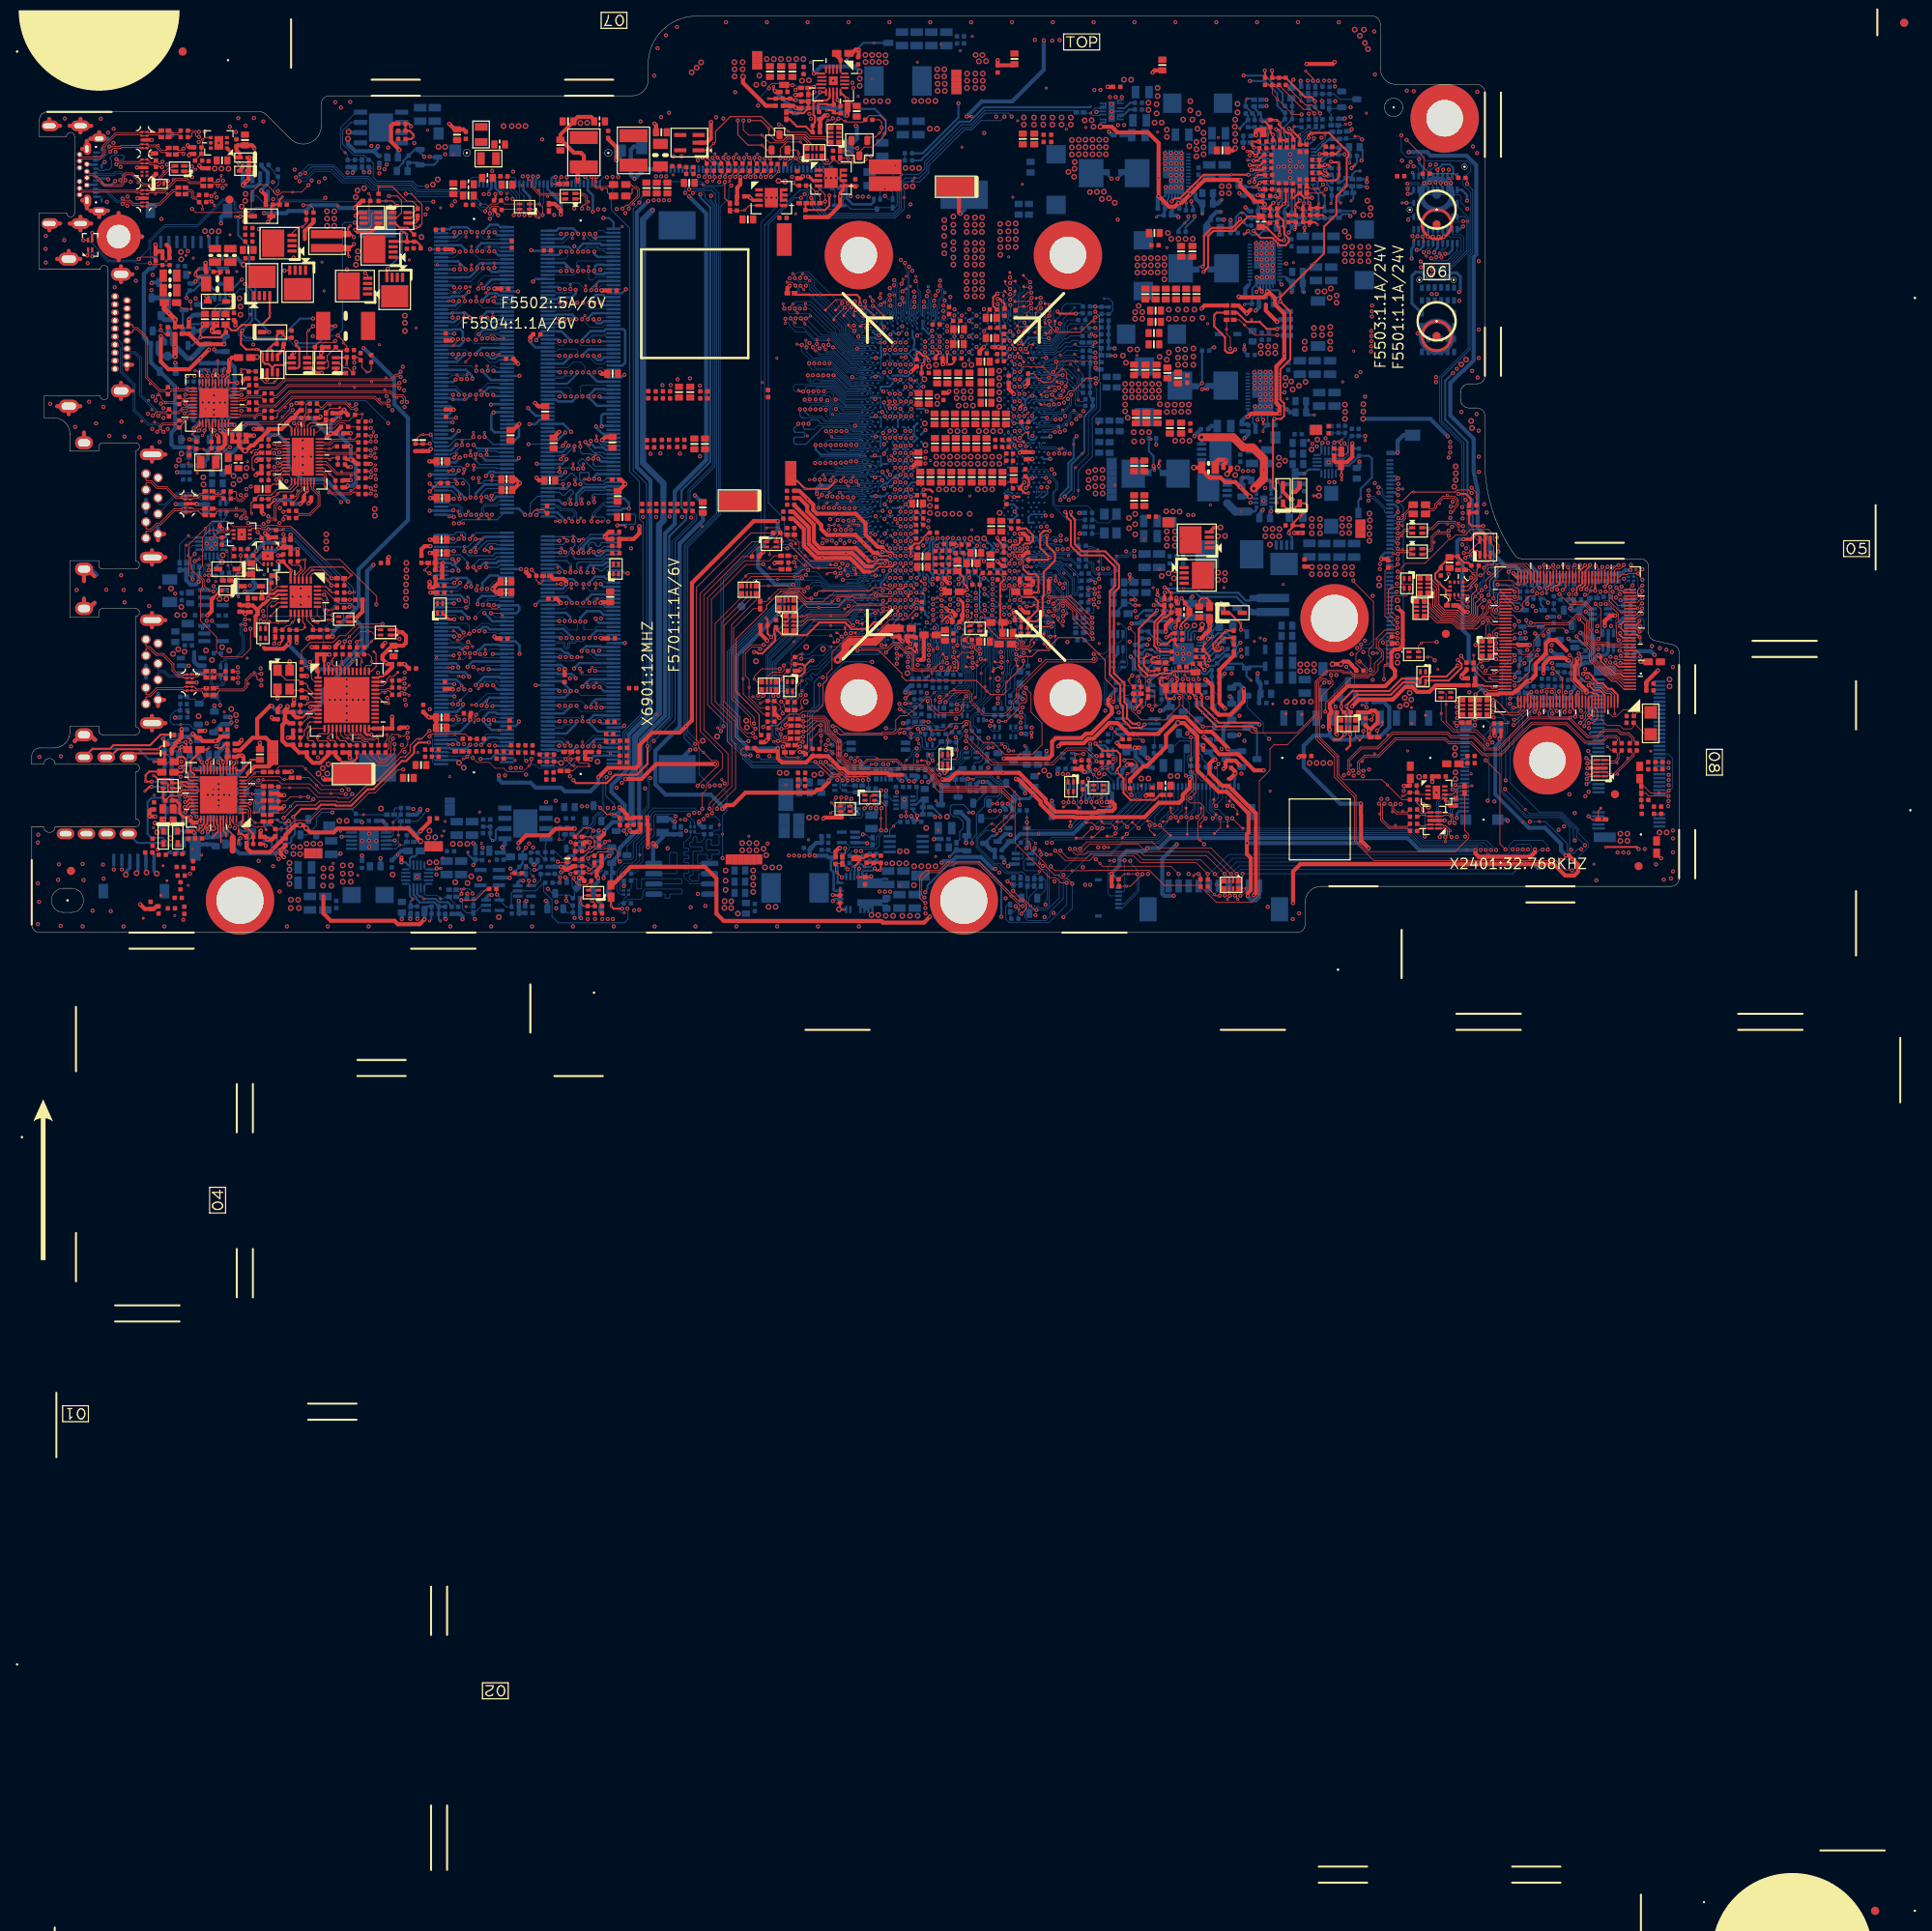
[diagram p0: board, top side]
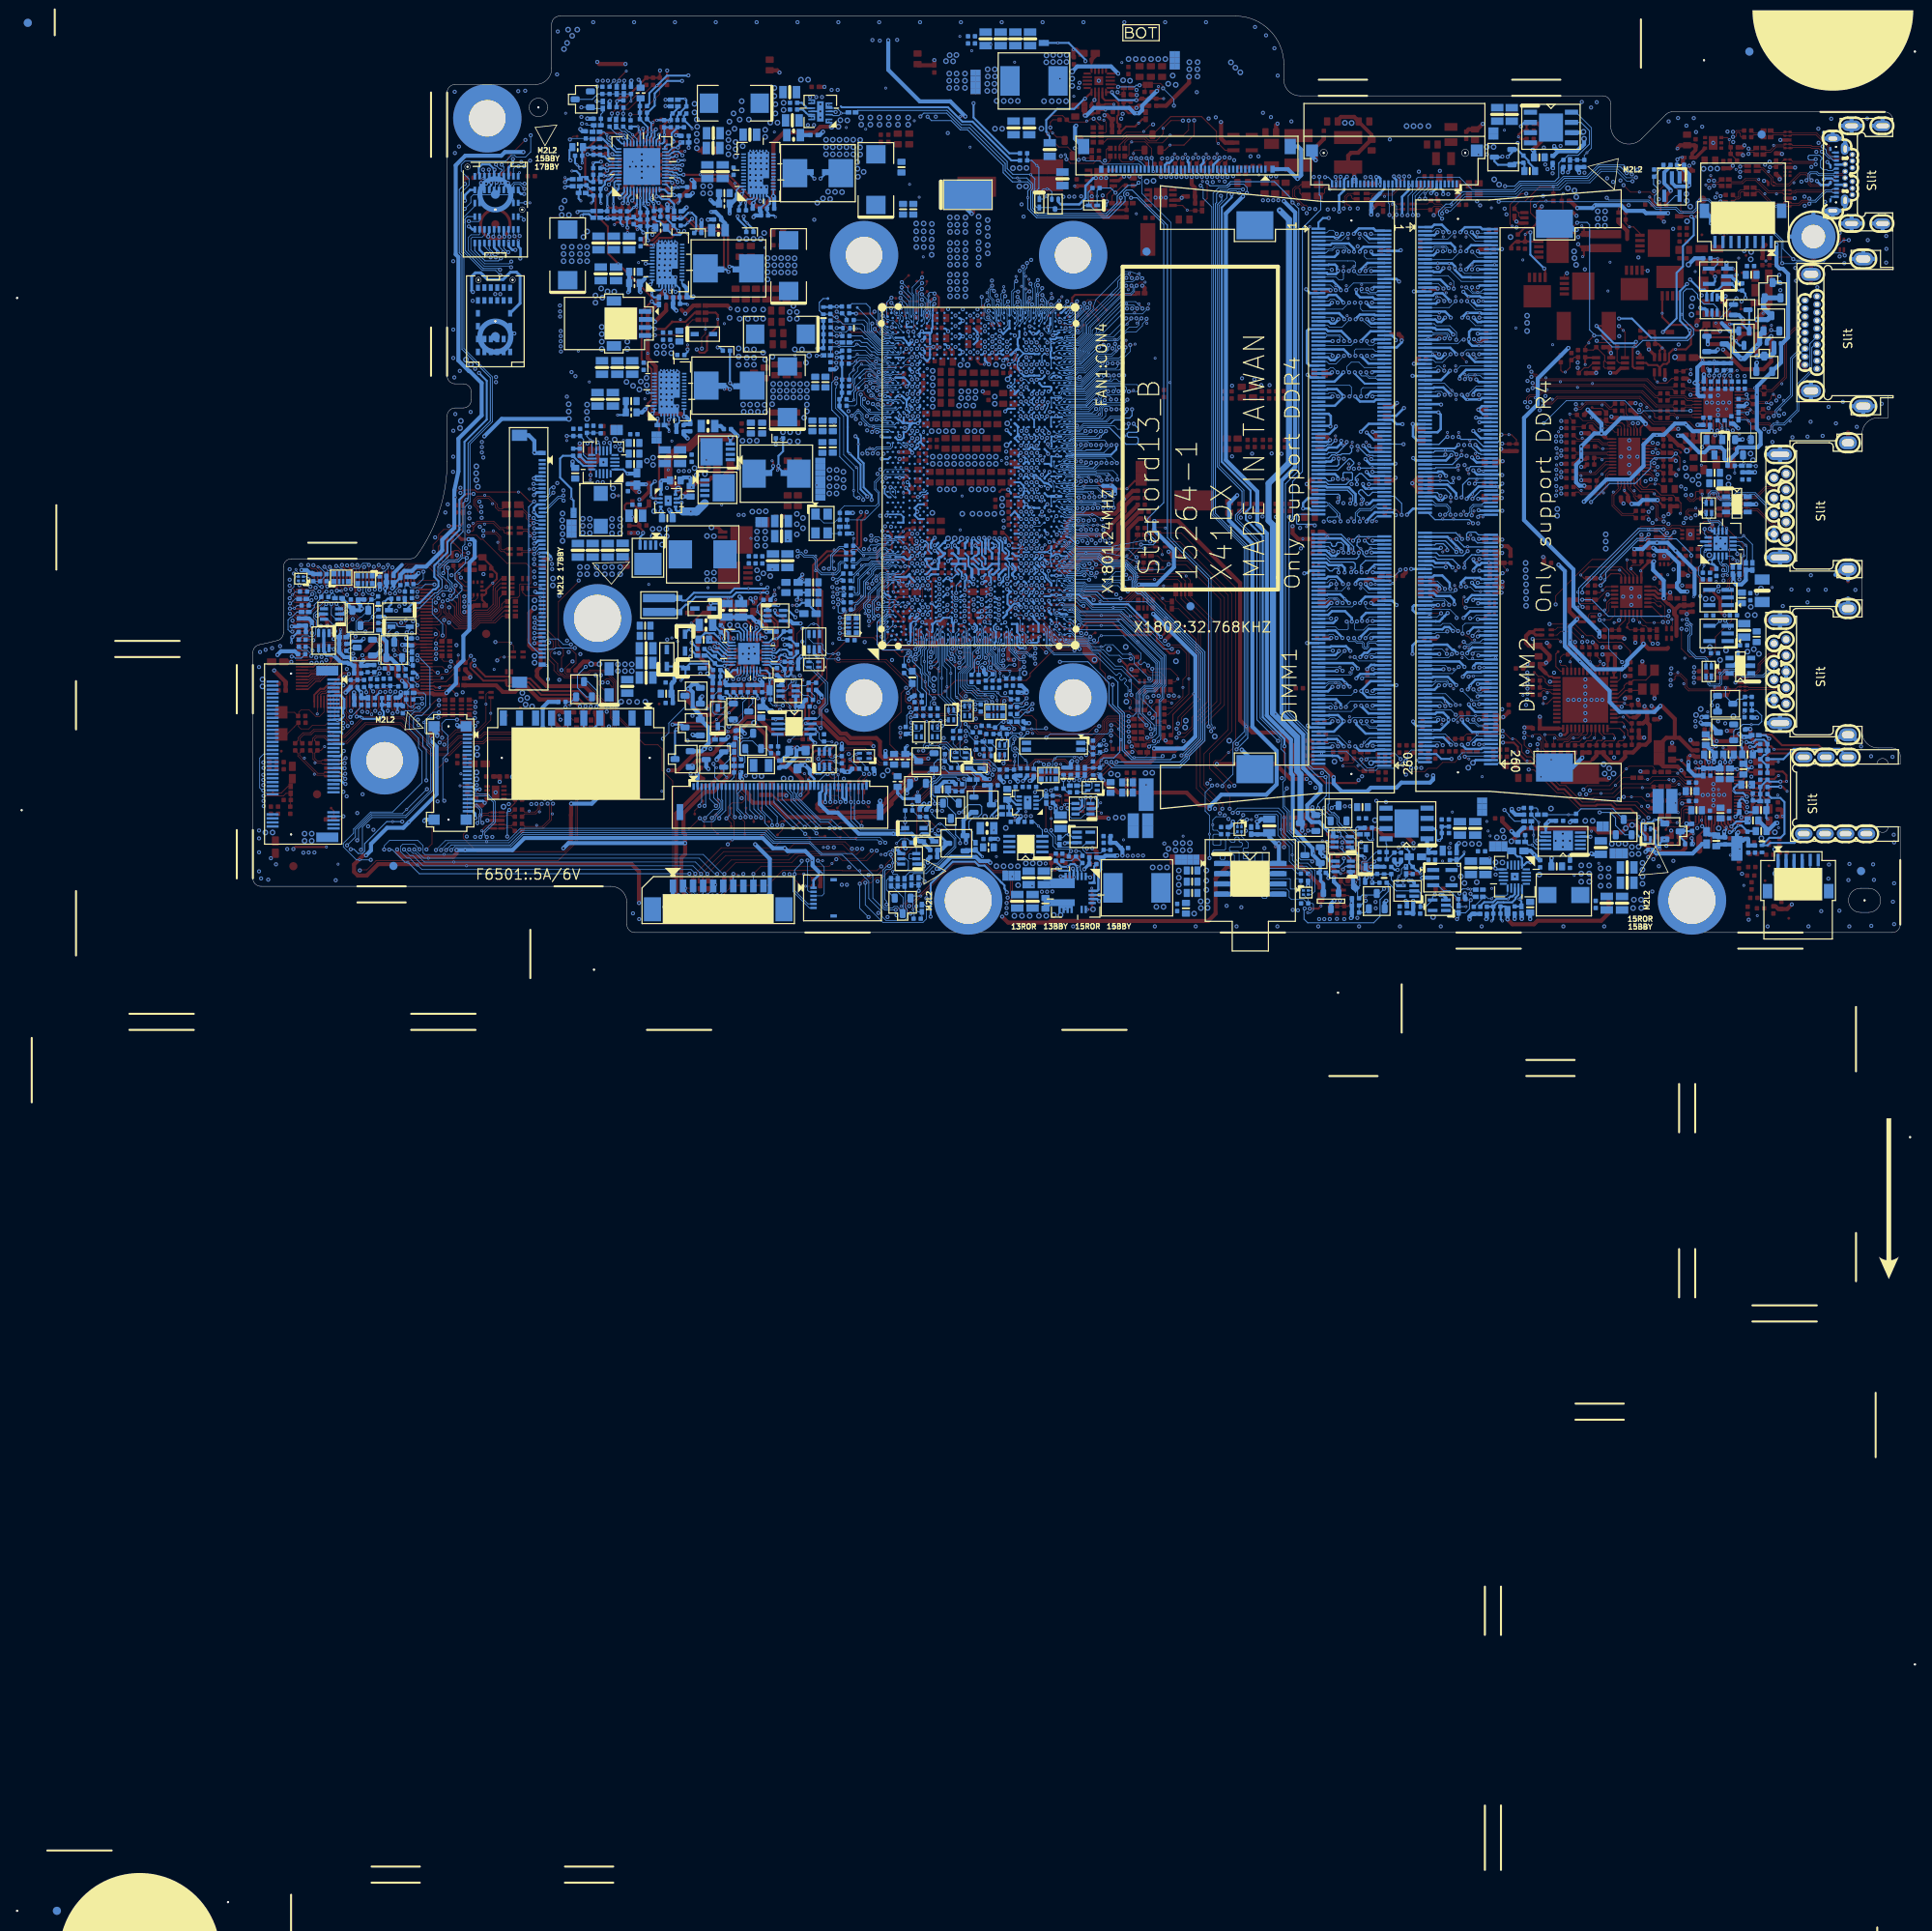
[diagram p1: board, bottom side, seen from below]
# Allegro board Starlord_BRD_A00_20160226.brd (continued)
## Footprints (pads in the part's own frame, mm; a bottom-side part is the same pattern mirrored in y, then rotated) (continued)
QFN22G4-G2PH42
  rect 0.305x0.914 smd: 1(1.25,2.051) 2(0.75,2.051) 3(0.25,2.051) 4(-0.25,2.051) 5(-0.75,2.051) 6(-1.25,2.051) 16(0.75,-2.051) 17(1.25,-2.051)
  custom 0.326x0.326 smd: 7(-2.051,1.25)
  rect 0.025x0.025 smd: 8(-2.051,0.75) 9(-2.051,0.25) 10(-2.051,-0.75) 13(-0.75,-2.051) 14(-0.25,-2.051) 15(0.25,-2.051)
  custom 0.232x0.232 smd: 11(-2.051,-1.25)
  custom 0.229x0.229 smd: 12(-1.25,-2.051)
  rect 0.914x0.305 smd: 18(2.051,-1.25) 19(2.051,-0.75) 20(2.051,-0.25) 21(2.051,0.25) 22(2.051,1.25)
QFN24-G2D8-UH24
  rect 0.305x0.889 smd: 1(1.25,2.045) 2(0.751,2.045) 3(0.25,2.045) 4(-0.25,2.045) 5(-0.751,2.045) 6(-1.25,2.045) 13(-1.25,-2.045) 14(-0.751,-2.045) 15(-0.25,-2.045) 16(0.25,-2.045) 17(0.751,-2.045) 18(1.25,-2.045)
  rect 0.889x0.305 smd: 7(-2.045,1.25) 8(-2.045,0.751) 9(-2.045,0.25) 10(-2.045,-0.25) 11(-2.045,-0.751) 12(-2.045,-1.25) 19(2.045,-1.25) 20(2.045,-0.751) 21(2.045,-0.25) 22(2.045,0.25) 23(2.045,0.751) 24(2.045,1.25)
  rect 2.794x2.794 smd: 25(0,0)
QFN32J4-G2D7H42
  custom 0.051x0.051 smd: 1(1.4,2.076) 8(-1.4,2.076) 9(-2.076,1.4) 16(-2.076,-1.4) 17(-1.4,-2.076) 24(1.4,-2.076) 25(2.076,-1.4) 32(2.076,1.4)
  rect 0.203x0.94 smd: 2(1,2.038) 3(0.6,2.038) 4(0.2,2.038) 5(-0.2,2.038) 6(-0.6,2.038) 7(-1,2.038) 18(-1,-2.038) 19(-0.6,-2.038) 20(-0.2,-2.038) 21(0.2,-2.038) 22(0.6,-2.038) 23(1,-2.038)
  rect 0.94x0.203 smd: 10(-2.038,1) 11(-2.038,0.6) 12(-2.038,0.2) 13(-2.038,-0.2) 14(-2.038,-0.6) 15(-2.038,-1) 26(2.038,-1) 27(2.038,-0.6) 28(2.038,-0.2) 29(2.038,0.2) 30(2.038,0.6) 31(2.038,1)
  rect 2.692x2.692 smd: 33(0,0)
QFN36J4060-G2554H48
  rect 0.203x0.559 smd: 1(1,2.873) 2(0.6,2.873) 3(0.2,2.873) 4(-0.2,2.873) 5(-0.6,2.873) 6(-1,2.873)
  rect 0.61x0.203 smd: 7(-1.848,2.2) 8(-1.848,1.8) 9(-1.848,1.4) 10(-1.848,1) 25(1.848,-2.2) 26(1.848,-1.8) 27(1.848,-1.4) 28(1.848,-1) 29(1.848,-0.6) 30(1.848,-0.2) 31(1.848,0.2) 32(1.848,0.6) 33(1.848,1) 34(1.848,1.4) 35(1.848,1.8) 36(1.848,2.2)
  rect 0.559x0.203 smd: 11(-1.848,0.6) 12(-1.848,0.2) 13(-1.848,-0.2) 14(-1.848,-0.6) 15(-1.848,-1) 16(-1.848,-1.4) 17(-1.848,-1.8) 18(-1.848,-2.2)
  rect 0.025x0.025 smd: 19(-1,-2.848) 20(-0.6,-2.848) 21(-0.2,-2.848) 22(0.2,-2.848) 23(0.6,-2.848) 24(1,-2.848)
  custom 0.665x0.665 smd: 37(0,0)
QFN40J5-G3D65H32
  rect 0.203x0.94 smd: 1(1.8,2.538) 10(-1.8,2.538) 21(-1.8,-2.538) 30(1.8,-2.538)
  rect 0.203x0.965 smd: 2(1.4,2.526) 3(1,2.526) 4(0.6,2.526) 5(0.2,2.526) 6(-0.2,2.526) 7(-0.6,2.526) 8(-1,2.526) 9(-1.4,2.526) 22(-1.4,-2.526) 23(-1,-2.526) 24(-0.6,-2.526) 25(-0.2,-2.526) 26(0.2,-2.526) 27(0.6,-2.526) 28(1,-2.526) 29(1.4,-2.526)
  rect 0.94x0.203 smd: 11(-2.538,1.8) 20(-2.538,-1.8) 31(2.538,-1.8) 40(2.538,1.8)
  rect 0.965x0.203 smd: 12(-2.526,1.4) 13(-2.526,1) 14(-2.526,0.6) 15(-2.526,0.2) 16(-2.526,-0.2) 17(-2.526,-0.6) 18(-2.526,-1) 19(-2.526,-1.4) 32(2.526,-1.4) 33(2.526,-1) 34(2.526,-0.6) 35(2.526,-0.2) 36(2.526,0.2) 37(2.526,0.6) 38(2.526,1) 39(2.526,1.4)
  rect 3.658x3.658 smd: 41(0,0)
QFN40J4060-G275475H32
  rect 0.203x0.914 smd: 1(1.4,3.051) 2(1,3.051) 3(0.6,3.051) 4(0.2,3.051) 5(-0.2,3.051) 6(-0.6,3.051) 7(-1,3.051) 8(-1.4,3.051) 21(-1.4,-3.051) 22(-1,-3.051) 23(-0.6,-3.051) 24(-0.2,-3.051) 25(0.2,-3.051) 26(0.6,-3.051) 27(1,-3.051) 28(1.4,-3.051)
  rect 0.914x0.203 smd: 9(-2.051,2.2) 10(-2.051,1.8) 11(-2.051,1.4) 12(-2.051,1) 13(-2.051,0.6) 14(-2.051,0.2) 15(-2.051,-0.2) 16(-2.051,-0.6) 17(-2.051,-1) 18(-2.051,-1.4) 19(-2.051,-1.8) 20(-2.051,-2.2) 29(2.051,-2.2) 30(2.051,-1.8) 31(2.051,-1.4) 32(2.051,-1) 33(2.051,-0.6) 34(2.051,-0.2) 35(2.051,0.2) 36(2.051,0.6) 37(2.051,1) 38(2.051,1.4) 39(2.051,1.8) 40(2.051,2.2)
  rect 2.743x4.75 smd: 41(0,0)
QFN48G7-G5D7H26
  rect 0.305x0.914 smd: 1(2.75,3.551) 12(-2.75,3.551) 25(-2.75,-3.551) 36(2.75,-3.551)
  rect 0.305x0.94 smd: 2(2.25,3.538) 3(1.75,3.538) 4(1.25,3.538) 5(0.75,3.538) 6(0.25,3.538) 7(-0.25,3.538) 8(-0.75,3.538) 9(-1.25,3.538) 10(-1.75,3.538) 11(-2.25,3.538) 26(-2.25,-3.538) 27(-1.75,-3.538) 28(-1.25,-3.538) 29(-0.75,-3.538) 30(-0.25,-3.538) 31(0.25,-3.538) 32(0.75,-3.538) 33(1.25,-3.538) 34(1.75,-3.538) 35(2.25,-3.538)
  rect 0.914x0.305 smd: 13(-3.551,2.75) 24(-3.551,-2.75) 37(3.551,-2.75) 48(3.551,2.75)
  rect 0.94x0.305 smd: 14(-3.538,2.25) 15(-3.538,1.75) 16(-3.538,1.25) 17(-3.538,0.75) 18(-3.538,0.25) 19(-3.538,-0.25) 20(-3.538,-0.75) 21(-3.538,-1.25) 22(-3.538,-1.75) 23(-3.538,-2.25) 38(3.538,-2.25) 39(3.538,-1.75) 40(3.538,-1.25) 41(3.538,-0.75) 42(3.538,-0.25) 43(3.538,0.25) 44(3.538,0.75) 45(3.538,1.25) 46(3.538,1.75) 47(3.538,2.25)
  rect 5.69x5.69 smd: 49(0,0)
QFN48J6-G465H40
  rect 0.203x0.965 smd: 1(2.2,3.025) 2(1.8,3.025) 3(1.4,3.025) 4(1,3.025) 5(0.6,3.025) 6(0.2,3.025) 7(-0.2,3.025) 8(-0.6,3.025) 9(-1,3.025) 10(-1.4,3.025) 11(-1.8,3.025) 12(-2.2,3.025) 25(-2.2,-3.025) 26(-1.8,-3.025) 27(-1.4,-3.025) 28(-1,-3.025) 29(-0.6,-3.025) 30(-0.2,-3.025) 31(0.2,-3.025) 32(0.6,-3.025) 33(1,-3.025) 34(1.4,-3.025) 35(1.8,-3.025) 36(2.2,-3.025)
  rect 0.965x0.203 smd: 13(-3.025,2.2) 14(-3.025,1.8) 15(-3.025,1.4) 16(-3.025,1) 17(-3.025,0.6) 18(-3.025,0.2) 19(-3.025,-0.2) 20(-3.025,-0.6) 21(-3.025,-1) 22(-3.025,-1.4) 23(-3.025,-1.8) 24(-3.025,-2.2) 37(3.025,-2.2) 38(3.025,-1.8) 39(3.025,-1.4) 40(3.025,-1) 41(3.025,-0.6) 42(3.025,-0.2) 43(3.025,0.2) 44(3.025,0.6) 45(3.025,1) 46(3.025,1.4) 47(3.025,1.8) 48(3.025,2.2)
  rect 4.648x4.648 smd: 49(0,0)
R402H14
  custom 0.14x0.14 smd: 1(0,0.445) 2(0,-0.445)
R402H15
  custom 0.14x0.14 smd: 1(0,0.445) 2(0,-0.445)
R402H16
  custom 0.14x0.14 smd: 1(0,0.445) 2(0,-0.445)
R603H22
  custom 0.197x0.197 smd: 1(0,0.66) 2(0,-0.66)
R805H24
  rect 1.549x0.94 smd: 1(0,0.838) 2(0,-0.838)
R1206H26
  rect 1.854x1.27 smd: 1(0,1.397) 2(0,-1.397)
R1206H28
  rect 1.854x1.27 smd: 1(0,1.397) 2(0,-1.397)
R2512H28
  rect 3.505x1.778 smd: 1(0,2.794) 2(0,-2.794)
R3720H40
  rect 4.013x1.041 smd: 1(0,0.867) 2(0,-0.867)
SC70-2D2-312H44
  custom 0.152x0.152 smd: 1(-0.65,-0.902) 2(0.65,-0.902) 3(0,0.902)
SC70-5H44
  rect 0.406x1.219 smd: 1(0.65,0.826) 2(0,0.826) 3(-0.65,0.826) 4(-0.65,-0.826) 5(0.65,-0.826)
SKT-HDMI23-188137-2
  oval 0.787x0.94 hole 0.533: 1(-4.5,5.75) 2(-4,7.25) 3(-3.5,5.75) 4(-3,7.25) 5(-2.5,5.75) 6(-2,7.25) 7(-1.5,5.75) 8(-1,7.25) 9(-0.5,5.75) 10(0,7.25) 11(0.5,5.75) 12(1,7.25) 13(1.5,5.75) 14(2,7.25) 15(2.5,5.75) 16(3,7.25) 17(3.5,5.75) 18(4,7.25) 19(4.5,5.75)
  oval 1.626x2.515 hole 0.914x1.803: 20(-7.25,6.5) 21(7.25,6.5) 22(-9.15,0) 23(9.15,0)
SKT-USB13-160162-2
  round 1.168 hole 0.813: 1(3.5,9.2) 2(1,9.2) 3(-1,9.2) 4(-3.5,9.2) 5(-4,7.7) 6(-2,7.7) 7(0,7.7) 8(2,7.7) 9(4,7.7)
  oval 1.422x2.997 hole 0.711x2.286: 10(6.4,8.45) 11(-6.4,8.45)
  oval 1.626x2.235 hole 0.914x1.524: 12(7.85,0) 13(-7.85,0)
SKT-USB36-124103-1
  round 0.254 hole 0.762 unplated: (-3.45,5.8) (3.45,5.8)
  oval 1.321x2.134 hole 0.61x1.6: 13(-6.075,0) 22(6.075,0)
  oval 1.321x2.311 hole 0.61x1.6: 14(-6.075,3.865) 21(6.075,3.865)
  oval 1.041x1.829 hole 0.508x1.118: 15(-4.475,6.2) 20(4.475,6.2)
  custom 0.076x0.076 smd: 16(-3.2,6.49) 19(3.2,6.49) A1(-2.75,5.74) A12(2.75,5.74)
  rect 0.508x0.305 smd: 17(-1,6.49) 18(1,6.49)
  rect 0.305x0.61 smd: A2(-2.25,5.74) A3(-1.75,5.74) A4(-1.25,5.74) A5(-0.75,5.74) A6(-0.25,5.74) A7(0.25,5.74) A8(0.75,5.74) A9(1.25,5.74) A10(1.75,5.74) A11(2.25,5.74)
  oval 1.549x0.94 hole 0.914x0.406: B1(3.2,4.665) B12(-3.2,4.665)
  oval 0.66x0.711 hole 0.406: B2(2.5,3.765) B3(1.7,3.765) B4(1.3,4.665) B5(0.85,3.765) B6(0.4,4.665) B7(-0.4,4.665) B8(-0.85,3.765) B9(-1.3,4.665) B10(-1.7,3.765) B11(-2.5,3.765)
SLP2510P8-1H22
  rect 0.305x0.762 smd: 1(-1,-0.5) 5(1,-0.5) 6(1,0.5) 10(-1,0.5)
  rect 0.203x0.762 smd: 2(-0.5,-0.5) 4(0.5,-0.5) 7(0.5,0.5) 9(-0.5,0.5)
  rect 0.406x0.762 smd: 3(0,-0.5) 8(0,0.5)
SMD49-3215-0713H36
  rect 1.549x1.549 smd: 1(0,1.371) 2(0,-1.371)
SMD49-6914-0403H56
  rect 1.168x0.559 smd: 1(-3.38,-0.427) 2(3.38,-0.427) 3(3.38,0.427) 4(-3.38,0.427)
SMD-ARES4-2H18-U
  rect 0.305x0.406 smd: 1(-0.25,-0.305) 2(0.25,-0.305) 3(0.25,0.305) 4(-0.25,0.305)
SMD-ARES4H18
  rect 0.356x0.66 smd: 1(-0.325,-0.599) 2(0.325,-0.599) 3(0.325,0.599) 4(-0.325,0.599)
SMD-ARES4H20
  rect 0.356x0.66 smd: 1(-0.325,-0.599) 2(0.325,-0.599) 3(0.325,0.599) 4(-0.325,0.599)
SOD123FLAKH40
  rect 1.143x1.651 smd: A(0,1.622) K(0,-1.622)
SOD323-2513AKH36
  rect 0.559x1.168 smd: A(0,1.05) K(0,-1.05)
SOD323AKH38
  rect 0.559x1.016 smd: A(0,1.143) K(0,-1.143)
SOD323AKH44
  rect 0.559x1.016 smd: A(0,1.143) K(0,-1.143)
SOD882-10D6-1H20
  custom 0.114x0.114 smd: 1(0,0.445) 2(0,-0.445)
SOD923-10D6AKH16
  rect 0.457x0.762 smd: A(0,0.527) K(0,-0.527)
SOD-523-2H26
  rect 0.559x1.016 smd: 1(0,0.762) 2(0,-0.762)
SOD-523-4H28
  rect 0.559x0.864 smd: 1(0,0.778) 2(0,-0.778)
SOIC8-1H86
  rect 0.635x1.651 smd: 1(-1.905,-3.493) 2(-0.635,-3.493) 3(0.635,-3.493) 4(1.905,-3.493) 5(1.905,3.493) 6(0.635,3.493) 7(-0.635,3.493) 8(-1.905,3.493)
SOIC8-G3530H63
  rect 0.635x1.651 smd: 1(-1.905,-2.555) 2(-0.635,-2.555) 3(0.635,-2.555) 4(1.905,-2.555) 5(1.905,2.555) 6(0.635,2.555) 7(-0.635,2.555) 8(-1.905,2.555)
  rect 3.505x2.997 smd: 9(0,0)
SOT23-2D4-312H44
  custom 0.191x0.191 smd: 1(-0.984,-0.953) 2(0.984,-0.953) 3(0,0.953)
SOT23-2D4-312H48
  custom 0.191x0.191 smd: 1(-0.984,-0.953) 2(0.984,-0.953) 3(0,0.953)
SOT23-2D4-312H60
  custom 0.191x0.191 smd: 1(-0.984,-0.953) 2(0.984,-0.953) 3(0,0.953)
SOT23CBE2D4H44
  custom 0.191x0.191 smd: B(-0.984,-0.953) C(0,0.953) E(0.984,-0.953)
SOT23CBE2D6H46
  custom 0.165x0.165 smd: B(-0.95,-1.092) C(0,1.092) E(0.95,-1.092)
SOT23CBE2D6H62
  custom 0.165x0.165 smd: B(-0.95,-1.092) C(0,1.092) E(0.95,-1.092)
SOT23DGS2D4H44
  custom 0.191x0.191 smd: D(0,0.953) G(-0.984,-0.953) S(0.984,-0.953)
SOT23DGS2D4H48
  custom 0.191x0.191 smd: D(0,0.953) G(-0.984,-0.953) S(0.984,-0.953)
SOT23DGS2D8H56
  custom 0.254x0.254 smd: D(0,1.118) G(-1.016,-1.118) S(1.016,-1.118)
SOT323CBE2D2H40
  custom 0.152x0.152 smd: B(-0.65,-0.902) C(0,0.902) E(0.65,-0.902)
SOT723DGS1D2H22
  custom 0.146x0.146 smd: D(0,0.61)
  custom 0.121x0.121 smd: G(-0.4,-0.61) S(0.4,-0.61)
SOT883-1D0-321H20
  rect 0.203x0.305 smd: 1(0.203,-0.35) 2(-0.203,-0.35)
  rect 0.559x0.305 smd: 3(0,0.35)
SOT-6H58
  rect 0.584x1.016 smd: 1(-0.953,-1.346) 2(0,-1.346) 3(0.953,-1.346) 4(0.953,1.346) 5(0,1.346) 6(-0.953,1.346)
SOT-23-5H51
  rect 0.508x1.524 smd: 1(-0.95,-1.143) 2(0,-1.143) 3(0.95,-1.143) 4(0.95,1.143) 5(-0.95,1.143)
SOT-23-5H52
  rect 0.508x1.524 smd: 1(-0.95,-1.143) 2(0,-1.143) 3(0.95,-1.143) 4(0.95,1.143) 5(-0.95,1.143)
SOT-23-5H56
  rect 0.508x1.524 smd: 1(-0.95,-1.143) 2(0,-1.143) 3(0.95,-1.143) 4(0.95,1.143) 5(-0.95,1.143)
SOT-23-9H44
  custom 0.178x0.178 smd: 1(-0.95,-0.999) 2(0.95,-0.999) 3(0,0.999)
SOT-23-10H44
  rect 0.762x1.143 smd: 1(-0.984,-0.953) 2(0.984,-0.953) 3(0,0.953)
SOT-363H44
  rect 0.406x1.016 smd: 1(-0.65,-0.94) 2(0,-0.94) 3(0.65,-0.94) 4(0.65,0.94) 5(0,0.94) 6(-0.65,0.94)
SPR5128H111
  rect 4.801x2.489 smd: 1(-1.397,0)
SPR6238H60
  rect 5.893x3.505 smd: 1(-1.702,0)
STF217R115H101
  round 5.512 hole 2.921: 1(0,0)
STFSR158R113H62
  round 0.254 hole 2.87 unplated: (0,0)
  custom 1.003x1.003 smd: 1(0,-1.822)
TPAD14-OP
  round 0.356 smd: 1(0,0)
TQFP128J16H48
  rect 0.203x1.524 smd: 1(6.2,7.746) 2(5.8,7.746) 3(5.4,7.746) 4(5,7.746) 5(4.6,7.746) 6(4.2,7.746) 7(3.8,7.746) 8(3.4,7.746) 9(3,7.746) 10(2.6,7.746) 11(2.2,7.746) 12(1.8,7.746) 13(1.4,7.746) 14(1,7.746) 15(0.6,7.746) 16(0.2,7.746) 17(-0.2,7.746) 18(-0.6,7.746) 19(-1,7.746) 20(-1.4,7.746) 21(-1.8,7.746) 22(-2.2,7.746) 23(-2.6,7.746) 24(-3,7.746) 25(-3.4,7.746) 26(-3.8,7.746) 27(-4.2,7.746) 28(-4.6,7.746) 29(-5,7.746) 30(-5.4,7.746) 31(-5.8,7.746) 32(-6.2,7.746) 65(-6.2,-7.746) 66(-5.8,-7.746) 67(-5.4,-7.746) 68(-5,-7.746) 69(-4.6,-7.746) 70(-4.2,-7.746) 71(-3.8,-7.746) 72(-3.4,-7.746) 73(-3,-7.746) 74(-2.6,-7.746) 75(-2.2,-7.746) 76(-1.8,-7.746) 77(-1.4,-7.746) 78(-1,-7.746) 79(-0.6,-7.746) 80(-0.2,-7.746) 81(0.2,-7.746) 82(0.6,-7.746) 83(1,-7.746) 84(1.4,-7.746) 85(1.8,-7.746) 86(2.2,-7.746) 87(2.6,-7.746) 88(3,-7.746) 89(3.4,-7.746) 90(3.8,-7.746) 91(4.2,-7.746) 92(4.6,-7.746) 93(5,-7.746) 94(5.4,-7.746) 95(5.8,-7.746) 96(6.2,-7.746)
  rect 1.524x0.203 smd: 33(-7.746,6.2) 34(-7.746,5.8) 35(-7.746,5.4) 36(-7.746,5) 37(-7.746,4.6) 38(-7.746,4.2) 39(-7.746,3.8) 40(-7.746,3.4) 41(-7.746,3) 42(-7.746,2.6) 43(-7.746,2.2) 44(-7.746,1.8) 45(-7.746,1.4) 46(-7.746,1) 47(-7.746,0.6) 48(-7.746,0.2) 49(-7.746,-0.2) 50(-7.746,-0.6) 51(-7.746,-1) 52(-7.746,-1.4) 53(-7.746,-1.8) 54(-7.746,-2.2) 55(-7.746,-2.6) 56(-7.746,-3) 57(-7.746,-3.4) 58(-7.746,-3.8) 59(-7.746,-4.2) 60(-7.746,-4.6) 61(-7.746,-5) 62(-7.746,-5.4) 63(-7.746,-5.8) 64(-7.746,-6.2) 97(7.746,-6.2) 98(7.746,-5.8) 99(7.746,-5.4) 100(7.746,-5) 101(7.746,-4.6) 102(7.746,-4.2) 103(7.746,-3.8) 104(7.746,-3.4) 105(7.746,-3) 106(7.746,-2.6) 107(7.746,-2.2) 108(7.746,-1.8) 109(7.746,-1.4) 110(7.746,-1) 111(7.746,-0.6) 112(7.746,-0.2) 113(7.746,0.2) 114(7.746,0.6) 115(7.746,1) 116(7.746,1.4) 117(7.746,1.8) 118(7.746,2.2) 119(7.746,2.6) 120(7.746,3) 121(7.746,3.4) 122(7.746,3.8) 123(7.746,4.2) 124(7.746,4.6) 125(7.746,5) 126(7.746,5.4) 127(7.746,5.8) 128(7.746,6.2)
unnamed
  round 0.254 hole 2.184 unplated: (0,0)
XBGCB5008
  round 0.254 hole 2.718 unplated: (0,0)
  round 0.254 hole 0.711 unplated: (5.143,-2.145) (5.143,2.105)
  rect 0.813x0.508 smd: A1(-3.805,2.165) A2(-3.805,1.365) A3(-3.805,0.565) A4(-3.805,-0.235) A5(-3.805,-1.035) A6(-3.805,-1.835) B1(-2.205,2.165) B2(-2.205,1.365) B3(-2.205,0.565) B4(-2.205,-0.235) B5(-2.205,-1.035) B6(-2.205,-1.835) C1(2.595,2.165) C2(2.595,1.365) C3(2.595,0.565) C4(2.595,-0.235) C5(2.595,-1.035) C6(2.595,-1.835) D2(4.195,1.365) D3(4.195,0.565) D4(4.195,-0.235) D5(4.195,-1.035) P1(-0.605,2.165) P2(0.995,2.165) P3(-0.605,-1.835) P4(0.995,-1.835)
  rect 0.762x0.508 smd: D1(4.169,2.165) D6(4.169,-1.835)
  custom 1.124x1.124 smd: N1(-1.905,0)
XBGCB5009
  round 0.254 hole 0.711 unplated: (-5.325,-3.465) (0,3.34)
  round 0.254 hole 2.718 unplated: (0,0)
  rect 0.813x0.356 smd: A1(-4.15,2.845) A2(-4.15,2.245) A3(-4.15,1.645) A4(-4.15,1.045) A5(-4.15,0.445) A6(-4.15,-0.155) A7(-4.15,-0.755) A8(-4.15,-1.355) A9(-4.15,-1.955) A10(-4.15,-2.555) B1(-2.45,2.845) B2(-2.45,2.245) B3(-2.45,1.645) B4(-2.45,1.045) B5(-2.45,0.445) B6(-2.45,-0.155) B7(-2.45,-0.755) B8(-2.45,-1.355) B9(-2.45,-1.955) B10(-2.45,-2.555) C2(-0.82,2.245) C9(-0.82,-1.955) C10(-0.82,-2.555) D1(0.87,2.845) D2(0.87,2.245) D9(0.87,-1.955) D10(0.87,-2.555) E1(2.45,2.845) E2(2.45,2.245) E3(2.45,1.645) E4(2.45,1.045) E5(2.45,0.445) E6(2.45,-0.155) E7(2.45,-0.755) E8(2.45,-1.355) E9(2.45,-1.955) E10(2.45,-2.555) F1(4.15,2.845) F2(4.15,2.245) F3(4.15,1.645) F4(4.15,1.045) F5(4.15,0.445) F6(4.15,-0.155) F7(4.15,-0.755) F8(4.15,-1.355) F9(4.15,-1.955) F10(4.15,-2.555)
  rect 0.762x0.356 smd: C1(-0.846,2.845)
  custom 1.124x1.124 smd: N1(-1.905,0)

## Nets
1.8V_RUN_FB: PC5405.2 PR5403.2 PR5404.1 PU5401.2
3V5V_CT1: C4001.1 U4001.12
3V5V_CT2: C4002.1 U4001.10
3V5V_S0_ON: R4010.2 U4001.3 U4001.5
3V_5V_EN: C4009.1 D4001.1 PR4515.1 PR4516.1 R4006.1 R4009.1
3V_5V_POK: C1710.1 EC1705.1 PG4529.1 PG4531.1 PR5210.1 PR5406.1 R1718.2 R1728.2 R4033.1
3V_5V_POK#: Q1701.5 Q1701.6 R1726.1
3V_5V_POK_C: Q1701.2 R1727.2 R1728.1 R1729.1
5V_AUX_S5: PG4528.2 PR4510.2
5V_HDD: C6010.1 R6003.1 R6006.2 U6002.7 U6002.8
5V_HDD_SIP: C6002.1 C6004.1 HDD1.8 HDD1.9 HDD1.10 HDD1.11 R6003.2
5V_HDMI_R_S5: F5701.1 R5715.2 R5716.2
5V_HDMI_S5: C5713.1 F5701.2 HDMI1.18
5V_S0: C4005.1 C6009.1 D5701.3 EC8916.1 EC8917.1 F5501.1 F6501.1 GPU2.P4 R2612.1 R2702.1 R2703.2 R2704.1 R5507.1 R5716.1 R6006.1 R6501.1 R6510.1 U4001.13 U4001.14 U6002.1 U6002.2 U6002.4
5V_S5: C3402.1 C3502.1 C3503.1 C3713.1 C3714.1 C4031.1 C4032.1 EC8914.1 EC8915.1 IOBD1.28 IOBD1.29 IOBD1.30 IOBD1.31 IOBD1.32 PC4707.1 PC4807.1 PC4846.1 PC5001.1 PC5202.1 PC5401.1 PC5410.1 PG4507.2 PG4508.2 PG4509.2 PG4510.2 PG4511.2 PG4512.2 PG4513.2 PG4514.2 PR4303.1 PR4642.1 PR4657.1 PR4702.2 PR4803.2 PR4806.2 PR5118.2 PU4701.7 PU4701.36 PU4801.3 PU4801.7 PU4801.36 PU4802.3 PU4802.7 PU4802.36 PU5001.4 PU5201.21 PU5401.6 PU5403.6 Q6401.E Q6402.E Q6505.E R2725.1 R3402.1 R3405.1 R3406.1 R3721.2 R3722.1 R3723.1 R5715.1 U3401.1 U3501.5 U3502.5 U3703.2 U3704.2 U4001.1 U4001.2 U4001.4 U4002.3 U4004.3 U4006.4
5V_STB: HDA27.47 R2725.2
+3V_1D8V_AVDD: C2715.1 HDA27.16 R2705.2 R2710.2 R2713.2
+3V_AVDD: C2716.1 C2717.1 C2719.1 HDA27.4 HDA27.12 R2722.1 R2728.2 R2731.2
+3VLP: KBC24.120 R2454.1 R2463.2
+5V_AVDD: C2710.1 C2711.1 HDA27.40 R2703.1
+5V_KB_BL: AFTP6529.1 C6501.1 F6501.2 KBBD1.30 R6501.2
+5V_PVDD: C2706.1 C2707.1 C2708.1 C2709.1 HDA27.41 HDA27.46 R2702.2 R2704.2
+V1.00A_SIP: C1112.1 C2101.1 C2104.1 C2116.1 C2121.1 CPU1.A10 CPU1.A14 CPU1.AB17 CPU1.AB19 CPU1.AB20 CPU1.AK20 CPU1.K17 CPU1.L1 CPU1.L21 CPU1.P18 CPU1.T1 CPU1.Y18 R1102.2 R1803.2 R2108.1 R2109.1 R2110.1 R2111.1
+V1.00U_CPU: C4012.1 R4036.1 R4038.1 U4006.7 U4006.8
+V1.8A: C2714.1 C2722.1 C4023.1 C4029.1 PG5405.2 PG5406.2 PG5407.2 Q2702.S Q4009.S R1104.2 R2726.1 R4046.1
+V1.8A_SIP: C1122.1 C2108.1 CPU1.AA1 CPU1.AF16 R1104.1
+V1.8S_EDRAM: C4028.1 CPU1.H63 Q4009.D R702.1 R704.1
+V3.3A_SIP: C1113.1 C1123.1 C2105.1 C2106.1 C2107.1 C2109.1 C2110.1 C2111.1 CPU1.AD15 CPU1.AG15 CPU1.AJ16 CPU1.AJ21 CPU1.AK15 CPU1.AK17 CPU1.T16 CPU1.V19 CPU1.Y15 CPU1.Y16 R1103.2 R1701.1 R1731.1 R2101.1
+VCCAMPHYPLL_1P0: C2113.1 CPU1.K15 CPU1.L15 R2107.2
+VCCAPLL_1P0: C2114.1 CPU1.V15 R2108.2
+VCCCLK2: C2115.1 CPU1.K19 R2109.2
+VCCCLK4: C2119.1 CPU1.N20 R2110.2
+VCCCLK5: C2122.1 CPU1.L19 R2111.2
+VCCCOREG0: CPU1.K32 TP701.1
+VCCCOREG1: CPU1.AK32 TP707.1
+VCCDSW_1P0: C2103.1 CPU1.AL1
+VCCFUSEPRG: CPU1.G20 R703.1
+VCCGT: C1102.1 C1103.1 C1104.1 C1105.1 C1106.1 C1107.1 CPU1.A48 CPU1.A53 CPU1.A58 CPU1.A62 CPU1.A66 CPU1.AA63 CPU1.AA64 CPU1.AA66 CPU1.AA67 CPU1.AA69 CPU1.AA70 CPU1.AA71 CPU1.AC64 CPU1.AC65 CPU1.AC66 CPU1.AC67 CPU1.AC68 CPU1.AC69 CPU1.AC70 CPU1.AC71 CPU1.AK42 CPU1.AK43 CPU1.AK45 CPU1.AK46 CPU1.AK48 CPU1.AK50 CPU1.AK52 CPU1.AK53 CPU1.AK55 CPU1.AK56 CPU1.AK58 CPU1.AK60 CPU1.AK70 CPU1.AL43 CPU1.AL46 CPU1.AL50 CPU1.AL53 CPU1.AL56 CPU1.AL60 CPU1.AM48 CPU1.AM50 CPU1.AM52 CPU1.AM53 CPU1.AM56 CPU1.AM58 CPU1.AU58 CPU1.AU63 CPU1.BB57 CPU1.BB66 CPU1.J43 CPU1.J45 CPU1.J46 CPU1.J48 CPU1.J50 CPU1.J52 CPU1.J53 CPU1.J55 CPU1.J56 CPU1.J58 CPU1.J60 CPU1.K48 CPU1.K50 CPU1.K52 CPU1.K53 CPU1.K55 CPU1.K56 CPU1.K58 CPU1.K60 CPU1.L62 CPU1.L63 CPU1.L64 CPU1.L65 CPU1.L66 CPU1.L67 CPU1.L68 CPU1.L69 CPU1.L70 CPU1.L71 CPU1.M62 CPU1.N63 CPU1.N64 CPU1.N66 CPU1.N67 CPU1.N69 CPU1.N70 CPU1.N71 CPU1.R63 CPU1.R64 CPU1.R65 CPU1.R66 CPU1.R67 CPU1.R68 CPU1.R69 CPU1.R70 CPU1.R71 CPU1.T62 CPU1.U65 CPU1.U68 CPU1.U71 CPU1.W63 CPU1.W64 CPU1.W65 CPU1.W66 CPU1.W67 CPU1.W68 CPU1.W69 CPU1.W70 CPU1.W71 CPU1.Y62 EC1005.1 EC1006.1 PC1001.1 PC1037.1 PC1038.1 PC1039.1 PC1040.1 PC1041.1 PC1042.1 PC1043.1 PC1044.1 PC1045.1 PC1046.1 PC1047.1 PC1048.1 PC1049.1 PC1050.1 PC1051.1 PC1052.1 PC1053.1 PC1054.1 PC1055.1 PC1056.1 PC1057.1 PC1058.1 PC1059.1 PC1060.1 PC1061.1 PC1062.1 PC1063.1 PC1064.1 PC1065.1 PC1066.1 PC1067.1 PC1068.1 PC1069.1 PC1070.1 PG4809.2 PG4816.2 PL4801.2 PL4802.2 PT4801.1 PT4802.1 PT4803.1 R721.1
+VCCIO: C1108.1 C1109.1 C1110.1 C1111.1 CPU1.AK28 CPU1.AK30 CPU1.AL30 CPU1.AL42 CPU1.AM28 CPU1.AM30 CPU1.AM42 PC1102.1 PC1103.1 PC1104.1 R801.1 R4045.2
+VCCIO_SIP: C4007.1 R4042.1 R4045.1 U4002.6 U4002.7 U4002.8
+VCCMPHYGTAON_1P0_LS_SIP: C1114.1 C1115.1 C1116.1 C1117.1 C1118.1 C1119.1 C1120.1 C1121.1 C1704.1 CPU1.AF20 CPU1.AF21 CPU1.N15 CPU1.N16 CPU1.N17 CPU1.N18 CPU1.P15 CPU1.P16 CPU1.T19 CPU1.T20 R1724.2 R1735.2 R2107.1
+VCCPAZIO: CPU1.AJ19 R2101.2 R2102.2
+VCCPDSW_3P3: CPU1.AD17 CPU1.AD18 CPU1.AJ17 R1707.1 R1711.2
+VCCPRIM_CORE: C2102.1 C2120.1 CPU1.AF18 CPU1.AF19 CPU1.V20 CPU1.V21 EC2101.1 PC1105.1 PC1106.1 R1101.2
+VCCPRTC_3P3: C2117.1 C2118.1 CPU1.AK19 CPU1.BB14 R2106.2
+VCCSA: CPU1.AK23 CPU1.AK25 CPU1.G23 CPU1.G25 CPU1.G27 CPU1.G28 CPU1.J22 CPU1.J23 CPU1.J27 CPU1.K23 CPU1.K25 CPU1.K27 CPU1.K28 CPU1.K30 EC1001.1 EC1007.1 PC1071.1 PC1072.1 PC1073.1 PC1074.1 PC1075.1 PC1076.1 PC1077.1 PC1078.1 PG5025.1 PG5026.1 PG5027.1 PG5028.1 PG5029.1 PG5030.1 PG5031.1 R735.1
+VCCSFR: C720.1 C721.1 CPU1.K20 CPU1.K21 R4038.2
+VCCST_CPU: C716.1 CPU1.A18 PC4610.1 PR4621.1 PR4622.1 PR4623.1 PR4624.1 R419.1 R603.2 R723.1 R726.1 R727.1 R4036.2
+VCCSTG: C717.1 C4008.1 CPU1.A22 PR4669.1 R401.1 R408.2 R409.2 R416.2 R417.2 R421.2 R422.2 R423.2 R703.2 R1722.1 R4042.2
+VDDQ_CPU_CLK: C715.1 CPU1.AM40 R705.2
AV1_TP: CPU1.AV1 TP2307.1
AV71_TP: CPU1.AV71 TP2304.1
DVSS: HDA27.7 R2732.1
GND: AFTP2604.1 AFTP4306.1 AFTP4307.1 AFTP4308.1 BATT1.8 BATT1.9 BATT1.10 C701.2 C702.2 C703.2 C704.2 C715.2 C716.2 C717.2 C718.2 C719.2 C720.2 C721.2 C1101.2 C1102.2 C1103.2 C1104.2 C1105.2 C1106.2 C1107.2 C1108.2 C1109.2 C1110.2 C1111.2 C1112.2 C1113.2 C1114.2 C1115.2 C1116.2 C1117.2 C1118.2 C1119.2 C1120.2 C1121.2 C1122.2 C1123.2 C1124.2 C1125.2 C1126.2 C1127.2 C1202.2 C1203.2 C1204.2 C1205.2 C1206.2 C1207.2 C1208.2 C1209.2 C1210.2 C1211.2 C1212.2 C1213.2 C1214.2 C1215.2 C1216.2 C1217.2 C1218.2 C1219.2 C1220.2 C1221.2 C1223.2 C1224.2 C1225.2 C1226.2 C1227.2 C1228.2 C1229.2 C1230.2 C1231.2 C1232.2 C1301.2 C1303.2 C1304.2 C1305.2 C1306.2 C1307.2 C1308.2 C1309.2 C1310.2 C1311.2 C1312.2 C1313.2 C1314.2 C1315.2 C1316.2 C1317.2 C1318.2 C1319.2 C1320.2 C1321.2 C1322.2 C1324.2 C1325.2 C1326.2 C1327.2 C1328.2 C1329.2 C1330.2 C1331.2 C1701.2 C1702.2 C1703.2 C1704.2 C1710.2 C1711.2 C1801.1 C1802.1 C1803.1 C1804.1 C1805.2 C1806.2 C2101.2 C2102.2 C2103.2 C2104.2 C2105.2 C2106.2 C2107.2 C2108.2 C2109.2 C2110.2 C2111.2 C2112.2 C2113.2 C2114.2 C2115.2 C2116.2 C2117.2 C2118.2 C2119.2 C2120.2 C2121.2 C2122.2 C2402.2 C2403.2 C2405.2 C2406.2 C2409.2 C2410.2 C2411.2 C2412.2 C2413.2 C2414.2 C2416.2 C2418.2 C2420.2 C2421.2 C2423.2 C2424.1 C2425.1 C2426.2 C2428.2 C2429.2 C2501.2 C2502.2 C2503.2 C2601.2 C2602.2 C2603.2 C2604.2 C2605.2 C2608.2 C2609.2 C2610.2 C2701.2 C2706.2 C2707.2 C2708.2 C2709.2 C2716.2 C2717.2 C2718.2 C2719.2 C2721.2 C2722.2 C2723.1 C2724.2 C3401.2 C3402.2 C3403.2 C3404.2 C3405.2 C3502.2 C3503.2 C3507.2 C3508.2 C3512.2 C3513.2 C3514.2 C3701.2 C3702.2 C3703.2 C3704.2 C3705.1 C3706.2 C3707.2 C3708.2 C3709.2 C3710.2 C3711.2 C3712.2 C3713.2 C3714.2 C3815.2 C3816.2 C3817.2 C3818.2 C3819.2 C3820.2 C3821.2 C4001.2 C4002.2 C4004.2 C4005.2 C4006.2 C4007.2 C4008.2 C4009.2 C4010.2 C4011.2 C4012.2 C4013.2 C4014.2 C4015.2 C4017.2 C4028.2 C4029.2 C4031.2 C4032.2 C4033.2 C4034.2 C4101.2 C4102.2 C5502.2 C5503.2 C5505.2 C5507.2 C5508.1 C5512.2 C5513.2 C5514.2 C5515.2 C5516.2 C5517.2 C5518.2 C5534.2 C5542.1 C5701.1 C5702.1 C5703.1 C5704.1 C5705.1 C5706.1 C5713.2 C5716.1 C6002.2 C6004.2 C6007.2 C6008.2 C6009.2 C6010.2 C6304.2 C6305.2 C6306.2 C6307.2 C6308.2 C6501.2 C6503.2 C6504.2 C6901.2 C6902.2 C6903.2 C6904.2 C6905.2 C6906.2 C6907.2 C6908.2 C6909.2 C7001.2 C7002.2 C7003.2 C7004.2 CPU1.AA2 CPU1.AA4 CPU1.AA65 CPU1.AA68 CPU1.AB8 CPU1.AB15 CPU1.AB16 CPU1.AB18 CPU1.AB21 CPU1.AD8 CPU1.AD13 CPU1.AD16 CPU1.AD19 CPU1.AD20 CPU1.AD21 CPU1.AD62 CPU1.AE64 CPU1.AE65 CPU1.AE66 CPU1.AE67 CPU1.AE68 CPU1.AE69 CPU1.AF1 CPU1.AF2 CPU1.AF4 CPU1.AF10 CPU1.AF15 CPU1.AF17 CPU1.AF63 CPU1.AG16 CPU1.AG17 CPU1.AG18 CPU1.AG19 CPU1.AG20 CPU1.AG21 CPU1.AG71 CPU1.AH6 CPU1.AH13 CPU1.AH63 CPU1.AH64 CPU1.AH67 CPU1.AJ4 CPU1.AJ15 CPU1.AJ18 CPU1.AJ20 CPU1.AK8 CPU1.AK11 CPU1.AK16 CPU1.AK18 CPU1.AK21 CPU1.AK22 CPU1.AK27 CPU1.AK63 CPU1.AK68 CPU1.AK69 CPU1.AL2 CPU1.AL4 CPU1.AL28 CPU1.AL32 CPU1.AL35 CPU1.AL38 CPU1.AL45 CPU1.AL48 CPU1.AL52 CPU1.AL55 CPU1.AL58 CPU1.AL64 CPU1.AL65 CPU1.AL66 CPU1.AM8 CPU1.AM13 CPU1.AM21 CPU1.AM25 CPU1.AM27 CPU1.AM43 CPU1.AM45 CPU1.AM46 CPU1.AM55 CPU1.AM60 CPU1.AM61 CPU1.AM68 CPU1.AM71 CPU1.AN20 CPU1.AN23 CPU1.AN28 CPU1.AN30 CPU1.AN32 CPU1.AN33 CPU1.AN35 CPU1.AN37 CPU1.AN38 CPU1.AN40 CPU1.AN42 CPU1.AN58 CPU1.AN63 CPU1.AP10 CPU1.AP18 CPU1.AP20 CPU1.AP23 CPU1.AP28 CPU1.AP32 CPU1.AP35 CPU1.AP38 CPU1.AP42 CPU1.AP58 CPU1.AP63 CPU1.AP68 CPU1.AP70 CPU1.AR5 CPU1.AR8 CPU1.AR11 CPU1.AR15 CPU1.AR16 CPU1.AR20 CPU1.AR23 CPU1.AR28 CPU1.AR35 CPU1.AR42 CPU1.AR43 CPU1.AR45 CPU1.AR46 CPU1.AR48 CPU1.AR50 CPU1.AR52 CPU1.AR53 CPU1.AR55 CPU1.AR58 CPU1.AR63 CPU1.AT2 CPU1.AT4 CPU1.AT20 CPU1.AT23 CPU1.AT28 CPU1.AT35 CPU1.AT42 CPU1.AT56 CPU1.AT58 CPU1.AT63 CPU1.AT68 CPU1.AT71 CPU1.AU10 CPU1.AU15 CPU1.AU20 CPU1.AU32 CPU1.AU38 CPU1.AV68 CPU1.AV69 CPU1.AV70 CPU1.AW6 CPU1.AW8 CPU1.AW10 CPU1.AW12 CPU1.AW14 CPU1.AW16 CPU1.AW18 CPU1.AW21 CPU1.AW23 CPU1.AW26 CPU1.AW28 CPU1.AW30 CPU1.AW32 CPU1.AW34 CPU1.AW36 CPU1.AW38 CPU1.AW41 CPU1.AW43 CPU1.AW45 CPU1.AW47 CPU1.AW49 CPU1.AW51 CPU1.AW53 CPU1.AW55 CPU1.AW57 CPU1.AW60 CPU1.AW62 CPU1.AW64 CPU1.AW66 CPU1.AY66 CPU1.B10 CPU1.B14 CPU1.B18 CPU1.B22 CPU1.B30 CPU1.B34 CPU1.B39 CPU1.B44 CPU1.B48 CPU1.B53 CPU1.B58 CPU1.B62 CPU1.B66 CPU1.BA6 CPU1.BA10 CPU1.BA14 CPU1.BA18 CPU1.BA23 CPU1.BA28 CPU1.BA32 CPU1.BA36 CPU1.BA41 CPU1.BA45 CPU1.BA49 CPU1.BA53 CPU1.BA57 CPU1.BA62 CPU1.BA66 CPU1.BB6 CPU1.BB18 CPU1.BB26 CPU1.BB30 CPU1.BB34 CPU1.BB38 CPU1.BB43 CPU1.BB55 CPU1.BB60 CPU1.BB64 CPU1.C5 CPU1.C25 CPU1.D6 CPU1.D10 CPU1.D11 CPU1.D14 CPU1.D18 CPU1.D22 CPU1.D25 CPU1.D26 CPU1.D30 CPU1.D34 CPU1.D39 CPU1.D44 CPU1.D45 CPU1.D47 CPU1.D48 CPU1.D53 CPU1.D58 CPU1.D62 CPU1.D66 CPU1.D69 CPU1.E6 CPU1.E11 CPU1.E15 CPU1.E18 CPU1.E21 CPU1.E46 CPU1.E50 CPU1.E53 CPU1.E56 CPU1.E65 CPU1.F1 CPU1.F2 CPU1.F4 CPU1.F8 CPU1.F13 CPU1.F22 CPU1.F23 CPU1.F27 CPU1.F28 CPU1.F32 CPU1.F33 CPU1.F35 CPU1.F37 CPU1.F38 CPU1.F40 CPU1.F42 CPU1.F68 CPU1.G5 CPU1.G6 CPU1.G10 CPU1.G22 CPU1.G43 CPU1.G45 CPU1.G48 CPU1.G52 CPU1.G55 CPU1.G58 CPU1.G60 CPU1.G63 CPU1.G66 CPU1.H15 CPU1.H18 CPU1.H71 CPU1.J8 CPU1.J11 CPU1.J13 CPU1.J25 CPU1.J28 CPU1.J32 CPU1.J35 CPU1.J38 CPU1.J42 CPU1.K16 CPU1.K18 CPU1.K22 CPU1.K61 CPU1.K63 CPU1.K64 CPU1.K65 CPU1.K66 CPU1.K67 CPU1.K68 CPU1.K70 CPU1.K71 CPU1.L2 CPU1.L4 CPU1.L8 CPU1.L11 CPU1.L16 CPU1.L17 CPU1.L18 CPU1.L20 CPU1.N6 CPU1.N10 CPU1.N13 CPU1.N19 CPU1.N21 CPU1.N65 CPU1.N68 CPU1.P17 CPU1.P19 CPU1.P20 CPU1.P21 CPU1.R6 CPU1.R13 CPU1.T2 CPU1.T4 CPU1.T15 CPU1.T17 CPU1.T18 CPU1.T21 CPU1.U10 CPU1.U63 CPU1.U64 CPU1.U66 CPU1.U67 CPU1.U69 CPU1.U70 CPU1.V16 CPU1.V17 CPU1.V18 CPU1.W6 CPU1.W9 CPU1.W13 CPU1.Y17 CPU1.Y19 CPU1.Y20 CPU1.Y21 D502.1 D2601.A D4304.1 D4305.1 D4306.1 DB1.8 DB1.10 DB1.11 DB1.12 DB3.4 DB3.7 DB3.8 DCIN1.9 DCIN1.10 DM1.1 DM1.2 DM1.5 DM1.6 DM1.9 DM1.10 DM1.14 DM1.15 DM1.18 DM1.19 DM1.22 DM1.23 DM1.26 DM1.27 DM1.30 DM1.31 DM1.35 DM1.36 DM1.39 DM1.40 DM1.43 DM1.44 DM1.47 DM1.48 DM1.51 DM1.52 DM1.56 DM1.57 DM1.60 DM1.61 DM1.64 DM1.65 DM1.68 DM1.69 DM1.72 DM1.73 DM1.77 DM1.78 DM1.81 DM1.82 DM1.85 DM1.86 DM1.89 DM1.90 DM1.93 DM1.94 DM1.98 DM1.99 DM1.102 DM1.103 DM1.106 DM1.107 DM1.167 DM1.168 DM1.171 DM1.172 DM1.175 DM1.176 DM1.180 DM1.181 DM1.184 DM1.185 DM1.188 DM1.189 DM1.192 DM1.193 DM1.196 DM1.197 DM1.201 DM1.202 DM1.205 DM1.206 DM1.209 DM1.210 DM1.213 DM1.214 DM1.217 DM1.218 DM1.222 DM1.223 DM1.226 DM1.227 DM1.230 DM1.231 DM1.234 DM1.235 DM1.238 DM1.239 DM1.243 DM1.244 DM1.247 DM1.248 DM1.251 DM1.252 DM1.261 DM1.262 DM2.1 DM2.2 DM2.5 DM2.6 DM2.9 DM2.10 DM2.14 DM2.15 DM2.18 DM2.19 DM2.22 DM2.23 DM2.26 DM2.27 DM2.30 DM2.31 DM2.35 DM2.36 DM2.39 DM2.40 DM2.43 DM2.44 DM2.47 DM2.48 DM2.51 DM2.52 DM2.56 DM2.57 DM2.60 DM2.61 DM2.64 DM2.65 DM2.68 DM2.69 DM2.72 DM2.73 DM2.77 DM2.78 DM2.81 DM2.82 DM2.85 DM2.86 DM2.89 DM2.90 DM2.93 DM2.94 DM2.98 DM2.99 DM2.102 DM2.103 DM2.106 DM2.107 DM2.167 DM2.168 DM2.171 DM2.172 DM2.175 DM2.176 DM2.180 DM2.181 DM2.184 DM2.185 DM2.188 DM2.189 DM2.192 DM2.193 DM2.196 DM2.197 DM2.201 DM2.202 DM2.205 DM2.206 DM2.209 DM2.210 DM2.213 DM2.214 DM2.217 DM2.218 DM2.222 DM2.223 DM2.226 DM2.227 DM2.230 DM2.231 DM2.234 DM2.235 DM2.238 DM2.239 DM2.243 DM2.244 DM2.247 DM2.248 DM2.251 DM2.252 DM2.261 DM2.262 EC401.2 EC1001.2 EC1002.2 EC1003.2 EC1004.2 EC1005.2 EC1006.2 EC1007.2 EC1102.2 EC1103.2 EC1202.2 EC1302.2 EC1303.2 EC1701.2 EC1702.2 EC1703.2 EC1704.2 EC1705.2 EC1706.2 EC1707.2 EC1708.2 EC1709.2 EC1710.2 EC1711.2 EC1712.2 EC1713.2 EC1801.2 EC1802.2 EC1803.1 EC1806.2 EC1807.2 EC1808.2 EC1901.1 EC1902.2 EC2002.2 EC2101.2 EC2501.2 EC2502.2 EC2503.2 EC2701.2 EC2703.2 EC2704.2 EC2705.2 EC2706.2 EC2707.2 EC2708.2 EC2709.2 EC2901.2 EC2902.2 EC2903.2 EC2904.2 EC2909.2 EC2910.2 EC2911.2 EC2912.2 EC4001.2 EC4306.1 EC4307.2 EC4308.2 EC4309.2 EC4310.2 EC4425.2 EC4534.2 EC5501.2 EC5502.2 EC5503.2 EC5504.2 EC5505.2 EC6401.2 EC6402.2 EC6501.2 EC6502.2 EC6503.2 EC6504.2 EC6601.2 EC6602.2 EC6603.2 EC8901.2 EC8902.2 EC8903.2 EC8904.2 EC8905.2 EC8906.2 EC8907.2 EC8908.2 EC8909.2 EC8910.2 EC8911.2 EC8912.2 EC8913.2 EC8914.2 EC8915.2 EC8916.2 EC8917.2 EC8918.2 EC8919.2 EC8920.2 EC8921.2 EC8922.2 EC8923.2 EC8924.2 EC8925.2 EC8926.2 EC8927.2 EC8928.2 EC8929.2 EC8933.2 EC8934.2 EC8935.2 EC8936.2 EC8937.2 EC8938.2 ED1217.2 ED1302.2 ED2901.2 ED2902.2 ED2903.2 ED2904.2 ED2905.2 ED2906.2 ED3801.3 ED6301.3 ED6301.8 ED6401.2 ED6402.2 EL4303.2 EL4304.2 EU3601.3 EU3602.2 EU3603.3 EU3604.2 EU3801.3 EU3802.3 EU3803.3 EU3804.3 FAN1.2 FAN1.5 FAN1.6 G1801.1 GMR1.2 GPU1.A3 GPU1.A6 GPU1.A9 GPU1.B1 GPU1.B4 GPU1.B7 GPU1.B10 GPU1.E1 GPU1.E4 GPU1.E7 GPU1.E10 GPU1.F3 GPU1.F6 GPU1.F9 GPU2.C1 GPU2.C2 GPU2.C3 GPU2.C4 GPU2.C5 GPU2.C6 GPU2.D1 GPU2.D2 GPU2.D3 GPU2.D4 GPU2.D5 GPU2.D6 H2.1 H3.1 H4.1 H5.1 H6.1 H7.1 H8.1 H9.1 H10.1 HDA27.49 HDD1.3 HDD1.4 HDD1.5 HDD1.6 HDD1.14 HDD1.17 HDD1.20 HDD1.21 HDD1.22 HDD1.23 HDD1.24 HDMI1.2 HDMI1.5 HDMI1.8 HDMI1.11 HDMI1.17 HDMI1.20 HDMI1.21 HDMI1.22 HDMI1.23 HS1.1 IOBD1.5 IOBD1.6 IOBD1.9 IOBD1.12 IOBD1.15 IOBD1.18 IOBD1.21 IOBD1.24 IOBD1.50 IOBD1.51 IOBD1.52 IOBD1.53 IOBD1.54 KBBD1.1 KBBD1.35 KBBD1.38 KBBD1.39 KBBD1.45 KBBD1.46 KBC24.17 KBC24.51 KBC24.64 KBC24.84 KBC24.100 KBC24.124 LCD1.11 LCD1.14 LCD1.17 LCD1.20 LCD1.23 LCD1.26 LCD1.33 LCD1.34 LCD1.35 LCD1.36 LCD1.37 LCD1.38 LCD1.39 LCD1.40 LCD1.41 LCD1.42 LCD1.43 LCD1.44 PC1001.2 PC1002.2 PC1003.2 PC1004.2 PC1005.2 PC1006.2 PC1007.2 PC1008.2 PC1009.2 PC1010.2 PC1011.2 PC1012.2 PC1013.2 PC1014.2 PC1015.2 PC1016.2 PC1017.2 PC1018.2 PC1019.2 PC1020.2 PC1021.2 PC1022.2 PC1023.2 PC1024.2 PC1025.2 PC1026.2 PC1027.2 PC1028.2 PC1029.2 PC1030.2 PC1031.2 PC1032.2 PC1034.2 PC1036.2 PC1037.2 PC1038.2 PC1039.2 PC1040.2 PC1041.2 PC1042.2 PC1043.2 PC1044.2 PC1045.2 PC1046.2 PC1047.2 PC1048.2 PC1049.2 PC1050.2 PC1051.2 PC1052.2 PC1053.2 PC1054.2 PC1055.2 PC1056.2 PC1057.2 PC1058.2 PC1059.2 PC1060.2 PC1061.2 PC1062.2 PC1063.2 PC1064.2 PC1065.2 PC1066.2 PC1067.2 PC1068.2 PC1069.2 PC1070.2 PC1071.2 PC1072.2 PC1073.2 PC1074.2 PC1075.2 PC1076.2 PC1077.2 PC1078.2 PC1101.2 PC1102.2 PC1103.2 PC1104.2 PC1105.2 PC1106.2 PC1107.2 PC1108.2 PC1109.2 PC1110.2 PC1111.2 PC1112.2 PC1113.2 PC1114.2 PC1115.2 PC4302.2 PC4303.2 PC4304.2 PC4305.2 PC4306.2 PC4307.2 PC4311.2 PC4403.2 PC4404.2 PC4405.2 PC4406.2 PC4407.2 PC4408.2 PC4409.2 PC4410.2 PC4411.2 PC4412.2 PC4413.2 PC4415.2 PC4416.2 PC4417.2 PC4418.2 PC4419.2 PC4421.2 PC4422.2 PC4423.2 PC4424.2 PC4427.2 PC4428.2 PC4430.2 PC4431.2 PC4432.2 PC4433.2 PC4435.2 PC4501.2 PC4502.2 PC4503.2 PC4504.2 PC4505.2 PC4507.2 PC4508.2 PC4509.2 PC4510.2 PC4511.2 PC4512.2 PC4513.2 PC4514.2 PC4515.2 PC4516.2 PC4517.2 PC4518.2 PC4519.2 PC4520.2 PC4522.2 PC4523.2 PC4524.2 PC4525.2 PC4527.2 PC4528.2 PC4529.2 PC4530.2 PC4531.2 PC4532.2 PC4610.2 PC4701.2 PC4702.2 PC4703.2 PC4704.2 PC4705.2 PC4707.2 PC4708.2 PC4709.2 PC4710.2 PC4802.2 PC4803.2 PC4804.2 PC4805.2 PC4806.2 PC4807.2 PC4808.2 PC4810.2 PC4811.2 PC4812.2 PC4814.2 PC4820.2 PC4827.2 PC4828.2 PC4829.2 PC4830.2 PC4846.2 PC4847.2 PC5001.2 PC5002.2 PC5027.2 PC5029.2 PC5031.2 PC5101.2 PC5102.2 PC5103.2 PC5104.2 PC5105.2 PC5106.2 PC5107.2 PC5108.2 PC5110.2 PC5111.2 PC5113.2 PC5114.2 PC5115.2 PC5116.2 PC5118.2 PC5119.2 PC5120.2 PC5138.2 PC5201.2 PC5202.2 PC5203.2 PC5205.2 PC5206.2 PC5208.2 PC5209.2 PC5210.2 PC5211.2 PC5213.2 PC5214.2 PC5215.2 PC5216.2 PC5401.2 PC5402.2 PC5403.2 PC5404.2 PC5406.2 PC5407.2 PC5408.2 PC5409.2 PC5410.2 PC5412.2 PC5413.2 PC5414.2 PC5427.2 PD4301.A PD4302.1 PD4303.3 PD4304.A PG4601.2 PQ4302.E PQ4304.E PQ4306.1 PQ4306.4 PQ4307.1 PQ4307.4 PQ4308.1 PQ4308.4 PQ4309.1 PQ4309.4 PQ4310.1 PQ4310.4 PQ4311.1 PQ4311.4 PQ4405.1 PQ4405.4 PQ4415.1 PQ4415.4 PR4302.2 PR4308.2 PR4313.2 PR4315.1 PR4316.2 PR4323.2 PR4324.2 PR4328.1 PR4329.2 PR4332.2 PR4401.2 PR4409.2 PR4413.1 PR4423.2 PR4424.2 PR4430.2 PR4433.2 PR4436.2 PR4437.2 PR4442.2 PR4443.1 PR4449.2 PR4451.2 PR4508.2 PR4512.2 PR4513.2 PR4514.2 PR4530.2 PR4551.2 PR4652.2 PR4653.1 PR4656.1 PR4661.2 PR5104.2 PR5106.1 PR5203.2 PR5204.2 PR5401.2 PR5404.2 PR5409.2 PR5420.2 PT4701.2 PT4801.2 PT4802.2 PT4803.2 PT4805.2 PT4806.2 PU4401.33 PU4405.1 PU4405.2 PU4405.3 PU4501.7 PU4501.8 PU4501.18 PU4501.21 PU4502.7 PU4502.8 PU4502.18 PU4502.21 PU4701.3 PU4701.5 PU4701.19 PU4701.20 PU4701.21 PU4701.22 PU4701.23 PU4701.24 PU4701.31 PU4701.37 PU4801.5 PU4801.19 PU4801.20 PU4801.21 PU4801.22 PU4801.23 PU4801.24 PU4801.31 PU4801.37 PU4802.5 PU4802.19 PU4802.20 PU4802.21 PU4802.22 PU4802.23 PU4802.24 PU4802.31 PU4802.37 PU5001.6 PU5001.9 PU5003.1 PU5003.2 PU5003.3 PU5101.7 PU5101.8 PU5101.18 PU5101.21 PU5102.4 PU5102.8 PU5102.11 PU5201.4 PU5201.12 PU5201.13 PU5201.14 PU5201.15 PU5201.19 PU5401.1 PU5402.2 PU5403.1 Q1701.1 Q1701.4 Q1702.1 Q1702.4 Q1802.S Q2408.S Q2505.S Q2701.S Q4008.S Q5704.S Q6501.S Q6503.S Q7001.1 Q7001.4 R402.2 R406.2 R407.2 R412.2 R413.2 R414.2 R415.2 R501.2 R502.2 R503.2 R601.2 R602.2 R604.2 R605.2 R720.2 R722.2 R725.2 R731.2 R734.2 R803.1 R1205.2 R1209.2 R1210.2 R1212.2 R1216.2 R1303.2 R1307.2 R1309.2 R1311.2 R1501.2 R1502.2 R1603.2 R1714.2 R1715.2 R1717.2 R1719.2 R1816.2 R1823.2 R1825.2 R1901.2 R2008.2 R2009.2 R2019.2 R2030.2 R2417.2 R2436.2 R2445.1 R2448.2 R2449.1 R2454.2 R2504.2 R2510.2 R2611.2 R2706.2 R2717.2 R2732.2 R3403.1 R3404.1 R3501.2 R3704.1 R3716.2 R3802.1 R3803.2 R3815.1 R3817.1 R3819.1 R3821.1 R3823.1 R3830.2 R3831.2 R4006.2 R4301.1 R4303.2 R5412.1 R5414.1 R5416.1 R5418.1 R5501.2 R5710.2 R6304.2 R6305.2 R6508.2 R6509.2 R6907.2 R6908.1 R6910.1 R6912.1 R6914.1 R6916.1 R6918.1 R7007.1 RN1201.2(A) RN1301.2(A) RN1602.3(B) RN1602.4(B) RN1703.1(A) RN1703.2(A) RN2009.1(A) RN2009.2(A) RN5502.1(A) RN5502.2(A) RN5502.3(A) RN5502.4(A) SKT251.4 SPI25.4 SPK1.6 SPK1.7 SPK1.8 SPR1.1 SPR2.1 SPR3.1 SPR4.1 SSD1.1 SSD1.3 SSD1.9 SSD1.15 SSD1.21 SSD1.27 SSD1.33 SSD1.39 SSD1.45 SSD1.51 SSD1.57 SSD1.71 SSD1.73 SSD1.75 SSD1.76 SSD1.77 TC3501.2 TCBD1.13 TCBD1.16 TCBD1.20 TCBD1.21 TCBD1.29 TCBD1.33 TCBD1.34 THM261.5 TP6901.1 U1701.3 U1703.3 U3401.14 U3401.17 U3501.2 U3502.2 U3701.25 U3702.3 U3702.7 U3703.1 U3703.7 U3704.1 U3704.7 U3801.41 U4001.11 U4001.15 U4002.5 U4004.5 U4005.3 U4006.5 U4006.9 U4101.1 U4301.3 U4302.3 U5501.2 U5701.8 U5701.15 U5701.35 U5701.41 U6001.3 U6001.8 U6002.5 U6002.9 U6901.8 U6901.23 U6901.35 U6901.47 U6901.49 U7001.5 U7001.6 U7001.7 U7001.8 USB1.13 USB1.14 USB1.15 USB1.16 USB1.17 USB1.18 USB1.19 USB1.20 USB1.21 USB1.22 USB1.A1 USB1.A12 USB1.B1 USB1.B12 USB2.4 USB2.7 USB2.10 USB2.11 USB2.12 USB2.13 USB3.4 USB3.7 USB3.10 USB3.11 USB3.12 USB3.13 X6901.2 X6901.4
V0.85A_VID0: CPU1.AN11 TP2101.1
V0.85A_VID1: CPU1.AN13 TP2102.1
VBUS_PRODECT: PQ4309.2 PQ4311.2 PR4334.1 U4301.1
VBUS_PRODECT#: PQ4311.5 PQ4311.6 PR4337.1
VCC3PD: D3701.K D3702.K PR4334.2 PR4337.2 R3701.1 R3702.1 U4301.2
VCC_CORE: C1101.1 C1124.1 C1125.1 C1126.1 C1127.1 CPU1.A30 CPU1.A34 CPU1.A39 CPU1.A44 CPU1.AK33 CPU1.AK35 CPU1.AK37 CPU1.AK38 CPU1.AK40 CPU1.AL33 CPU1.AL37 CPU1.AL40 CPU1.AM32 CPU1.AM33 CPU1.AM35 CPU1.AM37 CPU1.AM38 CPU1.G30 CPU1.G32 CPU1.G33 CPU1.G35 CPU1.G37 CPU1.G38 CPU1.G40 CPU1.G42 CPU1.J30 CPU1.J33 CPU1.J37 CPU1.J40 CPU1.K33 CPU1.K35 CPU1.K37 CPU1.K38 CPU1.K40 CPU1.K42 CPU1.K43 EC1002.1 EC1003.1 EC1004.1 PC1002.1 PC1003.1 PC1004.1 PC1005.1 PC1006.1 PC1007.1 PC1008.1 PC1009.1 PC1010.1 PC1011.1 PC1012.1 PC1013.1 PC1014.1 PC1015.1 PC1016.1 PC1017.1 PC1018.1 PC1019.1 PC1020.1 PC1021.1 PC1022.1 PC1023.1 PC1024.1 PC1025.1 PC1026.1 PC1027.1 PC1028.1 PC1029.1 PC1030.1 PC1031.1 PC1032.1 PC1034.1 PC1036.1 PG4708.2 PL4701.2 PT4701.1 R719.1
VCC_EDRAM_FUSEPRG: CPU1.G61 R702.2 R704.2
VCC_SENSE: CPU1.E32 PR4648.1 R719.2
VCCGT_SENSE: CPU1.J70 PR4617.1 R721.2
VCCPD_VBUS: C3707.1 C3821.1 PC4310.2 PR4319.1 PR4331.1 PR4336.2 PR4338.1 PU4303.1 PU4303.2 PU4303.3 PU4305.5 PU4305.6 PU4305.7 PU4305.8 R3703.1 R3715.1 U3702.6 USB1.A4 USB1.A9 USB1.B4 USB1.B9
VCCRTCEXT: C2112.1 CPU1.BB10
VCCSA_SENSE: CPU1.H20 PR4607.1 R735.2
VCCSENSE_EDRAM_VR: CPU1.AC63 R724.2
VCCSENSE_EOPIO_VR: CPU1.AL63 R729.2
VCCSTG_EN_R: C4033.1 R4017.2 U4002.4
VCCSTU_EN: EC4001.1 R4023.2 R4024.1 R4026.2 U4005.4
VCCSTU_EN_R: C4034.1 R4024.2 U4006.3
VDD: PC4428.1 PR4412.1 PR4422.1 PR4471.1 PU4401.19
VDDD: C3701.1 C3702.1 C3703.1 R3701.2 R3708.1 R3717.1 RN1814.1(A) RN1814.2(A) RN1815.1(A) RN1815.2(A) U3701.6 U3701.9
VDDIO: R3702.2 R3713.1 R3714.1 U3701.8
VSS_AY71: CPU1.AY71 R602.1
VSS_SENSE: CPU1.E33 PR4645.1 R720.1
VSSGT_SENSE: CPU1.J69 PR4618.1 R722.1
VSSSA_SENSE: CPU1.H21 PR4604.1 R734.1
VSSSENSE_EDRAM_VR: CPU1.AE63 R725.1
VSSSENSE_EOPIO_VR: CPU1.AJ62 R731.1
0D6V_PWR: PC5114.1 PG5120.1 PG5121.1 PU5102.3 PU5102.5
0D6V_S0: C1223.1 C1224.1 C1225.1 C1226.1 C1227.1 C1230.1 C1324.1 C1325.1 C1326.1 C1327.1 DM1.258 DM2.258 PG5120.2 PG5121.2
1D0V_PWR: PC5201.1 PC5203.1 PC5205.1 PC5206.1 PC5208.1 PG5201.1 PG5204.1 PG5206.1 PG5207.1 PG5208.1 PG5209.1 PG5211.1 PG5213.1 PG5215.1 PG5216.1 PG5223.2 PL5201.2
1D0V_S5: C4006.1 C4013.1 C4015.1 EC1710.1 PG5201.2 PG5204.2 PG5206.2 PG5207.2 PG5208.2 PG5209.2 PG5211.2 PG5213.2 PG5215.2 PG5216.2 Q4001.G R1101.1 R1102.1 R1724.1 R1735.1 R2402.1 U4002.1 U4002.2 U4002.9 U4004.1 U4004.2 U4004.9 U4006.1 U4006.2
1D0V_S5_PWRGD: PR5209.1 R4029.1
1D2V_PWR: PC5101.1 PC5102.1 PC5103.1 PC5104.1 PC5105.1 PC5115.1 PC5118.1 PG5102.1 PG5106.1 PG5109.1 PG5111.1 PG5112.1 PG5113.1 PG5114.1 PL5101.2 PU5102.1 PU5102.2
1D2V_S3: C718.1 C719.1 C1202.1 C1203.1 C1204.1 C1205.1 C1206.1 C1208.1 C1209.1 C1210.1 C1214.1 C1215.1 C1216.1 C1217.1 C1218.1 C1219.1 C1220.1 C1221.1 C1303.1 C1304.1 C1305.1 C1306.1 C1307.1 C1308.1 C1309.1 C1310.1 C1315.1 C1316.1 C1317.1 C1318.1 C1319.1 C1320.1 C1321.1 C1322.1 CPU1.AL23 CPU1.AU23 CPU1.AU28 CPU1.AU35 CPU1.AU42 CPU1.BB23 CPU1.BB32 CPU1.BB41 CPU1.BB47 CPU1.BB51 DM1.12 DM1.33 DM1.54 DM1.75 DM1.96 DM1.111 DM1.112 DM1.117 DM1.118 DM1.123 DM1.124 DM1.129 DM1.130 DM1.135 DM1.136 DM1.141 DM1.142 DM1.147 DM1.148 DM1.153 DM1.154 DM1.159 DM1.160 DM1.163 DM1.178 DM1.199 DM1.220 DM1.241 DM2.12 DM2.33 DM2.54 DM2.75 DM2.96 DM2.111 DM2.112 DM2.117 DM2.118 DM2.123 DM2.124 DM2.129 DM2.130 DM2.135 DM2.136 DM2.141 DM2.142 DM2.147 DM2.148 DM2.153 DM2.154 DM2.159 DM2.160 DM2.163 DM2.178 DM2.199 DM2.220 DM2.241 EC1102.1 EC1103.1 EC1202.1 EC1303.1 EC8918.1 EC8919.1 EC8920.1 EC8921.1 EC8922.1 EC8923.1 EC8924.1 EC8925.1 EC8933.1 EC8934.1 EC8935.1 EC8936.1 EC8937.1 EC8938.1 PC1101.1 PC1107.1 PC1108.1 PC1109.1 PC1110.1 PC1111.1 PC1112.1 PC1113.1 PC1114.1 PC1115.1 PG5102.2 PG5106.2 PG5109.2 PG5111.2 PG5112.2 PG5114.2 Q501.G R505.1 R705.1 R1215.1 R1312.1 RN1201.1(A) RN1301.1(A)
1D2V_VTT_PWRGD: PR5107.1 R4011.1
1D5V_PWR: PC5409.1 PG5404.1 PU5402.5
1D5V_S0: PG5404.2 R2102.1 R2705.1 R5701.1
1D5V_VDD: C5702.2 C5704.2 C5705.2 C5706.2 C5716.2 R5701.2 U5701.12 U5701.19 U5701.20 U5701.31 U5701.40
1D8S_EN#: Q4008.D R4043.1 R4046.2
1D8S_EN_R#: C4023.2 Q4009.G R4043.2
1D8V_EN#: Q2701.D R2726.2 R2727.1
1D8V_EN_R#: C2714.2 Q2702.G R2727.2
1D8V_PWR: PC5402.1 PC5404.1 PC5405.1 PG5405.1 PG5406.1 PG5407.1 PR5403.1 PU5401.3 PU5401.4
1D8V_S0: C2721.1 Q2702.D R2713.1 R2724.1
1D8V_S5_PWROK: PR5408.1 R4030.1
2D5V_S3: C1207.1 C1211.1 C1212.1 C1213.1 C1231.1 C1232.1 C1311.1 C1312.1 C1313.1 C1314.1 C1330.1 C1331.1 DM1.257 DM1.259 DM2.257 DM2.259 PG5408.2 PG5409.2
3D3V_AUX_KBC_33: C2423.1 KBC24.54 R2462.1
3D3V_AUX_S5: D2501.1 GPU1.F1 PG4532.2 PR4503.1 PR4505.1 R1726.2 R1727.1 R1737.1 R2463.1
3D3V_CAMERA_S0: C5503.1 EC5502.1 F5502.2 R5513.2 TCBD1.6
3D3V_GSEN2: C7003.1 C7004.1 R7004.2 R7005.1 R7006.2 U7001.9 U7001.10
3D3V_MCU: C6901.1 C6903.1 C6904.1 C6905.1 C6906.1 C6907.1 R6901.2 R6902.2 R6909.2 R6911.2 R6913.2 R6915.2 R6917.2 R6919.2 RN6901.1(A) RN6901.2(A) TP6902.1 U6901.1 U6901.9 U6901.24 U6901.36 U6901.48
3D3V_MUX: C3815.1 C3816.1 C3817.1 C3818.1 C3819.1 R3801.1 R3810.2 R3811.2 R3812.2 R3813.2 R3814.2 R3816.1 R3818.1 R3820.1 R3822.1 R3824.1 R3847.2 R3848.2 R3849.1 R3850.1 U3801.6 U3801.20 U3801.28
3D3V_S0: C1228.1 C1328.1 C1329.1 C2601.1 C2602.1 C4004.1 C5502.1 C5701.2 C5703.2 DB1.1 DM1.255 DM2.255 EC8909.1 EC8910.1 EC8911.1 F5502.1 F5504.1 GPU2.P1 GPU2.P2 GPU2.P3 IOBD1.36 IOBD1.37 IOBD1.38 IOBD1.39 PR4614.1 PR5102.2 Q1801.2 Q1801.5 Q2414.G Q2601.2 Q2601.5 R405.1 R506.1 R802.2 R1204.2 R1208.2 R1211.2 R1216.1 R1302.2 R1306.2 R1310.2 R1503.1 R1606.1 R1607.1 R1608.1 R1818.2 R1820.1 R1821.1 R2005.1 R2006.1 R2010.1 R2029.1 R2042.1 R2043.1 R2044.1 R2045.1 R2046.1 R2047.1 R2048.1 R2049.1 R2429.2 R2430.2 R2489.2 R2603.1 R2604.1 R2609.1 R2710.1 R2731.1 R3847.1 R3848.1 R4005.1 R4027.1 R5411.1 R5413.1 R5415.1 R5417.1 R5419.1 R5420.1 R5513.1 R5516.1 R6120.1 R6302.1 R6307.1 R6502.1 R6901.1 R7004.1 R7018.1 RN801.1(A) RN801.2(A) RN803.1(A) RN803.2(A) RN1810.1(A) RN1810.2(A) RN1812.1(A) RN1812.2(A) RN1812.3(A) RN1813.1(A) RN1813.2(A) RN1813.3(A) RN2007.3(B) RN2007.4(B) RN2008.3(B) RN2008.4(B) RN2602.1(A) RN2602.2(A) THM261.1 U4001.8 U4001.9 U5501.4 U5501.5 U5701.11 U5701.37
3D3V_S5: C1702.1 C1703.1 C2416.1 C2421.1 C4014.1 C4102.1 C6502.1 C7002.1 D3701.A EC1302.1 EC1713.1 EC8912.1 GMR1.3 PC5403.1 PC5408.1 PC5414.1 PD4302.2 PG4519.2 PG4520.2 PG4521.2 PG4522.2 PG4523.2 PG4524.2 PR4304.1 PR4335.1 PR4450.2 PR5208.1 PR5402.1 PR5410.1 PU5401.5 PU5401.9 PU5402.1 PU5403.5 PU5403.9 Q2416.2 Q2416.5 Q6502.S R1711.1 R2434.1 R2442.1 R2446.1 R2607.1 R3849.2 R3850.2 R4026.1 R4028.1 R4031.1 R4101.1 R5721.1 R7001.2 R7011.2 RN1704.1(A) RN1704.2(A) RN1704.3(A) RN1704.4(A) RN2405.5(B) RN2405.6(B) RN2405.7(B) RN2405.8(B) RN2407.1(A) RN2407.2(A) U1701.5 U1703.5 U4001.6 U4001.7 U4005.5 U4101.2 U4101.3 U4302.2
3D3V_S5_KBC: C2410.1 C2411.1 C2412.1 C2413.1 C2414.1 C2420.1 C2422.1 C2429.1 D4304.2 D4305.2 D4306.2 DB3.1 KBC24.5 KBC24.19 KBC24.22 KBC24.43 KBC24.65 KBC24.82 KBC24.103 KBC24.115 PR4438.1 PR4439.1 PR4445.1 Q2415.G Q2605.2 Q2605.5 R2414.2 R2415.2 R2424.2 R2443.1 R2446.2 R2450.2 R2462.2 R2473.2 R2480.2 R2495.2 R2608.1 R3707.1 R4032.1 RN2402.1(A) RN2402.2(A) RN2403.1(A) RN2403.2(A) RN2403.3(A) RN2403.4(A) RN2404.1(A) RN2404.2(A) RN2404.3(A) RN2404.4(A) RN2409.1(A) RN2409.2(A) RN2409.3(A) RN2409.4(A) RN2410.1(A) RN2410.2(A) RN2410.3(A) RN2410.4(A) RN2411.1(A) RN2411.2(A) RN2411.3(A) RN2411.4(A) RN2412.1(A) RN2412.2(A) RN2412.3(A) RN2412.4(A) RN2603.1(A) RN2603.2(A) RN2604.1(A) RN2604.2(A)
3D3V_S5_PCH: C4101.1 Q2604.2 Q2604.5 R404.1 R1103.1 R1814.1 R1822.1 R1824.1 R1836.1 R1837.1 R2007.1 R2039.1 R2040.1 R2041.1 R2501.2 R2515.1 R4101.2 R4103.2 RN1601.1(A) RN1601.2(A) RN1601.3(A) RN1601.4(A) RN1802.1(A) RN1802.2(A) RN1807.1(A) RN1807.2(A) RN1807.3(A) RN1807.4(A) RN1811.1(A) RN1811.2(A)
3D3V_SEN_S0: C5515.1 EC5505.1 F5504.2 R5516.2 TCBD1.5
3D3V_SPIVCC1: C2501.1 C2502.1 R2515.2 SKT251.8 SPI25.8
3D3V_SSD: AFTP6304.1 C6304.1 C6305.1 C6306.1 C6307.1 C6308.1 R6302.2 R6303.1 R6307.2 SSD1.2 SSD1.4 SSD1.12 SSD1.14 SSD1.16 SSD1.18 SSD1.70 SSD1.72 SSD1.74
81208_AGND: PC4604.1 PC4609.2 PC4613.2 PC4615.1 PC4619.2 PC4626.2 PC4628.2 PC4629.2 PC4630.2 PC4631.2 PC4632.2 PC4633.2 PG4601.1 PR4602.1 PR4611.2 PR4613.1 PR4615.2 PR4628.2 PR4632.1 PR4635.2 PR4636.2 PR4658.1 PR4659.2 PR4660.1 PR4663.1 PR4664.2 PR4672.1 PU4601.49
+DC_IN: EC8913.1 EL4301.2 EL4302.2 PC4301.1 PC4302.1 PD4301.K PQ4305.2 PR4307.1 PR4312.1 PR4314.1 PU4301.1 PU4301.2 PU4301.3
+DC_IN_C: AFTP4303.1 AFTP4305.1 DCIN1.6 DCIN1.7 DCIN1.8 EC4301.1 EC4302.1 EL4301.1 EL4302.1
+RTC_VCC: D2501.2 IOBD1.34 Q2505.G R2504.1
+SDC_IN: PG4402.1 PR4318.1 PR4320.1 PR4402.1 PU4302.1 PU4302.2 PU4302.3 PU4304.1 PU4304.2 PU4304.3
+SDC_IN_SW: PR4318.2 PR4333.2 PU4302.4
+SDC_IN_SW_R1: PQ4310.3 PR4333.1
+V_EDRAM_VR: C701.1 C702.1 CPU1.AB62 CPU1.P62 CPU1.V62 R724.1 R4021.2
+V_EOPIO_VR: C703.1 C704.1 CPU1.AE62 CPU1.AG62 R729.1 R4022.1
+V_VREF_PATH1: C1222.2 R1209.1
+V_VREF_PATH2: C1323.2 R1309.1
A5_TP: CPU1.A5 TP2309.1
A67_TP: CPU1.A67 TP2311.1
A70_TP: CPU1.A70 TP2310.1
AC_DIS: PQ4304.B PQ4306.5 R4302.1 R4303.1
AC_IN#_G: PR4312.2 PR4313.1 U4302.5
AC_PRESENT: CPU1.AY15 D1701.A EC1707.1 Q1702.3 RN1704.8(B)
ACLIM: PR4421.2 PR4424.1 PU4401.16
ACOK#: PQ4415.2 PQ4415.3 PR4471.2
ACOK_IN: KBC24.128 PG4408.2 PQ4415.5
ACOK_IN_M: D1701.K PD4305.K PD4306.K PQ4415.6
AD+: PC4303.1 PC4304.1 PC4305.1 PC4306.1 PD4402.A PD4406.A PD4411.A PR4311.1 PR4316.1 PR4431.1 PU4301.5 PU4301.6 PU4301.7 PU4301.8 PU4302.5 PU4302.6 PU4302.7 PU4302.8
AD_IA: PC4423.1 PG4401.2 R2421.1
AD_OFF_L: PQ4304.C PQ4305.1
AD_OFF_R: PC4301.2 PQ4305.3 PR4307.2 PR4308.1 PU4301.4
ALERT#: R2603.2 THM261.6
ALL_SYS_PWRGD: D4002.1 EC1709.1 KBC24.48 R1716.1 R1733.2 R4002.1 R4005.2 R4011.2 R4044.1 U1701.2 U1703.4
ALL_SYS_PWRGD_R: D4003.K R4018.2 R4019.1 R4044.2
ALWON: KBC24.121 R4009.2
AMBER_LED_BAT: EC6401.1 Q6402.C R6401.2
AUD_AGND: C2702.1 C2704.1 C2705.1 C2710.2 C2711.2 C2712.1 C2713.2 C2715.2 C2902.2 EC2703.1 EC2704.1 EC2705.1 EC2706.1 EC2707.1 EC2905.2 EC2906.2 EC2907.2 EC2908.2 EC8901.1 EC8902.1 EC8903.1 EC8904.1 HDA27.18 HDA27.37 HPMIC1.MS R2706.1 R2711.1 R2905.2 R2919.2 R2920.2
AUD_HP1_JACK_L: HDA27.26 R2907.2
AUD_HP1_JACK_L1: EC2907.1 R2907.1 R2908.1 R2912.2 R2919.1 R2922.2
AUD_HP1_JACK_R: HDA27.25 R2909.2
AUD_HP1_JACK_R1: EC2908.1 R2909.1 R2910.1 R2913.2 R2920.1 R2921.2
AUD_PC_BEEP: HDA27.32 R2723.2
AUD_PC_BEEP_C: C2720.1 D2701.3 R2717.1
AUD_PC_BEEP_R: C2720.2 R2723.1
AUD_PORTA_L_R_B: ED2902.1 HPMIC1.1 R2908.2
AUD_PORTA_R_R_B: ED2905.1 HPMIC1.2 R2910.2
AUD_SENSE: C2902.1 R2709.2 R2923.2
AUD_SENSE_A: HDA27.1 R2709.1 R2722.2
AUD_SPK_L+: EC2904.1 EL2902.2 HDA27.42
AUD_SPK_L+_C: AFTP2902.1 EC2911.1 EL2902.1 SPK1.1
AUD_SPK_L-: EC2903.1 EL2901.2 HDA27.43
AUD_SPK_L-_C: AFTP2901.1 EC2909.1 EL2901.1 SPK1.2
AUD_SPK_R+: EC2901.1 EL2904.2 HDA27.45
AUD_SPK_R+_C: AFTP2904.1 EC2910.1 EL2904.1 SPK1.4
AUD_SPK_R-: EC2902.1 EL2903.2 HDA27.44
AUD_SPK_R-_C: AFTP2903.1 EC2912.1 EL2903.1 SPK1.3
AUD_VREF: C2705.2 HDA27.38
AUX_EN_WOWL: CPU1.BB17 TP1710.1
B71_TP: CPU1.B71 TP2312.1
BA1_TP: CPU1.BA1 TP2305.1
BA2_TP: CPU1.BA2 TP2306.1
BA71_TP: CPU1.BA71 TP2303.1
BAT1_LED#: KBC24.1 Q2416.1 RN2405.1(A)
BAT2_LED#: KBC24.106 Q2416.4 RN2405.2(A)
BAT_AMBER: ED6401.1 KBBD1.33 R6401.1
BAT_WHITE: ED6402.1 KBBD1.34 R6402.1
BATT_WHITE_LED#: Q2416.6 R6404.1
BATT_WHITE_LED_R#: Q6105.D Q6401.B R6404.2
BB67_TP: CPU1.BB67 TP2302.1
BB70_TP: CPU1.BB70 TP2301.1
BEEP: KBC24.45 RN2701.1(A)
BKLGT_PWM: KBC24.44 Q6501.G R6509.1
BKLT_CTRL: D5502.3 R5502.1 RN5501.5(B) RN5502.5(B)
BLON_OUT_C: LCD1.31 RN5501.2(A) RN5502.6(B)
BLUETOOTH_EN: CPU1.AB2 IOBD1.47 R2042.2
BOARD_ID: C2408.2 KBC24.111 R2443.2 R2444.1 R2494.2
BOARD_ID1: CPU1.AC1 R2009.1 R2010.2
BOARD_ID2: CPU1.AB3 R2005.2 R2008.1
BOOST_MON: PC4424.1 PG4414.2 R2423.1
BT+: AFTP4312.1 AFTP4313.1 AFTP4314.1 BATT1.1 BATT1.2 BATT1.3 EC4307.1 EC4308.1 PC4415.1 PC4416.1 PC4417.1 PC4418.1 PC4419.1 PC4433.1 PC4435.1 PD4304.K PD4401.A PG4413.1 PR4403.2 PR4415.2
C1_TP: CPU1.C1 TP2308.1
CAP_LED: AFTP6538.1 KBBD1.2 R6513.2
CAP_LED#: KBC24.93 Q2414.S R2489.1
CAP_LED#_R: Q2414.D R6512.1
CAP_LED_Q: Q6505.C R6513.1
CAP_LED_R#: Q6505.B R6512.2
CBN: C2703.2 HDA27.23
CBP: C2703.1 HDA27.22
CCG2_I2C_SCL: Q2605.6 RN1815.4(B) U3701.20
CCG2_I2C_SDA: Q2605.3 RN1815.3(B) U3701.19
CFG: R5420.2 U5701.23
CFG0: CPU1.E68 TP618.1
CFG1: CPU1.B67 TP619.1
CFG2: CPU1.D65 TP620.1
CFG3: CPU1.D67 R604.1 TP621.1
CFG4: CPU1.E70 R605.1 TP622.1
CFG5: CPU1.C68 TP623.1
CFG6: CPU1.D68 TP624.1
CFG7: CPU1.C67 TP625.1
CFG8: CPU1.F71 TP626.1
CFG9: CPU1.G69 TP627.1
CFG10: CPU1.F70 TP628.1
CFG11: CPU1.G68 TP629.1
CFG12: CPU1.H70 TP630.1
CFG13: CPU1.G71 TP631.1
CFG14: CPU1.H69 TP632.1
CFG15: CPU1.G70 TP633.1
CFG16: CPU1.E63 TP634.1
CFG17: CPU1.F63 TP635.1
CFG18: CPU1.E66 TP636.1
CFG19: CPU1.F66 TP637.1
CFG_RCOMP: CPU1.E60 R601.1
CHARGER_SRC: PC4405.1 PC4406.1 PC4407.1 PC4408.1 PC4409.1 PC4410.1 PC4411.1 PG4404.1 PG4405.1 PG4406.1 PG4407.1 PU4404.5 PU4404.6 PU4404.7 PU4404.8
CHG_AMBER_LED#: Q2416.3 R6403.1
CHG_AMBER_LED_R#: Q6402.B R6403.2
CLK_PCI_LPC: DB1.9 EC1802.1 R1804.2
CLK_PCI_LPC_MEC: EC1801.1 KBC24.57 R1805.2
CLK_PCIE_VGA: CPU1.C42 GPU1.B8
CLK_PCIE_VGA#: CPU1.D42 GPU1.B9
CLK_TP_SIO: EC6501.1 KBC24.78 RN6501.4(B) RN6502.2(A)
CLKREQ_PCIE#1: CPU1.AT7 IOBD1.44 RN1813.7(B)
CLKREQ_PCIE#2: CPU1.AT8 RN1813.6(B)
CLKREQ_PCIE#3: CPU1.AT10 RN1812.8(B)
CLKREQ_PCIE#4: CPU1.AU8 RN1812.6(B)
CLKREQ_PCIE#5: CPU1.AU7 RN1813.8(B)
CLKREQ_PEG#0: CPU1.AR10 GPU1.A2 RN1812.7(B)
CLKRUN#: KBC24.63 R1819.2 R2510.1
CLKRUN#_R: CPU1.AW11 R1818.1 R1819.1
CMP_VIN0: KBC24.20 R2470.2
CMP_VIN0_R: C2612.1 C2613.1 R2470.1 R2494.1 R2608.2 R2609.2 R2610.1
CMP_VOUT0: KBC24.85 R2602.2 R2607.2 R2615.2
CMP_VOUT1: KBC24.83 Q2408.G R2417.1 R2418.1
CODEC_BITCLK_R: HDA27.8 R2720.2
CODEC_SDOUT_R: HDA27.11 R2719.2
COMBO-GPI: HDA27.2 TP2702.1
CPU_A16_TP: CPU1.BB9 TP1902.1
CPU_D1_TP: CPU1.M2 TP1801.1
CPU_D4_TP: CPU1.V1 TP1804.1
CPU_D5_TP: CPU1.V2 TP1805.1
CPU_D6_TP: CPU1.M1 TP1806.1
CPU_DP1_CTRL_CLK: CPU1.L13 RN801.3(B) U5701.38
CPU_DP1_CTRL_DATA: CPU1.L12 RN801.4(B) U5701.39
CPU_DP1_HPD: CPU1.L9 U5701.3
CPU_DP2_CTRL_CLK: CPU1.N7 RN803.4(B)
CPU_DP2_CTRL_DATA: CPU1.N8 RN803.3(B)
CPU_DP2_HPD: CPU1.L7 R803.2 R804.1
CPU_DP_HPD_MUX: R3706.2 U3701.23
CPU_DP_HPD_R: R804.2 R3706.1 R3717.2 R3846.2
CPU_POPIRCOMP: CPU1.AT16 R412.1
CPU_RXN_C_DGPU_TXN0: CPU1.H13 GPU1.E3
CPU_RXN_C_DGPU_TXN1: CPU1.G11 GPU1.E6
CPU_RXN_C_DGPU_TXN2: CPU1.H16 GPU1.F5
CPU_RXN_C_DGPU_TXN3: CPU1.G15 GPU1.F8
CPU_RXP_C_DGPU_TXP0: CPU1.G13 GPU1.E2
CPU_RXP_C_DGPU_TXP1: CPU1.F11 GPU1.E5
CPU_RXP_C_DGPU_TXP2: CPU1.G16 GPU1.F4
CPU_RXP_C_DGPU_TXP3: CPU1.F15 GPU1.F7
CPVDD: C2701.1 C2724.1 HDA27.21 R2724.2
CPVEE: C2704.2 HDA27.24
CSI2_COMP: CPU1.E13 R1501.1
CTL1: R3401.2 U3401.6
CTL2: R3406.2 U3401.7
CTL3: R3402.2 U3401.8
DAT_TP_SIO: EC6502.1 KBC24.79 RN6501.3(B) RN6502.1(A)
DBC_EN_R: LCD1.32 R5503.1
DBC_PANEL_EN: CPU1.AM5 R2043.2 R5503.2
DC_IN_OK: PD4305.A PQ4306.2 PQ4308.2 PQ4310.5 PR4311.2 PR4315.2 PR4335.2 R2475.1 U4302.1
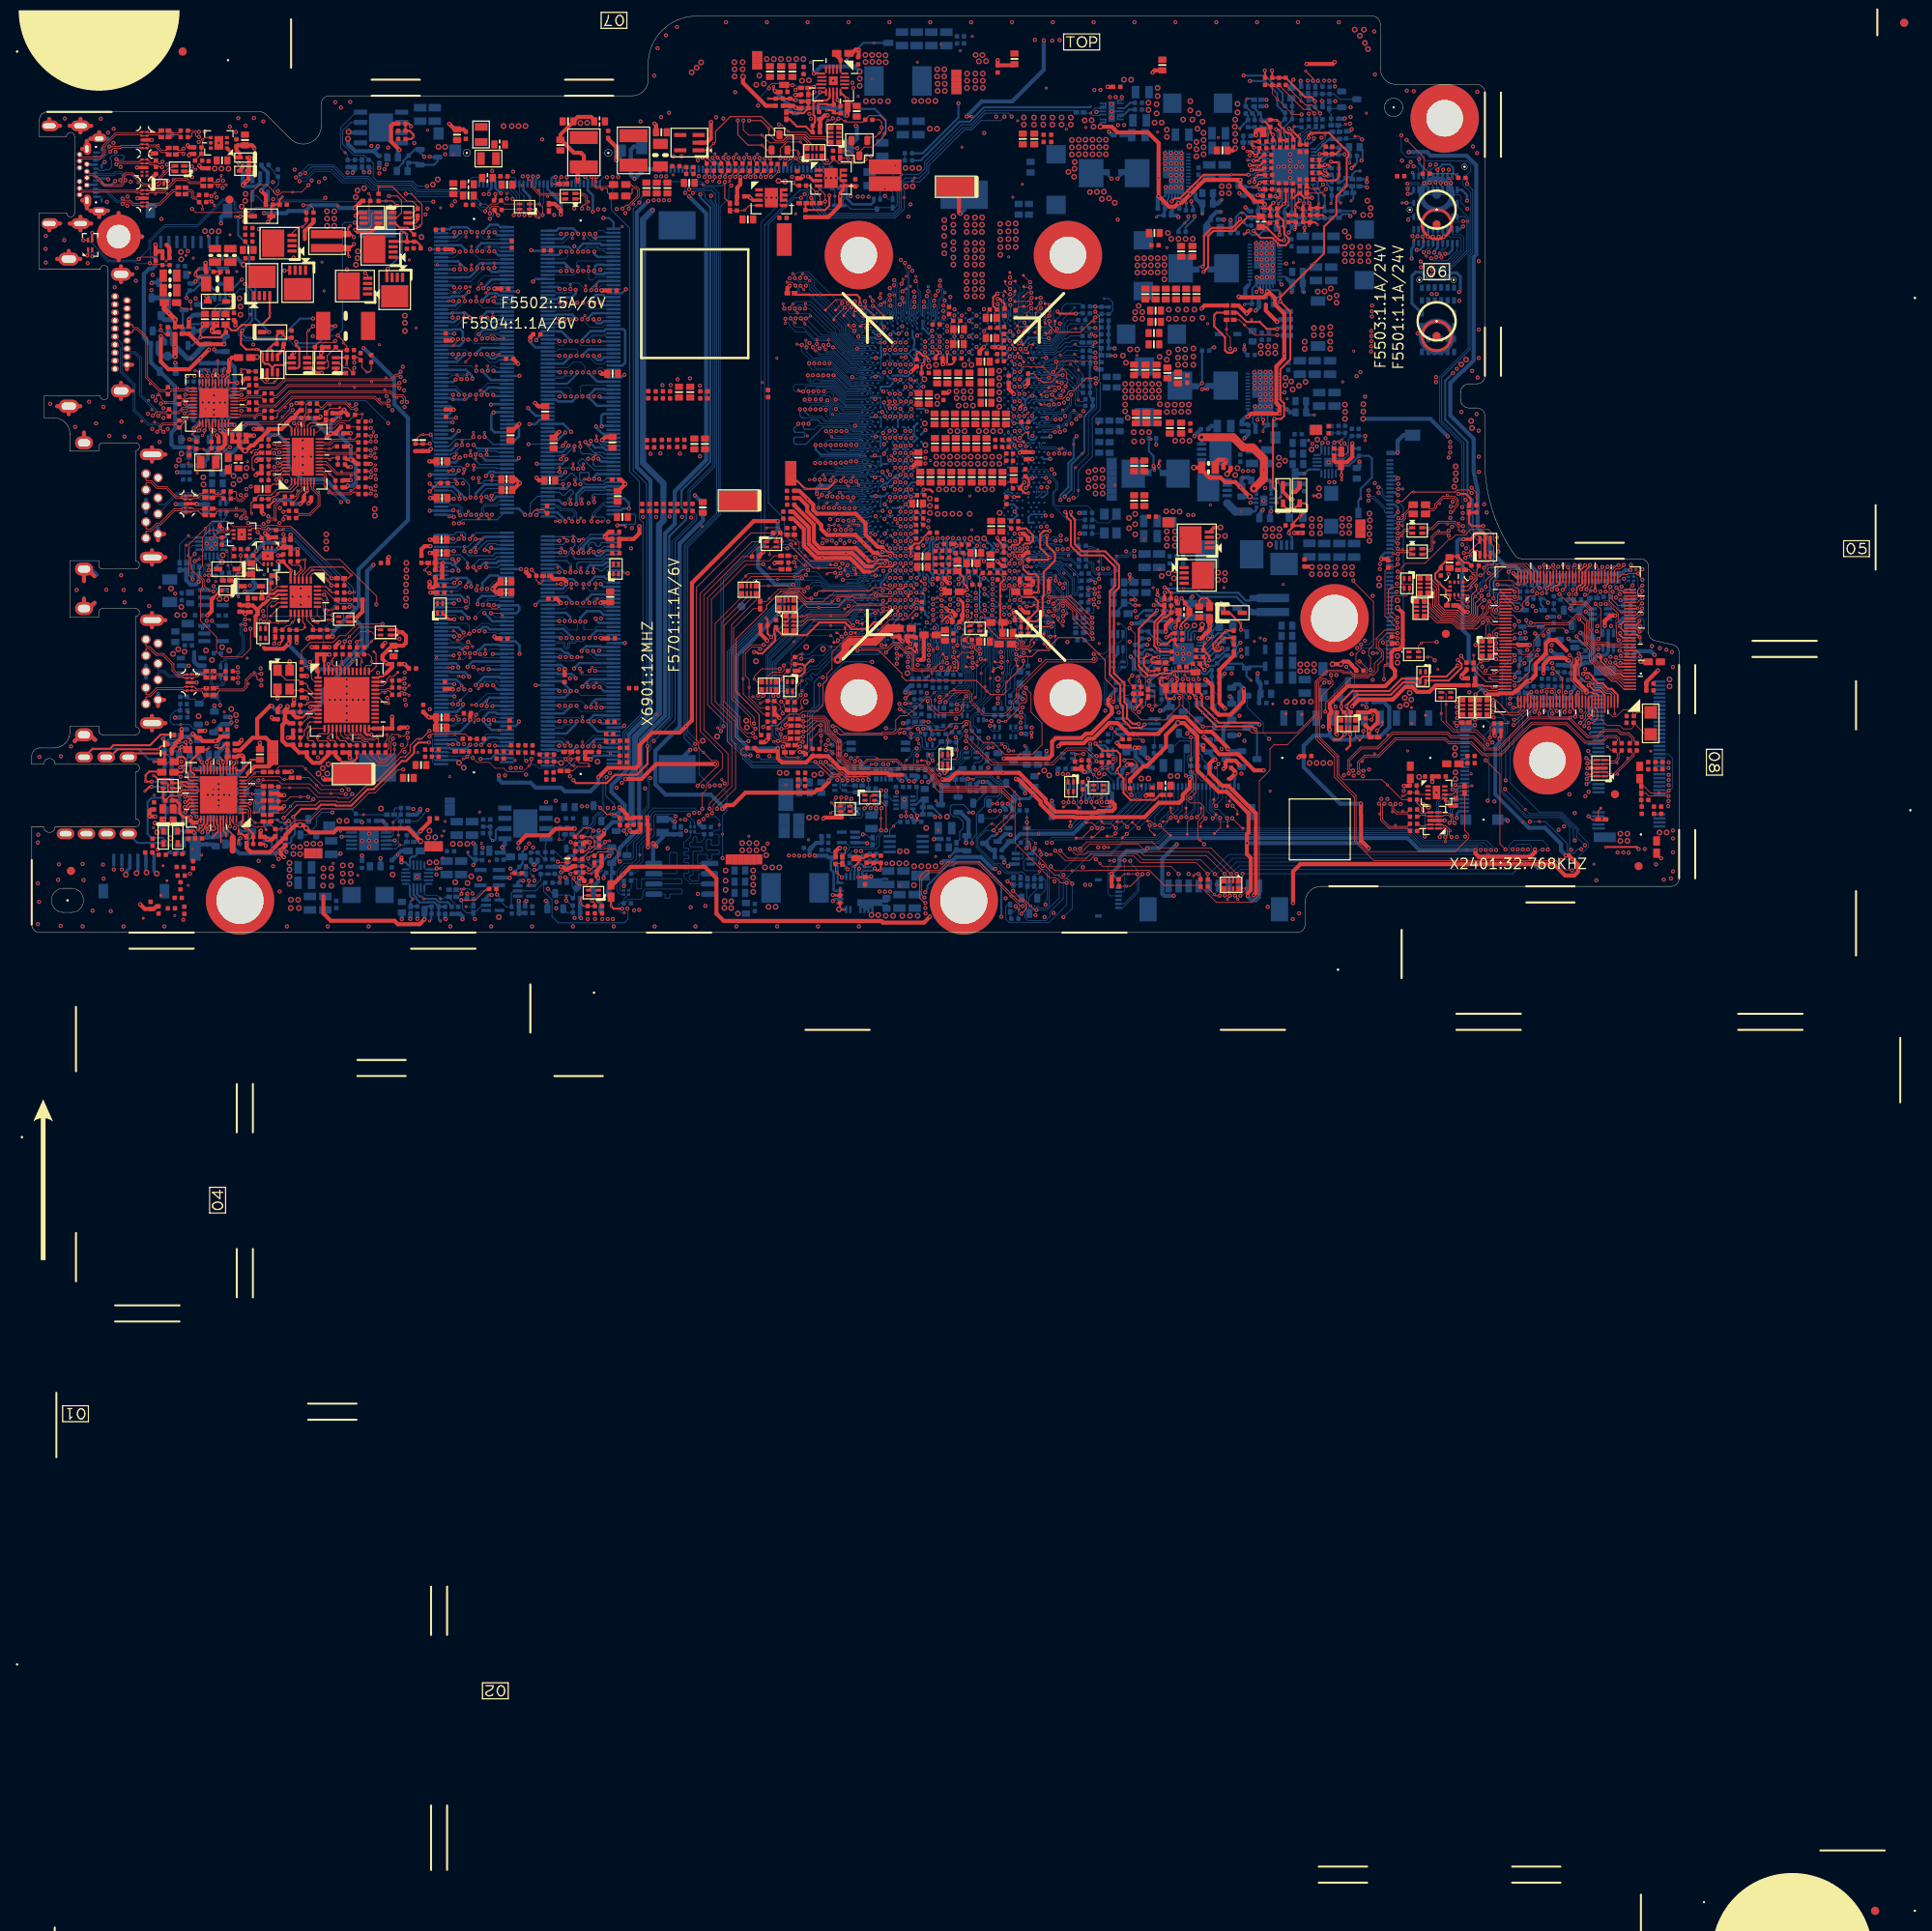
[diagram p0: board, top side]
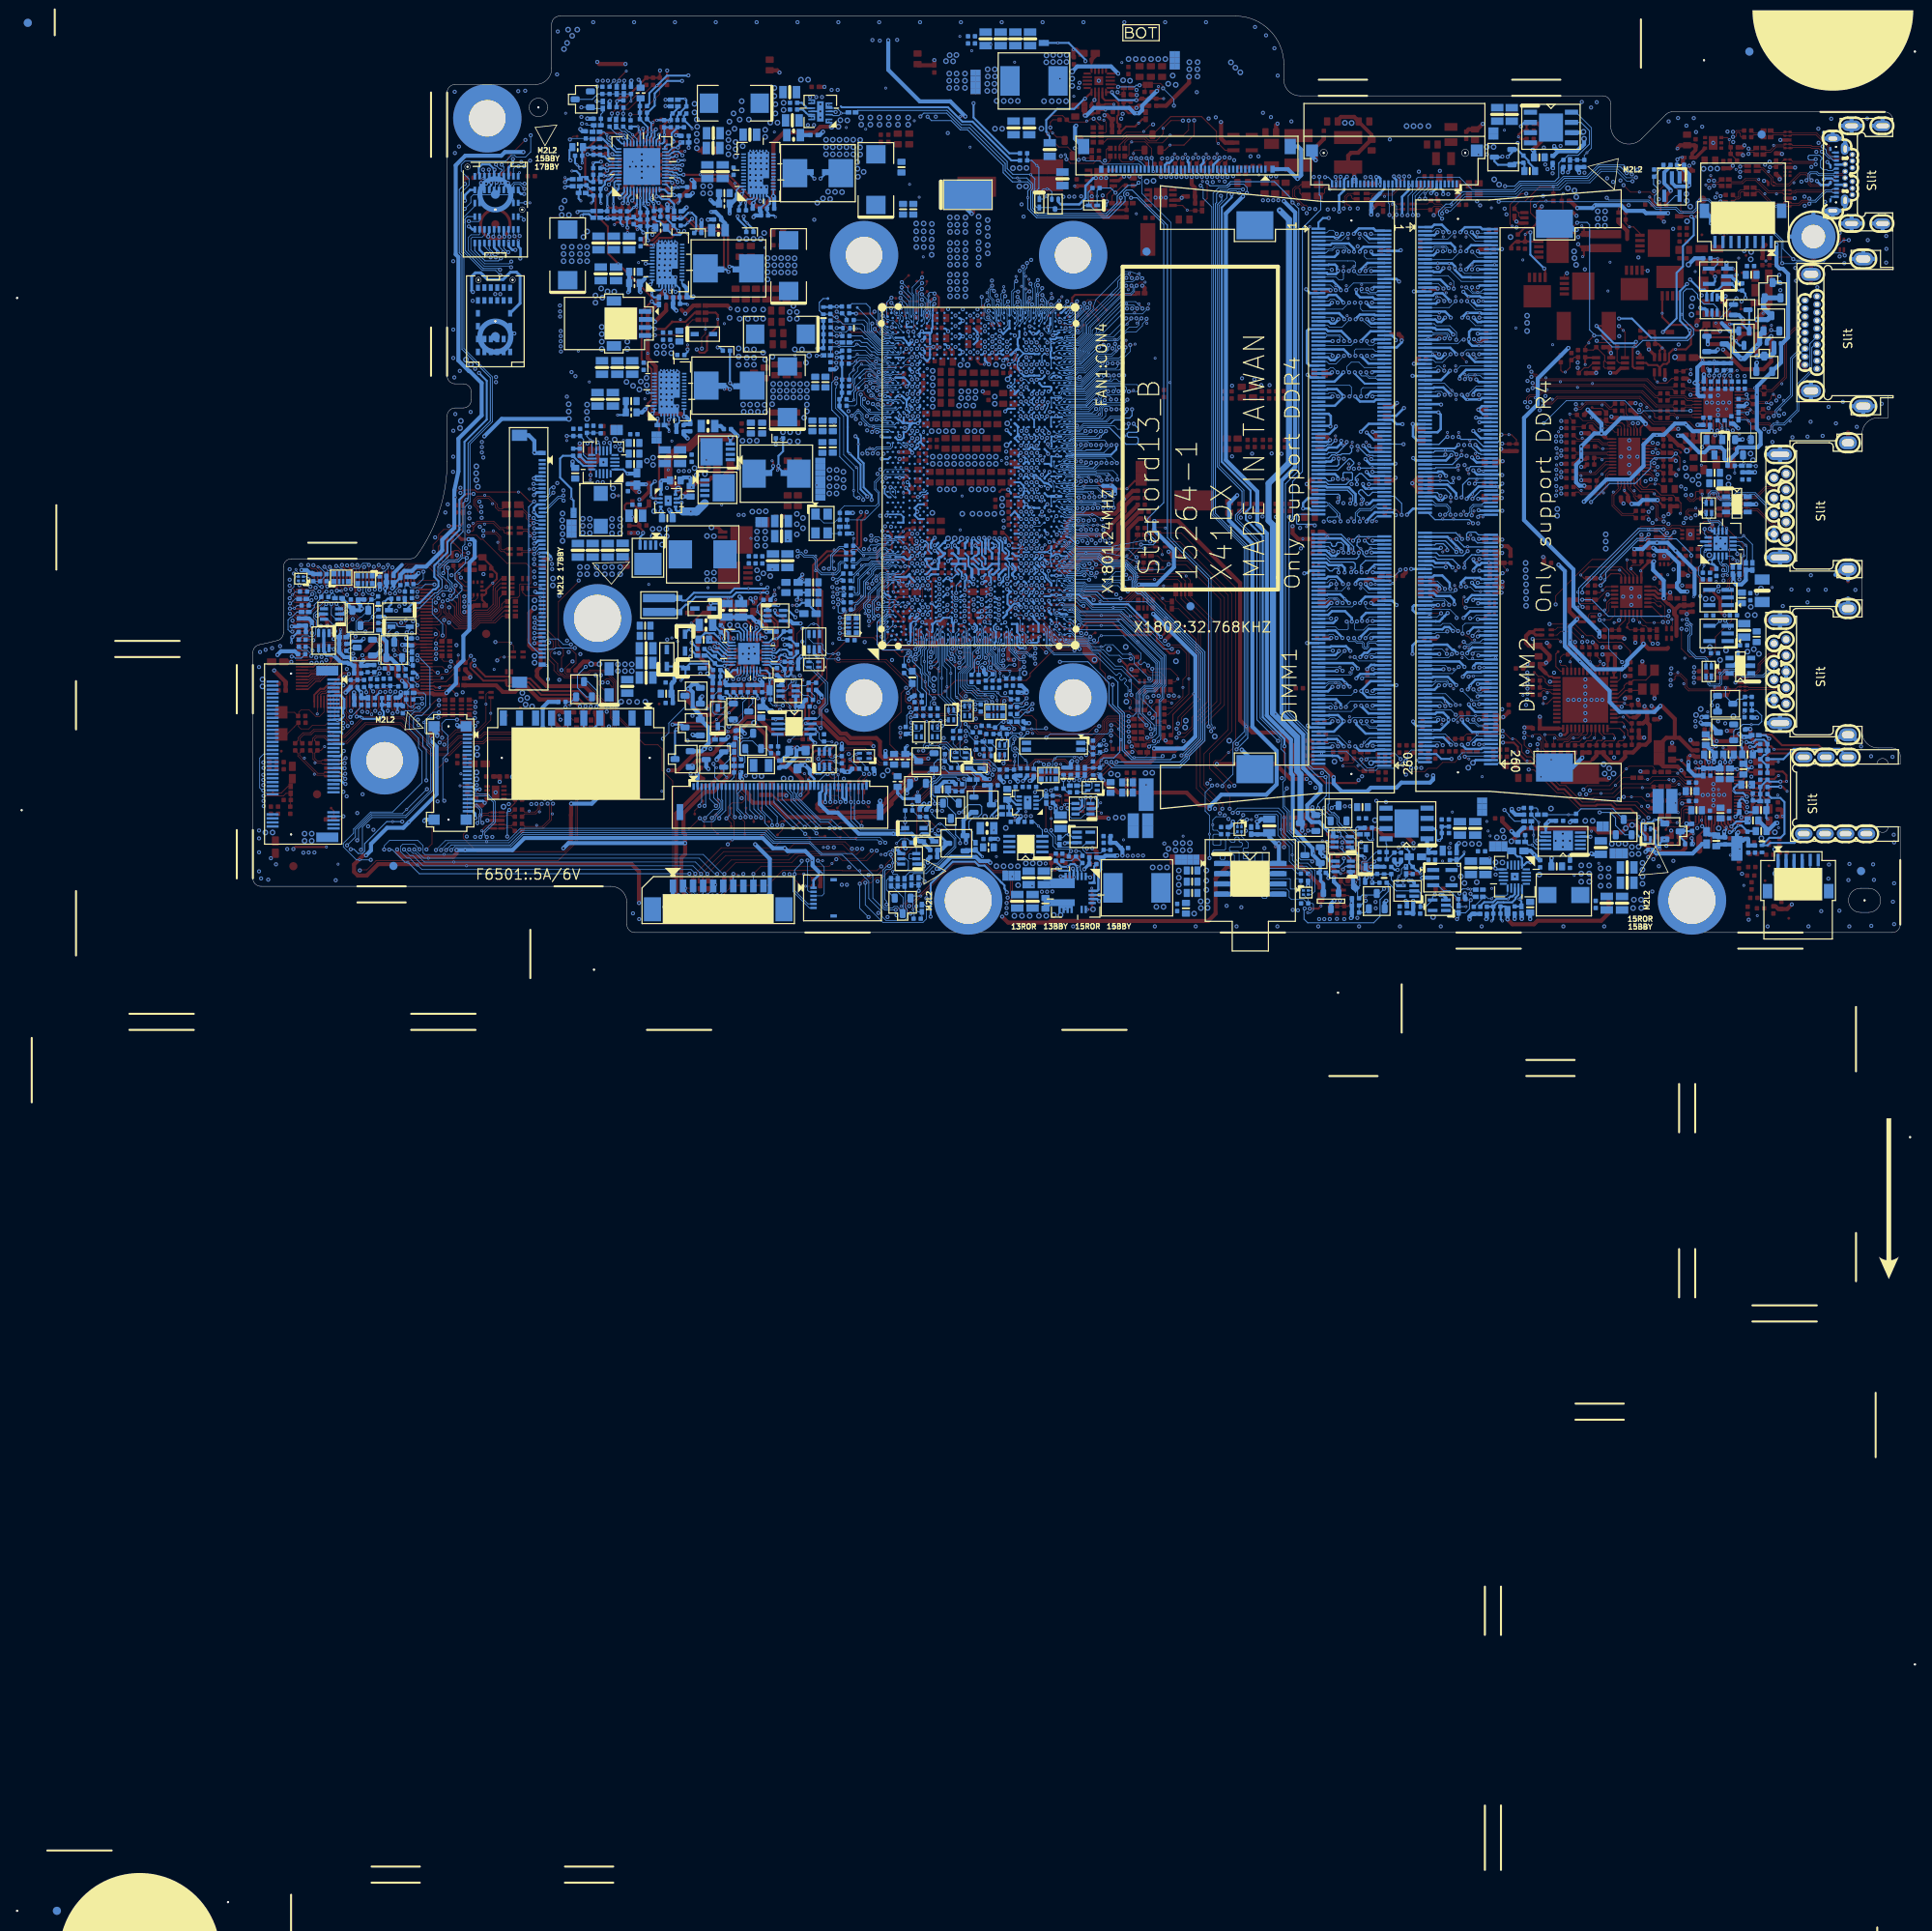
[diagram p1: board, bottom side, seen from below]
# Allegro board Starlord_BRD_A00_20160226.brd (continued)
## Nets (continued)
DCBATOUT: EC4425.1 EC4534.1 EC8905.1 EC8906.1 EC8907.1 EC8908.1 EC8926.1 EC8927.1 EC8928.1 EC8929.1 F5503.2 GPU2.A1 GPU2.A2 GPU2.A3 GPU2.A4 GPU2.A5 GPU2.A6 GPU2.B1 GPU2.B2 GPU2.B3 GPU2.B4 GPU2.B5 GPU2.B6 PC4434.1 PC4701.1 PC4702.1 PC4703.1 PC4704.1 PC4705.1 PC4710.1 PC4802.1 PC4803.1 PC4804.1 PC4805.1 PC4806.1 PC4811.1 PC4812.1 PC4820.1 PC4827.1 PC4828.1 PC4829.1 PC4830.1 PG4403.1 PG4404.2 PG4405.2 PG4406.2 PG4407.2 PG4501.1 PG4502.1 PG4503.1 PG4504.1 PG4505.1 PG4506.1 PG4515.1 PG4516.1 PG4517.1 PG4518.1 PG5023.2 PG5024.2 PG5101.1 PG5103.1 PG5104.1 PG5107.1 PG5108.1 PG5110.1 PG5210.1 PG5212.1 PG5214.1 PR4402.2 PR4410.2 PR4458.1 PR4509.1 PR4511.1 PR4601.1 PT4805.1 PT4806.1 PU4403.1 PU4403.2 PU4403.3 PU4701.25 PU4701.26 PU4701.27 PU4701.28 PU4701.29 PU4701.30 PU4801.25 PU4801.26 PU4801.27 PU4801.28 PU4801.29 PU4801.30 PU4802.25 PU4802.26 PU4802.27 PU4802.28 PU4802.29 PU4802.30 R5514.2 R5520.2
DCBATOUT_+VCCSA: PC5002.1 PC5027.1 PC5029.1 PG5023.1 PG5024.1 PU5002.5 PU5002.6 PU5002.7 PU5002.8
DCBATOUT_CAMERA: C5534.1 C5542.2 R5520.1 TCBD1.1 TCBD1.2
DCBATOUT_LCD: C5512.1 C5513.1 C5514.1 C5518.1 F5503.1 LCD1.1 LCD1.2 LCD1.3 LCD1.4 R5514.1
DCIN_EN: R5419.2 U5701.13
DDC_CLK_HDMI: HDMI1.15 R5707.2 U5701.32
DDC_CLK_PH1: D5701.2 R5707.1
DDC_DATA_HDMI: HDMI1.16 R5706.2 U5701.33
DDC_DATA_PH2: D5701.1 R5706.1
DDCBUF: R5417.2 R5418.2 U5701.14
DDR4_DRAMRST#: DM1.108 DM2.108 ED1217.1 ED1302.1 R504.2
DDR_VREF_S3: PC5116.1 PU5102.6
DGPU_HOLD_RST#: CPU1.P3 EC2002.1 GPU1.D10 RN2009.4(B)
DGPU_PWR_EN: CPU1.U1 GPU1.C10 RN2009.3(B)
DGPU_PWROK: GPU1.D9 R2471.1
DGPU_PWROK_KBC: KBC24.24 R2471.2
DGPU_RXN_C_CPU_TXN0: C1606.1 GPU1.A5
DGPU_RXN_C_CPU_TXN1: C1608.1 GPU1.A8
DGPU_RXN_C_CPU_TXN2: C1610.1 GPU1.B3
DGPU_RXN_C_CPU_TXN3: C1612.1 GPU1.B6
DGPU_RXP_C_CPU_TXP0: C1605.1 GPU1.A4
DGPU_RXP_C_CPU_TXP1: C1607.1 GPU1.A7
DGPU_RXP_C_CPU_TXP2: C1609.1 GPU1.B2
DGPU_RXP_C_CPU_TXP3: C1611.1 GPU1.B5
DMIC_CLK: C2723.2 EC5504.1 R2716.1 RN5503.4(B)
DMIC_CLK_C: RN5503.1(A) TCBD1.17
DMIC_CLK_R: HDA27.6 R2716.2
DMIC_DATA: EC5503.1 R2714.1 RN5503.3(B)
DMIC_DATA_C: RN5503.2(A) TCBD1.18
DMIC_DATA_R: EC2701.1 HDA27.5 R2714.2
DPB_AUXN: C3802.1 CPU1.E48
DPB_AUXN_C: C3802.2 R3801.2 U3801.25
DPB_AUXP: C3801.1 CPU1.F48
DPB_AUXP_C: C3801.2 R3802.2 U3801.24
DS3_PWRCTL: R4102.2 U4101.4
E71_TP: CPU1.E71 TP2313.1
EAPD#: HDA27.3 R2708.2
EC_AGND: C2407.1 C2408.1 C2422.2 C2427.2 C2435.2 C2441.2 KBC24.112 R2441.2 R2444.2 R2445.2
EC_MUTE#: KBC24.119 R2708.1 R2728.1
EC_SPI_CLK: KBC24.32 RN2406.4(B)
EC_SPI_MISO: KBC24.29 RN2406.3(B)
EC_SPI_MOSI: KBC24.28 R2405.2
EC_VTT: C2406.1 KBC24.95 R2402.2
EC_WAKE#: KBC24.35 R1732.1
ECVBAT: C2428.1 KBC24.122 R2451.2 R2472.1 R2496.2
EDP_AUX: C5510.1 LCD1.12
EDP_AUX#: C5511.1 LCD1.13
EDP_AUX_DN: C5511.2 CPU1.E45
EDP_AUX_DP: C5510.2 CPU1.F45
EDP_COMP: CPU1.E52 R801.2
EDP_DISP_UTIL: CPU1.B52 TP801.1
EDP_HPD: CPU1.L10 R5506.2 RN5502.7(B)
EDP_HPD_CONN: LCD1.27 R5506.1
EDP_TX0: C5509.1 LCD1.25
EDP_TX0#: C5506.1 LCD1.24
EDP_TX0_DN: C5506.2 CPU1.C47
EDP_TX0_DP: C5509.2 CPU1.C46
EDP_TX1: C5504.1 LCD1.22
EDP_TX1#: C5501.1 LCD1.21
EDP_TX1_DN: C5501.2 CPU1.D46
EDP_TX1_DP: C5504.2 CPU1.C45
EDP_TX2: C5519.1 LCD1.19
EDP_TX2#: C5533.1 LCD1.18
EDP_TX2_DN: C5533.2 CPU1.A45
EDP_TX2_DP: C5519.2 CPU1.B45
EDP_TX3: C5531.1 LCD1.16
EDP_TX3#: C5532.1 LCD1.15
EDP_TX3_DN: C5532.2 CPU1.A47
EDP_TX3_DP: C5531.2 CPU1.B47
EDP_VDD_EN: CPU1.U13 D5501.1
EDRAM_OPIO_RCOMP: CPU1.H66 R414.1
EMMC_RCOMP: CPU1.AT1 R1502.1
EN_EDRAM_VR: D4003.A D4004.A Q4001.D R4019.2 R4027.2 R4028.2 U4004.4
EOPIO_RCOMP: CPU1.H65 R415.1
EQ: R5411.2 R5412.2 U5701.17
EXT_PWR_GATE#: CPU1.AM10 R1731.2
FALL_INT2: Q7001.2 Q7001.3 R7018.2
FAN1_PWM: KBC24.47 R2614.1
FAN1_TACH: D2403.A KBC24.40 R2430.1
FAN_PWM1_C: AFTP2602.1 FAN1.4 R2614.2
FAN_TACH1: D2403.K R2613.1
FAN_TACH1_C: AFTP2601.1 FAN1.3 R2613.2
FAN_VCC_1: AFTP2603.1 C2603.1 C2604.1 C2605.1 D2601.K FAN1.1 R2612.2
FFS_INT2: CPU1.AC2 D7001.3 R2044.2 R7008.2
FFS_INT2_Q: Q7001.6 R6001.1
FFS_INT2_Q_R: HDD1.1 R6001.2
GC6_FB_EN: GPU1.C1 R2004.1
GC6_FB_EN_MCP: CPU1.AP7 R2004.2
GPD2/LAN_WAKE#: CPU1.AM15 R1707.2 R1732.2
GPD11/LANPHYPC: CPU1.AW17 RN1704.5(B)
GPP_B2/VRALERT#: CPU1.AM11 TP1708.1
GPP_B4/CPU_GP3: CPU1.AY5 TP404.1
GPP_B18/GSPI0_MOSI: CPU1.AR7 R2007.2 R2019.1
GPP_B22: CPU1.AN5 TP2018.1
GPP_B23/SML1ALERT#: CPU1.AM7 R1837.2
GPP_C2/SMBALERT#: CPU1.R10 R1836.2
GPP_C5/SML0ALERT#: CPU1.W1 R1822.2 R1823.1
GPP_E0/SATAXPCIE0/SATAGP0: CPU1.H2 TP1602.1
GPP_E1/SATAXPCIE1/SATAGP1: CPU1.H3 TP1603.1
GPP_E2/SATAXPCIE2/SATAGP2: CPU1.G4 TP1604.1
GPP_E3/CPU_GP0: CPU1.A6 TP403.1
GPU_EVENT#: GPU1.F10 R2003.1
GPU_EVENT_MCP#: CPU1.AN8 R2003.2
GSEN2_INT1: R7009.2 R7012.2 U7001.12
GSEN2_INT1_C: R2025.2 R6925.2 R7009.1
GSEN2_INT1_C_HUB: R6925.1 U6901.17
GSEN2_INT1_ISH: CPU1.BA7 R2025.1
GSEN2_INT2: R7010.2 R7013.2 U7001.11
GSEN2_INT2_C: R2026.2 R6926.2 R7010.1
GSEN2_INT2_C_HUB: R6926.1 U6901.38
GSEN2_INT2_ISH: CPU1.AY7 R2026.1
GSEN_INT1: R2023.2 R6921.2 TCBD1.9
GSEN_INT1_HUB: R6921.1 U6901.18
GSEN_INT1_ISH: CPU1.BA8 R2023.1
GSEN_INT2: R2024.2 R6922.2 TCBD1.10
GSEN_INT2_HUB: R6922.1 U6901.19
GSEN_INT2_ISH: CPU1.BB7 R2024.1
GSENSOR_CS: R7006.1 U7001.2
GSENSOR_SDO: R7005.2 R7007.2 U7001.3
GYRO_DRDY: R2028.2 R6924.2 TCBD1.12
GYRO_DRDY_HUB: R6924.1 U6901.39
GYRO_DRDY_ISH: CPU1.AP13 R2028.1
GYRO_INT: R7002.2 R7003.2 TCBD1.11
GYRO_INT_C: R2027.2 R6923.2 R7003.1
GYRO_INT_C_HUB: R6923.1 U6901.20
GYRO_INT_ISH: CPU1.AW7 R2027.1
GYRO_INT_P11: D7001.1 R7002.1
H_CATERR#: CPU1.D63 TP401.1
H_CPU_SVIDALRT#: CPU1.B63 R728.2
H_CPU_SVIDCLK: CPU1.A63 R732.1
H_CPU_SVIDDAT: CPU1.D64 R709.1 R726.2
H_CPUPWRGD: CPU1.A68 EC1701.1 R1714.1 TP1705.1
H_PECI: CPU1.A54 R2437.2
H_PROCHOT#: C2403.1 PG4419.2 PR4445.2 PR4455.2 PR4624.2 PR4668.2 PR4669.2 Q2408.D R401.2 R403.1 R2418.2
H_PROCHOT#_R: CPU1.C65 R403.2
H_VCCST_PWRGD: C1711.1 CPU1.B65 EC1708.1 R1716.2 R1719.1 R1722.2 U1701.4
HDA_BITCLK: CPU1.AY22 RN1902.3(B)
HDA_CODEC_BITCLK: EC1901.2 EC2709.1 R2720.1 RN1902.2(A)
HDA_CODEC_SDIN0: HDA27.10 R2718.2
HDA_CODEC_SDOUT: EC2708.1 R2719.1 RN1902.1(A)
HDA_CODEC_SYNC: HDA27.9 R1908.1
HDA_RST#: CPU1.AW22 EC1902.1 R1911.2
HDA_RST#_R: R1911.1 TP1903.1
HDA_SDIN0: CPU1.BA21 R2718.1
HDA_SDOUT: CPU1.BB22 R1909.2 RN1902.4(B)
HDA_SPKR_R: D2701.2 RN2701.3(B)
HDA_SYNC: CPU1.BA22 R1908.2
HDD_CT: C6007.1 U6002.6
HDD_DEVSLP: CPU1.J1 R6002.1
HDD_DEVSLP_R: HDD1.13 R6002.2
HDD_EN: C6008.1 R6005.2 R6007.2 U6002.3
HDD_EN_PCH: CPU1.J4 R6007.1
HDD_FALL_INT: CPU1.M3 R7012.1
HDMI_CLK: C5709.1 CPU1.G56
HDMI_CLK#: C5714.1 CPU1.F56
HDMI_CLK#_R: C5714.2 U5701.10
HDMI_CLK#_R_C: HDMI1.12 R5705.1 U5701.21
HDMI_CLK_R: C5709.2 U5701.9
HDMI_CLK_R_C: HDMI1.10 R5705.2 U5701.22
HDMI_DATA0: C5711.1 CPU1.G53
HDMI_DATA0#: C5708.1 CPU1.F53
HDMI_DATA0#_R: C5708.2 U5701.1
HDMI_DATA0#_R_C: HDMI1.9 R5703.2 U5701.30
HDMI_DATA0_R: C5711.2 U5701.2
HDMI_DATA0_R_C: HDMI1.7 R5703.1 U5701.29
HDMI_DATA1: C5712.1 CPU1.F58
HDMI_DATA1#: C5715.1 CPU1.E58
HDMI_DATA1#_R: C5715.2 U5701.4
HDMI_DATA1#_R_C: HDMI1.6 R5704.2 U5701.27
HDMI_DATA1_R: C5712.2 U5701.5
HDMI_DATA1_R_C: HDMI1.4 R5704.1 U5701.26
HDMI_DATA2: C5707.1 CPU1.F55
HDMI_DATA2#: C5710.1 CPU1.E55
HDMI_DATA2#_R: C5710.2 U5701.6
HDMI_DATA2#_R_C: HDMI1.3 R5702.2 U5701.25
HDMI_DATA2_R: C5707.2 U5701.7
HDMI_DATA2_R_C: HDMI1.1 R5702.1 U5701.24
HDMI_EC_DET#: R2407.1 R5723.1
HDMI_EC_DET#_C: Q5704.D R5721.2 R5723.2
HOST_DEBUG_TX: DB3.5 KBC24.81 R2480.1
HPD_HDMI_CON: HDMI1.19 R5722.2 U5701.28
HPD_HDMI_CON_C: Q5704.G R5722.1
HUB_PA1: R6918.2 R6919.1 U6901.11
HUB_PA2: R6916.2 R6917.1 U6901.12
HUB_PA3: R6914.2 R6915.1 U6901.13
HUB_PA4: R6912.2 R6913.1 U6901.14
HUB_PA5: R6910.2 R6911.1 U6901.15
HUB_PA6: R6908.2 R6909.1 U6901.16
HW_ACAVIN_NB#: KBC24.21 R2474.2 R2475.2
I2C0_SCL: CPU1.N3 R2020.1 RN2007.1(A)
I2C0_SCL_R: AFTP6534.1 KBBD1.37 Q6504.6 R6505.2 RN6503.3(B)
I2C0_SCL_TCH_PAD: CPU1.U6 EC6503.1 Q6504.1 R6505.1
I2C0_SDA: CPU1.M4 R2021.1 RN2007.2(A)
I2C0_SDA_R: AFTP6535.1 KBBD1.36 Q6504.3 R6506.2 RN6503.4(B)
I2C0_SDA_TCH_PAD: CPU1.U7 EC6504.1 Q6504.4 R6506.1
I2C1_SCL: CPU1.N2 RN2008.2(A)
I2C1_SDA: CPU1.N1 RN2008.1(A)
I2C_CLK_PD: R3845.2 RN1814.4(B) U3701.10
I2C_DATA_PD: R3844.2 RN1814.3(B) U3701.13
I_ADP: C2435.1 KBC24.110 R2421.2
I_BATT: C2441.1 KBC24.114 R2407.2 R2423.2
I_SYS: C2427.1 KBC24.113 R2403.2 R2422.2 R2497.2
IC_DELAY: PC4307.1 U4302.4
ICSP_CLOCK: DB3.2 KBC24.101
ICSP_CLR: DB3.6 KBC24.87 R2414.1
ICSP_DATA: DB3.3 KBC24.102
ILIM_HI: R3404.2 U3401.16
ILIM_LO: R3403.2 U3401.15
ILIM_SEL: R3405.2 U3401.4
INT2_SELECT: D7001.2 Q7001.5 R7008.1 R7013.1
INT#_TYPEC: KBC24.30 R3705.2
INT#_TYPEC_R: R3705.1 R3707.2 U3701.14
INT_TP#: AFTP6536.1 D401.K KBBD1.40 KBC24.33 R410.1 R6511.2
IR_CAMERA_DET#: CPU1.W4 R2046.2 R5540.2
IR_CAMERA_DET#_R: R5540.1 TCBD1.22
ISET: R5413.2 R5414.2 U5701.34
ISH_KB_DISABLE: CPU1.AY8 R2022.1
ITP_PMODE: CPU1.E8 TP638.1
JACK_PLUG: ED2903.1 HPMIC1.5 R2923.1
JACK_PLUG_DET: ED2904.1 HPMIC1.6 R2905.1
JGND: AFTP4301.1 AFTP4302.1 DCIN1.1 DCIN1.2 DCIN1.3 EC4301.2 EC4302.2 EL4303.1 EL4304.1
KB_BL_CTRL#: AFTP6530.1 KBBD1.31 Q6501.D
KB_CLOSE#_2: C7001.1 GMR1.1 Q2415.S R7001.1
KB_CLOSE#_2_R: KBC24.126 Q2415.D R2496.1
KB_DET#: CPU1.AD4 KBBD1.28 R2045.2
KB_DISABLE: R2022.2 R2403.1 R6920.1
KB_DISABLE_HUB: R6920.2 U6901.2
KB_LED_BL_DET_R: CPU1.W8 R6507.1 R6508.1
KB_LED_DET_C: C6504.1 KBBD1.32 R6507.2
KBC_BEEP_R: D2701.1 RN2701.4(B)
KBC_PWRBTN#: EC6601.1 IOBD1.45 R2432.1
KSI0: AFTP6512.1 KBBD1.20 KBC24.98 RN2403.8(B)
KSI1: AFTP6501.1 KBBD1.22 KBC24.99 RN2403.7(B)
KSI2: AFTP6508.1 KBBD1.24 KBC24.6 RN2403.6(B)
KSI3: AFTP6509.1 KBBD1.21 KBC24.7 RN2403.5(B)
KSI4: AFTP6505.1 KBBD1.25 KBC24.104 RN2404.8(B)
KSI5: AFTP6506.1 KBBD1.23 KBC24.105 RN2404.7(B)
KSI6: AFTP6503.1 KBBD1.26 KBC24.107 RN2404.6(B)
KSI7: AFTP6502.1 KBBD1.27 KBC24.108 RN2404.5(B)
KSO0: AFTP6507.1 KBBD1.11 KBC24.2 RN2412.8(B)
KSO1: AFTP6511.1 KBBD1.13 KBC24.14 RN2412.7(B)
KSO2: AFTP6513.1 KBBD1.12 KBC24.15 RN2412.6(B)
KSO3: AFTP6518.1 KBBD1.14 KBC24.16 RN2412.5(B)
KSO4: AFTP6514.1 KBBD1.18 KBC24.37 RN2409.8(B)
KSO5: AFTP6510.1 KBBD1.19 KBC24.38 RN2409.7(B)
KSO6: AFTP6517.1 KBBD1.16 KBC24.39 RN2409.6(B)
KSO7: AFTP6515.1 KBBD1.17 KBC24.50 RN2409.5(B)
KSO8: AFTP6516.1 KBBD1.15 KBC24.46 RN2410.8(B)
KSO9: AFTP6504.1 KBBD1.5 KBC24.68 R2449.2 R2450.1
KSO10: AFTP6523.1 KBBD1.3 KBC24.72 RN2410.7(B)
KSO11: AFTP6522.1 KBBD1.4 KBC24.74 RN2410.6(B)
KSO12: AFTP6519.1 KBBD1.10 KBC24.75 RN2410.5(B)
KSO13: AFTP6520.1 KBBD1.7 KBC24.76 RN2411.8(B)
KSO14: AFTP6521.1 KBBD1.6 KBC24.77 RN2411.7(B)
KSO15: AFTP6524.1 KBBD1.8 KBC24.86 RN2411.6(B)
KSO16: AFTP6539.1 KBBD1.9 KBC24.92 RN2411.5(B)
L_BKLT_CTRL: CPU1.R11 D5502.1 R5502.2
L_BKLT_EN: CPU1.R12 R2435.2
L_BKLT_EN_EC: KBC24.34 R2435.1 R2436.1
LCD_BRIGHTNESS: EC5501.1 LCD1.30 RN5501.4(A)
LCD_TST: D5502.2 R2419.2 RN5501.8(B)
LCD_TST_C: LCD1.29 RN5501.1(A)
LCD_TST_EN: D5501.2 KBC24.26 R2419.1
LCDVDD: C5505.1 C5507.1 C5508.2 LCD1.6 LCD1.7 LCD1.8 LCD1.9 U5501.3
LDO1_CAP: C2702.2 HDA27.39 R2711.2
LDO2_CAP: C2712.2 HDA27.17
LDO3_CAP: C2718.1 HDA27.13
LID_CL_SIO#: D2402.K GMR1.4 KBC24.41 R7011.1 RN2405.3(A)
LINE1-L_C: C2907.2 R2922.1
LINE1-L_R: C2908.2 R2921.1
LINE1_L: C2907.1 HDA27.34
LINE1_R: C2908.1 HDA27.33
LINE1_VREFO_L: HDA27.14 R2912.1
LINE1_VREFO_R: HDA27.15 R2913.1
LPC_FRAME#_DEBUG: DB1.6 R6801.2
LPC_LAD0: KBC24.59 RN1806.8(B) RN6801.1(A)
LPC_LAD0_C: DB1.2 RN6801.8(B)
LPC_LAD0_R: CPU1.AY13 RN1806.1(A)
LPC_LAD1: KBC24.60 RN1806.7(B) RN6801.2(A)
LPC_LAD1_C: DB1.3 RN6801.7(B)
LPC_LAD1_R: CPU1.BA13 RN1806.2(A)
LPC_LAD2: KBC24.61 RN1806.6(B) RN6801.3(A)
LPC_LAD2_C: DB1.4 RN6801.6(B)
LPC_LAD2_R: CPU1.BB13 RN1806.3(A)
LPC_LAD3: KBC24.62 RN1806.5(B) RN6801.4(A)
LPC_LAD3_C: DB1.5 RN6801.5(B)
LPC_LAD3_R: CPU1.AY12 RN1806.4(A)
LPC_LFRAME#: KBC24.58 R1801.1 R6801.1
LPC_LFRAME#_R: CPU1.BA12 R1801.2
LPSS_UART2_RXD: CPU1.AD1 R2048.2
LPSS_UART2_TXD: CPU1.AD2 R2049.2
LVDS_VDD_EN_R: D5501.3 RN5502.8(B) U5501.1
M_A_A0: CPU1.AY50 DM1.144
M_A_A1: CPU1.BB50 DM1.133
M_A_A2: CPU1.AY51 DM1.132
M_A_A3: CPU1.BA50 DM1.131
M_A_A4: CPU1.BB52 DM1.128
M_A_A5: CPU1.BA51 DM1.126
M_A_A6: CPU1.BA52 DM1.127
M_A_A7: CPU1.AW52 DM1.122
M_A_A8: CPU1.AY52 DM1.125
M_A_A9: CPU1.BB54 DM1.121
M_A_A10: CPU1.AT50 DM1.146
M_A_A11: CPU1.BA54 DM1.120
M_A_A12: CPU1.AW54 DM1.119
M_A_A13: CPU1.AU46 DM1.158
M_A_A14: CPU1.AT46 DM1.151
M_A_A15: CPU1.AU48 DM1.156
M_A_A16: CPU1.AU50 DM1.152
M_A_ACT_N: CPU1.BA55 DM1.114
M_A_ALERT_N: CPU1.AW50 DM1.116
M_A_BA0: CPU1.AU52 DM1.150
M_A_BA1: CPU1.AT48 DM1.145
M_A_BG0: CPU1.AY55 DM1.115
M_A_BG1: CPU1.AY54 DM1.113
M_A_CKE0: CPU1.BA56 DM1.109
M_A_CKE1: CPU1.BB56 DM1.110
M_A_CLK0: CPU1.AT53 DM1.137
M_A_CLK1: CPU1.AT55 DM1.138
M_A_CLK#0: CPU1.AU53 DM1.139
M_A_CLK#1: CPU1.AU55 DM1.140
M_A_CS#0: CPU1.AU45 DM1.149
M_A_CS#1: CPU1.AU43 DM1.157
M_A_DIMA_ODT0: CPU1.AT45 DM1.155
M_A_DIMA_ODT1: CPU1.AT43 DM1.161
M_A_DQ0: CPU1.AL71 DM1.8
M_A_DQ1: CPU1.AL68 DM1.7
M_A_DQ2: CPU1.AN68 DM1.20
M_A_DQ3: CPU1.AN69 DM1.21
M_A_DQ4: CPU1.AL70 DM1.4
M_A_DQ5: CPU1.AL69 DM1.3
M_A_DQ6: CPU1.AN70 DM1.16
M_A_DQ7: CPU1.AN71 DM1.17
M_A_DQ8: CPU1.AR70 DM1.28
M_A_DQ9: CPU1.AR68 DM1.29
M_A_DQ10: CPU1.AU71 DM1.41
M_A_DQ11: CPU1.AU68 DM1.42
M_A_DQ12: CPU1.AR71 DM1.24
M_A_DQ13: CPU1.AR69 DM1.25
M_A_DQ14: CPU1.AU70 DM1.38
M_A_DQ15: CPU1.AU69 DM1.37
M_A_DQ16: CPU1.BB65 DM1.50
M_A_DQ17: CPU1.AW65 DM1.49
M_A_DQ18: CPU1.AW63 DM1.62
M_A_DQ19: CPU1.AY63 DM1.63
M_A_DQ20: CPU1.BA65 DM1.46
M_A_DQ21: CPU1.AY65 DM1.45
M_A_DQ22: CPU1.BA63 DM1.58
M_A_DQ23: CPU1.BB63 DM1.59
M_A_DQ24: CPU1.BA61 DM1.70
M_A_DQ25: CPU1.AW61 DM1.71
M_A_DQ26: CPU1.BB59 DM1.83
M_A_DQ27: CPU1.AW59 DM1.84
M_A_DQ28: CPU1.BB61 DM1.66
M_A_DQ29: CPU1.AY61 DM1.67
M_A_DQ30: CPU1.BA59 DM1.79
M_A_DQ31: CPU1.AY59 DM1.80
M_A_DQ32: CPU1.AY39 DM1.174
M_A_DQ33: CPU1.AW39 DM1.173
M_A_DQ34: CPU1.AY37 DM1.187
M_A_DQ35: CPU1.AW37 DM1.186
M_A_DQ36: CPU1.BB39 DM1.170
M_A_DQ37: CPU1.BA39 DM1.169
M_A_DQ38: CPU1.BA37 DM1.183
M_A_DQ39: CPU1.BB37 DM1.182
M_A_DQ40: CPU1.AY35 DM1.195
M_A_DQ41: CPU1.AW35 DM1.194
M_A_DQ42: CPU1.AY33 DM1.207
M_A_DQ43: CPU1.AW33 DM1.208
M_A_DQ44: CPU1.BB35 DM1.191
M_A_DQ45: CPU1.BA35 DM1.190
M_A_DQ46: CPU1.BA33 DM1.203
M_A_DQ47: CPU1.BB33 DM1.204
M_A_DQ48: CPU1.AY31 DM1.216
M_A_DQ49: CPU1.AW31 DM1.215
M_A_DQ50: CPU1.AY29 DM1.228
M_A_DQ51: CPU1.AW29 DM1.229
M_A_DQ52: CPU1.BB31 DM1.211
M_A_DQ53: CPU1.BA31 DM1.212
M_A_DQ54: CPU1.BA29 DM1.224
M_A_DQ55: CPU1.BB29 DM1.225
M_A_DQ56: CPU1.AY27 DM1.237
M_A_DQ57: CPU1.AW27 DM1.236
M_A_DQ58: CPU1.AY25 DM1.249
M_A_DQ59: CPU1.AW25 DM1.250
M_A_DQ60: CPU1.BB27 DM1.232
M_A_DQ61: CPU1.BA27 DM1.233
M_A_DQ62: CPU1.BA25 DM1.245
M_A_DQ63: CPU1.BB25 DM1.246
M_A_DQS_DN0: CPU1.AM70 DM1.11
M_A_DQS_DN1: CPU1.AT69 DM1.32
M_A_DQS_DN2: CPU1.BA64 DM1.53
M_A_DQS_DN3: CPU1.AY60 DM1.74
M_A_DQS_DN4: CPU1.BA38 DM1.177
M_A_DQS_DN5: CPU1.AY34 DM1.198
M_A_DQS_DN6: CPU1.BA30 DM1.219
M_A_DQS_DN7: CPU1.AY26 DM1.240
M_A_DQS_DP0: CPU1.AM69 DM1.13
M_A_DQS_DP1: CPU1.AT70 DM1.34
M_A_DQS_DP2: CPU1.AY64 DM1.55
M_A_DQS_DP3: CPU1.BA60 DM1.76
M_A_DQS_DP4: CPU1.AY38 DM1.179
M_A_DQS_DP5: CPU1.BA34 DM1.200
M_A_DQS_DP6: CPU1.AY30 DM1.221
M_A_DQS_DP7: CPU1.BA26 DM1.242
M_A_PARITY: CPU1.AT52 DM1.143
M_B_A0: CPU1.BA46 DM2.144
M_B_A1: CPU1.AY46 DM2.133
M_B_A2: CPU1.AY47 DM2.132
M_B_A3: CPU1.BB46 DM2.131
M_B_A4: CPU1.BA47 DM2.128
M_B_A5: CPU1.AY48 DM2.126
M_B_A6: CPU1.BA48 DM2.127
M_B_A7: CPU1.AP48 DM2.122
M_B_A8: CPU1.BB48 DM2.125
M_B_A9: CPU1.AP50 DM2.121
M_B_A10: CPU1.AW46 DM2.146
M_B_A11: CPU1.AN48 DM2.120
M_B_A12: CPU1.AN50 DM2.119
M_B_A13: CPU1.BA43 DM2.158
M_B_A14: CPU1.AY44 DM2.151
M_B_A15: CPU1.AY43 DM2.156
M_B_A16: CPU1.AW44 DM2.152
M_B_ACT_N: CPU1.AN53 DM2.114
M_B_ALERT_N: CPU1.AN43 DM2.116
M_B_BA0: CPU1.BB44 DM2.150
M_B_BA1: CPU1.BA44 DM2.145
M_B_BG0: CPU1.AP52 DM2.115
M_B_BG1: CPU1.AN52 DM2.113
M_B_CKE0: CPU1.AN56 DM2.109
M_B_CKE1: CPU1.AP55 DM2.110
M_B_CLK0: CPU1.AP45 DM2.137
M_B_CLK1: CPU1.AP46 DM2.138
M_B_CLK#0: CPU1.AN45 DM2.139
M_B_CLK#1: CPU1.AN46 DM2.140
M_B_CS#0: CPU1.BB42 DM2.149
M_B_CS#1: CPU1.AY42 DM2.157
M_B_DIMB_ODT0: CPU1.BA42 DM2.155
M_B_DIMB_ODT1: CPU1.AW42 DM2.161
M_B_DQ0: CPU1.AF65 DM2.28
M_B_DQ1: CPU1.AF64 DM2.29
M_B_DQ2: CPU1.AK65 DM2.41
M_B_DQ3: CPU1.AK64 DM2.42
M_B_DQ4: CPU1.AF66 DM2.24
M_B_DQ5: CPU1.AF67 DM2.25
M_B_DQ6: CPU1.AK67 DM2.38
M_B_DQ7: CPU1.AK66 DM2.37
M_B_DQ8: CPU1.AF70 DM2.8
M_B_DQ9: CPU1.AF68 DM2.7
M_B_DQ10: CPU1.AH71 DM2.20
M_B_DQ11: CPU1.AH68 DM2.21
M_B_DQ12: CPU1.AF71 DM2.4
M_B_DQ13: CPU1.AF69 DM2.3
M_B_DQ14: CPU1.AH70 DM2.16
M_B_DQ15: CPU1.AH69 DM2.17
M_B_DQ16: CPU1.AT66 DM2.50
M_B_DQ17: CPU1.AU66 DM2.49
M_B_DQ18: CPU1.AP65 DM2.62
M_B_DQ19: CPU1.AN65 DM2.63
M_B_DQ20: CPU1.AN66 DM2.46
M_B_DQ21: CPU1.AP66 DM2.45
M_B_DQ22: CPU1.AT65 DM2.58
M_B_DQ23: CPU1.AU65 DM2.59
M_B_DQ24: CPU1.AT61 DM2.70
M_B_DQ25: CPU1.AU61 DM2.71
M_B_DQ26: CPU1.AP60 DM2.83
M_B_DQ27: CPU1.AN60 DM2.84
M_B_DQ28: CPU1.AN61 DM2.66
M_B_DQ29: CPU1.AP61 DM2.67
M_B_DQ30: CPU1.AT60 DM2.79
M_B_DQ31: CPU1.AU60 DM2.80
M_B_DQ32: CPU1.AU40 DM2.174
M_B_DQ33: CPU1.AT40 DM2.173
M_B_DQ34: CPU1.AT37 DM2.187
M_B_DQ35: CPU1.AU37 DM2.186
M_B_DQ36: CPU1.AR40 DM2.170
M_B_DQ37: CPU1.AP40 DM2.169
M_B_DQ38: CPU1.AP37 DM2.183
M_B_DQ39: CPU1.AR37 DM2.182
M_B_DQ40: CPU1.AT33 DM2.195
M_B_DQ41: CPU1.AU33 DM2.194
M_B_DQ42: CPU1.AU30 DM2.207
M_B_DQ43: CPU1.AT30 DM2.208
M_B_DQ44: CPU1.AR33 DM2.191
M_B_DQ45: CPU1.AP33 DM2.190
M_B_DQ46: CPU1.AR30 DM2.203
M_B_DQ47: CPU1.AP30 DM2.204
M_B_DQ48: CPU1.AU27 DM2.216
M_B_DQ49: CPU1.AT27 DM2.215
M_B_DQ50: CPU1.AT25 DM2.228
M_B_DQ51: CPU1.AU25 DM2.229
M_B_DQ52: CPU1.AP27 DM2.211
M_B_DQ53: CPU1.AN27 DM2.212
M_B_DQ54: CPU1.AN25 DM2.224
M_B_DQ55: CPU1.AP25 DM2.225
M_B_DQ56: CPU1.AT22 DM2.237
M_B_DQ57: CPU1.AU22 DM2.236
M_B_DQ58: CPU1.AU21 DM2.249
M_B_DQ59: CPU1.AT21 DM2.250
M_B_DQ60: CPU1.AN22 DM2.232
M_B_DQ61: CPU1.AP22 DM2.233
M_B_DQ62: CPU1.AP21 DM2.245
M_B_DQ63: CPU1.AN21 DM2.246
M_B_DQS_DN0: CPU1.AH66 DM2.32
M_B_DQS_DN1: CPU1.AG69 DM2.11
M_B_DQS_DN2: CPU1.AR66 DM2.53
M_B_DQS_DN3: CPU1.AR61 DM2.74
M_B_DQS_DN4: CPU1.AT38 DM2.177
M_B_DQS_DN5: CPU1.AT32 DM2.198
M_B_DQS_DN6: CPU1.AR25 DM2.219
M_B_DQS_DN7: CPU1.AR22 DM2.240
M_B_DQS_DP0: CPU1.AH65 DM2.34
M_B_DQS_DP1: CPU1.AG70 DM2.13
M_B_DQS_DP2: CPU1.AR65 DM2.55
M_B_DQS_DP3: CPU1.AR60 DM2.76
M_B_DQS_DP4: CPU1.AR38 DM2.179
M_B_DQS_DP5: CPU1.AR32 DM2.200
M_B_DQS_DP6: CPU1.AR27 DM2.221
M_B_DQS_DP7: CPU1.AR21 DM2.242
M_B_PARITY: CPU1.AP43 DM2.143
M_VREF_CA_DIMMA: C1229.1 DM1.164 R1206.1 RN1201.3(B) RN1201.4(B)
M_VREF_CA_DIMMB: C1301.1 DM2.164 R1305.1 RN1301.3(B) RN1301.4(B)
MCU_BOOT0: R6907.1 U6901.44
MCU_OSCI: C6909.1 U6901.5 X6901.1
MCU_OSCO: C6908.1 U6901.6 X6901.3
MCU_RST#: C6902.1 R6902.1 U6901.7
ME_FWP_EC: KBC24.80 R1909.1
ME_SUS_PWR_ACK: RN1702.1(A) TP1712.1
ME_SUS_PWR_ACK_R: CPU1.AR13 R1708.1 R2039.2 RN1702.4(B)
MEM_SMBCLK: CPU1.R7 Q1801.3 RN1811.3(B)
MEM_SMBDATA: CPU1.R8 Q1801.6 RN1811.4(B)
MIC2_VREFO_L: HDA27.27 RN2901.2(A)
MIC2_VREFO_R: HDA27.28 RN2901.1(A)
MIC_CAP: C2713.1 HDA27.31
MIC_GND: R5501.1 TCBD1.19
MODEL_ID: C2407.2 KBC24.109 R2441.1 R2442.2
MSATA_DEVSLP: CPU1.J3 R6301.1 R6303.2 R6304.1
MSATA_DEVSLP_R: AFTP6301.1 R6301.2 SSD1.38
MSM#: CPU1.AP56 TP617.1
MUX_CDE: R3819.2 R3820.2 U3801.35
MUX_CEQ: R3817.2 R3818.2 U3801.38
MUX_CEXT: C3820.1 U3801.1
MUX_DPEQ: R3815.2 R3816.2 U3801.14
MUX_EN: R3810.1 R3842.1 U3801.29
MUX_EN_R: R3842.2 TP2901.1
MUX_HPD_PD: R3846.1 U3801.32
MUX_I2C_EN: R3811.1 U3801.17
MUX_REXT: R3803.1 U3801.2
MUX_SSDE: R3823.2 R3824.2 U3801.3
MUX_SSEQ: R3821.2 R3822.2 U3801.11
MUX_SW0_PD: R3814.1 R3845.1 U3801.21
MUX_SW1_PD: R3813.1 R3844.1 U3801.22
MUX_SW2_PD: R3812.1 R3843.1 U3801.23
MUX_SW2_PD_R: R3843.2 TP2902.1
MUX_TYPEC_RXN1: R3835.1 U3801.31
MUX_TYPEC_RXN2: R3837.1 U3801.39
MUX_TYPEC_RXP1: R3834.1 U3801.30
MUX_TYPEC_RXP2: R3836.1 U3801.40
MUX_TYPEC_TXN1: C3863.1 U3801.34
MUX_TYPEC_TXN1_C: C3863.2 R3833.1
MUX_TYPEC_TXN2: C3862.1 U3801.36
MUX_TYPEC_TXN2_C: C3862.2 R3839.1
MUX_TYPEC_TXP1: C3864.1 U3801.33
MUX_TYPEC_TXP1_C: C3864.2 R3832.1
MUX_TYPEC_TXP2: C3861.1 U3801.37
MUX_TYPEC_TXP2_C: C3861.2 R3838.1
NCT7718_DXN: C2606.2 C2607.2 Q2603.E THM261.3
NCT7718_DXP: C2606.1 C2607.1 Q2603.B Q2603.C THM261.2
OC_1: R3722.2 U3703.4
OC_2: R3723.2 U3704.4
OVER_CURRENT_P8#: GPU1.C2 R2474.1
P_SYS: PC4430.1 PG4415.2 PR4401.1 PR4671.1 R2422.1
PANEL_BKEN_EC: KBC24.117 RN5501.7(B)
PBAT_PRES1#: AFTP4309.1 BATT1.6 RN4302.8(B)
PBAT_PRES#: D4304.3 EC4306.2 KBC24.97 R2415.1 RN4302.1(A)
PBAT_SMBCLK1: AFTP4311.1 BATT1.4 RN4302.6(B)
PBAT_SMBDAT1: AFTP4310.1 BATT1.5 RN4302.7(B)
PCH_ALW_ON: KBC24.71 R2495.1 R4102.1
PCH_BATLOW#: CPU1.AU13 RN1704.6(B)
PCH_DPC_N0: C3813.1 CPU1.C50
PCH_DPC_N0_C: C3813.2 U3801.10
PCH_DPC_N1: C3807.1 CPU1.C52
PCH_DPC_N1_C: C3807.2 U3801.13
PCH_DPC_N2: C3808.1 CPU1.A50
PCH_DPC_N2_C: C3808.2 U3801.16
PCH_DPC_N3: C3810.1 CPU1.D51
PCH_DPC_N3_C: C3810.2 U3801.19
PCH_DPC_P0: C3812.1 CPU1.D50
PCH_DPC_P0_C: C3812.2 U3801.9
PCH_DPC_P1: C3814.1 CPU1.D52
PCH_DPC_P1_C: C3814.2 U3801.12
PCH_DPC_P2: C3809.1 CPU1.B50
PCH_DPC_P2_C: C3809.2 U3801.15
PCH_DPC_P3: C3811.1 CPU1.C51
PCH_DPC_P3_C: C3811.2 U3801.18
PCH_DPWROK: CPU1.BB20 EC1711.1 R1704.2 R1718.1 R2497.1
PCH_JTAG_TCK: CPU1.B56 R407.1
PCH_JTAG_TDI: CPU1.D59 R408.1
PCH_JTAG_TDO: CPU1.A56 R409.1
PCH_JTAG_TMS: CPU1.C59 R416.1
PCH_PLTRST#: CPU1.AN10 R1713.2
PCH_POPIRCOMP: CPU1.AU16 R413.1
PCH_RSMRST#: EC1712.1 KBC24.88 R1702.2
PCH_SMBCLK: DM1.253 DM2.253 Q1801.4 RN1810.3(B)
PCH_SMBDATA: DM1.254 DM2.254 Q1801.1 RN1810.4(B)
PCH_THERMTRIP#: CPU1.C63 EC401.1 R419.2
PCH_WAKE#: CPU1.BB15 RN1704.7(B)
PCI_CLK_LPC0: CPU1.AW9 R1804.1
PCI_CLK_LPC1: CPU1.AY9 R1805.1
PCIE_CLK_XDP_N: CPU1.F43 TP1802.1
PCIE_CLK_XDP_P: CPU1.E43 TP1803.1
PCIE_RCOMPN: CPU1.F5 R1604.1
PCIE_RCOMPP: CPU1.E5 R1604.2
PCIE_RX_CPU_N5: CPU1.F16 IOBD1.8
PCIE_RX_CPU_P5: CPU1.E16 IOBD1.7
PCIE_TX_CPU_N5: C1601.2 CPU1.C19
PCIE_TX_CPU_P5: C1602.2 CPU1.D19
PCIE_TX_WLAN_N5: C1601.1 IOBD1.10
PCIE_TX_WLAN_P5: C1602.1 IOBD1.11
PD4403_A: PD4404.A PQ4408.B
PD4403_K: PD4404.K PR4458.2
PD_CC1: R3709.1 R3718.2 U3701.2
PD_CC1_VCONN_CTRL: R3712.2 R3713.2 U3703.3
PD_CC1_VCONN_CTRL_R: R3712.1 U3701.24
PD_CC2: R3710.1 R3719.2 U3701.1
PD_CC2_VCONN_CTRL: R3711.2 R3714.2 U3704.3
PD_CC2_VCONN_CTRL_R: R3711.1 U3701.21
PD_RD1: R3718.1 R3719.1 U3701.3
PD_SWD_CLK: TP3702.1 U3701.12
PD_SWD_IO: TP3701.1 U3701.11
PD_VBUS_C_CTRL1: PQ4307.2 PR4323.1 U3701.18
PD_VBUS_C_CTRL1_A: PC4311.1 PQ4306.6 PQ4307.5 PQ4307.6 PQ4311.3 PR4319.2
PD_VBUS_DISCHG: PQ4310.2 PR4332.1 U3701.22
PD_VBUS_P_CTRL1: PR4310.1 U3701.15
PD_VBUS_P_CTRL1_R: PQ4309.5 PQ4309.6 PR4310.2 PR4324.1
PD_VBUS_R: C3705.2 R3703.2 R3704.2 U3701.17
PD_VCCD: C3704.1 U3701.7
PD_XRES: C3706.1 R3708.2 TP3703.1 U3701.16
PECI_EC: C2405.1 KBC24.94 R2437.1
PEG_CLK1_CPU: CPU1.A42 IOBD1.14
PEG_CLK1_CPU#: CPU1.B42 IOBD1.13
PEG_TX_CPU_N0: C1606.2 CPU1.B17
PEG_TX_CPU_N1: C1608.2 CPU1.D16
PEG_TX_CPU_N2: C1610.2 CPU1.D17
PEG_TX_CPU_N3: C1612.2 CPU1.B19
PEG_TX_CPU_P0: C1605.2 CPU1.A17
PEG_TX_CPU_P1: C1607.2 CPU1.C16
PEG_TX_CPU_P2: C1609.2 CPU1.C17
PEG_TX_CPU_P3: C1611.2 CPU1.A19
PG_1: PG4402.2 PR4444.2
PG_2: PG4403.2 PR4414.1
PIRQA#: CPU1.BB11 R1607.2
PLT_RST#: C1701.1 C2402.1 EC1703.1 EC6602.1 GPU1.D1 IOBD1.43 KBC24.56 R1713.1 R1715.1 R6802.1
PLT_RST#_DEBUG: DB1.7 R6802.2
PM_PCH_PWROK: CPU1.BA20 R1706.2 RN1703.3(B)
PM_RSMRST#: CPU1.AY17 Q1701.3 R1702.1 R1704.1 R1720.2 RN1703.4(B)
PM_RSMRST#_M: Q1702.5 Q1702.6 R1737.2
PM_RSMRST#_R: Q1702.2 R1720.1
PME#: CPU1.AU11 TP1707.1
POWER_SW_IN#: C2426.1 KBC24.127 R2432.2 R2451.1
PQ3802_1: PQ4302.B PR4302.1 PR4309.2
PQ3809_D: PQ4306.3 PR4314.2
PQ4405_2: PQ4405.2 PR4462.1 PR4463.1
PQ4405_3: PQ4405.3 PR4455.1
PQ4405_5: PC4438.1 PQ4405.5 PR4413.2
PQ4405_6: PC4438.2 PQ4405.6 PR4450.1
PQ4408_C: PQ4408.C PR4451.1 PR4462.2
PQ4408_E: PQ4408.E PR4431.2 PR4436.1
PR_2: PC4432.1 PR4416.2
PRE: R5415.2 R5416.2 U5701.16
PROC_SELECT#: CPU1.C64 R603.1
PS_ID: KBC24.36 PD4302.3 PR4304.2 PR4305.2
PS_ID_R: AFTP4304.1 DCIN1.4 PR4317.1
PS_ID_R1: PQ4301.S PR4305.1 PR4306.2
PS_ID_R2: PD4303.1 PD4303.2 PQ4301.D PR4306.1 PR4309.1 PR4317.2
PSID_DISABLE#_R_C: PQ4301.G PQ4302.C PR4303.2
PSYS: PR4615.1 PR4671.2 PU4601.46
PTP_DIS#: AFTP6537.1 KBBD1.41 KBC24.90
PURE_HW_SHUTDOWN#: C2610.1 D4001.3 Q2602.D R2615.1
PWR_0D6V_S3EN: PC5120.1 PR5125.2 PR5126.2 PU5102.7
PWR_0D6V_S5EN: PC5119.1 PR5114.2 PU5102.9
PWR_0D6V_VCNTL: PC5111.1 PR5118.1 PU5102.10
PWR_1D0V_BT: PC5204.1 PU5201.20
PWR_1D0V_EN: PC5215.1 PR5207.2 PR5210.2 PU5201.2
PWR_1D0V_FB: PC5212.2 PR5202.2 PR5204.1 PU5201.5
PWR_1D0V_FB_A: PC5212.1 PG5223.1 PR5202.1
PWR_1D0V_PFM: PR5203.1 PU5201.3
PWR_1D0V_PG: PR5208.2 PR5209.2 PU5201.1
PWR_1D0V_PH: PC5204.2 PL5201.1 PU5201.10 PU5201.11 PU5201.16 PU5201.17 PU5201.18
PWR_1D0V_SS: PC5213.1 PU5201.22
PWR_1D0V_TON: PR5201.2 PU5201.6
PWR_1D2V_BOOT: PR5101.1 PU5101.1
PWR_1D2V_BOOT_R: PC5117.1 PR5101.2
PWR_1D2V_BYP: PC5110.1 PR5102.1 PU5101.15
PWR_1D2V_EN: PC5138.1 PR5105.2 PU5101.11
PWR_1D2V_IMAX: PR5106.2 PU5101.13
PWR_1D2V_LDO_P5: PC5113.1 PU5101.16 PU5101.17
PWR_1D2V_PGOOD: PR5107.2 PU5101.9 PU5101.10
PWR_1D2V_PHASE: PC5117.2 PL5101.1 PU5101.6 PU5101.19 PU5101.20
PWR_1D2V_VFB: PC5112.2 PR5103.2 PR5104.1 PU5101.14
PWR_1D2V_VFB_R: PC5112.1 PG5113.2 PR5103.1
PWR_1D5V_EN: PC5407.1 PR5405.2 PU5402.3
PWR_1D8V_EN: PC5406.1 PR5401.1 PR5406.2 PR5407.2 PU5401.8
PWR_1D8V_POK: PR5402.2 PR5408.2 PU5401.7
PWR_2D5V: PC5411.1 PC5412.1 PC5413.1 PG5408.1 PG5409.1 PR5419.1 PU5403.3 PU5403.4
PWR_2D5V_EN: PC5427.1 PR5409.1 PR5417.2 PU5403.8
PWR_2D5V_FB: PC5411.2 PR5419.2 PR5420.1 PU5403.2
PWR_2D5V_PG: PR5105.1 PR5114.1 PR5410.2 PU5403.7
PWR_3D3V: PC4509.1 PC4510.1 PC4511.1 PC4512.1 PC4513.1 PC4525.1 PG4519.1 PG4520.1 PG4521.1 PG4522.1 PG4523.1 PG4524.1 PG4530.2 PL4501.2
PWR_3D3V_BOOT: PR4501.1 PU4501.1
PWR_3D3V_BOOT_A: PC4506.1 PR4501.2
PWR_3D3V_EN: PC4508.1 PR4508.1 PR4509.2 PU4501.11
PWR_3D3V_EN1: PC4532.1 PR4514.1 PR4516.2 PU4501.12
PWR_3D3V_FB: PC4533.1 PU4501.13
PWR_3D3V_FB2: PC4533.2 PR4506.2
PWR_3D3V_LDO: PC4507.1 PG4532.1 PU4501.16 PU4501.17
PWR_3D3V_PH: PC4506.2 PL4501.1 PU4501.6 PU4501.19 PU4501.20
PWR_3D3V_VOUT: PG4530.1 PR4506.1 PU4501.14
PWR_3V_PG: PG4531.2 PR4505.2 PU4501.9 PU4501.10
PWR_5V: PC4514.1 PC4515.1 PC4516.1 PC4517.1 PC4518.1 PC4527.1 PC4528.1 PC4529.1 PG4507.1 PG4508.1 PG4509.1 PG4510.1 PG4511.1 PG4512.1 PG4513.1 PG4514.1 PG4527.2 PL4502.1
PWR_5V_BOOT: PR4502.1 PU4502.1
PWR_5V_BOOT_A: PC4521.1 PR4502.2
PWR_5V_EN: PC4530.1 PR4511.2 PR4512.1 PU4502.11
PWR_5V_EN1: PC4531.1 PR4504.2 PR4513.1 PU4502.12
PWR_5V_EN1_R: PR4503.2 PR4504.1 PR4515.2 PR4530.1
PWR_5V_FB: PC4526.1 PR4551.1 PU4502.13
PWR_5V_FB_A: PC4526.2 PR4507.1
PWR_5V_LDO: PC4520.1 PG4528.1 PU4502.15
PWR_5V_PG: PG4529.2 PR4510.1 PU4502.9 PU4502.10
PWR_5V_PH: PC4521.2 PL4502.2 PU4502.6 PU4502.19 PU4502.20
PWR_5V_VCC: PC4524.1 PU4502.16 PU4502.17
PWR_5V_VOUT: PG4527.1 PR4507.2 PU4502.14
PWR_+VCCSA: PG5022.2 PG5025.2 PG5026.2 PG5027.2 PG5028.2 PG5029.2 PG5030.2 PG5031.2 PL5001.2
PWR_ASGATE: PC4436.2 PU4401.30
PWR_CHG_1: PD4401.K PD4402.K PD4405.K PR4407.2
PWR_CHG_ACDET: PC4413.1 PR4408.2 PR4409.1 PU4401.1
PWR_CHG_ACN: PC4402.2 PC4404.1 PR4414.2 PU4401.31
PWR_CHG_ACOK: PG4408.1 PR4422.2 PR4443.2 PR4463.2 PU4401.2
PWR_CHG_ACP: PC4402.1 PC4403.1 PR4444.1 PU4401.32
PWR_CHG_BATDRV: PC4437.2 PU4401.25
PWR_CHG_BATPRES#: PR4449.1 PU4401.13
PWR_CHG_BTST: PR4447.1 PU4401.24
PWR_CHG_BTST1: PC4414.1 PR4447.2
PWR_CHG_COMP: PC4427.1 PR4416.1 PU4401.10
PWR_CHG_FSET: PR4430.1 PU4401.12
PWR_CHG_HIDRV: PU4401.23 PU4404.4
PWR_CHG_IADP: PG4401.1 PU4401.6
PWR_CHG_IDCHG: PG4414.1 PU4401.7
PWR_CHG_ILIM: PR4420.2 PR4423.1 PU4401.11
PWR_CHG_LODRV: PU4401.21 PU4405.4
PWR_CHG_NTC: PR4437.1 PU4401.17
PWR_CHG_PHASE: PC4414.2 PL4401.1 PU4401.22 PU4404.1 PU4404.2 PU4404.3 PU4405.5 PU4405.6 PU4405.7 PU4405.8
PWR_CHG_PHASE_1: PG4412.1 PL4401.2 PR4415.1 PU4403.5 PU4403.6 PU4403.7 PU4403.8
PWR_CHG_PMON: PG4415.1 PU4401.8
PWR_CHG_PROCHOT#: PG4419.1 PU4401.5
PWR_CHG_PROG: PR4433.1 PU4401.9
PWR_CHG_REGN: PC4431.1 PR4412.2 PR4420.1 PR4421.1 PU4401.20
PWR_CHG_SCL: PG4410.2 PU4401.4
PWR_CHG_SDA: PG4409.2 PU4401.3
PWR_CHG_SRN: PC4420.2 PC4422.1 PR4448.1 PU4401.14
PWR_CHG_SRN_1: PG4413.2 PR4448.2
PWR_CHG_SRP: PC4420.1 PC4421.1 PR4411.2 PU4401.15
PWR_CHG_SRP_1: PG4412.2 PR4411.1
PWR_CHG_VCC: PC4412.1 PR4407.1 PU4401.18
PWR_CMSRC: PC4436.1 PR4410.1 PU4401.29
PWR_DCBATOUT_1D0V: PC5209.1 PC5210.1 PC5211.1 PC5214.1 PC5216.1 PG5210.2 PG5212.2 PG5214.2 PR5201.1 PU5201.7 PU5201.8 PU5201.9
PWR_DCBATOUT_1D2V: PC5106.1 PC5107.1 PC5108.1 PG5101.2 PG5103.2 PG5104.2 PG5107.2 PG5108.2 PG5110.2 PU5101.2 PU5101.3 PU5101.4 PU5101.5
PWR_DCBATOUT_3D3V: PC4501.1 PC4502.1 PC4503.1 PC4504.1 PG4515.2 PG4516.2 PG4517.2 PG4518.2 PU4501.2 PU4501.3 PU4501.4 PU4501.5
PWR_DCBATOUT_5V: PC4505.1 PC4519.1 PC4522.1 PC4523.1 PG4501.2 PG4502.2 PG4503.2 PG4504.2 PG4505.2 PG4506.2 PU4502.2 PU4502.3 PU4502.4 PU4502.5
PWR_OPCN: PC4426.2 PU4401.28
PWR_OPCP: PC4426.1 PU4401.27
PWR_VBAT: PC4437.1 PR4403.1 PU4401.26
PWR_VCCGT_BOOTA: PR4802.1 PU4801.35
PWR_VCCGT_BOOTA_RC: PC4809.1 PR4802.2
PWR_VCCGT_BOOTB: PR4805.1 PU4802.35
PWR_VCCGT_BOOTB_RC: PC4845.1 PR4805.2
PWR_VCCGT_COMP: PC4617.2 PC4618.2 PU4601.4
PWR_VCCGT_COMP_R: PC4618.1 PR4631.2
PWR_VCCGT_CSCOMP: PC4620.1 PC4621.1 PR4634.2 PR4639.2 PR4640.2 PU4601.6
PWR_VCCGT_CSNA: PG4809.1 PR4646.2
PWR_VCCGT_CSNB: PG4816.1 PR4643.2
PWR_VCCGT_CSP1: PC4624.2 PR4651.1 PU4601.10
PWR_VCCGT_CSP2: PC4622.2 PR4642.2 PR4654.1 PU4601.9
PWR_VCCGT_CSPA: PG4808.1 PR4637.1 PR4651.2
PWR_VCCGT_CSPB: PG4815.1 PR4641.1 PR4654.2
PWR_VCCGT_CSREF: PC4622.1 PC4624.1 PC4626.1 PR4643.1 PR4646.1 PU4601.8
PWR_VCCGT_CSSUM: PC4620.2 PC4621.2 PR4637.2 PR4638.2 PR4641.2 PU4601.7
PWR_VCCGT_DIFFOUT: PR4625.1 PR4626.1 PU4601.2
PWR_VCCGT_DISB#_A: PR4808.2 PU4801.2
PWR_VCCGT_DISB#_B: PR4809.2 PU4802.2
PWR_VCCGT_FB: PC4614.2 PC4617.1 PR4626.2 PR4631.1 PU4601.3
PWR_VCCGT_FB_R: PC4614.1 PR4625.2
PWR_VCCGT_GL1: PU4801.8 PU4801.9 PU4801.10 PU4801.11
PWR_VCCGT_GL2: PU4802.8 PU4802.9 PU4802.10 PU4802.11
PWR_VCCGT_ICCMAX: PR4672.2 PU4601.18
PWR_VCCGT_ILIM: PR4640.1 PU4601.5
PWR_VCCGT_ILIM_R: PR4634.1 PR4638.1 PR4639.1
PWR_VCCGT_IOUT: PC4615.2 PR4632.2 PU4601.1
PWR_VCCGT_NTC: PR4655.1 PR4656.2 PR4661.1
PWR_VCCGT_PHASEDA: PC4809.2 PU4801.32 PU4801.34
PWR_VCCGT_PHASEDB: PC4845.2 PU4802.32 PU4802.34
PWR_VCCGT_PWMA: PU4601.16 PU4801.4
PWR_VCCGT_PWMB: PU4601.17 PU4802.4
PWR_VCCGT_SNUB_1: PC4810.1 PR4804.2
PWR_VCCGT_SNUB_2: PC4814.1 PR4807.2
PWR_VCCGT_SWA: PG4808.2 PL4801.1 PR4804.1 PU4801.12 PU4801.13 PU4801.14 PU4801.15 PU4801.16 PU4801.17 PU4801.18
PWR_VCCGT_SWB: PG4815.2 PL4802.1 PR4807.1 PU4802.12 PU4802.13 PU4802.14 PU4802.15 PU4802.16 PU4802.17 PU4802.18
PWR_VCCGT_TSENSE: PC4630.1 PR4655.2 PU4601.11
PWR_VCCGT_VCCA: PC4808.1 PR4803.1 PU4801.6
PWR_VCCGT_VCCB: PC4847.1 PR4806.1 PU4802.6
PWR_VCCGT_VSN: PC4612.2 PR4619.1 PU4601.48
PWR_VCCGT_VSN_R: PC4611.2 PC4612.1 PR4618.2 PR4619.2
PWR_VCCGT_VSP: PC4611.1 PR4617.2 PU4601.47
PWR_VCCSA_BST: PR5013.1 PU5001.1
PWR_VCCSA_BST_RC: PC5008.1 PR5013.2
PWR_VCCSA_COMP: PC4602.2 PC4604.2 PU4601.43
PWR_VCCSA_COMP_R: PC4602.1 PR4602.2
PWR_VCCSA_CSN: PC4606.1 PC4607.1 PG5022.1 PR4606.2 PU4601.41
PWR_VCCSA_CSN_NTC: PR4606.1 PR4609.2
PWR_VCCSA_CSP: PG5021.1 PR4612.2
PWR_VCCSA_CSP1B: PC4606.2 PC4607.2 PR4609.1 PR4612.1 PU4601.40
PWR_VCCSA_DRVH: PU5001.8 PU5002.4
PWR_VCCSA_DRVL: PU5001.5 PU5003.4
PWR_VCCSA_ICCMAX: PR4660.2 PU4601.20
PWR_VCCSA_ILIM: PC4632.1 PR4611.1 PU4601.42
PWR_VCCSA_IOUT: PC4609.1 PR4613.2 PU4601.39
PWR_VCCSA_PWM: PU4601.36 PU5001.2
PWR_VCCSA_SNUB: PC5031.1 PR5014.2
PWR_VCCSA_SW: PC5008.2 PG5021.2 PL5001.1 PR5014.1 PU5001.7 PU5002.1 PU5002.2 PU5002.3 PU5003.5 PU5003.6 PU5003.7 PU5003.8
PWR_VCCSA_VSN: PC4603.2 PR4605.2 PU4601.44
PWR_VCCSA_VSN_R: PC4603.1 PC4605.2 PR4604.2 PR4605.1
PWR_VCCSA_VSP: PC4608.2 PR4608.2 PU4601.45
PWR_VCCSA_VSP_R: PC4605.1 PR4607.2 PR4608.1 PR4616.1
PWR_VCCSA_VSP_RC: PC4608.1 PR4616.2
PWR_VCORE_ADDR_BOOT: PR4663.2 PU4601.21
PWR_VCORE_ALERT#: PR4666.2 PU4601.33
PWR_VCORE_BOOT: PR4701.1 PU4701.35
PWR_VCORE_BOOT_RC: PC4706.1 PR4701.2
PWR_VCORE_COMP: PC4601.1 PC4619.1 PU4601.26
PWR_VCORE_COMP_R: PC4601.2 PR4636.1
PWR_VCORE_CSN: PC4616.2 PC4634.2 PG4708.1 PR4633.1 PU4601.28
PWR_VCORE_CSNNTC: PR4629.2 PR4633.2
PWR_VCORE_CSP: PG4707.1 PR4627.2
PWR_VCORE_CSP_1A: PC4616.1 PC4634.1 PR4627.1 PR4629.1 PU4601.29
PWR_VCORE_DISB#: PR4704.2 PU4701.2
PWR_VCORE_DRVON: PR4704.1 PR4808.1 PR4809.1 PU4601.35 PU5001.3
PWR_VCORE_EN: PR4630.1 PU4601.37
PWR_VCORE_GL: PU4701.8 PU4701.9 PU4701.10 PU4701.11
PWR_VCORE_ICCMAX: PR4658.2 PU4601.19
PWR_VCORE_ILIM: PC4633.1 PR4635.1 PU4601.27
PWR_VCORE_IOUT: PC4613.1 PR4628.1 PU4601.30
PWR_VCORE_NTC: PR4650.1 PR4652.1 PR4653.2
PWR_VCORE_PHASED: PC4706.2 PU4701.32 PU4701.34
PWR_VCORE_PWM: PU4601.22 PU4701.4
PWR_VCORE_ROSC_COREGT: PR4664.1 PU4601.14
PWR_VCORE_ROSC_SAUS: PR4659.1 PU4601.15
PWR_VCORE_SCLK: PR4665.2 PU4601.34
PWR_VCORE_SDIO: PR4667.2 PU4601.32
PWR_VCORE_SNUB: PC4709.1 PR4703.2
PWR_VCORE_SW: PG4707.2 PL4701.1 PR4703.1 PU4701.12 PU4701.13 PU4701.14 PU4701.15 PU4701.16 PU4701.17 PU4701.18
PWR_VCORE_TSENSE: PC4628.1 PR4650.2 PU4601.23
PWR_VCORE_VCC: PC4708.1 PR4702.1 PU4701.6
PWR_VCORE_VCC_R: PC4631.1 PR4657.2 PU4601.13
PWR_VCORE_VR_RDY: PR4670.1 PU4601.38
PWR_VCORE_VRHOT#: PR4668.1 PU4601.31
PWR_VCORE_VRMP: PC4629.1 PR4601.2 PU4601.12
PWR_VCORE_VSN: PC4623.2 PR4644.1 PU4601.25
PWR_VCORE_VSN_R: PC4623.1 PC4625.1 PR4644.2 PR4645.2
PWR_VCORE_VSP: PR4647.1 PR4649.1 PU4601.24
PWR_VCORE_VSP_R: PC4625.2 PC4627.2 PR4647.2 PR4648.2
PWR_VCORE_VSP_RC: PC4627.1 PR4649.2
Q6204_G: Q6504.2 Q6504.5 R6510.2
Q6205_Q: Q6503.D R6503.2
Q6502_D: Q6502.D R6514.1
RESET_OUT#: EC1704.1 KBC24.73 Q2602.G R1706.1
REXT: R5710.1 U5701.18
RING2: EC2905.1 HDA27.29 R2906.2 RN2901.3(B)
RING2_R: ED2901.1 HPMIC1.4 R2906.1
RSMRST_PWRGD#: D4002.3 R4029.2 R4030.2 R4031.2 R4032.2 R4033.2
RSVD_F65: CPU1.F65 TP612.1
RSVD_G65: CPU1.G65 TP613.1
RSVD_TP_AK12: CPU1.AK12 TP606.1
RSVD_TP_AK13: CPU1.AK13 TP605.1
RSVD_TP_AW70: CPU1.AW70 TP615.1
RSVD_TP_AW71: CPU1.AW71 TP614.1
RSVD_TP_BA68: CPU1.BA68 TP602.1
RSVD_TP_BA70: CPU1.BA70 TP601.1
RSVD_TP_BB68: CPU1.BB68 TP603.1
RSVD_TP_BB69: CPU1.BB69 TP604.1
RTC_AUX_S5: C2503.1 D2501.3 R1730.1 R2106.1 R2472.2 RN1801.1(A) RN1801.2(A)
RTC_DET#: CPU1.P1 Q2505.D R2040.2
RTC_RST#: C1806.1 CPU1.AM16 EC1807.1 G1801.2 Q1802.D RN1801.3(B)
RTC_X1: C1804.2 CPU1.AM18 R1815.1 X1802.1
RTC_X2: C1803.2 CPU1.AM20 R1815.2 X1802.4
RTCRST_ON: EC1808.1 KBC24.31 Q1802.G R1816.1
SA0_CHA_DIM0: DM1.256 R1204.1 R1205.1
SA0_CHB_DIM0: DM2.256 R1302.1 R1303.1
SA1_CHA_DIM0: DM1.260 R1208.1 R1210.1
SA1_CHB_DIM0: DM2.260 R1306.1 R1307.1
SA2_CHA_DIM0: DM1.166 R1211.1 R1212.1
SA2_CHB_DIM0: DM2.166 R1310.1 R1311.1
SATA_ACT#: CPU1.H1 Q6105.S R1606.2
SATA_LED#: KBC24.69 Q6105.G R4302.2 R6120.2
SATA_RX_CPU_N0: C6006.1 CPU1.F20
SATA_RX_CPU_N1: C6309.2 CPU1.G21
SATA_RX_CPU_N1_C: C6309.1 ED6301.4 ED6301.7 SSD1.43
SATA_RX_CPU_P0: C6005.1 CPU1.E20
SATA_RX_CPU_P1: C6301.2 CPU1.F21
SATA_RX_CPU_P1_C: C6301.1 ED6301.5 ED6301.6 SSD1.41
SATA_RXN0_R: C6006.2 HDD1.18 U6001.4 U6001.7
SATA_RXP0_R: C6005.2 HDD1.19 U6001.5 U6001.6
SATA_TX_CPU_N0: C6003.1 CPU1.B21
SATA_TX_CPU_N1: C6303.2 CPU1.D21
SATA_TX_CPU_N1_C: C6303.1 ED6301.2 ED6301.9 SSD1.47
SATA_TX_CPU_P0: C6001.1 CPU1.A21
SATA_TX_CPU_P1: C6302.2 CPU1.C21
SATA_TX_CPU_P1_C: C6302.1 ED6301.1 ED6301.10 SSD1.49
SATA_TXN0_R: C6003.2 HDD1.16 U6001.2 U6001.9
SATA_TXP0_R: C6001.2 HDD1.15 U6001.1 U6001.10
SD_RCOMP: CPU1.AB7 R1901.1
SENSOR_I2C_SCL: R2020.2 R6928.2 RN6901.4(B) RN7001.2(A) TCBD1.8
SENSOR_I2C_SCL_2G: RN7001.3(B) U7001.1
SENSOR_I2C_SCL_HUB: R6928.1 U6901.42
SENSOR_I2C_SDA: R2021.2 R6929.2 RN6901.3(B) RN7001.1(A) TCBD1.7
SENSOR_I2C_SDA_2G: RN7001.4(B) U7001.4
SENSOR_I2C_SDA_HUB: R6929.1 U6901.43
SERIRQ: CPU1.AY11 KBC24.55 R1821.2
SIO_EXT_SCI#: CPU1.J2 KBC24.66 R1608.2
SIO_EXT_SMI#: CPU1.L6 KBC24.10 R802.1
SIO_EXT_WAKE#: CPU1.AD3 KBC24.116 R2041.2
SIO_PWRBTN#: CPU1.BA15 KBC24.52
SIO_RCIN#: CPU1.AW13 KBC24.53 R1820.2
SIO_SLP_A#: CPU1.AN16 TP1706.1
SIO_SLP_S0#: CPU1.AT11 KBC24.42 R6005.1
SIO_SLP_S3#: CPU1.AP15 KBC24.70 PR5126.1 PR5405.1 Q2701.G Q4008.G R1733.1 R4010.1 R4017.1 R4018.1 U1703.2
SIO_SLP_S4#: CPU1.BA16 KBC24.67 PR5417.1 R4023.1 U4005.2
SIO_SLP_S5#: CPU1.AY16 TP1703.1
SIO_SLP_SUS#: CPU1.AN15 PR5207.1 PR5407.1 R1729.2
SKTOCC#: CPU1.A65 TP402.1
SLEEVE: EC2906.1 HDA27.30 R2911.2 RN2901.4(B)
SLEEVE_R: ED2906.1 HPMIC1.3 R2911.1
SLP_LAN#: CPU1.AW15 TP1704.1
SM_DRAMRST#: CPU1.AT13 D502.2 R504.1 R505.2
SM_INTRUDER#: CPU1.AP16 R1730.2
SM_PGCNTL: CPU1.AW67 Q501.S
SM_PGCNTL_R: PR5125.1 Q501.D R506.2
SM_RCOMP_0: CPU1.AR18 R501.1
SM_RCOMP_1: CPU1.AT18 R502.1
SM_RCOMP_2: CPU1.AU18 R503.1
SMBCLK1: D4306.3 EC4309.1 KBC24.9 PG4410.1 PR4439.2 RN2402.3(B) RN4302.3(A)
SMBCLK2: KBC24.12 Q2604.3 R2459.1 RN2603.4(B)
SMBCLK3: KBC24.91 Q2605.1 RN2604.4(B)
SMBDA1: D4305.3 EC4310.1 KBC24.8 PG4409.1 PR4438.2 RN2402.4(B) RN4302.2(A)
SMBDA2: KBC24.11 Q2604.6 R2447.1 RN2603.3(B)
SMBDA3: KBC24.89 Q2605.4 RN2604.3(B)
SML0_SMBCLK: CPU1.R9 RN1807.5(B)
SML0_SMBDATA: CPU1.W2 RN1807.6(B)
SML1_SMBCLK: CPU1.W3 GPU1.E8 Q2601.3 Q2604.4 R2459.2 RN1807.7(B)
SML1_SMBDATA: CPU1.V3 GPU1.E9 Q2601.6 Q2604.1 R2447.2 RN1807.8(B)
SPI_CLK_CPU: CPU1.AV2 RN1803.8(B)
SPI_CLK_ROM: RN1803.1(A) RN2406.1(A) RN2502.4(B)
SPI_CLK_ROM_R: EC2503.1 RN2502.1(A) SKT251.6 SPI25.6
SPI_CS_CPU_N0: CPU1.AU3 R1812.2
SPI_CS_ROM_N0: KBC24.27 R1812.1 R2501.1 SKT251.1 SPI25.1
SPI_HOLD_CPU: CPU1.AU4 R1811.2
SPI_HOLD_ROM: R1811.1 R2503.2 RN1802.4(B)
SPI_HOLD_ROM_R: R2503.1 SKT251.7 SPI25.7
SPI_SI_CPU: CPU1.AV3 R1824.2 R1825.1 RN1803.6(B)
SPI_SI_ROM: R2405.1 RN1803.3(A) RN2502.3(B)
SPI_SI_ROM_R: EC2501.1 RN2502.2(A) SKT251.5 SPI25.5
SPI_SO_CPU: CPU1.AW3 RN1803.7(B)
SPI_SO_ROM: RN1803.2(A) RN2406.2(A) RN2503.2(A)
SPI_SO_ROM_R: EC2502.1 RN2503.3(B) SKT251.2 SPI25.2
SPI_WP_CPU: CPU1.AW2 RN1803.5(B)
SPI_WP_ROM: RN1802.3(B) RN1803.4(A) RN2503.1(A)
SPI_WP_ROM_R: RN2503.4(B) SKT251.3 SPI25.3
SPK_DET#: CPU1.AB1 R2047.2 SPK1.5
SPKR: CPU1.AW5 R2006.2 RN2701.2(A)
SRTC_RST#: C1805.1 CPU1.AN18 EC1806.1 RN1801.4(B)
SSD_PEDET: AFTP6303.1 R6305.1 SSD1.69
SUS_STAT#/LPCPD#: CPU1.BA11 R1814.2
SUSACK#: RN1702.2(A) TP1711.1
SUSACK#_R: CPU1.AP11 R1708.2 RN1702.3(B)
SUSCLK: R1813.2 TP1807.1
SUSCLK_R: CPU1.BA17 EC1803.2 R1813.1
SWCLK: TP6904.1 U6901.37
SWDIO: TP6903.1 U6901.34
SYS_PRES1#: AFTP4315.1 BATT1.7 R4301.2
SYS_PWROK: CPU1.B6 EC1702.1 KBC24.96 R1717.1
T_CRIT#: R2601.1 R2604.2 THM261.4
THERM_SYS_SHDN#: Q2602.S R2601.2 R2602.1
THM_SML1_CLK: C2608.1 Q2601.4 RN2602.4(B) THM261.8
THM_SML1_DATA: C2609.1 Q2601.1 RN2602.3(B) THM261.7
TOUCH_PANEL_INTR#: CPU1.A7 D2402.A R2429.1 TCBD1.32
TOUCHPAD_INTR#: CPU1.BA5 D401.A R404.2 R405.2 R410.2
TP1_AY4: CPU1.AY4 TP610.1
TP2_BB3: CPU1.BB3 TP611.1
TP4_BB5: CPU1.BB5 TP609.1
TP5_AU5: CPU1.AU5 TP607.1
TP6_AT5: CPU1.AT5 TP608.1
TP_EN#: KBC24.49 R6504.1 RN2405.4(A)
TP_ON#_GATE: C6502.2 Q6502.G Q6503.G R6504.2
TP_VDD: AFTP6531.1 C6503.1 KBBD1.44 R6502.2 R6503.1 R6511.1 R6514.2 RN6501.1(A) RN6501.2(A) RN6503.1(A) RN6503.2(A)
TPAN_VDD: C5516.1 C5517.1 F5501.2 R5507.2 TCBD1.26 TCBD1.27
TPCLK_C: AFTP6532.1 KBBD1.43 RN6502.3(B)
TPDATA_C: AFTP6533.1 KBBD1.42 RN6502.4(B)
TPS70933_EN: C3708.1 R3715.2 R3716.1 U3702.4
TS#_DIMM0_1: DM1.134 R1215.2
TS#_DIMM1_1: DM2.134 R1312.2
TYPEC_5V: PQ4309.3 PR4339.2
TYPEC_5V_SW: PC4312.2 PR4330.2 PU4305.1 PU4305.2 PU4305.3 PU4306.1 PU4306.2 PU4306.3
TYPEC_5V_SW_R: PC4312.1 PR4330.1 PR4339.1 PU4305.4 PU4306.4
TYPEC_CON_RXN1: EU3801.5 EU3801.6 R3835.2 USB1.B10
TYPEC_CON_RXN2: EU3802.1 EU3802.9 R3837.2 USB1.A10
TYPEC_CON_RXP1: EU3801.4 EU3801.7 R3834.2 USB1.B11
TYPEC_CON_RXP2: EU3802.2 EU3802.8 R3836.2 USB1.A11
TYPEC_CON_TXN1: EU3801.2 EU3801.8 R3833.2 USB1.A3
TYPEC_CON_TXN2: EU3802.4 EU3802.7 R3839.2 USB1.B3
TYPEC_CON_TXP1: EU3801.1 EU3801.9 R3832.2 USB1.A2
TYPEC_CON_TXP2: EU3802.5 EU3802.6 R3838.2 USB1.B2
U3703_OUT: D3704.A U3703.5 U3703.6
U3704_OUT: D3703.A U3704.5 U3704.6
U4006_CT: C4017.1 U4006.6
U4101_OUT: R4103.1 U4101.6 U4101.7 U4101.8
U4301_IN: PR4329.1 PR4331.2 U4301.5
UART0_CTS#: CPU1.U4 TP2014.1
UART0_RTS#: CPU1.U3 TP2013.1
UART0_TXD: CPU1.U2 TP2012.1
UART1_CTS#: CPU1.AB4 TP2017.1
UART1_RTS#: CPU1.AC3 TP2016.1
USB2_ID: CPU1.AG3 RN1602.1(A)
USB2_VBUSSENSE: CPU1.AG4 RN1602.2(A)
USB20_DN0_C: EU3602.1 TR3602.2 USB2.2
USB20_DN1_C: EU3604.1 TR3603.2 USB3.2
USB20_DP0_C: EU3602.6 TR3602.3 USB2.3
USB20_DP1_C: EU3604.6 TR3603.3 USB3.3
USB30_RX_CPU_N1: CPU1.H8 R3609.1
USB30_RX_CPU_N2: CPU1.J6 R3612.1
USB30_RX_CPU_N4: C3806.1 CPU1.E10
USB30_RX_CPU_N4_C: C3806.2 U3801.4
USB30_RX_CPU_P1: CPU1.G8 R3610.1
USB30_RX_CPU_P2: CPU1.H6 R3613.1
USB30_RX_CPU_P4: C3805.1 CPU1.F10
USB30_RX_CPU_P4_C: C3805.2 U3801.5
USB30_RXDN1_C: EU3601.1 EU3601.9 R3609.2 USB2.5
USB30_RXDN2_C: EU3603.1 EU3603.9 R3612.2 USB3.5
USB30_RXDP1_C: EU3601.2 EU3601.8 R3610.2 USB2.6
USB30_RXDP2_C: EU3603.2 EU3603.8 R3613.2 USB3.6
USB30_TX_CPU_N1: C3601.1 CPU1.C13
USB30_TX_CPU_N2: C3603.1 CPU1.B13
USB30_TX_CPU_N4: C3804.1 CPU1.C15
USB30_TX_CPU_N4_C: C3804.2 U3801.7
USB30_TX_CPU_P1: C3602.1 CPU1.D13
USB30_TX_CPU_P2: C3604.1 CPU1.A13
USB30_TX_CPU_P4: C3803.1 CPU1.D15
USB30_TX_CPU_P4_C: C3803.2 U3801.8
USB30_TXDN1_C: EU3601.4 EU3601.7 R3605.2 USB2.8
USB30_TXDN1_R: C3601.2 R3605.1
USB30_TXDN2_C: EU3603.4 EU3603.7 R3611.2 USB3.8
USB30_TXDN2_R: C3603.2 R3611.1
USB30_TXDP1_C: EU3601.5 EU3601.6 R3606.2 USB2.9
USB30_TXDP1_R: C3602.2 R3606.1
USB30_TXDP2_C: EU3603.5 EU3603.6 R3614.2 USB3.9
USB30_TXDP2_R: C3604.2 R3614.1
USB30_VCCA: C3401.1 C3403.1 C3404.1 C3405.1 EU3602.5 U3401.12 USB2.1
USB30_VCCB: C3507.1 C3508.1 C3512.1 C3513.1 C3514.1 EU3604.5 PU4306.5 PU4306.6 PU4306.7 PU4306.8 R3501.1 TC3501.1 U3501.1 U3502.1 USB3.1
USB_8+: R6904.1 R6906.2 U6901.33
USB_8-: R6905.2 U6901.32
USB_ADT: PD4405.A PD4407.A PD4409.A PR4327.2 PU4303.5 PU4303.6 PU4303.7 PU4303.8 PU4304.5 PU4304.6 PU4304.7 PU4304.8
USB_ADT_D: PD4406.K PD4407.K PR4408.1
USB_ADT_D1: PC4434.2 PD4409.K PD4411.K PR4442.1 PU4403.4
USB_ADT_R1: PD4306.A PQ4308.5 PQ4308.6 PR4327.1 PR4328.2
USB_ADT_SW: PR4320.2 PR4321.1 PU4304.4
USB_ADT_SW_R: PQ4308.3 PR4321.2
USB_CAMERA_N: TCBD1.15 TR5501.3
USB_CAMERA_P: TCBD1.14 TR5501.2
USB_CHG_EN: KBC24.23 U3401.5
USB_CPU_PN0: CPU1.AB9 U3401.2
USB_CPU_PN1: CPU1.AD6 TR3603.1
USB_CPU_PN2: CPU1.AH3 TR6601.2
USB_CPU_PN2_C: IOBD1.19 TR6601.1
USB_CPU_PN3: CPU1.AD9 TR3805.1
USB_CPU_PN4: CPU1.AJ1 TR5501.4
USB_CPU_PN5: CPU1.AF6 R6605.2
USB_CPU_PN5_C: IOBD1.16 R6605.1
USB_CPU_PN6: CPU1.AH1 R5510.2
USB_CPU_PN7: CPU1.AF8 TR6602.2
USB_CPU_PN7_C: IOBD1.22 TR6602.1
USB_CPU_PN8: CPU1.AG1 R6905.1
USB_CPU_PP0: CPU1.AB10 U3401.3
USB_CPU_PP1: CPU1.AD7 TR3603.4
USB_CPU_PP2: CPU1.AJ3 TR6601.3
USB_CPU_PP2_C: IOBD1.20 TR6601.4
USB_CPU_PP3: CPU1.AD10 TR3805.2
USB_CPU_PP4: CPU1.AJ2 TR5501.1
USB_CPU_PP5: CPU1.AF7 R6606.2
USB_CPU_PP5_C: IOBD1.17 R6606.1
USB_CPU_PP6: CPU1.AH2 R5511.2
USB_CPU_PP7: CPU1.AF9 TR6602.3
USB_CPU_PP7_C: IOBD1.23 TR6602.4
USB_CPU_PP8: CPU1.AG2 R6906.1
USB_EN#: IOBD1.49 KBC24.13 R2434.2 U3501.4 U3502.4
USB_OC0#: CPU1.A9 RN1601.6(B) U3401.13 U3501.3 U3502.3
USB_OC1#: CPU1.C9 IOBD1.48 RN1601.5(B)
USB_OC2#: CPU1.D9 RN1601.8(B)
USB_OC3#: CPU1.B9 RN1601.7(B)
USB_PN0_R: TR3602.1 U3401.11
USB_PN6_TPNL: R5510.1 TCBD1.31
USB_PP0_R: TR3602.4 U3401.10
USB_PP6_TPNL: R5511.1 TCBD1.30
USB_TYPEC_DIS: PQ4310.6 PR4338.2
USB_TYPEC_R: PC4310.1 PR4322.1 PR4336.1 PU4303.4
USB_TYPEC_SW: PQ4307.3 PR4322.2
USB_UART_SEL_D9: CPU1.P2 TP2006.1
USBC1_CC1_CONN: C3711.1 D3704.K ED3801.2 R3709.2 R3720.2 USB1.A5
USBC1_CC2_CONN: C3712.1 D3703.K ED3801.1 R3710.2 USB1.B5
USBC_CON_PN3: EU3804.1 TR3805.4 USB1.A7 USB1.B7
USBC_CON_PP3: EU3804.2 TR3805.3 USB1.A6 USB1.B6
USBC_DPAUX1: EU3803.1 EU3803.9 R3830.1 U3801.27 USB1.A8
USBC_DPAUX2: EU3803.2 EU3803.8 R3831.1 U3801.26 USB1.B8
USBCHARGER_CB0: KBC24.118 R2473.1 R3401.1
USBCOMP: CPU1.AB6 R1603.1
USBDISABLE: R6904.2 U6901.31
V_EDRAM_EOPIO_R: C4010.1 C4011.1 R4021.1 R4022.2 U4004.6 U4004.7 U4004.8
V_SM_VREF_CNTA: C1222.1 CPU1.AY67 R1206.2
V_SM_VREF_CNTB: C1323.1 CPU1.BA67 R1305.2
VCONN1: R3720.1 U3701.5
VCONN2: R3721.1 U3701.4
VCREF0: C2409.1 KBC24.25 R2424.1 R2448.1
VD_IN1_C: C2612.2 C2613.2 R2610.2 R2611.1
VOL_DOWN#: IOBD1.42 KBC24.4 RN2407.3(B)
VOL_UP#: IOBD1.41 KBC24.3 RN2407.4(B)
VR_CAP: C2418.1 KBC24.18
VR_EN: PR4630.2 R4002.2
VR_RDY: AFTP4601.1 PR4614.2 PR4670.2
VR_SVID_ALERT#: PR4622.2 PR4666.1 R727.2 R728.1
VR_SVID_CLK: PR4621.2 PR4665.1 R723.2 R732.2
VR_SVID_DATA: PR4623.2 PR4667.1 R709.2
VRAM_ID1: CPU1.AP8 R2029.2 R2030.1
VREG3PD: C3709.1 C3710.1 D3702.A U3702.1
WHITE_LED_BAT: EC6402.1 Q6401.C R6402.2
WIFI_RF_EN: CPU1.B7 EC6603.1 IOBD1.46 R1503.2
XCLK_BIASREF: CPU1.E42 R1803.1
XDP_BPM0: CPU1.C55 TP405.1
XDP_BPM1: CPU1.D55 TP406.1
XDP_BPM2: CPU1.B54 TP407.1
XDP_BPM3: CPU1.C56 TP408.1
XDP_DBRESET#: CPU1.B5 EC1706.1 R1701.2 TP1709.1
XDP_PRDY#: CPU1.D56 TP1605.1
XDP_PREQ#: CPU1.D61 TP1606.1
XDP_TCK_JTAGX: CPU1.A59 R417.1
XDP_TCLK: CPU1.B61 R406.1
XDP_TDI: CPU1.D60 R422.1
XDP_TDO_CPU: CPU1.A61 R423.1
XDP_TMS: CPU1.C60 R421.1
XDP_TRST#: CPU1.B59 CPU1.C61 R402.1
XTAL1: C2425.2 KBC24.123 X2401.1
XTAL2: C2424.2 KBC24.125 X2401.2
XTAL24_IN: C1801.2 CPU1.E37 R1802.1 X1801.1
XTAL24_OUT: CPU1.E35 R1802.2 R1810.1
XTAL24_OUT_R: C1802.2 R1810.2 X1801.3
ZVM#: CPU1.AR56 D4004.K Q4001.S

Pads without a net: CPU1 A3 A4 A11 A15 A23 A25 A26 A27 A29 A31 A33 A36 A38 A40 A52 A69 AB11 AB12 AB13 AD11 AD12 AF11 AF12 AF13 AH7 AH8 AH9 AH10 AH11 AH12 AK6 AK7 AK9 AK10 AK62 AL25 AL27 AL61 AM1 AM2 AM3 AM4 AM22 AM23 AN1 AN2 AN3 AN7 AN55 AP1 AP2 AP3 AP4 AP5 AP53 AT15 AU1 AU2 AU56 AW1 AW20 AW48 AW56 AW68 AW69 AY1 AY2 AY3 AY20 AY21 AY56 AY68 B2 B3 B11 B15 B23 B25 B26 B27 B29 B31 B33 B36 B38 B40 B69 B70 BA3 BA4 BA9 BB2 BB4 C2 C4 C7 C8 C11 C12 C20 C23 C24 C27 C28 C29 C31 C32 C33 C36 C37 C38 C40 C41 C54 C70 C71 D1 D3 D4 D5 D7 D8 D12 D20 D23 D24 D27 D28 D29 D31 D32 D33 D36 D37 D38 D40 D41 D54 D71 E1 E2 E3 E22 E23 E25 E27 E28 E30 E38 E40 E61 F6 F18 F25 F30 F46 F50 F52 F60 F61 G1 G2 G3 G18 G46 G50 H5 H10 H11 J5 J10 J68 J71 K45 K46 N9 N11 N12 P4 U8 U9 U11 U12 W7 W10 W11 W12; D4001 2; D4002 2; DCIN1 5; DM1 87 88 91 92 95 97 100 101 104 105 162 165; DM2 87 88 91 92 95 97 100 101 104 105 162 165; EU3602 3 4; EU3604 3 4; EU3803 4 5 6 7; GPU1 A1 A10 C9 D2 F2 N1; GPU2 N1; HDA27 19 20 35 36 48; HDD1 2 7 12; HDMI1 13 14; HS2 1; HS3 1; IOBD1 1 2 3 4 25 26 27 33 35 40; KBBD1 29; LCD1 5 10 28; PU4501 15; PU4701 1 33; PU4801 1 33; PU4802 1 33; PU5101 12; PU5402 4; RN1812 4 5; RN1813 4 5; RN4302 4 5; RN5501 3 6; SSD1 5 6 7 8 10 11 13 17 19 20 22 23 24 25 26 28 29 30 31 32 34 35 36 37 40 42 44 46 48 50 52 53 54 55 56 58 67 68; TCBD1 3 4 23 24 25 28; U1701 1; U1703 1; U3401 9; U3702 2 5; U4005 1; U4101 5; U4301 4; U5701 36; U6901 3 4 10 21 22 25 26 27 28 29 30 40 41 45 46; X1801 2 4; X1802 2 3

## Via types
v1: diameter 0.356, hole 0.178, TOP to BOTTOM, 1223 vias
v2: diameter 0.508, hole 0.254, TOP to BOTTOM, 3583 vias
v3: diameter 0.711, hole 0.406, TOP to BOTTOM, 782 vias

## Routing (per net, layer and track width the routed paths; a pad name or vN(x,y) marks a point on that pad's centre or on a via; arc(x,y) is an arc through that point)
1.8V_RUN_FB: length 5.5
  BOTTOM w0.254: PU5401.2 57.94,12.92 57.71,12.69 57.71,11.6 57.55,11.45 v1(57.3,11.45) 57,11.75 57,12.35 PR5404.1 57.02,12.37 PC5405.2 PR5403.2
3V5V_CT1: length 2.1
  BOTTOM w0.203: U4001.12 135.84,101.67 136.04,101.87
  BOTTOM w0.254: 136.04,101.87 136.47,102.3 C4001.1
3V5V_CT2: length 2.1
  BOTTOM w0.203: 136.13,102.7 135.91,102.47 U4001.10
  BOTTOM w0.254: C4002.1 136.57,103.14 136.13,102.7
3V5V_S0_ON: length 4.5
  BOTTOM w0.127: v1(131.7,101.85) 131.99,101.55 132.69,101.55 132.81,101.67 U4001.3 ; v1(131.7,101.85) 130.9,101.85 R4010.2 ; v1(131.7,101.85) 131.7,101.95 132.22,102.47 U4001.5
3V_5V_EN: length 119.5
  TOP w0.127: v1(117.09,19.02) 116.99,19.12 v2(116.42,19.12) ; v2(97.33,104.46) 97.33,104.44 97.06,104.17 PR4515.1 96.56,104.19 PR4516.1
  L3 w0.127: v2(101.85,91.51) 102.57,90.79 104.5,90.79 111.92,83.38 111.92,79.16 111.38,78.61 111.38,76.95 109.7,75.28 109.7,70.83 109.96,70.57 109.96,64.82 109.83,64.69 109.83,51.43 111.31,49.95 118.17,49.95 118.92,49.2 118.92,48.04 117.52,46.65 117.52,43.78 116.76,43.02 116.14,43.02 115.9,42.78 115.9,42.44 115.91,42.43 115.91,35.95 115.21,35.25 114.29,35.25 112.72,33.69 112.72,32.27 115.47,29.53 115.47,23.14 115.73,22.88 115.73,22.08 116.42,21.39 v2(116.42,19.12)
  L4 w0.127: v2(101.85,91.51) 101.85,93.26 104.9,96.31 104.9,100.25 102.54,102.61 99.01,102.61 97.33,104.28 v2(97.33,104.46)
  BOTTOM w0.127: D4001.1 117.26,16.08 118.41,17.24 118.41,17.8 117.83,17.8 117.59,17.56 R4006.1 R4009.1 116.19,18.03 116.19,18.89 v2(116.42,19.12)
3V_5V_POK: length 318.7
  TOP w0.102: v2(91.67,104.94) 91.67,105.22 92,105.55 93.09,105.55 PG4529.1 ; PG4531.1 163.42,59.45 163.65,59.68 163.65,60.39 v2(163.24,60.8) ; v2(65.4,8.81) 65.49,8.72 EC1705.1 66.91,8.72 67.35,9.15 C1710.1 R1728.2 69.33,10.02 69.65,10.02 70,10.38 71.25,10.38 71.32,10.46 72.44,10.46 72.9,10 v1(72.9,9.85) 72.9,9.06 v2(73.12,8.83) ; v2(105.61,17.67) 105.54,17.59 105.54,16.37 106.25,15.66 v2(106.25,12.69)
  L3 w0.102: v2(159.94,105.88) 157.44,108.39 135.44,108.39 133.5,106.44 122.3,106.44 116.81,100.96 115.04,100.96 114.28,101.72 108.2,101.72 107.74,102.18 102.08,102.18 102.07,102.17 99.06,102.17 97.89,103.34 95.71,103.34 95.4,103.04 94.63,103.04 92.63,105.05 91.77,105.05 v2(91.67,104.94) ; v2(103.12,10.13) 103.12,10.17 101.9,11.4 94.74,11.4 94.22,11.92 87.11,11.92 79.49,4.3 72.22,4.3 71.05,3.13 65.92,3.13 v2(65.25,3.8) ; v2(82.22,91.94) 82.22,92.83 81.28,93.77 81.28,94.4 81.94,95.06 81.94,97.02 84.61,99.69 84.92,99.69 85.57,100.34 85.57,101.44 86.05,101.92 88.24,101.92 89.1,102.79 v2(90.32,102.79)
  L4 w0.102: v2(65.4,8.81) 65.25,8.65 65.25,6.67 66.22,5.71 66.22,5.01 65.54,4.34 65.54,4.09 v2(65.25,3.8)
  L6 w0.102: v2(159.94,105.88) 160.4,106.34 162.25,106.34 162.63,105.95 162.63,105.22 165.38,102.48 165.38,100.89 169.29,96.98 169.29,77.94 167.21,75.86 165.63,75.86 165.2,75.43 165.2,75.39 165.19,75.38 165.19,71.17 166.79,69.57 166.79,62.06 166.01,61.28 163.73,61.28 v2(163.24,60.8)
  BOTTOM w0.102: v2(106.25,12.69) 106.2,12.69 105.38,11.88 105.38,10.79 104.95,10.35 103.35,10.35 v2(103.12,10.13) 103.39,9.86 PR5210.1 ; v2(159.94,105.88) 160.5,105.33 R4033.1 ; v2(90.32,102.79) 90.32,103.6 v2(91.67,104.94) ; v2(73.12,8.83) 73.33,9.03 74.53,9.03 74.8,9.31 74.8,11.14 76.22,12.56 76.22,14.98 76.78,15.54 76.78,18.69 76.48,18.99 76.48,22.29 77.01,22.83 77.01,23.36 76.93,23.44 76.93,24 77.19,24.25 79.6,26.66 79.6,48.56 82.43,51.39 82.43,51.8 81.62,52.61 81.62,54.98 84.67,58.04 84.67,90.39 83.74,91.31 83.74,91.76 83.31,92.19 82.57,92.19 82.32,91.94 v2(82.22,91.94) ; v2(105.61,17.67) 105.38,17.9 R1718.2 ; PR5406.1 65.1,9.11 v2(65.4,8.81)
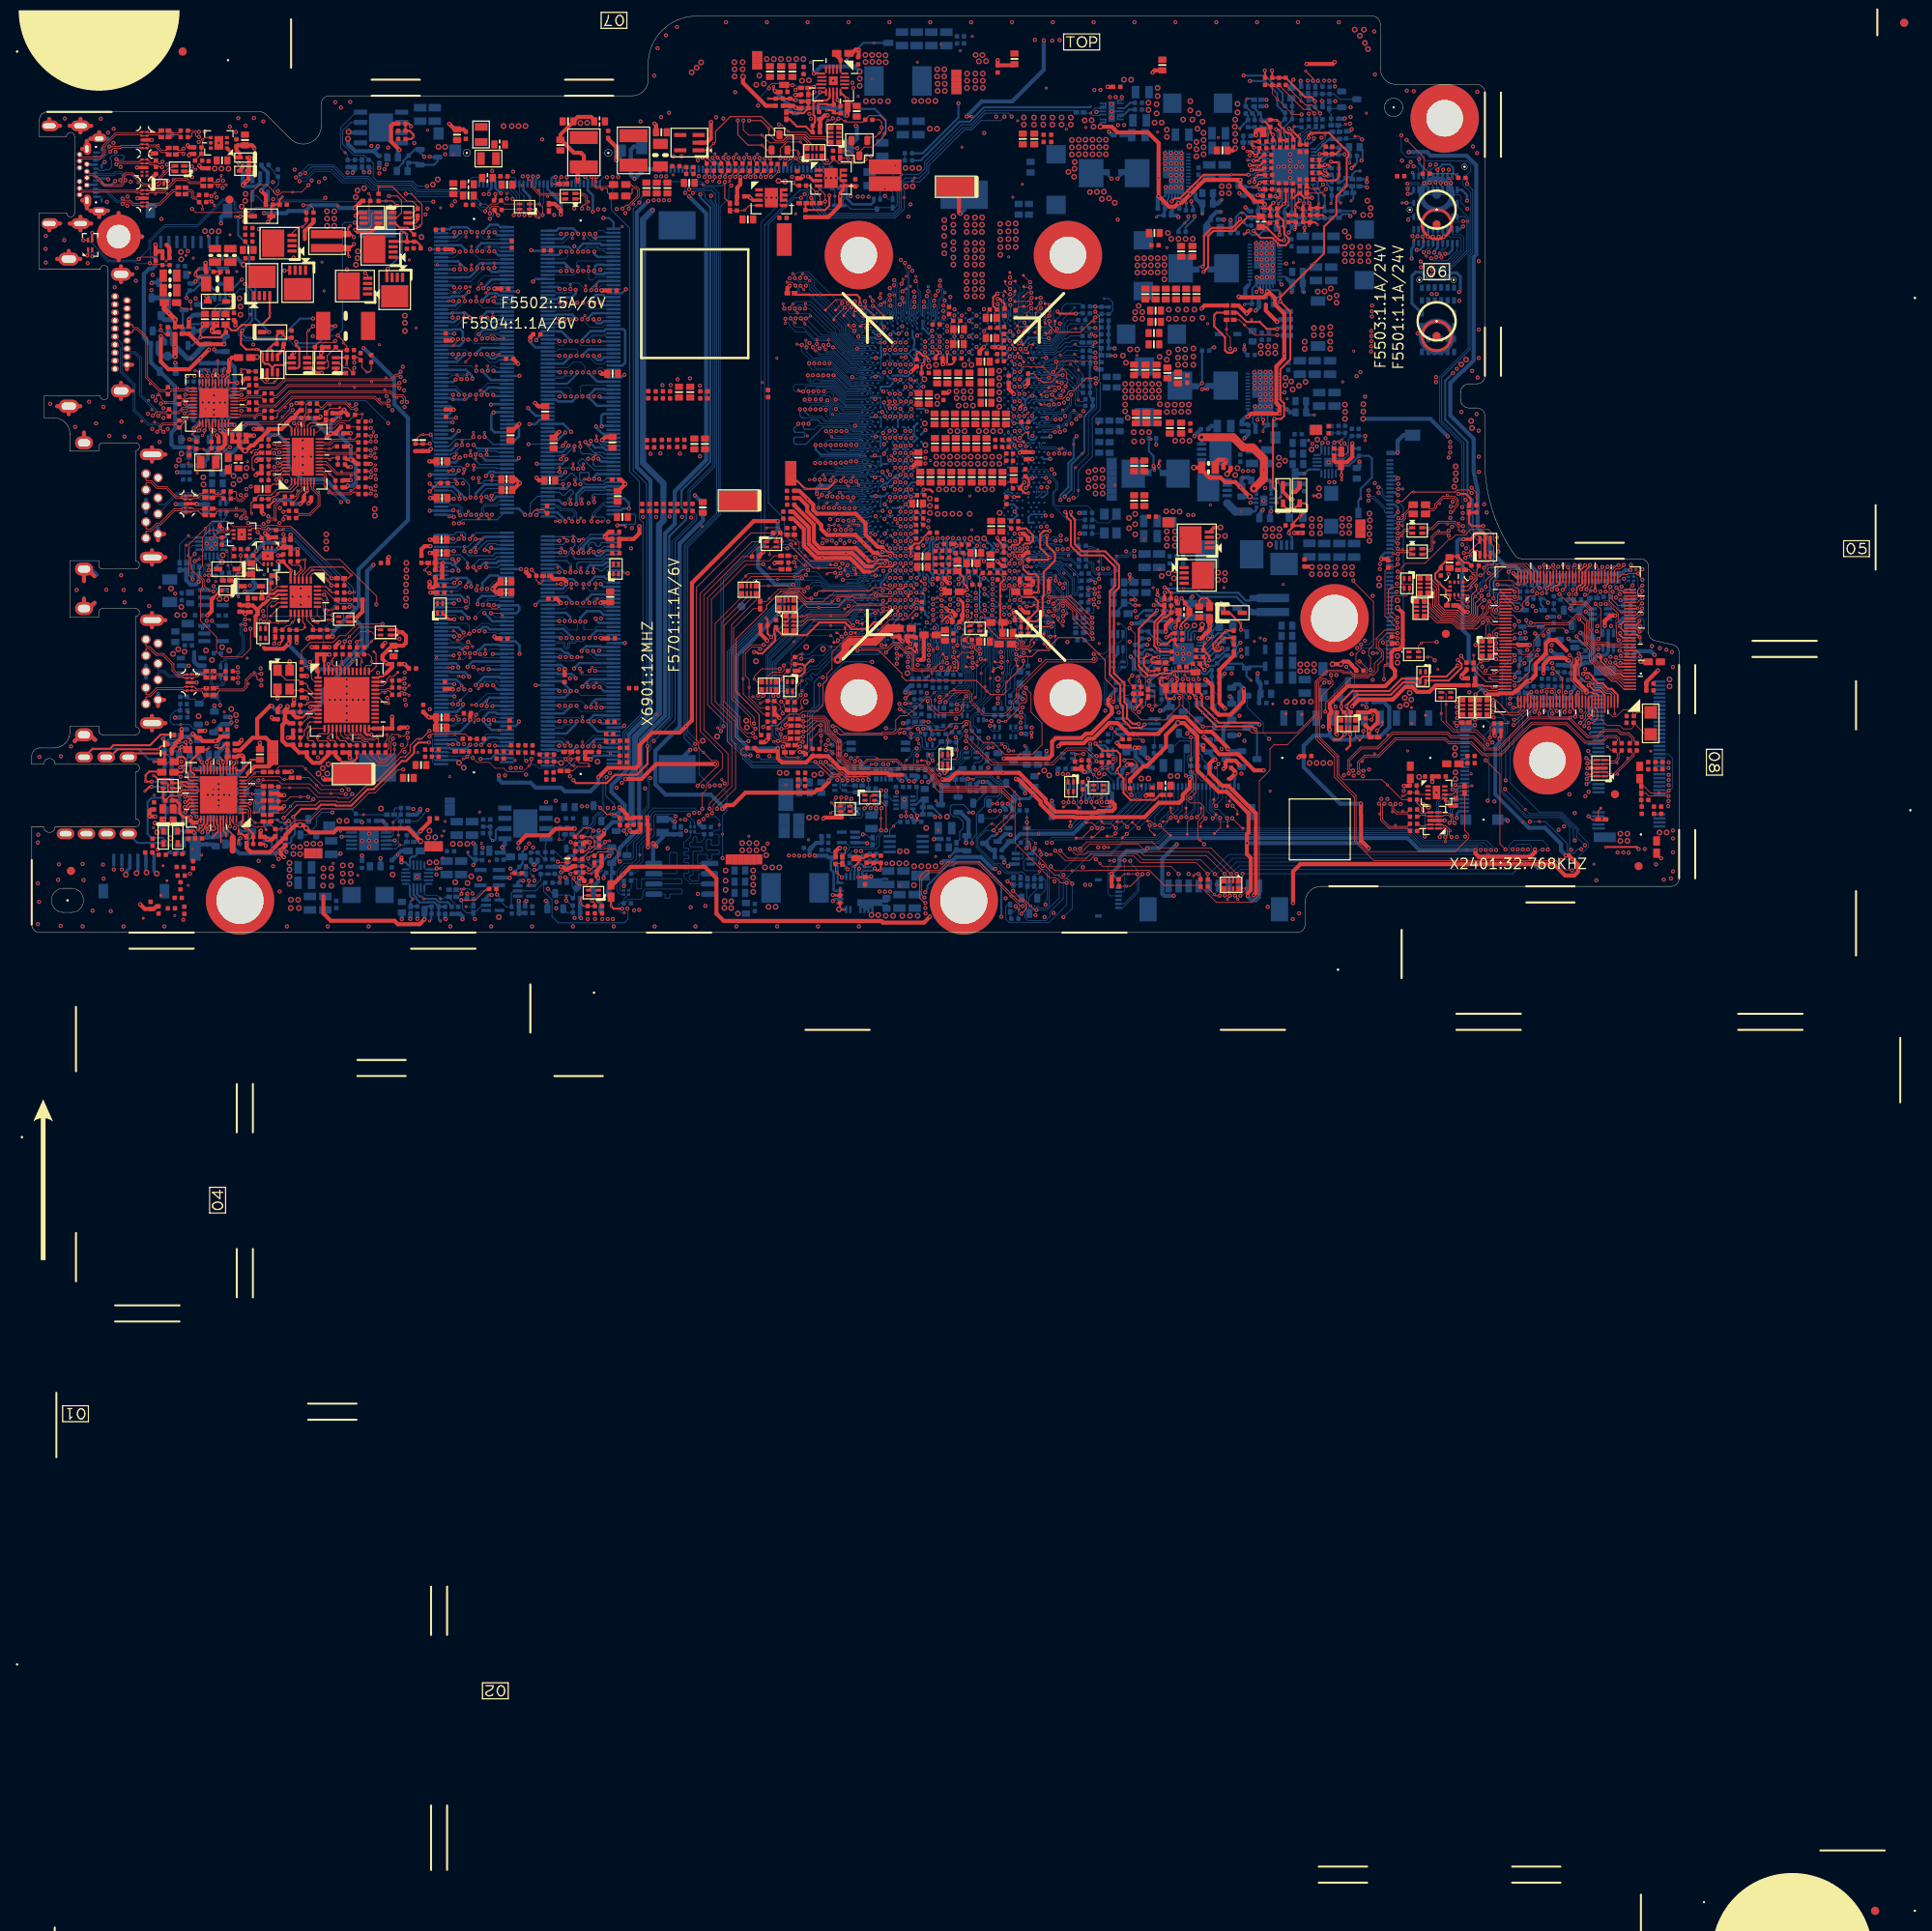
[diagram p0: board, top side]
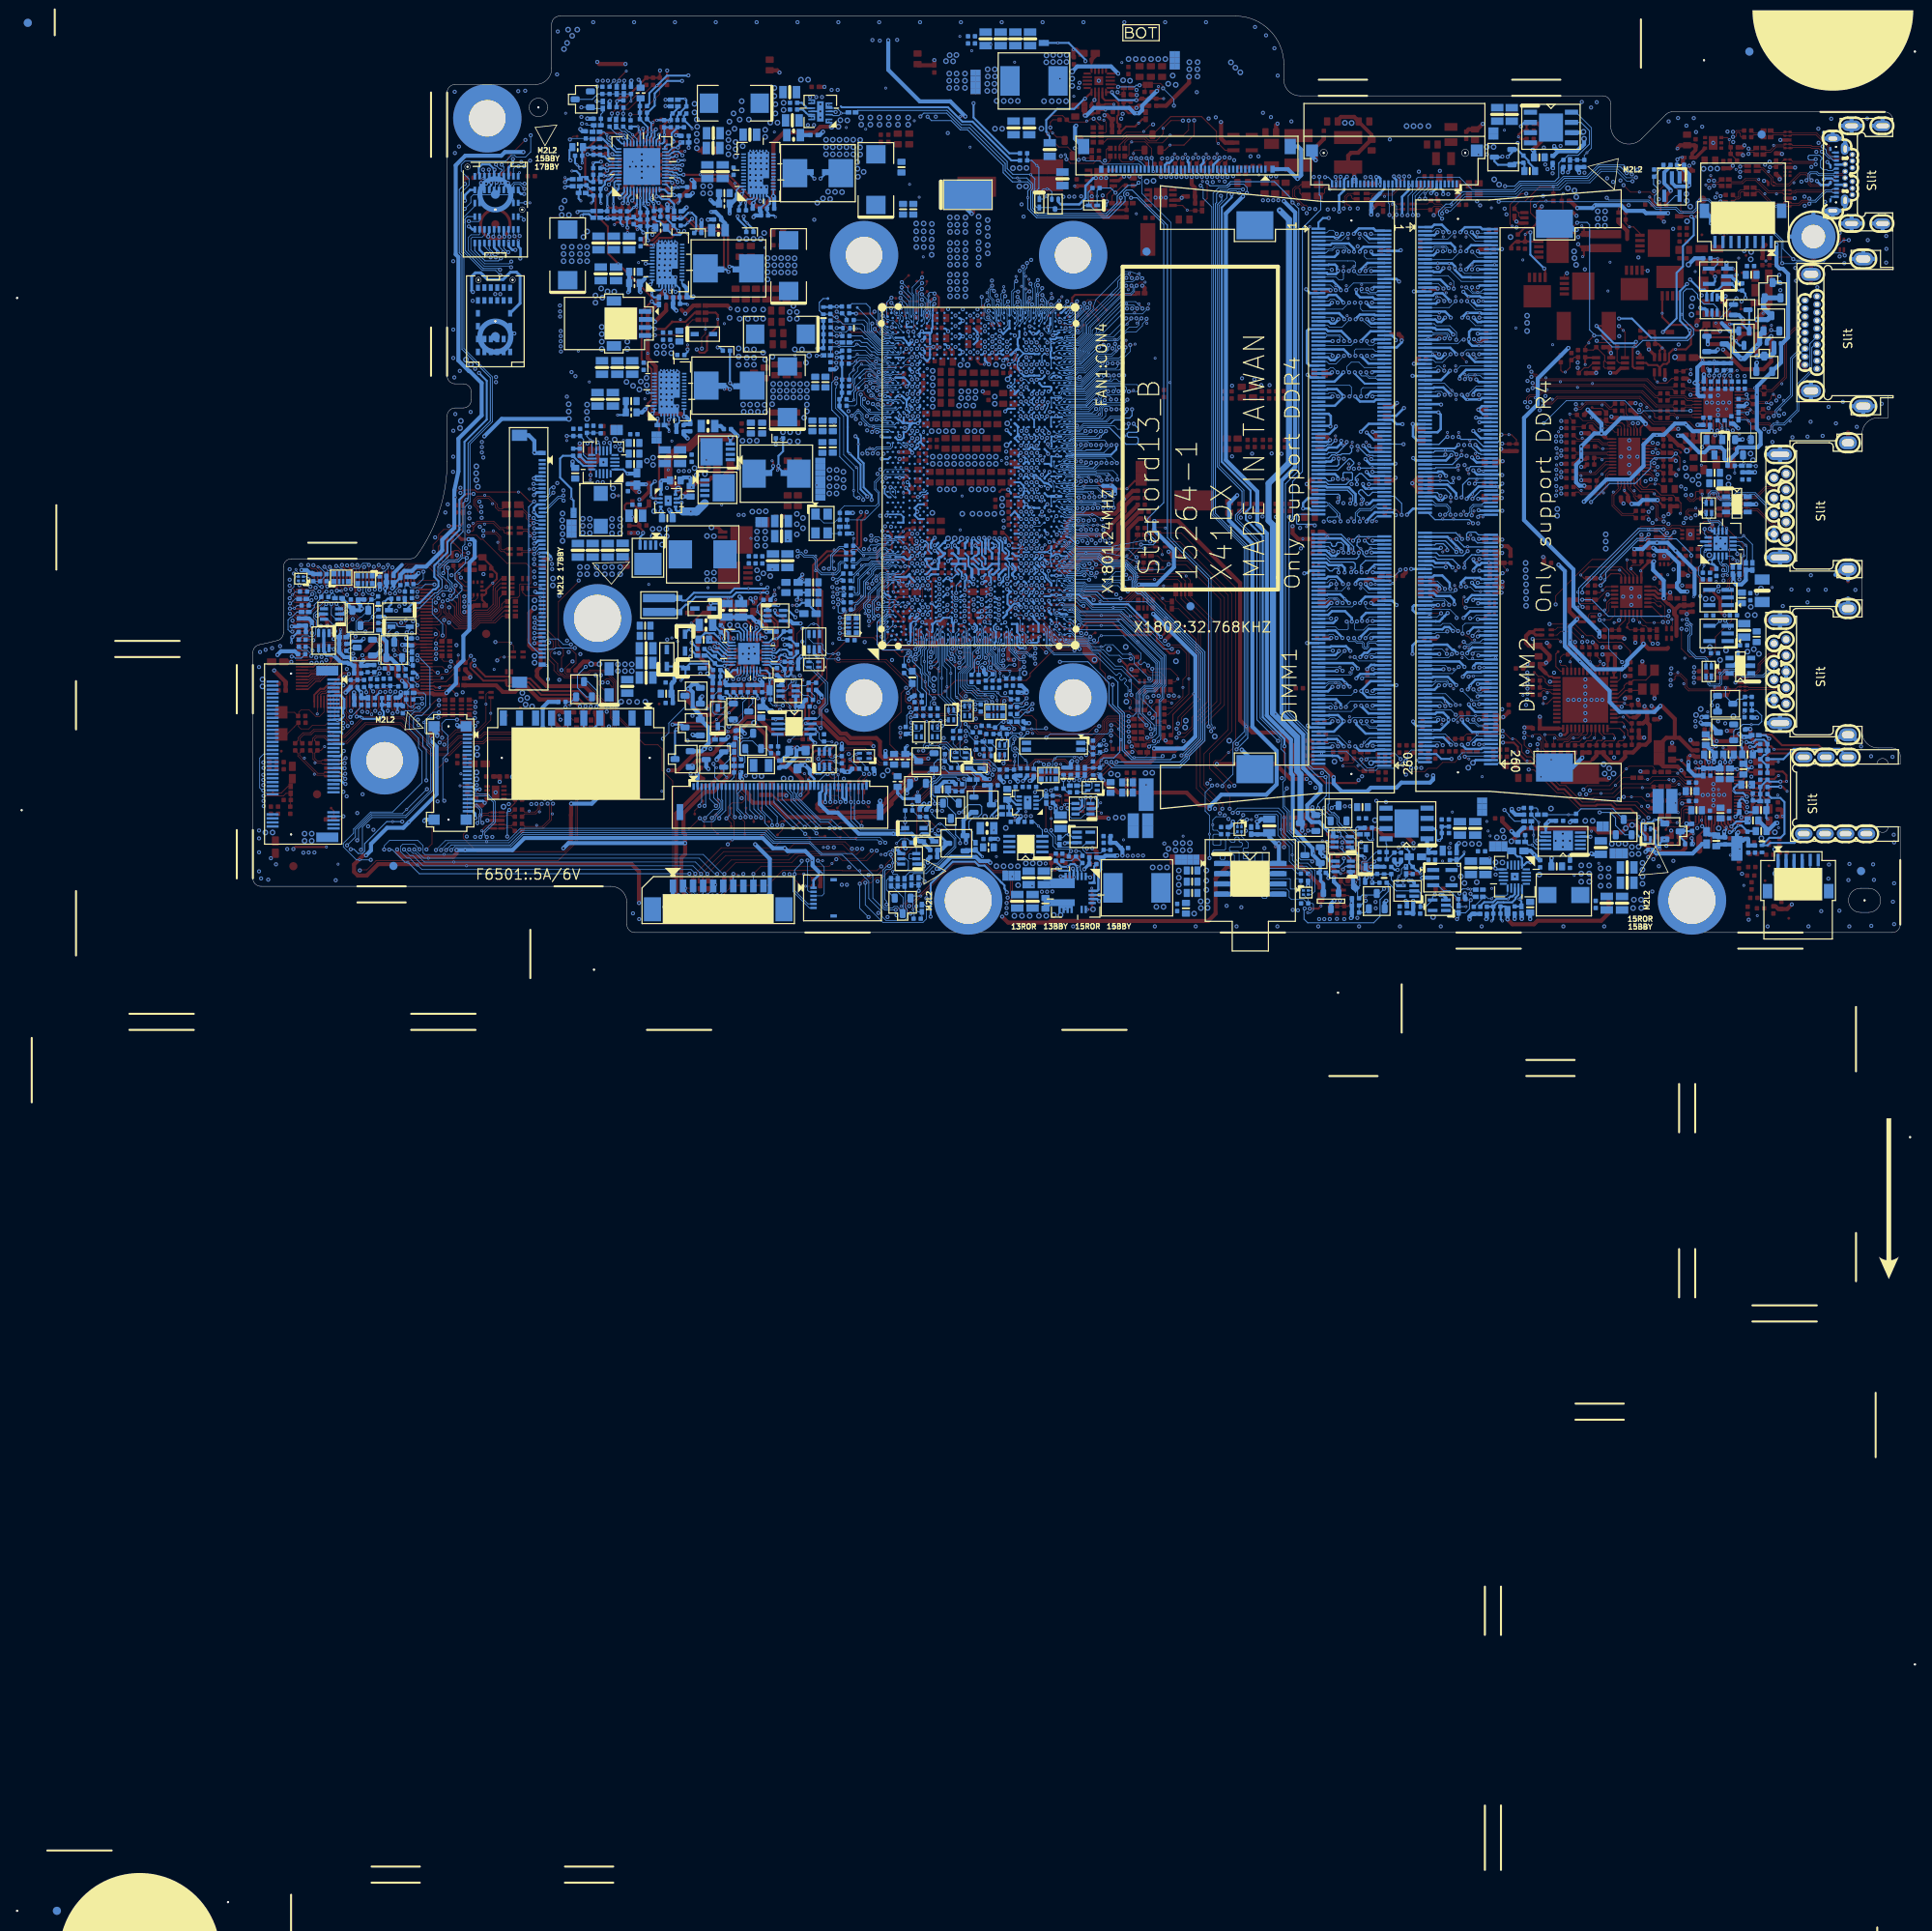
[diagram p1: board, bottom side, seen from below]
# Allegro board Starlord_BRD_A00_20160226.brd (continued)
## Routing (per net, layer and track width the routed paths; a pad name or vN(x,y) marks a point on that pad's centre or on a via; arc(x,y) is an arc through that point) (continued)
3V_5V_POK#: length 6.5
  TOP w0.127: v1(71.65,10.1) 71.58,10.02 70.46,10.02 69.98,9.54 R1726.1 69.52,9.54 v2(69.19,9.21)
  BOTTOM w0.127: v2(69.19,9.21) 69.19,8.73 69.7,8.22 Q1701.5 70.79,8.22 70.92,8.09 70.92,7.7 70.79,7.57 Q1701.6
3V_5V_POK_C: length 5.5
  TOP w0.127: R1727.2 69.96,8.26 69.57,7.87 69.31,7.87 v2(69.29,7.84) 69.26,7.87 69.26,7.97 68.96,8.27 68.46,8.27 R1728.1 68.39,8.2 68.39,7.64 R1729.1 69.02,7.46 69.15,7.33 v1(69.59,7.33)
  BOTTOM w0.127: v2(69.29,7.84) 69.26,7.87 69.26,7.97 69.01,8.22 Q1701.2
5V_AUX_S5: length 13.2
  TOP w0.254: v2(92.43,104.61) 92.25,104.79 v1(92.25,105.17)
  TOP w0.508: PG4528.2 101.45,101.64 v2(101.37,101.57) ; PR4510.2 92.56,104.49 92.43,104.61 v2(92.43,104.61)
  BOTTOM w0.508: v2(92.43,104.61) 94.28,102.76 94.28,102.23 94.66,101.85 95.22,101.85 95.88,102.51 100.25,102.51 101.19,101.57 v2(101.37,101.57)
5V_HDD:
  vias: v1(171.09,22.57)
5V_HDD_SIP:
  vias: v1(178.99,19.73) v3(177.04,19.9) v3(177.04,19.07)
5V_HDMI_R_S5:
  vias: v1(26.85,58.54)
5V_HDMI_S5:
  vias: v1(19.45,58.31) v3(18.31,58.72) v3(18.62,59.53)
5V_S0: length 76.3
  TOP w0.508: v2(145.46,77.56) 145.85,77.94 R2612.1
  L3 w0.508: v2(28.19,18.91) 29.41,17.7 29.41,14.09 31.55,11.95 31.55,10.15 v2(31.67,10.02)
  L6 w0.508: v2(145.46,77.56) 150.06,77.56 151.2,78.71 151.2,86.17 149.55,87.82 142.34,87.82 140.77,89.4 140.77,91.81 139.98,92.6 139.98,98.85 138.48,100.35 135.86,100.35 v2(135.84,100.37)
  BOTTOM w0.356: v2(177.49,79.62) 177.65,79.77 177.65,81.55 177.19,82.01 176.53,82.01 176.34,81.82 176.27,81.77 176.15,81.66 176.11,81.59 175.69,81.17 173.73,81.17 172.82,82.08 172.06,82.08 171.63,81.65 171.63,78.21 GPU2.P4
  BOTTOM w0.508: v2(31.67,10.02) 31.39,10.3 v1(31.09,10.3) 30.81,10.3 30.33,9.82 25.83,9.82 24.65,11 R2703.2
  vias: v1(24.74,58.11) v1(28.75,19.02) v2(25.45,25.62) v2(25.47,26.28) v2(135.08,100.37) v2(173.02,15.97) v3(25.4,27.04) v3(26.59,56.73) v3(26.72,57.75) v3(42.64,52.65) v3(42.67,51.81) v3(49.88,92.98) v3(50.49,93.62) v3(68.22,100.63) v3(69.06,100.65) v3(135.81,106.01) v3(136.7,106.01) v3(141.6,19.45) v3(142.47,19.45) v3(165.78,110.58) v3(166.17,109.82) v3(172.52,19.35) v3(173.68,15.64)
5V_S5: length 304.2
  TOP w0.406: U4004.3 97.17,93.47 96.67,93.97 v2(96.52,93.97) ; U4002.3 89.66,91.03 v2(89.36,91.33)
  TOP w0.508: v2(89.36,91.33) 89.18,91.51 C4032.1 ; v2(147.17,21.48) 146.96,21.48 146.45,20.97 146.45,19.8 148.03,18.23 148.79,18.23 152.22,14.8 152.22,4.92 v2(151.94,4.64) ; v3(48.36,11.35) 46.79,12.92 38.02,12.92 37.54,12.44 34.64,12.44 34.14,12.95 v3(34.14,12.97) 33.75,13.35 v3(33.35,13.35) 32.76,13.35 31.55,12.13 EC8914.1 31.32,11.71 29.61,10 27.23,10 26.72,10.51 R2725.1 ; v2(150.09,79.06) 150.19,78.96 153.19,78.96 153.62,79.38 v2(153.62,79.7) 153.74,79.7 154.61,78.83 154.61,78.07 155.75,76.93 v1(155.75,72) 155.75,71.37 154.76,70.37 154.76,65.83 155.17,65.42 v2(155.17,64.51) 151.63,64.51 v2(151.24,64.12) ; v2(153.34,90.52) 152.98,90.87 152.2,90.87 150.29,92.78 v2(150.29,93.56) 145.85,93.56 v2(144.07,91.79) 142.97,90.69 v2(142.59,90.69) 142.14,90.24 141.43,90.24 v2(140.13,91.53) v1(140.13,93.82) 140.13,98.14 138.81,99.46 135,99.46 134.29,100.17 v3(132.89,100.17) ; R3721.2 v2(33.07,47.67) ; v2(16.05,74.13) 16.05,70.96 16.99,70.02 19.58,70.02 v1(20.97,71.41) v2(22.02,72.46)
  L3 w0.508: v2(84,93.36) 83.92,93.29 82.79,93.29 82.32,93.76 82.32,94.29 82.69,94.66 87.98,94.66 88.05,94.59 94.8,94.59 95.25,94.14 95.25,93.73 95.62,93.36 96.15,93.36 96.52,93.73 v2(96.52,93.97)
  L4 w0.508: v2(84,93.36) 84.07,93.29 84.57,93.29 86.53,91.33 v2(89.36,91.33) ; v2(96.52,93.97) 97.64,93.97 98.7,92.9 98.98,92.9 99.82,92.07 99.82,91.2 100.38,90.64 104.31,90.64 104.82,91.16 104.82,93.32 106.73,95.23 106.73,96.87 108,98.14 111.94,98.14 116.3,102.51 v3(116.3,104.99) ; v2(154.12,52.39) 154.12,60.27 151.24,63.15 v2(151.24,64.12)
  L6 w0.508: 119.84,9.16 120.72,10.05 122.32,10.05 124.08,11.8 127.11,11.8 127.69,11.22 133.61,11.22 134.63,10.2 136.2,10.2 137.23,9.17 137.23,8.53 136.85,8.14 136.85,6.99 137.23,6.62 150.05,6.62 151.94,4.72 v2(151.94,4.64) ; v2(153.62,79.7) 154.57,79.7 v2(155.42,80.55) 155.12,80.86 155.12,85.82 153.72,87.21 153.72,90.14 v2(153.34,90.52)
  BOTTOM w0.203: PU4801.3 153.54,79.78 v2(153.62,79.7) ; PU4701.36 154.93,64.74 v2(155.17,64.51) ; PU4801.36 155.19,80.79 v2(155.42,80.55) ; v2(144.07,91.79) 143.83,92.02 PU4802.36 ; v2(132.38,102) 132.46,102.07 U4001.4 ; v2(151.24,64.12) PU4701.7 ; PU4801.7 151.49,80.67 151.26,80.43 ; v2(142.59,90.69) 142.59,90.82 142.18,91.23 PU4802.3 ; PU4802.7 140.14,91.54 v2(140.13,91.53)
  BOTTOM w0.305: C3402.1 22.86,45.41 23.21,45.76 23.37,45.76 v3(23.67,46.07) 23.1,46.64 U3401.1 ; 153.47,78.96 153.47,79.16 153.62,79.32 v2(153.62,79.7) ; PU5201.21 99.88,5.17 99.72,5.33 99.72,7.48 99.39,7.81 99.39,8.86 99.87,9.34 ; v2(154.12,52.39) PU5001.4
  BOTTOM w0.508: Q6505.E 147.17,21.59 v2(147.17,21.48) ; v2(142.59,90.69) 142.69,90.6 PC4846.1 ; v2(33.07,47.67) 32.03,47.67 31.24,48.45 v2(30.25,48.45) 28.93,48.45 v2(27.94,47.46) 27.4,46.93 27.4,46.91 25.58,45.08 25.58,42.05 ; 42.54,97.12 43.03,97.6 v2(43.03,97.76) ; 42.54,97.12 43.11,96.55 PC5410.1 ; 42.54,97.12 40.23,97.12 39.62,97.72 39.58,97.72 39.32,97.98 v3(39.32,98.67) ; Q6401.E 115.51,14.93 116.5,13.95 116.5,12.26 Q6402.E 116.18,11.94 v2(116.18,11.14) ; 116.25,104.94 v3(116.3,104.99) ; v2(119.81,7.92) 119.5,7.92 118.03,9.39 114.94,9.39 114.43,8.88 113.36,8.88 v2(113.16,8.68) ; PC5202.1 99.06,9.34 98.86,9.54 97.64,9.54 97.61,9.57 v2(97.36,9.57) ; R3405.1 20.75,44.48 v2(20.75,43.6) 20.42,43.27 19.73,43.27 19.2,43.81 R3406.1 R3402.1 ; v2(153.34,90.52) 153.29,90.47 PR4642.1 ; v2(150.09,79.06) 150.19,78.96 PR4803.2 150.9,80.08 151.26,80.43 ; v2(16.05,74.13) 16.6,73.59 PR4303.1 ; PR4702.2 151.15,63.2 PC4707.1 150.47,63.59 150.99,64.12 v2(151.24,64.12) ; PU5403.6 39.5,99.43 v3(39.39,99.53) ; PR4657.1 149.97,93.24 v2(150.29,93.56) ; v2(154.12,52.39) 153.97,52.24 PC5001.1 ; v2(140.13,91.53) 140.02,91.43 PR4806.2
  vias: v1(75.61,9.64) v1(126.16,104.97) v1(131.06,100.07) v2(24.86,41.83) v2(91.51,11.07) v2(107.59,17.44) v3(23.34,41.47) v3(23.75,46.91) v3(23.67,35.48) v3(24.2,41.47) v3(24.56,35.07) v3(25.09,56.76) v3(25.83,56.25) v3(26.11,90.24) v3(26.54,90.95) v3(26.59,91.81) v3(55.68,6.7) v3(65.33,13.96) v3(82.07,106.93) v3(82.68,107.51) v3(83.23,108.17) v3(116.3,106.77) v3(116.3,105.88) v3(117.35,106.77) v3(117.35,105.88) v3(117.35,104.99) v3(118.26,106.77) v3(118.26,105.88) v3(118.26,104.99) v3(130.94,100.96) v3(131.8,100.98) v3(132.03,100.17) v3(164.51,112.23) v3(165.15,111.47) v3(165.66,112.23) v3(167.54,44.01) v3(167.56,43.15)
5V_STB: length 3.4
  TOP w0.102: 25.73,12.77 25.73,13.09 25.65,13.17 25.65,13.22 25.45,13.43 25.22,13.43 25.04,13.61 HDA27.47
  TOP w0.254: 25.73,12.77 v1(25.73,12.26) 26.16,12.26 26.5,11.92 R2725.2
+3V_1D8V_AVDD: length 7.2
  TOP w0.203: 24.31,21.17 24.31,21 24.24,20.93 HDA27.16
  TOP w0.254: 24.31,21.17 24.31,21.8 R2713.2 R2710.2 R2705.2 24.08,23.46 23.52,22.9 v1(23.44,22.9) 23.19,22.9 v2(22.93,23.16)
  BOTTOM w0.254: v2(22.93,23.16) 23.06,23.16 23.37,23.46 23.37,23.82 C2715.1
+3V_AVDD: length 12.6
  TOP w0.203: v2(27.13,16.05) 27.06,16.11 HDA27.4 ; HDA27.12 26.63,19.31 26.85,19.52 26.85,19.78
  TOP w0.508: 26.85,19.78 v2(27.23,20.16) 27.71,20.64 29.46,20.64 29.97,21.15 R2731.2 ; R2728.2 29.88,11.57 v1(29.34,11.57) 29.01,11.9 R2722.1 28.43,12.6 v2(28.5,12.67)
  L6 w0.508: v2(28.5,12.67) 28.5,14.68 v2(27.13,16.05)
+3VLP: length 23.4
  TOP w0.102: KBC24.120 194.01,27.83 194.26,27.58 194.26,26.89 193.93,26.56 193.47,26.56 193.17,26.25 193.17,25.77 v2(193.06,25.67) ; v2(181.32,24.22) 181.35,24.25 181.35,25.51 R2454.1 R2463.2 183.5,25.99 v1(183.61,26.1)
  L6 w0.102: v2(181.32,24.22) 181.32,24.87 183.44,26.99 184.5,26.99 185.98,28.46 189.63,28.46 190.17,27.93 190.17,26.97 190.45,26.69 191.06,26.69 192.23,25.52 192.91,25.52 v2(193.06,25.67)
+5V_AVDD: length 5.7
  TOP w0.203: v2(21.89,12.54) 21.89,13.1 22.24,13.44 HDA27.40
  BOTTOM w0.254: v2(21.89,12.54) 21.64,12.79 v1(21.64,13.07)
  BOTTOM w0.508: v2(21.89,12.54) 21.89,11.97 C2710.1 22.67,11.84 C2711.1 23.01,12.18 23.73,12.18 R2703.1
+5V_KB_BL: length 1
  BOTTOM w0.305: KBBD1.30 135.55,18.75 135.81,19.02
  vias: v3(137.97,19.14) v3(138.86,19.14)
+5V_PVDD: length 2
  TOP w0.203: HDA27.41 22.64,13.02 v3(22.58,12.96) ; v2(24.64,13.2) 24.64,13.2 HDA27.46
  vias: v1(24.71,13.96) v2(25.25,12.98)
+V1.00A_SIP: length 29.6
  TOP w0.406: v2(120.06,46.17) 120.66,45.57 C2101.1
  TOP w0.508: v2(126.69,43.98) 126.48,43.77 v2(126.48,42.36) ; v2(115,48.1) 114.8,48.3 C2121.1 ; v2(113.08,42.7) 113.51,42.7 R2108.1 ; v2(124.43,58.87) 124.39,58.83 R1803.2
  L4 w0.508: v2(137.21,39.97) 132.54,39.97 132.52,40 130.86,40 129.28,41.57 127.54,41.57 126.79,42.32 126.53,42.32 v2(126.48,42.36)
  BOTTOM w0.127: v2(120.52,34.87) 120.47,34.92 120.47,36.01 120.41,36.06 CPU1.L1 ; CPU1.A14 125.6,44.19 126.49,44.19 v2(126.69,43.98) ; v2(117.85,35.27) 117.78,35.34 117.78,36.6 CPU1.T1
  BOTTOM w0.152: CPU1.AK20 109.59,47.77 109.33,48.04 v2(109.33,48.66)
  BOTTOM w0.254: CPU1.K17 120.41,45.82 v2(120.06,46.17) ; v2(118.39,46.17) 118.08,46.47 CPU1.P18 ; CPU1.A10 125.84,41.97 126.09,41.97 v2(126.48,42.36) ; CPU1.AB17 115.26,46.47 CPU1.Y18 115.08,46.84 114.89,46.84 CPU1.AB19
  BOTTOM w0.305: v2(115,48.1) 115,48.1 115,48.08 114.7,47.77 CPU1.AB20 CPU1.AB19 ; CPU1.L21 119.94,48.12 v2(120.06,48.12)
  vias: v1(139.44,42.87)
+V1.00U_CPU: length 6
  TOP w0.254: v1(110.11,13.96) v2(110.11,14.52)
  BOTTOM w0.254: U4006.8 109.61,15.12 110.11,14.62 v2(110.11,14.52) 110.63,14.52 R4038.1 R4036.1 110.81,15.96 111.05,16.2 C4012.1 110.59,16.53 109.96,15.9 U4006.7
+V1.8A: length 50.2
  TOP w0.508: R1104.2 110.92,36.81 v1(110.92,34) 110.82,33.9 v2(110.21,33.9) ; v2(73.1,15.56) 74.03,14.63 R4046.1 74.79,14.22 C4023.1 74.86,14.29 C4029.1
  L6 w0.508: v2(110.21,33.9) 109.95,33.9 109.56,33.51 109.56,32.92 110.01,32.48 110.01,31.3 109.17,30.47 108.37,30.47 107.21,29.31 107.21,27.63 104.98,25.39 100.78,25.39 99.84,26.34 99.79,26.34 99.71,26.41 97.86,26.41 97.08,25.63 97.08,23.12 95.77,21.81 95.12,21.81 94.74,22.19 92.38,22.19 91.92,22.65 86.49,22.65 85.96,23.17 83.83,23.17 82.75,22.09 80.82,22.09 79.96,21.23
  BOTTOM w0.508: v2(73.1,15.56) 73.1,15.08 72.68,14.66 Q4009.S
  vias: v1(23.95,27.42) v1(51.41,13.81) v3(20.75,26.89) v3(24.81,27.78) v3(43.43,15.41)
+V1.8A_SIP: length 3.2
  BOTTOM w0.178: CPU1.AA1 115.11,36.72 115.11,35.73 v2(115.09,35.7)
  BOTTOM w0.254: v2(113.21,43.32) 113.08,43.45 113.08,44.14 113.31,44.37 113.31,44.8 CPU1.AF16
  vias: v1(114.6,35.4)
+V1.8S_EDRAM: length 147
  TOP w0.508: C4028.1 75.68,12.58 v1(75.59,12.49) 74.55,12.49 v2(74.37,12.67)
  L6 w0.508: v2(77.16,89.78) 79.03,87.91 87.41,87.91 89.08,89.58 98.93,89.58 99.85,90.49 106.58,90.49 107.29,89.78 111.45,89.78 112.95,91.28 117.73,91.28 119.45,89.55 119.45,83.35 120.95,81.86 120.95,73.22 v2(121.61,72.56)
  BOTTOM w0.305: v2(121.61,72.56) 121.3,72.25 CPU1.H63
  BOTTOM w0.508: Q4009.D 74.57,13.61 74.37,13.4 v2(74.37,12.67)
  BOTTOM w0.762: Q4009.D 74.59,19.69 75,20.11 75,24.29 78,27.29 78,50.66 78.55,51.21 78.55,55.83 76.01,58.37 76.01,88.62 v2(77.16,89.78)
+V3.3A_SIP: length 94.6
  TOP w0.508: v2(70.46,19.3) 71.63,20.46 75.16,20.46 75.59,20.9 75.59,23.31 77.14,24.86 80.57,24.86 v1(81.32,25.61) 82.09,26.38 82.09,43.45 89.79,51.15 v2(92.76,51.15)
  L4 w0.508: v2(54.89,11.12) 54.89,11.75 54.99,11.85 54.99,14.93 55.04,14.98 55.04,15.21 58.09,18.25 v2(58.09,19.52)
  BOTTOM w0.254: CPU1.Y16 115.87,45.59 115.87,46.7 CPU1.V19 ; v2(116.58,44.11) 116.7,44.23 116.7,44.75 116.75,44.79 CPU1.T16
  BOTTOM w0.279: CPU1.AK15 110.42,44.63 110.04,45.01 110.04,45.34 110.42,45.72 CPU1.AK17
  BOTTOM w0.305: CPU1.AD15 113.77,44.49 v2(114.16,44.11) ; v2(112.02,43.95) 112.09,44.02 CPU1.AG15 112.03,44.52 111.38,45.17 CPU1.AJ16 ; CPU1.AK15 110.42,44.43 v2(110.06,44.07) ; CPU1.AJ21 111.26,48.84 v2(111.35,48.94)
  BOTTOM w0.406: v2(115.24,43.95) 115.45,44.16 CPU1.Y15 CPU1.Y16
  BOTTOM w0.508: v2(94.69,43.25) 92.48,43.25 90.32,45.41 90.32,47.57 90.72,47.97 90.73,47.97 92.76,50 v2(92.76,51.15) ; v2(70.46,19.3) 70.46,18.53 69.47,17.54 66.29,17.54 65.83,18.01 62.65,18.01 62.03,18.63 58.47,18.63 58.09,19.02 v2(58.09,19.52) ; v2(54.89,11.12) 55.17,10.84 R2101.1
+VCCAMPHYPLL_1P0: length 8.7
  TOP w0.254: v2(120.93,44.06) 120.93,43.86 120.42,43.35 v1(120.42,40.99) 120.42,38.97 R2107.2 120.7,38.46 C2113.1
  BOTTOM w0.254: v2(120.93,44.06) 120.9,44.09 120.9,44.1 120.48,44.52 CPU1.K15 CPU1.L15
+VCCAPLL_1P0: length 5.9
  TOP w0.254: R2108.2 116.05,42.36 v2(116.3,42.61) 116.3,42.97 115.87,43.4 v1(115.87,43.6) 115.87,44.16 C2114.1
  BOTTOM w0.254: CPU1.V15 116.11,44.35 116.11,43.9 116.3,43.7 v2(116.3,42.61)
+VCCCLK2: length 25.2
  TOP w0.254: v2(137.21,41.34) v1(136.65,41.34)
  L6 w0.203: v2(121.63,48.65) 122.1,49.11 122.65,49.11
  L6 w0.254: v2(137.21,41.34) 137.34,41.47 137.34,42.35 135.41,44.28 135.41,44.94 133.94,46.4 130.78,46.4 130.15,47.03 128.85,47.03 128.8,47.08 127.05,47.08 126.67,47.46 125.53,47.46 123.9,49.09 122.68,49.09 122.65,49.11
  BOTTOM w0.203: v2(121.63,48.65) 121.21,48.65 120.88,48.32 120.88,47.52 CPU1.K19
  BOTTOM w0.254: C2115.1 R2109.2 137.06,42.26 137.06,41.49 v2(137.21,41.34)
+VCCCLK4: length 26.7
  TOP w0.254: v2(136.52,44.49) v1(136.52,43.91)
  L6 w0.254: v2(136.52,44.49) 136.52,44.9 134.18,47.24 131.6,47.24 128.95,49.88 127.81,49.88 126.67,48.73 126.08,48.73 124.31,50.51 120.29,50.51 119.05,49.27 119.05,48.78 118.38,48.12 v2(118.38,48.08)
  BOTTOM w0.254: v2(118.38,48.08) 118.69,47.77 CPU1.N20 ; C2119.1 R2110.2 137.06,43.53 137.06,43.88 136.52,44.42 v2(136.52,44.49)
+VCCCLK5: length 29.4
  TOP w0.254: v2(137.21,40.68) v1(137.77,40.68)
  L6 w0.254: v2(137.21,40.68) 137.27,40.68 137.72,41.13 137.72,42.5 135.79,44.43 135.79,45.09 134.1,46.78 131.14,46.78 129.68,48.24 125.64,48.24 123.84,50.04 122.02,50.04 120.95,48.97 120.95,47.85 120.57,47.46 v2(120.06,47.46)
  BOTTOM w0.254: v2(120.06,47.46) 119.98,47.46 CPU1.L19 ; R2111.2 134.81,39.81 135.84,40.83 C2122.1 136.57,40.99 136.88,40.68 v2(137.21,40.68)
+VCCCOREG0: length 2
  TOP w0.254: v2(122.15,54.15) 122.17,54.17 TP701.1
  BOTTOM w0.127: CPU1.K32 121.11,54.45 121.56,54.45 121.82,54.19 122.1,54.19 v2(122.15,54.15)
+VCCCOREG1: length 1.8
  TOP w0.254: TP707.1 111.73,55.06 v2(110.92,55.06)
  BOTTOM w0.254: CPU1.AK32 110.59,54.68 110.92,55.01 v2(110.92,55.06)
+VCCDSW_1P0: length 4.5
  TOP w0.254: C2103.1 110.11,34.92 v1(110.06,34.87) 109.83,34.87 109.35,35.35 108.89,35.35 v2(108.86,35.38)
  BOTTOM w0.254: CPU1.AL1 109.82,36.71 109.82,35.67 109.5,35.35 108.89,35.35 v2(108.86,35.38)
+VCCFUSEPRG: length 8.4
  TOP w0.152: 123.3,45.31 123.3,46.09 123.02,46.37 122.68,46.37 v2(122.22,46.83)
  TOP w0.254: 123.3,45.31 123.3,45.17 123.92,44.54 124.84,44.54 125.18,44.2 v1(125.18,42.3) 125.13,42.26 123.99,42.26 R703.1
  BOTTOM w0.254: CPU1.G20 121.92,47.29 122.22,46.98 v2(122.22,46.83)
+VCCGT: length 12.3
  BOTTOM w0.114: CPU1.BB57 103.45,68.95 103.45,68.95 103.36,68.95 102.13,68.95 v2(102.03,69.05)
  BOTTOM w0.127: v2(126.49,68.98) 126.49,68.98 CPU1.A58 ; v2(102.79,74.1) 102.96,73.93 CPU1.BB66
  BOTTOM w0.152: CPU1.AU63 106.45,71.97 106.73,71.7 v2(106.73,70.67)
  BOTTOM w0.178: v2(126.46,73.88) 126.44,73.85 125.67,73.85 CPU1.A66
  BOTTOM w0.203: v2(110.94,77.79) 110.77,77.62 CPU1.AK70 ; CPU1.A53 125.75,66.67 v2(126.21,66.67)
  BOTTOM w0.254: CPU1.AK45 110.59,61.92 v2(111.12,62.45) ; CPU1.A62 126.12,71.46 v2(126.13,71.44) ; CPU1.AK43 111,60.6 v3(111.12,60.6) ; CPU1.AK58 110.62,69.23 111,68.85 v3(111,68.77) ; CPU1.AU58 106.4,69.15 106.75,68.8 107.21,68.8 107.29,68.72 v2(107.39,68.72) ; v2(126.24,63.98) 126.23,63.98 126.15,64.06 125.63,64.06 CPU1.A48
  vias: v1(115.67,97.63) v1(121.99,91.41) v1(123.19,93.01) v2(113.36,77.94) v2(114.75,77.47) v2(114.74,76.7) v2(114.73,72.13) v2(115.64,72.15) v2(115.65,76.7) v2(115.65,74.09) v2(116.58,77.47) v2(117.48,76.7) v2(117.48,75.4) v2(117.48,74.09) v2(117.48,72.79) v2(118.41,77.49) v3(111.05,63.29) v3(113.48,88.56) v3(113.49,87.6) v3(113.46,86.58) v3(113.47,85.44) v3(113.47,84.42) v3(114.6,88.99) v3(114.6,87.98) v3(114.6,87.09) v3(114.6,85.82) v3(114.6,84.93) v3(114.6,83.91) v3(114.6,83.02) v3(115.26,65.5) v3(116.24,88.89) v3(116.23,85.72) v3(116.24,84.83) v3(116.23,81.78) v3(116.24,80.89) v3(116.15,65.52) v3(116.25,87.98) v3(116.25,87.09) v3(116.25,83.91) v3(116.25,83.02) v3(116.25,79.98) v3(116.25,79.09) v3(117.04,65.5) v3(117.3,88.89) v3(117.27,87.98) v3(117.27,87.09) v3(117.28,85.72) v3(117.3,84.83) v3(117.27,83.91) v3(117.27,83.02) v3(117.28,81.78) v3(117.3,80.89) v3(117.27,79.98) v3(117.27,79.09) v3(118.19,88.89) v3(118.16,87.98) v3(118.16,87.09) v3(118.17,85.72) v3(118.19,84.83) v3(118.16,83.91) v3(118.16,83.02) v3(118.17,81.78) v3(118.19,80.89) v3(118.16,79.98) v3(118.16,79.09) v3(120.32,69.82) v3(120.32,68.93) v3(120.32,68.04) v3(120.32,67.15) v3(120.32,66.26) v3(120.32,65.37) v3(128.9,94.56) v3(129.34,98.52) v3(129.34,97.6) v3(129.34,96.71) v3(129.61,93.95) v3(129.69,95.77) v3(129.67,94.94) v3(130.2,98.54) v3(130.2,97.63) v3(130.2,96.74) v3(131.04,98.54) v3(131.04,97.63) v3(131.04,96.74) v3(131.6,92.04) v3(131.9,98.54) v3(131.9,97.63) v3(131.9,96.74) v3(132.46,92.07) v3(132.74,98.54) v3(132.74,97.63) v3(132.74,96.74) v3(133.07,91.18) v3(133.32,92.09) v3(133.58,98.54) v3(133.58,97.63) v3(133.58,96.74) v3(133.96,91.25) v3(134.67,90.72) v3(136.57,72.48) v3(137.21,77.13) v3(137.21,76.29) v3(137.49,83.81) v3(137.49,82.92) v3(137.49,82.03) v3(137.46,72.48) v3(137.64,77.89) v3(138.1,77.13) v3(138.1,76.29) v3(138.33,83.84) v3(138.33,82.95) v3(138.33,82.06) v3(139.16,83.84) v3(139.16,82.95) v3(139.16,82.06) v3(140,83.84) v3(140,82.95) v3(140,82.06) v3(140.84,83.84) v3(140.84,82.97) v3(140.84,82.08) v3(140.84,81.2)
+VCCIO: length 1.6
  TOP w0.127: 106.48,65.57 106.5,65.6 107.59,65.6 107.62,65.57 ; 107.16,60.09 107.57,60.09
  vias: v1(92.66,71.39) v2(111.17,59.78) v3(111.68,53.94) v3(111.68,53.05) v3(111.68,52.16) v3(112.6,66.62) v3(112.6,65.73)
+VCCIO_SIP:
  vias: v1(94.99,89.35)
+VCCMPHYGTAON_1P0_LS_SIP: length 2.3
  BOTTOM w0.254: v2(112.52,48.07) 112.87,48.42 112.93,48.42 CPU1.AF21
  BOTTOM w0.305: v2(112.52,48.07) 112.82,47.77 CPU1.AF20 ; v2(117.57,48.1) 117.23,47.77 CPU1.T20 CPU1.T19
  vias: v1(94.79,36.14) v2(119.47,43.98) v3(88.85,26.33) v3(88.92,25.49) v3(90.07,33.72) v3(96.32,35.5) v3(96.67,14.29) v3(97.56,14.29)
+VCCPAZIO: length 82.1
  L4 w0.254: v2(58.85,19.52) 58.85,18.08 55.5,14.72 55.5,8.98 v2(54.91,8.4)
  L6 w0.254: 109.75,44.59 110.54,45.38 110.54,47.13 111.99,48.58 v2(111.99,49.01) ; 106.2,43.58 105.87,43.58 102.03,39.74 100.63,39.74 97,36.11 94.56,36.11 90.73,32.27 86.54,32.27 78.59,24.32 76.91,24.32 73.84,21.25 72.03,21.25 70.76,19.98 69.92,19.98 68.37,18.43 67.03,18.43 65.5,19.96 65.33,19.96 65.15,20.13 61.24,20.13 61.06,19.96 59.28,19.96 v2(58.85,19.52)
  BOTTOM w0.254: R2101.2 54.93,9.05 54.23,9.74 v1(54.23,10) ; R2101.2 55.95,9.05 R2102.2 ; R2101.2 55.17,8.7 54.91,8.45 v2(54.91,8.4) ; v2(111.99,49.01) 111.99,48.86 111.63,48.51 111.63,47.5 CPU1.AJ19
+VCCPDSW_3P3: length 82.6
  L4 w0.254: v2(61.47,19.63) 61.29,19.45 61.29,10.81 61.44,10.66 v2(61.44,10.56) ; v2(114.55,49.04) 114.5,48.99 114.5,47.74 111.05,44.29 v2(111.05,44)
  L6 w0.254: 106.27,41.93 105.71,41.93 103.02,39.23 101.01,39.23 96.32,34.54 94.03,34.54 91.39,31.89 86.71,31.89 78.33,23.51 77.8,23.51 76.6,22.32 75.46,22.32 74.01,20.87 72.23,20.87 70.97,19.61 70.97,19.08 69.93,18.05 66.85,18.05 65.33,19.57 61.52,19.57 v2(61.47,19.63) ; v2(111.05,44) 111.01,44 110.56,43.55 110.56,42.97 110.34,42.74
  BOTTOM w0.203: v2(111.05,44) 110.86,44.19 110.86,45.35 111.26,45.74 CPU1.AJ17
  BOTTOM w0.229: v2(114.55,49.04) 114.55,48.89 114.2,48.53 114.2,46.9 CPU1.AD18
  BOTTOM w0.254: CPU1.AD17 CPU1.AD18 ; v1(59.66,7.32) 60.02,7.69 60.17,7.69 60.63,8.14 R1707.1 60.63,8.2 61.05,8.61 R1711.2 61.05,10.06 61.44,10.46 v2(61.44,10.56)
+VCCPRIM_CORE: length 4.2
  BOTTOM w0.254: v2(113.28,49.04) 113.38,48.94 113.38,47.67 112.93,47.22 CPU1.AF19
  BOTTOM w0.305: CPU1.V20 CPU1.V21 116.21,48.42 116,48.63 v2(116,49.01) ; CPU1.AF18 CPU1.AF19
  vias: v1(93.78,18.36) v3(93.01,19.85) v3(93.85,19.83) v3(96.24,28.69) v3(98.4,35.25)
+VCCPRTC_3P3: length 97.4
  TOP w0.203: C2118.1 111.48,49.7 110.87,49.09 110.87,48.89 110.78,48.8
  TOP w0.254: v2(109.33,46.83) 109.31,46.85 C2117.1 109.31,47.88 109.78,48.35 110.34,48.35 110.78,48.8 ; v2(73.43,2.96) 72.36,2.96 v1(72.03,3.29) R2106.2
  L3 w0.229: 106.86,48.23 106.88,48.2 108.91,48.2 109.33,47.79 v2(109.33,46.83)
  L3 w0.254: v2(73.38,18.61) 73.4,18.58 74.14,18.58 74.48,18.93 76.44,18.93 76.68,18.69 77.14,18.69 78.18,19.73 81.2,19.73 81.88,20.4 86.98,20.4 87.96,19.42 91.39,19.42 91.59,19.22 94.7,19.22 97.19,21.71 97.84,21.71 98.19,22.06 98.19,23.83 99.08,24.72 99.08,28.24 97.43,29.89 97.43,31.49 98.24,32.3 100.02,32.3 101.46,33.75 102.32,33.75 103.38,34.8 103.38,42.51 v2(101.47,44.42) 101.5,44.44 102.44,44.44 104.08,46.09 104.08,46.97 105,47.9 106.2,47.9 106.53,48.23 106.86,48.23
  L4 w0.254: v2(73.43,2.96) 73.43,4.86 74.14,5.57 74.14,10.41 73.12,11.42 73.12,12.89 75.13,14.9 75.13,18.64 74.17,19.6 73.6,19.6 73.3,19.3 73.3,18.69 v2(73.38,18.61)
  BOTTOM w0.127: CPU1.BB14 103.6,44.37 102.84,44.37 102.84,44.36 101.88,44.36 101.82,44.42 v2(101.47,44.42)
  BOTTOM w0.254: v2(109.33,46.83) 109.35,46.8 110.03,46.8 110.35,47.12 CPU1.AK19
+VCCSA:
  vias: v1(134.75,55.62) v2(111.5,51.2) v2(111.48,50.36) v2(125.5,50.44) v2(126.23,50.49) v2(126.85,51.81) v3(112.65,52.04) v3(113.54,52.04) v3(114.48,52.05) v3(115.37,52.05) v3(116.64,52.05) v3(120.36,52.16) v3(131.42,57.27) v3(131.42,56.25) v3(131.39,55.31) v3(132.26,57.5) v3(132.26,56.48) v3(132.26,55.46) v3(132.28,54.58) v3(133.15,57.5) v3(133.15,56.48) v3(133.15,55.46) v3(133.17,54.58)
+VCCSFR: length 55.1
  TOP w0.254: C721.1 C720.1 120.86,48.04 120.06,48.84 v2(120.06,49.06) ; v2(124.33,24.83) v1(124.33,24.25)
  L4 w0.254: v2(120.06,49.06) 120.53,48.59 120.53,44.35 120.45,44.26 120.45,42.98 120.83,42.59 124.07,42.59 124.97,41.7 124.97,38.32 124.1,37.46 124.1,32.76 124.99,31.87 124.99,26.85 124.13,25.98 124.13,25.98 123.75,25.59 123.75,25.09 124,24.83 v2(124.33,24.83)
  L6 w0.254: v2(124.33,24.83) 124.28,24.78 124.28,24.68 123.19,23.59 120.62,23.59 120.22,23.18 120.22,22.39 120.11,22.29 120.11,18.94 116.84,15.66 116.41,15.66 115.09,14.34 115.09,13.89 114.6,13.4 112.85,13.4 112.34,13.91 v2(112.34,14.37)
  BOTTOM w0.254: R4038.2 112.09,14.7 112.34,14.44 v2(112.34,14.37) ; CPU1.K20 120.55,47.84 120.55,48.35 CPU1.K21 120.48,48.65 v2(120.06,49.06)
+VCCST_CPU: length 183.5
  TOP w0.254: v2(154.23,107.15) 154.25,107.13 PR4624.1 PR4622.1 PR4621.1 158.33,103.85 159.13,103.85 159.56,103.42 v2(159.56,103.34) ; C716.1 126.31,46.33 v2(126.58,46.61) 126.58,46.64 125.4,47.82 125.4,49.47 125.86,49.93 v2(126.57,49.93)
  L4 w0.254: v2(124.36,25.47) 125.37,26.48 125.37,32.05 124.53,32.88 124.53,37.23 125.35,38.04 125.35,44.64 126.58,45.88 v2(126.58,46.61) ; v2(134.67,72.61) 134.03,72.61 133.85,72.43 133.85,70.88 134.8,69.94 136.04,69.94 139.72,73.63 151.1,73.63 151.97,72.76 151.97,71.82 152.37,71.42 156.72,71.42 157.22,71.92 163.22,71.92 166.07,74.78 v2(166.57,74.78)
  L6 w0.254: v2(154.23,107.15) 157.1,107.15 157.17,107.08 159.1,107.08 159.31,107.28 162.66,107.28 163.6,106.34 163.6,105.59 166.32,102.87 166.32,101.28 170.07,97.53 171.43,97.53 172.01,96.95 172.01,95.78 172.34,95.45 172.34,95.03 172.01,94.71 171.25,94.71 170.23,93.69 170.23,86 172.11,84.12 172.11,84 172.11,83.13 171.65,82.67 171.65,78.31 168.12,74.78 v2(166.57,74.78) ; v2(134.67,72.61) 134.03,71.97 134.03,65.07 130.66,61.69 v2(129.92,61.69) ; v2(112.98,14.37) 112.98,14.14 113.33,13.78 114.4,13.78 114.65,14.04 114.65,14.47 116.28,16.09 116.71,16.09 119.73,19.12 119.73,22.47 119.84,22.57 119.84,23.36 120.65,24.17 123.21,24.17 123.59,24.55 123.59,24.87 124.2,25.47 v2(124.36,25.47) ; v2(127.91,53.79) 127.44,53.32 127.44,50.75 126.62,49.93 v2(126.57,49.93)
  BOTTOM w0.152: v2(126.58,46.61) 126.51,46.68 CPU1.A18
  BOTTOM w0.254: PC4610.1 159.62,103.28 v2(159.56,103.34) 159.47,103.43 PR4623.1 ; v2(127.91,53.79) 127.91,54.35 128.9,55.34 128.9,58.34 129.56,59 v1(129.56,60.7) 129.56,61.33 v2(129.92,61.69) ; v2(112.98,14.37) 112.98,14.6 111.99,15.59 R4036.2 ; R603.2 133.89,76.04 R419.1 R727.1 R723.1 133.89,72.66 R726.1 134.64,72.64 v2(134.67,72.61)
+VCCSTG: length 319.2
  TOP w0.114: R703.2 122.43,42.36 123.09,41.7 123.44,41.7
  TOP w0.254: v2(67.36,18.94) 67.36,18.89 67.67,18.58 71.5,18.58 72.52,19.6 75.21,19.6 76.58,20.97 v2(76.58,23.16) ; v2(153.34,107.15) 153.36,107.13 PR4669.1 ; v2(127.56,77.18) 127.81,76.93 v2(129.84,76.93) ; v2(126.24,49.32) 126.24,48.15 127.23,47.16 127.23,46.21 125.83,44.81 125.83,41.8 125.7,41.67 125.7,39.41 124.97,38.68 124.14,38.68 C717.1 125.09,40.11 125.09,41.19 124.59,41.7 123.44,41.7 ; v2(99.18,91.62) 99.18,90.34 98.66,89.82 C4008.1 96.21,90.56 R4042.2
  L3 w0.254: v2(127.56,77.18) 127.56,76.39 126.71,75.54 125.99,75.54 124.69,76.85 124.4,76.85 122.99,78.27 122.99,84.09 123.24,84.34 123.24,88.49 120.65,91.08 107.95,91.08 106.75,92.28 99.84,92.28 v2(99.18,91.62) 98.99,91.81 98.5,91.81 97.61,92.7 88.47,92.7 88.09,92.32 86.51,92.32 86.13,92.7 84.07,92.7 v2(83.13,91.76)
  L4 w0.254: v2(129.84,76.93) 131.2,75.58 131.2,72.44 132.17,71.47 v2(132.26,71.47) 132.66,71.47 134.57,69.56 136.37,69.56 140.05,73.24 150.93,73.24 151.59,72.58 151.59,71.98 151.59,71.66 152.21,71.04 156.87,71.04 157.38,71.54 163.42,71.54 166.02,74.14 v2(166.57,74.14) ; v2(67.36,18.94) 67.31,18.94 66.75,18.38 64.74,18.38 64.46,18.1 64.46,16.01 64.17,15.71 64.04,15.71 63.1,14.78 63.1,8.35 62.54,7.79 v2(62.51,7.79)
  L6 w0.254: v2(128.45,54.19) 128.45,53.38 127.94,52.87 127.94,50.54 126.72,49.32 v2(126.24,49.32) ; v2(166.57,74.14) 168.03,74.14 174.83,80.94 175.39,80.94 177.24,82.8 177.24,93.77 176.88,94.12 176.2,94.12 176.17,94.1 174.51,94.1 173.02,95.59 173.02,96.49 171.61,97.91 170.23,97.91 166.7,101.44 166.7,102.71 166.7,103.03 163.98,105.75 163.98,106.5 162.82,107.66 159.05,107.66 158.85,107.46 157.45,107.46 157.25,107.66 153.97,107.66 153.47,107.15 v2(153.34,107.15)
  BOTTOM w0.254: v2(76.58,23.16) 76.58,24.07 77.06,24.55 79.27,26.76 79.27,49.24 81.38,51.35 81.38,52.27 80.8,52.85 80.8,54.95 84.36,58.52 84.36,90.15 83.13,91.38 v2(83.13,91.76) ; CPU1.A22 125.75,49.32 v2(126.24,49.32) ; v2(129.84,76.93) 129.89,76.98 R401.1 ; v2(132.26,71.47) 132.21,71.52 R423.2 131.63,71.47 R421.2 131.63,70.31 131.58,70.26 R416.2 131.61,68.7 R417.2 R408.2 131.61,66.59 R409.2 R422.2 131.91,65.19 130.89,64.17 130.89,62.86 130.9,62.85 130.9,62.78 130.89,62.79 130.89,59.79 v1(130.63,59.53) 129.28,58.18 129.28,55.08 128.45,54.25 v2(128.45,54.19) ; R1722.1 63.23,8.16 62.86,7.79 v2(62.51,7.79)
+VDDQ_CPU_CLK: length 17.4
  TOP w0.254: v2(109.36,59.63) 110.21,59.63 C715.1 ; R705.2 95.2,56.13 v1(96.16,55.16) 99.03,55.16 99.97,56.1 v2(99.97,56.15)
  L4 w0.152: 108.96,60.04 108.94,60.06 107.29,60.06
  L4 w0.254: 106.53,59.2 106.42,59.2 104.39,57.17 100.98,57.17 100.14,56.32 100.14,56.32 v2(99.97,56.15)
  BOTTOM w0.254: CPU1.AM40 109.65,59.34 v2(109.36,59.63)
AV1_TP: length 1.3
  TOP w0.102: TP2307.1 105.69,35.7 v2(105.66,35.73)
  BOTTOM w0.102: v2(105.66,35.73) 105.77,35.84 CPU1.AV1
AV71_TP: length 3.3
  TOP w0.102: v2(104.6,77.87) 104.7,77.87 104.81,77.77 104.82,77.77 TP2304.1
  BOTTOM w0.102: CPU1.AV71 105.7,77.07 104.97,77.79 104.79,77.79 104.7,77.87 v2(104.6,77.87)
DVSS: length 2.6
  TOP w0.102: R2732.1 28.76,17.21 v1(27.44,17.21) 27.34,17.31 HDA27.7
GND: length 1777.8
  TOP w0.203: U5701.8 v2(26.08,66.84) ; U5701.15 22.85,66.97 v2(22.66,66.77) ; v2(197.5,37.23) 197.5,36.98 197.84,36.64 198.75,36.64 KBC24.17 ; KBC24.64 184.81,44.19 184.53,44.19 184.25,44.47 v2(184.25,44.67) ; U5701.35 22.45,62.7 v2(22.76,62.4) ; KBC24.84 182.35,35.04 v2(182.09,35.3) ; 195.61,27.38 KBC24.124 195.61,29.5 194.96,30.14 194.22,30.14 193.64,30.73 v2(193.6,30.73) ; v2(186.46,29.89) 186.33,29.89 186.01,29.56 KBC24.100 ; KBC24.51 190.01,43.39 189.76,43.15 189.51,43.15 189.05,42.69 v2(189.05,42.61)
  TOP w0.254: v2(58.01,89.17) 57.54,89.64 EC5504.2 ; v1(195.71,10.63) 199.57,10.63 v2(199.82,10.38) ; v2(57.66,91.79) 57.66,91.19 EC5503.2
  TOP w0.305: RN1602.3 113.26,20.08 v2(113.51,19.83) 113.64,19.83 113.91,20.1 RN1602.4 ; PR4451.2 137.93,28.5 137.26,27.83 v2(137.18,27.83) ; U6901.47 36.92,33.33 v2(36.88,33.37) ; RN1301.2 51.89,38.93 52.54,38.93 v2(52.54,38.93) ; EU3804.3 16.43,93.25 16.61,93.44 v2(16.95,93.44) ; U6901.8 34.76,28.17 v2(34.64,28.06) ; U6901.23 41.41,24.87 41.7,24.58 v2(42.25,24.58) ; v2(20.5,31.08) EU3603.3 ; v2(176.02,16.12) 175.78,16.36 U6002.5 ; 22.59,41.63 23.47,42.51 ED3801.3 ; U6901.35 43.55,31.17 v2(43.56,31.18)
  TOP w0.356: v2(181.94,24.45) 181.91,24.45 181.84,24.53 R2454.2 ; v2(175.69,13.94) U6001.3 U6001.8
  TOP w0.381: v2(115.23,41.4) 115.39,41.4 115.8,40.99 115.8,39.54 R1901.2 ; R3815.1 39.25,57.88 v2(39.67,57.88)
  TOP w0.406: v2(31.27,72.48) 30.57,71.79 PQ4308.4 ; EU3801.3 v2(13.13,91.28) ; PQ4307.4 35.94,72.02 v2(35.96,72.04) ; v2(44.58,90.26) 44.85,89.98 PQ4309.1 ; v2(193.44,20.41) 193.47,20.44 ED6301.8 ED6301.3 ; v2(32.64,72.1) 32.63,72.1 32.36,71.83 PQ4310.4 ; v2(100.53,91.51) 100.53,91.94 100.93,92.33 U4004.5 102.33,92.82 C4011.2 ; v2(40.23,87.34) 40.54,87.04 42.16,87.04 43.1,87.98 PQ4311.1 ; PQ4311.4 40.65,89.49 v2(40.26,89.09) ; PQ4308.1 v2(29.27,68.75) ; PQ4309.4 47.44,88.19 47.64,88.38 v2(47.72,88.38) 47.98,88.64 PR4324.2 ; PQ4310.1 34.76,70.16 35.34,69.57 v2(36.07,69.57) ; v2(20.55,53.26) 20.5,53.31 EU3601.3 ; EU3803.3 v2(13.08,95.09) ; v2(162.28,24.6) 162.17,24.72 162.17,26.88 162.29,27 EC4309.2 ; EU3802.3 v2(14.91,98.52) ; C3713.2 26.69,44.58 26.48,44.37 v2(26.39,44.37) ; PQ4307.1 v2(37.82,69.57)
  TOP w0.432: v2(30.63,46.88) 31.15,46.88 C3703.2
  TOP w0.457: C3819.2 32.93,65.82 v2(32.92,65.8)
  TOP w0.508: v2(34.31,36.54) 34.34,36.54 34.53,36.73 C3705.1 R3704.1 ; C3816.2 28.54,62.6 v2(27.61,62.6) ; C6902.2 32.61,28.4 v2(32.61,28.95) ; HDMI1.20 12.54,67.33 ; HDMI1.20 11.1,68.32 ; HDMI1.20 11.1,66.34 ; 12.5,70.58 HDMI1.2 11.85,70.01 ; EC2708.2 32.23,19.96 v2(32.31,20.03) ; C1210.2 70.84,69.46 v2(70.67,69.63) ; v2(19.56,76.24) 19.56,75.99 19.53,75.96 PR4302.2 ; C3706.2 v2(32.94,36.03) ; USB2.12 6.5,62.17 ; C1214.2 70.89,79.8 v2(70.84,79.85) ; 3.52,88.13 USB1.13 2.19,87.3 ; C1203.2 64.9,61.54 v2(65.59,62.23) ; v2(156.97,49.67) 157.48,49.67 157.49,49.69 PR4442.2 ; PC4531.2 PR4513.2 98.04,100.33 98.04,100.98 PR4551.2 98.14,101.11 98.63,101.59 v2(98.96,101.59) ; 6.27,91.01 USB1.B12 6.85,90.02 ; v2(57.52,36.8) 57.78,36.54 C1318.2 ; PD4301.A 21.89,78.93 v2(21.72,79.11) ; v2(52.46,64.99) 52.46,65 C1315.2 ; C6008.2 171.28,18.23 v2(170.64,18.23) ; v2(57.52,80.05) 57.54,80.03 C1321.2 ; PC1115.2 v2(49.5,48.84) ; v2(31.34,9.37) 30.96,9.75 30.96,10.24 EC8914.2 ; 22.59,41.63 22.38,41.42 22.38,39.97 v2(21.84,39.44) ; v2(141.02,37.41) 141.02,38.19 141.65,38.83 PC4428.2 ; EC1807.2 68.69,6.46 68.4,6.75 68.12,6.75 v2(68.04,6.82) ; v2(109.33,57.8) 109.45,57.8 110.01,58.36 C715.2 ; EC5505.2 53.68,99.84 C5515.2 52.6,99.84 v2(51.92,100.52) ; R3821.1 38.7,56.23 v2(39.67,56.23) ; v2(14.7,96.79) 14.91,96.79 14.97,96.85 R3830.2 ; v3(161.75,33.37) v3(162.79,33.37) 163.09,33.67 163.73,33.67 164.16,33.24 164.16,33.19 164.7,32.64 EC6603.2 ; v2(152.24,99.1) 152.2,99.15 152.2,99.53 152.45,99.79 PG4601.2 ; v2(19.56,96.64) 19.71,96.79 R3716.2 ; v2(122.13,66.94) 121.49,67.58 R601.2 ; v2(88.11,93.92) 88.11,92.98 87.72,92.59 C4032.2 87.68,91.47 C4033.2 ; EC1712.2 68.77,11.22 v2(69.39,11.22) ; v2(45.72,97.3) 45.71,97.3 44.68,98.33 44.68,100.22 45.01,100.55 PR5420.2 ; v2(113.33,70.63) 113.27,70.69 R725.2 ; PR4323.2 37.85,69.54 v2(37.82,69.57) ; C3702.2 26.25,39.88 v2(26.54,39.59) 26.8,39.84 C3701.2 ; C1209.2 70.84,41.06 v2(70.74,40.96) ; C1218.2 66.27,32.71 v2(66.3,32.74) ; v2(65.81,8.17) 65.86,8.12 66.09,8.12 66.38,7.83 EC1705.2 66.81,8.04 67.07,8.04 67.28,8.26 C1710.2 ; C1306.2 59.84,55.01 v2(60.68,55.85) 60.17,56.35 C1307.2 ; v2(36.19,19.22) 36.4,19.02 38.66,19.02 39.35,19.71 SPR3.1 ; R3802.1 35.76,63.97 v2(35.91,64.13) ; C3818.2 34.75,53.66 v2(34.42,53.33) ; v3(148.64,56.99) 148.64,57.05 149.08,57.5 PC5031.2 ; USB3.11 16.63,26.03 ; USB3.11 14.95,26.92 ; USB3.11 14.95,25.14 ; v2(90.98,47.34) 90.46,46.82 EC1901.1 ; C1304.2 57.71,42.31 v2(57.3,42.71) 58.24,43.65 C1305.2 ; ED2903.2 17.41,22.83 17.82,23.23 ED2904.2 18.63,24.25 ED2905.2 18.63,25.28 v2(18.64,25.29) ; TP6901.1 43.61,35.68 v2(43.94,36.01) ; 7.3,89.73 USB1.15 ; USB1.15 8.39,88.95 ; USB1.15 9.48,89.73 ; USB1.21 7.39,100.28 ; USB1.21 6.06,101.12 ; USB1.21 4.72,100.28 ; USB1.21 6.06,99.45 ; C6906.2 v2(37.03,35.46) ; R6910.1 R6908.1 v2(39.55,21.73) ; PC4431.2 142.34,41.1 v2(142.34,41.6) ; C6909.2 34.21,31.91 v2(34.24,31.88) ; EC1902.2 92.45,45.99 v2(92.38,45.91) ; C1205.2 72.97,54.9 v2(73.81,55.74) 73.24,56.31 C1219.2 ; C1215.2 62.36,74.36 62,74.01 v2(62,73.6) ; v2(52.36,73.72) 52.23,73.59 C1319.2 ; v2(28.83,52.01) 28.6,52.24 R3823.1 R3803.2 ; C2416.2 C2421.2 200.77,31.14 v2(202.21,32.58) ; v2(39.67,62.07) 38.77,62.07 C3817.2 ; v2(35.96,72.04) 36.1,72.18 PR4332.2 PC4311.2 ; 16.74,85.49 17.11,85.12 C7002.2 17.11,83.89 C7001.2 ; EC8910.2 46.89,32.83 v2(46.35,33.37) C6904.2 ; C1316.2 52.3,30.28 v2(52.36,30.22) ; v2(167.8,46.43) 168.5,46.43 EC6602.2 ; R1901.2 115.71,39.45 115.71,38.93 R1603.2 ; v2(65.81,40.96) 65.28,41.49 C1217.2 ; v2(100.53,91.51) 100.53,90.42 99.05,88.93 C4008.2 ; v3(149.66,97.5) 149.38,97.22 EC8929.2 ; R3819.1 28.07,58.79 v2(27.91,58.64) ; EC1801.2 EC1802.2 92.54,27.11 v2(92.96,26.69) ; 10.8,83.58 HS1.1 ; HS1.1 10.8,89.44 ; HS1.1 13.73,86.51 ; C1206.2 71.29,61.59 v2(70.92,61.21) ; v2(94.26,80.41) 93.97,80.12 R602.2 ; C6907.2 v2(34.82,35.46) ; v2(30.58,44.01) 30.21,44.38 C3704.2 ; C1202.2 62.99,65.42 v2(62.59,65.83) ; v2(23.01,61.81) 23.23,61.6 R5414.1 ; v2(70.76,36.62) 70.81,36.57 C1220.2 ; v2(130.94,19.96) 130.54,20.35 C6504.2 130.3,20.35 R6508.2 ; USB3.10 14.95,39.72 ; USB3.10 16.63,38.83 ; USB3.10 14.95,37.94 ; C4015.2 95.64,93.76 v2(95.88,94) ; v2(114.17,43.44) 113.96,43.44 113.54,43.86 C2107.2 ; v2(134.95,23.56) 135.37,23.14 C2609.2 C2608.2 ; 7.3,98.68 USB1.20 8.39,99.47 ; HDMI1.23 6.04,83.73 ; HDMI1.23 4.6,84.72 ; HDMI1.23 3.16,83.73 ; R4301.1 166.27,24.52 166.27,25.04 v2(166.29,25.06) ; v2(31.85,24.22) R6916.1 R6918.1 ; PC4302.2 22.83,75.43 22.4,75 v2(22.4,74.77) 22.55,74.62 PR4308.2 ; v2(38.25,36.08) 37.77,35.6 R6907.2 ; v2(76.63,10.61) 76.63,13.39 C4028.2 C4029.2 ; EC8907.2 49.5,14.18 49.5,13.81 48.33,12.64 v2(48.33,12.59) ; EC8908.2 157.71,21.94 v2(157.53,21.76) ; v2(52.54,84.69) 52.31,84.93 C1322.2 ; PR4315.1 29.11,90.5 29.11,91.63 v2(28.55,92.19) ; v2(44.4,46.68) 44.31,46.59 EC8911.2 ; USB1.14 6.06,88.97 ; USB1.14 4.72,88.13 ; USB1.14 7.39,88.13 ; USB1.14 6.06,87.3 ; PR4328.1 31.27,73.07 v2(31.27,72.48) ; HDMI1.21 11.1,82.82 ; HDMI1.21 12.54,81.83 ; HDMI1.21 11.1,80.84 ; R1825.2 95.4,32.53 v2(95.6,32.73) ; 5.33,23.79 6.12,24.58 USB3.13 7.21,24.58 7.85,23.94 ; EC8913.2 25.32,75.95 v2(25.32,75.48) ; SPR1.1 115.3,89.51 v2(115.47,89.35) ; v2(20.83,95.32) 21.14,95 C3821.2 ; EC2910.2 15.5,3.26 15.17,2.93 EC2912.2 14.06,2.93 v2(13.49,3.5) ; v2(62.76,56.53) 63.09,56.2 C1204.2 ; v2(174.17,18.74) 174.15,18.75 C6009.2 C6010.2 ; C717.2 123.48,39.81 v2(122.86,40.43) ; v2(118.4,72.8) 117.87,72.27 C1104.2 ; PR4313.2 21.61,82.22 v2(21.61,83.25) ; v2(66.47,43.32) 66.47,43.6 66.11,43.96 64.83,43.96 R1212.2 ; v2(77.44,100.55) 77.62,100.37 C5502.2 ; 6.85,98.4 USB1.B1 6.27,97.41 ; v2(84.48,100.75) 84.45,100.73 84.45,98.7 83.95,98.19 U5501.2 ; 6.5,43.68 USB2.13 6.91,45.18 7.8,44.29 ; v2(60.63,63.21) 59.89,62.48 C1303.2 ; C1317.2 54.52,27.17 v2(54.52,26.46) ; R1309.2 50.2,45.1 R1311.2 50.2,47.1 C1308.2 v2(49.5,47.18) ; X6901.4 v2(32.07,33.7) ; R3831.2 14.98,93.83 v2(14.98,93.64) ; v2(166.29,25.06) 166.29,25.3 EC4306.1 ; v2(166.29,25.06) 167.36,26.13 167.36,27.22 167,27.57 166.54,27.57 166.34,27.37 EC4310.2 ; EC6601.2 169.2,35.96 v2(169.85,35.96) ; AFTP2604.1 153.47,77.31 v2(154.86,75.91) ; v2(49.63,60.11) 49.36,59.85 ED1217.2 ED1302.2 ; PR4512.2 PC4530.2 94.71,102.77 v2(94.98,102.51) 95.15,102.51 95.17,102.48 PR4530.2 ; v2(122.87,46.83) 123.29,46.83 123.68,47.22 C716.2 ; EC8928.2 139.65,107.18 v2(139.37,106.9) ; R407.2 123.9,68.24 v2(123.54,67.88) ; 3.52,100.28 USB1.22 2.19,101.12 ; C6007.2 176.36,15.78 v2(176.02,16.12) ; C2103.2 109.79,36.8 R1502.2 108.77,36.54 108.88,36.43 108.88,36.26 v2(109.26,35.88) ; C6903.2 30.07,26.51 v2(29.84,26.74) ; v2(49.45,58.59) 49.48,58.56 C1310.2 ; C2718.2 v2(28.37,23.58) ; EC8927.2 122.06,107.8 EC8915.2 v2(120.11,108.45) ; USB2.11 14.95,47.52 ; USB2.11 16.63,46.63 ; USB2.11 14.95,45.74 ; v2(122.87,49.57) 123.39,49.57 123.89,49.08 R734.2 ; X6901.2 v2(30.56,29.11) ; EC8916.2 v2(133.78,105.12) ; R731.2 110,70.36 v2(109.33,69.69) ; EC2701.2 30.62,15.51 C2723.1 31.13,15.45 v2(31.39,15.71) ; 15.7,48.77 USB2.4 16.46,49.53 ; v2(72.69,96) 72.69,96.36 72.77,96.44 72.77,97.55 71.68,98.64 EC8917.2 ; C3711.2 v2(32.18,49.45) ; R1501.2 122.87,43.18 v2(122.87,43.17) ; 16.46,28.93 USB3.4 15.7,28.17 ; C6905.2 30.59,27.82 v2(30.94,28.16) ; v2(34.24,29.1) 34.12,29.21 C6908.2 ; HDMI1.22 6.04,65.43 ; HDMI1.22 3.16,65.43 ; HDMI1.22 4.6,64.44 ; C1301.2 v2(49.58,42.26) ; v2(91.44,36.26) 91.44,36.31 90.61,37.14 C2112.2 ; EC8904.2 v2(21.56,25.07) ; EC4425.2 159.12,45.5 v3(159.18,45.43) ; v2(138.53,17.01) 138.64,17.12 C6501.2 ; v2(46.73,25.49) 45.83,25.49 C6901.2 ; USB2.10 14.95,60.32 ; USB2.10 16.63,59.43 ; USB2.10 14.95,58.54 ; C1329.2 50.29,25.47 R1216.2 49.43,26.74 v2(49.38,26.79) 49.31,26.79 EC8909.2 ; C2405.2 178.42,32.59 177.82,32 v2(177.82,31.74) 177.98,31.59 C2406.2 ; 7.8,40.99 7.09,40.28 USB3.12 6.5,41.47 ; v2(31.39,17.06) 30.85,17.06 EC2709.2 30.62,17.29 R2732.2 ; C1309.2 v2(49.55,54.02) ; v2(19.38,97.86) 19.63,97.6 C3708.2 ; v2(60.48,70.69) 59.88,71.3 C1320.2 ; C3815.2 v2(42.16,58.26)
  L3 w0.508: HDMI1.5 10.99,72.08 ; 6.5,43.83 USB2.13 6.96,45.18 7.72,44.42 ; USB1.14 7.39,88.13 ; USB1.14 4.72,88.13 ; USB1.14 6.06,87.3 ; USB1.14 6.06,88.97 ; 3.52,88.13 USB1.13 2.19,87.3 ; 7.3,89.73 USB1.15 ; USB1.15 8.39,88.95 ; USB1.15 9.48,89.73 ; 3.16,65.43 HDMI1.22 ; HDMI1.22 6.04,65.43 ; HDMI1.22 4.6,64.44 ; 14.95,37.94 USB3.10 14.95,39.72 ; USB2.4 16.46,49.53 ; USB2.4 15.7,50.29 ; USB2.4 15.7,48.77 ; 15.7,28.17 USB3.4 ; USB3.4 16.46,28.93 ; USB3.4 15.7,29.69 ; USB3.11 14.95,26.92 ; USB3.11 16.63,26.03 ; USB3.11 14.95,25.14 ; HDMI1.21 12.54,81.83 ; HDMI1.21 11.1,80.84 ; HDMI1.21 11.1,82.82 ; HDMI1.2 12.5,70.58 ; HDMI1.2 11.85,70.01 ; HDMI1.2 11.2,70.58 ; HS1.1 10.8,88.35 ; HS1.1 12.64,86.51 ; HS1.1 10.8,84.67 ; HS1.1 8.96,86.51 ; USB1.21 6.06,101.12 ; USB1.21 4.72,100.28 ; USB1.21 7.39,100.28 ; USB1.21 6.06,99.45 ; 14.95,47.52 USB2.11 14.95,45.74 ; 3.52,100.28 USB1.22 2.19,101.12 ; 7.82,23.97 7.21,24.58 USB3.13 6.17,24.58 5.33,23.74 ; HDMI1.11 10.96,75.08 ; 6.85,98.4 USB1.B1 6.27,97.41 ; USB2.10 14.95,60.32 ; USB2.10 14.95,58.54 ; USB2.10 16.63,59.43 ; 7.3,98.68 USB1.20 8.39,99.47 ; USB3.7 14.96,32.43 ; USB3.7 14.2,31.67 ; USB3.7 14.2,33.19 ; 7.85,41.06 7.06,40.28 USB3.12 6.5,41.62 ; USB2.7 14.96,53.03 ; USB2.7 14.2,52.27 ; USB2.7 14.2,53.79 ; HDMI1.23 6.04,83.73 ; HDMI1.23 3.16,83.73 ; HDMI1.23 4.6,84.72 ; 6.85,90.02 USB1.B12 6.27,91.01 ; 12.5,73.58 HDMI1.8 11.2,73.58 ; 6.5,62.07 USB2.12 6.91,60.88 7.69,61.66 ; HDMI1.20 11.1,68.32 ; HDMI1.20 12.54,67.33 ; HDMI1.20 11.1,66.34
  L4 w0.127: v2(109.33,40.43) 109.32,40.43 108.86,40.89 108.48,40.89 108.03,41.34 v2(108.01,41.34)
  L4 w0.508: 15.7,48.77 USB2.4 ; USB2.4 15.7,50.29 ; USB2.4 16.46,49.53 ; HDMI1.23 6.04,83.73 ; HDMI1.23 3.16,83.73 ; HDMI1.23 4.6,84.72 ; 6.5,62.32 USB2.12 7.04,60.88 7.77,61.61 ; USB1.21 7.39,100.28 ; USB1.21 6.06,99.45 ; USB1.21 6.06,101.12 ; USB1.21 4.72,100.28 ; USB2.7 14.96,53.03 ; USB2.7 14.2,52.27 ; USB2.7 14.2,53.79 ; 5.31,23.77 6.12,24.58 USB3.13 7.19,24.58 7.85,23.92 ; v2(108.03,42.26) 108.03,42.25 108.03,41.35 v2(108.01,41.34) ; 14.95,60.32 USB2.10 14.95,58.54 ; 4.6,64.44 HDMI1.22 ; HDMI1.22 6.04,65.43 ; HDMI1.22 3.16,65.43 ; USB3.11 14.95,26.92 ; USB3.11 16.63,26.03 ; USB3.11 14.95,25.14 ; 11.1,66.34 HDMI1.20 ; HDMI1.20 12.54,67.33 ; HDMI1.20 11.1,68.32 ; 8.39,88.95 USB1.15 7.3,89.73 ; 6.06,87.3 USB1.14 ; USB1.14 7.39,88.13 ; USB1.14 4.72,88.13 ; USB1.14 6.06,88.97 ; USB3.7 14.2,33.19 ; USB3.7 14.2,31.67 ; USB3.7 14.96,32.43 ; USB2.11 14.95,47.52 ; USB2.11 16.63,46.63 ; USB2.11 14.95,45.74 ; 2.19,101.12 USB1.22 3.52,100.28 ; 7.69,44.39 6.91,45.18 USB2.13 6.5,43.93 ; USB3.10 14.95,39.72 ; USB3.10 16.63,38.83 ; USB3.10 14.95,37.94 ; HDMI1.21 12.54,81.83 ; HDMI1.21 11.1,82.82 ; HDMI1.21 11.1,80.84 ; 15.7,28.17 USB3.4 ; USB3.4 15.7,29.69 ; USB3.4 16.46,28.93 ; 6.85,90.02 USB1.B12 6.27,91.01 ; 6.5,41.6 USB3.12 6.89,40.28 7.64,41.04 ; 12.5,73.58 HDMI1.8 11.2,73.58 ; 11.2,70.58 HDMI1.2 ; HDMI1.2 11.85,70.01 ; HDMI1.2 12.5,70.58 ; 7.3,98.68 USB1.20 8.39,99.47 ; 3.52,88.13 USB1.13 2.19,87.3 ; 6.27,97.41 USB1.B1 6.85,98.4 ; HDMI1.5 11.02,72.08
  L6 w0.127: v2(109.33,40.43) 108.9,40.86 108.51,40.86 108.03,41.34 v2(108.01,41.34)
  L6 w0.508: USB2.11 14.95,47.52 ; USB2.11 14.95,45.74 ; USB2.11 16.63,46.63 ; USB1.21 7.39,100.28 ; USB1.21 6.06,101.12 ; USB1.21 6.06,99.45 ; USB1.21 4.72,100.28 ; 3.52,88.13 USB1.13 2.19,87.3 ; USB1.14 7.39,88.13 ; USB1.14 6.06,88.97 ; USB1.14 4.72,88.13 ; USB1.14 6.06,87.3 ; 6.85,98.4 USB1.B1 6.27,97.41 ; USB3.4 16.46,28.93 ; USB3.4 15.7,28.17 ; USB3.4 15.7,29.69 ; 14.2,31.67 USB3.7 ; USB3.7 14.2,33.19 ; USB3.7 14.96,32.43 ; 6.5,43.86 USB2.13 7.13,45.18 7.9,44.42 ; 4.6,64.44 HDMI1.22 ; HDMI1.22 6.04,65.43 ; HDMI1.22 3.16,65.43 ; 6.5,41.65 USB3.12 7.19,40.28 7.9,40.99 ; 6.27,91.01 USB1.B12 6.85,90.02 ; 5.31,23.74 6.15,24.58 USB3.13 7.29,24.58 7.97,23.89 ; HDMI1.23 6.04,83.73 ; HDMI1.23 3.16,83.73 ; HDMI1.23 4.6,84.72 ; 14.2,52.27 USB2.7 ; USB2.7 14.96,53.03 ; USB2.7 14.2,53.79 ; HS1.1 12.64,86.51 ; HS1.1 10.8,84.67 ; HS1.1 8.96,86.51 ; HS1.1 10.8,88.35 ; HDMI1.20 12.54,67.33 ; HDMI1.20 11.1,66.34 ; HDMI1.20 11.1,68.32 ; 14.95,39.72 USB3.10 14.95,37.94 ; USB2.4 16.46,49.53 ; USB2.4 15.7,50.29 ; USB2.4 15.7,48.77 ; HDMI1.21 11.1,82.82 ; HDMI1.21 11.1,80.84 ; HDMI1.21 12.54,81.83 ; 3.52,100.28 USB1.22 2.19,101.12 ; 14.95,58.54 USB2.10 ; USB2.10 14.95,60.32 ; USB2.10 16.63,59.43 ; USB3.11 16.63,26.03 ; USB3.11 14.95,26.92 ; USB3.11 14.95,25.14 ; 8.39,88.95 USB1.15 ; USB1.15 9.48,89.73 ; USB1.15 7.3,89.73 ; 8.39,99.47 USB1.20 7.3,98.68
  BOTTOM w0.089: v2(171.68,86.58) 171.85,86.76 GPU1.E1 ; 99.13,55.54 101.65,55.54 101.66,55.53 101.77,55.53 101.88,55.41 102.76,55.41 102.87,55.53 CPU1.BB34
  BOTTOM w0.102: CPU1.P20 CPU1.P21 ; v2(125.55,55.34) 125.6,55.29 125.6,54.63 125.09,54.11 CPU1.B30
  BOTTOM w0.114: v2(125.55,55.34) 125.35,55.34 124.94,54.93 124.94,54.5
  BOTTOM w0.127: v2(102.2,51.21) 102.29,51.3 102.35,51.36 102.98,51.36 103.18,51.57 103.95,51.57 104.1,51.72 CPU1.BA28 ; v2(107.95,78.08) 108.08,77.96 108.08,76.16 CPU1.AP70 ; CPU1.BB55 103.59,67.63 102.74,67.63 102.67,67.56 101.57,67.56 99.85,69.27 v2(99.7,69.27) ; CPU1.AW51 CPU1.AW53 ; v2(112.27,77.93) 112.21,77.88 112.21,77.67 112.1,77.46 CPU1.AG71 ; CPU1.AT71 107.09,77.5 106.85,77.74 106.85,77.87 v2(106.79,77.93) ; CPU1.AW32 105.59,54.19 105.59,53.43 105.56,53.4 CPU1.AW30 ; v2(109.77,79.02) 109.77,79.02 109.35,78.59 109.35,77.62 109.38,77.58 109.38,77.55 109.45,77.49 CPU1.AM71 ; CPU1.BB64 102.67,72.6 v2(102.64,72.57) ; CPU1.BB26 102.93,50.54 102.44,50.05 101.87,50.05 v2(101.87,50.06) ; CPU1.AW60 105.59,70.18 105.59,71.4 CPU1.AW62 ; v2(99.64,72.74) 99.82,72.74 101.9,70.65 102.72,70.65 103.07,70.3 103.56,70.3 CPU1.BB60 ; CPU1.BB38 102.99,57.88 102.86,57.75 100.35,57.75 99.97,58.13 v2(99.97,58.36) ; CPU1.BB30 102.56,52.9 102.41,52.75 v2(102.33,52.75) ; v2(102.53,60.61) 102.56,60.61 102.68,60.48 CPU1.BB43
  BOTTOM w0.152: CPU1.AW16 105.56,45.94 105.67,46.05 105.67,46.69 CPU1.AW18 ; CPU1.AL55 110.13,67.4 110.59,67.86 ; CPU1.AK16 110.42,45.29 110.79,45.66 110.79,46.01 CPU1.AJ18 ; CPU1.AP42 108.49,60.09 108.5,60.08 108.85,60.08 108.85,60.09 CPU1.AN42 ; 110.59,67.86 110.13,68.32 CPU1.AL58 ; 110.59,67.86 v2(110.87,67.86) ; CPU1.AR42 107.58,60.09 107.57,60.08 107.22,60.08 107.21,60.09 CPU1.AT42 ; CPU1.AR20 CPU1.AT20
  BOTTOM w0.178: 118.39,44.06 117.85,44.06 117.39,44.52 CPU1.T15 ; CPU1.AM61 109.78,70.93 109.78,70.27 CPU1.AM60 ; CPU1.AW64 105.62,72.76 105.62,73.72 105.65,73.75 ; CPU1.H71 121.7,78.01 v2(121.69,78.02) ; CPU1.AP20 CPU1.AN20
  BOTTOM w0.203: v2(108.08,66.02) 108.08,65.95 CPU1.AR52 ; CPU1.AN63 109.65,71.32 CPU1.AM61 ; CPU1.AN63 CPU1.AP63 ; CPU1.AN63 109.5,72.47 CPU1.AL64 ; CPU1.AT20 CPU1.AU20 ; v2(104.94,64.22) 105.09,64.07 CPU1.AW49 105.6,64.03 105.6,62.91 CPU1.AW47 ; v2(156.01,83.15) 155.97,83.12 PU4801.31 ; CPU1.AR11 107.7,42.58 v2(108.03,42.26) 108.35,41.93 CPU1.AP10 ; v2(152.42,63.74) 152.48,63.8 PU4701.5 ; CPU1.L8 120.4,40.88 CPU1.J8 ; PU4701.31 155.7,67.08 v2(155.78,67.15) ; v2(104.86,56.58) 104.98,56.7 CPU1.AW36 ; v2(126.08,51.84) 125.94,51.98 124.77,51.98 124.76,51.97 124.26,51.97 CPU1.D26 ; CPU1.AM45 109.75,62.01 109.75,62.73 CPU1.AM46 ; v2(152.3,79.65) 152.74,80.08 PU4801.5 ; v2(120.11,78.15) 120.29,77.97 120.29,77.32 120.29,77.32 120.29,76.75 CPU1.K71 CPU1.K70 ; CPU1.AW18 105.34,46.8 105.13,47.01 105.08,47.01 105.04,47.04 104.58,47.04 104.34,46.8 CPU1.BA18 CPU1.BB18 ; v2(104.87,66.31) 105.03,66.47 CPU1.AW53 ; CPU1.AW43 105.51,60.43 105.51,60.82 105.59,60.9 105.59,61.21 105.56,61.23 CPU1.AW45 104.97,61.66 v2(104.96,61.66) ; CPU1.AR45 107.7,61.91 107.44,61.65 107.44,61.59 v2(107.36,61.51) 107.44,61.43 107.44,61.26 107.69,61 CPU1.AR43 ; PC4846.2 141.24,90.55 141.24,91.12 141.38,91.26 PU4802.5 ; CPU1.G45 121.77,61.79 121.77,61.12 CPU1.G43 ; PU4701.3 153.28,65.25 ; CPU1.AJ15 111.26,44.46 111.53,44.19 111.53,43.68 CPU1.AH13 ; CPU1.AF2 112.74,37.65 112.74,38.07 CPU1.AF4 ; CPU1.AR50 107.73,64.66 108.07,64.32 v2(108.07,64.19) 108.07,64.08 107.74,63.74 CPU1.AR48 CPU1.AR46 ; CPU1.D45 123.64,62.22 123.29,62.57 123.29,62.73 CPU1.E46 ; CPU1.G5 122.02,39.06 122.39,38.69 122.72,38.69 CPU1.F4 ; 105.58,58 105.58,59.16 CPU1.AW41 104.97,59.18 v2(104.84,59.3) ; v2(104.96,71.43) CPU1.AW62 ; 153.28,65.29 v2(153.39,65.4) ; U4001.11 v2(134.29,102.07) ; CPU1.T17 117.52,45.43 117.52,45.01 117.12,44.62 CPU1.T15
  BOTTOM w0.229: USB1.A12 8.42,96.96 ; CPU1.AL2 109.81,37.29 109.47,36.95 109.47,36.14 109.26,35.92 v2(109.26,35.88) ; CPU1.AD16 114.19,45.59 114.19,46.06 CPU1.AB18 ; USB1.A1 8.61,91.46 ; CPU1.AJ20 110.84,47.36 110.84,46.91 111.26,46.49 CPU1.AJ18
  BOTTOM w0.254: GPU1.A9 176.65,94.35 176.76,94.45 176.76,95.06 176.35,95.47 175.41,95.47 174.8,94.86 v2(174.8,94.83) ; CPU1.AR35 107.7,56.56 108.02,56.88 ; v2(118.4,72.8) 118.72,73.12 CPU1.N65 ; v2(108.74,55.06) 109,55.33 CPU1.AN33 109.46,55.97 CPU1.AL35 ; v2(108.74,55.06) 109,54.79 CPU1.AN32 109,54.52 v2(109.33,54.19) 109.38,54.14 CPU1.AL32 ; v2(108.74,55.06) 108.35,54.68 CPU1.AP32 ; CPU1.AN35 109,56.56 v2(108.68,56.89) 108.68,56.75 CPU1.AP35 ; v2(104.84,59.3) 104.72,59.18 CPU1.BA41 ; CPU1.AT56 107.05,68.25 106.66,67.86 105.68,67.86 CPU1.AW55 105.56,67.46 105.74,67.28 105.87,67.28 105.89,67.25 v2(105.91,67.25) ; CPU1.AT2 CPU1.AT4 107.16,38.42 107.7,38.96 CPU1.AR5 ; v2(108.68,53.23) 109,52.9 CPU1.AN28 ; v2(108.68,53.23) 109,53.55 CPU1.AN30 ; v2(108.68,53.23) 108.35,52.9 CPU1.AP28 108.29,52.83 107.76,52.83 CPU1.AR28 CPU1.AT28 ; EC401.2 131.53,75.18 132.23,75.18 v2(132.26,75.15) ; v2(104.96,61.66) 104.96,61.66 CPU1.BA45 ; DM1.78 66.59,68.23 67.82,69.46 v2(67.82,69.63) ; CPU1.B18 CPU1.D18 123.62,46.37 CPU1.E18 ; CPU1.AP63 108.33,71.95 107.73,71.95 CPU1.AR63 107.63,71.9 107.13,71.9 CPU1.AT63 ; CPU1.D47 124.06,63.35 124.46,63.74 124.61,63.74 124.9,64.02 CPU1.B48 ; CPU1.D47 123.92,63.39 CPU1.D48 ; CPU1.D47 123.5,63.35 123.46,63.31 122.18,63.31 v2(122.15,63.29) ; CPU1.AP42 108.35,60.13 108.03,60.45 ; R406.2 131.81,72.1 v2(132.26,72.1) ; CPU1.AA68 114.74,74.62 v2(114.74,74.1) 114.74,73.57 CPU1.AA65 ; CPU1.BA62 v2(104.96,71.43) ; v2(119.46,40.74) 119.56,40.74 119.88,40.43 CPU1.L8 ; CPU1.U10 116.69,41.9 116.41,41.9 v2(116.38,41.93) ; CPU1.T2 CPU1.T4 ; CPU1.T4 117.76,38.44 v2(117.45,38.75) ; CPU1.T4 117.93,38.52 CPU1.R6 CPU1.N6 119.41,38.71 119.9,38.71 120.27,38.35 CPU1.L4 120.34,38.28 120.34,37.44 CPU1.L2 ; USB1.18 8.68,95.39 v2(9.07,95.77) ; CPU1.BA49 104.77,64.07 104.88,64.18 104.9,64.18 v2(104.94,64.22) ; v2(104.87,66.31) 104.71,66.47 CPU1.BA53 ; v2(118.41,44.06) 118.62,44.06 CPU1.N13 ; v2(118.41,44.06) 118.03,43.68 CPU1.R13 ; v2(118.41,44.06) 118.39,44.06 ; v2(108.08,66.02) 108.08,66.12 CPU1.AR53 ; CPU1.K70 120.34,75.16 CPU1.K68 120.45,74.65 CPU1.K67 CPU1.K66 CPU1.K65 ; CPU1.B53 124.72,66.72 v2(124.4,66.72) 124.14,66.72 CPU1.D53 123.56,66.14 v2(123.56,65.12) 123.56,65.04 123.19,64.67 CPU1.E50 ; v2(70.59,73.52) 70.63,73.48 DM1.57 ; v2(112,72.13) 111.83,72.31 111.7,72.31 CPU1.AH64 ; v2(112,72.13) 111.69,71.82 CPU1.AH63 ; v2(112,72.13) 112.31,71.82 CPU1.AF63 ; v2(104.86,56.58) 104.72,56.58 104.6,56.7 CPU1.BA36 ; CPU1.AW64 105.56,72.31 105.66,72.21 105.66,71.52 CPU1.AW62 ; v2(104.87,39.73) 104.81,39.73 104.8,39.72 104.52,39.72 CPU1.BA6 104.24,39.54 104.19,39.59 103.76,39.59 103.7,39.54 CPU1.BB6 ; CPU1.L20 119.64,47.79 119.38,48.05 119.38,48.05 119,48.42 CPU1.N21 ; CPU1.AG17 CPU1.AF17 ; CPU1.AG17 CPU1.AG18 CPU1.AG19 112.09,47.23 112.04,47.29 112.04,47.69 112.09,47.75 CPU1.AG20 112.03,47.84 112.03,48.36 CPU1.AG21 112.09,48.44 v2(112.65,48.99) ; CPU1.AG17 CPU1.AG16 ; CPU1.T17 CPU1.T18 ; CPU1.AK69 CPU1.AK68 110.89,75.07 CPU1.AH67 111.55,74.42 v2(111.95,74.82) ; CPU1.AT58 CPU1.AR58 CPU1.AP58 108.43,69.15 108.92,69.15 CPU1.AN58 109.33,69.56 v2(109.33,69.69) 109.65,70.01 CPU1.AM60 ; CPU1.AD16 CPU1.AB16 ; CPU1.AB16 CPU1.AB15 ; CPU1.AB16 115.26,45.82 CPU1.Y17 ; CPU1.AR15 107.38,44.87 v2(107.38,45) ; GPU1.E7 175.45,86.97 175.59,86.83 v2(175.59,86.5) ; 108.02,56.88 107.5,56.88 CPU1.AT35 107,56.43 106.46,55.88 106.25,55.88 106.18,55.81 106,55.81 105.94,55.76 105.89,55.76 CPU1.AW34 ; 108.02,56.88 v2(108.03,56.89) ; CPU1.U66 116.7,74.1 v2(116.57,74.1) 116.75,74.28 116.76,74.28 116.91,74.42 CPU1.U67 ; CPU1.AR55 107.98,67.13 v2(107.98,66.94) ; CPU1.B44 124.94,61.55 124.94,61.51 124.66,61.24 124.27,61.24 124.26,61.25 124.22,61.25 CPU1.D44 123.92,62.18 CPU1.D45 ; 108.03,60.45 v2(108.03,60.52) ; 108.03,60.45 107.7,60.12 CPU1.AR42 ; CPU1.AW32 106.03,54.23 CPU1.AU32 ; CPU1.BA66 CPU1.AY66 105.09,73.75 105.65,73.75 CPU1.AW66 ; CPU1.AV70 CPU1.AV69 105.7,75.55 v2(105.97,75.28) 105.89,75.2 CPU1.AV68 ; LCD1.11 83.95,94.41 83.74,94.2 83.74,94 v2(83.67,93.92) ; CPU1.AB21 114.65,48.42 115.21,48.99 v2(115.26,48.99) ; v2(122.2,60.55) 122.2,60.73 121.92,61 CPU1.G43 121.88,61 CPU1.J42 ; CPU1.G60 122.22,69.82 v2(122.22,69.69) 121.89,69.36 CPU1.G58 ; CPU1.Y21 115.45,48.32 115.47,48.3 115.47,47.91 115.45,47.88 CPU1.Y20 CPU1.Y19 ; R604.2 v2(132.26,77.82) 132.29,77.78 R1714.2 133.07,77.75 EC1701.2 ; CPU1.U69 116.9,75.72 116.76,75.87 116.75,75.87 v2(116.57,76.05) 116.75,76.23 116.76,76.23 116.91,76.37 CPU1.U70 ; CPU1.D26 123.96,51.59 CPU1.D25 CPU1.C25 ; DM1.213 70.11,32.48 v2(70.06,32.53) ; v2(113.14,40.64) 113.35,40.43 CPU1.AD8 ; CPU1.G63 121.61,71.68 v2(121.61,71.62) 121.61,71.6 121.07,71.06 CPU1.K61 120.93,71.09 120.92,71.15 120.65,71.41 CPU1.K63 CPU1.K64 ; CPU1.W13 115.72,43.68 115.35,43.31 v2(115.25,43.31) ; CPU1.H18 121.24,46.25 121.03,46.04 121.03,45.81 120.48,45.26 CPU1.K16 121.11,44.54 CPU1.H15 ; CPU1.AU38 105.84,58.26 CPU1.AW38 ; v2(110.06,43.27) 109.99,43.27 109.65,43.61 CPU1.AM13 ; CPU1.AW14 v2(104.93,44.38) CPU1.BA14 ; CPU1.B34 124.5,56.59 v2(124.43,56.52) 124.36,56.59 CPU1.D34 ; CPU1.AL4 CPU1.AJ4 ; CPU1.AK11 111.01,41.96 111.01,40.84 CPU1.AK8 110.59,40.48 110.18,40.88 CPU1.AM8 ; GPU1.B7 175.45,92.66 175.21,92.9 v2(175.21,93.21) ; CPU1.AK18 CPU1.AJ18 ; v2(118.48,42.06) 118.5,42.04 118.68,42.04 CPU1.N10 ; v2(105.79,47.31) 105.66,47.44 105.66,47.59 105.56,47.69 CPU1.AW21 ; v2(105.79,47.31) 105.82,47.29 CPU1.AU20 ; v2(105.79,47.31) 105.56,47.08 CPU1.AW18 ; v2(112.06,41.47) 112.35,41.47 CPU1.AF10 ; CPU1.AU10 105.72,41.8 CPU1.AW10 v2(104.93,41.96) CPU1.BA10 ; CPU1.D58 123.85,68.98 CPU1.E56 123.19,68.21 123.51,67.89 123.53,67.89 123.54,67.88 v2(123.54,67.88) ; CPU1.AK27 110.13,52.31 CPU1.AL28 109.67,51.86 CPU1.AM27 ; CPU1.F68 CPU1.D69 123.57,75.71 v2(123.44,75.84) ; CPU1.AW8 105.87,41.03 v2(105.87,41.24) ; CPU1.U63 116.89,71.82 v2(116.57,72.15) 116.89,72.47 CPU1.U64 ; v2(112.62,35.35) 112.62,35.42 112.6,35.45 112.6,36.03 112.46,36.17 CPU1.AF1 CPU1.AF2 ; CPU1.AM45 110.11,61.46 CPU1.AL45 109.67,61 CPU1.AM43 ; CPU1.AW57 105.56,68.95 105.31,69.21 105.02,69.21 v2(104.92,69.1) 104.89,69.08 104.47,69.08 CPU1.BA57 ; CPU1.AP68 107.96,74.44 v2(107.8,74.44) ; CPU1.F2 CPU1.F1 123.07,36.26 123.29,36.04 v2(123.29,36.03) ; CPU1.AN37 109.33,57.67 v2(109.33,57.8) CPU1.AL38 ; CPU1.J25 122.08,51.4 CPU1.F27 122.54,51.97 122.28,52.23 122.28,52.25 v2(122.22,52.32) 122.22,52.41 122.54,52.73 CPU1.F28 122.08,53.23 CPU1.J28 ; v2(106.73,45) 106.72,45 106.72,44.86 CPU1.AU15 106.25,44.39 106.25,44.09 105.56,43.4 CPU1.AW12 ; DM1.5 70.43,86.48 70.29,86.35 69.87,86.35 69.58,86.64 69.58,86.65 v2(69.37,86.86) ; v2(173.12,93.18) 173.66,92.65 173.66,92.31 GPU1.B4 ; CPU1.B66 CPU1.D66 123.92,73.83 123.54,73.45 123.54,73.33 CPU1.E65 ; v2(65.61,38.73) 65.6,38.73 DM1.188 ; v2(108.68,58.72) 108.35,58.39 CPU1.AP38 ; v2(118.4,74.75) 118.72,75.07 CPU1.N68 ; v2(111.3,64.79) 110.97,65.12 CPU1.AL52 ; CPU1.AM68 109.54,73.98 CPU1.AL66 CPU1.AL65 109.74,73.11 109.74,73 109.68,72.94 109.68,72.55 109.74,72.49 109.74,72.49 CPU1.AL64 ; v2(71.07,88.82) 71.79,88.82 72.35,88.26 DM1.1 ; CPU1.B14 CPU1.D14 ; CPU1.B62 124.58,71.46 v2(124.41,71.29) 124.24,71.46 CPU1.D62
  BOTTOM w0.279: CPU1.AA2 115.1,37.38 115.09,37.38 114.81,37.66 114.81,38.06 115.09,38.35 CPU1.AA4
  BOTTOM w0.305: CPU1.AH6 111.53,39.15 111.09,39.59 111.09,39.93 CPU1.AK8 ; DM1.217 69.4,31.48 68.47,30.56 v2(68.46,30.56) ; v2(53.96,41.19) 53.79,41.37 53.79,41.42 53.27,41.94 50.9,41.94 DM2.176 ; v2(114.17,43.44) 114.1,43.44 113.86,43.68 CPU1.AD13 ; v2(54.52,26.46) 54.37,26.31 54.37,26.07 53.24,24.94 DM2.244 ; DM2.103 57.54,62.19 57.15,62.58 57.15,64.38 v2(57.43,64.66) 57.45,64.69 DM2.93 ; DM2.35 58.1,79.19 57.82,79.46 56.91,79.46 56.17,78.72 56.17,78.67 v2(56,78.5) ; v3(117.57,48.99) 117.57,48.8 117.96,48.42 CPU1.P21 ; v2(57.29,28.14) 57.34,28.19 DM2.231 ; GPU1.B1 171.85,92.14 171.52,91.81 v2(171.12,91.81) ; v2(52.54,36.8) 52.53,36.81 52.4,36.81 52.28,36.94 50.9,36.94 DM2.196 ; DM2.222 52.15,30.44 v2(52.36,30.22) ; IOBD1.18 169.83,50.21 v2(169.87,50.26) ; DM2.82 52.72,67.44 53.1,67.06 v2(53.1,66.84) ; DM1.81 72.35,67.49 71.29,67.49 71.22,67.55 70.07,67.55 69.37,66.86 69.37,66.81 v2(69.19,66.64) 69.37,66.46 69.37,66.42 70.3,65.48 DM1.89 ; DM1.196 65.53,36.73 65.65,36.61 65.78,36.61 v2(65.79,36.6) ; DM2.192 50.9,37.94 53.06,37.94 v2(53.72,37.28) ; DM2.60 53.23,72.94 53.64,73.35 v2(53.64,73.75) 53.64,73.86 53.61,73.9 53.61,74.68 53.31,74.97 52.32,74.97 52.27,74.92 50.91,74.92 DM2.52 ; v2(57.42,69.83) 57.57,69.69 DM2.73 ; v2(65.71,34.24) 65.71,34.23 DM1.206 ; DM2.61 55.95,72.69 55.39,72.12 55.39,72.07 v2(55.21,71.89) ; v2(66.53,86.86) 66.53,86.76 66,86.24 64.15,86.24 DM1.6 ; v2(113.92,49.06) 113.77,48.92 CPU1.AD21 CPU1.AD20 CPU1.AD19 ; DM1.15 70.34,83.98 69.95,84.38 v2(69.95,84.65) ; v2(53.15,78.5) 52.97,78.32 52.97,78.27 52.64,77.94 DM2.40 ; v2(52.39,26.46) 52.36,26.44 DM2.238 ; v2(53.05,23.42) 53.05,23.6 52.67,23.97 52.09,23.97 52.06,23.94 DM2.248 ; v2(122.87,46.83) 123.19,46.51 CPU1.E18 ; HDD1.14 177.52,18.08 177.24,17.8 v2(176.66,17.8) ; v2(57.33,34.61) 57.35,34.61 57.38,34.64 59.05,34.64 DM2.205 ; DM2.214 52.08,32.44 52.14,32.37 53.86,32.37 54.22,32.02 54.22,31.97 v2(54.39,31.8) ; v2(52.5,40.92) 52.48,40.94 50.9,40.94 DM2.180 ; DM1.44 65.32,76.73 65.4,76.81 67.2,76.81 67.54,76.47 67.54,76.42 v2(67.72,76.24) ; CPU1.G66 121.95,74.45 v2(121.66,74.75) 121.45,74.54 120.75,74.54 CPU1.K67 ; v2(86.64,96.31) 86.64,95.7 86.95,95.39 LCD1.17 ; v2(67.08,62.25) 66.09,63.23 DM1.98 ; TCBD1.13 61.15,92.26 61.95,91.46 v2(61.95,89.17) ; DM2.167 58.16,44.19 57.96,44.38 56.96,44.38 56.03,43.46 56.03,42.79 v2(55.95,42.71) ; v2(65.66,80.03) 65.45,80.23 DM1.30 ; v2(67.21,82.23) 67.04,82.41 67.04,82.45 66.25,83.24 64.15,83.24 DM1.18 ; DM1.106 65.43,61.23 v2(66.35,62.15) ; v2(67.21,36.6) 67.04,36.78 67.04,36.83 66.13,37.73 DM1.192 ; v2(65.69,69.63) 65.59,69.73 DM1.72 ; v2(65.64,26.26) 65.61,26.23 DM1.238 ; v2(108.03,39.51) 107.87,39.36 107.87,39.31 107.7,39.14 CPU1.AR5 ; TCBD1.16 62.65,93.56 62.96,93.87 v2(62.96,94) ; CPU1.H18 121.14,46.47 CPU1.K18 ; v2(54.7,87.06) 54.52,87.23 54.52,87.28 54.13,87.67 52.21,87.67 51.97,87.44 DM2.2 ; DM1.184 64.15,39.73 66.44,39.73 66.98,39.19 66.98,38.78 v2(66.93,38.73) ; SSD1.9 193.91,29.44 193.5,29.02 193.5,27.88 193.65,27.73 ; USB1.17 8.68,93.19 8.94,92.93 9.88,92.93 v2(10.36,93.41) ; DM2.5 57.92,86.69 v2(57.54,87.06) ; v2(54.19,33.01) 54.19,33.06 54.82,33.69 DM2.209 ; v2(70.84,79.85) 70.86,79.85 71,79.98 DM1.31 ; DM2.89 57.16,65.69 v2(57.1,65.62) ; R2436.2 184.69,32.31 184.4,32.02 184.4,31.74 v2(184.4,31.74) ; DM2.218 52.82,31.44 53.61,30.64 53.61,30.4 v2(53.79,30.22) ; CPU1.AD62 113.82,71.12 v2(113.33,70.63) ; v2(57.52,84.69) 58.03,84.18 DM2.15 ; DM1.86 65.21,66.23 65.44,66.01 67.19,66.01 67.77,66.59 v2(67.77,66.64) ; v2(67.44,32.81) 67.44,32.86 68.07,33.49 72.35,33.49 DM1.209 ; CPU1.AF15 112.74,44.52 CPU1.AG16 ; v2(57.45,26.43) 57.45,26.38 57.64,26.19 DM2.239 ; DM2.69 60.48,70.69 v2(60.48,70.69) ; v2(55.6,74.34) 55.68,74.41 55.68,74.46 56.16,74.95 57.69,74.95 57.89,75.15 58.09,75.15 58.13,75.19 DM2.51 ; v2(57.52,80.05) 57.54,80.05 57.68,80.19 DM2.31 ; DM2.18 53,83.44 53.79,82.65 53.79,82.61 v2(53.96,82.43) ; v2(122.16,65.1) 121.89,65.37 CPU1.G52 ; v2(65.79,82.23) 65.79,82.24 64.15,82.24 DM1.22 ; CPU1.AM45 109.65,61.74 v2(109.37,61.46) ; v2(55.93,28.24) 55.93,28.24 56.87,29.19 DM2.227 ; DM2.48 52.07,75.94 52.12,75.89 52.55,75.89 52.88,76.22 52.88,76.27 v2(53.05,76.44) ; v2(54.3,39.11) 53.48,39.94 50.9,39.94 DM2.184 ; DM1.185 71.13,39.48 70.67,39.95 69.04,39.95 68.2,39.11 v2(68.2,38.65) ; v2(65.61,71.69) 65.57,71.73 DM1.64 ; LCD1.14 85.45,95.36 85.39,95.42 85.39,95.44 84.66,96.18 v2(84.66,96.31) ; v2(54.63,43.02) 54.63,43.5 54.05,44.09 52.28,44.09 52.13,43.94 50.9,43.94 DM2.168 ; KBBD1.35 133.05,16.23 v2(133.04,16.22) ; CPU1.AK63 110.54,71.82 109.89,72.47 CPU1.AL64 ; DM1.107 71.4,60.98 71.39,61 71.12,61 v2(70.92,61.21) ; v2(53.28,87.06) 53.28,87 52.71,86.44 DM2.6 ; DM1.69 73.46,70.48 73.79,70.81 73.79,74.79 73.59,74.98 DM1.51 71.38,74.98 71.16,74.76 69.5,74.76 68.48,73.75 68.48,73.55 v2(68.46,73.52) ; DM1.205 70.25,34.48 69.8,34.94 v2(69.8,35) ; DM1.251 70.77,22.98 v2(70.62,23.14) ; v2(70.84,27.96) 70.87,27.98 DM1.231 ; 123.56,66.14 123.22,66.49 CPU1.E53 ; 60.59,63.18 60.59,61.7 60.08,61.19 DM2.107 ; 60.59,63.18 60.03,63.18 60.02,63.19 DM2.99 ; 60.59,63.18 v2(60.63,63.21) ; DM1.168 65.38,43.73 65.58,43.93 67.31,43.93 67.74,43.51 v2(67.74,43.32) ; v2(65.78,84.65) 65.78,84.49 65.53,84.24 64.15,84.24 DM1.14 ; DM1.181 71.34,40.48 70.89,40.94 70.76,40.94 v2(70.74,40.96) ; DM1.93 71.09,64.48 70.82,64.22 70.82,63.03 70.86,62.99 v2(70.86,62.91) 70.94,62.98 DM1.99 ; DM1.73 72.35,69.49 70.82,69.49 v2(70.67,69.63) ; v2(178,87.77) 177.94,87.77 177.57,87.4 177.26,87.4 GPU1.E10 ; v2(67.04,28.19) 66.86,28.01 66.86,27.97 66.12,27.23 DM1.234 ; v2(70.18,62.91) 70.18,62.79 70.99,61.98 DM1.103 ; DM1.90 63.18,65.23 v2(62.59,65.83) ; v2(173.58,86.5) 173.65,86.58 GPU1.E4 ; v2(62.33,80.92) 62.36,80.95 62.37,80.95 62.65,81.23 DM1.26 ; v2(69.57,28.01) 69.57,28.41 70.14,28.98 DM1.227 ; DM1.65 72.35,71.48 71.15,71.48 70.82,71.16 70.36,71.16 70.06,71.46 70.06,71.51 v2(69.88,71.69) ; v2(52.46,34.44) 50.98,34.44 50.97,34.44 DM2.206 ; DM2.30 52.3,80.44 v2(52.54,80.2) ; CPU1.AM55 110.11,66.95 CPU1.AL55 ; CPU1.D22 CPU1.B22 ; v2(57.3,73.83) 57.38,73.83 57.52,73.69 DM2.57 ; v2(52.34,62.44) DM2.102 ; v2(52.54,38.93) 52.54,38.94 50.9,38.94 DM2.188 ; DM1.210 65.33,33.23 65.37,33.27 65.81,33.27 66.3,32.78 v2(66.3,32.74) ; CPU1.AM46 110.11,63.29 CPU1.AL48 ; DM1.202 65.8,35.23 66.26,34.77 66.65,34.77 66.96,34.46 66.96,34.41 v2(67.14,34.24) ; DM2.78 52.41,68.44 v2(52.73,68.75) ; DM2.172 50.9,42.94 52.76,42.94 53.25,43.43 v2(53.25,43.48) ; DM2.247 58.04,24.19 57.97,24.25 56.82,24.25 56.12,23.56 56.1,23.56 v2(55.88,23.33) ; DM1.61 72.35,72.48 69.2,72.48 68.64,71.92 68.64,71.87 v2(68.46,71.69) ; DM2.56 52.15,73.94 v2(52.36,73.72) ; v2(70.62,66.64) 70.77,66.49 72.35,66.49 DM1.85 ; v2(55.45,40.81) 55.47,40.83 55.47,41.28 55.51,41.32 55.51,41.36 55.97,41.83 57.67,41.83 58.03,42.19 DM2.175 ; DM1.39 70.98,77.98 v2(70.67,78.3) ; v2(52.34,63.44) DM2.98 ; v2(122.2,60.55) 122.2,60.39 122.5,60.09 CPU1.F42 ; v2(55.39,84.69) 55.39,85.17 55.9,85.69 DM2.9 ; v2(178.48,90.97) 178.48,91.66 177.83,92.31 GPU1.B10 ; v2(172.21,84.85) 172.59,84.85 173.05,85.32 GPU1.F3 ; DM1.167 71.41,43.98 71.16,44.24 70.05,44.24 69.37,43.55 69.37,43.4 v2(69.29,43.32) ; PU5102.8 45.08,11.42 45.1,11.44 v2(45.15,11.44) ; v2(68.55,40.96) 68.56,40.96 69.63,42.03 71.23,42.03 71.28,41.98 DM1.175 ; DM2.235 57.82,27.19 57.65,27.36 56.83,27.36 56.18,26.71 v2(56.18,26.43) 56.18,26.17 57.17,25.19 DM2.243 ; v2(88.59,96.28) 88.59,95.8 88.45,95.66 LCD1.20 ; CPU1.F13 123.19,44.28 CPU1.E15 123.53,44.2 CPU1.D14 ; v2(105.84,40.22) 105.84,39.84 105.58,39.58 CPU1.AW6 ; DM2.43 56.59,77.19 55.89,76.49 v2(55.89,76.44) ; DM1.35 71.35,78.98 71.07,79.26 70.16,79.26 69.42,78.52 69.42,78.47 v2(69.24,78.3) ; DM1.248 65.05,23.73 65.07,23.75 65.81,23.75 66.3,23.26 v2(66.3,23.22) ; IOBD1.6 168.9,56.23 169.59,56.23 169.82,56.46 v2(169.9,56.46) 169.64,56.71 IOBD1.5 ; CPU1.V18 CPU1.T18 117.77,47.12 CPU1.P19 ; DM1.222 64.15,30.24 65.4,30.24 v2(65.61,30.02) ; v2(70.76,43.32) 70.76,43.29 71.06,42.98 DM1.171 ; DM1.68 66.13,70.73 66.86,71.46 66.86,71.51 v2(67.04,71.69) ; CPU1.AN38 108.68,58.58 v2(108.68,58.72) 108.68,58.85 CPU1.AN40 ; v2(67.92,84.62) 67.92,85.01 68.56,85.65 70.68,85.65 70.84,85.48 DM1.9 ; v2(57.42,78.5) 57.73,78.19 DM2.39 ; v2(55.12,34.71) 55.12,34.74 55.52,35.14 55.7,35.14 56.34,35.78 58.07,35.78 58.17,35.69 DM2.201 ; DM1.23 71.33,81.98 71.3,81.96 71.3,81.96 71.19,81.86 70.18,81.86 69.92,82.11 69.92,82.24 v2(69.9,82.26) 70.06,82.42 70.06,82.8 70.28,83.02 71.07,83.02 71.11,82.98 DM1.19 ; SSD1.33 193.57,23.44 ; CPU1.T21 116.74,48.81 v3(116.74,48.96) ; v2(53.79,71.89) 53.61,71.71 53.61,71.66 52.88,70.94 DM2.68 ; DM1.27 70.55,80.98 69.62,80.05 69.62,79.9 v2(69.57,79.85) ; v2(115.26,48.99) 115.45,48.8 CPU1.Y21 ; CPU1.AT68 107.09,74.74 107.39,74.44 v2(107.8,74.44) ; v2(53.05,32.94) 53.05,33.15 52.73,33.47 52.11,33.47 52.07,33.44 DM2.210 ; v2(53.85,34.71) 53.85,34.81 53.23,35.44 DM2.202 ; DM2.252 52,22.94 52.12,22.82 54,22.82 v2(54.52,23.34) ; DM2.86 52.03,66.44 52.2,66.26 54,66.26 54.34,66.61 54.34,66.66 v2(54.52,66.84) ; DM2.85 57.52,66.69 v2(57.37,66.84) ; 193.77,22.17 194,21.94 SSD1.39 ; v2(56.12,87.06) 56.3,87.23 56.3,87.28 57.01,87.98 57.95,87.98 58.25,87.69 DM2.1 ; v2(55.62,37.48) 56.11,37.96 56.66,37.96 56.94,37.68 DM2.193 ; v2(67.95,86.86) 67.77,87.03 67.77,87.08 67.33,87.52 65.51,87.52 65.22,87.23 DM1.2 ; 193.65,27.73 193.86,27.94 SSD1.15 ; 193.65,27.73 v2(193.65,26.99) 193.65,26.79 194,26.44 SSD1.21 ; CPU1.AK11 110.74,42.38 v2(111.06,42.69) ; DM2.230 52.32,28.44 v2(52.36,28.39) ; CPU1.G55 121.89,67.18 v2(122.13,66.94) ; PU5201.19 99.88,4.17 v2(99.62,3.9) ; SSD1.3 193.81,30.94 v2(193.6,30.73) ; v2(56.16,80.1) 56.26,80.2 56.26,80.25 57.19,81.19 DM2.27 ; DM1.48 65.33,75.73 65.36,75.7 65.81,75.7 66.12,76.02 66.12,76.06 v2(66.3,76.24) ; IOBD1.24 168.27,47.21 167.8,46.74 v2(167.8,46.43) ; v2(67.77,23.14) 67.26,22.62 65.37,22.62 65.25,22.73 DM1.252 ; v2(69.85,76.24) 70.03,76.06 70.03,76.01 70.34,75.7 70.79,75.7 71.07,75.98 DM1.47 ; v2(174.39,84.52) 174.39,84.7 174.85,85.16 GPU1.F6 ; IOBD1.9 169.57,54.71 169.9,54.38 v2(169.9,54.37) ; KBBD1.39 131.05,16.31 v2(131.14,16.22) 131.24,16.32 131.24,16.44 131.55,16.75 KBBD1.38 ; DM1.180 64.15,40.73 65.53,40.73 65.76,40.96 v2(65.81,40.96) ; DM2.47 57.82,76.19 57.82,76.19 57.54,75.91 57.09,75.91 56.78,76.21 56.78,76.26 v2(56.6,76.44) ; 193.75,24.76 193.93,24.94 SSD1.27 ; DM1.10 64.15,85.24 66.75,85.24 67.21,84.78 v2(67.21,84.62) ; v2(53.96,84.69) 53.96,84.84 53.37,85.44 DM2.10 ; CPU1.L20 118.99,47.12 CPU1.N19 119.24,46.69 119.42,46.69 CPU1.L18 119.53,46.37 119.53,45.93 CPU1.L17 CPU1.L16 CPU1.K16 ; v2(66.4,78.3) 66.22,78.12 66.22,78.07 65.89,77.73 DM1.40 ; v2(193.44,20.41) 193.47,20.44 SSD1.45 ; DM1.218 65.87,31.23 66.86,30.25 66.86,30.2 v2(67.04,30.02) 66.86,29.84 66.86,29.8 66.29,29.23 DM1.226 ; DM2.189 57.77,38.69 57.76,38.68 57.3,38.68 56.97,39.01 56.97,39.05 56.68,39.34 56.67,39.34 v2(56.28,39.72) ; DM1.235 71.06,26.98 71.02,27.02 69.91,27.02 69.37,26.48 69.37,26.44 v2(69.19,26.26) 69.37,26.08 69.37,26.03 70.42,24.98 72.35,24.98 DM1.243 ; IOBD1.12 169.49,53.21 169.9,52.81 v2(169.9,52.26) 169.9,52.23 169.38,51.71 IOBD1.15 ; DM2.251 57.65,23.19 v2(57.61,23.23) ; v2(52.54,84.69) 52.28,84.44 DM2.14 ; DM2.36 52.12,78.94 52.27,79.09 53.77,79.09 v2(54.33,79.65) ; v2(52.36,71.89) 52.32,71.94 DM2.64 ; v2(69.24,69.63) 69.42,69.46 69.42,69.41 70.34,68.49 72.35,68.49 DM1.77 ; DM2.217 58.18,31.69 58.09,31.77 56.23,31.77 55.22,30.76 v2(55.21,30.76) ; v2(69.19,23.14) 69.37,23.31 69.37,23.36 70.07,24.05 71.22,24.05 71.29,23.98 DM1.247 ; v2(62,73.6) 62,73.35 62.61,72.73 DM1.60 ; TCBD1.20 64.65,93.73 64.84,93.92 v2(65.15,93.92) TCBD1.21 ; PU5201.4 102.79,7.84 v2(102.89,7.94) ; v2(53.1,62.35) 52.18,61.44 DM2.106 ; DM1.82 65.79,67.23 66.17,66.86 66.17,66.81 v2(66.35,66.64) ; v2(172.52,96.16) 172.52,95.62 173.06,95.08 173.06,94.02 GPU1.A3 ; v2(176.02,16.12) 176.25,16.35 177.19,16.35 177.42,16.58 HDD1.17 ; CPU1.V16 CPU1.V17 CPU1.T17 CPU1.P17 ; v2(70.13,39.03) 70.13,38.86 70.5,38.48 DM1.189 ; v2(67.04,73.52) 66.86,73.7 66.86,73.75 65.87,74.73 DM1.52 ; v2(109.33,50.49) 109.33,50.34 ; v2(70.62,26.26) 70.89,25.98 DM1.239 ; DM2.223 57.91,30.19 v2(57.37,30.73) ; DM2.44 52.07,76.94 52.17,77.03 53.93,77.03 54.29,76.67 54.29,76.62 v2(54.47,76.44) ; IOBD1.21 169.4,48.71 169.65,48.45 169.77,48.45 v2(169.87,48.35) ; DM1.193 71.25,37.48 71.2,37.53 70.24,37.53 69.37,36.66 v2(69.37,36.62) ; DM1.102 v2(65.59,62.23) ; DM1.197 70.9,36.48 v2(70.76,36.62) ; v2(65.61,73.52) 65.4,73.73 DM1.56 ; DM2.94 50.9,64.43 51.91,64.43 v2(52.46,64.99) 52.02,65.44 DM2.90 ; v2(68.38,35) 68.56,35.18 68.56,35.22 68.91,35.58 68.92,35.58 70.78,35.58 70.87,35.48 DM1.201 ; CPU1.AR8 107.7,40.97 107.87,41.13 107.87,41.19 108.01,41.33 v2(108.01,41.34) ; v2(54.79,68.85) 54.79,69.16 54.01,69.94 DM2.72 ; CPU1.N21 118.8,48.6 v3(118.41,48.99) ; v2(56.63,71.89) 56.81,71.71 56.81,71.66 57.11,71.36 57.57,71.36 57.9,71.69 DM2.65 ; v2(69.14,76.24) 69.14,76.34 69.79,76.98 DM1.43 ; v2(67.64,31.6) 67.47,31.77 67.47,31.82 67.14,32.15 65.43,32.15 65.34,32.23 DM1.214 ; v2(122.15,63.29) 121.89,63.55 CPU1.G48 ; CPU1.AD16 113.58,45.17 CPU1.AF17 ; PU5001.6 v2(151.54,53.44) ; DM2.22 52.54,82.44 v2(52.54,82.43) ; LCD1.26 91.45,95.41 91.18,95.67 90.88,95.67 90.5,96.05 v2(90.5,96.28) ; v2(53.64,28.36) 53.64,28.25 53.61,28.21 53.61,28.16 52.88,27.44 DM2.234 ; DM2.171 57.52,43.19 57.3,42.97 v2(57.3,42.71) ; v2(55.94,66.84) 56.12,67.02 56.12,67.06 56.82,67.75 57.97,67.75 58.04,67.69 DM2.81 ; v2(61.71,65.2) 62.67,64.23 DM1.94 ; DM1.172 64.15,42.73 66.01,42.73 66.47,43.2 v2(66.47,43.32) ; DM2.23 58.08,82.19 58.08,82.19 58.01,82.11 57.23,82.11 56.81,82.53 v2(56.81,82.59) ; v2(69.77,89.6) 69.77,91.64 69.15,92.26 TCBD1.29 69.15,93.6 v2(68.81,93.95) ; DM2.77 57.09,68.69 56.17,69.61 56.17,69.66 v2(56,69.83) ; CPU1.B58 CPU1.D58 ; v2(107.38,45) 107.53,45.15 107.53,45.2 107.7,45.37 CPU1.AR16 ; DM2.213 58.19,32.69 58.18,32.7 56.85,32.7 v2(56.81,32.74) ; GPU1.A6 174.85,94.78 v2(174.8,94.83) ; v2(70.62,30.53) 71.16,29.98 DM1.223 ; DM1.230 65.57,28.23 v2(65.61,28.19) ; GPU1.F9 176.66,85.7 176.66,84.86 176.17,84.37 v2(175.77,84.37) ; v2(90.02,93.92) 89.95,93.99 LCD1.23 ; DM2.226 52.47,29.44 v2(52.56,29.34) ; v2(177.19,14.24) 177.19,14.77 177.49,15.08 HDD1.20 ; DM2.19 55.75,83.19 55.39,82.82 v2(55.39,82.59) 55.39,82.38 54.46,81.45 53.4,81.45 53.39,81.44 DM2.26 ; v2(57.52,36.8) 57.63,36.69 DM2.197 ; DM1.36 65.37,78.73 65.59,78.96 67.16,78.96 67.64,79.44 v2(67.64,79.9) ; v2(193.34,18.47) 193.66,18.65 193.96,18.94 SSD1.51 ; v2(67.77,26.26) 67.62,26.11 67.62,25.87 66.49,24.73 DM1.244 ; DM2.185 60.24,39.69 60.63,40.07 60.63,40.5 60.45,40.68 59.1,40.68 DM2.181 58.18,40.69 58.16,40.71 v2(57.48,40.71) ; v2(67.18,40.96) 67.18,41.02 67.04,41.17 67.04,41.22 66.52,41.73 64.15,41.73 DM1.176 ; CPU1.AH13 111.58,43.68 111.94,43.32 111.99,43.32 v2(112.01,43.3) ; CPU1.AL2 CPU1.AL4 ; U3401.14 24.78,48.6 ; v2(38.53,11.9) 38.55,11.92 PU5102.4
  BOTTOM w0.356: CPU1.AM27 109.65,51.72 v2(109.33,51.4) ; CPU1.BA32 104.9,54.23 v2(104.93,54.26) ; Q1701.4 70.96,8.87 71.58,9.49 v2(71.8,9.49) ; THM261.5 135.51,24.12 v2(134.95,23.56) ; CPU1.F4 CPU1.F2 ; 122.1,40.2 121.89,39.99 CPU1.G6 ; R2504.2 71.12,7.12 v2(71.12,6.77) ; 122.86,63.31 123.19,62.98 CPU1.E46 ; U4005.3 102.38,11.17 103.88,11.17 v2(103.88,11.09)
  BOTTOM w0.381: Q1702.1 68.39,10.62 67.31,9.54 66.88,9.54 v2(66.62,9.29) ; CPU1.AW32 104.97,54.23 v2(104.93,54.26)
  BOTTOM w0.406: v2(110.84,25.34) 111.52,25.34 R1823.2 ; v2(122.93,73.58) 122.93,73.45 123.22,73.16 123.25,73.16 CPU1.E65 ; v2(191.08,36.52) 191.39,36.21 192.51,36.21 192.84,35.88 C2428.2 ; v2(113.51,19.83) 113.59,19.83 114.17,20.41 ED6402.2 ; v2(109.33,40.43) 109.65,40.75 CPU1.AM8 ; v2(137.18,27.83) 137.36,28.01 PQ4405.4 ; v2(138.92,31.27) 138.92,31.15 139.24,30.83 PQ4405.1 ; PQ4306.4 24.07,77.3 24.31,77.54 24.74,77.54 v2(24.86,77.66) ; v2(191.39,29.86) 191.84,30.32 C2426.2 ; v2(21.72,79.11) 21.88,78.95 PQ4306.1 ; C2502.2 79.96,13.15 79.96,13.78 v2(79.98,13.81) ; PC5202.2 PC5213.2 101.47,7.88 v2(101.47,7.87) ; C4034.2 105,15.75 v2(105,15.45) ; v2(124.71,10.51) 124.71,10.28 124.24,9.81 Q7001.4 ; v2(139.52,40.71) 140.56,40.71 140.84,40.43 PQ4415.1 ; v2(138.73,35.77) 138.2,35.77 PR4449.2 ; Q7001.1 121.67,8.51 v2(121.41,8.25) ; v2(57.2,4.66) 56.84,4.66 56.5,4.32 U1703.3 ; v2(61.11,6.44) 60.69,6.44 60.44,6.19 U1701.3 ; PQ4415.4 138.02,38.74
  BOTTOM w0.432: C2429.2 199.25,38.04 v2(200.03,38.04)
  BOTTOM w0.457: v2(28.55,92.19) 28.55,92.32 29.35,93.12 U4301.3 29.35,94.49 28.56,95.28 PR4329.2 ; 186.31,45.71 187.36,44.66 C2423.2 ; v2(136.65,34.31) 136.65,34.31 137.04,33.91 137.04,33.65 ; C2418.2 198.26,38.14 C2410.2
  BOTTOM w0.508: v2(26.59,13.55) 26.53,13.49 25.91,13.49 R2717.2 ; v2(109.37,14.47) 109.37,14.34 109.71,14 C4102.2 ; C1702.2 61.35,3.79 v2(61.49,3.93) ; 3.16,65.43 HDMI1.22 ; HDMI1.22 4.6,64.44 ; HDMI1.22 6.04,65.43 ; HDD1.23 183.39,14.03 v2(183.54,13.89) ; v2(148.99,29.35) 149.21,29.14 D4304.1 ; v2(149.07,88.56) 149.07,88.05 149.08,88.04 PR4656.1 ; v2(73.63,5.78) 73.63,6.37 73.65,6.38 EC2503.2 ; v2(146.15,29.18) 146.67,29.18 PR4436.2 ; LCD1.43 74.88,97.71 74.5,97.32 74.5,94.15 v2(74.95,93.69) 76.15,94.89 LCD1.41 ; PQ4304.E 20.07,76.76 v2(19.56,76.24) ; 15.7,28.17 USB3.4 ; USB3.4 15.7,29.69 ; USB3.4 16.46,28.93 ; v2(179.45,25.8) 179.28,25.63 HDD1.22 ; R803.1 123.61,24.73 v2(123.01,24.73) ; v2(18.64,25.29) 19.24,25.29 EC8902.2 ; v2(185.98,40.86) 185.96,40.87 C2411.2 ; v2(71.8,9.49) 71.8,9.57 72.12,9.88 Q2505.S ; 6.06,99.45 USB1.21 ; USB1.21 4.72,100.28 ; USB1.21 7.39,100.28 ; USB1.21 6.06,101.12 ; PC4423.2 PC4424.2 PR4401.2 141.48,30.81 141.48,31.08 v2(141.83,31.44) ; 14.2,52.27 USB2.7 14.2,53.79 ; PC5118.2 v2(41.07,9.57) ; PD4303.3 14.97,80.8 v2(14.91,80.74) ; 14.2,33.19 USB3.7 14.2,31.67 ; R2445.1 190.54,29.15 C2413.2 191.39,29.19 v2(191.39,29.86) ; EC6502.2 130.34,20.32 130.71,19.96 v2(130.94,19.96) 131.29,19.96 131.48,20.15 EC6503.2 ; v2(105,15.45) 105,14.88 104.72,14.6 C4013.2 ; EC1708.2 64.21,8.18 C1711.2 65.06,8.17 v2(65.81,8.17) ; 7.95,23.94 7.31,24.58 USB3.13 6.2,24.58 5.43,23.82 ; v2(184.25,44.67) 184.72,44.2 R2510.2 R2449.1 ; PC5409.2 PC5408.2 58.67,10.41 v2(58.49,10.58) 58.83,10.92 PU5401.1 ; PC5410.2 43.23,95.06 v2(43.18,95.01) ; C2420.2 186.73,29.19 186.46,29.46 v2(186.46,29.89) ; PC4307.2 25.55,83.81 v3(26.34,83.02) ; 2.19,87.3 USB1.13 3.52,88.13 ; v2(103,21.3) 103.15,21.15 EC1704.2 EC1711.2 ; PC4810.2 148.23,88.64 v2(148.26,88.61) ; C1806.2 EC1808.2 R1816.2 68.18,1.91 v2(68.3,1.79) ; v2(59.43,6.8) 59.41,6.82 PU5402.2 ; v2(81.89,22.72) 80.25,21.09 DM1.262 ; EC4307.2 152.64,29.52 EC4308.2 152.8,30.92 PC4419.2 152.42,31.3 152.42,32.2 v2(152.45,32.22) ; v2(114.15,32.94) 113.94,32.73 113.94,32.34 R2009.2 ; R1719.2 66.53,6.66 v2(66.34,6.85) ; v2(141.02,37.41) 139.76,37.41 PR4424.2 ; EC1707.2 107.75,19.19 108.08,18.86 v2(108.23,18.86) ; EC6401.2 120.93,9.07 v2(120.93,8.7) ; v2(153.08,52.54) 152.93,52.39 152.93,52.27 152.65,51.99 PC5001.2 ; v2(123.52,17.31) 123.52,17.7 123.13,18.08 Q6503.S ; v2(126.85,16.37) 126.85,16.35 126.85,16.34 KBBD1.46 ; TCBD1.34 73.15,96.46 v2(72.69,96) ; v2(140.29,27.56) 140.31,27.56 140.35,27.6 140.69,27.6 141.12,28.03 C2601.2 141.41,28.25 141.41,28.95 PC4430.2 ; D4305.1 150.07,24.51 v2(150.16,24.6) ; R2417.2 C2412.2 191.78,41 191.49,40.71 191.49,40.45 v2(191.31,40.28) 191.31,40.25 191.5,40.06 Q2408.S 192.53,40.12 192.53,40.2 193.76,41.43 R2611.2 ; v2(181.94,24.45) 181.94,24.68 182.32,25.06 HDD1.21 ; v2(47.95,1.69) PC5110.2 ; v2(112.19,11.6) 112.24,11.65 113.09,11.65 C4101.2 ; PC5406.2 62.91,8.81 62.53,8.42 v2(62.46,8.42) 62.08,8.81 PR5401.2 ; USB2.4 15.7,50.29 ; USB2.4 15.7,48.77 ; USB2.4 16.46,49.53 ; 2.19,101.12 USB1.22 3.52,100.28 ; v2(150.93,90.14) 151.41,89.65 PR4661.2 ; USB1.20 9.48,98.68 ; USB1.20 7.3,98.68 ; USB1.20 8.39,99.47 ; R4006.2 117.76,18.73 v2(118.26,18.73) 118.9,18.73 119.73,17.9 C4009.2 ; 137.04,33.65 PC4432.2 PC4427.2 ; EC2502.2 83.56,13.06 83.42,13.06 82.98,13.5 v2(82.98,13.78) ; v2(46.02,1.67) PC5113.2 ; v2(133.96,99.53) 134.36,99.13 PC4814.2 ; v2(150.8,61.43) 151.29,61.93 PC4708.2 151.23,62.31 PC4707.2 ; PC5407.2 54.15,4.25 v2(54.15,4.84) ; 3.16,83.73 HDMI1.23 ; HDMI1.23 4.6,84.72 ; HDMI1.23 6.04,83.73 ; 14.95,58.54 USB2.10 ; USB2.10 14.95,60.32 ; USB2.10 16.63,59.43 ; 4.72,88.13 USB1.14 ; USB1.14 7.39,88.13 ; USB1.14 6.06,87.3 ; USB1.14 6.06,88.97 ; v2(18.06,57.22) 18.07,57.2 C3401.2 C3403.2 ; ED6401.2 121.03,12.23 121.61,12.23 v2(121.72,12.13) ; R2030.2 109.26,30.69 108.63,30.06 v2(108.63,29.84) 109.71,29.84 R2008.2 ; PR5409.2 PC5427.2 40.18,94.86 39.93,94.61 v2(39.93,94.45) ; 6.5,41.55 USB3.12 7.19,40.28 7.87,40.96 ; C1802.1 v2(130.3,49.6) ; v2(160.45,103.34) 160.51,103.28 PC4610.2 ; PR4652.2 151.76,99.03 151.84,99.1 v2(152.24,99.1) ; PC5119.2 46.85,12.95 46.98,12.95 47.53,12.39 PC5111.2 47.85,12.11 v2(48.33,12.59) ; v2(102.49,100.3) 102.61,100.17 102.61,98.67 101.67,97.73 101.57,97.73 LCD1.44 ; v2(144.32,41.75) 144.12,41.55 144.12,40.91 PC4412.2 ; v2(185.8,36.59) 185.76,36.55 C2414.2 ; v2(70.51,12.69) 70.51,12.1 Q1702.4 ; v2(79.98,13.81) 79.78,13.81 79.5,14.09 C2501.2 ; 8.39,88.95 USB1.15 ; USB1.15 7.3,89.73 ; USB1.15 9.48,89.73 ; EC6504.2 v2(131.62,23.46) ; PR4413.1 136.51,28.52 C2602.2 136.93,28.08 v2(137.18,27.83) ; v2(39.55,21.73) 40.77,20.51 DM2.262 ; PC4807.2 152.58,78.2 PC4808.2 152.63,77.74 v2(152.2,77.31) ; C2403.2 188.53,39.25 v2(188.44,39.16) ; PR5106.1 PC5138.2 53.25,2.32 53.57,2 v2(53.57,1.64) ; PR4409.2 147.66,31.77 PC4413.2 147.95,31.82 v2(148.33,32.2) ; USB3.11 14.95,26.92 ; USB3.11 16.63,26.03 ; USB3.11 14.95,25.14 ; C2721.2 24.65,26.8 v2(24.71,26.74) ; R6509.2 139.13,21.37 138.81,21.68 138.78,21.68 v2(138.76,21.71) 138.71,21.71 138.15,22.27 Q6501.S ; PR4433.2 139.63,31.98 v2(138.92,31.27) ; DM2.261 41.27,88.11 40.5,87.34 v2(40.23,87.34) ; v2(19.61,61.31) 19.65,61.27 Q5704.S ; PD4302.1 17.9,70.76 v2(17.83,70.83) ; 11.1,66.34 HDMI1.20 11.1,68.32 ; SPR4.1 116,89.88 v2(115.47,89.35) ; v2(142.59,88.94) 142.39,89.15 PC4847.2 141.68,89.57 141.8,89.7 PC4846.2 ; v2(127.56,19.7) 127.56,19.87 127.57,19.88 127.57,20.26 EC6501.2 ; 6.27,97.41 USB1.B1 6.85,98.4 ; v2(144.59,61.71) 144.59,61.76 PC4709.2 ; v2(38.4,9.82) 38.38,9.82 38.28,9.72 PC5114.2 ; PC4507.2 164.87,57.75 165.1,57.98 v2(165.1,58.54) ; v2(63.93,3.95) 63.93,3.91 64.11,3.73 Q1802.S ; EU3602.2 20.57,53.23 v2(20.55,53.26) ; v2(96.72,9.57) 96.72,10.32 EC1710.2 97.56,11.15 EC4001.2 98.25,11.18 98.25,11.92 C4014.2 ; G1801.1 68.04,5.58 v2(68.04,6.82) 68.32,7.1 Q1701.1 ; PC5414.2 45.54,97.12 v2(45.72,97.3) ; C1703.2 60.67,2.43 EC8912.2 60.56,2.38 EC1709.2 v2(60.56,3.94) ; v2(132.28,70.2) 132.47,70.01 R402.2 ; v2(21.61,83.25) 21.61,82.63 U4302.3 ; C2722.2 18.43,26.71 v2(17.8,26.71) ; 14.95,39.72 USB3.10 14.95,37.94 ; C2410.2 C2429.2 ; EU3604.2 v2(19.53,33.16) ; 10.8,89.44 HS1.1 13.73,86.51 ; C1801.1 v2(130.25,52.16) ; PR5104.2 51.41,1.74 v2(51.48,1.67) ; v2(23.54,88.15) 23.54,88.91 DCIN1.10 ; USB2.11 14.95,47.52 ; USB2.11 16.63,46.63 ; USB2.11 14.95,45.74 ; v2(189.05,42.61) 189.05,43.21 189.08,43.23 C2402.2 ; v2(97.64,54.55) 97.64,55.16 97.99,55.52 99.11,55.52 99.13,55.54 ; C2610.2 144.75,25.15 144.11,25.15 v2(143.69,24.73) ; 8.08,44.47 7.36,45.18 USB2.13 6.5,43.88 ; v2(198.8,45.05) 198.17,45.05 197.81,44.7 197.47,44.7 C2409.2 R2448.2 ; 6.27,91.01 USB1.B12 6.85,90.02 ; v2(154.86,75.91) 155.16,76.21 FAN1.2 ; IOBD1.53 169.8,59.61 v2(169.85,59.66) 169.85,61.12 170.54,61.81 IOBD1.51 ; PC5120.2 47.83,14.65 48.31,15.13 v2(48.31,15.36) ; 138.02,38.74 137.71,38.42 v2(136.75,38.42) ; v2(22.68,72.48) 22.94,72.22 PQ4302.E ; Q2701.S v2(22.72,28.22) ; PC5115.2 43.38,9.21 v2(43.36,9.24) ; C6503.2 v2(126.19,22.57)
  vias: v1(15.92,42.89) v1(18.9,61.31) v1(19.45,27.35) v1(21.61,65.09) v1(22.6,17.77) v1(26.8,34.1) v1(48,22.37) v1(58.14,25.14) v1(60.98,92.88) v1(61.49,8.27) v1(73.43,87.75) v1(77.67,27.14) v1(83.34,50.49) v1(90.83,68.37) v1(116.66,54.27) v1(116.94,111.4) v1(116.89,50.05) v1(118.11,39.21) v1(121.49,83.99) v1(121.46,62.15) v1(122.6,100.91) v1(128.65,99.86) v1(137.44,71.75) v1(138.35,48.81) v1(139.19,61.33) v1(140.26,45.18) v1(141.17,85.13) v1(144.12,36.39) v1(146.23,75.68) v1(171.7,94.45) v1(194.26,8.5) v2(0.81,12.16) v2(0.76,11.2) v2(0.76,6.12) v2(0.76,1.04) v2(0.91,3.83) v2(0.96,21.84) v2(1.73,84.98) v2(1.75,86.58) v2(1.75,83.28) v2(2.3,65.72) v2(3.27,6.54) v2(3.38,8.47) v2(3.63,21.91) v2(3.61,0.83) v2(4.04,86.07) v2(4.11,101.18) v2(4.88,23.13) v2(5.41,62.86) v2(5.59,42.59) v2(6.32,8.53) v2(6.33,0.76) v2(6.45,6.52) v2(6.96,83.2) v2(7.13,65.97) v2(7.54,84.04) v2(7.57,2.71) v2(8,63.29) v2(8.58,101.16) v2(8.91,65.35) v2(8.86,8.45) v2(8.94,6.7) v2(9.35,90.82) v2(9.27,42.61) v2(9.65,61.74) v2(9.83,2.66) v2(10.16,98.16) v2(10.21,7.84) v2(10.31,80.2) v2(10.44,97.04) v2(11.05,95.16) v2(11.15,63.49) v2(11.11,44.42) v2(11.43,42.59) v2(11.41,0.76) v2(11.54,61.64) v2(11.54,41.04) v2(11.91,91.48) v2(11.89,90.34) v2(12.29,93.34) v2(12.95,81.02) v2(13.05,82.62) v2(13.41,61.56) v2(13.54,42.64) v2(14.45,64.48) v2(14.6,40.58) v2(14.91,79.85) v2(15.04,81.75) v2(15.04,66.64) v2(14.98,62.6) v2(15.64,10.33) v2(15.9,60.98) v2(16.13,88.71) v2(16.38,65.19) v2(16.38,63.97) v2(16.49,0.76) v2(16.81,95.44) v2(16.91,62.6) v2(17.83,42.13) v2(18.85,1.59) v2(19.68,7.31) v2(19.94,93.92) v2(20.78,98.26) v2(21.26,65.88) v2(21.49,99.56) v2(21.77,48.33) v2(21.77,26) v2(21.89,17.11) v2(22.02,65.88) v2(21.97,43.76) v2(22.35,48.99) v2(22.35,47.72) v2(22.53,17.11) v2(22.65,65.84) v2(22.66,64.99) v2(22.66,64.35) v2(22.66,26.25) v2(22.88,48.33) v2(22.99,91.38) v2(23.24,18.46) v2(23.24,17.8) v2(23.24,17.11) v2(23.24,16.45) v2(23.24,15.79) v2(23.26,98.16) v2(23.42,65.88) v2(23.74,92.57) v2(23.8,93.46) v2(23.93,17.11) v2(24.05,65.88) v2(24.64,100.17) v2(24.56,17.09) v2(24.69,79.21) v2(25.4,99.51) v2(25.45,51.86) v2(25.63,32.99) v2(25.68,101.24) v2(25.7,95.67) v2(25.65,31.06) v2(26.11,49.5) v2(26.59,100.3) v2(26.57,37.63) v2(26.69,55.13) v2(26.92,50.92) v2(27.25,55.44) v2(27.63,101.25) v2(27.56,73.09) v2(28.47,32.83) v2(28.55,30.73) v2(28.8,100.83) v2(28.83,50.79) v2(28.75,39.97) v2(29.36,46.8) v2(30.2,56.94) v2(30.81,50.92) v2(30.86,52.77) v2(31.67,56.1) v2(31.73,0.76) v2(32.43,41.75) v2(32.69,59.15) v2(33.45,42.76) v2(33.45,41.75) v2(33.45,40.73) v2(33.7,61.18) v2(33.7,60.16) v2(33.7,59.15) v2(33.7,58.13) v2(33.7,57.12) v2(34.47,41.75) v2(34.72,59.15) v2(35.58,21.76) v2(36.81,0.76) v2(37.06,28.92) v2(37.74,103.22) v2(37.72,28.92) v2(38.4,28.92) v2(39.17,31.46) v2(39.17,30.57) v2(39.17,29.68) v2(39.17,28.92) v2(39.17,28.16) v2(39.17,27.27) v2(39.17,26.38) v2(39.6,103.25) v2(39.93,28.92) v2(40.61,28.92) v2(41.07,11.4) v2(41.3,28.92) v2(41.93,11.42) v2(41.89,0.76) v2(41.96,12.28) v2(41.96,10.63) v2(42.75,60.19) v2(42.75,59) v2(42.8,61.69) v2(42.8,61.05) v2(42.77,57.52) v2(42.8,56.35) v2(42.77,55.49) v2(42.8,54.32) v2(42.85,11.4) v2(44.12,66.69) v2(44.83,64.94) v2(46.15,70.32) v2(46.3,67.4) v2(46.35,68.57) v2(46.35,65.32) v2(46.35,30.95) v2(46.4,28.95) v2(47.93,6.95) v2(50.32,7.2) v2(52.05,0.76) v2(52.25,90.39) v2(52.63,90.9) v2(54.57,78.5) v2(57.13,0.76) v2(59.87,94.58) v2(61.06,94) v2(62.21,0.76) v2(63.47,98.59) v2(64.97,89.2) v2(66.93,19.42) v2(67.29,0.76) v2(67.46,90.01) v2(67.47,85.3) v2(67.82,78.3) v2(68.43,15.69) v2(69.06,15.69) v2(69.14,1.67) v2(70.05,1.69) v2(70.43,89.91) v2(70.94,1.67) v2(71.19,89.88) v2(71.63,1.67) v2(72.26,1.67) v2(72.37,0.76) v2(72.74,89.93) v2(73.81,89.42) v2(74.53,47.75) v2(74.63,50.29) v2(74.9,2.76) v2(76.01,51.66) v2(76.94,59.51) v2(77.34,91.02) v2(77.41,106.52) v2(77.45,0.76) v2(77.65,51.66) v2(77.82,109.92) v2(77.98,91.02) v2(78.17,59.56) v2(78.43,68.05) v2(78.61,91.02) v2(78.87,111.52) v2(79.25,91.02) v2(79.31,51.71) v2(79.45,68.05) v2(80.24,112.56) v2(80.32,68.77) v2(80.6,59.53) v2(80.87,51.66) v2(81.85,68.9) v2(82,51.58) v2(82.53,0.76) v2(82.83,96) v2(82.83,4.79) v2(83.09,67.97) v2(83.09,59.19) v2(83.77,3.32) v2(85.48,93.29) v2(86.33,113.16) v2(87.61,0.76) v2(91.41,113.16) v2(92.69,0.76) v2(94.99,76.34) v2(95.53,77.56) v2(96.26,80.41) v2(96.49,113.16) v2(96.72,73.27) v2(97.79,69.26) v2(97.77,0.76) v2(97.94,70.76) v2(97.96,72.61) v2(98.04,58.36) v2(98.32,48.38) v2(99.03,23.89) v2(99.57,54.19) v2(99.67,105.88) v2(99.92,50.05) v2(100.05,48.38) v2(100.18,18.97) v2(100.4,52.75) v2(100.91,51.2) v2(101.24,22.06) v2(101.57,113.16) v2(101.87,58.57) v2(102.06,105.63) v2(102.16,104.99) v2(102.85,0.76) v2(104.37,96.51) v2(106.27,8.58) v2(106.65,113.16) v2(107.56,33.42) v2(108.03,46.83) v2(108.08,83.61) v2(108.51,16.53) v2(109.02,88.99) v2(109.5,82.26) v2(110.69,18.74) v2(110.84,48.12) v2(111.56,34.48) v2(111.73,113.16) v2(112.39,79.19) v2(112.95,81.04) v2(113.82,75.4) v2(113.82,74.75) v2(113.82,73.45) v2(113.82,72.8) v2(114.48,22.14) v2(115.21,40.76) v2(115.21,40.08) v2(116.81,113.16) v2(120.92,43.17) v2(121.89,113.16) v2(122.22,49.57) v2(126.42,59.51) v2(126.97,113.16) v2(127.13,59.53) v2(127.96,49.34) v2(128.23,40.61) v2(128.24,38.7) v2(128.27,42.84) v2(128.29,16.2) v2(128.37,65.88) v2(128.5,64.2) v2(128.47,62.42) v2(128.67,48.85) v2(128.86,47.68) v2(129.06,59.53) v2(129.31,63.26) v2(130.78,64.81) v2(130.99,5.93) v2(131.62,5.93) v2(132.05,113.16) v2(132.72,41.74) v2(132.69,41.06) v2(132.79,42.94) v2(133.86,45.25) v2(134.29,102.96) v2(134.29,101.31) v2(136.09,47.36) v2(137.13,113.16) v2(138.81,7.28) v2(140.92,96.89) v2(140.94,96.26) v2(140.94,95.6) v2(140.97,94.91) v2(140.99,92.65) v2(141.35,7.28) v2(141.65,96.92) v2(141.68,96.28) v2(141.68,95.62) v2(141.65,94.89) v2(141.65,94.15) v2(141.68,93.46) v2(141.65,92.63) v2(142.21,113.16) v2(142.31,96.92) v2(142.34,96.28) v2(142.34,95.62) v2(142.34,94.89) v2(142.31,94.15) v2(142.34,93.46) v2(142.29,92.65) v2(142.44,34.66) v2(142.95,96.92) v2(142.92,92.65) v2(142.97,96.28) v2(142.97,95.62) v2(143.03,94.91) v2(143,94.17) v2(143.03,93.49) v2(143.15,35.35) v2(143.18,34.66) v2(143.2,34) v2(143.91,34.64) v2(143.86,7.28) v2(147.29,113.16) v2(150.19,26.94) v2(150.42,19.75) v2(150.59,57.37) v2(150.8,23.84) v2(151.26,57.37) v2(151.89,57.37) v2(152.02,69.64) v2(152.04,69) v2(152.04,68.34) v2(152.07,67.66) v2(152.09,65.4) v2(152.25,85.69) v2(152.27,85.06) v2(152.27,84.4) v2(152.3,83.71) v2(152.32,81.45) v2(152.37,113.16) v2(152.75,69.66) v2(152.78,69.03) v2(152.78,68.37) v2(152.75,67.63) v2(152.75,66.89) v2(152.78,66.21) v2(152.75,65.37) v2(152.91,85.72) v2(152.93,85.08) v2(152.93,84.42) v2(152.93,83.68) v2(152.98,82.95) v2(153.01,82.26) v2(152.98,81.42) v2(153.21,53.69) v2(153.41,69.66) v2(153.44,69.03) v2(153.44,68.37) v2(153.44,67.63) v2(153.41,66.89) v2(153.44,66.21) v2(153.36,55.26) v2(153.57,85.72) v2(153.59,85.08) v2(153.59,84.42) v2(153.59,83.68) v2(153.64,82.95) v2(153.62,81.45) v2(153.67,82.26) v2(154.05,69.66) v2(154.02,65.4) v2(154.07,69.03) v2(154.07,68.37) v2(154.13,67.66) v2(154.1,66.92) v2(154.13,66.23) v2(154.2,85.72) v2(154.23,85.08) v2(154.23,84.42) v2(154.28,83.71) v2(154.33,82.97) v2(154.25,81.45) v2(154.35,82.29) v2(156.82,1.67) v2(157.45,113.16) v2(157.59,2.38) v2(160.39,98.8) v2(160.88,61.43) v2(161.19,60.88) v2(161.26,58.46) v2(161.34,55.97) v2(161.97,55.97) v2(162.53,113.16) v2(163.17,19.55) v2(164.39,19.5) v2(165.54,19.44) v2(166.24,54.96) v2(166.29,20.26) v2(166.94,112.01) v2(167.03,106.67) v2(167,55.87) v2(167.82,16.6) v2(168.58,16.6) v2(169.87,46.42) v2(170.23,15.97) v2(170.99,104.64) v2(171.85,104.59) v2(174.09,79.37) v2(174.72,79.37) v2(174.67,17.42) v2(175.08,11.88) v2(176.2,59.05) v2(176.18,44.56) v2(176.38,60.98) v2(176.4,51.55) v2(176.63,50.44) v2(176.68,53.56) v2(177.21,11.88) v2(177.77,64.71) v2(178.26,11.93) v2(179.22,97.71) v2(179.73,96.89) v2(179.68,64.45) v2(179.75,104.51) v2(179.8,69) v2(179.94,83.45) v2(179.93,74.95) v2(179.93,71.42) v2(179.93,62.37) v2(179.94,59.15) v2(179.96,57.27) v2(180.62,53.23) v2(180.92,52.21) v2(182.19,49.11) v2(193.17,32.76) v2(193.55,22.57) v2(193.65,25.42) v2(193.6,17.49) v2(194.55,6.5) v2(197.2,9.95) v2(197.92,9.95) v2(198.58,9.92) v2(198.85,45.69) v2(200.28,45.15) v2(200.28,43.86) v2(200.58,10.38) v2(201.47,35.6) v2(201.98,8.47) v2(202.46,35.35) v2(202.94,6.57) v2(203.27,35.14) v2(203.53,20.46) v2(203.53,16.35) v2(203.5,15.71) v2(203.55,21.15) v2(203.83,6.72) v2(203.96,34.87) v2(204.09,33) v2(204.09,12.68) v2(204.09,11.7) v2(204.09,9.97) v2(204.09,7.6) v3(17.32,42.76) v3(17.58,34.64) v3(18.21,35.22) v3(19,34.92) v3(22.4,33.87) v3(25.07,55.74) v3(26.52,88.41) v3(32.05,8.65) v3(32.05,7.81) v3(32.05,6.95) v3(32.05,6.06) v3(32.23,4.08) v3(32.21,3.04) v3(33.12,4.08) v3(33.22,3.04) v3(52.37,11.01) v3(52.67,6.25) v3(53.26,11.01) v3(54.15,11.01) v3(54.19,6.15) v3(54.65,6.98) v3(86.13,3.06) v3(86.16,3.9) v3(86.28,7.71) v3(86.28,6.44) v3(86.28,5.3) v3(86.99,3.88) v3(86.97,3.04) v3(87.81,2.35) v3(90.09,105.38) v3(90.47,106.52) v3(91.03,105.5) v3(95.78,105.88) v3(96.64,105.94) v3(97.31,19.6) v3(98.14,19.75) v3(104.42,2.18) v3(105.26,2.18) v3(106.2,2.07) v3(106.81,99.94) v3(107.01,8.6) v3(107.11,2.07) v3(107.87,8.6) v3(108.25,2.07) v3(108.74,8.6) v3(109.22,2.07) v3(110.16,2.07) v3(111.68,99.91) v3(112.57,99.91) v3(112.83,55.08) v3(113.71,55.08) v3(114.22,62.32) v3(114.6,55.08) v3(114.98,67.28) v3(115.01,66.44) v3(115.11,62.32) v3(115.49,55.08) v3(115.87,67.28) v3(115.9,66.44) v3(116,62.32) v3(116.76,67.28) v3(116.79,66.44) v3(117.37,109.08) v3(117.65,55.08) v3(117.78,108.3) v3(117.78,62.32) v3(118.21,109.06) v3(118.54,55.08) v3(118.67,108.32) v3(118.67,62.32) v3(119.43,55.08) v3(119.56,62.32) v3(120.42,88.08) v3(120.42,87.12) v3(120.45,86.15) v3(120.44,85.19) v3(120.45,84.25) v3(120.45,62.32) v3(121.44,88.13) v3(121.44,87.17) v3(121.44,86.2) v3(121.42,85.21) v3(122.35,85.21) v3(122.37,88.13) v3(122.37,87.17) v3(122.37,86.2) v3(123.37,101.31) v3(123.37,100.42) v3(124.64,101.31) v3(124.64,100.42) v3(125.78,101.31) v3(125.78,100.42) v3(126.92,101.31) v3(126.92,100.42) v3(128.07,101.31) v3(128.07,100.42) v3(129.21,101.31) v3(129.21,100.42) v3(135.69,71.72) v3(136.07,70.83) v3(136.45,51.53) v3(136.45,50.26) v3(137.03,62.2) v3(137.08,61.05) v3(137.21,52.04) v3(137.21,50.77) v3(137.21,49.5) v3(138.05,62.2) v3(138.1,61.05) v3(138.86,103.14) v3(138.86,102.25) v3(138.94,62.2) v3(139.62,100.68) v3(139.88,102.96) v3(139.88,101.82) v3(140,104.99) v3(140,103.98) v3(140.24,71.57) v3(140.51,100.68) v3(140.51,44.31) v3(141.15,99.79) v3(141.15,98.9) v3(141.15,71.21) v3(141.27,86.96) v3(141.4,77.44) v3(141.4,76.29) v3(141.4,72.1) v3(141.37,44.64) v3(141.7,86.22) v3(142.19,61.13) v3(142.16,45.03) v3(142.29,76.29) v3(142.54,77.44) v3(142.54,72.48) v3(142.54,71.47) v3(142.54,70.58) v3(142.59,86.22) v3(143.08,61.13) v3(143.31,76.29) v3(143.43,72.48) v3(143.43,71.47) v3(143.43,70.58) v3(143.48,86.22) v3(143.56,77.44) v3(143.97,61.13) v3(144.32,76.29) v3(144.37,86.22) v3(144.45,72.61) v3(144.45,71.59) v3(144.45,70.58) v3(144.58,77.44) v3(145.57,76.42) v3(147.98,92.78) v3(147.98,91.89) v3(148.87,92.78) v3(148.87,91.89) v3(149.6,100.17) v3(149.66,101.06) v3(149.66,99.28) v3(149.66,98.39) v3(149.66,56.86) v3(149.93,103.01) v3(149.93,101.95) v3(149.93,57.73) v3(152.83,72.91) v3(152.83,72.03) v3(153.74,72.86) v3(153.74,72.03) v3(154.63,72.89) v3(154.63,72.03) v3(154.96,52.37) v3(157.74,33.34) v3(157.74,32.5) v3(158.29,73.45) v3(158.29,72.56) v3(158.58,33.34) v3(158.58,32.5) v3(159.18,44.54) v3(159.43,75.15) v3(159.43,74.26) v3(159.46,33.34) v3(159.46,32.5) v3(159.92,79.67) v3(160.2,45.43) v3(160.2,44.54) v3(160.45,75.15) v3(160.45,74.26) v3(160.75,79.7) v3(161.09,45.43) v3(161.09,44.54) v3(161.39,78.91) v3(161.54,80.05) v3(161.47,75.28) v3(161.47,74.39) v3(161.47,73.45) v3(161.47,72.56) v3(162.1,45.43) v3(162.1,44.54) v3(162.25,79.19) v3(162.25,78.3) v3(163.29,87.15) v3(163.29,65.63) v3(163.32,64.74) v3(163.29,63.85) v3(163.75,86.45) v3(165.56,89.2) v3(166.09,90.97) v3(166.44,89.2) v3(166.5,90.06) v3(169.82,34.38) v3(169.82,33.54) v3(170.13,28.11) v3(170.74,29.18) v3(170.94,28.34) v3(171.35,29.79) v3(171.55,28.95) v3(176.99,22.93) v3(176.96,22.09) v3(197.53,12.28) v3(197.53,11.4) v3(198.42,12.28) v3(198.42,11.4)
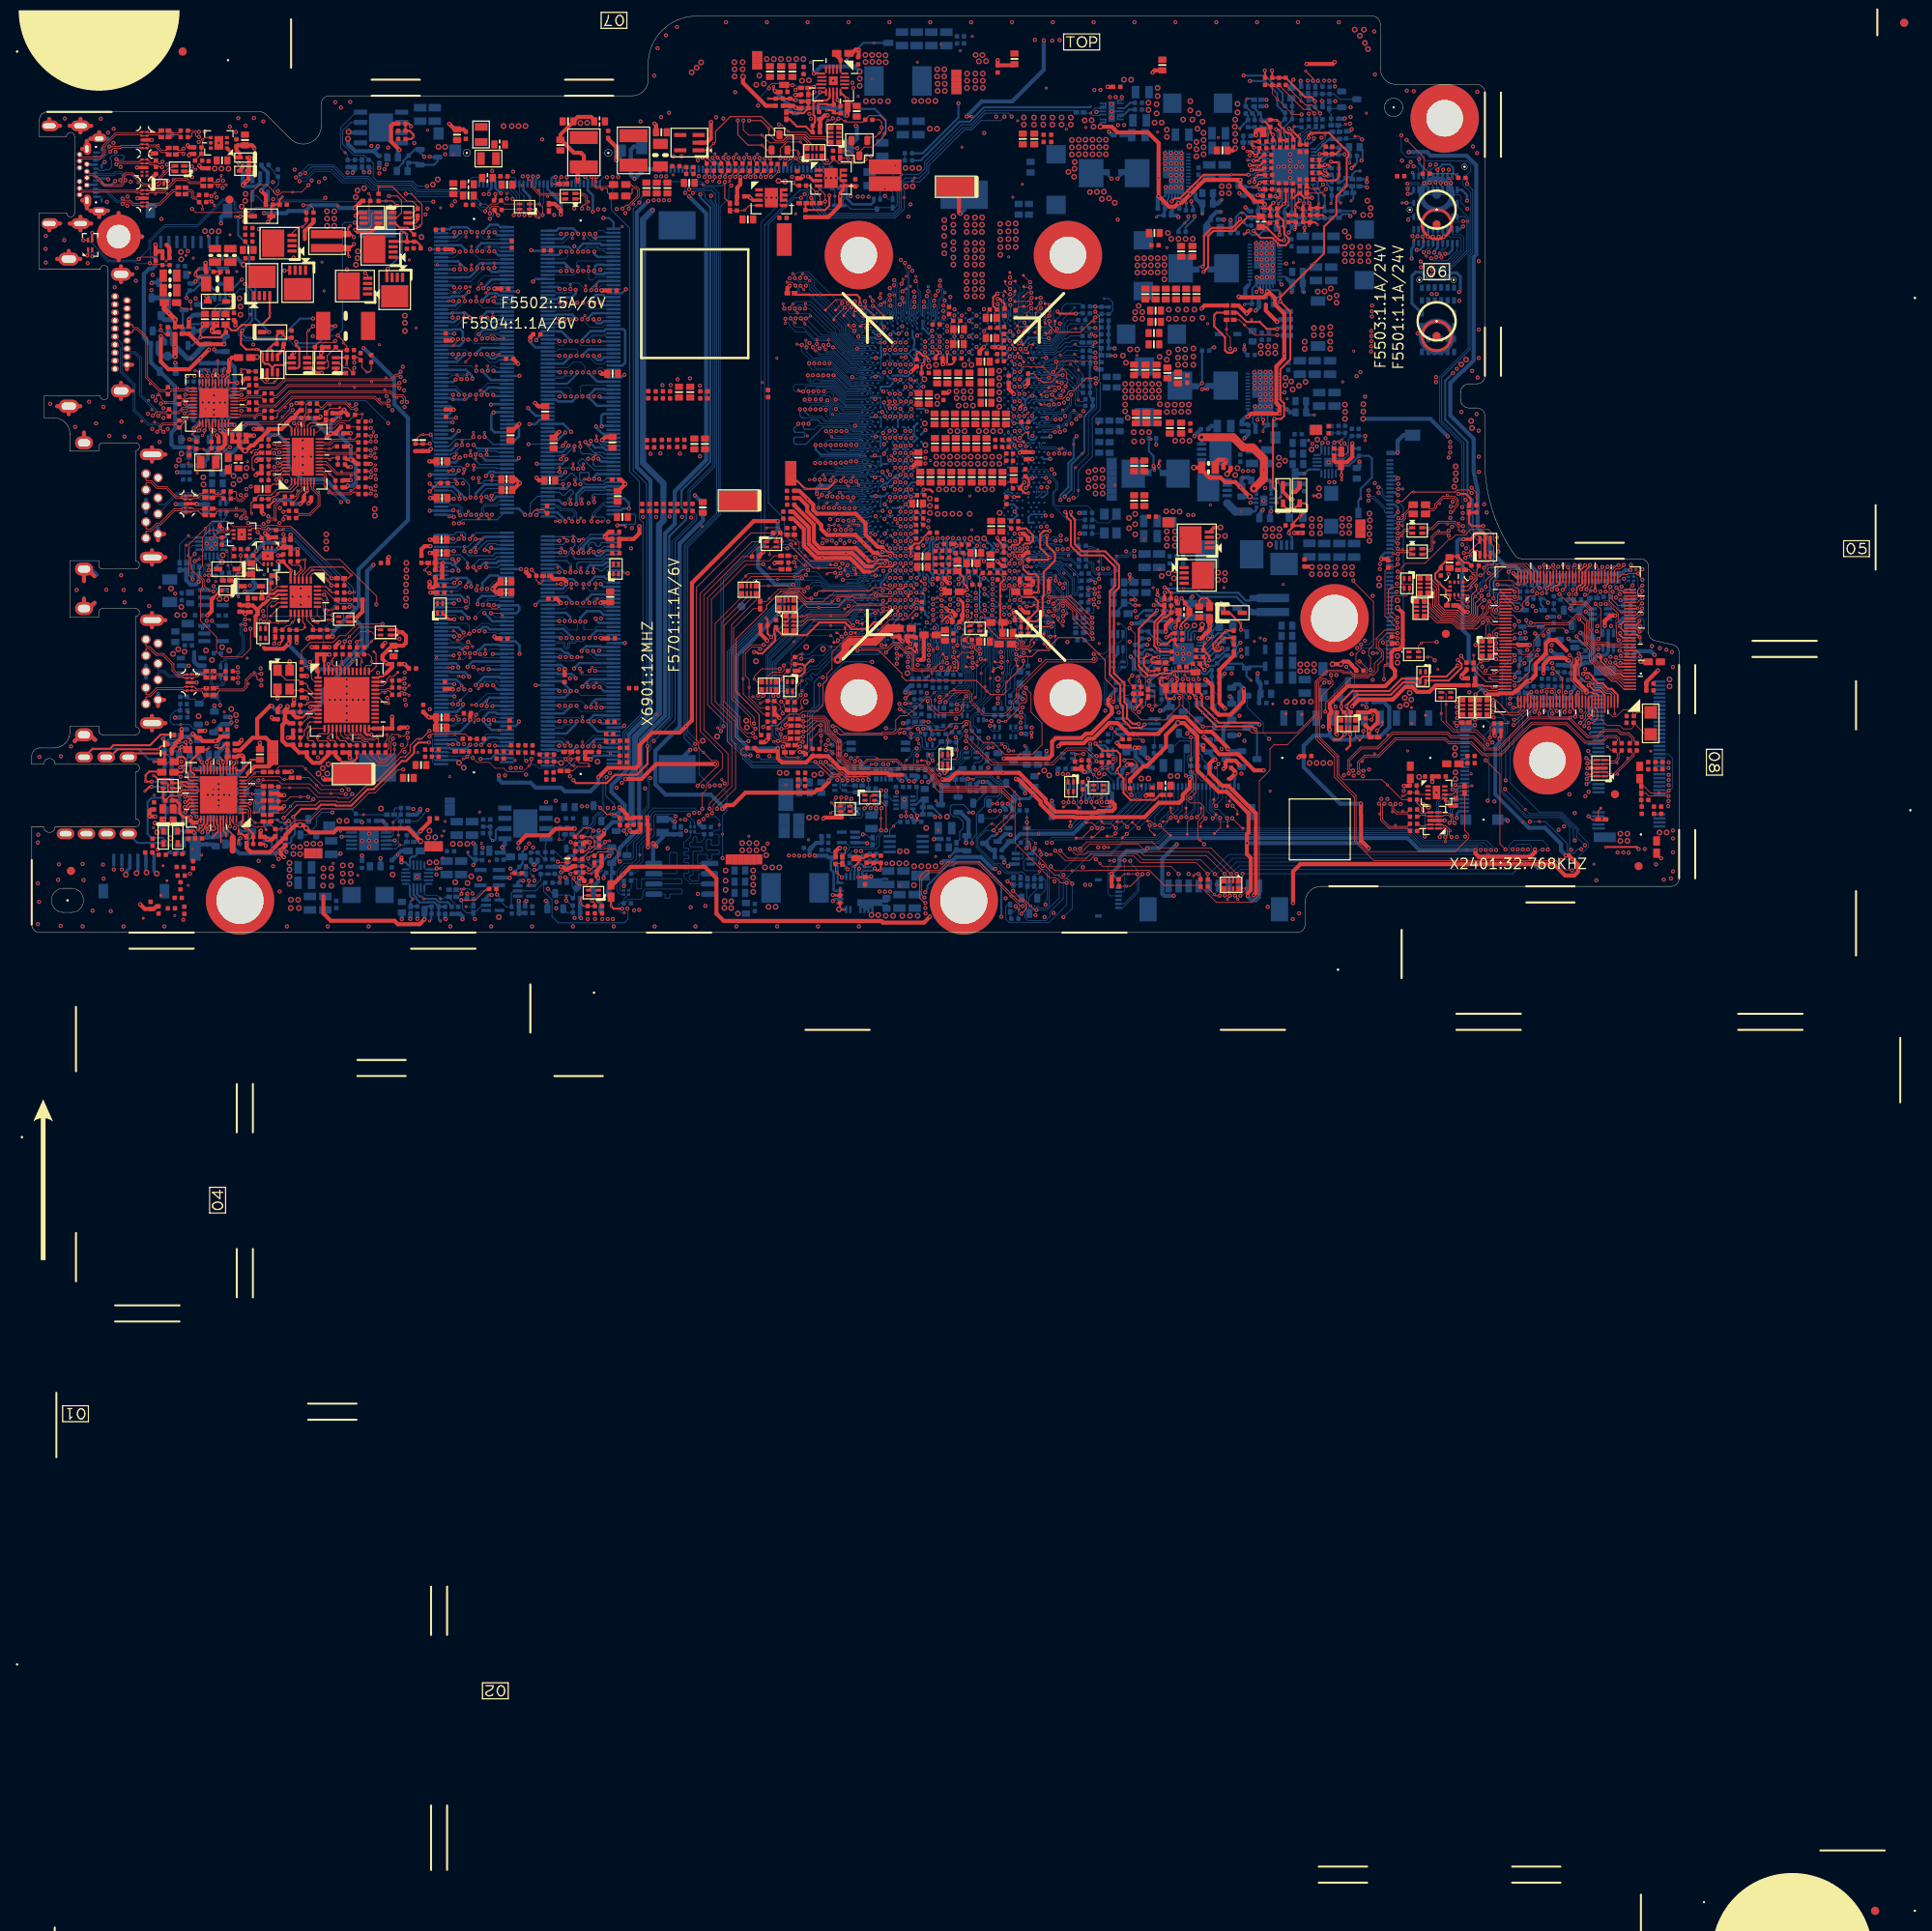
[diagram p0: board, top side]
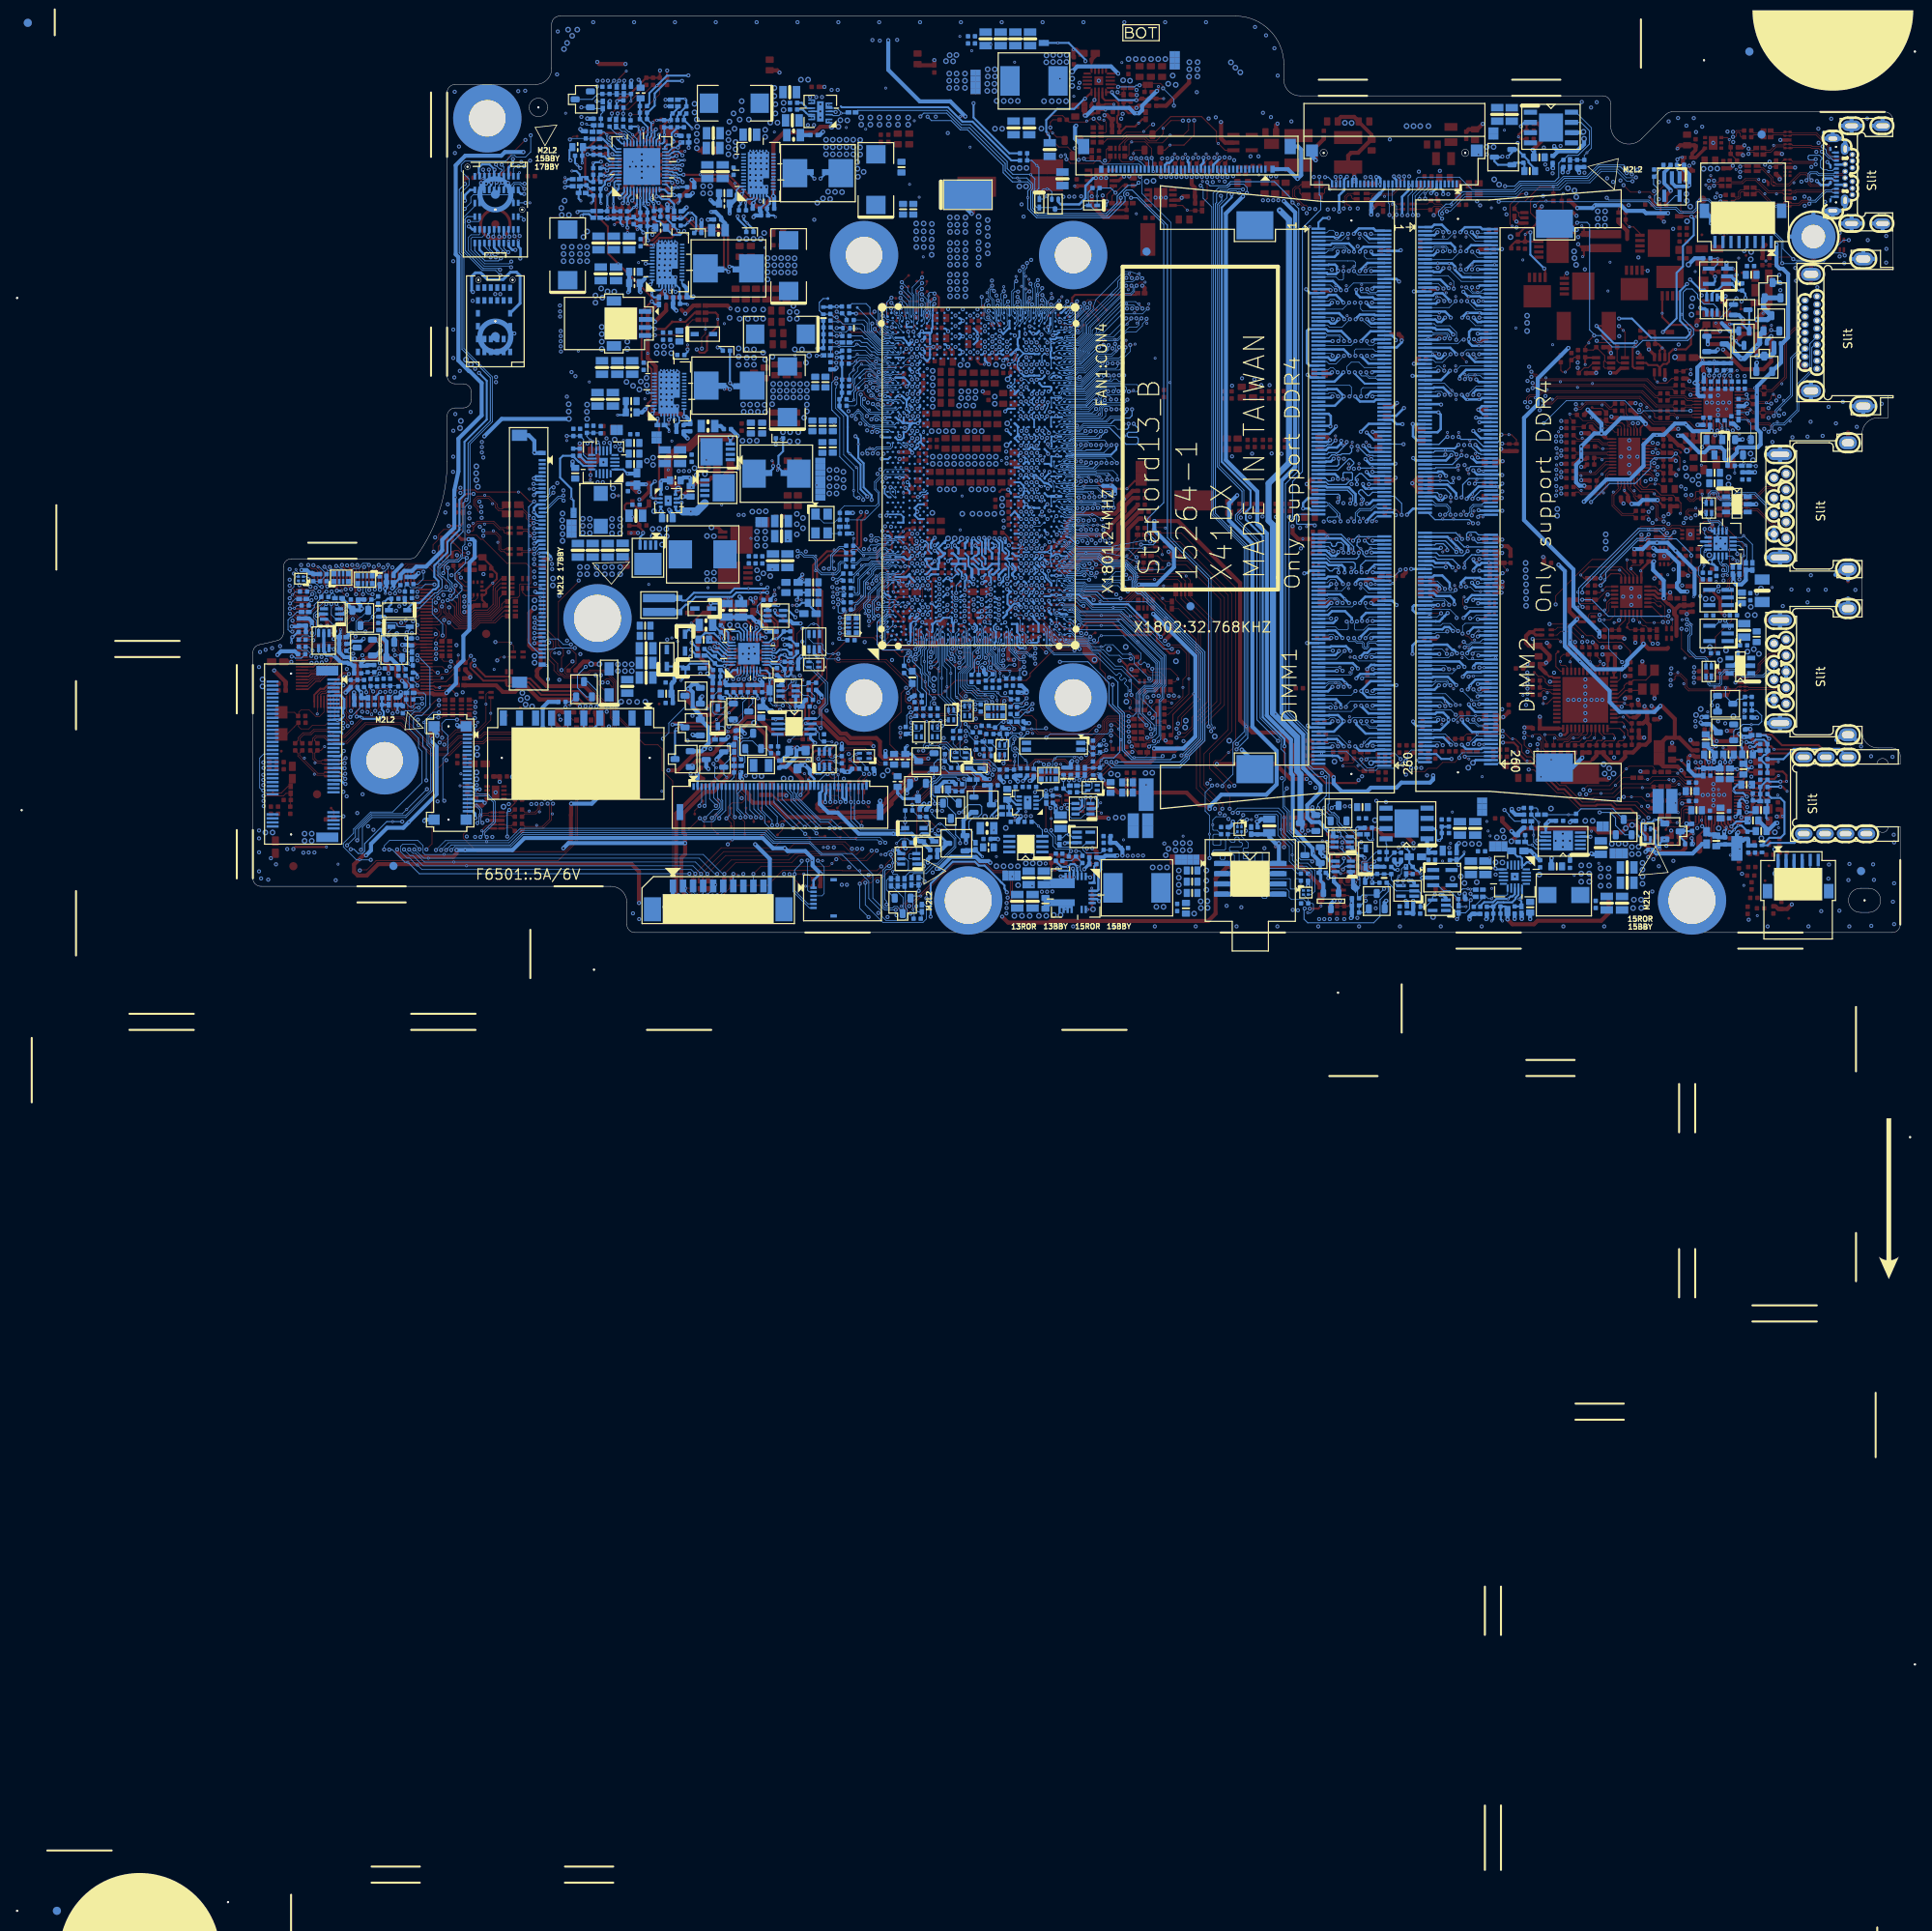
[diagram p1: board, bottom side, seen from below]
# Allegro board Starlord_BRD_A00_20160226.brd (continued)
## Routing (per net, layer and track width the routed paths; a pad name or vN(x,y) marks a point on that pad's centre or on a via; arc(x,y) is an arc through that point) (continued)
V0.85A_VID0: length 1.2
  TOP w0.254: v2(109.33,42.26) 108.98,41.91 TP2101.1
  BOTTOM w0.254: CPU1.AN11 109,42.68 109.33,42.35 v2(109.33,42.26)
V0.85A_VID1: length 1.8
  TOP w0.203: TP2102.1 108.25,42.71 v2(108.68,43.15)
  BOTTOM w0.254: CPU1.AN13 108.89,43.63 108.68,43.43 v2(108.68,43.15)
VBUS_PRODECT: length 33.1
  TOP w0.127: v2(44.42,91.56) 45.44,91.56 45.97,91.02 45.97,89.45 45.36,88.84 PQ4309.2 PQ4311.2
  L4 w0.127: v2(44.42,91.56) 43.25,91.56 42.31,90.62 36.75,90.62 35.74,89.6 30.71,89.6 29.44,90.87 29.44,91.48 30.16,92.21 30.16,92.59 30.5,92.93 30.5,93.56 29.31,94.76 28.7,94.76 27.71,95.75 v2(27.71,96.1)
  BOTTOM w0.127: U4301.1 27.45,94.44 27.77,94.77 PR4334.1 27.77,96.04 v2(27.71,96.1) 27.46,96.36 v1(27.1,96.36)
VBUS_PRODECT#: length 5.2
  TOP w0.102: 41.96,88.84 PQ4311.5 ; 41.96,88.84 41.96,90.81 PR4337.1 42.1,91.67 v1(41.91,91.86) ; 41.96,88.84 41.96,88.36 41.79,88.19 PQ4311.6
VCC3PD: length 88.2
  TOP w0.508: v2(40.16,90.06) 41.04,90.95 PR4337.2 ; D3702.K 27.02,96.25 27.02,94.77 D3701.K 26.94,93.61 v1(26.74,93.41) v2(26.24,92.9)
  L4 w0.508: v2(28.88,89.42) 28.9,89.45 28.9,91.63 29.18,91.91 29.18,92.98 28.9,93.26 26.59,93.26 v2(26.24,92.9) 26.03,92.7 26.03,92.7 25.83,92.5 25.83,91.56 25.82,91.55 25.82,91.34 22.4,87.93 21.83,87.93 20.8,87.93 20.2,87.33 20.2,86.47 20.88,85.79 20.88,83.1 21.08,82.9 21.08,78.32 20.29,77.54 20.29,75.45 18.72,73.88 18.72,68.9 20.12,67.5 20.12,65.98 22.12,63.97 22.12,58.64 23.16,57.6 23.16,52.24 25.35,50.05 25.35,44.24 26.44,43.15 v2(27.13,43.15)
  BOTTOM w0.457: v2(26.24,92.9) 26.39,92.75 27.96,92.75 28.4,93.18 U4301.2
  BOTTOM w0.508: v2(28.88,89.42) 31.62,89.42 31.9,89.7 34.03,89.7 34.75,90.42 37.92,90.42 38.28,90.06 v2(40.16,90.06) ; v2(26.24,92.9) 26.24,94.23 26.88,94.87 PR4334.2
VCC_CORE: length 5.5
  BOTTOM w0.152: CPU1.G32 121.75,54.74 121.27,54.74 121.05,54.96
  BOTTOM w0.203: v2(126.13,56.51) 126.05,56.59 CPU1.A34 ; v2(126.29,55.37) 126.29,54.58 125.82,54.11 CPU1.A30
  BOTTOM w0.254: CPU1.A39 125.63,59.07 125.86,58.84 126.52,58.84 126.57,58.89 v2(126.64,58.89) ; v2(126.67,61.69) 126.53,61.55 CPU1.A44
  vias: v1(111.76,58.67) v1(132.59,63.26) v2(109.39,58.7) v2(109.39,56.87) v2(109.4,55.06) v2(111.12,59) v2(111.12,58.31) v3(112.47,59.15) v3(112.47,58.26) v3(113.31,59.15) v3(113.31,58.26) v3(114.2,59.15) v3(114.2,58.26) v3(115.09,59.15) v3(115.09,58.26) v3(115.92,59.15) v3(115.92,58.26) v3(116.76,59.15) v3(116.76,58.26) v3(117.65,59.15) v3(117.65,58.26) v3(118.54,59.15) v3(118.54,58.26) v3(119.43,59.15) v3(119.43,58.26) v3(120.32,59.15) v3(120.32,58.26) v3(135.96,68.19) v3(135.96,67.35) v3(135.96,66.51) v3(135.96,65.62) v3(135.96,64.79) v3(136.29,64) v3(136.8,68.19) v3(136.8,67.35) v3(136.8,66.51) v3(137.64,68.19) v3(137.64,67.35) v3(137.64,66.51) v3(138.48,68.19) v3(138.48,67.35) v3(138.48,66.51) v3(139.32,68.19) v3(139.32,67.35) v3(139.32,66.51) v3(140.16,68.19) v3(140.16,67.35) v3(140.16,66.51) v3(140.28,65.68) v3(141.15,64.71) v3(141.22,65.6) v3(142.14,65.62) v3(142.06,64.74) v3(142.95,64.74) v3(143.03,65.62) v3(143.81,64.74) v3(143.89,65.62)
VCC_EDRAM_FUSEPRG: length 0.6
  BOTTOM w0.305: CPU1.G61 121.89,70.88 122.15,70.62 122.2,70.62 v2(122.22,70.6)
  vias: v1(121.84,71.06)
VCC_SENSE: length 102.5
  TOP w0.254: v2(123.64,55.27) 124,55.63 v1(124,55.85) 124,56.25 123.56,56.7 R719.2
  L3 w0.254: v2(165.23,69.66) 165.05,69.66 163.85,70.86 163.85,79.7 159.48,84.07 159.48,89.65 160.4,90.56 160.4,91.79 159.59,92.61 159.59,96.16 157.83,97.91 157.83,99.88 157.83,100.2 154.74,103.29 153.77,103.29 v2(153.54,103.52)
  L6 w0.254: v2(123.64,55.27) 123.89,55.27 124.99,54.17 126.8,54.17 127.74,55.11 129.58,55.11 131.31,53.38 137.33,53.38 139.85,50.87 142.8,50.87 143.38,50.28 144.94,50.28 146.28,51.63 151.28,51.63 152.53,52.87 152.53,53.94 152.91,54.32 155.16,54.32 158.16,57.33 158.16,61 159.43,62.27 163.91,62.27 164.56,62.93 164.56,66.41 165.61,67.45 165.61,69.03 165.23,69.41 v2(165.23,69.66)
  BOTTOM w0.254: PR4648.1 v2(153.54,103.52) ; v2(123.64,55.27) 123.19,54.82 CPU1.E32
VCCGT_SENSE: length 67.2
  TOP w0.254: v2(120.09,79.43) 120,79.34 119.94,79.34 119.56,78.96 119.56,77.88 R721.2
  L4 w0.254: v2(164.49,89.55) 164.49,88.74 164.21,88.46 161.54,88.46 160.27,87.19 160.27,81.65 157.83,79.21 154.86,79.21 154.4,78.76 153.21,78.76 152.58,78.12 140.54,78.12 139.8,78.86 127.46,78.86 123.87,82.44 120.34,82.44 119.3,81.4 119.3,79.45 119.49,79.26 119.93,79.26 v2(120.09,79.43)
  BOTTOM w0.089: v2(120.09,79.43) 120.25,79.59 120.67,79.59 120.82,79.44 v1(120.82,79.16) 120.82,77.29 120.81,77.25 120.76,77.11 120.76,77.11 120.76,76.92 120.82,76.79 120.82,76.58 CPU1.J70
  BOTTOM w0.254: v2(164.49,89.55) 164.36,89.68 PR4617.1
VCCPD_VBUS: length 44.9
  TOP w0.508: v2(37.41,36.8) 36.82,36.8 R3703.1
  BOTTOM w0.305: USB1.B4 6.9,95.46 USB1.A9 ; USB1.B9 6.9,92.96 USB1.A4
  BOTTOM w0.508: v2(41.27,72.66) 45.08,68.85 45.08,65.68 46.79,63.97 46.79,51.27 40.64,45.13 40.64,40.58 37.41,37.35 v2(37.41,36.8)
  vias: v1(27.76,97.43) v1(43.23,73.07) v3(22.76,94.96) v3(23.59,94.96) v3(24.46,94.94) v3(40.28,91.43) v3(40.31,83) v3(40.51,92.24) v3(40.51,83.84) v3(40.56,84.67) v3(41.32,92.52)
VCCRTCEXT: length 16.5
  TOP w0.254: v1(91.29,39.11) 91.5,38.89 C2112.1 91.5,37.16 91.92,36.75 v2(91.95,36.75)
  BOTTOM w0.254: v2(91.95,36.75) 96.01,40.81 100.46,40.81 101.19,41.55 101.67,41.55 102.13,42 103.57,42 CPU1.BB10
VCCSA_SENSE: length 93.9
  TOP w0.152: 123.49,48.35 123.34,48.2 123.34,47.54 123.11,47.31 121.99,47.31 v2(121.56,46.88)
  TOP w0.254: 123.49,48.35 124.13,48.35 124.51,48.73 124.51,49.37 v1(124.01,49.87) 123.65,50.23 122.69,50.23 R735.2
  L4 w0.203: 123.49,46.37 121.84,46.37 121.56,46.65 v2(121.56,46.88)
  L4 w0.254: v2(144.45,51.91) 144.45,51.44 143.82,50.82 140.31,50.82 139.27,49.78 139.27,46.52 138.12,45.38 135.74,45.38 135.02,46.09 127.84,46.09 126.77,47.16 125.53,47.16 125.25,46.88 124,46.88 123.49,46.37
  L6 w0.254: v2(166.04,92.62) 166.04,92.61 162.08,88.64 162.08,82.12 163.96,80.24 163.96,72.36 162.79,71.19 162.79,67.03 159.81,64.05 158.7,64.05 155.19,60.54 154.18,60.54 153.57,59.94 153.57,56.75 152.89,56.07 151.53,56.07 150.42,54.96 150.42,53.31 150.01,52.9 144.93,52.9 144.45,52.42 v2(144.45,51.91)
  BOTTOM w0.254: v2(121.56,46.88) 121.51,46.88 121.24,47.15 CPU1.H20 ; PR4607.1 165.89,92.77 v2(166.04,92.62)
VCCSENSE_EDRAM_VR: length 3.5
  TOP w0.254: R724.2 114.72,70.95 114.4,70.63 v1(113.9,70.63) 113.82,70.71 v2(113.82,72.15)
  BOTTOM w0.254: CPU1.AC63 114.15,71.82 v2(113.82,72.15)
VCCSENSE_EOPIO_VR: length 3.5
  TOP w0.254: R729.2 110.65,70.44 v2(110.84,70.63) 110.97,70.76 v1(110.97,71.21)
  BOTTOM w0.127: CPU1.AL63 110.11,71.09 110.34,70.86 110.74,70.73 v2(110.84,70.63)
VCCSTG_EN_R: length 3.9
  TOP w0.127: U4002.4 89.24,90.38 v1(88.67,89.81) 88.61,89.74 C4033.1 R4017.2
VCCSTU_EN: length 14.4
  TOP w0.102: v2(105.66,15.46) 105.59,15.38 v1(105.59,14.16) v2(105.59,12.72)
  BOTTOM w0.102: EC4001.1 R4026.2 99.43,9.9 101.25,9.9 101.62,10.27 101.62,10.46 101.78,10.61 ; R4024.1 106.2,15.99 v2(105.66,15.46) ; v2(105.59,12.72) 105.59,12.46 105.05,11.93 105.05,11.12 104.84,10.9 R4023.2 104.25,10.61 101.78,10.61 ; U4005.4 101.21,11.18 101.78,10.61
VCCSTU_EN_R: length 3.2
  BOTTOM w0.127: v1(104.46,16.97) 104.52,17.02 C4034.1 106.17,17.02 R4024.2 106.42,17 107.03,16.4 U4006.3
VDD: length 17.8
  TOP w0.254: PR4412.1 142.62,38.87 PC4428.1 142.39,38.64 142.39,38.09 v2(142.21,37.91) ; v1(139.98,42.59) v2(139.98,41.98) ; v2(145.84,32.64) 145.8,32.68 145.77,32.68 145.27,33.18 PR4422.1
  L3 w0.254: v2(139.98,41.98) 140,41.98 140.74,41.24 140.74,39.39 v2(142.21,37.91) 142.21,37.66 145.46,34.41 145.46,33.02 v2(145.84,32.64)
  BOTTOM w0.203: PU4401.19 142.58,37.35 142.21,37.71 v2(142.21,37.91)
  BOTTOM w0.254: PR4471.1 140.47,41.48 v2(139.98,41.98)
VDDD: length 43.5
  TOP w0.305: U3701.6 32.2,44.86 v1(32.29,44.94) 32.29,45.02 31.29,46.02 C3703.1 ; U3701.9 30.63,42 30.19,41.56 v2(29.41,41.56)
  TOP w0.356: RN1815.2 39.91,39.28 40.18,39.01 v2(40.18,38.95) 40.18,38.9 39.91,38.63 RN1815.1
  TOP w0.406: v2(29.41,41.56) 29.41,41.37 28.9,40.86 28.78,40.86 28.17,40.25 28.17,39.91 C3701.1
  TOP w0.508: C3702.1 25.93,40.67 R3701.2 27.47,40.67 28.1,40.03 C3701.1 28.1,39.58 27.84,39.31 27.84,36.87 ; 28.88,35.4 29.01,35.27 31.3,35.27 31.8,35.77 31.8,35.78 v2(31.93,35.91) 32.05,36.03 R3708.1 ; C3703.1 v2(30.63,46.13) ; v2(40.18,38.95) 41.13,39.91 R3717.1
  BOTTOM w0.508: v2(30.63,46.13) 30.73,46.03 30.73,45.08 29.41,43.76 v2(29.41,41.56) ; v2(31.93,35.91) 31.93,35.78 33.96,33.75 33.96,33.36 34.33,32.99 34.37,32.99 34.62,32.73 37.95,32.73 41.07,35.85 41.07,38.07 v2(40.18,38.95)
VDDIO: length 14.3
  TOP w0.305: U3701.8 30.49,42.5 30.1,42.1 28.8,42.1 v2(28.62,42.28)
  TOP w0.508: v2(28.62,42.28) 28.61,42.27 R3702.2 ; R3714.1 29.59,49.13 R3713.1 29.47,49.18 v2(29.01,49.65)
  L3 w0.508: v2(29.01,49.65) 29.01,49.34 28.52,48.86 28.42,48.86 27.18,47.62 27.18,44.62 28.62,43.17 v2(28.62,42.28)
VSS_AY71: length 11
  TOP w0.254: R602.1 95.06,79.27 v1(98.04,79.27) 102.61,79.27 102.97,78.91 102.97,78.14 v2(103.03,78.08)
  BOTTOM w0.254: v2(103.03,78.08) 103.03,78.06 103.25,77.83 103.5,77.83 104.31,77.02 CPU1.AY71
VSS_SENSE: length 101.8
  TOP w0.254: v1(123.95,54.63) 123.48,54.63 R720.1 122.9,55.43 v2(123.44,55.97)
  L3 w0.254: v2(164.74,69.16) 164.74,69.43 163.47,70.7 163.47,79.54 159.1,83.91 159.1,89.81 160.02,90.72 160.02,91.63 159.2,92.45 159.2,96 157.45,97.76 157.45,100.04 154.58,102.91 153.72,102.91 v2(153.54,102.73)
  L6 w0.254: v2(123.44,55.97) 123.44,55.97 123.72,55.97 125.14,54.55 126.64,54.55 127.58,55.49 129.74,55.49 131.47,53.76 137.49,53.76 140,51.25 142.96,51.25 143.54,50.66 144.78,50.66 146.12,52.01 151.12,52.01 152.14,53.03 152.14,54.09 152.75,54.7 155,54.7 157.78,57.48 157.78,61.16 159.28,62.65 163.75,62.65 164.18,63.08 164.18,66.57 165.23,67.61 165.23,68.87 164.94,69.16 v2(164.74,69.16)
  BOTTOM w0.254: PR4645.1 153.52,102.71 v2(153.54,102.73) ; CPU1.E33 123.19,55.75 123.42,55.97 v2(123.44,55.97)
VSSGT_SENSE: length 65.6
  TOP w0.254: v2(120.09,78.79) 120.37,78.79 v1(120.71,78.45) 120.98,78.19 R722.1
  L4 w0.254: v2(120.09,78.79) 120,78.88 119.33,78.88 118.92,79.29 118.92,81.56 120.19,82.82 124.03,82.82 127.61,79.24 139.96,79.24 140.69,78.5 152.42,78.5 153.05,79.14 154.25,79.14 154.7,79.59 157.68,79.59 159.89,81.81 159.89,87.03 159.89,87.03 159.89,87.35 161.38,88.84 163.75,88.84 v2(163.98,89.07)
  BOTTOM w0.089: v2(120.09,78.79) 120.63,78.25 120.63,77.28 120.57,77.15 120.57,76.9 120.63,76.78 120.63,76.32 120.81,76.14 120.81,75.95 CPU1.J69
  BOTTOM w0.254: PR4618.1 162.6,88.85 163.05,89.3 163.75,89.3 v2(163.98,89.07)
VSSSA_SENSE: length 89.5
  TOP w0.203: v2(121.64,47.74) 121.64,47.82 122.02,48.2 122.6,48.2
  TOP w0.254: R734.1 122.87,48.78 122.87,48.47 122.6,48.2 ; v1(166.04,93.84) v2(166.04,93.29)
  L4 w0.203: v2(121.64,47.74) 121.64,47.49 121.84,47.29 123.29,47.29
  L4 w0.254: v2(143.81,51.91) 143.81,51.53 143.61,51.32 140.08,51.32 138.76,50 138.76,49.57 138.76,49.56 138.76,46.75 137.89,45.89 135.96,45.89 135.25,46.6 127.84,46.6 126.82,47.62 125.42,47.62 125.09,47.29 123.29,47.29
  L6 w0.254: v2(143.81,51.91) 143.81,52.5 144.72,53.41 149.63,53.41 149.91,53.69 149.91,55.17 151.32,56.58 152.68,56.58 153.06,56.96 153.06,60.16 153.95,61.05 154.98,61.05 158.49,64.56 159.6,64.56 162.28,67.24 162.28,71.4 163.45,72.57 163.45,80.03 161.57,81.91 161.57,88.92 165.94,93.29 v2(166.04,93.29)
  BOTTOM w0.254: PR4604.1 165.68,93.64 v2(166.04,93.29) ; v2(121.64,47.74) 121.64,47.75 121.56,47.75 121.24,48.07 CPU1.H21
VSSSENSE_EDRAM_VR: length 2.1
  TOP w0.254: v1(112.45,72.46) 112.81,72.1 v2(112.93,72.1) 112.38,71.56 R725.1
  BOTTOM w0.254: CPU1.AE63 113.21,71.82 v2(112.93,72.1)
VSSSENSE_EOPIO_VR: length 3.5
  TOP w0.254: v2(111.53,71.11) 111.53,71.34 111.2,71.67 110.87,71.67 110.39,72.15 v1(110.08,72.15) 110.06,72.13 R731.1
  BOTTOM w0.254: CPU1.AJ62 111.29,71.35 v2(111.53,71.11)
0D6V_PWR:
  vias: v1(38.4,12.59)
0D6V_S0: length 4.1
  BOTTOM w0.305: v3(65.81,21.07) 65.65,21.23 DM1.258 ; v3(53.14,21.1) 52.8,21.44 DM2.258
  vias: v1(51.99,19.37) v3(38.25,13.89) v3(39.17,13.89) v3(53.72,20.49)
1D0V_PWR:
  vias: v1(96.59,11.52) v3(89.71,7.71) v3(89.71,6.82) v3(89.71,5.93) v3(89.71,5.05) v3(91.18,8.09) v3(91.62,3.19) v3(92.07,8.09) v3(92.51,3.19) v3(92.96,8.09)
1D0V_S5: length 72.1
  TOP w0.508: v2(164.18,28.11) 165.05,28.97 169.21,28.97 169.24,29 169.26,29 170.79,30.52 171.65,30.52 172.26,29.91 173.79,29.91 174.6,30.73 178.55,30.73 R2402.1
  L4 w0.508: v2(134.95,28.03) 134.05,28.03 128.21,33.87 v2(125.37,33.87)
  L6 w0.508: v2(164.18,28.11) 164.18,27.4 163.27,26.48 160.35,26.48 158.7,24.83 153.24,24.83 153.03,24.63 151.58,24.63 149.53,26.68 149.53,27.86 147.52,29.86 141.9,29.86 141.02,28.98 141.02,27.39 140.39,26.76 137.35,26.76 136.08,28.03 v2(134.95,28.03)
  BOTTOM w0.305: v2(100.02,93.79) 100.33,93.79 101.32,92.8 101.32,91.29 102.09,90.52 104.4,90.52 104.7,90.82 Q4001.G
  vias: v1(89.18,11.98) v1(111.5,31.87) v2(91.34,91.36) v2(91.97,91.36) v2(92.61,91.36) v2(94.16,9.57) v2(94.79,9.57) v2(95.43,9.54) v2(96.09,9.54) v2(98.75,93.79) v2(99.39,93.79) v3(83.44,23.84) v3(85.24,24.38) v3(88.34,11.12) v3(88.34,10.23) v3(89.23,11.12) v3(89.23,10.23) v3(90.12,11.12) v3(90.12,10.23) v3(91.01,10.41) v3(91.34,9.62) v3(92.86,93.44) v3(93.7,93.36) v3(108.89,32.25) v3(120.14,31.54)
1D0V_S5_PWRGD: length 183.9
  TOP w0.127: v2(101.14,10.46) 101.14,9.78 PR5209.1
  L3 w0.127: v2(158.67,105.88) 158.67,105.98 156.76,107.89 135.71,107.89 133.75,105.93 123.87,105.93 120.95,103.02 v2(120.95,101.41)
  L4 w0.127: v2(101.14,10.46) 100.66,10.94 99.9,10.94 99.19,11.65 94.46,11.65 92.78,13.33 90.85,13.33 87.18,17 86.4,17 86.12,16.72 82.27,16.72 81.34,17.65 81.34,19.77 84.4,22.83 84.4,24.88 85.15,25.62 v2(86,25.62)
  BOTTOM w0.127: v2(158.67,105.88) 158.72,105.83 R4029.1 ; v2(86,25.62) 86,43.96 91.13,49.09 91.13,87.93 95.5,92.29 96.24,92.29 96.57,91.96 96.57,91.61 96.39,91.43 96.39,90.9 98.42,88.87 107.41,88.87 108.49,89.95 v1(108.49,91.36) 108.49,92.19 108.13,92.56 108.13,92.94 108.5,93.31 110.41,93.31 111.56,94.45 111.56,95.36 115.98,99.79 116.89,99.79 118.03,100.93 120.47,100.93 v2(120.95,101.41)
1D2V_PWR: length 16.3
  TOP w0.508: v2(48.84,1.64) 48.23,1.03 45.54,1.03 45.11,1.46 37.18,1.46 36.27,2.38 36.27,4.54
  BOTTOM w0.508: PG5113.1 v2(48.84,1.64)
  vias: v1(37.49,8.6) v1(40.54,7.1) v3(36.22,5.83) v3(36.27,7.97) v3(36.27,6.95) v3(37.26,7.97) v3(37.26,6.95) v3(37.26,5.81) v3(38.68,8.35) v3(38.68,7.33) v3(38.68,6.32) v3(39.67,8.35) v3(39.67,7.33) v3(39.67,6.32)
1D2V_S3: length 234.9
  TOP w0.508: v2(85.88,15.36) 85.93,15.36 86.41,15.84 87.2,15.84 88.75,17.39 97.28,17.39 97.66,17.77 98.14,17.77 99.11,18.74 v2(99.11,18.91)
  BOTTOM w0.089: v2(102.16,54.09) 102.63,54.19 CPU1.BB32
  BOTTOM w0.127: CPU1.BB47 103.59,62.85 102.59,62.85 102.44,63.01 v2(102.37,63.01) ; CPU1.BB51 103.44,65.47 101.19,65.47 101.18,65.48 101.15,65.48 100.37,66.26 v2(99.97,66.26)
  BOTTOM w0.203: CPU1.BB23 103.59,49.14 103.3,49.14 102.75,48.59 102.73,48.59 102.69,48.56 102.34,48.56 v2(102.3,48.52)
  BOTTOM w0.254: v2(52.75,64) 52.7,63.95 52.12,63.95 52.11,63.94 DM2.96 ; DM1.112 66,59.73 66.56,60.3 66.56,60.31 v2(66.77,60.51) ; v2(97.45,60.6) 97.48,60.57 97.48,60.04 98.13,59.39 102.86,59.39 102.98,59.27 103.6,59.27 CPU1.BB41 ; v2(105.79,57.26) 105.79,57.14 106.4,56.53 CPU1.AU35 ; 57.55,57.19 57.55,57.19 DM2.123 ; CPU1.AU42 106.4,60.08 105.99,59.67 105.99,59.53 v2(105.97,59.5) ; CPU1.AU28 106.4,52.9 v2(106.07,53.24) ; 60.26,52.69 DM2.141 ; v2(106.08,49.57) 106.08,49.62 106.4,49.95 CPU1.AU23 ; v2(109.33,49.57) CPU1.AL23 ; DM2.111 55.37,60.19 v2(54.94,60.62) ; DM1.142 63.09,52.23 v2(62.74,51.88) ; DM1.160 65.37,45.73 v2(66.32,44.78)
  BOTTOM w0.305: v2(52.55,74.44) 52.55,74.44 DM2.54 ; 60.26,52.69 60.59,52.69 v2(61.34,51.93) ; v2(52.54,30.88) 52.48,30.93 DM2.220 ; v2(66.5,58.85) 66.32,58.67 66.32,58.63 65.93,58.23 DM1.118 62.84,58.23 v2(62.79,58.28) ; DM1.123 70.28,56.98 69.92,56.63 v2(69.92,56.38) ; v2(74.12,44.64) 74.06,44.7 73.71,44.7 73.42,44.98 DM1.163 ; DM2.148 50.9,48.94 52.38,48.94 v2(52.39,48.94) ; v2(62.63,40.71) 63.16,41.23 DM1.178 ; v2(56.48,56.76) 56.48,56.78 56.99,57.3 57.44,57.3 57.55,57.19 ; v2(57.12,47.83) 57.26,47.69 DM2.153 ; v2(62.66,30.74) 62.67,30.73 DM1.220 ; DM2.160 50.9,45.94 52.07,45.94 52.31,45.69 52.54,45.69 ; v2(69.52,61.13) 69.52,60.82 70.05,60.29 71.09,60.29 71.4,59.99 72.35,59.99 DM1.111 ; v2(53.25,59.05) 53.07,58.87 53.07,58.83 52.68,58.44 DM2.118 ; v2(67.74,53.24) 67.74,54.5 68.5,55.27 68.52,55.27 68.59,55.34 71.28,55.34 71.43,55.48 DM1.129 ; v2(53.91,53.92) 53.73,54.1 53.73,54.14 52.44,55.44 DM2.130 49.86,55.43 v2(49.49,55.8) ; v2(49.49,56.87) 49.56,56.94 DM2.124 52.63,56.94 53.1,57.41 v2(53.1,57.45) ; DM1.130 65.68,55.23 65.74,55.18 66.48,55.18 66.81,55.5 v2(66.81,55.74) ; DM2.154 52.48,47.44 v2(52.5,47.41) ; v2(60.82,45.19) DM2.163 ; v2(65.61,48.71) 65.58,48.73 DM1.148 ; v2(73.7,69.32) 73.64,69.32 73.3,68.98 DM1.75 ; DM2.136 52.47,53.94 v2(52.49,53.92) ; v2(60.65,69.21) 60.63,69.19 DM2.75 ; DM2.199 60.15,36.19 60.65,35.68 v2(60.65,34.64) ; DM1.54 63.23,74.23 62.74,73.74 v2(62.74,73.63) ; v2(68.6,47.21) 68.6,48.08 69.51,48.98 DM1.147 ; v2(60.57,58.98) 60.27,58.69 DM2.117 56.48,58.69 v2(55.82,59.35) ; v2(65.73,47.24) 65.73,47.23 DM1.154 ; v2(70.46,58.89) 70.81,58.54 71.38,58.54 71.44,58.48 DM1.117 ; DM2.135 57.82,54.19 57.4,53.76 56.95,53.76 56.64,54.07 56.64,54.09 v2(56.54,54.19) ; DM1.141 73.27,52.48 73.49,52.71 v2(74.26,52.71) 74.26,53.38 73.66,53.98 DM1.135 ; DM1.142 65.32,52.23 66.22,51.34 66.22,51.25 v2(66.37,51.1) ; v2(61.9,63.19) 62.63,63.19 63.18,63.73 DM1.96 ; v2(49.53,84.95) 49.55,84.94 DM2.12 ; DM1.136 65.56,53.73 65.99,53.31 v2(66.31,53.31) ; v2(73.88,79.96) 73.4,79.48 DM1.33 ; v2(52.83,60.62) 52.14,59.94 DM2.112 ; DM2.147 56.31,49.19 54.56,47.43 v2(54.56,47.36) ; v2(69.87,47.31) 69.87,47.18 70.23,46.83 70.71,46.83 71.37,47.48 DM1.153 ; v2(62.11,84.82) 62.2,84.82 62.29,84.73 DM1.12 ; DM1.159 71.39,45.98 71.07,45.67 69.43,45.67 69.09,45.33 v2(69.09,44.76) ; DM2.129 56.3,55.69 55.22,54.6 v2(55.22,54.04) ; DM2.241 60.19,25.68 60.58,26.07 v2(60.58,26.23) ; v2(53.07,44.98) 53.07,45.16 52.54,45.69 ; DM1.124 65.86,56.73 66.17,57.05 66.17,57.07 v2(66.35,57.25) ; v2(53.07,46.4) 53.07,46.17 52.59,45.69 52.54,45.69 ; v2(55.68,45.38) 56.23,45.94 57.78,45.94 58.03,46.19 DM2.159 ; v2(73.77,35.98) DM1.199 ; v2(49.49,52.42) 49.51,52.44 DM2.142 52.37,52.43 v2(52.44,52.5) ; DM2.178 52.25,41.44 52.28,41.46 52.99,41.46 v2(53.11,41.33) ; DM2.33 60.48,79.69 v2(60.48,79.69) ; DM1.241 73.4,25.48 73.63,25.72 v2(73.68,25.72)
  BOTTOM w0.508: R505.1 99.52,19.32 v2(99.11,18.91) ; v2(85.88,15.36) 85.88,15.69 84.43,17.14 78.83,17.14 77.54,18.43 77.54,22.57 80.57,25.59 80.57,48.33 83.46,51.22 83.46,53.34 v2(82.45,54.35)
  vias: v1(50.34,34.18) v1(50.44,83.02) v1(96.44,61.74) v1(104.27,57.95) v2(52.5,50.87) v2(53.61,55.82) v2(53.92,59.25) v2(54.23,60.6) v2(54.18,58.11) v2(54.63,51.93) v2(54.88,56.48) v2(55.29,51.93) v2(55.65,61.59) v2(57.22,51.93) v2(67.64,44.8) v2(67.94,57.65) v2(68.22,55.74) v2(68.67,51.11) v2(69.19,58.89) v2(69.25,53.37) v2(71.69,51.09) v2(97.2,67.28) v2(97.48,66.26) v2(97.46,65.04) v2(100.04,62.33) v2(99.99,60.6) v3(32.54,10.66) v3(32.54,9.77) v3(33.37,10.63) v3(33.37,9.74) v3(34.19,11.04) v3(35.02,11.04) v3(35.66,19.75) v3(35.86,11.01) v3(36.19,20.41) v3(36.75,19.75) v3(36.88,20.92) v3(46.53,43.27) v3(46.53,42.38) v3(46.53,41.49) v3(46.53,40.61) v3(46.58,45.94) v3(46.58,45.05) v3(46.58,44.16)
1D2V_VTT_PWRGD: length 228.1
  L3 w0.127: v2(49.2,89.98) 49.68,89.5 49.68,89.02 49.02,88.36 49.02,64.3 47.8,63.08 47.8,35.45 45.9,33.54 45.9,28.82 46.43,28.29 v2(46.53,28.29) ; v2(51.41,96.74) 51.43,96.74 52.68,97.98 55.45,97.98 57.16,96.27 65.53,96.27 67,97.74 77.68,97.74 78.78,98.84 79.33,98.84 86.79,106.3 86.79,108.45 87.97,109.63 120.05,109.63 121.12,108.56 133.84,108.56 134.81,109.53 158.72,109.53 161.49,106.76 162.44,106.76 162.76,106.44 162.76,104 v2(162.1,103.34)
  L4 w0.127: v2(49.2,89.98) 49.2,90.75 51.05,92.6 51.05,96.38 v2(51.41,96.74) ; v2(46.53,28.29) 46.29,28.05 46.29,23.68 46.89,23.08 46.89,18.2 51.81,13.28 51.81,10.8 54.98,7.64 55.51,7.64 56.22,6.92 56.22,6.25 v2(54.81,4.84)
  BOTTOM w0.127: v2(162.1,103.34) 162.06,103.31 R4011.1 ; v2(54.81,4.84) 54.81,5.05 54.43,5.43 v1(53.74,5.43) 52.89,5.43 PR5107.1
1D5V_PWR:
  vias: v1(56.92,8.88)
1D5V_S0: length 99
  TOP w0.508: v2(26.08,23.93) 26.08,23.87 25.68,23.46 R2705.1
  L3 w0.508: v3(28.02,71.53) 27.96,71.53 27.9,71.47 27.22,71.47 25.4,69.65 25.4,69.08 24.86,68.55 24.86,66.34 24.94,66.26 24.94,64.53 24.18,63.77 24.18,61.84 23.21,60.88 22.3,60.88 19.05,57.62 19.05,56.79 18.54,56.28 18.54,52.11 17.85,51.43 17.85,43.4 20.06,41.19 20.06,38.57 20.37,38.27 20.37,34.13 20.74,33.76 22.02,32.48 22.02,30.83 24.15,28.69 25.16,28.69 26.16,27.69 26.16,24.01 v2(26.08,23.93) 26.08,23.11 30.15,19.04 30.15,14.54 32.86,11.83 36.7,11.83 37.41,11.12 39.17,11.12 40.97,12.92 42.34,12.92 45.79,9.47 55.01,9.47 v2(56.08,10.53)
  vias: v1(55.93,11.09)
1D5V_VDD: length 8.9
  TOP w0.178: U5701.12 24.05,68.85 24.41,69.21 v2(24.41,69.36)
  TOP w0.203: U5701.40 25.01,63.3 v2(25.21,63.1) ; U5701.31 20.85,63.14 20.39,62.68 v2(20.14,62.68)
  TOP w0.508: R5701.2 24.89,71.47 v1(24.6,71.18) 24.54,71.11 24.54,69.87 24.41,69.74 v2(24.41,69.36)
  BOTTOM w0.508: v2(20.14,62.68) 20.74,63.28 C5716.2 ; C5704.2 v2(25.21,63.1) ; v2(24.41,69.36) 24.43,69.33 C5702.2
  vias: v2(19.35,69.18) v2(20.24,69.18)
1D8S_EN#: length 4.8
  TOP w0.127: R4043.1 R4046.2 72.65,14.7 v1(72.08,14.7) 71.5,14.7 v2(70.7,15.5)
  BOTTOM w0.127: Q4008.D 70.37,15.78 70.65,15.5 v2(70.7,15.5)
1D8S_EN_R#: length 3.3
  TOP w0.127: C4023.2 74.09,13.39 R4043.2 74.03,13.06 v2(73.63,12.67) 73.63,12.56 v1(73.99,12.21)
  BOTTOM w0.127: v2(73.63,12.67) 73.59,12.62 Q4009.G
1D8V_EN#: length 5.1
  BOTTOM w0.127: v1(21.72,30.47) 21.72,29.34 Q2701.D 20.24,29.01 19.58,29.01 R2726.2 R2727.1
1D8V_EN_R#: length 8.2
  BOTTOM w0.127: Q2702.G 20.71,25.05 20.47,25.29 20.17,25.29 19.58,25.87 18.54,25.87 v1(18.51,25.85) 17.6,25.85 17.23,26.22 17.23,26.95 17.85,27.58 18.43,27.58 C2714.2 18.46,27.61 R2727.2
1D8V_PWR:
  vias: v1(55.7,14.98)
1D8V_S0: length 13.2
  TOP w0.508: R2713.1 25.53,21.84 25.69,22 v1(26.14,22) 26.16,21.98 26.16,21.96 26.34,21.78 v2(26.34,21.17)
  L6 w0.508: v2(24.81,26.1) 24.81,25.19 25.45,24.55 25.45,22.98 26.34,22.09 v2(26.34,21.17)
  BOTTOM w0.508: v2(24.81,26.1) 24.62,25.91 C2721.1 23.65,25.91 Q2702.D ; v2(26.34,21.17) 26.34,20.29 25.56,19.51 R2724.1
1D8V_S5_PWROK: length 191.8
  TOP w0.127: v1(158.42,107.08) 159.31,106.19 v2(159.31,105.88)
  L3 w0.127: v2(159.31,105.88) 157.05,108.14 135.58,108.14 133.63,106.19 123.76,106.19 119.94,102.36 v2(119.94,101.41) ; v2(72.24,93.95) 72.79,93.39 73.73,93.39 74.5,94.15 76.43,94.15 79.46,97.18 80.01,97.18 85.37,102.54 87.93,102.54 88.9,103.52 90.61,103.52 91.63,102.5 91.63,102.32 92.15,101.79 92.56,101.79 93.67,100.68 97.59,100.68 98.83,99.43 102.84,99.43 103.94,100.52 107.03,100.52 107.49,100.07 109.32,100.07 111.12,98.26 117.32,98.26 v2(118.44,99.38)
  L4 w0.127: v2(118.44,99.38) 119.94,100.88 v2(119.94,101.41)
  BOTTOM w0.127: R4030.1 159.61,105.58 v2(159.31,105.88) ; v2(72.24,93.95) 72.24,91.69 72.06,91.51 72.06,89.86 74.34,87.57 74.34,57.28 75.56,56.07 75.56,51.45 76,51.01 76,27.41 73.53,24.93 73.53,20.86 73.01,20.34 71.78,20.34 71.03,19.58 71.03,16.01 71.15,15.89 71.15,15.31 70.72,14.89 70.38,14.89 69.8,14.3 69.8,13.7 69.19,13.1 68.53,13.1 67.64,12.21 PR5408.1
2D5V_S3:
  vias: v1(60.12,21.4) v1(71.96,22.24) v2(59.56,20.46) v2(60.2,20.46) v2(60.83,20.46) v3(50.57,97.65) v3(51.41,97.65) v3(70.36,21.25)
3D3V_AUX_KBC_33: length 3.9
  TOP w0.203: KBC24.54 188.81,43.26 188.42,42.87 v2(188.42,42.76)
  BOTTOM w0.305: v1(188.37,42.16) 188.37,42.72 v2(188.42,42.76)
  BOTTOM w0.508: C2423.1 R2462.1 188.25,42.93 v2(188.42,42.76)
3D3V_AUX_S5: length 436.4
  TOP w0.406: v2(182.52,24.07) 182.52,24.17 182.7,24.35 R2463.1
  TOP w0.508: v2(156.84,3.67) 156.84,7.59 157.76,8.5 189.28,8.5 190.69,7.09 191.82,7.09 192.28,7.55 192.28,8.45 191.13,9.59 v2(190.78,9.59) ; v2(94.94,104.11) 95.62,104.11 PR4503.1 ; v2(158.52,107.97) 161.77,107.97 v2(162.02,108.22) ; v2(164.21,60.8) 164.21,59.12 163.55,58.46 PG4532.2 162.15,58.46 161.95,58.67 PR4505.1 ; v2(71.17,12.67) 71.17,12.26 70.62,11.71 R1737.1 ; v2(70.43,6.8) 70.25,6.98 70.25,7.66 70.85,8.26 R1727.1 R1726.2
  L3 w0.508: v2(170.38,95.95) 169.75,95.95 165.66,100.04 165.66,103.35 164.26,104.75 164.26,107.13 163.17,108.22 v2(162.02,108.22) ; v2(94.94,104.11) 95.88,104.11 96.16,103.83 98.04,103.83 99.26,102.61 99.81,102.61 99.81,102.61 101.9,102.61 101.9,102.61 107.92,102.61 108.38,102.15 117.35,102.15 122.13,106.94 133.26,106.94 135.15,108.83 157.66,108.83 v2(158.52,107.97)
  L4 w0.508: v2(136.52,36.16) 136.8,36.16 139.83,39.18 154.4,39.18 158.01,42.79 158.01,53.1 158.34,53.43 158.34,61.51 159.41,62.58 162.43,62.58 v2(164.21,60.8) ; v2(94.94,104.11) 94.71,104.11 94.59,103.98 89.38,103.98 88.26,105.1 87.21,105.1 86.84,104.72 86.84,99.81 84.71,97.68 83.49,97.68 78.54,92.73 78.14,92.73 76.66,91.24 v2(76.66,90.92) ; v2(71.17,12.67) 71.17,12.41 70.66,11.9 69.09,11.9 68.4,11.22 68.4,10.66 69.14,9.92 69.67,9.92 70.43,9.16 v2(70.43,6.8)
  L6 w0.508: v2(142.01,4.56) 142.9,4.56 144.93,2.53 155.7,2.53 v2(156.84,3.67) ; v2(136.52,36.16) 132.59,32.22 132.59,25.04 133.78,23.84 133.78,20.19 134.29,19.69 134.29,17.49 138.35,13.43 138.35,13.11 140.5,10.96 v2(142.39,10.96) ; v2(164.21,60.8) 166.42,60.8 167.56,61.94 167.56,69.43 165.63,71.37 165.63,74.73 166.31,75.41 167.7,75.41 171.12,78.83 171.12,83.3 v2(171.6,83.79) 169.72,85.67 169.72,95.29 v2(170.38,95.95)
  BOTTOM w0.305: GPU1.F1 171.85,85.28 171.58,85.01 171.58,83.81 v2(171.6,83.79)
  BOTTOM w0.457: v1(185.45,13.71) 181.99,17.18 181.99,23.12 182.52,23.65 v2(182.52,24.07)
  BOTTOM w0.508: v2(142.39,10.96) 140.58,9.15 140.58,4.83 140.84,4.56 v2(142.01,4.56) ; v2(70.43,6.8) 70.43,6.32 69.84,5.72 D2501.1 ; v2(190.78,9.59) 190.17,10.2 190.17,11.01 188.16,13.02 186.15,13.02 v1(185.45,13.71) ; v2(71.17,12.67) 72.24,13.73 73.2,13.73 73.73,14.27 73.73,15.84 72.08,17.49 72.08,18.29 74.24,20.44 74.24,24.61 76.93,27.3 76.93,56.18 75.25,57.87 75.25,89.51 v2(76.66,90.92)
3D3V_CAMERA_S0: length 1.5
  BOTTOM w0.305: v2(58.34,91.91) 58.29,91.91 57.65,92.56 TCBD1.6
  vias: v1(59.08,91.86)
3D3V_GSEN2: length 11.7
  TOP w0.254: 175.84,42.63 v1(175.03,43.45) 174.52,43.95 174.52,44.6 175.19,45.27 C7003.1 175.21,45.56 C7004.1 176.41,46.77 R7005.1 178.14,45.97 178.67,45.97 R7006.2 ; 175.84,42.63 175.96,42.52 U7001.9 ; 175.84,42.63 175.84,42.18 176.07,41.96 U7001.10 176.35,41.35 175.98,40.97 R7004.2
3D3V_MCU: length 75.6
  TOP w0.254: U6901.9 34.98,27.67 34.73,27.42 34.36,27.42 33.68,26.74 33.22,26.74 ; 42.49,25.37 U6901.24 ; U6901.36 43.12,31.67 43.27,31.82 43.66,31.82 44.08,32.24 ; 38.25,21.53 38.56,21.23 39.98,21.23 40.44,21.68 R6909.2 ; U6901.48 36.41,33.07 36.37,33.11 36.37,33.8 ; 35.61,32.37 U6901.1
  TOP w0.356: RN6901.2 45.39,37.63 45.69,37.33 45.34,36.98 RN6901.1
  TOP w0.508: C6905.1 31.48,27.63 31.8,27.94 v2(31.8,28.13) ; C6905.1 R6902.2 32.5,27.12 32.88,26.74 33.22,26.74 ; C6905.1 C6903.1 ; C6906.1 C6907.1 35.48,32.5 35.61,32.37 ; C6906.1 36.37,33.8 ; C6906.1 37.02,34.57 v2(37.03,34.56) ; v2(44.82,26.83) C6901.1 42.5,25.37 42.49,25.37 ; 38.25,21.53 37.77,22.01 R6911.2 R6913.2 36.88,22.11 35.86,21.1 34.95,21.1 34.21,21.84 R6915.2 33.23,22.38 32.5,23.12 R6917.2 31.67,23.33 31.16,23.84 31.16,25.8 31.48,26.12 C6903.1 ; C6903.1 31.99,26 R6919.2 ; 45.69,37.33 46.07,37.33 46.53,36.87 46.53,36.01 46.18,35.65 R6901.2 44.83,35.65 43.61,34.43 TP6902.1 43.61,33.98 v2(44.04,33.54) 44.22,33.37 C6904.1 44.82,32.97 44.08,32.24
  L4 w0.508: 42.54,33.54 41.53,34.56 v2(37.03,34.56) 36.45,34.56 35.84,33.95 35.84,27.73 35,26.89 33.04,26.89 v2(31.8,28.13) ; 42.54,33.54 42.37,33.37 42.37,29.28 v2(44.82,26.83) ; 42.54,33.54 v2(44.04,33.54)
3D3V_MUX: length 60.8
  TOP w0.203: U3801.20 36.41,61.35 36.65,61.59 ; U3801.28 32.3,62.73 31.82,63.21 v2(31.67,63.21) ; U3801.6 34.3,55.34
  TOP w0.254: v2(30.17,53.76) 30.17,53.73 R3824.1
  TOP w0.305: 34.3,55.34 v1(34.3,54.96) 34.3,54.85 33.86,54.4 C3818.1
  TOP w0.406: v2(39.67,58.77) 39.62,58.82 39.13,58.82 R3816.1
  TOP w0.508: v2(39.67,60.42) R3811.2 ; R3812.2 37.42,64.56 38.43,64.56 v2(38.86,64.99) 38.86,64.84 39.3,64.39 R3813.2 ; v2(39.29,55.54) 39.09,55.34 R3822.1 ; C3818.1 33.86,53.74 v2(33.4,53.28) ; R3850.1 25.77,60.48 26.36,59.88 v3(26.54,59.88) 26.62,59.88 27.28,60.54 27.55,60.54 28.31,61.31 R3810.2 28.56,61.5 29.45,62.39 C3816.1 31.04,62.58 v2(31.67,63.21) 31.67,63.34 32.28,63.95 32.57,63.95 R3801.1 32.82,64.19 32.82,64.38 33.36,64.93 C3819.1 ; R3850.1 R3847.2 R3848.2 ; R3850.1 R3849.1 ; R3820.1 R3818.1 28.09,57.09 v2(27.86,56.86) ; v2(39.67,58.77) 39.93,58.77 40.44,58.26 C3815.1 ; R3814.2 38.47,62.82 37.86,62.21 C3817.1 v2(37.16,62.04) 37.16,62.02 36.73,61.59 36.65,61.59
  L4 w0.508: v3(26.54,59.88) 26.54,59.05 27.86,57.73 v2(27.86,56.86) 27.86,56.63 30.17,54.32 v2(30.17,53.76)
  BOTTOM w0.508: v2(39.29,55.54) 39.89,55.54 40.31,55.96 40.31,58.14 39.68,58.77 v2(39.67,58.77) v2(39.67,60.42) 38.05,62.04 v2(37.16,62.04) ; v2(31.67,63.21) 31.67,63.27 32.35,63.95 34.75,63.95 36.65,62.04 v2(37.16,62.04) ; v2(33.4,53.28) 32.54,53.28 32.05,53.76 v2(30.17,53.76) ; v2(37.16,62.04) 37.16,63.29 v2(38.86,64.99)
3D3V_S0: length 508.6
  TOP w0.203: v2(25.55,68.32) 25.5,68.32 25.44,68.38 U5701.11 ; U5701.37 23.25,62.59 v2(23.47,62.37)
  TOP w0.406: v2(23.47,62.37) 23.98,61.87 R3848.1
  TOP w0.508: v2(49.58,48.02) 48.84,48.02 48.46,47.64 R1310.2 ; v2(161.4,25.22) 161.31,25.32 161.31,27.01 161.45,27.15 161.45,27.17 161.57,27.29 161.57,27.72 161.42,27.87 161.42,28.44 163.6,30.62 168.31,30.62 169.52,31.83 169.52,31.96 169.52,31.96 169.52,32.49 169.52,32.49 169.52,32.6 169.06,33.06 169.06,34.81 169.44,35.2 170,35.2 170.48,35.68 170.48,36.4 170.48,39.72 v3(169.85,40.35) ; 28.04,24.21 27.47,24.21 25.91,22.65 R2710.1 ; 28.04,24.21 29.09,24.21 R2731.1 ; 28.04,24.21 28.04,26.56 29.64,28.16 v2(29.84,28.16) ; R5413.1 23.53,60.16 24.04,60.67 R3847.1 R3848.1 ; v2(61.49,45.15) 61.49,44.75 61.86,44.38 R1211.2 ; v2(165.28,16.02) 165.28,14.63 165.3,14.61 165.3,11.42 v2(166.24,10.48) ; v2(92.78,22.88) 92.78,22.87 ; 92.78,22.87 92.48,22.57 90.23,22.57 R1607.1 ; 92.78,22.87 92.78,21.66 93.29,21.15 96.3,21.15 R1821.1 97.13,21.92 R1820.1 98.99,21.92 100.53,20.39 100.99,20.39 101.55,19.83 106.37,19.83 106.6,19.6 108.23,19.6 ; C1228.1 R1204.2 R1208.2 68.82,21.56 69.44,21.56 v2(69.49,21.51) ; v2(151.2,4.56) 151.2,4.89 151.59,5.27 151.59,9.26 151.1,9.74 v2(151.1,11.12) 151.1,12.21 151.31,12.41 151.31,14.82 148.63,17.49 147.6,17.49 144.93,20.16 144.93,24.4 143.28,26.05 v3(142.54,26.05) 141.04,24.55 141.04,23.1 138.62,20.67 138.23,20.67 136.57,19.02 R2045.1 ; R7004.1 177.37,40.66 177.51,40.52 177.51,40.52 178.19,39.84 v2(178.56,39.84)
  L3 w0.508: v2(61.49,45.15) 61.49,46.02 58.98,48.53 55.95,48.53 55.52,48.1 49.66,48.1 v2(49.58,48.02) ; v2(28.22,8.91) 30.83,6.29 v2(30.83,5.1) 30.83,2.38 31.72,1.49 44.93,1.49 45.74,2.3 46.45,2.3 v2(47.06,1.69) ; v2(85.11,101.34) 85.11,100.49 84.74,100.12 84.43,100.12 v2(80.8,96.49)
  L4 w0.508: 163.24,101.21 v2(163.27,101.18) ; 163.24,101.21 163.24,103.12 162.17,104.19 160.51,104.19 159.57,105.12 150.77,105.12 150.09,105.81 137.67,105.81 135.71,103.85 v2(135.56,103.85) ; 163.24,101.21 163.24,100.14 163.6,99.79 164.06,99.79 v2(164.13,99.86) ; v2(28.22,8.91) 28.62,8.91 30.02,10.3 30.02,22.31 29.08,23.25 29.08,27.4 v2(29.84,28.16) ; v2(188.59,37.41) 188.59,37.76 187.81,38.55 187.81,40.3 187.48,40.63 186.71,40.63 v2(186.64,40.56) ; v2(135.18,27.35) 133.73,27.35 v2(133.5,27.58) ; v2(30.83,5.1) 32.18,5.1 35.89,8.81 37.18,8.81 37.69,9.31 37.69,12.16 38.38,12.84 40.21,12.84 v2(41.07,13.71) ; v2(92.89,39.62) 89.18,35.91 89.18,34.59 79.07,24.48 76.93,24.48 74.78,22.32 69.06,22.32
  L6 w0.508: v2(23.47,62.37) 23.65,62.2 25.48,62.2 25.96,62.67 25.96,63.85 25.2,64.61 25.2,67.99 25.5,68.29 25.5,68.32 v2(25.55,68.32) 25.55,68.75 25.2,69.1 25.2,69.51 24.64,70.07 19.07,70.07 18.46,69.47 18.46,66.39 19.07,65.78 v2(19.07,65.73) ; v2(49.58,48.02) 44.8,48.02 v2(42.49,45.71) ; v2(202.61,9.24) 202.61,11.19 201.67,12.13 201.67,16.66 203.34,18.33 v2(203.55,18.33) ; v2(203.55,19.6) 203.49,19.6 202.89,20.2 202.89,32.35 202.84,32.4 202.84,32.84 202.47,33.21 202.03,33.21 199.31,35.94 199.31,37.87 197.16,40.02 195.65,40.02 193.95,38.32 190.85,38.32 189.94,37.41 v2(188.59,37.41) ; v2(108.33,26.03) 108.86,26.03 110.41,27.58 110.41,28.87 v2(111.3,29.76)
  BOTTOM w0.254: DM2.255 57.68,22.19 57.08,21.58 v2(55.8,21.58) ; R4027.1 110.79,96.87 115.24,101.31 v2(115.24,103.09)
  BOTTOM w0.305: v2(172.34,74.46) 172.46,74.46 172.87,74.86 GPU2.P3 ; Q1801.2 100.13,15.38 99.85,15.66 99.85,16.5 100.02,16.68 v2(100.02,16.78) ; Q1801.5 102.06,15.38 101.75,15.69 101.75,16.45 v2(101.93,16.63) ; v2(69.49,21.51) 69.95,21.96 70.61,21.96 70.63,21.98 DM1.255
  BOTTOM w0.356: R2043.1 108.76,19.31 108.76,19.17 v2(109.09,18.84)
  BOTTOM w0.406: Q2601.2 135.05,34.66 134.72,34.33
  BOTTOM w0.508: R506.1 40.9,13.87 v2(41.07,13.71) ; v2(19.07,65.73) 19.12,65.73 19.42,65.43 R5420.1 ; v2(42.49,45.71) 41.71,44.92 41.71,35.58 36.14,30.02 36.14,28.66 34.91,27.42 30.58,27.42 v2(29.84,28.16) ; PR4614.1 163.87,99.6 v2(164.13,99.86) ; R1818.2 108.82,26.03 v2(108.33,26.03) ; v2(166.24,10.48) 165.61,11.12 v2(151.1,11.12) ; C5701.2 24.97,66.67 25.2,66.89 25.2,68.11 25.4,68.32 v2(25.55,68.32) 25.24,68.63 25.24,70.23 24.7,70.77 R5419.1 R5417.1 R5415.1 R5411.1 ; v2(151.2,4.56) 151.2,4.48 151.68,4 152.2,4 152.63,4.43 152.63,5.79 DB1.1 ; 161.4,24.49 159.44,24.49 158.16,23.21 158.16,20.56 162.71,16.02 v2(165.28,16.02) ; 161.4,24.49 v2(161.4,25.22) ; 161.4,24.49 161.92,23.97 164.41,23.97 164.79,24.35 167.66,24.35 168.81,25.49 168.81,27.98 168.12,28.67 R6120.1 ; v2(123.7,10.48) 123.85,10.63 123.85,10.99 123.86,11 R7018.1 ; v2(92.89,39.62) 87.65,34.38 87.65,24.37 89.14,22.88 v2(92.78,22.88) ; v2(163.27,101.18) 163.24,101.16 R4005.1 ; R405.1 121.92,15.49 121.41,15.99 v2(121.38,15.99) ; v2(39.34,53.56) 39.3,53.56 36.55,56.32 33.61,56.32 31.93,58 31.93,60.64 30.7,61.87 29.41,61.87 28.01,63.26 26.74,63.26 25.8,62.32 23.52,62.32 v2(23.47,62.37) 23.67,62.58 C5703.2 ; R2042.1 111.99,19.17 111.5,18.69 v2(111.48,18.71) ; R2429.2 188.78,37.6 v2(188.59,37.41) 188.59,37.24 188.64,37.19 188.64,36.57 188.23,36.15 188.23,34.19 Q2414.G 188.14,34.05 187.65,34.05 186.75,33.15 R2489.2 ; PR5102.2 47.06,2.32 47.06,1.8 47.06,1.79 v2(47.06,1.69)
  vias: v1(132.74,35.93) v2(49.5,27.75) v2(57.25,94.68) v2(79.81,96.49) v2(86,101.18) v2(96.7,101.77) v2(96.87,101.16) v2(114.93,26.59) v2(118.95,24.17) v2(123.21,27.98) v2(134.08,103.85) v2(134.8,103.85) v2(174.62,69.05) v2(174.62,68.42) v2(177.52,78.53) v2(203.55,18.97) v3(169.82,41.29) v3(177.75,70.63) v3(178.36,71.21)
3D3V_S5: length 329.1
  TOP w0.305: GMR1.3 7.51,86.93 v2(7.54,86.96)
  TOP w0.406: Q2416.2 Q2416.5 180.72,49.45 180.49,49.67 179.7,49.67 178.92,48.89 v2(178.03,48.89)
  TOP w0.457: v2(26.24,95.32) 26.24,95.14 25.89,94.79 D3701.A
  TOP w0.508: R7001.2 16.25,84.64 C7002.1 15.67,84.67 R7011.2 15.42,85.37 15.39,85.4 v2(15.39,85.51) ; R3850.2 R3849.2 26.76,61.76 v2(27.63,61.76) ; v2(122.37,19.1) 122.43,19.04 122.69,19.04 125.45,16.28 125.45,15.98 127.06,14.37 129.64,14.37 129.72,14.29 132.74,14.29 132.79,14.34 138.38,14.34 140.16,16.13 142.69,16.13 143.13,16.57 143.13,17.11 144.02,18 v2(144.02,19.07) ; v2(100.48,10.48) 100.35,10.48 99.95,10.08 PR5208.1 ; v2(60.53,11.12) 61.49,12.08 64.31,12.08 65.12,12.89 v2(67.51,12.89) ; v2(180.77,29.79) 180.95,29.61 182.38,29.61 182.51,29.73 184.17,29.73 184.5,30.06 184.71,30.06 185.93,31.28 v2(186.31,31.28) 187.02,32 187.02,33.42 188.29,34.69 188.29,35.92 188.74,36.36 189.53,36.36 190.85,35.04 ; v2(120.88,21.63) 126.44,21.63 126.87,22.06 126.87,23.71 127.33,24.17 130.54,24.17 131.09,24.73 131.76,24.73 134.31,27.29 134.31,27.95 133.86,28.4 133.86,28.95 v2(134.14,29.23)
  L3 w0.508: v2(20.37,80.94) 19.96,80.94 v2(15.39,85.51)
  L4 w0.508: 179.68,51.81 179.68,55.72 178.87,56.53 178.87,59.39 176.56,61.69 v2(176.07,61.69) ; v2(186.31,31.28) 185.55,30.52 185.55,28.87 186.23,28.19 186.23,26.97 186.74,26.46 187.79,26.46 191.49,22.76 191.49,20.08 188.31,16.9 186.78,16.9 186.1,16.21 181.98,16.21 v2(181.89,16.3) ; v2(26.24,95.32) 26.24,95.14 24.42,93.32 24.42,91.92 21.83,89.32 19.36,89.32 15.75,85.71 15.75,85.7 15.56,85.51 v2(15.39,85.51) 15.39,85.35 15.05,85.01 13.03,85.01 12.18,84.16 9.84,84.16 8.3,85.69 8.3,86.2 v2(7.54,86.96)
  L6 w0.508: v2(144.02,19.07) 144.45,18.63 147.5,18.63 148.56,17.57 151.31,17.57 152.52,16.35 158.04,16.35 159.05,15.33 170.53,15.33 172.54,17.34 173.81,17.34 175.66,15.49 181.07,15.49 v2(181.89,16.3) ; 41.22,95.7 39.38,95.7 35.39,91.71 33.64,91.71 28.76,86.83 27.76,86.83 27.43,87.16 27.43,94.25 26.36,95.32 v2(26.24,95.32)
  BOTTOM w0.254: R4028.1 110.54,95.98 115.37,100.8 116.64,100.8 118.41,102.58 131.62,102.58 131.75,102.71
  BOTTOM w0.406: R2442.1 185.87,30.85 v2(186.31,31.28) ; v2(20.37,80.94) 20.42,80.99 20.42,81.02 20.62,81.22 20.7,81.22 21.05,81.58 U4302.2
  BOTTOM w0.508: v3(165.56,63.85) 173.91,63.85 v2(176.07,61.69) ; v2(27.63,61.76) 27.07,61.76 24.99,59.68 24.33,59.68 23.7,60.32 22.3,60.32 21.87,59.88 21.87,58.89 21.47,58.5 ; PR5402.1 66.61,13 67.41,13 v2(67.51,12.89) ; PR5410.1 41.98,95.05 v2(41.98,94.5) ; v2(15.39,85.51) 15.39,82.92 14.98,82.52 14.6,82.52 13.94,81.86 13.94,73.96 14.65,73.24 PR4304.1 14.82,70.86 PD4302.2 17.83,67.85 v1(17.83,66.87) 17.83,62.6 17.37,62.14 17.37,60.68 17.73,60.32 20.12,60.32 20.32,60.11 20.32,59.66 21.47,58.5 ; v2(20.37,80.94) 20.1,80.67 19.68,80.67 PR4335.1 ; R2607.1 144.22,19.82 144.22,19.27 v2(144.02,19.07) ; v2(134.14,29.23) 134.14,29.47 PR4450.2 ; v2(180.77,29.79) 179.6,30.95 179.6,32.94 178.67,33.86 178.67,36.89 177.93,37.64 177.93,45.97 177.26,46.63 177.26,48.63 177.52,48.89 v2(178.03,48.89) ; R2434.1 199.29,34.61 199.64,34.97 201.34,34.97 v2(201.8,34.51) ; 21.47,58.5 R5721.1
  vias: v1(50.85,90.09) v2(43.86,94.89) v2(44.14,95.47) v2(59.54,7.94) v2(60.53,10.48) v2(106.25,17.64) v2(132.13,104.74) v2(132.89,104.74) v2(160.7,105.88) v2(161.34,105.88) v2(162,105.88) v3(48.46,86.45) v3(58.09,1.92) v3(107.95,10.1) v3(108.79,10.1) v3(111.22,13) v3(165.58,65.68) v3(165.58,64.76) v3(166.34,52.09) v3(166.34,50.38) v3(166.34,49.52) v3(166.34,48.68) v3(166.39,51.25)
3D3V_S5_KBC: length 444.6
  TOP w0.178: KBC24.19 197.98,37.44 197.51,37.91 v2(197.51,38.09)
  TOP w0.203: v2(197.51,38.09) 197.51,38.19 197.96,38.64 KBC24.22 ; KBC24.65 184.12,42.64 v2(184.4,42.36) ; KBC24.5 197.89,31.84 197.59,32.15 196.88,32.15 196.17,32.86 195.99,32.86 195.12,33.73 195.12,34.18 ; v2(192.28,29.84) 192.01,29.57 KBC24.115 ; KBC24.103 187.21,27.76 v2(186.87,27.42) ; 184.77,35.84 184.77,35.84 KBC24.82 ; v2(193.77,45.69) 193.72,45.64 193.72,45.51 193.21,44.99 KBC24.43 193.21,43.24 v2(192.66,42.69)
  TOP w0.254: v2(30.78,35.91) 31.16,36.29 R3707.1
  TOP w0.508: v2(127.68,23.16) 128.07,23.54 130.8,23.54 131.36,24.1 132.02,24.1 133.97,26.05 134.5,26.05 135,26.05 136.37,24.68 137.01,24.68 137.01,24.68 140,24.68 142.11,26.79 143.48,26.79 145.31,24.96 146.72,24.96 148.72,22.96 v2(148.72,22.8) ; v2(179.53,10.25) 179.53,9.82 179.93,9.41 186.36,9.41 186.92,9.97 v2(186.92,10.33) ; 184.77,35.84 184.86,35.75 v2(186.28,35.75) ; 195.12,34.18 v2(194.82,34.48) ; v2(145.92,31.46) 146,31.46 146.81,30.65 146.81,27.86 147.6,27.07 149.02,27.07 150.72,28.77 v2(150.72,30.29) ; R2414.2 134.28,5.78 R2480.2 134.28,7.27 v2(134.24,7.31) ; v2(200.07,33.65) R2446.2
  L3 w0.254: v2(30.02,8.25) 31.42,6.85 31.42,2.53 31.95,2 44.65,2 45.46,2.81 58.06,2.81 58.62,2.25 67.22,2.25 67.3,2.33 71.45,2.33 72.62,3.5 81.58,3.5 v2(81.94,3.14)
  L3 w0.406: 123.7,25.75 123.7,27.64 123.8,27.74 123.8,28.22 123.7,28.33 123.7,28.34 123.52,28.52 123.52,28.74 v2(123.24,29.02)
  L3 w0.508: v2(138.71,10.48) 137.01,12.18 137.01,13.25 135.94,14.32 135.94,17.16 134.62,18.48 132.92,18.48 131.6,19.8 131.6,20.29 129.21,22.67 128.17,22.67 v2(127.68,23.16) 127.4,23.44 124.83,23.44 123.7,24.57 123.7,25.75 ; v2(186.87,27.42) 186.84,27.4 186.84,26.66 187.4,26.1 188.92,26.1 192.19,22.84 192.19,19.51 187.53,14.85 187.53,11.78 186.92,11.17 v2(186.92,10.33)
  L4 w0.254: v2(30.78,35.91) 30.78,35.65 29.11,33.98 29.11,29.62 30.35,28.37 30.35,27.96 30.53,27.78 30.53,9.65 30.02,9.14 v2(30.02,8.25)
  L6 w0.254: v2(111.1,5) 111.1,6.39 109.98,7.51 106.22,7.51 105.26,8.47 99.79,8.47 98.19,10.08 92.78,10.08 91.59,8.88 88.39,8.88 87.7,8.2 87.7,7.64 87.15,7.08 85.88,7.08 v2(81.94,3.14) ; v2(134.24,7.31) 128.86,7.31 128.5,7.66 127.89,7.66 127.18,6.95 125.32,6.95 120.57,2.21 v2(120.57,1.97)
  L6 w0.508: v2(171.22,97.02) 170.28,97.02 169.86,97.02 165.81,101.07 165.81,102.66 163.09,105.38 163.09,106.13 162.45,106.77 159.56,106.77 159.31,106.52 158.41,106.52 157.78,105.89 v2(157.78,105.88)
  BOTTOM w0.254: v2(186.87,27.42) 186.87,28.1 C2420.1 ; v2(120.57,1.97) 120.57,6.06 117.83,8.81 115.07,8.81 114.59,8.32 113.86,8.32 111.91,6.38 111.91,6.34 111.76,6.19 111.72,6.19 111.39,5.86 111.39,5.48 v2(111.1,5)
  BOTTOM w0.305: DB3.1 135.14,6.48 134.31,7.31 v2(134.24,7.31) ; R2495.2 186.57,44.07 187.12,43.53 R2462.2
  BOTTOM w0.406: v2(194.82,34.48) 195.71,34.48 195.93,34.71 195.93,34.87 196.04,34.97 Q2605.5 Q2605.2
  BOTTOM w0.508: C2420.1 186.36,28.3 R2415.2 ; R2495.2 186.51,44.46 186.01,44.96 185.05,44.96 184.53,45.48 183.32,45.48 181.3,47.5 181.3,48.81 179.8,50.31 179.8,54.96 179.79,54.97 179.3,57.32 179.3,61.38 176.4,64.28 176.4,68.3 177.89,69.79 177.98,69.79 179.3,71.11 179.3,83.96 179.63,84.29 179.63,95.37 178.43,96.56 173.96,96.56 173.51,97.02 v2(171.22,97.02) ; v2(187.53,42.79) 187.36,42.96 R2462.2 ; R2443.1 C2422.1 192.45,33.16 192.68,33.39 192.94,33.39 193.09,33.54 193.88,33.54 v2(194.82,34.48) ; C2429.1 C2410.1 197.88,39.04 197.51,38.68 v2(197.51,38.09) ; v2(134.24,7.31) 135.25,8.32 135.25,9.22 136.16,10.13 138.35,10.13 v2(138.71,10.48) 140.18,10.48 141.45,11.75 171.07,11.75 172.57,10.25 v1(178.46,10.25) v2(179.53,10.25) ; v2(188.92,35.07) 189.55,34.44 Q2415.G ; R2608.1 122.72,29.3 122.93,29.3 123.21,29.02 v2(123.24,29.02) ; R4032.1 157.83,105.83 v2(157.78,105.88) ; D4304.2 149.65,30.85 150.16,30.85 v2(150.72,30.29) 150.57,30.29 150.16,29.89 150.16,27.98 149.21,27.03 D4305.2 148.18,25.45 148.18,23.51 148.59,23.11 148.59,22.93 v2(148.72,22.8) 148.79,22.8 149.05,22.54 D4306.2 ; v2(145.92,31.46) 146.1,31.28 146.1,30.92 PR4438.1 PR4439.1 PR4445.1 ; v2(192.28,29.84) 192.28,29.19 C2413.1 R2473.2 ; C2414.1 185.43,35.67 185.52,35.75 v2(186.28,35.75)
  vias: v1(174.85,32.71) v2(178.76,29.86) v2(179.54,35.73) v2(189.81,45.46)
3D3V_S5_PCH: length 208.2
  TOP w0.254: 96.11,33.09 96.11,32.35 95.65,31.89 94.87,31.89 ; 96.11,33.09 96.82,33.8 v2(97.08,33.8) ; 96.11,33.09 95.85,33.35 R1824.1
  TOP w0.508: 100.76,14.29 98.58,14.29 v2(98.45,14.16) ; v2(195.6,38.12) 195.6,38.73 196.26,39.39 v2(196.9,39.39) ; R1837.1 91.62,24.12 v2(91.36,23.87) 91.15,23.65 R1814.1
  TOP w1.016: v3(100.2,33.9) 101.2,34.9 101.2,35.6 101.77,36.16 104.87,36.16 106.53,37.81 R1103.1
  L3 w0.508: v2(190.52,13.2) 195.3,13.2 199.26,17.16 199.26,30.29 198.02,31.54 198.02,32.96 198.22,33.16 198.22,35.15 197.67,35.7 197.05,35.7 195.6,37.15 v2(195.6,38.12) 195.6,38.19 194.92,38.88 194.33,38.88 193.32,39.89 v2(193.24,39.89) ; v2(79.07,10.48) 83.01,10.48 86.31,13.78 88.31,13.78 88.8,14.27 94.79,14.27 95.73,13.33 97.79,13.33 98.45,13.99 v2(98.45,14.16) 101.19,14.16 ; v2(97.08,33.8) 96.65,33.37 95.34,33.37 94.87,32.89 94.87,32.14 93.12,30.4 92.29,30.4 91.59,29.69 91.59,24.1 v2(91.36,23.87)
  L4 w0.508: v2(81.38,12.64) 79.22,10.48 v2(79.07,10.48)
  L6 w0.508: v2(109.73,18.79) 110.59,19.65 111.21,19.65 112.06,20.51 112.06,20.52 112.28,20.74 112.3,20.74 112.67,21.12 112.67,21.58 114.22,23.13 114.22,27.12 114.83,27.73 v2(115.01,27.73) ; v2(190.52,13.2) 190.52,11.7 189.99,11.17 179.51,11.17 177.43,9.08 144.86,9.08 144.78,9.16 140.97,9.16 138.53,11.6 134.13,11.6 133.87,11.85 128.88,11.85 127.51,13.22 127.51,16.72 129.97,19.19 129.97,20.75 129.56,21.16 129.56,23.33 131.95,25.72 131.95,32.94 v2(128.78,36.11)
  BOTTOM w0.406: Q2604.5 196.57,39.59 196.77,39.39 v2(196.9,39.39) ; v2(193.24,39.89) 193.27,39.89 193.27,39.92 193.6,39.59 Q2604.2
  BOTTOM w0.508: v2(109.73,18.79) 109.73,18.81 110.21,19.3 R2007.1 110.06,19.51 R2041.1 ; v2(120.7,16.04) 120.72,16.02 120.72,15.74 121.05,15.41 121.05,15.32 R404.1
  vias: v1(112.22,29.81) v1(112.44,16.35) v2(83.54,14.11) v3(113.82,14.39)
3D3V_SEN_S0: length 1.4
  BOTTOM w0.305: v2(56.84,91.79) 56.84,92.19 57.15,92.5 TCBD1.5
  vias: v1(52.45,96.71)
3D3V_SPIVCC1: length 7.5
  TOP w0.508: v1(77.67,10.68) v2(77.27,11.09)
  BOTTOM w0.508: SPI25.8 77.27,8.71 v2(77.27,11.09) 77.7,11.09 78.46,11.85 C2501.1 78.66,12.21 C2502.1 79.92,12.22 R2515.2
3D3V_SSD:
  vias: v3(202.41,12.44) v3(203.3,12.44) v3(203.66,31.46) v3(203.66,30.6)
81208_AGND:
  vias: v1(157.63,95.83) v2(155.01,95.19) v2(155.73,95.22) v2(156.49,96.74) v2(156.49,95.98) v2(156.49,95.22) v2(156.49,94.58) v2(156.49,93.82) v2(157.22,95.22) v2(157.96,95.19)
+DC_IN: length 2.5
  BOTTOM w0.508: PQ4305.2 21.19,74.78 21.82,75.4 21.84,75.4 22.2,75.76
  vias: v1(22.93,75.76) v1(25.5,82.16) v1(27.18,76.85) v3(25.83,78.83) v3(25.96,77.82) v3(25.96,76.8)
+DC_IN_C:
  vias: v1(20.09,83.84) v3(21.54,87.19) v3(22.38,87.16) v3(23.24,87.16)
+RTC_VCC: length 276.5
  TOP w0.254: v1(116.89,101.44) v2(116.25,101.44)
  L4 w0.508: v2(81.74,91.51) 82.3,90.94 83.23,90.94 83.84,91.56 83.84,91.94 84.12,92.22 84.74,92.22 86.37,90.59 89.79,90.59 90.24,91.05 90.24,91.53 91.16,92.45 95.17,92.45 95.43,92.7 97.84,92.7 98.35,92.19 98.35,91.76 97.77,91.18 97.77,90.46 98.22,90.01 104.57,90.01 104.94,90.38 105.46,90.9 105.46,93.06 107.49,95.09 107.49,96.61 108.38,97.5 112.32,97.5 v2(116.25,101.44) ; v2(169.75,42.36) 170.42,43.03 170.42,43.08 171.96,44.62 171.96,53 172.97,54.02 172.97,69.38 178.41,74.82 178.41,76.14 179.09,76.83 179.09,82.59 178.87,82.82 178.87,88.94 179.2,89.27 179.2,93.49 178.74,93.95 178.05,93.95 174.7,97.3 174.19,97.3 170.92,100.56 168.83,100.56 167.44,101.96 167.44,104 165.78,105.65 165.78,108.23 162.04,111.98 126.92,111.98 v2(125.84,110.9)
  BOTTOM w0.305: v2(169.75,42.36) 169.6,42.21 IOBD1.34
  BOTTOM w0.406: 71.74,6.06 72.07,6.39 72.07,7.18 R2504.1 72.12,7.64 Q2505.G
  BOTTOM w0.508: v2(81.74,91.51) 83.86,89.39 83.86,58.73 79.96,54.83 79.96,50.79 78.76,49.6 78.76,26.97 76.85,25.06 76.85,25.06 75.77,23.98 75.77,19.78 75.54,19.55 75.54,12.92 73.07,10.46 73.07,9.69 72.12,8.74 Q2505.G ; v2(125.84,110.9) 125.84,107.24 121.92,103.32 118.13,103.32 v2(116.25,101.44) ; 71.74,6.06 D2501.2
+SDC_IN: length 21.9
  TOP w0.508: v2(26.21,68.55) 26.53,68.86 PR4320.1 ; PR4318.1 35.04,88.29 33.96,87.21 33.96,86.2
  L3 w0.508: v2(26.21,68.55) 26.52,68.55 29.34,71.37 29.34,73.45 30.64,74.75 30.64,80.26 32.56,82.19 v2(32.56,83.91)
  vias: v1(36.09,83.33)
+SDC_IN_SW: length 3.9
  TOP w0.127: PR4333.2 PR4318.2 34.15,88.19 33.67,87.72 v1(33.67,87.72) 33.16,87.72 32.37,86.92 PU4302.4
+SDC_IN_SW_R1: length 22.7
  TOP w0.127: PR4333.1 35.04,90.02 34.62,90.44 33.79,90.44 v2(33.77,90.42) ; PQ4310.3 34.24,74.64 v1(34.44,74.85) v2(34.97,75.38)
  L3 w0.127: v2(34.97,75.38) 34.49,75.86 34.49,79.16 35.51,80.18 35.51,85.31 33.68,87.14 33.68,90.33 v2(33.77,90.42)
+V_EDRAM_VR:
  vias: v1(116.51,71.11) v3(108.66,95.04) v3(109.5,95.04) v3(110.34,95.01) v3(115.97,70.55) v3(116.86,70.55)
+V_EOPIO_VR:
  vias: v1(109.52,93.44) v3(108.71,92.75) v3(109.55,92.75) v3(111.56,70.37) v3(112.44,70.58)
+V_VREF_PATH1: length 2.2
  TOP w0.508: R1209.1 71.78,49.81 71.27,49.31 v1(71.27,49.18) 71.53,48.92 C1222.2
+V_VREF_PATH2: length 1.9
  TOP w0.508: C1323.2 R1309.1 51.04,45.85 v1(51.15,45.97)
A5_TP: length 2.8
  TOP w0.102: v2(126.67,36.77) 126.74,36.85 TP2309.1
  BOTTOM w0.102: CPU1.A5 125.91,38.46 126.24,38.14 126.24,37.91 126.49,37.66 126.49,36.95 v2(126.67,36.77)
A67_TP: length 4.8
  TOP w0.102: v2(126.59,77.99) 126.41,78.17 TP2311.1
  BOTTOM w0.102: CPU1.A67 126,74.61 127.09,75.7 127.09,77.5 v2(126.59,77.99)
A70_TP: length 3.2
  TOP w0.102: v2(125.45,78.91) 124.97,78.91 TP2310.1
  BOTTOM w0.102: CPU1.A70 126.03,76.68 126.03,78.32 v2(125.45,78.91)
AC_DIS: length 200.1
  TOP w0.102: v2(34.42,92.9) 33.55,92.04 v1(32.43,92.04) 31.11,92.04 30.81,91.74 30.35,91.74 30.05,92.04 30.05,92.17 29.26,92.96 28.29,92.96 27.3,91.96 27.3,89.83 26.97,89.5 20.39,89.5 v2(19.94,89.96) ; v2(170.97,98.52) 173.12,96.37 173.12,95.06 R4303.1 176.9,94.33 R4302.1
  L3 w0.102: v2(34.42,92.9) 34.36,92.96 34.36,93.67 35.15,94.45 36.6,94.45 41.67,99.52 47.92,99.52 48.49,100.09 57.05,100.09 57.99,99.15 62.28,99.15 62.95,99.83 75.71,99.83 75.8,99.91 75.82,99.91 77.09,101.18 77.75,101.18 78,100.93 78.43,100.93 78.69,101.18 78.69,101.56 78.62,101.62 78.61,101.63 78.61,102.16 78.98,102.53 79.52,102.53 83.39,106.39 84.47,107.47 84.47,109.47 86.82,111.83 86.88,111.83 87.01,111.95 161.65,111.95 165.81,107.8 165.81,105.78 165.83,105.75 165.83,105.75 167.54,104.05 167.54,101.64 169.64,99.53 170.48,99.53 170.97,99.05 v2(170.97,98.52)
  L6 w0.102: v2(19.94,89.96) 19.94,79.26 v2(20.37,78.83)
  BOTTOM w0.102: PQ4306.5 23.42,76.52 23.21,76.32 22.48,76.32 PQ4304.B 20.74,78.46 v2(20.37,78.83)
AC_IN#_G: length 3.2
  TOP w0.254: v2(23.04,81.53) 23.48,81.97 PR4312.2 PR4313.1
  BOTTOM w0.254: v2(23.04,81.53) 23.04,80.92 23.33,80.63 U4302.5
AC_PRESENT: length 91.7
  L3 w0.102: v2(106.5,20.9) 106.02,20.41 101.01,20.41 99.74,19.14 99.74,18.65 98.38,17.29 89.81,17.29 89.61,17.49 86.94,17.49 86.85,17.58 79.36,17.58 76.68,14.9 72.22,14.9 v2(71.63,15.5)
  L4 w0.102: v2(100.86,43.86) 100.86,43.81 100.73,43.68 100.73,42.92 99.01,41.19 99.01,39.31 94.77,35.07 94.77,26.38 94.87,26.28 94.87,23.79 94.54,23.46 94.54,22 95.05,21.48 96.25,21.48 97.19,20.54 98.52,20.54 99.41,19.65 103.83,19.65 104.37,20.18 105.79,20.18 v2(106.5,20.9)
  BOTTOM w0.089: 103.4,44.16 103.52,44.12 103.69,44.12 103.79,44.14 103.96,44.32 103.96,44.41 104.55,45 CPU1.AY15
  BOTTOM w0.102: v2(71.63,15.5) 71.63,15.26 71.02,14.65 70.48,14.65 70.05,14.22 70.05,13.5 68.47,11.92 Q1702.3 68.44,11.9 68.1,11.9 67.55,11.36 67.55,10.88 67.13,10.46 D1701.A ; RN1704.8 107.46,20.06 EC1707.1 107.75,20.97 107.49,21.23 v1(107.14,21.23) 106.83,21.23 v2(106.5,20.9) ; v2(100.86,43.86) 100.92,43.91 102.68,43.91 102.93,44.16 103.4,44.16
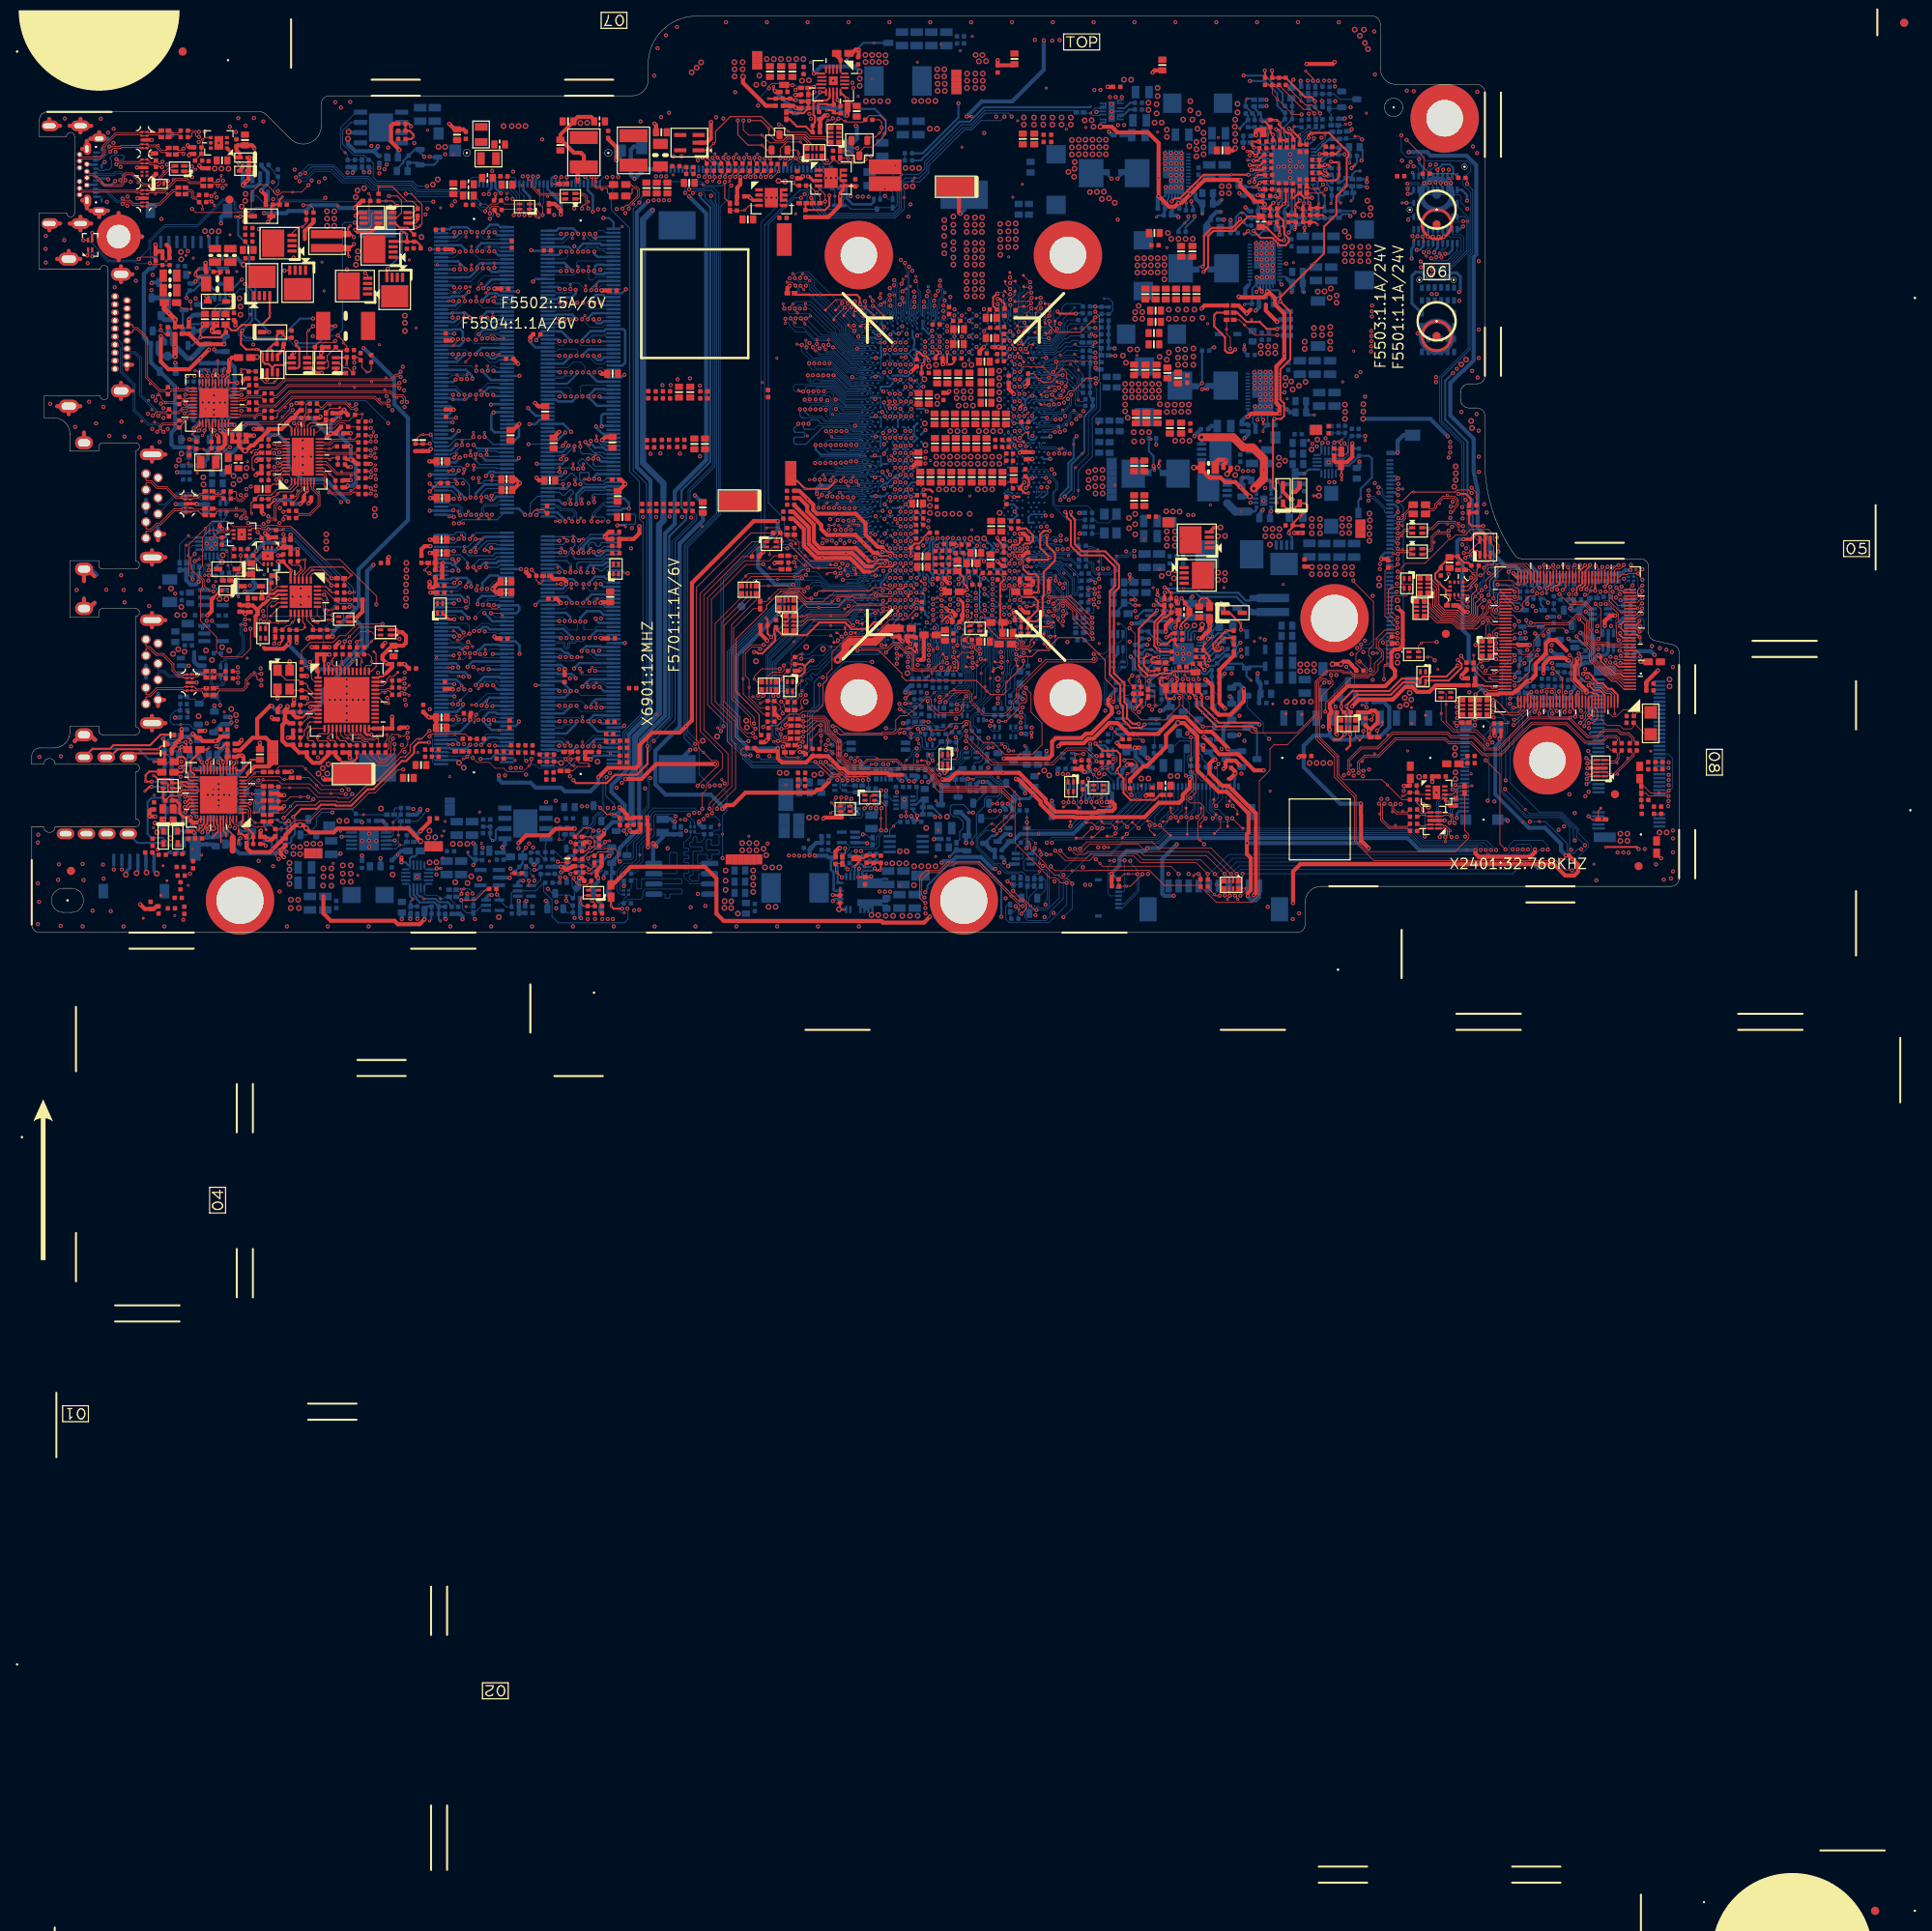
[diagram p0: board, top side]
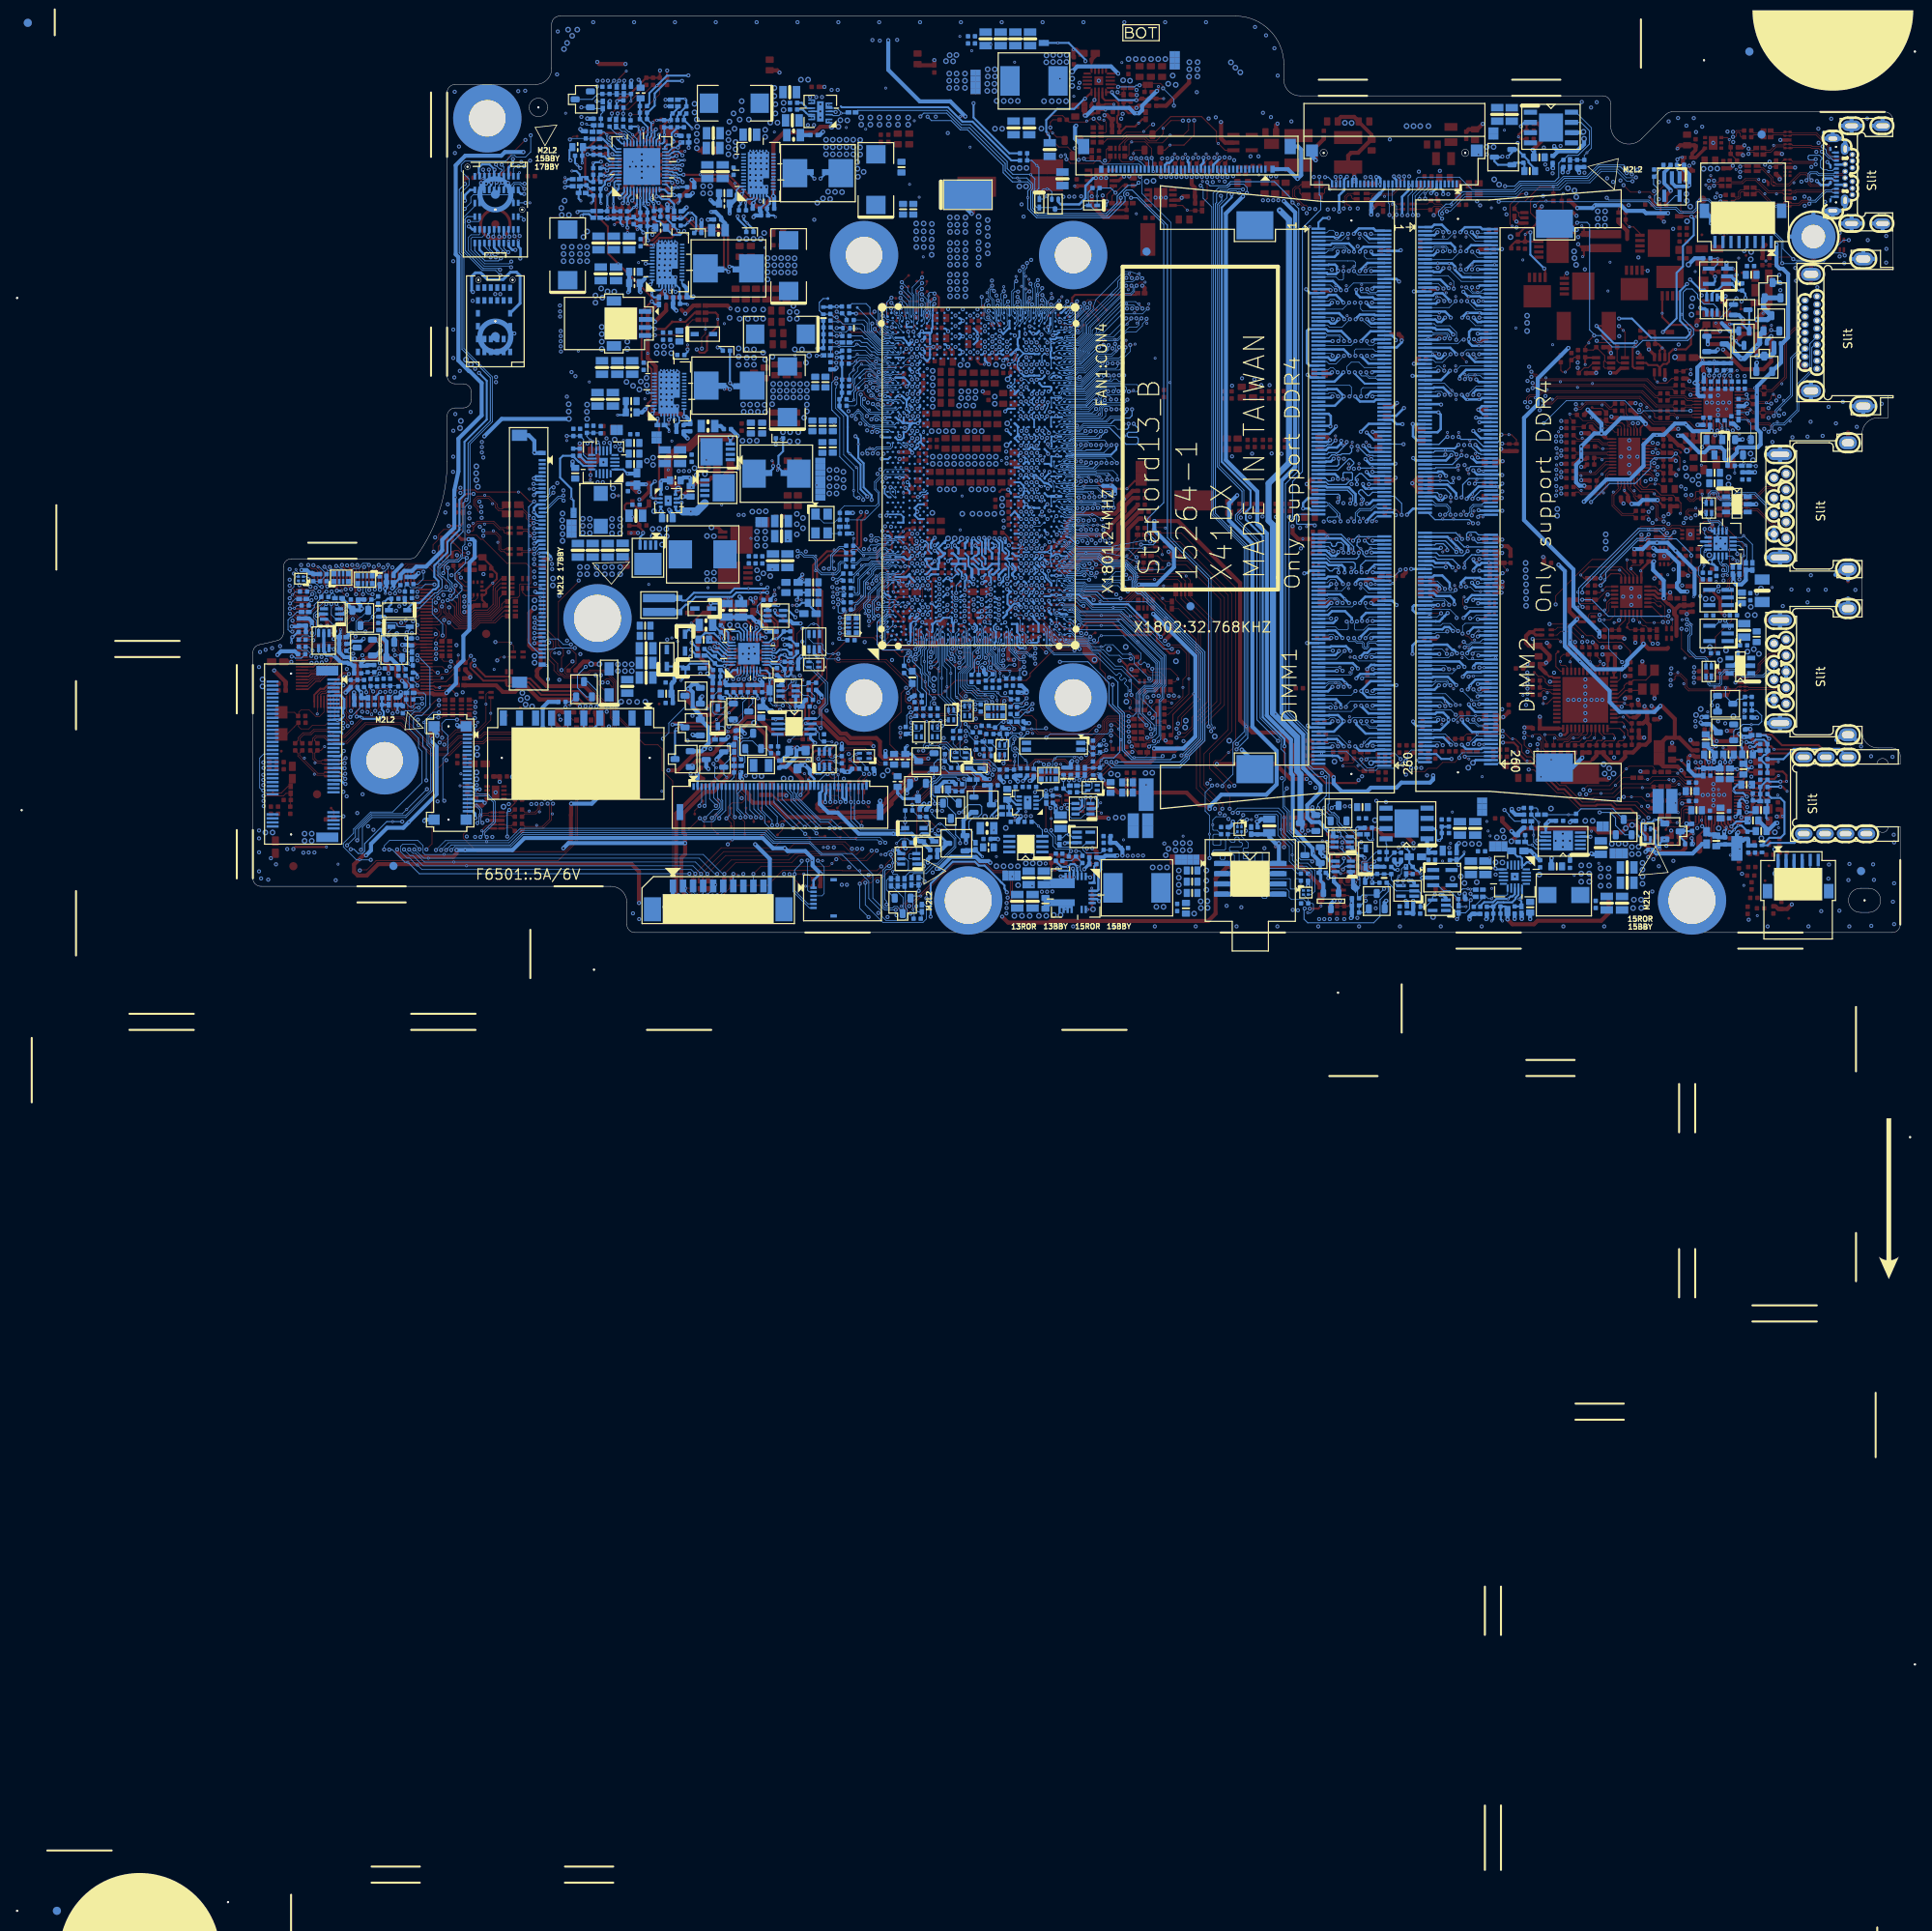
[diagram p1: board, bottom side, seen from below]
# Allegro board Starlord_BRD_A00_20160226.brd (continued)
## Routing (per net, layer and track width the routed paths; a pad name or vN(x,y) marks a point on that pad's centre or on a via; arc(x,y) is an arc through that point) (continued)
ACLIM: length 3.7
  BOTTOM w0.203: PU4401.16 140.66,36.06 140.41,36.31
  BOTTOM w0.254: PR4421.2 138.83,37.44 PR4424.1 138.85,37.32 139.65,36.52 v1(139.75,36.52) 140.21,36.52 140.41,36.31
ACOK#: length 4.4
  BOTTOM w0.127: 141.58,39.29 141.58,39.11 141.21,38.74 PQ4415.3 ; 141.58,39.29 142.11,39.82 v1(142.11,39.89) 142.11,40.59 PR4471.2 ; 141.58,39.29 141.48,39.39 PQ4415.2
ACOK_IN: length 85.4
  TOP w0.203: 196.95,29.81 197.21,29.55 KBC24.128
  TOP w0.254: v2(192.91,32.15) 192.96,32.15 193.06,32.25 193.65,32.25 194.18,31.72 194.18,31.56 194.75,30.99 195.31,30.99 196.01,30.29 196.47,30.29 196.95,29.81 ; v2(139.93,40.05) 137.67,37.79 v1(137.67,33.44) 137.67,33.08 138.77,31.97 139.95,31.97 140.17,32.2 141.68,32.2 141.96,32.48 144.27,32.48 PG4408.2
  L6 w0.254: v2(139.93,40.05) 140.08,39.89 140.08,36.77 140.71,36.14 140.71,35.67 144.25,32.13 146.05,32.13 146.78,32.86 155.57,32.86 156.74,34.03 163.22,34.03 164.72,32.52 165.5,32.52 166.11,33.14 167.99,33.14 169.16,31.97 176.64,31.97 177.7,30.9 178.81,30.9 179.19,30.52 183.41,30.52 184.1,31.21 185.6,31.21 186.1,30.7 191.46,30.7 v2(192.91,32.15)
  BOTTOM w0.254: v2(139.93,40.05) 139.93,39.67 139.65,39.39 PQ4415.5
ACOK_IN_M: length 404.4
  TOP w0.254: PD4305.K 26.01,89.04 v2(25.96,88.99) v1(25.35,88.99) ; PD4306.K v2(29.51,74.64)
  L3 w0.254: v2(65.81,7.48) 65.05,7.48 63.32,9.21 61.08,9.21 59.99,10.3 59.99,11.22 59.23,11.98 59.23,12.01 58.6,12.64 58.56,12.64 58.43,12.77 51.98,12.77 51.38,13.36 51.38,13.38 51.18,13.58 51.17,13.58 50.73,14.01 45.72,14.01 43.71,16.02 38.77,16.02 37.82,16.97 37.82,18.18 38.72,19.08 38.72,24.21 35.42,27.51 35.42,34.08 33.81,35.7 33.81,36.44 33.04,37.2 29.2,37.2 27.94,38.46 27.94,40.86 29.28,42.21 29.28,43.3 27.68,44.9 27.68,45.91 29.54,47.77 29.54,48.91 30,49.37 30,50 30.25,50.25 30.25,52.9 31.11,53.76 31.11,54.75 32.18,55.82 32.18,56.33 31.29,57.22 31.29,61.1 30.05,62.35 30.05,65.25 34.64,69.85 34.64,73.83 v2(34.95,74.13) ; v2(39.27,94.45) 39.27,94.82 41.59,97.15 43.13,97.15 44.94,98.95 48.11,98.95 48.73,99.57 56.6,99.57 57.68,98.49 62.36,98.49 63.18,99.32 77.05,99.32 78.15,100.42 78.71,100.42 85.23,106.94 85.23,109.1 87.32,111.19 120.88,111.19 121.77,110.3 133.07,110.3 133.86,111.09 161.36,111.09 161.49,110.96 161.49,110.96 165.02,107.43 165.02,105.45 166.62,103.85 166.62,100.83 171.47,95.98 v2(171.47,95.77)
  L4 w0.254: v2(137.39,39.18) 136.75,39.18 135.18,37.61 135.18,35.04 137.16,33.06 144.56,33.06 145.83,34.33 147.86,34.33 148.61,33.58 148.64,33.58 148.66,33.56 151.62,33.56 151.94,33.87 153.08,33.87 154.61,35.4 157.62,35.4 158.63,36.41 158.63,40.45 160.61,42.43 164.61,42.43 165.07,42.89 165.07,56.53 166.6,58.06 166.6,58.31 166.6,58.31 166.6,60.06 168.06,61.52 168.06,70.82 169.25,72.01 169.25,79.53 169.9,80.18 169.9,94.65 170.61,95.36 170.61,95.45 170.93,95.77 v2(171.47,95.77)
  L6 w0.254: v2(39.27,94.45) 39.27,93.21 38.78,92.73 38.78,87.47 35.86,84.55 35.86,75.05 v2(34.95,74.13) 33.68,72.86 32.64,72.86 30.86,74.64 v2(29.51,74.64)
  BOTTOM w0.254: PQ4415.6 138.24,40.04 v2(137.39,39.18) ; v2(25.96,88.99) 25.68,88.71 25.68,86.68 27.02,85.34 27.02,82.8 27.81,82.01 27.81,76.34 v2(29.51,74.64) ; v2(65.81,7.48) 66.06,7.48 66.47,7.89 D1701.K
AD+: length 251.1
  TOP w0.457: v2(156.79,53.84) 156.54,53.84 155.6,54.78 PD4411.A
  L3 w0.508: v2(149.2,32.2) 149.2,35.84 150.26,36.9 151.56,36.9 157.61,42.94 157.61,53.03 v2(156.79,53.84)
  L4 w0.508: v2(163.93,100.55) 164.51,100.55 165.4,101.44 165.4,103.16 163.63,104.94 163.63,107.52 161.33,109.82 128.7,109.82 128.48,109.61 124.66,109.61 121.78,112.48 82.57,112.48 81.93,112.48 78.05,108.6 78.05,104.61 76,102.56 v2(38.45,102.56) ; v2(166.67,77.94) 166.75,78.02 167.61,78.02 168.48,77.16 168.48,72.15 167.31,70.98 167.31,69.73 163.99,66.41 161.34,66.41 157.58,62.65 157.58,54.37 157.05,53.84 v2(156.79,53.84)
  L6 w0.508: v2(38.45,102.56) 38.45,101.13 37.51,100.19 37.51,98.8 35.33,96.61 30.99,96.61 29.06,94.68 29.06,92.96 29.36,92.65 29.36,91.18 28.24,90.06 v2(28.24,87.47) ; v2(163.93,100.55) 163.8,100.55 163.35,100.09 163.35,99.66 164.74,98.26 164.74,98.21 165.36,97.59 166.36,97.59 167.69,96.26 167.69,78.99 166.67,77.97 v2(166.67,77.94)
  vias: v1(152.04,36.19)
AD_IA: length 70
  TOP w0.102: v2(165.1,33.7) 165.19,33.7 166.04,32.85 166.04,32.26 165.86,32.08 164.34,32.08 164.02,32.4 163.19,32.4 162.96,32.63 161.04,32.63 159.61,31.2 159.61,27.11 157.34,24.83 151.71,24.83 151.33,25.21 147.17,25.21 146.78,25.59 v2(145.64,25.59) 145.62,25.59 v1(144.93,26.28) 143.15,28.06 143.15,29.4 142.95,29.61 142.57,29.61 PG4401.2
  L6 w0.102: v2(189.1,32.2) 189.03,32.2 188.26,32.96 185.14,32.96 185.01,33.09 184.14,33.09 183.83,33.09 182.56,31.82 180.11,31.82 178.23,33.7 178.23,34.58 177.95,34.87 176.96,34.87 175.11,33.01 169.59,33.01 168.3,34.31 168.3,34.31 167.9,34.31 167.9,34.31 165.71,34.31 v2(165.1,33.7)
  BOTTOM w0.102: v2(189.1,32.2) 189.38,31.92 189.83,31.92 R2421.1 ; v2(145.64,25.59) 145.54,25.59 145.21,25.92 144.58,25.92 143.94,26.56 143.94,28.59 143.31,29.23 PC4423.1
AD_OFF_L: length 5.5
  BOTTOM w0.254: PQ4304.C 18.78,77.26 PQ4305.1 18.81,74.78 19.66,75.63 v1(21.23,75.63)
AD_OFF_R: length 17.3
  TOP w0.254: PU4301.4 v1(29.6,76.98) 29.6,76.51 28.62,75.53 26.11,75.53 25.42,74.85 24.84,74.85 PR4307.2 24.1,74.65 PR4308.1 23.51,73.98 v2(20.98,73.98) 20.98,75.02 PC4301.2
  BOTTOM w0.254: v2(20.98,73.98) 19.98,72.98 PQ4305.3
ALERT#: length 3.8
  BOTTOM w0.102: v1(132.84,23.69) 132.9,23.75 R2603.2 134.12,23.75 134.43,24.06 134.43,24.79 134.93,25.29 THM261.6
ALL_SYS_PWRGD: length 312.9
  TOP w0.127: KBC24.48 191.21,45.23 v2(191.01,45.43) ; R4044.1 97.13,91.13 v2(96.92,91.33) ; R1733.2 57.77,4.8 v2(57.86,4.72)
  L3 w0.127: v2(179.12,69.82) 178.72,69.42 178.48,69.42 178.26,69.37 177.53,69.37 176.78,68.62 176.78,64.18 179.47,61.48 179.47,57.09 180.16,54.91 180.16,52.16 181.25,51.07 181.61,50.03 181.61,49.06 183.23,47.44 183.23,46.55 183.84,45.94 184.83,45.94 185.84,44.94 190.51,44.94 v2(191.01,45.43) ; v2(121.84,101.44) 121.84,103.04 124.46,105.66 133.93,105.66 135.91,107.64 156.66,107.64 158.23,106.07 158.23,105.39 158.7,104.92 159.76,104.92 162.1,102.58 v2(164.01,102.58)
  L4 w0.127: v2(96.92,91.33) 96.57,91.69 96.57,91.96 96.28,92.26 95.61,92.26 95.36,92 91.35,92 90.7,91.36 90.7,90.77 90.07,90.14 85.93,90.14 v2(84.48,91.58) ; v2(77.37,23.82) 77.37,20.9 75.46,18.99 75.46,14.77 74.83,14.14 74.83,5.71 73.99,4.87 73.99,3.06 v2(74.06,2.99) ; v2(166.65,76.57) 167.08,76.14 167.08,73.83 166.76,73.51 v2(166.57,73.51)
  L6 w0.127: v2(166.57,73.51) 166.08,73.01 166.08,71.73 170.97,66.84 175.11,66.84 177.72,69.46 178.76,69.46 v2(179.12,69.82) ; v2(166.65,76.57) 166.27,76.57 165.86,76.98 165.86,77.96 167.12,79.22 167.12,95.64 165.91,96.84 165.9,96.84 165.82,96.93 165.1,96.93 164.24,97.79 164.12,97.79 162.02,99.89 162.02,101.34 163.27,102.58 v2(164.01,102.58)
  BOTTOM w0.127: v2(96.92,91.33) 96.92,90.83 98.63,89.12 107.3,89.12 108.13,89.95 108.13,92.2 107.87,92.46 107.87,93.05 108.62,93.79 v1(109.78,93.79) 110.39,93.79 111.3,94.71 111.3,95.6 115.75,100.04 116.76,100.04 118.58,101.86 121.42,101.86 v2(121.84,101.44) ; v2(74.06,2.99) 74.14,2.91 74.14,1.67 73.68,1.21 65.48,1.21 64.69,2 64.69,4.08 63.68,5.1 63.68,6 R1716.1 63.68,6.19 62.66,5.17 U1701.2 59.92,5.17 59.64,4.89 59.64,3.26 EC1709.1 59.64,3.18 59.02,3.18 U1703.4 58.15,4.42 v2(57.86,4.72) ; v2(164.01,102.58) 164,102.59 D4002.1 162.7,102.42 R4011.2 161.34,101.95 161.58,101.71 R4005.2 R4002.1 ; v2(77.37,23.82) 80,26.45 80,48.59 82.67,51.27 82.67,51.9 81.86,52.71 81.86,54.86 84.91,57.91 84.91,90.49 84.38,91.02 84.38,91.48 v2(84.48,91.58)
ALL_SYS_PWRGD_R: length 7.6
  TOP w0.127: R4044.2 98.02,91.53 v2(97.59,91.96) 96.7,92.85 R4018.2
  BOTTOM w0.127: v2(97.59,91.96) 98.17,92.55 R4019.1 99.87,92.23 v1(99.87,91.53) 99.87,90.41 D4003.K
ALWON: length 110.8
  TOP w0.127: KBC24.121 194.41,27.91 194.69,27.63 194.69,26.69 v1(194.34,26.34) 194.05,26.05 v2(193.62,26.05)
  L4 w0.127: v2(116.91,11.12) 117.12,10.91 118.84,10.91 119.48,10.28 122.48,10.28 123.52,9.24 128.95,9.24 130.52,7.67 132.78,7.67 132.87,7.76 137.52,7.76 137.53,7.78 137.9,7.78 137.91,7.76 140.08,7.76 140.51,8.2 152.35,8.2 156.67,12.51 164.21,12.51 165.02,13.33 173.91,13.33 175.16,14.57 176.78,14.57 177.24,15.03 179.04,15.03 179.53,15.51 186.41,15.51 187.09,16.2 188.6,16.2 192.19,19.79 192.19,23.22 191.5,23.91 191.5,27.06 192.43,27.99 193,27.99 193.19,27.8 193.19,26.48 v2(193.62,26.05)
  BOTTOM w0.127: R4009.2 116.66,18.56 117.42,19.32 119.15,19.32 119.89,18.58 120.11,18.58 120.34,18.36 120.34,17.13 120.11,16.91 118.76,16.91 118.46,16.61 118.46,15.69 117.47,14.7 117.47,12.16 116.91,11.6 v2(116.91,11.12)
AMBER_LED_BAT: length 4.6
  BOTTOM w0.305: Q6402.C 119.4,12.03 119.76,12.03 v1(120.04,12.31)
  BOTTOM w0.508: Q6402.C 119.08,10.48 119.12,10.48 119.34,10.25 R6401.2 EC6401.1
AUD_AGND: length 29.6
  TOP w0.203: 20.5,13.68 20.9,14.09 HDA27.37 ; HDA27.18 23.44,20.82 23.16,21.1 v2(23.16,21.17)
  TOP w0.381: v2(19.76,14.32) 19.71,14.37 18.87,14.37 18.4,14.84 18.4,15.96 17.93,16.43 EC2906.2
  TOP w0.508: v2(20.17,12.44) 20.03,12.58 EC2704.1 ; EC2905.2 14.84,15.29 14.65,15.1 v1(14.65,14.47) 14.7,14.42 v2(15.35,14.42) ; v2(19.76,14.32) 19.76,13.89 19.96,13.68 20.5,13.68 ; v2(20.01,24.71) 20.53,24.18 EC8904.1 21.27,23.79 v2(22.83,23.79) 23.01,23.79 23.49,24.27 EC8901.1 EC8903.1
  BOTTOM w0.508: C2705.1 16.64,12.92 C2702.1 16.51,12.62 15.52,13.61 v2(15.29,13.61) ; v2(20.01,24.71) 20.01,24.68 19.67,24.34 EC8902.1 18.67,24.34 R2905.2 ; R2706.1 19.58,11.42 19.37,11.64 R2711.1 18.9,11.54 EC2707.1 EC2706.1 ; R2706.1 20.32,12.28 v2(20.17,12.44) ; R2706.1 20.79,10.95 C2710.2 22.67,10.95 C2711.2 ; C2715.2 23.06,22.19 C2712.1 23.16,22.01 v2(23.16,21.17)
  vias: v2(18.51,19.37) v2(18.62,21.25)
AUD_HP1_JACK_L: length 3.5
  TOP w0.203: 19.43,19.14 19.66,18.91 HDA27.26
  TOP w0.254: R2907.2 18.7,19.93 18.97,20.21 v1(18.98,20.21) 18.98,20.16 19.43,19.71 19.43,19.14
AUD_HP1_JACK_L1: length 9.5
  TOP w0.254: v1(14.14,18.8) 14.16,18.8 ; 14.16,18.8 14.16,19.56 14.6,20.01 16.09,20.01 R2907.1 ; 14.16,18.8 14.24,18.8 14.27,18.76 v2(14.91,18.76)
  BOTTOM w0.254: v2(14.91,18.76) 16.29,18.76 R2919.1 R2912.2 R2908.1 R2922.2 17.44,16.35 18.27,16.35 EC2907.1
AUD_HP1_JACK_R: length 5.3
  TOP w0.203: HDA27.25 20.21,19.65
  TOP w0.254: 20.21,19.65 20.06,19.8 20.06,19.8 19.76,20.1 19.76,21.33 20.9,22.47 20.9,22.75 R2909.2 21.82,22.75 v1(22.02,22.95)
AUD_HP1_JACK_R1: length 8.5
  TOP w0.254: v2(19.12,23.66) 19.23,23.56 19.23,22.91 R2909.1
  BOTTOM w0.254: R2920.1 EC2908.1 R2910.1 17.41,21.59 16.91,22.09 16.76,22.09 16.52,22.33 R2921.2 R2913.2 16.52,23.52 16.97,23.97 17.98,23.97 v1(18.34,23.61) 19.07,23.61 v2(19.12,23.66)
AUD_PC_BEEP: length 3.1
  TOP w0.203: HDA27.32 19.56,16.51 19.3,16.25 19.1,16.25 19.08,16.23 v2(19.07,16.23)
  BOTTOM w0.254: v2(19.07,16.23) 19.08,16.23 19.1,16.25 19.2,16.25 19.66,16.7 v1(19.66,16.76) 20.01,16.4 R2723.2
AUD_PC_BEEP_C: length 3.3
  BOTTOM w0.254: R2717.1 25.91,12.6 27.33,12.6 D2701.3 27.37,11.88 26.76,11.27 C2720.1
AUD_PC_BEEP_R: length 10.5
  TOP w0.254: v1(25.68,11.04) 25.68,11.46 v2(25.94,11.73)
  L6 w0.254: v2(25.94,11.73) 25.71,11.73 24.97,12.46 23.26,12.46 22.66,11.85 21.1,11.85 20.7,12.25 20.7,12.76 20.5,12.96 v2(20.5,14.39)
  BOTTOM w0.254: R2723.1 20.24,14.74 20.24,14.65 v2(20.5,14.39) ; v2(25.94,11.73) 25.87,11.66 C2720.2
AUD_PORTA_L_R_B: length 15.7
  BOTTOM w0.254: R2908.2 16.04,16.73 14.91,16.73 14.4,16.22 14.4,12.26 14.88,11.78 16.28,11.78 17.19,10.86 ED2902.1 16.47,10.85 16.18,11.14 13.15,11.14 HPMIC1.1
AUD_PORTA_R_R_B: length 23.4
  TOP w0.254: ED2905.1 17.69,24.6 16.03,24.6 14.7,23.28 10.16,23.28 9.7,22.83 7.54,22.83 6.51,21.79 HPMIC1.2
  BOTTOM w0.254: HPMIC1.2 7.54,22.83 13.26,22.83 14.53,21.56 R2910.2
AUD_SENSE: length 30
  TOP w0.254: v2(18.46,20.54) 18.64,20.71 18.89,20.71 19.17,21 v1(19.17,21.5) 18.83,21.84 18.31,21.84 18.31,21.82 R2923.2 ; v2(29.08,10.79) 29.08,10.81 28.88,11.01 R2709.2
  L6 w0.254: v2(18.46,20.54) 18.34,20.41 15.33,20.41 14.4,19.48 14.4,17.15 20.26,11.29 22.81,11.29 23.48,11.95 24.76,11.95 25.93,10.79 v2(29.08,10.79)
  BOTTOM w0.254: v2(18.46,20.54) 18.59,20.41 18.95,20.41 C2902.1
AUD_SENSE_A: length 4.8
  TOP w0.203: 26.26,14.39 HDA27.1
  TOP w0.254: 26.26,14.39 26.26,13.96 26.08,13.78 26.08,13.34 26.52,12.9 v1(26.76,12.9) 26.89,12.9 27.54,12.25 R2722.2 R2709.1
AUD_SPK_L+: length 2.6
  TOP w0.203: 22.43,11.8 23.16,12.54 23.16,13.33 23.04,13.45 HDA27.42
  vias: v1(19.96,10.38)
AUD_SPK_L+_C: length 1.8
  BOTTOM w0.406: v3(15.54,7.33) 15.2,7.67 SPK1.1
AUD_SPK_L-: length 2.9
  TOP w0.203: HDA27.43 23.44,13.53 23.49,13.48 23.49,11.97 23.52,11.94 23.52,11.22
  vias: v1(21.13,9.62)
AUD_SPK_L-_C: length 1.6
  BOTTOM w0.406: v3(14.27,7.46) 14.2,7.53 SPK1.2
AUD_SPK_R+: length 4.3
  TOP w0.203: 24.99,11.8 24.99,12.13 24.15,12.97 24.15,13.49 24.24,13.58 HDA27.45
  TOP w0.762: 24.99,10.17 24.99,11.8
  vias: v1(17.78,2.1)
AUD_SPK_R+_C: length 2
  BOTTOM w0.406: SPK1.4 12.2,8.03 11.71,7.54 v3(11.71,7.18)
AUD_SPK_R-: length 2.3
  TOP w0.203: HDA27.44 23.82,14.07 23.82,12.64 24.15,12.31 24.15,11.9
  vias: v1(19.45,5.86)
AUD_SPK_R-_C: length 1.7
  BOTTOM w0.406: SPK1.3 13.2,7.55 v3(13.03,7.38)
AUD_VREF: length 4
  TOP w0.203: HDA27.38 21.44,13.58 21.24,13.37 21.2,13.37 v2(21,13.17)
  TOP w0.254: v1(20.65,12.74) 21,13.1 v2(21,13.17)
  BOTTOM w0.254: C2705.2 19.1,13.81 20.37,13.81 v2(21,13.17)
AUX_EN_WOWL: length 4.3
  TOP w0.102: TP1710.1 99.97,45.71 v2(100,45.74)
  BOTTOM w0.102: CPU1.BB17 102.77,46.14 102.64,46.27 100.46,46.27 100,45.81 v2(100,45.74)
B71_TP: length 2.5
  TOP w0.102: v2(125.5,77.61) 124.81,76.93 TP2312.1
  BOTTOM w0.102: CPU1.B71 125.45,77.51 125.5,77.56 v2(125.5,77.61)
BA1_TP: length 4.1
  TOP w0.102: v2(100.25,36.31) 100,36.06 TP2305.1
  BOTTOM w0.102: v2(100.25,36.31) 100.3,36.36 100.86,36.36 100.89,36.39 103.33,36.39 103.33,36.4 CPU1.BA1
BA2_TP: length 4.4
  TOP w0.102: TP2306.1 100.23,37.25 v2(100.71,36.77)
  BOTTOM w0.102: v2(100.71,36.77) 100.86,36.62 102.54,36.62 103.1,37.18 103.58,37.18 103.73,37.03 CPU1.BA2
BA71_TP: length 5.6
  TOP w0.102: v2(102.37,78.46) 102.37,78.01 102.79,77.59 103.22,77.59 103.32,77.49 103.96,77.49 TP2303.1
  BOTTOM w0.102: CPU1.BA71 103.49,77.28 103.49,77.32 103.26,77.55 102.83,77.55 102.57,77.81 102.57,78.24 102.37,78.44 v2(102.37,78.46)
BAT1_LED#: length 49.7
  TOP w0.127: v2(178.26,46.57) 178.53,46.85 v1(178.92,46.85) 178.92,47.08 179.32,47.49 179.75,47.49 180.07,47.17 Q2416.1 ; v2(180.63,41.31) 179.78,40.46 179.78,39.39 179.21,38.82 178.98,38.59 177.72,38.59 176.97,39.34 175.38,39.34 174.22,40.5 174.22,41.61 RN2405.1 ; v2(192.1,36.8) 192.1,36.75 193.71,35.13 193.71,33.83 195.61,31.93 195.78,31.93 196.49,31.22 197.01,31.22 197.99,30.24 KBC24.1
  L3 w0.127: v2(181.18,44.67) 181.53,44.67 183.13,43.07 184.83,43.07 188.3,39.6 188.62,39.6 188.89,39.34 188.89,39.17 189.74,38.32 190.98,38.32 191.44,37.86 191.44,37.46 v2(192.1,36.8)
  BOTTOM w0.127: v2(180.63,41.31) 180.06,41.31 178.87,42.51 178.87,43.07 179.7,43.91 179.7,44.62 178.41,45.91 178.41,46.4 178.26,46.55 v2(178.26,46.57) 178.8,46.57 179.3,46.08 180.48,46.08 180.74,45.83 180.75,45.83 181.06,45.51 181.06,45.5 181.07,45.49 181.07,44.77 v2(181.18,44.67)
BAT2_LED#: length 38.6
  TOP w0.127: v2(180.59,45.33) 181.01,45.74 v1(181.64,45.74) 181.79,45.89 181.79,48 181.37,48.41 Q2416.4 ; KBC24.106 188.41,29.9 v2(188.39,29.91) ; RN2405.2 174.06,42.87 174.5,42.43 174.5,40.58 175.48,39.59 177.08,39.59 177.83,38.84 178.87,38.84 179.53,39.5 179.53,40.94 180.26,41.68 180.26,41.81 180.3,41.85 v2(180.3,41.85)
  L4 w0.127: v2(188.39,29.91) 188.39,30.17 187.02,31.54 187.02,33.7 186.73,33.99 186.73,36.76 186.5,36.99 186.5,37.16 185.39,38.26 185.39,38.85 184.96,39.28 184.91,39.28 181.65,42.54 181,42.54 180.54,42.08 180.31,41.85 v2(180.3,41.85)
  BOTTOM w0.127: v2(180.59,45.33) 180.59,43.96 180.07,43.44 180.07,42.96 179.78,42.67 179.78,42.27 180.1,41.94 180.17,41.94 180.26,41.85 v2(180.3,41.85)
BAT_AMBER: length 18.4
  BOTTOM w0.305: 134.34,17.31 134.05,17.6 KBBD1.33
  BOTTOM w0.508: R6401.1 120.64,10.32 ED6401.1 121.69,11.37 122.03,11.37 122.92,12.26 v1(125.19,12.26) 125.22,12.28 129.51,12.28 132.13,14.9 133.28,14.9 134.34,15.96 134.34,17.31
BAT_WHITE: length 31
  TOP w0.508: v2(133.68,16.2) 133.7,16.22 134.34,16.22 134.67,15.89 134.67,15.43 134.34,15.1 132.64,15.1 132.46,14.93 130,14.93 129.92,15 127.32,15 126.08,16.24 126.08,16.55 122.77,19.85 v1(120.8,19.85) 114.98,19.85 114.1,18.97 113.33,18.97 v2(113.23,19.07)
  BOTTOM w0.305: KBBD1.34 133.55,17.34 133.68,17.21 v2(133.68,16.2)
  BOTTOM w0.406: R6402.1 113.92,19.23 114.44,19.75 114.86,19.75 115.52,20.41 ED6402.1
  BOTTOM w0.457: R6402.1 113.8,19.07 v2(113.23,19.07)
BATT_WHITE_LED#: length 90.9
  TOP w0.127: Q2416.6 180.07,48.62 178.64,47.18 v2(178.08,47.18) ; v1(119.51,16.02) v2(120.06,16.02)
  L4 w0.127: v2(120.06,16.02) 120.06,15.99 120.47,15.59 120.6,15.59 120.85,15.33 121.99,15.33 122.43,14.9 125.27,14.9 125.66,14.51 134.81,14.51 135.08,14.77 139.5,14.77 141.63,16.91 143.64,16.91 143.89,17.16 144.73,17.16 146.43,18.86 148.84,18.86 149.27,19.3 150.59,19.3 150.87,19.58 150.87,20.47 154.56,24.16 164.3,24.16 164.72,24.58 166.44,24.58 166.86,25 166.86,25.3 169.09,27.52 169.09,28.7 172.74,32.35 172.74,36.57 175.99,39.82 175.99,43.45 176.01,43.47 176.01,43.5 176.99,44.48 176.99,46.09 v2(178.08,47.18)
  BOTTOM w0.127: R6404.1 115.73,19.32 115.99,19.57 119.26,19.57 119.99,18.84 120.22,18.84 120.59,18.46 120.59,16.88 120.09,16.37 120.09,16.04 v2(120.06,16.02)
BATT_WHITE_LED_R#: length 60
  L4 w0.127: v2(162.13,28.06) 162,28.06 161.91,28.15 160.51,28.15 159.94,27.58 152.2,27.58 150.47,25.85 149.73,25.85 148.79,24.91 146.12,24.91 146,24.78 145.57,24.78 145.18,24.39 145.18,24 143.98,22.8 141.68,22.8 139.42,20.54 137.56,20.54 136.65,19.63 135.53,19.63 134.91,19 132.45,19 131.89,19.56 131.18,19.56 131.13,19.51 130.21,19.51 129.04,20.68 124.99,20.68 124.57,20.26 121.95,20.26 121.69,20.26 121.16,19.73 119.71,19.73 v2(118.95,20.49)
  BOTTOM w0.127: Q6401.B v1(115.19,18.1) 114.84,18.44 R6404.2 114.84,19.18 115.49,19.83 118.29,19.83 v2(118.95,20.49) ; Q6105.D 163.21,31.2 161.96,29.95 161.96,28.23 v2(162.13,28.06)
BB67_TP: length 2.1
  TOP w0.102: v2(102.31,74.79) 102.26,74.79 TP2302.1
  BOTTOM w0.102: v2(102.31,74.79) 102.33,74.79 102.36,74.82 103.03,74.82 103.24,74.61 CPU1.BB67
BB70_TP: length 2
  TOP w0.102: v2(102.46,77.36) 102.23,77.13 TP2301.1
  BOTTOM w0.102: CPU1.BB70 103.13,76.56 102.51,77.18 102.51,77.31 v2(102.46,77.36)
BEEP: length 343.5
  TOP w0.203: KBC24.45 192.41,44.99 192.62,45.2 192.76,45.2 193.14,45.58 v2(193.14,45.64)
  TOP w0.254: v2(31.95,13.89) 31.85,13.89 v1(31.49,13.53)
  L3 w0.254: v2(31.95,13.89) 31.95,14.35 30.78,15.52 30.78,19.45 26.8,23.44 26.8,27.96 25.27,29.48 24.41,29.48 22.66,31.23 22.66,32.74 21,34.39 21,38.53 20.7,38.84 20.7,41.45 18.49,43.66 18.49,51.15 19.18,51.83 19.18,56 19.68,56.51 19.68,57.2 22.72,60.24 23.48,60.24 25.72,62.48 25.72,63.81 25.58,63.95 25.58,67.05 26.19,67.66 26.52,67.66 29.97,71.1 29.97,73.17 31.29,74.49 31.29,80 33.2,81.91 33.2,84.33 31.28,86.25 31.28,90.76 30.1,91.94 30.1,92.49 32.44,94.83 v2(32.69,94.83)
  L4 w0.254: v2(169.87,44.87) 169.87,44.9 170.51,45.53 170.51,53.81 171.52,54.83 171.52,69.92 176.83,75.22 176.83,77.08 176.68,77.23 176.68,79.54 177.67,80.53 177.67,81.83 177.21,82.29 177.21,85.61 175.82,87.01 172.95,87.01 172.57,87.39 172.57,90.52 171.73,91.36 171.73,93.97 172.41,94.66 172.41,95.52 172.01,95.93 172.01,96.97 171.4,97.58 169.84,97.58 166.04,101.38 166.04,103.42 164.32,105.14 164.32,107.72 161.46,110.58 128.44,110.58 128.1,110.24 127.52,110.24 v2(126.9,110.86)
  L6 w0.254: v2(32.69,94.83) 32.92,95.06 35.99,95.06 38.4,97.48 40.07,97.48 41.93,99.33 44.32,99.33 47.18,102.19 76.28,102.19 76.6,102.51 76.6,102.51 79.04,104.94 79.04,106.7 83.93,111.59 126.17,111.59 v2(126.9,110.86) ; v2(193.14,45.64) 193.14,45.6 191.6,44.06 183.71,44.06 183.13,44.64 183.13,44.66 181.14,46.65 179.94,46.65 179.13,45.84 172.11,45.84 171.14,44.87 v2(169.87,44.87)
  BOTTOM w0.254: v2(31.95,13.89) 32.23,13.61 32.23,12.51 31.72,12 RN2701.1
BKLGT_PWM: length 113.7
  TOP w0.203: v2(192.02,42.05) 192.02,42.08 192.12,42.18 192.12,42.84 192.46,43.17 192.61,43.17 192.81,43.37 KBC24.44
  TOP w0.508: v1(137.72,22.98) v2(137.16,22.98)
  L3 w0.508: v2(192.02,42.05) 192.02,41.69 193.03,40.68 193.62,40.68 194.18,40.12 197.06,40.12 198.58,38.61 198.58,36.26 198.98,35.86 198.98,32.73 198.78,32.53 198.78,31.85 200.02,30.61 200.02,16.83 195.5,12.31 190.32,12.31 v2(189.86,12.77)
  L6 w0.508: v2(137.16,22.98) 137.21,22.93 137.21,18.86 138.33,17.75 138.69,17.75 139.16,17.27 139.16,15.86 145.18,9.85 177.11,9.85 179.32,12.06 189.15,12.06 v2(189.86,12.77)
  BOTTOM w0.508: R6509.1 139.28,20.59 138.56,20.59 137.26,21.89 137.26,22.88 v2(137.16,22.98) 136.98,22.8 136.29,22.8 Q6501.G
BKLT_CTRL: length 22.2
  TOP w0.114: v2(98.91,95.95) 98.73,96.13 98.73,97.32 98.57,97.48 RN5501.5 ; RN5502.5 99.38,100.24 v2(100.3,101.16) 100.68,101.16 100.96,100.88 v1(101.17,100.88) 101.29,100.75 103.36,100.75 R5502.1 104.15,101.54 105.51,101.54 106.2,100.85 106.2,99.23 104.61,97.64 103.53,97.64 102.92,97.03 D5502.3
  L4 w0.114: v2(98.91,95.95) 100.3,97.35 v2(100.3,101.16)
BLON_OUT_C: length 15.7
  TOP w0.102: v2(95.02,96.26) 95.02,96.18 95.43,95.77 96.75,95.77 97.08,96.11 RN5501.2 ; v2(99.62,101.21) 99.4,100.99 v1(99.03,100.99) 98.73,100.69 98.73,99.53 98.86,99.4 RN5502.6
  L4 w0.102: v2(95.02,96.26) 95.22,96.05 95.22,96.03 95.45,95.8 95.83,95.8 99.62,99.58 v2(99.62,101.21)
  BOTTOM w0.102: LCD1.31 93.95,95.29 94.49,95.83 94.59,95.83 v2(95.02,96.26)
BLUETOOTH_EN: length 82.8
  L4 w0.102: v2(114.74,34.84) 114.77,34.81 114.78,34.81 115.39,34.21 115.39,29.02 115.75,28.67 115.75,25.5 115.54,25.29 115.54,23.53 116.14,22.93 v2(116.2,22.93) 118.1,22.93 118.73,22.29 119.45,22.29 120.55,21.2 121.06,21.2 121.31,21.45 124.15,21.45 124.51,21.81 130.5,21.81 130.55,21.76 130.96,21.76 131.77,22.57 132.79,22.57 133.32,22.04 137.84,22.04 138.23,22.42 139.08,22.42 140.89,24.22 142.21,24.22 143.99,26 144.52,26 145.01,26.48 148.78,26.48 150.71,28.41 151.69,28.41 152.02,28.74 154.94,28.74 155.62,29.43 159.41,29.43 159.56,29.28 161.57,29.28 162.83,29.28 165.75,32.2 166.65,32.2 166.9,32.45 166.9,32.99 167.94,34.03 167.94,35.98 v2(168.02,36.06)
  BOTTOM w0.089: CPU1.AB2 114.66,36.83 114.66,36.67 114.71,36.48 114.71,36.31 114.67,36.18 114.5,36.01 114.5,35.3 114.6,35.2
  BOTTOM w0.102: IOBD1.47 168.27,35.71 168.04,35.93 168.04,36.01 168.02,36.03 v2(168.02,36.06) ; v2(114.74,34.84) 114.74,35.05 114.6,35.2 ; R2042.2 112.08,20.25 112.27,20.44 112.27,20.44 112.52,20.69 112.52,20.69 v1(112.72,20.9) 113.28,21.45 115.19,21.45 115.46,21.73 115.46,22.44 115.95,22.93 v2(116.2,22.93)
BOARD_ID: length 9.6
  TOP w0.102: v2(189.13,32.86) 190.32,31.67 190.32,29.68 190.41,29.6 KBC24.111 190.41,27.89 190.41,27.89 190.17,27.65 190.17,27.27 v1(190.07,27.17)
  BOTTOM w0.102: R2494.2 188.53,32.76 189.03,32.76 v2(189.13,32.86) 189.15,32.86 189.25,32.76 189.28,32.76 189.67,32.36 C2408.2 R2444.1 190.71,32.22 R2443.2
BOARD_ID1: length 6.5
  BOTTOM w0.102: CPU1.AC1 113.76,36.7 113.76,35.89 113.77,35.88 113.77,34.74 113.31,34.28 v1(113.31,33.75) 113.31,33.32 113.54,33.09 113.54,32.68 113.33,32.48 113.19,32.48 R2009.1 112.91,32.12 R2010.2
BOARD_ID2: length 14.7
  BOTTOM w0.089: CPU1.AB3 114.45,37.52 114.84,37.13 114.84,36.69 114.89,36.5 114.89,36.11 114.68,35.9 114.68,35.48 114.74,35.41
  BOTTOM w0.102: R2008.1 R2005.2 110.59,29 110.92,29.33 111.78,29.33 112.44,29.99 114.45,29.99 114.6,30.14 114.6,30.14 v1(114.68,30.22) 115.11,30.65 115.82,30.65 116.05,30.88 116.05,32.22 115.31,32.96 115.31,34.84 114.74,35.41
BOOST_MON: length 72.1
  TOP w0.254: PG4414.2 141.04,29.18 v1(141.17,29.05) 141.98,29.05 v2(142.06,29.13)
  L6 w0.254: v2(142.06,29.13) 142.06,29.12 144.08,27.1 144.08,25.09 145.11,24.06 145.4,23.77 146.68,23.77 147.27,24.35 149.22,24.35 150.24,23.33 176.53,23.33 176.73,23.54 177.98,23.54 179.5,22.01 182.93,22.01 187.55,26.64 189.56,26.64 189.81,26.38 190.93,26.38 192.45,24.86 193.9,24.86 194.16,25.11 194.16,27.53 192.51,29.18 189.76,29.18 v2(189.03,29.91)
  BOTTOM w0.254: R2423.1 189.67,29.26 v2(189.03,29.91) ; PC4424.1 142.42,29.84 142.11,29.53 142.11,29.23 142.06,29.18 v2(142.06,29.13)
BT+:
  vias: v3(156.06,28.69) v3(157.07,28.67) v3(158.06,28.69) v3(159.05,28.69)
C1_TP: length 2.4
  TOP w0.102: TP2308.1 126.21,35.53 v2(126.36,35.53)
  BOTTOM w0.102: v2(126.36,35.53) 125.49,36.4 CPU1.C1
CAP_LED: length 3.7
  TOP w0.508: AFTP6538.1 149.02,19.12 v2(149.66,19.75) 149.66,19.97 R6513.2
  BOTTOM w0.305: 149.55,19.12 KBBD1.2
  BOTTOM w0.508: 149.55,19.12 149.55,19.65 v2(149.66,19.75)
CAP_LED#: length 10.8
  TOP w0.127: v2(187.17,34.48) 186.23,33.54 186.23,32.43 184.96,31.16 184.3,31.16 184.02,31.44 KBC24.93 181.53,31.44 v1(181.33,31.64)
  BOTTOM w0.127: R2489.1 185.86,32.9 186.36,33.39 186.36,34.1 Q2414.S 186.61,34.48 v2(187.17,34.48)
CAP_LED#_R: length 81.2
  TOP w0.508: v2(145.69,23.26) 145.67,23.23 v1(145.67,22.7)
  L3 w0.508: 194.36,30.62 194.77,30.62 196.77,28.62 196.77,18.23 195.04,16.5 193.62,16.5 v2(193.19,16.93) ; v2(186.94,37.18) 186.94,36.9 187.76,36.08 187.76,35.83 188.29,35.3 188.29,34.71 188.77,34.23 189.76,34.23 192.11,31.88
  L6 w0.508: v2(145.69,23.26) 145.72,23.26 145.97,23 146.86,23 147.57,23.71 148.79,23.71 149.96,22.55 151.79,22.55 154.15,20.18 156.87,20.18 158.62,21.94 163.24,21.94 164.23,20.95 172.24,20.95 172.95,20.24 175.06,20.24 175.46,20.64 182.85,20.64 184.35,19.14 184.38,19.14 185.7,17.82 192.3,17.82 v2(193.19,16.93)
  BOTTOM w0.508: v2(145.69,23.26) 145.63,23.32 145.03,23.32 R6512.1 ; v2(186.94,37.18) 187.27,36.85 Q2414.D
CAP_LED_Q: length 4.3
  TOP w0.508: v2(148.21,20.34) 148.44,20.57 148.44,21.17 148.63,21.37 R6513.1 149.67,21.37 v1(150.24,20.79)
  BOTTOM w0.508: v2(148.21,20.34) 148.49,20.62 Q6505.C
CAP_LED_R#: length 3.9
  BOTTOM w0.127: v1(145.92,19.3) 146.3,19.68 Q6505.B 146.3,20.82 145.57,21.56 145.57,21.9 R6512.2
CBN: length 2.9
  TOP w0.203: HDA27.23 21.44,20.74 21.13,21.05 v2(21.13,21.17)
  TOP w0.254: v2(21.13,21.17) 20.78,21.53 v1(20.7,21.53)
  BOTTOM w0.254: C2703.2 21.13,21.68 v2(21.13,21.17)
CBP: length 2.8
  TOP w0.203: HDA27.22 21.84,21.1 v2(21.77,21.17)
  TOP w0.254: v2(21.77,21.17) 21.77,21.33 v1(22.15,21.71)
  BOTTOM w0.254: C2703.1 21.77,21.87 v2(21.77,21.17)
CCG2_I2C_SCL: length 361.1
  TOP w0.089: RN1815.4 38.51,38.63 38.78,38.9 38.78,39.46 38.53,39.72 37.62,39.72 v2(37.39,39.49) 36.73,39.49 36.22,40 36.22,40.87 36.09,41 U3701.20 ; v2(85.7,25.04) v1(85.29,25.44)
  L3 w0.127: v2(120.32,7.46) 120.93,6.85 121.54,6.85 124.6,3.79 125.07,3.79 125.25,3.61 125.25,3.61 125.87,2.99 128.75,2.99 129,2.73 153.26,2.73 153.69,3.17 v2(153.69,3.19) ; v2(37.39,39.49) 35.86,41.01 35.86,42.26 36.12,42.51 37.26,42.51 38.78,44.03 38.78,51.37 37.49,52.67 37.49,53.71 38.02,54.25 38.02,68.88 38.43,69.28 38.43,72.03 37.26,73.19 37.26,74.11 39.67,76.52 39.67,79.44 43.86,83.63 43.86,92.63 43.23,93.26 v2(43.23,94.38)
  L4 w0.127: v2(43.23,94.38) 43.27,94.34 44.76,94.34 49.6,99.18 54.28,99.18 55.34,98.11 55.34,94.71 56.7,93.35 70.55,93.35 70.84,93.64 70.84,94.12 71.14,94.43 72.41,94.43 v2(72.92,93.92) ; v2(85.7,25.04) 85.82,24.91 85.82,23.69 81.72,19.59 81.72,17.81 82.43,17.1 85.96,17.1 86.24,17.38 87.34,17.38 91.01,13.71 92.96,13.71 94.64,12.03 99.36,12.03 100.07,11.32 102.81,11.32 103.48,10.65 105.9,10.65 106.31,11.05 109.21,11.05 109.97,10.29 113.93,10.29 114.83,9.39 118.21,9.39 119.18,8.42 119.93,8.42 120.32,8.04 v2(120.32,7.46) ; v2(194.79,35.22) 194.79,35.14 195.27,34.66 195.27,34.31 195.22,34.26 195.22,33.32 199.01,29.53 199.01,17.92 193.58,12.5 192.26,12.5 190.8,11.04 190.8,10.28 188.71,8.18 158.54,8.18 158.33,7.97 158.29,7.97 153.69,3.37 v2(153.69,3.19)
  L6 w0.102: v2(94.54,93.95) 94.53,93.95 93.67,93.95 93.61,94.01 92.62,94.01 92.1,93.49 87.02,93.49 86.82,93.29 86.79,93.29 86.56,93.06 86.56,93.03 86.28,92.75 83.89,92.75 83.06,93.59 82.75,93.59 82.35,94 79.53,94 79.09,94.43 74.88,94.43 74.37,93.92 v2(72.92,93.92)
  BOTTOM w0.089: Q2605.6 194.92,35.35 v2(194.79,35.22) ; v2(94.54,93.95) 94.54,93.9 94.28,93.64 94.28,91.86 90.68,88.26 90.68,49.06 85.7,44.09 85.7,25.92 85.58,25.8 85.58,25.44 85.7,25.32 v2(85.7,25.04)
CCG2_I2C_SDA: length 236.5
  TOP w0.089: RN1815.3 37.81,39.28 v2(37.39,38.85) 37.36,38.88 v1(36.83,38.88) 36.07,38.88 35.49,39.45 U3701.19
  L3 w0.127: v2(34.59,33.62) 34.69,33.52 34.69,28.85 34.16,28.31 34.16,27.75 38.02,23.89 38.02,19.4 37.11,18.48 37.11,16.69 38.49,15.31 41.78,15.31 44.42,12.67 45.69,12.67 47.57,10.79 50.77,10.79 51.89,11.9 51.97,11.9 51.99,11.93 58.29,11.93 58.52,11.7 58.52,11.69 59.29,10.91 59.29,10.01 61.97,7.33 64.01,7.33 66,5.34 79.04,5.34 86.64,12.93 94.7,12.93 95.13,12.5 100.39,12.5 101.12,13.24 109.8,13.24 110.64,12.4 111.54,12.4 111.75,12.6 113.22,12.6 116.72,9.11 117.25,9.11 120.9,5.45 120.9,4.46 v2(121.11,4.26)
  L4 w0.127: v2(196.39,38.11) 196.39,37.44 194.99,36.03 194.97,36.03 194.35,35.41 194.35,33.96 194.84,33.47 194.84,33.16 198.61,29.39 198.61,18.25 193.51,13.15 192.35,13.15 190.42,11.22 190.42,10.44 188.55,8.56 158.39,8.56 158.17,8.35 158.13,8.35 152.56,2.77 133.46,2.77 133.02,3.22 132.1,3.22 132.1,3.22 130.18,3.22 130.17,3.22 127.74,3.22 126.63,4.32 121.17,4.32 v2(121.11,4.26)
  BOTTOM w0.089: Q2605.3 196.69,37.8 196.39,38.09 v2(196.39,38.11) ; v2(37.39,38.85) 36.24,37.71 36.24,35.27 v2(34.59,33.62)
CFG: length 2.8
  TOP w0.102: U5701.23 19.16,66.84 19.12,66.87 v2(19.1,66.87)
  BOTTOM w0.102: v2(19.1,66.87) 18.95,66.72 v1(18.95,66.31) 20.1,66.31 R5420.2
CFG0: length 4.7
  TOP w0.089: v2(126.52,76.67) 126.03,76.19 TP618.1
  BOTTOM w0.089: v2(126.52,76.67) 126.36,76.52 126.31,76.52 126.01,76.22 125.78,76.22 125.63,76.06 125.2,76.06 124.56,75.42 124.56,75.19 123.97,74.61 CPU1.E68
CFG1: length 4.5
  TOP w0.089: v2(126.54,77.31) 126.31,77.31 TP619.1
  BOTTOM w0.089: v2(126.54,77.31) 126.54,77.28 126.9,76.92 126.9,75.85 125.95,74.9 125.7,74.9 125.42,74.61 CPU1.B67
CFG2: length 5.5
  TOP w0.089: v2(127.53,75.02) 127.25,75.3 TP620.1
  BOTTOM w0.089: v2(127.53,75.02) 127.15,74.64 127.15,74.63 126.8,74.28 126.27,74.28 126.16,74.17 125.78,74.17 125.72,74.2 125.46,74.2 125.42,74.18 125.25,74 125.25,73.84 124.98,73.58 124.28,73.58 CPU1.D65
CFG3: length 9.5
  TOP w0.114: TP621.1 126.44,74.46 v2(126.67,74.69)
  BOTTOM w0.089: v2(126.67,74.69) 126.57,74.6 126.31,74.6 126.07,74.35 125.81,74.35 125.72,74.39 125.45,74.39 125.36,74.35 125.16,74.35 125.03,74.4 124.82,74.4 CPU1.D67
  BOTTOM w0.114: R604.1 130.36,78.17 128.6,78.17 128.12,77.69 128.12,76.9 127.3,76.09 127.3,75.61 126.67,74.97 v2(126.67,74.69)
CFG4: length 4.5
  TOP w0.089: v2(124.28,78.25) 123.85,77.82 TP622.1 122.79,77.82 R605.1
  BOTTOM w0.089: v2(124.28,78.25) 123.77,77.74 123.77,76.85 123.61,76.69 CPU1.E70
CFG5: length 4.9
  TOP w0.089: v2(125.45,78.27) 125.42,78.25 125.42,78.15 125.02,77.74 125.02,77.72 TP623.1
  BOTTOM w0.089: v2(125.45,78.27) 125.42,78.27 125.02,77.87 125.02,77.26 125.12,77.16 125.12,76.9 124.94,76.72 124.53,76.72 124.33,76.52 124.33,76.27 124.5,76.1 124.5,75.75 124.22,75.47 CPU1.C68
CFG6: length 3.2
  TOP w0.089: TP624.1 123.77,77.03 124.31,77.56 v2(124.31,77.61)
  BOTTOM w0.089: v2(124.31,77.61) 124.46,77.46 124.46,76.9 124.28,76.72 124.2,76.72 123.98,76.5 123.98,76.14 CPU1.D68
CFG7: length 1.5
  TOP w0.089: TP625.1 124.76,74.61 v2(125.41,75.25)
  BOTTOM w0.089: v2(125.41,75.25) 124.96,75.25 CPU1.C67
CFG8: length 5
  TOP w0.089: TP626.1 123.44,80.2 v2(124.18,80.2)
  BOTTOM w0.089: CPU1.F71 122.98,76.65 123.06,76.73 123.06,78.88 124.18,80 v2(124.18,80.2)
CFG9: length 5.7
  TOP w0.089: v2(121.66,80) 121.05,80.61 TP627.1
  BOTTOM w0.089: CPU1.G69 122.26,75.88 122.1,76.04 122.1,79.54 121.66,79.98 v2(121.66,80)
CFG10: length 5.4
  TOP w0.089: TP628.1 123.8,79.54 v2(124.31,79.54)
  BOTTOM w0.089: v2(124.31,79.54) 123.24,78.48 123.24,76.85 123.29,76.8 123.29,76.37 122.92,76 CPU1.F70
CFG11: length 7.7
  TOP w0.089: v2(124.15,80.84) TP629.1
  BOTTOM w0.089: CPU1.G68 122.26,75.11 122.65,75.51 122.65,76.66 122.81,76.81 122.81,79.16 123.42,79.77 123.42,80.1 v2(124.15,80.84)
CFG12: length 4.3
  TOP w0.089: v2(121.66,78.68) 122.25,79.26 TP630.1
  BOTTOM w0.089: CPU1.H70 121.49,76.25 121.49,76.43 121.44,76.61 121.44,76.79 121.47,76.9 121.47,77.17 121.44,77.24 121.44,77.31 121.26,77.49 121.26,78.25 121.66,78.66 v2(121.66,78.68)
CFG13: length 4.8
  TOP w0.089: TP631.1 121.87,80.97 v2(121.64,80.74)
  BOTTOM w0.089: CPU1.G71 122.36,79.48 122.39,79.51 122.39,79.94 121.64,80.69 v2(121.64,80.74)
CFG14: length 5.3
  TOP w0.089: TP632.1 121.36,79.34 v2(121.66,79.34)
  BOTTOM w0.089: CPU1.H69 121.31,75.78 121.31,76.4 121.26,76.59 121.26,76.82 121.29,76.93 121.29,77.13 121.26,77.2 121.26,77.24 121.03,77.46 121.03,78.71 v2(121.66,79.34)
CFG15: length 6.4
  TOP w0.089: TP633.1 121.64,82.03 v2(121.64,81.42)
  BOTTOM w0.089: CPU1.G70 122.36,76.61 122.63,76.88 122.63,79.26 122.86,79.49 122.86,80.2 v2(121.64,81.42)
CFG16: length 1.8
  TOP w0.089: v2(122.95,72.56) 123.49,72.03 TP634.1
  BOTTOM w0.089: v2(122.95,72.56) 122.95,72.29 123.21,72.03 CPU1.E63
CFG17: length 1.3
  TOP w0.089: v2(122.25,71.54) 122.63,71.92 TP635.1
  BOTTOM w0.089: v2(122.25,71.54) 122.6,71.9 CPU1.F63
CFG18: length 1.5
  TOP w0.089: v2(123.37,74.69) 123.37,74.92 TP636.1
  BOTTOM w0.089: v2(123.37,74.69) 123.25,74.58 CPU1.E66
CFG19: length 1.5
  TOP w0.089: v2(122.71,74.69) 122.71,75.28 TP637.1
  BOTTOM w0.089: CPU1.F66 122.6,74.59 v2(122.71,74.69)
CFG_RCOMP: length 0.6
  BOTTOM w0.356: v2(122.87,69.69) 123.19,70.01 CPU1.E60
  vias: v1(121.03,70.07)
CHARGER_SRC:
  vias: v1(142.92,48.99) v3(141.15,49.85) v3(141.15,48.96) v3(141.15,48.07) v3(142.16,49.85) v3(142.16,48.96) v3(142.16,48.07)
CHG_AMBER_LED#: length 96.2
  TOP w0.127: v1(116.48,14.9) v2(117.04,14.9) ; v2(179.47,46.91) 179.47,46.5 179.88,46.09 181.18,46.09 181.37,46.29 Q2416.3
  L4 w0.127: v2(117.04,14.9) 117.27,14.67 121.74,14.67 122.25,14.16 123.92,14.16 124.31,13.78 135,13.78 135.33,14.11 139.75,14.11 141.88,16.25 144.3,16.25 146.66,18.61 148.97,18.61 149.2,18.84 150.49,18.84 151.13,19.48 151.13,20.37 154.66,23.91 164.43,23.91 164.84,24.32 167.15,24.32 169.34,26.52 169.34,28.59 173,32.25 173,36.44 176.25,39.69 176.25,43.35 176.26,43.36 176.26,43.4 177.24,44.38 177.24,44.8 179.35,46.91 v2(179.47,46.91)
  BOTTOM w0.127: v2(117.04,14.9) 116.86,14.9 115.87,15.89 114.45,15.89 114.22,15.66 114.22,14.77 114.6,14.39 115.2,14.39 115.81,13.79 115.81,12.93 115.39,12.51 115.39,11.56 R6403.1
CHG_AMBER_LED_R#: length 2.5
  BOTTOM w0.305: v1(114.12,9.44) 114.16,9.44 R6403.2
  BOTTOM w0.508: Q6402.B 116.19,10.23 115.02,10.23 R6403.2
CLK_PCI_LPC: length 63.8
  TOP w0.089: v2(142.62,7.28) 141.66,8.24 133.18,8.24 v1(132.84,8.58) v2(132.31,9.11) ; EC1802.1 R1804.2 91.51,26.1 v2(90.96,25.54)
  L4 w0.127: v2(132.31,9.11) 131.37,10.05 131.37,10.11 129.34,12.13 128.93,12.13 127.8,13.26 123.38,13.26 122.99,13.66 122.02,13.66 121.56,14.11 121.54,14.11 121.49,14.16 116.14,14.16 114.46,15.85 108.19,15.85 107.63,16.41 102.35,16.41 102.12,16.18 101.74,16.18 101.62,16.3 99.85,16.3 98.43,17.72 97.31,17.72 95.7,19.33 95.7,19.46 94.88,20.27 94.55,20.27 92.68,22.14 92.68,22.33 92.33,22.68 92.33,24.25 91.03,25.54 v2(90.96,25.54)
  BOTTOM w0.089: v2(142.62,7.28) 142.61,7.28 142.61,5.79 DB1.9
CLK_PCI_LPC_MEC: length 137.8
  TOP w0.089: KBC24.57 187.61,45.28 v2(187.5,45.38) ; v1(90.6,28.52) 90.73,28.52 90.99,28.78 R1805.2 EC1801.1 92.44,28.78 93.09,28.13 93.09,27.78 93.37,27.5 v2(93.37,27.22)
  L4 w0.127: v2(177.88,52.88) 178.53,52.22 178.53,49.65 178.28,49.39 177.83,49.39 177.34,48.91 177.34,47.59 176.43,46.68 176.43,45.74 175.49,44.8 175.49,40.05 172.24,36.8 172.24,32.57 168.58,28.91 168.58,27.75 166.34,25.52 165.17,25.52 165,25.34 162.23,25.34 161.58,24.69 153.82,24.69 153.27,24.15 153.27,23.79 150.28,20.79 150.04,20.79 148.64,19.4 146.23,19.4 144.5,17.67 143.66,17.67 143.43,17.44 141.43,17.44 139.27,15.28 134.85,15.28 134.58,15.02 125.89,15.02 125.5,15.41 122.69,15.41 121.59,16.5 115.78,16.5 115.03,17.25 109.71,17.25 109.09,17.87 108.53,17.87 107.78,18.62 105.09,18.62 104.46,17.99 99.4,17.99 98.45,18.94 96.93,18.94 95.09,20.78 94.76,20.78 93.84,21.71 93.84,23.78 94.17,24.12 94.17,25.96 94.03,26.1 94.03,26.56 v2(93.37,27.22)
  L6 w0.102: v2(177.88,52.88) 177.99,52.88 179.86,51.02 179.86,50.54 182.93,47.46 182.93,46.85 183.64,46.14 184.22,46.14 184.35,46.02 184.67,46.02 184.78,45.98 185.37,45.38 v2(187.5,45.38)
CLK_PCIE_VGA: length 155.3
  L3 w0.14: v2(123.65,60.44) 123.39,60.19 123.39,59.55 123.52,59.43 123.87,59.43 124,59.55 124,59.86 124.13,59.99 124.38,59.99 126.17,58.2 127.73,58.2 128.26,57.67 128.26,56.73 125.32,53.8 125.32,51.55 125.78,51.1 126.46,51.1 126.9,50.66 129.96,50.66 131.05,49.57 131.05,48.17 131.88,47.34 134.82,47.34 137.26,44.9 137.26,43.98 136.37,43.1 136.37,39.61 135.66,38.9 135.66,34.26 137.69,32.23 137.69,32.05 138.17,31.58 138.17,30.4 138.9,29.66 139.34,29.66 140.13,28.87 140.74,28.87 141.44,28.17 146.12,28.17 147.36,26.94 149.22,26.94 149.82,27.54 153.02,27.54 154.38,26.18 164.31,26.18 165.53,27.4 165.53,29.48 166.25,30.21 166.25,31.58 166.58,31.91 166.78,31.91 167.51,32.63 167.51,36.75 168.48,37.72 168.48,43.84 168.6,43.96 168.6,55.57 167.73,56.44 167.73,92.97 169.26,94.5 174.09,94.5 174.88,93.72 175.57,93.72 175.84,93.44 v2(175.84,93.11)
  BOTTOM w0.102: GPU1.B8 176.05,92.9 v2(175.84,93.11) ; v2(123.65,60.44) 123.95,60.44 124.38,60.87 CPU1.C42
CLK_PCIE_VGA#: length 156
  TOP w0.102: v2(176.48,93.18) 176.48,93.49 v1(176.22,93.74)
  L3 w0.14: v2(122.91,60.54) 123.24,60.88 123.87,60.88 126.28,58.46 127.84,58.46 128.52,57.78 128.52,56.62 125.59,53.69 125.59,51.66 125.89,51.36 126.58,51.36 127.01,50.92 130.07,50.92 131.32,49.68 131.32,48.28 131.99,47.6 134.93,47.6 137.53,45.01 137.53,43.87 136.64,42.98 136.64,39.5 135.93,38.79 135.93,34.37 137.96,32.34 137.96,32.16 138.43,31.69 138.43,30.51 139.01,29.93 139.45,29.93 140.24,29.14 140.85,29.14 141.55,28.44 146.23,28.44 147.47,27.21 149.11,27.21 149.71,27.8 153.13,27.8 154.49,26.45 164.2,26.45 165.26,27.51 165.26,29.6 165.99,30.32 165.99,31.69 166.47,32.17 166.67,32.17 167.24,32.74 167.24,36.86 168.22,37.83 168.22,43.95 168.34,44.07 168.34,55.46 167.46,56.33 167.46,93.08 169.15,94.77 174.2,94.77 174.99,93.98 175.68,93.98 v2(176.48,93.18)
  BOTTOM w0.102: GPU1.B9 176.65,93.01 v2(176.48,93.18) ; v2(122.91,60.54) 123.19,60.54 123.51,60.87 CPU1.D42
CLK_TP_SIO: length 94.5
  TOP w0.089: KBC24.78 184.01,37.44 184.4,37.84 184.4,38.22 v2(184.4,38.22) ; v2(133.35,10.58) v1(133.91,10.58) ; RN6502.2 128.88,19.04 v2(128.22,19.7)
  L3 w0.127: v2(133.35,10.58) 133.27,10.58 132.83,10.14 131.61,10.14 127.46,14.3 127.46,18.94 v2(128.22,19.7)
  L4 w0.127: v2(184.4,38.22) 184.4,38.22 184.1,37.91 184.1,37.46 183.58,36.93 183.58,29.49 183.37,29.28 183.37,28.65 183.35,28.62 183.35,28.26 183.74,27.86 183.74,27.33 183.42,27.01 183.42,25.45 184.01,24.87 184.01,22.57 181.58,20.15 177.58,20.15 177.26,20.46 176.68,20.46 176.48,20.26 176.48,18.59 174.86,16.97 174.48,16.97 173.68,17.77 172.41,17.77 171.42,16.78 170.18,16.78 169.66,17.3 167.88,17.3 166.14,15.56 158.7,15.56 157.88,14.75 155.65,14.75 151.33,10.43 139.44,10.43 139.05,10.04 138.52,10.04 138.06,10.49 133.44,10.49 v2(133.35,10.58)
  BOTTOM w0.089: v2(128.22,19.7) 128.22,20.02 EC6501.1 128.56,20.55 129.43,21.42 RN6501.4
CLKREQ_PCIE#1: length 110.6
  TOP w0.102: v2(169.85,37.23) 168.55,37.23 167.51,36.19 167.51,35.48 168.07,34.92 168.07,33.95 167.41,33.29 167.41,32.58 166.8,31.97 166.43,31.97 166.13,31.67 164.04,31.67 160.86,28.49 v2(160.86,27.45) ; RN1813.7 95.93,38.67 96.51,39.25 101.23,39.25 102.11,40.12 v1(103.07,40.12) 105.21,40.12 105.5,39.83 106.01,39.83 106.2,40.02 106.97,40.02 v2(107.38,40.43)
  L4 w0.102: v2(107.38,40.43) 106.99,40.82 106.57,40.82 106.25,40.5 106.25,39.87 106.15,39.77 106.15,39.26 106.87,38.54 106.87,33.26 106.91,33.22 106.91,28.34 106.86,28.29 106.86,24.24 109.51,21.58 110.29,21.58 111.1,22.39 112.46,22.39 113.2,21.65 113.33,21.65 113.8,21.65 115.28,20.17 118.27,20.17 119.21,19.23 121.42,19.23 121.94,19.75 121.96,19.75 122.13,19.75 124.59,19.75 125.63,18.71 127.79,18.71 128.07,18.43 135.08,18.43 135.71,19.07 136.83,19.07 137.77,20.01 139.62,20.01 141.83,22.22 144.24,22.22 144.58,22.55 145.62,22.55 146.38,23.31 146.4,23.31 147.5,24.4 149.02,24.4 149.88,25.26 150.62,25.26 152.4,27.04 160.15,27.04 160.55,27.45 v2(160.86,27.45)
  BOTTOM w0.102: CPU1.AT7 107.05,40.11 v2(107.38,40.43) ; v2(169.85,37.23) 169.83,37.21 IOBD1.44
CLKREQ_PCIE#2: length 15.4
  TOP w0.102: RN1813.6 95.79,38.17 96.51,38.89 v1(97.25,38.89) 101.43,38.89 v2(102.13,38.19)
  L6 w0.102: v2(107.38,41.34) 107.31,41.34 106.81,40.83 105.13,40.83 104.16,39.87 104.16,39.36 103.05,38.24 102.18,38.24 v2(102.13,38.19)
  BOTTOM w0.102: v2(107.38,41.34) 107.05,41.02 CPU1.AT8
CLKREQ_PCIE#3: length 16.1
  TOP w0.102: RN1812.8 92.95,41.65 93.51,42.21 95.27,42.21 96.35,41.13 98.4,41.13 99.2,41.93 v1(103.17,41.93) 104.32,41.93 104.74,42.35 105.11,42.35 105.37,42.09 106.56,42.09 v2(106.73,42.26)
  BOTTOM w0.102: v2(106.73,42.26) 107.05,41.93 CPU1.AT10
CLKREQ_PCIE#4: length 15.1
  TOP w0.102: RN1812.6 94.1,41.75 94.19,41.83 95.08,41.83 96.5,40.4 v1(97.86,40.4) 100.23,40.4 101.15,41.33 102.12,41.33 102.6,40.85 106.24,40.85 v2(106.73,41.34)
  BOTTOM w0.102: CPU1.AU8 106.4,41.01 v2(106.73,41.34)
CLKREQ_PCIE#5: length 13.2
  TOP w0.102: v2(106.73,40.43) 106.2,40.43 106.01,40.62 102.25,40.62 101.14,39.51 96.29,39.51 96.1,39.32 v1(95.76,39.32) RN1813.8
  BOTTOM w0.102: CPU1.AU7 106.4,40.1 v2(106.73,40.43)
CLKREQ_PEG#0: length 183.4
  TOP w0.102: v2(107.38,42.26) 106.89,41.77 105.33,41.77 105.12,41.56 102.32,41.56 102.14,41.74 100.14,41.74 v1(99.53,41.13) 99.34,40.94 96.26,40.94 95.18,42.02 93.82,42.02 93.6,41.8 RN1812.7
  L4 w0.102: v2(107.38,42.26) 106.87,41.75 106.58,41.75 106.26,41.43 106.26,41.08 105.81,40.63 105.69,40.63 105.45,40.39 105.45,40.03 105.48,40 105.48,39.64 106.65,38.47 106.65,24.16 109.43,21.38 110.37,21.38 111.18,22.19 112.37,22.19 113.12,21.45 113.41,21.45 113.71,21.45 115.19,19.97 118.18,19.97 119.12,19.03 121.52,19.03 122.05,19.55 124.48,19.55 125.53,18.51 127.68,18.51 127.96,18.23 135.18,18.23 135.81,18.86 136.93,18.86 137.87,19.8 139.72,19.8 141.93,22.01 144.35,22.01 144.68,22.34 145.72,22.34 146.48,23.11 146.53,23.11 147.62,24.2 149.12,24.2 149.99,25.06 150.73,25.06 152.51,26.84 160.91,26.84 161.39,27.32 164.37,27.32 165.11,28.07 165.11,29.19 166.31,30.38 167.05,30.38 167.69,31.02 167.69,31.91 167.84,32.06 167.84,32.56 168.88,33.61 168.88,35.25 169.19,35.55 169.19,37.24 168.87,37.56 168.87,43.06 169.24,43.43 169.24,56.94 170.89,58.59 170.89,70.18 171.7,70.99 171.7,77.11 173.47,78.88 174.85,78.88 175.67,79.7 175.67,81.7 176.45,82.48 176.45,84.65 175.34,85.77 171.59,85.77 170.74,86.62 170.74,88.79 171.07,89.12 171.63,89.12 172.07,89.57 172.07,90.25 170.64,91.68 170.64,93.97 171.83,95.17 v2(171.83,95.24)
  BOTTOM w0.102: CPU1.AR10 107.7,41.93 v2(107.38,42.26) ; v2(171.83,95.24) 172.17,95.24 172.46,94.95 172.46,94.02 GPU1.A2
CLKRUN#: length 104.5
  TOP w0.102: v2(183.64,44.85) 183.92,45.13 185.07,45.13 185.21,44.99 KBC24.63 ; v1(110.51,24.83) 110.51,24.98 v2(110.18,25.32)
  L4 w0.102: v2(183.64,44.85) 183.33,44.85 180.41,47.77 v2(178.36,47.77) ; v2(110.18,25.32) 110.59,24.91 110.59,23.96 111.2,23.35 114.61,23.35 115.66,22.29 118.16,22.29 118.57,21.89 119.23,21.89 120.32,20.79 120.44,20.79 121.22,20.79 121.48,21.05 124.36,21.05 124.71,21.4 130.3,21.4 130.35,21.35 131.14,21.35 131.62,20.87 135.51,20.87 135.99,20.39 136.37,20.39 137.64,21.66 137.75,21.66 138.31,22.22 139.17,22.22 140.86,23.91 142.2,23.91 144.09,25.8 144.63,25.8 145.11,26.28 148.86,26.28 150.79,28.21 151.79,28.21 151.86,28.29 154.79,28.29 155.73,29.23 159.31,29.23 159.46,29.07 161.48,29.07 161.49,29.07 162.78,29.07 162.91,29.07 165.84,32 166.73,32 167.1,32.37 167.1,32.88 168.15,33.93 168.15,35.55 168.45,35.86 168.45,36.62 168.07,37 168.07,42.82 168.1,42.84 168.1,45.38 v2(167.66,45.81)
  L6 w0.102: v2(178.36,47.77) 174.55,47.77 173.28,46.5 171.75,46.5 170.58,45.33 168.15,45.33 v2(167.66,45.81)
  BOTTOM w0.102: R2510.1 184.31,43.31 183.67,43.96 183.67,44.82 v2(183.64,44.85) ; v2(110.18,25.32) 110.18,25.42 110.73,25.96 R1819.2
CLKRUN#_R: length 23.1
  L4 w0.127: v2(105.81,42.49) 105.81,41.93 105.21,41.32 105.21,39.97 105.28,39.89 105.28,39.56 104.47,38.75 104.47,34.94 106.22,33.19 v2(106.22,25.4)
  BOTTOM w0.089: v2(106.22,25.4) 106.32,25.3 v1(108.02,25.3) 108.99,25.3 R1818.1 109.84,26.15 R1819.1 ; CPU1.AW11 105.73,42.57 v2(105.81,42.49)
CMP_VIN0: length 5.3
  TOP w0.114: v2(199.95,37.41) 199.91,37.41 199.48,37.84 KBC24.20
  BOTTOM w0.114: v2(199.95,37.41) 200.23,37.41 200.48,37.66 200.48,38.85 200.12,39.21 200,39.21 199.37,39.84 R2470.2
CMP_VIN0_R: length 158.9
  L3 w0.102: v2(189.08,33.49) 189.46,33.49 192.81,30.14 192.81,29.35 193.05,29.11 194.83,29.11 196.04,27.91 196.04,18.99 194.97,17.92 192.85,17.92 190.09,15.16 190.09,14.88 188.48,13.27 188.48,11.38 187.89,10.8 v2(187.89,10.3) ; v2(123.37,34.76) 123.37,34.46 122.82,33.91 122.82,33.79 122.45,33.42 122.15,33.42 120.67,31.94 120.67,29.96 120.27,29.56 119.96,29.56 118.51,28.11 118.51,25.54 119.25,24.81 119.38,24.68 119.38,21.03 120.9,19.51 120.9,19.09 123.75,16.25 123.75,14.65 124.28,14.11 124.28,10.2 125.25,9.24 126.64,9.24 126.69,9.19 127.1,9.19 127.71,8.58 127.71,7.13 128.11,6.72 131.65,6.72 132.66,7.74 150.14,7.74 v2(150.57,7.31)
  L4 w0.114: v2(187.04,40) 187.04,38.27 187.45,37.86 187.45,36.57 187.83,36.19 187.83,34.74 v2(189.08,33.49)
  L6 w0.102: v2(195.71,42.38) 194.71,41.39 194.13,41.39 193.6,40.86 191.06,40.86 190.76,40.57 187.62,40.57 v2(187.04,40)
  BOTTOM w0.114: v2(123.37,34.76) 123.87,34.26 C2612.1 123.2,32.48 R2610.1 122.22,31.84 122.22,30.17 121.82,29.76 121.82,29.6 R2608.2 R2609.2 ; R2494.1 187.56,32.92 187.96,33.32 188.44,33.32 188.53,33.41 188.71,33.41 188.8,33.49 v2(189.08,33.49) ; v2(150.57,7.31) 184.15,7.31 v1(185.59,8.74) 185.95,8.74 187.51,10.3 v2(187.89,10.3) ; v2(195.71,42.38) 195.88,42.38 196.35,41.91 C2613.1 196.35,41.59 197.21,40.73 197.21,40.42 197.79,39.84 R2470.1
CMP_VOUT0: length 65.5
  TOP w0.114: v2(147.57,20.97) 147.57,20.87 v1(147.19,20.49) ; v2(184.4,34.46) 184.22,34.64 KBC24.85
  L6 w0.102: v2(147.57,20.97) 149.05,20.97 149.26,20.77 150.78,20.77 153.35,18.2 169.24,18.2 170.41,17.03 171.04,17.03 172.16,18.15 175.66,18.15 176.45,17.36 181.74,17.36 v2(183.28,18.91)
  BOTTOM w0.114: v2(147.57,20.97) 147.57,20.77 147.42,20.62 147.42,19.32 146.94,18.84 145.49,18.84 145.02,19.31 R2607.2 R2602.2 R2615.2 ; v2(183.28,18.91) 183.28,22.73 183.72,23.17 183.72,24.37 184.89,25.53 184.89,26.59 184.51,26.97 183.85,26.97 182.83,27.99 182.83,28.43 182.83,32.89 v2(184.4,34.46)
CMP_VOUT1: length 17.1
  TOP w0.089: KBC24.83 184.49,35.44 185.37,34.56 186.18,34.56 186.76,35.14 186.76,36.28 188.32,37.83 190.43,37.83 v2(190.85,37.41)
  BOTTOM w0.089: v2(190.85,37.41) 190.9,37.35 191.76,37.35 192.04,37.63 192.04,38.68 191.51,39.21 191.36,39.21 Q2408.G 190.5,40.99 R2417.1 189.67,41.39 R2418.1
CODEC_BITCLK_R: length 3
  TOP w0.089: HDA27.8 26.73,17.71 27.45,18.43 v1(27.54,18.43) 27.72,18.43 27.96,18.18 R2720.2
CODEC_SDOUT_R: length 3
  TOP w0.089: HDA27.11 26.79,18.91 v1(27.68,19.8) 27.84,19.96 R2719.2
COMBO-GPI: length 4.9
  TOP w0.102: TP2702.1 29.13,12.92 28.88,13.17 28.19,13.17 28.12,13.1 27.66,13.1 26.95,13.81 26.95,15.18 26.82,15.31 HDA27.2
CPU_A16_TP: length 2.7
  TOP w0.102: TP1902.1 101.22,40.25 v2(101.57,40.61)
  BOTTOM w0.102: v2(101.57,40.61) 101.93,40.61 102.61,41.29 103.13,41.29 103.13,41.29 CPU1.BB9
CPU_D1_TP: length 4.8
  TOP w0.102: v2(120.6,33.6) 119.84,33.6 TP1801.1
  BOTTOM w0.089: CPU1.M2 119.75,36.99 119.98,36.71 119.98,36.61 120.01,36.48 120.01,35.75
  BOTTOM w0.102: 120.01,35.75 119.89,35.63 119.89,34.15 120.45,33.6 v2(120.6,33.6)
CPU_D4_TP: length 5.1
  TOP w0.102: TP1804.1 116.89,33.04 v2(117.02,32.91)
  BOTTOM w0.102: v2(117.02,32.91) 116.27,33.65 116.27,35.78 116.41,35.91 116.41,36.69 CPU1.V1
CPU_D5_TP: length 4.9
  TOP w0.102: TP1805.1 117.19,33.54 v2(117.02,33.54)
  BOTTOM w0.102: v2(117.02,33.54) 116.47,34.09 116.47,35.67 116.7,35.9 116.7,37.06 116.44,37.32 CPU1.V2
CPU_D6_TP: length 5.2
  TOP w0.102: v2(120.55,32.96) 120.01,32.96 TP1806.1
  BOTTOM w0.102: v2(120.55,32.96) 120.34,33.16 120.14,33.16 119.66,33.65 119.66,36.3 CPU1.M1
CPU_DP1_CTRL_CLK: length 232.5
  TOP w0.089: v2(32.46,64.96) 32.46,64.91 30.73,63.19 26.72,63.19 v1(26.64,63.11) 26.26,63.11 25.54,62.39 24.14,62.39 23.65,62.87 U5701.38
  L3 w0.127: v2(127.18,57.01) 126.06,57.01 124.81,55.77 124.81,51.84 123.43,50.46 122.26,50.46 121.03,49.23 121.03,47.55 120.26,46.78 119.83,46.78 119.07,46.02 119.07,43.79 119.48,43.38 v2(119.48,43.34)
  L4 w0.127: v2(122.99,25.42) 122.99,25.47 124.53,27.02 124.53,31.16 121.97,33.72 121.97,36.34 124.51,38.88 124.51,41.49 123.69,42.31 120.5,42.31 v2(119.48,43.34)
  L6 w0.102: v2(32.46,64.96) 32.31,64.96 31.7,65.57 31.7,66.95 33.04,68.29 33.04,70.7 37.01,74.67 37.01,84.45 39.22,86.66 39.22,92.16 40.47,93.41 41.5,93.41 42.42,94.33 42.42,95.29 42.87,95.75 43.1,95.75 46.05,98.69 46.05,98.77 47.01,99.74 47.34,99.74 47.72,100.12 47.72,100.78 48.25,101.3 74.59,101.3 75.49,100.4 76.17,100.4 78.54,102.76 87.11,102.76 88.07,103.72 92.12,103.72 95.12,100.73 101.7,100.73 102.03,101.06 103.58,101.06 103.83,100.8 121.19,100.8 130.27,91.73 130.69,91.3 131.71,91.3 136,87.01 136,74.99 133.93,72.92 133.93,72.74 133.42,72.23 133.42,65.45 130.4,62.42 129.61,62.42 129.18,61.99 129.18,60.47 129.79,59.86 129.79,59.22 127.58,57.01 v2(127.18,57.01)
  BOTTOM w0.089: RN801.3 121.72,25.28 121.99,25.01 122.6,25.01 122.93,25.34 122.93,25.37 v2(122.99,25.42) ; CPU1.L13 119.81,43.68 v2(119.48,43.34)
CPU_DP1_CTRL_DATA: length 230.1
  TOP w0.089: U5701.39 24.05,62.88 24.28,62.66 25.4,62.66 26.21,63.47 30.58,63.47 31.16,64.04 v1(31.16,64.11) 31.17,64.11 32.03,64.96 32.03,65.22 32.28,65.47 v2(32.28,65.6)
  L3 w0.127: v2(119.47,42.69) 119.04,43.12 119.04,43.49 118.85,43.67 118.85,46.11 119.75,47.01 120.18,47.01 120.8,47.63 120.8,49.31 122.17,50.68 123.34,50.68 124.59,51.92 124.59,55.85 125.97,57.23 126.48,57.23 v2(126.82,57.57)
  L4 w0.127: v2(119.47,42.69) 120.11,42.04 123.56,42.04 124.29,41.3 124.29,39.04 121.74,36.49 121.74,33.39 124.15,30.98 124.15,27.23 123.03,26.1 v2(122.98,26.1)
  L6 w0.102: v2(126.82,57.57) 127.71,57.57 129.49,59.35 129.49,59.71 128.88,60.32 128.88,62.12 129.49,62.73 130.27,62.73 133.02,65.47 133.02,72.25 133.6,72.84 133.6,73.04 135.7,75.14 135.7,86.89 131.58,91 130.57,91 129.06,92.5 121.07,100.5 103.71,100.5 103.45,100.75 102.16,100.75 101.83,100.42 94.87,100.42 91.9,103.39 88.17,103.39 87.15,102.37 78.62,102.37 76.35,100.09 75.36,100.09 74.57,100.88 70.08,100.88 69.29,100.09 67.66,100.09 66.76,100.99 48.4,100.99 48.08,100.68 48.08,100.04 47.47,99.43 47.16,99.43 46.35,98.63 46.35,98.57 43.23,95.44 43,95.44 42.72,95.17 42.72,94.2 41.63,93.11 40.6,93.11 39.55,92.06 39.55,86.56 37.31,84.32 37.31,74.54 33.35,70.58 33.35,68.16 33.13,67.95 33.13,67.81 33.43,67.51 33.43,67.33 33.25,67.15 33.07,67.15 32.77,67.45 32.63,67.45 32,66.82 32,65.88 v2(32.28,65.6)
  BOTTOM w0.089: v2(119.47,42.69) 119.8,43.03 CPU1.L12 ; RN801.4 122.37,25.64 122.71,25.98 122.85,25.98 v2(122.98,26.1)
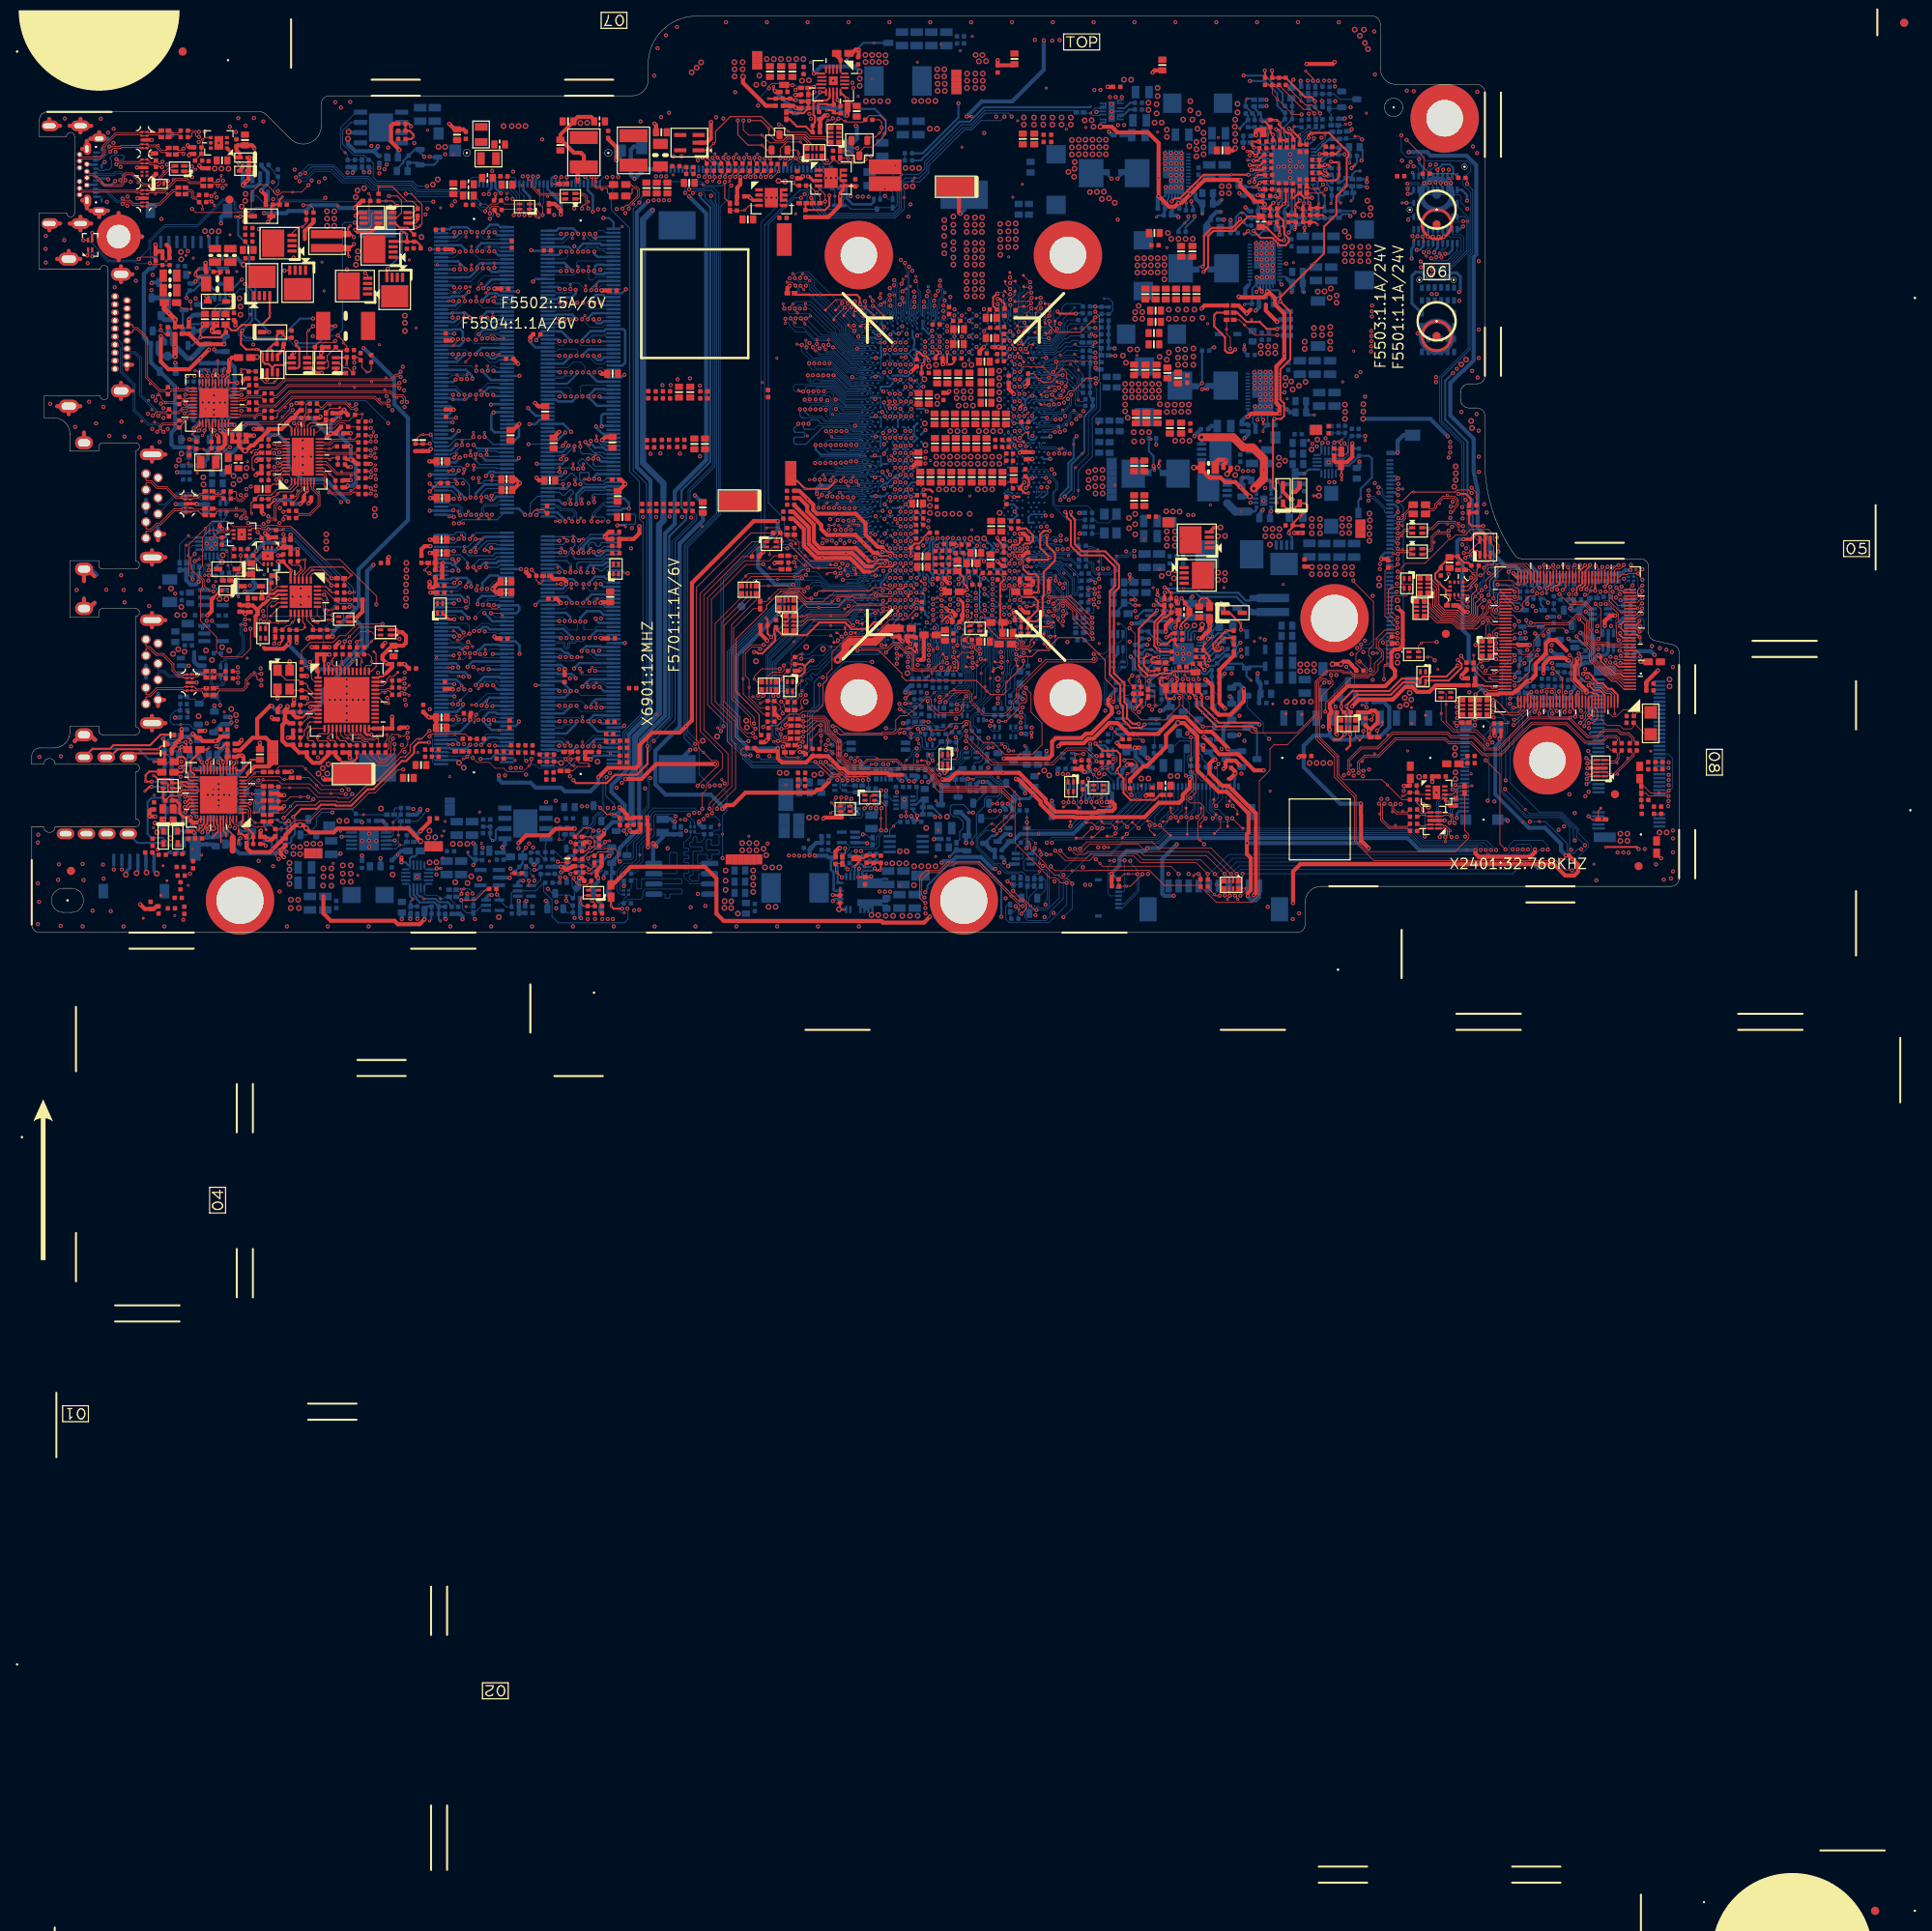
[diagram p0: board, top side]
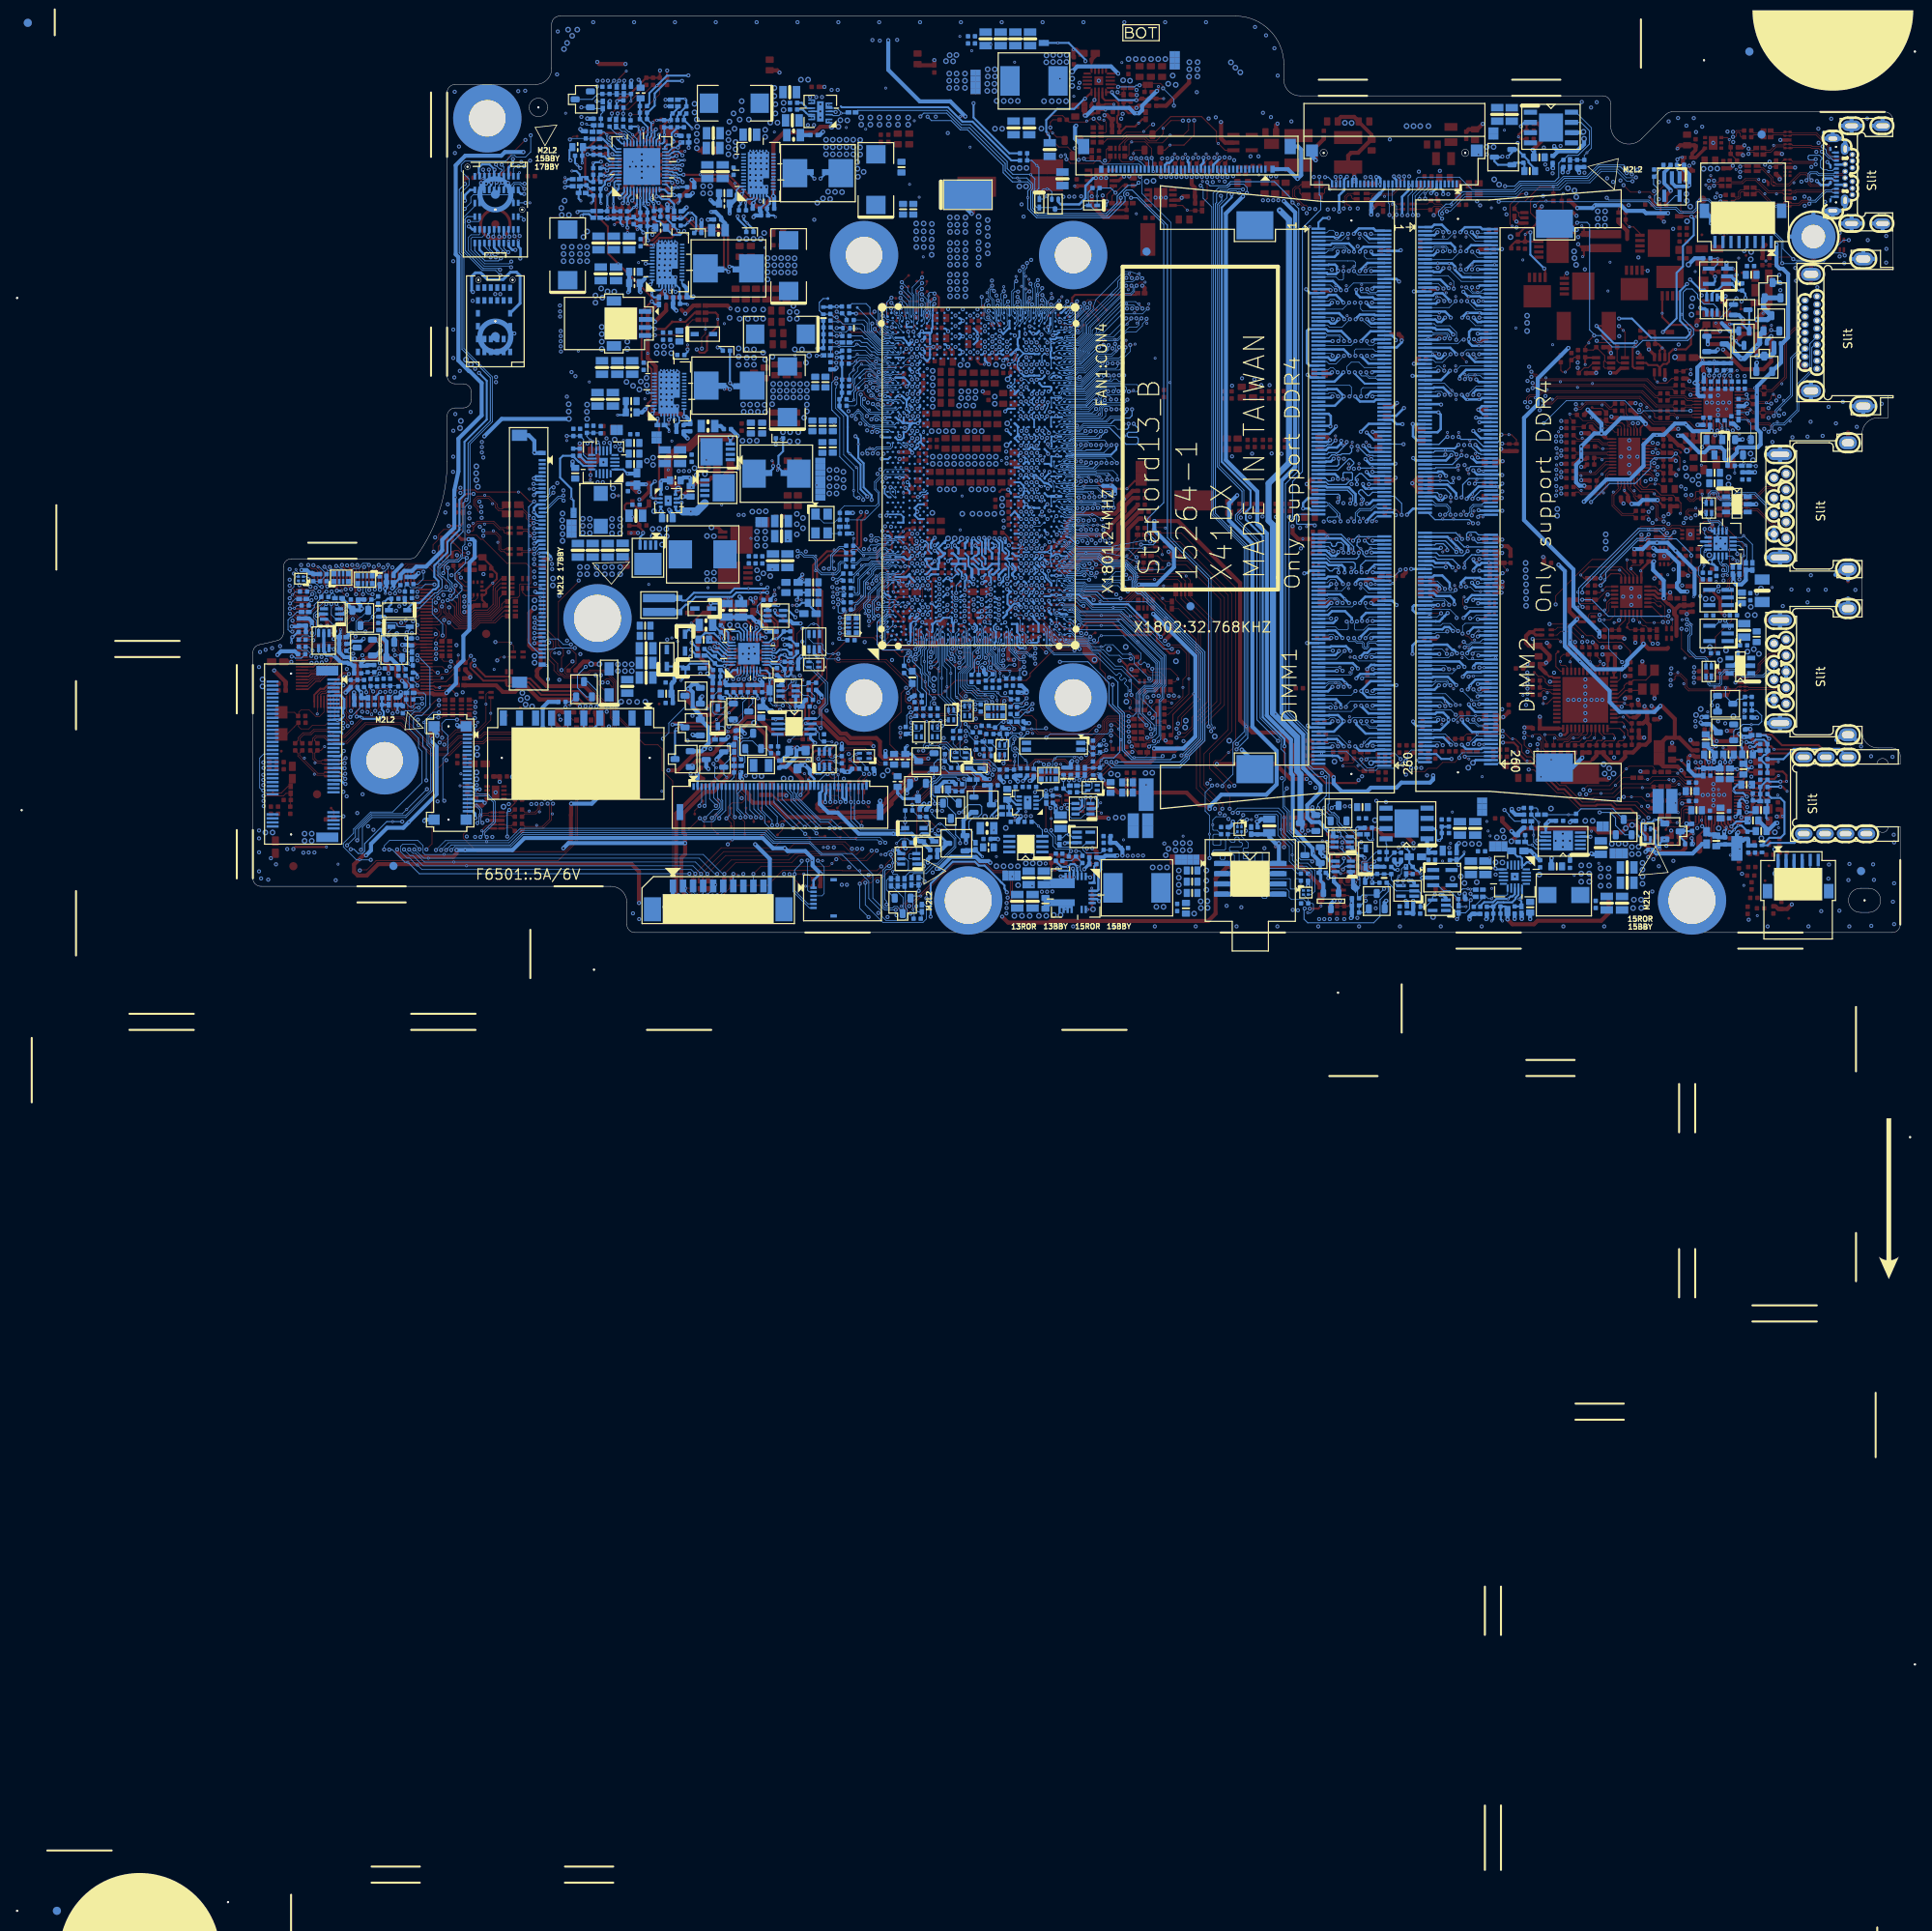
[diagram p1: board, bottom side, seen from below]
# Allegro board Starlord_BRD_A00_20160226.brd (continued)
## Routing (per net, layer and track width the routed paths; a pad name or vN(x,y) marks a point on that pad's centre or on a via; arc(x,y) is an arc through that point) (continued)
CPU_DP1_HPD: length 184.2
  TOP w0.102: v2(123.62,30.42) 123.62,30.37 124.26,29.73 124.26,27.4 125.63,26.03 125.63,23.36 124.4,22.14 120.98,22.14 119.56,23.56 118.36,23.56 116.69,25.24 116.69,26.13 116.46,26.36 116.03,26.36 115.7,26.03 115.69,26.03 115.64,25.98 114.32,25.98 113.52,25.18 v1(111.82,25.18) 111.22,25.77 109.83,25.77 109.42,25.37 108,25.37 107.29,24.65 105.84,24.65 105.74,24.55 100.51,24.55 v2(99.95,25.11) ; U5701.3 26.06,64.84 v2(26.08,64.86)
  L3 w0.102: v2(44.32,63.31) 45.46,62.17 45.46,40.94 43.1,38.57 43.1,33.49 44.25,32.35 44.25,30.14 43.56,29.46 43.56,23.44 46.01,20.99 47.53,20.99 48.61,19.9 51.59,19.9 53.95,17.54 62.61,17.54 62.79,17.36 77.14,17.36 78.71,18.94 81.53,18.94 82.22,19.63 86.59,19.63 87.6,18.61 90.78,18.61 90.97,18.42 95.08,18.42 97.15,20.49 99.25,20.49 99.67,20.91 99.67,24.83 v2(99.95,25.11)
  L4 w0.102: v2(123.62,30.42) 121.46,32.58 121.46,36.5 123.59,38.63 123.59,40.1 123.33,40.37 123.33,41.5 122.99,41.84 121.42,41.84 120.97,41.38 v2(119.47,41.38)
  BOTTOM w0.102: v2(44.32,63.31) 41.53,66.11 34.24,66.11 32.66,64.53 32.26,64.53 31.93,64.86 v2(26.08,64.86) ; CPU1.L9 119.63,41.38 v2(119.47,41.38)
CPU_DP2_CTRL_CLK: length 17.9
  TOP w0.089: v1(119.73,25.68) 119.72,25.7 v2(119.15,25.7)
  L4 w0.127: v2(118.51,40.07) 118.51,38.32 118.69,38.14 118.69,26.15 v2(119.15,25.7)
  BOTTOM w0.089: RN803.4 120.36,25.18 120.21,25.03 119.46,25.03 119.15,25.35 v2(119.15,25.7) ; CPU1.N7 118.81,39.77 v2(118.51,40.07)
CPU_DP2_CTRL_DATA: length 17
  TOP w0.089: v2(119.33,26.31) 118.79,26.31 v1(118.73,26.37)
  L4 w0.127: v2(118.47,40.73) 118.47,40.7 119.05,40.12 119.05,39.66 119,39.61 119,38.42 119.07,38.35 119.07,26.56 v2(119.33,26.31)
  BOTTOM w0.089: CPU1.N8 118.78,40.43 v2(118.47,40.73) ; RN803.3 119.71,25.82 119.33,26.2 v2(119.33,26.31)
CPU_DP2_HPD: length 23.1
  TOP w0.102: v1(122.5,26.89) 122.55,26.89 v2(123.04,27.37)
  L4 w0.127: v2(123.04,27.37) 122.99,27.37 122.76,27.6 122.76,28.7 121.21,30.25 121.21,36.85 123.34,38.98 123.34,39.82 123.16,40 122.72,40 121.83,40.89 120.24,40.89 v2(119.46,40.1)
  BOTTOM w0.127: v2(119.46,40.1) 119.78,39.77 CPU1.L7 ; R804.1 122.41,27.82 122.86,27.37 v2(123.04,27.37) 123.16,27.37 123.54,26.99 123.54,25.68 R803.2
CPU_DP_HPD_MUX: length 5.6
  TOP w0.102: U3701.23 36.51,42.5 37.64,41.37 R3706.2 37.96,41.16 38.21,40.91 39.67,40.91 40.05,40.53 v1(40.05,40.45)
CPU_DP_HPD_R: length 174.8
  TOP w0.127: R3706.1 v2(39.55,41.37) R3717.2 ; R3846.2 28.01,59.63 v2(27.91,59.53) 27.89,59.53 27.4,59.05 27.4,57.7 v1(27.56,57.55)
  L3 w0.127: v2(108.1,14.47) 107.97,14.47 107.12,13.62 100.97,13.62 100.23,12.88 95.31,12.88 94.37,13.82 88.99,13.82 88.49,13.33 86.49,13.33 80.55,7.4 67.65,7.4 65.45,9.59 61.78,9.59 60.98,10.39 60.98,11.29 59.15,13.12 52.09,13.12 50.87,14.34 50.85,14.34 50.56,14.63 46.58,14.63 46.56,14.66 45.73,15.49 44.78,15.49 43.91,16.35 38.89,16.35 38.15,17.09 38.15,18.05 39.04,18.94 39.04,24.35 35.74,27.65 35.74,36.16 34.9,37 34.46,37 33.93,37.53 29.32,37.53 28.43,38.42 28.43,38.94 v2(28.83,39.34) ; v2(39.55,41.37) 38.81,42.1 38.81,42.54 39.8,43.53 39.8,51.55 38.45,52.9 v2(38.45,53.51)
  L6 w0.127: v2(108.1,14.47) 108.63,13.94 110.59,13.94 111.71,15.05 114.48,15.05 115.85,16.43 116.59,16.43 119.42,19.25 119.42,22.6 119.52,22.7 119.52,23.5 122.76,26.74 v2(123.04,26.74)
  BOTTOM w0.127: v2(123.04,26.74) 122.57,26.74 R804.2 ; v2(39.55,41.37) 38.35,41.37 36.29,39.31 28.9,39.31 28.87,39.34 v2(28.83,39.34) ; v2(38.45,53.51) 36.14,55.82 32.97,55.82 31.05,57.74 31.05,58.54 30.6,59 28.45,59 v2(27.91,59.53)
CPU_POPIRCOMP: length 18
  TOP w0.203: 104.21,44.85 104.7,44.85 105.31,45.46 106.92,45.46 v2(107.38,45.92)
  TOP w0.508: R412.1 94.69,51.45 96.01,50.13 96.01,48.07 97.53,46.55 v1(98.3,46.55) 101.78,46.55 103.48,44.85 104.21,44.85
  BOTTOM w0.305: v2(107.38,45.92) 107.38,45.78 CPU1.AT16
CPU_RXN_C_DGPU_TXN0: length 161.1
  TOP w0.102: v1(173.07,85.92) 173.07,86.38 v2(172.95,86.5)
  L3 w0.14: v2(121.56,44.03) 121.61,44.03 122.03,43.62 123.65,43.62 124.89,42.38 124.89,37.53 125.36,37.06 125.36,35.29 125.88,34.77 125.88,33.54 124.1,31.77 124.1,28.77 124.38,28.49 124.38,26.46 126.69,24.15 129.59,24.15 131.29,22.44 132.56,22.44 132.86,22.15 132.86,20.93 133.86,19.93 133.86,19.77 134.52,19.1 135.44,19.1 137.49,17.06 137.49,13.79 139.32,11.95 164.74,11.95 165.25,12.46 170.36,12.46 172.4,14.51 172.4,18.62 171.59,19.43 171.59,25.53 174.05,28 174.05,31.24 173.7,31.6 173.7,33.73 174.23,34.26 174.23,62.13 173.39,62.97 173.39,71.25 176.97,74.83 176.97,76.96 175.45,78.49 175.45,80.27 175.7,80.52 175.7,81.7 176.97,82.96 176.97,84.33 176.01,85.29 173.45,85.29 172.99,85.76 172.95,85.8 v2(172.95,86.5)
  BOTTOM w0.102: GPU1.E3 173.05,86.61 v2(172.95,86.5) ; CPU1.H13 121.24,43.76 121.52,44.03 v2(121.56,44.03)
CPU_RXN_C_DGPU_TXN1: length 166.1
  TOP w0.102: v2(121.57,43.17) 121.01,42.61 v1(120.85,42.61)
  L3 w0.14: v2(174.95,86.5) 174.95,86.48 175.41,86.02 176.66,86.02 177.84,84.84 177.84,80.62 176.66,79.44 176.66,78.42 177.71,77.37 177.71,74.4 174.12,70.81 174.12,63.36 174.94,62.54 174.94,36.91 175.42,36.42 175.42,35.31 175.26,35.14 175.26,33.32 174.84,32.9 174.84,27.49 172.35,25 172.35,20.85 173.49,19.71 173.49,17.02 174.56,15.95 174.56,15.32 173.9,14.66 173.67,14.66 170.76,11.75 165.56,11.75 164.96,11.15 154.39,11.15 153,9.76 137.65,9.76 135.27,12.15 135.27,13.6 134.96,13.9 134.96,16.74 134.12,17.58 131.89,17.58 130.19,19.28 130.19,20.29 128.91,21.57 125.06,21.57 122.26,24.36 122.26,28.88 122.52,29.14 122.52,31.2 124.57,33.25 124.57,36.63 124.13,37.07 124.13,40.8 122.9,42.04 121.91,42.04 121.54,42.41 121.54,43.14 v2(121.57,43.17)
  BOTTOM w0.102: v2(174.95,86.5) 174.86,86.6 174.86,87.4 GPU1.E6 ; CPU1.G11 121.89,42.85 v2(121.57,43.17)
CPU_RXN_C_DGPU_TXN2: length 151.6
  TOP w0.102: v2(121.56,45.86) 121.56,46.09 v1(121.84,46.37)
  L3 w0.14: v2(173.73,84.55) 173.56,84.38 173.56,80.57 171.82,78.82 171.82,62.31 172.27,61.85 172.43,61.7 172.43,58.21 172.62,58.01 172.81,57.83 172.81,34.85 172.08,34.13 172.08,30.98 172.48,30.58 172.48,28.68 170.17,26.37 170.17,18.89 169.89,18.61 169.89,17.5 170.95,16.44 170.95,15.67 169.21,13.94 151.31,13.94 150.26,14.99 143.85,14.99 139.06,19.78 138.2,19.78 136.04,21.94 135.56,21.94 134.28,23.21 134.28,23.24 131.83,25.7 127.27,25.7 125.8,27.16 125.8,29.09 125.6,29.29 125.6,31.24 127.94,33.58 127.94,33.6 128.01,33.67 128.01,37.79 128.69,38.46 128.69,43.23 127.07,44.85 122.96,44.85 122.38,45.43 122.05,45.43 121.61,45.86 v2(121.56,45.86)
  BOTTOM w0.102: v2(173.73,84.55) 173.73,84.76 174.25,85.28 GPU1.F5 ; v2(121.56,45.86) 121.24,45.54 CPU1.H16
CPU_RXN_C_DGPU_TXN3: length 154.7
  TOP w0.102: v2(175.28,83.94) 175.28,84.19 v1(175.03,84.45)
  L3 w0.14: v2(121.59,44.97) 122.1,44.47 122.35,44.47 122.46,44.35 124.56,44.35 125.63,43.29 125.63,37.84 126.24,37.23 126.92,37.23 127.23,36.92 127.23,33.87 124.89,31.54 124.89,29 125.09,28.79 125.09,26.86 127.02,24.93 131.58,24.93 133.6,22.92 133.6,21.19 134.38,20.41 135.2,20.41 137.74,17.87 138.53,17.87 139.47,16.93 139.47,14.88 141.54,12.81 164.58,12.81 164.95,13.17 170.05,13.17 171.66,14.79 171.66,18.29 170.88,19.08 170.88,25.94 173.26,28.33 173.26,30.81 172.96,31.12 172.96,34 173.52,34.56 173.52,58.13 173.21,58.43 173.21,62.03 172.6,62.64 172.6,71.54 173.1,72.04 173.1,74.74 172.6,75.24 172.6,78.53 174.87,80.8 174.87,81.89 175.28,82.3 v2(175.28,83.94)
  BOTTOM w0.102: v2(175.28,83.94) 175.29,83.95 175.29,84.54 176.05,85.3 GPU1.F8 ; CPU1.G15 121.59,44.85 v2(121.59,44.97)
CPU_RXP_C_DGPU_TXP0: length 161.2
  TOP w0.102: v1(171.85,86.05) 171.85,86.1 v2(172.31,86.55)
  L3 w0.14: v2(172.31,86.55) 172.41,86.45 172.41,86.26 172.29,86.13 172.03,86.13 171.91,86 171.91,85.7 172.03,85.57 172.8,85.57 173.34,85.02 173.57,85.02 175.9,85.02 176.71,84.22 176.71,83.07 175.44,81.81 175.44,80.63 175.18,80.38 175.18,78.38 176.71,76.85 176.71,74.94 173.12,71.36 173.12,62.86 173.96,62.02 173.96,34.37 173.43,33.84 173.43,31.49 173.79,31.13 173.79,28.11 171.32,25.65 171.32,19.32 172.13,18.51 172.13,14.62 170.25,12.73 165.14,12.73 164.63,12.22 139.43,12.22 137.76,13.9 137.76,17.17 137.41,17.51 135.55,19.37 134.63,19.37 134.12,19.88 134.12,20.04 133.13,21.04 133.13,22.26 132.67,22.71 131.4,22.71 129.7,24.41 126.8,24.41 124.65,26.57 124.65,28.6 124.37,28.88 124.37,31.66 126.15,33.43 126.15,34.88 125.63,35.4 125.63,37.17 125.16,37.64 125.16,42.49 123.76,43.89 122.34,43.89 v2(122.2,44.03)
  BOTTOM w0.102: CPU1.G13 121.89,43.78 122.15,44.03 v2(122.2,44.03) ; v2(172.31,86.55) 172.45,86.7 GPU1.E2
CPU_RXP_C_DGPU_TXP1: length 167.4
  TOP w0.102: v1(121.61,41.27) 121.61,42.66 122.12,43.17 v2(122.22,43.17)
  L3 w0.14: v2(122.22,43.17) 121.8,42.76 121.8,42.52 122.02,42.31 123.01,42.31 124.4,40.91 124.4,37.18 124.84,36.74 124.84,33.14 122.78,31.08 122.78,29.03 122.53,28.77 122.53,24.47 125.17,21.84 129.02,21.84 130.45,20.41 130.45,19.39 132,17.85 134.23,17.85 135.23,16.85 135.23,14.01 135.53,13.71 135.53,12.26 137.76,10.03 152.89,10.03 154.28,11.42 164.85,11.42 165.44,12.02 170.65,12.02 173.56,14.93 173.79,14.93 174.29,15.43 174.29,15.84 173.23,16.91 173.23,19.6 172.08,20.74 172.08,25.11 174.57,27.6 174.57,33.01 174.99,33.43 174.99,35.25 175.16,35.42 175.16,36.31 174.67,36.8 174.67,62.43 173.85,63.25 173.85,70.92 177.44,74.51 177.44,77.26 176.39,78.31 176.39,79.55 177.57,80.73 177.57,84.73 176.54,85.75 174.69,85.75 174.22,86.22 v2(174.22,86.5)
  BOTTOM w0.102: GPU1.E5 174.26,87.4 174.26,86.55 v2(174.22,86.5) ; v2(122.22,43.17) 122.17,43.13 122.17,42.85 122.35,42.66 122.49,42.66 CPU1.F11
CPU_RXP_C_DGPU_TXP2: length 151.6
  TOP w0.102: v1(173.43,84.07) 173.1,84.4 v2(173.1,84.57)
  L3 w0.14: v2(122.22,45.86) 122.32,45.86 123.07,45.12 127.18,45.12 128.95,43.35 128.95,38.35 128.28,37.68 128.28,33.55 125.87,31.13 125.87,29.4 126.07,29.2 126.07,27.27 127.38,25.96 131.94,25.96 134.55,23.35 134.55,23.32 135.67,22.2 136.15,22.2 138.31,20.04 139.17,20.04 143.96,15.26 150.37,15.26 151.42,14.2 169.1,14.2 170.68,15.78 170.68,16.33 169.62,17.39 169.62,18.72 169.9,19 169.9,26.48 172.21,28.79 172.21,30.47 171.97,30.71 171.82,30.86 171.82,34.24 172.54,34.96 172.54,57.72 172.36,57.9 172.16,58.1 172.16,61.59 171.55,62.2 171.55,78.93 173.3,80.68 173.3,83.81 173.17,83.94 172.59,83.94 172.46,84.07 172.46,84.45 172.59,84.57 v2(173.1,84.57)
  BOTTOM w0.102: GPU1.F4 173.65,85.08 173.15,84.57 v2(173.1,84.57) ; CPU1.G16 121.89,45.51 122.22,45.84 v2(122.22,45.86)
CPU_RXP_C_DGPU_TXP3: length 154.6
  TOP w0.102: v1(122.78,44.92) 122.25,44.92 v2(122.22,44.95)
  L3 w0.14: v2(174.65,83.94) 174.67,83.94 174.8,83.81 174.8,83.49 174.67,83.36 174.37,83.36 174.24,83.23 174.24,82.97 174.37,82.85 174.89,82.85 175.02,82.72 175.02,82.41 174.61,82 174.61,80.91 172.34,78.64 172.34,75.13 172.83,74.63 172.83,72.15 172.34,71.65 172.34,62.53 172.95,61.92 172.95,58.32 173.25,58.02 173.25,34.67 172.69,34.11 172.69,31 173,30.7 173,28.44 170.61,26.05 170.61,18.97 171.4,18.18 171.4,14.9 169.94,13.44 164.84,13.44 164.47,13.07 141.65,13.07 139.74,14.99 139.74,17.04 138.64,18.14 137.85,18.14 135.31,20.68 134.49,20.68 133.87,21.3 133.87,23.03 131.69,25.2 127.13,25.2 125.36,26.98 125.36,28.91 125.16,29.11 125.16,31.43 127.49,33.76 127.49,37.03 127.03,37.49 126.35,37.49 125.89,37.95 125.89,43.4 124.67,44.62 122.6,44.62 122.27,44.95 v2(122.22,44.95)
  BOTTOM w0.102: v2(122.22,44.95) 122.28,44.95 122.54,44.69 CPU1.F15 ; v2(174.65,83.94) 174.72,83.94 174.85,84.07 174.85,84.12 175.06,84.33 175.06,84.63 175.45,85.02 GPU1.F7
CPVDD: length 4.9
  TOP w0.203: HDA27.21 22.24,21.01 v2(22.4,21.17)
  BOTTOM w0.254: R2724.2 v1(25.4,20.4)
  BOTTOM w0.508: v2(22.4,21.17) 22.4,20.44 C2724.1 22.46,20.4 C2701.1 R2724.2
CPVEE: length 1.8
  TOP w0.203: v2(20.27,20.31) 20.44,20.14 HDA27.24
  BOTTOM w0.305: v2(20.27,20.31) 20.34,20.39 C2704.2
CSI2_COMP: length 2.9
  TOP w0.508: R1501.1 124.18,43.98 124.51,43.65 v1(124.51,43.32) 124.35,43.16 v2(123.52,43.16)
  BOTTOM w0.254: CPU1.E13 123.19,43.52 123.52,43.19 v2(123.52,43.16)
CTL1: length 3.9
  BOTTOM w0.102: U3401.6 19.99,48.1 19.45,47.57 v1(19.45,46.85) 19.68,46.63 19.68,45.77 R3401.2
CTL2: length 4.1
  BOTTOM w0.102: U3401.7 19.68,48.6 v1(19.23,48.15) 19.07,48 19.07,46.47 19.2,46.35 R3406.2
CTL3: length 5.3
  BOTTOM w0.102: R3402.2 18.39,48.25 v1(19.48,49.34) 19.72,49.1 U3401.8
DAT_TP_SIO: length 93.4
  TOP w0.089: v2(185.09,37.2) 184.33,37.2 184.16,37.04 184.16,37.04 KBC24.79 ; v2(128.85,19.7) 128.93,19.7 129.53,19.1 RN6502.1
  L3 w0.127: v2(128.85,19.7) 127.85,18.7 127.85,15.35 v2(132.61,10.58)
  L4 w0.127: v2(185.09,37.2) 184.38,37.2 183.96,36.78 183.96,29.6 184.28,29.28 184.28,28.53 184.67,28.14 184.67,27.72 183.81,26.85 183.81,25.61 184.39,25.02 184.39,22.42 180.35,18.38 178.76,18.38 177.7,17.31 175.77,17.31 175.04,16.59 174.31,16.59 173.59,17.3 172.5,17.3 170.38,15.18 158.88,15.18 158.06,14.37 155.83,14.37 151.51,10.05 139.67,10.05 139.28,9.66 138.34,9.66 137.88,10.11 133.08,10.11 v2(132.61,10.58)
  BOTTOM w0.089: v2(128.85,19.7) 128.85,19.77 EC6502.1 130.63,21.54 v1(130.63,21.56) 129.9,22.29 RN6501.3
DBC_EN_R: length 8.9
  TOP w0.102: R5503.1 101.41,96.3 v2(101.52,96.18)
  BOTTOM w0.102: LCD1.32 94.45,95.33 94.64,95.52 99.08,95.52 99.47,95.91 101.25,95.91 v2(101.52,96.18)
DBC_PANEL_EN: length 157.4
  TOP w0.102: v2(102.16,96.05) 102.16,96.66 101.64,97.18 R5503.2
  L3 w0.102: v2(84.3,18.2) 84.68,17.82 86.97,17.82 87.09,17.7 89.94,17.7 90.1,17.53 98.34,17.53 99.54,18.74 99.54,19.23 100.56,20.24 100.56,24.13 102.2,25.77 104.1,25.77 106.45,28.13 106.45,31.51 108.01,33.07 108.01,34.85 v2(107.54,35.32)
  L4 w0.102: v2(86.99,92.85) 87.63,93.49 92.1,93.49 93.19,94.58 96.44,94.58 96.82,94.96 101.06,94.96 v2(102.16,96.05) ; v2(107.54,35.32) 108.01,34.85 108.01,33.31 107.31,32.61 107.31,28.17 107.26,28.12 107.26,24.43 108.71,22.98 109.95,22.98 v2(110.06,22.88)
  BOTTOM w0.102: v2(86.99,92.85) 86.69,92.55 86.69,91.28 85.61,90.2 85.61,51.93 81.58,47.91 81.58,24.96 82.68,23.87 82.98,23.56 82.98,19.68 84.3,18.36 v2(84.3,18.2) ; v2(107.54,35.32) 107.94,35.72 108.37,35.72 108.76,36.11 108.76,37.08 109.06,37.38 109.25,37.38 109.44,37.57 109.44,38.84 CPU1.AM5 ; v2(110.06,22.88) 109.8,22.88 109.47,22.55 109.47,22.11 v1(108.78,21.42) 108.56,21.2 R2043.2
DC_IN_OK: length 290.6
  TOP w0.254: PQ4308.2 29.92,70.22 ; 29.92,70.22 29.46,70.68 29.03,70.68 28.75,70.96 28.75,71.97 28.24,72.48 v1(27.94,72.48) 26.66,72.48 26.02,73.12 26.02,74.68 v2(26.19,74.85) ; 29.92,70.22 30.24,70.54 31.33,70.54 31.6,70.81 PQ4310.5 ; R2475.1 178.92,53.29 178.92,53.92 178.31,54.53 v2(177.42,54.53) ; v2(29.39,88.36) 29.79,88.76 PD4305.A 29.79,90.3 PR4315.2 PR4311.2 30.82,91.09 v1(31.16,91.43)
  L3 w0.254: v2(26.52,80.61) 26.39,80.48 20.85,80.48 v2(19.25,78.88) ; v2(34.8,93.49) 34.92,93.36 34.92,92.69 34.29,92.06 34.29,86.99 35.84,85.44 35.84,77.18 v2(34.97,76.32)
  L4 w0.254: v2(124.74,110.96) 126.26,112.49 162.25,112.49 166.29,108.44 166.29,105.91 167.97,104.23 170.23,104.23 171.07,103.39 171.07,101.21 174.47,97.81 174.49,97.81 174.91,97.81 174.91,97.81 175.11,97.81 176.63,96.28 178.76,96.28 179.17,95.88 179.17,94.4 179.7,93.87 179.7,88.92 179.37,88.59 179.37,83.03 179.6,82.8 179.6,76.62 179.37,76.39 179.37,71.16 175.56,67.35 175.56,55.31 176.35,54.53 v2(177.42,54.53) ; v2(26.19,74.85) 27.05,75.71 27.05,84.62 28.98,86.55 28.98,87.95 v2(29.39,88.36)
  L6 w0.254: v2(124.74,110.96) 124.62,111.08 84.14,111.08 79.58,106.52 79.58,104.74 76.78,101.95 76.76,101.95 76.5,101.68 47.43,101.68 44.52,98.77 42.09,98.77 40.28,96.97 38.61,96.97 36.2,94.56 35.05,94.56 34.8,94.3 v2(34.8,93.49)
  BOTTOM w0.254: v2(34.97,76.32) 33.36,76.32 30.97,73.93 26.62,73.93 26.19,74.36 v2(26.19,74.85) 27.38,76.04 27.38,79.75 v2(26.52,80.61) ; v2(19.25,78.88) 19.25,79.4 PR4335.2 20.15,79.81 20.97,80.63 U4302.1 21.93,80.63 22.66,79.9 22.93,79.9 23.42,79.42 PQ4306.2
DCBATOUT: length 43.4
  TOP w0.508: v2(153.19,20.16) 152.02,20.16 150.01,22.17 147.68,22.17 147.16,22.69 147.16,22.91 v2(145.74,24.32) ; PR4410.2 149.48,34.43 147.7,32.66 147.7,28.52 v2(148.39,27.83) ; v3(88.44,106.39) 88.44,105.63 91.3,102.77 PR4511.1
  L6 w0.508: v3(158.9,21.07) 157.25,19.42 153.84,19.42 153.19,20.07 v2(153.19,20.16) ; v2(145.74,24.32) 145.74,24.45 148.39,27.09 v2(148.39,27.83) ; v3(145.72,96.74) 146.99,95.47 147.37,95.47 150.16,92.68 v2(150.16,91.91)
  BOTTOM w0.508: PR4458.1 146.07,23.99 v2(145.74,24.32) ; PR4601.1 150.47,91.61 v2(150.16,91.91)
  vias: v1(38.07,90.34) v1(51,12.01) v1(51.26,12.62) v1(112.72,12.72) v1(113.08,110.38) v1(146.56,53.15) v1(147.55,98.82) v1(154,17.57) v1(163.02,68.44) v1(164.39,72.28) v1(165.96,101.85) v3(36.7,89.65) v3(36.73,88.74) v3(36.73,87.85) v3(37.62,89.65) v3(37.62,88.74) v3(37.62,87.85) v3(49.3,11.83) v3(49.45,12.67) v3(50.16,11.83) v3(58.67,100.25) v3(59.69,100.25) v3(60.53,100.25) v3(61.39,100.25) v3(87.37,108.2) v3(87.4,107.31) v3(87.4,106.42) v3(88.4,108.2) v3(88.4,107.31) v3(109.73,8.25) v3(110.62,8.25) v3(111.5,8.25) v3(112.39,8.25) v3(141.07,52.37) v3(141.91,52.34) v3(142.75,52.31) v3(143.18,101.06) v3(143.94,97.76) v3(144.07,103.34) v3(144.07,102.2) v3(144.32,101.06) v3(144.83,98.26) v3(144.83,97.37) v3(144.83,96.49) v3(144.96,99.91) v3(145.08,101.82) v3(145.59,100.8) v3(145.72,99.41) v3(145.72,98.52) v3(145.72,97.63) v3(153.44,50.16) v3(153.39,49.27) v3(153.97,48.23) v3(154.3,50.18) v3(154.28,49.27) v3(155.09,59.02) v3(155.09,58.13) v3(155.14,50.16) v3(155.12,49.27) v3(155.9,68.95) v3(155.88,68.04) v3(155.85,58.64) v3(156.61,68.5) v3(156.79,67.5) v3(157.58,67.96) v3(158.39,68.44) v3(159.76,21.07) v3(160.6,21.07) v3(161.44,21.07) v3(163.29,85.23) v3(163.29,84.34) v3(163.29,83.46) v3(163.29,45.43) v3(163.29,44.54) v3(164.18,85.23) v3(164.18,84.34) v3(164.18,83.46) v3(164.18,45.43) v3(164.18,44.54) v3(165.2,85.23) v3(165.2,84.34) v3(165.2,83.46) v3(166.22,85.23) v3(166.22,84.34) v3(166.22,83.46) v3(176.88,55.41) v3(177.06,57.95) v3(177.09,57.09) v3(177.06,56.25) v3(178.99,63.59) v3(179.09,62.7)
DCBATOUT_+VCCSA:
  vias: v1(152.75,61.1)
DCBATOUT_CAMERA:
  vias: v1(55.8,90.52) v2(56.21,91.79)
DCBATOUT_LCD:
  vias: v1(79.75,94.17) v2(77.62,94) v2(78.26,94) v2(78.89,94)
DCIN_EN: length 2.6
  TOP w0.102: v1(23.98,70.13) 23.77,69.91 v2(23.77,69.23) 23.65,69.12 U5701.13
  BOTTOM w0.102: v2(23.77,69.23) 23.77,69.83 R5419.2
DDC_CLK_HDMI: length 29.1
  TOP w0.089: R5707.2 20.47,61.43 19.99,61.92 v1(19.99,61.97) 20.24,62.22 20.63,62.22 v2(20.83,62.41) 20.86,62.45 20.86,62.49 21.25,62.88 U5701.32
  L6 w0.102: v2(20.83,62.41) 20.83,62.38 20.65,62.2 19.35,62.2 17.79,63.76 17.79,64.7 17.4,65.09 17.4,68.62 13.59,72.43 13.59,78.2 12.27,79.52 11.43,79.52 11.02,79.11 11.02,77.23 10.87,77.08 HDMI1.15
DDC_CLK_PH1: length 5.8
  TOP w0.089: v2(24.66,60.32) 24.43,60.32 23.8,59.68 21.79,59.68 v1(21.41,60.06) 21.32,60.15 R5707.1
  BOTTOM w0.089: v2(24.66,60.32) 24.66,60.47 24.1,61.03 D5701.2
DDC_DATA_HDMI: length 24.4
  TOP w0.089: U5701.33 21.65,62.57 v2(21.46,62.37) 21.46,62.02 v1(21.23,61.79)
  L6 w0.102: HDMI1.16 13.06,76.37 13.06,72.5 17.09,68.47 17.09,63.95 19.18,61.87 20.95,61.87 v2(21.46,62.37)
  BOTTOM w0.089: v2(21.46,62.37) 21.64,62.55 21.64,63.48 R5706.2
DDC_DATA_PH2: length 2.6
  BOTTOM w0.089: R5706.1 22.15,63.1 v1(22.15,62.73) 22.15,61.29 D5701.1
DDCBUF: length 4.5
  TOP w0.102: U5701.14 23.25,69.06 23.13,69.18 v2(23.13,69.23) v1(23.13,71.09)
  BOTTOM w0.102: R5418.2 23.13,68.89 v2(23.13,69.23) 23.13,69.58 R5417.2
DDR4_DRAMRST#: length 130.2
  TOP w0.127: v2(49.6,61.89) v1(48.66,61.89) 48.36,61.89 47.72,61.26 ED1302.1 ED1217.1 49.31,60.74 49.35,60.77 v2(49.5,60.77)
  L3 w0.127: v2(102.09,18.94) 102.08,18.93 102.08,18.91 101.63,18.46 100.02,18.46 98.61,17.05 89.44,17.05 89.25,17.24 86.84,17.24 86.74,17.34 79.47,17.34 76.8,14.66 71.38,14.66 70.99,15.05 66.01,15.05 65.94,15.13 63.4,15.13 61.85,16.68 53.54,16.68 51.26,18.97 46.48,18.97 42.89,22.56 42.89,32.14 v2(43.05,32.3) ; v2(49.6,61.89) 50.62,61.89 51.45,61.07 61.4,61.07 v2(61.77,60.7) ; v2(46.38,32.33) 48.06,34 48.06,59.83 48.99,60.77 v2(49.5,60.77)
  L4 w0.127: v2(46.38,32.33) 46.35,32.3 v2(43.05,32.3)
  BOTTOM w0.127: DM1.108 62.74,60.73 62.71,60.7 v2(61.77,60.7) ; v2(102.09,18.94) 102.07,18.94 101.42,19.59 R504.2 ; DM2.108 50.05,60.94 49.81,61.18 49.81,61.69 v2(49.6,61.89)
DDR_VREF_S3: length 2.5
  BOTTOM w0.305: PU5102.6 44.08,13.12
  BOTTOM w0.508: PC5116.1 43.64,13.89 v1(43.74,13.78) 44.08,13.44 44.08,13.12
DGPU_HOLD_RST#: length 136.7
  TOP w0.127: v2(117.96,34.64) 117.89,34.64 117.27,35.26 117.27,35.67 116.98,35.96 116.44,35.96 EC2002.1 116.01,36.43 116.7,37.11 RN2009.4
  L4 w0.127: v2(117.96,34.64) 117.96,34.54 117.6,34.18 117.6,33.82 118.06,33.37 118.06,25.84 119.19,24.71 120.39,24.71 122.24,22.86 125.06,22.86 126.36,24.16 132.66,24.16 133.7,23.12 135.86,23.12 136.17,23.42 137.46,23.42 137.74,23.14 138.78,23.14 142.4,26.76 144.22,26.76 144.7,27.25 148.46,27.25 150.39,29.18 151.38,29.18 151.71,29.51 154.4,29.51 155.05,30.15 160.07,30.15 160.22,30 161.87,30 162.4,30 162.66,30.27 162.67,30.27 163.3,30.9 163.3,30.9 163.31,30.91 163.31,31.34 164.99,33.02 165.4,33.02 166.07,33.7 166.36,33.7 167.21,34.55 167.21,35.09 167.08,35.22 167.08,36.49 167.21,36.62 167.21,42.03 166.51,42.73 166.51,46.69 168.24,48.42 168.24,59.52 169.49,60.77 169.49,70.17 170.69,71.37 170.69,78.1 173.45,80.86 173.45,81.73 v2(174.12,82.39)
  BOTTOM w0.089: CPU1.P3 118.43,37.62 118.02,37.22 118.02,36.62 117.99,36.53 117.99,35.84 118.26,35.56 118.26,34.94 118.2,34.88
  BOTTOM w0.127: GPU1.D10 178.18,88.99 178.46,88.71 178.46,84.78 176.22,82.54 174.27,82.54 v2(174.12,82.39) ; 118.2,34.88 v2(117.96,34.64) 117.57,34.25 v1(117.57,33.65)
DGPU_PWR_EN: length 136.5
  TOP w0.102: RN2009.3 116.3,38.14 116.08,37.91 116.08,37.2 115.59,36.72 115.59,35.83 v1(115.95,35.48) 116.84,35.48 v2(116.86,35.5)
  L4 w0.102: v2(174.09,81.73) 174.09,81.14 170.94,77.99 170.94,71.27 169.75,70.08 169.75,60.67 168.48,59.4 168.48,48.3 166.75,46.57 166.75,42.84 167.45,42.14 167.45,36.5 167.32,36.38 167.32,35.32 167.45,35.19 167.45,34.45 166.42,33.42 166.29,33.42 162.63,29.76 162.5,29.76 159.97,29.76 159.82,29.91 155.22,29.91 154.56,29.25 151.81,29.25 151.48,28.92 150.49,28.92 148.61,27.04 148.6,27.04 148.55,26.99 144.8,26.99 144.32,26.51 143.79,26.51 142.16,24.88 140.86,24.88 138.88,22.9 138,22.9 137.64,22.55 133.93,22.55 132.56,23.92 126.49,23.92 125.19,22.62 122.14,22.62 121.09,23.66 118.72,23.66 117.8,24.58 117.8,33.32 117.4,33.72 117.4,34.97 v2(116.86,35.5)
  BOTTOM w0.102: GPU1.C10 177.25,90.3 178.71,88.84 178.71,84.7 176.32,82.3 174.66,82.3 v2(174.09,81.73) ; v2(116.86,35.5) 117.09,35.73 117.09,36.39 CPU1.U1
DGPU_PWROK: length 69.3
  TOP w0.102: v2(178,88.41) v1(178.56,88.41)
  L3 w0.102: v2(178,88.41) 177.57,87.98 177.57,86.58 178.8,85.34 178.8,73.59 175.54,70.32 175.54,63.64 178.31,60.88 178.31,54.78 179.18,53.9 179.18,51.17 179.8,50.54 179.8,49.88 180.21,49.47 180.21,48.23 180.57,47.87 180.57,46.4 183.41,43.55 184.98,43.55 185.11,43.43 191.75,43.43 191.88,43.3 193.67,43.3 193.77,43.2 193.77,41.98 194.26,41.49 196.14,41.49 196.49,41.14 197.39,41.14 v2(197.56,41.31)
  BOTTOM w0.102: R2471.1 197.9,40.97 v2(197.56,41.31) ; GPU1.D9 176.65,88.52 176.79,88.38 177.98,88.38 v2(178,88.41)
DGPU_PWROK_KBC: length 3.5
  TOP w0.102: v2(200.25,40.28) 199.72,39.74 199.72,39.67 199.49,39.44 KBC24.24
  BOTTOM w0.102: R2471.2 199.34,40.66 v1(199.69,40.3) 199.7,40.31 200.22,40.31 v2(200.25,40.28)
DGPU_RXN_C_CPU_TXN0: length 149.9
  TOP w0.102: v1(132.71,42.31) 132.41,42.31 v2(132.18,42.08)
  L3 w0.14: v2(132.18,42.08) 132.18,42.1 132.05,42.23 131.81,42.23 131.68,42.1 131.68,41.72 131.55,41.6 131.34,41.6 131.21,41.72 131.21,42.32 131.09,42.45 130.81,42.45 130.62,42.26 130.62,33.23 132.68,31.17 132.68,27.74 133.97,26.45 134.22,26.45 136.97,23.7 137.46,23.7 138.67,22.48 139.21,22.48 140.6,21.09 144.15,21.09 146.97,18.27 150.81,18.27 152.29,16.79 166.68,16.79 169.19,19.3 169.19,28.97 171.09,30.88 171.09,34.52 171.83,35.26 171.83,57.43 171.65,57.61 171.37,57.88 171.37,61.26 170.84,61.79 170.84,86.78 171.41,87.35 175.14,87.35 176.62,88.83 176.62,91.49 177.72,92.6 177.72,94.15 176.22,95.65 174.81,95.65 v2(174.62,95.47)
  BOTTOM w0.102: v2(132.18,42.08) 132.18,42.1 131.92,42.36 131.29,42.36 131.14,42.21 131.14,42.06 131.27,41.93 C1606.1 ; v2(174.62,95.47) 174.62,95.38 174.16,94.91 173.99,94.91 173.89,94.81 173.89,94.69 174.25,94.32 GPU1.A5
DGPU_RXN_C_CPU_TXN1: length 140
  TOP w0.102: v2(132.08,41.42) 131.57,41.42 v1(131.52,41.37)
  L3 w0.14: v2(132.08,41.42) 131.81,41.15 131.54,41.15 131.16,40.77 131.16,33.32 133.12,31.35 133.12,28.59 133.95,27.76 133.95,27.56 137.22,24.29 138.58,24.29 141.34,21.53 144.35,21.53 147.09,18.79 151.05,18.79 152.61,17.23 166.45,17.23 168.74,19.53 168.74,27.18 168.49,27.43 168.49,29.09 170.65,31.25 170.65,34.7 171.38,35.44 171.38,57.24 170.85,57.78 170.85,61.04 170.32,61.57 170.32,86.89 171.33,87.9 172.08,87.9 172.45,88.27 172.45,90.21 174.57,92.32 176.73,92.32 177.27,92.86 177.27,93.51 176.22,94.55 v2(176.22,94.83)
  BOTTOM w0.102: v2(176.22,94.83) 176.22,94.66 176.05,94.49 GPU1.A8 ; v2(132.08,41.42) 131.7,41.04 C1608.1
DGPU_RXN_C_CPU_TXN2: length 137.8
  TOP w0.102: v2(132.71,43.97) v1(132.71,44.57)
  L3 w0.14: v2(132.71,43.97) 132.78,43.97 133.56,43.18 133.56,40.77 132.85,40.06 132.85,33 134.1,31.76 134.1,30.28 135.97,28.41 135.97,26.93 137.62,25.27 139.43,25.27 142.2,22.51 144.76,22.51 147.43,19.84 148.54,19.84 149.38,20.68 150.78,20.68 153.25,18.21 166.04,18.21 167.77,19.93 167.77,26.66 167.36,27.06 167.36,29.56 169.43,31.63 169.43,32.52 168.96,32.99 168.96,34.92 169.34,35.3 169.85,35.3 170.41,35.86 170.41,56.84 169.12,58.12 169.12,92.15 170.06,93.08 v2(171.07,93.08)
  BOTTOM w0.102: C1610.1 131.49,44.62 132.13,43.98 132.7,43.98 v2(132.71,43.97) ; v2(171.07,93.08) 171.4,93.08 171.56,93.23 172.39,93.23 173.05,92.57 GPU1.B3
DGPU_RXN_C_CPU_TXN3: length 142.4
  L3 w0.14: v2(133.22,45.2) 133.04,45.03 133.04,44.74 134.28,43.51 134.28,40.48 133.56,39.77 133.56,33.3 134.81,32.05 134.81,30.57 135.96,29.42 136.3,29.08 136.68,28.71 136.68,27.22 137.23,26.67 138.55,26.67 139.13,26.09 140.14,26.09 142.72,23.51 144.8,23.51 146.02,22.29 147.67,22.29 148.5,21.47 151.11,21.47 153.63,18.95 165.78,18.95 166.84,20.01 166.84,21.62 164.81,23.64 164.81,25.83 166.44,27.46 166.44,29.65 167.33,30.54 167.33,31.69 168.1,32.45 168.1,35.5 168.47,35.87 168.47,36.74 169,37.28 169,43.62 169.12,43.74 169.12,56.42 168.32,57.22 168.32,92.8 169.51,93.98 173.87,93.98 174.55,93.31 v2(174.55,93.23)
  BOTTOM w0.102: GPU1.B6 174.85,92.57 174.72,92.7 174.72,93.06 v2(174.55,93.23) ; 132.46,47.47 133.02,46.91 133.02,45.42 133.22,45.21 v2(133.22,45.2) ; 132.46,47.47 v1(132.56,47.57) ; 132.46,47.47 131.94,47.99 131.17,47.99 C1612.1
DGPU_RXP_C_CPU_TXP0: length 150.1
  TOP w0.102: v1(131.37,42.59) 131.49,42.71 v2(132.18,42.71)
  L3 w0.14: v2(132.18,42.71) 130.7,42.71 130.35,42.37 130.35,33.12 132.41,31.06 132.41,27.63 133.86,26.18 134.11,26.18 136.86,23.43 137.35,23.43 138.56,22.21 139.09,22.21 140.49,20.82 144.04,20.82 146.86,18 150.7,18 152.18,16.52 166.79,16.52 169.45,19.18 169.45,28.86 171.36,30.77 171.36,34.41 172.1,35.15 172.1,57.54 171.91,57.72 171.91,57.72 171.64,57.99 171.64,61.37 171.11,61.9 171.11,86.67 171.52,87.09 175.25,87.09 176.88,88.72 176.88,91.38 177.99,92.49 177.99,94.26 176.33,95.92 174.44,95.92 173.96,95.44 v2(173.91,95.44)
  BOTTOM w0.102: C1605.1 132.08,42.82 v2(132.18,42.71) ; GPU1.A4 173.66,94.02 173.66,95.19 v2(173.91,95.44)
DGPU_RXP_C_CPU_TXP1: length 140.1
  TOP w0.102: v2(132.08,40.78) 132.21,40.78 v1(132.61,40.38)
  L3 w0.14: v2(175.51,94.83) 175.56,94.83 177,93.4 177,92.97 176.62,92.59 174.45,92.59 172.18,90.32 172.18,88.38 171.97,88.16 171.22,88.16 170.05,87 170.05,61.46 170.58,60.93 170.58,57.66 171.12,57.13 171.12,35.55 170.38,34.81 170.38,31.36 168.22,29.2 168.22,27.32 168.48,27.07 168.48,19.64 166.34,17.5 152.72,17.5 151.16,19.05 147.2,19.05 144.46,21.8 141.45,21.8 138.69,24.56 137.33,24.56 134.22,27.67 134.22,27.87 133.39,28.71 133.39,31.46 131.42,33.43 131.42,40.66 131.65,40.88 131.98,40.88 v2(132.08,40.78)
  BOTTOM w0.102: C1607.1 131.38,39.84 131.51,39.72 131.95,39.72 132.08,39.84 v2(132.08,40.78) ; GPU1.A7 175.45,94.75 175.46,94.76 175.46,94.78 v2(175.51,94.83)
DGPU_RXP_C_CPU_TXP2: length 137.8
  TOP w0.102: v1(131.75,43.78) 131.98,43.78 v2(132.26,43.5)
  L3 w0.14: v2(132.26,43.5) 132.33,43.58 132.47,43.58 132.53,43.52 132.85,43.52 133.3,43.07 133.3,40.88 132.59,40.17 132.59,32.89 133.83,31.65 133.83,30.17 135.7,28.3 135.7,26.82 137.51,25 139.32,25 142.08,22.24 144.65,22.24 147.32,19.57 148.65,19.57 149.49,20.41 150.67,20.41 153.14,17.94 166.15,17.94 168.03,19.82 168.03,26.77 167.63,27.17 167.63,29.45 169.7,31.52 169.7,32.63 169.23,33.1 169.23,34.81 169.45,35.03 169.96,35.03 170.67,35.75 170.67,56.95 169.39,58.23 169.39,92.04 170.17,92.82 170.7,92.82 170.88,92.63 170.91,92.63 170.95,92.59 v2(171.09,92.45)
  BOTTOM w0.102: v2(132.26,43.5) 132.26,43.63 132.13,43.76 132.04,43.76 131.78,44.01 131.56,44.01 131.43,43.88 C1609.1 ; v2(171.09,92.45) 171.65,93.01 172.3,93.01 172.45,92.85 GPU1.B2
DGPU_RXP_C_CPU_TXP3: length 142.3
  L3 w0.14: v2(132.56,45.2) 132.78,44.99 132.78,44.63 134.01,43.4 134.01,40.59 133.3,39.88 133.3,33.19 134.54,31.94 134.54,30.46 135.44,29.57 136.11,28.9 136.41,28.6 136.41,27.11 137.12,26.4 138.44,26.4 139.02,25.82 140.03,25.82 142.61,23.24 144.69,23.24 145.91,22.03 147.56,22.03 148.39,21.2 151,21.2 153.52,18.68 165.89,18.68 167.1,19.9 167.1,21.73 165.08,23.75 165.08,25.72 166.71,27.35 166.71,29.54 167.6,30.43 167.6,31.58 168.36,32.34 168.36,35.39 168.74,35.76 168.74,36.63 169.27,37.17 169.27,43.51 169.39,43.63 169.39,56.53 168.59,57.33 168.59,92.69 169.6,93.7 169.61,93.7 169.62,93.72 173.76,93.72 173.93,93.55 173.93,93.3 v2(173.84,93.21)
  BOTTOM w0.102: C1611.1 131.08,47.31 131.52,47.76 131.85,47.76 132.79,46.81 132.79,46.12 ; v1(132.66,46.12) 132.79,46.12 ; 132.79,46.12 132.79,45.43 v2(132.56,45.2) ; GPU1.B5 174.25,92.87 173.91,93.21 v2(173.84,93.21)
DMIC_CLK: length 123.4
  TOP w0.089: R2716.1 29.79,16.34 C2723.2 31.61,16.34 32.13,16.86 v1(33.42,16.86) v2(34.39,16.86) ; v2(56.97,89.37) 56.97,90.04 57.21,90.28 57.98,90.28 EC5504.1 58.51,89.91 RN5503.4
  L3 w0.127: v2(34.39,16.86) 34.39,17.03 34.31,17.11 34.31,22.9 30,27.22 29.53,27.22 29.01,27.75 29.01,33.85 25.63,37.23 25.63,42.85 24.78,43.7 24.78,45.43 24.98,45.63 24.98,47.74 26.55,49.31 26.55,49.92 27.38,50.74 27.38,52.68 28.65,53.95 28.65,65.9 33.09,70.35 33.09,72.57 32.42,73.24 32.42,73.61 33.15,74.33 33.15,79.63 33.42,79.91 33.42,79.93 34.24,80.74 34.24,81.47 34.25,81.49 34.25,84.77 32.33,86.69 32.33,93.34 v2(32.87,93.87)
  BOTTOM w0.089: v2(56.97,89.37) 56.97,89.67 56.5,90.14 55.89,90.14 54.25,91.79 47.8,91.79 47.01,92.57 42.52,92.57 41.62,93.47 38.7,93.47 37.28,94.89 35.13,94.89 34.06,93.82 32.92,93.82 v2(32.87,93.87)
DMIC_CLK_C: length 6.8
  TOP w0.089: v2(62.63,89.22) 62.63,88.97 62.74,88.87 v1(63.07,88.87) 63.09,88.89 63.09,89.53 62.71,89.91 RN5503.1
  BOTTOM w0.089: v2(62.63,89.22) 62.63,90.29 63.15,90.8 TCBD1.17
DMIC_CLK_R: length 3.1
  TOP w0.089: HDA27.6 27.2,16.91 27.94,16.17 v1(27.94,16.1) 27.94,16.09 28.34,16.09 28.65,16.4 R2716.2
DMIC_DATA: length 123.1
  TOP w0.089: v2(35.02,16.58) 34.72,16.27 32.71,16.27 32.15,15.71 v1(32.15,15.69) 32.15,15.66 31.37,14.88 29.98,14.88 R2714.1 ; v2(56.39,89.65) 56.39,89.83 57.1,90.55 57.9,90.55 EC5503.1 58.79,90.56 RN5503.3
  L3 w0.127: v2(35.02,16.58) 35.02,16.96 34.69,17.29 34.69,23.06 30.15,27.6 29.69,27.6 29.39,27.91 29.39,34.01 26.01,37.39 26.01,41.74 26.01,43.01 25.16,43.86 25.16,45.27 25.36,45.47 25.36,47.58 26.94,49.15 26.94,49.47 26.93,49.47 26.93,49.76 27.76,50.58 27.76,52.52 29.03,53.79 29.03,65.57 33.53,70.07 33.53,79.47 34.62,80.56 34.62,81.31 34.63,81.33 34.63,84.93 32.71,86.85 32.71,92.8 v2(33.3,93.39)
  BOTTOM w0.089: v2(33.3,93.39) 34.01,93.39 35.24,94.62 37.17,94.62 38.59,93.2 41.43,93.2 42.34,92.29 46.91,92.29 47.72,91.48 54.13,91.48 55.95,89.65 v2(56.39,89.65)
DMIC_DATA_C: length 6.7
  TOP w0.089: v2(63.52,89.2) 63.52,90.16 v1(63.14,90.54) 63.12,90.56 RN5503.2
  BOTTOM w0.089: v2(63.52,89.2) 63.52,90.54 63.65,90.67 TCBD1.18
DMIC_DATA_R: length 5.3
  TOP w0.089: R2714.2 EC2701.1 28.45,15.51 28.29,15.36 28.29,15.05 28.16,14.91 v1(27.63,14.91) 27.58,14.97 27.58,16.23 27.29,16.51 HDA27.5
DPB_AUXN: length 174.2
  TOP w0.102: v2(40.33,65.68) 40.33,65.65 39.95,65.27 39.79,65.27 39.45,65.61 ; 39.45,65.61 39.13,65.93 36.73,65.93 36.09,65.29 35.93,65.29 C3802.1 ; 39.45,65.61 v1(39.55,65.7)
  L6 w0.127: v2(40.33,65.68) 39.97,65.31 39.55,65.31 39.43,65.43 39.43,69.04 38.38,70.1 38.38,71.06 39.05,71.73 39.05,80.5 41.39,82.84 41.39,91.09 42.2,91.91 42.2,92.21 45.02,95.03 45.02,95.56 47.12,97.66 47.12,98.31 47.39,98.59 47.72,98.59 48.89,99.76 52.24,99.76 52.59,100.11 56.17,100.11 56.36,99.92 56.36,99.91 57.27,99.01 61.73,99.01 62.58,99.86 66.72,99.86 67.26,99.33 69.61,99.33 70.39,100.12 74.26,100.12 75.04,99.33 78.12,99.33 78.39,99.6 94.6,99.6 94.63,99.57 103.44,99.57 103.66,99.36 105.61,99.36 105.99,98.98 107.5,98.98 108.26,99.74 110.49,99.74 111.25,98.98 112.09,98.98 112.62,98.44 122.05,98.44 130.25,90.24 131.27,90.24 134.93,86.58 134.93,84.99 134.94,84.98 134.94,77.11 132.78,74.96 132.78,73.23 132.37,72.83 131.76,72.83 131.15,72.21 131.15,70.01 131.56,69.6 131.56,66.68 128,63.12 125.61,63.12 125.14,63.59 122.83,63.59 122.62,63.81 122.62,64.04 v2(122.78,64.2)
  BOTTOM w0.102: CPU1.E48 122.95,63.74 122.78,63.92 v2(122.78,64.2)
DPB_AUXN_C: length 4.5
  TOP w0.102: U3801.25 33.5,62.72 33.68,62.9 33.68,63.13 33.68,63.13 33.68,63.78 R3801.2 33.81,63.97 33.93,64.1 33.93,64.33 34.11,64.5 34.11,65.62 34.24,65.75 C3802.2
DPB_AUXP: length 175.9
  TOP w0.102: v1(37.08,65.57) 37.08,65.7 ; 37.08,65.7 39.04,65.7 39.7,65.04 v2(40.33,65.04) ; 37.08,65.7 36.83,65.7 36.19,65.06 35.67,65.06 C3801.1
  L6 w0.127: v2(122.13,64.2) 122.35,63.97 122.35,63.69 122.72,63.33 125.03,63.33 125.5,62.86 128.11,62.86 131.82,66.57 131.82,69.71 131.42,70.12 131.42,72.1 131.88,72.56 132.48,72.56 133.04,73.12 133.04,74.85 135.2,77 135.2,85.09 135.2,85.1 135.2,86.69 131.38,90.5 130.36,90.5 122.16,98.71 112.73,98.71 112.2,99.24 111.36,99.24 110.6,100 108.15,100 107.39,99.24 106.1,99.24 105.72,99.62 103.77,99.62 103.55,99.84 94.74,99.84 94.71,99.86 78.28,99.86 78.01,99.6 75.16,99.6 74.37,100.38 70.28,100.38 69.49,99.6 67.37,99.6 66.83,100.13 62.47,100.13 61.62,99.28 57.38,99.28 56.63,100.03 56.28,100.37 52.47,100.37 52.13,100.03 48.78,100.03 47.61,98.86 47.28,98.86 46.85,98.43 46.85,97.77 44.75,95.67 44.75,95.14 41.93,92.32 41.93,92.02 41.12,91.2 41.12,82.95 38.78,80.61 38.78,71.84 38.11,71.17 38.11,69.98 39.17,68.93 39.17,65.32 39.44,65.04 v2(40.33,65.04)
  BOTTOM w0.102: CPU1.F48 122.54,63.78 v2(122.13,64.2)
DPB_AUXP_C: length 2.9
  TOP w0.102: C3801.2 34.38,64.66 R3802.2 33.91,63.5 33.91,63.04 33.9,63.04 U3801.24
DS3_PWRCTL: length 2.5
  BOTTOM w0.127: U4101.4 106.68,12.5 106.69,12.51 106.69,12.75 v1(107.16,13.22) 107.7,13.76 R4102.2
E71_TP: length 4.5
  TOP w0.102: TP2313.1 123.9,78.45 v2(124.33,78.88)
  BOTTOM w0.102: CPU1.E71 123.5,78.05 v2(124.33,78.88)
EAPD#: length 4.1
  TOP w0.102: R2708.2 28.55,13.81 28.4,13.66 v1(27.76,13.66) 27.25,14.16 27.25,15.31 26.85,15.71 HDA27.3
EC_AGND: length 8.5
  TOP w0.152: KBC24.112 190.81,27.75 190.6,27.54 v2(190.6,27.4)
  TOP w0.508: v2(191.11,33.82) 190.97,33.82 190.67,34.13 188.81,34.13 187.98,33.3 v2(187.98,32.22)
  BOTTOM w0.508: v2(191.11,33.82) 191.11,33.8 191.37,33.53 C2422.2 190.66,33.16 R2444.2 C2408.1
  vias: v1(190.09,27.07)
EC_MUTE#: length 191
  TOP w0.102: R2708.1 29.7,13.43 R2728.1 30.34,12.92 31.67,12.92 32.69,13.94 34.64,13.94 36.09,15.38 37.61,15.38 37.65,15.34 39.91,15.34 41.95,17.38 42.71,17.38 v1(44.68,19.35) 45.54,20.21 46.15,20.21 v2(46.2,20.26) ; v2(192.56,26.08) 192.66,26.08 193.22,26.64 193.22,27.17 193.61,27.56 KBC24.119
  L3 w0.102: v2(84.94,18.3) 84.53,18.71 82.62,18.71 81.94,18.03 79.12,18.03 77.54,16.45 66.27,16.45 65.4,15.59 63.63,15.59 62.08,17.14 53.74,17.14 51.38,19.5 48.28,19.5 47.52,20.26 v2(46.2,20.26)
  L4 w0.102: v2(192.56,26.08) 192.45,25.98 192.45,23.87 192.63,23.69 192.63,19.6 188.08,15.05 179.7,15.05 179.23,14.58 178.99,14.58 177.27,12.87 165.23,12.87 164.41,12.06 156.87,12.06 152.55,7.74 140.71,7.74 139.6,6.62 133.06,6.62 132.48,7.2 130.33,7.2 128.75,8.78 122.93,8.78 121.89,9.82 119.31,9.82 118.66,10.47 115.85,10.47 114.74,11.59 113.85,11.59 113.21,12.23 111.93,12.23 111.65,11.95 109.95,11.95 109.78,12.13 105.56,12.13 104.86,12.83 102.64,12.83 102.35,12.54 100.48,12.54 99.9,13.12 95.12,13.12 93.39,14.85 91.42,14.85 87.3,18.97 85.6,18.97 v2(84.94,18.3)
EC_SPI_CLK: length 1.3
  TOP w0.089: v2(199.06,43.17) 198.75,42.87 KBC24.32
  BOTTOM w0.089: v2(199.06,43.17) 199.13,43.25 199.13,43.68 RN2406.4
EC_SPI_MISO: length 5.5
  TOP w0.089: v2(200.28,42.46) 200.28,42.25 199.47,41.44 KBC24.29
  BOTTOM w0.089: v2(200.28,42.46) 199.74,42.99 199.74,43.96 199.47,44.23 RN2406.3 199.19,44.7 199.49,45 v1(199.49,45.13)
EC_SPI_MOSI: length 3.4
  TOP w0.089: v2(200.28,41.55) 200.18,41.55 199.67,41.04 KBC24.28
  BOTTOM w0.089: v2(200.28,41.55) 200.28,41.65 v1(199.92,42) 199.54,42.38 R2405.2
EC_VTT: length 4.8
  TOP w0.203: R2402.2 180.42,30.75 180.55,30.62 181.46,30.62 v1(181.63,30.45) 182.14,30.45 182.34,30.64 KBC24.95
  TOP w0.508: C2406.1 R2402.2
EC_WAKE#: length 188.7
  TOP w0.102: KBC24.35 196.41,44.96 197.1,45.66 v2(197.33,45.66)
  L3 w0.102: v2(62.51,6.44) 64.18,4.77 79.3,4.77 86.89,12.36 94.44,12.36 94.87,11.93 100.62,11.93 101.36,12.67 104.44,12.67 105.08,12.03 110.2,12.03 110.46,11.78 111.73,11.78 111.98,12.03 112.99,12.03 116.57,8.45 117.1,8.45 120.27,5.28 120.27,4.2 121.68,2.79 123.29,2.79 123.93,2.15 v2(124.81,2.15)
  L4 w0.102: v2(197.33,45.66) 197.33,45.07 198.01,44.39 198.17,44.39 198.55,44.01 198.55,43.04 198.8,42.79 198.8,39.59 198.58,39.36 198.58,31.41 200.02,29.96 200.02,17.49 193.88,11.35 193,11.35 192.1,10.45 192.1,10.01 189.49,7.41 158.9,7.41 154.94,3.45 154.94,3.16 153.78,2 133.09,2 132.66,2.43 127.84,2.43 127.35,1.95 126.9,1.95 126.19,2.66 125.68,2.66 125.17,2.15 v2(124.81,2.15)
  BOTTOM w0.102: v2(62.51,6.44) 62.51,6.85 v1(62.36,7) 62.03,7.33 62.03,7.89 61.76,8.16 R1732.1
ECVBAT: length 13.4
  TOP w0.203: v2(193.32,29.84) 193.32,29.84 194.02,29.84 194.17,29.7 194.6,29.7 194.81,29.49 KBC24.122
  TOP w0.508: v2(193.32,29.84) 193.32,30.09 191.87,31.54 191.87,33.11 192.12,33.37 192.12,33.98 v2(192.17,34.03)
  BOTTOM w0.254: v1(193.95,37.63) 193.95,37.18 194.12,37.01 R2472.1
  BOTTOM w0.508: v2(193.32,29.84) 192.68,30.47 R2451.2 ; R2472.1 C2428.1 R2496.2 194.12,34.86 193.49,34.23 192.86,34.23 192.66,34.03 v2(192.17,34.03)
EDP_AUX: length 2
  TOP w0.102: v2(84.3,93.92) 83.95,94.28 C5510.1
  BOTTOM w0.102: v2(84.3,93.92) 84.45,94.07 LCD1.12
EDP_AUX#: length 2.6
  TOP w0.102: v1(84.68,93.41) 84.94,93.67 v2(84.94,93.92) 84.83,94.02 C5511.1
  BOTTOM w0.102: LCD1.13 84.95,94.54 84.73,94.32 84.73,94.1 84.91,93.92 v2(84.94,93.92)
EDP_AUX_DN: length 98.1
  TOP w0.102: C5511.2 84.72,95.58 84.02,96.28 v2(84.02,96.36)
  L3 w0.14: v2(122.86,62.38) 122.63,62.62 122.63,62.86 122.76,62.98 123.2,62.98 123.33,62.86 123.33,62.21 124.04,61.5 124.23,61.31 124.73,61.31 125.79,60.25 130.37,60.25 133.61,63.5 133.61,69.98 132.81,70.79 132.81,86.31 130.93,88.19 127.93,88.19 127.25,88.87 127.25,91.99 122.13,97.11 103.82,97.11 103.4,96.69 101.27,96.69 100.41,97.55 98.55,97.55 96.94,99.17 86.59,99.17 85.24,97.82 84.19,97.82 83.65,97.29 83.65,97.11 83.79,96.97 83.89,96.97 84.02,96.84 v2(84.02,96.36)
  BOTTOM w0.102: CPU1.E45 122.99,61.92 122.86,62.04 v2(122.86,62.38)
EDP_AUX_DP: length 98.1
  TOP w0.102: v2(83.39,96.31) 83.95,95.75 C5510.2
  L3 w0.14: v2(83.39,96.31) 83.39,97.4 84.08,98.09 85.13,98.09 86.48,99.43 97.05,99.43 98.66,97.82 100.52,97.82 101.38,96.96 103.29,96.96 103.71,97.37 122.24,97.37 127.52,92.1 127.52,88.98 128.04,88.46 131.04,88.46 133.08,86.42 133.08,70.9 133.88,70.1 133.88,63.39 130.48,59.99 125.68,59.99 124.62,61.04 124.12,61.04 123.85,61.31 123.22,61.94 122.62,61.94 v2(122.23,62.34)
  BOTTOM w0.102: v2(122.23,62.34) 122.54,62.03 CPU1.F45
EDP_COMP: length 2
  TOP w0.305: v2(122.89,65.1) 122.89,65.3 v1(123.19,65.6)
  TOP w0.508: v2(114.1,67.28) 113.89,67.07 113.4,67.07 R801.2
  BOTTOM w0.305: v2(122.89,65.1) 122.89,65.27 CPU1.E52
EDP_DISP_UTIL: length 2.5
  TOP w0.102: v2(126.49,65.6) 125.53,65.6 TP801.1
  BOTTOM w0.102: CPU1.B52 125.26,65.78 125.58,65.47 126.36,65.47 v2(126.49,65.6)
EDP_HPD: length 119.6
  TOP w0.102: RN5502.7 96.84,98.9 96.26,99.48 94.18,99.48 94.09,99.57 v1(94.07,99.57) 94.07,99.59 93.32,100.35 93.01,100.35 v2(92.91,100.45) ; R5506.2 93.65,95.52 v2(94.38,96.26)
  L3 w0.102: v2(126.54,56.02) 125.68,56.02 125.02,55.36 125.02,51.15 124.13,50.26 122.34,50.26 121.23,49.15 121.23,47.46 120.34,46.57 119.91,46.57 119.67,46.33 119.67,46 119.87,45.8 119.87,42.45 v2(119.47,42.05) ; v2(135.05,88.61) 134.97,88.54 131.67,88.54 131.24,88.97 128.6,88.97 128.04,89.53 128.04,92.32 122.48,97.88 104.56,97.88 103.47,98.98 98.63,98.98 97.38,100.22 93.14,100.22 v2(92.91,100.45)
  L4 w0.102: v2(94.38,96.26) 94.38,98.92 92.91,100.4 v2(92.91,100.45)
  L6 w0.102: v2(135.05,88.61) 136.32,87.33 136.32,74.87 134.24,72.79 134.24,72.61 133.73,72.1 133.73,65.29 130.55,62.12 129.74,62.12 129.49,61.87 129.49,60.6 130.1,59.99 130.1,59.1 127.02,56.02 v2(126.54,56.02)
  BOTTOM w0.102: CPU1.L10 119.62,42.05 v2(119.47,42.05)
EDP_HPD_CONN: length 3.2
  TOP w0.102: v2(91.92,93.92) 92.17,93.92 v1(92.86,94.61) 92.86,95.41 R5506.1
  BOTTOM w0.102: LCD1.27 91.95,93.95 v2(91.92,93.92)
EDP_TX0: length 2.2
  TOP w0.102: v2(91.29,93.92) 91.95,94.58 C5509.1
  BOTTOM w0.102: v2(91.29,93.92) 90.95,94.26 LCD1.25
EDP_TX0#: length 2
  TOP w0.102: v2(90.65,93.92) 90.65,94.38 90.97,94.7 C5506.1
  BOTTOM w0.102: v2(90.65,93.92) 90.65,94.33 90.45,94.53 LCD1.24
EDP_TX0_DN: length 78.1
  TOP w0.102: v2(91.13,96.23) 91.24,96.13 91.24,95.76 C5506.2
  L3 w0.14: v2(91.13,96.23) 91.34,96.44 91.34,96.77 91.59,97.02 95.98,97.02 96.45,96.55 97.11,95.89 98.39,94.61 100.23,94.61 100.88,93.96 107.5,93.96 107.69,93.76 107.8,93.65 111.83,93.65 112.78,94.61 117.77,94.61 118.07,94.31 118.07,92.85 118.21,92.71 118.58,92.71 118.72,92.85 118.72,94.31 119.01,94.61 120.95,94.61 125.13,90.43 125.13,82.22 129.35,78 129.35,76.52 129.73,76.14 129.73,69.4 130.85,68.28 130.85,65.97 130.33,65.46 130.33,64.27 v2(130.38,64.23)
  BOTTOM w0.102: 129.59,64.76 129.84,64.76 v2(130.38,64.23) ; 129.59,64.76 129.31,64.76 128.98,64.43 128.98,63.92 128.13,63.07 125.1,63.07 124.82,63.35 CPU1.C47 ; 129.59,64.76 v1(129.59,64.91)
EDP_TX0_DP: length 78.1
  TOP w0.102: C5509.2 91.95,96.08 v2(91.79,96.23)
  L3 w0.14: v2(91.79,96.23) 91.6,96.42 91.6,96.65 91.7,96.75 95.87,96.75 96.92,95.7 98.28,94.34 100.12,94.34 100.77,93.69 107.39,93.69 107.69,93.39 111.94,93.39 112.09,93.54 112.89,94.34 117.66,94.34 117.8,94.2 117.8,92.74 118.1,92.44 118.69,92.44 118.98,92.74 118.98,94.2 119.12,94.34 120.84,94.34 124.86,90.32 124.86,82.11 129.08,77.89 129.08,76.41 129.46,76.03 129.46,69.29 130.58,68.17 130.58,66.08 130.07,65.57 130.07,64.75 129.84,64.52 129.6,64.52 129.34,64.26 129.34,63.92 129.44,63.82 v2(129.87,63.82)
  BOTTOM w0.102: v2(129.87,63.82) 129.94,63.9 129.94,64.34 129.75,64.53 129.4,64.53 129.21,64.34 129.21,63.83 128.57,63.19 ; v1(128.67,63.08) 128.57,63.19 ; 128.57,63.19 128.22,62.84 125,62.84 CPU1.C46
EDP_TX1: length 2.1
  TOP w0.102: C5504.1 90.16,94.7 v2(89.38,93.92)
  BOTTOM w0.102: v2(89.38,93.92) 89.38,94.31 89.45,94.38 LCD1.22
EDP_TX1#: length 2.1
  TOP w0.102: v2(88.75,93.92) 88.77,93.92 88.95,94.1 88.95,94.1 89.28,94.43 C5501.1
  BOTTOM w0.102: v2(88.75,93.92) 88.95,94.12 LCD1.21
EDP_TX1_DN: length 79.4
  TOP w0.102: C5501.2 89.51,95.81 89.51,96 v2(89.23,96.28) 88.9,96.61 v1(88.9,96.77)
  L3 w0.14: v2(123.78,62.75) 124.1,62.43 124.3,62.43 124.69,62.83 125.32,63.45 125.32,64.1 126.24,65.02 128.37,65.02 129.72,66.36 129.72,67.76 128.62,68.85 128.62,75.75 128.29,76.08 128.29,77.51 124.05,81.75 124.05,89.93 122.33,91.65 116.57,91.65 116.25,91.96 116.25,93.41 116.13,93.54 115.39,93.54 115.26,93.41 115.26,91.95 114.96,91.65 114.37,91.65 114.08,91.95 114.08,93.41 113.94,93.55 113.45,93.55 111.61,91.71 108.18,91.71 107.03,92.85 98.65,92.85 96.2,95.3 89.7,95.3 89.42,95.59 89.42,96.09 v2(89.23,96.28)
  BOTTOM w0.102: v2(123.78,62.75) 123.82,62.78 CPU1.D46
EDP_TX1_DP: length 79.5
  TOP w0.102: v1(90.26,96.79) 89.86,96.39 v2(89.86,96.28) 89.86,95.89 C5504.2
  L3 w0.14: v2(124.45,61.73) 124.45,62.2 124.88,62.64 125.11,62.87 125.59,63.34 125.59,63.99 126.35,64.75 128.48,64.75 129.98,66.25 129.98,67.87 128.89,68.97 128.89,75.86 128.56,76.19 128.56,77.62 124.32,81.86 124.32,90.04 122.44,91.92 116.68,91.92 116.52,92.08 116.52,93.52 116.24,93.81 115.28,93.81 114.99,93.52 114.99,92.06 114.85,91.92 114.48,91.92 114.35,92.06 114.35,93.52 114.05,93.82 113.34,93.82 111.5,91.98 108.29,91.98 107.14,93.12 98.76,93.12 96.31,95.57 89.81,95.57 89.69,95.7 89.69,96.1 v2(89.86,96.28)
  BOTTOM w0.102: CPU1.C45 124.61,61.9 v2(124.45,61.73)
EDP_TX2: length 2.4
  TOP w0.102: v2(87.48,93.92) 88.25,94.7 C5519.1
  BOTTOM w0.102: v2(87.48,93.92) 87.95,94.39 LCD1.19
EDP_TX2#: length 2.9
  TOP w0.102: v1(86.76,93.36) 86.84,93.44 v2(86.84,93.92) 87.5,94.58 C5533.1
  BOTTOM w0.102: LCD1.18 87.45,94.53 v2(86.84,93.92)
EDP_TX2_DN: length 81.3
  TOP w0.102: C5533.2 87.27,95.81 v2(87.27,96.31) 87.27,96.44 v1(87.63,96.79)
  L3 w0.14: v2(127.23,62.22) 127.89,61.56 128.78,61.56 129.56,62.35 129.81,62.35 131.63,64.17 131.63,68.81 130.76,69.69 130.76,77.74 125.92,82.58 125.92,91.44 121.94,95.42 112.42,95.42 111.44,94.44 108.41,94.44 108.11,94.75 101.21,94.75 100.56,95.39 98.8,95.39 96.38,97.82 88.02,97.82 87.48,97.27 87.48,96.51 v2(87.27,96.31)
  BOTTOM w0.102: CPU1.A45 v2(127.23,62.22)
EDP_TX2_DP: length 81.3
  TOP w0.102: v1(127.68,62.88) 127.86,62.7 v2(127.86,62.22) ; C5519.2 88.39,95.7 87.93,96.16 v2(87.93,96.28)
  L3 w0.14: v2(87.93,96.28) 87.74,96.47 87.74,97.16 88.13,97.55 96.27,97.55 98.69,95.13 100.45,95.13 101.1,94.48 108,94.48 108.3,94.17 111.56,94.17 112.53,95.15 121.83,95.15 125.65,91.33 125.65,82.47 130.49,77.63 130.49,69.58 131.37,68.7 131.37,64.28 129.7,62.62 129.45,62.62 128.67,61.83 128,61.83 127.86,61.96 v2(127.86,62.22)
  BOTTOM w0.102: CPU1.B45 125.49,62.22 125.76,62.49 126.86,62.49 127.02,62.65 127.43,62.65 v2(127.86,62.22)
EDP_TX3: length 2
  TOP w0.102: C5531.1 86.21,94.29 v2(86.21,93.92)
  BOTTOM w0.102: v2(86.21,93.92) 86.33,94.05 86.33,94.12 86.45,94.24 LCD1.16
EDP_TX3#: length 2
  TOP w0.102: C5532.1 85.72,94.07 v2(85.57,93.92)
  BOTTOM w0.102: LCD1.15 85.95,94.3 v2(85.57,93.92)
EDP_TX3_DN: length 95.2
  TOP w0.102: v1(84.96,96.82) 84.96,96.64 v2(85.29,96.31) 85.72,95.88 C5532.2
  L3 w0.14: v2(85.29,96.31) 85.55,96.56 85.55,97.35 86.8,98.61 96.7,98.61 98.36,96.96 100.11,96.96 101.53,95.53 104.56,95.53 105.36,96.33 122.15,96.33 126.72,91.76 126.72,88.53 127.58,87.67 130.58,87.67 132.22,86.03 132.22,81.28 131.62,80.69 131.62,70.17 132.05,69.74 132.58,69.74 133.07,69.25 133.07,63.75 130.09,60.77 126.52,60.77 125.69,61.6 125.69,62.46 126.33,63.1 127.33,63.1 127.53,63.3 127.53,63.54 v2(127.3,63.77)
  BOTTOM w0.102: v2(127.3,63.77) 126.92,63.77 126.49,63.35 CPU1.A47
EDP_TX3_DP: length 95.1
  TOP w0.102: C5531.2 86.61,95.6 86,96.21 v2(86,96.31) 86,96.49 v1(86.31,96.79)
  L3 w0.14: v2(86,96.31) 85.81,96.5 85.81,97.24 86.91,98.34 96.59,98.34 98.25,96.69 100,96.69 101.42,95.27 104.67,95.27 105.47,96.07 122.04,96.07 126.45,91.65 126.45,88.42 127.47,87.41 130.47,87.41 131.95,85.92 131.95,81.39 131.35,80.8 131.35,70.06 131.94,69.47 132.47,69.47 132.8,69.14 132.8,63.86 129.98,61.04 126.63,61.04 125.96,61.71 125.96,62.35 126.44,62.83 127.44,62.83 127.6,62.99 127.8,63.19 127.8,63.66 v2(127.94,63.8)
  BOTTOM w0.102: CPU1.B47 125.53,63.62 126.07,63.62 126.1,63.59 126.41,63.59 127.06,64.24 127.5,64.24 v2(127.94,63.8)
EDP_VDD_EN: length 108.7
  TOP w0.127: D5501.1 91.43,97.26 v1(90.8,97.88) 89.08,97.88 87.81,99.15 v2(87.81,100.96)
  L3 w0.127: v2(117.4,42.21) 117.98,42.79 117.98,46.47 119.35,47.84 119.35,49.38 118.08,50.64 112.98,50.64 111.99,51.63 111.5,51.63 110.51,52.61 110.51,66.31 111.5,67.3 111.5,69.21 110.44,70.27 110.44,73.4 111.53,74.49 111.53,76.04 112.95,77.46 112.95,78.68 113.82,79.55 113.82,82.79 109.9,86.71 109.9,87.09 105.03,91.96 100.15,91.96 99.35,91.15 99.02,91.15 98.85,91.33 97.59,91.33 96.53,92.38 88.61,92.38 88.23,92 85.76,92 85.74,92.03 84.03,92.03 83.32,91.32 82.95,91.32 82.68,91.59 82.68,92.75 81.88,93.55 81.88,94.62 82.19,94.94 82.19,96.93 84.71,99.45 85.02,99.45 85.87,100.3 87.15,100.3 v2(87.81,100.96)
  BOTTOM w0.127: v2(117.4,42.21) 117.4,43.15 CPU1.U13
EDRAM_OPIO_RCOMP: length 0.6
  BOTTOM w0.381: v2(121.62,73.56) 121.3,73.88 CPU1.H66
  vias: v1(122.12,74.29)
EMMC_RCOMP: length 3.5
  TOP w0.508: v2(108.28,36.19) 107.88,36.58 R1502.1 v1(106.98,36.8)
  BOTTOM w0.254: v2(108.28,36.19) 108.1,36.01 107.34,36.01 107.16,36.19 CPU1.AT1
EN_EDRAM_VR: length 22.6
  TOP w0.127: U4004.4 97.85,92.54 98.66,91.72 v2(98.66,90.88)
  BOTTOM w0.127: D4003.A 100.91,91.04 100.98,91.11 100.98,92.02 R4019.2 ; D4003.A 101.4,90.39 101.86,89.93 105.1,89.93 Q4001.D 105.29,90.12 D4004.A 107.34,90.12 107.62,90.39 107.62,91.99 107.11,92.5 107.11,95.09 107.36,95.34 ; D4003.A 100.76,90.39 100.25,89.88 99.11,89.88 98.66,90.33 v2(98.66,90.88) ; 107.36,95.34 108,95.98 R4028.2 R4027.2 ; 107.36,95.34 v1(107.36,95.35)
EOPIO_RCOMP: length 2.7
  TOP w0.508: v1(119.4,72.76) 120.19,72.76 v2(120.24,72.81) 120.36,72.7 R415.1
  BOTTOM w0.152: v2(120.24,72.81) 121.08,72.81 CPU1.H65
EQ: length 3.7
  TOP w0.102: v1(21.5,70) 21.86,69.65 v2(21.86,69.23) 22.05,69.04 U5701.17
  BOTTOM w0.102: R5411.2 21.12,69.88 21.77,69.23 v2(21.86,69.23) 21.86,68.58 R5412.2
EXT_PWR_GATE#: length 2
  TOP w0.127: R1731.2 110.32,41.1 v2(110.05,41.37) 109.75,41.08 v1(109.75,40.83)
  BOTTOM w0.127: v2(110.05,41.37) 109.65,41.77 CPU1.AM10
FALL_INT2: length 6.3
  BOTTOM w0.102: Q7001.2 123.19,9.16 123.26,9.24 123.26,9.69 123.16,9.8 122.37,9.8 Q7001.3 122.35,10.55 R7018.2 123.45,11.65 124.26,11.65 v1(124.81,11.09)
FAN1_PWM: length 76.3
  TOP w0.102: R2614.1 v1(148.58,75) 148.58,74.43 149.04,73.96 149.04,72.61 v2(149.02,72.58) ; KBC24.47 191.61,45.4 191.87,45.66 v2(191.87,45.69)
  L3 w0.102: v2(177.21,70.07) 177.21,69.42 176.83,69.03 176.81,69.03 176.53,68.75 176.53,64.08 179.23,61.37 179.23,57.05 179.52,56.13 179.52,56.13 179.91,54.91 179.91,52.06 181.05,50.92 181.37,49.99 181.37,48.95 182.98,47.34 182.98,46.46 183.74,45.7 184.72,45.7 185.72,44.7 190.88,44.7 191.87,45.68 v2(191.87,45.69)
  L4 w0.102: v2(166.55,72.23) 165.44,72.23 163.81,70.6 157.77,70.6 157.26,70.1 151.83,70.1 150.71,71.21 150.19,71.21 149.02,72.38 v2(149.02,72.58)
  L6 w0.102: v2(177.21,70.07) 177.37,69.92 177.37,69.49 174.97,67.09 171.07,67.09 166.55,71.61 v2(166.55,72.23)
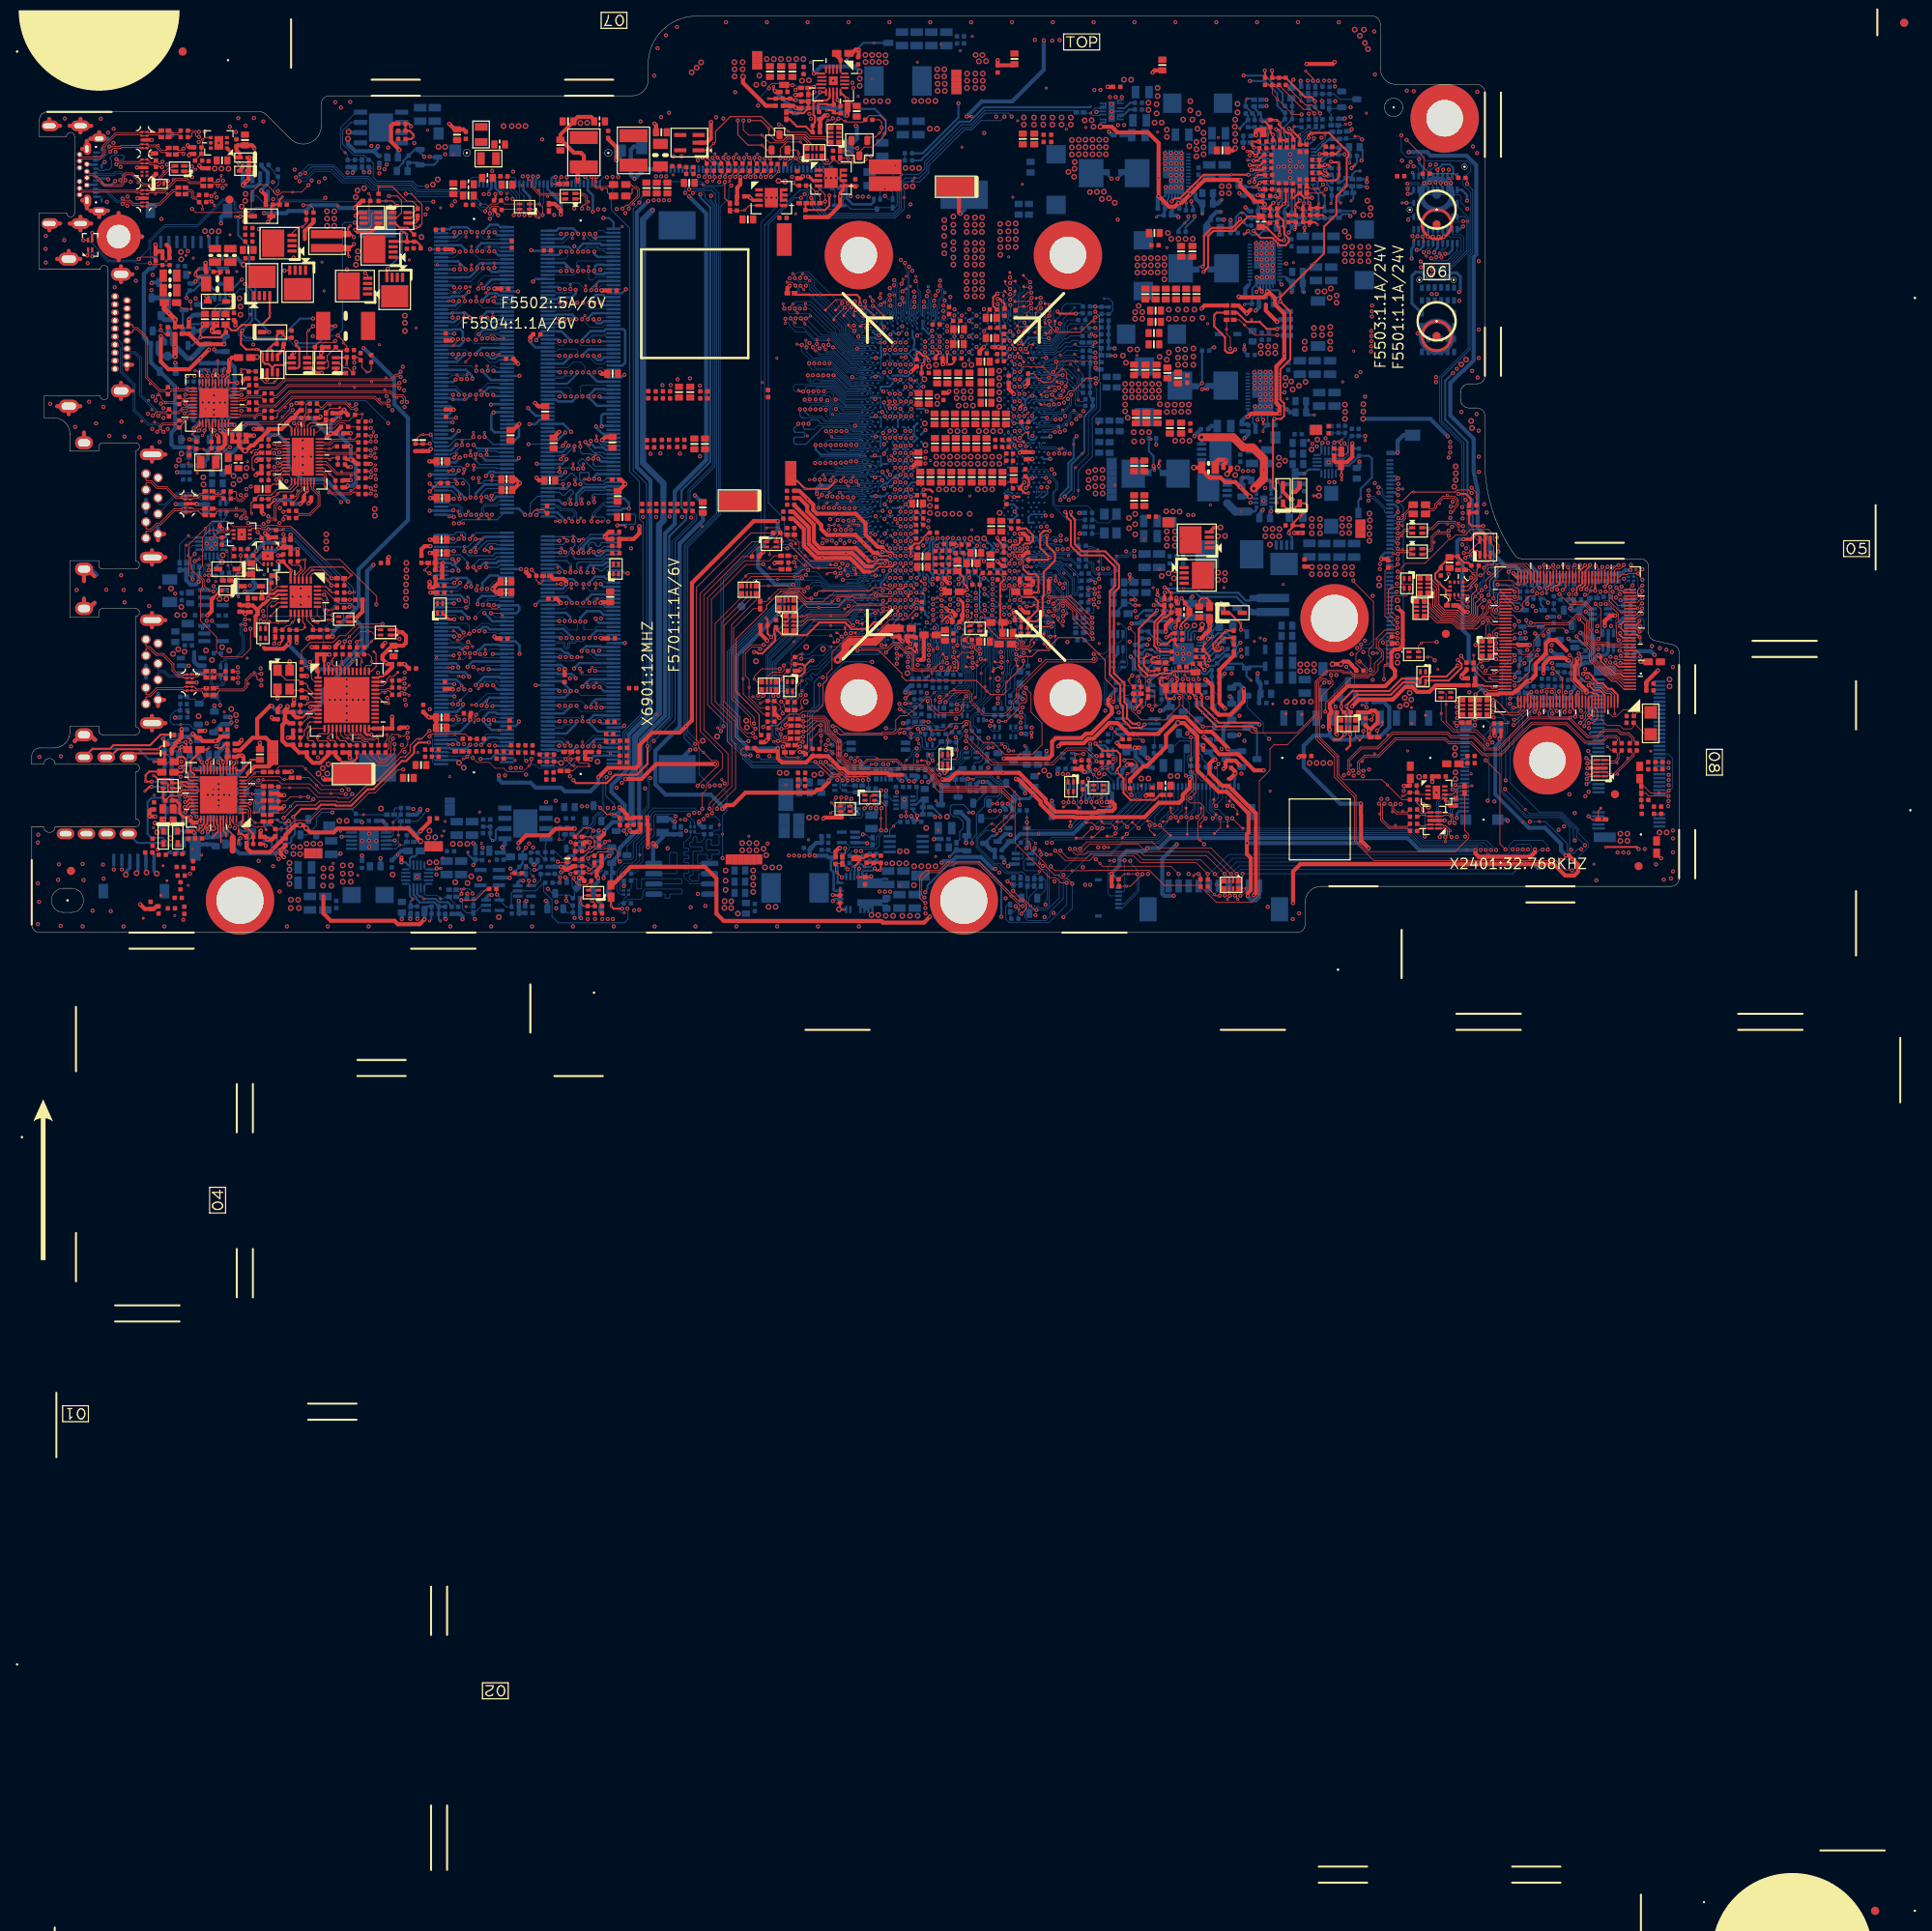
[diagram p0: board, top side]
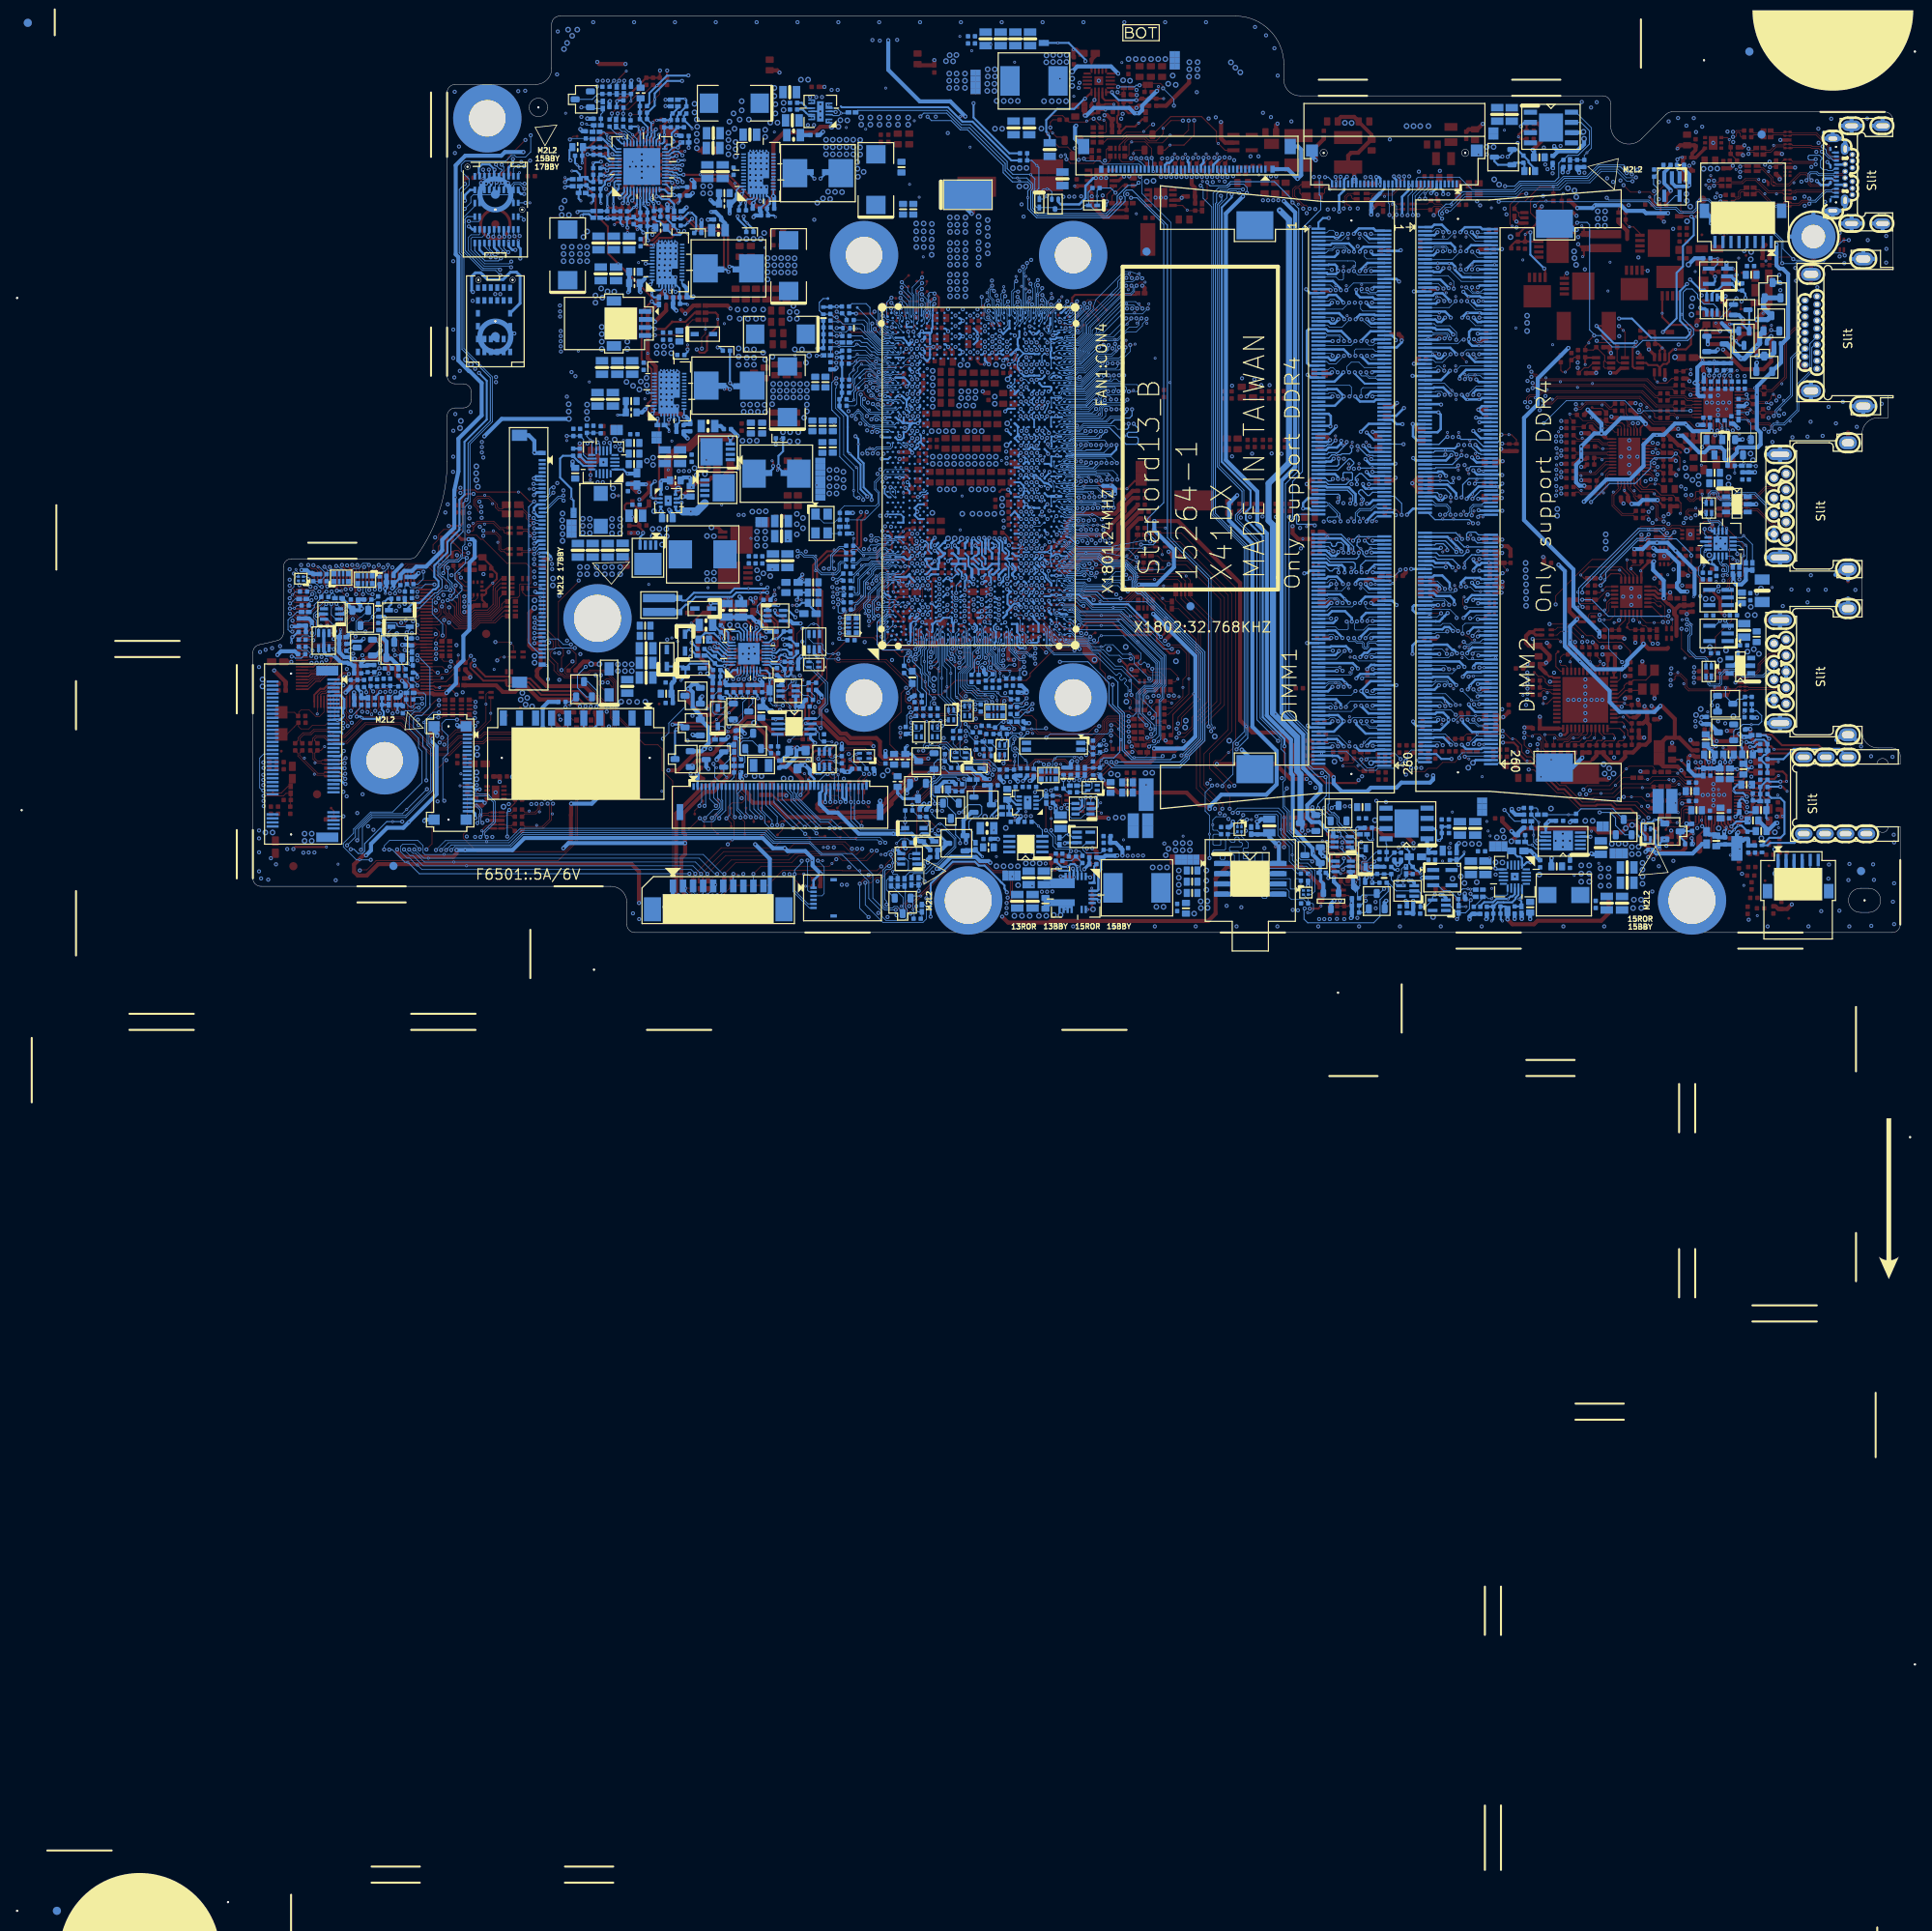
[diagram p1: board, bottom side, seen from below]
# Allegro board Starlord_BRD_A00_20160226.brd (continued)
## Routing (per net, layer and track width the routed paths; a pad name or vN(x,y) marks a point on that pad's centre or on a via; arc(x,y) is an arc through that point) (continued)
FAN1_TACH: length 11.4
  TOP w0.203: KBC24.40 194.41,42.97 194.41,42.97
  TOP w0.254: v2(194.41,42.49) 194.41,42.97
  L6 w0.254: v2(194.41,42.49) 194.37,42.49 193.35,41.47 190.8,41.47 190.52,41.19 190.36,41.19 190.33,41.16 188.72,41.16 v2(188.57,41.01)
  BOTTOM w0.254: v2(188.57,41.01) 188.09,41.49 R2430.1 187.64,40.8 187.93,40.5 D2403.A ; v1(193.85,42.49) v2(194.41,42.49)
FAN_PWM1_C: length 7.4
  TOP w0.102: R2614.2 150.16,76.17 AFTP2602.1 152.07,74.26 v2(154.86,74.26)
  BOTTOM w0.102: v2(154.86,74.26) 154.91,74.21 FAN1.4
FAN_TACH1: length 75.7
  TOP w0.254: v2(149.66,72.48) 149.25,72.08 148.69,72.08 148.39,72.38 148.39,74.01 147.04,75.35 v1(147.04,76.24) 147.04,76.78 147.32,77.05 R2613.1
  L4 w0.254: v2(149.66,72.48) 150.44,71.7 150.84,71.7 152,70.53 157.08,70.53 157.59,71.04 163.63,71.04 165.47,72.87 v2(166.57,72.87)
  L6 w0.254: v2(166.57,72.87) 166.58,72.86 166.98,72.86 167.33,72.51 167.33,71.58 171.4,67.52 174.79,67.52 176.73,69.46 v2(176.73,69.56)
  BOTTOM w0.254: D2403.K 185.65,40.25 184.91,40.99 184.08,40.99 182.4,42.67 182.16,42.67 181.77,43.05 181.77,43.69 182.29,44.21 182.29,45.62 180.67,47.24 180.67,48.55 179.17,50.05 179.17,53.81 178.53,54.44 178.53,61 175.77,63.77 175.77,68.58 176.73,69.55 v2(176.73,69.56)
FAN_TACH1_C: length 7.5
  TOP w0.254: R2613.2 149.91,77.05 151.05,75.91 AFTP2601.1 153.59,75.02 v2(154.86,75.02)
  BOTTOM w0.254: FAN1.3 155.05,75.21 v2(154.86,75.02)
FAN_VCC_1: length 2.7
  TOP w0.508: 151.08,76.95 AFTP2603.1 ; 151.08,76.95 150.09,77.94 R2612.2 ; 151.08,76.95 v2(151.08,76.93)
  vias: v1(151.69,76.19)
FFS_INT2: length 52
  TOP w0.102: v2(125.73,8.27) 125.68,8.27 v1(125.3,8.65)
  L3 w0.102: v2(125.73,8.27) 124.84,8.27 122.5,10.61 122.5,10.63 122.43,10.71 122.43,12.77 121.74,13.45 121.74,13.71 120.75,14.7 118.95,14.7 118.48,15.16 118.48,17.16 118.48,17.16 118.48,17.33 117.05,18.76 117.05,19.38 116.86,19.57 116.86,25.01 116.38,25.49 116.05,25.49 115.72,25.82 115.72,30.34 v2(113.13,32.94)
  BOTTOM w0.089: 113.56,35.83 113.56,36.53 113.51,36.67 113.51,37.1 CPU1.AC2
  BOTTOM w0.102: R2044.2 112.43,31.77 112.43,32.4 112.68,32.65 112.84,32.65 v2(113.13,32.94) 112.95,33.11 112.95,34.23 113.56,34.84 113.56,35.83 113.56,35.83 ; v2(125.73,8.27) 126.01,8.27 126.49,7.79 126.49,3.29 126.24,3.04 125.32,3.04 125.12,3.24 124.74,3.24 124.41,2.91 124.41,2.72 D7001.3 124,2.42 124,4.38 125.41,5.8 R7008.2
FFS_INT2_Q: length 75.9
  TOP w0.102: v2(179.47,26.46) 179.06,26.46 R6001.1 ; v1(126.74,9.69) v2(126.19,9.69)
  L4 w0.102: v2(126.19,9.69) 126.34,9.54 130.15,9.54 131.37,8.32 139.9,8.32 140.28,8.7 152.12,8.7 156.44,13.02 163.98,13.02 164.79,13.83 173.68,13.83 174.93,15.08 176.55,15.08 177.04,15.56 178.79,15.56 179.6,16.37 v2(181.05,16.37)
  BOTTOM w0.102: v2(179.47,26.46) 179.5,26.46 179.51,26.47 180.87,26.47 181.36,25.98 181.36,25.24 180.62,24.5 180.62,22.24 181.23,21.63 181.23,16.55 v2(181.05,16.37) ; Q7001.6 124.54,8.51 124.92,8.88 124.92,9.74 125.32,10.15 125.73,10.15 v2(126.19,9.69)
FFS_INT2_Q_R: length 3.5
  TOP w0.102: R6001.2 177.71,26.2 176.94,26.2 v1(176.88,26.14) 176.88,26.03 v2(177.21,25.7)
  BOTTOM w0.102: HDD1.1 177.57,24.58 177.21,24.93 v2(177.21,25.7)
GC6_FB_EN: length 145.1
  TOP w0.127: v2(170.97,90.7) v1(170.41,90.7)
  L4 w0.127: v2(170.97,90.7) 170.5,90.24 170.5,86.52 171.5,85.51 175.25,85.51 176.21,84.55 176.21,82.58 174.83,81.2 174.83,81.14 171.45,77.77 171.45,71.08 170.56,70.19 170.56,58.61 168.98,57.04 168.98,43.78 168.59,43.39 168.59,42.64 168.57,42.61 168.57,37.52 168.95,37.14 168.95,35.65 168.64,35.35 168.64,33.71 167.6,32.66 167.6,32.16 167.45,32.01 167.45,31.12 166.95,30.62 166.21,30.62 164.87,29.29 164.87,28.17 164.32,27.61 161.33,27.61 161.05,27.89 160.64,27.89 160.07,27.32 152.34,27.32 150.56,25.54 149.81,25.54 148.92,24.65 147.39,24.65 146.44,23.7 145.38,23.7 144.13,22.46 141.72,22.46 139.51,20.25 137.65,20.25 136.75,19.35 135.63,19.35 134.96,18.67 128.18,18.67 127.89,18.97 125.73,18.97 124.69,20.01 121.84,20.01 121.31,19.47 119.31,19.47 118.37,20.41 115.38,20.41 113.9,21.89 113.3,21.89 112.56,22.64 110.93,22.64 110.24,23.32 108.73,23.32 107.5,24.55 107.5,28.02 v2(107.9,28.41)
  BOTTOM w0.127: v2(170.97,90.7) 171.85,90.7 GPU1.C1 ; R2004.1 109.83,27.17 109.29,27.7 108.66,27.7 107.95,28.41 v2(107.9,28.41)
GC6_FB_EN_MCP: length 15
  TOP w0.127: v2(108.63,28.46) v1(109.32,28.46)
  L4 w0.127: v2(108.63,28.46) 107.94,29.16 107.94,32.94 108.21,33.22 108.21,35.22 107.36,36.08 107.36,38.2 v2(108.68,39.51)
  BOTTOM w0.127: CPU1.AP7 108.35,39.92 108.68,39.6 v2(108.68,39.51) ; v2(108.63,28.46) 109.05,28.05 R2004.2
GPD2/LAN_WAKE#: length 87.7
  TOP w0.102: v2(61.82,6.44) v1(61.82,5.88)
  L3 w0.102: v2(109.33,44.08) 109.33,44.35 109.72,44.74 109.72,46.08 109.49,46.31 105.91,46.31 103.93,44.33 103.93,34.43 102.56,33.06 101.78,33.06 99.72,31 99.72,26.97 100.42,26.27 100.42,24.96 99.87,24.41 99.87,20.83 99.33,20.29 97.24,20.29 95.17,18.22 90.82,18.22 90.63,18.41 87.48,18.41 86.46,19.42 82.32,19.42 81.63,18.74 78.81,18.74 77.24,17.16 64.74,17.16 63.96,16.37 v2(63.96,16.22)
  L4 w0.102: v2(63.96,16.22) 63.93,16.22 63.85,16.15 63.73,16.15 62.8,15.22 62.8,9.76 61.82,8.78 v2(61.82,6.44)
  BOTTOM w0.102: v2(61.82,6.44) 61.62,6.65 61.62,6.65 61.44,6.83 R1732.2 R1707.2 ; v2(109.33,44.08) 109.65,44.41 CPU1.AM15
GPD11/LANPHYPC: length 42
  TOP w0.102: v1(104.39,20.92) v2(104.98,20.92)
  L4 w0.102: v2(104.98,20.92) 104.9,20.84 104.42,20.84 103.63,20.06 100.76,20.06 98.93,21.89 95.22,21.89 94.94,22.17 94.94,23.26 95.27,23.59 95.27,26.48 95.17,26.59 95.17,32.91 95.81,33.54 95.9,33.54 102.72,40.36 102.72,42.87 103.6,43.76 103.6,45.05 104.87,46.32 v2(104.87,46.6)
  BOTTOM w0.102: CPU1.AW17 105.24,46.24 v2(104.87,46.6) ; v2(104.98,20.92) 104.98,20.1 RN1704.5
GPP_B2/VRALERT#: length 1.2
  TOP w0.102: TP1708.1 109.72,42.78 v2(109.33,43.17)
  BOTTOM w0.102: v2(109.33,43.17) 109.65,42.85 CPU1.AM11
GPP_B4/CPU_GP3: length 1.6
  TOP w0.102: v2(104.95,38.11) 104.57,37.73 TP404.1
  BOTTOM w0.102: CPU1.AY5 104.91,38.15 v2(104.95,38.11)
GPP_B18/GSPI0_MOSI: length 25
  L4 w0.102: v2(108.03,40.43) 107.95,40.43 107.54,40.02 106.68,40.02 106.34,39.68 106.34,39.35 107.08,38.6 107.08,33.31 107.11,33.29 107.11,28.26 107.06,28.2 107.06,24.32 108.71,22.67 109.45,22.67 v2(110.11,22.01)
  BOTTOM w0.102: v2(110.11,22.01) 110.11,21.28 v1(110.13,21.25) 110.13,20.84 110.21,20.77 R2007.2 R2019.1 ; v2(108.03,40.43) 107.7,40.11 CPU1.AR7
GPP_B22: length 2
  TOP w0.102: v2(110.03,39.49) 109.9,39.49 TP2018.1
  BOTTOM w0.102: v2(110.03,39.49) 109.24,39.49 109,39.25 CPU1.AN5
GPP_B23/SML1ALERT#: length 28.3
  TOP w0.102: R1837.2 91.91,25.72 92.77,25.72 94.19,27.14 95.53,27.14 95.88,27.5 97.66,27.5 98.37,28.21 98.37,30.83 98.88,31.33 98.88,32.17 99.52,32.81 99.52,34.83 101.51,36.82 104.6,36.82 106.68,38.91 v1(108.29,38.91) 108.63,38.91 109.42,39.7 109.42,39.72 v2(110.03,40.33)
  BOTTOM w0.102: CPU1.AM7 109.67,39.97 v2(110.03,40.33)
GPP_C2/SMBALERT#: length 20.1
  TOP w0.102: v1(115.8,25.57) 116.15,25.92 v2(116.23,25.92)
  L4 w0.102: v2(116.23,25.92) 116,26.15 116,28.79 115.64,29.15 115.64,32.48 115.71,32.54 115.71,38 115.54,38.17 115.54,39.85 115.72,40.02 115.72,40.68 116.3,41.27 v2(116.38,41.27)
  BOTTOM w0.102: v2(116.23,25.92) 116,25.7 116,25.59 115.33,24.92 R1836.2 ; CPU1.R10 117.93,41.53 117.56,41.15 117.23,41.15 117.02,41.37 116.74,41.37 116.64,41.27 v2(116.38,41.27)
GPP_C5/SML0ALERT#: length 16.9
  TOP w0.102: v2(111.5,26.18) 111.4,26.28 v1(110.92,26.28)
  L4 w0.102: v2(112.9,29.28) 111.5,27.88 v2(111.5,26.18)
  BOTTOM w0.102: v2(112.9,29.28) 113.05,29.43 114.77,29.43 115.43,30.09 116.03,30.09 116.6,30.65 116.6,32.24 115.73,33.11 115.73,36.35 CPU1.W1 ; v2(111.5,26.18) 111.81,26.18 112.49,25.49 R1823.1 113.14,25.49 R1822.2
GPP_E0/SATAXPCIE0/SATAGP0: length 4.8
  TOP w0.102: v2(122.43,33.95) 122.43,33.29 TP1602.1
  BOTTOM w0.089: 121.54,35.55 121.54,36.46 121.48,36.63 121.48,36.86 121.48,36.87 121.49,37 CPU1.H2
  BOTTOM w0.102: v2(122.43,33.95) 122.43,34.03 121.82,34.64 121.82,35.27 121.54,35.55
GPP_E1/SATAXPCIE1/SATAGP1: length 4.9
  TOP w0.102: TP1603.1 123.85,35.22 v2(122.48,35.22)
  BOTTOM w0.102: v2(122.48,35.22) 122.08,35.61 122.08,37.68 CPU1.H3
GPP_E2/SATAXPCIE2/SATAGP2: length 5.4
  TOP w0.102: TP1604.1 124.64,35.78 124.28,35.42 122.91,35.42 v2(122.48,35.86)
  BOTTOM w0.102: v2(122.48,35.86) 122.67,36.05 122.67,37.92 122.4,38.19 CPU1.G4
GPP_E3/CPU_GP0: length 1.8
  TOP w0.102: v2(126.41,38.52) 126.44,38.55 TP403.1
  BOTTOM w0.102: v2(126.41,38.52) 126.22,38.71 126.22,38.82 125.8,39.24 CPU1.A6
GPU_EVENT#: length 136.1
  TOP w0.127: v1(108.53,27.4) 108.18,27.75 v2(107.95,27.75)
  L4 w0.127: v2(107.95,27.75) 107.83,27.64 107.83,24.58 108.84,23.58 110.35,23.58 111.02,22.9 114.43,22.9 115.49,21.84 117.99,21.84 118.38,21.44 119.04,21.44 120.13,20.35 120.62,20.35 121.41,20.35 121.66,20.6 124.56,20.6 124.9,20.95 130.1,20.95 130.15,20.9 130.94,20.9 132.57,19.26 133.67,19.26 134.8,20.39 135.15,20.39 135.61,19.93 136.54,19.93 137.48,20.87 139.22,20.87 141.4,23.05 143.88,23.05 144.89,24.07 144.89,24.68 145.36,25.15 145.83,25.15 146.09,25.42 148.69,25.42 149.53,26.25 150.51,26.25 152.09,27.83 159.66,27.83 160.41,28.58 163.8,28.58 166.1,30.88 166.84,30.88 167.19,31.23 167.19,32.11 167.35,32.27 167.35,32.77 168.39,33.81 168.39,35.45 168.69,35.76 168.69,36.72 168.31,37.1 168.31,42.72 168.34,42.74 168.34,43.51 168.72,43.9 168.72,57.15 170.31,58.74 170.31,70.3 171.19,71.18 171.19,77.89 174.56,81.26 174.56,83.27 v2(174.01,83.81)
  BOTTOM w0.127: v2(174.01,83.81) 174.33,83.49 175.98,83.49 177.26,84.77 177.26,85.7 GPU1.F10 ; R2003.1 110.17,26.69 109.52,26.69 108.81,27.4 108.3,27.4 v2(107.95,27.75)
GPU_EVENT_MCP#: length 16.6
  TOP w0.127: v1(109.27,29.71) 108.68,29.13 v2(108.63,29.13)
  L4 w0.127: v2(108.68,40.43) 108.68,40.38 109.14,39.92 109.14,36.92 109.76,36.31 109.76,35.54 109.16,34.94 109.08,34.94 108.48,34.35 108.48,33.14 108.19,32.85 108.19,29.57 v2(108.63,29.13)
  BOTTOM w0.127: CPU1.AN8 109,40.75 v2(108.68,40.43) ; R2003.2 110.17,28.52 109.24,28.52 v2(108.63,29.13)
GSEN2_INT1: length 105.2
  TOP w0.102: v2(122.05,5.17) 123.02,4.2 123.31,4.2 v1(124.24,3.27) 124.69,2.81 v2(124.92,2.81) ; U7001.12 177.41,41.73 177.6,41.55 178.15,41.55 v2(178.56,41.14)
  L3 w0.102: v2(180.82,10.25) 181.94,11.37 181.94,14.63 182.6,15.29 182.6,16.52 180.97,18.14 180.97,19.79 183.03,21.85 183.03,22.75 183.64,23.36 183.64,24.43 182.42,25.65 182.42,29.61 181.43,30.6 181.43,32.94 180.85,33.52 180.85,35.44 179.28,37.01 179.28,38.02 179.2,38.1 179.2,40.5 v2(178.56,41.14)
  BOTTOM w0.102: v2(124.92,2.81) 126.3,2.81 127.76,4.27 127.76,7.23 130.35,9.82 134.1,9.82 135.58,11.29 140.05,11.29 141.17,12.41 171.35,12.41 172.87,10.89 180.19,10.89 v2(180.82,10.25) ; R7009.2 R7012.2 122.07,5.91 122.05,5.88 v2(122.05,5.17)
GSEN2_INT1_C: length 113.9
  TOP w0.102: v2(120.45,12.69) 120.45,12.92 122.02,14.49 122.02,16.3 120.6,17.72 113.34,17.72 112.39,18.67 112.39,18.71 112.04,19.07 112.04,19.53 111.38,20.18 111.1,20.18 110.82,20.46 101.85,20.46 101.29,21.02 101.1,21.02 100.3,21.82 100.3,23.55 98.77,25.07 98.77,26.11 98.48,26.41 97.25,26.41 96.47,25.62 v2(95.93,25.62) 95.83,25.72 R2025.2 ; v2(46.76,24.22) 46.76,23.31 46.35,22.9 46.17,22.9 45.92,22.65 45.92,22.47 44.25,20.79 42.72,20.79 41.32,22.19 R6925.2
  L3 w0.102: v2(46.76,24.22) 47.83,23.16 47.83,22.6 49.38,21.05 52.09,21.05 54.43,18.71 65.53,18.71 66.67,19.85 67.03,19.85 67.8,20.62 68.8,20.62 69.35,20.07 70.9,20.07 72.36,21.53 80.57,21.53 81.13,22.09 83.5,22.09 84.14,22.72 88.52,22.72 88.8,22.44 93.34,22.44 94.31,23.41 94.31,23.99 v2(95.93,25.62)
  BOTTOM w0.102: R7009.1 122.96,7.08 122.71,7.33 121.11,7.33 120.04,8.4 119.63,8.4 117.45,10.58 117.45,11.76 119.19,13.5 v1(119.4,13.5) 119.63,13.5 v2(120.45,12.69)
GSEN2_INT1_C_HUB: length 4.3
  TOP w0.102: U6901.17 38.41,24.59 38.83,24.17 v1(39.29,24.17) 39.47,24.17 39.93,23.71 40.94,23.71 41.32,23.33 R6925.1
GSEN2_INT1_ISH: length 26.8
  TOP w0.102: R2025.1 94.02,25.34 93.24,25.34 v2(93.22,25.32) v1(92.66,25.32)
  BOTTOM w0.102: v2(93.22,25.32) 93.22,25.9 94.54,27.22 94.54,29.56 93.78,30.32 92.86,30.32 92.15,31.03 92.15,33.61 97.19,38.65 101.75,38.65 102.92,39.82 103.43,39.82 103.71,40.1 CPU1.BA7
GSEN2_INT2: length 106
  TOP w0.102: v2(178.56,40.5) 178.36,40.5 v1(178,40.86) 177.6,41.27 177.21,41.27 176.91,41.57 U7001.11
  L3 w0.102: v2(180.19,10.25) 181.74,11.8 181.74,14.72 182.4,15.38 182.4,16.43 180.77,18.06 180.77,19.87 182.83,21.93 182.83,22.85 183.34,23.36 183.34,24.43 182.22,25.54 182.22,29.51 181.23,30.5 181.23,32.83 180.64,33.42 180.64,35.35 179.07,36.92 179.07,37.94 178.99,38.02 178.99,40.07 v2(178.56,40.5)
  BOTTOM w0.102: R7013.2 R7010.2 123.72,5.69 123.72,3.13 123.49,2.91 123.49,1.84 123.84,1.49 126.11,1.49 126.64,2.02 126.64,2.61 128.27,4.23 128.27,6.37 131.52,9.62 134.19,9.62 135.66,11.09 140.16,11.09 141.25,12.18 171.27,12.18 172.77,10.68 179.75,10.68 v2(180.19,10.25)
GSEN2_INT2_C: length 122.7
  TOP w0.102: R6926.2 41.53,35.46 v1(42.23,36.16) 42.22,36.16 42.55,36.49 v2(45.72,36.49) ; R2026.2 95.31,24.98 v2(95.96,24.98) 96.32,24.98 97.53,26.2 98.4,26.2 98.57,26.03 98.57,24.99 100.1,23.46 100.1,21.66 100.94,20.82 101.19,20.82 101.75,20.26 110.72,20.26 111,19.98 111.3,19.98 111.83,19.45 111.83,18.97 112.19,18.61 112.19,18.12 112.82,17.49 120.54,17.49 121.82,16.22 121.82,15 119.61,12.79 v2(119.61,12.69)
  L3 w0.102: v2(45.72,36.49) 45.64,36.41 45.64,27.65 46.3,26.99 46.3,24.06 46.85,23.51 46.85,23.5 47.62,22.72 47.62,22.5 49.35,20.77 51.99,20.77 54.25,18.51 71.58,18.51 73.71,20.64 80.77,20.64 81.46,21.33 83.82,21.33 84.48,21.99 87.86,21.99 88.77,21.07 91.54,21.07 92.23,21.76 92.95,21.76 94.51,23.32 94.51,23.91 95.59,24.98 v2(95.96,24.98)
  BOTTOM w0.102: v2(119.61,12.69) 118.67,12.69 117.65,11.68 117.65,10.68 119.73,8.6 120.34,8.6 121.41,7.54 123.19,7.54 123.82,6.9 R7010.1
GSEN2_INT2_C_HUB: length 3.5
  TOP w0.102: R6926.1 41.9,34.57 42.26,34.21 v1(42.26,33.7) 42.26,33.29 42.16,33.19 41.63,33.19 41.41,32.98 U6901.38
GSEN2_INT2_ISH: length 29.3
  TOP w0.102: v2(93.65,24.22) 94.33,24.91 R2026.1
  BOTTOM w0.102: CPU1.AY7 104.3,40.16 104.09,40.37 102.91,40.37 101.95,39.41 v1(99.36,39.41) 97.03,39.41 91.74,34.13 91.74,30.86 92.69,29.91 93.55,29.91 94.03,29.43 94.03,28.77 92.53,27.27 92.53,24.65 92.96,24.22 v2(93.65,24.22)
GSEN_INT1: length 150.9
  TOP w0.102: v2(45.11,23.41) v1(45.11,22.78) 45.11,22.32 43.91,21.12 43.13,21.12 42.21,22.04 R6921.2 ; v2(95.88,23.71) 95.81,23.64 95.29,23.64 R2023.2
  L3 w0.102: v2(59.94,89.17) 59.1,89.17 57.94,90.34 52.83,90.34 52.45,89.96 52.04,89.96 51.59,90.42 49.73,90.42 49.5,90.64 48.82,90.64 46.84,88.66 46.84,85.61 47.85,84.59 47.85,73.55 45.01,70.7 45.01,65.41 45.74,64.68 45.74,38.52 44.4,37.18 44.4,35.2 44.65,34.94 44.65,27.6 44.17,27.12 44.17,24.22 44.98,23.41 v2(45.11,23.41) 45.11,22.57 46.17,21.51 47.65,21.51 48.84,20.31 51.87,20.31 54.23,17.95 71.6,17.95 73.89,20.24 80.97,20.24 81.66,20.92 84.02,20.92 84.68,21.58 87.58,21.58 88.49,20.67 91.74,20.67 92.4,21.33 93.16,21.33 95.55,23.71 v2(95.88,23.71)
  BOTTOM w0.102: TCBD1.9 59.15,92.71 60.32,91.53 60.32,89.55 v2(59.94,89.17)
GSEN_INT1_HUB: length 4.6
  TOP w0.102: R6921.1 41.77,23.71 41.32,23.71 40.87,24.17 v1(40.64,24.17) 40.05,24.17 39.7,24.53 39.11,24.53 38.92,24.73 U6901.18
GSEN_INT1_ISH: length 28.5
  TOP w0.102: R2023.1 93.74,23.59 93.34,23.59 93.14,23.79 v2(92.81,23.79) 92.29,23.79 v1(92.24,23.74)
  BOTTOM w0.102: v2(92.81,23.79) 92.17,24.43 92.17,28.85 91.79,29.23 91.79,30.5 91.54,30.75 91.54,34.37 96.93,39.77 102.03,39.77 102.87,40.61 104.14,40.61 104.26,40.72 CPU1.BA8
GSEN_INT2: length 150.3
  TOP w0.102: R2024.2 95.49,24.35 v2(95.91,24.35) ; v2(44.91,24.1) 44.91,23.94 44.68,23.71 44.68,22.22 43.94,21.48 43.41,21.48 v1(43.41,21.48) 43.38,21.48 43.1,21.76 R6922.2
  L3 w0.102: v2(95.91,24.35) 95.88,24.35 93.06,21.53 92.3,21.53 91.64,20.87 88.67,20.87 87.76,21.78 84.58,21.78 83.92,21.12 81.56,21.12 80.87,20.44 73.79,20.44 71.51,18.15 54.32,18.15 51.96,20.51 48.94,20.51 47.67,21.78 46.2,21.78 45.54,22.44 45.54,23.77 45.21,24.1 v2(44.91,24.1) 44.37,24.63 44.37,27.02 44.85,27.5 44.85,35.03 44.6,35.28 44.6,37.08 46,38.47 46,64.71 45.21,65.5 45.21,70.6 48.06,73.45 48.06,84.67 47.04,85.69 47.04,88.56 48.92,90.44 49.4,90.44 49.63,90.21 51.48,90.21 51.94,89.75 52.55,89.75 52.93,90.14 57.83,90.14 59.23,88.74 60.15,88.74 v2(60.6,89.2)
  BOTTOM w0.102: TCBD1.10 59.65,92.69 60.65,91.69 60.65,89.24 v2(60.6,89.2)
GSEN_INT2_HUB: length 5.5
  TOP w0.102: U6901.19 39.41,24.91 39.59,24.74 39.79,24.74 40,24.53 40.82,24.53 41.43,23.92 42.59,23.92 42.85,24.17 v1(43,24.17) 43.1,24.07 R6922.1
GSEN_INT2_ISH: length 27.4
  TOP w0.102: v2(93.14,24.65) 93.14,24.1 93.44,23.79 94.04,23.79 R2024.1
  BOTTOM w0.102: CPU1.BB7 102.92,40.1 101.8,38.98 96.9,38.98 91.95,34.03 91.95,30.95 92.78,30.12 93.63,30.12 94.23,29.52 94.23,27.25 92.78,25.8 92.78,25.01 v2(93.14,24.65)
GSENSOR_CS: length 4.3
  TOP w0.127: U7001.2 178.59,42.52 v1(178.99,42.92) 178.99,43.14 179.7,43.85 179.7,45.15 179.92,45.37 R7006.1
GSENSOR_SDO: length 5.2
  TOP w0.127: U7001.3 178.51,43.01 179.45,43.96 179.45,44.39 v1(179.21,44.63) 178.77,45.08 R7007.2 178.24,45.32 177.68,45.88 R7005.2
GYRO_DRDY: length 160.3
  TOP w0.102: v1(41.02,36.36) 40.69,36.36 v2(40.44,36.11) R6924.2
  L3 w0.102: v2(102.73,18.94) 101.99,18.2 100.13,18.2 98.73,16.81 88.49,16.81 88.31,16.98 86.64,16.98 86.52,17.1 79.59,17.1 76.91,14.42 71.22,14.42 70.84,14.8 65.91,14.8 65.82,14.89 63.21,14.89 61.67,16.43 53.44,16.43 51.15,18.71 46.38,18.71 41.82,23.27 41.82,25.35 42.44,25.98 42.44,33.57 40.44,35.58 v2(40.44,36.11) 40.69,36.11 42.39,37.81 42.39,42.42 42.53,42.56 42.53,44.09 43.61,45.17 43.61,53.41 43.99,53.79 43.99,62.22 43.39,62.82 43.39,70.08 47.34,74.03 47.34,84.46 46.43,85.38 46.43,88.89 48.87,91.33 54.53,91.33 55.29,90.57 58.19,90.57 59.05,89.7 60.73,89.7 v2(61.26,89.17)
  BOTTOM w0.102: TCBD1.12 60.65,92.11 61.2,91.56 61.2,89.23 v2(61.26,89.17) ; R2028.2 102.73,19.14 v2(102.73,18.94)
GYRO_DRDY_HUB: length 2.4
  TOP w0.102: R6924.1 41.05,33.96 v1(41.05,33.64) 40.92,33.51 U6901.39
GYRO_DRDY_ISH: length 33.9
  TOP w0.102: v2(102.36,21.3) 102.36,21.45 v1(102.69,21.78)
  L3 w0.102: v2(102.36,21.3) 102.23,21.17 101.09,21.17 100.76,21.51 100.76,24.05 102.28,25.57 104.57,25.57 106.88,27.88 106.88,31.66 107.71,32.48 107.71,32.49 108.23,33.01 108.23,35.2 105.9,37.52 105.9,38.61 105.42,39.09 105.42,42.8 106.3,43.68 107.54,43.68 107.95,44.08 v2(108.03,44.08)
  BOTTOM w0.102: CPU1.AP13 108.35,43.76 v2(108.03,44.08) ; v2(102.36,21.3) 102.28,21.23 R2028.1
GYRO_INT: length 223.1
  TOP w0.102: v1(122.76,2.86) v2(122.35,3.27)
  L3 w0.102: v2(122.35,3.27) 121.49,3.27 120.47,4.28 120.47,5.37 117.18,8.65 116.65,8.65 113.07,12.23 111.9,12.23 111.69,12.03 110.49,12.03 110.29,12.23 105.25,12.23 104.61,12.87 101.28,12.87 100.54,12.13 94.97,12.13 94.54,12.56 86.79,12.56 79.2,4.97 65.76,4.97 63.78,6.95 61.83,6.95 58.93,9.85 58.93,10.76 58.14,11.55 52.14,11.55 52.12,11.52 52.04,11.52 50.93,10.41 47.34,10.41 45.46,12.28 44.27,12.28 41.63,14.93 38.35,14.93 36.73,16.55 36.73,18.63 37.65,19.56 37.65,23.73 33.76,27.62 33.76,34.61 32.51,35.85 32.51,36.21 32.09,36.63 28.98,36.63 27.38,38.23 27.38,38.43 27.38,42.16 25.53,44.01 25.53,45.11 26.41,46 26.41,48.05 27.3,48.94 27.3,49 27.3,49.6 28.13,50.43 28.13,52.35 29.4,53.62 29.4,65.41 33.89,69.9 33.89,79.3 35,80.41 35,85.08 33.08,87 33.08,90.75 33.08,90.95 33.73,91.59 33.73,93.67 33.37,94.02 33.37,94.25 v2(33.38,94.25)
  BOTTOM w0.102: v2(33.38,94.25) 33.37,94.25 33.37,94.4 34.39,95.41 37.57,95.41 38.99,94 41.88,94 42.75,93.13 47.24,93.13 48.03,92.35 53.26,92.35 54.81,93.9 59.95,93.9 60.15,93.7 TCBD1.11 ; R7002.2 121.66,1.86 R7003.2 122.13,2.57 122.35,2.79 v2(122.35,3.27)
GYRO_INT_C: length 122.7
  TOP w0.102: v2(128.7,6.19) 127.96,6.19 127.33,6.82 126.57,6.82 122.27,11.12 122.27,16.47 120.79,17.95 113.4,17.95 112.6,18.75 112.6,18.81 112.24,19.17 112.24,19.63 111.49,20.39 111.18,20.39 110.9,20.67 108.18,20.67 107.49,21.35 103.94,21.35 103.26,20.67 101.95,20.67 101.39,21.23 101.18,21.23 100.51,21.9 100.51,23.63 98.98,25.16 98.98,26.2 98.54,26.64 96.84,26.64 96.45,26.25 v2(95.96,26.25) 95.68,26.53 R2027.2 ; R6923.2 43.99,22.44 44.45,22.9 44.45,24.27 44.8,24.63 45.52,24.63 v1(45.74,24.4) 46.28,24.4 v2(46.73,24.86)
  L3 w0.102: v2(95.96,26.25) 95.48,26.25 94.08,24.86 94.08,24.04 93.83,23.79 93.47,23.79 93.22,23.54 93.21,23.54 92.99,23.31 92.61,23.31 92,22.7 88.87,22.7 88.64,22.93 84.05,22.93 83.42,22.29 81.02,22.29 80.47,21.73 72.26,21.73 70.8,20.27 69.45,20.27 68.78,20.95 67.82,20.95 67.03,20.16 66.5,20.16 65.25,18.91 54.53,18.91 52.2,21.25 49.48,21.25 48.03,22.7 48.03,23.56 47.19,24.4 47.19,24.4 46.94,24.65 v2(46.73,24.86)
  BOTTOM w0.102: R7003.1 121.35,3.46 121.11,3.22 121.11,1.68 121.52,1.26 126.52,1.26 128.7,3.44 v2(128.7,6.19)
GYRO_INT_C_HUB: length 6.7
  TOP w0.102: U6901.20 39.92,24.92 40.1,24.73 40.9,24.73 41.51,24.12 42.44,24.12 42.92,24.6 v1(44.19,24.6) 44.19,23.94 43.99,23.74 R6923.1
GYRO_INT_ISH: length 26.9
  TOP w0.102: v2(93.72,25.77) 93.72,26 94.26,26.53 R2027.1
  BOTTOM w0.089: CPU1.AW7 105.24,39.94 105.26,39.92 105.26,39.57 105.02,39.34 104.57,39.34 104.44,39.21 104.29,39.21
  BOTTOM w0.102: 104.29,39.21 104.19,39.21 104.11,39.29 103.83,39.29 103.81,39.26 102.64,39.26 101.55,38.17 v1(99.36,38.17) 96.99,38.17 92.35,33.53 92.35,31.13 92.96,30.52 93.88,30.52 94.74,29.66 94.74,26.79 v2(93.72,25.77)
GYRO_INT_P11: length 4.1
  BOTTOM w0.102: R7002.1 122.63,1.78 122.63,2.53 122.78,2.69 122.78,3.99 D7001.1 122.8,4.54 v1(121.79,4.54)
H_CATERR#: length 1.7
  TOP w0.102: v2(123.59,72.56) 124.12,73.09 TP401.1
  BOTTOM w0.102: v2(123.59,72.56) 123.96,72.19 CPU1.D63
H_CPU_SVIDALRT#: length 6.2
  BOTTOM w0.114: R728.2 129.11,74.16 128.77,73.82 128.45,73.82 127.04,72.41 125.73,72.41 125.45,72.13 CPU1.B63
H_CPU_SVIDCLK: length 5.5
  BOTTOM w0.114: R732.1 130.25,73.35 130,73.6 129.38,73.6 129.13,73.35 128.5,73.35 127.86,72.71 127.71,72.71 127.13,72.13 CPU1.A63
H_CPU_SVIDDAT: length 11.1
  BOTTOM w0.114: R709.1 133.01,72.61 R726.2 132.85,72.81 131.86,72.81 131.81,72.87 131.36,72.87 131.35,72.86 130.08,72.86 129.8,73.13 v1(129.76,73.13) 129.58,73.13 129.31,72.86 128.6,72.86 127.91,72.18 127.53,72.18 127.2,71.85 125.96,71.85 125.94,71.83 124.49,71.83 124.29,72.04 CPU1.D64
H_CPUPWRGD: length 13.3
  TOP w0.127: v2(132.26,76.47) 130.4,74.62 127.36,74.62 126.52,75.46 v2(126.52,76.01)
  BOTTOM w0.127: CPU1.A68 126.02,75.26 126.52,75.76 v2(126.52,76.01) ; v2(132.26,76.47) 132.56,76.47 132.98,76.89 R1714.1 133.07,76.86 EC1701.1 133.97,76.86 134.42,77.31 134.42,78.32 133.93,78.81 TP1705.1
H_PECI: length 88.4
  TOP w0.114: v2(132.31,68.9) 131.14,68.9 129.59,67.35 129.06,67.35 128.82,67.12 128.82,66.94 128.22,66.34 127.43,66.34 126.92,66.84 v2(126.87,66.84) ; v2(177.75,34.38) 177.99,34.14 177.99,34.01 178.36,33.63 178.36,33.63 178.42,33.57 R2437.2
  L6 w0.102: v2(177.75,34.38) 177.16,34.38 175.31,32.53 169.39,32.53 168.1,33.82 165.99,33.82 165.38,33.21 165.3,33.21 164.84,33.21 163.4,34.66 156.56,34.66 155.8,33.9 152.45,33.9 152.37,33.82 148.08,33.82 147.09,34.81 144.7,34.81 140.64,38.88 140.64,41.9 140.46,42.08 140.46,42.18 134.49,48.15 132.41,48.15 131.67,48.89 131.67,51.73 129.54,53.86 v2(129.54,54.04)
  BOTTOM w0.114: v2(126.87,66.84) 126.62,66.84 126.34,67.12 125.97,67.12 CPU1.A54 ; v2(132.31,68.9) 132.87,68.34 132.87,64.97 132.79,64.89 132.79,64.89 131.88,63.97 131.88,59.15 130.15,57.42 v1(130.15,54.96) 130.15,54.3 129.89,54.04 v2(129.54,54.04)
H_PROCHOT#: length 208.5
  TOP w0.089: v2(132.26,77.18) 132.26,77.11 132.74,76.62 132.74,68.67 132.33,68.27 v2(132.31,68.27) ; v2(136.51,37.82) 137.18,37.15 137.18,32.94 138.49,31.63 138.49,30.59 138.81,30.27 PR4455.2 139.18,30.2 139.65,29.73 139.65,28.04 v2(139.3,27.69) ; PG4419.2 143.08,30.09 v2(143.97,29.2) ; PR4669.2 PR4624.2 154.25,104.23 156.79,101.69 v2(157.91,101.69)
  L4 w0.127: v2(143.97,29.2) 143.94,29.2 143.42,28.68 140.28,28.68 139.3,27.7 v2(139.3,27.69) ; v2(132.26,77.18) 133.7,75.73 151.38,75.73 153.51,77.86 158.75,77.86 159.03,77.59 162.43,77.59 167.68,82.83 167.68,95.48 166.04,97.12 164.82,97.12 164.46,97.48 162.34,97.48 158.12,101.69 v2(157.91,101.69) ; v2(136.51,37.82) 135.74,37.05 135.74,35.48 136.16,35.05 138.82,35.05 139.13,34.74 141.65,34.74 142.84,33.56 144.41,33.56 145.64,34.79 148.03,34.79 148.79,34.03 150.16,34.03 v2(150.44,34.31)
  L6 w0.102: v2(128.95,53.79) 128.95,53.43 129.82,52.57 129.82,51.98 131.09,50.71 131.09,48.73 132.21,47.62 134.34,47.62 138.35,43.61 138.35,39.41 136.77,37.82 v2(136.51,37.82) ; v2(150.44,34.31) 152.17,34.31 152.25,34.38 155.6,34.38 156.36,35.14 163.42,35.14 167.87,39.59 170,39.59 170.25,39.34 170.25,39.16 173.73,35.68 174.9,35.68 176.14,36.92 177.42,36.92 179.78,39.29 181.24,39.29 181.34,39.18 183.31,39.18 183.74,39.62 185.62,39.62 185.98,39.26 187.93,39.26 188.26,39.59 188.64,39.59 189,39.23 v2(189.94,39.23)
  BOTTOM w0.089: Q2408.D 191.49,38.17 190.96,38.7 190.47,38.7 v2(189.94,39.23) 189.94,39.45 C2403.1 189.25,40.87 R2418.2 ; R403.1 131.02,76.42 R401.2 132.05,76.98 v2(132.26,77.18) ; v2(132.31,68.27) 132.31,67.71 132.38,67.63 132.38,65.17 131.39,64.18 131.39,59.4 v1(129.79,57.8) 129.64,57.65 129.64,54.78 128.95,54.09 v2(128.95,53.79) ; PR4668.2 157.91,100.99 v2(157.91,101.69) ; v2(143.97,29.2) 143.97,29.63 144.19,29.86 PR4445.2
H_PROCHOT#_R: length 7.5
  BOTTOM w0.089: R403.2 128.85,76.14 128.47,75.76 128.47,74.76 126.69,72.98 125.12,72.98 124.85,73.26 CPU1.C65
H_VCCST_PWRGD: length 250.4
  TOP w0.127: v2(65.71,6.85) v1(65.71,6.29)
  L3 w0.127: v2(109.27,90.52) 120.76,90.52 122.92,88.36 122.92,84.68 122.67,84.44 122.67,77.41 125.24,74.85 125.6,74.85 126.01,75.25 127.13,75.25 127.58,75.71 v2(127.84,75.71) ; v2(65.71,6.85) 65.12,6.85 63.09,8.88 60.96,8.88 59.68,10.16 59.68,11.07 59.56,11.19 59.56,11.19 58.9,11.85 58.9,11.88 58.47,12.31 51.99,12.31 51.86,12.44 51.84,12.44 51.05,13.22 51.05,13.24 51.05,13.25 44.4,13.25 41.96,15.69 38.65,15.69 37.49,16.85 37.49,18.3 38.4,19.22 38.4,24.07 35.1,27.37 35.1,33.74 33.45,35.39 33.45,36.29 32.87,36.87 29.08,36.87 27.62,38.33 27.62,43.29 27.25,43.65 26.34,43.65 25.93,44.06 25.93,45 26.66,45.72 26.66,47.76 28.21,49.31 28.33,49.31 28.55,49.52 28.55,50.44 28.38,50.61 28.38,52.25 29.28,53.15 29.28,53.17 29.64,53.52 29.64,65.29 34.22,69.88 34.22,79.28 35.25,80.31 35.25,85.18 33.32,87.11 33.32,90.85 33.97,91.49 33.97,94.37 v2(34.01,94.4)
  L6 w0.127: v2(56.97,88.74) 57.15,88.74 57.35,88.54 64.64,88.54 65.84,87.34 68.13,87.34 68.13,87.34 68.37,87.34 68.37,87.34 70.99,87.34 71.7,88.05 74.47,88.05 76.86,90.44 77.77,90.44 79.42,88.79 87.65,88.79 88.92,90.06 98.78,90.06 99.67,90.95 106.85,90.95 107.28,90.52 v2(109.27,90.52)
  BOTTOM w0.127: v2(56.97,88.74) 57.41,89.18 57.41,89.63 56.5,90.55 55.97,90.55 54.43,92.09 47.93,92.09 47.14,92.88 42.64,92.88 41.77,93.76 38.89,93.76 37.47,95.17 34.78,95.17 v2(34.01,94.4) ; R1716.2 R1719.1 65.64,6.71 65.66,6.72 65.66,6.8 v2(65.71,6.85) 65.26,7.29 C1711.1 65.02,7.27 EC1708.1 R1722.2 63.3,6.57 62.55,5.82 U1701.4 ; v2(127.84,75.71) 127.94,75.61 127.94,74.81 127.92,74.79 127.92,74.77 127.36,74.21 127.36,74.2 126.63,73.47 126.16,73.47 126.09,73.54 125.74,73.54 125.46,73.26 CPU1.B65
HDA_BITCLK: length 14.2
  TOP w0.089: v1(91.77,46.98) 91.77,47.51 92.18,47.93 RN1902.3 93.06,47.93 v2(93.95,47.74)
  BOTTOM w0.089: v2(93.95,47.74) 93.98,47.77 102.35,47.77 102.36,47.77 102.53,47.77 102.91,48.16 103.3,48.16 103.61,48.47 103.61,48.65 103.79,48.82 103.96,48.83 104.25,48.77 CPU1.AY22
HDA_CODEC_BITCLK: length 99.3
  TOP w0.089: v2(84.3,15.38) 84.26,15.43 84.26,16.03 86.58,18.35 86.58,22.22 83.58,25.22 83.58,41.92 88.38,46.73 EC1901.2 89.57,47.17 90.33,47.93 RN1902.2 ; v2(39.85,17.21) 39.34,16.7 38.22,16.7 38.11,16.82 35.57,16.82 34.39,18 v1(32.08,18) 30.8,18 EC2709.1 30.62,18.18 R2720.1
  L3 w0.127: v2(84.3,15.38) 84.02,15.1 83.87,15.1 83.18,14.42 82.27,14.42 80.52,12.67 78.46,12.67 77.93,12.13 76.78,12.13 75.47,10.82 71.11,10.82 70.25,11.69 63.02,11.69 62.75,11.95 62.74,11.95 60.55,14.14 52.49,14.14 50.19,16.44 45.25,16.44 44.38,17.31 43.83,17.31 40.05,17.31 40,17.26 39.9,17.26 v2(39.85,17.21)
HDA_CODEC_SDIN0: length 6.7
  TOP w0.089: R2718.2 32.03,19.24 31.82,19.04 v1(31.42,19.04) 31.19,19.04 30.83,19.4 27.61,19.4 26.72,18.51 HDA27.10
HDA_CODEC_SDOUT: length 99.5
  TOP w0.089: v2(83.39,15.38) 83.39,17.26 83.87,17.75 83.87,18.37 85.89,20.4 85.89,22.24 83.11,25.03 83.11,42.12 89.57,48.58 RN1902.1 ; R2719.1 EC2708.1 30.57,20.45 30.78,20.67 33.73,20.67 v1(34.06,20.34) 36.14,18.25 38.91,18.25 v2(39.39,17.77)
  L3 w0.127: v2(39.39,17.77) 39.77,17.77 39.83,17.82 43.62,17.82 44.17,17.82 44.59,17.82 45.47,16.95 50.4,16.95 52.7,14.65 60.78,14.65 63.23,12.2 76.01,12.2 76.45,12.64 77.7,12.64 78.23,13.17 80.08,13.17 80.53,13.62 80.53,14.48 81.39,15.33 83.34,15.33 v2(83.39,15.38)
HDA_CODEC_SYNC: length 105.1
  TOP w0.089: HDA27.9 26.73,18.11 27.48,18.86 27.64,18.86 28.02,18.49 28.4,18.49 28.84,18.93 30.62,18.93 31.06,18.48 34.57,18.48 35.77,17.29 v1(37.21,17.29) 38.3,17.29 38.4,17.19 v2(39.06,17.19) ; v2(84.61,14.82) 84.61,15 84.73,15.12 84.73,15.83 87.05,18.15 87.05,23.2 86.49,23.77 86.49,25.85 84.05,28.29 84.05,41.62 88.64,46.22 91.74,46.22 92.35,46.83 R1908.1
  L3 w0.127: v2(39.06,17.19) 39.5,16.76 44.09,16.76 44.92,15.93 49.98,15.93 52.28,13.63 60.32,13.63 62.81,11.14 66.04,11.14 66.47,10.71 67.41,10.71 67.98,10.14 75.53,10.14 77.01,11.62 78.15,11.62 78.69,12.16 82.21,12.16 84.61,14.55 v2(84.61,14.82)
HDA_RST#: length 13.3
  TOP w0.089: R1911.2 94.12,45.97 EC1902.1 94.74,45.99 v2(94.79,46.04) 95.02,45.81 v1(95.02,45.45)
  BOTTOM w0.089: v2(94.79,46.04) 96.44,46.7 99.52,47.38 102.64,47.38 103.06,47.8 103.49,47.8 103.86,48.17 104.11,48.28 104.57,48.3 104.74,48.3 CPU1.AW22
HDA_RST#_R: length 1.6
  TOP w0.089: R1911.1 91.97,45.15 TP1903.1
HDA_SDIN0: length 108.1
  TOP w0.089: v2(90.96,45.79) 90.9,45.74 88.85,45.74 84.52,41.41 84.52,28.5 86.97,26.05 86.97,23.96 87.52,23.41 87.52,17.92 85.22,15.61 v2(85.22,15.38) ; v2(38.61,17.67) 38.5,17.77 35.95,17.77 v1(35.42,18.29) 34.78,18.94 34.77,18.94 34.47,19.24 R2718.1
  L3 w0.127: v2(38.61,17.67) 39.32,18.38 44.88,18.38 45.81,17.45 50.63,17.45 52.93,15.16 61.01,15.16 63.27,12.89 66.77,12.89 67.24,13.36 70.45,13.36 70.66,13.15 77.47,13.15 80.16,15.84 84.76,15.84 v2(85.22,15.38)
  BOTTOM w0.089: CPU1.BA21 103.93,47.99 103.57,47.62 103.13,47.62 102.69,47.18 99.58,47.18 98.7,46.3 96.24,46.3 95.07,45.13 91.57,45.13 91.13,45.56 91.13,45.61 v2(90.96,45.79)
HDA_SDOUT: length 15
  TOP w0.089: R1909.2 93.27,49.48 v2(93.27,48.61) ; R1909.2 92.57,49.17 RN1902.4 ; R1909.2 93.08,50.17 92.91,50.33 91.43,50.33 v1(91.38,50.28)
  BOTTOM w0.089: CPU1.BB22 102.83,48.31 102.77,48.28 102.18,47.99 98.02,47.99 94.51,48.66 93.32,48.66 v2(93.27,48.61)
HDA_SPKR_R: length 4.7
  BOTTOM w0.254: D2701.2 29.41,11.58 29.87,11.12 v1(29.87,10.38) 30.49,11 30.49,12.65 30.72,12.88 RN2701.3
HDA_SYNC: length 12.4
  TOP w0.089: R1908.2 94.79,46.83 v2(94.97,46.65) 95.99,45.63 v1(96.23,45.63)
  BOTTOM w0.089: v2(94.97,46.65) 95.02,46.65 95.93,47.57 102.57,47.57 102.99,47.98 103.42,47.98 103.94,48.49 CPU1.BA22
HDD_CT: length 2.6
  TOP w0.102: U6002.6 176.66,17.17 177.06,17.57 v1(177.21,17.57) 177.21,16.79 C6007.1
HDD_DEVSLP: length 98.9
  TOP w0.102: R6002.1 178.18,12.72 178.69,12.21 178.69,11.75 176.99,10.05 166.06,10.05 164.68,11.43 164.68,17.02 162.3,19.4 162.3,21.84 159.89,24.25 159.89,26.46 160.22,26.79 160.22,30.57 v2(160.73,31.08)
  L4 w0.102: v2(160.73,31.08) 160.63,31.18 154.56,31.18 154.13,30.75 151.74,30.75 151.71,30.78 150.52,30.78 149.66,29.91 148.69,29.91 147.09,28.31 144.3,28.31 143.81,27.83 142.04,27.83 142.01,27.8 141.99,27.8 138.86,24.68 137.66,24.68 137.56,24.78 133.5,24.78 133.09,25.19 125.93,25.19 124.64,23.89 122.66,23.89 121.87,24.69 121.87,28.31 v2(120.14,30.04)
  BOTTOM w0.102: v2(120.14,30.04) 120.22,30.04 120.88,30.7 120.88,31.87 121.31,32.3 121.31,33.65 v1(121.36,33.7) 121.36,35.1 121.13,35.33 121.13,36.34 CPU1.J1
HDD_DEVSLP_R: length 3.4
  TOP w0.102: v2(177.01,18.33) 177.04,18.33 177.13,18.24 R6002.2 v1(179.09,18.24)
  BOTTOM w0.102: v2(177.01,18.33) 177.11,18.33 177.34,18.56 177.68,18.56 177.7,18.58 HDD1.13
HDD_EN: length 4.3
  TOP w0.102: R6005.2 172.26,18.24 C6008.1 ; R6005.2 172.5,17.17 U6002.3 ; R6005.2 R6007.2 171.16,17.4 170.74,16.98 v1(170.47,16.98)
HDD_EN_PCH: length 83
  TOP w0.102: v2(161.57,32) 161.57,31.49 161.8,31.26 161.8,30.8 160.42,29.43 160.42,26.7 160.15,26.42 160.15,24.3 162.51,21.94 162.51,19.6 163.12,18.99 167.92,18.99 v1(168.55,18.35) 170.39,16.51 R6007.1
  L4 w0.102: v2(121.61,38.57) 121.59,38.57 120.13,37.11 120.13,32.52 120.95,31.69 120.95,29.89 122.27,28.57 122.27,24.86 122.83,24.3 124.47,24.3 125.76,25.59 133.4,25.59 133.85,26.05 136.22,26.05 136.83,26.66 138.89,26.66 139.86,27.64 139.86,27.74 140.36,28.24 143.61,28.24 144.09,28.72 146.89,28.72 148.49,30.32 149.45,30.32 150.32,31.18 151.92,31.18 151.94,31.16 153.92,31.16 154.43,31.67 160.14,31.67 160.47,32 v2(161.57,32)
  BOTTOM w0.102: v2(121.61,38.57) 121.59,38.57 121.36,38.35 CPU1.J4
HDD_FALL_INT: length 45.7
  TOP w0.102: v1(121.8,6) 121.44,6.37 v2(121.33,6.37)
  L3 w0.102: v2(120.6,34.23) 117.98,31.61 117.98,20.17 119.61,18.55 119.61,18.24 119.61,18.24 119.61,15.87 119.88,15.59 120.57,15.59 120.9,15.26 120.9,15.1 121.96,14.05 121.96,13.54 122.64,12.85 122.64,10.8 124.74,8.7 126.41,8.7 126.46,8.65 126.9,8.65 127.18,8.37 v2(127.18,6.37)
  L4 w0.102: v2(121.33,6.37) 121.41,6.44 127.1,6.44 v2(127.18,6.37)
  BOTTOM w0.089: CPU1.M3 120.13,37.01 120.15,36.8 120.15,36.63 120.19,36.5 120.19,36.01 120.24,35.95 120.24,35.68
  BOTTOM w0.102: R7012.1 121.7,6.81 121.33,6.44 v2(121.33,6.37) ; v2(120.6,34.23) 120.13,34.7 120.13,35.56 120.24,35.68
HDMI_CLK: length 148.3
  TOP w0.102: C5709.1 28.36,67.58 30.5,67.58 31.52,68.6 42.26,68.6 ; 42.26,68.6 44.75,68.6 45.33,69.18 45.77,69.18 v2(45.87,69.08) ; 42.26,68.6 v1(42.26,68.47)
  L6 w0.127: v2(45.87,69.08) 46.15,69.36 47.85,69.36 48.42,69.93 48.42,74.7 47.55,75.58 47.55,75.58 47.52,75.61 47.52,86.3 48.66,87.44 48.66,87.95 50.67,89.96 50.67,91.38 51.82,92.54 55.1,92.54 55.7,93.13 59.18,93.13 59.63,92.69 60.24,92.69 60.57,92.36 64.62,92.36 65.09,92.83 69.3,92.83 70.02,92.1 75.62,92.1 75.89,92.37 79.68,92.37 81.3,90.75 82.09,90.75 82.76,90.09 87.09,90.09 88.82,91.81 92.92,91.81 93.16,91.57 95.26,91.57 96.1,92.41 98.18,92.41 98.7,92.93 106.81,92.93 107.8,91.94 111.1,91.94 112.06,92.9 119.68,92.9 123.96,88.62 123.96,82.48 123.38,81.89 123.38,77.55 124.64,76.29 124.64,74.74 124.83,74.55 124.83,70.16 123.04,68.37 122.72,68.37 v2(122.21,67.85)
  BOTTOM w0.102: v2(122.21,67.85) 121.89,68.17 CPU1.G56
HDMI_CLK#: length 148.4
  TOP w0.102: 44.07,68.83 31.42,68.83 30.41,67.81 28.15,67.81 C5714.1 ; 44.07,68.83 44.65,68.83 45.24,69.41 45.57,69.41 v2(45.87,69.71) ; 44.07,68.83 v1(44.07,68.95)
  L6 w0.127: v2(122.86,67.85) 122.9,67.85 125.09,70.05 125.09,74.66 124.9,74.85 124.9,76.4 123.65,77.66 123.65,81.78 124.23,82.37 124.23,88.74 119.79,93.17 111.95,93.17 110.99,92.21 107.91,92.21 106.92,93.2 98.59,93.2 98.07,92.68 95.98,92.68 95.15,91.84 93.27,91.84 93.03,92.08 88.71,92.08 86.98,90.35 82.87,90.35 82.21,91.01 81.41,91.01 79.79,92.64 75.78,92.64 75.51,92.37 70.13,92.37 69.41,93.1 64.98,93.1 64.51,92.63 60.68,92.63 60.35,92.96 59.74,92.96 59.29,93.4 55.59,93.4 54.99,92.8 51.71,92.8 50.4,91.49 50.4,90.07 48.4,88.06 48.4,87.55 47.25,86.41 47.25,75.5 47.28,75.47 47.28,75.47 48.16,74.59 48.16,70.04 47.74,69.63 45.96,69.63 v2(45.87,69.71)
  BOTTOM w0.102: CPU1.F56 122.54,68.17 v2(122.86,67.85)
HDMI_CLK#_R: length 2.1
  TOP w0.102: U5701.10 25.83,67.64 25.91,67.55 26.08,67.55 26.24,67.71 26.71,67.71 C5714.2
HDMI_CLK#_R_C: length 15
  TOP w0.102: 18.11,67.55 17.19,67.55 R5705.1 16.61,67.48 15.98,67.48 14.4,69.05 14.4,73.95 13.15,75.19 12.67,75.19 12.57,75.3 12.57,75.48 12.47,75.58 HDMI1.12 ; 18.11,67.55 v1(18.11,67.68) ; 18.11,67.55 19.4,67.55 19.48,67.64 U5701.21
HDMI_CLK_R: length 2.1
  TOP w0.102: U5701.9 25.83,67.24 25.91,67.32 26.17,67.32 26.33,67.48 26.71,67.48 C5709.2
HDMI_CLK_R_C: length 15.1
  TOP w0.102: 14.82,68.31 14.17,68.96 14.17,73.85 13.06,74.97 12.67,74.97 12.57,74.86 12.57,74.68 12.47,74.58 HDMI1.10 ; 14.82,68.31 15.88,67.25 16.61,67.25 R5705.2 17.35,67.32 19.4,67.32 19.48,67.24 U5701.22 ; 14.82,68.31 v1(14.73,68.22)
HDMI_DATA0: length 156.7
  TOP w0.102: C5711.1 30.57,64.86 32.35,66.64 42.69,66.64 43.15,66.18 ; v2(44.4,66.11) 44.22,65.93 43.4,65.93 43.15,66.18 ; 43.15,66.18 v1(43.25,66.29)
  L6 w0.127: v2(122.2,66.03) 122.57,65.66 124.3,65.66 125.13,66.49 125.13,68.3 126.43,69.6 126.43,70.57 126.93,71.08 126.93,73.29 128.22,74.57 128.22,75.13 128.51,75.42 128.51,76 128.23,76.28 128.23,78.26 125.82,80.67 125.82,89.41 120.48,94.75 110.96,94.75 110.59,94.38 108,94.38 107.61,94.77 101.2,94.77 100.53,95.44 96.95,95.44 96.28,94.77 79.84,94.77 79.41,95.2 74.51,95.2 74.08,94.77 71.51,94.77 70.8,95.48 63.65,95.48 63.56,95.39 56.21,95.39 55.77,94.95 54.94,94.95 54.42,94.43 49.66,94.43 47.88,92.65 47.88,91.2 46.91,90.24 46.91,89.88 45.26,88.23 45.26,83.3 45.52,83.05 45.52,78.88 44.14,77.51 44.14,67.38 44.66,66.86 44.66,66.37 v2(44.4,66.11)
  BOTTOM w0.102: v2(122.2,66.03) 121.89,66.34 CPU1.G53
HDMI_DATA0#: length 155.9
  TOP w0.102: 31.42,65.39 30.55,64.52 30.55,64.11 30.42,63.97 C5708.1 ; 31.42,65.39 32.44,66.41 42.59,66.41 43.31,65.7 44.17,65.7 v2(44.4,65.47) ; 31.42,65.39 v1(31.52,65.29)
  L6 w0.127: v2(122.84,66.07) 122.98,65.93 124.19,65.93 124.86,66.6 124.86,68.42 126.16,69.71 126.16,70.68 126.67,71.19 126.67,73.4 127.95,74.68 127.95,75.24 128.24,75.53 128.24,75.89 127.96,76.17 127.96,78.15 125.55,80.56 125.55,89.3 120.37,94.48 111.07,94.48 110.7,94.11 107.89,94.11 107.49,94.5 101.09,94.5 100.42,95.18 97.06,95.18 96.39,94.5 79.73,94.5 79.3,94.94 74.62,94.94 74.19,94.5 71.4,94.5 70.69,95.22 63.76,95.22 63.67,95.13 56.32,95.13 55.88,94.68 55.05,94.68 54.53,94.16 49.77,94.16 48.14,92.54 48.14,91.09 47.18,90.13 47.18,89.77 45.53,88.12 45.53,83.41 45.78,83.16 45.78,78.77 44.41,77.4 44.41,67.49 44.93,66.97 44.93,66.01 v2(44.4,65.47)
  BOTTOM w0.102: CPU1.F53 122.54,66.37 v2(122.84,66.07)
HDMI_DATA0#_R: length 4.1
  TOP w0.102: 27.74,64.12 28.01,64.12 28.19,64.3 28.61,64.3 C5708.2 ; 27.74,64.12 v1(27.74,63.97) ; 27.74,64.12 25.91,64.12 25.83,64.04 U5701.1
HDMI_DATA0#_R_C: length 20.8
  TOP w0.102: U5701.30 19.49,64.04 18.88,63.43 18.88,63.31 R5703.2 18.01,63.1 16.34,63.1 16.1,62.86 16.1,62.53 v2(16.38,62.25)
  BOTTOM w0.102: 15.29,63.31 15.77,63.31 16.1,62.98 16.1,62.53 v2(16.38,62.25) ; 15.29,63.31 14.49,63.31 12.85,64.96 12.85,68.13 11.23,69.76 11.23,73.2 HDMI1.9 ; 15.29,63.31 v1(15.29,63.47)
HDMI_DATA0_R: length 4
  TOP w0.102: C5711.2 28.61,64.53 28.1,64.53 27.92,64.35 25.91,64.35 25.83,64.44 U5701.2
HDMI_DATA0_R_C: length 20
  TOP w0.102: U5701.29 19.56,64.44 18.78,63.66 R5703.1 18.01,63.33 16.24,63.33 15.87,62.96 15.87,62.53 v2(15.59,62.25)
  BOTTOM w0.102: 13.8,63.68 14.4,63.08 15.68,63.08 15.87,62.89 15.87,62.53 v2(15.59,62.25) ; 13.8,63.68 v1(13.69,63.57) ; 13.8,63.68 12.62,64.86 12.62,68.04 11,69.66 11,72.71 10.63,73.08 HDMI1.7
HDMI_DATA1: length 148.6
  TOP w0.102: v2(46.66,65.93) 46.45,66.13 46.45,66.49 46.12,66.82 45.13,66.82 44.59,67.35 43.91,67.35 ; 43.91,67.35 v1(43.91,67.48) ; 43.91,67.35 32.05,67.35 30.28,65.57 28.23,65.57 C5712.1
  L6 w0.127: v2(122.22,68.77) 122.68,69.24 122.99,69.24 123.49,69.74 123.49,71.85 124.03,72.38 124.03,73.22 123.92,73.32 123.92,74.82 123.65,75.1 123.09,75.1 122.32,75.86 122.32,83.46 123.19,84.32 123.19,88.28 119.35,92.12 112.42,92.12 111.4,91.1 107.41,91.1 106.36,92.16 99.05,92.16 97.47,90.58 88.71,90.58 87.43,89.3 81.63,89.3 79.36,91.57 76.38,91.57 76.12,91.3 69.73,91.3 68.98,92.05 65.41,92.05 64.93,91.57 60.24,91.57 60.06,91.75 59.17,91.75 58.56,92.36 56.02,92.36 55.33,91.67 52.23,91.67 51.51,90.95 51.51,89.65 49.45,87.6 49.45,86.28 48.31,85.14 48.31,75.91 49.2,75.02 49.2,75.02 49.21,75.01 49.21,69.12 46.56,66.47 46.56,66.03 v2(46.66,65.93)
  BOTTOM w0.102: v2(122.22,68.77) 122.54,69.1 CPU1.F58
HDMI_DATA1#: length 149
  TOP w0.102: v1(45.39,66.46) 45.39,66.59 ; 45.39,66.59 45.03,66.59 44.5,67.12 32.15,67.12 30.37,65.35 28.28,65.35 C5715.1 ; 45.39,66.59 46.03,66.59 46.23,66.39 46.23,66.13 v2(46.02,65.93)
  L6 w0.127: v2(46.02,65.93) 46.29,66.2 46.29,66.58 48.92,69.21 48.92,69.23 48.94,69.26 48.94,74.9 48.93,74.91 48.93,74.91 48.04,75.8 48.04,85.25 49.19,86.39 49.19,87.71 51.24,89.76 51.24,91.06 52.12,91.94 55.22,91.94 55.91,92.63 58.67,92.63 59.28,92.02 60.17,92.02 60.35,91.84 64.82,91.84 65.3,92.32 69.09,92.32 69.84,91.57 76.01,91.57 76.27,91.84 79.47,91.84 81.74,89.56 87.31,89.56 88.6,90.85 97.36,90.85 98.94,92.42 106.47,92.42 107.53,91.37 111.29,91.37 112.31,92.38 119.46,92.38 123.45,88.39 123.45,84.21 122.59,83.35 122.59,75.97 123.2,75.37 123.76,75.37 124.19,74.93 124.19,73.43 124.29,73.33 124.29,72.27 123.76,71.74 123.76,69.63 122.91,68.77 v2(122.87,68.77)
  BOTTOM w0.102: v2(122.87,68.77) 122.87,69.14 122.96,69.23 CPU1.E58
HDMI_DATA1#_R: length 2
  TOP w0.102: U5701.4 25.83,65.24 25.91,65.32 26.7,65.32 C5715.2
HDMI_DATA1#_R_C: length 15.6
  TOP w0.102: v2(15.72,64.21) 16.01,64.51 16.72,64.51 R5704.2 17.41,64.51 18.3,64.51 18.86,65.07 19.37,65.07 19.54,65.24 U5701.27
  BOTTOM w0.102: v2(15.72,64.21) 15.55,64.39 15.55,64.93 14.42,66.05 ; 14.42,66.05 13.64,66.84 13.64,71.42 12.87,72.19 12.24,72.19 HDMI1.6 ; 14.42,66.05 v1(14.53,66.16)
HDMI_DATA1_R: length 2
  TOP w0.102: C5712.2 26.71,65.55 25.91,65.55 25.83,65.64 U5701.5
HDMI_DATA1_R_C: length 16
  TOP w0.102: v2(15.06,64.25) 15.54,64.74 16.75,64.74 R5704.1 17.38,64.74 18.21,64.74 18.77,65.29 19.28,65.29 19.62,65.64 U5701.26
  BOTTOM w0.102: HDMI1.4 12.24,71.97 12.77,71.97 13.41,71.33 13.41,66.74 15.05,65.1 ; 15.05,65.1 15.32,64.83 15.32,64.51 v2(15.06,64.25) ; 15.05,65.1 v1(14.93,64.99)
HDMI_DATA2: length 150.3
  TOP w0.102: v2(45.72,68.32) 45.52,68.11 38.28,68.11 ; v1(38.28,68.24) 38.28,68.11 ; 38.28,68.11 31.8,68.11 30.38,66.69 30.16,66.69 C5707.1
  L6 w0.127: v2(122.81,66.95) 123.34,67.48 123.72,67.48 123.95,67.71 123.95,68.22 125.44,69.7 125.44,71.78 125.73,72.08 125.73,74.3 125.92,74.49 125.92,75.52 125.4,76.04 125.4,76.69 124.76,77.33 124.76,88.97 120.04,93.69 111.53,93.69 111.17,93.34 107.57,93.34 107.19,93.72 100.78,93.72 100.1,94.4 98.32,94.4 97.16,93.25 95.79,93.25 94.95,92.41 93.43,92.41 93.24,92.6 88.34,92.6 88.29,92.56 88.29,92.55 88.22,92.48 86.61,90.87 84.17,90.87 83.64,91.41 83.64,91.89 82.99,92.54 82.26,92.54 81.85,92.94 80.31,92.94 80.11,93.15 75.55,93.15 75.29,92.89 71.08,92.89 70.72,93.25 70.72,94.09 70.37,94.44 65.03,94.44 63.74,93.15 60.89,93.15 60.51,93.53 59.91,93.53 59.57,93.87 59.54,93.87 59.51,93.91 55.38,93.91 54.78,93.31 51.48,93.31 47.97,89.8 47.97,89.42 46.71,88.16 46.71,78.25 45.27,76.82 45.27,68.5 45.46,68.32 v2(45.72,68.32)
  BOTTOM w0.102: CPU1.F55 122.54,67.22 v2(122.81,66.95)
HDMI_DATA2#: length 151.5
  TOP w0.102: v1(40.13,67.76) 40.13,67.89 ; 40.13,67.89 45.52,67.89 v2(45.72,67.68) ; 40.13,67.89 31.89,67.89 30.47,66.46 30.16,66.46 C5710.1
  L6 w0.127: v2(45.72,67.68) 45.01,68.39 45.01,76.93 46.44,78.36 46.44,88.27 47.7,89.53 47.7,89.91 51.37,93.58 54.67,93.58 55.27,94.17 59.62,94.17 59.65,94.14 59.68,94.14 60.02,93.79 60.62,93.79 61.01,93.41 63.63,93.41 64.92,94.71 70.48,94.71 70.99,94.2 70.99,93.36 71.19,93.16 75.18,93.16 75.44,93.41 80.22,93.41 80.42,93.21 81.96,93.21 82.37,92.8 83.1,92.8 83.91,92 83.91,91.52 84.28,91.14 86.5,91.14 88.03,92.66 88.03,92.67 88.23,92.87 93.35,92.87 93.54,92.68 94.84,92.68 95.68,93.51 97.05,93.51 98.21,94.67 100.21,94.67 100.89,93.98 107.3,93.98 107.68,93.6 111.06,93.6 111.42,93.96 120.15,93.96 125.03,89.08 125.03,77.44 125.66,76.8 125.66,76.15 126.19,75.63 126.19,74.38 125.99,74.19 125.99,71.97 125.7,71.67 125.7,69.59 124.22,68.11 124.22,67.6 123.79,67.17 123.7,67.17 v2(123.47,66.94)
  BOTTOM w0.102: CPU1.E55 123.19,67.22 v2(123.47,66.94)
HDMI_DATA2#_R: length 4.1
  TOP w0.102: C5710.2 28.61,66.46 26.84,66.46 26.5,66.12 25.91,66.12 25.83,66.04 U5701.6
HDMI_DATA2#_R_C: length 13.8
  TOP w0.102: U5701.25 19.48,66.04 19.36,66.16 18.81,66.16 R5702.2 18.27,65.75 v2(16.05,65.75)
  L6 w0.127: HDMI1.3 11.17,70.26 11.17,70.25 13.63,67.8 15.28,67.8 16.18,66.89 16.18,65.88 v2(16.05,65.75)
  BOTTOM w0.102: v1(16.66,65.85) 16.56,65.75 v2(16.05,65.75)
HDMI_DATA2_R: length 4.1
  TOP w0.102: U5701.7 25.83,66.44 25.91,66.35 26.4,66.35 26.74,66.69 28.61,66.69 C5707.2
HDMI_DATA2_R_C: length 14.5
  TOP w0.102: v1(15.77,66.89) 15.77,66.76 ; 15.77,66.76 15.93,66.76 16.05,66.64 16.05,66.37 16.44,65.98 17.68,65.98 17.8,66.11 17.8,66.45 17.93,66.58 R5702.1 18.53,66.39 19.43,66.39 19.48,66.44 U5701.24 ; 15.77,66.76 15.59,66.76 15.47,66.64 15.47,66.18 v2(15.42,66.13)
  L6 w0.127: v2(15.42,66.13) 15.67,66.13 15.91,66.37 15.91,66.78 15.17,67.53 13.51,67.53 10.8,70.25 10.52,70.25 HDMI1.1
HDMI_EC_DET#: length 260.9
  TOP w0.102: v2(30.71,9.11) 30.35,9.47 v1(30.35,9.92)
  L3 w0.102: v2(187.12,29.94) 187.12,29.56 188.59,28.08 188.59,27.04 188.85,26.79 188.85,26.79 192.62,23.02 192.62,19.23 189.51,16.12 189.51,15.51 187.96,13.96 187.96,11.6 187.37,11.01 187.37,10.09 187.37,10.08 187.37,9.74 185.67,8.04 174.47,8.04 173.84,7.41 157.23,7.41 155.17,5.35 155.17,3.17 154.38,2.38 153.43,2.38 153.41,2.37 128.85,2.37 128.6,2.62 127.26,2.62 v2(127.07,2.43) ; v2(30.71,9.11) 30.71,11.09 28.75,13.05 28.75,17.54 27.66,18.63 27.66,20.56 25.65,22.57 25.65,24.73 24.86,25.52 22.63,25.52 22.61,25.54 22.61,25.57 23.16,26.13 23.16,26.38 22.2,27.35 22.2,29.28 21.13,30.34 21.13,32.35 19.61,33.87 19.61,35.91 16.91,38.6 16.91,39.92 16.13,40.71 16.13,44.87 17.16,45.9 17.16,57.18 v2(17.96,57.98)
  L4 w0.102: v2(127.07,2.43) 126.49,3.01 125.4,3.01 125.17,3.24 124.53,3.24 124.13,2.84 121.72,2.84 117.27,7.28 114.54,7.28 112.39,5.14 112.39,1.71 111.88,1.2 111.11,1.2 110.93,1.02 103.74,1.02 103.55,1.21 31.65,1.21 30.4,2.46 30.4,7.08 30.71,7.38 v2(30.71,9.11)
  BOTTOM w0.102: v2(187.12,29.94) 187.87,29.19 R2407.1 ; v2(17.96,57.98) 18.01,58.03 R5723.1
HDMI_EC_DET#_C: length 3.2
  BOTTOM w0.102: v1(20.58,57.12) R5721.2 R5723.2 19.56,58.17 Q5704.D
HOST_DEBUG_TX: length 83.2
  TOP w0.102: v2(137.49,7.26) 137.46,7.28 v1(136.35,7.28) 135.82,7.28 R2480.1 ; KBC24.81 184.05,36.24 184.4,36.59 v2(184.4,36.59)
  L4 w0.102: v2(184.4,36.59) 184.4,36.59 184.4,35.53 186.18,33.75 186.18,32.35 185.11,31.28 185.11,28.54 185.72,27.93 185.72,21.83 184.14,20.24 184.14,18.14 183.24,17.24 179.27,17.24 178.1,16.07 177.24,16.07 176.45,15.28 174.83,15.28 173.58,14.04 164.69,14.04 163.88,13.22 156.34,13.22 152.02,8.91 140.18,8.91 139.8,8.53 137.06,8.53 136.68,8.91 v2(136.6,8.91)
  BOTTOM w0.102: DB3.5 135.82,3.56 137.49,5.22 v2(137.49,7.26) 137.49,7.76 136.57,8.68 136.57,8.88 v2(136.6,8.91)
HPD_HDMI_CON: length 23.8
  TOP w0.102: U5701.28 19.33,64.84 v2(19.02,64.53)
  L6 w0.102: v2(19.02,64.53) 18.95,64.61 18.31,64.61 17.7,65.22 17.7,68.75 13.89,72.56 13.89,78.32 12.37,79.85 11.12,79.85 HDMI1.19
  BOTTOM w0.102: v1(18.64,64.99) 18.64,64.91 v2(19.02,64.53) 19.12,64.63 20.1,64.63 R5722.2
HPD_HDMI_CON_C: length 3.8
  BOTTOM w0.102: Q5704.G 18.57,63.32 v1(18.87,63.62) 19.01,63.76 R5722.1
HUB_PA1: length 3.5
  TOP w0.127: R6918.2 R6919.1 33.65,26 v1(34.44,26.79) 34.97,26.79 35.09,26.67 U6901.11
HUB_PA2: length 4.5
  TOP w0.127: U6901.12 34.56,26.17 34.33,25.94 v1(34.33,25.57) 33.88,25.13 33.88,24.53 33.58,24.22 R6916.2 R6917.1
HUB_PA3: length 5.4
  TOP w0.127: R6915.1 R6914.2 35.1,23.69 34.95,23.84 34.49,23.84 34.31,24.02 v1(34.31,24.27) 34.31,24.81 34.88,25.37 U6901.13
HUB_PA4: length 5.4
  TOP w0.127: R6912.2 R6913.1 36.92,23.31 36.92,23.6 36.7,23.82 35.63,23.82 35.53,23.92 v1(35.53,24.14) 35.53,24.5 35.74,24.71 36.8,24.71 36.92,24.82 U6901.14
HUB_PA5: length 3.9
  TOP w0.127: R6910.2 R6911.1 37.77,23.74 37.64,23.87 37.13,23.87 v1(36.83,24.17) 36.83,24.3 37.41,24.89 U6901.15
HUB_PA6: length 4
  TOP w0.127: R6909.1 R6908.2 38.97,23.84 38.38,23.84 v1(38.05,24.17) 37.92,24.3 U6901.16
HW_ACAVIN_NB#: length 34.5
  TOP w0.203: KBC24.21 199.54,38.24 199.92,38.62 v2(199.92,38.78)
  TOP w0.254: v2(180.49,50.54) v1(179.09,50.54) 178.74,50.89 R2475.2 R2474.2
  L3 w0.254: v2(199.92,38.78) 199.92,39.06 199.49,39.49 199.49,41.57 199.16,41.9 199.09,41.9 198.53,42.46 198.53,44.14 198.2,44.47 197.78,44.47 197.7,44.39 191.65,44.39 191.24,43.98 185.34,43.98 185.19,44.14 183.62,44.14 181.13,46.63 181.13,48.25 180.85,48.53 180.85,49.48 v2(180.49,50.54)
I2C0_SCL: length 14.3
  BOTTOM w0.089: CPU1.N3 119.13,37.97 119.3,37.74 119.3,37.57 119.35,37.47 119.35,37.27 119.31,37.19 119.31,36.9 119.35,36.82 119.35,36.62 119.27,36.45 119.27,35.91 119.2,35.84 v1(119.2,31.61) 119.2,29.48 117.71,27.98 RN2007.1 117.71,27.5 117.55,27.35 117.35,27.35 116.81,26.81 116.81,25.67 116.91,25.57 R2020.1
I2C0_SCL_R: length 11.4
  TOP w0.089: AFTP6534.1 131.77,15.89 v2(131.77,16.22) 131.77,16.63 132.18,17.03 132.97,17.03 133.24,17.3 RN6503.3 ; v2(134.54,21.58) 134.11,21.15 R6505.2 133.41,20.62 132.89,20.62 132.51,20.24 v2(132.28,20.24)
  BOTTOM w0.089: v2(132.28,20.24) 132.28,19.88 132.05,19.65 KBBD1.37 132.05,16.5 v2(131.77,16.22) ; Q6504.6 134.43,21.87 134.54,21.76 v2(134.54,21.58)
I2C0_SCL_TCH_PAD: length 40.5
  TOP w0.089: R6505.1 132.56,21.15 v2(132.41,21.3) 131.04,22.67 128.82,22.67 126.99,20.84 119.31,20.84 117.74,22.41 v1(117.59,22.41) 116.2,23.79 v2(116.17,23.79)
  L4 w0.127: v2(116.17,23.79) 116.23,23.79 117.42,24.98 117.42,31.09 116.46,32.05 116.46,38.17 116.79,38.5 116.79,38.91 v2(116.34,39.35)
  BOTTOM w0.089: EC6503.1 132.14,21.04 v2(132.41,21.3) 132.66,21.3 132.76,21.4 133.07,21.4 133.12,21.45 133.98,21.45 134.43,21.01 Q6504.1 ; CPU1.U6 116.57,39.12 v2(116.34,39.35)
I2C0_SDA: length 15.3
  BOTTOM w0.089: CPU1.M4 119.49,38.09 119.49,37.6 119.53,37.51 119.53,37.23 119.49,37.15 119.49,36.95 119.53,36.86 119.53,36.58 119.45,36.41 119.45,35.93 119.47,35.91 119.47,33.12 119.61,32.99 v1(119.61,32.81) 119.61,29.51 118.36,28.26 RN2007.2 118.36,27.24 118.18,27.07 117.45,27.07 117.09,26.71 117.09,25.77 117.78,25.09 R2021.1
I2C0_SDA_R: length 14.4
  TOP w0.089: R6506.2 134.71,22.01 134.97,21.76 134.97,21.41 133.91,20.35 133.01,20.35 132.74,20.08 v2(132.74,19.78) ; AFTP6535.1 132.97,15.66 v2(132.41,16.22) 132.41,16.25 132.92,16.76 133.07,16.76 133.81,17.49 133.81,18.15 133.63,18.33 RN6503.4
  BOTTOM w0.089: v2(132.41,16.22) 132.55,16.36 KBBD1.36 132.55,19.59 v2(132.74,19.78) 132.74,19.78 133.13,20.17 Q6504.3
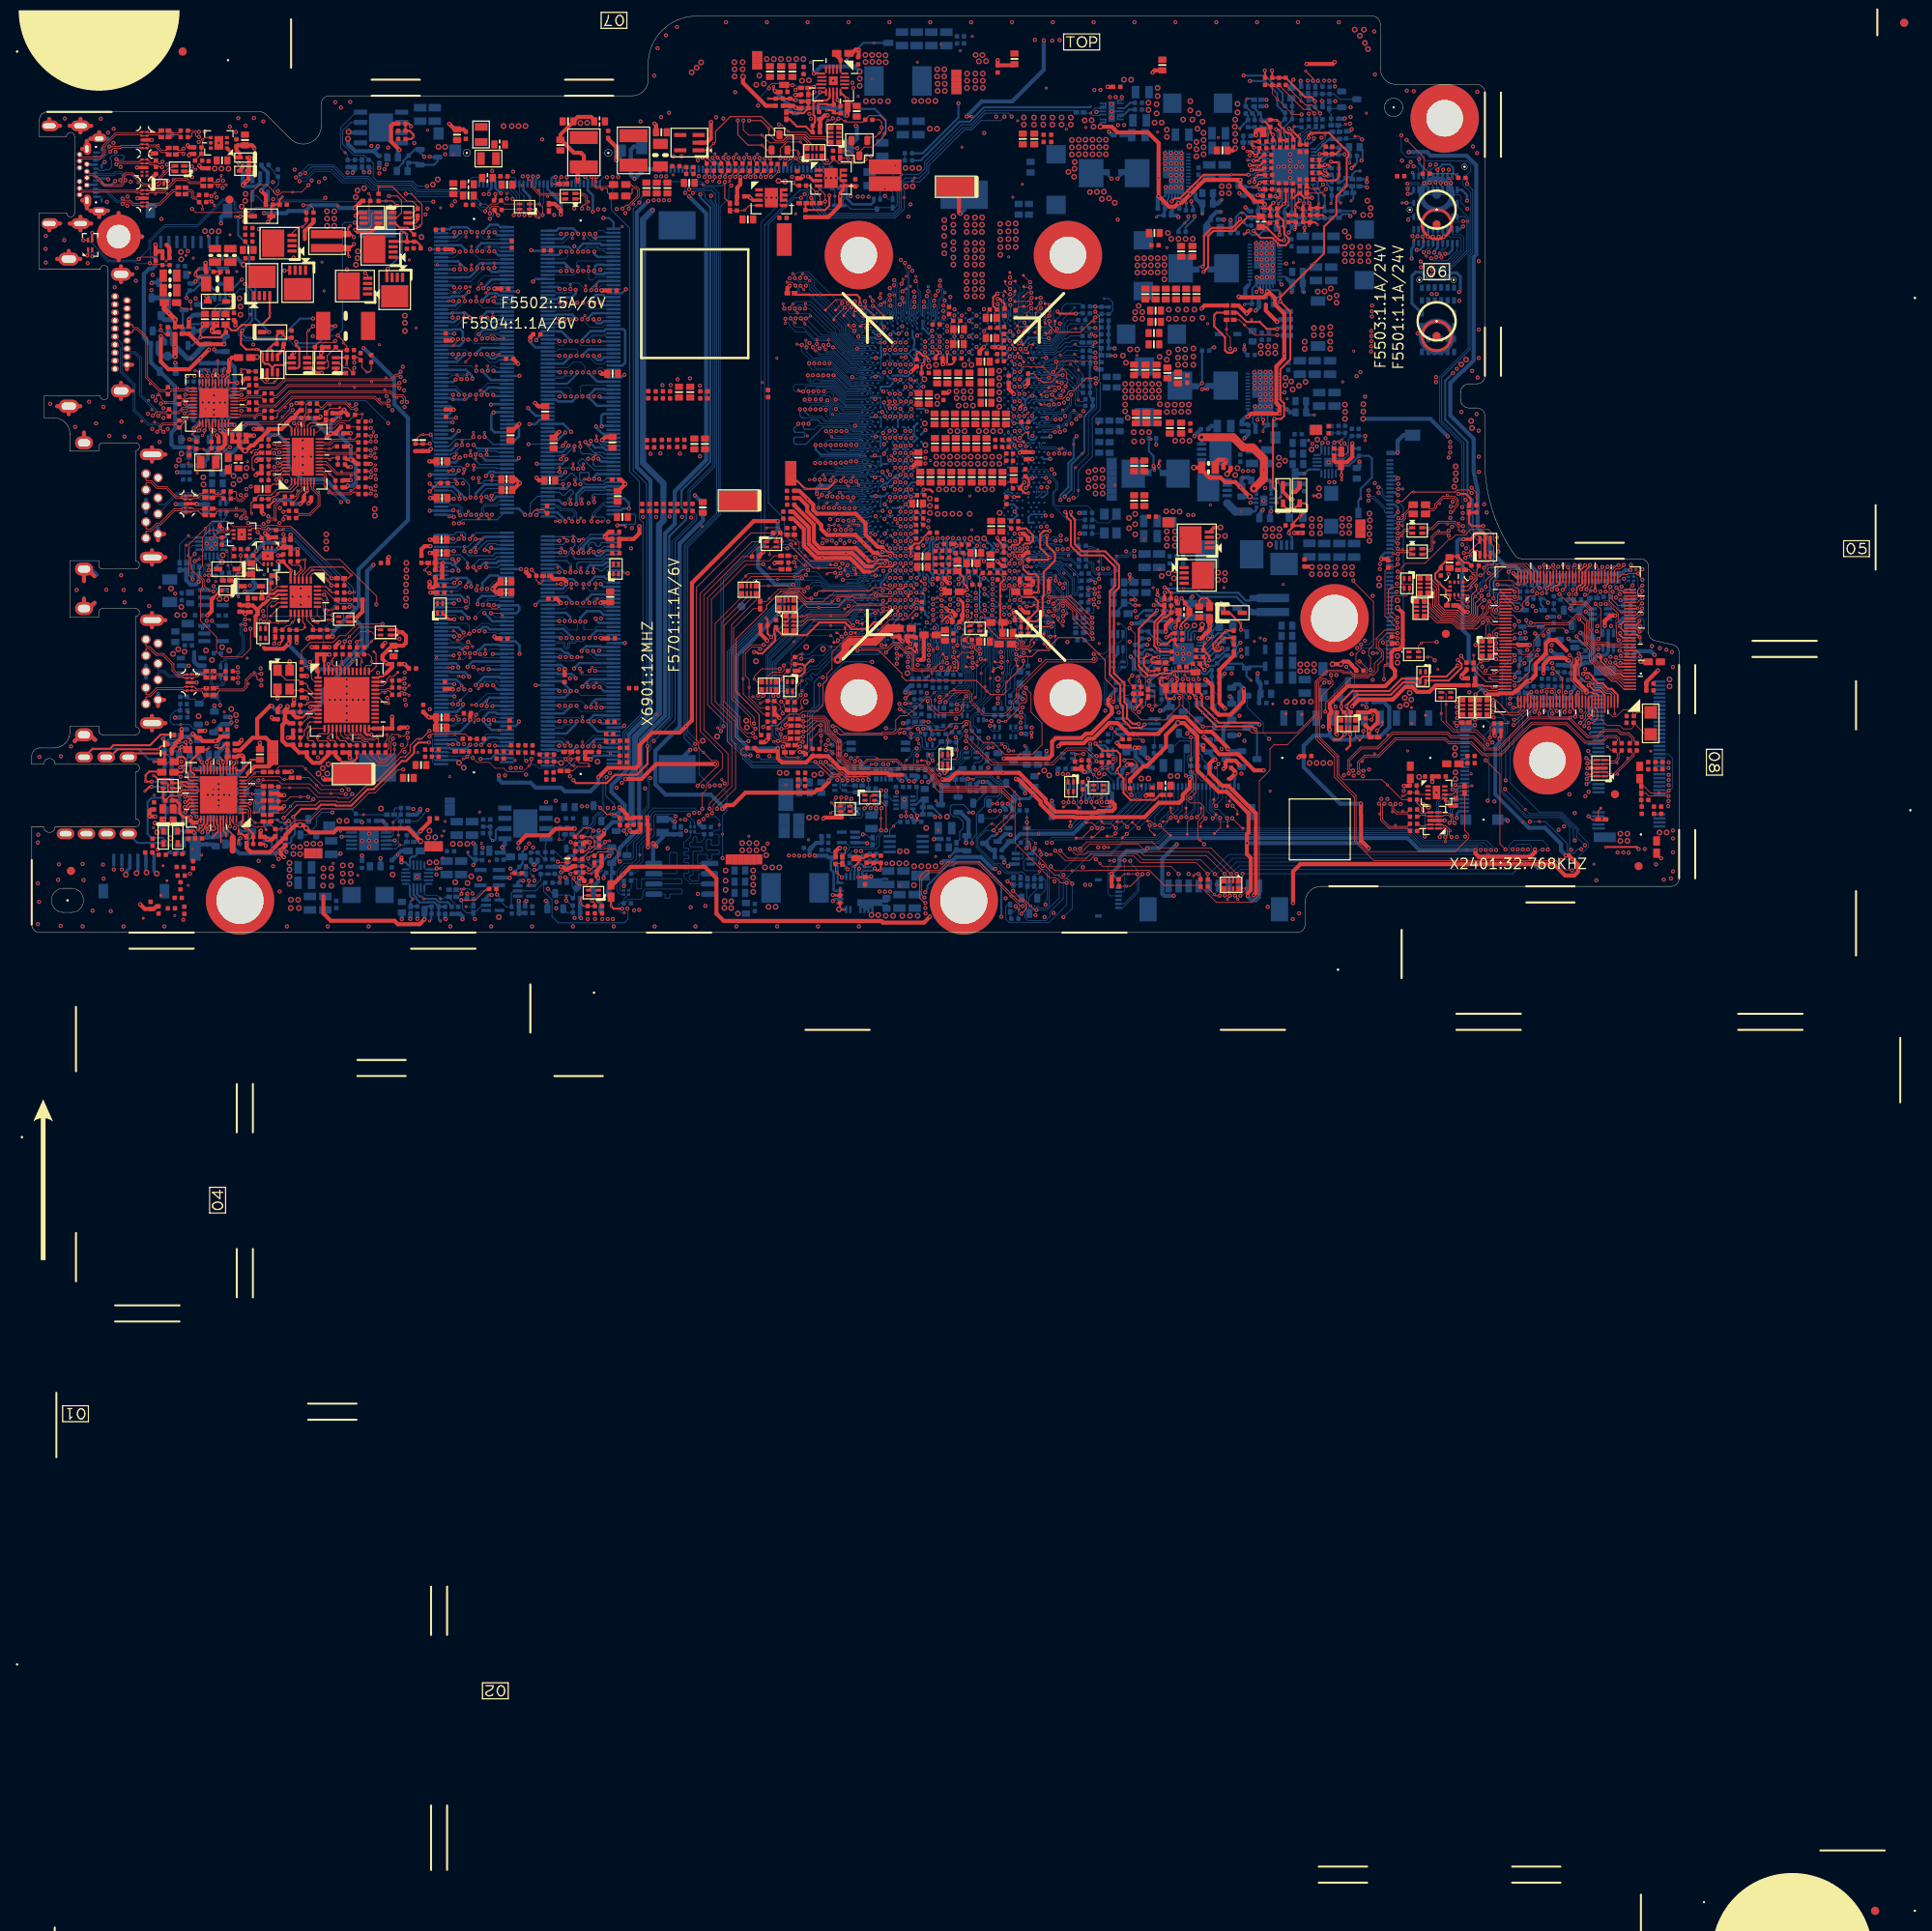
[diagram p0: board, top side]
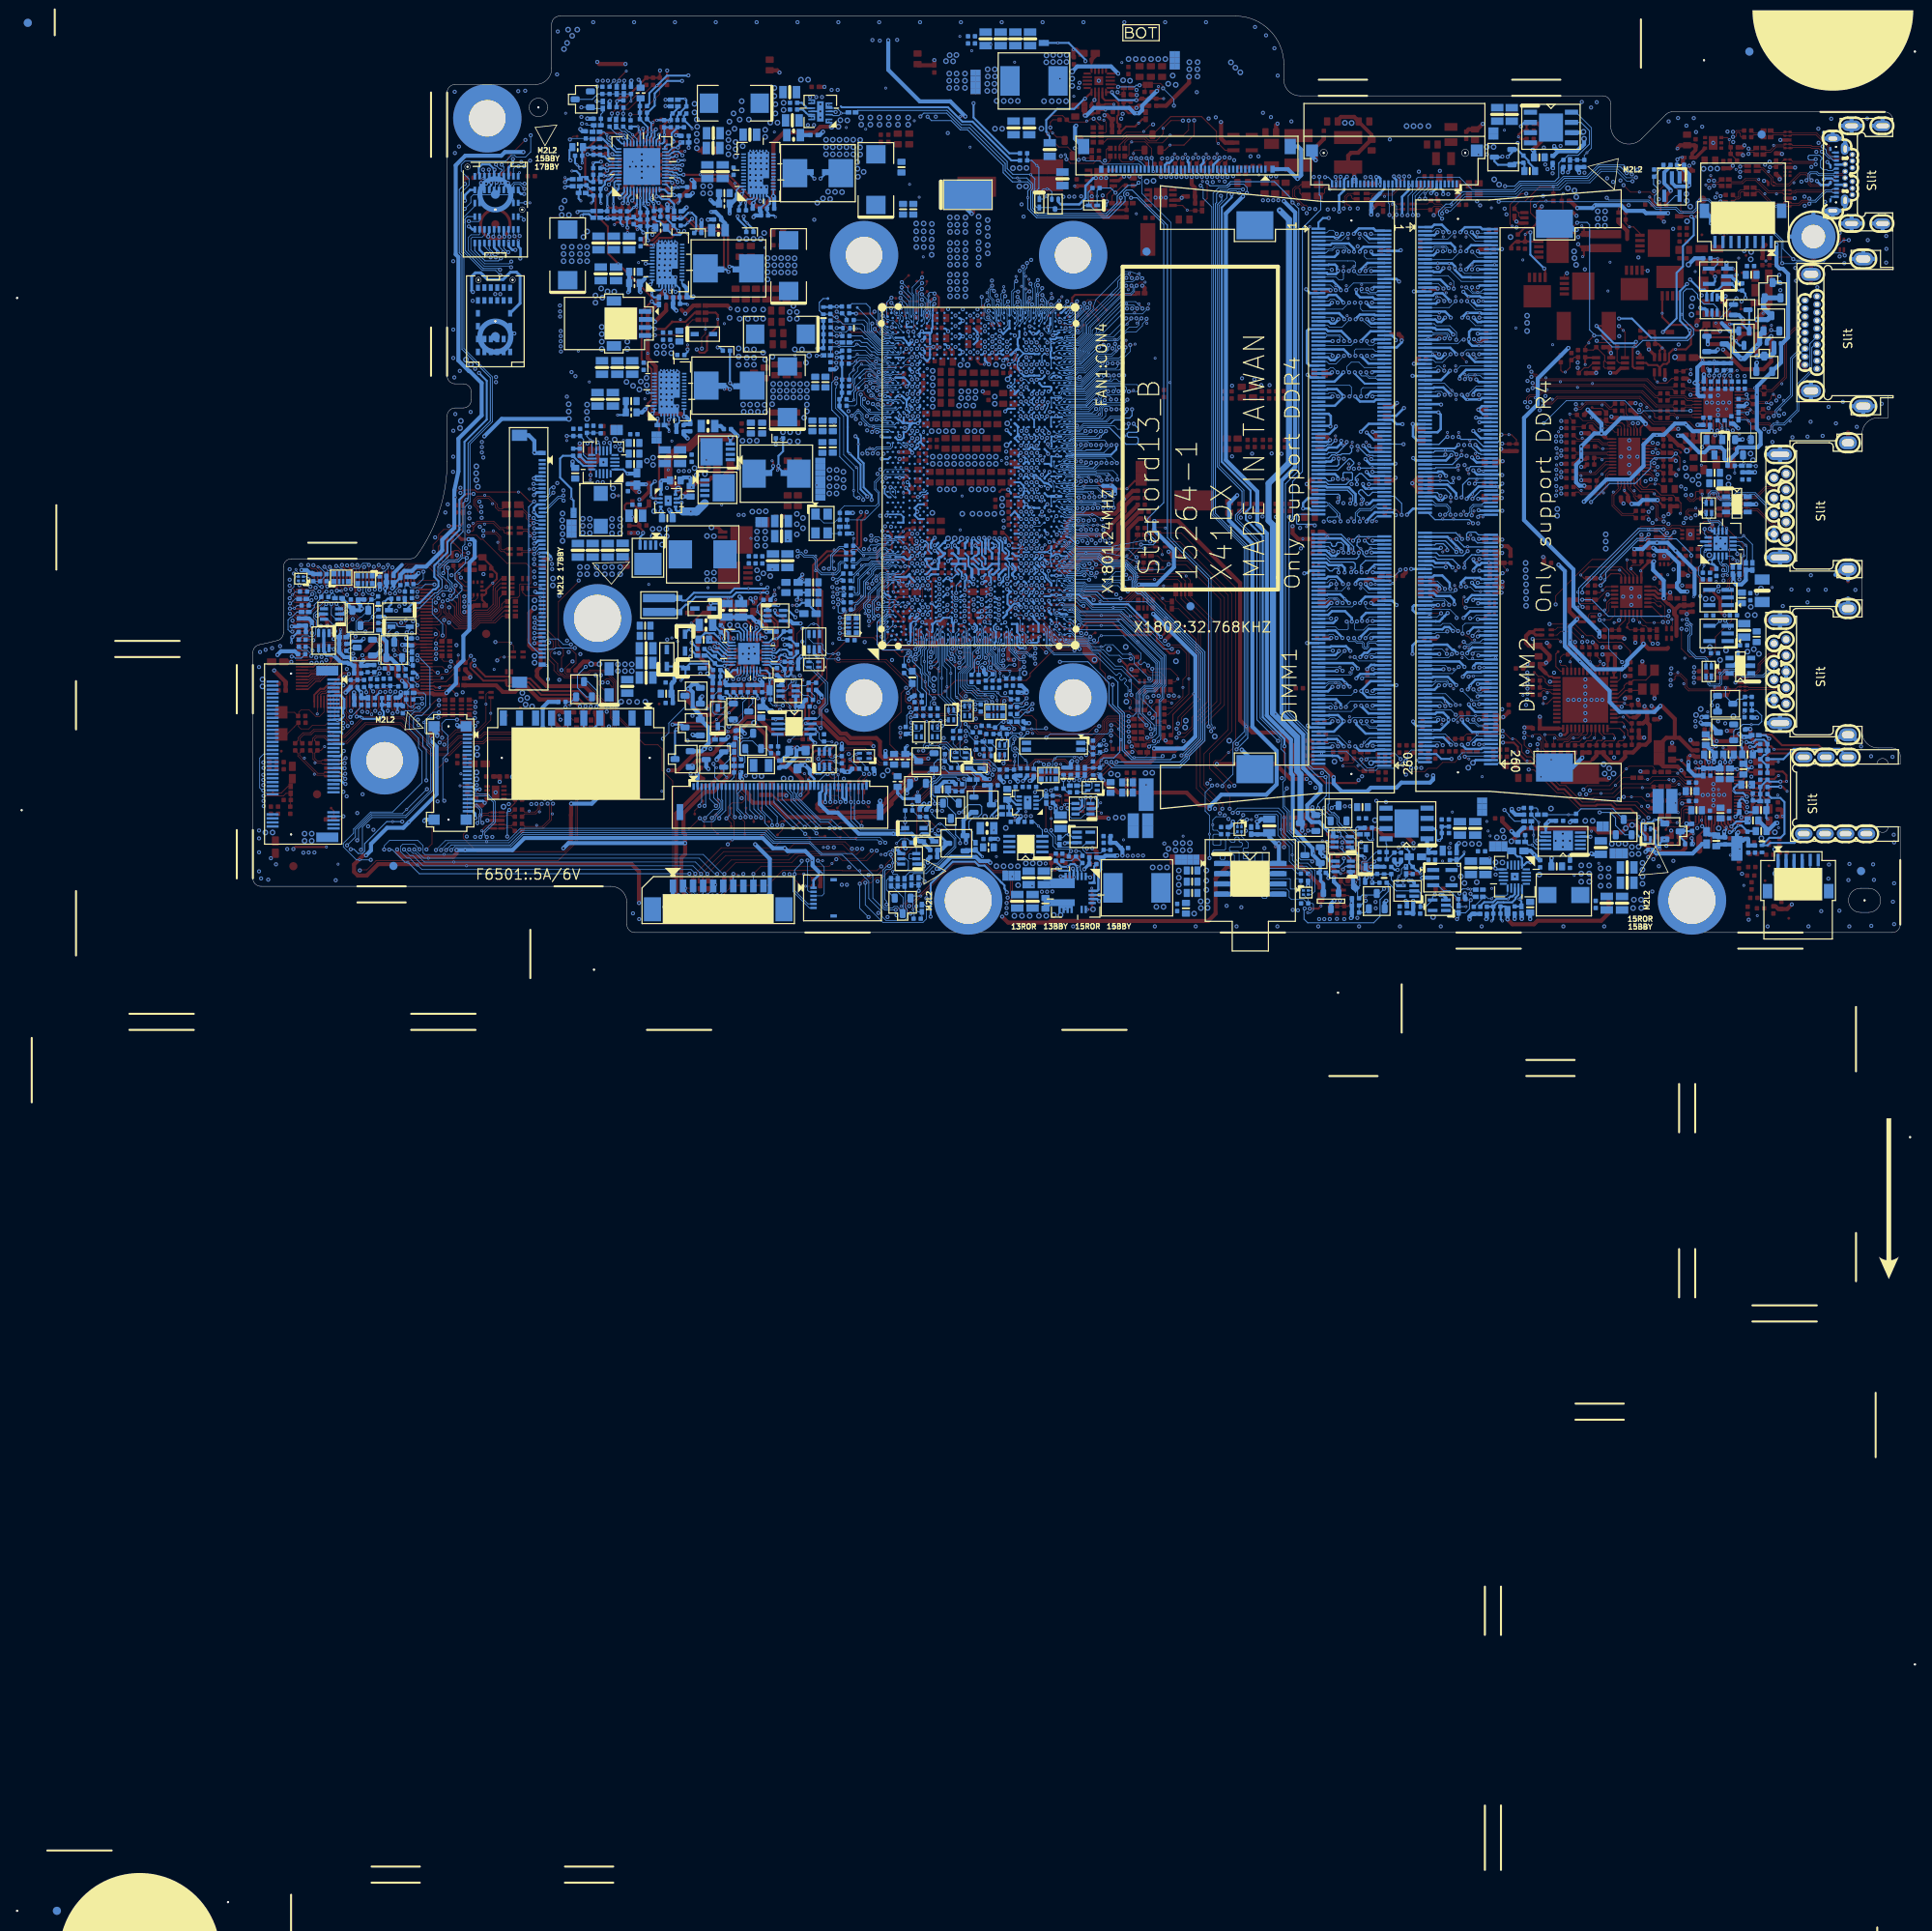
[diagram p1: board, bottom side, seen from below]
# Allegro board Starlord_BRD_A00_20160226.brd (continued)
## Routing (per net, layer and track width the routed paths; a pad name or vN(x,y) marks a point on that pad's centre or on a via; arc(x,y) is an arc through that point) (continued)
I2C0_SDA_TCH_PAD: length 38.9
  TOP w0.089: v2(116.23,24.43) v1(118.85,21.81) 119.55,21.11 126.88,21.11 128.71,22.93 131.23,22.93 132.23,21.94 v2(132.41,21.94) 132.98,21.94 R6506.1
  L4 w0.127: v2(116.23,24.43) 117.03,25.23 117.03,30.94 116.18,31.79 116.18,38.12 115.94,38.36 115.94,39.59 v2(116.33,39.99)
  BOTTOM w0.089: v2(116.33,39.99) 116.54,39.77 CPU1.U7 ; EC6504.1 132.4,21.92 v2(132.41,21.94) 132.66,21.68 132.97,21.68 133.13,21.85 Q6504.4
I2C1_SCL: length 10.8
  BOTTOM w0.089: CPU1.N2 119.04,37.37 118.83,37.16 118.83,33.68 118.06,32.91 v1(118.06,32.22) 118.06,29.17 117.04,28.15 RN2008.2
I2C1_SDA: length 11.8
  BOTTOM w0.089: CPU1.N1 119,36.64 119,33.17 118.54,32.71 v1(118.54,30.55) 118.54,29.28 116.79,27.52 115.85,27.52 115.7,27.67 RN2008.1
I2C_CLK_PD: length 45.1
  TOP w0.089: R3845.2 v2(42.16,62.7) ; U3701.10 30.66,41.5 30.33,41.16 29.87,41.16 29.26,40.56 29.26,38.98 v2(28.88,38.6) 28.55,38.93 v1(28.4,38.93) 28.32,38.85 28.32,38.24 28.43,38.14 RN1814.4
  L3 w0.127: v2(42.16,62.7) 41.2,61.74 41.2,38.39 40.39,37.58 38.99,37.58 38.78,37.38 34.62,37.38 34.09,37.91 29.56,37.91 v2(28.88,38.6)
I2C_DATA_PD: length 42.8
  TOP w0.089: RN1814.3 29.08,38.16 v2(29.51,38.6) 29.59,38.52 v1(30.61,38.52) 31.62,38.52 32.2,39.1 U3701.13 ; v2(42.16,63.59) 42.09,63.52 R3844.2
  L3 w0.127: v2(42.16,63.59) 40.82,62.25 40.82,38.55 40.23,37.96 38.81,37.96 38.61,37.76 34.8,37.76 34.26,38.29 29.82,38.29 v2(29.51,38.6)
I_ADP: length 3
  TOP w0.102: KBC24.110 190.01,29.85 v2(189.89,29.96)
  BOTTOM w0.102: v2(189.89,29.96) 190.22,30.29 R2421.2 189.46,30.64 C2435.1
I_BATT: length 8.8
  TOP w0.203: 191.95,27.52 191.61,27.87 KBC24.114
  TOP w0.254: 191.95,27.52 191.95,27.51 191.97,27.48 191.97,27.06 191.95,27.03 v2(191.95,26.84)
  BOTTOM w0.254: v2(191.95,26.84) 191.44,26.84 v1(191.31,26.71) 191.16,26.56 189.02,26.56 188.57,27.01 188.57,27.38 188.59,27.4 188.59,27.5 188.81,27.72 C2441.1 ; C2441.1 188.81,29.13 R2423.2 ; C2441.1 187.97,28.31 R2407.2
I_SYS: length 16.1
  TOP w0.102: KBC24.113 191.21,27.5 v2(191.26,27.45)
  L6 w0.102: v2(183.79,28.44) 184.02,28.67 190.63,28.67 191.26,28.03 v2(191.26,27.45)
  BOTTOM w0.102: C2427.1 185.57,31.62 185.57,31.14 R2422.2 185.76,29.94 R2403.2 185.79,29.76 R2497.2 185.79,28.5 185.34,28.06 v1(185.01,28.06) 184.63,28.44 v2(183.79,28.44)
IC_DELAY: length 2.9
  BOTTOM w0.127: PC4307.1 v1(22.71,83.81) 22.71,83.1 23.28,82.53 U4302.4
ICSP_CLOCK: length 68.4
  TOP w0.089: KBC24.101 186.41,27.98 186.18,27.75 185.96,27.75 184.66,26.46 v2(184.33,26.46) ; v1(135.33,8.96) v2(135.89,8.96)
  L4 w0.127: v2(135.89,8.96) 136.28,9.35 136.79,9.35 137.25,8.89 139.63,8.89 140.03,9.29 151.86,9.29 156.18,13.61 163.73,13.61 164.54,14.42 173.43,14.42 174.67,15.66 176.3,15.66 177.09,16.45 177.95,16.45 179.12,17.62 180.69,17.62 185.15,22.08 185.15,25.71 184.4,26.46 v2(184.33,26.46)
  BOTTOM w0.089: v2(135.89,8.96) 135.89,5.26 135.69,5.06 DB3.2
ICSP_CLR: length 82.9
  TOP w0.102: v2(182.09,34) 182.25,33.84 KBC24.87 ; v2(138.12,7.26) 136.62,5.76 v1(136.12,5.76) R2414.1 ; v2(180.8,21.43) 182.57,19.65 182.57,11.02 v2(183.27,10.33)
  L4 w0.102: v2(180.8,21.43) 180.62,21.61 180.62,24.54 182.29,26.22 182.29,29.06 182.32,29.09 182.32,29.72 182.52,29.92 182.52,33.57 v2(182.09,34)
  L6 w0.102: v2(183.27,10.33) 183.27,10.03 183.06,9.82 182.45,9.82 181.28,8.65 139.52,8.65 v2(138.12,7.26)
  BOTTOM w0.102: v2(138.12,7.26) 137.69,6.82 137.69,5.1 135.65,3.06 DB3.6
ICSP_DATA: length 71
  TOP w0.089: v2(184.25,25.8) 184.45,25.8 185.93,27.27 186.1,27.27 186.81,27.97 KBC24.102 ; v1(134.01,8.93) v2(134.59,8.93)
  L4 w0.127: v2(184.25,25.8) 184.77,25.28 184.77,22.26 180.51,18 178.94,18 177.77,16.83 175.84,16.83 175.22,16.21 174.46,16.21 174.13,16.21 173.42,16.92 172.68,16.92 170.56,14.8 164.36,14.8 163.55,13.99 156.01,13.99 151.69,9.67 139.85,9.67 139.46,9.28 137.42,9.28 136.97,9.73 135.39,9.73 v2(134.59,8.93)
  BOTTOM w0.089: v2(134.59,8.93) 133.81,8.15 133.81,4.84 134.09,4.56 DB3.3
ILIM_HI: length 3.3
  BOTTOM w0.102: U3401.16 24.17,47.6 24.41,47.36 v1(24.41,45.64) 24.41,45.48 24.55,45.34 R3404.2
ILIM_LO: length 5.2
  BOTTOM w0.102: U3401.15 24.45,48.1 24.81,47.74 24.81,45.69 25.09,45.41 25.09,44.48 R3403.2
ILIM_SEL: length 3.2
  TOP w0.102: v1(20.83,46.41) 20.79,46.41 20.55,46.17 v2(20.27,46.17)
  BOTTOM w0.102: R3405.2 20.27,46 v2(20.27,46.17) 20.9,46.8 U3401.4
INT2_SELECT: length 9.6
  BOTTOM w0.102: Q7001.5 123.62,9.16 123.34,8.88 123.34,7.92 123.57,7.69 125.19,7.69 v1(125.3,7.59) 125.3,7.31 125.22,7.23 124.74,7.23 124.66,7.15 R7013.1 R7008.1 125.87,6.68 126.06,6.49 126.06,5.3 125.04,4.28 D7001.2
INT#_TYPEC: length 248.6
  TOP w0.127: R3705.2 30.28,36.03 v2(30.15,35.91) ; KBC24.30 199.49,41.84 199.71,42.06 199.71,42.57 200.25,43.12 v2(200.28,43.12) ; v2(123.06,2.35) 123.68,2.98 123.68,3.48 123.21,3.95 122.64,3.95 117.82,8.77 113.89,8.77 112.81,7.69 111.16,7.69 v1(110.42,6.95) 110.42,4.28 111.03,3.67 v2(111.12,3.67)
  L3 w0.127: v2(30.15,35.91) 31.04,35.02 32.56,35.02 33.25,34.33 33.25,26.81 35.08,24.98 35.08,19.27 36.27,18.08 36.27,15.1 36.9,14.47 41.43,14.47 45.97,9.92 54.67,9.92 55.74,10.99 56.61,10.99 56.92,10.68 56.92,8.68 59.92,5.68 60.48,5.68 63.59,2.57 67.09,2.57 67.17,2.65 71.28,2.65 72.45,3.81 81.9,3.81 84.19,1.53 111.87,1.53 112.13,1.79 112.13,3.31 111.73,3.7 111.15,3.7 v2(111.12,3.67)
  L4 w0.127: v2(123.06,2.35) 123.72,1.69 125.07,1.69 125.78,2.4 126.08,2.4 127.02,1.46 128.47,1.46 128.55,1.54 153.98,1.54 155.47,3.03 155.47,3.32 159.1,6.95 189.81,6.95 192.44,9.58 193.04,9.58 200.68,17.22 200.68,30.45 201.06,30.83 201.06,34.61 199.25,36.43 199.25,39.07 199.79,39.62 199.79,41.22 199.82,41.24 199.82,42.64 200.02,42.84 200.02,42.87 v2(200.28,43.12)
INT#_TYPEC_R: length 3.8
  TOP w0.102: U3701.14 32.7,38.84 v1(32.41,38.55) 31.98,38.12 31.66,38.12 R3707.2 R3705.1
INT_TP#: length 140.4
  TOP w0.102: v2(130.48,16.22) 130.48,16.83 130.68,17.03 R6511.2 ; KBC24.33 197.21,44.19 197.46,44.19 197.76,44.49 198.37,44.49 198.5,44.62 v2(199.74,44.62) ; v2(123.75,13.71) 123.8,13.66 AFTP6536.1 123.8,11.45 124.2,11.04 124.2,10.4 125.7,8.91 125.7,8.91 126.16,8.45 126.16,8.17 127.2,7.13 127.71,7.13 128.11,6.72 128.78,6.72 129.39,6.11 v2(129.39,6.06)
  L4 w0.102: v2(128.29,1.92) 128.42,1.79 153.9,1.79 155.14,3.04 155.14,3.34 159,7.2 189.71,7.2 192.33,9.82 192.94,9.82 200.43,17.31 200.43,30.13 199.01,31.55 199.01,39.18 199.24,39.41 199.24,41 199.57,41.33 199.57,42.74 199.77,42.94 199.77,43.7 199.74,43.73 v2(199.74,44.62)
  BOTTOM w0.102: R410.1 123.75,15.17 v1(123.75,14.27) v2(123.75,13.71) D401.K 123.98,12.74 129.29,12.74 130.48,13.93 v2(130.48,16.22) 130.55,16.29 KBBD1.40 ; v2(128.29,1.92) 129.39,3.01 v2(129.39,6.06)
IR_CAMERA_DET#: length 142.4
  TOP w0.102: v2(113.82,33.49) 112.93,33.49 v1(112.34,32.91) 112.22,32.78 109.85,32.78 109.7,32.94 109.7,34.54 109.32,34.92 108.77,34.92 108.3,35.38 108.3,35.48 107.77,36.01 107.06,36.01 106.37,35.32 103.2,35.32 103.02,35.5 102.31,35.5 v2(102.06,35.25) ; v2(66.52,93.9) 66.51,93.88 R5540.2
  L3 w0.102: v2(66.52,93.9) 66.52,93.69 67.92,92.29 80.9,92.29 v2(81.25,91.94) ; v2(82.5,23.44) 82.86,23.08 83.52,23.08 83.85,23.41 88.87,23.41 89.1,23.18 91.29,23.18 92.02,23.92 92.02,26.92 94.38,29.28 94.38,30.18 99.2,35 101.81,35 v2(102.06,35.25)
  L4 w0.102: v2(113.82,33.49) 114.15,33.82 114.15,35.53 115.29,36.67 v2(115.29,37.86)
  BOTTOM w0.102: CPU1.W4 115.77,38.35 v2(115.29,37.86) ; v2(82.5,23.44) 81.38,24.55 81.38,47.99 85.41,52.02 85.41,90.5 85.44,90.54 85.44,91.92 84.77,92.59 83.68,92.59 83.23,93.03 81.63,93.03 81.23,92.63 81.23,91.96 v2(81.25,91.94) ; R2046.2 114.6,33.06 114.2,33.47 113.89,33.47 113.87,33.49 v2(113.82,33.49)
IR_CAMERA_DET#_R: length 2.8
  TOP w0.102: v2(65.86,93.92) 65.62,93.68 R5540.1 65.59,93.03 v1(64.72,93.03)
  BOTTOM w0.102: v2(65.86,93.92) 65.65,93.71 TCBD1.22
ISET: length 3.4
  TOP w0.102: R5413.2 R5414.2 22.45,61.12 v1(22.45,61.92) 22.45,62.09 22.05,62.49 U5701.34
ISH_KB_DISABLE: length 31.8
  TOP w0.102: v2(93.39,23.11) 93.64,22.86 R2022.1 93.64,22.05 93.93,21.76 v1(95.27,21.76)
  BOTTOM w0.102: CPU1.AY8 104.75,40.72 104.45,41.02 104.12,41.02 103.91,40.81 102.79,40.81 101.95,39.97 96.85,39.97 91.34,34.46 91.34,30.67 91.59,30.41 91.59,29.13 91.97,28.74 91.97,24.02 92.68,23.31 93.19,23.31 v2(93.39,23.11)
ITP_PMODE: length 1.7
  TOP w0.102: v2(123.72,40.53) 124.43,40.53 TP638.1
  BOTTOM w0.102: CPU1.E8 123.21,40.88 123.57,40.53 v2(123.72,40.53)
JACK_PLUG: length 7
  TOP w0.254: HPMIC1.5 12.48,22.27 16.5,22.27 ED2903.1 16.52,21.56 R2923.1 v1(15.16,21.23)
JACK_PLUG_DET: length 10.7
  TOP w0.254: v2(16.31,24.1) 16.93,23.47 ED2904.1 16.65,23.16 16.08,23.16 v1(15.7,22.78) 10.67,22.78 9.68,21.79 HPMIC1.6
  BOTTOM w0.254: v2(16.31,24.1) 16.74,24.53 R2905.1
JGND:
  vias: v1(16.71,83.48) v3(18.54,84.6) v3(18.59,83.68)
KB_BL_CTRL#: length 4.9
  TOP w0.508: v2(136.19,20.82) 136.29,20.92 AFTP6530.1
  BOTTOM w0.305: KBBD1.31 135.05,19.11 135.61,19.67 135.61,19.8
  BOTTOM w0.508: Q6501.D 136.7,20.82 v2(136.19,20.82) 135.61,20.24 135.61,19.8
KB_CLOSE#_2: length 313.8
  TOP w0.102: GMR1.1 7.01,84.27 v2(6.91,84.17) ; C7001.1 R7001.1 16.13,83.09 14.79,83.09 v2(14.68,83.2) ; v1(85.8,19.02) 85.8,18.89 v2(86.16,18.53)
  L3 w0.102: v2(86.16,18.53) 85.77,18.91 82.52,18.91 81.84,18.23 79.02,18.23 77.44,16.65 66.17,16.65 65.3,15.79 63.73,15.79 62.18,17.34 53.85,17.34 51.48,19.7 48.51,19.7 47.46,20.76 45.96,20.76 43.36,23.36 43.36,29.56 43.99,30.19 43.99,32.3 42.9,33.39 42.9,38.68 45.11,40.89 45.11,61.43 43.6,62.95 43.6,70 47.55,73.94 47.55,84.55 46.63,85.46 46.63,88.79 48.69,90.85 v2(49.93,90.85)
  L4 w0.102: v2(189,35.73) 188.97,35.73 188.49,35.25 188.49,34.84 189.61,33.72 189.61,32.28 191.84,30.04 191.84,29.66 192.78,28.72 192.86,28.72 194.08,27.5 194.08,25.02 192.86,23.8 192.86,19.54 186.41,13.1 177.79,13.1 177.36,12.67 165.33,12.67 164.51,11.85 156.97,11.85 151.97,6.85 140.13,6.85 139.7,6.42 132.98,6.42 132.39,7 129.91,7 128.82,8.09 127.77,8.09 127.46,7.79 123.62,7.79 121.79,9.62 119.22,9.62 118.57,10.27 115.77,10.27 114.65,11.38 113.77,11.38 113.12,12.03 112.01,12.03 111.73,11.75 109.85,11.75 109.68,11.93 105.48,11.93 104.78,12.63 102.73,12.63 102.44,12.34 100.38,12.34 99.79,12.92 95.02,12.92 93.29,14.65 91.33,14.65 87.45,18.53 v2(86.16,18.53)
  BOTTOM w0.102: v2(49.93,90.85) 31.34,90.85 30.41,89.92 27.98,89.92 27.48,89.42 25.7,89.42 25.17,89.96 25.17,90.72 24.92,90.97 23.86,90.97 20.61,87.72 16.58,87.72 14.78,85.92 14.78,83.3 v2(14.68,83.2) 14.63,83.15 13.1,83.15 12.88,83.37 9.5,83.37 8.4,84.47 7.21,84.47 v2(6.91,84.17) ; Q2415.S 189.68,36.41 v2(189,35.73)
KB_CLOSE#_2_R: length 11.4
  TOP w0.127: v2(192.38,34.66) 192.66,34.38 192.66,33.21 192.35,32.91 192.35,31.97 193.14,31.18 193.77,31.18 194.4,30.56 194.41,30.56 194.52,30.45 195.07,30.45 195.78,29.73 196.24,29.73 196.41,29.57 KBC24.126
  BOTTOM w0.127: Q2415.D 191.96,35.35 192.9,35.35 R2496.1 192.95,34.74 192.45,34.74 v2(192.38,34.66)
KB_DET#: length 49.1
  TOP w0.102: v2(135.86,21.4) 136.02,21.56 136.98,21.56 137.39,21.15 137.39,20.64 136.5,19.75 v1(136.27,19.75) 136.07,19.55 136.07,17.64 136.5,17.21 136.6,17.21 136.73,17.09 v2(136.75,17.09) 136.78,17.11 136.78,17.73 R2045.2
  L4 w0.102: v2(113.87,38.62) 113.87,35.14 113.35,34.62 113.35,33.28 113.54,33.09 113.54,31.97 115.19,30.32 115.19,28.94 115.54,28.58 115.54,25.59 115.33,25.38 115.33,23.14 115.97,22.5 118.24,22.5 118.65,22.09 119.37,22.09 120.46,21 121.14,21 121.39,21.25 124.26,21.25 124.61,21.61 130.4,21.61 130.45,21.56 131.37,21.56 132.18,22.37 132.64,22.37 133.86,21.15 135.58,21.15 135.84,21.4 v2(135.86,21.4)
  BOTTOM w0.102: v2(113.87,38.62) 113.59,38.35 CPU1.AD4 ; v2(136.75,17.09) 136.75,17.24 136.55,17.44 KBBD1.28
KB_DISABLE: length 266.4
  TOP w0.102: v2(95.58,23.13) 95.32,22.88 94.84,22.39 R2022.2 ; v2(111,4.33) 110.67,4.66 110.67,6.54 111.57,7.45 112.91,7.45 113.47,8 113.99,8.52 117.72,8.52 122.95,3.29 v2(123.24,3.29) ; R6920.1 33.55,34.99 34.54,35.98 34.57,35.98 34.67,36.08 37.46,36.08 38.27,36.9 39.01,36.9 40.46,38.35 v2(43.61,38.35)
  L3 w0.102: v2(111,4.33) 111.45,4.33 112.44,3.34 112.44,1.69 111.96,1.21 83.01,1.21 81.41,2.81 v2(75.54,2.81) ; v2(95.58,23.13) 95.26,23.13 93.25,21.12 92.56,21.12 91.9,20.46 88.36,20.46 87.45,21.38 84.78,21.38 84.12,20.72 81.76,20.72 81.08,20.03 77.75,20.03 v2(76.91,19.19) 76.48,19.63 73.56,19.63 71.69,17.75 54.07,17.75 51.71,20.11 48.74,20.11 47.55,21.3 45.99,21.3 43.76,23.53 43.76,29.35 44.45,30.04 44.45,32.45 43.51,33.39 43.51,38.24 v2(43.61,38.35)
  L4 w0.102: v2(75.54,2.81) 75.54,14.29 76.99,15.74 76.99,19.12 v2(76.91,19.19) ; v2(123.24,3.29) 123.26,3.29 123.92,3.95 126.39,3.95 127.28,3.06 127.34,3.06 127.57,2.84 132.87,2.84 133.3,2.4 153.54,2.4 154.48,3.34 154.48,3.6 158.7,7.81 188.97,7.81 v2(190.19,9.03)
  BOTTOM w0.102: R2403.1 183.61,29.79 183.36,29.53 183.36,28.21 184.07,27.5 184.73,27.5 185.42,26.81 185.42,25.32 184.25,24.15 184.25,22.95 183.82,22.52 183.82,18.63 187.47,14.98 190.22,14.98 192.33,12.87 192.33,12.36 193.6,11.09 193.6,10.66 191.97,9.03 v1(191.57,9.03) v2(190.19,9.03)
KB_DISABLE_HUB: length 3.7
  TOP w0.102: U6901.2 35.18,31.17 34.8,31.55 34.8,32.74 v1(34.46,33.08) 33.91,33.08 R6920.2
KB_LED_BL_DET_R: length 37.6
  TOP w0.102: R6507.1 129.88,21.4 R6508.1 129.72,22.09 v1(129.79,22.17) 129.82,22.19 v2(130.76,22.19)
  L4 w0.102: v2(130.76,22.19) 130.58,22.01 122.08,22.01 121.7,21.93 121.31,21.93 121.11,22.01 121.08,22.03 120.61,22.5 118.82,22.5 117.95,23.36 115.99,23.36 115.74,23.61 115.74,25.21 116.02,25.49 116.41,25.49 116.66,25.75 116.66,30.09 115.89,30.87 115.89,31.87 115.9,31.88 115.9,38.09 115.73,38.25 115.73,39.76 115.92,39.95 115.92,40.17 v2(116.38,40.63)
  BOTTOM w0.102: CPU1.W8 116.14,40.43 116.34,40.63 v2(116.38,40.63)
KB_LED_DET_C: length 5.9
  TOP w0.102: v2(133.37,19.7) 132.84,19.17 132.51,19.17 v1(132.08,19.6) 131.43,20.25 C6504.1 R6507.2
  BOTTOM w0.102: KBBD1.32 134.55,18.75 133.7,19.6 133.48,19.6 v2(133.37,19.7)
KBC_BEEP_R: length 3.4
  BOTTOM w0.254: RN2701.4 31.72,13.38 31.39,13.71 30.86,13.71 v1(30.55,14.01) 29.74,14.01 D2701.1
KBC_PWRBTN#: length 32.6
  TOP w0.102: v2(169.85,36.59) 169.66,36.78 EC6601.1 168.5,36.15 168.5,33.42 v1(168.3,33.21) 168.15,33.07 v2(168.15,31.48)
  L6 w0.102: v2(168.15,31.48) 169,30.64 175.34,30.64 176.09,29.89 177.65,29.89 178.42,29.13 180.87,29.13 181.48,29.73 185.6,29.73 186.26,30.4 190.22,30.4 v2(190.75,29.86)
  BOTTOM w0.102: v2(190.75,29.86) 190.75,30.23 R2432.1 ; v2(169.85,36.59) 169.73,36.71 IOBD1.45
KSI0: length 66.4
  TOP w0.102: KBC24.98 185.21,27.77 184.78,27.35 183.61,27.35 182.07,28.9 v2(181.71,28.9) 181.7,28.91 RN2403.8 ; AFTP6512.1 136.93,13.68 v2(137.64,12.97)
  L4 w0.102: v2(137.64,12.97) 138.35,12.97 138.68,12.64 140.87,12.64 141.25,13.02 149.53,13.02 150.24,13.73 151.36,13.73 154.58,16.96 156.82,16.96 157.76,17.9 162.38,17.9 162.97,18.48 165.95,18.48 167.02,19.55 168.79,19.55 175.97,26.73 175.97,28.97 176.73,29.73 178.09,29.73 178.92,28.9 v2(181.71,28.9)
  BOTTOM w0.102: v2(137.64,12.97) 140.55,15.88 KBBD1.20
KSI1: length 69
  TOP w0.102: AFTP6501.1 135.56,13.78 v2(136.22,13.12) ; RN2403.7 181.71,28.26 v2(181.71,28.26) 182.93,27.04 184.86,27.04 185.61,27.79 KBC24.99
  L4 w0.102: v2(181.71,28.26) 179.27,28.26 178,29.53 176.82,29.53 176.17,28.89 176.17,26.64 168.88,19.35 167.1,19.35 166.04,18.28 163.05,18.28 162.39,17.62 157.78,17.62 156.92,16.76 154.68,16.76 151.46,13.53 150.34,13.53 149.63,12.82 141.35,12.82 140.97,12.44 137.54,12.44 136.85,13.12 v2(136.22,13.12)
  BOTTOM w0.102: v2(136.22,13.12) 139.55,16.45 KBBD1.22
KSI2: length 121.6
  TOP w0.102: v2(134.8,12.97) 134.24,13.53 133.3,13.53 AFTP6508.1 ; RN2403.6 181.55,27.76 181.73,27.58 v2(181.73,27.37) ; v2(195.73,33.87) 195.73,33.52 196.11,33.14 196.37,33.14 197.08,32.43 197.71,32.43 197.9,32.24 KBC24.6
  L4 w0.102: v2(195.73,33.87) 195.73,33.77 195.71,33.75 195.71,33.37 199.41,29.66 199.41,17.8 193.57,11.95 192.38,11.95 191.88,11.46 v2(191.88,11.46) ; v2(134.8,12.97) 135.08,12.69 136.98,12.69 137.44,12.23 141.07,12.23 141.45,12.62 149.73,12.62 150.44,13.33 151.56,13.33 154.79,16.55 157.02,16.55 157.88,17.42 162.48,17.42 163.14,18.08 166.12,18.08 167.19,19.14 168.96,19.14 176.38,26.56 176.38,28.8 176.9,29.33 177.9,29.33 179.17,28.06 181.02,28.06 181.68,27.4 181.7,27.4 v2(181.73,27.37)
  BOTTOM w0.102: KBBD1.24 138.55,17.72 137.94,17.1 137.94,16.35 134.8,13.21 v2(134.8,12.97) ; v2(191.88,11.46) 191.72,11.62 191.72,12.9 190.08,14.55 185.87,14.55 182.76,17.66 182.76,22.88 183.18,23.31 183.18,24.57 183.46,24.85 183.46,26.37 182.46,27.37 v2(181.73,27.37)
KSI3: length 119.9
  TOP w0.102: RN2403.5 180.98,27.09 181.33,26.74 v2(181.79,26.74) ; v2(196.29,33.57) 196.29,33.54 197.19,32.64 KBC24.7 ; AFTP6509.1 136.09,12.26 v2(136.17,12.26)
  L4 w0.102: v2(136.17,12.26) 136.4,12.03 141.17,12.03 141.55,12.41 149.83,12.41 150.54,13.12 151.66,13.12 154.89,16.35 157.12,16.35 157.99,17.21 162.56,17.21 163.22,17.87 166.2,17.87 167.27,18.94 169.04,18.94 176.58,26.47 176.58,28.72 176.98,29.13 177.8,29.13 180.19,26.74 v2(181.79,26.74) ; v2(191.41,10.28) 191.41,10.38 191.9,10.86 192.78,11.75 193.67,11.75 199.62,17.7 199.62,29.76 197.71,31.67 197.71,32.02 196.29,33.44 v2(196.29,33.57)
  BOTTOM w0.102: v2(181.79,26.74) 182.81,26.74 183.2,26.35 183.2,24.91 182.95,24.67 182.95,23.51 182.5,23.05 182.5,17.63 185.84,14.29 190.04,14.29 191.23,13.1 191.23,10.46 v2(191.41,10.28) ; v2(136.17,12.26) 140.05,16.14 KBBD1.21
KSI4: length 79.9
  TOP w0.102: KBC24.104 187.61,27.81 187.48,27.68 v2(187.48,27.22) ; v2(177.25,26.66) 177.44,26.66 177.89,27.11 RN2404.8 ; v2(133.15,12.97) 132.03,11.85 AFTP6505.1
  L4 w0.102: v2(133.15,12.97) 134.49,11.62 141.37,11.62 141.76,12.01 150.04,12.01 150.75,12.72 151.86,12.72 155.09,15.94 157.33,15.94 158.19,16.81 162.73,16.81 163.39,17.47 166.37,17.47 167.44,18.53 169.21,18.53 171.07,20.39 174.48,20.39 175.77,21.67 175.77,23.32 177.67,25.22 177.67,26.24 v2(177.25,26.66)
  L6 w0.102: v2(187.48,27.22) 182.57,22.32 180.62,22.32 178.2,24.73 178.2,25.7 v2(177.25,26.66)
  BOTTOM w0.102: KBBD1.25 138.05,17.65 137.69,17.29 137.69,16.58 134.11,13 133.17,13 v2(133.15,12.97)
KSI5: length 76.8
  TOP w0.102: AFTP6506.1 134.42,11.98 v2(134.77,12.34) ; v2(188.09,27.55) 188.01,27.63 KBC24.105 ; RN2404.7 177.55,27.76 177.24,27.45 177.24,27.33 v2(177.24,27.32)
  L4 w0.102: v2(177.24,27.32) 176.81,26.9 176.81,26.42 169.13,18.74 167.36,18.74 166.29,17.67 163.3,17.67 162.64,17.01 158.09,17.01 157.22,16.15 154.99,16.15 151.76,12.92 150.65,12.92 149.93,12.21 141.65,12.21 141.27,11.83 135.28,11.83 v2(134.77,12.34)
  L6 w0.102: v2(188.09,27.55) 188.06,27.58 188.06,27.6 187.81,27.86 186.69,27.86 185.67,26.84 185.67,26.03 182.16,22.52 180.7,22.52 178.56,24.66 178.56,26 v2(177.24,27.32)
  BOTTOM w0.102: KBBD1.23 139.05,16.61 134.85,12.41 134.85,12.41 v2(134.77,12.34)
KSI6: length 86.3
  TOP w0.102: AFTP6503.1 131.82,13.66 v2(132.51,12.97) ; KBC24.107 188.81,27.92 189.08,27.64 v2(189.08,27.22) ; RN2404.6 177.41,28.26 v2(177.19,28.03)
  L4 w0.102: v2(132.51,12.97) 134.06,11.42 141.48,11.42 141.86,11.8 150.14,11.8 150.85,12.51 151.97,12.51 155.19,15.74 157.43,15.74 158.29,16.6 162.81,16.6 163.47,17.26 166.46,17.26 167.52,18.33 169.31,18.33 171.17,20.18 174.56,20.18 175.97,21.59 175.97,23.23 177.87,25.14 177.87,27.45 177.29,28.03 v2(177.19,28.03)
  L6 w0.102: v2(177.19,28.03) 177.29,28.03 178.76,26.56 178.76,24.75 180.79,22.72 182.07,22.72 185.34,25.99 185.34,26.8 186.6,28.06 188.69,28.06 189.08,27.68 189.08,27.23 v2(189.08,27.22)
  BOTTOM w0.102: KBBD1.26 137.55,17.45 137.39,17.29 137.39,16.82 134.3,13.73 133.27,13.73 v2(132.51,12.97)
KSI7: length 90.4
  TOP w0.102: AFTP6502.1 130.61,11.75 v2(131.82,12.97) ; KBC24.108 189.21,27.9 189.56,27.55 v2(189.63,27.55) ; RN2404.5 177.4,28.91 v2(177.16,28.67)
  L4 w0.102: v2(177.16,28.67) 177.32,28.67 178.08,27.91 178.08,22.45 177.18,21.56 176.22,21.56 174.62,19.96 171.25,19.96 169.42,18.13 167.61,18.13 166.54,17.06 163.56,17.06 162.87,16.37 158.37,16.37 157.53,15.54 155.29,15.54 152.07,12.31 150.95,12.31 150.24,11.6 141.96,11.6 141.58,11.22 133.58,11.22 v2(131.82,12.97)
  L6 w0.102: v2(177.16,28.67) 177.32,28.67 178.97,27.02 178.97,24.83 180.87,22.93 181.99,22.93 185.14,26.08 185.14,26.88 186.52,28.26 188.85,28.26 189.56,27.55 v2(189.63,27.55)
  BOTTOM w0.102: v2(131.82,12.97) 132.89,14.04 134.31,14.04 137.18,16.91 137.18,17.26 137.05,17.4 KBBD1.27
KSO0: length 86.9
  TOP w0.102: KBC24.2 198.03,30.64 197.2,31.46 196.59,31.46 195.88,32.17 195.71,32.17 193.95,33.93 193.95,35.25 193.44,35.75 193.44,35.77 193.11,36.1 193.11,38.27 v2(192.43,38.95) ; AFTP6507.1 145.41,14.85 v2(144.91,14.34)
  L3 w0.102: v2(192.43,38.95) 192.43,39.77 190.58,41.62 189.79,41.62 189.53,41.87 189.53,42.26 189.69,42.41 v2(189.69,42.64)
  L4 w0.102: v2(189.69,42.64) 189.1,43.22 187.27,43.22 187.04,42.99 183.16,42.99 182.29,43.86 179.44,43.86 177.85,42.27 177.85,39.06 175.72,36.92 175.72,32.36 173.38,30.02 173.38,27.69 168.54,22.85 165.56,22.85 165.12,22.42 158.88,22.42 157.38,20.93 157.07,20.93 155.67,19.52 153.36,19.52 151.2,17.36 150.01,17.36 149.68,17.03 147.6,17.03 v2(144.91,14.34)
  BOTTOM w0.102: RN2412.8 189.69,43.05 v2(189.69,42.64) ; v2(144.91,14.34) 145.05,14.49 KBBD1.11
KSO1: length 86.8
  TOP w0.102: AFTP6511.1 143.53,14.39 v2(143.58,14.34) ; KBC24.14 197.74,35.44 197.68,35.5 195.96,35.5 195.81,35.65 194.47,35.65 193.72,36.4 193.72,40.02 192.99,40.76 191.26,40.76 v2(189.96,42.05)
  L4 w0.102: v2(143.58,14.34) 143.58,14.32 144.04,13.86 145.03,13.86 145.34,14.16 145.34,14.45 146.19,15.31 147.45,15.31 147.7,15.56 147.7,15.67 148.61,16.58 148.87,16.58 148.92,16.63 149.88,16.63 150.21,16.96 151.43,16.96 153.03,18.56 153.03,18.58 153.57,19.12 155.84,19.12 157.18,20.46 157.24,20.52 157.55,20.52 159.04,22.01 165.33,22.01 165.76,22.44 168.7,22.44 173.79,27.53 173.79,29.85 176.12,32.19 176.12,36.69 179.28,39.86 179.28,42.17 180.52,43.4 181.13,43.4 181.99,42.54 182.7,42.54 182.95,42.79 185.47,42.79 186.66,41.6 189.51,41.6 v2(189.96,42.05)
  BOTTOM w0.102: RN2412.7 190.65,42.96 190.83,42.79 190.83,42.38 190.5,42.05 v2(189.96,42.05) ; v2(143.58,14.34) 143.58,14.47 144.5,15.38 144.5,17.36 144.05,17.81 KBBD1.13
KSO2: length 88.7
  TOP w0.102: KBC24.15 197.75,35.84 197.61,35.7 196.06,35.7 195.91,35.86 194.55,35.86 193.93,36.48 193.93,40.11 193.07,40.96 191.84,40.96 191.16,41.65 v2(191.16,42.05) ; v2(144.22,14.29) 143.69,13.76 AFTP6513.1
  L4 w0.102: v2(144.22,14.29) 144.7,14.77 144.83,14.77 147.29,17.24 149.58,17.24 149.91,17.57 151.1,17.57 153.26,19.73 155.58,19.73 157.1,21.24 157.1,21.94 157.12,21.96 157.12,22.01 157.73,22.62 165.02,22.62 165.45,23.05 168.45,23.05 173.18,27.78 173.18,30.11 175.51,32.44 175.51,37.02 177.57,39.08 177.57,42.87 178.5,43.79 178.5,44.28 179.07,44.85 180.74,44.85 181,45.1 181.36,45.1 182.19,44.26 182.19,44.25 183.24,43.2 186.94,43.2 187.17,43.43 190.14,43.43 190.8,42.77 190.8,42.41 v2(191.16,42.05)
  BOTTOM w0.102: KBBD1.12 144.55,17.82 144.7,17.67 144.7,15.23 144.22,14.75 v2(144.22,14.29) ; v2(191.16,42.05) 191.15,42.06 RN2412.6
KSO3: length 89.7
  TOP w0.102: KBC24.16 197.84,36.24 197.84,36.24 197.51,35.91 196.16,35.91 196.01,36.06 194.64,36.06 194.13,36.57 194.13,40.19 193.16,41.16 192.02,41.16 191.59,41.6 191.59,42.59 v2(191.64,42.64) ; v2(142.95,14.34) 142.57,13.96 AFTP6518.1
  L4 w0.102: v2(191.64,42.64) 190.65,43.63 187.07,43.63 186.84,43.4 183.33,43.4 182.4,44.33 182.4,44.35 180.93,45.81 180.39,45.81 180.19,45.61 179.54,45.61 178.29,44.36 178.29,43.88 177.37,42.95 177.37,39.23 175.31,37.18 175.31,32.53 172.97,30.19 172.97,27.86 168.37,23.26 165.35,23.26 164.95,22.85 157.5,22.85 156.76,22.11 156.76,21.19 155.83,20.26 154.23,20.26 153.69,20.79 153.04,20.79 152.22,19.97 152.22,19.03 150.96,17.77 149.81,17.77 149.58,17.54 147.27,17.54 144.7,14.98 143.58,14.98 v2(142.95,14.34)
  BOTTOM w0.102: v2(191.64,42.64) 191.64,42.66 191.81,42.83 RN2412.5 ; v2(142.95,14.34) 143.55,14.94 KBBD1.14
KSO4: length 88.3
  TOP w0.102: v2(195.96,45.46) 195.61,45.1 KBC24.37 ; AFTP6514.1 141.5,12.11 v2(140.28,13.33)
  L4 w0.102: v2(195.96,45.46) 194.84,44.34 187.01,44.34 186.48,43.81 183.5,43.81 182.8,44.5 182.8,44.52 181.1,46.22 180.19,46.22 179.98,46.02 179.37,46.02 177.89,44.53 177.89,44.05 176.96,43.12 176.96,39.44 173.68,36.16 173.68,31.48 172.57,30.36 172.57,28.03 168.2,23.66 165.15,23.66 164.74,23.26 154.94,23.26 153.51,21.83 153.5,21.83 151.79,20.11 151.79,19.18 150.79,18.18 149.5,18.18 149.27,17.95 146.96,17.95 144.6,15.59 142.36,15.59 140.28,13.51 v2(140.28,13.33)
  BOTTOM w0.102: v2(140.28,13.33) 140.28,13.94 141.55,15.2 KBBD1.18 ; v2(195.96,45.46) 195.5,45 195.18,45 RN2409.8
KSO5: length 87.6
  TOP w0.102: v2(195.29,45.44) 195.21,45.36 KBC24.38 ; v2(139.65,13.35) 139.14,13.86 AFTP6510.1
  L4 w0.102: v2(139.65,13.35) 142.09,15.79 144.5,15.79 146.86,18.15 149.17,18.15 149.4,18.38 150.7,18.38 151.59,19.26 151.59,20.2 154.85,23.46 164.64,23.46 165.05,23.87 168.11,23.87 172.36,28.12 172.36,30.44 173.45,31.54 173.45,36.24 176.76,39.54 176.76,43.2 177.68,44.13 177.68,44.61 179.29,46.22 179.88,46.22 180.16,46.5 181.11,46.5 183.01,44.6 183.01,44.58 183.58,44.01 186.39,44.01 186.93,44.54 194.39,44.54 v2(195.29,45.44)
  BOTTOM w0.102: RN2409.7 194.13,45 194.26,45.13 194.97,45.13 v2(195.29,45.44) ; KBBD1.19 141.05,15.82 139.65,14.42 v2(139.65,13.35)
KSO6: length 88.4
  TOP w0.102: KBC24.39 194.81,45.24 v2(194.49,45.56) ; AFTP6517.1 141.17,13.78 v2(141.65,14.27)
  L4 w0.102: v2(194.49,45.56) 194.82,45.89 196.49,45.89 196.75,45.64 196.75,45.28 195.6,44.14 187.09,44.14 186.56,43.6 183.41,43.6 182.6,44.42 182.6,44.43 181.02,46.02 180.29,46.02 180.08,45.81 179.46,45.81 178.09,44.44 178.09,43.96 177.16,43.04 177.16,39.34 173.94,36.11 173.94,31.44 172.77,30.27 172.77,27.95 168.28,23.46 165.25,23.46 164.84,23.05 155.03,23.05 153.6,21.62 153.59,21.62 151.99,20.03 151.99,19.09 150.87,17.97 149.6,17.97 149.38,17.75 147.06,17.75 144.68,15.36 142.72,15.36 141.65,14.29 v2(141.65,14.27)
  BOTTOM w0.102: RN2409.6 193.63,45.08 193.8,45.25 193.98,45.25 194.28,45.56 v2(194.49,45.56) ; v2(141.65,14.27) 141.65,14.47 142.55,15.37 KBBD1.16
KSO7: length 87.9
  TOP w0.102: KBC24.50 190.41,45.67 v2(190.42,45.69) ; v2(139.01,13.35) 139.01,12.74 AFTP6515.1
  L4 w0.102: v2(190.42,45.69) 190.24,45.51 190.24,45.28 189.71,44.75 186.84,44.75 186.33,44.24 183.64,44.24 183.21,44.67 183.21,44.69 181.19,46.7 180.06,46.7 179.78,46.42 179.21,46.42 177.48,44.7 177.48,44.28 176.5,43.3 176.5,39.59 173.25,36.34 173.25,31.62 172.16,30.53 172.16,28.2 168.04,24.08 164.96,24.08 164.54,23.66 154.76,23.66 151.38,20.28 151.38,19.39 150.58,18.58 149.3,18.58 149.08,18.37 146.77,18.37 144.4,15.99 141.98,15.99 139.85,13.86 139.52,13.86 v2(139.01,13.35)
  BOTTOM w0.102: RN2409.5 192.98,44.66 192.38,45.25 191.67,45.25 191.44,45.48 191.44,45.64 191.18,45.89 190.63,45.89 v2(190.42,45.69) ; KBBD1.17 142.05,15.35 141.2,14.49 141.2,13.63 140.46,12.89 139.47,12.89 v2(139.01,13.35)
KSO8: length 105.7
  TOP w0.102: v2(142.29,14.32) 141.63,14.98 AFTP6516.1 ; KBC24.46 192,44.19 192,45.16 192.5,45.66 v2(192.5,45.69) ; v2(180.45,40.42) 180.45,39.72 179.94,39.21 179.45,38.72 179.08,38.35 177.62,38.35 176.87,39.09 175.28,39.09 173.91,40.46 173.91,40.81 173.57,41.15 RN2410.8 172.68,41.65 171.9,41.65 171.68,41.87 171.68,43.25 171.6,43.32 170.43,43.32 170.31,43.45 170.31,45.33 170.86,45.89 173.25,45.89 176.25,48.89 176.53,48.89 177.04,49.39 178.23,49.39 178.94,50.11 181.13,50.11 181.76,49.47 181.76,48.89 182.45,48.2 182.45,47.41 v2(182.37,47.34)
  L3 w0.102: v2(192.5,45.69) 192.07,45.25 191.79,45.25 191.03,44.49 185.64,44.49 184.64,45.49 183.65,45.49 182.45,46.7 182.45,47.26 v2(182.37,47.34)
  L4 w0.102: v2(180.45,40.42) 180.25,40.42 178.79,38.96 178.79,38.68 176.35,36.24 176.35,32.13 173.99,29.77 173.99,27.44 168.79,22.24 165.86,22.24 165.43,21.81 163.02,21.81 161.14,19.93 156.97,19.93 155.93,18.89 153.66,18.89 150.94,16.17 148.51,16.17 147.9,15.56 147.9,15.48 147.53,15.1 146.28,15.1 145.54,14.37 145.54,14.08 145.12,13.66 142.95,13.66 v2(142.29,14.32)
  BOTTOM w0.102: v2(142.29,14.32) 142.29,14.47 143.05,15.23 KBBD1.15
KSO9: length 67
  TOP w0.102: AFTP6504.1 146.99,16.02 v2(147.27,15.74) ; v2(182.28,43.26) 182.36,43.26 182.47,43.15 184.22,43.15 184.58,42.79 184.76,42.79 184.88,42.66 184.88,41.52 184.63,41.27 184.22,41.27 184.05,41.44 KBC24.68
  L4 w0.102: v2(147.27,15.74) 148.36,16.83 149.78,16.83 150.11,17.16 151.31,17.16 153.47,19.32 155.75,19.32 157.16,20.72 157.16,20.73 157.47,20.73 158.96,22.22 165.23,22.22 165.66,22.65 168.62,22.65 173.58,27.61 173.58,29.94 175.92,32.27 175.92,36.82 178.05,38.95 178.05,42.18 179.52,43.65 181.3,43.65 181.66,43.3 182.24,43.3 v2(182.28,43.26)
  BOTTOM w0.102: KBBD1.5 148.05,16.61 147.27,15.83 v2(147.27,15.74) ; R2450.1 185.95,43.05 185.7,43.3 R2449.2 185.25,42.87 183.84,42.87 183.39,43.32 182.38,43.32 182.32,43.26 v2(182.28,43.26)
KSO10: length 64.7
  TOP w0.102: RN2410.7 173.59,40.5 175.19,38.89 176.79,38.89 177.54,38.14 179.16,38.14 179.65,38.63 179.65,38.63 180.02,39.01 180.9,39.88 180.9,40.8 v2(181.25,41.16) 181.34,41.16 181.79,40.71 181.79,40.33 181.68,40.23 181.68,39.87 181.94,39.62 182.32,39.62 182.54,39.84 KBC24.72 ; v2(149.32,15.74) 149.91,15.16 AFTP6523.1
  L4 w0.102: v2(181.25,41.16) 180.92,40.83 180.92,40.22 180.64,39.95 180.06,39.95 178.99,38.88 178.99,38.45 176.55,36.01 176.55,32.05 174.19,29.68 174.19,27.36 168.87,22.04 165.96,22.04 165.53,21.61 163.15,21.61 161.25,19.7 157.03,19.7 156.02,18.69 153.74,18.69 150.8,15.74 v2(149.32,15.74)
  BOTTOM w0.102: KBBD1.3 149.05,16.22 149.32,15.94 v2(149.32,15.74)
KSO11: length 64
  TOP w0.102: v2(148.69,15.74) 148.92,15.97 AFTP6522.1 ; RN2410.6 173.6,40 174.92,38.69 176.69,38.69 177.44,37.94 179.25,37.94 179.86,38.55 179.86,38.55 180.11,38.8 180.11,38.8 180.42,39.12 181.15,39.84 181.15,40.33 v2(181.35,40.53) 181.48,40.4 181.48,39.56 182.01,39.04 KBC24.74
  L4 w0.102: v2(181.35,40.53) 181.35,40.2 180.88,39.73 180.15,39.73 179.2,38.78 179.2,37.58 178.38,36.77 178.38,33.47 177.6,32.68 177.49,32.68 174.39,29.58 174.39,27.27 168.96,21.84 166.06,21.84 165.63,21.4 163.24,21.4 161.33,19.5 157.12,19.5 156.11,18.48 153.87,18.48 150.7,15.31 149.12,15.31 v2(148.69,15.74)
  BOTTOM w0.102: KBBD1.4 148.55,15.88 v2(148.69,15.74)
KSO12: length 65.1
  TOP w0.102: KBC24.75 181.9,38.64 181.25,39.29 180.88,39.29 180.63,39.03 180.63,38.68 v2(180.47,38.52) 179.68,37.74 177.34,37.74 176.59,38.49 174.74,38.49 173.87,39.35 RN2410.5 ; v2(145.97,14.19) 145.36,13.58 AFTP6519.1
  L4 w0.102: v2(145.97,14.19) 146.68,14.9 147.62,14.9 147.83,15.1 150.8,15.1 153.97,18.28 156.21,18.28 157.2,19.27 161.39,19.27 163.32,21.2 165.73,21.2 166.17,21.63 169.04,21.63 174.62,27.21 174.62,29.51 177.6,32.48 177.75,32.48 178.59,33.32 178.59,36.54 180.47,38.42 v2(180.47,38.52)
  BOTTOM w0.102: KBBD1.10 145.55,14.61 v2(145.97,14.19)
KSO13: length 59
  TOP w0.102: RN2411.8 180.82,36.72 180.82,38.12 181.06,38.35 v2(181.06,38.85) 181.67,38.24 KBC24.76 ; AFTP6520.1 147.83,13.05 147.83,14.19 v2(147.78,14.24)
  L4 w0.102: v2(181.06,38.85) 181.06,38.07 180.29,37.3 180.29,35.58 178.79,34.08 178.79,33.23 177.83,32.27 177.73,32.27 174.83,29.38 174.83,27.13 169.13,21.43 166.25,21.43 165.82,21 163.4,21 161.47,19.07 157.3,19.07 156.31,18.08 154.07,18.08 150.9,14.9 148.44,14.9 v2(147.78,14.24)
  BOTTOM w0.102: v2(147.78,14.24) 146.63,15.38 146.63,16.3 147.05,16.72 KBBD1.7
KSO14: length 55.2
  TOP w0.102: AFTP6521.1 148.72,14.14 v2(148.64,14.22) ; RN2411.7 181.72,35.55 181.89,35.71 181.89,35.73 v2(182.09,35.93) 182.09,36.47 181.68,36.87 181.68,37.38 182.14,37.84 KBC24.77
  L4 w0.102: v2(182.09,35.93) 181.18,35.93 179.2,33.95 179.2,32.47 177.66,30.93 176.67,30.93 175.03,29.29 175.03,27.05 169.21,21.23 166.33,21.23 165.9,20.79 163.49,20.79 161.56,18.86 157.4,18.86 156.41,17.87 154.18,17.87 151,14.7 149.12,14.7 v2(148.64,14.22)
  BOTTOM w0.102: KBBD1.6 147.55,16.76 146.84,16.04 146.84,15.56 147.09,15.31 147.55,15.31 v2(148.64,14.22)
KSO15: length 54.3
  TOP w0.102: v2(149.27,14.22) 150.54,12.95 AFTP6524.1 ; RN2411.6 181.72,35.05 182.07,34.7 v2(182.07,34.64) 182.14,34.64 182.54,34.24 KBC24.86
  L4 w0.102: v2(182.07,34.64) 180.17,34.64 179.45,33.92 179.45,32.44 177.69,30.67 176.7,30.67 175.26,29.23 175.26,26.99 169.29,21.02 166.42,21.02 165.99,20.59 163.57,20.59 161.64,18.66 157.5,18.66 156.51,17.67 154.28,17.67 151.08,14.47 149.53,14.47 v2(149.27,14.22)
  BOTTOM w0.102: v2(149.27,14.22) 148.84,13.78 147.62,13.78 147.34,14.06 147.34,14.37 146.43,15.28 146.43,16.4 146.55,16.52 KBBD1.8
KSO16: length 55.1
  TOP w0.102: RN2411.5 181.35,33.94 181.13,33.72 180.24,33.72 v2(180.21,33.7) 179.8,33.28 179.8,32.91 180.61,32.1 181.41,32.1 181.66,31.84 KBC24.92 ; AFTP6539.1 147.27,14.6 v2(146.86,14.19)
  L4 w0.102: v2(180.21,33.7) 179.7,33.19 179.7,32.27 177.9,30.47 176.79,30.47 175.46,29.15 175.46,26.9 168.62,20.06 166.84,20.06 165.75,18.97 162.77,18.97 162.21,18.41 157.55,18.41 156.61,17.47 154.38,17.47 151.15,14.24 149.93,14.24 149.48,13.78 147.6,13.78 147.19,14.19 v2(146.86,14.19)
  BOTTOM w0.102: v2(146.86,14.19) 146.86,14.37 146.05,15.18 KBBD1.9
L_BKLT_CTRL: length 79.7
  TOP w0.114: D5502.1 104.33,98.88 104.91,98.88 v1(105.41,99.38) 105.69,99.66 v2(105.69,100.07) 105.69,100.73 105.38,101.03 R5502.2
  L3 w0.114: v2(117.4,41.55) 117.14,41.55 116.86,41.83 116.86,42.64 117.12,42.89 117.32,42.89 117.77,43.34 117.77,46.59 119.14,47.95 119.14,49.29 118.01,50.41 112.67,50.41 112.29,50.79 111.33,50.79 110.05,52.07 110.05,64.58 110.18,64.7 110.18,70.69 109.95,70.91 109.95,73.21 111.3,74.57 111.3,76.39 112.7,77.79 112.7,78.81 113.4,79.51 113.4,82.61 109.48,86.53 109.48,86.91 106.64,89.75 106.14,89.75 104.68,91.22 104.3,91.22 v2(104.06,91.45)
  L4 w0.114: v2(105.69,100.07) 105.69,95.05 104.57,93.94 104.06,93.43 v2(104.06,91.45)
  BOTTOM w0.114: v2(117.4,41.55) 117.63,41.77 117.63,41.85 117.93,42.16 117.93,42.36 117.93,42.36 CPU1.R11
L_BKLT_EN: length 96.2
  TOP w0.102: v1(167.33,34.74) v2(166.77,34.74)
  L4 w0.102: v2(118.48,42.72) 118.48,42.63 118.08,42.23 118.08,38.07 118.4,37.75 118.4,33.84 118.32,33.76 118.32,25.91 119.29,24.95 120.49,24.95 122.34,23.11 124.96,23.11 126.26,24.4 132.76,24.4 133.17,23.99 137.23,23.99 137.84,23.38 138.68,23.38 142.31,27.02 144.12,27.02 144.6,27.5 147.39,27.5 148.33,28.44 149.3,28.44 150.29,29.43 151.28,29.43 151.61,29.76 154.3,29.76 154.94,30.4 160.17,30.4 160.32,30.24 162.3,30.24 163.07,31.01 163.07,31.44 164.89,33.27 165.3,33.27 v2(166.77,34.74)
  L6 w0.102: v2(185.98,35.12) 184.94,36.16 182.93,36.16 182.55,36.54 182.42,36.67 181.76,36.67 181.63,36.54 181.38,36.29 179.25,36.29 178.46,35.5 176.73,35.5 175.49,34.26 170.7,34.26 170.04,34.92 169.6,34.92 169.42,34.74 v2(166.77,34.74)
  BOTTOM w0.102: R2435.2 185.74,34.88 v2(185.98,35.12) ; v2(118.48,42.72) 118.24,42.72 CPU1.R12
L_BKLT_EN_EC: length 74.5
  TOP w0.102: v2(197.97,45.69) 197.97,45.64 197.53,45.2 197.03,45.2 196.81,44.98 KBC24.34
  L4 w0.102: v2(185.62,33.47) 185.62,32.15 184.86,31.39 184.86,28.49 185.52,27.83 185.52,21.91 183.93,20.32 183.93,18.55 v2(183.21,17.82) ; v2(193.14,10.84) 193.44,11.14 193.98,11.14 200.23,17.39 200.23,30.05 198.78,31.5 198.78,39.26 199.03,39.51 199.03,41.16 199.36,41.49 199.36,42.84 199.57,43.04 199.57,43.4 198.78,44.19 198.7,44.19 198.3,44.59 198.09,44.59 197.79,44.9 197.79,45.3 197.97,45.48 v2(197.97,45.69)
  BOTTOM w0.102: v2(193.14,10.84) 192.1,11.88 192.1,12.81 190.13,14.77 186.26,14.77 v1(185.73,15.3) v2(183.21,17.82) ; v2(185.62,33.47) 185.62,33.44 185.38,33.2 R2436.1 185.08,33.32 R2435.1
LCD_BRIGHTNESS: length 20.3
  TOP w0.114: RN5501.4 98.23,95.97 98.7,95.5 99.19,95.5 99.62,95.93 99.62,96.27 EC5501.1 100.32,95.62 103.17,95.62 v2(103.68,96.13)
  L4 w0.114: v2(103.68,96.13) 103.19,96.62 100.84,96.62 99.61,95.39 94.59,95.39 v2(93.72,96.26)
  BOTTOM w0.114: v2(103.68,96.13) 103.68,96.54 v1(103.83,96.69) ; LCD1.30 93.45,95.98 v2(93.72,96.26)
LCD_TST: length 232.3
  TOP w0.102: D5502.2 101.93,97.72 102.16,97.5 v2(102.64,97.5) ; v2(88.49,100.93) 88.49,99.76 89.14,99.12 v1(90.79,99.12) 91.75,98.16 93.5,98.16 93.97,98.63 95.99,98.63 96.43,98.19 RN5501.8
  L3 w0.102: v2(197.46,42.08) 197.99,41.55 197.99,41.47 198,41.46 198,41.1 197.99,41.1 197.99,41.04 197.74,40.78 196.47,40.78 195.96,41.29 193.21,41.29 192.71,41.8 192.71,42.03 192.07,42.66 192.07,42.82 191.67,43.22 185.02,43.22 184.93,43.31 183.27,43.31 181.05,45.53 181.05,45.56 180.8,45.81 180.77,45.81 180.36,46.22 180.36,47.42 179.96,47.83 179.96,49.39 179.6,49.75 179.6,50.46 178.98,51.08 178.98,53.82 178.1,54.69 178.1,60.65 175.33,63.42 175.33,70.53 178.52,73.71 178.52,85.34 177.37,86.49 177.37,88.21 177.57,88.41 177.57,91.06 179.25,92.74 179.25,95.75 178.75,96.24 176.97,96.24 175.23,97.98 172.32,97.98 170.57,99.74 169.92,99.74 167.77,101.9 167.77,104.11 166.04,105.83 166.04,105.84 166.01,105.86 166.01,107.88 161.74,112.16 86.92,112.16 86.8,112.03 86.74,112.03 84.26,109.56 84.26,107.57 79.42,102.73 78.9,102.73 78.26,102.09 v2(78.26,101.36) ; v2(88.49,100.93) 88.49,101.21 88.7,101.41 89.63,101.41 91.11,99.94 97.25,99.94 98.86,98.34 100.71,98.34 101.57,97.48 102.61,97.48 v2(102.64,97.5)
  L6 w0.102: v2(78.26,101.36) 78.28,101.36 78.38,101.46 81.28,101.46 81.58,101.77 87.65,101.77 v2(88.49,100.93)
  BOTTOM w0.102: v2(197.46,42.08) 198.07,41.47 R2419.2
LCD_TST_C: length 7.8
  TOP w0.102: v2(93.09,96.28) 93.09,97.46 93.64,98.01 93.64,98.02 93.9,98.28 v1(95.58,98.28) 95.91,97.95 95.91,96.69 96.09,96.51 RN5501.1
  BOTTOM w0.102: v2(93.09,96.28) 93.09,96.26 92.95,96.12 LCD1.29
LCD_TST_EN: length 227.9
  TOP w0.102: D5501.2 95.18,97.26 95.35,97.1 v1(95.35,96.84) 95.35,96.54 v2(95.65,96.23) ; v2(200.24,40.91) 200.18,40.91 199.51,40.24 199.5,40.24 KBC24.26
  L3 w0.102: v2(200.24,40.91) 199.85,41.3 199.85,43.55 199.41,43.98 199.16,43.98 198.35,44.8 191.62,44.8 191.12,44.29 185.55,44.29 184.55,45.29 183.53,45.29 181.43,47.39 181.43,48.51 181.15,48.78 181.15,49.99 180.87,50.81 180.58,51.1 179.7,51.98 179.7,54.88 179.32,56.1 179.03,57.02 179.03,61.27 176.3,64 176.3,69.97 179.5,73.17 179.5,91.79 179.78,92.07 179.78,96 179.02,96.76 177.13,96.76 175.4,98.49 172.5,98.49 171.17,99.82 171.17,103.45 170.2,104.41 168.15,104.41 166.5,106.06 166.5,108.08 161.94,112.64 86.72,112.64 86.62,112.54 86.56,112.54 83.78,109.76 83.78,107.8 79.19,103.22 78.7,103.22 77.24,101.76 76.96,101.76 76.03,100.83 v2(75.72,100.83)
  L4 w0.102: v2(95.65,96.23) 95.65,98.72 93.32,101.06 89.99,101.06 87.48,103.57 v2(87.48,104.46)
  L6 w0.102: v2(75.72,100.83) 76.15,100.83 78.71,103.39 86.41,103.39 v2(87.48,104.46)
  BOTTOM w0.102: R2419.1 199.59,41.47 200.15,40.91 v2(200.24,40.91)
LCDVDD:
  vias: v1(83.46,92.93) v2(82.95,94.02)
LDO1_CAP: length 5.9
  TOP w0.203: HDA27.39 21.84,13.51 21.51,13.18 21.51,13 21.21,12.69 v2(21.21,12.46)
  BOTTOM w0.254: C2702.2 18.91,12.62 R2711.2 19,12.56 19.73,13.3 v1(20.16,13.3) 21,12.46 v2(21.21,12.46)
LDO2_CAP: length 2.9
  TOP w0.203: HDA27.17 23.84,21.13 v2(23.8,21.17)
  TOP w0.254: v1(23.44,21.68) 23.8,21.33 v2(23.8,21.17)
  BOTTOM w0.254: C2712.2 24.38,21.75 v2(23.8,21.17)
LDO3_CAP: length 3.6
  TOP w0.254: C2718.1 27.28,21.48 v1(27.2,21.4) 27.2,21.28 26.06,20.14 HDA27.13
LID_CL_SIO#: length 305.5
  TOP w0.102: RN2405.3 174.12,43.37 174.71,42.78 174.71,42.56 174.74,42.53 174.74,40.68 175.58,39.83 177.18,39.83 177.93,39.08 178.77,39.08 179.28,39.6 179.28,41.54 v1(179.49,41.74) v2(180.31,42.56) ; R7011.1 15.42,83.58 15.04,83.96 13.56,83.96 v2(13.31,83.71) ; v2(6.4,86.07) 6.41,86.08 GMR1.4 ; v2(193.14,41.98) 193.42,41.98 193.75,42.31 193.75,42.76 194.01,43.02 KBC24.41
  L3 w0.102: v2(36.5,91.33) 37.67,92.5 37.67,94.91 42.02,99.27 47.99,99.27 48.6,99.88 56.93,99.88 57.94,98.87 62.3,98.87 63.05,99.62 75.9,99.62 77.26,100.98 77.62,100.98 77.88,100.73 78.52,100.73 78.89,101.1 78.89,101.64 78.81,101.72 78.81,102.08 79.07,102.33 79.61,102.33 83.47,106.19 84.67,107.39 84.67,109.39 86.91,111.62 86.96,111.62 87.09,111.75 161.57,111.75 165.61,107.71 165.61,105.69 167.31,103.99 167.31,101.46 169.67,99.1 v2(170.31,99.1)
  L4 w0.102: v2(188.01,36.92) 188.72,36.92 189.23,37.43 189.23,39.67 191.01,41.44 192.61,41.44 v2(193.14,41.98)
  L6 w0.102: v2(181.25,36.92) 181.33,36.92 181.68,37.28 181.68,37.28 181.94,37.53 183.21,37.53 183.72,37.02 184.61,37.02 185.52,36.11 186,36.11 186.46,36.57 187.65,36.57 v2(188.01,36.92)
  BOTTOM w0.102: D2402.K 187.63,37.74 188.01,37.35 v2(188.01,36.92) ; v2(170.31,99.1) 170.31,97.04 170.96,96.38 172.08,96.38 172.29,96.59 172.72,96.59 173.4,95.9 178.48,95.9 178.94,95.44 178.94,94.66 177.98,93.69 177.98,92.93 178.94,91.96 178.94,84.58 178.61,84.25 178.61,72.61 175.08,69.08 175.08,63.49 177.85,60.72 177.85,53.52 178.48,52.89 178.48,48.25 178.79,47.95 178.79,46.93 179.4,46.32 180.58,46.32 180.84,46.07 180.85,46.07 181.3,45.61 181.3,45.6 181.61,45.3 181.61,44.49 181.33,44.21 181.19,44.21 180.31,43.34 180.31,42.61 180.31,42.61 v2(180.31,42.56) 180.31,42.56 180.39,42.49 181.37,42.49 181.87,41.98 181.95,41.98 182.55,41.38 182.55,39.64 181.25,38.35 v2(181.25,36.92) ; v2(6.4,86.07) 7.09,86.07 9.58,83.58 13.17,83.58 v2(13.31,83.71) 14.58,84.98 14.58,86.02 16.53,87.98 20.57,87.98 23.77,91.18 25,91.18 25.37,90.8 25.37,90.06 25.8,89.63 27.33,89.63 27.84,90.14 30.34,90.14 31.26,91.05 36.22,91.05 v2(36.5,91.33)
LINE1-L_C: length 2.4
  BOTTOM w0.254: R2922.1 16.52,15.35 C2907.2 16.66,14.24 v1(16.48,14.06)
LINE1-L_R: length 1.1
  BOTTOM w0.254: C2908.2 17.9,22.57 R2921.1
LINE1_L: length 2.7
  TOP w0.203: HDA27.34 19.71,15.71 19.64,15.64 19.64,15.64 19.5,15.51 19.5,15.36 v2(19.1,14.95)
  BOTTOM w0.254: C2907.1 18.24,14.95 v2(19.1,14.95)
LINE1_R: length 12.6
  TOP w0.203: HDA27.33 19.64,16.11 19.12,15.59 v2(19.02,15.59)
  TOP w0.254: v1(19.43,24.25) 19.76,23.92 v2(19.76,23.66)
  L3 w0.254: v2(19.76,23.66) 19.76,23.05 19.48,22.78 19.48,20.46 19.3,20.29 19.3,18.91 18.46,18.08 18.46,16.09 18.85,15.71 18.9,15.71 v2(19.02,15.59)
  BOTTOM w0.254: v2(19.76,23.66) 19.76,23.05 19.66,22.95 19.66,22.15 C2908.1
LINE1_VREFO_L: length 15.8
  TOP w0.203: v2(25.45,21.17) 25.45,21.13 25.04,20.72 HDA27.14
  TOP w0.254: v2(14.91,18.13) 14.64,18.13 v1(14.07,17.56)
  L6 w0.254: v2(14.91,18.13) 19.48,18.13 21.94,20.59 24.95,20.59 25.32,20.96 25.32,21.05 v2(25.45,21.17)
  BOTTOM w0.254: v2(14.91,18.13) 16.5,18.13 R2912.1
LINE1_VREFO_R: length 10.1
  TOP w0.203: HDA27.15 24.64,21 v2(24.81,21.17)
  TOP w0.254: v1(18.34,22.57) 18.34,22.75 v2(18.67,23.08)
  L6 w0.254: v2(24.81,21.17) 23.93,22.06 23.16,22.06 22.15,23.08 v2(18.67,23.08)
  BOTTOM w0.254: v2(18.67,23.08) 18.13,23.08 17.8,23.41 R2913.1
LPC_FRAME#_DEBUG: length 4.3
  TOP w0.089: R6801.2 146.25,5.55 v1(147.09,4.72) 147.24,4.56 147.67,4.56 v2(147.7,4.59)
  BOTTOM w0.089: v2(147.7,4.59) 147.67,4.56 146.84,4.56 146.36,5.04 146.36,5.66 146.36,5.66 DB1.6
LPC_LAD0: length 177
  TOP w0.089: RN6801.1 150.05,7.12 149.86,7.31 v2(149.83,7.31) 146.61,10.53 140.05,10.53 139.3,11.28 131.22,11.28 v2(130.35,10.41) ; KBC24.59 186.81,44.93 185.88,45.86 182.27,45.86 181.79,45.38 181.28,45.38 180.31,44.42 v2(180.15,44.42) ; v2(89.99,25.34) 89.85,25.34 89.38,25.81 89.38,26.71 87.02,29.07 87.02,38.27 90.08,41.33 RN1806.8
  L3 w0.127: v2(180.15,44.42) 180.15,43.03 179.86,42.74 179.86,42.04 179.85,42.04 179.85,41.67 179.86,41.67 179.86,41.46 180.45,40.87 180.76,40.87 180.9,40.73 180.9,39.86 182.8,37.96 182.8,33.15 183.37,32.58 183.37,30.53 183.85,30.05 183.85,30.05 184.43,29.47 184.43,28.77 184.8,28.4 184.8,22.88 184.43,22.51 184.43,11.62 184.13,11.33 v2(184.13,10.35)
  L4 w0.127: v2(130.35,10.41) 129.16,11.6 128.73,11.6 127.57,12.75 123.16,12.75 122.77,13.15 121.79,13.15 121.28,13.66 115.93,13.66 114.24,15.35 107.57,15.35 107.01,15.9 102.58,15.9 102.35,15.68 101.51,15.68 101.4,15.79 99.64,15.79 98.22,17.21 96.92,17.21 95.48,18.66 93.43,18.66 92.17,19.92 92.17,22.11 91.82,22.47 91.82,24.04 90.52,25.34 v2(89.99,25.34)
  BOTTOM w0.089: v2(149.83,7.31) 150.35,7.83 183.82,7.83 v1(184.39,8.4) 184.5,8.4 185.37,9.26 185.69,9.26 186.49,10.06 186.49,10.71 186.23,10.96 184.74,10.96 v2(184.13,10.35)
LPC_LAD0_C: length 4
  TOP w0.089: v2(150.29,4.59) 150.29,4.66 151,5.38 v1(151,5.5) 150.1,5.5 RN6801.8
  BOTTOM w0.089: DB1.2 151.36,5.79 151.36,5.4 150.56,4.59 v2(150.29,4.59)
LPC_LAD0_R: length 15.6
  TOP w0.089: RN1806.1 v1(91.62,43.1) 93.95,43.1 94.2,42.85 96.45,42.85 v2(96.49,42.89)
  BOTTOM w0.089: CPU1.AY13 104.3,43.43 104.07,43.43 103.83,43.2 102.97,43.2 102.82,43.04 101.67,43.04 101.34,42.71 98.8,42.71 98.02,43.5 97.08,43.5 96.49,42.92 v2(96.49,42.89)
LPC_LAD1: length 173.6
  TOP w0.089: v2(180.8,42.97) 180.8,43.7 181.34,44.24 181.35,44.24 181.6,44.49 181.6,44.51 182.74,45.65 185.66,45.65 186.41,44.9 KBC24.60 ; v2(89.69,24.78) 88.89,24.78 88.09,25.59 88.09,26.74 86.09,28.73 86.09,38.15 89.43,41.49 RN1806.7 ; RN6801.2 149.4,6.95 149.12,7.23 v2(149.12,7.28) 149.07,7.28 146.3,10.06 138.52,10.06 137.57,11.01 131.56,11.01 130.53,9.98 130.14,9.98 v2(129.72,10.41)
  L3 w0.127: v2(180.8,42.97) 181.15,42.97 181.75,42.37 182.12,42.37 182.12,42.37 182.88,42.37 183.95,41.3 183.95,40.99 183.95,40.99 183.95,33.62 185.61,31.96 185.61,29.35 186,28.96 186,22.47 185.57,22.04 185.57,11.93 186.06,11.44 v2(186.06,10.33)
  L4 w0.127: v2(129.72,10.41) 128.9,11.22 128.55,11.22 127.39,12.37 123,12.37 122.61,12.77 121.61,12.77 121.23,13.15 115.9,13.15 114.09,14.96 101.66,14.96 101.22,15.41 99.48,15.41 98.06,16.83 96.75,16.83 95.3,18.28 93.13,18.28 91.26,20.15 91.26,23.33 90.9,23.69 90.9,23.94 90.06,24.78 v2(89.69,24.78)
  BOTTOM w0.089: v2(186.06,10.33) 185.3,9.57 184.96,9.57 183.69,8.3 v1(178.28,8.3) 150.14,8.3 v2(149.12,7.28)
LPC_LAD1_C: length 3
  TOP w0.089: RN6801.7 149.4,4.8 149.6,4.59 v2(149.63,4.59) 149.63,4.56 149.96,4.23 v1(149.96,4.13)
  BOTTOM w0.089: DB1.3 150.11,5.71 150.11,5.71 150.11,5.05 149.66,4.59 v2(149.63,4.59)
LPC_LAD1_R: length 15.9
  TOP w0.089: RN1806.2 89.43,43.47 89.84,43.88 v1(92.73,43.88) 95.63,43.88 v2(95.78,44.03)
  BOTTOM w0.089: v2(95.78,44.03) 96.01,43.81 97.97,43.81 98.37,43.4 98.47,43.4 98.98,42.89 101.27,42.89 101.6,43.22 102.74,43.22 102.89,43.37 103.36,43.37 103.69,43.71 103.69,43.71 103.69,43.71 CPU1.BA13
LPC_LAD2: length 172
  TOP w0.089: KBC24.61 186.01,44.89 185.49,45.41 182.98,45.41 181.27,43.7 181.27,42.07 v2(181.15,41.95) ; v2(129.08,10.41) 129.77,9.71 130.95,9.71 131.31,10.07 137.82,10.07 138.33,9.57 146.05,9.57 v2(148.33,7.28) 148.4,7.28 148.9,6.79 RN6801.3 ; RN1806.6 88.93,41.68 85.82,38.57 85.82,28.34 87.76,26.41 87.76,25.54 89.02,24.27 89.94,24.27 v2(89.99,24.22)
  L3 w0.127: v2(185.42,10.33) 185.42,11.54 185.19,11.77 185.19,22.2 185.62,22.63 185.62,28.8 185.23,29.19 185.23,29.75 185.23,31.8 183.56,33.46 183.56,41.14 182.72,41.99 181.96,41.99 181.96,41.99 181.59,41.99 181.59,41.99 181.19,41.99 v2(181.15,41.95)
  L4 w0.127: v2(129.08,10.41) 128.65,10.84 128.37,10.84 127.21,11.99 122.52,11.99 122.21,11.69 120.01,11.69 119.41,12.28 118.14,12.28 117.71,12.72 115.78,12.72 115.37,13.12 114.55,13.12 113.9,13.77 112.31,13.77 111.71,14.37 111.4,14.37 110.7,14.37 110.35,14.02 107.86,14.02 107.3,14.58 101.48,14.58 101.04,15.03 99.32,15.03 97.9,16.45 96.57,16.45 95.12,17.9 92.98,17.9 90.75,20.12 90.75,23.11 90.4,23.46 90.4,23.82 v2(89.99,24.22)
  BOTTOM w0.089: v2(148.33,7.28) 149.82,8.77 v1(179.86,8.77) 183.53,8.77 184.61,9.85 184.94,9.85 v2(185.42,10.33)
LPC_LAD2_C: length 2.8
  TOP w0.089: v1(148.69,4.11) 148.69,4.26 148.99,4.56 v2(148.99,4.59) 148.9,4.69 RN6801.6
  BOTTOM w0.089: v2(148.99,4.59) 148.86,4.72 148.86,5.79 DB1.4
LPC_LAD2_R: length 16.1
  TOP w0.089: RN1806.3 88.93,43.73 89.43,44.24 v1(94.84,44.24) 95.44,44.24 95.62,44.42 96.22,44.42 v2(96.26,44.47)
  BOTTOM w0.089: CPU1.BB13 103.12,43.55 102.82,43.55 102.67,43.4 101.52,43.4 101.19,43.07 99.06,43.07 97.84,44.29 96.44,44.29 v2(96.26,44.47)
LPC_LAD3: length 170.6
  TOP w0.089: RN1806.5 88.28,41.71 84.99,38.42 84.99,28.72 87.45,26.25 87.45,24.32 88.03,23.74 89.08,23.74 v2(89.13,23.79) ; RN6801.4 147.97,6.42 v2(147.12,7.28) 145.38,9.02 138.19,9.02 137.41,9.8 131.72,9.8 131.14,9.22 128.87,9.22 v2(127.91,10.18) ; KBC24.62 185.61,43.33 185.52,43.25 184.64,43.25 184.63,43.25 184.13,43.76 182.01,43.76 181.79,43.53 181.79,41.56 v2(181.77,41.55)
  L3 w0.127: v2(181.77,41.55) 182.62,41.55 183.18,40.99 183.18,33.3 183.75,32.74 183.75,30.68 184.81,29.63 184.81,29.07 185.24,28.64 185.24,22.79 184.81,22.35 184.81,10.35 v2(184.78,10.33)
  L4 w0.127: v2(89.13,23.79) 89.84,23.08 89.84,20.46 92.78,17.52 94.94,17.52 96.39,16.07 97.74,16.07 99.17,14.65 100.07,14.65 100.52,14.2 107.14,14.2 107.7,13.64 110.51,13.64 110.85,13.99 111.56,13.99 112.15,13.39 113.75,13.39 114.39,12.74 115.22,12.74 115.62,12.34 117.55,12.34 117.98,11.9 119.25,11.9 119.85,11.31 122.59,11.31 122.9,11.61 127.03,11.61 127.91,10.73 v2(127.91,10.18)
  BOTTOM w0.089: v2(147.12,7.28) 147.39,7.28 149.35,9.24 v1(183.03,9.24) 183.62,9.24 184.71,10.33 v2(184.78,10.33)
LPC_LAD3_C: length 3.5
  TOP w0.089: v1(147.32,5.93) 147.76,5.93 RN6801.5 148.25,4.73 v2(148.36,4.61)
  BOTTOM w0.089: v2(148.36,4.61) 148.36,4.66 147.61,5.41 147.61,5.79 DB1.5
LPC_LAD3_R: length 19.7
  TOP w0.089: v2(96.52,45.08) 95.76,45.08 95.27,44.59 89.08,44.59 v1(88.8,44.32) 88.28,43.79 RN1806.4
  BOTTOM w0.089: CPU1.AY12 104.91,43.8 104.68,44.03 104.27,44.03 104.21,43.98 103.86,43.98 103.72,43.94 103.48,43.94 103.47,43.95 103.39,43.98 103.05,43.98 102.8,43.73 102.74,43.73 102.59,43.58 101.45,43.58 101.12,43.25 99.19,43.25 97.56,44.87 96.72,44.87 v2(96.52,45.08)
LPC_LFRAME#: length 179.6
  TOP w0.089: R1801.1 89.74,40.26 87.29,37.81 87.29,29.29 89.81,26.76 v2(89.81,25.98) ; KBC24.58 187.21,43.26 186.6,42.65 v2(186.6,42.45) ; R6801.1 146.25,7.26 v2(146.23,7.28) 144.8,8.71 137.83,8.71 137.01,9.54 132.12,9.54 131.54,8.96 128.5,8.96 v2(127.28,10.18)
  L3 w0.127: v2(186.6,42.45) 186.6,41.84 188.27,40.17 189.9,40.17 192.06,38.02 192.64,38.02 194.33,36.33 194.33,33.72 198.3,29.76 198.3,17.75 195.6,15.05 193.06,15.05 192.21,14.2 190.47,14.2 190.17,14.2 189.01,13.05 189.01,10.81 v2(188.53,10.32)
  L4 w0.127: v2(89.81,25.98) 89.53,25.7 89.53,25.26 89.23,24.96 89.23,24.63 88.68,24.08 88.68,23.27 88.92,23.03 88.92,20.83 92.62,17.14 94.77,17.14 96.21,15.69 97.59,15.69 99.01,14.27 99.9,14.27 100.34,13.82 106.98,13.82 107.54,13.26 110.67,13.26 110.99,13.58 111.42,13.58 111.99,13.01 113.59,13.01 114.23,12.36 115.06,12.36 115.48,11.94 117.27,11.94 117.49,11.73 117.69,11.52 119.09,11.52 119.69,10.93 124.5,10.93 124.52,10.95 125.23,10.95 125.55,10.63 126.82,10.63 v2(127.28,10.18)
  BOTTOM w0.089: v2(188.53,10.32) 188.53,10.78 187.86,11.45 184.33,11.45 183.69,10.8 183.69,9.92 183.46,9.69 181.1,9.69 v1(181.07,9.72) 181.06,9.71 148.85,9.71 146.43,7.28 v2(146.23,7.28)
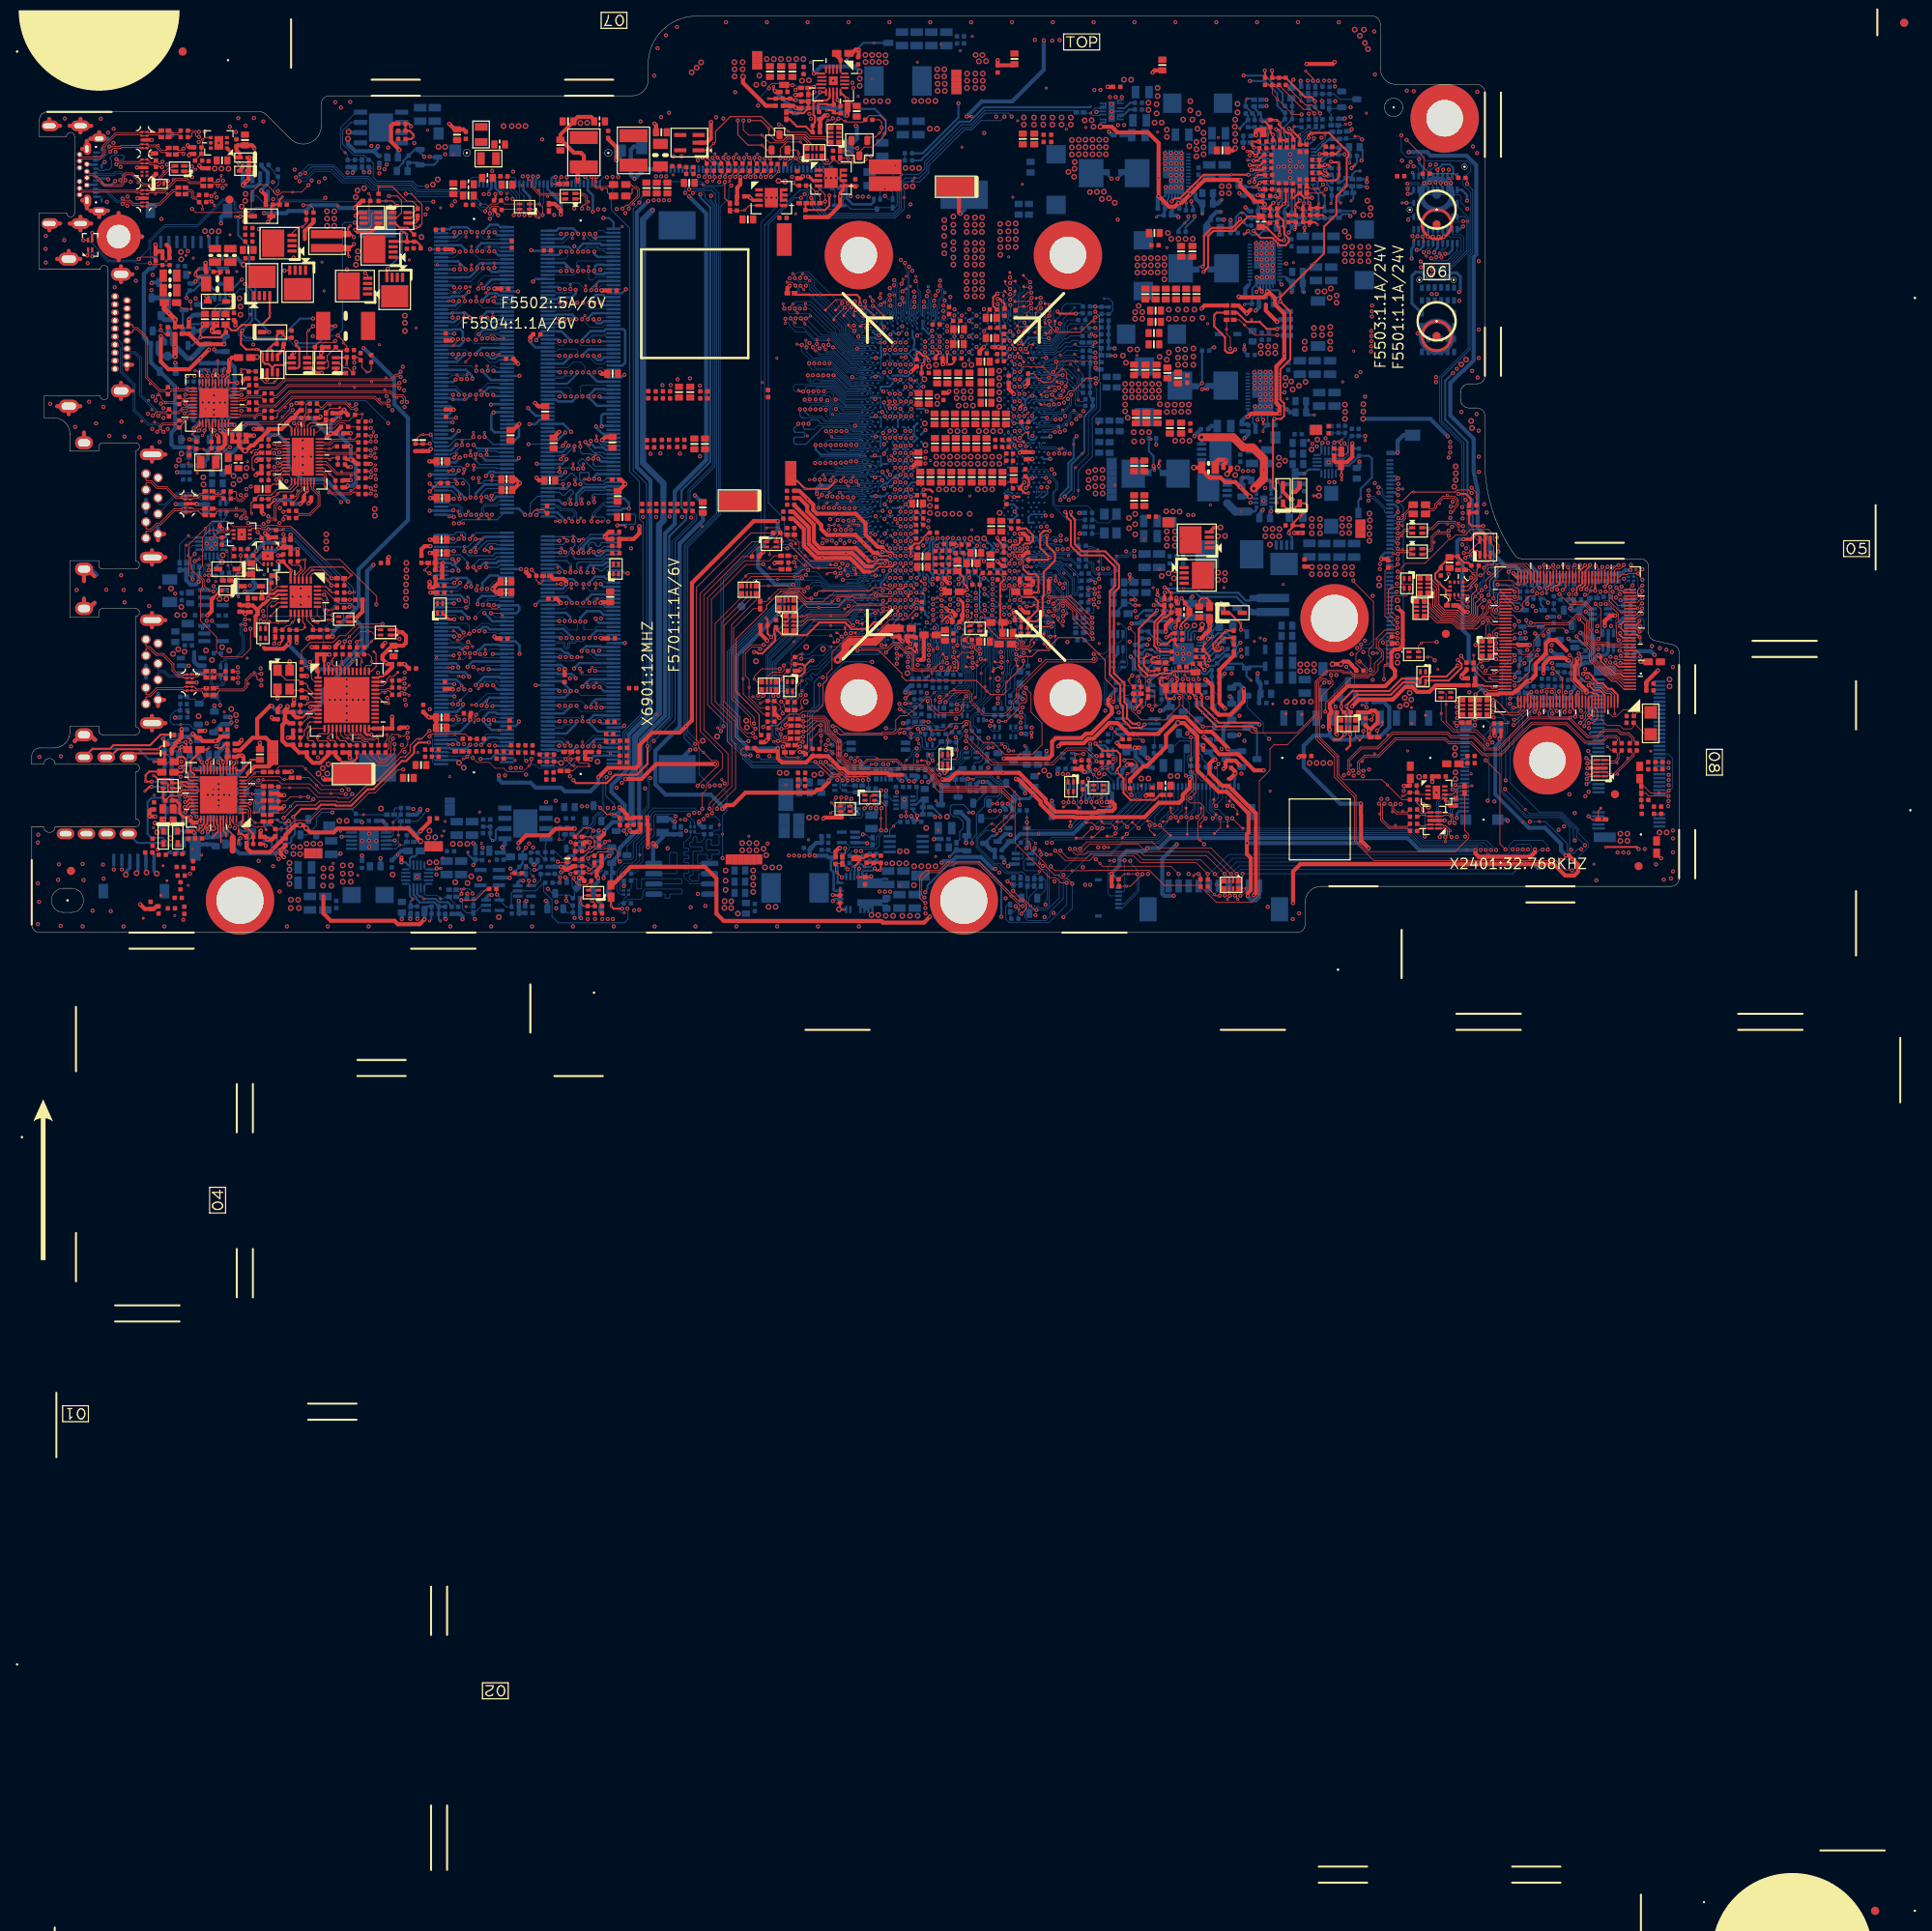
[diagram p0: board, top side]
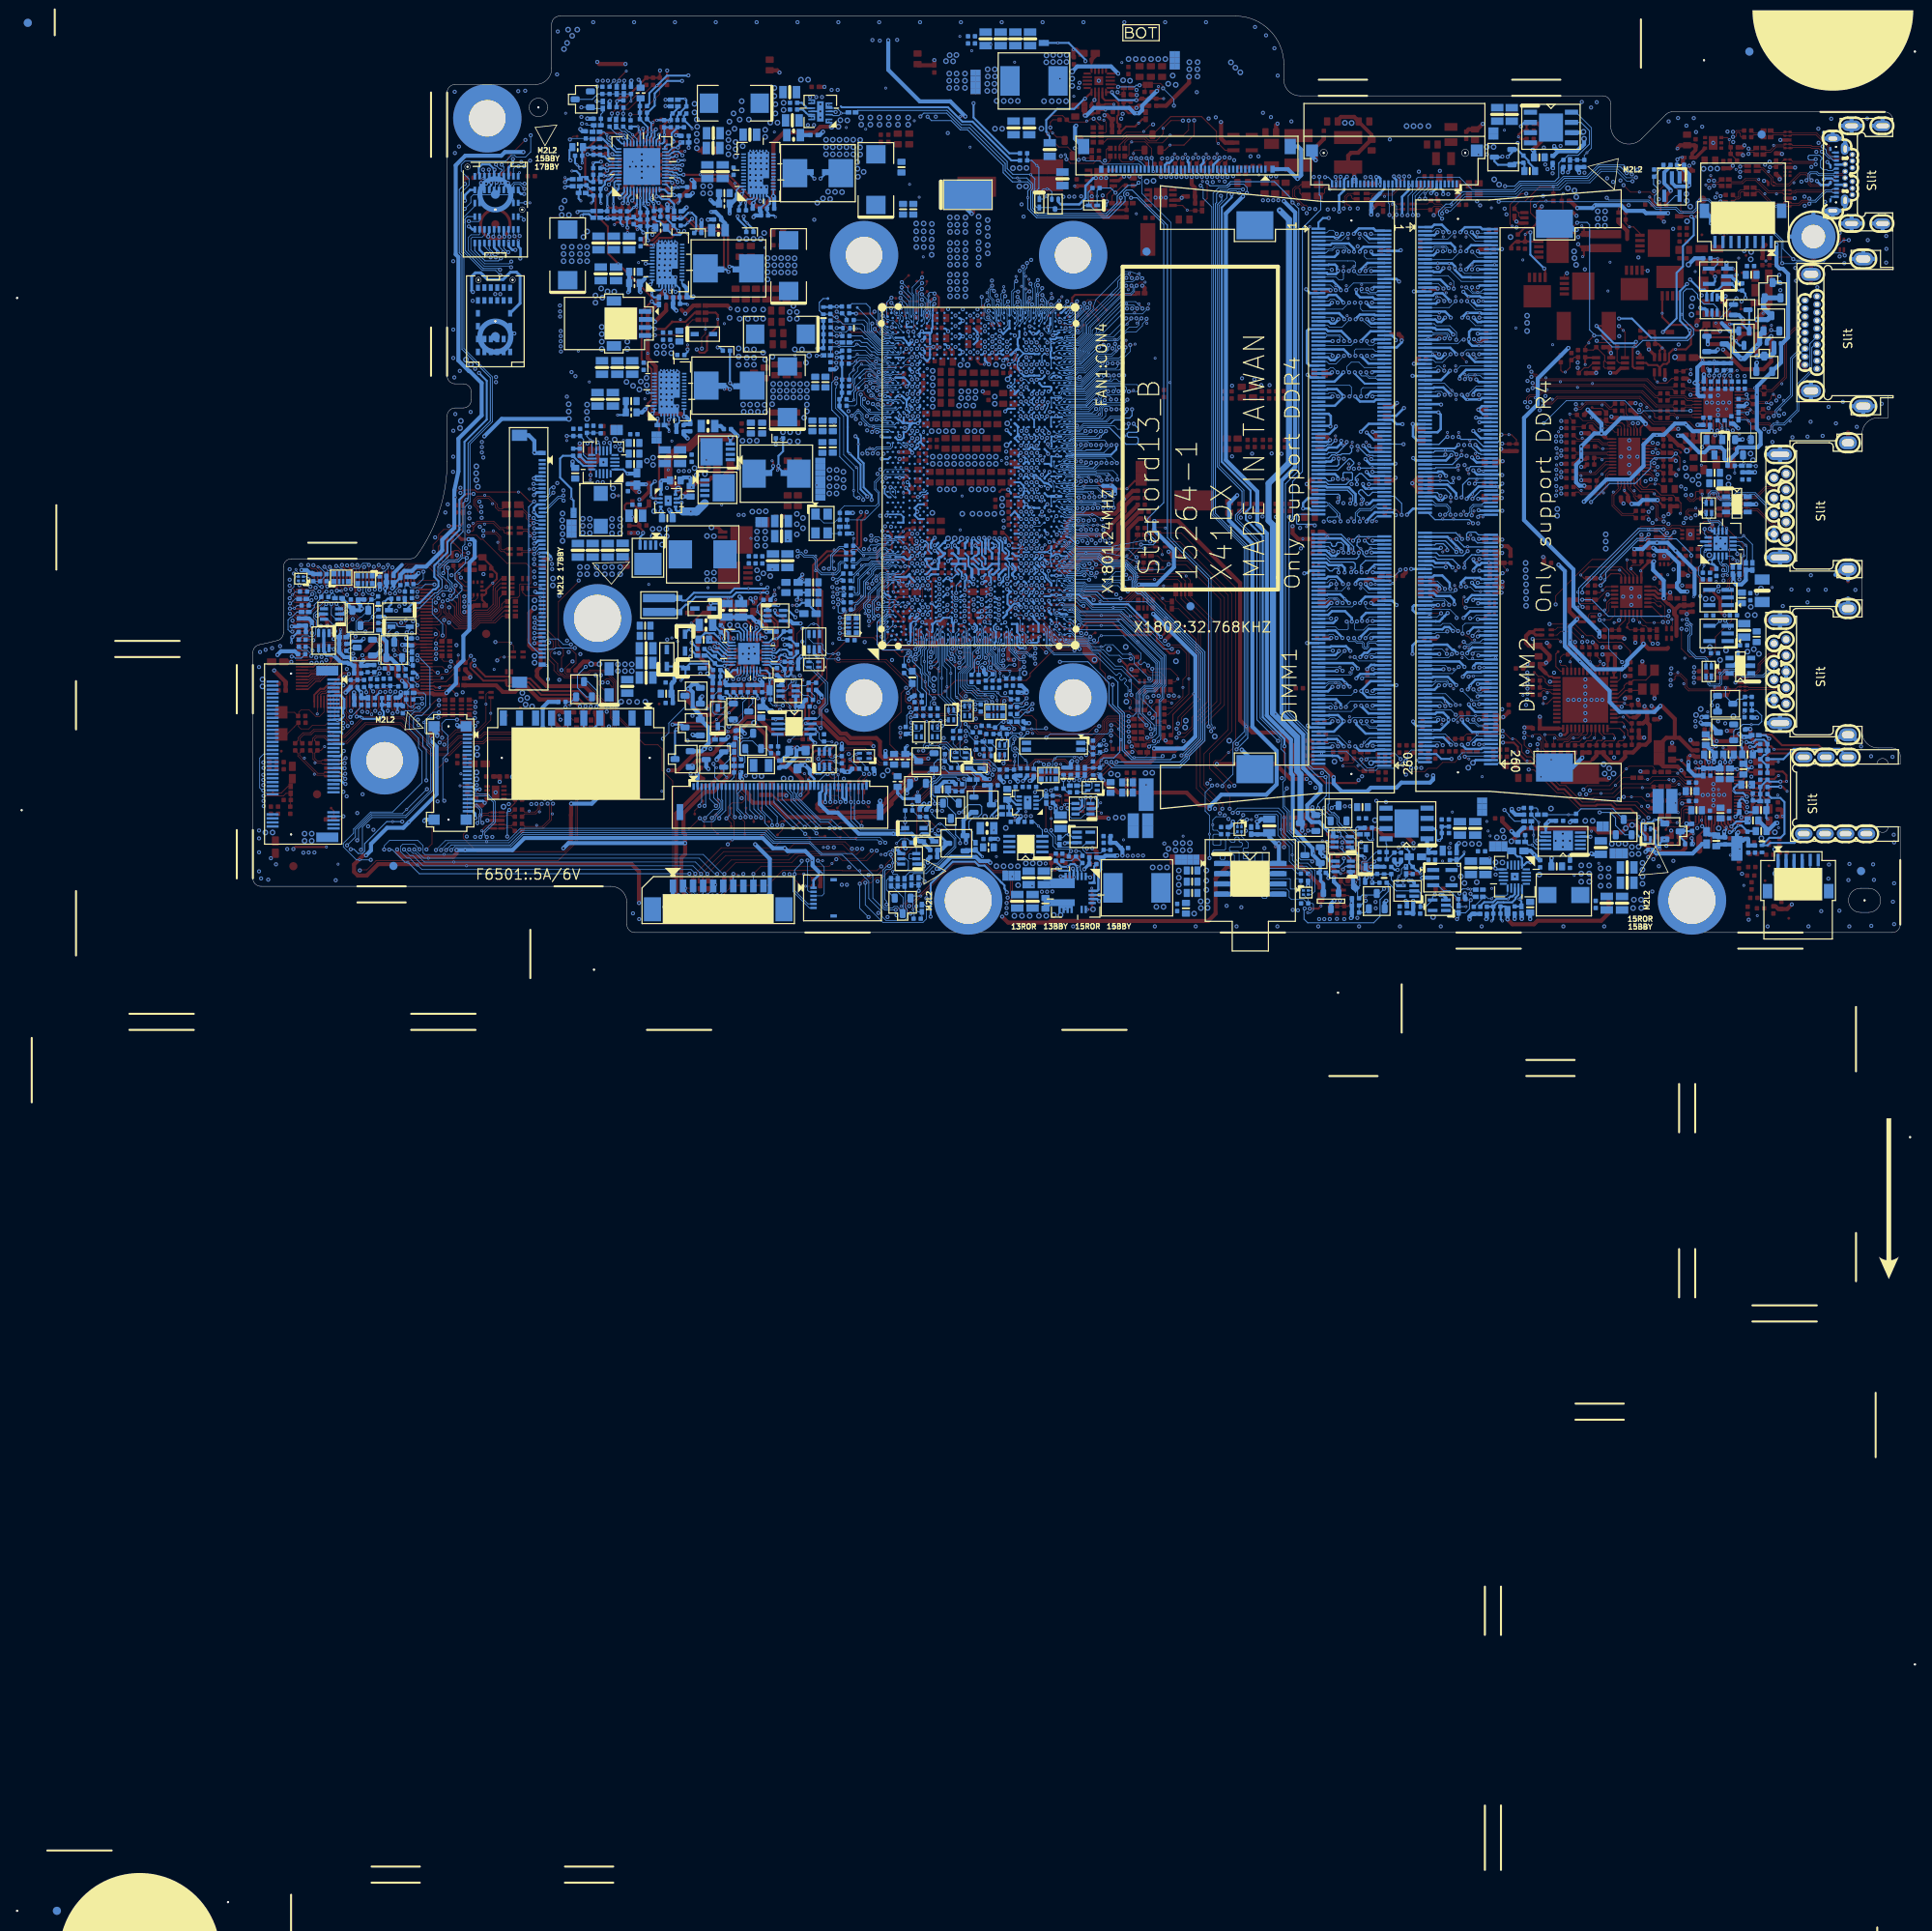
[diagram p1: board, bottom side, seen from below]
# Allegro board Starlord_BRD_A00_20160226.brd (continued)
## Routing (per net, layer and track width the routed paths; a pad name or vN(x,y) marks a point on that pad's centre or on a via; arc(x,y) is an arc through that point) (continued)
LPC_LFRAME#_R: length 15.3
  TOP w0.089: v2(96.06,42.41) 95.81,42.66 92.86,42.66 v1(91.73,41.53) 91.35,41.15 R1801.2
  BOTTOM w0.089: CPU1.BA12 104.01,42.89 103.66,42.89 103.53,43.02 103.05,43.02 102.89,42.87 101.75,42.87 101.42,42.54 98.7,42.54 98.12,43.12 97.28,43.12 96.62,42.46 96.11,42.46 v2(96.06,42.41)
LPSS_UART2_RXD: length 6.7
  BOTTOM w0.089: R2048.2 110.72,32.03 v1(110.72,32.5) 110.82,32.6 111.81,32.6 111.82,32.61 111.85,32.61 112.59,33.35 112.59,34.45 113.2,35.06 113.2,35.68 113.16,35.72 113.16,35.72 113.12,35.76 CPU1.AD1
LPSS_UART2_TXD: length 6.5
  BOTTOM w0.089: R2049.2 111.94,31.42 v1(111.94,32.25) 111.94,32.45 112.77,33.28 112.77,34.33 113.38,34.94 113.38,35.75 113.38,35.75 113.38,36.28 113.38,36.3 113.38,36.5 113.33,36.63 113.33,36.84 CPU1.AD2
LVDS_VDD_EN_R: length 20.3
  TOP w0.127: RN5502.8 98.99,98.25 98.6,98.64 96.7,98.64 96.18,99.17 D5501.3 90.73,101.43 86.87,101.43 85.02,99.58 85.02,98.3 v1(84.81,98.09) 83.96,97.24 U5501.1
M_A_A0: length 50.3
  TOP w0.152: v1(65.12,51.12) v2(65.68,51.12)
  L3 w0.089: v2(96.11,66.23) 95.91,66.03 93.31,66.03
  L3 w0.203: 93.31,66.03 93.28,66.06 86.47,66.06 83.13,62.72 82.35,62.72 80.66,61.03 79.98,61.03 78.65,59.7 78.65,59.36 76.2,56.9 75.12,56.9 74.53,56.31 73.64,56.31 72.16,54.83 68.73,54.83 68.65,54.75 67.08,54.75 65.68,53.36 v2(65.68,51.12)
  BOTTOM w0.089: v2(96.11,66.23) 96.11,66.16 96.42,65.85 98.68,65.85 98.78,65.75 99.1,65.75 99.59,65.26 99.59,64.93 100.11,64.41 102.82,64.41 103.04,64.19 103.94,64.19 104.25,64.5 104.46,64.5 CPU1.AY50
  BOTTOM w0.152: DM1.144 65.07,51.73 v2(65.68,51.12)
M_A_A1: length 49.4
  TOP w0.152: v1(69.94,54.07) v2(69.94,53.51)
  L3 w0.089: v2(98.93,66.16) 98.93,66.98 99.6,67.65 100.32,67.65 100.42,67.55 100.42,66.81 100.32,66.71 99.69,66.71 99.59,66.6 99.59,65.85 99.36,65.62 94.75,65.62 94.17,65.05 93.01,65.05
  L3 w0.203: 93.01,65.05 86.89,65.05 82.81,60.96 82.36,60.96 81.31,59.92 80.89,59.92 80.8,60.01 80.4,60.01 80.12,59.73 80.12,59.25 76.76,55.89 75.54,55.89 74.19,54.54 73.31,54.54 72.58,53.81 70.31,53.81 70,53.51 v2(69.94,53.51)
  BOTTOM w0.089: CPU1.BB50 103.28,64.63 103.15,64.77 100.89,64.77 100.16,65.5 99.62,65.5 99.19,65.93 99.16,65.93 v2(98.93,66.16)
  BOTTOM w0.152: v2(69.94,53.51) 69.68,53.77 69.68,54.3 69.86,54.48 DM1.133
M_A_A2: length 51.9
  TOP w0.152: v1(67.01,53.86) v2(67.01,53.28)
  L3 w0.089: 93,65.56 93.28,65.56 93.39,65.44 94.16,65.44 94.53,65.8 97.97,65.8 98.14,65.97 v2(98.14,66.26)
  L3 w0.203: v2(67.01,53.28) 67.01,53.97 67.29,54.25 68.88,54.25 68.96,54.32 72.37,54.32 73.09,55.05 73.98,55.05 75.33,56.4 76.41,56.4 79.16,59.15 79.16,59.49 80.19,60.52 81.05,60.52 82.2,61.67 82.79,61.67 86.68,65.56 93,65.56
  BOTTOM w0.089: v2(98.14,66.26) 98.14,66.5 98.34,66.69 99.14,66.69 99.34,66.5 99.34,66.03 99.7,65.68 100.28,65.68 100.89,65.07 101.85,65.07 101.87,65.08 103.08,65.08 103.27,64.9 103.36,64.9 103.51,64.85 103.71,64.85 103.91,64.91 104.54,64.91 104.69,65.03 CPU1.AY51
  BOTTOM w0.152: v2(67.01,53.28) 67.01,53.34 66.66,53.69 66.66,53.9 67.36,54.6 67.36,54.82 67.14,55.03 66.93,55.03 66.23,54.34 66.02,54.34 65.62,54.73 DM1.132
M_A_A3: length 51
  TOP w0.152: v1(68.4,53.92) v2(68.4,53.34)
  L3 w0.089: 92.75,64.54 93.99,64.54 94.88,65.43 99.5,65.43 99.79,65.72 99.98,65.72 100.8,66.54 100.95,66.54 101.13,66.36 101.13,66.22 v2(100,65.09)
  L3 w0.203: 92.75,64.54 87.11,64.54 83.02,60.46 82.57,60.46 80.65,58.54 80.12,58.54 76.97,55.38 75.75,55.38 74.4,54.03 73.52,54.03 72.79,53.31 70.53,53.31 70.12,52.89 68.85,52.89 v2(68.4,53.34)
  BOTTOM w0.089: v2(100,65.09) 100.5,64.59 102.89,64.59 103.11,64.37 103.68,64.37 CPU1.BA50
  BOTTOM w0.152: DM1.131 68.74,54.98 68.09,54.34 68.09,53.65 v2(68.4,53.34)
M_A_A4: length 51.1
  TOP w0.152: v1(66.07,55.17) v2(66.07,55.73)
  L3 w0.102: v2(97.84,67.28) 97.84,67.06 97.59,66.81 95.21,66.81
  L3 w0.203: 95.21,66.81 94.94,67.08 86.05,67.08 82.74,63.77 81.91,63.77 81.2,63.07 79.92,63.07 79.52,62.67 79.52,62.09 77.98,60.55 77.66,60.55 77.53,60.42 77.51,60.42 77.09,59.99 76.74,59.99 76.46,59.71 76.46,59.01 75.39,57.94 74.71,57.94 74.1,57.33 73.22,57.33 71.74,55.85 69.09,55.85 68.29,56.64 64.87,56.64 64.67,56.44 64.67,55.88 64.87,55.68 66.02,55.68 v2(66.07,55.73)
  BOTTOM w0.089: CPU1.BB52 101.2,65.96 99.4,67.76 97.66,67.76 97.53,67.63 97.53,67.5 97.76,67.28 v2(97.84,67.28)
  BOTTOM w0.152: v2(66.07,55.73) 66.01,55.73 66.01,55.73 DM1.128
M_A_A5: length 51.1
  TOP w0.152: v1(67.49,56.28) 67.57,56.2 v2(67.57,55.72)
  L3 w0.089: 94.5,66.52 95.84,66.52 95.94,66.62 96.58,66.62 96.75,66.45 v2(96.75,66.26)
  L3 w0.203: v2(67.57,55.72) 67.57,55.45 67.76,55.26 68.43,55.26 68.5,55.34 71.95,55.34 73.43,56.82 74.32,56.82 74.91,57.41 75.99,57.41 76.36,57.78 76.36,58.07 76.94,58.65 77.22,58.65 77.69,59.11 77.69,59.76 77.97,60.04 78.19,60.04 80.03,61.88 80.03,62.28 80.31,62.56 81.47,62.56 82.14,63.23 82.92,63.23 86.26,66.57 94.45,66.57 94.5,66.52
  BOTTOM w0.089: v2(96.75,66.26) 96.54,66.46 96.54,66.77 96.64,66.86 96.73,66.86 96.74,66.87 98.63,66.87 98.64,66.89 98.66,66.89 98.97,67.2 99.37,67.2 99.73,66.84 99.73,66.61 99.52,66.4 99.52,66.4 99.52,66.11 99.77,65.85 100.35,65.85 100.95,65.26 103.21,65.26 103.39,65.08 103.54,65.03 103.68,65.03 103.88,65.09 103.97,65.09 CPU1.BA51
  BOTTOM w0.152: v2(67.57,55.72) 67.57,56.05 67.76,56.25 67.76,56.54 67.26,57.04 66.97,57.04 66.17,56.23 DM1.126
M_A_A6: length 50.6
  TOP w0.152: v1(68.73,56.35) v2(69.29,56.35)
  L3 w0.203: v2(69.29,56.35) 69.31,56.38 69.31,56.45 69.72,56.86 71.26,56.86 75.92,61.52 76.99,61.52 77.27,61.8 77.27,61.92 79.46,64.11 80.77,64.11 82.12,65.46 82.12,66.23 83.99,68.1 96.34,68.1 96.57,67.87 v2(96.57,67.25)
  BOTTOM w0.089: v2(96.57,67.25) 96.48,67.25 96.24,67.5 96.24,67.73 96.44,67.94 99.53,67.94 101.23,66.23 103.66,66.23 CPU1.BA52
  BOTTOM w0.152: v2(69.29,56.35) 69.29,57.08 69.19,57.18 68.22,57.18 68.12,57.08 68.12,56.3 68.22,56.2 68.41,56.2 68.92,55.7 71.13,55.7 71.42,55.98 DM1.127
M_A_A7: length 52.7
  TOP w0.152: v1(65.64,57.83) v2(65.64,57.27)
  L3 w0.203: v2(98.5,67.28) 97.95,67.82 97.09,67.82 96.45,68.46 95.3,68.46 95.22,68.53 95.15,68.6 83.04,68.6 82.61,68.17 82.61,67.43 81.62,66.44 81.62,65.67 80.56,64.62 79.19,64.62 77.2,62.63 76.31,62.63 71.05,57.37 69.51,57.37 69.29,57.15 67.11,57.15 66.83,57.43 66.83,57.45 66.55,57.73 66.53,57.73 65.93,58.33 64.63,58.33 64.43,58.14 64.43,57.46 64.64,57.26 65.63,57.26 v2(65.64,57.27)
  BOTTOM w0.089: v2(98.5,67.28) 98.5,67.3 98.78,67.58 99.33,67.58 99.71,67.2 101.24,65.68 104.16,65.68 104.48,65.57 104.95,65.57 CPU1.AW52
  BOTTOM w0.152: DM1.122 65.6,57.23 v2(65.64,57.27)
M_A_A8: length 51.4
  TOP w0.152: v1(95.35,67.4) 95.5,67.25 v2(95.93,67.25)
  L3 w0.203: v2(70.56,56.38) 70.58,56.35 71.53,56.35 73.4,58.22 73.68,58.22 73.84,58.06 74.12,58.06 74.41,58.36 74.41,58.64 74.26,58.8 74.26,59.08 74.65,59.48 74.94,59.48 75.39,59.02 75.68,59.02 75.95,59.3 75.95,59.61 75.51,60.05 75.51,60.34 76.1,60.93 77.32,60.93 77.78,61.39 77.78,61.71 79.67,63.6 80.98,63.6 82.25,64.87 83.13,64.87 83.47,65.22 83.47,65.5 83.09,65.88 83.09,65.89 82.94,66.04 82.94,66.32 83.22,66.61 83.51,66.61 84.05,66.08 84.33,66.08 84.62,66.37 84.62,66.65 84.26,67.01 84.26,67.3 84.55,67.59 84.83,67.59 85.19,67.23 85.48,67.23 85.84,67.59 95.78,67.59 95.93,67.43 v2(95.93,67.25)
  BOTTOM w0.089: v2(95.93,67.25) 94.93,67.25 94.72,67.45 94.72,67.91 94.93,68.11 99.6,68.11 101.3,66.41 104,66.41 104.22,66.19 104.23,66.19 104.55,65.86 CPU1.AY52
  BOTTOM w0.152: v2(70.56,56.38) 70.8,56.13 71.14,56.13 71.49,56.48 DM1.125
M_A_A9: length 50.2
  TOP w0.152: v1(68.58,58.26) v2(68.58,57.7)
  L3 w0.203: v2(68.58,57.7) 68.65,57.7 68.86,57.9 70.87,57.9 76.1,63.14 76.99,63.14 78.98,65.12 80.35,65.12 80.88,65.65 80.88,66.71 80.77,66.81 80.77,67.1 81.06,67.39 81.35,67.39 81.45,67.28 81.74,67.28 82.1,67.64 82.1,68.41 82.8,69.11 95.06,69.11 95.34,68.83 96.7,68.83 v2(97.15,69.27)
  BOTTOM w0.089: v2(97.15,69.27) 97.06,69.27 96.78,69 96.78,68.62 96.91,68.5 97.15,68.5 97.46,68.81 97.78,68.81 98.09,68.5 99.73,68.5 101.24,66.99 CPU1.BB54
  BOTTOM w0.152: v2(68.58,57.7) 68.53,57.7 68.4,57.83 68.4,57.84 67.96,58.28 67.96,58.46 68.38,58.88 68.55,58.88 69.95,57.48 DM1.121
M_A_A10: length 50.7
  TOP w0.152: v2(68.04,48.71) 68.25,48.91 v1(68.58,48.91)
  L3 w0.089: 95.5,61.43 95.64,61.57 102.82,61.57 104.69,63.44 106.03,63.44 v2(106.74,64.15)
  L3 w0.203: 95.5,61.43 94.25,60.18 88.97,60.18 82.65,53.87 82.16,53.87 81.22,52.93 80.74,52.93 79.88,52.07 79.88,51.6 78.38,50.1 77.35,50.1 75.99,48.74 68.08,48.74 68.05,48.7 v2(68.04,48.71)
  BOTTOM w0.152: DM1.146 64.18,49.21 67.55,49.21 v2(68.04,48.71) ; v2(106.74,64.15) 107.05,64.46 CPU1.AT50
M_A_A11: length 50.9
  TOP w0.152: v1(67.31,58.28) v2(67.31,57.7)
  L3 w0.203: v2(96.51,69.27) 95.4,69.27 95.06,69.62 81.89,69.62 81.31,69.04 81.31,68.36 80.3,67.35 80.26,67.31 80.26,66.7 79.74,66.17 79.15,66.17 79.14,66.18 79.13,66.18 76.6,63.65 75.89,63.65 70.66,58.41 68.07,58.41 67.94,58.54 67.94,59.55 67.81,59.68 67.22,59.68 67.01,59.47 67.01,58 v2(67.31,57.7)
  BOTTOM w0.089: CPU1.BA54 103.68,66.73 101.25,66.73 99.66,68.32 96.8,68.32 96.51,68.61 v2(96.51,69.27)
  BOTTOM w0.152: DM1.120 67.22,57.73 67.26,57.7 v2(67.31,57.7)
M_A_A12: length 50.9
  TOP w0.152: v2(69.82,58.89) 69.82,59.07 v1(70.13,59.38)
  L3 w0.089: v2(98.43,69.26) 98.43,69.5 98.24,69.69 95.59,69.69
  L3 w0.203: v2(69.82,58.89) 69.82,59.17 69.62,59.38 68.72,59.38 68.51,59.58 68.51,59.94 68.72,60.14 71.67,60.14 75.68,64.16 76.39,64.16 77.25,65.02 77.25,65.89 77.6,66.24 78.47,66.24 78.97,66.73 79.47,66.73 79.76,67.02 79.76,67.52 80.8,68.57 80.8,69.36 81.57,70.13 95,70.13 95.44,69.69 95.59,69.69
  BOTTOM w0.089: CPU1.AW54 105.24,66.87 105.1,66.73 104.49,66.73 104.27,66.95 104.27,67.12 104.19,67.2 104.02,67.25 103.84,67.25 103.72,67.21 103.47,67.21 103.39,67.25 102.98,67.25 102.91,67.17 101.32,67.17 99.82,68.67 98.29,68.67 98.19,68.77 98.19,69.16 98.29,69.26 v2(98.43,69.26)
  BOTTOM w0.152: DM1.119 70.02,57.98 69.82,58.18 v2(69.82,58.89)
M_A_A13: length 53.1
  TOP w0.152: v1(66.98,45.36) v2(66.98,44.77)
  L3 w0.089: 95.92,59.59 96.32,59.99 103.84,59.99 105.87,62.01 v2(105.87,62.09)
  L3 w0.203: v2(66.98,44.77) 66.98,45.33 67.41,45.76 73.71,45.76 73.73,45.74 74.85,45.74 75.27,45.32 79.05,45.32 82.55,48.83 82.55,49.97 90.03,57.45 93.78,57.45 95.92,59.59
  BOTTOM w0.152: DM1.158 66.5,46.23 67.11,45.63 67.11,44.95 66.98,44.82 v2(66.98,44.77) ; CPU1.AU46 105.87,62.29 v2(105.87,62.09)
M_A_A14: length 51.6
  TOP w0.152: v2(70.51,47.39) v1(71.07,47.39)
  L3 w0.089: 96.62,60.95 96.85,60.95 97.11,61.21 103.11,61.21 104.92,63.03 106.55,63.03 106.7,63.18 107.41,63.18 107.6,62.98 107.6,62.64 v2(107.34,62.37)
  L3 w0.203: 96.62,60.95 96,60.95 94.18,59.12 89.35,59.12 83.07,52.85 82.58,52.85 81.43,51.7 81.43,51.54 80.47,50.58 80.47,50.29 80.96,49.81 80.96,49.52 80.67,49.23 80.38,49.23 79.9,49.72 79.61,49.72 79.32,49.43 79.32,49.14 79.84,48.63 79.84,48.37 79.52,48.05 79.27,48.05 78.75,48.57 77.33,48.57 76.49,47.72 75.99,47.72 75.41,47.72 74.96,47.27 74.37,47.27 74.35,47.29 72.93,47.29 72.49,47.72 70.85,47.72 v2(70.51,47.39)
  BOTTOM w0.152: v2(107.34,62.37) 107.05,62.66 CPU1.AT46 ; v2(70.51,47.39) 71.11,47.98 DM1.151
M_A_A15: length 51.9
  TOP w0.152: v1(67.33,49.27) v2(67.33,48.71)
  L3 w0.089: 96.7,61.84 96.78,61.76 102.7,61.76 104.71,63.76 105.12,63.76 105.65,64.3 105.97,64.3 v2(106.09,64.18)
  L3 w0.203: v2(67.33,48.71) 67.87,49.25 68.04,49.25 68.28,49.49 72.11,49.49 72.31,49.29 75.82,49.29 77.16,50.62 78.01,50.62 78.83,51.44 78.83,52.03 80.24,53.44 80.99,53.44 81.97,54.42 81.97,54.58 82.22,54.83 82.9,54.83 88.79,60.72 94.24,60.72 95.35,61.84 96.7,61.84
  BOTTOM w0.152: v2(106.09,64.18) 106.09,64.02 106.37,63.74 CPU1.AU48 ; v2(67.33,48.71) 67.55,48.49 67.55,48.11 66.83,47.38 66.83,47.07 66.49,46.73 DM1.156
M_A_A16: length 52.4
  TOP w0.152: v2(66.37,47.26) 65.86,47.77 v1(65.86,47.79)
  L3 w0.089: 97.74,62.98 99.68,62.98 101.9,63.27 102.29,63.39 102.5,63.39 102.89,63.56 104.75,65.09 105.37,65.53 105.45,65.62 105.53,65.66 105.58,65.68 v2(105.99,65.9)
  L3 w0.203: v2(66.37,47.26) 66.11,48.45 66.11,48.94 67.44,50.27 68.09,50.51 71.41,50.51 71.92,50.65 72.28,50.83 72.59,51.15 73.68,51.15 73.95,51.41 74.84,51.41 75.45,52.03 77.06,52.65 77.29,52.65 81.02,56.38 82.1,56.38 88.03,62.31 93.72,62.31 94.43,62.56 94.63,62.76 97.51,62.76 97.74,62.98
  BOTTOM w0.152: v2(66.37,47.26) 65.89,47.73 DM1.152 ; v2(105.99,65.9) 105.99,65.45 106.15,65.12 CPU1.AU50
M_A_ACT_N: length 49.6
  TOP w0.152: v2(67.49,60.47) 67.46,60.44 v1(67.46,59.91)
  L3 w0.203: v2(96.66,70.77) 96.4,70.77 95.01,72.16 80.29,72.16 72.08,63.95 68.66,63.95 67.56,62.85 67.56,60.54 v2(67.49,60.47)
  BOTTOM w0.089: v2(96.66,70.77) 96.66,70.38 97.12,69.92 99.59,69.92 101.76,67.76 102.54,67.76 102.65,67.87 103.39,67.87 103.52,67.91 103.69,67.91 103.88,67.86 103.98,67.86 CPU1.BA55
  BOTTOM w0.152: v2(67.49,60.47) 66.32,59.31 65.6,59.31 65.53,59.23 DM1.114
M_A_ALERT_N: length 66.2
  TOP w0.152: v2(65.79,58.85) 65.79,58.95 v1(66.14,59.3)
  L3 w0.089: 107.41,67.96 108.02,67.35 109.5,67.35 109.76,67.09 109.76,64.93 109.54,64.7 106.59,64.7 106.54,64.76 105.79,64.76 v2(105.74,64.71)
  L3 w0.203: 107.41,67.96 106.78,67.96 102.62,72.13 95.98,72.13 94.94,73.18 79.85,73.18 71.64,64.96 65.73,64.96 64.55,63.79 64.55,60.09 v2(65.79,58.85)
  BOTTOM w0.152: v2(105.74,64.71) 105.73,64.69 CPU1.AW50 ; v2(65.79,58.85) 65.68,58.73 DM1.116
M_A_BA0: length 51.6
  TOP w0.152: v1(66.11,49.09) 66.22,49.09 v2(66.6,48.71)
  L3 w0.089: 97.21,62.16 97.44,61.94 102.36,61.94 104.44,64.02 104.44,64.27 104.8,64.63 105.05,64.63 105.57,65.15 106.69,65.15 v2(106.71,65.17)
  L3 w0.203: 97.21,62.16 95.21,62.16 94.32,61.27 92.16,61.27 92.16,61.26 88.42,61.26 82.5,55.35 81.43,55.35 78.32,52.24 78.32,51.65 77.8,51.13 76.94,51.13 76.42,50.6 76.42,50.6 75.61,49.8 74.41,49.8 74.08,50.12 71.92,50.12 71.48,50 68.18,50 68,49.94 67.82,49.76 67.66,49.76 67.5,49.59 67.48,49.59 v2(66.6,48.71)
  BOTTOM w0.152: v2(66.6,48.71) 66.57,48.68 66.5,48.68 66.05,48.23 DM1.150 ; v2(106.71,65.17) 106.4,65.48 CPU1.AU52
M_A_BA1: length 53.6
  TOP w0.152: v1(68.3,47.69) 67.97,47.36 v2(67.97,47.21)
  L3 w0.089: v2(107.38,64.14) 106.47,63.23 104.88,63.23 103.04,61.39 96.83,61.39 96.7,61.26
  L3 w0.203: v2(67.97,47.21) 67.97,47.26 68.94,48.23 76.2,48.23 77.56,49.59 78.59,49.59 80.39,51.39 80.39,51.86 80.95,52.42 81.43,52.42 82.37,53.36 82.86,53.36 89.17,59.66 94.21,59.66 95.81,61.26 96.7,61.26
  BOTTOM w0.152: DM1.145 69.5,49.48 67.97,47.95 v2(67.97,47.21) ; v2(107.38,64.14) 107.05,63.81 CPU1.AT48
M_A_BG0: length 50.4
  TOP w0.152: v1(68.15,60.95) 68.22,60.88 v2(68.22,60.39)
  L3 w0.203: v2(68.22,60.39) 68.22,62.02 69.64,63.44 72.29,63.44 80.5,71.65 95.04,71.65 96.36,70.33 97.04,70.33 97.3,70.58 v2(97.3,70.77)
  BOTTOM w0.089: CPU1.AY55 104.62,68.04 103.91,68.04 103.71,68.09 103.5,68.09 103.37,68.05 102.55,68.05 102.44,67.94 101.83,67.94 99.64,70.13 97.54,70.13 97.3,70.36 v2(97.3,70.77)
  BOTTOM w0.152: DM1.115 71.08,58.98 70.69,59.38 69.57,59.38 69.44,59.5 68.48,59.5 68.22,59.76 v2(68.22,60.39)
M_A_BG1: length 51.2
  TOP w0.152: v2(68.83,60.98) 69.21,60.6 v1(69.31,60.6)
  L3 w0.089: 95.53,70.12 95.78,69.87 100.23,69.87 100.37,69.73 100.37,69.07 100.16,68.86 99.47,68.86 v2(99.06,69.26)
  L3 w0.203: v2(68.83,60.98) 68.88,60.98 69.21,60.65 71.41,60.65 75.43,64.66 76.18,64.66 76.4,64.89 76.4,65.41 76.29,65.52 76.29,65.93 77.12,66.76 78.28,66.76 78.97,67.46 78.97,68.25 81.36,70.64 95.01,70.64 95.53,70.12
  BOTTOM w0.089: v2(99.06,69.26) 99.06,69.03 99.25,68.85 99.97,68.85 101.47,67.35 102.76,67.35 102.83,67.42 103.43,67.42 103.51,67.39 103.69,67.39 103.82,67.42 104.04,67.42 104.18,67.39 104.29,67.39 104.59,67.09 CPU1.AY54
  BOTTOM w0.152: v2(68.83,60.98) 68.83,60.76 69.94,59.66 71.09,59.66 71.26,59.48 DM1.113
M_A_CKE0: length 50.8
  TOP w0.152: v1(70.23,61.74) v2(70.23,61.18)
  L3 w0.089: 95.85,70.3 96.06,70.09 100.78,70.09 101.04,70.35 101.04,70.57 100.86,70.75 99.23,70.75 v2(99.21,70.77)
  L3 w0.203: v2(70.23,61.18) 70.23,61.46 70.03,61.66 69.34,61.66 69.12,61.89 69.12,62.17 69.37,62.42 70.74,62.42 71.48,61.68 71.73,61.68 71.93,61.88 71.93,62.7 72.16,62.93 72.98,62.93 75.22,65.17 75.22,65.58 76.91,67.28 77.39,67.28 77.94,67.83 77.94,68.31 78.38,68.75 78.75,68.75 80.23,70.23 80.23,70.6 80.78,71.14 95.01,71.14 95.85,70.3
  BOTTOM w0.089: CPU1.BA56 103.41,68.57 103.13,68.57 103.12,68.56 103.09,68.56 103.02,68.48 102.72,68.47 102.46,68.47 102.36,68.37 101.9,68.37 101.7,68.58 99.5,70.77 v2(99.21,70.77)
  BOTTOM w0.152: DM1.109 71.4,60.48 71.24,60.65 70.76,60.65 v2(70.23,61.18)
M_A_CKE1: length 50.4
  TOP w0.152: v2(66.06,60.51) 66.06,60.61 v1(66.42,60.98)
  L3 w0.203: v2(98.58,70.77) 98.58,71.29 98.35,71.52 96.07,71.52 94.92,72.67 80.08,72.67 71.86,64.45 65.94,64.45 65.06,63.58 65.06,61.51 v2(66.06,60.51)
  BOTTOM w0.089: v2(98.58,70.77) 98.58,70.76 98.95,70.38 99.64,70.38 101.91,68.11 102.36,68.11 102.49,68.24 103.21,68.24 CPU1.BB56
  BOTTOM w0.152: v2(66.06,60.51) 65.78,60.23 DM1.110
M_A_CLK0: length 52
  TOP w0.102: v2(69.6,51.12) 69.6,51.48 v1(69.77,51.65)
  L3 w0.089: v2(107.34,66.01) 106.93,66.41 106.4,66.41 106.32,66.49 105.64,66.49 105.07,65.92 103.17,65.92 103.13,65.96
  L3 w0.14: 103.13,65.96 102.54,65.96 102.02,65.43 102.02,65.02 102.64,64.39 102.64,64.16 102.48,64 102.25,64 101.62,64.62 101.2,64.62 100.34,63.76 98.21,63.76 98.04,63.92 94.99,63.92 94.22,63.14 87.71,63.14 81.76,57.2 80.68,57.2 76.95,53.47 75.74,53.47 74.5,52.23 73.61,52.23 73.35,51.97 71.1,51.97 70.66,51.53 70.34,51.53 70.21,51.51 v2(69.6,51.12)
  BOTTOM w0.102: v2(69.6,51.12) 69.71,51.22 69.71,52.06 70.99,53.35 71.19,53.35 71.33,53.48 DM1.137 ; CPU1.AT53 v2(107.34,66.01)
M_A_CLK1: length 52.7
  TOP w0.102: v1(68.27,51.53) 68.27,51.45 v2(67.92,51.1)
  L3 w0.089: 103.68,66.51 103.72,66.56 104.11,66.56 104.26,66.72 105.33,66.72 105.37,66.67 106.47,66.67 106.54,66.6 106.86,66.6 106.89,66.62 v2(107.34,66.95)
  L3 w0.14: v2(67.92,51.1) 67.92,51.62 68.36,52.06 70.46,52.06 70.88,52.49 73.13,52.49 73.86,53.21 74.74,53.21 76.09,54.56 77.31,54.56 80.46,57.72 80.99,57.72 82.91,59.64 83.36,59.64 87.4,63.67 94.06,63.67 94.67,64.28 100.23,64.28 102.46,66.51 103.68,66.51
  BOTTOM w0.102: CPU1.AT55 v2(107.34,66.95) ; v2(67.92,51.1) 67.77,51.25 67.77,52.17 67.24,52.7 65.86,52.7 65.46,53.1 65.16,53.1 65.02,53.23 DM1.138
M_A_CLK#0: length 52
  TOP w0.102: v2(70.37,51.08) 70.93,51.08 v1(70.94,51.09)
  L3 w0.089: 103.13,65.69 103.17,65.73 105.15,65.73 105.72,66.3 106.23,66.3 106.35,66.18 106.5,66.18 v2(106.68,66.01)
  L3 w0.14: 103.13,65.69 102.65,65.69 102.28,65.32 102.28,65.13 102.91,64.5 102.91,64.05 102.59,63.73 102.13,63.73 101.51,64.35 101.31,64.35 100.45,63.49 98.1,63.49 97.93,63.66 95.1,63.66 94.33,62.88 87.82,62.88 81.87,56.93 80.79,56.93 77.06,53.2 75.85,53.2 74.61,51.97 73.72,51.97 73.46,51.7 71.21,51.7 70.59,51.08 v2(70.37,51.08)
  BOTTOM w0.102: v2(106.68,66.01) 106.5,66.01 106.4,66.1 CPU1.AU53 ; DM1.139 71.33,52.98 71.19,53.12 71.09,53.12 70.03,52.06 70.03,51.77 70.15,51.64 71.12,51.64 71.27,51.49 71.27,51.23 71.12,51.08 v2(70.37,51.08)
M_A_CLK#1: length 52.6
  TOP w0.102: v1(66.77,51.5) 66.8,51.5 v2(67.21,51.1)
  L3 w0.089: v2(106.7,66.99) 106.58,66.86 105.45,66.86 105.41,66.91 104.18,66.91 104.03,66.75 103.71,66.75 103.68,66.78
  L3 w0.14: 103.68,66.78 102.35,66.78 100.12,64.55 94.56,64.55 93.95,63.94 87.29,63.94 83.25,59.9 82.8,59.9 80.88,57.98 80.35,57.98 77.2,54.83 75.98,54.83 74.63,53.48 73.74,53.48 73.02,52.75 70.77,52.75 70.34,52.33 68.25,52.33 67.65,51.73 67.35,51.73 67.21,51.59 67.21,51.1 v2(67.21,51.1)
  BOTTOM w0.102: DM1.140 64.97,52.73 65.11,52.87 65.36,52.87 65.77,52.47 67.15,52.47 67.54,52.08 67.54,51.83 67.41,51.7 67.33,51.7 67.21,51.57 v2(67.21,51.1) ; v2(106.7,66.99) 106.53,66.99 106.4,67.12 CPU1.AU55
M_A_CS#0: length 55.9
  TOP w0.152: v1(69.52,47.74) 69.24,47.46 v2(69.24,47.24)
  L3 w0.089: 96.9,60.65 97.28,61.02 102.9,61.02 103,60.92 103,60.54 103.1,60.43 103.39,60.43 103.5,60.54 103.5,60.76 103.6,60.86 104.09,60.86 104.19,60.96 104.19,61.19 104.09,61.29 103.92,61.29 103.82,61.39 103.82,61.67 104.83,62.68 106.37,62.68 v2(106.68,62.37)
  L3 w0.203: v2(69.24,47.24) 69.24,46.98 69.44,46.78 70.72,46.78 71.16,47.22 72.25,47.22 72.69,46.78 74.14,46.78 74.15,46.76 75.96,46.76 76.29,46.43 76.99,46.43 77.19,46.63 77.19,47.24 77.39,47.45 77.8,47.45 78,47.24 78,46.63 78.21,46.43 78.71,46.43 81.53,49.25 81.53,49.82 81.53,50.92 81.71,51.1 82.2,51.1 82.48,51.38 82.48,52.03 82.79,52.34 83.29,52.34 89.5,58.56 94.04,58.56 96.02,60.54 96.13,60.54 96.24,60.65 96.9,60.65
  BOTTOM w0.152: DM1.149 70.88,48.48 70.73,48.33 70.73,48.16 70.57,48.01 70.27,48.01 70.12,48.16 70.12,48.33 69.97,48.48 69.51,48.48 69.24,48.22 v2(69.24,47.24) ; v2(106.68,62.37) 106.65,62.35 106.65,62.17 CPU1.AU45
M_A_CS#1: length 56.9
  TOP w0.152: v1(68.28,45.36) v2(68.28,44.78)
  L3 w0.089: 96.24,59.48 96.52,59.76 104.37,59.76 104.91,60.3 106.57,60.3 106.77,60.49 106.77,60.81 v2(106.09,61.48)
  L3 w0.203: 96.24,59.48 93.7,56.94 90.38,56.94 83.06,49.61 83.06,48.62 78.59,44.15 78.08,44.15 77.88,44.36 77.88,44.61 77.68,44.82 77.27,44.82 77.07,44.61 77.07,44.36 76.86,44.15 76.46,44.15 76.25,44.36 76.25,44.61 76.05,44.82 75.65,44.82 75.44,44.61 75.44,44.36 75.24,44.15 73.99,44.15 73.98,44.16 73.92,44.16 73.63,44.44 73.63,44.46 72.84,45.25 68.48,45.25 68.28,45.05 v2(68.28,44.78)
  BOTTOM w0.152: v2(68.28,44.78) 68.1,44.97 68.1,44.99 67.78,45.3 67.78,45.84 67.98,46.05 70.91,46.05 71.35,46.48 DM1.157 ; v2(106.09,61.48) 106.09,61.4 106.4,61.09 CPU1.AU43
M_A_DIMA_ODT0: length 56
  TOP w0.152: v2(67.33,47.21) 67.33,47.46 v1(67.08,47.72)
  L3 w0.089: v2(106.73,61.51) 106.73,61.76 106.28,62.21 106.28,62.23 106.03,62.48 105.21,62.48 104.6,61.87 104.6,61.84 104.58,61.82 104.58,60.98 103.81,60.21 96.95,60.21 96.92,60.24
  L3 w0.203: 96.92,60.24 96.14,60.24 93.85,57.95 89.82,57.95 82.04,50.18 82.04,49.04 78.85,45.85 75.73,45.85 75.33,46.25 73.94,46.25 73.93,46.27 67.56,46.27 67.33,46.49 v2(67.33,47.21)
  BOTTOM w0.102: v2(106.73,61.51) 106.73,61.59 107.05,61.91 CPU1.AT45
  BOTTOM w0.152: DM1.155 71.47,46.98 71.44,46.96 71.42,46.96 70.92,46.45 67.61,46.45 67.33,46.73 v2(67.33,47.21)
M_A_DIMA_ODT1: length 56.6
  TOP w0.152: v1(69.85,45.33) v2(69.85,44.77)
  L3 w0.089: 96.59,59.33 96.84,59.58 102.95,59.58 104.33,58.2 105.38,58.2 106.83,59.64 106.83,60.07 107.25,60.49 v2(107.39,60.49)
  L3 w0.203: 96.59,59.33 93.7,56.43 90.59,56.43 83.57,49.4 83.57,48.41 78.76,43.6 78.08,43.6 77.88,43.39 77.88,42.92 77.69,42.74 77.25,42.74 77.07,42.92 77.07,43.46 76.88,43.64 76.44,43.64 76.25,43.46 76.25,42.97 76.05,42.76 75.64,42.76 75.44,42.97 75.44,43.47 75.26,43.64 74.8,43.64 74.63,43.47 74.63,42.96 74.42,42.75 73.19,42.75 72.83,43.11 72.83,43.4 73.2,43.77 73.2,44.05 72.91,44.34 72.63,44.34 72.26,43.98 71.97,43.98 71.24,44.71 69.91,44.71 v2(69.85,44.77)
  BOTTOM w0.152: CPU1.AT43 107.05,60.71 107.27,60.49 v2(107.39,60.49) ; v2(69.85,44.77) 69.85,45.15 69.95,45.25 70.35,45.25 70.65,44.95 70.94,44.95 71.47,45.48 DM1.161
M_A_DQ0: length 59.5
  TOP w0.089: v1(67.24,86.29) v2(67.24,86.86)
  L3 w0.127: v2(67.24,86.86) 67.68,86.41 72.53,86.41 74.95,88.84 82.67,88.84 82.8,88.96 82.8,89.36 82.92,89.49 83.18,89.49 83.3,89.36 83.3,88.96 83.43,88.84 83.85,88.84 84.58,89.56 104.23,89.56 110.37,83.41 110.37,80.34 v2(109.7,79.67)
  BOTTOM w0.089: CPU1.AL71 110.32,77.23 110.32,79.48 110.13,79.67 v2(109.7,79.67) ; v2(67.24,86.86) 66.12,85.73 DM1.8
M_A_DQ1: length 60
  TOP w0.089: v1(68.66,86.28) v2(68.66,86.86)
  L3 w0.127: v2(109.75,77.75) 110.46,78.46 111.09,80.04 111.09,83.71 104.36,90.44 77.85,90.44 74.62,89.6 73.7,88.67 69.05,87.32 v2(68.66,86.86)
  BOTTOM w0.089: DM1.7 71.46,85.98 71.43,86.02 69.49,86.02 v2(68.66,86.86) ; v2(109.75,77.75) 109.75,77.33 109.67,77.25 109.67,76.88 109.71,76.81 109.71,76.6 109.67,76.49 109.67,76.26 109.73,76.07 109.73,75.73 110.11,75.22 CPU1.AL68
M_A_DQ2: length 60.4
  TOP w0.089: v1(66.5,82.8) v2(66.5,82.23)
  L3 w0.127: v2(66.5,82.23) 66.5,83.07 66.7,83.28 71.18,83.28 72.39,84.49 73.15,84.49 75.75,87.09 96.66,87.09 96.95,87.37 103.95,87.37 106.15,85.17 107.06,83.43 108.95,81.54 108.95,80.28 108.66,79.48 108.46,79.28 108.01,79.28 107.77,78.92 107.53,78.14 107.53,77.91 107.91,77.35 109.23,76.03 109.23,74.61 109.02,74.41 v2(108.78,74.41)
  BOTTOM w0.089: v2(66.5,82.23) 65.9,82.73 DM1.20 ; v2(108.78,74.41) 108.88,74.51 CPU1.AN68
M_A_DQ3: length 60.2
  TOP w0.089: v1(108.35,81.2) 108.35,80.84 v2(108.15,80.64)
  L3 w0.127: v2(108.15,80.64) 108.13,80.66 108.13,81.34 107.39,82.07 106.73,82.07 106.61,82.2 106.61,82.68 106.46,82.83 106.25,82.83 106.1,82.68 106.1,82.2 105.97,82.07 105.72,82.07 105.59,82.2 105.59,82.45 105.44,82.6 105.23,82.6 105.08,82.45 105.08,82.2 104.96,82.07 104.8,82.07 103.96,81.22 101.27,81.22 100.43,82.06 100.43,82.97 99.45,83.95 99.45,84.13 100.21,84.89 100.21,85.1 100.06,85.25 99.85,85.25 99.09,84.49 98.91,84.49 98.73,84.67 98.73,84.85 99.62,85.73 99.62,85.94 99.47,86.09 99.26,86.09 98.37,85.21 98.19,85.21 98.01,85.38 98.01,85.56 98.75,86.31 98.75,86.52 98.61,86.66 98.39,86.66 97.65,85.92 97.47,85.92 97.08,86.32 76.13,86.32 73.25,83.44 72.44,83.44 71.38,82.39 v2(70.69,82.39)
  BOTTOM w0.089: CPU1.AN69 108.6,76.12 108.38,76.42 108.31,76.49 108.31,77.29 108.35,77.33 108.35,78.24 107.87,78.72 107.87,79.58 107.88,79.59 107.88,80.04 107.99,80.15 107.99,80.47 v2(108.15,80.64) ; DM1.21 70.78,82.48 v2(70.69,82.39)
M_A_DQ4: length 59.9
  L3 w0.127: v2(109.93,80.97) 109.97,81 109.97,83.32 104.08,89.21 87.31,89.21 86.58,88.47 86.22,88.47 86.1,88.6 86.1,89 85.97,89.13 85.72,89.13 85.59,89 85.59,88.6 85.46,88.47 85.21,88.47 85.08,88.6 85.08,89 84.95,89.13 84.7,89.13 84.57,89 84.57,88.6 84.45,88.47 75.17,88.47 72.76,86.06 66.62,86.06 v2(65.82,86.86)
  BOTTOM w0.089: v1(109.95,81.55) 109.93,81.53 v2(109.93,80.97) 110.18,80.71 110.18,80 110.5,79.69 110.5,76.76 CPU1.AL70 ; DM1.4 65.7,86.73 v2(65.82,86.86)
M_A_DQ5: length 60.5
  TOP w0.089: v1(70.08,86.29) v2(70.08,86.86)
  L3 w0.127: v2(70.08,86.86) 72.47,86.86 74.8,89.19 77.68,89.19 77.81,89.32 77.81,89.75 77.96,89.9 78.17,89.9 78.32,89.75 78.32,89.32 78.45,89.19 78.7,89.19 78.83,89.32 78.83,89.77 78.95,89.89 79.21,89.89 79.33,89.77 79.33,89.32 79.46,89.19 79.72,89.19 79.84,89.32 79.84,89.73 79.99,89.88 80.2,89.88 80.35,89.73 80.35,89.32 80.48,89.19 80.73,89.19 80.86,89.32 80.86,89.63 81.01,89.78 81.22,89.78 81.37,89.63 81.37,89.32 81.49,89.19 81.87,89.19 82.7,90.01 104.28,90.01 110.73,83.56 110.73,80.19 110.23,79.7 110.23,78.85 v2(109.77,78.39)
  BOTTOM w0.089: v2(70.08,86.86) 70.52,87.29 71.01,87.29 71.32,86.98 DM1.3 ; CPU1.AL69 109.9,75.93 109.9,76.1 109.85,76.29 109.85,76.47 109.88,76.57 109.88,76.85 109.85,76.92 109.85,77.18 110.14,77.47 110.14,78.01 109.77,78.38 v2(109.77,78.39)
M_A_DQ6: length 58.9
  TOP w0.089: v2(108.25,78.88) 108.25,78.53 v1(108.46,78.32)
  L3 w0.127: v2(66.5,84.65) 66.5,83.87 66.73,83.63 71.03,83.63 72.24,84.85 73,84.85 75.6,87.44 96.3,87.44 96.61,87.75 104.07,87.75 107.41,84.41 107.41,83.64 109.31,81.75 109.31,79.85 109.29,79.84 109.29,79.05 109.14,78.9 108.27,78.9 v2(108.25,78.88)
  BOTTOM w0.089: v2(108.25,78.88) 108.25,78.84 108.54,78.55 108.54,77.26 108.48,77.21 108.48,76.67 CPU1.AN70 ; v2(66.5,84.65) 66.63,84.51 66.63,84.02 66.35,83.73 DM1.16
M_A_DQ7: length 58.5
  TOP w0.089: v1(108.76,80) 108.58,80 v2(108.28,79.7)
  L3 w0.127: v2(108.28,79.7) 108.28,80.13 108.6,80.45 108.6,81.37 105.77,84.19 105.77,85.05 103.8,87.02 101.42,87.02 101.29,86.89 101.29,86.52 101.14,86.38 100.93,86.38 100.78,86.52 100.78,86.89 100.65,87.02 100.4,87.02 100.27,86.89 100.27,86.63 100.12,86.48 99.91,86.48 99.76,86.63 99.76,86.89 99.64,87.02 97.09,87.02 96.81,86.73 75.9,86.73 73.3,84.13 72.56,84.13 71.33,82.9 68.78,82.9 68.58,82.7 v2(68.58,82.24)
  BOTTOM w0.089: v2(68.58,82.24) 68.16,82.66 67.93,82.66 67.73,82.86 67.73,83.28 67.93,83.48 68.7,83.48 68.7,83.48 DM1.17 ; v2(108.28,79.7) 108.48,79.7 108.74,79.44 108.74,77.23 108.78,77.19 CPU1.AN71
M_A_DQ8: length 55.6
  TOP w0.089: v1(68.88,80.41) v2(68.88,79.85)
  L3 w0.127: v2(107.24,80.46) 107.14,80.46 107.05,80.55 105.22,80.55 104.73,80.06 100.78,80.06 99.36,81.47 99.36,82.52 96.77,85.11 82.14,85.11 81.48,84.44 81.12,84.44 81,84.57 81,85.02 80.87,85.14 80.62,85.14 80.49,85.02 80.49,84.57 80.36,84.44 80.11,84.44 79.98,84.57 79.98,85.02 79.85,85.14 79.6,85.14 79.47,85.02 79.47,84.57 79.35,84.44 75.94,84.44 73.8,82.3 72.9,82.3 71.28,80.69 69.72,80.69 v2(68.88,79.85)
  BOTTOM w0.089: v2(68.88,79.85) 68,80.73 DM1.28 ; CPU1.AR70 107.55,76.58 107.55,76.75 107.49,76.94 107.49,77.12 107.53,77.22 107.53,77.5 107.47,77.62 107.46,77.64 107.38,77.78 107.38,79.45 107.24,79.59 v2(107.24,80.46)
M_A_DQ9: length 56.1
  TOP w0.089: v1(70.2,80.41) v2(70.2,79.85)
  L3 w0.127: v2(70.2,79.85) 70.21,79.85 70.65,80.29 71.42,80.29 73.07,81.95 73.95,81.95 76.09,84.09 81.63,84.09 82.25,84.71 96.66,84.71 99.01,82.36 99.01,80.83 100.14,79.7 104.87,79.7 104.97,79.79 106.39,79.79 106.52,79.66 106.85,79.66 107.21,79.3 107.21,77.41 105.26,75.46 105.26,75 105.59,74.67 106.54,74.67 107.12,75.25 107.12,76.08 107.24,76.21 108.13,76.21 108.25,76.08 v2(108.25,75.35)
  BOTTOM w0.089: v2(70.2,79.85) 70.84,80.48 DM1.29 ; v2(108.25,75.35) 107.93,75.35 CPU1.AR68
M_A_DQ10: length 53.8
  TOP w0.089: v1(105.56,79.44) 105.48,79.37 v2(105.48,78.88)
  L3 w0.127: v2(105.48,78.88) 105.18,78.58 105.18,77.44 105.43,77.2 105.43,76.83 104.89,76.29 104.33,76.29 104.13,76.09 100.14,76.09 97.15,79.08 97.15,81.59 95.8,82.95 86.61,82.95 85.91,82.25 76.83,82.25 72.06,77.49 68.72,77.49 68.53,77.67 v2(68.53,78.3)
  BOTTOM w0.089: DM1.41 69.34,77.48 v2(68.53,78.3) ; CPU1.AU71 106.43,77.21 106.04,77.6 106.04,78.38 105.61,78.81 105.56,78.81 v2(105.48,78.88)
M_A_DQ11: length 55.5
  TOP w0.089: v2(103.6,78.46) 103.68,78.39 v1(103.68,77.84)
  L3 w0.127: v2(103.6,78.46) 103.9,78.16 103.9,77.26 103.37,76.74 101.46,76.74 98.87,79.32 98.34,79.32 97.92,79.75 97.92,81.91 96.14,83.68 82.68,83.68 81.95,82.96 76.53,82.96 74.49,80.92 73.5,80.92 71.33,78.75 70.78,78.75 70.77,78.74 67.56,78.74 v2(67.11,78.3)
  BOTTOM w0.089: DM1.42 65.14,77.23 65.16,77.25 66.84,77.25 67.11,77.52 v2(67.11,78.3) ; CPU1.AU68 106.45,75.07 106.45,74.9 106.01,74.45 105.77,74.45 105.59,74.64 105.59,74.87 105.41,75.05 105.41,77.07 105.12,77.36 104.56,77.36 103.62,78.29 103.62,78.44 v2(103.6,78.46)
M_A_DQ12: length 54.2
  TOP w0.089: v1(67.92,82.8) v2(67.92,82.23)
  L3 w0.127: v2(67.92,82.23) 67.92,81.68 68.16,81.45 71.49,81.45 72.72,82.69 73.68,82.69 75.8,84.8 77.25,84.8 77.38,84.93 77.38,85.15 77.51,85.28 77.76,85.28 77.89,85.15 77.89,84.93 78.02,84.8 78.38,84.8 79.11,85.52 96.86,85.52 99.72,82.67 99.72,81.63 100.84,80.51 104.67,80.51 105.26,81.09 v2(107.24,81.09)
  BOTTOM w0.089: DM1.24 67.43,81.73 v2(67.92,82.23) ; v2(107.24,81.09) 107.66,80.67 107.66,80.27 107.56,80.17 107.56,77.92 107.75,77.73 CPU1.AR71
M_A_DQ13: length 55.3
  TOP w0.089: v1(69.24,82.8) v2(69.24,82.24)
  L3 w0.127: v2(106.7,80.1) 106.79,80.01 107.42,80.01 107.68,80.27 107.68,81.28 107.25,81.71 105.37,81.71 104.52,80.86 100.99,80.86 100.07,81.78 100.07,82.82 96.99,85.91 76.37,85.91 73.5,83.04 72.58,83.04 71.34,81.8 69.57,81.8 69.24,82.13 v2(69.24,82.24)
  BOTTOM w0.089: v2(106.7,80.1) 106.75,80.05 106.75,79.82 107.19,79.39 107.19,77.72 107.32,77.53 107.35,77.46 107.35,77.25 107.32,77.15 107.32,76.91 107.37,76.72 107.37,76.38 107.59,76.09 CPU1.AR69 ; DM1.25 70.16,81.48 69.79,81.12 69.37,81.12 69.24,81.25 69.24,81.74 69.24,81.74 v2(69.24,82.24)
M_A_DQ14: length 53.7
  TOP w0.089: v2(105.59,78.05) 105.87,78.32 v1(106.09,78.32)
  L3 w0.127: v2(65.69,78.3) 66.85,77.13 72.21,77.13 76.9,81.82 85.99,81.82 86.76,82.59 95.65,82.59 96.77,81.47 96.77,78.96 99.87,75.86 102.39,75.86 102.39,75.86 102.4,75.86 102.71,75.55 103.95,75.55 104.02,75.48 104.78,75.48 106.02,76.72 106.02,77.61 v2(105.59,78.05)
  BOTTOM w0.089: DM1.38 65.63,78.23 v2(65.69,78.3) ; CPU1.AU70 106.23,76.68 106.21,76.76 106.14,76.83 106.14,77.24 105.86,77.53 105.86,77.55 105.84,77.57 105.84,77.79 v2(105.59,78.05)
M_A_DQ15: length 54.8
  TOP w0.089: v1(104.24,79.04) 104.57,78.7 v2(104.57,78.52)
  L3 w0.127: v2(69.96,78.3) 70.4,77.85 71.93,77.85 73.4,79.33 73.4,80.23 73.64,80.47 74.54,80.47 76.68,82.6 76.97,82.6 76.97,82.6 82.61,82.6 82.74,82.73 82.74,83.01 82.87,83.14 83.12,83.14 83.25,83.01 83.25,82.73 83.37,82.6 83.63,82.6 83.76,82.73 83.76,83.01 83.88,83.14 84.14,83.14 84.26,83.01 84.26,82.73 84.39,82.6 84.64,82.6 84.77,82.73 84.77,83.01 84.9,83.14 85.15,83.14 85.28,83.01 85.28,82.73 85.41,82.6 85.76,82.6 86.46,83.3 95.94,83.3 97.53,81.71 97.53,79.35 98.13,78.75 98.31,78.75 98.51,78.95 98.69,78.95 98.87,78.77 98.87,78.59 98.67,78.39 98.67,78.21 98.85,78.03 99.03,78.03 99.23,78.23 99.41,78.23 99.59,78.05 99.59,77.87 99.39,77.67 99.39,77.49 99.57,77.31 99.75,77.31 99.95,77.52 100.13,77.52 100.31,77.34 100.31,77.16 100.11,76.95 100.11,76.77 100.36,76.52 103.46,76.52 104.16,77.22 104.16,78.1 v2(104.57,78.52)
  BOTTOM w0.089: DM1.37 71.08,78.48 70.84,78.72 70.38,78.72 v2(69.96,78.3) ; CPU1.AU69 106.15,76.08 106.12,76.15 106.09,76.26 106.09,76.42 106.07,76.45 106.07,76.47 106.07,76.47 106.07,76.55 106.01,76.61 105.99,76.67 105.97,76.7 105.97,77.17 105.5,77.64 105.44,77.64 105.2,77.89 105.2,78.06 104.73,78.52 v2(104.57,78.52)
M_A_DQ16: length 47.3
  TOP w0.089: v2(94.89,81.35) 94.89,81.65 v1(94.64,81.91)
  L3 w0.127: v2(67.01,76.24) 67.98,75.43 72.54,75.43 77.46,80.34 91.51,80.34 92.13,80.97 93.98,80.97 94.07,80.88 94.44,80.88 94.7,81.14 94.7,81.15 v2(94.89,81.35)
  BOTTOM w0.089: v2(67.01,76.24) 65.81,75.23 DM1.50 ; v2(94.89,81.35) 95.15,81.14 95.29,81.01 95.45,80.92 96.17,80.92 96.47,80.8 96.69,80.58 96.69,80 101.14,75.55 101.14,74.45 102.25,73.35 102.97,73.35 103.05,73.27 CPU1.BB65
M_A_DQ17: length 49.5
  TOP w0.089: v2(68.43,76.24) 68.43,76.33 v1(68.78,76.68)
  L3 w0.127: v2(68.43,76.24) 68.89,75.78 72.39,75.78 77.31,80.7 91.36,80.7 91.98,81.32 v2(94.26,81.32)
  BOTTOM w0.089: v2(68.43,76.24) 69.43,75.24 70.96,75.24 71.2,75.48 DM1.49 ; CPU1.AW65 104.51,73.62 104.34,73.62 104.2,73.66 104.08,73.7 103.97,73.81 103.94,73.91 103.94,73.98 103.85,74.15 103.69,74.19 103.27,74.19 102.98,74.48 102.56,74.48 102.48,74.41 102.15,74.41 101.83,74.73 101.83,76.01 100.35,77.49 100.35,77.81 100.1,78.45 100.02,78.68 96.55,82.15 95.72,82.15 94.66,81.79 v2(94.26,81.32)
M_A_DQ18: length 50.3
  TOP w0.089: v2(94.23,77.56) 94.23,77.72 v1(94.66,78.16)
  L3 w0.127: v2(67.75,71.69) 67.75,72.11 67.95,72.32 71.46,72.32 72.02,72.87 72.62,72.87 78.26,78.52 93.94,78.52 94.23,78.23 v2(94.23,77.56)
  BOTTOM w0.089: CPU1.AW63 104.98,72.23 104.72,72.38 104.45,72.38 104.41,72.34 103.53,72.34 103.39,72.38 103.05,72.38 102.85,72.19 102.48,72.19 102.25,72.41 102.25,72.57 100.48,74.34 100.48,74.85 96.9,78.43 95.1,78.43 v2(94.23,77.56) ; v2(67.75,71.69) 67.89,71.83 67.89,72.35 67.7,72.54 65.56,72.54 65.25,72.23 DM1.62
M_A_DQ19: length 48.6
  TOP w0.089: v2(93.57,77.56) 93.44,77.69 v1(93.44,78.15)
  L3 w0.127: v2(93.57,77.56) 93.57,77.61 93.02,78.16 83.31,78.16 83.18,78.04 83.18,77.5 83.05,77.37 82.8,77.37 82.67,77.5 82.67,78.04 82.54,78.16 82.29,78.16 82.16,78.04 82.16,77.5 82.04,77.37 81.78,77.37 81.65,77.5 81.65,78.04 81.53,78.16 81.27,78.16 81.15,78.04 81.15,77.5 81.02,77.37 80.77,77.37 80.64,77.5 80.64,78.04 80.51,78.16 80.26,78.16 80.13,78.04 80.13,77.5 80,77.37 79.75,77.37 79.62,77.5 79.62,78.04 79.5,78.16 78.98,78.16 78.72,77.91 78.54,77.91 78.47,77.98 78.29,77.98 78.11,77.8 78.11,77.62 78.18,77.55 78.18,77.37 78,77.19 77.82,77.19 77.75,77.26 77.57,77.26 77.39,77.08 77.39,76.91 77.46,76.83 77.46,76.65 77.28,76.47 77.1,76.47 77.03,76.55 76.85,76.55 76.67,76.37 76.67,76.19 76.75,76.11 76.75,75.93 73.26,72.44 72.61,72.44 71.85,71.69 v2(70.59,71.69)
  BOTTOM w0.089: v2(70.59,71.69) 70.59,71.88 70.69,71.98 DM1.63 ; CPU1.AY63 104.04,71.64 102.27,71.64 101.65,72.26 101.65,72.33 99.42,74.56 99.11,74.56 96.77,76.9 94.23,76.9 v2(93.57,77.56)
M_A_DQ20: length 47.8
  TOP w0.089: v2(96.24,81.37) 96.37,81.37 v1(96.72,81.02)
  L3 w0.127: v2(65.59,76.24) 65.59,76.51 65.81,76.72 72.31,76.72 77.05,81.46 86.34,81.46 86.98,82.11 93.91,82.11 93.95,82.15 95.46,82.15 v2(96.24,81.37)
  BOTTOM w0.089: v2(96.24,81.37) 96.39,81.37 97.01,80.76 97.01,80.13 101.32,75.82 101.32,74.53 102.32,73.52 103.16,73.52 103.17,73.53 103.37,73.53 103.63,73.46 CPU1.BA65 ; v2(65.59,76.24) 65.58,76.23 DM1.46
M_A_DQ21: length 48.4
  TOP w0.089: v1(95.86,81.91) 95.55,81.6 v2(95.55,81.35)
  L3 w0.127: v2(70.57,76.24) 70.57,76.24 72.34,76.24 76.7,80.6 76.7,80.6 77.16,81.06 86.88,81.06 87.01,81.18 87.01,81.62 87.13,81.75 87.39,81.75 87.51,81.62 87.51,81.18 87.64,81.06 87.89,81.06 88.02,81.18 88.02,81.62 88.15,81.75 88.4,81.75 88.53,81.62 88.53,81.18 88.66,81.06 88.91,81.06 89.04,81.18 89.04,81.62 89.16,81.75 89.42,81.75 89.55,81.62 89.55,81.18 89.67,81.06 89.93,81.06 90.05,81.18 90.05,81.62 90.18,81.75 90.43,81.75 90.56,81.62 90.56,81.18 90.69,81.06 91.21,81.06 91.83,81.68 93.98,81.68 94.1,81.79 95.08,81.79 95.52,81.35 v2(95.55,81.35)
  BOTTOM w0.089: v2(70.57,76.24) 70.81,76.48 DM1.45 ; CPU1.AY65 104.44,73.27 104.2,73.48 103.82,73.58 103.7,73.63 103.39,73.71 103,73.71 103,73.7 102.44,73.7 101.6,74.54 101.6,75.99 99.88,77.7 97.32,80.26 97.32,80.92 96.42,81.83 96.04,81.83 v2(95.55,81.35)
M_A_DQ22: length 48.2
  TOP w0.089: v1(95.22,77.03) 94.89,77.36 v2(94.89,77.56)
  L3 w0.127: v2(94.89,77.56) 94.89,78.51 94.5,78.9 78.13,78.9 72.48,73.25 71.81,73.25 71.28,72.72 66.82,72.72 66.32,73.21 v2(66.32,73.52)
  BOTTOM w0.089: CPU1.BA63 103.63,72.14 103.37,72.2 103.12,72.2 102.92,72.01 102.4,72.01 102.04,72.38 102.04,72.51 99.97,74.57 99.97,74.9 96.89,77.99 95.32,77.99 v2(94.89,77.56) ; DM1.58 65.3,73.23 65.53,73.01 66.09,73.01 66.32,73.24 v2(66.32,73.52)
M_A_DQ23: length 47.3
  TOP w0.089: v2(96.16,77.56) 96.16,78.15 v1(96.21,78.2)
  L3 w0.127: v2(67.75,73.52) 68.19,73.08 70.94,73.08 71.75,73.88 72.45,73.88 77.88,79.32 94.82,79.32 96.16,77.98 v2(96.16,77.56)
  BOTTOM w0.089: DM1.59 68.28,72.98 v2(67.75,73.52) ; v2(96.16,77.56) 96.72,77.56 100.07,74.22 100.07,74.16 101.86,72.37 101.86,72.3 102.34,71.82 103.16,71.82 CPU1.BB63
M_A_DQ24: length 48
  TOP w0.089: v2(95.63,76.34) 96.14,75.84 v1(96.14,75.63)
  L3 w0.127: v2(68.53,69.63) 68.98,69.19 71.36,69.19 73.2,71.02 73.93,71.02 78.76,75.85 93.14,75.85 93.14,75.85 95.43,75.85 95.63,76.05 v2(95.63,76.34)
  BOTTOM w0.089: v2(68.53,69.63) 68.82,69.92 68.82,70.35 68.27,70.9 67.32,70.9 66.66,70.23 DM1.70 ; CPU1.BA61 103.59,71.26 102.15,71.26 101.29,72.12 101.29,72.19 99.46,74.02 97.85,74.02 95.68,76.19 95.68,76.27 95.63,76.32 v2(95.63,76.34)
M_A_DQ25: length 49.3
  TOP w0.089: v1(93.7,75.73) 93.7,76.27 v2(93.72,76.29)
  L3 w0.127: v2(93.72,76.29) 92.4,76.29 92.28,76.42 92.28,76.89 92.13,77.04 91.92,77.04 91.77,76.89 91.77,76.42 91.64,76.29 91.39,76.29 91.26,76.42 91.26,76.87 91.13,77 90.88,77 90.75,76.87 90.75,76.42 90.63,76.29 90.37,76.29 90.25,76.42 90.25,76.87 90.12,77 89.86,77 89.74,76.87 89.74,76.42 89.61,76.29 89.36,76.29 89.23,76.42 89.23,76.87 89.1,77 88.85,77 88.72,76.87 88.72,76.42 88.59,76.29 78.68,76.29 73.76,71.38 73.05,71.38 72.08,70.41 69.92,70.41 69.72,70.2 69.72,69.84 69.92,69.63 v2(69.96,69.63)
  BOTTOM w0.089: CPU1.AW61 104.78,70.49 104.74,70.48 104.49,70.48 104.28,70.56 104.22,70.62 103.13,70.62 102.88,70.87 101.97,70.87 101.54,71.3 101.54,71.33 100.86,72 100.86,72.05 100.83,72.08 100.83,72.14 99.41,73.57 97.29,73.57 96.19,74.67 94.99,74.67 94.23,75.43 94.23,75.66 93.72,76.17 v2(93.72,76.29) ; v2(69.96,69.63) 70.54,70.22 70.87,70.22 71.1,69.98 DM1.71
M_A_DQ26: length 47.5
  TOP w0.089: v2(97.64,73.17) v1(97.64,73.73)
  L3 w0.127: v2(69.91,66.64) 69.22,67.32 68.04,67.32 67.93,67.42 67.93,68.04 68.04,68.14 71.89,68.14 73.61,69.87 74.23,69.87 79.19,74.82 92.71,74.82 92.72,74.82 96.76,74.82 97.64,73.94 v2(97.64,73.17)
  BOTTOM w0.089: v2(97.64,73.17) 97.56,73.09 97.56,72.42 98.11,71.87 99.69,71.87 101.54,70.02 102.39,70.02 102.74,69.66 103.02,69.66 103.1,69.59 CPU1.BB59 ; v2(69.91,66.64) 70.34,67.08 71.04,67.08 71.13,66.98 DM1.83
M_A_DQ27: length 50.2
  TOP w0.089: v2(95.76,73.04) 95.25,73.04 v1(95.15,73.14)
  L3 w0.127: v2(95.76,73.04) 95.15,73.65 79.66,73.65 71.44,65.43 66.84,65.43 v2(65.64,66.64)
  BOTTOM w0.089: v2(65.64,66.64) 65.54,66.73 DM1.84 ; v2(95.76,73.04) 95.76,72.22 96.79,71.18 99.32,71.18 99.34,71.16 99.39,71.16 99.62,70.93 99.62,70.91 101.88,68.65 102.21,68.65 102.3,68.74 102.55,68.74 103.41,68.76 103.66,68.67 103.94,68.67 104.06,68.61 105.06,68.61 105.1,68.65 105.38,68.65 105.41,68.61 105.7,68.61 105.9,68.81 105.9,69.09 105.47,69.52 105.31,69.52 CPU1.AW59
M_A_DQ28: length 47.6
  TOP w0.089: v1(94.92,75.76) 94.92,75.79 v2(94.36,76.34)
  L3 w0.127: v2(66.32,71.69) 66.32,71.09 66.52,70.89 72.06,70.89 72.9,71.73 73.62,71.73 78.53,76.65 86.86,76.65 86.99,76.78 86.99,77.07 87.11,77.2 87.37,77.2 87.49,77.07 87.49,76.78 87.62,76.65 88.16,76.65 88.37,76.85 88.37,77.2 88.57,77.41 92.59,77.41 93.25,76.75 93.95,76.75 v2(94.36,76.34)
  BOTTOM w0.089: CPU1.BB61 103.14,71.06 102.06,71.06 101.06,72.06 101.06,72.17 99.47,73.75 97.38,73.75 95.88,75.25 94.94,75.25 94.66,75.53 94.66,76.06 94.41,76.32 94.38,76.32 v2(94.36,76.34) ; v2(66.32,71.69) 65.87,71.23 DM1.66
M_A_DQ29: length 48.4
  TOP w0.089: v1(96.82,76.65) 96.52,76.34 v2(96.26,76.34)
  L3 w0.127: v2(96.26,76.34) 96.21,76.39 96.21,76.89 96,77.11 93.39,77.11 92.71,77.79 86.44,77.79 86.32,77.66 86.32,77.13 86.19,77 85.93,77 85.81,77.13 85.81,77.66 85.68,77.79 85.43,77.79 85.3,77.66 85.3,77.13 85.17,77 84.92,77 84.79,77.13 84.79,77.66 84.66,77.79 84.22,77.79 83.44,77 78.38,77 73.47,72.09 72.75,72.09 71.91,71.25 69.61,71.25 v2(69.17,71.69)
  BOTTOM w0.089: CPU1.AY61 103.92,71.3 103.79,71.44 102.22,71.44 101.47,72.19 101.47,72.26 99.47,74.26 98.32,74.26 96.62,75.96 96.62,75.99 v2(96.26,76.34) ; DM1.67 71.33,70.98 71.02,70.68 70.18,70.68 v2(69.17,71.69)
M_A_DQ30: length 48.2
  TOP w0.089: v1(97.48,72.31) 97.13,72.66 v2(97.13,72.76)
  L3 w0.127: v2(68.48,66.64) 68.48,66.38 68.67,66.19 71.2,66.19 79.47,74.47 92.57,74.47 92.57,74.46 95.78,74.46 95.78,74.47 96.44,74.47 97.13,73.78 v2(97.13,72.76)
  BOTTOM w0.089: DM1.79 71.44,67.98 71.41,68.02 68.46,68.02 68.25,67.81 68.25,66.87 v2(68.48,66.64) ; CPU1.BA59 103.83,69.48 103.61,69.48 103.51,69.38 103.38,69.33 103.07,69.33 102.93,69.47 102.6,69.47 102.28,69.79 101.44,69.79 99.59,71.64 98.02,71.64 97.18,72.48 97.18,72.71 v2(97.13,72.76)
M_A_DQ31: length 49.3
  TOP w0.089: v2(96.34,72.74) 96.27,72.81 v1(96.27,73.61)
  L3 w0.127: v2(67.06,66.64) 67.06,66.09 67.32,65.84 71.34,65.84 79.62,74.11 92.42,74.11 92.42,74.11 95.71,74.11 96.32,73.5 96.32,72.76 v2(96.34,72.74)
  BOTTOM w0.089: DM1.80 64.24,67.73 64.24,67.73 66.82,67.73 67.06,67.49 v2(67.06,66.64) ; v2(96.34,72.74) 96.37,72.71 96.37,72.18 97.13,71.41 99.5,71.41 101.35,69.56 102.25,69.56 102.51,69.3 102.92,69.15 103.41,69.15 103.69,69.24 104.09,69.24 104.18,69.28 CPU1.AY59
M_A_DQ32: length 52.7
  TOP w0.089: v2(67.11,43.32) v1(67.11,42.76)
  L3 w0.127: v2(67.11,43.32) 67.11,42.63 67.4,42.34 68.34,42.34 68.46,42.21 68.46,41.8 68.59,41.67 68.84,41.67 68.97,41.8 68.97,42.21 69.1,42.34 71.05,42.34 72.54,40.85 78.22,40.85 81.11,43.74 81.61,43.74 85.1,47.23 85.1,48.77 91.15,54.81 93.45,54.81 97,58.36 v2(97.41,58.36)
  BOTTOM w0.089: CPU1.AY39 104.36,58.54 104.05,58.86 103.69,58.86 103.38,59.01 102.88,59.01 102.76,59.13 98.12,59.13 97.43,58.44 97.43,58.39 v2(97.41,58.36) ; DM1.174 66.17,42.23 67.11,43.17 v2(67.11,43.32)
M_A_DQ33: length 51.3
  TOP w0.089: v2(68.6,43.32) v1(68.6,42.76)
  L3 w0.127: v2(68.6,43.32) 69.04,43.78 70.99,43.78 72.85,41.91 78.24,41.91 84.39,48.07 84.39,49.06 90.91,55.57 93.53,55.57 97.06,59.11 98.39,59.11 v2(99.34,58.41)
  BOTTOM w0.089: CPU1.AW39 105.24,58.06 105.18,57.84 105.05,57.72 104.67,57.62 104.18,57.62 104.04,57.66 103.79,57.66 103.71,57.62 103.51,57.62 103.43,57.66 103.04,57.66 102.93,57.55 100.17,57.55 100.02,57.7 v2(99.34,58.41) ; DM1.173 69.44,42.48 v2(68.6,43.32)
M_A_DQ34: length 52.7
  TOP w0.089: v1(96.7,56.28) 96.72,56.3 v2(97.36,56.3)
  L3 w0.127: v2(97.36,56.3) 96.88,56.3 93.77,53.19 92.11,53.19 86.84,47.92 86.84,45.51 84.04,42.71 83.18,42.71 82.92,42.46 82.92,42.28 83.18,42.02 83.18,41.84 83,41.67 82.82,41.67 82.57,41.92 82.39,41.92 82.21,41.74 82.21,41.56 82.46,41.31 82.46,41.13 82.28,40.95 82.1,40.95 81.85,41.2 81.67,41.2 81.49,41.02 81.49,40.84 81.74,40.59 81.74,40.41 81.56,40.23 81.38,40.23 81.13,40.48 80.95,40.48 80.77,40.3 80.77,40.12 81.02,39.87 81.02,39.69 80.84,39.51 80.66,39.51 80.41,39.76 80.23,39.76 79.5,39.03 79.14,39.03 79.02,38.9 79.02,38.57 78.89,38.45 78.64,38.45 78.51,38.57 78.51,38.9 78.38,39.03 78.13,39.03 78,38.9 78,38.57 77.87,38.45 77.62,38.45 77.49,38.57 77.49,38.9 77.37,39.03 77.11,39.03 76.98,38.9 76.98,38.57 76.86,38.45 76.6,38.45 76.48,38.57 76.48,38.9 76.35,39.03 76.1,39.03 75.97,38.9 75.97,38.57 75.84,38.45 75.59,38.45 75.46,38.57 75.46,38.9 75.33,39.03 v2(70.79,39.03)
  BOTTOM w0.089: v2(70.79,39.03) 72.3,39.03 DM1.187 ; v2(97.36,56.3) 97.36,56.89 97.89,57.42 99.99,57.42 100.04,57.37 103,57.37 103.11,57.48 103.39,57.48 103.47,57.44 103.75,57.44 103.84,57.48 104.01,57.48 104.11,57.45 104.12,57.45 104.26,57.38 CPU1.AY37
M_A_DQ35: length 53.2
  TOP w0.089: v1(99.67,56.66) 99.34,56.33 v2(99.34,56.18)
  L3 w0.127: v2(99.34,56.18) 99.03,55.87 96.82,55.87 93.84,52.89 92.32,52.89 87.2,47.77 87.2,45.36 80.96,39.12 80.2,39.12 79.17,38.09 75.39,38.09 74.99,38.49 70.05,38.49 69.67,38.86 69.67,38.94 69.16,39.45 66.27,39.45 66.11,39.3 66.11,38.88 v2(66.27,38.73)
  BOTTOM w0.089: CPU1.AW37 105.12,57.32 104.81,57 104.14,57 104.09,56.96 103.95,56.96 103.77,56.78 103.75,56.78 103.75,56.78 103.01,56.78 103,56.78 102.99,56.78 102.94,56.84 100.13,56.84 100.04,56.74 99.52,56.74 99.39,56.61 99.39,56.23 v2(99.34,56.18) ; v2(66.27,38.73) 66.27,38.97 66,39.23 DM1.186
M_A_DQ36: length 50.6
  TOP w0.089: v2(65.84,43.32) 65.81,43.3 v1(65.28,43.3)
  L3 w0.127: v2(65.84,43.32) 65.86,43.35 65.86,43.91 66.19,44.24 71.03,44.24 73,42.27 78.09,42.27 84.04,48.21 84.04,49.21 90.78,55.95 93.57,55.95 96.98,59.35 102.84,59.35 103.02,59.17 103.02,58.67 102.92,58.57 v2(102.51,58.57)
  BOTTOM w0.089: CPU1.BB39 102.53,58.54 v2(102.51,58.57) ; DM1.170 65.72,43.23 65.81,43.32 v2(65.84,43.32)
M_A_DQ37: length 51.5
  TOP w0.089: v2(70.13,43.32) v1(70.13,42.76)
  L3 w0.127: v2(70.13,43.32) 70.11,43.32 69.91,43.12 69.91,42.9 70.11,42.7 71.57,42.7 72.71,41.56 73.2,41.56 73.33,41.43 73.33,41.33 73.46,41.2 73.71,41.2 73.84,41.33 73.84,41.43 73.97,41.56 74.22,41.56 74.35,41.43 74.35,41.33 74.47,41.2 74.73,41.2 74.85,41.33 74.85,41.43 74.98,41.56 75.24,41.56 75.36,41.43 75.36,41.33 75.49,41.2 75.74,41.2 75.87,41.33 75.87,41.43 76,41.56 76.25,41.56 76.38,41.43 76.38,41.33 76.51,41.2 76.76,41.2 76.89,41.33 76.89,41.43 77.01,41.56 77.27,41.56 77.39,41.43 77.39,41.33 77.52,41.2 77.78,41.2 77.9,41.33 77.9,41.43 78.03,41.56 78.39,41.56 81.05,44.22 81.23,44.22 81.32,44.13 81.5,44.13 81.68,44.3 81.68,44.48 81.58,44.58 81.58,44.76 81.76,44.94 81.94,44.94 82.04,44.84 82.22,44.84 82.4,45.02 82.4,45.2 82.3,45.3 82.3,45.47 82.48,45.65 82.66,45.65 82.75,45.56 82.93,45.56 83.11,45.74 83.11,45.92 83.02,46.01 83.02,46.19 83.2,46.37 83.38,46.37 83.47,46.28 83.65,46.28 83.83,46.46 83.83,46.64 83.74,46.73 83.74,46.91 83.92,47.09 84.1,47.09 84.19,47 84.37,47 84.55,47.18 84.55,47.36 84.46,47.45 84.46,47.63 84.75,47.92 84.75,48.91 91.03,55.19 93.48,55.19 97.05,58.77 98.3,58.77 v2(98.7,58.36)
  BOTTOM w0.089: v2(98.7,58.36) 98.7,58.8 98.86,58.96 102.68,58.96 102.8,58.84 103.32,58.84 103.55,58.73 103.72,58.65 103.83,58.65 CPU1.BA39 ; v2(70.13,43.32) 70.13,43.73 70.31,43.91 70.82,43.91 71.25,43.48 DM1.169
M_A_DQ38: length 52.3
  TOP w0.089: v2(98.63,56.3) 98.63,56.68 v1(98.45,56.86)
  L3 w0.127: v2(67.82,40.96) 67.82,40.36 68.02,40.16 71.41,40.16 71.83,39.74 79.18,39.74 82.9,43.47 83.79,43.47 86.13,45.81 86.13,48.28 90.12,52.26 90.12,52.32 91.54,53.75 93.51,53.75 96.69,56.93 98.37,56.93 98.63,56.67 v2(98.63,56.3)
  BOTTOM w0.089: CPU1.BA37 103.67,56.95 103.08,56.95 103.02,57.01 100.03,57.01 99.95,56.94 98.91,56.94 98.65,56.68 98.65,56.33 v2(98.63,56.3) ; DM1.183 71.99,39.98 71.27,39.98 70.78,40.48 68.17,40.48 67.87,40.78 67.87,40.91 v2(67.82,40.96)
M_A_DQ39: length 51.3
  TOP w0.089: v2(97.99,56.3) 97.99,55.85 v1(98.22,55.62)
  L3 w0.127: v2(97.99,56.3) 97.59,56.71 96.86,56.71 93.56,53.41 92.01,53.41 92,53.39 91.81,53.39 86.49,48.07 86.49,45.66 83.89,43.06 83.03,43.06 79.35,39.39 71.06,39.39 70.64,39.81 66.56,39.81 66.23,40.13 66.23,40.7 v2(66.5,40.96)
  BOTTOM w0.089: v2(66.5,40.96) 66.5,40.47 66.26,40.23 DM1.182 ; CPU1.BB37 103.26,57.19 99.95,57.19 99.91,57.15 98.51,57.15 97.99,56.63 v2(97.99,56.3)
M_A_DQ40: length 56.7
  TOP w0.089: v1(102.84,55.62) 102.51,55.95 v2(102.51,56.07)
  L3 w0.127: v2(70.1,36.62) 70.1,36.67 70.49,37.06 71.39,37.06 72.39,36.07 73.06,36.07 73.58,35.54 73.95,35.54 74.48,36.07 79.91,36.07 88.76,44.91 88.76,47.2 92.26,50.7 92.97,50.7 97.22,54.96 103.46,54.96 104.26,55.76 104.26,57.92 104.13,58.05 102.19,58.05 101.86,57.71 101.86,57.17 102.51,56.51 v2(102.51,56.07)
  BOTTOM w0.089: CPU1.AY35 104.47,55.97 104.14,55.97 104.04,55.93 103.84,55.93 103.74,55.96 103.47,55.96 103.35,55.91 102.67,55.91 v2(102.51,56.07) ; DM1.195 71.07,36.98 70.98,37.08 70.53,37.08 70.1,36.64 v2(70.1,36.62)
M_A_DQ41: length 57.5
  TOP w0.089: v1(102.16,56.63) 101.88,56.35 v2(101.88,56.07)
  L3 w0.127: v2(101.88,56.07) 100.99,55.19 97.1,55.19 94.13,52.22 93.15,52.22 88.4,47.47 88.4,45.06 79.77,36.42 73.96,36.42 73.95,36.43 73.58,36.43 73.57,36.42 72.55,36.42 72.5,36.47 72.5,36.47 71.55,37.42 68.3,37.42 67.71,38.01 64.71,38.01 64.51,37.81 64.51,37.35 64.71,37.15 65.95,37.15 v2(66.5,36.6)
  BOTTOM w0.089: v2(66.5,36.6) 65.87,37.23 DM1.194 ; CPU1.AW35 104.94,55.79 104.17,55.79 104.07,55.75 103.8,55.75 103.71,55.79 103.51,55.79 103.42,55.75 103.42,55.75 103.38,55.73 102.81,55.73 102.81,55.72 102.68,55.59 102.29,55.59 101.88,56 v2(101.88,56.07)
M_A_DQ42: length 56.9
  TOP w0.089: v1(101.85,53.56) 101.85,53.74 v2(101.47,54.12)
  L3 w0.089: 97.35,53.29 97.5,53.43 101.1,53.43 101.47,53.8 v2(101.47,54.12)
  L3 w0.127: 97.35,53.29 92.84,48.78 92.84,47.36 91.43,45.94 91.43,45.01 90.54,44.12 90.54,43.42 87.43,40.31 87.26,40.31 87.03,40.54 86.85,40.54 86.67,40.36 86.67,40.18 86.9,39.95 86.9,39.77 86.72,39.59 86.54,39.59 86.31,39.82 86.13,39.82 85.95,39.64 85.95,39.46 86.18,39.23 86.18,39.05 86,38.87 85.82,38.87 85.59,39.1 85.41,39.1 85.23,38.92 85.23,38.74 85.46,38.52 85.46,38.34 85.28,38.16 85.1,38.16 84.87,38.38 84.69,38.38 84.51,38.2 84.51,38.02 84.74,37.8 84.74,37.62 84.56,37.44 84.38,37.44 84.27,37.54 84.06,37.54 83.92,37.39 83.92,37.18 84.02,37.08 84.02,36.9 83.84,36.72 83.66,36.72 83.55,36.83 83.37,36.83 83.19,36.65 83.19,36.47 83.3,36.36 83.3,36.18 83,35.88 82.21,35.88 81.61,35.28 81.61,35.1 81.83,34.89 81.83,34.71 81.65,34.53 81.47,34.53 81.26,34.74 81.08,34.74 79.54,33.21 71.52,33.21 70.68,34.05 70.05,34.05 v2(69.09,35)
  BOTTOM w0.089: DM1.207 70.11,33.98 v2(69.09,35) ; CPU1.AY33 104.36,54.71 104.16,54.57 103.92,54.57 103.57,54.49 103.51,54.45 103.39,54.42 102.59,54.42 102.51,54.5 101.73,54.5 101.47,54.24 v2(101.47,54.12)
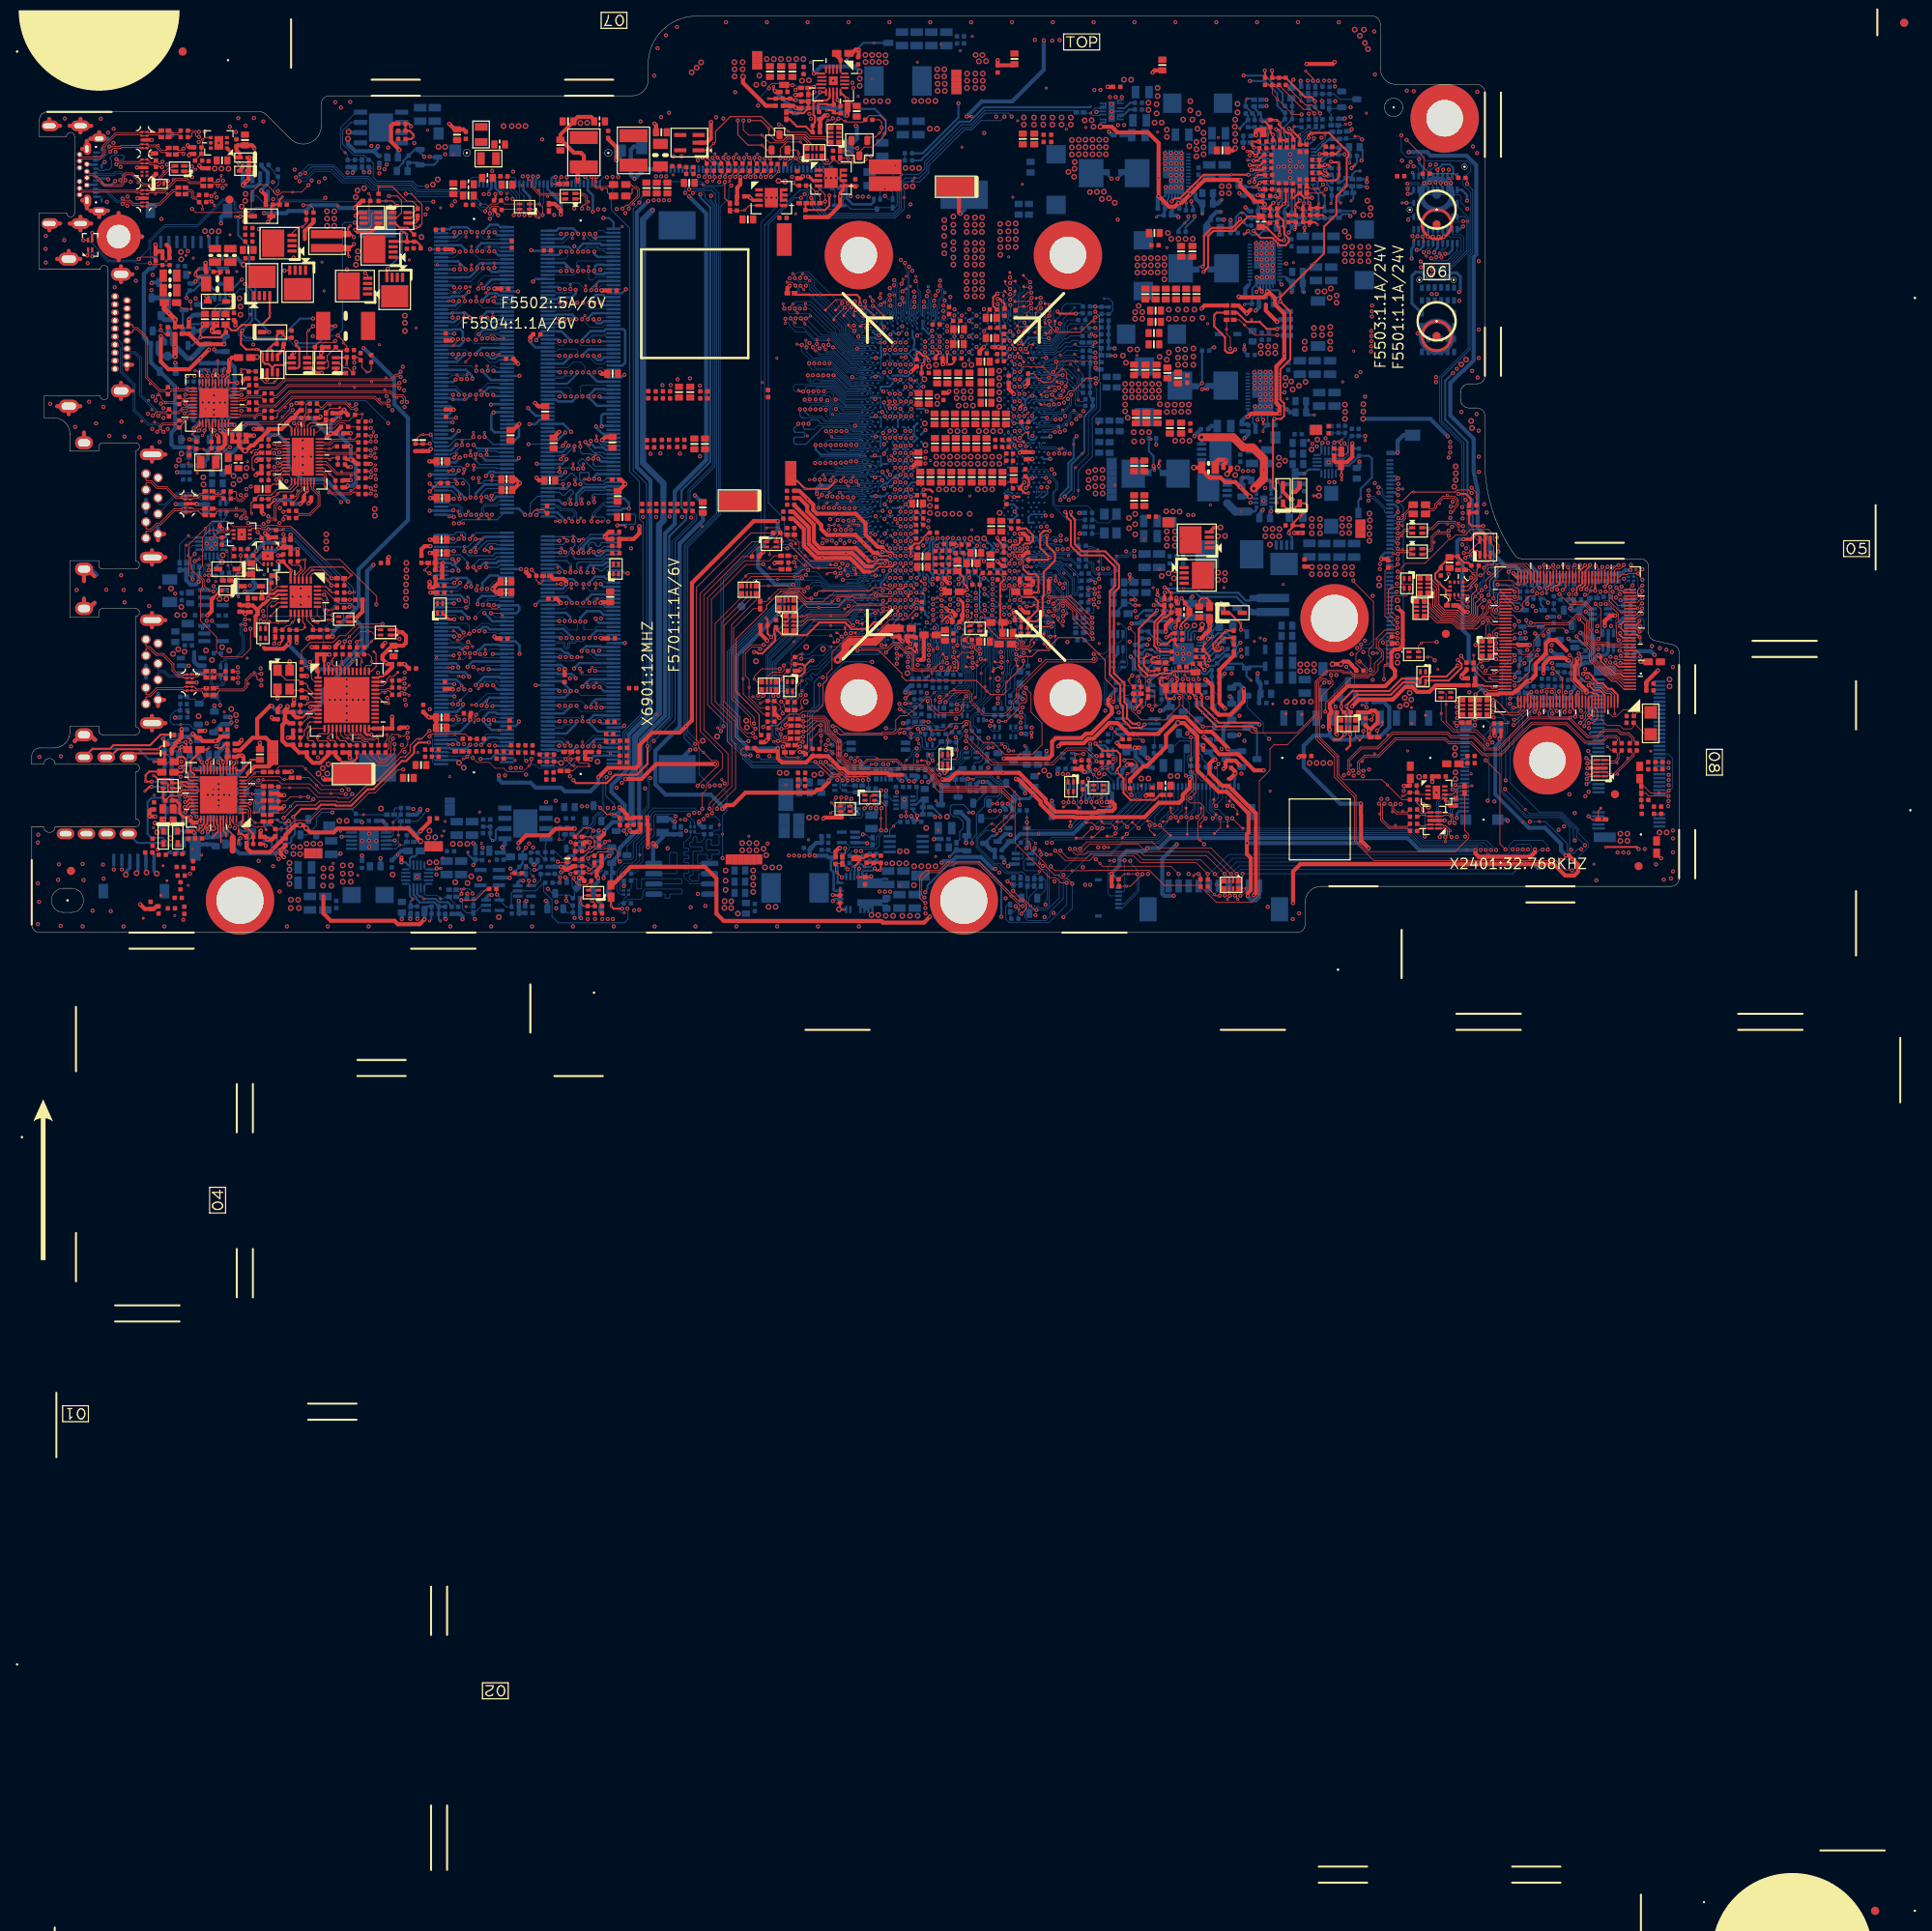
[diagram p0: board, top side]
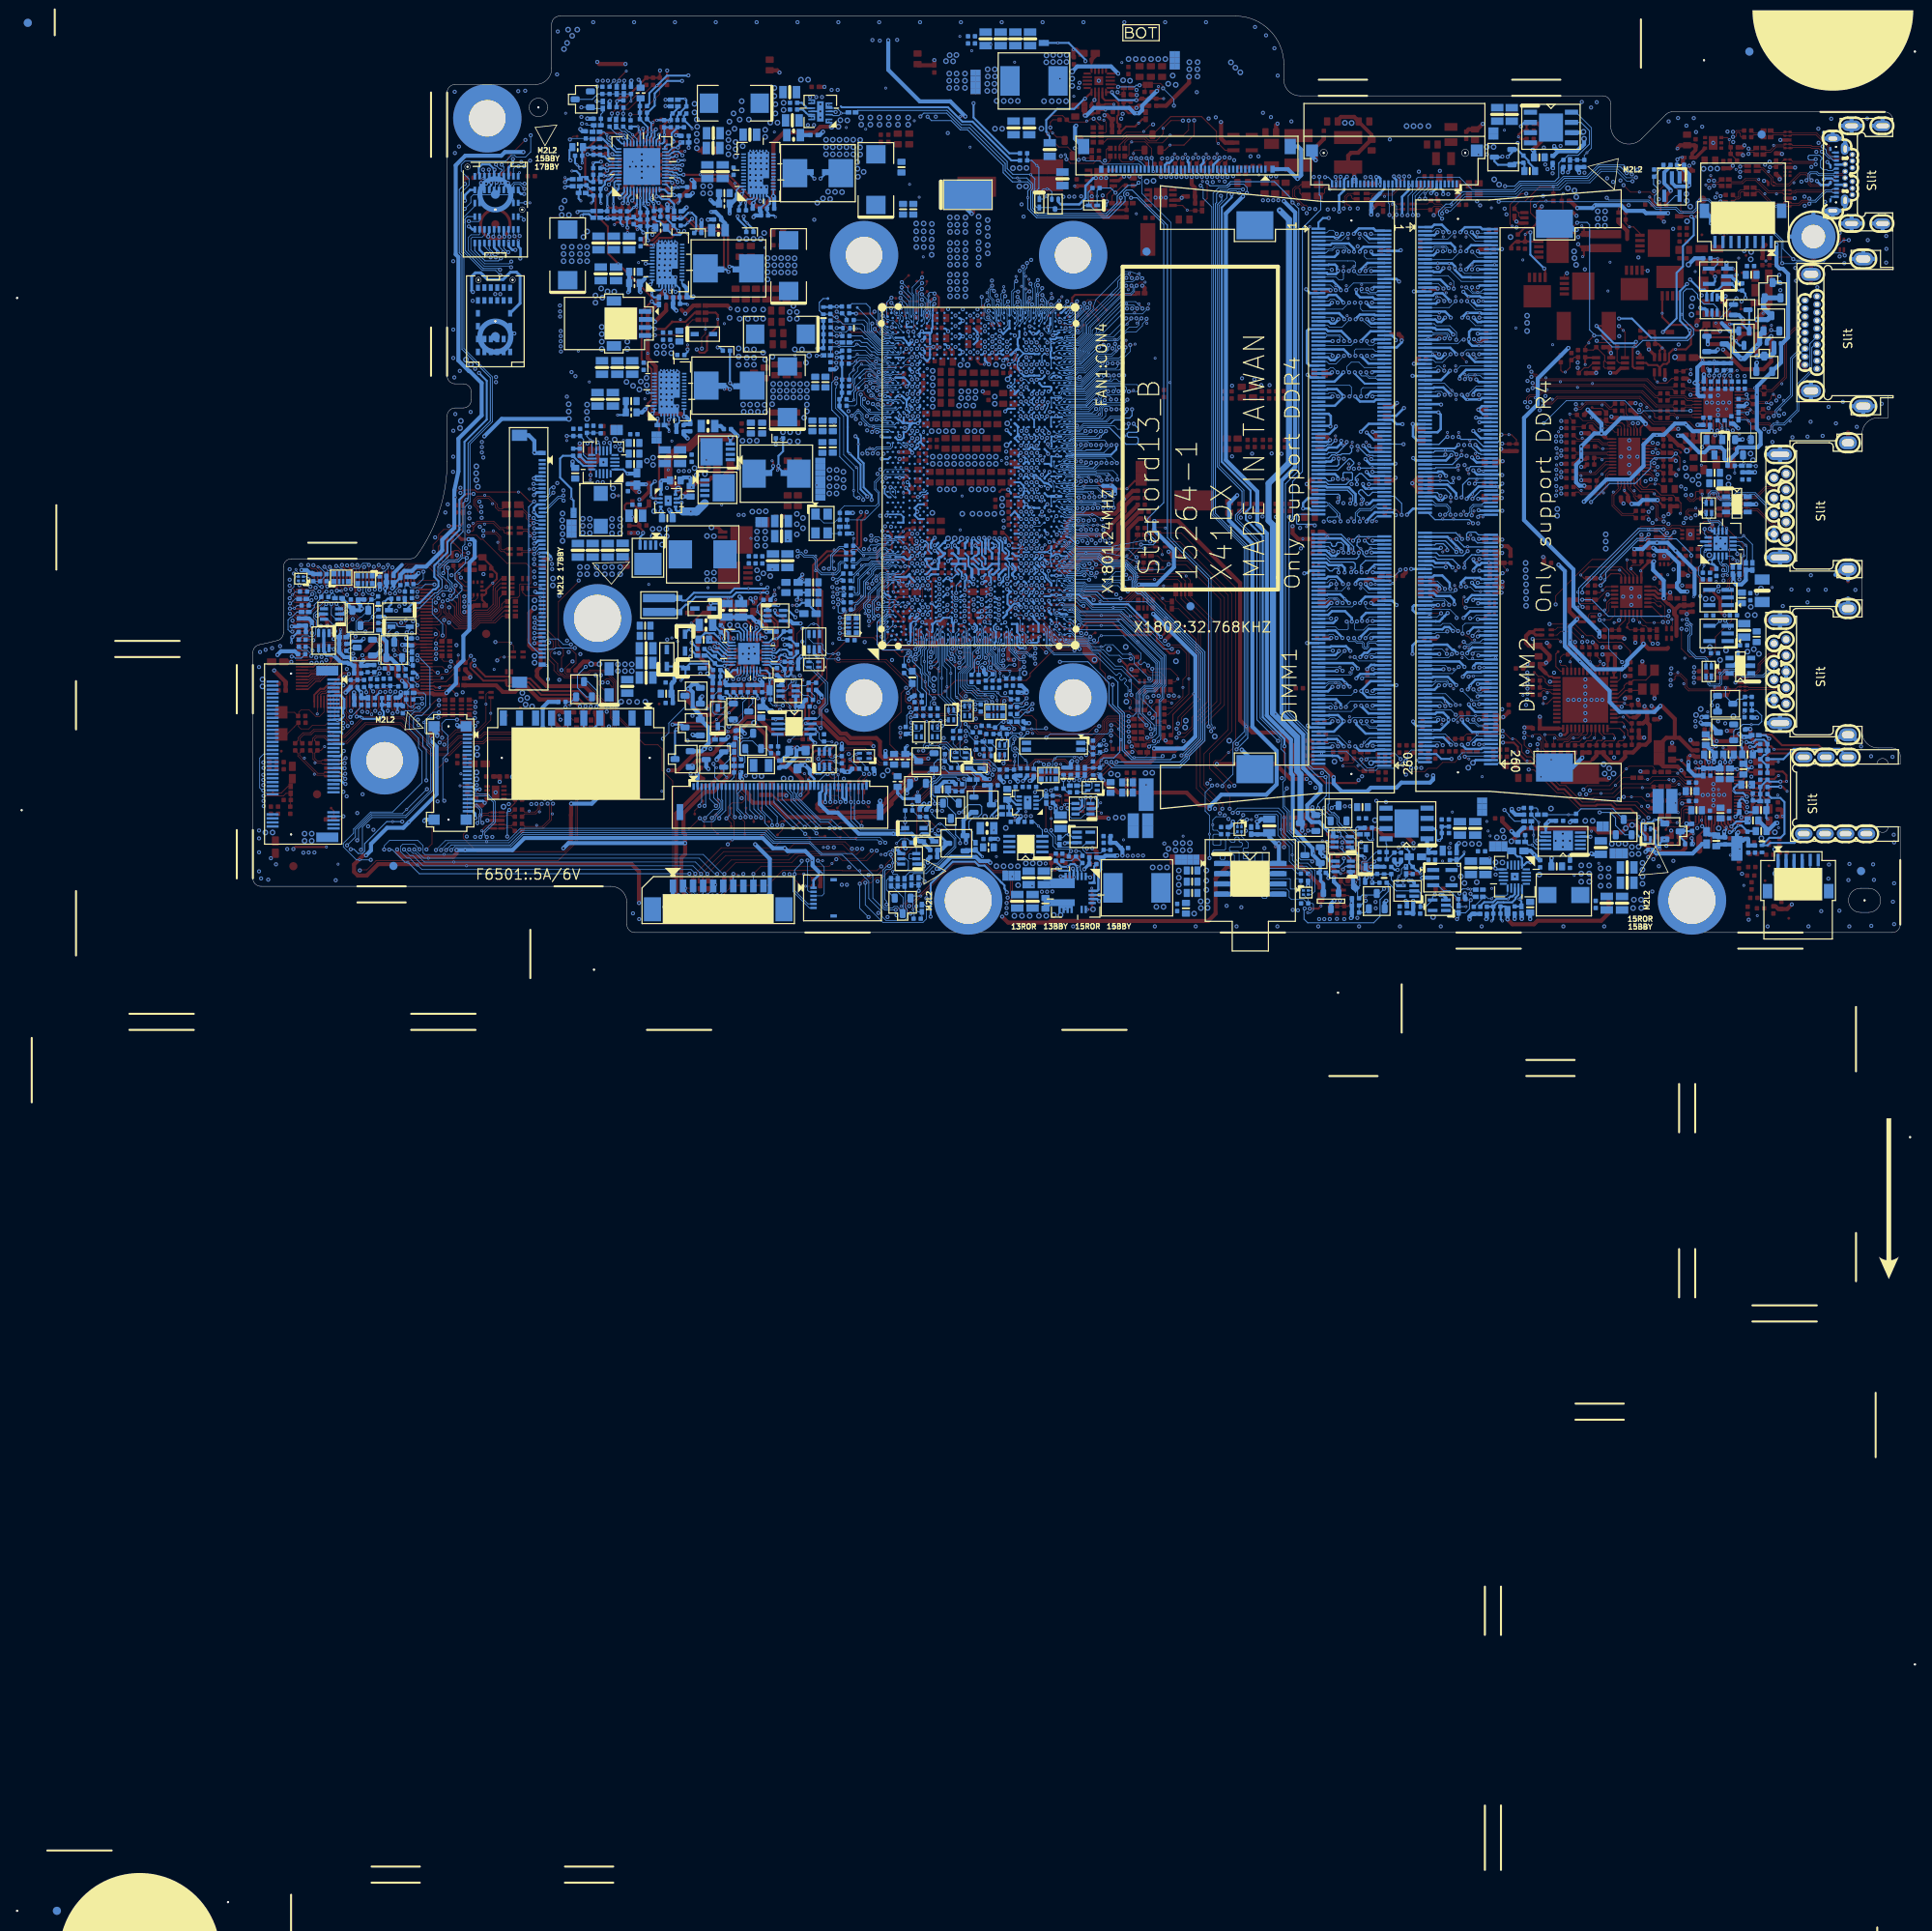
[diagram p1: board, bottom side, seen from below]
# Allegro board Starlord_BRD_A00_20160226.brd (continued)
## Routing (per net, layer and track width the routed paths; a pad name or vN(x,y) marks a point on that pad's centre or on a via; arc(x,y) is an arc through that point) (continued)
M_A_DQ43: length 55.2
  TOP w0.089: v2(67.85,34.24) v1(68.41,34.24)
  L3 w0.127: v2(105.75,56.23) 102.56,53.64 101.33,53.23 97.67,53.23 94.44,50 93.8,48.52 93.11,47.83 93.11,46.84 92.81,45.62 91.37,44.19 90.9,43.28 81.66,34.04 79.79,32.86 71.37,32.86 70.54,33.69 69.8,33.69 v2(67.85,34.24)
  BOTTOM w0.089: v2(67.85,34.24) 67.37,33.75 65.16,33.75 65.14,33.73 DM1.208 ; v2(105.75,56.23) 105.75,56.19 105.37,55.82 105.24,55.44 CPU1.AW33
M_A_DQ44: length 55.6
  TOP w0.089: v1(101.55,55.49) 101.24,55.8 v2(101.24,56.07)
  L3 w0.127: v2(101.24,56.07) 101.24,55.76 100.9,55.41 97.03,55.41 94.04,52.43 92.87,52.43 87.91,47.48 87.91,45.07 80.87,38.03 80.69,38.03 80.5,38.23 80.32,38.23 80.14,38.05 80.14,37.87 80.33,37.67 80.33,37.49 79.67,36.83 79.31,36.83 79.19,36.96 79.19,37.25 79.06,37.38 78.81,37.38 78.68,37.25 78.68,36.96 78.55,36.83 78.3,36.83 78.17,36.96 78.17,37.25 78.04,37.38 77.79,37.38 77.66,37.25 77.66,36.96 77.54,36.83 77.28,36.83 77.16,36.96 77.16,37.25 77.03,37.38 76.77,37.38 76.65,37.25 76.65,36.96 76.52,36.83 76.27,36.83 76.14,36.96 76.14,37.23 75.99,37.38 75.78,37.38 75.63,37.23 75.63,36.96 75.5,36.83 72.64,36.83 71.7,37.77 68.51,37.77 68.38,37.9 68.38,38.21 68.83,38.65 v2(68.83,38.65)
  BOTTOM w0.089: DM1.191 70.2,37.98 69.86,37.64 68.77,37.64 68.64,37.77 68.64,38.52 68.77,38.65 v2(68.83,38.65) ; CPU1.BB35 103.24,56.19 102.75,56.38 102.67,56.46 101.63,56.46 v2(101.24,56.07)
M_A_DQ45: length 56.1
  TOP w0.089: v2(100.61,56.13) 100.61,56.25 v1(100.94,56.58)
  L3 w0.127: v2(67.56,38.68) 67.56,38.97 67.69,39.09 69.02,39.09 69.29,38.82 69.29,38.27 69.43,38.13 72.59,38.13 72.72,38 72.72,37.34 72.86,37.2 73.08,37.2 73.22,37.34 73.22,38 73.35,38.13 73.61,38.13 73.73,38 73.73,37.31 73.86,37.19 74.11,37.19 74.24,37.31 74.24,38 74.37,38.13 74.85,38.13 75.24,37.73 79.32,37.73 80.35,38.77 81.1,38.77 87.55,45.22 87.55,47.62 92.58,52.65 93.93,52.65 96.92,55.64 100.36,55.64 100.61,55.89 v2(100.61,56.13)
  BOTTOM w0.089: v2(100.61,56.13) 101.13,56.65 102.88,56.65 102.95,56.58 103.74,56.58 103.94,56.38 CPU1.BA35 ; v2(67.56,38.68) 67.57,38.68 67.86,38.38 67.86,37.73 67.74,37.6 66.75,37.6 66.11,38.23 DM1.190
M_A_DQ46: length 56
  TOP w0.089: v1(100.43,54.73) 100.84,54.32 v2(100.84,54.12)
  L3 w0.089: v2(100.84,54.12) 100.84,53.76 100.69,53.61 97.35,53.61 97.18,53.45
  L3 w0.127: v2(70.56,35.04) 70.56,34.64 70.81,34.39 71.39,34.39 71.59,34.58 71.77,34.58 71.95,34.41 71.95,34.23 71.75,34.03 71.75,33.85 72.01,33.6 74.29,33.6 74.42,33.72 74.42,34.01 74.57,34.16 74.78,34.16 74.93,34.01 74.93,33.72 75.05,33.6 75.31,33.6 75.43,33.72 75.43,33.98 75.58,34.13 75.79,34.13 75.94,33.98 75.94,33.72 76.07,33.6 79.4,33.6 87.05,41.24 87.23,41.24 87.45,41.01 87.63,41.01 87.81,41.19 87.81,41.37 87.59,41.6 87.59,41.78 87.77,41.96 87.95,41.96 88.17,41.73 88.35,41.73 88.53,41.91 88.53,42.09 88.3,42.32 88.3,42.5 88.48,42.68 88.66,42.68 88.89,42.45 89.07,42.45 89.25,42.63 89.25,42.81 89.02,43.04 89.02,43.22 89.2,43.4 89.38,43.4 89.61,43.17 89.79,43.17 89.97,43.35 89.97,43.53 89.74,43.76 89.74,43.94 90.14,44.34 90.14,44.75 90.27,44.88 90.74,44.88 90.87,45 90.87,45.26 90.74,45.39 90.27,45.39 90.14,45.51 90.14,46.62 90.4,46.89 91.3,46.89 91.43,47.01 91.43,47.53 91.54,47.64 91.8,47.64 92.1,47.34 92.28,47.34 92.46,47.52 92.46,47.7 91.95,48.21 91.95,48.39 92.84,49.28 93.01,49.28 97.18,53.45
  BOTTOM w0.089: v2(100.84,54.12) 100.84,54.47 101.05,54.68 102.59,54.68 102.66,54.6 103.36,54.6 103.43,54.62 103.82,54.86 CPU1.BA33 ; v2(70.56,35.04) 72.29,35.04 DM1.203
M_A_DQ47: length 54.6
  L3 w0.089: 96.78,53.41 97.15,53.79 99.87,53.79 v2(100.2,54.12)
  L3 w0.127: v2(66.43,34.24) 65.67,35 65.38,35 65.25,35.12 65.25,35.84 65.38,35.96 67.91,35.96 68.38,35.49 71.37,35.49 72.87,33.99 73.86,33.99 74.81,34.95 75.51,34.95 76.47,33.99 79.29,33.99 89.79,44.49 89.79,46.77 92.65,49.64 93,49.64 96.78,53.41
  BOTTOM w0.089: v2(66.43,34.24) 66.32,34.24 65.89,34.66 65.3,34.66 65.23,34.73 DM1.204 ; CPU1.BB33 103.25,54.83 102.72,54.83 102.69,54.86 100.71,54.86 v1(100.52,54.66) 100.23,54.37 100.23,54.14 v2(100.2,54.12)
M_A_DQ48: length 55.7
  TOP w0.089: v1(100.15,53.28) 99.76,52.89 v2(99.76,52.78)
  L3 w0.127: v2(99.76,52.78) 99.35,52.37 98.98,52.37 98.51,51.89 97.92,51.89 95.44,49.41 95.44,47.7 94.24,46.51 94.24,45.05 92.79,43.6 92.79,42.78 81.16,31.15 74.93,31.15 74.21,30.43 71.41,30.43 70.69,31.15 68.03,31.15 67.43,30.54 66.48,30.54 66.28,30.75 66.28,31.27 66.61,31.6 v2(66.93,31.6)
  BOTTOM w0.089: CPU1.AY31 104.23,53.2 103.43,53.2 103.38,53.15 100.14,53.15 v2(99.76,52.78) ; DM1.216 66.79,31.73 v2(66.93,31.6)
M_A_DQ49: length 56.1
  TOP w0.089: v2(68.15,32.81) 68.15,32.6 v1(68.43,32.33)
  L3 w0.127: v2(97.81,52.8) 97.62,52.8 94.7,49.88 94.7,49.1 93.42,47.82 93.42,45.74 91.73,44.04 91.73,43.57 80.66,32.5 71.22,32.5 70.39,33.33 69.32,33.33 68.44,33.7 67.76,33.7 67.63,33.57 67.63,33.25 68.07,32.81 v2(68.15,32.81)
  BOTTOM w0.089: DM1.215 68.35,31.98 68.15,32.18 v2(68.15,32.81) ; v2(97.81,52.8) 97.81,53.56 97.94,53.69 102.72,53.69 103.05,54.02 103.42,54.02 103.57,53.95 103.64,53.88 104.74,53.88 105.05,53.56 CPU1.AW31
M_A_DQ50: length 55.4
  TOP w0.089: v2(101.57,51.23) 101.57,51.23 102.06,50.74 102.72,50.74 v1(102.81,50.64)
  L3 w0.127: v2(68.93,28.03) 68.93,28.45 69.17,28.69 81.16,28.69 94.03,41.55 94.03,43.24 96.63,45.83 96.63,48.82 98.5,50.69 101.03,50.69 v2(101.57,51.23)
  BOTTOM w0.089: CPU1.AY29 104.19,52.06 104.03,51.94 103.84,51.89 103.72,51.76 103.1,51.76 102.94,51.6 101.95,51.6 101.58,51.23 v2(101.57,51.23) ; DM1.228 67.2,28.73 67.24,28.77 68.38,28.77 68.93,28.21 v2(68.93,28.03)
M_A_DQ51: length 55
  TOP w0.089: v2(70.2,27.96) v1(70.2,28.52)
  L3 w0.127: v2(70.2,27.96) 70.66,27.5 70.73,27.5 70.74,27.49 71.6,27.49 72.23,28.12 72.63,28.12 72.76,27.99 72.76,27.62 72.89,27.49 73.14,27.49 73.27,27.62 73.27,27.99 73.39,28.12 73.65,28.12 73.78,27.99 73.78,27.62 73.9,27.49 74.16,27.49 74.28,27.62 74.28,27.99 74.41,28.12 81.21,28.12 92.26,39.17 93.07,39.17 93.43,39.53 93.43,40.45 94.28,41.3 94.28,41.78 96.92,44.43 96.92,48.81 98.59,50.47 102.83,50.47 104.77,52.42 v2(105.81,52.42)
  BOTTOM w0.089: CPU1.AW29 105.73,52.34 v2(105.81,52.42) ; v2(70.2,27.96) 70.73,28.48 DM1.229
M_A_DQ52: length 53.9
  TOP w0.089: v2(69.35,32.53) 69.69,32.87 v1(69.69,32.98)
  L3 w0.127: v2(99.13,52.79) 99.07,52.79 98.4,52.11 97.83,52.11 95.21,49.49 95.21,48.03 93.89,46.71 93.89,45.2 92.44,43.75 92.44,43.21 80.99,31.77 74.25,31.77 74.13,31.64 74.13,31 74,30.88 73.75,30.88 73.62,31 73.62,31.64 73.49,31.77 73.24,31.77 73.11,31.64 73.11,31 72.96,30.85 72.75,30.85 72.6,31 72.6,31.64 72.48,31.77 72.22,31.77 72.1,31.64 72.1,31 71.97,30.88 71.71,30.88 71.59,31 71.59,31.64 71.46,31.77 69.62,31.77 69.35,32.04 v2(69.35,32.53)
  BOTTOM w0.089: v2(69.35,32.53) 69.81,33 69.82,32.98 DM1.211 ; v2(99.13,52.79) 99.6,53.26 99.97,53.26 100.05,53.33 103.05,53.33 CPU1.BB31
M_A_DQ53: length 54.6
  TOP w0.089: v2(98.45,52.8) 98.45,52.92 v1(98.91,53.38)
  L3 w0.127: v2(98.45,52.8) 98.02,52.37 97.61,52.37 94.96,49.71 94.96,48.17 93.66,46.86 93.66,45.47 92.08,43.89 92.08,43.41 80.8,32.13 71.09,32.13 70.24,32.98 69.16,32.98 68.48,32.29 66.8,32.29 66.29,31.78 65.26,31.78 65.05,31.99 65.05,32.53 65.26,32.74 v2(65.59,32.74)
  BOTTOM w0.089: v2(65.59,32.74) 65.58,32.73 DM1.212 ; v2(98.45,52.8) 98.45,53.28 98.68,53.51 102.79,53.51 103.12,53.84 103.35,53.84 103.38,53.82 103.47,53.79 103.52,53.75 103.7,53.56 CPU1.BA31
M_A_DQ54: length 54.4
  TOP w0.089: v2(100.23,51.27) 99.59,50.64 v1(99.13,50.64)
  L3 w0.127: v2(100.23,51.27) 99.79,51.27 99.44,50.92 98.42,50.92 96.4,48.9 96.4,45.91 93.71,43.22 93.71,41.73 81.02,29.04 66.63,29.04 66.32,29.35 v2(66.32,30.02)
  BOTTOM w0.089: v2(100.23,51.27) 100.35,51.27 100.86,51.78 102.87,51.78 103.03,51.94 103.54,51.94 103.66,52.06 CPU1.BA29 ; DM1.224 65.21,29.73 65.37,29.58 65.89,29.58 v2(66.32,30.02)
M_A_DQ55: length 52.4
  L3 w0.127: v2(99.29,51.38) 99.06,51.15 98.34,51.15 96.14,48.95 96.14,45.96 93.49,43.31 93.49,42.02 80.87,29.4 68.84,29.4 v2(67.75,30.02)
  BOTTOM w0.089: CPU1.BB29 103.07,52.24 102.78,51.96 v1(100.48,51.96) 100.26,51.96 99.88,51.73 v2(99.29,51.38) ; v2(67.75,30.02) 68.28,29.48 DM1.225
M_A_DQ56: length 59.4
  TOP w0.089: v2(101.24,50.04) 101.24,50.2 v1(101.6,50.56)
  L3 w0.127: v2(69.91,26.26) 70.35,25.82 70.89,25.82 71.25,26.17 79.17,26.17 80.04,27.04 82.09,27.04 86.39,31.34 86.57,31.34 87.08,30.83 87.26,30.83 87.44,31.01 87.44,31.19 86.93,31.7 86.93,31.88 87.11,32.06 87.29,32.06 87.8,31.55 87.98,31.55 88.16,31.73 88.16,31.91 87.65,32.42 87.65,32.6 87.83,32.78 88.01,32.78 88.52,32.27 88.7,32.27 88.88,32.45 88.88,32.63 88.37,33.14 88.37,33.32 88.55,33.5 88.73,33.5 89.24,32.99 89.42,32.99 89.6,33.17 89.6,33.35 89.09,33.86 89.09,34.04 89.34,34.29 90.41,34.29 95.78,39.65 95.78,40.97 97.69,42.88 97.69,48.63 98.45,49.39 100.27,49.39 100.29,49.41 100.61,49.41 v2(101.24,50.04)
  BOTTOM w0.089: DM1.237 71.1,26.48 70.89,26.7 70.34,26.7 v2(69.91,26.26) ; CPU1.AY27 104.3,50.99 104.23,50.93 104.07,50.86 103.74,50.86 103.7,50.85 103.45,50.78 103.37,50.77 103.33,50.75 102.86,50.75 102.57,50.46 101.65,50.46 v2(101.24,50.04)
M_A_DQ57: length 59.6
  TOP w0.089: v2(68.48,26.26) v1(68.48,26.82)
  L3 w0.127: v2(68.48,26.26) 69.47,25.27 74.17,25.27 74.72,25.82 79.34,25.82 80.21,26.69 82.24,26.69 84.98,29.43 85.16,29.43 85.55,29.04 85.73,29.04 85.91,29.22 85.91,29.4 85.52,29.79 85.52,29.97 85.81,30.26 87.38,30.26 91.01,33.89 91.01,34.39 97.91,41.28 97.91,48.55 98.53,49.17 100.35,49.17 100.38,49.2 100.72,49.2 100.75,49.17 102.02,49.17 104.61,51.76 v2(104.93,51.76)
  BOTTOM w0.089: v2(104.93,51.76) 104.93,51.71 105.24,51.4 CPU1.AW27 ; v2(68.48,26.26) 68.01,26.73 DM1.236
M_A_DQ58: length 58.6
  TOP w0.089: v2(69.91,23.14) v1(69.91,23.7)
  L3 w0.127: v2(101.67,48.68) 101.67,48.43 101.24,48 100.94,48 99.27,46.33 99.27,40.13 93.17,34.03 93.17,33.57 88.03,28.44 87.65,28.44 84.07,24.86 81.2,24.86 80.27,23.93 80.27,23.11 80.14,22.98 79.89,22.98 79.76,23.11 79.76,23.93 79.63,24.06 79.38,24.06 79.25,23.93 79.25,22.91 79.12,22.79 78.87,22.79 78.74,22.91 78.74,23.93 78.62,24.06 78.26,24.06 76.9,22.69 74.86,22.69 74.74,22.82 74.74,23 74.61,23.13 74.36,23.13 74.23,23 74.23,22.82 74.1,22.69 73.85,22.69 73.72,22.82 73.72,23 73.59,23.13 73.34,23.13 73.21,23 73.21,22.82 73.09,22.69 70.35,22.69 v2(69.91,23.14)
  BOTTOM w0.089: DM1.249 71.13,23.48 71.04,23.58 70.34,23.58 v2(69.91,23.14) ; CPU1.AY25 104.23,49.61 104.15,49.57 104.15,49.57 103.81,49.57 103.2,49.38 102.73,48.91 102,48.91 101.78,48.68 v2(101.67,48.68)
M_A_DQ59: length 59.3
  TOP w0.089: v1(104.29,49.7) 104.54,49.45 v2(104.87,49.45)
  L3 w0.127: v2(65.59,23.21) 66.46,22.34 67.43,22.34 67.56,22.21 67.56,21.94 67.69,21.81 67.94,21.81 68.07,21.94 68.07,22.21 68.2,22.34 68.45,22.34 68.58,22.21 68.58,22.04 68.7,21.91 68.96,21.91 69.08,22.04 69.08,22.21 69.21,22.34 80.23,22.34 82.4,24.5 84.22,24.5 87.81,28.08 88.19,28.08 92.26,32.15 93.15,32.15 93.99,32.99 93.99,34.35 99.52,39.87 99.52,45.99 99.93,46.41 100.87,46.41 101.24,46.78 102.2,46.78 v2(104.87,49.45)
  BOTTOM w0.089: v2(65.59,23.21) 65.56,23.23 DM1.250 ; CPU1.AW25 105.24,49.82 v2(104.87,49.45)
M_A_DQ60: length 56.9
  L3 w0.127: v2(99.11,50.05) 98.47,50.05 97.15,48.74 97.15,44.34 94.76,41.95 94.76,40.24 92.09,37.56 91.15,37.56 81.35,27.76 77.09,27.76 76.96,27.64 76.96,27.01 76.83,26.88 76.58,26.88 76.45,27.01 76.45,27.64 76.33,27.76 76.07,27.76 75.94,27.64 75.94,27.01 75.82,26.88 75.56,26.88 75.44,27.01 75.44,27.64 75.31,27.76 74.95,27.76 74.33,27.14 69.2,27.14 68.35,27.99 68.35,28.2 67.92,28.64 66.77,28.64 v2(66.32,28.19)
  BOTTOM w0.089: v2(99.11,50.05) 99.11,50.28 99.49,50.66 v1(99.79,50.66) 100.94,50.66 101.09,50.82 102.41,50.82 102.72,51.12 102.72,51.12 102.73,51.13 103.2,51.13 CPU1.BB27 ; DM1.232 65.87,27.73 v2(66.32,28.19)
M_A_DQ61: length 58.3
  TOP w0.089: v1(100.35,50.61) 100.6,50.37 v2(100.6,50.07)
  L3 w0.127: v2(67.74,28.19) 67.74,27.06 68.07,26.73 75.16,26.73 75.36,26.53 77.4,26.53 77.52,26.65 77.52,27.17 77.65,27.3 77.9,27.3 78.03,27.17 78.03,26.65 78.16,26.53 78.82,26.53 79.71,27.41 81.5,27.41 81.55,27.41 91.34,37.21 92.23,37.21 95.36,40.34 95.36,40.86 97.47,42.96 97.47,48.75 98.35,49.62 100.16,49.62 v2(100.6,50.07)
  BOTTOM w0.089: CPU1.BA27 103.63,51.01 103.31,50.93 102.78,50.93 102.49,50.64 101.17,50.64 v2(100.6,50.07) ; DM1.233 68.26,27.48 67.74,28.01 v2(67.74,28.19)
M_A_DQ62: length 57.9
  TOP w0.089: v2(68.48,23.14) v1(68.48,23.7)
  L3 w0.127: v2(68.48,23.14) 68.93,23.58 71.15,23.58 71.32,23.41 71.32,23.21 71.47,23.05 72.41,23.05 72.62,23.26 72.62,23.46 72.74,23.58 74.7,23.58 74.86,23.42 75.09,23.42 75.3,23.63 75.3,24.29 75.42,24.41 75.78,24.41 75.91,24.28 75.91,23.79 76.03,23.66 76.29,23.66 76.41,23.79 76.41,24.28 76.54,24.41 80.03,24.41 80.84,25.21 83.9,25.21 87.49,28.8 87.88,28.8 92.8,33.73 92.8,34.17 99.05,40.42 99.05,46.42 101.04,48.4 v2(101.06,48.4)
  BOTTOM w0.089: DM1.245 69.83,24.48 v2(68.48,23.14) ; CPU1.BA25 103.58,49.69 103.13,49.55 103.11,49.54 102.66,49.09 101.27,49.09 101.06,48.88 101.06,48.41 v2(101.06,48.4)
M_A_DQ63: length 56.9
  TOP w0.089: v2(67.01,23.22) 66.66,23.56 v1(66.66,23.65)
  L3 w0.127: v2(100.55,48.79) 100.55,48.29 98.8,46.55 98.8,40.68 92.32,34.2 92.32,33.75 87.81,29.23 87.42,29.23 85.08,26.9 84.9,26.9 84.66,27.13 84.48,27.13 84.3,26.96 84.3,26.78 84.47,26.61 84.47,26.43 84.29,26.25 84.11,26.25 83.87,26.49 83.69,26.49 83.51,26.31 83.51,26.13 83.82,25.82 83.82,25.64 83.76,25.57 80.67,25.57 79.87,24.77 75.28,24.77 74.52,24.01 67.8,24.01 v2(67.01,23.22)
  BOTTOM w0.089: DM1.246 65.99,24.23 v2(67.01,23.22) ; v2(100.55,48.79) 101.03,49.27 102.54,49.27 103.15,49.88 CPU1.BB25
M_A_DQS_DN0: length 59.8
  L3 w0.14: v2(109.09,82.77) 109.09,83.64 103.96,88.77 95.64,88.77 95.35,88.49 95.35,88.22 95.21,88.08 94.93,88.08 94.79,88.22 94.79,88.49 94.51,88.77 94.02,88.77 93.73,88.49 93.73,88.22 93.59,88.08 93.31,88.08 93.17,88.22 93.17,88.49 92.88,88.77 92.39,88.77 92.1,88.49 92.1,88.22 91.96,88.08 91.68,88.08 91.54,88.22 91.54,88.49 91.25,88.77 89.87,88.77 89.34,88.25 88.91,88.25 88.38,88.77 87.72,88.77 87.03,88.08 75.34,88.08 72.74,85.49 69.16,85.49 68.55,84.88 v2(68.55,84.65)
  BOTTOM w0.089: v1(109.27,80.33) 109.11,80.33 ; 109.11,80.33 109.11,78.21 109.15,77.86 109.15,77.54 109.18,77.5 109.18,77.24 109.22,77.17 109.22,76.9 109.18,76.79 109.18,76.61 109.24,76.43 109.24,76.25 CPU1.AM70 ; 109.11,80.33 109.11,82 109.07,82.04 109.07,82.75 v2(109.09,82.77) ; v2(68.55,84.65) 68.55,84.82 68.78,85.05 68.78,85.07 69.02,85.31 69.18,85.31 70.34,85.31 70.46,85.2 70.46,85.2 70.67,84.98 DM1.11
M_A_DQS_DN1: length 54.9
  TOP w0.089: v1(107.29,79.24) v2(106.68,79.24)
  L3 w0.14: v2(66.29,79.98) 66.29,80.84 66.55,81.1 67.59,81.1 68.35,80.33 68.35,79.7 68.65,79.39 71.06,79.39 73.23,81.56 74.11,81.56 76.25,83.7 81.79,83.7 82.04,83.95 82.41,84.33 96.44,84.33 98.58,82.19 98.58,80.72 99.92,79.37 105.02,79.37 105.21,79.55 106.08,79.55 106.39,79.24 v2(106.68,79.24)
  BOTTOM w0.089: DM1.32 65,79.73 65.15,79.59 65.9,79.59 v2(66.29,79.98) ; CPU1.AT69 106.7,76.04 106.7,76.42 106.65,76.6 106.65,76.79 106.7,76.97 106.7,76.99 106.7,77.19 106.21,77.68 106.21,78.63 v2(106.68,79.24)
M_A_DQS_DN2: length 48.6
  TOP w0.089: v2(94.97,80.41) 94.54,80.84 v1(93.9,80.84)
  L3 w0.14: v2(69.17,73.52) 69.42,73.77 69.42,74.32 69.83,74.73 72.39,74.73 77.62,79.96 91.86,79.96 92,80.1 92,80.29 92.29,80.58 92.78,80.58 93.07,80.29 93.07,80.1 93.21,79.96 95.13,79.96 95.21,80.04 95.21,80.16 95.15,80.22 95.15,80.22 v2(94.97,80.41)
  BOTTOM w0.089: v2(94.97,80.41) 95.23,80.15 95.23,79.67 95.64,79.26 96.65,79.26 100.71,75.2 100.71,74.36 102.1,72.97 102.83,72.97 102.97,72.82 103.39,72.82 103.54,72.87 103.68,72.87 103.88,72.81 104.06,72.81 CPU1.BA64 ; DM1.53 71.45,74.48 71.28,74.32 69.72,74.32 69.17,73.77 v2(69.17,73.52)
M_A_DQS_DN3: length 48.6
  TOP w0.089: v1(98.73,72.48) 98.45,72.76 v2(98.45,73.01)
  L3 w0.14: v2(98.45,73.01) 98.63,73.19 98.63,73.75 97.17,75.21 92.88,75.21 92.88,75.21 79.03,75.21 74.07,70.25 73.45,70.25 71.75,68.55 67.16,68.55 66.6,69.11 66.6,69.43 v2(66.4,69.63)
  BOTTOM w0.089: DM1.74 65.04,69.23 65.2,69.07 66,69.07 66.4,69.48 v2(66.4,69.63) ; CPU1.AY60 104.54,69.87 103.91,69.87 103.71,69.81 103.51,69.81 103.36,69.85 102.81,69.85 102.46,70.21 101.66,70.21 99.78,72.09 98.76,72.09 98.45,72.41 v2(98.45,73.01)
M_A_DQS_DN4: length 52
  TOP w0.089: v2(69.34,40.96) 69.34,41.19 v1(69.06,41.47)
  L3 w0.14: v2(100.61,58.41) 100.78,58.24 100.78,57.21 100.45,56.88 99.45,56.88 98.79,57.55 96.6,57.55 93.44,54.39 91.59,54.39 91.59,54.39 91.27,54.39 89.48,52.59 85.49,48.6 85.49,46.97 84.94,46.42 84.94,46.01 85.08,45.86 85.08,45.66 84.88,45.47 84.69,45.47 84.5,45.66 84.11,45.66 83.74,45.29 83.74,44.9 83.93,44.71 83.93,44.51 83.73,44.32 83.54,44.32 83.39,44.46 82.98,44.46 81.62,43.1 81.22,43.1 78.58,40.46 72.28,40.46 70.79,41.95 70.06,41.95 69.34,41.23 v2(69.34,40.96)
  BOTTOM w0.089: CPU1.BA38 103.98,58.09 103.88,58.09 103.69,58.14 103.52,58.14 103.39,58.11 102.91,58.11 102.72,57.98 102.69,57.95 101.01,57.95 100.61,58.35 v2(100.61,58.41) ; v2(69.34,40.96) 70.01,41.63 71.08,41.63 71.22,41.48 DM1.177
M_A_DQS_DN5: length 56.8
  TOP w0.089: v2(98.91,54.19) 98.91,54.42 v1(99.19,54.7)
  L3 w0.089: 96.81,53.77 97,53.97 98.52,53.97 98.75,54.19 v2(98.91,54.19)
  L3 w0.14: 96.81,53.77 93.06,50.02 92.49,50.02 89.4,46.93 89.4,44.65 80.18,35.42 79.17,35.42 79.03,35.28 79.03,34.7 78.74,34.41 78.25,34.41 77.96,34.7 77.96,35.28 77.82,35.42 77.54,35.42 77.4,35.28 77.4,34.7 77.12,34.41 76.62,34.41 76.34,34.7 76.34,35.28 76.2,35.42 74.74,35.42 74.22,34.9 74.21,34.9 73.69,34.38 73.03,34.38 71.5,35.91 68.62,35.91 v2(67.92,36.6)
  BOTTOM w0.089: DM1.198 65.03,36.23 65.09,36.17 66.11,36.17 66.32,35.97 66.32,35.53 66.42,35.43 66.57,35.43 66.67,35.53 66.67,35.97 66.87,36.17 67.51,36.17 67.92,36.58 v2(67.92,36.6) ; v2(98.91,54.19) 99.87,55.16 101.49,55.16 101.62,55.03 102.93,55.03 103,55.1 103.11,55.1 103.13,55.12 103.3,55.12 103.3,55.13 103.36,55.13 103.51,55.08 103.71,55.08 103.91,55.14 104.29,55.14 CPU1.AY34
M_A_DQS_DN6: length 54.5
  TOP w0.089: v1(69,31.05) 69.19,30.86 v2(69.19,30.53)
  L3 w0.14: v2(101.67,52.75) 101.38,52.45 101.38,52.21 101.03,51.86 99.15,51.86 98.7,51.41 98.11,51.41 95.91,49.22 95.91,46.05 93.27,43.4 93.27,42.34 80.71,29.79 79.79,29.79 79.5,30.07 79.5,30.37 79.36,30.51 79.08,30.51 78.94,30.37 78.94,30.07 78.65,29.79 78.16,29.79 77.87,30.07 77.87,30.37 77.73,30.51 77.45,30.51 77.31,30.37 77.31,30.07 77.02,29.79 76.35,29.79 75.94,30.2 75.22,30.2 74.81,29.79 69.76,29.79 69.19,30.35 v2(69.19,30.53)
  BOTTOM w0.089: CPU1.BA30 104.06,52.7 103.88,52.7 103.68,52.63 103.54,52.63 103.39,52.68 102.99,52.68 102.77,52.46 102.64,52.34 101.84,52.34 101.67,52.5 v2(101.67,52.75) ; v2(69.19,30.53) 69.48,30.81 69.48,30.91 69.71,31.15 71.14,31.15 71.31,30.98 DM1.219
M_A_DQS_DN7: length 58.3
  L3 w0.14: v2(66.35,26.26) 66.35,25.28 67.23,24.4 74.36,24.4 75.14,25.18 79.72,25.18 80.52,25.98 82.43,25.98 84.23,27.77 85.37,27.77 87.22,29.62 87.65,29.62 91.93,33.91 91.93,34.36 98.5,40.93 98.5,47.04 99.51,48.05 v2(99.51,48.71)
  BOTTOM w0.089: CPU1.AY26 104.63,50.16 103.91,50.16 103.71,50.1 103.51,50.1 103.36,50.15 103.12,50.15 102.43,49.46 99.97,49.46 ; 99.97,49.46 99.63,49.46 99.37,49.19 99.37,48.85 v2(99.51,48.71) ; 99.97,49.46 v1(99.97,49.29) ; v2(66.35,26.26) 66.35,26 65.93,25.58 65.11,25.58 64.96,25.73 DM1.240
M_A_DQS_DP0: length 59.8
  L3 w0.14: v2(108.58,83.23) 108.68,83.23 108.84,83.38 108.84,83.54 103.86,88.52 95.75,88.52 95.61,88.38 95.61,88.12 95.32,87.83 94.83,87.83 94.54,88.12 94.54,88.38 94.4,88.52 94.12,88.52 93.98,88.38 93.98,88.12 93.69,87.83 93.2,87.83 92.91,88.12 92.91,88.38 92.77,88.52 92.49,88.52 92.36,88.38 92.36,88.12 92.07,87.83 91.58,87.83 91.29,88.12 91.29,88.38 91.15,88.52 89.98,88.52 89.45,87.99 88.81,87.99 88.28,88.52 87.82,88.52 87.13,87.83 75.44,87.83 72.84,85.23 69.27,85.23 69.06,85.02 69.06,84.8 v2(69.21,84.65)
  BOTTOM w0.089: v2(69.21,84.65) 69.1,84.65 68.97,84.78 68.97,84.99 69.1,85.12 70.26,85.12 70.38,85.01 70.38,85.01 70.59,84.79 71.1,84.79 71.41,84.48 DM1.13 ; 108.92,81.58 108.92,78.2 108.94,78.02 108.96,77.84 108.96,77.46 109.01,77.41 109.01,77.2 109.04,77.13 109.04,76.93 109.01,76.82 109.01,76.59 109.06,76.4 109.06,76.05 109.45,75.55 CPU1.AM69 ; 108.92,81.58 v1(108.74,81.58) ; 108.92,81.58 108.92,81.92 108.88,81.96 108.88,82.38 108.59,82.67 108.59,83.22 v2(108.58,83.23)
M_A_DQS_DP1: length 54.8
  TOP w0.089: v1(66.98,80.56) v2(66.98,80)
  L3 w0.14: v2(66.98,80) 66.91,80 66.74,80.16 66.55,80.36 66.55,80.74 66.65,80.84 67.48,80.84 68.1,80.23 68.1,79.59 68.55,79.14 71.17,79.14 73.34,81.31 74.22,81.31 76.36,83.45 81.89,83.45 82.29,83.84 82.29,83.85 82.52,84.07 96.33,84.07 98.32,82.08 98.32,80.61 99.82,79.11 105.13,79.11 105.31,79.3 105.97,79.3 106.29,78.99 106.35,78.99 106.35,78.98 v2(106.73,78.6)
  BOTTOM w0.089: CPU1.AT70 106.88,76.26 106.88,76.44 106.83,76.63 106.83,76.77 106.86,76.91 106.87,76.94 106.88,76.96 106.88,77.28 106.4,77.76 106.4,78.41 106.49,78.5 106.63,78.5 v2(106.73,78.6) ; v2(66.98,80) 67.01,80 67.14,79.87 67.14,79.66 67.01,79.53 66.27,79.53 66.14,79.4 65.23,79.4 65.07,79.23 DM1.34
M_A_DQS_DP2: length 47.9
  TOP w0.089: v2(95.6,80.41) 95.6,80.31 v1(96.01,79.9)
  L3 w0.14: v2(69.88,73.52) 69.67,73.73 69.67,74.21 69.94,74.48 72.49,74.48 77.72,79.7 91.97,79.7 92.26,79.99 92.26,80.19 92.4,80.33 92.67,80.33 92.81,80.19 92.81,79.99 93.1,79.7 95.23,79.7 95.46,79.94 95.46,80.26 95.48,80.28 95.48,80.28 v2(95.6,80.41)
  BOTTOM w0.089: v2(95.6,80.41) 95.42,80.22 95.42,79.75 95.72,79.45 96.73,79.45 100.9,75.28 100.9,74.44 102.18,73.16 102.9,73.16 103.06,73 103.36,73 103.51,73.05 103.71,73.05 103.91,72.99 104.54,72.99 CPU1.AY64 ; DM1.55 71.47,73.98 71.33,74.13 69.8,74.13 69.69,74.03 69.69,73.62 69.8,73.52 v2(69.88,73.52)
M_A_DQS_DP3: length 48.6
  TOP w0.089: v2(99.08,73.05) v1(99.08,73.7)
  L3 w0.14: v2(67.11,69.63) 66.99,69.51 66.99,69.08 67.27,68.8 71.64,68.8 73.35,70.51 73.97,70.51 78.92,75.46 92.98,75.46 92.98,75.46 97.28,75.46 98.88,73.86 98.88,73.25 v2(99.08,73.05)
  BOTTOM w0.089: v2(99.08,73.05) 98.66,72.63 98.66,72.46 98.84,72.28 99.86,72.28 101.74,70.4 102.54,70.4 102.91,70.03 103.39,70.03 103.54,69.98 103.68,69.98 103.88,70.05 104.06,70.05 CPU1.BA60 ; DM1.76 65.04,68.73 65.19,68.88 66.08,68.88 66.38,69.19 66.98,69.19 67.11,69.32 v2(67.11,69.63)
M_A_DQS_DP4: length 51.9
  TOP w0.089: v2(70.03,40.96) 70.03,41.14 v1(70.33,41.44)
  L3 w0.14: v2(101.24,58.44) 101.03,58.23 101.03,57.11 100.55,56.63 99.35,56.63 98.68,57.29 96.71,57.29 93.54,54.13 91.48,54.13 91.48,54.13 91.38,54.13 89.73,52.48 85.74,48.5 85.74,46.86 85.19,46.31 85.19,46.11 85.34,45.97 85.34,45.56 84.99,45.21 84.58,45.21 84.39,45.4 84.21,45.4 84,45.19 84,45.01 84.19,44.82 84.19,44.41 83.84,44.06 83.43,44.06 83.29,44.21 83.09,44.21 81.73,42.85 81.32,42.85 78.68,40.21 72.18,40.21 70.69,41.7 70.17,41.7 69.79,41.32 69.79,41.06 69.89,40.96 v2(70.03,40.96)
  BOTTOM w0.089: CPU1.AY38 104.31,58.27 103.91,58.27 103.71,58.32 103.5,58.32 103.37,58.28 102.81,58.28 102.64,58.17 102.61,58.14 101.43,58.14 101.24,58.33 v2(101.24,58.44) ; DM1.179 72.06,40.98 71.46,40.98 71,41.44 70.09,41.44 69.82,41.18 69.82,41.06 69.93,40.96 v2(70.03,40.96)
M_A_DQS_DP5: length 57
  TOP w0.089: v1(97.84,54.02) 97.92,54.02 v2(98.27,54.37)
  L3 w0.089: 96.63,53.95 96.71,54.03 96.8,54.03 96.92,54.16 98.19,54.16 98.27,54.24 v2(98.27,54.37)
  L3 w0.14: v2(68.64,36.6) 68.64,36.29 68.76,36.16 71.6,36.16 73.13,34.63 73.59,34.63 74.11,35.15 74.11,35.15 74.63,35.68 76.3,35.68 76.59,35.39 76.59,34.81 76.73,34.67 77.01,34.67 77.15,34.81 77.15,35.39 77.44,35.68 77.93,35.68 78.22,35.39 78.22,34.81 78.36,34.67 78.64,34.67 78.78,34.81 78.78,35.39 79.06,35.68 80.07,35.68 89.15,44.75 89.15,47.04 92.38,50.28 92.95,50.28 96.63,53.95
  BOTTOM w0.089: v2(68.64,36.6) 68.67,36.57 68.67,36.3 68.54,36.17 67.79,36.17 67.59,35.98 66.95,35.98 66.86,35.89 66.86,35.45 66.65,35.24 66.34,35.24 66.12,35.45 66.12,35.89 66.04,35.98 65.27,35.98 65.02,35.73 DM1.200 ; CPU1.BA34 104.06,55.32 103.88,55.32 103.68,55.26 103.54,55.26 103.39,55.31 103.02,55.31 103,55.29 102.92,55.29 102.85,55.22 101.69,55.22 101.57,55.35 99.79,55.35 99.25,54.8 98.26,54.8 98.13,54.68 98.13,54.5 98.26,54.37 v2(98.27,54.37)
M_A_DQS_DP6: length 54.6
  TOP w0.089: v1(70.22,31.06) 69.91,30.74 v2(69.91,30.53)
  L3 w0.14: v2(101.04,52.75) 101.13,52.66 101.13,52.32 100.92,52.11 99.04,52.11 98.6,51.67 98.59,51.67 98.59,51.67 98.01,51.67 95.66,49.32 95.66,46.15 93.01,43.51 93.01,42.45 80.6,30.04 79.89,30.04 79.75,30.18 79.75,30.47 79.46,30.76 78.97,30.76 78.68,30.47 78.68,30.18 78.54,30.04 78.27,30.04 78.13,30.18 78.13,30.47 77.84,30.76 77.35,30.76 77.06,30.47 77.06,30.18 76.92,30.04 76.46,30.04 76.05,30.45 75.11,30.45 74.7,30.04 70,30.04 69.83,30.21 69.83,30.46 v2(69.91,30.53)
  BOTTOM w0.089: v2(101.04,52.75) 101.04,52.72 101.07,52.69 101.07,52.69 101.61,52.15 102.72,52.15 102.9,52.33 103.08,52.5 103.36,52.5 103.51,52.46 103.71,52.46 103.91,52.52 104.29,52.52 104.45,52.67 CPU1.AY30 ; v2(69.91,30.53) 69.79,30.53 69.67,30.66 69.67,30.83 69.79,30.96 71.06,30.96 71.54,30.49 72.35,30.49 DM1.221
M_A_DQS_DP7: length 58.7
  TOP w0.089: v1(98.35,48.99) 98.57,48.99 v2(98.87,48.69)
  L3 w0.14: v2(98.87,48.69) 99.2,48.36 99.2,48.1 98.25,47.14 98.25,41.03 91.68,34.47 91.68,34.01 87.54,29.87 87.11,29.87 85.27,28.03 84.13,28.03 82.33,26.23 80.41,26.23 79.61,25.43 75.03,25.43 74.25,24.65 67.34,24.65 66.6,25.39 66.6,25.68 67.06,26.14 v2(67.06,26.26)
  BOTTOM w0.089: v2(67.06,26.26) 67.06,25.95 66.94,25.83 66.45,25.83 66.01,25.39 65.12,25.39 64.96,25.23 DM1.242 ; v2(98.87,48.69) 99.18,48.99 99.18,49.27 99.55,49.65 102.35,49.65 103.03,50.33 103.39,50.33 103.54,50.28 103.68,50.28 103.88,50.34 104.06,50.34 CPU1.BA26
M_A_PARITY: length 49.2
  TOP w0.152: v1(73.83,50.46) 73.69,50.61 v2(72.8,50.61)
  L3 w0.089: v2(107.36,65.17) 107.36,65.32 107.12,65.57 106.2,65.57 106.15,65.52 105.65,65.52 105.64,65.5 105.62,65.5 104.97,64.86 104.78,64.86 104.26,64.34 104.26,64.34 103.29,63.37 102.95,63.37 102.77,63.2 102.77,62.86 102.53,62.62 102.21,62.62 101.99,62.84 101.73,62.84 101.69,62.81 98.02,62.81 97.76,62.55
  L3 w0.203: v2(72.8,50.61) 72.84,50.64 73.9,50.64 74.16,50.91 75.05,50.91 75.26,51.11 76.21,51.11 77.23,52.14 77.44,52.14 77.44,52.14 77.5,52.14 81.22,55.86 82.29,55.86 88.21,61.77 94.16,61.77 94.85,62.45 97.67,62.45 97.76,62.55
  BOTTOM w0.152: v2(72.8,50.61) 72.8,50.62 72.93,50.75 74.96,50.75 75.07,50.86 75.07,51.86 74.95,51.98 DM1.143 ; CPU1.AT52 107.16,65.57 107.36,65.37 v2(107.36,65.17)
M_B_A0: length 67.1
  TOP w0.152: v1(51.9,51.66) v2(52.49,51.66)
  L6 w0.165: v2(52.49,51.66) 51.96,52.19 51.43,52.19 51.23,51.99 51.23,50.84 51.03,50.65 50.52,50.65 50.32,50.85 50.32,52.77 50.52,52.98 53.29,52.98 53.55,53.24 65.54,53.24 66.12,53.82 69.01,53.82 69.18,53.99 71.88,53.99 73.07,55.19 74.12,55.19 75.16,56.23 77.28,56.23 80.11,59.06 80.81,59.06 84.19,62.44 92.67,62.44 92.78,62.55 95.24,62.55 95.93,63.24 v2(95.96,63.24)
  BOTTOM w0.089: CPU1.BA46 103.7,62.35 103.7,62.35 103.37,62.43 102.15,62.43 101.56,63.02 97.74,63.02 97.29,62.56 96.85,62.56
  BOTTOM w0.152: DM2.144 52.32,51.94 52.49,51.76 v2(52.49,51.66) ; 96.85,62.56 96.16,62.56 95.96,62.76 v2(95.96,63.24)
M_B_A1: length 68.2
  TOP w0.152: v1(57.17,53.74) v2(57.17,54.3)
  L6 w0.165: v2(57.17,54.3) 57.29,54.18 59.26,54.18 59.46,54.37 59.46,55.12 59.96,55.62 60.25,55.62 60.86,55 62.4,55 62.56,54.84 62.56,54.39 62.73,54.22 63.06,54.22 63.22,54.39 63.22,54.84 63.39,55 63.72,55 63.88,54.84 63.88,54.39 64.05,54.22 64.38,54.22 64.54,54.39 64.54,54.84 64.71,55 64.9,55 65.14,54.76 65.74,54.76 65.74,54.76 68.62,54.76 68.81,54.95 71.51,54.95 73.9,57.35 74.79,57.35 74.99,57.54 75.22,57.54 75.54,57.23 75.77,57.23 76.01,57.46 76.01,57.69 75.69,58.01 75.69,58.24 76.03,58.58 76.29,58.58 76.46,58.41 76.46,58.07 76.65,57.88 76.93,57.88 77.12,58.07 77.12,58.41 77.28,58.58 78.29,58.58 78.89,59.18 78.89,59.8 80.2,61.11 80.2,61.41 80.4,61.61 80.7,61.61 81.02,61.93 81.02,62.19 82.22,63.38 82.61,63.38 82.92,63.69 83.27,63.69 83.58,63.38 86.63,63.38 86.79,63.55 86.79,63.94 86.96,64.1 87.29,64.1 87.45,63.94 87.45,63.55 87.62,63.38 87.95,63.38 88.11,63.55 88.11,63.94 88.28,64.1 88.61,64.1 88.77,63.94 88.77,63.55 88.94,63.38 89.27,63.38 89.43,63.55 89.43,63.94 89.6,64.1 89.93,64.1 90.09,63.94 90.09,63.55 90.26,63.38 90.59,63.38 90.75,63.55 90.75,63.94 90.92,64.1 91.25,64.1 91.41,63.94 91.41,63.55 91.58,63.38 91.91,63.38 92.07,63.55 92.07,63.94 92.24,64.1 92.57,64.1 92.73,63.94 92.73,63.55 92.9,63.38 93.23,63.38 93.39,63.55 93.39,63.94 93.56,64.1 93.89,64.1 94.06,63.94 94.06,63.55 94.22,63.38 94.45,63.38 95.07,64 95.83,64 v2(96.59,63.24)
  BOTTOM w0.089: 98.17,63.26 101.57,63.26 102.22,62.61 103.39,62.61 103.58,62.56 103.99,62.56 CPU1.AY46
  BOTTOM w0.152: 98.17,63.26 97.71,63.72 96.9,63.72 96.59,63.42 v2(96.59,63.24) ; DM2.133 57.56,54.69 v2(57.17,54.3)
M_B_A2: length 67.8
  TOP w0.152: v1(53.2,54.5) v2(53.2,53.92)
  L6 w0.165: v2(53.2,53.92) 52.74,53.46 51.64,53.46 51.51,53.59 51.51,54.25 51.9,54.64 53.92,54.64 54.64,55.35 58.36,55.35 59.79,56.78 61.08,56.78 61.92,55.94 64.02,55.94 64.28,56.2 65.01,56.2 65.01,56.21 68.6,56.21 68.91,55.89 71.12,55.89 73.51,58.29 74.4,58.29 76.77,60.65 77.01,60.65 77.35,60.31 77.59,60.31 77.82,60.54 77.82,60.78 77.47,61.12 77.47,61.36 77.7,61.58 78.99,61.58 79.26,61.86 79.26,62.5 80.07,63.31 80.82,63.31 82.26,64.76 82.99,64.76 83.28,65.05 94.51,65.05 94.94,64.62 95.74,64.62 v2(96.16,65.04)
  BOTTOM w0.089: CPU1.AY47 104.46,63.2 104.03,63.2 103.71,63.27 103.5,63.27 103.37,63.24 102.94,63.24 102.55,63.63 98.77,63.63 98.22,64.18 96.72,64.18 96.61,64.29
  BOTTOM w0.152: DM2.132 52.2,54.94 52.2,54.92 v2(53.2,53.92) ; 96.61,64.29 96.16,64.74 v2(96.16,65.04)
M_B_A3: length 67.6
  TOP w0.152: v1(55.9,53.56) v2(55.9,54.12)
  L6 w0.165: v2(55.9,54.12) 56.32,53.71 59.81,53.71 59.98,53.87 59.98,54.56 60.17,54.75 60.44,54.75 60.64,54.56 60.64,53.87 60.8,53.71 61.13,53.71 61.3,53.87 61.3,54.36 61.46,54.53 61.79,54.53 61.96,54.36 61.96,53.87 62.12,53.71 65.34,53.71 65.93,54.29 68.82,54.29 69,54.47 71.69,54.47 73.93,56.7 77.08,56.7 79.54,59.16 79.54,59.78 80.76,61.01 81,61.01 81.26,60.75 81.53,60.75 81.73,60.94 81.73,61.21 81.47,61.47 81.47,61.71 81.7,61.94 82.09,61.94 82.27,61.76 82.83,61.76 83.08,62.02 83.08,62.7 83.29,62.91 92.14,62.91 92.26,62.8 94.23,62.8 94.66,63.24 v2(95.32,63.24)
  BOTTOM w0.089: 101.08,62.78 101.55,62.78 102.07,62.26 103.2,62.26 CPU1.BB46
  BOTTOM w0.152: DM2.131 56.56,55.19 55.9,54.53 v2(55.9,54.12) ; 101.08,62.78 98.35,62.78 96.26,60.7 94.99,60.7 94.77,60.93 94.77,61.42 94.92,61.57 95.98,61.57 96.14,61.72 96.14,62.03 95.98,62.18 94.92,62.18 94.77,62.33 94.77,62.68 v2(95.32,63.24)
M_B_A4: length 67.4
  TOP w0.152: v1(52.65,56.3) 52.9,56.06 v2(52.9,55.79)
  L6 w0.165: v2(95.53,65.04) 94.75,65.82 94,65.82 93.71,65.52 93.34,65.52 93.05,65.82 92.68,65.82 92.39,65.52 92.02,65.52 91.73,65.82 91.36,65.82 91.07,65.52 90.7,65.52 90.41,65.82 90.04,65.82 89.75,65.52 89.38,65.52 89.09,65.82 88.72,65.82 88.43,65.52 88.06,65.52 87.77,65.82 87.4,65.82 87.11,65.52 86.74,65.52 86.45,65.82 86.08,65.82 85.79,65.52 85.42,65.52 85.13,65.82 84.76,65.82 84.47,65.52 84.1,65.52 83.81,65.82 83.39,65.82 82.8,65.23 81.98,65.23 80.54,63.78 79.88,63.78 78.19,62.09 77.55,62.09 74.21,58.76 73.32,58.76 71.43,56.86 69.14,56.86 68.95,56.68 64.82,56.68 64.81,56.67 63.39,56.67 62.93,57.13 62.55,57.13 62.12,56.7 61.83,56.7 60.95,57.57 59.92,57.57 58.17,55.82 54.44,55.82 53.73,55.11 51.46,55.11 51.26,55.31 51.26,55.95 51.46,56.15 52.18,56.15 52.53,55.79 v2(52.9,55.79)
  BOTTOM w0.089: CPU1.BA47 103.99,63.02 103.69,63.1 103.53,63.1 103.4,63.06 102.87,63.06 102.47,63.45 98.66,63.45 98.17,63.95 96.19,63.95
  BOTTOM w0.152: v2(52.9,55.79) 52.76,55.94 DM2.128 ; 96.19,63.95 95.83,63.95 95.53,64.25 v2(95.53,65.04)
M_B_A5: length 68.2
  L6 w0.165: v2(96.82,65.04) 97.38,64.48 97.38,64.08 97.18,63.87 96.59,63.87 96.11,64.36 94.53,64.36 94.31,64.58 86.14,64.58 85.97,64.41 85.97,64.04 85.81,63.87 85.48,63.87 85.31,64.04 85.31,64.41 85.15,64.58 84.82,64.58 84.65,64.41 84.65,64.04 84.49,63.87 84.16,63.87 83.99,64.04 83.99,64.41 83.83,64.58 83.48,64.58 83.19,64.29 82.46,64.29 81.01,62.84 80.3,62.84 79.73,62.27 79.73,61.31 79.51,61.09 78.9,61.09 78.64,60.82 78.64,60.21 78.44,60.02 77.98,60.02 77.7,59.75 77.7,59.28 77.47,59.05 75.83,59.05 74.6,57.82 73.71,57.82 71.31,55.42 68.62,55.42 68.43,55.23 65.94,55.23 65.94,55.23 65.33,55.23 65.09,55.47 61.43,55.47 61.16,55.75 61.16,56.04 60.88,56.31 59.99,56.31 58.5,54.83 54.79,54.83 54.56,54.6 v2(54.56,54.09)
  BOTTOM w0.089: v2(96.82,65.04) 96.82,65.4 97,65.57 99.03,65.57 99.41,65.19 99.41,64.58 v1(99.59,64.41) 99.77,64.23 102.74,64.23 103.02,63.95 103.46,63.95 104.31,63.74 CPU1.AY48
  BOTTOM w0.152: DM2.126 52.64,56.44 52.65,56.44 53.64,56.44 54.41,55.67 54.41,54.24 v2(54.56,54.09)
M_B_A6: length 66.4
  TOP w0.152: v1(55.59,55.92) v2(55.59,56.48)
  L6 w0.165: v2(55.59,56.48) 55.78,56.29 57.97,56.29 59.72,58.04 61.15,58.04 61.59,57.6 63.13,57.6 63.59,57.14 64.62,57.14 65.25,57.77 66.5,57.77 67.09,57.19 68.8,57.19 69.53,57.92 69.79,57.92 69.96,57.75 69.96,57.51 70.13,57.34 70.39,57.34 70.62,57.57 70.85,57.57 71.03,57.39 71.27,57.39 71.5,57.63 71.5,57.86 71.32,58.04 71.32,58.27 71.55,58.51 71.78,58.51 71.97,58.33 72.2,58.33 72.43,58.56 72.43,58.79 72.25,58.98 72.25,59.21 72.62,59.58 73.31,59.58 73.71,59.98 73.95,59.98 74.23,59.7 74.46,59.7 74.7,59.93 74.7,60.17 74.41,60.45 74.41,60.68 74.65,60.92 74.88,60.92 75.16,60.63 75.4,60.63 75.63,60.87 75.63,61.1 75.35,61.38 75.35,61.62 76.57,62.84 77.15,62.84 77.39,62.6 77.96,62.6 79.61,64.25 80.16,64.25 82.19,66.29 82.59,66.29 82.85,66.54 83.25,66.54 83.51,66.29 92.28,66.29 92.44,66.45 92.44,66.86 92.61,67.02 92.94,67.02 93.1,66.86 93.1,66.45 93.27,66.29 94.92,66.29 95.68,65.52 97.61,65.52 v2(98.09,65.04)
  BOTTOM w0.089: CPU1.BA48 103.58,63.73 103.39,63.77 102.94,63.77 102.7,64.02 99.47,64.02 99.24,64.25 99.24,65.12 98.96,65.4 98.35,65.4 98.12,65.17 98.12,65.07 v2(98.09,65.04)
  BOTTOM w0.152: DM2.127 56.3,56.19 55.94,55.83 55.72,55.83 55.59,55.96 v2(55.59,56.48)
M_B_A7: length 69.1
  TOP w0.152: v2(52.39,57.47) 51.96,57.47 v1(51.84,57.34)
  L6 w0.102: v2(108.73,64.19) 108.22,63.68 104.81,63.68 104.6,63.9
  L6 w0.165: v2(52.39,57.47) 52.39,56.61 52.61,56.38 52.84,56.38 53.22,56.76 54.3,56.76 54.53,56.99 56,56.99 56.28,57.27 57.49,57.27 59.99,59.77 60.43,59.77 60.98,59.22 65.36,59.22 65.4,59.26 65.41,59.26 65.55,59.41 70.74,59.41 71.85,60.52 72.92,60.52 73.09,60.68 73.09,60.92 72.69,61.32 72.69,61.55 72.92,61.79 73.15,61.79 73.55,61.39 73.79,61.39 76.19,63.78 77.81,63.78 79.22,65.19 79.77,65.19 80.4,65.83 80.4,66.06 80.4,66.2 80.68,66.48 81.05,66.48 81.34,66.76 81.34,67 81.34,67.13 81.7,67.49 83.26,67.49 83.74,67.97 93.76,67.97 94.47,67.26 94.59,67.26 94.59,67.26 95.16,67.26 95.65,66.77 100.13,66.77 102,64.89 103.6,64.89 104.6,63.9
  BOTTOM w0.152: v2(52.39,57.47) 52.35,57.44 DM2.122 ; CPU1.AP48 108.73,64.12 v2(108.73,64.19)
M_B_A8: length 64.7
  TOP w0.152: v1(57.21,56.18) v2(57.21,56.76)
  L6 w0.165: v2(57.21,56.76) 57.66,56.76 59.41,58.51 60.87,58.51 61.11,58.75 61.5,58.75 61.66,58.59 61.66,58.32 61.83,58.16 62.16,58.16 62.32,58.32 62.32,58.59 62.49,58.75 63.92,58.75 64.09,58.59 64.09,57.94 64.25,57.78 64.58,57.78 64.75,57.94 64.75,58.59 64.91,58.75 65.21,58.75 65.73,58.24 67.02,58.24 67.18,58.41 67.18,58.75 67.35,58.92 67.68,58.92 67.84,58.75 67.84,58.41 68.01,58.24 69.19,58.24 69.33,58.39 70.61,58.39 72.27,60.05 73.12,60.05 76.38,63.31 78.01,63.31 79.42,64.72 79.96,64.72 82.26,67.02 83.46,67.02 83.93,67.5 84.42,67.5 84.59,67.33 84.59,66.98 84.75,66.82 85.08,66.82 85.25,66.98 85.25,67.33 85.41,67.5 85.74,67.5 85.91,67.33 85.91,66.98 86.07,66.82 86.4,66.82 86.57,66.98 86.57,67.33 86.73,67.5 87.06,67.5 87.23,67.33 87.23,66.98 87.39,66.82 87.72,66.82 87.89,66.98 87.89,67.33 88.06,67.5 88.39,67.5 88.55,67.33 88.55,66.98 88.72,66.82 89.05,66.82 89.21,66.98 89.21,67.33 89.38,67.5 89.71,67.5 89.87,67.33 89.87,66.98 90.04,66.82 90.37,66.82 90.53,66.98 90.53,67.33 90.7,67.5 91.03,67.5 91.19,67.33 91.19,66.98 91.36,66.82 91.69,66.82 91.85,66.98 91.85,67.33 92.02,67.5 93.57,67.5 94.27,66.79 94.39,66.79 94.39,66.79 94.86,66.79 95.87,65.78 97.97,65.78 v2(98.75,64.99)
  BOTTOM w0.089: CPU1.BB48 102.93,63.5 102.62,63.81 99.2,63.81 98.8,64.2 98.8,64.94 v2(98.75,64.99)
  BOTTOM w0.152: DM2.125 57.29,56.69 v2(57.21,56.76)
M_B_A9: length 65.4
  TOP w0.152: v1(54.96,57.5) v2(54.96,58.06)
  L6 w0.102: v2(108.02,65.12) 107.68,64.77 106.51,64.77 105.98,65.31 102.59,65.31 101.84,66.06 101.8,66.06
  L6 w0.165: 101.8,66.06 99.74,68.11 99.65,68.2 94.86,68.2 94.15,68.91 82.52,68.91 82.04,68.43 81.3,68.43 79.58,66.7 79.27,66.7 78.24,65.67 78.24,65.54 77.42,64.72 75.78,64.72 73.79,62.73 72.02,62.73 71.14,61.85 68.29,61.85 67.66,61.22 66.74,61.22 64.25,61.22 63.81,60.77 62.61,60.77 62.07,60.24 61.29,60.24 60.76,60.77 59.67,60.77 57.13,58.24 55.14,58.24 v2(54.96,58.06)
  BOTTOM w0.152: CPU1.AP50 108.35,64.79 v2(108.02,65.12) ; DM2.121 57.84,57.69 57.75,57.78 55.24,57.78 v2(54.96,58.06)
M_B_A10: length 67.3
  TOP w0.152: v1(53.41,49.42) 53.77,49.06 v2(53.77,48.94)
  L6 w0.102: v2(101.31,62.35) 101.31,61.33 100.99,61 97.28,61 96.65,60.37 96.32,60.37 95.48,59.53 94.62,59.53
  L6 w0.165: 94.62,59.53 93.52,58.44 87.45,58.44 82.09,53.08 80.94,53.08 79.77,51.91 79.77,50.76 79.51,50.5 79.28,50.5 78.92,50.86 78.68,50.86 78.45,50.63 78.45,50.4 78.81,50.03 78.81,49.8 78.58,49.57 78.35,49.57 77.98,49.93 77.75,49.93 77.52,49.7 77.52,49.46 77.88,49.1 77.88,48.87 77.28,48.26 71.83,48.26 71.62,48.48 68.47,48.48 68.14,48.14 66.95,48.14 66.58,47.78 66.21,47.78 65.74,48.25 65.41,48.25 65.08,48.58 64.51,48.58 64.34,48.76 55.79,48.76 55.47,48.44 54.01,48.44 53.77,48.68 v2(53.77,48.94)
  BOTTOM w0.089: CPU1.AW46 104.94,62.07 104.6,61.96 104.18,61.96 104.09,61.91 103.13,61.91 102.98,62.06 102.96,62.07 101.59,62.07 v2(101.31,62.35)
  BOTTOM w0.152: v2(53.77,48.94) 53.92,49.09 53.92,49.55 53.69,49.78 52.8,49.78 52.46,49.44 DM2.146
M_B_A11: length 69.6
  TOP w0.152: v1(53.64,57.04) 53.8,57.19 v2(53.8,57.58)
  L6 w0.102: v2(109.39,64.2) 109,64.59 107.9,64.59 107.9,64.58 106.43,64.58 105.9,65.12 102.51,65.12 102.16,65.47 101.93,65.47
  L6 w0.165: v2(53.8,57.58) 55.93,57.58 56.12,57.77 57.33,57.77 59.8,60.24 60.62,60.24 61.1,59.77 62.92,59.77 63.34,60.19 63.69,60.19 64,59.88 64.35,59.88 64.51,60.04 64.51,60.56 64.68,60.72 65.01,60.72 65.17,60.56 65.17,60.04 65.34,59.88 69.03,59.88 69.19,60.04 69.19,60.46 69.36,60.62 69.69,60.62 69.85,60.46 69.85,60.04 70.02,59.88 70.3,59.88 71.69,61.27 71.69,61.68 71.95,61.94 72.36,61.94 72.68,62.26 73.98,62.26 75.97,64.25 77.62,64.25 78.71,65.35 78.71,65.48 79.47,66.23 79.77,66.23 81.5,67.96 82.24,67.96 82.71,68.44 93.96,68.44 94.66,67.73 95.14,67.73 95.27,67.86 99.54,67.86 101.93,65.47
  BOTTOM w0.152: CPU1.AN48 109.39,64.13 v2(109.39,64.2) ; DM2.120 52.19,57.94 52.19,57.94 53.4,57.94 53.76,57.58 v2(53.8,57.58)
M_B_A12: length 70.2
  TOP w0.152: v1(54.56,59.91) v2(54.56,59.33)
  L6 w0.102: v2(109.38,65.09) 109.74,65.45 109.74,66.3 109.47,66.56 109.18,66.56 108.19,67.56 106.98,67.56 106.7,67.83 105.64,67.83 104.98,67.17 104.93,67.17
  L6 w0.165: 104.93,67.17 102.94,67.17 100.06,70.05 95.42,70.05 94.68,70.79 79.18,70.79 73.11,64.71 64.21,64.71 62.16,62.65 58.89,62.65 56.86,60.62 55.68,60.62 55.21,60.16 54.76,60.16 54.56,59.95 v2(54.56,59.33)
  BOTTOM w0.152: v2(54.56,59.33) 55.7,58.19 DM2.119 ; CPU1.AN50 109.38,65.03 v2(109.38,65.09)
M_B_A13: length 64.6
  TOP w0.152: v1(52.65,45.97) 52.65,46.11 v2(52.34,46.43)
  L6 w0.102: v2(100.63,60.6) 100.61,60.6 100.07,60.06 99.11,60.06 98.6,59.55 96.75,59.55 93.74,56.54
  L6 w0.165: 93.74,56.54 88.29,56.54 77.44,45.69 73.84,45.69 73.51,45.36 64.91,45.36 64.72,45.18 64.72,44.91 64.56,44.75 64.23,44.75 64.06,44.91 64.06,45.55 63.9,45.71 63.57,45.71 63.4,45.55 63.4,44.91 63.24,44.75 62.91,44.75 62.74,44.91 62.74,45.55 62.58,45.71 57.73,45.71 57.1,46.35 54.28,46.35 53.57,45.64 52.55,45.64 52.34,45.85 v2(52.34,46.43)
  BOTTOM w0.089: v2(100.63,60.6) 101.05,61.02 102.65,61.02 102.67,60.99 102.69,60.99 102.83,60.85 102.88,60.78 103.01,60.71 103.4,60.71 103.53,60.74 103.69,60.74 103.99,60.67 CPU1.BA43
  BOTTOM w0.152: v2(52.34,46.43) 52.33,46.44 DM2.158
M_B_A14: length 68.2
  TOP w0.152: v2(56.34,47.54) 56.67,47.54 v1(56.89,47.31)
  L6 w0.102: v2(98.72,60.6) 98.08,59.96 96.55,59.96 95.16,58.57 94.97,58.57
  L6 w0.165: 94.97,58.57 93.89,57.48 87.9,57.48 82.46,52.05 81.81,52.05 81.53,51.78 81.53,51.12 77.05,46.63 74.33,46.63 73.63,47.32 71.1,47.32 70.55,46.77 68.82,46.77 68.35,46.3 65.35,46.3 64.8,46.85 64.8,47.33 64.58,47.55 64.1,47.55 63.83,47.82 63.1,47.82 62.94,47.65 62.94,46.89 62.77,46.73 62.44,46.73 62.28,46.89 62.28,47.65 62.11,47.82 61.78,47.82 61.61,47.65 61.61,46.89 61.45,46.73 61.12,46.73 60.95,46.89 60.95,47.65 60.79,47.82 60.46,47.82 60.29,47.65 60.29,46.89 60.13,46.73 59.8,46.73 59.63,46.89 59.63,47.65 59.47,47.82 59.14,47.82 58.97,47.65 58.97,46.89 58.81,46.73 58.48,46.73 58.31,46.89 58.31,47.65 58.15,47.82 57.81,47.82 57.28,47.29 56.59,47.29 v2(56.34,47.54)
  BOTTOM w0.089: CPU1.AY44 104.18,60.84 104.03,60.84 103.71,60.92 103.5,60.92 103.37,60.88 103.08,60.88 102.81,61.13 102.74,61.2 98.95,61.2 98.72,60.97 v2(98.72,60.6)
  BOTTOM w0.152: DM2.151 57.87,48.19 57.73,48.33 56.82,48.33 56.34,47.84 v2(56.34,47.54)
M_B_A15: length 68
  TOP w0.152: v1(54.2,45.91) v2(54.2,45.36)
  L6 w0.102: v2(105.99,60.7) 103.35,60.7 102.11,59.45 99.34,59.45 98.83,58.94 97.25,58.94 95.78,57.47
  L6 w0.165: v2(54.2,45.36) 53.72,44.87 53.72,44.39 53.97,44.14 58.11,44.14 59.39,42.86 76.6,42.86 88.84,55.1 93.41,55.1 95.78,57.47
  BOTTOM w0.089: v2(105.99,60.7) 105.99,60.39 105.69,60.09 105.37,60.09 105.36,60.1 105.19,60.1 CPU1.AY43
  BOTTOM w0.152: v2(54.2,45.36) 54.13,45.43 54.13,46.12 53.29,46.96 52.86,46.96 52.84,46.94 50.9,46.94 DM2.156
M_B_A16: length 67
  TOP w0.152: v1(55.98,48.91) v2(55.19,48.91)
  L6 w0.102: v2(100.68,62.33) 100.68,61.6 100.26,61.19 97.2,61.19 96.57,60.56 96.24,60.56 95.7,60.02 94.57,60.02
  L6 w0.165: v2(55.19,48.91) 55.51,49.23 64.51,49.23 64.57,49.18 66.18,49.18 66.19,49.18 66.2,49.17 71.59,49.17 72.03,48.73 74.18,48.73 74.35,48.9 74.35,49.18 74.51,49.34 74.85,49.34 75.01,49.18 75.01,48.9 75.18,48.73 76.05,48.73 76.22,48.91 76.22,49.17 75.72,49.67 75.72,49.91 75.95,50.14 76.19,50.14 76.61,49.72 76.84,49.72 77.07,49.96 77.07,50.19 76.86,50.4 76.86,50.67 77.06,50.86 77.33,50.86 77.54,50.66 77.77,50.66 78.12,51.01 78.12,51.95 78.52,52.35 79.54,52.35 80.75,53.55 81.57,53.55 81.74,53.72 81.74,54.8 82.01,55.07 83.42,55.07 87.26,58.91 93.46,58.91 94.57,60.02
  BOTTOM w0.089: v2(100.68,62.33) 101.12,61.88 102.91,61.88 103.06,61.73 103.78,61.73 104.17,61.34 104.72,61.34 105.01,61.05 CPU1.AW44
  BOTTOM w0.152: DM2.152 50.9,47.94 54.22,47.94 v2(55.19,48.91)
M_B_ACT_N: length 68.7
  TOP w0.152: v1(53.52,61.18) v2(53.52,60.62)
  L6 w0.102: 104.09,68.29 105.26,68.29 105.43,68.47 106.96,68.47 107.19,68.24 108.15,68.24 108.32,68.41 109.14,68.41 109.32,68.22 109.51,68.22 109.74,68 109.74,67.37 v2(109.33,66.97)
  L6 w0.165: v2(53.52,60.62) 53.52,61 54.74,62.22 55.83,62.22 58.34,64.73 62.2,64.73 63.63,66.16 72.56,66.16 78.6,72.2 94.8,72.2 95.23,71.77 99.6,71.77 101.5,69.86 102.52,69.86 104.09,68.29
  BOTTOM w0.152: CPU1.AN53 109,66.64 v2(109.33,66.97) ; v2(53.52,60.62) 52.42,59.53 52.25,59.53 52.14,59.43 50.91,59.43 DM2.114
M_B_ALERT_N: length 71.7
  TOP w0.152: v1(52.83,59.53) 52.83,59.34 v2(52.54,59.05)
  L6 w0.089: v2(109.33,60.54) 109.33,60.6 109.88,61.15 109.88,64.26 109.55,64.59 109.27,64.59 108.99,64.86 108.99,65.3 108.72,65.56 106.55,65.56 106.49,65.5 103.05,65.5 102.89,65.65
  L6 w0.165: 102.89,65.65 100.05,68.5 95.23,68.5 94.35,69.38 81.58,69.38 79.38,67.17 79.08,67.17 78.15,66.24 77.64,66.24 77.32,65.93 77.32,65.62 76.89,65.19 75.58,65.19 73.59,63.2 71.82,63.2 70.94,62.32 68.1,62.32 67.46,61.69 66.54,61.69 66.16,61.69 66.16,61.69 64.06,61.69 63.61,61.24 59.47,61.24 56.94,58.71 54.12,58.71 53.85,58.44 52.88,58.44 52.54,58.78 v2(52.54,59.05)
  BOTTOM w0.152: v2(52.54,59.05) 52.43,58.94 DM2.116 ; v2(109.33,60.54) 109,60.87 CPU1.AN43
M_B_BA0: length 66.1
  L6 w0.102: 95.38,60.85 95.78,60.85 95.91,60.98 96.45,60.98 97.05,61.57 98.02,61.57 v2(98.77,62.33)
  L6 w0.165: 95.38,60.85 94.03,60.85 93.03,59.85 86.87,59.85 83.2,56.18 80.85,56.18 77.64,52.96 75.89,52.96 74.94,52.02 74.94,51.42 73.19,49.67 72.42,49.67 71.97,50.12 64.95,50.12 64.9,50.18 50.52,50.18 50.32,49.97 50.32,48.68 50.52,48.48 52.64,48.48 v2(53.1,48.94)
  BOTTOM w0.152: CPU1.BB44 103.15,61.28 102.95,61.28 102.8,61.43 102.72,61.44 99.66,61.44 v1(99.48,61.62) v2(98.77,62.33) ; v2(53.1,48.94) 53.09,48.94 52.58,48.44 DM2.150
M_B_BA1: length 67.3
  TOP w0.152: v2(54.48,48.91) 54.48,49.01 v1(54.84,49.37)
  L6 w0.102: v2(99.41,62.33) 99.69,62.04 99.69,61.51 99.57,61.38 97.12,61.38 96.52,60.78 96.12,60.78 95.87,60.53 94.75,60.53
  L6 w0.165: 94.75,60.53 94.52,60.53 93.37,59.38 87.06,59.38 83.23,55.54 81.05,55.54 80.27,54.76 80.27,54.53 80.52,54.28 80.52,54.05 80.29,53.82 80.06,53.82 79.81,54.06 79.57,54.06 79.34,53.83 79.34,53.6 79.59,53.35 79.59,53.11 79.35,52.88 79.12,52.88 78.87,53.13 78.64,53.13 78,52.49 77.33,52.49 77.17,52.33 77.17,51.54 77,51.38 76.67,51.38 76.51,51.54 76.51,52.33 76.34,52.49 76.08,52.49 75.41,51.82 75.41,51.23 75.1,50.91 75.1,50.1 74.82,49.83 74.01,49.83 73.39,49.2 72.22,49.2 71.78,49.65 64.76,49.65 64.71,49.7 54.68,49.7 54.48,49.5 v2(54.48,48.91)
  BOTTOM w0.089: v2(99.41,62.33) 100.07,61.66 102.83,61.66 102.88,61.65 103.04,61.49 103.41,61.49 103.68,61.4 CPU1.BA44
  BOTTOM w0.152: v2(54.48,48.91) 55.25,49.69 DM2.145
M_B_BG0: length 69.4
  TOP w0.152: v1(56.56,59.96) v2(56.56,59.4)
  L6 w0.102: v2(108.71,66.03) 108.32,66.42 105.62,66.42 105.07,65.87 104.52,65.87
  L6 w0.165: v2(56.56,59.4) 56.84,59.67 57.23,59.67 59.28,61.71 63.4,61.71 65.36,63.67 65.73,63.67 65.9,63.51 65.9,62.79 66.06,62.63 66.39,62.63 66.56,62.79 66.56,63.51 66.72,63.67 67.44,63.67 67.61,63.51 67.61,63.12 67.77,62.96 68.1,62.96 68.27,63.12 68.27,63.51 68.43,63.67 73.4,63.67 76.06,66.34 76.3,66.34 76.42,66.21 76.66,66.21 76.89,66.45 76.89,66.68 76.76,66.81 76.76,67.04 77.05,67.32 77.28,67.32 77.79,66.82 78.02,66.82 78.26,67.05 78.26,67.28 77.75,67.79 77.75,68.02 78.56,68.84 78.79,68.84 79.1,68.53 79.33,68.53 79.56,68.76 79.56,69 79.26,69.3 79.26,69.54 79.57,69.85 80.05,69.85 80.22,69.68 80.22,69.4 80.38,69.23 80.71,69.23 80.88,69.4 80.88,69.68 81.04,69.85 94.54,69.85 95.25,69.14 95.85,69.14 96.19,68.8 100.35,68.8 102.89,66.26 104.13,66.26 104.52,65.87
  BOTTOM w0.152: v2(108.71,66.03) 108.69,66.01 108.69,65.91 CPU1.AP52 ; DM2.115 56.78,59.19 v2(56.56,59.4)
M_B_BG1: length 68.1
  TOP w0.152: v1(55.19,58.84) v2(55.19,59.43)
  L6 w0.102: 104.93,66.84 105.08,66.69 106.09,66.69 106.3,66.9 106.3,67.14 106.54,67.38 106.87,67.38 106.9,67.35 108.13,67.35 109.34,66.13 v2(109.34,65.99)
  L6 w0.165: 104.93,66.84 102.91,66.84 100.06,69.7 95.21,69.7 94.59,70.32 79.38,70.32 73.3,64.24 64.43,64.24 64.28,64.09 64.28,63.86 64.45,63.68 64.45,63.45 64.22,63.22 63.98,63.22 63.81,63.39 63.57,63.39 63.34,63.16 63.34,62.92 63.51,62.75 63.51,62.52 63.28,62.28 63.05,62.28 62.87,62.46 62.64,62.46 62.37,62.18 59.08,62.18 57.04,60.14 55.9,60.14 v2(55.19,59.43)
  BOTTOM w0.152: CPU1.AN52 109.34,65.91 v2(109.34,65.99) ; v2(55.19,59.43) 55.62,59.85 57.86,59.85 58.03,59.69 DM2.113
M_B_CKE0: length 63.6
  TOP w0.152: v1(56.31,62.17) v2(56.31,61.61)
  L6 w0.102: 105.08,67.92 105.16,67.92 105.51,68.27 106.86,68.27 107.08,68.04 108.23,68.04 108.41,68.22 108.94,68.22 v2(109.33,67.83)
  L6 w0.165: 105.08,67.92 104.01,67.92 102.38,69.54 101.46,69.54 99.79,71.21 95.3,71.21 94.79,71.73 78.79,71.73 72.75,65.69 63.82,65.69 62.4,64.26 58.96,64.26 v2(56.31,61.61)
  BOTTOM w0.127: v2(109.33,67.83) 109.33,67.99 CPU1.AN56
  BOTTOM w0.152: v2(56.31,61.61) 56.43,61.61 57.36,60.69 DM2.109
M_B_CKE1: length 65.6
  TOP w0.152: v1(54.91,62.17) v2(54.91,61.61)
  L6 w0.102: 104.77,67.5 105.02,67.5 105.55,68.03 106.82,68.03 107.03,67.81 v2(108.65,67.81)
  L6 w0.165: 104.77,67.5 102.98,67.5 100.17,70.31 95.62,70.31 94.67,71.26 78.99,71.26 72.92,65.19 64.03,65.19 62.63,63.79 59.36,63.79 56.69,61.12 55.4,61.12 v2(54.91,61.61)
  BOTTOM w0.152: CPU1.AP55 v2(108.65,67.81) ; DM2.110 51.86,60.43 52.73,61.31 54.61,61.31 v2(54.91,61.61)
M_B_CLK0: length 69.5
  TOP w0.102: v2(55.93,51.93) 55.93,51.81 v1(55.55,51.43)
  L6 w0.089: 105.31,62.7 105.31,62.71 105.36,62.77 107.51,62.77 108,62.28 108,61.54 v2(108.02,61.51)
  L6 w0.127: 105.31,62.7 104.89,62.28 103.88,62.28 102.64,63.52 98.68,63.52 97.22,62.06 96.45,62.06 95.94,61.55 93.66,61.55 92.99,60.88 86.46,60.88 86.2,60.61 85.8,60.61 85.54,60.88 85.32,60.88 85.16,60.71 85.16,60.54 85.44,60.25 85.44,59.85 85.1,59.52 84.7,59.52 84.29,59.93 84.11,59.93 83.93,59.75 83.93,59.57 84.34,59.16 84.34,58.76 82.88,57.29 80.56,57.29 77.91,54.65 76.09,54.65 75.05,53.62 73.84,53.62 73.24,53.02 73.24,52.84 73.82,52.27 73.82,51.87 73.48,51.53 73.08,51.53 72.51,52.11 72.33,52.11 71.83,51.6 65.18,51.6 64.75,51.17 56.5,51.17 56.14,51.53 56.14,51.71 55.93,51.92 v2(55.93,51.93)
  BOTTOM w0.102: v2(55.93,51.93) 55.93,52.8 56.36,53.23 57.71,53.23 58.16,53.69 DM2.137 ; CPU1.AP45 108.35,61.84 v2(108.02,61.51)
M_B_CLK1: length 68.5
  TOP w0.102: v1(54.28,52.37) 54.28,52.24 v2(53.95,51.91)
  L6 w0.127: v2(108.63,62.36) 108.88,62.6 108.88,62.97 108.66,63.19 104.28,63.19 103.21,64.25 98.58,64.25 96.89,62.56 96.2,62.56 95.68,62.04 92.98,62.04 92.59,61.65 84.72,61.65 82.4,59.33 82.4,59.15 82.74,58.82 82.74,58.42 82.4,58.09 82,58.09 81.67,58.42 81.49,58.42 81.14,58.07 80.24,58.07 77.61,55.44 75.78,55.44 74.73,54.39 73.47,54.39 71.52,52.44 53.92,52.44 53.72,52.24 53.72,52.12 53.93,51.91 v2(53.95,51.91)
  BOTTOM w0.102: CPU1.AP46 108.61,62.83 108.71,62.73 108.71,62.44 v2(108.63,62.36) ; v2(53.95,51.91) 53.87,51.91 53.52,52.26 53.52,52.82 53.13,53.2 52.02,53.2 51.79,53.43 DM2.138
M_B_CLK#0: length 69.5
  TOP w0.102: v1(56.89,51.43) 56.59,51.73 v2(56.59,51.93)
  L6 w0.089: 105.12,62.89 105.18,62.96 107.59,62.96 108.19,62.36 108.19,61.96 v2(108.7,61.45)
  L6 w0.127: 105.12,62.89 104.78,62.55 103.99,62.55 102.75,63.78 98.57,63.78 97.11,62.32 96.34,62.32 95.83,61.81 93.55,61.81 92.88,61.14 86.35,61.14 86.09,60.88 85.91,60.88 85.65,61.14 85.21,61.14 84.89,60.83 84.89,60.42 85.17,60.14 85.17,59.96 84.99,59.78 84.81,59.78 84.4,60.19 84,60.19 83.67,59.86 83.67,59.46 84.07,59.05 84.07,58.87 82.77,57.56 80.45,57.56 77.8,54.92 75.98,54.92 74.94,53.89 73.73,53.89 72.98,53.13 72.98,52.73 73.55,52.16 73.55,51.98 73.37,51.8 73.19,51.8 72.62,52.37 72.22,52.37 71.72,51.87 65.07,51.87 64.64,51.44 56.61,51.44 56.41,51.64 56.41,51.76 v2(56.59,51.93)
  BOTTOM w0.102: CPU1.AN45 108.75,61.92 108.65,61.81 108.65,61.5 v2(108.7,61.45) ; v2(56.59,51.93) 56.16,52.37 56.16,52.7 56.46,53 57.8,53 57.99,53.19 DM2.139
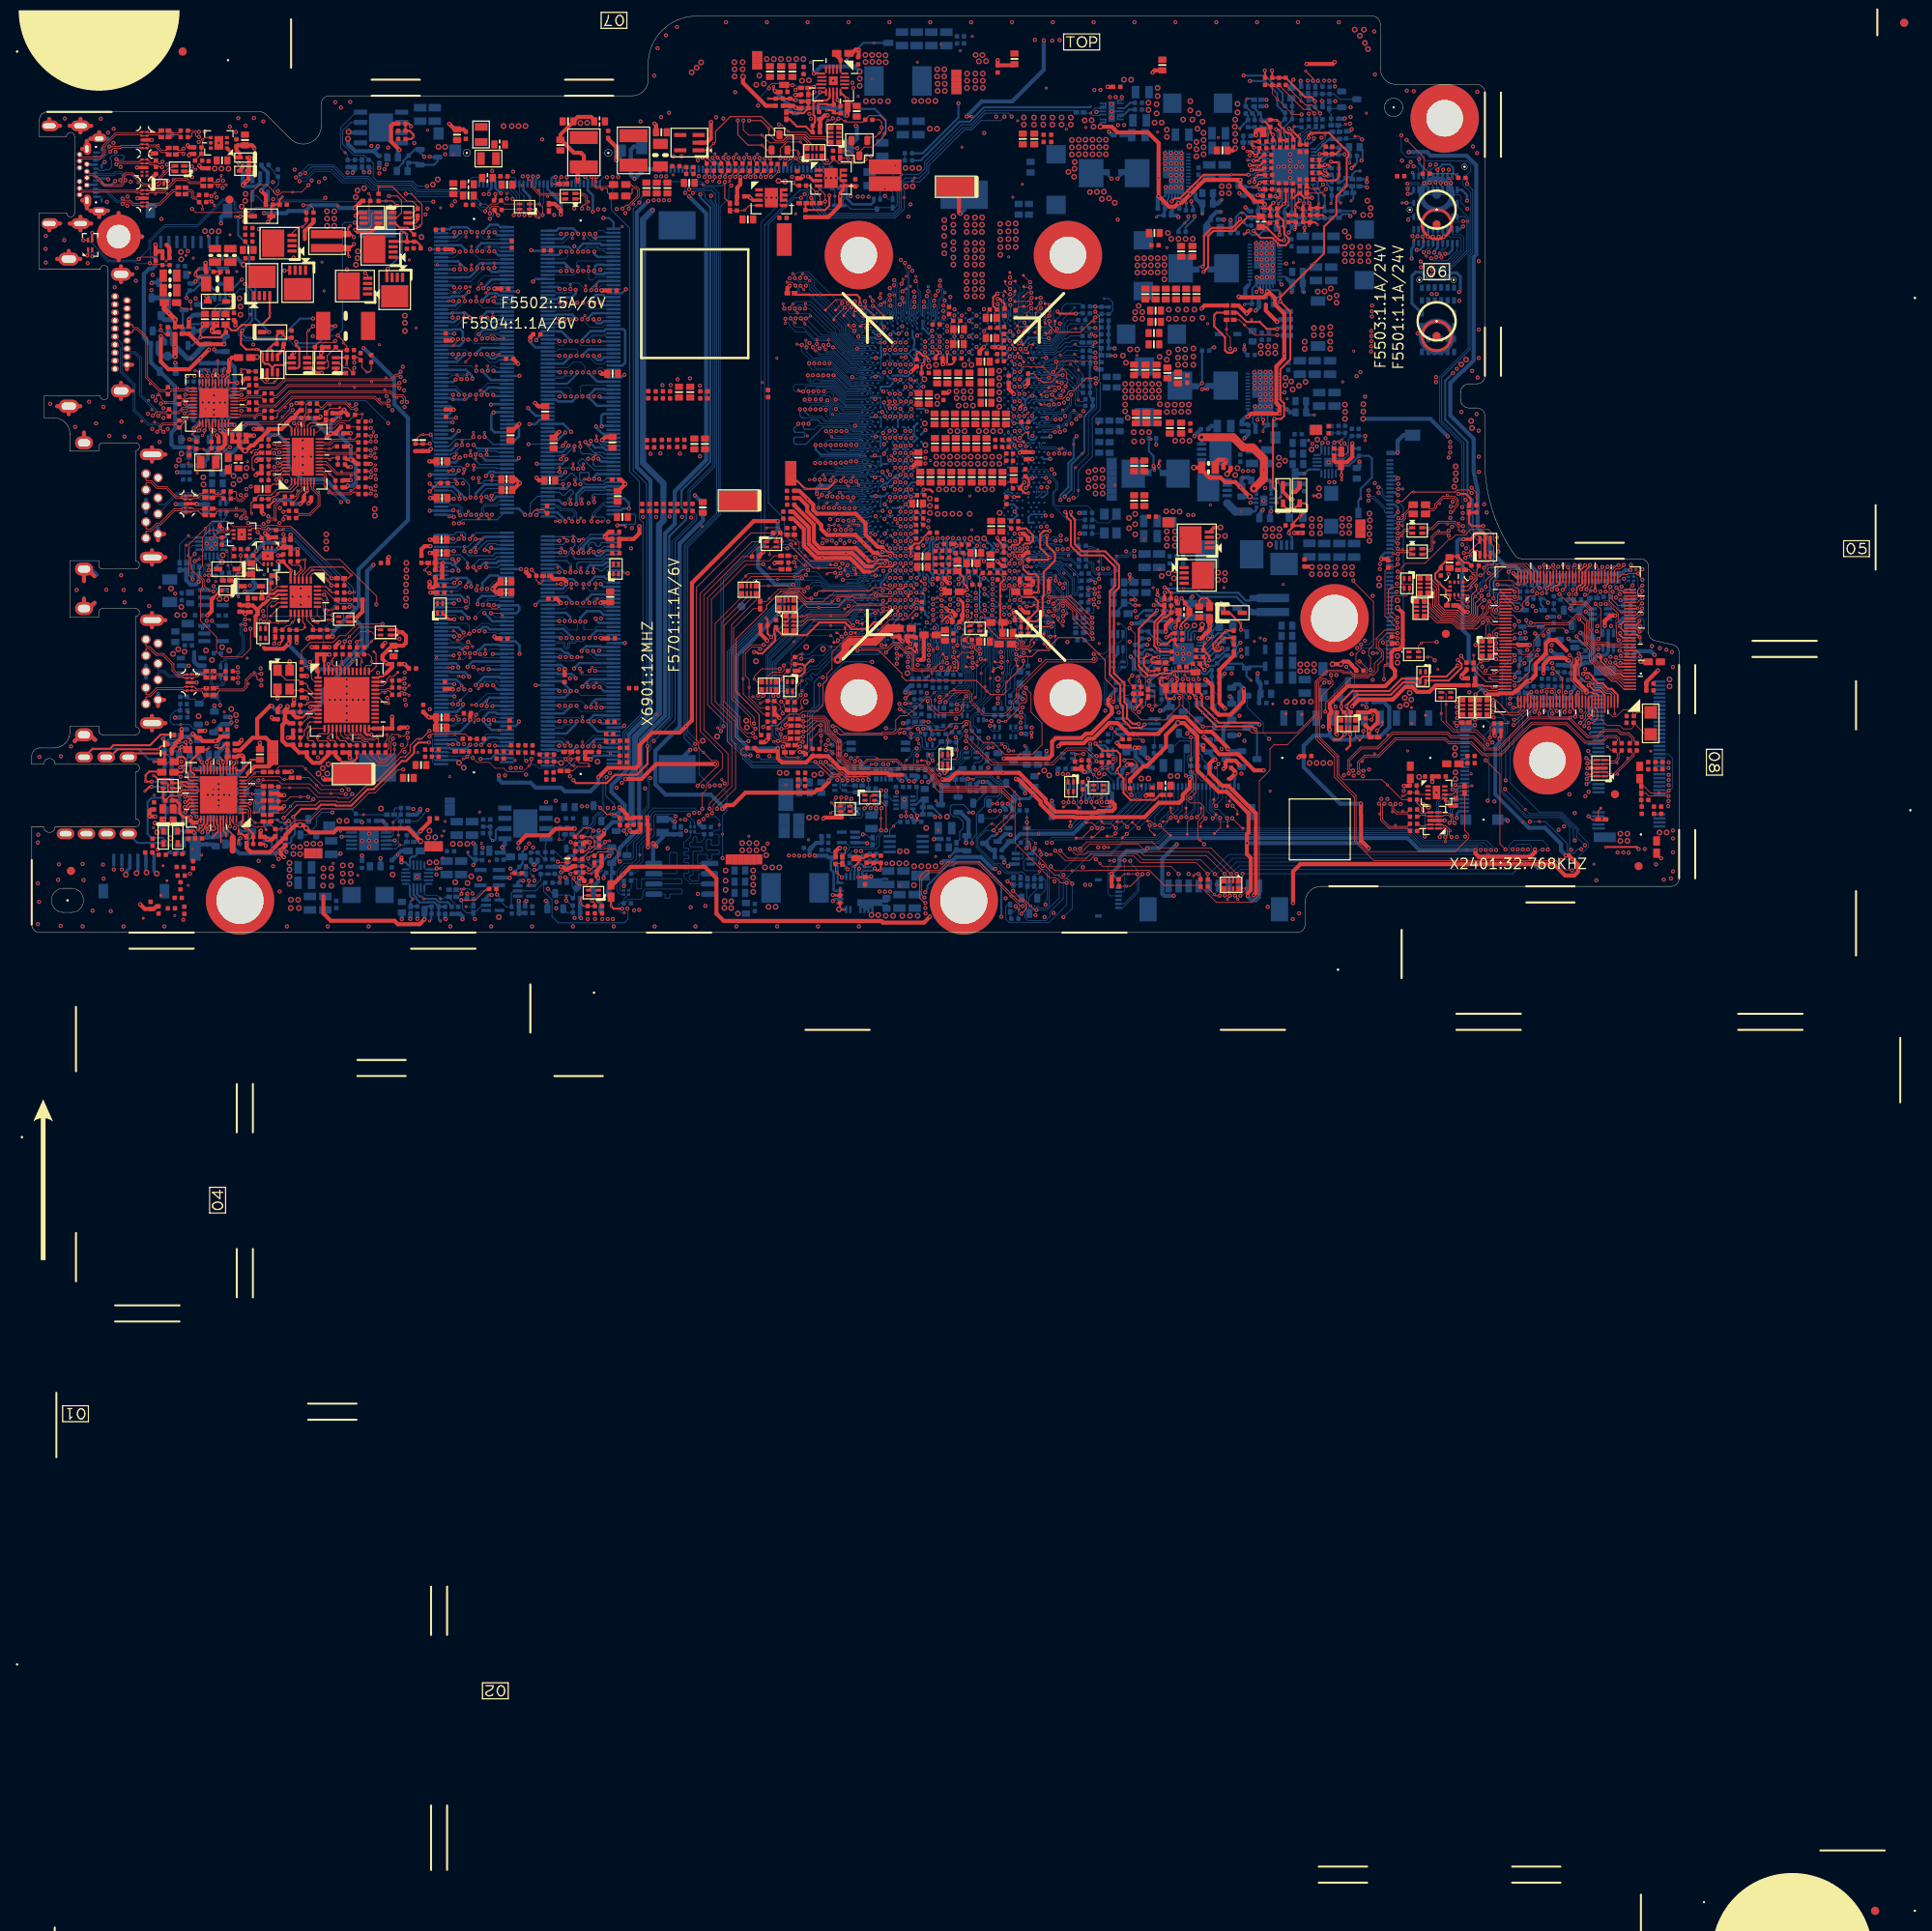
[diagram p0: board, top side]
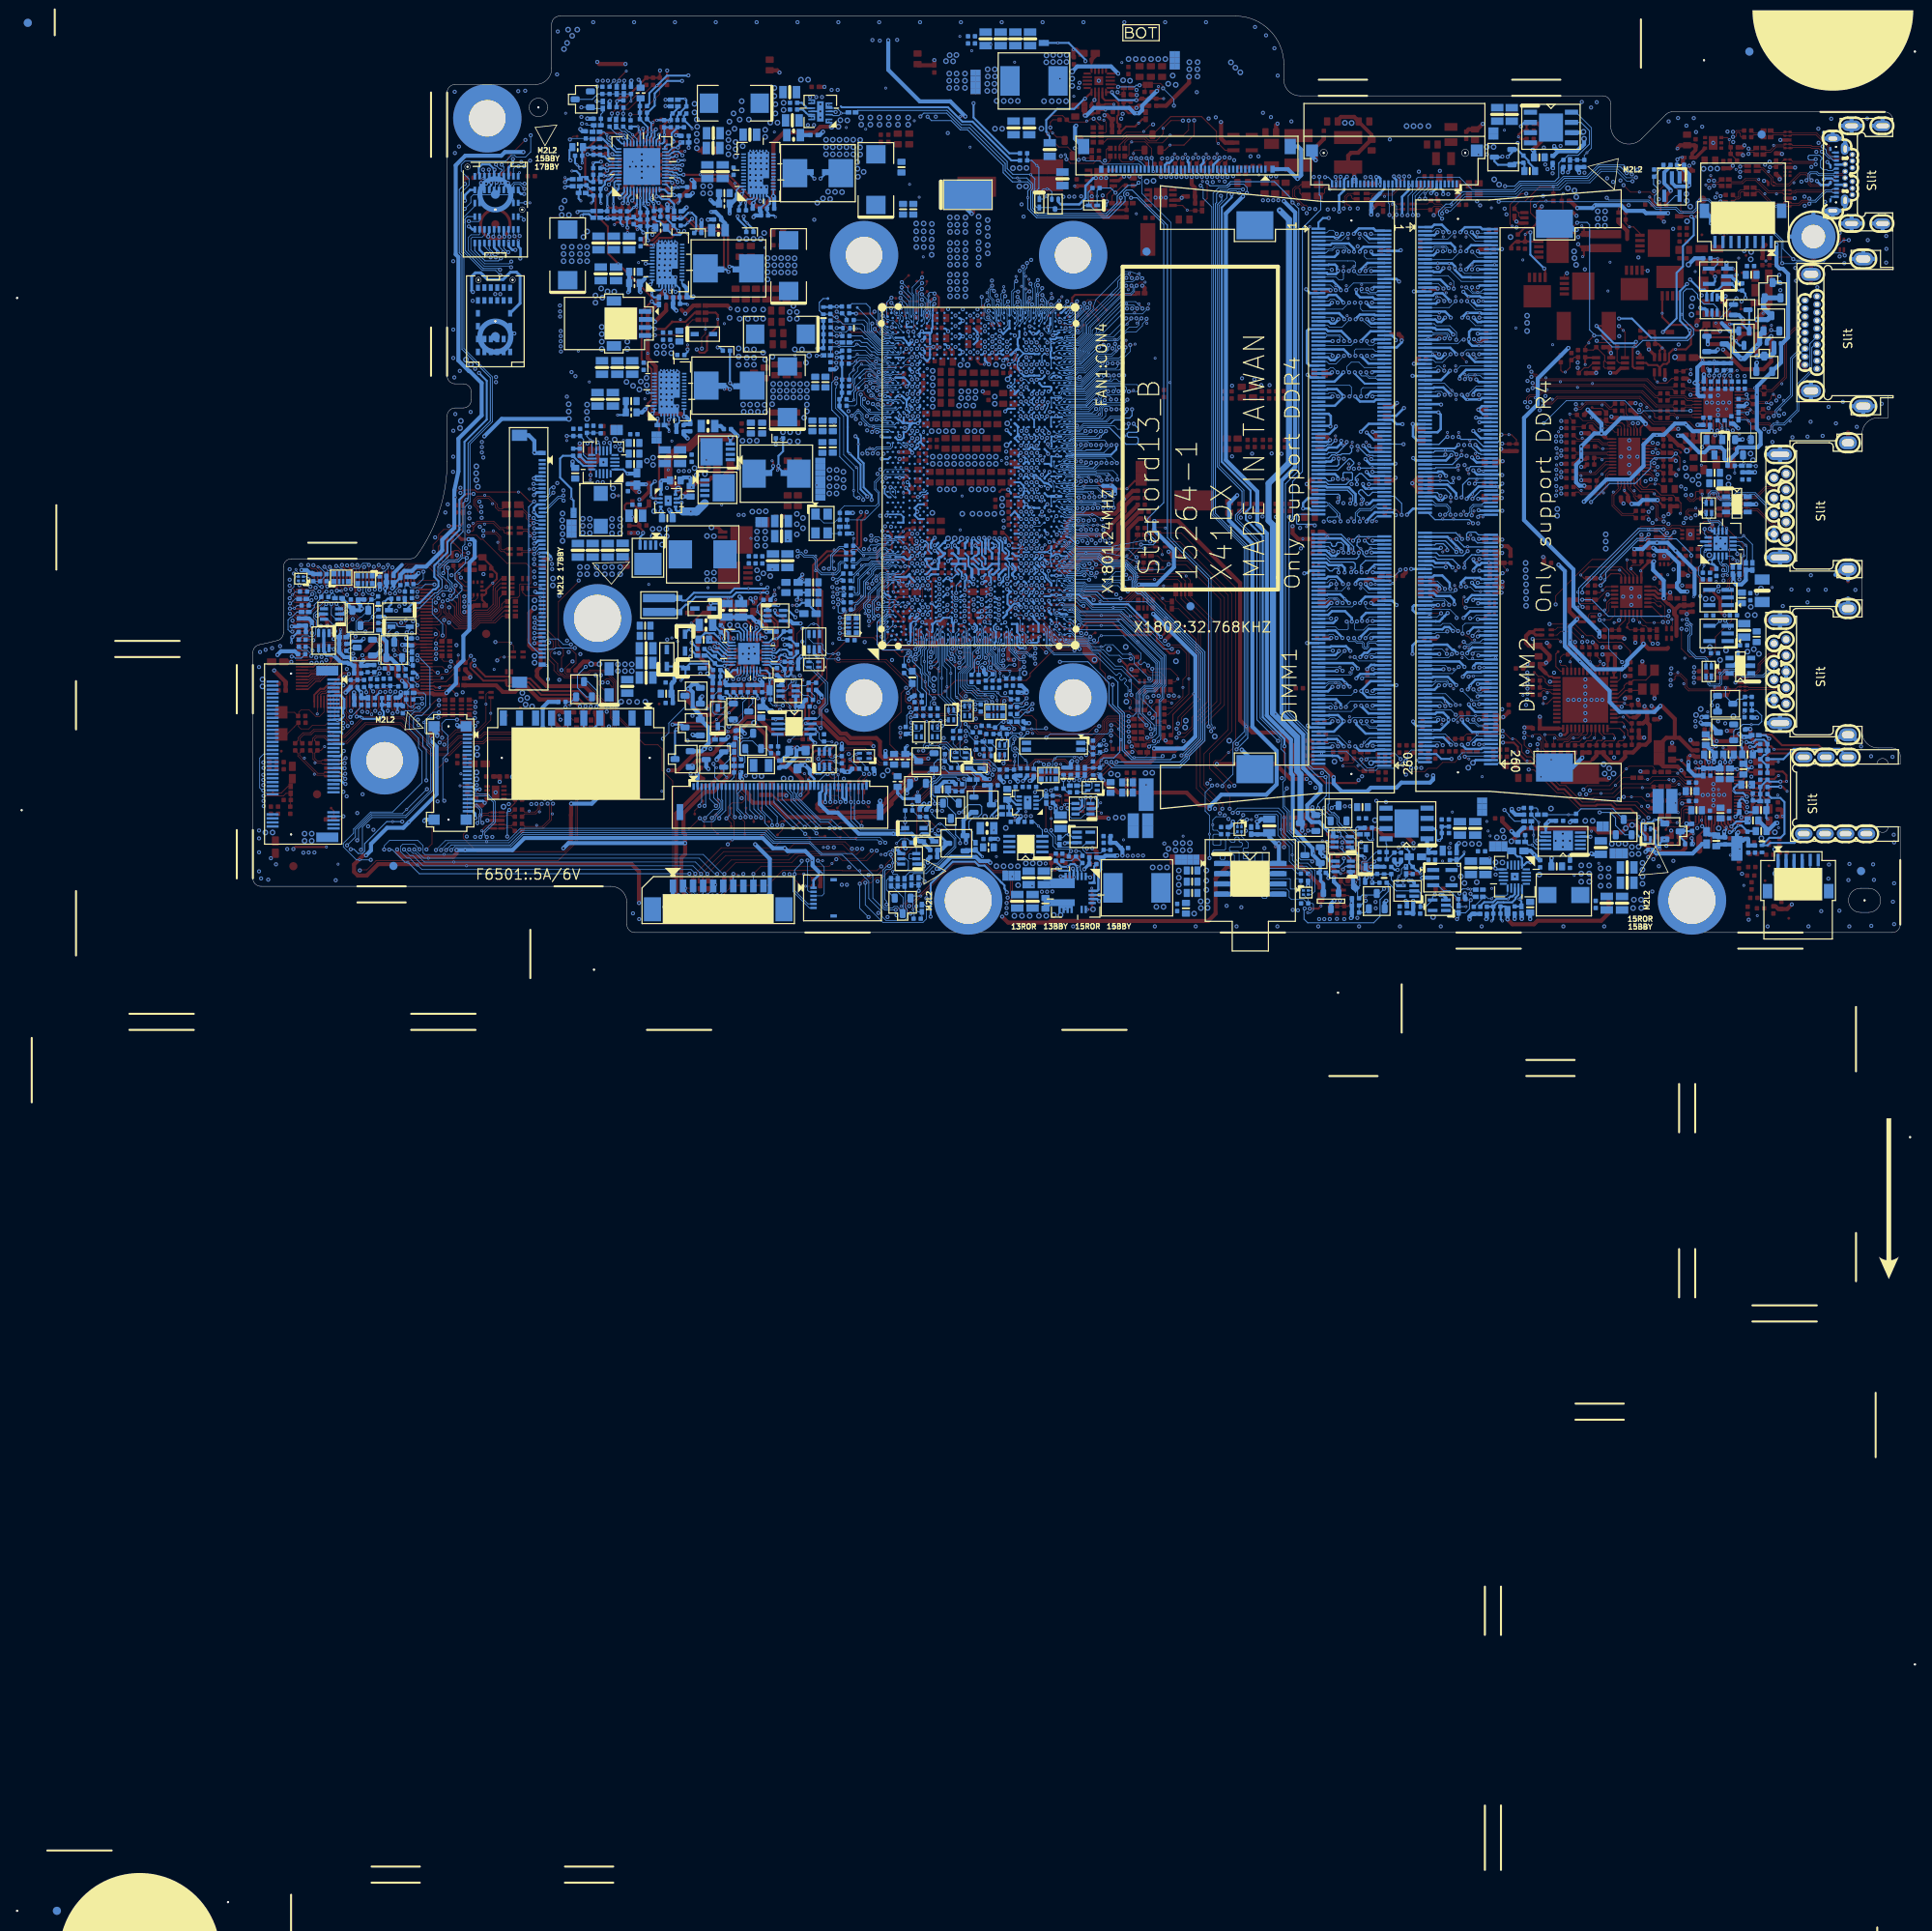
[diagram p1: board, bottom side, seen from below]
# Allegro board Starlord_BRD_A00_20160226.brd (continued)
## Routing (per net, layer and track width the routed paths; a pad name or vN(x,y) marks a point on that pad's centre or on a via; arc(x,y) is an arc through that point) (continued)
M_B_CLK#1: length 68.6
  TOP w0.102: v2(53.29,51.86) 53.01,52.14 v1(53.01,52.39)
  L6 w0.127: v2(109.28,62.35) 109.14,62.49 109.14,63.08 108.77,63.45 104.39,63.45 103.33,64.52 98.47,64.52 96.78,62.83 96.09,62.83 95.57,62.31 92.87,62.31 92.48,61.92 84.61,61.92 82.14,59.45 82.14,59.04 82.47,58.71 82.47,58.53 82.29,58.35 82.11,58.35 81.78,58.68 81.38,58.68 81.03,58.34 80.12,58.34 77.5,55.71 75.67,55.71 74.62,54.66 73.36,54.66 71.41,52.71 53.81,52.71 53.45,52.35 53.45,52.02 v2(53.29,51.86)
  BOTTOM w0.102: v2(109.28,62.35) 109,62.63 CPU1.AN46 ; v2(53.29,51.86) 53.29,52.72 53.03,52.98 50.94,52.98 DM2.140
M_B_CS#0: length 64.8
  TOP w0.152: v1(55.19,47.87) v2(55.19,47.31)
  L6 w0.102: v2(99.36,60.6) 98.52,59.76 96.63,59.76 93.89,57.01
  L6 w0.165: 93.89,57.01 88.1,57.01 77.24,46.16 73.64,46.16 73.48,46.33 73.48,46.69 73.31,46.85 72.98,46.85 72.82,46.69 72.82,45.97 72.69,45.84 72.28,45.84 72.15,45.97 72.15,46.69 71.99,46.85 71.66,46.85 71.49,46.69 71.49,46.33 71.33,46.16 70.43,46.16 70.1,45.84 69.76,45.84 69.44,46.16 68.91,46.16 68.58,45.83 65.15,45.83 64.74,46.24 64.35,46.24 64.18,46.41 64.18,46.89 63.99,47.08 63.72,47.08 63.52,46.89 63.52,46.41 63.36,46.24 58.04,46.24 57.47,46.82 55.36,46.82 55.19,46.98 v2(55.19,47.31)
  BOTTOM w0.089: 101.23,59.99 101.34,59.88 101.73,59.88 101.75,59.86 103.09,59.86 103.13,59.82 CPU1.BB42
  BOTTOM w0.152: v2(55.19,47.31) 56.57,48.69 DM2.149 ; v2(99.36,60.6) 99.36,60.17 99.54,59.99 101.23,59.99
M_B_CS#1: length 66
  TOP w0.152: v2(54.91,45.43) 54.91,45.33 v1(55.29,44.95)
  L6 w0.102: v2(101.26,60.6) 100.53,59.86 99.19,59.86 98.68,59.35 96.87,59.35 93.6,56.07
  L6 w0.165: 93.6,56.07 93.57,56.04 88.45,56.04 77.63,45.22 75.56,45.22 75.39,45.06 75.39,44.53 75.23,44.37 74.9,44.37 74.73,44.53 74.73,45.06 74.57,45.22 74.04,45.22 73.09,44.28 72.67,44.28 72.51,44.44 72.51,44.71 72.34,44.87 72.01,44.87 71.85,44.71 71.85,44.44 71.68,44.28 71.35,44.28 71.19,44.44 71.19,44.71 71.02,44.87 70.69,44.87 70.53,44.71 70.53,44.44 70.36,44.28 61.05,44.28 60.08,45.24 57.4,45.24 56.77,45.88 55.36,45.88 v2(54.91,45.43)
  BOTTOM w0.089: v2(101.26,60.6) 101.82,60.04 102.92,60.04 102.96,60.08 103.39,60.08 103.47,60.04 103.72,60.04 103.84,60.08 104.02,60.08 104.19,60.03 CPU1.AY42
  BOTTOM w0.152: v2(54.91,45.43) 54.91,45.64 55.68,46.4 57.53,46.4 57.82,46.69 DM2.157
M_B_DIMB_ODT0: length 65.7
  TOP w0.152: v1(53.8,47.97) v2(53.8,47.41)
  L6 w0.102: v2(98.09,60.6) 97.65,60.16 96.44,60.16 95.32,59.04 94.81,59.04
  L6 w0.165: 94.81,59.04 93.73,57.95 87.71,57.95 82.27,52.52 81.04,52.52 80.24,51.72 80.24,50.49 77.04,47.29 74.34,47.29 73.83,47.79 71.64,47.79 71.42,48.01 68.67,48.01 68.33,47.67 67.14,47.67 66.87,47.4 66.87,47.11 66.54,46.77 65.54,46.77 65.27,47.04 65.27,47.72 64.9,48.1 64.29,48.1 64.1,48.29 55.99,48.29 55.67,47.97 54,47.97 53.8,47.77 v2(53.8,47.41)
  BOTTOM w0.102: CPU1.BA42 103.67,59.55 103.13,59.55 103.12,59.56 103.08,59.56 102.98,59.66 99.02,59.66 v2(98.09,60.6)
  BOTTOM w0.152: DM2.155 57.72,47.19 57.69,47.16 57.63,47.16 57.33,46.85 54.35,46.85 v2(53.8,47.41)
M_B_DIMB_ODT1: length 66.3
  TOP w0.152: v1(56.51,45.97) v2(56.51,45.41)
  L6 w0.102: 93.07,55.59 93.44,55.59 97,59.15 98.75,59.15 99.26,59.66 101.62,59.66 101.9,59.93 v2(101.9,60.63)
  L6 w0.165: v2(56.51,45.41) 56.26,45.15 56.26,44.8 56.44,44.62 59.05,44.62 59.28,44.39 59.28,43.98 59.46,43.81 59.7,43.81 59.86,43.64 59.86,43.51 60.03,43.35 60.36,43.35 60.52,43.51 60.52,43.64 60.69,43.81 61.02,43.81 61.18,43.64 61.18,43.51 61.35,43.35 61.68,43.35 61.84,43.51 61.84,43.64 62.01,43.81 62.34,43.81 62.5,43.64 62.5,43.51 62.67,43.35 63,43.35 63.16,43.51 63.16,43.64 63.33,43.81 63.66,43.81 63.83,43.64 63.83,43.51 63.99,43.35 64.32,43.35 64.49,43.51 64.49,43.64 64.65,43.81 71.68,43.81 71.84,43.64 71.84,43.51 72.01,43.35 72.34,43.35 72.5,43.51 72.5,43.64 72.67,43.81 73,43.81 73.16,43.64 73.16,43.51 73.33,43.35 73.66,43.35 73.83,43.51 73.83,43.64 73.99,43.81 74.32,43.81 74.49,43.64 74.49,43.51 74.65,43.35 74.98,43.35 75.15,43.51 75.15,43.64 75.31,43.81 75.7,43.81 75.86,43.97 75.86,44.56 76.03,44.72 76.36,44.72 76.53,44.56 76.53,44.24 76.77,44 77.07,44 88.65,55.57 93.05,55.57 93.07,55.59
  BOTTOM w0.089: v2(101.9,60.63) 101.9,60.42 102.1,60.21 102.77,60.21 102.81,60.26 103.43,60.26 103.51,60.22 103.69,60.22 103.82,60.26 104.04,60.26 104.18,60.22 104.65,60.22 104.75,60.12 104.8,60.07 105.05,59.82 CPU1.AW42
  BOTTOM w0.152: DM2.161 58.23,45.69 57.95,45.41 v2(56.51,45.41)
M_B_DQ0: length 75
  TOP w0.089: v1(56.1,83.18) v2(56.1,82.59)
  L6 w0.102: v2(112.91,72.8) 113.31,73.2 113.31,73.55 113.51,73.75 113.51,74.41 113.31,74.62 113.31,74.87 110.78,77.4 110.55,77.63 110.55,77.63 110.18,77.99 110.18,79.19 110.11,79.26 110.11,79.93 107.83,82.21 105.71,82.21 104.87,81.37 101.67,81.37 98.02,85.03 90.26,85.03 88.42,83.19 81.16,83.19 80.21,82.24 73.25,82.24 72.13,81.12 63.62,81.12 63.05,81.68 63.03,81.68 63.02,81.7 56.98,81.7 v2(56.1,82.59)
  BOTTOM w0.089: DM2.28 54.59,80.94 56.1,82.44 v2(56.1,82.59) ; v2(112.91,72.8) 112.58,73.12 CPU1.AF65
M_B_DQ1: length 73.7
  TOP w0.089: v2(56.81,80.05) 56.81,79.86 v1(56.46,79.52)
  L6 w0.102: v2(112,72.8) 112.51,73.32 112.51,74.84 111.89,75.46 110.92,75.46 108.65,77.72 108.65,77.94 108.11,78.48 108.1,78.48 106.9,79.67 106.17,79.67 105.81,80.03 101.57,80.03 97.66,83.94 90.57,83.94 88.83,82.2 81.57,82.2 80.62,81.25 73.66,81.25 71.77,79.35 65.71,79.35 65.43,79.63 63.85,79.63 63.75,79.73 63.75,79.95 63.65,80.05 63.45,80.05 63.35,79.95 63.35,79.73 63.24,79.63 63.04,79.63 62.94,79.73 62.94,79.95 62.84,80.05 62.63,80.05 62.53,79.95 62.53,79.73 62.43,79.63 61.21,79.63 60.14,80.69 59.96,80.69 59.86,80.59 59.86,79.72 59.76,79.62 59.56,79.62 59.45,79.72 59.45,80.59 59.35,80.69 59.15,80.69 59.05,80.59 59.05,79.72 58.95,79.62 58.74,79.62 58.64,79.72 58.64,80.59 58.54,80.69 57,80.69 56.81,80.51 v2(56.81,80.05)
  BOTTOM w0.089: v2(112,72.8) 112.32,72.47 CPU1.AF64 ; DM2.29 57.45,80.69 v2(56.81,80.05)
M_B_DQ2: length 73.9
  TOP w0.089: v1(55.28,79.06) v2(55.28,78.5)
  L6 w0.102: v2(55.28,78.5) 55.36,78.42 55.36,77.72 55.47,77.62 60.73,77.62 61.35,77 73.03,77 75.65,79.62 87.74,79.62 87.84,79.72 87.84,80.44 87.96,80.56 88.13,80.56 88.25,80.44 88.25,79.72 88.35,79.62 88.57,79.62 91.11,82.16 91.32,82.16 91.42,82.06 91.42,81.64 91.54,81.53 91.71,81.53 91.83,81.64 91.83,82.06 91.93,82.16 92.14,82.16 92.24,82.06 92.24,81.62 92.36,81.5 92.52,81.5 92.64,81.62 92.64,82.06 92.75,82.16 92.95,82.16 93.05,82.06 93.05,81.68 93.15,81.58 93.35,81.58 93.46,81.68 93.46,82.06 93.56,82.16 97.08,82.16 100.38,78.86 103.76,78.86 103.99,78.63 103.99,77.65 104.46,77.18 105.54,77.18 106.12,76.6 108.28,76.6 110.59,74.28 110.59,73.29 v2(111.08,72.8)
  BOTTOM w0.089: v2(111.08,72.8) 110.95,72.8 CPU1.AK65 ; v2(55.28,78.5) 56.09,77.69 DM2.41
M_B_DQ3: length 74.9
  TOP w0.089: v1(53.64,79.04) 53.86,78.82 v2(53.86,78.5)
  L6 w0.102: v2(111.08,72.15) 111.47,72.54 111.47,73.63 111.07,74.03 111.07,74.34 108.41,77 106.27,77 105.64,77.64 105.44,77.64 105.19,77.88 105.19,78.62 105.09,78.72 105.09,78.75 104.57,79.26 101.04,79.26 100.73,79.57 100.63,79.57 97.33,82.87 90.89,82.87 89.24,81.22 87.79,81.22 87.29,81.22 87.19,81.12 87.19,80.89 87.06,80.76 86.9,80.76 86.78,80.88 86.78,81.12 86.68,81.22 85.9,81.22 84.96,80.28 75.37,80.28 74.17,79.08 74.03,79.08 73.54,79.56 73.4,79.56 73.26,79.42 73.26,79.28 73.74,78.79 73.74,78.65 73.6,78.5 73.45,78.5 72.97,78.99 72.83,78.99 72.68,78.85 72.68,78.7 73.17,78.22 73.17,78.07 72.96,77.86 71.77,77.86 71.59,78.05 71.36,78.05 71.18,77.86 65.15,77.86 64.41,78.6 57.94,78.6 57.61,78.93 54.29,78.93 v2(53.86,78.5)
  BOTTOM w0.089: v2(53.86,78.5) 52.82,77.45 51.91,77.45 51.89,77.44 DM2.42 ; v2(111.08,72.15) 110.95,72.15 CPU1.AK64
M_B_DQ4: length 74.3
  TOP w0.089: v1(54.67,83) v2(54.67,82.43)
  L6 w0.102: v2(112.91,73.45) 112.91,73.53 113.3,73.93 113.3,74.34 113.1,74.54 113.1,74.79 111.81,76.09 110.86,76.09 109.14,77.81 109.14,80.43 107.69,81.88 105.87,81.88 104.7,80.71 101.85,80.71 97.86,84.7 90.4,84.7 88.55,82.86 81.3,82.86 80.34,81.91 73.38,81.91 72.27,80.79 63.48,80.79 62.91,81.35 55.39,81.35 54.67,82.07 v2(54.67,82.43)
  BOTTOM w0.089: CPU1.AF66 112.58,73.77 v2(112.91,73.45) ; v2(54.67,82.43) 54.18,81.94 DM2.24
M_B_DQ5: length 74
  TOP w0.089: v2(55.52,80.03) 55.52,80.23 v1(55.93,80.64)
  L6 w0.102: v2(55.52,80.03) 55.52,80.66 55.89,81.02 60.59,81.02 60.69,80.92 60.69,80.76 60.79,80.66 61,80.66 61.1,80.76 61.1,80.92 61.2,81.02 61.61,81.02 62.18,80.46 72.4,80.46 73.52,81.58 80.48,81.58 81.43,82.53 88.69,82.53 90.52,84.36 97.72,84.36 101.73,80.36 105.21,80.36 106.4,81.55 107.41,81.55 107.67,81.3 107.67,80.51 107.97,80.2 108.58,80.2 108.81,79.98 108.81,79.59 108.91,79.48 108.91,77.77 110.81,75.87 111.76,75.87 112.91,74.71 v2(112.91,74.1)
  BOTTOM w0.089: DM2.25 58.1,81.69 58.06,81.65 56.23,81.65 55.52,80.94 v2(55.52,80.03) ; v2(112.91,74.1) 112.58,74.42 CPU1.AF67
M_B_DQ6: length 72.4
  TOP w0.089: v1(51.88,78.5) v2(52.44,78.5)
  L6 w0.102: v2(110.11,74.21) 110.11,74.32 108.04,76.39 106.04,76.39 105.48,76.95 104.09,76.95 103.45,77.59 102.79,77.59 102.63,77.75 102.5,77.75 101.6,78.66 100.1,78.66 96.92,81.83 94.08,81.83 93.42,81.17 90.59,81.17 88.71,79.29 75.79,79.29 73.17,76.67 72.57,76.67 72.47,76.57 72.47,76.29 72.35,76.17 72.18,76.17 72.07,76.29 72.07,76.57 71.96,76.67 71.76,76.67 71.66,76.57 71.66,76.23 71.56,76.14 71.35,76.14 71.25,76.23 71.25,76.57 71.15,76.67 61.21,76.67 60.6,77.29 55.13,77.29 55.03,77.39 55.03,77.92 54.93,78.02 54.73,78.02 54.62,77.92 54.62,77.39 54.52,77.29 54.32,77.29 54.22,77.39 54.22,77.92 54.12,78.02 53.91,78.02 53.81,77.92 53.81,77.39 53.71,77.29 53.51,77.29 53.41,77.39 53.41,77.92 53.3,78.02 53.1,78.02 53,77.92 53,77.39 52.9,77.29 52.65,77.29 52.44,77.5 v2(52.44,78.5)
  BOTTOM w0.089: v2(110.11,74.21) 110.32,74.42 CPU1.AK67 ; v2(52.44,78.5) 52.38,78.44 DM2.38
M_B_DQ7: length 73.7
  TOP w0.089: v1(57.63,79.04) 57.25,79.04 v2(56.71,78.5)
  L6 w0.102: v2(111.08,73.45) 110.82,73.71 110.82,74.32 108.34,76.8 106.2,76.8 105.61,77.39 104.53,77.39 104.18,77.73 104.18,78.77 103.89,79.06 100.96,79.06 100.68,79.34 100.38,79.34 97.23,82.49 90.98,82.49 89.38,80.89 87.65,80.89 86.71,79.95 86.51,79.95 86.41,80.05 86.41,80.75 86.29,80.86 86.12,80.86 86,80.75 86,80.05 85.9,79.95 75.51,79.95 72.9,77.33 64,77.33 63.9,77.44 63.9,78.17 63.8,78.27 63.6,78.27 63.49,78.17 63.49,77.44 63.39,77.33 63.19,77.33 63.09,77.44 63.09,78.17 62.99,78.27 62.78,78.27 62.68,78.17 62.68,77.44 62.58,77.33 62.38,77.33 62.27,77.44 62.27,78.17 62.17,78.27 61.97,78.27 61.87,78.17 61.87,77.44 61.77,77.33 61.49,77.33 61.36,77.46 61.36,77.82 61.24,77.95 60.09,77.95 59.99,78.05 59.99,78.17 59.89,78.27 59.69,78.27 59.59,78.17 59.59,78.05 59.48,77.95 59.28,77.95 59.18,78.05 59.18,78.17 59.08,78.27 58.87,78.27 58.77,78.17 58.77,78.05 58.67,77.95 57.25,77.95 v2(56.71,78.5)
  BOTTOM w0.089: DM2.37 57.91,78.69 57.62,78.98 57.19,78.98 v2(56.71,78.5) ; v2(111.08,73.45) 110.95,73.45 CPU1.AK66
M_B_DQ8: length 75.1
  TOP w0.089: v1(53.99,86.46) v2(53.99,87.06)
  L6 w0.102: v2(53.99,87.06) 54.43,86.61 63.68,86.61 64.55,85.74 72.36,85.74 72.47,85.86 73.48,85.86 73.65,86.02 73.89,86.02 74.06,85.86 79.02,85.86 79.7,86.54 87.96,86.54 89.2,87.79 98.85,87.79 100.35,89.29 105.79,89.29 113.71,81.36 113.71,79.65 113.51,79.44 v2(113.51,78.58)
  BOTTOM w0.089: DM2.8 52.87,85.94 v2(53.99,87.06) ; CPU1.AF70 113.26,76.88 113.5,76.88 113.74,77.12 113.74,77.66 113.9,77.82 113.9,78.14 113.51,78.53 v2(113.51,78.58)
M_B_DQ9: length 76.9
  TOP w0.089: v1(55.41,86.48) v2(55.41,87.06)
  L6 w0.102: v2(55.41,87.06) 56.17,87.82 63.41,87.82 64.83,86.4 72.08,86.4 72.89,87.2 87.68,87.2 88.93,88.45 98.58,88.45 100.08,89.95 106.06,89.95 114.37,81.63 114.37,79.16 v2(114.22,79.01)
  BOTTOM w0.089: v2(114.22,79.01) 114.22,77.84 113.94,77.56 113.94,76.34 113.68,76.08 113.22,76.08 113,75.85 113,75.58 113,75.58 112.96,75.55 112.96,75.53 CPU1.AF68 ; v2(55.41,87.06) 56.28,86.18 DM2.7
M_B_DQ10: length 74.4
  TOP w0.089: v1(53.25,83) v2(53.25,82.43)
  L6 w0.102: v2(111.3,79.11) 110.77,79.65 110.77,81.21 110.17,81.8 109.27,81.8 107.34,83.73 107.34,84.33 104.36,87.32 101.28,87.32 99.66,85.69 89.99,85.69 88.14,83.85 73.79,83.85 71.72,81.78 64.11,81.78 62.81,83.08 60.72,83.08 60.62,82.98 60.62,82.52 60.52,82.41 60.31,82.41 60.21,82.52 60.21,82.98 60.11,83.08 59.91,83.08 59.81,82.98 59.81,82.52 59.7,82.41 59.5,82.41 59.4,82.52 59.4,82.98 59.3,83.08 59.09,83.08 58.99,82.98 58.99,82.52 58.89,82.41 58.69,82.41 58.59,82.52 58.59,82.98 58.48,83.08 53.9,83.08 v2(53.25,82.43)
  BOTTOM w0.089: v2(53.25,82.43) 52.75,82.94 DM2.20 ; v2(111.3,79.11) 111.51,78.9 111.51,77.57 111.47,77.53 111.47,77.51 111.43,77.48 CPU1.AH71
M_B_DQ11: length 76.9
  TOP w0.089: v1(57.52,83.23) v2(57.52,82.65)
  L6 w0.102: v2(110.95,78.42) 110.95,78.87 110.44,79.39 110.44,81.07 110.06,81.45 109.16,81.45 107.01,83.6 107.01,84.2 104.22,86.99 101.42,86.99 99.79,85.36 90.12,85.36 88.28,83.52 81.02,83.52 80.07,82.57 79.69,82.57 79.58,82.67 79.58,83.38 79.48,83.48 79.28,83.48 79.18,83.38 79.18,82.67 79.08,82.57 78.87,82.57 78.77,82.67 78.77,83.38 78.67,83.48 78.47,83.48 78.37,83.38 78.37,82.67 78.26,82.57 78.06,82.57 77.96,82.67 77.96,83.38 77.86,83.48 77.65,83.48 77.55,83.38 77.55,82.67 77.45,82.57 77.25,82.57 77.15,82.67 77.15,83.38 77.04,83.48 76.84,83.48 76.74,83.38 76.74,82.67 76.64,82.57 76.43,82.57 76.33,82.67 76.33,83.38 76.23,83.48 76.03,83.48 75.93,83.38 75.93,82.67 75.83,82.57 75.62,82.57 75.52,82.67 75.52,83.38 75.42,83.48 75.22,83.48 75.11,83.38 75.11,82.67 75.01,82.57 73.11,82.57 71.99,81.45 63.93,81.45 63.32,82.06 58.11,82.06 v2(57.52,82.65)
  BOTTOM w0.089: v2(110.95,78.42) 110.95,78.42 111.33,78.04 111.33,77.64 111.29,77.6 111.29,77.59 111.08,77.37 111.08,76.9 111.06,76.88 111.06,75.93 111.03,75.91 111.03,75.48 CPU1.AH68 ; DM2.21 57.56,82.69 v2(57.52,82.65)
M_B_DQ12: length 74.3
  TOP w0.089: v1(52.57,86.49) v2(52.57,87.06)
  L6 w0.102: v2(52.57,87.06) 53.39,86.23 63.59,86.23 65.35,84.47 65.35,84.47 65.61,84.22 65.67,84.15 71.24,84.15 72.61,85.53 79.22,85.53 79.91,86.21 88.09,86.21 89.34,87.46 98.99,87.46 100.49,88.95 105.65,88.95 113.38,81.22 113.38,80.15 112.96,79.01 112.96,77.66 v2(113.35,77.28)
  BOTTOM w0.089: DM2.4 52.45,86.94 v2(52.57,87.06) ; CPU1.AF71 v2(113.35,77.28)
M_B_DQ13: length 76
  TOP w0.089: v1(56.83,86.48) v2(56.83,87.06)
  L6 w0.102: v2(113.43,76.46) 113.43,76.47 113.76,76.8 113.76,78.12 113.9,78.26 113.9,78.77 113.83,78.85 113.83,79.43 114.04,79.65 114.04,81.5 105.92,89.62 100.21,89.62 98.71,88.12 89.06,88.12 87.82,86.87 78.77,86.87 78.67,86.77 78.67,86.4 78.57,86.3 78.37,86.3 78.27,86.4 78.27,86.77 78.16,86.87 77.96,86.87 77.86,86.77 77.86,86.4 77.76,86.3 77.56,86.3 77.45,86.4 77.45,86.77 77.35,86.87 77.15,86.87 77.05,86.77 77.05,86.4 76.95,86.3 76.74,86.3 76.64,86.4 76.64,86.77 76.54,86.87 76.34,86.87 76.23,86.77 76.23,86.4 76.13,86.3 75.93,86.3 75.83,86.4 75.83,86.77 75.73,86.87 73.02,86.87 72.22,86.07 64.69,86.07 63.27,87.49 57.27,87.49 v2(56.83,87.06)
  BOTTOM w0.089: DM2.3 58.07,87.18 57.76,87.49 57.27,87.49 v2(56.83,87.06) ; CPU1.AF69 112.82,75.88 112.82,75.93 113.15,76.25 113.22,76.25 v2(113.43,76.46)
M_B_DQ14: length 75.1
  L6 w0.102: v2(111.48,79.72) 111.1,80.1 111.1,81.37 104.83,87.65 101.12,87.65 99.49,86.02 89.85,86.02 88.01,84.18 87.62,84.18 87.51,84.28 87.51,84.8 87.41,84.9 87.21,84.9 87.11,84.8 87.11,84.28 87.01,84.18 86.8,84.18 86.7,84.28 86.7,84.8 86.6,84.9 86.4,84.9 86.3,84.8 86.3,84.28 86.19,84.18 85.99,84.18 85.89,84.28 85.89,84.63 85.77,84.75 85.6,84.75 85.48,84.63 85.48,84.28 85.38,84.18 73.65,84.18 72.33,82.86 71.82,82.86 63.54,82.86 62.91,83.48 54.38,83.48 v2(53.24,84.62)
  BOTTOM w0.089: DM2.16 52.55,83.94 53.24,84.62 v2(53.24,84.62) ; CPU1.AH70 111.43,76.61 111.67,76.85 111.69,76.94 111.69,77.03 111.72,77.05 111.72,77.67 111.7,77.69 111.7,78.6 111.83,78.73 111.83,79.37 v2(111.48,79.72) 111.48,80.28 v1(111.48,80.28)
M_B_DQ15: length 76
  TOP w0.089: v1(54.67,85.28) v2(54.67,84.69)
  L6 w0.102: v2(112.21,78.56) 111.91,78.86 111.91,80.51 111.83,80.59 111.83,81.1 104.96,87.98 100.98,87.98 99.35,86.35 89.71,86.35 88.59,85.23 84.95,85.23 84.84,85.13 84.84,84.62 84.74,84.52 84.54,84.52 84.44,84.62 84.44,85.13 84.34,85.23 84.13,85.23 84.03,85.13 84.03,84.62 83.93,84.52 73.29,84.52 71.96,83.19 63.94,83.19 63.3,83.84 59.11,83.84 59.01,83.94 59.01,84.17 58.91,84.27 58.71,84.27 58.6,84.17 58.6,83.94 58.5,83.84 55.53,83.84 v2(54.67,84.69)
  BOTTOM w0.089: CPU1.AH69 111.83,76.12 111.83,76.76 111.9,77.02 111.9,77.75 111.88,77.77 111.88,78.23 v2(112.21,78.56) ; DM2.17 55.68,83.69 v2(54.67,84.69)
M_B_DQ16: length 62.9
  TOP w0.089: v1(53.76,77.02) v2(53.76,76.44)
  L6 w0.102: v2(106.78,74.34) 106.78,75.02 106.13,75.67 105.81,75.67 105.45,76.04 104.9,76.04 104.62,76.32 101.37,76.32 99.69,77.99 99.24,77.99 97.6,79.63 90.45,79.63 89.12,78.3 76.2,78.3 73.04,75.15 60.71,75.15 60.25,75.61 53.9,75.61 53.76,75.74 v2(53.76,76.44)
  BOTTOM w0.089: DM2.50 52.81,75.44 53.76,76.38 v2(53.76,76.44) ; v2(106.78,74.34) 106.78,74.31 106.81,74.29 106.81,74.13 107.05,73.89 CPU1.AT66
M_B_DQ17: length 62.2
  TOP w0.089: v1(105.51,73.35) v2(106.07,73.35)
  L6 w0.102: v2(55.22,73.68) 55.55,73.35 61.11,73.35 61.82,74.06 64.3,74.06 64.48,73.88 64.73,73.88 64.91,74.06 73.32,74.06 76.6,77.33 89.56,77.33 90.89,78.66 97.18,78.66 98.83,77 99.59,77 101.9,74.69 101.9,74.64 102.16,74.39 102.46,74.39 102.61,74.54 104.04,74.54 105.03,73.55 105.87,73.55 v2(106.07,73.35)
  BOTTOM w0.089: v2(55.22,73.68) 55.17,73.72 55.17,74.6 56,75.43 57.71,75.43 57.94,75.66 57.95,75.66 57.97,75.69 DM2.49 ; v2(106.07,73.35) 106.07,73.6 106.27,73.8 CPU1.AU66
M_B_DQ18: length 66.2
  TOP w0.089: v2(54.5,71.89) 54.5,71.48 v1(53.95,70.93)
  L6 w0.102: v2(54.5,71.89) 54.96,72.36 71.04,72.36 71.75,73.07 73.73,73.07 77.01,76.34 90.62,76.34 90.72,76.45 90.72,77.09 90.84,77.21 91.01,77.21 91.13,77.09 91.13,76.45 91.23,76.34 91.59,76.34 91.67,76.42 91.67,76.9 91.9,77.13 92.33,77.13 92.43,77.23 92.43,77.56 92.53,77.66 92.74,77.66 92.84,77.56 92.84,77.23 92.94,77.13 97.23,77.13 98.35,76.01 99.64,76.01 102.41,73.24 103.76,73.24 104.32,72.69 105.17,72.69 105.82,72.04 107.63,72.04 v2(108.03,72.43)
  BOTTOM w0.089: DM2.62 50.9,72.43 53.96,72.43 v2(54.5,71.89) ; CPU1.AP65 108.35,72.76 v2(108.03,72.43)
M_B_DQ19: length 66.4
  TOP w0.089: v1(58.14,71.89) v2(57.34,71.89)
  L6 w0.102: v2(108.68,72.43) 108.08,71.83 105.75,71.83 105.13,72.46 104.24,72.46 103.66,73.04 102.33,73.04 99.69,75.68 98.04,75.68 96.92,76.8 93.6,76.8 92.81,76.01 92.51,76.01 92.4,76.12 92.4,76.43 92.28,76.55 92.12,76.55 92,76.43 92,76.12 91.9,76.01 77.14,76.01 73.87,72.74 72.42,72.74 72.19,72.51 72.04,72.51 71.93,72.62 71.79,72.62 71.64,72.48 71.64,72.33 71.76,72.22 71.76,72.08 71.61,71.93 71.47,71.93 71.36,72.04 71.21,72.04 71.07,71.9 71.07,71.76 71.18,71.64 71.18,71.5 70.94,71.26 65.18,71.26 65.08,71.36 65.08,71.92 64.98,72.03 64.77,72.03 64.67,71.92 64.67,71.36 64.57,71.26 64.37,71.26 64.27,71.36 64.27,71.92 64.16,72.03 63.96,72.03 63.86,71.92 63.86,71.36 63.76,71.26 63.55,71.26 63.45,71.36 63.45,71.92 63.35,72.03 63.15,72.03 63.05,71.92 63.05,71.36 62.94,71.26 62.74,71.26 62.64,71.36 62.64,71.92 62.54,72.03 62.34,72.03 62.23,71.92 62.23,71.36 62.13,71.26 61.87,71.26 61.24,71.89 v2(57.34,71.89)
  BOTTOM w0.089: CPU1.AN65 109,72.76 v2(108.68,72.43) ; v2(57.34,71.89) 57.34,71.89 57.64,72.19 DM2.63
M_B_DQ20: length 65.4
  TOP w0.089: v1(52.34,77.02) v2(52.34,76.44)
  L6 w0.102: v2(52.34,76.44) 52.77,76.87 60.41,76.87 61.47,75.81 72.77,75.81 75.92,78.96 88.85,78.96 90.73,80.84 97.38,80.84 101.47,76.75 105.28,76.75 105.87,76.17 106.88,76.17 108.3,74.75 108.3,73.72 v2(108.68,73.35)
  BOTTOM w0.089: DM2.46 50.92,76.42 52.32,76.42 v2(52.34,76.44) ; v2(108.68,73.35) 109,73.67 CPU1.AN66
M_B_DQ21: length 64.7
  TOP w0.089: v1(57.32,77.03) v2(57.32,76.44)
  L6 w0.102: v2(57.32,76.44) 57.8,76.44 57.9,76.34 57.9,76.09 58,75.99 58.2,75.99 58.3,76.09 58.3,76.34 58.41,76.44 58.61,76.44 58.71,76.34 58.71,76.09 58.81,75.99 59.02,75.99 59.12,76.09 59.12,76.34 59.22,76.44 59.42,76.44 59.52,76.34 59.52,76.09 59.62,75.99 59.83,75.99 59.93,76.09 59.93,76.34 60.03,76.44 60.33,76.44 61.29,75.48 72.91,75.48 76.06,78.63 88.98,78.63 90.32,79.96 90.73,79.96 90.83,80.06 90.83,80.41 90.93,80.51 91.13,80.51 91.24,80.41 91.24,80.06 91.34,79.96 91.54,79.96 91.64,80.06 91.64,80.41 91.74,80.51 91.95,80.51 92.05,80.41 92.05,80.06 92.15,79.96 92.35,79.96 92.46,80.06 92.46,80.41 92.56,80.51 92.76,80.51 92.86,80.41 92.86,80.06 92.96,79.96 93.17,79.96 93.27,80.06 93.27,80.41 93.37,80.51 93.57,80.51 93.67,80.41 93.67,80.06 93.78,79.96 97.73,79.96 97.93,79.77 97.94,79.77 99.39,78.32 99.63,78.32 101.39,76.56 105.19,76.56 105.79,75.96 106.32,75.96 107.29,75 107.29,74.09 v2(108.03,73.35)
  BOTTOM w0.089: v2(108.03,73.35) 108.35,73.67 CPU1.AP66 ; DM2.45 57.56,76.69 v2(57.32,76.44)
M_B_DQ22: length 64.7
  TOP w0.089: v1(52.4,72.94) 53.01,73.55 v2(53.01,73.75)
  L6 w0.102: v2(106.73,72.43) 106.32,72.84 105.58,72.84 105.33,73.09 105.05,73.09 104.49,73.65 102.56,73.65 99.54,76.67 98.68,76.67 97.03,78.32 91.02,78.32 89.7,77 76.73,77 73.46,73.73 71.47,73.73 70.76,73.02 64.06,73.02 63.96,73.12 63.96,73.6 63.86,73.7 63.65,73.7 63.55,73.6 63.55,73.12 63.45,73.02 55.27,73.02 54.79,73.5 54.79,74.16 54.58,74.36 53.62,74.36 v2(53.01,73.75)
  BOTTOM w0.089: CPU1.AT65 107.05,72.76 v2(106.73,72.43) ; v2(53.01,73.75) 52.55,73.3 52.07,73.3 51.93,73.44 DM2.58
M_B_DQ23: length 63.5
  TOP w0.089: v1(106.07,71.87) 106.07,72.43 v2(106.07,72.44)
  L6 w0.102: v2(106.07,72.44) 105.71,72.44 105.26,72.89 104.47,72.89 103.91,73.45 102.49,73.45 99.59,76.34 98.49,76.34 96.83,77.99 92.05,77.99 91.95,77.89 91.95,77.73 91.83,77.61 91.66,77.61 91.54,77.73 91.54,77.89 91.44,77.99 91.16,77.99 89.84,76.67 76.87,76.67 73.59,73.4 71.61,73.4 70.9,72.69 55.13,72.69 54.28,73.54 v2(54.28,73.7)
  BOTTOM w0.089: v2(54.28,73.7) 54.52,73.7 55.03,73.19 DM2.59 ; v2(106.07,72.44) 106.4,72.77 CPU1.AU65
M_B_DQ24: length 63.6
  TOP w0.089: v1(55.28,70.43) v2(55.28,69.83)
  L6 w0.102: v2(107.38,70.6) 106.79,71.19 105.74,71.19 105.4,70.84 104.97,70.84 104.56,71.26 104.56,71.28 104.09,71.75 102.33,71.75 101.83,72.25 101.83,72.69 99.79,74.72 97.58,74.72 97.28,75.01 77.56,75.01 74.15,71.6 72.86,71.6 71.36,70.1 58.5,70.1 58.34,69.94 58.34,69.71 58.22,69.59 58.05,69.59 57.93,69.71 57.93,70.28 57.83,70.38 55.83,70.38 v2(55.28,69.83)
  BOTTOM w0.089: v2(107.38,70.6) 107.05,70.93 CPU1.AT61 ; DM2.70 50.91,70.43 54.69,70.43 v2(55.28,69.83)
M_B_DQ25: length 62.8
  TOP w0.089: v1(56.71,70.43) v2(56.71,69.83)
  L6 w0.102: v2(56.71,69.83) 56.71,69.32 56.92,69.1 59.62,69.1 60.23,69.71 60.84,69.71 61.46,69.09 61.74,69.09 61.84,69.19 61.84,69.64 61.94,69.74 62.15,69.74 62.25,69.64 62.25,69.19 62.35,69.09 62.55,69.09 62.65,69.19 62.65,69.64 62.76,69.74 62.96,69.74 63.06,69.64 63.06,69.19 63.16,69.09 63.36,69.09 63.47,69.19 63.47,69.64 63.57,69.74 63.77,69.74 63.87,69.64 63.87,69.19 63.97,69.09 64.18,69.09 64.28,69.19 64.28,69.64 64.38,69.74 64.58,69.74 64.69,69.64 64.69,69.19 64.79,69.09 70.82,69.09 73,71.27 74.29,71.27 77.69,74.68 97.15,74.68 97.31,74.51 99.72,74.51 101.62,72.61 101.62,72.18 102.26,71.54 103.83,71.54 104.72,70.65 106.01,70.65 v2(106.04,70.63)
  BOTTOM w0.089: CPU1.AU61 106.04,70.69 v2(106.04,70.63) ; DM2.71 59,70.19 57.82,70.19 57.59,70.42 57.29,70.42 56.71,69.83 v2(56.71,69.83)
M_B_DQ26: length 66.7
  TOP w0.089: v2(56.66,66.84) 56.12,67.38 v1(55.75,67.38)
  L6 w0.102: v2(108.68,69.69) 108.32,69.33 107.01,69.33 106.63,68.95 105.36,68.95 105.11,68.71 104.66,68.71 103.05,70.32 101.65,70.32 99.79,72.18 95.86,72.18 95.08,72.96 78.28,72.96 73.91,68.59 73.77,68.59 73.32,69.04 73.16,69.04 73.04,68.92 73.04,68.75 73.48,68.31 73.48,68.16 73.33,68.02 73.19,68.02 72.75,68.46 72.61,68.46 72.46,68.32 72.46,68.17 72.9,67.73 72.9,67.59 72.77,67.45 65.34,67.45 64.83,66.95 62.31,66.95 61.77,66.41 60.04,66.41 59.94,66.51 59.94,66.82 59.84,66.92 59.63,66.92 59.53,66.82 59.53,66.51 59.43,66.41 59.23,66.41 59.13,66.51 59.13,66.82 59.02,66.92 58.82,66.92 58.72,66.82 58.72,66.51 58.62,66.41 58.42,66.41 58.31,66.51 58.31,66.82 58.21,66.92 58.01,66.92 57.91,66.82 57.91,66.51 57.81,66.41 57.09,66.41 v2(56.66,66.84)
  BOTTOM w0.089: v2(108.68,69.69) 108.35,70.01 CPU1.AP60 ; v2(56.66,66.84) 57.08,67.26 57.72,67.26 57.8,67.19 DM2.83
M_B_DQ27: length 66.4
  TOP w0.089: v1(52.39,66.26) v2(52.39,66.84)
  L6 w0.102: v2(52.39,66.84) 53.15,66.08 61.91,66.08 62.45,66.62 64.97,66.62 65.48,67.12 72.47,67.12 72.9,67.12 78.42,72.63 95.04,72.63 95.69,71.99 99.71,71.99 101.57,70.12 102.92,70.12 104.52,68.52 105.2,68.52 105.36,68.67 106.62,68.67 107.06,69.12 108.65,69.12 108.76,69.23 109.43,69.23 109.72,69.53 109.72,70.21 v2(109.33,70.6)
  BOTTOM w0.089: v2(52.39,66.84) 52.29,66.94 DM2.84 ; CPU1.AN60 109,70.28 v2(109.33,70.6)
M_B_DQ28: length 65.7
  TOP w0.089: v1(52.78,71.39) 53.07,71.69 v2(53.07,71.89)
  L6 w0.102: v2(108.68,70.6) 107.89,71.39 105.61,71.39 105.05,71.95 102.41,71.95 102.03,72.33 102.03,72.79 99.79,75.02 97.74,75.02 97.41,75.35 77.42,75.35 74.01,71.95 72.64,71.95 71.13,70.43 61.61,70.43 60.92,71.13 60.3,71.13 59.88,70.71 54.22,70.71 54.12,70.81 54.12,71.09 54,71.21 53.83,71.21 53.71,71.09 53.71,70.81 53.61,70.71 53.31,70.71 53.07,70.94 v2(53.07,71.89)
  BOTTOM w0.089: v2(108.68,70.6) 109,70.93 CPU1.AN61 ; v2(53.07,71.89) 53.07,71.89 52.62,71.44 DM2.66
M_B_DQ29: length 65.1
  TOP w0.089: v1(108.1,71.52) v2(108.68,71.52)
  L6 w0.102: v2(55.92,71.89) 55.92,71.22 56.1,71.04 56.48,71.04 56.58,71.14 56.58,71.34 56.68,71.44 56.88,71.44 56.98,71.34 56.98,71.14 57.09,71.04 57.29,71.04 57.39,71.14 57.39,71.34 57.49,71.44 57.69,71.44 57.8,71.34 57.8,71.14 57.9,71.04 58.1,71.04 58.2,71.14 58.2,71.34 58.3,71.44 58.51,71.44 58.61,71.34 58.61,71.14 58.71,71.04 58.91,71.04 59.02,71.14 59.02,71.3 59.13,71.42 59.3,71.42 59.42,71.3 59.42,71.14 59.52,71.04 59.75,71.04 60.16,71.46 61.12,71.46 61.82,70.76 70.99,70.76 72.51,72.28 73.88,72.28 77.28,75.68 97.54,75.68 97.87,75.35 99.74,75.35 102.23,72.86 102.23,72.41 102.49,72.15 105.13,72.15 105.69,71.59 108.6,71.59 v2(108.68,71.52)
  BOTTOM w0.089: v2(55.92,71.89) 56.93,70.88 57.77,70.88 58.08,71.19 DM2.67 ; CPU1.AP61 108.35,71.19 v2(108.68,71.52)
M_B_DQ30: length 65.5
  TOP w0.089: v1(55.23,66.26) v2(55.23,66.84)
  L6 w0.102: v2(106.73,69.69) 106.26,69.22 105.42,69.22 105.03,69.61 104.39,69.61 103.48,70.53 101.96,70.53 100.51,71.98 100.51,72.43 99.26,73.68 95.51,73.68 95.12,73.3 78.14,73.3 74.82,69.98 73.53,69.98 71.36,67.8 71.32,67.8 71.31,67.78 63.99,67.78 63.89,67.68 63.89,67.38 63.78,67.28 63.58,67.28 63.48,67.38 63.48,67.68 63.38,67.78 63.17,67.78 63.07,67.68 63.07,67.38 62.97,67.28 62.77,67.28 62.67,67.38 62.67,67.68 62.57,67.78 62.42,67.78 61.9,67.27 61.63,67.27 61.53,67.17 61.53,66.84 61.43,66.74 61.22,66.74 61.12,66.84 61.12,67.17 61.02,67.27 60.82,67.27 60.71,67.17 60.71,66.84 60.61,66.74 60.41,66.74 60.31,66.84 60.31,67.17 60.21,67.27 55.66,67.27 v2(55.23,66.84)
  BOTTOM w0.089: v2(106.73,69.69) 107.05,70.01 CPU1.AT60 ; DM2.79 58.95,68.19 58.93,68.16 58.21,68.16 58.11,68.27 56.66,68.27 v2(55.23,66.84)
M_B_DQ31: length 64.7
  TOP w0.089: v1(53.81,66.26) v2(53.81,66.84)
  L6 w0.102: v2(53.81,66.84) 53.81,67.47 53.97,67.63 58.58,67.63 58.69,67.73 58.69,67.87 58.8,67.99 58.97,67.99 59.09,67.87 59.09,67.73 59.19,67.63 59.4,67.63 59.5,67.73 59.5,68.01 59.6,68.11 59.8,68.11 59.9,68.01 59.9,67.73 60.01,67.63 60.21,67.63 60.31,67.73 60.31,68.01 60.41,68.11 60.62,68.11 60.72,68.01 60.72,67.73 60.82,67.63 61.02,67.63 61.12,67.73 61.12,68.01 61.23,68.11 61.43,68.11 61.53,68.01 61.53,67.73 61.63,67.63 61.8,67.63 62.28,68.11 71.17,68.11 71.18,68.13 71.22,68.13 73.4,70.31 74.69,70.31 78,73.63 95.1,73.63 95.35,73.88 99.32,73.88 100.99,72.21 100.99,71.81 101.92,70.88 103.41,70.88 104.43,69.87 105.36,69.87 105.61,69.61 v2(105.99,69.61)
  BOTTOM w0.089: CPU1.AU60 106,69.74 106,69.67 105.99,69.66 v2(105.99,69.61) ; DM2.80 52.71,67.94 v2(53.81,66.84)
M_B_DQ32: length 65.4
  TOP w0.089: v1(54.23,43.5) 54,43.27 v2(54,42.97)
  L6 w0.102: v2(54,42.97) 55.01,41.95 58.14,41.95 58.14,41.95 58.18,41.95 58.7,41.43 71.23,41.43 71.65,41.01 76.77,41.01 89.35,53.59 93.37,53.59 96.92,57.14 102.92,57.14 104.44,58.67 106.66,58.67 v2(106.68,58.69)
  BOTTOM w0.089: v2(106.68,58.69) 106.4,58.96 CPU1.AU40 ; v2(54,42.97) 53.45,42.97 52.92,42.43 50.9,42.43 DM2.174
M_B_DQ33: length 65.9
  TOP w0.089: v1(55.42,43.15) 55.29,43.02 v2(55.29,42.59)
  L6 w0.102: v2(107.33,59.63) 106.65,59.63 106.13,59.11 105.62,59.11 105.04,59.7 104.68,59.7 102.53,57.55 96.67,57.55 93.46,54.34 89.16,54.34 76.92,42.09 58.98,42.09 57.92,43.15 55.62,43.15 55.29,42.82 v2(55.29,42.59)
  BOTTOM w0.089: v2(107.33,59.63) 107.05,59.36 CPU1.AT40 ; v2(55.29,42.59) 55.29,42.51 55.52,42.28 57.48,42.28 57.86,42.66 59.08,42.66 DM2.173
M_B_DQ34: length 67.8
  TOP w0.089: v1(58.55,39.36) 58.22,39.69 v2(57.1,39.69)
  L6 w0.102: v2(107.38,57.8) 107.33,57.85 106.35,57.85 106.16,58.04 104.91,58.04 103.53,56.66 103.53,56.52 102.66,55.64 98.8,55.64 98.65,55.8 96.59,55.8 93.43,52.63 92.25,52.63 92.1,52.48 89.65,52.48 89.38,52.2 89.38,52.06 89.73,51.71 89.73,51.57 89.58,51.42 89.44,51.42 89.09,51.77 88.95,51.77 88.8,51.63 88.8,51.49 89.15,51.14 89.15,50.99 89.01,50.85 88.86,50.85 88.52,51.2 88.37,51.2 88.23,51.05 88.23,50.91 88.58,50.56 88.58,50.42 88.43,50.27 88.29,50.27 87.94,50.62 87.8,50.62 87.65,50.48 87.65,50.34 88,49.99 88,49.84 87.86,49.7 87.71,49.7 87.37,50.05 87.22,50.05 87.08,49.9 87.08,49.76 87.2,49.64 87.2,49.47 87.08,49.35 86.91,49.35 86.79,49.47 86.65,49.47 76.99,39.82 65.14,39.82 64.91,39.59 57.2,39.59 v2(57.1,39.69)
  BOTTOM w0.089: v2(107.38,57.8) 107.38,57.67 CPU1.AT37 ; DM2.187 57.6,39.19 v2(57.1,39.69)
M_B_DQ35: length 66.4
  TOP w0.089: v1(106.42,57.42) 106.42,57.21 v2(106.74,56.89)
  L6 w0.102: v2(106.74,56.89) 105.97,57.66 105.1,57.66 104.24,56.81 104.24,56.69 102.81,55.26 98.63,55.26 98.52,55.36 97.13,55.36 94.01,52.25 92.65,52.25 92.22,51.82 91.95,51.82 90.93,51.82 87.69,48.58 86.69,48.58 77.27,39.16 71.68,39.16 71.12,38.6 69.49,38.6 68.94,39.16 65.43,39.16 65.2,38.93 55.97,38.93 55.36,39.54 53.97,39.54 v2(53.49,39.06)
  BOTTOM w0.089: v2(53.49,39.06) 53.13,39.06 52.75,39.44 DM2.186 ; CPU1.AU37 106.4,57.23 v2(106.74,56.89)
M_B_DQ36: length 66.6
  TOP w0.089: v2(52.54,43.48) 52.91,43.84 v1(52.91,43.93)
  L6 w0.102: v2(108.01,59.63) 107.61,60.03 104.74,60.03 102.47,57.75 96.57,57.75 93.48,54.67 89.03,54.67 76.78,42.42 59.11,42.42 58.06,43.48 54,43.48 53.56,43.91 52.97,43.91 v2(52.54,43.48)
  BOTTOM w0.089: CPU1.AR40 107.7,59.32 v2(108.01,59.63) ; v2(52.54,43.48) 52.49,43.43 50.91,43.43 DM2.170
M_B_DQ37: length 67.6
  TOP w0.089: v2(108.67,59.63) 109.04,59.26 v1(109.04,59.17)
  L6 w0.102: v2(56.61,42.71) 57.05,42.28 58.28,42.28 58.32,42.28 58.84,41.76 71.8,41.76 71.9,41.66 71.9,41.44 72,41.34 72.2,41.34 72.3,41.44 72.3,41.66 72.41,41.76 72.61,41.76 72.71,41.66 72.71,41.44 72.81,41.34 73.02,41.34 73.12,41.44 73.12,41.66 73.22,41.76 73.42,41.76 73.52,41.66 73.52,41.44 73.62,41.34 73.83,41.34 73.93,41.44 73.93,41.66 74.03,41.76 74.23,41.76 74.34,41.66 74.34,41.44 74.44,41.34 74.64,41.34 74.74,41.44 74.74,41.66 74.84,41.76 75.05,41.76 75.15,41.66 75.15,41.44 75.25,41.34 75.45,41.34 75.56,41.44 75.56,41.66 75.66,41.76 75.86,41.76 75.96,41.66 75.96,41.44 76.06,41.34 76.27,41.34 76.37,41.44 76.37,41.66 76.47,41.76 77.06,41.76 89.21,53.92 93.39,53.92 96.82,57.34 102.84,57.34 104.37,58.87 106.3,58.87 106.61,59.19 108.23,59.19 v2(108.67,59.63)
  BOTTOM w0.089: CPU1.AP40 108.35,59.31 v2(108.67,59.63) ; DM2.169 57.56,43.69 56.69,42.82 56.69,42.79 v2(56.61,42.71)
M_B_DQ38: length 68.4
  TOP w0.089: v1(108.35,57.34) 108.35,57.48 v2(108.68,57.8)
  L6 w0.102: v2(108.68,57.8) 108.17,57.29 107.75,57.29 107.64,57.18 106.94,56.48 106.55,56.48 106.18,56.85 105.62,56.85 105.48,56.99 104.69,56.99 104.44,56.74 104.44,56.62 102.89,55.07 98.54,55.07 98.47,55.13 97.39,55.13 93.67,51.41 93.15,51.41 92.95,51.61 92.47,51.61 92.36,51.49 91.81,51.49 91.06,51.49 87.83,48.25 86.83,48.25 77.4,38.83 71.81,38.83 71.2,38.22 65.17,38.22 64.79,38.6 55.68,38.6 v2(55.17,39.11)
  BOTTOM w0.089: v1(108.35,57.34) 108.35,57.48 v2(108.68,57.8) ; v2(55.17,39.11) 55.17,39.34 56.02,40.19 DM2.183
M_B_DQ39: length 68.9
  TOP w0.089: v1(54.23,41.7) 54.41,41.52 54.41,40.77 v2(54.03,40.4)
  L6 w0.102: v2(108.03,57.8) 107.95,57.8 107.56,57.41 107.21,57.41 106.96,57.66 106.27,57.66 106.08,57.85 104.99,57.85 103.73,56.6 103.73,56.45 102.73,55.45 98.72,55.45 98.56,55.6 96.78,55.6 93.62,52.44 92.37,52.44 92.08,52.15 90.79,52.15 87.55,48.91 86.55,48.91 77.13,39.49 65.28,39.49 65.05,39.26 56.11,39.26 55.68,39.69 55.68,40.25 55.55,40.38 55.24,40.38 55.12,40.25 55.12,40 54.99,39.87 54.57,39.87 v2(54.03,40.4)
  BOTTOM w0.089: CPU1.AR37 108.03,57.67 v2(108.03,57.8) ; v2(54.03,40.4) 54,40.44 DM2.182
M_B_DQ40: length 68.8
  TOP w0.089: v1(106.81,55.44) 106.84,55.44 v2(107.38,55.97)
  L6 w0.102: v2(56.34,37.43) 56.79,37.89 59.6,37.89 59.7,37.79 59.7,37.46 59.8,37.35 60,37.35 60.1,37.46 60.1,37.79 60.2,37.89 60.41,37.89 60.51,37.79 60.51,37.46 60.61,37.35 60.81,37.35 60.92,37.46 60.92,37.79 61.02,37.89 61.22,37.89 61.32,37.79 61.32,37.46 61.42,37.35 61.63,37.35 61.73,37.46 61.73,37.79 61.83,37.89 62.03,37.89 62.14,37.79 62.14,37.46 62.24,37.35 62.44,37.35 62.54,37.46 62.54,37.79 62.64,37.89 62.86,37.89 63.37,37.38 71.31,37.38 72.09,38.17 72.25,38.17 72.35,38.07 72.35,37.18 72.45,37.08 72.65,37.08 72.75,37.18 72.75,38.07 72.86,38.17 77.68,38.17 87.1,47.59 88.1,47.59 90.83,50.32 93.68,50.32 97.03,53.66 102.36,53.66 104.66,55.96 105.45,55.96 105.58,55.83 105.91,55.83 106.15,56.07 107.28,56.07 v2(107.38,55.97)
  BOTTOM w0.089: DM2.195 57.82,37.19 57.7,37.3 56.46,37.3 v2(56.34,37.43) ; v2(107.38,55.97) 107.05,55.65 CPU1.AT33
M_B_DQ41: length 68.6
  TOP w0.089: v1(52.42,37.48) 52.58,37.48 v2(53.19,36.87)
  L6 w0.102: v2(53.19,36.87) 53.2,36.87 53.45,36.62 54.43,36.62 54.68,36.37 62.76,36.37 63.07,36.37 63.07,36.37 63.63,36.37 63.9,36.1 64.71,36.1 64.81,36 64.81,35.72 64.93,35.6 65.1,35.6 65.22,35.72 65.22,36 65.32,36.1 65.53,36.1 65.63,36 65.63,35.4 65.73,35.3 65.93,35.3 66.03,35.4 66.03,36 66.13,36.1 66.34,36.1 66.44,36 66.44,35.4 66.54,35.3 66.74,35.3 66.85,35.4 66.85,36 66.95,36.1 70.89,36.1 71.21,36.41 72.96,36.41 74.05,37.51 77.95,37.51 87.37,46.93 88.37,46.93 91.1,49.66 94.12,49.66 97.65,53.19 97.67,53.19 97.69,53.2 102.51,53.2 104.49,55.18 v2(106.01,55.18)
  BOTTOM w0.089: v2(53.19,36.87) 52.62,37.44 DM2.194 ; CPU1.AU33 106.38,55.52 106.04,55.18 v2(106.01,55.18)
M_B_DQ42: length 67.1
  TOP w0.089: v2(106.73,54.14) 106.78,54.09 v1(106.78,53.59)
  L6 w0.102: v2(106.73,54.14) 105.69,54.14 105.13,53.59 104.84,53.59 102.94,51.68 100.08,51.68 99.74,51.35 99.74,51.28 99.4,50.93 97.73,50.93 94.06,47.26 93.27,47.26 93.17,47.36 93.17,47.77 93.07,47.87 92.86,47.87 92.76,47.77 92.76,47.36 92.66,47.26 92.46,47.26 92.36,47.36 92.36,47.77 92.25,47.87 92.05,47.87 91.95,47.77 91.95,47.36 91.85,47.26 91.59,47.26 91.21,46.88 90.16,46.88 88.91,45.64 87.91,45.64 78.49,36.21 76.04,36.21 73.99,34.16 68.95,34.16 68.26,33.47 63.77,33.47 62.18,35.07 56.21,35.07 55.8,34.66 55.8,34.66 v2(55.75,34.61)
  BOTTOM w0.089: v2(106.73,54.14) 106.4,53.82 CPU1.AU30 ; DM2.207 59.07,34.15 56.21,34.15 v2(55.75,34.61)
M_B_DQ43: length 68.1
  TOP w0.089: v1(54.48,34.15) v2(54.48,34.71)
  L6 w0.102: v2(54.48,34.71) 54.51,34.71 55.19,35.4 62.36,35.4 63.95,33.8 64.22,33.8 64.32,33.91 64.32,34.03 64.43,34.13 64.63,34.13 64.73,34.03 64.73,33.91 64.83,33.8 68.13,33.8 68.82,34.49 73.85,34.49 75.9,36.54 78.35,36.54 87.77,45.97 88.77,45.97 91.02,48.21 93.74,48.21 94.36,48.84 95.1,48.84 98.13,51.87 102.71,51.87 104.63,53.79 105.05,53.79 105.61,54.34 106.32,54.34 106.51,54.54 106.92,54.54 107.31,54.14 v2(107.38,54.14)
  BOTTOM w0.089: v2(107.38,54.14) 107.38,54.13 107.05,53.81 CPU1.AT30 ; v2(54.48,34.71) 53.69,33.93 50.91,33.93 DM2.208
M_B_DQ44: length 69.6
  TOP w0.089: v1(107.34,56.56) 107.43,56.56 v2(108.02,55.97)
  L6 w0.102: v2(54.99,37.48) 55.73,38.22 63.86,38.22 63.96,38.12 63.96,37.81 64.06,37.71 64.27,37.71 64.37,37.81 64.37,38.12 64.47,38.22 64.71,38.22 65.16,37.76 71.22,37.76 71.96,38.5 77.54,38.5 86.96,47.92 87.96,47.92 90.69,50.65 91.27,50.65 91.37,50.75 91.37,51.05 91.47,51.15 91.68,51.15 91.78,51.05 91.78,50.75 91.88,50.65 93.4,50.65 97.24,54.49 97.24,54.71 97.47,54.94 97.8,54.94 97.97,54.77 103.14,54.77 104.52,56.15 105.03,56.15 105.51,56.63 106.04,56.63 106.38,56.29 107.1,56.29 107.19,56.38 107.61,56.38 v2(108.02,55.97)
  BOTTOM w0.089: CPU1.AR33 107.7,55.65 v2(108.02,55.97) ; DM2.191 57.12,38.19 56.89,38.42 55.92,38.42 54.99,37.48 v2(54.99,37.48)
M_B_DQ45: length 71.5
  TOP w0.089: v1(52.93,36.36) 53.29,36.36 53.77,36.85 53.97,36.85 54.28,37.15 v2(54.43,37.15)
  L6 w0.102: v2(54.43,37.15) 54.86,36.72 56.67,36.72 57.2,37.25 58.85,37.25 59.08,37.02 59.89,37.02 59.99,36.92 59.99,36.82 60.09,36.72 60.3,36.72 60.4,36.82 60.4,36.92 60.5,37.02 60.7,37.02 60.81,36.92 60.81,36.82 60.91,36.72 61.11,36.72 61.21,36.82 61.21,36.92 61.31,37.02 61.52,37.02 61.62,36.92 61.62,36.82 61.72,36.72 61.92,36.72 62.03,36.82 62.03,36.92 62.13,37.02 62.33,37.02 62.43,36.92 62.43,36.82 62.53,36.72 62.74,36.72 62.84,36.82 62.84,36.92 62.94,37.02 65.61,37.02 65.63,37.05 71.09,37.05 71.39,36.75 72.82,36.75 73.91,37.84 77.81,37.84 87.24,47.26 88.24,47.26 90.96,49.99 93.94,49.99 97.36,53.41 102.41,53.41 104.38,55.37 105.65,55.37 105.91,55.64 105.99,55.64 106.12,55.64 106.36,55.88 106.91,55.88 107.21,55.58 107.23,55.58 107.25,55.56 108.29,55.56 v2(108.65,55.93)
  BOTTOM w0.089: v2(108.65,55.93) 108.35,55.63 CPU1.AP33 ; v2(54.43,37.15) 54.43,38.1 54.1,38.44 DM2.190
M_B_DQ46: length 68.4
  TOP w0.089: v1(56.39,35.2) v2(56.39,34.64)
  L6 w0.102: v2(108.03,54.14) 107.63,53.75 106.41,53.75 106.33,53.84 105.66,53.84 105.21,53.38 104.94,53.38 102.3,50.74 97.81,50.74 94,46.93 91.76,46.93 91.38,46.55 90.29,46.55 89.05,45.3 88.05,45.3 78.62,35.88 76.17,35.88 73.33,33.04 71.67,33.04 71.57,33.14 71.57,33.47 71.46,33.57 71.26,33.57 71.16,33.47 71.16,33.14 71.06,33.04 70.86,33.04 70.75,33.14 70.75,33.47 70.65,33.57 70.45,33.57 70.35,33.47 70.35,33.14 70.25,33.04 70.04,33.04 69.94,33.14 69.94,33.47 69.84,33.57 69.64,33.57 69.53,33.47 69.53,33.14 69.43,33.04 69.06,33.04 68.38,32.36 66.6,32.36 66.55,32.31 64.41,32.31 62.53,34.18 56.84,34.18 v2(56.39,34.64)
  BOTTOM w0.089: DM2.203 58.02,35.19 57.95,35.25 57,35.25 v2(56.39,34.64) ; CPU1.AR30 108.03,54.01 v2(108.03,54.14)
M_B_DQ47: length 69.4
  TOP w0.089: v1(53.18,34.08) v2(53.18,34.65)
  L6 w0.102: v2(53.18,34.65) 53.98,33.85 62.3,33.85 64.18,31.98 66.7,31.98 66.75,32.03 72.8,32.03 76.33,35.55 78.76,35.55 88.18,44.97 89.18,44.97 90.43,46.22 91.51,46.22 91.84,46.55 93.89,46.55 97.85,50.51 102.38,50.51 105,53.13 105.31,53.13 105.81,53.63 106.25,53.63 106.32,53.56 108.09,53.56 v2(108.68,54.14)
  BOTTOM w0.089: v2(53.18,34.65) 52.89,34.94 50.9,34.94 DM2.204 ; CPU1.AP30 108.35,53.82 v2(108.68,54.14)
M_B_DQ48: length 70.5
  TOP w0.089: v2(53.68,31.8) 53.16,31.8 v1(53.08,31.87)
  L6 w0.102: v2(106.04,51.4) 105.56,51.4 105.31,51.15 104.41,51.15 104.36,51.1 104.34,51.1 103.12,49.88 103.12,48.78 102.31,47.97 97.94,47.97 94.43,44.47 91.65,44.47 90.83,43.65 88.73,43.65 79.31,34.23 76.87,34.23 72.97,30.33 71.66,30.33 70.92,29.59 64.58,29.59 62.46,31.72 61.37,31.72 61.27,31.61 61.27,30.93 61.17,30.83 60.97,30.83 60.86,30.93 60.86,31.61 60.76,31.72 60.56,31.72 60.46,31.61 60.46,30.93 60.36,30.83 60.15,30.83 60.05,30.93 60.05,31.61 59.95,31.72 55.73,31.72 55.15,32.3 54.19,32.3 v2(53.68,31.8)
  BOTTOM w0.089: v2(53.68,31.8) 53.54,31.94 50.9,31.94 DM2.216 ; v2(106.04,51.4) 106.4,51.76 CPU1.AU27
M_B_DQ49: length 71
  TOP w0.089: v1(106.73,51.73) v2(106.73,52.31)
  L6 w0.102: v2(54.9,33.01) 55.87,32.05 59.43,32.05 59.53,32.15 59.53,32.73 59.63,32.83 59.83,32.83 59.94,32.73 59.94,32.15 60.04,32.05 60.24,32.05 60.34,32.15 60.34,32.73 60.44,32.83 60.65,32.83 60.75,32.73 60.75,32.15 60.85,32.05 62.59,32.05 64.19,30.45 67.93,30.45 68.28,30.1 70.87,30.1 71.44,30.66 72.84,30.66 76.74,34.56 79.17,34.56 88.59,43.98 90.7,43.98 91.51,44.8 94.43,44.8 95.76,46.12 95.76,46.83 98.13,49.2 102.14,49.2 104.29,51.35 105.18,51.35 105.64,51.81 106.22,51.81 v2(106.73,52.31)
  BOTTOM w0.089: v2(54.9,33.01) 55.73,32.19 DM2.215 ; CPU1.AT27 107.05,51.99 v2(106.73,52.31)
M_B_DQ50: length 69.5
  TOP w0.089: v1(107.62,50.87) 107.62,51.16 v2(107.38,51.4)
  L6 w0.102: v2(54.53,30.14) 55.29,29.38 63.02,29.38 63.78,28.62 64.6,28.62 64.7,28.52 64.7,28.31 64.8,28.21 65,28.21 65.11,28.31 65.11,28.52 65.21,28.62 71.33,28.62 72.05,29.34 73.4,29.34 77.32,33.27 79.71,33.27 89.13,42.69 91.23,42.69 91.92,43.37 94.26,43.37 96.44,45.56 97.64,45.56 99.05,46.97 102.21,46.97 103.81,48.57 103.81,49.5 104.87,50.57 106.35,50.57 107.18,51.4 v2(107.38,51.4)
  BOTTOM w0.089: CPU1.AT25 107.05,51.07 v2(107.38,51.4) ; v2(54.53,30.14) 53.21,28.82 52.48,28.82 52.37,28.93 DM2.228
M_B_DQ51: length 68.9
  TOP w0.089: v1(56.58,28.72) v2(56.58,28.14)
  L6 w0.102: v2(56.58,28.14) 57.11,28.67 58.26,28.67 58.36,28.57 58.36,28.34 58.46,28.24 58.66,28.24 58.76,28.34 58.76,28.57 58.87,28.67 59.07,28.67 59.17,28.57 59.17,28.34 59.27,28.24 59.47,28.24 59.58,28.34 59.58,28.57 59.68,28.67 62.75,28.67 64.22,27.19 72.19,27.19 77.6,32.6 79.98,32.6 89.41,42.03 91.51,42.03 91.74,42.26 95.02,42.26 96.06,43.3 96.59,43.3 99.7,46.4 102.18,46.4 104.27,48.49 104.27,49.42 105.03,50.19 106.88,50.19 107.17,50.47 107.71,50.49 v2(108.03,50.49)
  BOTTOM w0.089: v2(56.58,28.14) 57.13,28.68 DM2.229 ; v2(108.03,50.49) 106.96,50.49 106.5,50.94 CPU1.AU25
M_B_DQ52: length 71.4
  TOP w0.089: v1(55.52,32.74) v2(56.1,32.74)
  L6 w0.102: v2(56.1,32.74) 56.53,33.17 57.54,33.17 57.64,33.07 57.64,32.71 57.74,32.6 57.95,32.6 58.05,32.71 58.05,33.07 58.15,33.17 58.35,33.17 58.45,33.07 58.45,32.71 58.56,32.6 58.76,32.6 58.86,32.71 58.86,33.07 58.96,33.17 62.02,33.17 64.36,30.83 68.12,30.83 68.28,30.99 69.87,30.99 69.97,31.09 69.97,31.26 70.07,31.36 70.28,31.36 70.38,31.26 70.38,31.09 70.48,30.99 70.68,30.99 70.79,31.09 70.79,31.26 70.89,31.36 71.09,31.36 71.19,31.26 71.19,31.09 71.29,30.99 71.5,30.99 71.6,31.09 71.6,31.26 71.7,31.36 71.9,31.36 72.01,31.26 72.01,31.09 72.11,30.99 72.7,30.99 76.6,34.89 79.03,34.89 88.46,44.31 90.56,44.31 91.37,45.13 94.49,45.13 95.38,46.01 95.38,47.06 97.74,49.42 102.06,49.42 102.52,49.88 102.52,49.9 104.77,52.15 105.47,52.15 105.6,52.02 105.98,52.02 106.3,52.34 106.3,52.44 106.57,52.71 108.29,52.71 v2(108.68,52.31)
  BOTTOM w0.089: CPU1.AP27 108.35,51.99 v2(108.68,52.31) ; v2(56.1,32.74) 56.56,33.2 56.57,33.19 DM2.211
M_B_DQ53: length 71.9
  TOP w0.089: v1(51.76,32.94) v2(52.34,32.94)
  L6 w0.102: v2(52.34,32.94) 52.9,33.5 62.18,33.5 64.51,31.16 64.99,31.16 65.09,31.26 65.09,31.54 65.19,31.64 65.39,31.64 65.49,31.54 65.49,31.26 65.6,31.16 65.8,31.16 65.9,31.26 65.9,31.54 66,31.64 66.21,31.64 66.31,31.54 66.31,31.26 66.41,31.16 67.99,31.16 68.52,31.7 68.81,31.7 68.91,31.6 68.91,31.45 69.03,31.33 69.2,31.33 69.32,31.45 69.32,31.6 69.42,31.7 72.94,31.7 76.46,35.22 78.9,35.22 88.32,44.64 90.42,44.64 91.24,45.46 93.06,45.46 97.24,49.63 102,49.63 102.3,49.93 102.3,49.96 105.18,52.83 106.28,52.83 106.35,52.9 108.43,52.9 108.51,52.82 108.82,52.82 v2(109.33,52.31)
  BOTTOM w0.089: v2(109.33,52.31) 109,51.99 CPU1.AN27 ; DM2.212 50.9,32.94 52.33,32.94 v2(52.34,32.94)
M_B_DQ54: length 71.7
  TOP w0.089: v2(53.07,30.22) 53.07,30.31 v1(53.44,30.67)
  L6 w0.102: v2(53.07,30.22) 53.07,29.87 55.29,27.65 63.3,27.65 64.13,26.81 72.27,26.81 77.73,32.27 80.12,32.27 89.54,41.7 91.64,41.7 91.87,41.93 96.14,41.93 97.59,43.37 100.99,43.37 103.16,45.54 103.16,47.11 105.43,49.38 105.43,49.48 105.95,50 106.96,50 107.12,50.16 107.77,50.16 107.83,50.09 108.28,50.09 v2(108.68,50.49)
  BOTTOM w0.089: v2(53.07,30.22) 52.64,29.78 52.12,29.78 51.96,29.94 50.9,29.94 DM2.224 ; v2(108.68,50.49) 109,50.81 CPU1.AN25
M_B_DQ55: length 70.9
  TOP w0.089: v1(54.71,28.29) v2(55.27,28.29)
  L6 w0.102: v2(55.27,28.29) 56.03,29.05 62.84,29.05 63.73,28.16 63.88,28.16 63.99,28.27 64.13,28.27 64.27,28.12 64.27,27.98 64.16,27.87 64.16,27.72 64.36,27.52 72.05,27.52 77.46,32.94 79.85,32.94 89.27,42.36 91.37,42.36 91.6,42.59 94.97,42.59 95.88,43.5 96.19,43.5 99.39,46.71 102.21,46.71 104.06,48.56 104.06,49.49 104.95,50.38 106.52,50.38 107.11,50.97 108.25,50.97 v2(108.68,51.4)
  BOTTOM w0.089: v2(55.27,28.29) 55.27,28.41 56.54,29.69 56.88,29.69 DM2.225 ; CPU1.AP25 108.35,51.08 v2(108.68,51.4)
M_B_DQ56: length 73.8
  TOP w0.089: v2(56.82,26.43) 57,26.25 v1(57,25.9)
  L6 w0.102: v2(56.82,26.43) 56.82,26.05 57.07,25.8 59.44,25.8 59.54,25.9 59.54,26.86 59.64,26.97 59.85,26.97 59.95,26.86 59.95,25.9 60.05,25.8 61.16,25.8 61.27,25.9 61.27,26.89 61.37,26.99 61.57,26.99 61.67,26.89 61.67,25.9 61.77,25.8 61.98,25.8 62.08,25.9 62.08,26.89 62.18,26.99 62.38,26.99 62.49,26.89 62.49,25.9 62.59,25.8 62.83,25.8 62.93,25.9 62.93,26.61 63.03,26.71 63.24,26.71 63.34,26.61 63.34,25.9 63.44,25.8 64.17,25.8 64.47,25.5 71.62,25.5 71.62,25.5 71.89,25.5 78.01,31.61 80.39,31.61 89.51,40.73 95.6,40.73 97.76,42.89 101.06,42.89 103.62,45.45 103.62,47.04 105.52,48.94 106.31,48.94 106.92,49.55 107.35,49.55 v2(107.38,49.57)
  BOTTOM w0.089: DM2.237 57.8,26.68 57.63,26.86 57.24,26.86 v2(56.82,26.43) ; CPU1.AT22 107.05,49.25 v2(107.38,49.57)
M_B_DQ57: length 73.2
  TOP w0.089: v1(105.26,48.78) 105.51,48.53 v2(105.8,48.53)
  L6 w0.102: v2(105.8,48.53) 105.39,48.53 103.84,46.98 103.84,45.39 101.14,42.69 98.83,42.69 96.47,40.33 94.06,40.33 93.96,40.22 93.96,39.62 93.86,39.51 93.65,39.51 93.55,39.62 93.55,40.22 93.45,40.33 92.3,40.33 92.2,40.22 92.2,39.64 92.09,39.54 91.89,39.54 91.79,39.64 91.79,40.22 91.69,40.33 91.48,40.33 91.38,40.22 91.38,39.64 91.28,39.54 91.08,39.54 90.98,39.64 90.98,40.22 90.88,40.33 90.67,40.33 90.57,40.22 90.57,39.64 90.47,39.54 90.27,39.54 90.16,39.64 90.16,40.22 90.06,40.33 89.57,40.33 80.53,31.28 78.14,31.28 71.91,25.05 60.28,25.05 59.87,25.47 56.51,25.47 v2(55.55,26.43)
  BOTTOM w0.089: DM2.236 50.9,26.94 54.76,26.94 55.26,26.43 v2(55.55,26.43) ; v2(105.8,48.53) 105.81,48.53 106.4,49.11 CPU1.AU22
M_B_DQ58: length 72.2
  TOP w0.089: v1(106.35,48.18) 106.35,48.13 v2(106.73,47.74)
  L6 w0.102: v2(56.89,23.28) 57.45,23.84 58.96,23.84 59.16,23.65 73.34,23.65 76.67,26.97 76.81,26.97 77.32,26.46 77.47,26.46 77.61,26.6 77.61,26.75 77.1,27.26 77.1,27.4 77.24,27.55 77.39,27.55 77.9,27.03 78.04,27.03 78.19,27.18 78.19,27.32 77.67,27.83 77.67,27.98 77.82,28.12 77.96,28.12 78.47,27.61 78.62,27.61 78.76,27.75 78.76,27.9 78.25,28.41 78.25,28.55 78.39,28.7 78.54,28.7 79.05,28.18 79.19,28.18 79.34,28.33 79.34,28.47 78.82,28.98 78.82,29.13 78.97,29.27 79.11,29.27 79.62,28.76 79.77,28.76 79.91,28.9 79.91,29.05 79.4,29.56 79.4,29.7 79.68,29.99 81.07,29.99 89.27,38.19 96.26,38.19 99.81,41.74 101.43,41.74 104.87,45.18 104.87,45.84 106.73,47.69 v2(106.73,47.74)
  BOTTOM w0.089: v2(106.73,47.74) 106.73,47.74 106.4,48.07 CPU1.AU21 ; DM2.249 57.3,23.68 v2(56.89,23.28)
M_B_DQ59: length 73.2
  TOP w0.089: v1(51.79,23.38) v2(52.37,23.38)
  L6 w0.102: v2(107.38,47.74) 106.87,47.24 106.57,47.24 105.96,46.63 105.94,46.63 105.08,45.76 105.08,45.1 101.4,41.42 101.27,41.42 100.73,40.89 99.42,40.89 96.4,37.86 89.41,37.86 77.67,26.13 76.29,26.13 73.48,23.32 71.43,23.32 70.79,22.67 64.71,22.67 64.61,22.78 64.61,23.16 64.51,23.26 64.31,23.26 64.2,23.16 64.2,22.78 64.1,22.67 63.9,22.67 63.8,22.78 63.8,23.16 63.7,23.26 63.49,23.26 63.39,23.16 63.39,22.78 63.29,22.67 63.09,22.67 62.99,22.78 62.99,23.16 62.88,23.26 62.68,23.26 62.58,23.16 62.58,22.78 62.48,22.67 61.5,22.67 61.4,22.78 61.4,23.21 61.3,23.31 61.08,23.31 60.99,23.21 60.99,22.78 60.89,22.67 56.89,22.67 56.41,23.15 56.41,23.48 56.03,23.87 52.85,23.87 v2(52.37,23.38)
  BOTTOM w0.089: DM2.250 52.31,23.44 v2(52.37,23.38) ; CPU1.AT21 107.05,48.07 v2(107.38,47.74)
M_B_DQ60: length 75.5
  TOP w0.089: v1(53.34,28.9) 53.01,28.57 v2(53.01,28.36)
  L6 w0.102: v2(53.01,28.36) 53.01,27.58 53.34,27.25 54.35,27.25 55.12,26.48 55.12,25.54 55.52,25.14 59.66,25.14 60.15,24.65 71.98,24.65 72.43,25.1 72.57,25.1 72.88,24.78 73.03,24.78 73.17,24.93 73.17,25.07 72.86,25.39 72.86,25.53 78.28,30.95 80.67,30.95 88.9,39.18 94.35,39.18 94.45,39.29 94.45,39.87 94.55,39.97 94.75,39.97 94.85,39.87 94.85,39.29 94.96,39.18 95.71,39.18 99.02,42.5 101.25,42.5 104.04,45.28 104.04,46.91 105.25,48.12 105.95,48.12 106.88,49.06 108.17,49.06 v2(108.68,49.57)
  BOTTOM w0.089: DM2.232 50.9,27.94 52.62,27.94 53.01,28.33 v2(53.01,28.36) ; CPU1.AN22 109,49.25 v2(108.68,49.57)
M_B_DQ61: length 75.4
  TOP w0.089: v2(55.27,27.07) 55.09,26.89 55.09,26.2 v1(55.04,26.15)
  L6 w0.102: v2(108.03,49.57) 107.95,49.57 107.56,49.97 107.2,49.97 107.04,49.81 106.89,49.81 106.25,49.17 105.48,49.17 103.35,47.03 103.35,45.45 101.09,43.18 97.75,43.18 95.65,41.09 89.4,41.09 80.26,31.94 77.87,31.94 71.75,25.83 64.61,25.83 63.12,27.32 59.3,27.32 59.2,27.22 59.2,26.25 59.09,26.15 58.89,26.15 58.79,26.25 58.79,27.22 58.69,27.32 58.48,27.32 58.38,27.22 58.38,26.25 58.28,26.15 58.08,26.15 57.98,26.25 57.98,27.22 57.87,27.32 57.49,27.32 57.39,27.22 57.39,27.07 57.29,26.97 57.08,26.97 56.98,27.07 56.98,27.22 56.88,27.32 56.68,27.32 56.58,27.22 56.58,27.07 56.47,26.97 56.27,26.97 56.17,27.07 56.17,27.22 56.07,27.32 55.52,27.32 v2(55.27,27.07)
  BOTTOM w0.089: DM2.233 55.89,27.68 v2(55.27,27.07) ; v2(108.03,49.57) 108.35,49.25 CPU1.AP22
M_B_DQ62: length 73.9
  TOP w0.089: v2(108.03,47.74) 108.03,47.87 v1(107.7,48.2)
  L6 w0.102: v2(108.03,47.74) 108.54,47.24 109.48,47.24 109.72,46.99 109.72,46.66 109.48,46.42 106.02,46.42 105.29,45.68 105.29,44.72 105.36,44.64 105.36,44.24 102.32,41.2 101.34,41.2 100.67,40.53 99.54,40.53 96.54,37.53 89.56,37.53 77.82,25.8 76.45,25.8 73.64,22.99 71.59,22.99 70.94,22.34 56.23,22.34 v2(55.23,23.34)
  BOTTOM w0.089: DM2.245 56.58,24.68 v2(55.23,23.34) ; v2(108.03,47.74) 108.35,48.07 CPU1.AP21
M_B_DQ63: length 75.2
  TOP w0.089: v1(109,49.11) 108.68,48.79 v2(108.68,48.66)
  L6 w0.102: v2(53.76,23.42) 55.16,22.01 71.09,22.01 71.73,22.65 73.77,22.65 76.59,25.47 77.96,25.47 89.7,37.2 96.72,37.2 99.66,40.14 100.54,40.14 101.42,41.01 102.51,41.01 105.56,44.06 105.56,44.72 105.51,44.77 105.51,45.13 105.79,45.41 109.38,45.41 109.91,45.94 109.91,47.72 109.43,48.2 109.13,48.2 v2(108.68,48.66)
  BOTTOM w0.089: CPU1.AN21 109,48.33 v2(108.68,48.66) ; v2(53.76,23.42) 52.74,24.44 DM2.246
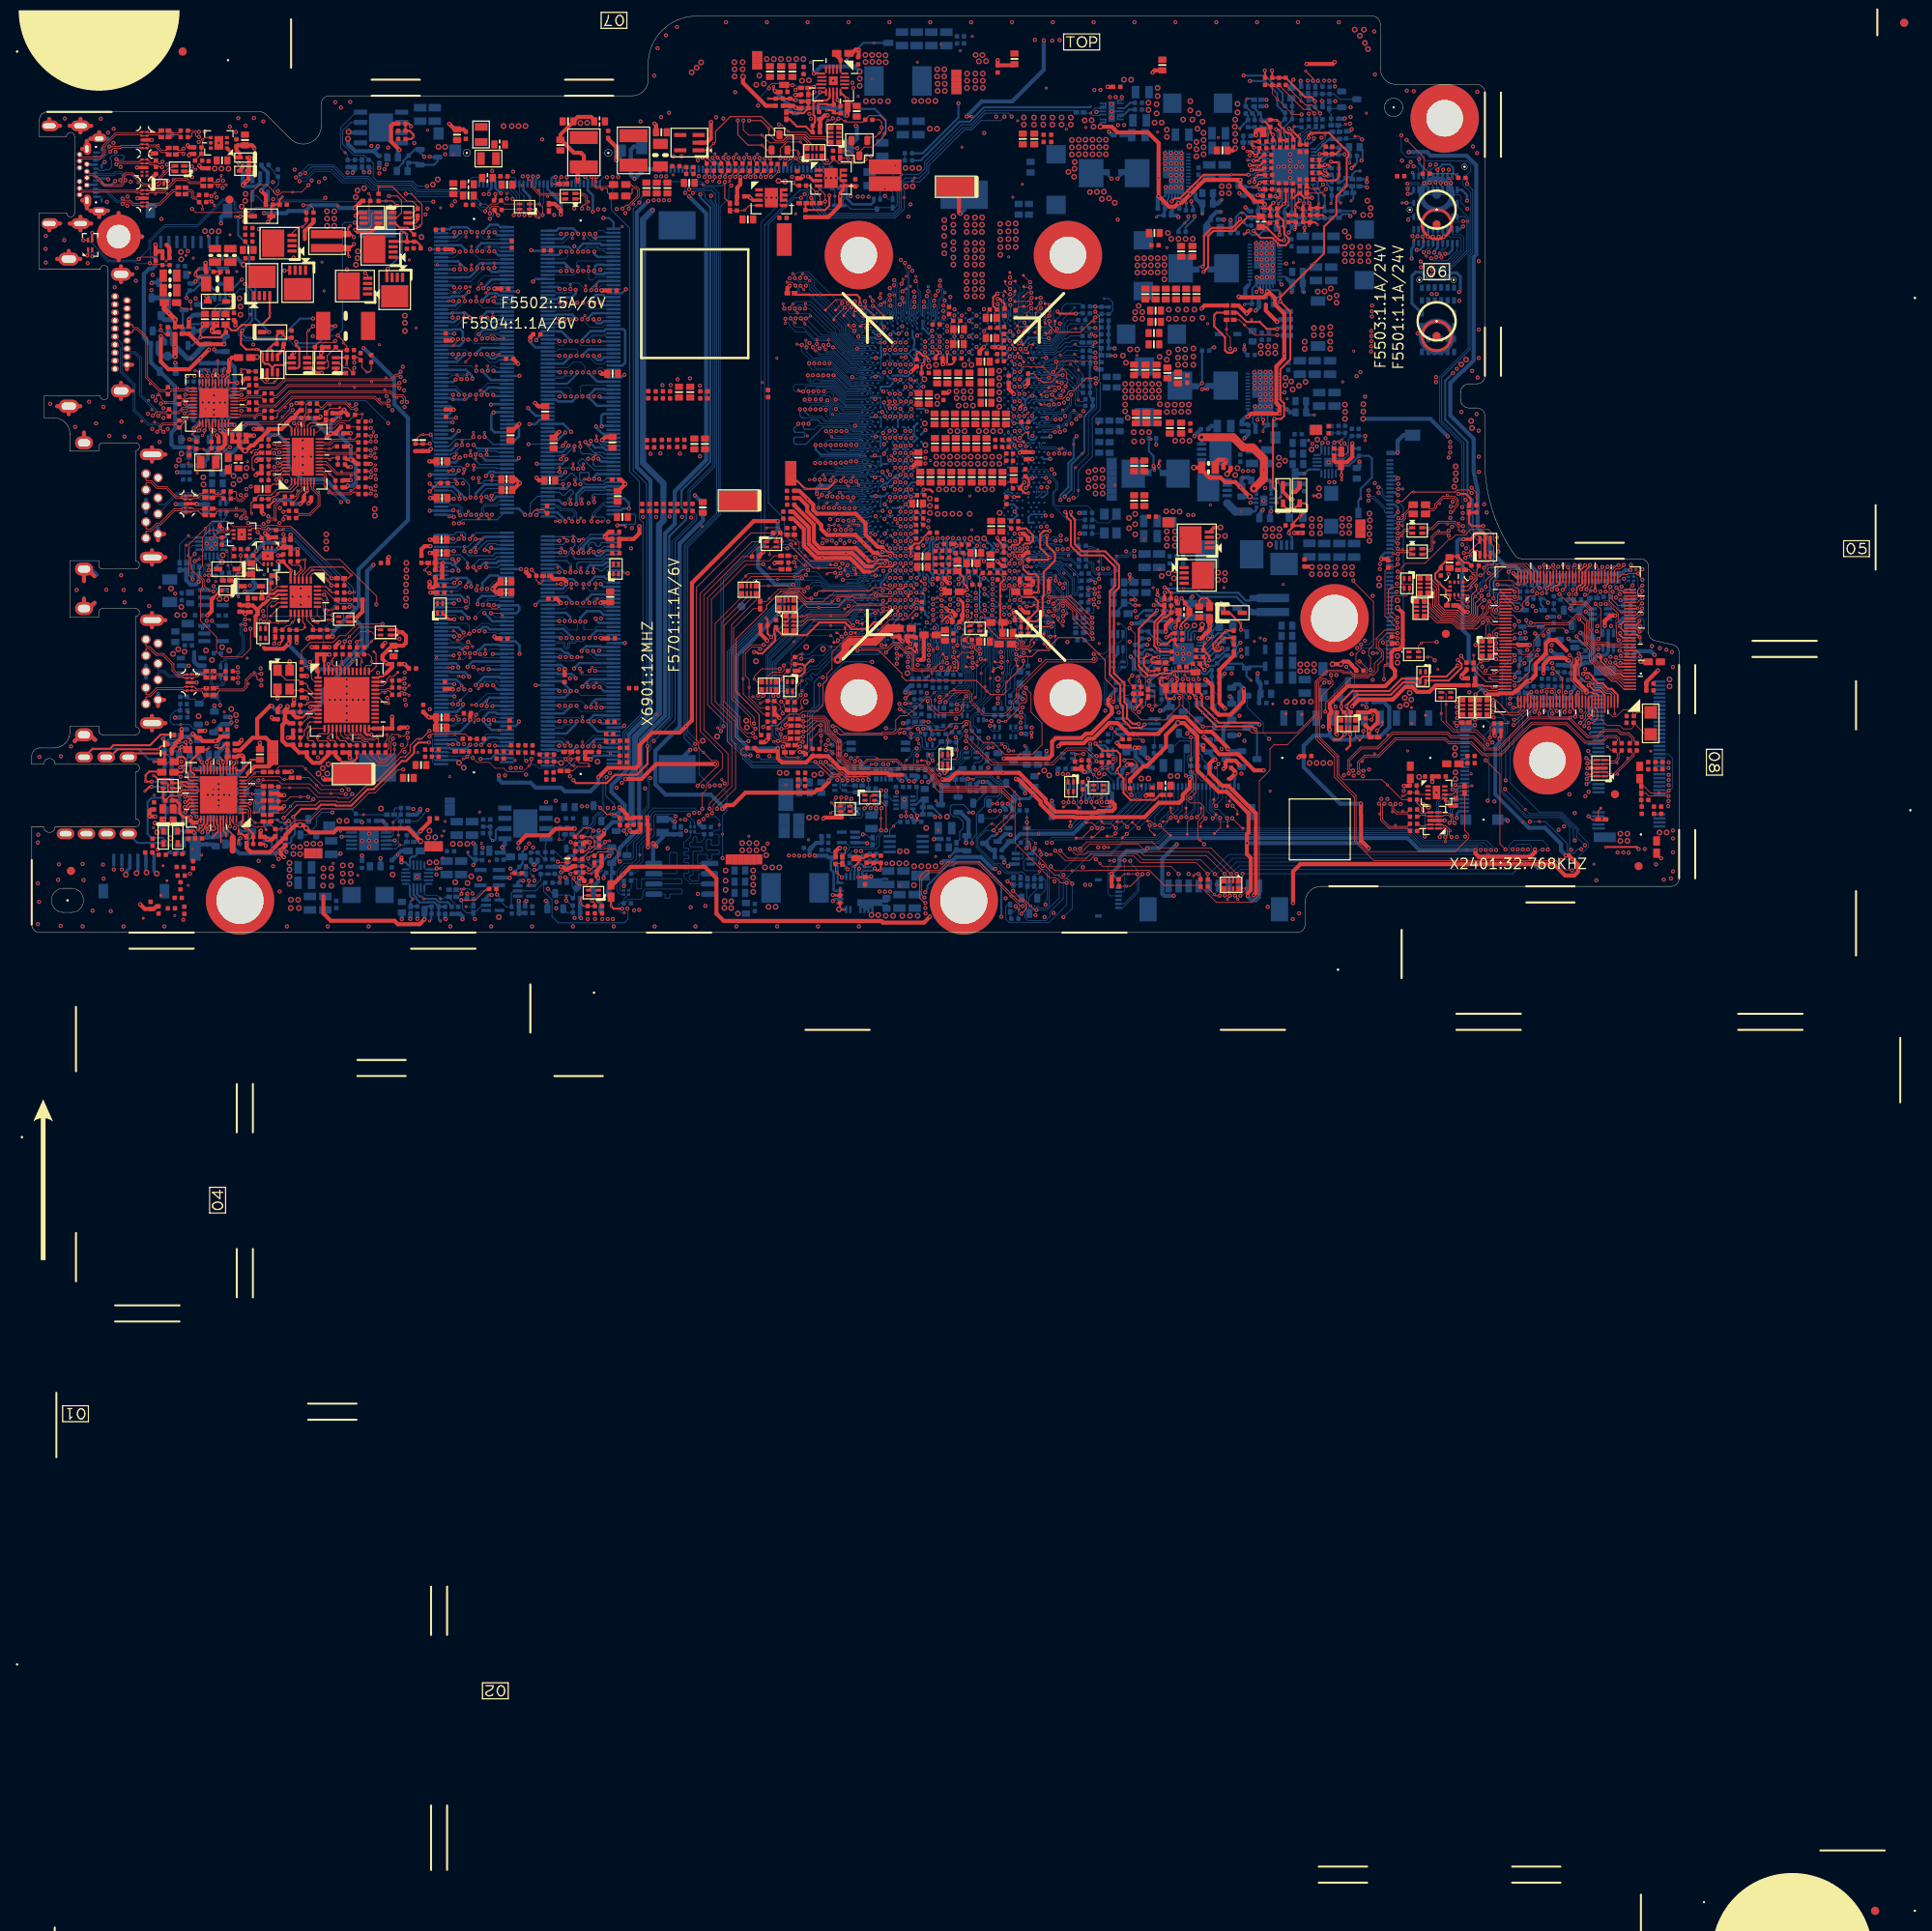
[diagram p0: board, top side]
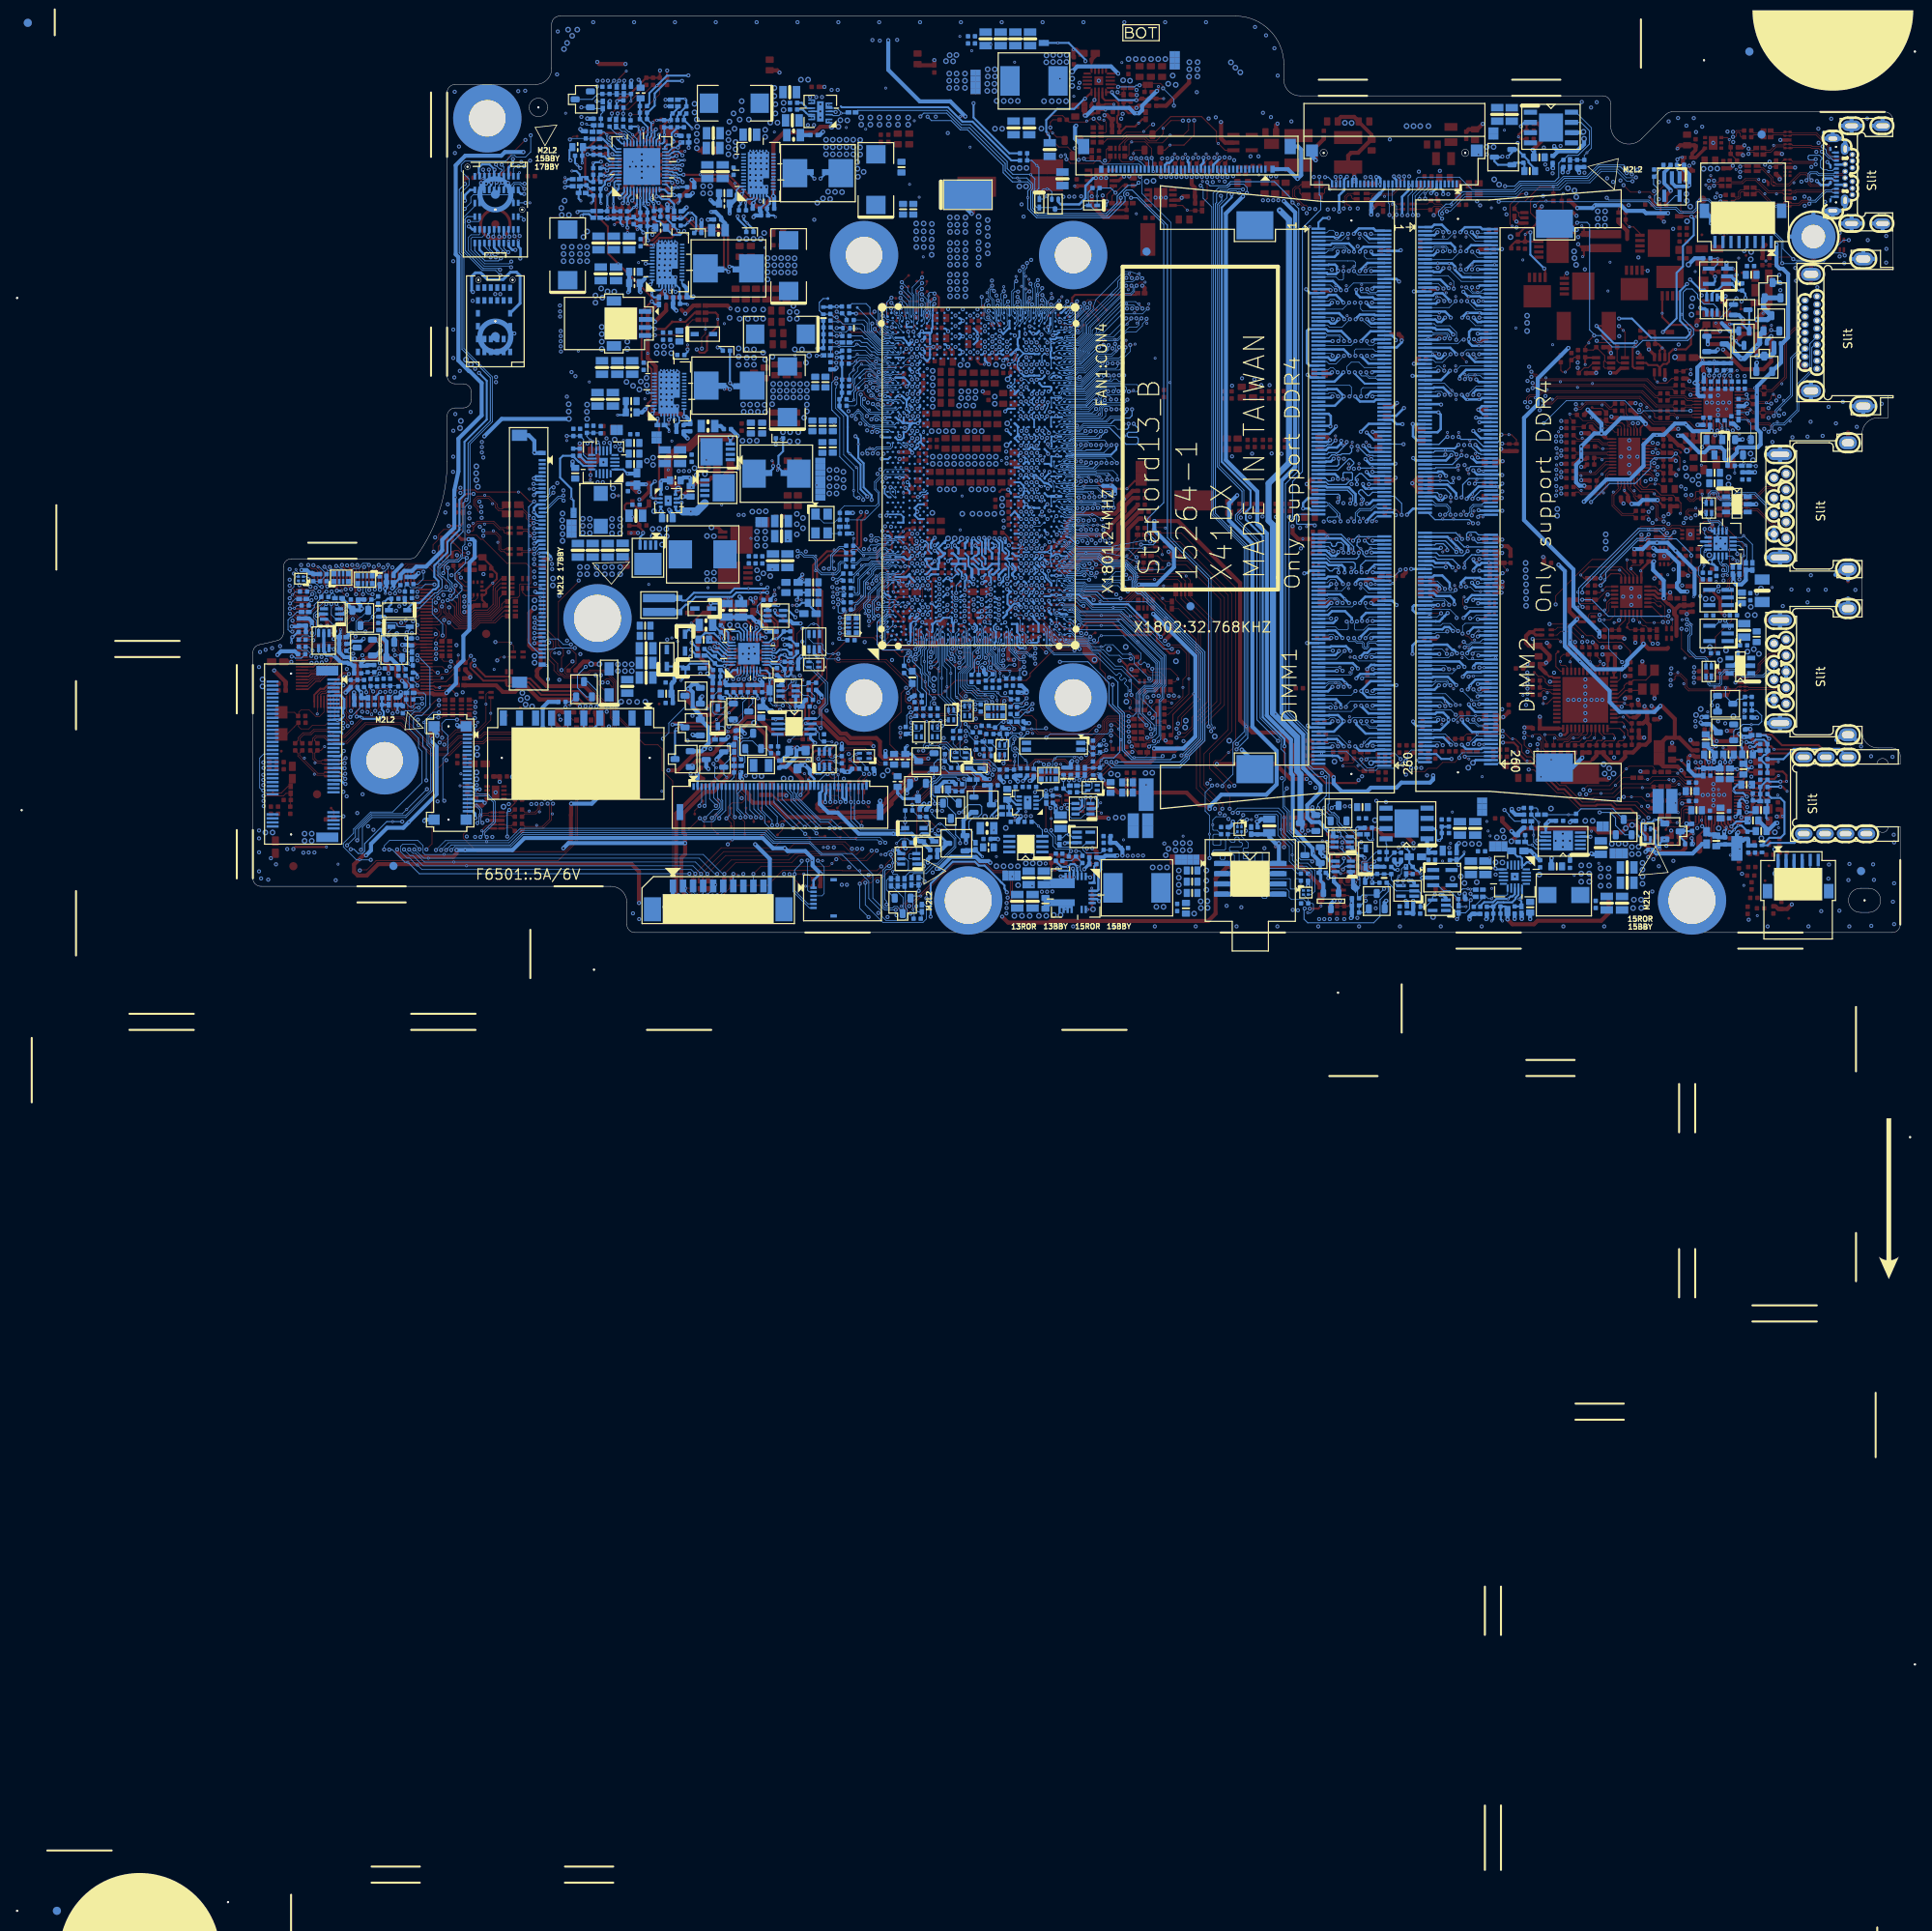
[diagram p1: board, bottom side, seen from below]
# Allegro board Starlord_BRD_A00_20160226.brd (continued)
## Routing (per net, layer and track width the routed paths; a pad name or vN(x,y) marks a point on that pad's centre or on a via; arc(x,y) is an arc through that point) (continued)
M_B_DQS_DN0: length 74
  TOP w0.089: v1(52.55,79.59) 53.15,80.2 v2(53.25,80.2)
  L6 w0.127: v2(112,74.1) 111.69,74.1 111.5,74.28 111.5,74.56 108.63,77.44 106.65,77.44 106.25,77.84 106.25,79.09 105.61,79.72 101.34,79.72 97.59,83.48 90.63,83.48 88.98,81.83 85.63,81.83 84.68,80.88 84.25,80.88 84.13,81 84.13,81.42 83.84,81.7 83.45,81.7 83.16,81.42 83.16,81 83.04,80.88 82.78,80.88 82.65,81 82.65,81.42 82.37,81.7 81.97,81.7 81.69,81.42 81.69,81 81.56,80.88 73.83,80.88 71.94,78.99 64.89,78.99 64.63,79.24 58.51,79.24 58.18,79.57 55.31,79.57 55.01,79.87 55.01,80.6 54.6,81.02 53.9,81.02 53.67,80.78 53.67,80.61 v2(53.25,80.2)
  BOTTOM w0.089: CPU1.AH66 111.67,73.77 v2(112,74.1) ; v2(53.25,80.2) 53.34,80.11 53.34,79.85 53.12,79.63 52.18,79.63 51.87,79.94 DM2.32
M_B_DQS_DN1: length 75
  L6 w0.127: v2(112.93,80.41) 112.47,80.86 112.47,81.55 105.43,88.59 100.64,88.59 99.14,87.09 89.49,87.09 88.24,85.84 83.08,85.84 82.82,85.58 82.82,85.28 82.69,85.16 82.44,85.16 82.31,85.28 82.31,85.58 82.05,85.84 81.61,85.84 81.34,85.58 81.34,85.28 81.22,85.16 72.76,85.16 71.39,83.79 65.14,83.79 63.1,85.82 56.39,85.82 56.02,85.45 v2(56.02,84.67)
  BOTTOM w0.089: v2(112.93,80.41) 113.38,79.95 113.38,79.54 ; v1(113.56,79.54) 113.38,79.54 ; 113.38,79.54 113.38,79.05 112.91,78.57 112.91,77.64 112.49,77.23 112.49,76.95 112.54,76.8 112.54,76.61 112.48,76.4 112.48,76.08 CPU1.AG69 ; DM2.11 58.09,85.18 57.94,85.34 56.47,85.34 56.26,85.12 56.26,84.91 v2(56.02,84.67)
M_B_DQS_DN2: length 64.2
  TOP w0.089: v1(107.01,72.91) 107.01,72.98 v2(107.38,73.35)
  L6 w0.089: 102.87,76.09 102.94,76.09 102.97,76.05 103.71,76.05 104.83,74.93 105.54,74.93 106.11,74.37 106.11,74.21 106.97,73.35 v2(107.38,73.35)
  L6 w0.127: v2(56.01,73.83) 56.18,74.01 56.18,74.36 56.51,74.69 57.96,74.69 58.22,74.43 58.22,74.08 58.35,73.96 58.6,73.96 58.73,74.08 58.73,74.91 58.99,75.18 59.43,75.18 59.69,74.91 59.69,74.08 59.82,73.96 60.08,73.96 60.2,74.08 60.2,74.43 60.46,74.69 73.11,74.69 76.35,77.93 89.27,77.93 90.61,79.26 97.43,79.26 99.08,77.61 99.69,77.61 101.22,76.09 102.87,76.09
  BOTTOM w0.089: DM2.53 58.24,74.69 58.09,74.53 56.62,74.53 56.29,74.53 56.09,74.33 56.09,73.92 v2(56.01,73.83) ; CPU1.AR66 107.7,73.67 v2(107.38,73.35)
M_B_DQS_DN3: length 64.6
  TOP w0.089: v1(54.13,69.36) v2(54.13,68.8)
  L6 w0.089: v2(108.02,70.58) 107.64,70.2 107.14,70.2 107.06,70.27 106.68,70.27 106.32,70.22 105.74,70.22 105.66,70.3 105.53,70.3 105.52,70.3 105.46,70.3 105.44,70.32 105.43,70.32
  L6 w0.127: v2(54.13,68.8) 53.92,68.6 53.92,68.39 54.09,68.23 55.11,68.23 55.61,68.72 56.34,68.72 56.83,68.23 58.13,68.23 58.63,68.72 70.97,68.72 73.15,70.9 74.44,70.9 77.85,74.31 99.61,74.31 101.42,72.5 101.42,71.99 102.07,71.34 103.7,71.34 104.72,70.32 105.43,70.32
  BOTTOM w0.089: CPU1.AR61 107.7,70.9 v2(108.02,70.58) ; DM2.74 53.69,69.44 53.87,69.26 53.87,68.98 54.05,68.8 v2(54.13,68.8)
M_B_DQS_DN4: length 66.8
  TOP w0.089: v1(106.88,59.27) 107.32,58.84 v2(107.32,58.74)
  L6 w0.102: v2(107.32,58.74) 107.32,58.67 106.91,58.26 106.5,58.26 106.32,58.44 104.6,58.44 103.1,56.94 102.77,56.94
  L6 w0.127: 102.77,56.94 97.01,56.94 93.15,53.08 89.41,53.08 76.74,40.42 64.89,40.42 64.66,40.19 62.2,40.19 62.07,40.31 62.07,40.62 61.81,40.89 61.37,40.89 61.11,40.62 61.11,40.31 60.98,40.19 60.73,40.19 60.6,40.31 60.6,40.62 60.34,40.89 59.9,40.89 59.63,40.62 59.63,40.31 59.51,40.19 59.24,40.19 57.84,41.58 56.68,41.58 56.36,41.26 56.36,41 v2(56.1,40.74)
  BOTTOM w0.089: CPU1.AT38 107.05,58.47 v2(107.32,58.74) ; DM2.177 58.26,41.69 58.02,41.44 56.67,41.44 56.1,40.87 v2(56.1,40.74)
M_B_DQS_DN5: length 68.7
  TOP w0.089: v2(54.28,36.14) 54.81,35.6 v1(54.81,35.53)
  L6 w0.089: v2(107.35,55.1) 107.17,54.91 106.33,54.91 106.2,54.78 105.84,54.78 105.73,54.89 105.57,54.89 104.72,54.89 104.72,54.89 104.54,54.89 104.54,54.89 104.51,54.89
  L6 w0.127: 104.51,54.89 103.78,54.15 103.78,53.56 103.51,53.3 103.32,53.11 103.32,53.1 102.53,52.31 97.63,52.31 94.61,49.29 91.25,49.29 88.53,46.56 87.53,46.56 78.1,37.14 75.65,37.14 73.61,35.09 71.57,35.09 70.93,35.73 68.05,35.73 67.24,34.92 64,34.92 62.92,36 54.94,36 54.65,35.71 54.52,35.71 54.28,35.95 v2(54.28,36.14)
  BOTTOM w0.089: v2(54.28,36.14) 54.24,36.14 53.9,35.81 53.63,35.81 53.32,36.12 52.24,36.12 51.92,36.44 DM2.198 ; CPU1.AT32 107.35,54.6 107.42,54.67 107.42,55.03 v2(107.35,55.1)
M_B_DQS_DN6: length 70.3
  TOP w0.089: v1(55.55,30.29) 55.94,30.69 v2(55.94,30.73)
  L6 w0.089: v2(108.03,51.4) 107.74,51.69 107.66,51.69 107.54,51.8 107.23,51.8 106.88,51.45 106.88,51.36 106.27,50.75 104.63,50.75 104.6,50.72
  L6 w0.127: v2(55.94,30.73) 56.07,30.6 56.07,30 56.29,29.79 58.3,29.79 58.56,30.05 58.56,30.93 58.69,31.06 58.94,31.06 59.07,30.93 59.07,30.05 59.33,29.79 63.32,29.79 64.11,28.99 71.18,28.99 71.9,29.71 73.24,29.71 77.17,33.63 79.56,33.63 88.98,43.06 91.08,43.06 91.88,43.86 94.44,43.86 96.51,45.93 97.31,45.93 98.8,47.41 102.36,47.41 103.55,48.6 103.55,49.68 104.07,50.2 104.59,50.72 104.6,50.72
  BOTTOM w0.089: CPU1.AR25 107.7,51.08 v2(108.03,51.4) ; v2(55.94,30.73) 56.18,30.96 56.18,31.18 56.35,31.35 57.75,31.35 57.78,31.35 57.94,31.19 DM2.219
M_B_DQS_DN7: length 73.5
  TOP w0.089: v2(53.1,26.46) 52.8,26.76 v1(52.8,26.94)
  L6 w0.089: 104.49,46.09 104.49,46.1 104.49,46.83 105.38,47.73 106.13,47.73 106.55,48.15 107.52,48.15 v2(108.03,48.66)
  L6 w0.127: v2(53.1,26.46) 53.1,25.2 53.77,24.52 58.8,24.52 59.31,24.02 73.19,24.02 75.09,25.92 75.09,26.29 74.89,26.5 74.89,26.68 75.07,26.86 75.25,26.86 75.45,26.65 75.82,26.65 76.14,26.96 76.14,27.33 75.93,27.54 75.93,27.72 76.11,27.9 76.29,27.9 76.5,27.69 76.87,27.69 79.53,30.36 80.91,30.36 89.13,38.57 96.08,38.57 99.53,42.03 101.42,42.03 104.49,45.1 104.49,46.09
  BOTTOM w0.089: v2(108.03,48.66) 107.7,48.98 CPU1.AR22 ; DM2.240 51.68,25.93 51.83,25.78 52.42,25.78 v2(53.1,26.46)
M_B_DQS_DP0: length 73.7
  TOP w0.089: v1(54.53,80.26) 54.02,80.26 v2(53.96,80.2)
  L6 w0.127: v2(112,73.45) 112,73.47 111.28,74.18 111.28,74.46 108.53,77.21 106.56,77.21 106.02,77.75 106.02,78.99 105.52,79.49 101.25,79.49 97.49,83.25 90.73,83.25 89.08,81.6 85.72,81.6 84.77,80.65 84.16,80.65 83.9,80.91 83.9,81.33 83.75,81.47 83.54,81.47 83.39,81.33 83.39,80.91 83.13,80.65 82.69,80.65 82.43,80.91 82.43,81.33 82.28,81.47 82.07,81.47 81.92,81.33 81.92,80.91 81.66,80.65 73.92,80.65 72.03,78.76 64.79,78.76 64.66,78.89 64.54,79.01 58.42,79.01 58.09,79.34 55.22,79.34 54.79,79.77 54.79,80.51 54.51,80.79 54,80.79 53.9,80.69 53.9,80.26 v2(53.96,80.2)
  BOTTOM w0.089: CPU1.AH65 111.67,73.12 v2(112,73.45) ; v2(53.96,80.2) 53.2,79.44 DM2.34
M_B_DQS_DP1: length 75.4
  TOP w0.089: v1(56.87,85.23) v2(56.87,84.67)
  L6 w0.127: v2(56.87,84.67) 56.65,84.67 56.25,85.07 56.25,85.36 56.48,85.59 63.01,85.59 65.05,83.56 71.49,83.56 72.86,84.93 81.31,84.93 81.57,85.19 81.57,85.49 81.7,85.61 81.95,85.61 82.08,85.49 82.08,85.19 82.34,84.93 82.79,84.93 83.05,85.19 83.05,85.49 83.17,85.61 88.34,85.61 89.58,86.86 99.24,86.86 100.73,88.36 105.34,88.36 112.24,81.46 112.24,80.77 112.42,80.59 112.42,79.85 112.52,79.75 v2(112.7,79.75)
  BOTTOM w0.089: v2(112.7,79.75) 112.7,79.88 112.8,79.98 113.08,79.98 113.19,79.87 113.19,79.13 112.72,78.65 112.72,77.74 112.32,77.34 112.32,76.92 112.36,76.77 112.36,76.63 112.3,76.43 112.3,76.15 112.2,76.05 CPU1.AG70 ; DM2.13 58.15,84.69 58.01,84.83 58.01,84.83 58.01,84.99 57.86,85.14 56.55,85.14 56.45,85.04 56.45,84.72 56.54,84.62 56.82,84.62 v2(56.87,84.67)
M_B_DQS_DP2: length 66
  TOP w0.089: v2(56.67,73.85) 57.07,74.26 57.48,74.26 57.88,73.85 v1(58.7,73.85)
  L6 w0.089: 102.87,75.86 103.63,75.86 104.75,74.74 105.46,74.74 105.92,74.29 105.92,74.13 106.91,73.14 106.92,73.14 107.38,72.68 v2(107.38,72.43)
  L6 w0.127: 102.87,75.86 101.12,75.86 99.6,77.39 98.99,77.39 97.34,79.04 90.7,79.04 89.37,77.7 76.44,77.7 73.2,74.46 60.56,74.46 60.43,74.34 60.43,73.99 60.17,73.73 59.73,73.73 59.47,73.99 59.47,74.82 59.34,74.95 59.09,74.95 58.96,74.82 58.96,73.99 58.7,73.73 58.25,73.73 57.99,73.99 57.99,74.34 57.87,74.46 56.61,74.46 56.41,74.27 56.41,74.11 v2(56.67,73.85)
  BOTTOM w0.089: DM2.55 58.25,74.19 58.1,74.33 57.96,74.33 57.96,74.34 56.37,74.34 56.28,74.25 56.28,74.15 56.37,74.07 56.58,73.85 v2(56.67,73.85) ; v2(107.38,72.43) 107.38,72.73 107.54,72.89 CPU1.AR65
M_B_DQS_DP3: length 64.8
  TOP w0.089: v2(53.44,68.77) 53.41,68.77 v1(52.88,69.31)
  L6 w0.089: v2(108.02,69.74) 107.76,70.01 107.06,70.01 106.98,70.08 106.69,70.08 106.34,70.03 105.66,70.03 105.63,70.06 105.61,70.06 105.59,70.08 105.57,70.08 105.56,70.1 105.43,70.1
  L6 w0.127: 105.43,70.1 104.62,70.1 103.6,71.11 101.98,71.11 101.19,71.9 101.19,72.41 99.52,74.08 77.94,74.08 74.53,70.67 73.24,70.67 71.07,68.49 58.72,68.49 58.23,68 56.74,68 56.24,68.5 55.7,68.5 55.21,68 53.99,68 53.69,68.3 53.69,68.52 v2(53.44,68.77)
  BOTTOM w0.089: DM2.76 51.94,68.94 52.25,69.24 53.61,69.24 53.68,69.18 53.68,69.01 v2(53.44,68.77) ; v2(108.02,69.74) 107.7,70.06 CPU1.AR60
M_B_DQS_DP4: length 67.7
  TOP w0.089: v2(56.81,40.74) 57.29,40.25 57.81,40.25 v1(58.09,40.53)
  L6 w0.102: 102.77,56.71 102.86,56.71 102.87,56.72 103.17,56.72 104.68,58.23 106.24,58.23 106.42,58.06 106.99,58.06 107.25,58.31 107.85,58.31 107.97,58.44 v2(107.97,58.72)
  L6 w0.127: v2(56.81,40.74) 56.59,40.95 56.59,41.16 56.78,41.35 57.75,41.35 58.23,40.87 59.14,39.96 59.6,39.96 59.86,40.22 59.86,40.53 59.99,40.66 60.24,40.66 60.37,40.53 60.37,40.22 60.63,39.96 61.08,39.96 61.34,40.22 61.34,40.53 61.46,40.66 61.72,40.66 61.84,40.53 61.84,40.22 62.11,39.96 64.76,39.96 64.99,40.19 76.84,40.19 89.5,52.85 93.24,52.85 97.1,56.71 102.77,56.71
  BOTTOM w0.089: DM2.179 58.16,41.19 58.1,41.25 56.75,41.25 56.65,41.15 56.65,40.89 v2(56.81,40.74) ; CPU1.AR38 107.7,58.46 v2(107.97,58.72)
M_B_DQS_DP5: length 68.5
  TOP w0.089: v2(54.15,35.45) 53.8,35.45 v1(53.62,35.27)
  L6 w0.089: 104.63,54.68 104.65,54.7 105.65,54.7 105.76,54.59 106.27,54.59 106.41,54.72 107.17,54.72 107.19,54.71 107.61,54.71 v2(107.99,55.08)
  L6 w0.127: v2(54.15,35.45) 54.19,35.48 54.74,35.48 55.03,35.77 62.82,35.77 63.9,34.69 67.33,34.69 68.15,35.5 70.84,35.5 71.47,34.87 73.7,34.87 75.75,36.91 78.2,36.91 87.62,46.33 88.62,46.33 91.35,49.06 94.7,49.06 97.73,52.08 102.62,52.08 103.55,53.01 103.55,53.01 103.61,53.07 103.61,53.07 104.01,53.47 104.01,54.06 104.63,54.68
  BOTTOM w0.089: CPU1.AR32 107.7,54.8 v2(107.99,55.08) ; v2(54.15,35.45) 53.99,35.61 53.55,35.61 53.24,35.93 51.78,35.93 51.77,35.93 DM2.200
M_B_DQS_DP6: length 70.3
  TOP w0.089: v2(108.03,52.31) 108.03,52.87 v1(108.02,52.87)
  L6 w0.089: 104.49,50.94 106.2,50.94 106.69,51.44 106.69,51.53 107.15,51.99 107.62,51.99 107.74,51.88 107.95,51.88 108.03,51.95 v2(108.03,52.31)
  L6 w0.127: v2(56.66,30.73) 56.3,30.38 56.3,30.1 56.38,30.02 58.2,30.02 58.33,30.14 58.33,31.02 58.59,31.28 59.04,31.28 59.3,31.02 59.3,30.14 59.42,30.02 63.41,30.02 64.21,29.22 71.09,29.22 71.8,29.94 73.15,29.94 77.07,33.86 79.46,33.86 88.88,43.29 90.99,43.29 91.79,44.09 94.34,44.09 96.41,46.16 97.22,46.16 98.7,47.64 102.27,47.64 103.33,48.7 103.33,49.78 104.49,50.94
  BOTTOM w0.089: CPU1.AR27 107.92,51.86 108.03,51.96 v2(108.03,52.31) ; DM2.221 58.17,30.69 57.7,31.16 57.19,31.16 57.19,31.16 56.43,31.16 56.37,31.1 56.37,30.84 56.48,30.73 v2(56.66,30.73)
M_B_DQS_DP7: length 73.8
  TOP w0.089: v1(106.81,49.34) 107.38,48.77 v2(107.38,48.66)
  L6 w0.089: 104.27,46.09 104.27,46.19 104.3,46.22 104.3,46.91 105.31,47.92 106.05,47.92 106.47,48.34 107.26,48.34 107.38,48.46 v2(107.38,48.66)
  L6 w0.127: v2(53.81,26.46) 53.81,26.44 53.33,25.96 53.33,25.29 53.86,24.75 58.9,24.75 59.4,24.25 73.1,24.25 74.87,26.01 74.87,26.19 74.66,26.4 74.66,26.77 74.97,27.09 75.34,27.09 75.55,26.88 75.73,26.88 75.91,27.06 75.91,27.24 75.7,27.45 75.7,27.81 76.01,28.13 76.38,28.13 76.59,27.92 76.77,27.92 79.44,30.59 80.82,30.59 89.04,38.8 95.98,38.8 99.44,42.26 101.33,42.26 104.27,45.2 104.27,46.09
  BOTTOM w0.089: v2(107.38,48.66) 107.7,48.33 CPU1.AR21 ; v2(53.81,26.46) 53.81,26.35 53.5,26.04 52.94,26.04 52.5,25.59 51.82,25.59 51.66,25.44 DM2.242
M_B_PARITY: length 71.4
  TOP w0.152: v1(53.69,50.87) v2(53.14,50.87)
  L6 w0.089: v2(108.67,60.5) 108.6,60.5 108.19,60.91 106.33,60.91 106.15,61.08 105.33,61.08
  L6 w0.165: v2(53.14,50.87) 53.36,50.65 53.73,50.65 53.9,50.81 53.9,51.19 54.06,51.35 54.39,51.35 54.56,51.19 54.56,50.81 54.72,50.65 65.09,50.65 65.15,50.59 72.17,50.59 72.61,50.14 73,50.14 74.47,51.62 74.47,52.21 75.69,53.43 77.44,53.43 80.74,56.73 83.09,56.73 86.67,60.32 93.14,60.32 94.08,61.25 96.24,61.25 96.8,61.82 97.64,61.82 98.96,63.14 101.47,63.14 103.52,61.08 105.33,61.08
  BOTTOM w0.152: v2(53.14,50.87) 53.59,51.32 57.86,51.32 58.72,52.19 DM2.143 ; v2(108.67,60.5) 108.35,60.82 CPU1.AP43
M_VREF_CA_DIMMA: length 1.5
  BOTTOM w0.305: v2(65.59,44.78) 65.54,44.73 DM1.164
  vias: v1(65.38,45.36)
M_VREF_CA_DIMMB: length 1.5
  BOTTOM w0.305: v2(52.34,44.98) 52.29,44.93 DM2.164
  vias: v1(52.2,42.38)
MCU_BOOT0: length 3.2
  TOP w0.127: U6901.44 38.41,33.01 38.29,33.14 37.57,33.14 37.32,33.38 37.32,33.55 37.32,33.55 v1(37.32,33.71) 37.32,33.94 37.77,34.38 R6907.1
MCU_OSCI: length 6.5
  TOP w0.127: X6901.1 30.56,32.45 31.63,31.37 33.2,31.37 C6909.1 33.58,30.99 34.02,30.99 34.34,30.67 34.34,30.42 35.09,29.67 U6901.5
MCU_OSCO: length 4
  TOP w0.127: U6901.6 35.08,29.17 34.15,30.1 C6908.1 32.23,30.1 X6901.3
MCU_RST#: length 3.3
  TOP w0.127: R6902.1 C6902.1 34.09,28.29 v1(34.29,28.49) 34.47,28.67 35.62,28.67 U6901.7
ME_FWP_EC: length 170
  TOP w0.102: v2(82.8,18.25) 85.06,20.51 85.17,20.51 85.42,20.77 85.42,21.13 85.17,21.38 84.53,21.38 v1(83.54,22.37) 82.93,22.98 82.93,23.61 82.63,23.91 82.63,42.87 89.43,49.67 R1909.1 ; v2(182.12,37.1) 182.14,37.08 182.14,36.9 182.4,36.64 KBC24.80
  L4 w0.102: v2(182.12,37.1) 182.73,36.49 182.73,29.84 182.52,29.64 182.52,29 182.5,28.98 182.5,27.9 182.57,27.83 182.57,25.65 182.5,25.57 182.5,25.17 183.16,24.51 183.16,22.93 181.23,21 177.98,21 177.62,21.35 176.33,21.35 174.69,19.71 174.09,19.71 173.15,18.77 170.5,18.77 169.64,17.92 167.69,17.92 166.63,16.86 163.64,16.86 162.96,16.17 158.47,16.17 157.63,15.33 155.4,15.33 152.17,12.11 151.05,12.11 150.34,11.4 142.06,11.4 141.68,11.01 132.43,11.01 132.18,10.76 132.18,10.18 132.74,9.62 132.74,8.93 132.49,8.68 131.82,8.68 130.76,9.74 126.87,9.74 126.49,10.13 125.32,10.13 125.25,10.05 123.37,10.05 122.88,10.53 119.56,10.53 118.94,11.15 117.54,11.15 117.12,11.57 115.32,11.57 114.91,11.99 114.08,11.99 113.43,12.64 111.76,12.64 111.48,12.36 110.41,12.36 109.95,12.82 107.47,12.82 106.83,13.45 102.56,13.45 102.06,12.95 100.68,12.95 100.1,13.53 95.38,13.53 93.65,15.26 91.58,15.26 87.47,19.37 83.92,19.37 v2(82.8,18.25)
ME_SUS_PWR_ACK: length 1.7
  TOP w0.127: TP1712.1 111.61,21.81 v2(112.04,21.38)
  BOTTOM w0.127: v2(112.04,21.38) 112.03,21.38 112.03,22.07 RN1702.1
ME_SUS_PWR_ACK_R: length 26.3
  TOP w0.127: v1(112.27,24.02) v2(111.71,24.02)
  L3 w0.127: v2(111.71,24.02) 111.45,24.27 111.45,25.59 109.47,27.58 109.47,30.19 108.28,31.39 108.28,32.76 108.43,32.91 108.43,35.3 106.32,37.41 106.32,42.43 106.56,42.66 107.47,42.66 107.97,43.17 v2(108.03,43.17)
  BOTTOM w0.127: v2(108.03,43.17) 107.7,43.5 CPU1.AR13 ; R2039.2 R1708.1 111.71,24.41 v2(111.71,24.02) 112.01,23.72 RN1702.4
MEM_SMBCLK: length 50.8
  TOP w0.089: v2(100.66,16.78) 100.57,16.69 RN1811.3 99.85,15.71 v1(99.44,16.12)
  L3 w0.127: v2(119.78,15.16) 119.76,15.16 119.24,15.68 119.24,18.39 117.61,20.02 117.61,31.77 118.63,32.78 118.63,38.21 v2(117.45,39.39)
  L4 w0.127: v2(119.78,15.16) 118.95,15.99 115.57,15.99 114.82,16.74 109.48,16.74 108.86,17.36 108.3,17.36 107.55,18.11 105.32,18.11 104.67,17.47 101.34,17.47 v2(100.66,16.78)
  BOTTOM w0.089: v2(100.66,16.78) 100.68,16.76 Q1801.3 ; v2(117.45,39.39) 117.84,39.77 CPU1.R7
MEM_SMBDATA: length 52.7
  TOP w0.089: v1(99.34,14.85) 99.55,15.06 RN1811.4 100.92,15.06 101.14,15.28 101.14,16.45 101.29,16.6 v2(101.29,16.78)
  L3 w0.127: v2(119.15,15.13) 118.86,15.42 118.86,17.48 117.42,18.91 117.42,19.55 117.23,19.74 117.23,31.93 118.41,33.11 118.41,36.95 117.04,38.32 117.04,39.62 v2(117.45,40.02)
  L4 w0.127: v2(119.15,15.13) 118.84,15.13 118.36,15.61 115.42,15.61 114.67,16.36 109.31,16.36 108.68,16.98 107.16,16.98 107.07,17.07 101.59,17.07 v2(101.29,16.78)
  BOTTOM w0.089: v2(117.45,40.02) 117.85,40.43 CPU1.R8 ; v2(101.29,16.78) 101.37,16.7 101.37,15.54 101.9,15 101.98,15 102.25,14.73 Q1801.6
MIC2_VREFO_L: length 5.6
  TOP w0.203: HDA27.27 19.43,18.51
  TOP w0.254: v1(15.14,19.5) 15.24,19.5 15.64,19.09 17.07,19.09 17.54,18.62 RN2901.2 18.41,18.58 18.55,18.71 19.23,18.71 19.43,18.51
MIC2_VREFO_R: length 2.9
  TOP w0.203: 19.23,18.11 HDA27.28
  TOP w0.254: 19.23,18.11 19.06,18.28 v1(18.74,18.28) 18.65,18.28 18.3,17.93 RN2901.1
MIC_CAP: length 4.5
  TOP w0.203: HDA27.31 19.1,16.91 v2(19.07,16.88)
  BOTTOM w0.254: C2713.1 20.24,18.38 20.7,17.92 v1(20.7,17.62) 20.7,17.57 20.48,17.35 19.54,17.35 v2(19.07,16.88)
MIC_GND: length 6.9
  TOP w0.508: R5501.1 65.03,90.58 v1(65.53,90.09) 65.78,89.83 v2(65.78,89.25)
  BOTTOM w0.305: 64.7,91.88 64.15,92.43 TCBD1.19
  BOTTOM w0.508: v2(65.78,89.25) 65.78,90.8 64.7,91.88
MODEL_ID: length 6
  TOP w0.102: v2(187.76,29.96) 188.14,30.34 189.23,30.34 189.46,30.12 189.46,29.71 189.61,29.56 KBC24.109
  BOTTOM w0.102: R2441.1 C2407.2 ; R2441.1 186.83,30.66 R2442.2 ; R2441.1 187.78,29.99 v2(187.76,29.96)
MSATA_DEVSLP: length 130.8
  TOP w0.102: R6303.2 200.2,16.41 R6304.1 200.14,17.29 R6301.1 200.73,17.3 201.05,16.98 v2(203.53,16.98) ; v2(191.55,7.72) 191.51,7.72 191.45,7.79 190.68,7.79 189.53,8.93 166.89,8.93 164.48,11.35 164.48,16.82 162,19.3 162,21.73 159.69,24.05 159.69,26.56 160.02,26.89 160.02,31.03 160.53,31.54 160.91,31.54 v2(161.36,31.08)
  L4 w0.102: v2(203.53,16.98) 201.08,16.98 193.1,9.01 192.56,9.01 191.55,8.01 v2(191.55,7.72) ; v2(120.22,30.67) 120.75,30.14 120.75,29.79 122.07,28.46 122.07,24.77 122.75,24.1 124.55,24.1 125.85,25.39 133.17,25.39 133.58,24.98 137.65,24.98 137.7,24.93 138.83,24.93 141.9,28.01 141.91,28.01 141.93,28.03 143.71,28.03 144.19,28.52 146.99,28.52 148.59,30.12 149.55,30.12 150.42,30.98 151.81,30.98 151.84,30.95 154.02,30.95 154.48,31.41 160.4,31.41 160.52,31.54 160.91,31.54 v2(161.36,31.08)
  BOTTOM w0.102: CPU1.J3 120.78,37.39 120.78,35.25 120.99,35.03 120.99,32.54 v1(120.72,32.27) 120.67,32.22 120.67,31.26 120.22,30.8 v2(120.22,30.67)
MSATA_DEVSLP_R: length 10
  TOP w0.102: v2(203.55,17.64) 203.25,17.34 AFTP6301.1 201.32,17.34 200.47,18.19 R6301.2
  BOTTOM w0.102: v2(203.55,17.64) 203.66,17.64 204.01,18 204.01,21.68 203.5,22.19 SSD1.38
MSM#: length 1.7
  TOP w0.102: TP617.1 109.47,68.6 v2(109.29,68.77)
  BOTTOM w0.102: CPU1.AP56 108.81,68.77 v2(109.29,68.77)
MUX_CDE: length 3.1
  TOP w0.127: U3801.35 30.88,58.95 30.81,58.87 v1(30.35,58.87) 29.53,58.87 R3819.2 R3820.2
MUX_CEQ: length 3.3
  TOP w0.127: U3801.38 31.21,57.75 30.88,57.42 v1(30.49,57.42) 29.77,57.42 R3818.2 R3817.2
MUX_CEXT: length 3.9
  TOP w0.127: U3801.1 32.3,55.69 31.95,55.34 31.55,55.34 31.13,55.75 v1(30.5,55.75) 30.5,55.74 29.97,55.74 C3820.1
MUX_DPEQ: length 3.3
  TOP w0.127: R3815.2 R3816.2 37.31,59 v1(37.08,58.77) 37.01,58.77 36.82,58.95 U3801.14
MUX_EN: length 3.4
  TOP w0.102: R3842.1 R3810.1 29.96,61.81 v1(30.28,61.81) 30.76,61.81 31.22,61.35 U3801.29
MUX_EN_R: length 1.6
  TOP w0.102: R3842.2 28.08,59.99 27.61,59.99 TP2901.1
MUX_HPD_PD: length 2.4
  TOP w0.102: U3801.32 30.61,60.15 30.56,60.09 v1(30.4,60.09) 29.91,60.09 R3846.1
MUX_I2C_EN: length 2.3
  TOP w0.102: U3801.17 v1(36.98,60.15) 37.29,60.15 37.56,60.42 R3811.1
MUX_REXT: length 8.1
  TOP w0.127: U3801.2 32.7,55.66 32.13,55.08 30.48,55.08 29.77,54.37 28.26,54.37 R3803.1 27.28,53.39 27.28,52.18 v1(27.35,52.1)
MUX_SSDE: length 5.7
  TOP w0.127: R3823.2 R3824.2 29.65,53.88 30,54.22 30.27,54.22 v1(30.58,54.53) 30.83,54.78 32.33,54.78 33.1,55.55 U3801.3
MUX_SSEQ: length 3.6
  TOP w0.127: U3801.11 36.3,57.75 v1(37.08,56.97) 37.76,56.29 R3821.2 R3822.2
MUX_SW0_PD: length 6.3
  TOP w0.089: U3801.21 35.48,62.2 35.99,62.7 v1(37.03,62.7) 37.54,62.7 38.2,63.36 38.85,63.36 R3814.1 40.47,62.86 R3845.1
MUX_SW1_PD: length 8.8
  TOP w0.089: R3844.1 41.1,63.99 v1(41.1,64.46) 40.3,64.46 R3813.1 39.47,63.63 38.09,63.63 37.62,63.16 36.65,63.16 36.46,62.97 34.86,62.97 34.7,62.81 U3801.22
MUX_SW2_PD: length 5.3
  TOP w0.127: U3801.23 34.3,63.05 34.59,63.34 36.16,63.34 R3843.1 R3812.1 37.65,63.68 37.96,63.99 38.4,63.99 v1(38.41,63.99)
MUX_SW2_PD_R: length 2.1
  TOP w0.127: R3843.2 37.07,65.14 38.2,65.14 TP2902.1
MUX_TYPEC_RXN1: length 52.8
  TOP w0.102: R3835.1 22.57,93.26 22.96,93.26 v2(23.16,93.46) 23.57,93.87 v1(23.57,94.1) ; U3801.31 31.1,60.55 31.01,60.46 30.48,60.46 v2(30.15,60.79)
  L6 w0.127: v2(30.15,60.79) 30.15,61.23 29.75,61.62 29.75,63.86 29.26,64.35 29.26,68 29.75,68.5 29.75,69.8 28.8,70.76 28.8,71.65 28.34,72.11 27.38,72.11 26.16,73.33 24.5,73.33 23.97,73.87 22.01,73.87 21.39,74.49 21.39,76.24 21.26,76.37 20.42,76.37 20.14,76.65 20.14,77.13 20.42,77.41 21.26,77.41 21.39,77.54 21.39,77.94 20.98,78.34 20.98,82.72 20.56,83.14 20.56,83.87 20.84,84.15 22.38,84.15 22.5,84.28 22.5,84.72 22.38,84.85 20.91,84.85 20.58,85.17 20.58,89.09 20.87,89.37 22.75,89.37 23.44,90.06 23.44,91.79 23.26,91.98 22.62,91.98 22.1,92.5 22.1,93.05 22.51,93.46 v2(23.16,93.46)
MUX_TYPEC_RXN2: length 57.6
  TOP w0.102: U3801.39 31.22,57.35 30.67,56.79 30.67,56.57 v2(30.4,56.3) ; v2(18.87,96.8) 18.67,96.99 18.2,96.99 R3837.1
  L6 w0.127: v2(30.4,56.3) 30.63,56.07 30.63,55.8 30.49,55.66 30.16,55.66 27.39,58.42 27.39,60.44 27.07,60.76 27.07,69.41 25.37,71.11 20.93,71.11 20.85,71.19 20.85,71.19 16.03,76.01 16.03,84.09 14.83,85.28 14.83,89.48 17.71,92.36 17.71,96.99 17.91,97.18 18.13,97.18 18.26,97.05 18.26,96.61 18.39,96.49 18.74,96.49 18.87,96.61 v2(18.87,96.8)
MUX_TYPEC_RXP1: length 53
  TOP w0.102: R3834.1 22.44,93.03 22.96,93.03 v2(23.16,92.83) 23.34,93.01 24.1,93.01 v1(24.18,92.93) ; v2(30.78,60.89) 30.84,60.95 U3801.30
  L6 w0.127: v2(30.78,60.89) 31.09,61.19 31.09,61.59 30.92,61.75 30.7,61.75 30.48,61.54 30.22,61.54 30.02,61.73 30.02,63.97 29.53,64.47 29.53,67.89 30.02,68.38 30.02,69.91 29.07,70.87 29.07,71.76 28.45,72.38 27.49,72.38 26.27,73.6 24.61,73.6 24.08,74.13 22.12,74.13 21.65,74.6 21.65,76.35 21.37,76.64 20.53,76.64 20.41,76.76 20.41,77.02 20.53,77.14 21.37,77.14 21.65,77.43 21.65,78.05 21.25,78.45 21.25,82.83 20.82,83.25 20.82,83.76 20.95,83.89 22.49,83.89 22.77,84.17 22.77,84.83 22.49,85.12 21.02,85.12 20.85,85.28 20.85,88.97 20.98,89.1 22.86,89.1 23.71,89.95 23.71,91.9 23.37,92.24 22.73,92.24 22.36,92.61 22.36,92.94 22.62,93.2 22.79,93.2 v2(23.16,92.83)
MUX_TYPEC_RXP2: length 57.6
  TOP w0.102: U3801.40 31.14,56.95 30.89,56.7 30.89,56.47 v2(31.04,56.33) ; R3836.1 18.22,97.22 18.64,97.22 v2(18.86,97.45)
  L6 w0.127: v2(18.86,97.45) 17.8,97.45 17.45,97.1 17.45,92.47 14.57,89.59 14.57,85.17 15.76,83.98 15.76,75.9 20.74,70.92 20.74,70.92 20.82,70.84 25.26,70.84 26.81,69.3 26.81,60.65 27.12,60.33 27.12,58.31 29.88,55.55 30.05,55.39 30.6,55.39 30.9,55.68 30.9,56.19 v2(31.04,56.33)
MUX_TYPEC_TXN1: length 55
  TOP w0.102: v1(22.81,91.91) 22.73,91.91 v2(22.35,91.53) 22.2,91.69 C3863.1 ; U3801.34 31.1,59.35 31.01,59.26 30.48,59.26 v2(30.15,59.59)
  L6 w0.127: v2(30.15,59.59) 28.98,60.75 28.98,63.42 28.37,64.03 28.37,70.03 25.99,72.41 23.6,72.41 22.95,73.05 20.82,73.05 18.79,75.08 18.79,76.25 17.62,77.42 17.62,80.09 17.91,80.37 18.59,80.37 18.72,80.5 18.72,80.75 18.59,80.88 17.91,80.88 17.62,81.16 17.62,81.64 17.91,81.92 18.59,81.92 18.72,82.05 18.72,82.3 18.59,82.43 17.91,82.43 17.62,82.71 17.62,86.75 17.91,87.03 18.9,87.03 19.02,87.16 19.02,87.41 18.9,87.54 17.91,87.54 17.62,87.82 17.62,88.3 17.91,88.58 18.95,88.58 19.07,88.71 19.07,88.96 18.95,89.09 17.91,89.09 17.62,89.37 17.62,90.43 18.73,91.53 v2(22.35,91.53)
MUX_TYPEC_TXN1_C: length 2.7
  TOP w0.102: C3863.2 20.53,91.41 20.18,91.41 20.11,91.48 20.11,92.08 19.88,92.31 19.4,92.31 R3833.1
MUX_TYPEC_TXN2: length 56
  TOP w0.102: v2(20.8,98.9) 20.52,98.9 20.39,99.03 20.39,99.33 20.27,99.46 20.01,99.46 19.89,99.33 19.89,99 19.76,98.87 C3862.1 ; v2(30.61,58.36) 30.68,58.28 30.94,58.28 31.21,58.55 U3801.36
  L6 w0.127: v2(30.61,58.36) 30.22,58.36 28.46,60.12 28.46,62.94 27.85,63.55 27.85,69.83 25.78,71.9 21.26,71.9 17.12,76.04 17.12,90.64 18.92,92.45 18.92,94.94 20.64,96.65 20.64,97.72 20.05,98.3 19.88,98.47 19.78,98.57 19.78,99.18 19.95,99.34 20.23,99.34 20.32,99.25 20.32,98.92 20.42,98.82 20.72,98.82 v2(20.8,98.9)
MUX_TYPEC_TXN2_C: length 1.8
  TOP w0.102: C3862.2 18.25,99.15 17.28,99.15 R3839.1
MUX_TYPEC_TXP1: length 55
  TOP w0.102: U3801.33 30.84,59.75 v2(30.78,59.69) ; C3864.1 21.93,91.02 22.2,91.02 v2(22.35,90.87) 22.71,90.52 v1(22.71,90.39)
  L6 w0.127: v2(22.35,90.87) 22.03,90.56 21.68,90.56 21.56,90.67 21.56,91.14 21.44,91.27 18.84,91.27 17.89,90.32 17.89,89.48 18.02,89.36 19.06,89.36 19.34,89.07 19.34,88.6 19.06,88.32 18.02,88.32 17.89,88.19 17.89,87.93 18.02,87.81 19.01,87.81 19.29,87.52 19.29,87.05 19.01,86.77 18.02,86.77 17.89,86.64 17.89,82.82 18.02,82.7 18.7,82.7 18.98,82.41 18.98,81.94 18.7,81.66 18.02,81.66 17.89,81.53 17.89,81.28 18.02,81.15 18.7,81.15 18.98,80.87 18.98,80.39 18.7,80.11 18.02,80.11 17.89,79.98 17.89,77.53 19.06,76.36 19.06,75.19 20.93,73.32 23.06,73.32 23.71,72.67 26.1,72.67 28.64,70.14 28.64,64.14 29.25,63.53 29.25,60.86 29.97,60.14 30.63,60.14 30.78,59.99 v2(30.78,59.69)
MUX_TYPEC_TXP1_C: length 3.8
  TOP w0.102: R3832.1 19.4,92.08 19.78,92.08 19.88,91.98 19.88,91.39 20.09,91.18 20.43,91.18 C3864.2 21.23,90.38 v1(21.23,89.91)
MUX_TYPEC_TXP2: length 55.9
  TOP w0.102: v2(30.17,57.88) 30.86,57.88 31.13,58.15 U3801.37 ; C3861.1 20.36,99.69 20.51,99.53 v2(20.8,99.53)
  L6 w0.127: v2(20.8,99.53) 20.72,99.61 19.84,99.61 19.52,99.29 19.52,98.46 19.86,98.11 20.37,97.61 20.37,96.77 18.65,95.05 18.65,92.56 16.85,90.75 16.85,75.93 21.15,71.63 25.67,71.63 27.58,69.72 27.58,63.44 28.19,62.83 28.19,60.01 30.17,58.03 v2(30.17,57.88)
MUX_TYPEC_TXP2_C: length 1.8
  TOP w0.102: R3838.1 17.31,99.38 18.22,99.38 C3861.2
NCT7718_DXN: length 182.5
  TOP w0.254: v2(129.23,52.26) 129.21,52.24 129.21,51.87 129.72,51.36 129.72,48.28 130.61,47.39 133.48,47.39 135.2,45.66 135.2,42.87 134.57,42.23 v1(134.57,34.33) 134.57,32.26 135.86,30.96 135.86,28.63 136.19,28.3 136.19,26.66 136.9,25.95 v2(137.67,25.95)
  L3 w0.254: v2(129.23,52.26) 129.54,52.57 129.86,52.57 130.61,53.32 130.61,58.35 135.02,62.77 135.02,70.51 134.16,71.37 134.16,84.67 136.17,86.67 136.17,88.92 135.46,89.63 132.19,89.63 131.76,90.06 129.62,90.06 129.13,90.55 129.13,92.94 121.67,100.4 114.76,100.4 113.99,101.16 107.95,101.16 107.49,101.62 102.16,101.62 101.12,100.58 99.25,100.58 98.45,101.38 98.45,101.45 97.12,102.79 96.14,102.79 95.32,101.97 93.91,101.97 91.24,104.64 88.5,104.64 87.48,103.62 84.92,103.62 79.57,98.26 79.01,98.26 76.04,95.29 67.49,95.29 67.09,95.7 50.96,95.7 49.69,96.97 49.22,96.97 48.82,96.56 v2(48.82,96.44)
  BOTTOM w0.254: v2(137.67,25.95) 137.67,25.52 137.89,25.29 THM261.3 ; v2(48.82,96.44) 48.28,96.97 Q2603.E 47.62,97.33 C2607.2 46.23,95.94 46.23,95.72 45.41,94.91 C2606.2
NCT7718_DXP: length 182.8
  TOP w0.254: v2(138.35,25.85) 138.35,25.8 138,25.44 137.67,25.44 136.69,25.44 v1(136.1,26.03) 136.1,26.04 135.81,26.32 135.69,26.45 135.69,28.09 135.35,28.42 135.35,30.75 134.06,32.05 134.06,42.44 134.69,43.08 134.69,45.45 133.26,46.88 130.39,46.88 129.21,48.07 129.21,51.15 128.7,51.65 128.7,52.09 v2(128.52,52.26)
  L3 w0.254: v2(49.48,96.46) 50.75,95.19 66.88,95.19 67.28,94.78 76.25,94.78 79.22,97.76 79.78,97.76 85.14,103.12 87.69,103.12 88.71,104.13 91.03,104.13 93.7,101.46 95.53,101.46 96.35,102.28 96.91,102.28 97.94,101.24 97.94,101.17 99.04,100.07 101.33,100.07 102.37,101.11 107.28,101.11 107.74,100.65 113.78,100.65 114.54,99.89 121.46,99.89 128.62,92.73 128.62,90.34 129.41,89.55 131.54,89.55 131.98,89.12 135.25,89.12 135.66,88.71 135.66,86.88 133.65,84.88 133.65,71.16 134.52,70.3 134.52,62.98 130.1,58.56 130.1,53.53 129.65,53.08 128.9,53.08 128.52,52.7 v2(128.52,52.26)
  BOTTOM w0.254: THM261.2 138.45,25.95 v2(138.35,25.85) ; C2606.1 46.73,95.56 C2607.1 48.03,95.69 Q2603.B 50.03,95.43 50.47,95.88 Q2603.C 49.55,96.38 v2(49.48,96.46)
OC_1: length 1.8
  TOP w0.102: R3722.2 28.64,45.73 U3703.4
OC_2: length 2.8
  TOP w0.102: U3704.4 24.83,50 23.94,49.1 R3723.2 23.64,49.1 23.02,49.1 22.73,49.38 v1(22.73,49.42)
OVER_CURRENT_P8#: length 47.9
  TOP w0.102: v2(179.04,55.29) 179.68,54.65 v1(179.68,54.09) 179.68,53.17 R2474.1
  L3 w0.102: v2(178.51,89.96) 179.3,89.17 179.3,73.35 176.03,70.08 176.03,63.86 178.83,61.06 178.83,56.99 179.04,56.3 v2(179.04,55.29)
  BOTTOM w0.102: GPU1.C2 172.45,91.17 173,91.71 177.44,91.71 177.75,91.41 177.75,90.72 v2(178.51,89.96)
P_SYS: length 122
  TOP w0.102: v2(164.34,43.76) 164.34,43.63 166.85,41.11 166.85,35.75 166.24,35.14 166.24,34.43 166.47,34.21 v2(166.47,32.63) ; PR4671.1 160.43,91.92 v2(160.93,92.42)
  L3 w0.102: v2(165.81,66.62) 165.83,66.64 165.83,69.1 165.91,69.18 165.91,70.13 164.67,71.37 164.67,80.05 160.32,84.4 160.32,89.32 161.62,90.62 161.62,92.17 161.36,92.42 v2(160.93,92.42)
  L4 w0.102: v2(165.81,66.62) 166.29,66.13 166.29,58.18 164.74,56.63 164.74,44.16 v2(164.34,43.76)
  L6 w0.102: v2(138.96,28.22) 138.96,28.26 141.22,30.52 149.88,30.52 150.75,31.39 159.87,31.39 160.93,32.45 162.76,32.45 163.02,32.2 166.04,32.2 v2(166.47,32.63) 168.07,32.63 169.03,31.67 175.72,31.67 176.79,30.6 178.69,30.6 179.07,30.22 183.92,30.22 184.4,30.7 v2(184.4,30.7)
  BOTTOM w0.102: v2(184.4,30.7) 184.4,30.85 185.07,31.52 R2422.1 ; PR4401.1 140.65,29.87 PG4415.2 140.5,29.72 PC4430.1 140.5,28.53 140.19,28.22 v1(139.83,28.22) v2(138.96,28.22)
PANEL_BKEN_EC: length 214.3
  TOP w0.127: v2(89.2,100.93) 90.7,100.93 v1(91.67,99.97) 91.67,99.26 92.53,98.4 93.38,98.4 93.85,98.87 96.09,98.87 97.08,97.88 RN5501.7 ; KBC24.117 192.81,29.97 191.41,31.36 191.41,33.32 191.67,33.57 191.67,34.1 191.31,34.46 v2(191.23,34.46)
  L3 w0.127: v2(191.23,34.46) 191.21,34.48 190.78,34.48 189.46,35.81 189.46,37.17 188.66,37.96 188.24,37.96 185.52,40.69 185.52,41.95 184.66,42.82 181.91,42.82 181.46,43.27 181.46,43.76 180.01,45.2 180.01,47.44 179.72,47.73 179.72,49.29 179.36,49.65 179.36,50.36 178.74,50.98 178.74,52.67 177.86,53.55 177.86,60.53 175.09,63.3 175.09,70.79 178.27,73.98 178.27,85.19 177.13,86.34 177.13,88.31 177.33,88.51 177.33,91.16 178.94,92.77 178.94,95.62 178.61,95.95 176.92,95.95 175.37,97.5 170.89,97.5 166.98,101.41 166.98,103.95 165.35,105.58 165.35,107.56 161.4,111.51 87.19,111.51 87.05,111.37 86.99,111.37 84.91,109.29 84.91,107.29 83.57,105.95 79.71,102.09 79.53,102.09 79.34,101.9 v2(79.25,101.9)
  L6 w0.127: v2(89.2,100.93) 89.2,101.24 88.83,101.6 88.49,101.6 88.04,102.05 81.5,102.05 81.3,101.85 79.3,101.85 v2(79.25,101.9)
PBAT_PRES1#: length 4.8
  TOP w0.102: RN4302.8 164.6,24.41 AFTP4309.1 165.58,24.35 v2(165.58,25.04)
  BOTTOM w0.102: v2(165.58,25.04) 165.7,25.15 BATT1.6
PBAT_PRES#: length 47.5
  TOP w0.102: RN4302.1 165.05,26.41 165.26,26.62 EC4306.2 166.03,26.46 v2(166.6,26.46) 166.77,26.63 166.77,27.01 v1(166.77,27.02) ; KBC24.97 184.81,28.08 184.68,27.96 v2(184.22,27.96)
  L6 w0.102: v2(153.86,24.09) 153.88,24.11 164.07,24.11 165.15,25.19 165.15,25.59 166.01,26.46 v2(166.6,26.46) 173.45,26.46 176.2,29.2 177.34,29.2 179.42,27.12 180.74,27.12 181.63,26.23 182.22,26.23 183.95,27.96 v2(184.22,27.96)
  BOTTOM w0.102: v2(184.22,27.96) 184.28,27.96 184.3,27.98 184.58,27.98 185.01,27.55 185.91,27.55 R2415.1 ; v2(153.86,24.09) 153.13,24.82 153.13,26.03 151.12,28.05 D4304.3
PBAT_SMBCLK1: length 5.2
  TOP w0.254: RN4302.6 163.45,24.81 v2(163.24,24.6) 162.63,23.99 AFTP4311.1
  BOTTOM w0.254: BATT1.4 161.69,26.65 161.69,26.15 v2(163.24,24.6)
PBAT_SMBDAT1: length 5
  TOP w0.254: RN4302.7 163.95,24.88 163.95,24.88 v2(163.95,24.6) 163.95,23.26 AFTP4310.1
  BOTTOM w0.254: BATT1.5 163.7,24.86 v2(163.95,24.6)
PCH_ALW_ON: length 143.7
  TOP w0.102: KBC24.71 184.08,40.24 184.43,39.89 185.01,39.89 185.42,40.3 185.42,41.01 186.23,41.82 186.83,41.82 v2(187.17,42.17) ; v2(108.74,14.47) v1(108.74,15.03)
  L3 w0.102: v2(108.74,14.47) 109.4,13.81 111.28,13.81 112.11,12.97 113.38,12.97 116.85,9.49 117.39,9.49 121.27,5.6 122.25,5.6 124.43,3.42 124.92,3.42 125.09,3.24 125.35,2.99 125.35,2.99 125.8,2.53 126.13,2.53 126.67,2 127.71,2 128.07,2.35 128.55,2.35 128.74,2.16 153.5,2.16 153.51,2.18 154.46,2.18 155.37,3.08 155.37,5.26 157.31,7.2 174.01,7.2 174.6,7.79 186.94,7.79 189.38,10.23 189.38,12.9 190.32,13.83 194.91,13.83 198.66,17.59 198.66,30.15 195.25,33.57 195.25,36.67 195,36.92 194.26,36.92 192.66,38.52 192.25,38.52 190.22,40.56 188.41,40.56 187.17,41.79 v2(187.17,42.17)
  BOTTOM w0.102: v2(108.74,14.47) 108.74,13.92 R4102.1 ; R2495.1 186.51,43.15 187.17,42.49 v2(187.17,42.17)
PCH_BATLOW#: length 34
  L4 w0.102: v2(101.85,21.68) 101.8,21.63 101.06,21.63 100.81,21.88 100.81,21.89 100.38,22.32 100.38,25.62 99.49,26.51 99.49,32.2 99.95,32.66 101.6,32.66 104.04,35.09 104.04,38.95 104.24,39.16 104.24,42.08 104.6,42.43 104.6,42.46 106.22,44.09 v2(106.73,44.09)
  BOTTOM w0.102: v2(101.85,21.68) 102.11,21.68 102.28,21.86 104.87,21.86 v1(105.13,21.6) 105.41,21.33 105.41,20.74 105.67,20.49 RN1704.6 ; v2(106.73,44.09) 106.4,43.76 CPU1.AU13
PCH_DPC_N0: length 162.1
  TOP w0.102: v1(42.75,54.91) 42.47,54.91 v2(42.16,55.21) 41.98,55.39 C3813.1
  L6 w0.127: v2(42.16,55.21) 42.34,55.03 43.05,55.03 44.79,56.77 44.79,63.92 43.37,65.34 43.37,74.27 43.2,74.44 43.2,77.79 44.73,79.32 44.73,82.72 44.47,82.97 44.47,88.59 46.12,90.24 46.12,90.69 47.09,91.66 47.09,93.01 49.3,95.22 52.14,95.22 52.65,95.72 55.35,95.72 55.81,96.18 63.02,96.18 63.26,96.42 70.97,96.42 71.84,95.56 73.75,95.56 74.64,96.45 78.37,96.45 78.77,96.04 79.69,96.04 80.18,95.55 95.78,95.55 96.9,96.66 100.4,96.66 101.52,95.55 105.69,95.55 106.22,96.08 110.51,96.08 111.06,95.53 120.81,95.53 126.6,89.74 126.6,88.72 128.05,87.28 130.16,87.28 131.99,85.45 131.99,81.72 129.06,78.78 129.06,74.37 128.23,73.54 128.23,70.7 127.7,70.16 127.7,69.22 125.8,67.33 125.8,66.21 124.4,64.81 v2(124.4,64.21)
  BOTTOM w0.102: v2(124.4,64.21) 124.4,64.49 CPU1.C50
PCH_DPC_N0_C: length 7.3
  TOP w0.102: C3813.2 40.31,55.39 39.77,54.86 ; v1(39.67,54.96) 39.77,54.86 ; 39.77,54.86 39.57,54.65 37.45,54.65 36.63,55.46 36.63,56.9 36.18,57.35 U3801.10
PCH_DPC_N1: length 164.7
  TOP w0.102: v1(42.75,58.13) 42.16,57.55 v2(42.16,57.24) 42.04,57.37 C3807.1
  L6 w0.127: v2(42.16,57.24) 42.34,57.07 43.66,57.07 44.02,57.42 44.02,57.82 43.89,57.95 43.5,57.95 43.22,58.23 43.22,58.7 43.5,58.99 43.89,58.99 44.02,59.11 44.02,62.45 43.38,63.09 43.38,64.18 42.59,64.96 42.59,73.73 42.29,74.03 42.29,78.3 43.51,79.52 43.51,90.21 44.38,91.08 45.34,91.08 45.62,91.36 45.62,92.65 48.97,96 51.43,96 53.48,98.05 55.15,98.05 56.25,96.96 62.63,96.96 62.87,97.2 70.39,97.2 71.25,98.06 72.95,98.06 73.79,97.22 79,97.22 79.26,97.49 100.87,97.49 101.45,96.91 103.52,96.91 103.85,97.24 104.66,97.24 105.04,96.85 110.85,96.85 111.39,96.32 121.14,96.32 127.39,90.07 127.39,89.33 128.66,88.07 130.49,88.07 132.78,85.78 132.78,81.39 130.85,79.46 130.85,76.84 129.84,75.84 129.84,74.03 128.95,73.14 128.95,69.2 129.45,68.71 129.45,67.8 128.4,66.74 v2(127.96,66.74)
  BOTTOM w0.089: CPU1.C52 124.82,66.03 125.03,66.03 125.16,66.09 125.36,66.09 125.45,66.05 125.72,66.05 125.81,66.09 126.71,66.09 126.79,66.16 127.29,66.16 127.88,66.74 v2(127.96,66.74)
PCH_DPC_N1_C: length 5.7
  TOP w0.102: 38.53,57.17 40.42,57.17 C3807.2 ; 38.53,57.17 37.98,57.17 36.6,58.55 U3801.13 ; 38.53,57.17 v1(38.53,57.29)
PCH_DPC_N2: length 164.6
  TOP w0.102: C3808.1 42.04,60.04 v2(42.16,59.91)
  L6 w0.127: v2(42.16,59.91) 42.33,59.74 42.96,59.74 43.24,60.02 43.24,62.11 42.61,62.75 42.61,63.83 41.72,64.72 41.72,72.85 41.32,73.24 41.32,78.71 42.72,80.1 42.72,90.57 43.69,91.53 43.69,91.84 46.84,94.99 46.84,95.52 49.8,98.48 52.77,98.48 53.12,98.82 55.5,98.82 56.59,97.73 62.3,97.73 62.61,98.04 70.13,98.04 70.93,98.84 73.73,98.84 74.53,98.04 78.69,98.04 78.92,98.26 102.89,98.26 103.13,98.02 104.99,98.02 105.37,97.64 111.18,97.64 111.72,97.11 121.47,97.11 128.18,90.4 128.18,89.66 128.99,88.85 130.82,88.85 133.56,86.11 133.56,81.06 132.83,80.33 132.83,80.15 133.52,79.46 133.52,79.06 133.18,78.72 132.78,78.72 132.09,79.41 131.92,79.41 131.63,79.13 131.63,76.51 130.64,75.52 130.64,73.72 129.75,72.83 129.75,69.52 130.24,69.04 130.24,67.47 129.72,66.95 129.72,66.69 129.36,66.34 v2(128.85,66.34)
  BOTTOM w0.102: CPU1.A50 125.95,64.66 128.07,64.66 128.28,64.87 ; v1(128.19,64.96) 128.28,64.87 ; 128.28,64.87 129.06,65.64 129.06,66.13 v2(128.85,66.34)
PCH_DPC_N2_C: length 5.2
  TOP w0.102: C3808.2 40.27,59.68 39.67,59.68 ; 39.67,59.68 36.44,59.68 36.37,59.75 U3801.16 ; 39.67,59.68 v1(39.67,59.81)
PCH_DPC_N3: length 166
  TOP w0.102: C3810.1 42.04,61.81 v2(42.16,61.69) 42.49,62.02 v1(42.49,62.25)
  L6 w0.127: v2(42.16,61.69) 42.16,61.87 42.04,61.99 41.71,61.99 41.58,61.87 41.58,61.45 41.45,61.32 41.22,61.32 41.06,61.48 41.06,71.96 40.45,72.57 40.45,79.26 42.2,81.01 42.2,90.79 43.04,91.63 43.04,91.93 45.81,94.7 45.81,95.21 49.59,98.99 52.56,98.99 52.91,99.33 55.71,99.33 56.8,98.24 62.07,98.24 62.91,99.08 66.16,99.08 66.68,98.56 69.93,98.56 70.71,99.34 73.94,99.34 74.72,98.56 75.37,98.56 78.47,98.56 78.63,98.71 78.71,98.8 103.1,98.8 103.35,98.54 105.21,98.54 105.59,98.16 111.4,98.16 111.94,97.63 121.69,97.63 128.7,90.62 128.7,90.03 129.36,89.37 131.04,89.37 134.08,86.33 134.08,77.59 132.37,75.87 131.97,75.87 131.28,75.19 131.28,73.59 130.33,72.64 130.33,69.69 130.76,69.26 130.76,67 129.78,66.02 129.78,66.02 129.08,65.32 127.89,65.32 127.76,65.45 v2(127.76,65.7)
  BOTTOM w0.102: CPU1.D51 124.52,65.26 124.81,64.97 127.03,64.97 v2(127.76,65.7)
PCH_DPC_N3_C: length 5.4
  TOP w0.102: U3801.19 36.3,60.95 36.37,60.88 37.01,60.88 37.47,61.33 39.55,61.33 ; C3810.2 40.14,61.33 39.55,61.33 ; v1(39.55,61.46) 39.55,61.33
PCH_DPC_P0: length 162.2
  TOP w0.102: v2(123.42,64.2) 123.52,64.2 v1(123.87,64.56) ; v2(42.16,54.58) 42.09,54.5 C3812.1
  L6 w0.127: v2(42.16,54.58) 42.35,54.77 43.16,54.77 45.06,56.66 45.06,64.03 43.64,65.45 43.64,74.38 43.47,74.55 43.47,77.68 44.99,79.21 44.99,82.83 44.74,83.08 44.74,88.48 46.39,90.13 46.39,90.58 47.36,91.55 47.36,92.9 49.41,94.95 52.25,94.95 52.76,95.46 55.46,95.46 55.92,95.91 63.13,95.91 63.25,96.04 63.37,96.16 70.86,96.16 71.73,95.29 73.86,95.29 74.75,96.18 78.26,96.18 78.66,95.77 79.58,95.77 80.07,95.28 95.89,95.28 97.01,96.4 100.29,96.4 101.41,95.28 105.8,95.28 106.33,95.81 110.4,95.81 110.95,95.27 120.7,95.27 126.34,89.63 126.34,88.61 127.94,87.01 130.05,87.01 131.72,85.34 131.72,81.83 128.79,78.89 128.79,74.48 127.96,73.65 127.96,70.81 127.43,70.27 127.43,69.33 125.54,67.44 125.54,66.32 124.13,64.92 124.13,64.59 123.75,64.2 v2(123.42,64.2)
  BOTTOM w0.102: CPU1.D50 123.47,64.2 v2(123.42,64.2)
PCH_DPC_P0_C: length 7.2
  TOP w0.102: 37.01,54.76 36.41,55.37 36.41,56.8 36.26,56.95 U3801.9 ; 37.01,54.76 37.35,54.42 39.67,54.42 40,54.75 40.37,54.75 C3812.2 ; 37.01,54.76 v1(36.9,54.65)
PCH_DPC_P1: length 164.2
  TOP w0.102: C3814.1 42.04,56.48 v2(42.16,56.61) 42.47,56.91 v1(42.75,56.91)
  L6 w0.127: v2(128.27,67.33) 128.29,67.3 128.58,67.3 129.18,67.91 129.18,68.6 128.69,69.09 128.69,73.25 129.58,74.14 129.58,75.95 130.58,76.95 130.58,79.57 132.51,81.5 132.51,85.67 130.38,87.8 128.55,87.8 127.13,89.22 127.13,89.96 121.03,96.05 111.28,96.05 110.74,96.59 104.93,96.59 104.54,96.97 103.96,96.97 103.63,96.64 101.34,96.64 100.76,97.22 79.37,97.22 79.11,96.96 73.67,96.96 72.84,97.79 71.36,97.79 70.5,96.93 62.98,96.93 62.74,96.69 56.14,96.69 55.04,97.78 53.59,97.78 51.54,95.74 49.08,95.74 45.88,92.54 45.88,91.24 45.45,90.81 44.49,90.81 43.78,90.1 43.78,79.41 42.56,78.19 42.56,74.14 42.86,73.84 42.86,65.08 43.65,64.29 43.65,63.2 44.28,62.56 44.28,59 44,58.72 43.61,58.72 43.48,58.59 43.48,58.34 43.61,58.21 44,58.21 44.28,57.93 44.28,57.31 43.77,56.8 42.35,56.8 v2(42.16,56.61)
  BOTTOM w0.089: 128,67.33 127.58,66.9 127.58,66.71 127.21,66.35 126.71,66.35 126.62,66.26 125.78,66.26 125.69,66.23 125.49,66.23 125.4,66.26 125.13,66.26 124.99,66.21 124.35,66.21 CPU1.D52
  BOTTOM w0.102: v2(128.27,67.33) 128,67.33
PCH_DPC_P1_C: length 5.7
  TOP w0.102: 39.7,56.94 37.88,56.94 36.67,58.15 U3801.12 ; 39.7,56.94 40.17,56.94 C3814.2 ; 39.7,56.94 v1(39.7,56.79)
PCH_DPC_P2: length 165.2
  TOP w0.102: v1(42.67,59.58) 42.37,59.27 v2(42.16,59.27) 42.04,59.15 C3809.1
  L6 w0.127: v2(42.16,59.27) 42.37,59.48 43.07,59.48 43.51,59.91 43.51,62.22 42.87,62.86 42.87,63.94 41.98,64.83 41.98,72.96 41.59,73.36 41.59,78.6 42.99,79.99 42.99,90.46 43.95,91.42 43.95,91.73 47.1,94.88 47.1,95.41 49.91,98.21 52.88,98.21 53.23,98.56 55.39,98.56 56.48,97.46 62.42,97.46 62.72,97.77 70.24,97.77 71.04,98.57 73.62,98.57 74.42,97.77 78.8,97.77 79.03,98 102.78,98 103.02,97.76 104.87,97.76 105.26,97.37 111.07,97.37 111.61,96.84 121.36,96.84 127.91,90.29 127.91,89.55 128.88,88.59 130.71,88.59 133.3,86 133.3,81.17 132.56,80.44 132.56,80.04 133.25,79.35 133.25,79.17 133.07,78.99 132.89,78.99 132.21,79.68 131.81,79.68 131.37,79.24 131.37,76.62 130.38,75.63 130.38,73.83 129.49,72.94 129.49,69.41 129.97,68.93 129.97,67.58 v2(129.26,66.87)
  BOTTOM w0.102: CPU1.B50 125.53,64.43 128.17,64.43 129.28,65.55 129.28,66.84 v2(129.26,66.87)
PCH_DPC_P2_C: length 5
  TOP w0.102: C3809.2 40.32,59.45 36.48,59.45 36.37,59.35 U3801.15
PCH_DPC_P3: length 166
  TOP w0.102: v2(127.13,65.65) 127.13,65.8 v1(126.77,66.16) ; C3811.1 42.04,60.93 v2(42.16,61.05)
  L6 w0.127: v2(42.16,61.05) 41.11,61.05 40.79,61.37 40.79,71.85 40.18,72.46 40.18,79.37 41.93,81.12 41.93,90.9 42.77,91.74 42.77,92.04 45.54,94.81 45.54,95.32 49.48,99.25 52.45,99.25 52.8,99.6 55.82,99.6 56.91,98.51 61.96,98.51 62.8,99.34 66.27,99.34 66.79,98.82 69.82,98.82 70.6,99.61 74.05,99.61 74.83,98.82 75.26,98.82 78.36,98.82 78.6,99.06 103.21,99.06 103.46,98.81 105.32,98.81 105.7,98.43 111.51,98.43 112.05,97.9 121.8,97.9 128.97,90.73 128.97,90.14 129.47,89.64 131.15,89.64 134.35,86.44 134.35,77.48 132.48,75.61 132.08,75.61 131.55,75.08 131.55,73.48 130.59,72.52 130.59,69.8 131.02,69.37 131.02,66.89 130.05,65.91 130.05,65.91 129.2,65.05 127.72,65.05 v2(127.13,65.65)
  BOTTOM w0.102: v2(127.13,65.65) 126.67,65.2 125,65.2 CPU1.C51
PCH_DPC_P3_C: length 5.2
  TOP w0.102: C3811.2 40.45,61.1 37.56,61.1 37.11,60.65 36.38,60.65 36.28,60.55 U3801.18
PCH_DPWROK: length 147.3
  TOP w0.127: v2(104.06,18.97) 104.06,19.14 103.82,19.38 101.36,19.38 100.81,19.93 100.35,19.93 99.48,20.81 v1(99.15,20.81) v2(98.73,21.23)
  L4 w0.127: v2(160.58,25.62) 160.48,25.52 153.6,25.52 152.54,24.45 152.54,24.37 150.66,22.5 149.66,22.5 148.03,20.87 148.03,20.79 147.45,20.21 145.97,20.21 144.19,18.43 143.36,18.43 143.13,18.2 141.12,18.2 138.96,16.04 134.54,16.04 134.25,15.75 126.27,15.75 125.4,16.63 122.51,16.63 121.9,17.24 116.09,17.24 115.34,17.99 110.81,17.99 110.18,18.62 110.18,18.96 109.61,19.54 104.63,19.54 v2(104.06,18.97)
  L6 w0.127: v2(183.82,29.1) 183.64,29.1 182.36,27.82 179.08,27.82 177.46,29.44 176.08,29.44 173.56,26.92 166.04,26.92 165,25.87 160.83,25.87 v2(160.58,25.62)
  BOTTOM w0.127: EC1711.1 104.06,19.59 v2(104.06,18.97) 104.05,18.95 R1718.1 103.59,17.44 R1704.2 ; R2497.1 184.83,28.97 184.58,29.23 183.95,29.23 v2(183.82,29.1) ; CPU1.BB20 103.27,47.36 102.88,46.97 99.65,46.97 98.73,46.04 96.3,46.04 94.94,44.69 94.94,43.63 95.1,43.48 95.1,43.08 94.71,42.69 94.29,42.69 86.47,34.87 86.47,23.86 88.43,21.91 88.43,21.62 89.54,20.5 98.02,20.5 98.73,21.21 v2(98.73,21.23)
PCH_JTAG_TCK: length 8.6
  TOP w0.114: R407.1 123.91,69.49 124.56,69.49 v1(125.29,68.76) 125.65,68.39 126.77,68.39 127.68,69.31 128.09,69.31 128.13,69.27 v2(128.19,69.27)
  BOTTOM w0.089: CPU1.B56 125.65,68.53 125.72,68.53 125.81,68.56 126.07,68.56 126.21,68.42 126.25,68.42 126.26,68.41 126.72,68.41 127.19,68.88 127.2,68.88 127.25,68.92 127.28,68.92 127.28,68.93 127.34,68.93 127.39,68.98 127.61,68.98 127.86,69.23 128.13,69.23 128.17,69.27 v2(128.19,69.27)
PCH_JTAG_TDI: length 9.2
  BOTTOM w0.089: v1(128.13,70.03) 128.08,70.03 128.04,69.99 128.01,69.99 127.91,69.89 127.8,69.89 127.19,69.28 127.14,69.28 127.13,69.28 126.8,69.28 126.71,69.37 126.32,69.37 126.23,69.27 126.13,69.24 126.09,69.22 125.74,69.22 125.68,69.24 125.44,69.24 125.32,69.36 124.26,69.36 CPU1.D59
  BOTTOM w0.114: v1(128.13,70.03) 128.82,70.03 130.03,68.82 130.03,68.25 130.15,68.13 130.15,67.5 130.55,67.1 R408.1
PCH_JTAG_TDO: length 7.5
  BOTTOM w0.089: CPU1.A56 126.05,68.3 126.12,68.23 126.8,68.23 127.26,68.7 127.68,68.7 127.84,68.86 128.92,68.86 129.79,67.99
  BOTTOM w0.114: R409.1 130.74,66.01 130.33,66.01 v1(130.12,66.21) 130.12,67.16 129.9,67.38 129.9,67.88 129.79,67.99
PCH_JTAG_TMS: length 8.3
  BOTTOM w0.089: CPU1.C59 124.83,69.66 125.09,69.92 126.46,69.92 126.8,70.25 127.43,70.25
  BOTTOM w0.114: R416.1 130.69,69.38 v1(130.15,69.92) 130.15,70.36 129.38,71.14 128.65,71.14 128.13,70.61 127.85,70.61 127.48,70.25 127.43,70.25
PCH_PLTRST#: length 27.6
  TOP w0.127: v1(107.9,24.76) 108,24.86 v2(108.51,24.86)
  L4 w0.127: v2(108.51,24.86) 108.51,24.93 109.6,26.03 109.6,30.29 111.16,31.86 111.16,32.64 110.88,32.92 110.88,35.22 110.74,35.36 110.74,37.1 110.54,37.3 110.54,38.83 110.74,39.03 110.74,41.25 110.22,41.78 109.77,41.78 v2(109.33,41.34)
  BOTTOM w0.127: v2(109.33,41.34) 109,41.67 CPU1.AN10 ; v2(108.51,24.86) 109.1,24.26 109.75,24.26 109.97,24.49 110.34,24.49 110.74,24.09 110.74,23.14 111.1,22.78 112.27,22.78 113.1,23.61 R1713.2
PCH_POPIRCOMP: length 17
  TOP w0.203: 104.11,46.16 105.07,46.16 105.27,46.36 106.28,46.36 v2(106.73,45.92)
  TOP w0.508: R413.1 94.83,53.12 97.25,50.69 97.25,48.56 98.04,47.77 102.5,47.77 v1(103.7,46.57) 104.11,46.16
  BOTTOM w0.305: CPU1.AU16 106.73,45.78 v2(106.73,45.92)
PCH_RSMRST#: length 186
  TOP w0.127: v2(67.03,11.24) 67.26,11.01 EC1712.1 67.55,10.89 R1702.2 ; v2(184.4,33.82) 184.4,33.82 184.02,33.44 KBC24.88
  L3 w0.127: v2(192.68,10.35) 191.97,10.35 191.6,10.72 191.22,10.72 187.96,7.46 174.62,7.46 174.12,6.95 157.4,6.95 155.62,5.18 155.62,2.98 154.57,1.92 129.23,1.92 128.79,1.48 122.18,1.48 119.75,3.91 119.75,5.17 117.37,7.55 112.66,7.55 110.3,5.18 110.3,3.23 v2(111.15,2.38) ; v2(186.28,13.78) 186.28,14.24 191.74,19.7 191.74,22.65 188.77,25.62 186.97,25.62 186.38,26.2 186.38,29.23 185.99,29.62 185.99,30.2 186.87,31.08 186.87,31.87 186.21,32.53 185.7,32.53 184.4,33.82 v2(184.4,33.82)
  L4 w0.127: v2(111.15,2.38) 111.15,2.29 110.38,1.53 104.15,1.53 103.94,1.74 75,1.74 74.27,2.48 70.54,2.48 68.88,4.14 68.88,7.26 68.58,7.56 68.58,8.93 66.9,10.61 66.9,11.12 v2(67.03,11.24)
  BOTTOM w0.127: v2(186.28,13.78) v1(187.48,13.78) 188.21,13.78 190.96,11.04 190.96,10.11 191.23,9.83 191.76,9.83 192.28,10.35 v2(192.68,10.35)
PCH_SMBCLK: length 76.3
  TOP w0.089: v2(104.32,15.46) 104.81,15.96 RN1810.3
  L3 w0.127: v2(61.85,11.07) 61.9,11.01 61.9,10.41 62.21,10.1 65.61,10.1 65.96,9.74 66.8,9.74 68.25,8.3 76.17,8.3 79.04,11.17 82.73,11.17 85.98,14.42 88.09,14.42 88.54,14.88 103.73,14.88 104.31,15.46 v2(104.32,15.46)
  L4 w0.127: v2(61.85,11.07) 61.95,11.17 61.95,20.13 61.49,20.59 v2(61.49,21.35)
  BOTTOM w0.089: DM1.253 68.82,22.48 66.5,20.16 65.2,20.16 64.95,20.41 63.04,20.41 62.6,20.86 62.22,20.86 61.72,21.35 v2(61.49,21.35) 61.24,21.61 61.24,22.27 60.82,22.68 DM2.253 ; v2(104.32,15.46) 104.32,15.47 v1(103.9,15.88) 103.75,16.03 Q1801.4
PCH_SMBDATA: length 78
  TOP w0.089: v2(103.55,15.45) 103.67,15.45 104.24,16.02 104.24,16.96 104.36,17.08 RN1810.4 ; v2(62.13,21.56) 62.13,21.02 v1(61.84,20.74) 61.11,20.01 59.13,20.01 58.72,20.41 57.63,20.41 56.89,21.15 55.4,21.15 v2(54.84,21.71)
  L3 w0.127: v2(103.55,15.45) 103.55,15.38 103.45,15.28 88.36,15.28 87.93,14.85 85.82,14.85 82.57,11.6 78.89,11.6 76.76,9.47 72.57,9.47 71.85,8.75 68.48,8.75 67.03,10.2 66.24,10.2 65.86,10.58 v2(62.36,10.58)
  L4 w0.127: v2(62.13,21.56) 62.13,20.77 62.36,20.54 v2(62.36,10.58)
  BOTTOM w0.089: v2(54.84,21.71) 54.84,21.96 54.46,22.34 51.92,22.34 51.82,22.44 DM2.254 ; DM1.254 62.81,22.23 v2(62.13,21.56) ; Q1801.1 101.36,14.73 101.88,14.22 103.05,14.22 103.35,14.52 103.35,15.13 103.55,15.33 v2(103.55,15.45)
PCH_THERMTRIP#: length 10.1
  BOTTOM w0.089: 128.06,73.77 126.9,72.61 125.32,72.61 124.85,72.13 CPU1.C63
  BOTTOM w0.102: R419.2 132.4,74.62 131.09,74.62 EC401.1 130.54,75.07 v1(129.79,75.07) 129.37,75.07 128.06,73.77
PCH_WAKE#: length 44.2
  TOP w0.102: v2(100.58,44.67) 100.54,44.67 v1(100.05,44.18)
  L4 w0.102: v2(105.87,20.92) 105.33,20.39 104.27,20.39 103.73,19.85 99.57,19.85 98.65,20.77 97.25,20.77 96.33,21.68 95.14,21.68 94.74,22.08 94.74,23.36 95.07,23.69 95.07,26.38 94.97,26.48 94.97,34.97 99.24,39.23 99.24,41.06 100.94,42.76 100.94,43.32 101.86,44.25 101.86,44.58 101.63,44.81 100.72,44.81 v2(100.58,44.67)
  BOTTOM w0.102: v2(105.87,20.92) 106.07,20.72 106.07,20.72 106.17,20.62 RN1704.7 ; v2(100.58,44.67) 100.91,45 101.79,45 101.98,44.81 103.15,44.81 CPU1.BB15
PCI_CLK_LPC0: length 29.1
  TOP w0.089: R1804.1 91.02,27.11 88.47,29.66 v1(88.47,31.54) 88.47,34.79 89.43,35.75 v2(91.01,35.75)
  BOTTOM w0.089: v2(91.01,35.75) 91.56,35.75 96.23,40.43 100.46,40.43 101.24,41.22 101.85,41.22 102.32,41.68 103.02,41.68 103.14,41.73 103.41,41.73 103.52,41.7 103.71,41.7 103.82,41.74 104.15,41.74 104.19,41.7 104.2,41.7 104.32,41.57 104.72,41.57 105,41.29 CPU1.AW9
PCI_CLK_LPC1: length 27.5
  TOP w0.089: v2(90.57,35.25) 90.33,35.49 89.54,35.49 88.73,34.68 88.73,31.92 89.21,31.44 89.21,30.47 v1(89.2,30.47) 89.2,29.3 90.61,27.89 R1805.1
  BOTTOM w0.089: CPU1.AY9 104.35,41.29 104.12,41.52 104.12,41.52 104.08,41.55 104.06,41.55 104.06,41.56 103.84,41.56 103.75,41.52 103.47,41.52 103.38,41.55 103.18,41.55 103.1,41.52 103.1,41.52 103.05,41.5 102.39,41.5 101.93,41.04 101.37,41.04 100.51,40.17 96.53,40.17 91.6,35.25 v2(90.57,35.25)
PCIE_CLK_XDP_N: length 1.8
  TOP w0.102: v2(122.23,61.43) 122.65,61 TP1802.1
  BOTTOM w0.102: v2(122.23,61.43) 122.54,61.11 CPU1.F43
PCIE_CLK_XDP_P: length 1.9
  TOP w0.102: v2(122.86,61.47) 123.52,62.12 TP1803.1
  BOTTOM w0.102: CPU1.E43 123.19,61.14 v2(122.86,61.47)
PCIE_RCOMPN: length 1.9
  TOP w0.305: v1(122.05,40.07) 122.05,39.68 v2(122.22,39.51) 122.22,38.83 R1604.1
  BOTTOM w0.305: v2(122.22,39.51) 122.22,39.38 CPU1.F5
PCIE_RCOMPP: length 1.4
  TOP w0.305: R1604.2 122.87,39.06 v2(122.87,39.51)
  BOTTOM w0.305: CPU1.E5 123.19,39.19 v2(122.87,39.51)
PCIE_RX_CPU_N5: length 153.7
  TOP w0.102: v1(170.48,55.13) v2(169.92,55.13)
  L3 w0.089: v2(122.88,45.91) 122.89,45.92 122.89,46.19 122.83,46.25 121.14,46.25 120.67,45.79
  L3 w0.14: 120.67,45.79 120.5,45.61 120.5,38.37 121.21,37.66 122.73,37.66 124.05,36.33 124.05,33.47 121.99,31.41 121.99,29.35 121.74,29.1 121.74,24.12 124.83,21.04 128.71,21.04 129.64,20.1 129.64,18.66 131.25,17.05 133.92,17.05 134.43,16.54 134.43,14.1 134.31,13.99 134.31,11.78 135.48,10.61 136.02,10.61 137.54,9.08 153.11,9.08 154.66,10.63 165.2,10.63 165.78,11.21 170.95,11.21 171.55,11.8 171.58,11.8 173.58,13.81 173.84,13.81 175.15,15.12 175.15,21.31 175.22,21.38 175.22,24.77 175.36,24.91 175.36,32.61 175.78,33.03 175.78,34.92 175.94,35.09 175.94,36.64 175.46,37.12 175.46,57.59 177.04,59.18 177.04,59.65 176.81,59.88 176.58,59.88 v2(176.38,59.68)
  L6 w0.127: v2(169.92,55.13) 170.34,54.72 170.34,53.79 170.47,53.66 170.79,53.66 170.91,53.79 170.91,55.25 175.69,60.02 176.03,60.02 v2(176.38,59.68)
  BOTTOM w0.102: v2(169.92,55.13) 169.85,55.21 IOBD1.8 ; CPU1.F16 122.55,45.46 122.86,45.76 122.86,45.89 v2(122.88,45.91)
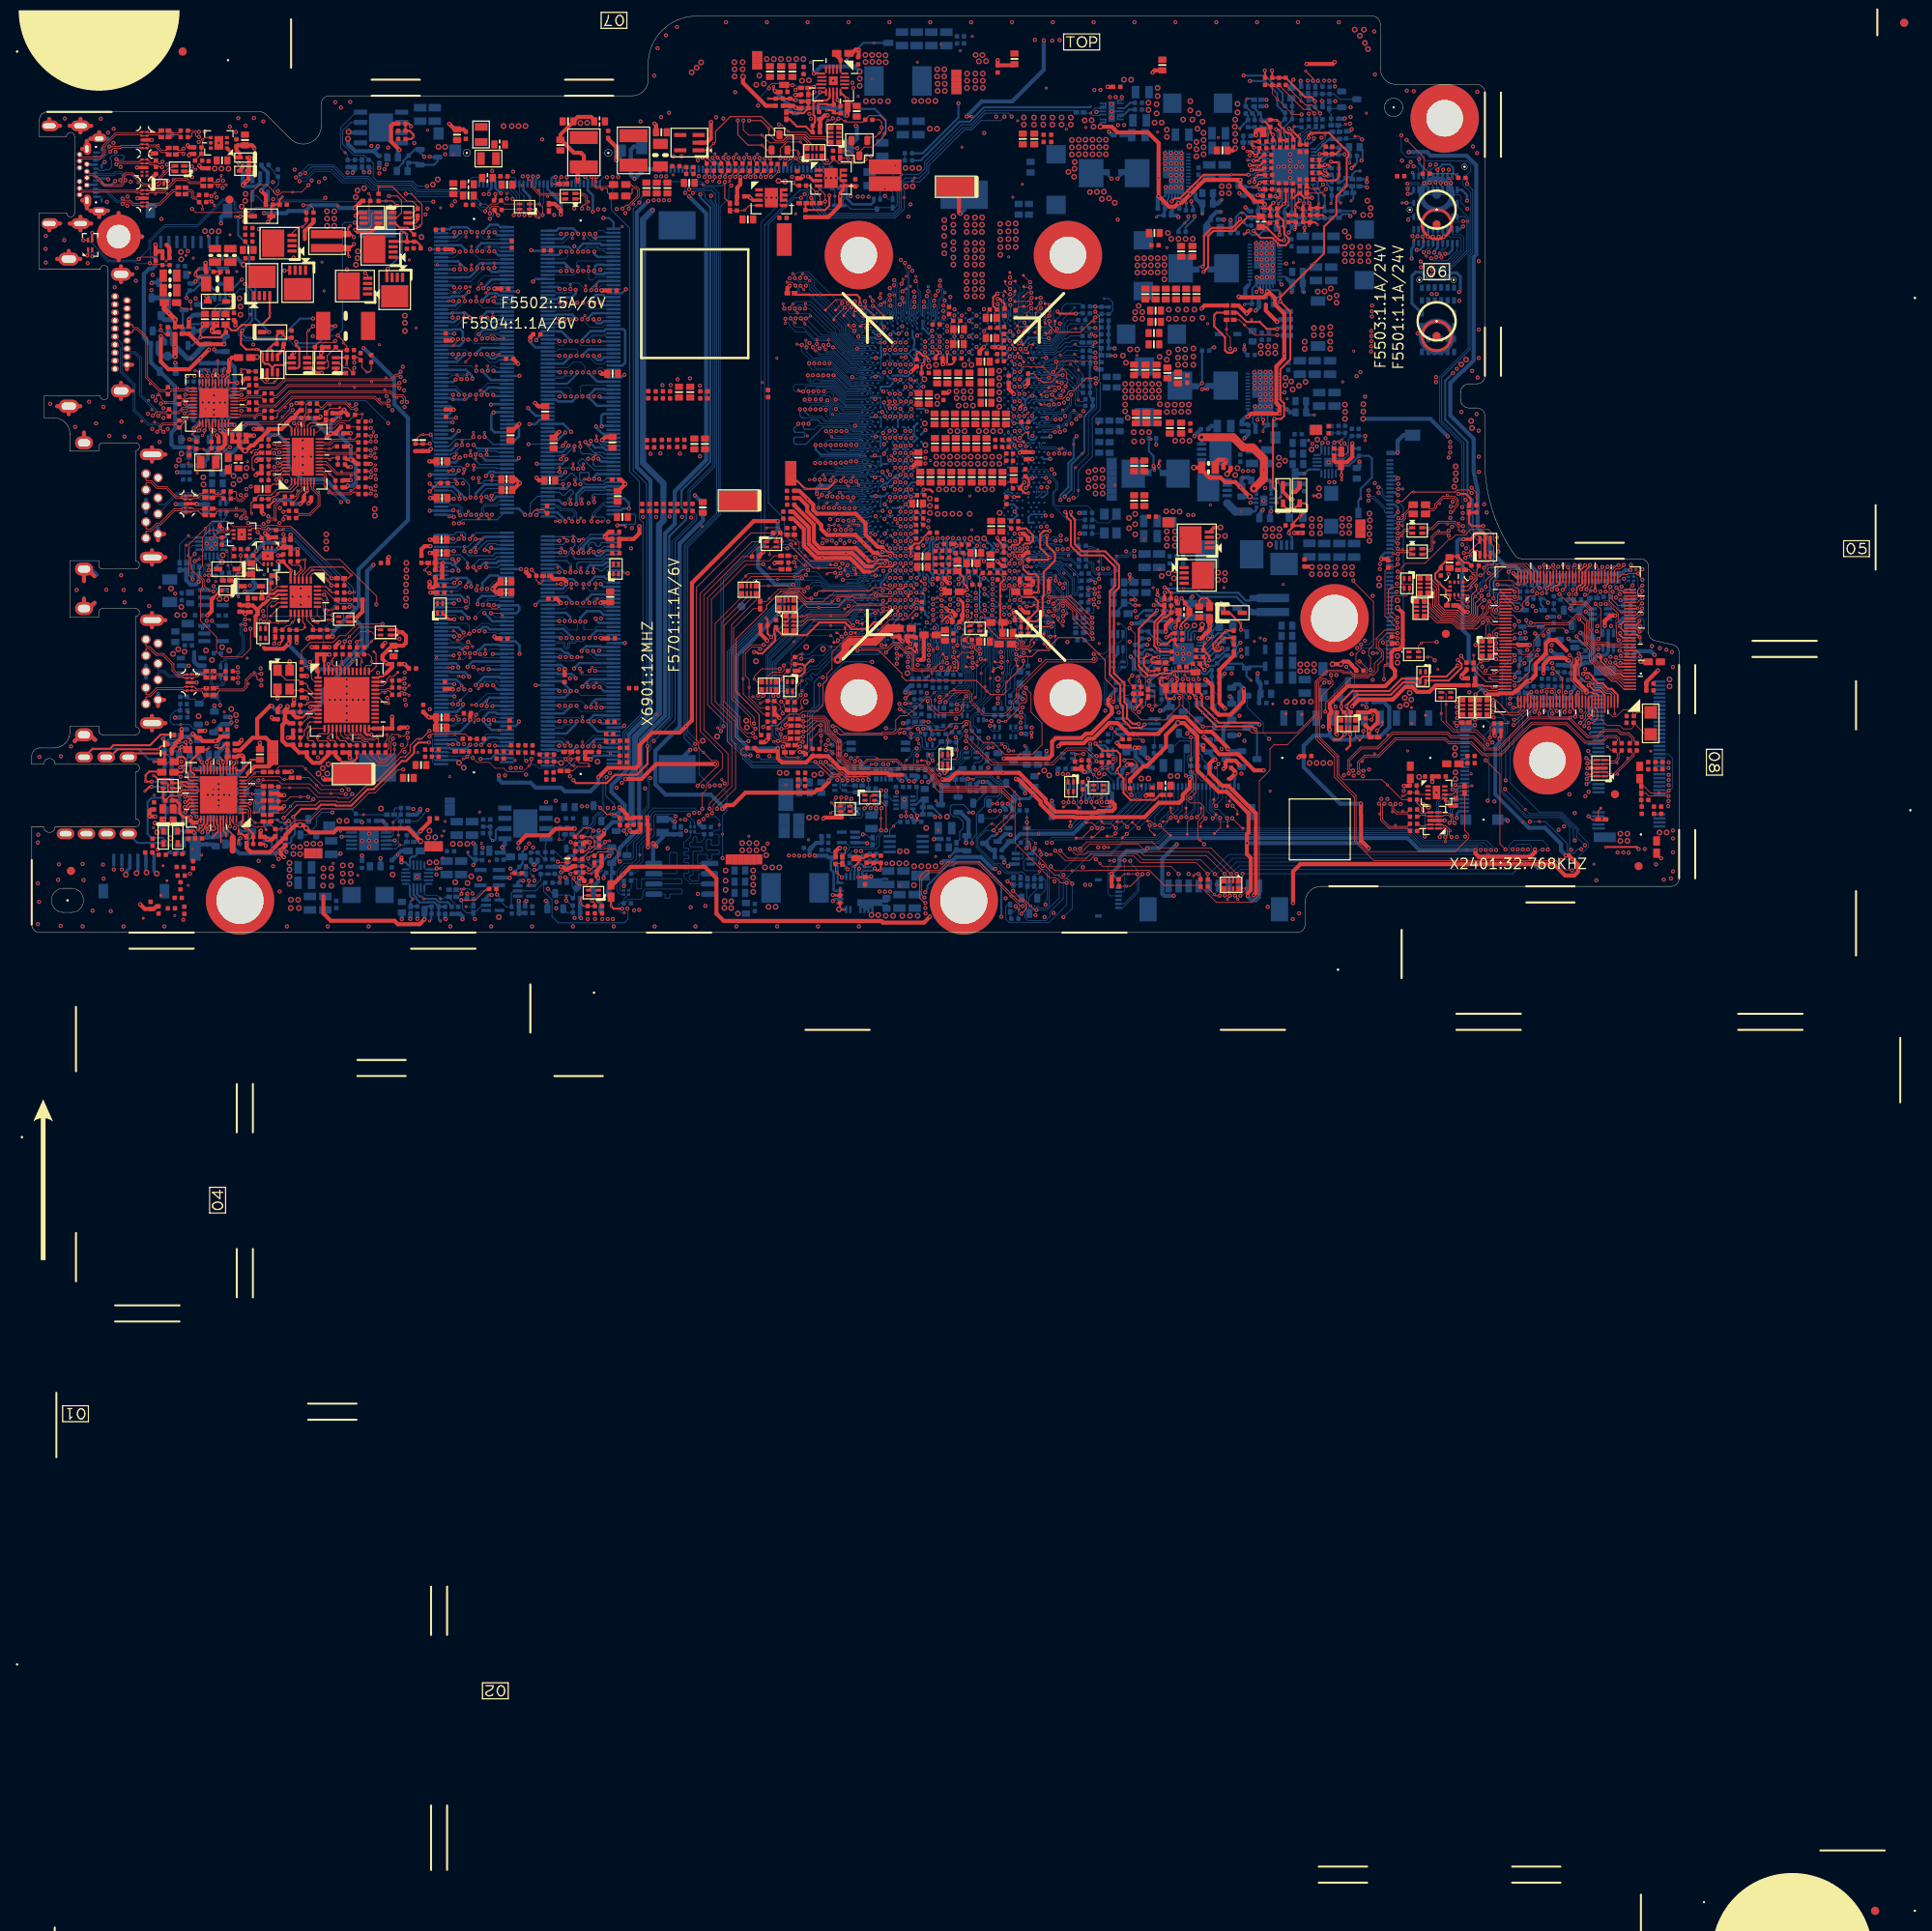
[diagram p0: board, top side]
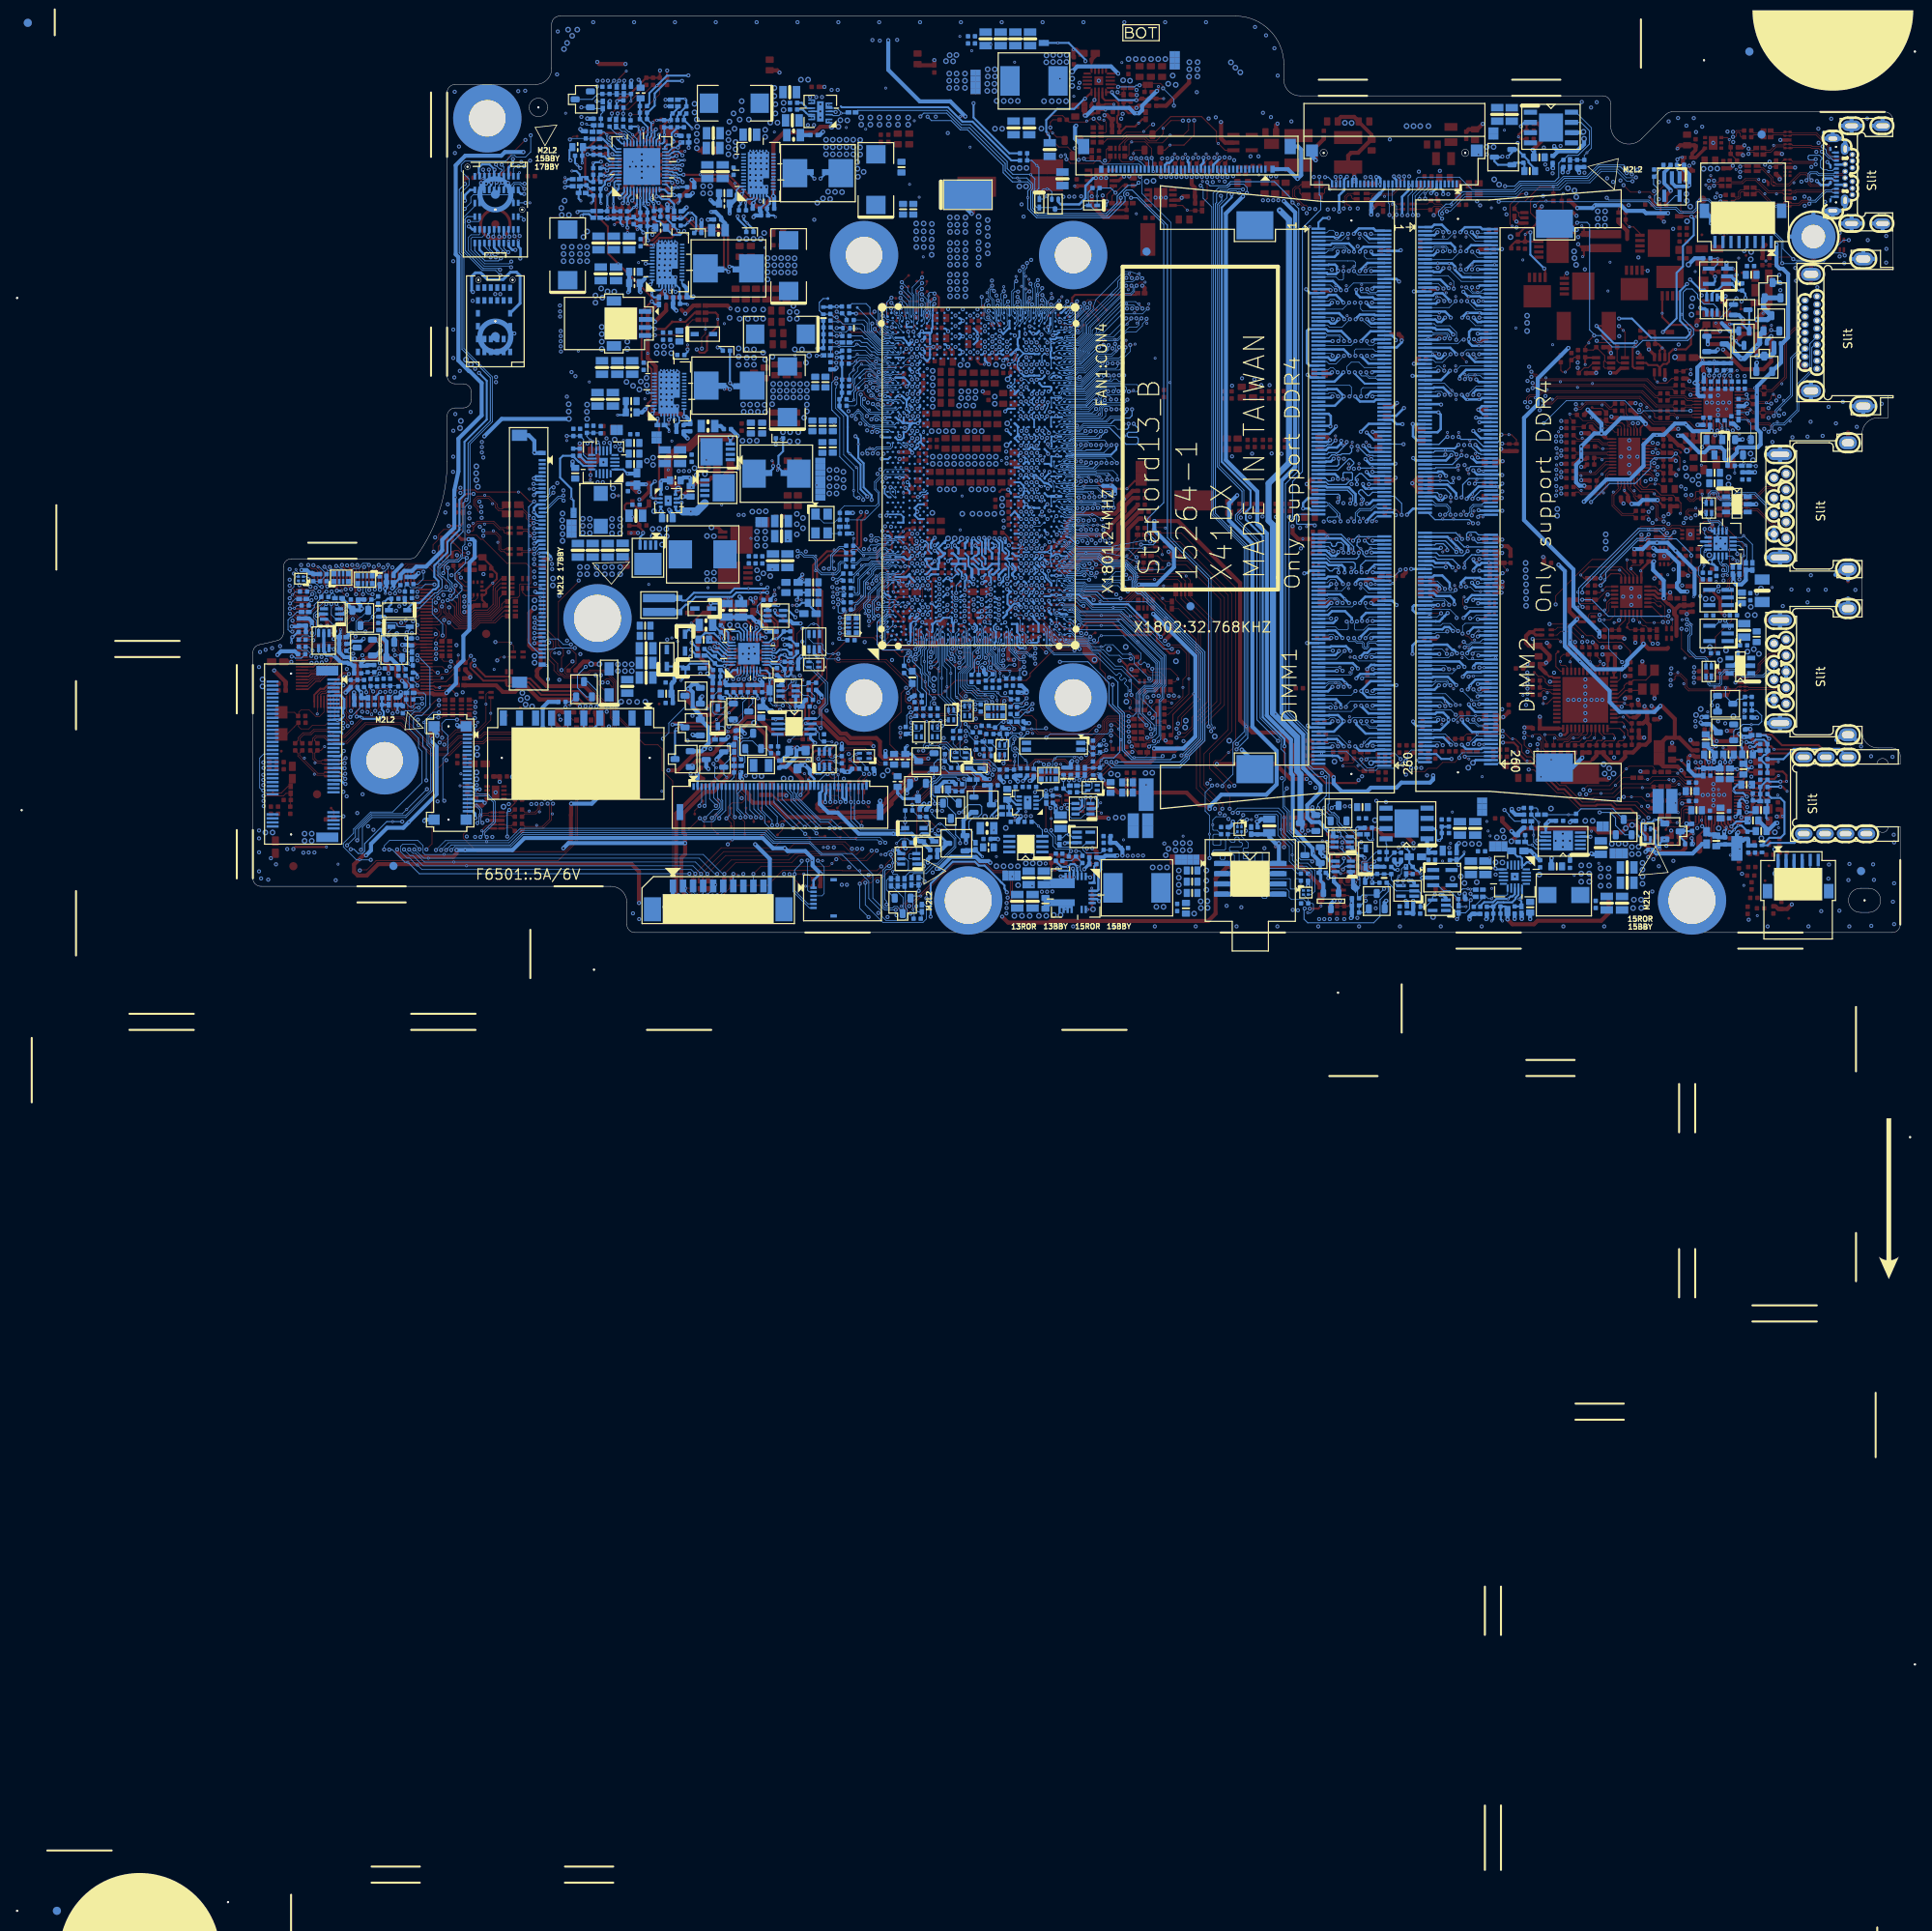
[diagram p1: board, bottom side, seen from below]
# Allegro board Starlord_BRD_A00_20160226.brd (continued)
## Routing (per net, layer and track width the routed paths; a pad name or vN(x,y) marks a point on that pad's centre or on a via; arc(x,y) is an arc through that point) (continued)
PCIE_RX_CPU_P5: length 153.8
  TOP w0.102: v1(124.31,45.41) 123.87,45.41 v2(123.75,45.53)
  L3 w0.089: v2(123.75,45.53) 123.75,45.6 122.9,46.44 121.06,46.44 120.62,46 120.58,46 120.55,45.97 120.48,45.97
  L3 w0.14: v2(176.38,60.34) 176.57,60.15 176.92,60.15 177.31,59.76 177.31,59.07 175.73,57.48 175.73,37.23 176.21,36.75 176.21,34.98 176.05,34.81 176.05,32.92 175.63,32.5 175.63,24.8 175.49,24.66 175.49,21.27 175.42,21.2 175.42,15.01 173.95,13.54 173.69,13.54 171.69,11.54 171.66,11.54 171.06,10.94 165.89,10.94 165.31,10.37 154.77,10.37 153.22,8.82 137.43,8.82 135.9,10.34 135.37,10.34 134.05,11.67 134.05,14.1 134.16,14.21 134.16,16.43 133.81,16.78 131.14,16.78 129.37,18.55 129.37,19.99 128.6,20.77 124.72,20.77 121.47,24.01 121.47,29.21 121.73,29.46 121.73,31.53 123.79,33.58 123.79,36.22 122.62,37.39 121.1,37.39 120.23,38.26 120.23,45.72 120.48,45.97
  L6 w0.127: v2(176.38,60.34) 176.33,60.29 175.58,60.29 170.85,55.56 170.16,55.56 v2(169.95,55.77)
  BOTTOM w0.102: IOBD1.7 169.89,55.71 v2(169.95,55.77) ; CPU1.E16 123.34,45.61 123.67,45.61 v2(123.75,45.53)
PCIE_TX_CPU_N5: length 7.1
  BOTTOM w0.089: 130.03,45.94 129.81,45.94 129.25,46.5 128.37,46.5 128.15,46.72 127.29,46.72 127.17,46.83 126.81,47.2 126.17,47.2 126.07,47.09 125.81,47.09 125.72,47.13 125.45,47.13 125.36,47.09 125.16,47.09 125.03,47.14 124.97,47.14 CPU1.C19
  BOTTOM w0.102: 130.03,45.94 130.38,45.94 130.5,46.07 130.5,46.25 130.38,46.37 C1601.2
PCIE_TX_CPU_P5: length 7.1
  BOTTOM w0.089: C1602.2 129.98,45.71 129.77,45.71 129.56,45.91 129.17,46.31 128.29,46.31 128.07,46.53 127.21,46.53 127.04,46.7 126.73,47.01 126.25,47.01 126.16,46.91 125.78,46.91 125.69,46.95 125.49,46.95 125.4,46.91 125.13,46.91 124.99,46.97 124.35,46.97 CPU1.D19
PCIE_TX_WLAN_N5: length 86.2
  L3 w0.14: v2(137.11,47.44) 137.48,47.06 138.25,47.06 138.77,46.54 138.77,43.49 138.11,42.83 138.11,38.47 137.37,37.72 137.37,34.08 139.66,31.78 139.66,30.84 140.56,29.94 145.16,29.94 145.27,30.05 147.04,30.05 147.37,30.38 149.37,30.38 150.37,29.38 153.71,29.38 155.4,27.69 160.03,27.69 160.65,28.31 160.65,29.38 160.98,29.71 163.96,29.71 165.2,30.95 165.2,32.99 166.05,33.84 166.05,35.87 166.36,36.17 166.36,37.14 167.32,38.1 167.32,42.12 166.62,42.82 166.62,46.6 167.55,47.52 167.55,52.56 167.19,52.92 167.19,54.24 167.03,54.39 167.03,54.91 v2(167.46,55.34)
  BOTTOM w0.102: v2(167.46,55.34) 167.53,55.4 167.69,55.4 167.95,55.14 167.95,54.54 168.28,54.21 IOBD1.10 ; 134.97,46.7 134.72,46.45 134.72,45.33 134.08,44.7 132.43,44.7 132.08,45.04 132.08,45.86 131.82,46.12 131.35,46.12 C1601.1 ; 134.97,46.7 v1(134.87,46.8) ; 134.97,46.7 135.18,46.91 136.25,46.91 136.63,47.29 136.96,47.29 v2(137.11,47.44)
PCIE_TX_WLAN_P5: length 86.2
  L3 w0.14: v2(137.11,46.75) 137.11,46.72 137.43,46.4 137.64,46.4 137.77,46.52 137.77,46.67 137.89,46.8 138.14,46.8 138.5,46.43 138.5,43.6 137.84,42.94 137.84,38.58 137.1,37.83 137.1,33.97 139.39,31.67 139.39,30.73 140.45,29.67 145.27,29.67 145.38,29.78 147.15,29.78 147.48,30.11 149.26,30.11 150.26,29.11 153.6,29.11 155.28,27.42 160.14,27.42 160.92,28.2 160.92,29.27 161.09,29.44 164.07,29.44 165.47,30.84 165.47,32.88 166.32,33.73 166.32,35.75 166.62,36.06 166.62,37.03 167.59,37.99 167.59,42.23 166.89,42.93 166.89,46.49 167.82,47.41 167.82,52.67 167.45,53.03 167.45,53.91 167.82,54.27 167.82,54.53 167.66,54.68 v2(167.49,54.68)
  BOTTOM w0.102: IOBD1.11 168.45,53.71 v2(167.49,54.68) ; v1(134.87,44.97) 134.78,45.07 ; 134.78,45.07 134.18,44.47 132.33,44.47 131.85,44.95 131.85,45.76 131.72,45.89 131.23,45.89 131.1,45.76 C1602.1 ; 134.78,45.07 134.95,45.24 134.95,46.35 135.27,46.68 136.34,46.68 136.73,47.06 136.85,47.06 137.11,46.8 v2(137.11,46.75)
PD4403_A: length 2.2
  BOTTOM w0.102: PD4404.A 146.38,27.93 145.85,28.46 PQ4408.B
PD4403_K: length 3.8
  BOTTOM w0.102: PR4458.2 147.38,24.41 146.91,24.88 145.87,24.88 v1(145.77,24.98) 146.43,25.65 PD4404.K
PD_CC1: length 14.3
  TOP w0.127: R3718.2 v2(37.26,44.03) 36.24,45.05 v1(34.9,45.05) 34.85,45.05 34.2,44.4 U3701.2 ; v2(31.29,49.5) 31.37,49.42 R3709.1
  BOTTOM w0.127: v2(31.29,49.5) 31.8,48.99 32.74,48.99 37.26,44.46 v2(37.26,44.03)
PD_CC1_VCONN_CTRL: length 19
  TOP w0.127: U3703.3 28.86,48.74 R3713.2 28.59,49.25 28.09,49.75 v2(28.09,49.78) ; R3712.2 v2(39.55,42.26) 40.05,42.26 v1(40.1,42.31)
  BOTTOM w0.127: v2(39.55,42.26) 39.55,42.79 32.38,49.95 29.94,49.95 29.18,49.19 28.67,49.19 v2(28.09,49.78)
PD_CC1_VCONN_CTRL_R: length 2.8
  TOP w0.127: R3712.1 37.34,42.26 v1(37.03,42.56) 36.59,43 U3701.24
PD_CC2: length 24.1
  TOP w0.127: U3701.1 34.7,44.4 34.9,44.6 35.99,44.6 v1(36.73,43.86) 37.26,43.32 v2(37.26,43.15) R3719.2 ; v2(25.98,46.85) 25.98,45.81 26.31,45.48 26.31,44.95 26.06,44.7 25.61,44.7 R3710.1
  BOTTOM w0.127: v2(37.26,43.15) 36.63,43.78 36.63,44.74 32.63,48.73 31.67,48.73 31.47,48.94 27.84,48.94 25.98,47.08 v2(25.98,46.85)
PD_CC2_VCONN_CTRL: length 21.3
  TOP w0.127: R3711.2 39.39,40.38 v2(39.5,40.48) ; v1(31.29,50.13) 31.18,50.02 R3714.2 30.26,50.13 v2(29.44,50.13) 29.42,50.12 28.55,50.12 28.41,50.26 27.44,50.26 U3704.3
  BOTTOM w0.127: v2(29.44,50.13) 29.54,50.23 32.56,50.23 39.99,42.8 39.99,40.97 v2(39.5,40.48)
PD_CC2_VCONN_CTRL_R: length 3.6
  TOP w0.127: R3711.1 37.72,40.38 37.44,40.1 v1(36.73,40.1) 36.5,40.32 36.5,40.99 36,41.5 U3701.21
PD_RD1: length 9.4
  TOP w0.127: U3701.3 33.7,44.46 34.67,45.43 38.73,45.43 v1(39.72,44.44) 39.32,44.03 R3718.1 R3719.1
PD_SWD_CLK: length 2.2
  TOP w0.127: TP3702.1 30.85,40.5 U3701.12
PD_SWD_IO: length 1.8
  TOP w0.127: U3701.11 30.56,41 30.12,40.56 TP3701.1
PD_VBUS_C_CTRL1: length 41.8
  TOP w0.127: PQ4307.2 38.2,70.81 38.81,70.2 39.3,70.2 PR4323.1 39.97,70.06 v2(40.1,70.2) ; v1(35.58,38.52) 35.23,38.52 34.97,38.78 v2(34.97,38.83) 34.7,39.1 U3701.18
  L3 w0.127: v2(40.1,70.2) 40.1,69.38 39.47,68.75 39.47,64.48 40.18,63.77 40.18,40.28 38.3,38.4 36.63,38.4 36.19,38.83 v2(34.97,38.83)
PD_VBUS_C_CTRL1_A: length 54.8
  TOP w0.127: PQ4311.3 42.43,89.49 42.26,89.32 42.26,87.88 41.96,87.57 40.84,87.57 v2(40.18,88.23) ; 36.75,71.09 36.88,70.96 36.88,70.32 36.71,70.16 PQ4307.6 ; 36.75,71.09 36.47,70.81 PQ4307.5 ; 36.75,71.09 36.75,71.71 PC4311.1 38.16,72.41 PR4319.2 39.18,72.85 v1(38.73,73.3) 38.73,73.55 v2(38.07,74.21)
  BOTTOM w0.127: v2(40.18,88.23) 40.13,88.28 38.94,88.28 38.63,87.98 38.63,74.92 38.07,74.36 v2(38.07,74.21) 37.23,74.21 35.81,72.79 32.82,72.79 32,73.6 26.41,73.6 25.7,74.31 25.7,75 27,76.29 27,79.59 26.59,80 25.88,80 25.2,79.32 25.2,78.91 24.41,78.12 23.21,78.12 22.77,77.67 PQ4306.6
PD_VBUS_DISCHG: length 42.4
  TOP w0.127: U3701.22 v2(36.37,42) 36.73,41.64 v1(36.73,41.32) ; PQ4310.2 34.95,70.81 35.22,71.07 PR4332.1 35.22,72.93 35.63,73.35 37.54,73.35 v2(37.74,73.55)
  L3 w0.127: v2(37.74,73.55) 38.2,73.55 38.89,72.86 38.89,68.93 38.4,68.44 38.4,54.09 37.87,53.55 37.87,52.82 39.17,51.53 39.17,43.83 37.33,42 v2(36.37,42)
PD_VBUS_P_CTRL1: length 64.8
  TOP w0.127: v2(45.44,90.34) 44.84,90.94 v1(44.04,90.94) PR4310.1 ; U3701.15 v2(33.2,38.83)
  L3 w0.127: v2(33.2,38.83) 34.29,38.83 34.97,38.14 38.43,38.14 40.44,40.15 40.44,63.9 39.89,64.44 39.89,68.51 40.74,69.36 40.74,71.62 40.36,72 40.36,77.74 44.73,82.11 44.73,88.84 45.44,89.55 v2(45.44,90.34)
PD_VBUS_P_CTRL1_R: length 9.7
  TOP w0.127: 47.45,89.44 47.39,89.49 PQ4309.6 ; 47.45,89.44 PR4324.1 47.98,90.26 47.34,90.9 46.66,90.9 44.83,92.73 v1(43.15,92.73) 43.13,92.7 PR4310.2 ; 47.45,89.44 47.45,89.07 47.22,88.84 PQ4309.5
PD_VBUS_R: length 5.1
  TOP w0.127: U3701.17 34.2,38.84 34.97,38.07 C3705.2 R3704.2 R3703.2 37.6,37.62 v1(37.67,37.56)
PD_VCCD: length 2.8
  TOP w0.127: U3701.7 30.46,43 30.02,42.56 v1(29.77,42.56) 29.72,42.61 29.72,43.39 C3704.1
PD_XRES: length 3.9
  TOP w0.127: U3701.16 33.7,38.58 33.96,38.32 TP3703.1 33.64,37.62 C3706.1 R3708.2
PECI_EC: length 6.4
  TOP w0.114: v1(179.31,34.48) R2437.1 C2405.1 180.83,31.18 182.32,31.18 182.46,31.04 KBC24.94
PEG_CLK1_CPU: length 99.2
  L3 w0.14: v2(128.42,59.53) 128.18,59.29 128.18,59.01 129.31,57.88 129.31,56.43 126.95,54.07 126.95,52.77 128,51.71 130.4,51.71 132.1,50 132.1,48.61 132.31,48.4 138.02,48.4 139.56,46.86 139.56,43.06 138.9,42.4 138.9,38.14 138.16,37.4 138.16,34.4 140.45,32.11 140.45,31.17 140.89,30.73 144.83,30.73 144.94,30.83 146.71,30.83 147.12,31.23 154.89,31.23 155.62,30.5 163.63,30.5 164.41,31.28 164.41,33.06 163.4,34.08 163.4,35.6 165.8,38 165.8,42.24 165.83,42.28 165.83,47.03 165.42,47.44 165.42,52.36 166.4,53.33 166.4,53.5 v2(166.22,53.69)
  BOTTOM w0.102: v2(166.22,53.69) 166.52,53.99 166.81,53.99 168.21,52.58 168.21,52.32 168.33,52.21 IOBD1.14 ; v1(128.14,60.19) 128.14,60.06 ; 128.14,60.06 128.52,60.06 128.65,59.94 128.65,59.76 v2(128.42,59.53) ; 128.14,60.06 127.6,60.06 127.32,60.34 125.68,60.34 125.55,60.47 125.55,60.74 125.68,60.87 CPU1.A42
PEG_CLK1_CPU#: length 99.7
  TOP w0.102: v2(127.79,59.55) v1(127.79,60.11)
  L3 w0.14: v2(127.79,59.55) 127.91,59.43 127.91,58.9 129.04,57.77 129.04,56.54 126.68,54.18 126.68,52.66 127.89,51.45 130.28,51.45 131.84,49.89 131.84,48.5 132.2,48.14 137.91,48.14 139.29,46.75 139.29,43.17 138.63,42.51 138.63,38.25 137.89,37.51 137.89,34.29 140.18,32 140.18,31.06 140.78,30.46 144.94,30.46 145.05,30.57 146.83,30.57 147.23,30.97 154.78,30.97 155.51,30.24 163.74,30.24 164.68,31.17 164.68,33.17 163.66,34.19 163.66,35.49 166.06,37.89 166.06,42.13 166.1,42.17 166.1,47.14 165.69,47.56 165.69,52.25 166.67,53.22 166.67,53.9 v2(166.24,54.32)
  BOTTOM w0.102: v2(127.79,59.55) 127.23,60.11 125.58,60.11 125.32,60.37 125.32,60.81 CPU1.B42 ; IOBD1.13 168.41,52.71 166.9,54.22 166.34,54.22 v2(166.24,54.32)
PEG_TX_CPU_N0: length 8.1
  BOTTOM w0.089: CPU1.B17 125.5,46 125.85,45.65 127.6,45.65 127.66,45.59
  BOTTOM w0.102: v1(128.34,44.67) 128.46,44.79 ; 128.46,44.79 129.37,43.88 129.37,42.17 129.44,42.1 129.61,41.93 C1606.2 ; 128.46,44.79 128.09,45.16 128.02,45.23 127.66,45.59
PEG_TX_CPU_N1: length 9.6
  BOTTOM w0.089: 127.65,45.22 127.43,45.43 125.82,45.43 125.52,45.73 124.82,45.73 124.61,45.61 124.32,45.44 CPU1.D16
  BOTTOM w0.102: 127.65,45.22 127.91,44.95 127.91,44.6 128.89,43.62 128.89,41.88 129.08,41.69 ; 129.08,41.69 129.73,41.04 C1608.2 ; 129.08,41.69 v1(129.18,41.8)
PEG_TX_CPU_N2: length 7.8
  BOTTOM w0.089: 128.83,45.81 128.31,45.81 128.24,45.88 128.16,45.96 127.91,46.21 126.39,46.21 126.16,46.44 125.78,46.44 125.69,46.4 125.49,46.4 125.4,46.44 125.13,46.44 124.99,46.39 124.35,46.39 CPU1.D17
  BOTTOM w0.102: 129.08,45.56 130.18,44.46 130.38,44.46 C1610.2 ; 129.08,45.56 128.83,45.81 ; 129.08,45.56 v1(129.18,45.66)
PEG_TX_CPU_N3: length 6.7
  BOTTOM w0.102: v1(130.15,48.99) 130.19,48.95 C1612.2 129.87,48.08 129.02,47.22 127.42,47.22 126.82,47.82 126.06,47.82 125.88,47.64 125.55,47.64 CPU1.B19
PEG_TX_CPU_P0: length 7.9
  BOTTOM w0.089: 127.8,45.77 127.73,45.84 126.07,45.84 CPU1.A17
  BOTTOM w0.102: C1605.2 130.34,42.97 130.12,42.97 130.05,42.89 130.05,42.26 129.95,42.16 129.71,42.16 129.6,42.26 129.6,43.97 128.34,45.23 127.8,45.77
PEG_TX_CPU_P1: length 9.6
  BOTTOM w0.089: 127.49,45.05 127.39,45.15 127.3,45.24 125.74,45.24 125.49,45.5 125.44,45.54 125.04,45.54 CPU1.C16
  BOTTOM w0.102: C1607.2 130.41,40.07 130.1,40.07 129.97,40.2 129.97,40.69 129.84,40.81 129.64,40.81 128.66,41.79 128.66,43.37 ; 128.66,43.37 v1(128.5,43.37) ; 128.66,43.37 128.66,43.53 127.68,44.5 127.68,44.86 127.49,45.05
PEG_TX_CPU_P2: length 7.8
  BOTTOM w0.089: 128.63,45.62 128.23,45.62 127.83,46.02 126.31,46.02 126.07,46.26 125.81,46.26 125.72,46.23 125.45,46.23 125.36,46.26 125.16,46.26 125.03,46.21 124.82,46.21 CPU1.C17
  BOTTOM w0.102: 128.63,45.62 128.69,45.62 129.71,44.61 ; v1(129.61,44.52) 129.71,44.61 ; 129.71,44.61 130.09,44.22 130.09,43.56 130.16,43.48 130.29,43.48 C1609.2
PEG_TX_CPU_P3: length 5.9
  BOTTOM w0.102: 128.9,46.99 129.11,46.99 129.74,47.62 130.35,47.62 130.48,47.49 130.48,47.31 130.35,47.19 C1611.2 ; 128.9,46.99 v1(128.9,46.85) ; 128.9,46.99 127.33,46.99 126.73,47.59 126.15,47.59 CPU1.A19
PG_1: length 237.3
  TOP w0.254: v1(39.5,84.01) 39.34,84.17 PG4402.2 39.55,85.06 v2(40.05,85.56)
  L3 w0.254: v2(40.05,85.56) 39.27,86.35 39.27,92.86 40.44,94.03 40.44,95.27 41.68,96.51 43.39,96.51 43.62,96.74 47.06,96.74 49.13,98.81 55.92,98.81 57.02,97.71 64.1,97.71 64.96,98.56 77.33,98.56 78.46,99.69 79.01,99.69 85.96,106.64 85.96,108.79 87.63,110.46 120.58,110.46 121.64,109.39 133.47,109.39 134.26,110.18 134.29,110.18 134.47,110.35 159.06,110.35 161.83,107.59 162.89,107.59 163.63,106.85 163.63,104.49 165.02,103.09 165.02,99.23 163.04,97.25 163.03,97.25 162.74,96.95 162.74,96.94 162.48,96.69 162.48,89.93 161.16,88.61 161.16,84.73 165.73,80.15 165.73,71.46 166.72,70.46 166.72,56.7 164.84,54.82 164.84,46.83 165.25,46.43 165.25,43.41 164.68,42.84 160.62,42.84 156.62,38.84 156.62,35.75 155.12,34.26 153.34,34.26 152.7,34.89 150.67,34.89 150.42,35.14 v2(150.37,35.14)
  BOTTOM w0.254: v2(150.37,35.14) 149.66,34.43 PR4444.2
PG_2: length 234.6
  TOP w0.254: v1(39.6,87.85) 39.34,87.6 PG4403.2 39.67,86.83 v2(40.05,86.45)
  L3 w0.254: v2(40.05,86.45) 39.65,86.86 39.65,92.7 40.82,93.87 40.82,95.11 41.83,96.13 43.55,96.13 43.78,96.36 47.22,96.36 49.29,98.43 55.76,98.43 56.86,97.32 64.26,97.32 65.12,98.18 77.49,98.18 78.62,99.31 79.17,99.31 86.35,106.48 86.35,108.63 87.79,110.07 120.42,110.07 121.49,109.01 133.63,109.01 134.42,109.8 134.45,109.8 134.62,109.97 158.9,109.97 161.67,107.2 162.74,107.2 163.24,106.7 163.24,104.33 164.64,102.93 164.64,99.39 162.88,97.63 162.88,97.63 162.36,97.11 162.36,97.1 162.1,96.85 162.1,90.09 160.78,88.76 160.78,84.57 165.35,80 165.35,71.3 166.34,70.31 166.34,56.86 164.46,54.98 164.46,46.68 164.87,46.27 164.87,43.57 164.52,43.22 160.46,43.22 156.24,39 156.24,35.91 154.96,34.64 153.5,34.64 152.86,35.27 151.05,35.27 v2(150.29,36.03)
  BOTTOM w0.254: v2(150.29,36.03) 149.59,35.34 PR4414.1
PIRQA#: length 35.4
  TOP w0.102: R1607.2 88.47,22.93 88.21,22.67 88.21,22.22 88.42,22.01 v1(88.72,22.01) v2(89.38,22.01)
  BOTTOM w0.102: v2(89.38,22.01) 87.22,24.17 87.22,34.56 93.77,41.11 99.13,41.11 100.05,42.03 101.5,42.03 101.93,42.46 103.22,42.46 CPU1.BB11
PLT_RST#: length 191.6
  TOP w0.102: v2(126.72,8.22) 127.25,7.69 v1(129.39,7.69) 131.54,7.69 131.6,7.74 138.96,7.74 140.84,5.86 145.2,5.86 R6802.1 147.31,3.75 151.66,3.75 152.65,4.74 152.65,18.84 153.97,20.16 153.97,22.83 154.48,23.33 156.13,23.33 159.82,27.02 159.82,31.11 161.13,32.43 162.86,32.43 163.09,32.2 163.93,32.2 164.25,31.88 166.05,31.88 166.34,32.17 166.62,32.17 166.95,32.5 166.95,33.42 167.83,34.29 167.83,34.83 167.21,35.45 167.21,36.57 168.22,37.58 169.54,37.58 v2(169.85,37.89) 169.72,37.89 168.27,39.34 168.27,44.96 EC6602.1 168.78,45.47 169.56,45.47 v2(169.87,45.79) ; KBC24.56 188.01,45.63 v2(188.06,45.69)
  L3 w0.102: v2(126.72,8.22) 126.24,7.74 125.04,7.74 122.15,10.63 122.15,12.74 121.54,13.35 121.54,13.53 120.72,14.34 119.01,14.34 118.28,15.08 118.28,17.24 116.85,18.67 116.85,19.3 116.66,19.49 116.66,24.61 v2(116.2,25.06)
  L4 w0.102: v2(188.06,45.69) 188.06,45.3 187.7,44.95 184.63,44.95 184.17,45.41 183.41,45.41 180.57,48.25 177.93,48.25 v2(177.9,48.23) ; v2(169.87,45.79) 169.44,46.22 169.44,56.84 171.09,58.49 171.09,70.09 171.91,70.91 171.91,77.03 173.45,78.58 175.21,78.58 175.94,79.31 175.94,81.68 176.66,82.4 176.66,84.74 175.42,85.97 171.68,85.97 171.17,86.48 v2(171.17,88.61)
  L6 w0.102: v2(169.87,45.79) 170.74,45.79 171.7,46.75 173.24,46.75 174.74,48.25 177.87,48.25 v2(177.9,48.23)
  BOTTOM w0.102: v2(116.2,25.06) 116.05,25.06 115.77,24.78 115.77,24.49 R1715.1 114.79,23.74 R1713.1 114.01,23.58 113.23,22.8 C1701.1 113.12,22.04 EC1703.1 ; GPU1.D1 171.39,88.99 171.17,88.76 v2(171.17,88.61) ; C2402.1 189.08,44.49 188.67,44.9 188.47,44.9 188.06,45.3 v2(188.06,45.69) ; IOBD1.43 169.67,37.71 v2(169.85,37.89)
PLT_RST#_DEBUG: length 3
  TOP w0.127: v1(144.47,7.05) 144.7,7.28 v2(145.11,7.28) 145.34,7.05 R6802.2
  BOTTOM w0.127: v2(145.11,7.28) 145.11,7.28 145.11,5.79 DB1.7
PM_PCH_PWROK: length 53.9
  TOP w0.127: v2(101.46,18.91) 100.7,19.68 99.82,19.68 v1(99.77,19.73) 99.57,19.73 v2(98.09,21.2)
  BOTTOM w0.127: R1706.2 101.13,18.25 RN1703.3 101.46,18.73 v2(101.46,18.91) ; v2(98.09,21.2) 97.65,20.76 89.65,20.76 88.68,21.72 88.68,22.01 86.73,23.97 86.73,34.77 94.37,42.41 94.79,42.41 95.31,42.94 95.31,43.59 95.16,43.74 95.16,44.6 96.35,45.79 98.8,45.79 99.74,46.73 103.1,46.73 103.73,47.36 CPU1.BA20
PM_RSMRST#: length 97.6
  TOP w0.127: v2(97.46,21.2) 98.27,20.39 98.32,20.39 99.39,19.32 99.9,19.32 100,19.42 100.35,19.42 100.82,18.95 v2(100.82,18.91) ; R1720.2 69.54,11.9 v1(69.59,11.85) 70,11.45 70,10.89 69.7,10.58 v2(69.44,10.58) 69.34,10.58 68.88,10.13 R1702.1
  L3 w0.127: v2(72.72,18) 74.17,18 74.78,18.61 76.3,18.61 76.55,18.36 77.47,18.36 78.51,19.4 81.33,19.4 82.01,20.08 86.79,20.08 87.81,19.07 91.01,19.07 91.21,18.86 94.87,18.86 97.2,21.2 v2(97.46,21.2)
  L4 w0.127: v2(69.44,10.58) 69.98,10.58 71.78,12.39 71.78,13.3 73.91,15.43 73.91,16.73 72.72,17.92 v2(72.72,18)
  BOTTOM w0.127: v2(100.82,18.91) 100.82,18.9 100.51,18.58 100.51,17.97 100.81,17.67 RN1703.4 101.29,17.44 R1704.1 ; Q1701.3 68.32,9.19 69.37,10.23 69.37,10.51 v2(69.44,10.58) ; v2(97.46,21.2) 89.56,21.2 88.94,21.83 88.94,22.12 86.98,24.07 86.98,34.66 94.42,42.1 94.84,42.1 95.53,42.79 95.53,43.7 95.38,43.86 95.38,44.51 96.4,45.53 98.88,45.53 99.82,46.47 104.21,46.47 104.55,46.14 CPU1.AY17
PM_RSMRST#_M: length 4.1
  TOP w0.127: v1(71.85,11.4) 71.42,11.4 v2(71.3,11.27) 71.3,11.19 70.93,10.82 R1737.2
  BOTTOM w0.127: Q1702.5 v2(71.3,11.27) 71.3,10.76 71.15,10.62 Q1702.6
PM_RSMRST#_R: length 5.1
  TOP w0.127: R1720.1 67.59,11.9 68.68,13 v1(69.04,13) 69.52,13 v2(69.87,12.64)
  BOTTOM w0.127: Q1702.2 68.81,11.27 69.16,11.62 69.16,11.73 69.57,12.13 69.57,12.41 69.77,12.62 69.85,12.62 v2(69.87,12.64)
PME#: length 1.3
  TOP w0.102: TP1707.1 106.12,43.17 v2(106.73,43.17)
  BOTTOM w0.102: CPU1.AU11 106.4,42.85 v2(106.73,43.17)
POWER_SW_IN#: length 9.2
  TOP w0.102: v2(193.42,31.74) 193.57,31.74 194.31,31 194.31,31 194.62,30.69 195.17,30.69 195.87,29.99 196.34,29.99 196.81,29.52 KBC24.127 196.81,27.21 v1(196.85,27.17)
  BOTTOM w0.102: R2432.2 C2426.1 R2451.1 193.1,31.4 193.39,31.69 193.39,31.72 v2(193.42,31.74)
PQ3802_1: length 6.9
  TOP w0.508: v2(23.94,73.13) 20.83,73.13 v1(20.38,73.57) PR4302.1 PR4309.2
  BOTTOM w0.508: PQ4302.B 23.94,74 v2(23.94,73.13)
PQ3809_D: length 12.4
  TOP w0.254: PR4314.2 21.69,80.84 21.05,81.47 20.65,81.47 v2(20.37,81.75) 20.37,82.11 v1(20.78,82.52)
  L3 w0.254: v2(20.37,81.75) 21.13,80.99 25.96,80.99 v2(26.13,81.17)
  BOTTOM w0.254: PQ4306.3 24.07,79.69 24.31,79.93 24.89,79.93 v2(26.13,81.17)
PQ4405_2: length 4.6
  TOP w0.102: v1(137.72,31.89) v2(137.72,31.27) 137.93,31.06 PR4463.1 137.92,30.51 137.92,29.7 PR4462.1
  BOTTOM w0.102: v2(137.72,31.27) 137.92,31.07 137.94,31.07 138.3,30.71 138.3,30.34 138.61,30.04 PQ4405.2
PQ4405_3: length 5
  TOP w0.089: v2(137.67,27.4) 138.5,28.24 138.5,29.01 PR4455.1
  BOTTOM w0.089: v2(137.67,27.4) 138.07,27.8 v1(138.07,28.03) 138.07,28.21 139.24,29.38 PQ4405.3
PQ4405_5: length 4.2
  BOTTOM w0.102: PQ4405.5 136.93,30.04 136.37,29.48 135.77,29.48 PR4413.2 135,29.14 135,29.42 PC4438.1
PQ4405_6: length 3.9
  BOTTOM w0.102: v1(137.46,31.82) 137.29,31.64 137.29,31.08 137.36,31 PQ4405.6 136.09,30.69 PC4438.2 PR4450.1
PQ4408_C: length 12.2
  TOP w0.102: PR4462.2 PR4451.1 136.75,28.55 136.75,27.65 137.97,26.43 v1(139.83,26.43) 140.94,26.43 142.7,28.19 142.7,29.15 v2(142.72,29.18)
  BOTTOM w0.102: PQ4408.C 143.19,28.02 142.7,28.52 142.7,29.15 v2(142.72,29.18)
PQ4408_E: length 6.1
  BOTTOM w0.102: PQ4408.E 145.57,26.49 146.2,27.12 147.39,27.12 147.69,27.41 PR4436.1 146.85,30.14 PR4431.2
PR_2: length 0.8
  BOTTOM w0.254: PR4416.2 138.67,33.6 PC4432.1
PRE: length 3.4
  TOP w0.102: U5701.16 22.45,69.19 v2(22.5,69.23) 22.5,69.71 v1(22.72,69.94)
  BOTTOM w0.102: R5416.2 22.5,68.64 v2(22.5,69.23) 22.5,69.33 R5415.2
PROC_SELECT#: length 9.8
  BOTTOM w0.089: CPU1.C64 125.03,72.79 126.75,72.79 128.7,74.74
  BOTTOM w0.102: 128.7,74.74 128.78,74.82 128.78,75.33 129.11,75.66 131.52,75.66 131.79,75.93 v1(132.1,75.93) 132.9,75.93 R603.1
PS_ID: length 290.3
  TOP w0.203: KBC24.36 196.01,43.4 195.63,43.02 v2(195.6,43.02)
  TOP w0.635: PR4305.2 v1(17.82,72.84) 17.82,72.24 17.83,72.23 v2(17.83,71.59)
  L4 w0.635: v2(17.83,71.59) 17.83,74.64 18.55,75.37 18.55,81.77 20.17,83.38 20.17,85.49 19.51,86.15 19.51,87.7 20.43,88.62 22.12,88.62 25.12,91.63 25.12,92.78 26.31,93.97 29.31,93.97 v2(30,93.29) ; v2(127.81,110.94) 128.15,111.28 161.75,111.28 165.02,108.01 165.02,105.43 166.74,103.71 166.74,101.67 168.54,99.86 170.64,99.86 173.21,97.29 173.21,94.39 173.58,94.02 176.66,94.02 177.21,93.46 177.21,86.61 178.17,85.65 178.17,82.38 178.38,82.16 178.38,77.11 177.57,76.29 177.57,74.97 172.26,69.66 172.26,54.35 171.23,53.32 171.23,44.99 170.41,44.16 v2(169.85,44.16)
  L6 w0.508: v2(169.85,44.16) 171.61,44.16 172.65,45.2 179.54,45.2 180.35,46.02 180.88,46.02 181.86,45.03 181.86,45.01 183.45,43.43 195.2,43.43 v2(195.6,43.02)
  L6 w0.635: v2(127.81,110.94) 126.46,112.29 83.64,112.29 78.33,106.98 78.33,105.22 76,102.89 46.79,102.89 44.32,100.42 39.04,100.42 38.42,99.8 38.42,98.53 35.67,95.79 34.4,95.79 34.39,95.77 31.62,95.77 30.73,94.88 30.73,94.76 30,94.02 v2(30,93.29)
  BOTTOM w0.635: v2(17.83,71.59) 17.77,71.66 PD4302.3 16.11,71.66 15.71,72.06 PR4304.2
PS_ID_R: length 10.8
  TOP w0.102: PR4317.1 18.82,77.49 AFTP4304.1 19.84,78.35 v2(19.73,78.45)
  L6 w0.102: v2(19.4,84.7) 19.48,84.62 19.48,79.29 19.73,79.04 v2(19.73,78.45)
  BOTTOM w0.102: DCIN1.4 19.05,85.21 19.4,84.85 v2(19.4,84.7)
PS_ID_R1: length 3.6
  TOP w0.102: v1(16.03,75.48) 16.03,74.92 v2(16.05,74.9) 16.58,74.36 PR4305.1 PR4306.2
  BOTTOM w0.102: PQ4301.S 15.94,74.78 v2(16.05,74.9)
PS_ID_R2: length 11.2
  TOP w0.508: PR4309.1 17.88,75.32 PR4306.1 17.82,76.15
  TOP w0.635: PR4317.2 16.48,77.56 v1(17.07,76.98) v2(17.85,76.19) 17.82,76.15
  BOTTOM w0.635: PD4303.2 PD4303.1 17.01,78.74 17.01,77.67 PQ4301.D 16.52,76.19 v2(17.85,76.19)
PSID_DISABLE#_R_C: length 7.7
  BOTTOM w0.635: PQ4302.C 21.59,73.17 20.67,72.25 20.67,72.2 v1(19.84,71.37) 19.37,71.37 PR4303.2 17.49,74.31 PQ4301.G
PSYS: length 4.8
  TOP w0.102: PR4615.1 158.53,93.6 PR4671.2 158.66,92.81 159,92.47 v1(159.69,92.47) 160.07,92.47 v2(160.58,92.98)
  BOTTOM w0.102: PU4601.46 159.82,93.82 160.58,93.06 v2(160.58,92.98)
PTP_DIS#: length 69.9
  TOP w0.127: AFTP6537.1 v2(129.16,13.22) ; v2(181.86,32.3) 182.17,32.3 182.51,32.64 KBC24.90
  L4 w0.127: v2(181.86,32.3) 181.42,31.86 179.74,31.86 178.08,30.19 176.85,30.19 175.72,29.06 175.72,26.81 168.72,19.82 166.94,19.82 165.85,18.72 162.87,18.72 162.3,18.15 157.66,18.15 156.72,17.21 154.48,17.21 151.26,13.99 150.14,13.99 149.43,13.28 141.15,13.28 140.75,12.88 138.8,12.88 138.11,13.57 135.16,13.57 135.02,13.43 129.36,13.43 v2(129.16,13.22)
  BOTTOM w0.127: v2(129.16,13.22) 130.05,14.12 130.05,16.02 130.03,16.04 130.03,16.41 130.05,16.42 KBBD1.41
PURE_HW_SHUTDOWN#: length 41.7
  TOP w0.102: v2(144.07,16.7) 144.75,17.39 144.75,19.52 v1(144.32,19.96) 144.14,20.13 v2(144.14,24.27)
  L4 w0.102: v2(120.42,15.13) 120.55,15 121.87,15 122.3,14.57 124.74,14.57 125.19,14.11 134.87,14.11 135.2,14.44 139.62,14.44 141.76,16.58 143.94,16.58 v2(144.07,16.7)
  BOTTOM w0.102: Q2602.D 143.27,24.15 143.99,24.15 144.12,24.27 v2(144.14,24.27) 144.23,24.18 C2610.1 144.5,23.85 144.5,21.9 R2615.1 ; D4001.3 119.85,14.18 120.42,14.75 v2(120.42,15.13)
PWR_0D6V_S3EN: length 6.3
  BOTTOM w0.127: PR5125.2 45.07,15.32 45.24,15.49 PR5126.2 45.91,14.67 PC5120.1 45.88,14.63 v1(44.96,13.71) 44.96,12.16 44.72,11.92 PU5102.7
PWR_0D6V_S5EN: length 4.4
  BOTTOM w0.127: PR5114.2 PC5119.1 45.59,12.73 v1(45.59,12.11) 45.59,11.24 45.27,10.92 PU5102.9
PWR_0D6V_VCNTL: length 3.8
  BOTTOM w0.127: PC5111.1 PR5118.1 46.26,10.89 v1(45.77,10.89) 45.77,10.88 45.31,10.42 PU5102.10
PWR_1D0V_BT: length 2.7
  TOP w0.254: v1(100.53,5.5) 100.53,4.63 PC5204.1 99.93,4.6 99.87,4.66 v2(99.62,4.66)
  BOTTOM w0.254: v2(99.62,4.66) 99.62,4.67 PU5201.20
PWR_1D0V_EN: length 4.9
  BOTTOM w0.127: PU5201.2 101.79,7.55 101.97,7.73 101.97,8.37 PR5207.2 102.5,9.44 PR5210.2 103.05,8.92 PC5215.1
PWR_1D0V_FB: length 5.8
  TOP w0.254: PC5212.2 PR5202.2 PR5204.1 105.59,7.84 v1(105.51,7.76) 105.48,7.74 105.05,7.74 v2(104.82,7.97)
  BOTTOM w0.254: v2(104.82,7.97) 104.54,7.69 103.4,7.69 103.29,7.57 PU5201.5
PWR_1D0V_FB_A: length 3.3
  TOP w0.254: v1(102.28,8.2) 102.84,8.75 PG5223.1 103.49,9.24 PC5212.1 PR5202.1
PWR_1D0V_PFM: length 4.5
  BOTTOM w0.254: PU5201.3 102.29,7.58 102.36,7.65 102.36,8.17 102.69,8.5 103.17,8.5 103.5,8.17 v1(103.55,8.17) 104.31,8.17 105,8.86 PR5203.1
PWR_1D0V_PG: length 3.5
  TOP w0.127: PR5209.2 100.75,8.58 99.99,8.58 PR5208.2 99.95,7.64 v1(100.13,7.46) v2(100.73,6.85)
  BOTTOM w0.127: PU5201.1 100.86,6.97 v2(100.73,6.85)
PWR_1D0V_PH: length 1.5
  TOP w0.254: v1(101.04,2.86) 100.4,2.86 v3(100.38,2.89) 100.51,3.01 PC5204.2
PWR_1D0V_SS: length 2.5
  BOTTOM w0.254: PC5213.1 100.23,8.23 100.23,6.43 PU5201.22
PWR_1D0V_TON: length 2.3
  TOP w0.254: v1(102.72,6.89) PR5201.2 104.3,6.89 v2(104.39,6.98)
  BOTTOM w0.254: v2(104.39,6.98) 104.09,6.98 104.08,6.97 PU5201.6
PWR_1D2V_BOOT: length 4.3
  TOP w0.508: v1(45.97,9.31) v2(45.97,8.73)
  BOTTOM w0.254: v2(45.97,8.73) 46.45,8.73 46.81,8.37 PU5101.1 47.04,8.39 47.04,9.21 47.27,9.44 47.61,9.44 PR5101.1
PWR_1D2V_BOOT_R: length 2.5
  BOTTOM w0.508: PC5117.1 44.82,9 v1(45.52,9.69) 45.97,10.15 PR5101.2
PWR_1D2V_BYP: length 3.4
  BOTTOM w0.254: PC5110.1 47.12,3.25 PR5102.1 47.12,3.88 v1(47.39,4.16) 47.03,4.52 PU5101.15
PWR_1D2V_EN: length 5.9
  BOTTOM w0.102: PC5138.1 53,3.2 51.9,4.3 PR5105.2 51.46,4.44 51.23,4.21 v1(50.82,4.21) 50.39,4.64 48.95,4.64 48.83,4.77 PU5101.11
PWR_1D2V_IMAX: length 5.8
  BOTTOM w0.254: PU5101.13 47.93,4.77 48.21,4.49 48.46,4.49 v1(48.77,4.18) 50.21,4.18 50.62,3.78 51.74,3.78 52.22,3.3 PR5106.2
PWR_1D2V_PGOOD:
  vias: v1(50.8,5.48)
PWR_1D2V_PHASE: length 7.4
  TOP w0.254: v1(50.9,7.97) v2(50.34,7.97)
  L3 w0.508: v3(44.88,7.2) 45.64,7.97 v2(50.34,7.97)
  BOTTOM w0.254: v2(50.34,7.97) 50.22,7.85 PU5101.6
PWR_1D2V_VFB: length 7.4
  BOTTOM w0.254: PR5103.2 50.59,3.23 50.06,3.77 49.35,3.77 49.33,3.75 48.26,3.75 47.83,4.18 47.83,4.34 47.48,4.68 PU5101.14 ; PR5103.2 50.64,3.2 PR5104.1 ; PR5103.2 PC5112.2 50.61,1.65 v1(50.82,1.43)
PWR_1D2V_VFB_R: length 2.9
  BOTTOM w0.254: v1(49.48,1.43) 49.68,1.63 49.68,2.31 PC5112.1 PR5103.1 49.1,3.23 PG5113.2
PWR_1D5V_EN: length 5.7
  BOTTOM w0.127: v1(54,3.22) 54.8,3.22 PR5405.2 54.91,4.12 PC5407.1 55.98,5.19 56.81,5.19 57.49,5.87 PU5402.3
PWR_1D8V_EN: length 4.7
  BOTTOM w0.127: PR5401.1 PC5406.1 63.74,9.11 PR5406.2 PR5407.2 63.87,10.95 63.95,11.03 PU5401.8
PWR_1D8V_POK: length 4.7
  BOTTOM w0.127: PU5401.7 65,12.92 65.12,13.05 65.67,13.05 PR5402.2 65.58,12.91 v1(65.58,11.55) 65.66,11.47 66.06,11.47 66.3,11.71 PR5408.2
PWR_2D5V:
  vias: v1(49.22,99.74) v2(47.57,98.14)
PWR_2D5V_EN: length 9.4
  BOTTOM w0.102: PR5417.2 PC5427.1 PR5409.1 39.29,96.61 v1(38.96,96.94) 38.4,97.5 38.4,100.04 40.33,101.97 PU5403.8
PWR_2D5V_FB: length 5.7
  TOP w0.254: PR5419.2 47.22,98.64 v1(47.47,98.9) 47.47,99.18 46.99,99.66 PC5411.2 PR5420.1 46.84,100.55 v2(47.17,100.22)
  BOTTOM w0.254: PU5403.2 46.76,100.7 47.17,100.3 v2(47.17,100.22)
PWR_2D5V_PG: length 117.4
  TOP w0.127: v1(53.44,5.38) v2(53.44,4.82)
  L3 w0.127: v2(48.97,89.27) 48.44,88.74 48.44,87.55 47.55,86.66 47.55,85.94 48.69,84.8 48.69,64.35 47.55,63.21 47.55,39.28 45.11,36.84 45.11,35.5 45.39,35.22 45.39,27.35 46.05,26.69 46.05,23.97 46.61,23.41 46.61,22.72 v2(46.35,22.47)
  L4 w0.127: v2(53.44,4.82) 53.49,4.87 53.49,8.73 51.56,10.66 51.56,12.89 v2(49.22,15.23) 45.76,18.7 45.76,21.77 46.35,22.37 v2(46.35,22.47) ; v2(48.97,89.27) 48.75,89.49 48.75,91.16 49.15,91.56 v2(49.15,92.78)
  BOTTOM w0.127: v2(49.22,15.23) 48.66,14.67 48.66,14.55 47.95,13.83 PR5114.1 ; v2(53.44,4.82) 53.44,4.79 53.08,4.44 PR5105.1 ; v2(49.15,92.78) 47.95,92.78 47.34,93.39 42.95,93.39 42.47,93.87 42.47,95.65 42.07,96.04 PR5410.2 41.31,96.61 40.05,96.61 38.66,98.01 38.66,99.66 39.7,100.7 PU5403.7
PWR_3D3V:
  vias: v1(157.81,49.65) v3(159.18,51.4) v3(159.18,50.51) v3(159.18,49.62) v3(160.2,51.4) v3(160.2,50.51) v3(160.2,49.62) v3(162.95,51.43) v3(162.95,50.54) v3(162.95,49.65) v3(163.83,51.43) v3(163.83,50.56) v3(163.83,49.67)
PWR_3D3V_BOOT: length 3
  BOTTOM w0.254: PU4501.1 158.79,57.56 v1(158.27,57.04)
  BOTTOM w0.508: v1(158.27,57.04) 157.2,57.04 PR4501.1
PWR_3D3V_BOOT_A: length 2.3
  BOTTOM w0.508: v1(155.98,55.72) 157,55.72 PR4501.2 157.24,55.76 PC4506.1
PWR_3D3V_EN: length 4.8
  BOTTOM w0.127: PU4501.11 162.69,61.03 v1(162.89,61.23) 163.32,61.66 PC4508.1 PR4508.1 161.64,62.11 PR4509.2
PWR_3D3V_EN1: length 132.2
  TOP w0.127: v2(94.97,104.74) 95.22,104.99 PR4516.2 ; v2(165.82,61.73) v1(165.82,61.15)
  L3 w0.127: v2(94.97,104.74) 95.27,105.05 96.52,105.05 97.04,105.57 97.48,105.57 98.14,104.91 98.2,104.91 98.46,104.65 98.46,104.58 99.99,103.05 101.71,103.05 102.69,104.03 108.02,104.03 109.45,102.61 116.84,102.61 121.61,107.38 133.04,107.38 134.94,109.27 158.61,109.27 161.38,106.51 162.19,106.51 162.51,106.19 162.51,105.63 v2(162.05,105.17)
  L6 w0.127: v2(162.05,105.17) 162.34,105.17 165.14,102.38 165.14,100.79 169.05,96.88 169.05,78.13 167.03,76.12 165.24,76.12 164.93,75.81 164.93,70.95 166.53,69.35 166.53,62.44 v2(165.82,61.73)
  BOTTOM w0.127: PU4501.12 163.26,58.91 163.74,59.39 163.74,61.31 PC4532.1 PR4514.1 v2(165.82,61.73)
PWR_3D3V_FB: length 1.9
  BOTTOM w0.254: PC4533.1 163.41,58.46 PU4501.13
PWR_3D3V_FB2: length 0.8
  BOTTOM w0.254: PR4506.2 PC4533.2
PWR_3D3V_LDO: length 1.6
  TOP w0.254: v1(162.89,56.28) 162.89,56.84 v2(162.86,56.86) 162.86,57.8 PG4532.1
PWR_3D3V_PH: length 7.6
  TOP w0.254: v1(159.38,54.3) v3(160.07,54.3)
  L6 w0.508: v3(160.07,55.21) 160.07,58.89 160.5,59.33 v2(160.5,60.88)
  BOTTOM w0.254: PU4501.6 160.36,60.74 v2(160.5,60.88)
PWR_3D3V_VOUT: length 11.8
  BOTTOM w0.254: PG4530.1 164.97,53.69 v1(165.25,53.97) 165.25,55.16 166.65,56.56 166.65,58.92 166.3,59.26 PR4506.1 165.02,59.2 164.34,58.51 164.26,58.51 163.76,58.01 PU4501.14
PWR_3V_PG: length 4.9
  TOP w0.127: PR4505.2 162.06,60.06 PG4531.2 162.84,60.6 162.56,60.88 v1(162.56,61.03) 162.08,61.03 v2(161.97,60.93)
  BOTTOM w0.127: PU4501.10 162.16,60.74 v2(161.97,60.93) 161.71,60.66 PU4501.9
PWR_5V:
  vias: v1(110.13,108.2) v1(115.47,109.62) v3(109.73,103.37) v3(110.62,103.37) v3(111.48,103.37) v3(112.37,103.37) v3(112.6,107.31) v3(112.57,106.42) v3(112.65,105.5) v3(112.65,104.61) v3(113.49,107.31) v3(113.46,106.42) v3(113.54,105.5) v3(113.54,104.61)
PWR_5V_BOOT: length 2.2
  TOP w0.254: 100.57,108.3 PU4502.1
  TOP w0.508: 100.57,108.3 100.57,108.54 100.1,109.01 PR4502.1
PWR_5V_BOOT_A: length 2.3
  TOP w0.508: PR4502.2 102,109.29 102.46,109.74 v1(102.83,109.74) 102.83,108.88 PC4521.1
PWR_5V_EN: length 7.7
  TOP w0.254: v2(98.02,104.46) 98.02,104.46 PU4502.11 ; v1(91.6,103.66) PR4511.2 PR4512.1 PC4530.1 94.52,103.66 94.71,103.47 v2(94.99,103.47)
  BOTTOM w0.254: v2(98.02,104.46) 98.02,104.31 97.18,103.47 v2(94.99,103.47)
PWR_5V_EN1: length 10.7
  TOP w0.254: PR4504.2 94.24,101.1 v1(94.71,100.63) 95.15,100.19 96.26,100.19 96.85,99.61 96.99,99.61 PC4531.1 PR4513.1 97.12,100.42 97.38,100.69 97.38,101.46 97.2,101.64 97.2,103.09 97.56,103.45 98.88,103.45 99.22,103.78 PU4502.12
PWR_5V_EN1_R: length 4.8
  TOP w0.254: PR4503.2 PR4515.2 96.58,102.48 PR4530.1 96.34,102.24 96.34,102.23 95.96,101.85 94.94,101.85 v1(94.92,101.87) 94.64,101.87 94.52,101.99 PR4504.1
PWR_5V_FB: length 4.6
  TOP w0.254: PU4502.13 99.67,103.22 99.74,103.14 PC4526.1 98.98,102.89 98.88,102.99 97.89,102.99 97.86,102.96 v1(97.79,102.96) 97.79,102.12 PR4551.1
PWR_5V_FB_A: length 1.9
  TOP w0.254: PR4507.1 99.91,101.83 PC4526.2 99.52,102.23 v1(98.83,102.23)
PWR_5V_LDO: length 10.8
  TOP w0.254: PG4528.1 101.45,103.58 v2(101.37,103.66) PU4502.15
  BOTTOM w0.254: PC4520.1 105.76,98.98 105.99,99.2 v1(105.99,99.34) 106.2,99.55 106.2,101.01 104.82,102.38 102.72,102.38 101.44,103.66 v2(101.37,103.66)
PWR_5V_PG: length 6.6
  TOP w0.127: PU4502.10 97.39,104.98 v2(97.25,105.12) 97.57,105.43 PU4502.9 ; PR4510.1 93.88,104.58 PG4529.2 94.54,105.38 v2(94.59,105.33)
  BOTTOM w0.127: v2(94.59,105.33) 95.01,105.33 95.22,105.12 v2(97.25,105.12)
PWR_5V_PH: length 7.3
  TOP w0.254: PU4502.6 97.27,106.78 v2(97.25,106.77)
  BOTTOM w0.508: v3(102.97,107.03) 102.33,107.66 98.14,107.66 v2(97.25,106.77)
  vias: v1(104.49,106.14) v3(102.97,106.14) v3(102.97,105.25) v3(103.66,109.08) v3(103.68,108.22) v3(103.73,103.34) v3(104.49,109.08) v3(104.52,108.22) v3(104.62,103.34) v3(105.33,109.08) v3(105.36,108.22) v3(105.51,103.34) v3(106.17,109.03) v3(106.2,108.18) v3(106.48,103.34)
PWR_5V_VCC:
  vias: v1(102.77,103.95)
PWR_5V_VOUT: length 13.2
  TOP w0.254: PR4507.2 100.57,103.11 100.2,103.47 v2(100.2,103.49) 100.2,103.55 100.12,103.63 PU4502.14
  L3 w0.254: v2(100.2,103.49) 100.2,103.55 100.13,103.62 100.13,104.82 101.27,105.96 101.27,108.27 v2(101.32,108.32)
  BOTTOM w0.254: v2(101.32,108.32) 101.32,108.5 103.4,110.58 v1(104.75,110.58) PG4527.1
PWR_ASGATE: length 8.5
  TOP w0.254: v2(148.03,35.35) 147.7,35.02 147.21,35.02 146.91,35.32 146.91,35.91 148.51,37.51 v1(148.51,37.52) PC4436.2
  BOTTOM w0.203: PU4401.30 145.98,34.06 146.28,34.36 146.3,34.36
  BOTTOM w0.254: 146.3,34.36 146.53,34.36 147.06,34.89 147.55,34.89 148,35.35 v2(148.03,35.35)
PWR_CHG_1: length 8.4
  TOP w0.254: v2(150.37,37.63) 150.34,37.66 v1(150.34,38.45) 150.26,38.45 148.97,39.74 PD4402.K 148.33,39.74 148.33,40.5 v2(147.9,40.94)
  BOTTOM w0.254: v2(150.37,37.63) 150.71,37.63 PD4405.K ; PD4401.K 147.9,40.39 v2(147.9,40.94) 147.85,40.89 PR4407.2
PWR_CHG_ACDET: length 4.2
  BOTTOM w0.254: PU4401.1 144.62,32.63 145.13,32.63 145.63,32.13 146.05,32.13 146.55,32.63 PR4408.2 PC4413.1 146.77,31.77 PR4409.1
PWR_CHG_ACN: length 6.8
  TOP w0.254: v1(145.9,36.03) 145.9,35.88 145.68,35.67 PC4404.1 146.43,34.37 v2(146.43,33.82)
  BOTTOM w0.203: PU4401.31 146.27,33.66 v2(146.43,33.82)
  BOTTOM w0.254: PR4414.2 148.65,35.25 148.24,34.84 148.21,34.84 147.76,34.38 147.43,34.38 PC4402.2 146.87,33.82 v2(146.43,33.82)
PWR_CHG_ACOK: length 15.5
  TOP w0.102: PR4463.2 136.45,31.12 v1(136.45,31.39) 136.45,31.57 v2(136.84,31.96) ; PR4443.2 143.95,33.42 PR4422.2 144.38,33.41 145.01,32.78 PG4408.1 145.01,31.61 v2(145.13,31.49)
  L4 w0.102: v2(145.13,31.49) 144.3,32.33 137.2,32.33 v2(136.84,31.96)
  BOTTOM w0.102: v2(145.13,31.49) 144.68,31.94 144.42,31.94 144.18,32.19 PU4401.2
PWR_CHG_ACP: length 5.3
  TOP w0.254: PC4403.1 145.67,34.23 145.87,34.03 145.87,33.49 v2(146.2,33.16)
  BOTTOM w0.203: PU4401.32 146.1,33.26 v2(146.2,33.16)
  BOTTOM w0.254: v2(146.2,33.16) 147.1,33.16 PC4402.1 148.37,34.43 PR4444.1
PWR_CHG_BATDRV: length 2.9
  BOTTOM w0.203: PU4401.25 145.62,36.06 145.74,36.19 145.74,36.57
  BOTTOM w0.254: PC4437.2 146.44,37.99 146.44,37.98 145.74,37.28 145.74,36.57
PWR_CHG_BATPRES#: length 3.6
  BOTTOM w0.203: 139.76,34.75 139.76,34.75 140.26,34.75 140.37,34.86 PU4401.13
  BOTTOM w0.254: PR4449.1 138.49,35.17 v1(139.19,35.17) 139.34,35.17 139.76,34.75
PWR_CHG_BTST: length 3.2
  TOP w0.508: PR4447.1 146.45,38.09 v1(146.48,38.07) 146.48,37.61 146.02,37.15 146.01,37.15 145.64,36.78 145.64,36.77 145.44,36.57 v2(145.08,36.57)
PWR_CHG_BTST1: length 3
  TOP w0.254: PR4447.2 146.45,41.24 146.15,41.55 v1(145.77,41.55) 145.44,41.55 145.16,41.27 PC4414.1
PWR_CHG_COMP: length 5.2
  BOTTOM w0.203: PU4401.10 140.63,33.66 140.33,33.37 139.33,33.37 PR4416.1
  BOTTOM w0.254: PR4416.1 138.68,32.72 v1(138.68,31.84) 138.23,31.84 137.93,32.14 PC4427.1
PWR_CHG_FSET: length 3.4
  TOP w0.254: v2(140.08,34.23) 139.44,34.23 139.19,33.98 v1(139.19,33.7) 139.32,33.57 PR4430.1
  BOTTOM w0.203: v2(140.08,34.23) 140.31,34.46 PU4401.12
PWR_CHG_HIDRV: length 16.1
  TOP w0.406: PU4404.4 147.02,50.36 v3(147.83,50.36)
  TOP w0.508: v1(145.31,37.58) 145.54,37.81 v3(145.54,38.24)
  L6 w1.016: v3(147.83,50.36) 147.21,50.36 146.35,49.5 146.35,40.17
  BOTTOM w0.203: v3(145.54,38.24) 145.54,37.81 145.18,37.46 144.44,37.46 144.18,37.2 PU4401.23
PWR_CHG_IADP: length 2.8
  TOP w0.254: PG4401.1 142.09,30.88 142.47,31.26 v2(142.47,31.51) 142.47,31.64 v1(142.11,32)
  BOTTOM w0.203: PU4401.6 142.58,31.62 v2(142.47,31.51)
PWR_CHG_IDCHG: length 4.2
  TOP w0.254: PG4414.1 140.51,30.7 140.26,30.95 v1(140.26,31.56) 140.38,31.69 v2(141.17,31.69)
  BOTTOM w0.203: PU4401.7 142.18,32.11 141.98,31.92 141.4,31.92 v2(141.17,31.69)
PWR_CHG_ILIM: length 8.9
  TOP w0.254: v2(138.73,34.51) 138.3,34.08 138.3,33.16 138.98,32.49 v1(139.03,32.49) 139.61,32.49 139.85,32.73 PR4423.1
  BOTTOM w0.203: 139.39,34.31 139.42,34.28 139.42,33.98 139.67,33.72 140.21,33.72 140.55,34.06 PU4401.11
  BOTTOM w0.254: PR4420.2 137.18,34.64 137.69,34.13 138.35,34.13 v2(138.73,34.51) 139.19,34.51 139.39,34.31
PWR_CHG_LODRV: length 1.5
  BOTTOM w0.203: v3(143.61,38.14) 143.61,37.77 143.38,37.54 PU4401.21
  vias: v1(141.65,43.3) v3(142.04,44.03)
PWR_CHG_NTC: length 2
  TOP w0.254: v2(141.1,36.69) 141.22,36.69 141.73,37.2 PR4437.1
  BOTTOM w0.203: v2(141.1,36.69) 141.14,36.74 PU4401.17
PWR_CHG_PHASE: length 7
  L6 w1.016: 147.6,37.02 149.05,38.47 149.05,41.65
  BOTTOM w0.203: PU4401.22 143.78,37.42 144.52,38.17 v3(144.58,38.17)
  vias: v1(148.26,42.87) v3(147.52,49.27) v3(147.52,44.75) v3(147.52,43.86) v3(148.39,49.29) v3(148.39,44.7) v3(148.36,43.83)
PWR_CHG_PHASE_1:
  vias: v1(155.62,43.27)
PWR_CHG_PMON: length 3.1
  BOTTOM w0.203: 141.01,32.59 PU4401.8
  BOTTOM w0.254: PG4415.1 v1(140.59,31.39) 140.59,32.17 141.01,32.59
PWR_CHG_PROCHOT#: length 2
  TOP w0.089: v2(143.13,31.49) 143.13,30.8 PG4419.1
  BOTTOM w0.089: PU4401.5 142.98,31.64 v2(143.13,31.49)
PWR_CHG_PROG: length 1.6
  BOTTOM w0.203: PU4401.9 140.64,33.26 140.25,32.87 PR4433.1
PWR_CHG_REGN: length 14.2
  TOP w0.254: v2(142.97,41.55) 143.39,41.13 PC4431.1 143.39,40.89 143.94,40.34 PR4412.2 143.94,39.33 142.9,38.29 v2(142.9,37.86)
  L4 w0.254: v2(142.9,37.86) 142.9,38.09 142.44,38.55 140.31,38.55 138.94,37.18 v2(138.94,36.47)
  BOTTOM w0.203: v2(142.9,37.86) 142.98,37.78 PU4401.20
  BOTTOM w0.254: v1(142.59,41.06) 142.97,41.44 v2(142.97,41.55) ; v2(138.94,36.47) 138.85,36.55 PR4421.1 138.02,36.49 137.3,35.77 PR4420.1
PWR_CHG_SCL: length 2.9
  TOP w0.089: PG4410.2 144.04,31.18 143.79,31.44 v2(143.79,31.49) 143.79,31.59 v1(143.38,32)
  BOTTOM w0.089: v2(143.79,31.49) 143.38,31.9 PU4401.4
PWR_CHG_SDA: length 2.5
  TOP w0.089: v2(144.45,31.49) 145.01,30.93 PG4409.2
  BOTTOM w0.089: PU4401.3 143.78,32.11 144.4,31.49 v2(144.45,31.49)
PWR_CHG_SRN: length 10.5
  TOP w0.254: v1(139.83,41.37) 139.83,41.22 140.4,40.64 PR4448.1 140.78,40.58 PC4420.2 139.6,38.59 139.6,35.63 140.03,35.2 v2(140.08,35.2) 140.37,34.9 PC4422.1
  BOTTOM w0.203: v2(140.08,35.2) 140.15,35.26 PU4401.14
PWR_CHG_SRN_1: length 12.7
  TOP w0.254: v2(140.89,42.26) 140.84,42.21 PR4448.2
  BOTTOM w0.254: PG4413.2 151.76,40.02 151.03,40.76 150.77,40.76 149.81,41.72 145.26,41.72 144.73,42.26 v1(141.81,42.26) v2(140.89,42.26)
PWR_CHG_SRP: length 10.1
  TOP w0.254: PR4411.2 141.65,39.78 PC4420.1 141.08,39.18 140.73,39.18 139.98,38.43 139.98,36.03 v2(140.16,35.86) 141.17,35.86 141.7,36.39 PC4421.1 142.15,35.92 v1(142.57,35.5)
  BOTTOM w0.203: v2(140.16,35.86) 140.35,35.66 PU4401.15
PWR_CHG_SRP_1: length 13.5
  TOP w0.254: PR4411.1 141.65,42.23 140.99,42.89 v2(140.87,42.89)
  BOTTOM w0.254: v2(140.87,42.89) 140.99,42.76 v1(143.23,42.76) 144.96,42.76 145.49,42.23 150.02,42.23 150.98,41.27 151.46,41.27 PG4412.2
PWR_CHG_VCC: length 6.6
  BOTTOM w0.203: 141.58,37.96 141.58,37.8 142.18,37.2 PU4401.18
  BOTTOM w0.508: 141.58,37.96 141.58,38.22 141.98,38.62 v1(142.24,38.62) 142.85,39.23 144.09,39.23 144.12,39.21 PC4412.1 PR4407.1
PWR_CMSRC: length 6.1
  TOP w0.254: v2(147.42,35.53) 147.42,35.7 v1(148,36.29) 148.35,36.63 PC4436.1 149.48,36.61 PR4410.1
  BOTTOM w0.203: PU4401.29 145.87,34.46 146.02,34.61
  BOTTOM w0.254: v2(147.42,35.53) 147.24,35.35 146.86,35.35 146.25,34.74 146.14,34.74 146.02,34.61
PWR_DCBATOUT_1D0V:
  vias: v1(107.95,5.81) v2(105.43,5.1) v2(106.09,5.07) v2(106.74,5.07) v3(109.7,5.88)
PWR_DCBATOUT_1D2V:
  vias: v1(51.08,9.26) v3(49.48,8.7) v3(50.32,8.73)
PWR_DCBATOUT_3D3V:
  vias: v1(158.77,61.18) v2(159.26,60.77) v2(159.79,60.42) v3(159.15,60.04) v3(159.87,61.28)
PWR_DCBATOUT_5V:
  vias: v1(96.8,108.14) v3(91.39,108.58) v3(92.28,108.58) v3(93.17,108.58) v3(94.13,108.56) v3(95.07,108.58) v3(95.96,108.58)
PWR_OPCN: length 3.6
  BOTTOM w0.203: PU4401.28 145.77,34.86 146,35.09 146.05,35.09 146.85,35.89
  BOTTOM w0.254: 146.85,35.89 146.89,35.93 147.04,35.93 v1(147.07,35.96) 147.12,35.96 147.24,36.08 147.8,36.08 148.13,36.41
PWR_OPCP: length 5.5
  BOTTOM w0.127: 146.78,36.49 146.76,36.47 146.76,36.27 145.75,35.26 PU4401.27
  BOTTOM w0.254: 146.78,36.49 147.5,37.2 148.66,37.2 PC4426.1
PWR_VBAT: length 4.6
  TOP w0.254: v1(146.81,36.84) 146.48,36.52 v2(146.28,36.52)
  BOTTOM w0.203: v2(146.28,36.52) 146.28,36.23 145.71,35.66 PU4401.26
  BOTTOM w0.254: v2(146.28,36.52) 146.28,36.94 PC4437.1 147.58,38.24 PR4403.1
PWR_VCCGT_BOOTA: length 3.1
  BOTTOM w0.203: 156.13,81.25 155.86,81.52 PU4801.35
  BOTTOM w0.508: v1(156.64,79.59) 156.74,79.7 PR4802.1 156.64,80.74 156.13,81.25
PWR_VCCGT_BOOTA_RC: length 2.6
  BOTTOM w0.508: v1(158.19,79.59) 158.06,79.72 PR4802.2 PC4809.1
PWR_VCCGT_BOOTB: length 4.5
  BOTTOM w0.203: PU4802.35 144.24,92.76 144.7,92.29 144.7,91.79
  BOTTOM w0.508: v1(145.57,89.37) PR4805.1 145.36,90.62 144.7,91.28 144.7,91.79
PWR_VCCGT_BOOTB_RC: length 2.6
  BOTTOM w0.508: PC4845.1 PR4805.2 147.5,90.62 v1(147.95,91.08)
PWR_VCCGT_COMP: length 4.5
  TOP w0.254: PC4618.2 156.27,89.17 PC4617.2 157.12,89.23 v1(157.12,90.16) 157.12,90.43 v2(157.68,90.99)
  BOTTOM w0.203: PU4601.4 157.49,91.19 v2(157.68,90.99)
PWR_VCCGT_COMP_R: length 1.9
  TOP w0.254: v1(157.05,87.37) 157.19,87.51 PR4631.2 156.27,88.31 PC4618.1
PWR_VCCGT_CSCOMP: length 24.7
  TOP w0.254: v1(158.27,87.01) v2(158.27,87.62)
  L4 w0.254: v2(158.27,87.62) 158.25,87.63 157.62,87.63 156.89,88.36 152.68,88.36 151.41,89.63 146.86,89.63 146.1,88.87 144.75,88.87 v2(144.58,89.04)
  BOTTOM w0.203: PU4601.6 156.69,91.25
  BOTTOM w0.254: PR4634.2 143.5,87.66 144.58,88.74 v2(144.58,89.04) ; v2(158.27,87.62) 158.33,87.69 PR4640.2 157.69,88.77 PR4639.2 157.18,88.63 PC4620.1 PC4621.1 156.69,89.52 156.69,91.25
PWR_VCCGT_CSNA: length 12
  TOP w0.254: v2(145.59,82.77) 145.77,82.95 145.77,86.61 146.76,87.6 149.29,87.6 150.24,88.54 v2(150.24,88.72)
  BOTTOM w0.254: v2(150.24,88.72) 150.27,88.72 v1(150.74,88.25) 151.12,87.88 PR4646.2 ; PG4809.1 145.22,82.77 v2(145.59,82.77)
PWR_VCCGT_CSNB: length 27
  TOP w0.254: v2(155.17,86.73) v1(155.17,87.37) 155.17,87.56 154.84,87.89 PR4643.2
  L4 w0.254: v2(134.26,93.72) 134.47,93.51 134.47,93.01 139.65,87.82 142.01,87.82 143,86.83 150.67,86.83 151.08,86.43 153.82,86.43 154.13,86.73 v2(155.17,86.73)
  BOTTOM w0.254: v2(134.26,93.72) 133.75,94.23 PG4816.1
PWR_VCCGT_CSP1: length 5
  TOP w0.254: v2(154.39,90.7) 153.97,90.28 PC4624.2 ; PR4651.1 PC4624.2 ; PC4624.2 152.96,90.01 v1(152.83,90.14)
  BOTTOM w0.203: v2(154.39,90.7) 154.51,90.7 154.81,91 154.84,91 155.14,91.3 155.14,91.33 155.16,91.35 155.16,91.71 155.09,91.77 PU4601.10
PWR_VCCGT_CSP2: length 4.6
  BOTTOM w0.203: PU4601.9 155.49,91.91 155.54,91.86 155.54,91.14
  BOTTOM w0.254: PC4622.2 PR4642.2 154.9,89.78 PR4654.1 154.99,90.57 155.01,90.59 v1(155.01,90.62) 155.02,90.62 155.54,91.14
PWR_VCCGT_CSPA: length 14.7
  TOP w0.254: PR4651.2 153.62,88.23 PR4637.1 v1(151.66,89.02) 151.25,89.02 149.45,87.21 146.94,87.21 146.28,86.55 146.28,82.72 145.95,82.39 145.95,82.36 v2(145.72,82.13)
  BOTTOM w0.254: PG4808.1 146.01,82.43 v2(145.72,82.13)
PWR_VCCGT_CSPB: length 25.9
  TOP w0.254: v1(150.75,86.83) 150.87,86.83 v2(151.23,87.19)
  L4 w0.254: v2(135.02,93.72) 134.85,93.54 134.85,93.26 139.9,88.21 142.19,88.21 143.18,87.21 151.2,87.21 v2(151.23,87.19)
  BOTTOM w0.254: PR4654.2 154.99,88.79 154.61,88.41 154.3,88.41 153.52,87.62 PR4641.1 153.49,87.57 152.64,86.72 152.16,86.72 152.15,86.71 151.73,86.71 151.26,87.19 v2(151.23,87.19) ; v2(135.02,93.72) 135.43,94.12 PG4815.1
PWR_VCCGT_CSREF: length 17.3
  TOP w0.254: PC4626.1 155.96,90.84 v2(155.7,90.58) 155.13,90.01 PC4624.1 154.84,89.99 PR4643.1 154.94,89.17 155.62,88.48 155.62,87.82 155.75,87.69 155.75,86.85 156.31,86.29 156.31,85.84 155.88,85.41 v1(154.99,85.41) 154.99,85.65 154.29,86.35 152.8,86.35 152.02,87.14 152.02,87.15 v2(151.94,87.22)
  BOTTOM w0.203: PU4601.8 155.89,92.05 155.92,92.02 155.92,91.1
  BOTTOM w0.254: 155.92,91.1 155.92,90.8 v2(155.7,90.58) ; v2(151.94,87.22) 151.95,87.22 152.54,87.81 PR4646.1 153.29,88.62 PC4622.1
PWR_VCCGT_CSSUM: length 11.2
  TOP w0.254: v2(155.73,86.05) 155.14,86.05 154.96,86.22 154.96,86.22 154.66,86.52 154.66,86.53 153.49,87.7 PR4637.2
  BOTTOM w0.203: PU4601.7 156.29,90.78 156.3,90.76
  BOTTOM w0.254: PR4641.2 154.99,87.8 PR4638.2 ; PR4638.2 155.79,87.8 PC4620.2 PC4621.2 155.79,89.96 156.2,90.37 156.2,90.38 v1(156.23,90.41) 156.3,90.48 156.3,90.76 ; PR4638.2 155.79,86.11 v2(155.73,86.05)
PWR_VCCGT_DIFFOUT: length 4.5
  TOP w0.254: v2(158.85,90.67) 158.96,90.56 PR4626.1 159.05,90.07 PR4625.1 160.51,90.07 v1(160.73,90.29)
  BOTTOM w0.203: 158.29,91.82 PU4601.2
  BOTTOM w0.254: 158.29,91.82 158.7,91.41 158.7,90.82 v2(158.85,90.67)
PWR_VCCGT_DISB#_A: length 3.2
  BOTTOM w0.203: PU4801.2 153.94,80.1 154.19,79.85
  BOTTOM w0.254: PR4808.2 154.99,78.96 155.24,79.21 v1(155.24,79.42) 155.24,79.62 155.01,79.85 154.19,79.85
PWR_VCCGT_DISB#_B: length 2.7
  BOTTOM w0.203: PU4802.2 142.58,91.34 142.77,91.15 143.36,91.15 143.56,90.95 v1(143.56,90.69)
  BOTTOM w0.254: PR4809.2 143.56,89.82 v1(143.56,90.69)
PWR_VCCGT_FB: length 6.2
  TOP w0.254: v2(158.21,90.64) 158.21,90.52 158.08,90.38 PR4626.2 PC4617.1 PR4631.1 158.09,88.29 PC4614.2 159.6,88.29 v1(159.89,88)
  BOTTOM w0.203: 157.89,91.66 PU4601.3
  BOTTOM w0.254: v2(158.21,90.64) 158.21,91.33 157.89,91.66
PWR_VCCGT_FB_R: length 1.9
  TOP w0.254: v1(160.73,88.97) 160.51,89.18 PR4625.2 PC4614.1
PWR_VCCGT_ICCMAX: length 3.7
  TOP w0.254: v2(151.68,94.78) 153.04,94.78 PR4672.2
  BOTTOM w0.203: 153.08,94.96 153.14,95.02 PU4601.18
  BOTTOM w0.254: v2(151.68,94.78) 151.87,94.96 v1(152.45,94.96) 153.08,94.96
PWR_VCCGT_ILIM: length 3.4
  BOTTOM w0.203: 157.09,90.54 PU4601.5
  BOTTOM w0.254: 157.09,90.54 157.09,90.5 157.43,90.15 v1(157.47,90.15) 157.97,89.66 PR4640.1
PWR_VCCGT_ILIM_R: length 18.7
  L4 w0.254: v2(143.81,89.02) 144.35,88.48 146.35,88.48 147.12,89.25 151.26,89.25 152.53,87.98 156.01,87.98 156.31,87.67 v2(156.31,87.01)
  BOTTOM w0.254: PR4634.1 142.61,87.41 v1(143.38,88.18) 143.81,88.61 v2(143.81,89.02) ; v2(156.31,87.01) 156.31,87.11 156.68,87.48 PR4638.1 157.24,87.8 PR4639.1
PWR_VCCGT_IOUT: length 5.2
  TOP w0.254: PR4632.2 156.69,92.1 v1(156.69,91.3) 156.92,91.3 157.52,91.91 PC4615.2 158.26,91.33 v2(159.21,91.33)
  BOTTOM w0.203: 158.85,91.86 158.69,92.03 PU4601.1
  BOTTOM w0.254: v2(159.21,91.33) 159.21,91.51 158.85,91.86
PWR_VCCGT_NTC: length 5.3
  BOTTOM w0.254: PR4656.2 149.73,87.2 149.73,88.94 150.26,89.48 v1(150.49,89.48) 150.69,89.48 151.4,88.76 PR4661.1 PR4655.1
PWR_VCCGT_PHASEDA:
  vias: v1(156.89,83.28)
PWR_VCCGT_PHASEDB:
  vias: v1(144.91,93.13)
PWR_VCCGT_PWMA: length 19.1
  TOP w0.254: v2(152.98,79.65) 152.98,79.8 v1(152.65,80.13)
  L6 w0.254: v2(151.41,93.28) 151.41,92.7 151.81,92.29 151.81,91.53 152.45,90.9 152.45,86.71 151.74,86 151.74,81.27 152.98,80.03 v2(152.98,79.65)
  BOTTOM w0.203: v2(152.98,79.65) 152.98,79.75 153.14,79.9 PU4801.4 ; PU4601.16 152.95,94.22 152.84,94.1 152.35,94.1 152.07,93.82 151.81,93.82 151.56,93.56 151.56,93.43 v2(151.41,93.28)
PWR_VCCGT_PWMB: length 14.2
  TOP w0.254: v2(141.76,90.9) 142.14,91.28 142.8,91.28 145.72,94.2 v1(149.22,94.2) v2(151.31,94.2)
  BOTTOM w0.203: v2(151.31,94.2) 151.94,94.2 152.2,94.45 152.58,94.45 152.7,94.58 153.21,94.58 153.25,94.62 PU4601.17 ; PU4802.4 141.78,91.05 141.76,91.02 v2(141.76,90.9)
PWR_VCCGT_SNUB_1: length 3.3
  BOTTOM w0.508: v1(147.88,89.58) 147.32,89.58 146.62,88.88 PC4810.1 146.12,88.14 PR4804.2
PWR_VCCGT_SNUB_2: length 1.3
  BOTTOM w0.508: PC4814.1 PR4807.2
PWR_VCCGT_SWB:
  vias: v1(140,99.51)
PWR_VCCGT_TSENSE: length 6
  TOP w0.254: v2(154.64,91.5) 154.79,91.36 v1(155.24,91.36) 155.24,92.09 PC4630.1
  BOTTOM w0.203: PU4601.11 154.69,91.55 v2(154.64,91.5)
  BOTTOM w0.254: PR4655.2 152.47,90.54 153.08,91.15 154,91.15 154.35,91.5 v2(154.64,91.5)
PWR_VCCGT_VCCA: length 3.6
  BOTTOM w0.203: 151.79,80.08 152.16,80.45 PU4801.6
  BOTTOM w0.254: 151.79,80.08 PR4803.1 151.74,78.91 PC4808.1 150.9,78.15 v1(150.8,78.05)
PWR_VCCGT_VCCB: length 3.9
  BOTTOM w0.203: 140.56,91.02 140.56,91.26 PU4802.6
  BOTTOM w0.254: v1(139.88,88.94) 140.08,89.15 PC4847.1 140.79,89.5 140.91,89.62 PR4806.1 140.91,90.24 140.56,90.59 140.56,91.02
PWR_VCCGT_VSN: length 4.5
  BOTTOM w0.203: PU4601.48 159.34,92.44 159.49,92.29
  BOTTOM w0.254: 159.49,92.29 160.02,91.76 v1(160.02,90.59) 160.02,89.72 PR4619.1 PC4612.2
PWR_VCCGT_VSN_R: length 3.5
  BOTTOM w0.254: PR4618.2 161.57,88.78 PC4611.2 PR4619.2 PC4612.1 159.15,88.18 v1(158.85,87.88)
PWR_VCCGT_VSP: length 5.5
  BOTTOM w0.203: PU4601.47 159.75,93.42 159.92,93.25 159.92,92.45 160.12,92.25
  BOTTOM w0.254: PR4617.2 160.8,89.68 PC4611.1 160.78,91.58 v1(160.7,91.66) 160.12,92.25
PWR_VCCSA_BST: length 2.8
  BOTTOM w0.305: 154.12,55.04 PU5001.1
  BOTTOM w0.508: PR5013.1 153.95,56.2 v1(154.07,56.07) 154.12,56.03 154.12,55.04
PWR_VCCSA_BST_RC: length 2.3
  BOTTOM w0.508: PR5013.2 151.31,56.56 v1(150.57,56.56) 150.42,56.4 PC5008.1
PWR_VCCSA_COMP: length 4.7
  TOP w0.254: v2(160.81,94.71) 161.21,94.3 v1(161.21,94.02) 160.75,94.02 160.32,94.45 PC4604.2
  BOTTOM w0.203: v2(160.81,94.71) 160.81,94.73 160.52,95.02 PU4601.43
  BOTTOM w0.254: v2(160.81,94.71) 161.11,95.01 PC4602.2
PWR_VCCSA_COMP_R: length 6.9
  TOP w0.254: PR4602.2 160.36,93.49 162.13,93.49 162.56,93.92 v1(162.56,95.67) 162.48,95.75 161.64,95.75 v2(161.57,95.83)
  BOTTOM w0.254: v2(161.57,95.83) 161.64,95.75 162.28,95.75 162.52,95.51 PC4602.1
PWR_VCCSA_CSN: length 72.7
  TOP w0.254: v2(139.5,58) 139.62,57.88 v1(139.62,57.45)
  L6 w0.254: v2(163.24,96.74) 163.75,96.74 164.64,95.85 164.64,94.43 159.84,89.63 159.84,85.18 158.21,83.56 158.21,77.01 156.36,75.15 156.36,71.63 157.36,70.63 159.23,70.63 160.4,69.46 160.4,67.75 155.4,62.75 140.89,62.75 140.39,62.25 140.39,59.92 139.67,59.2 139.67,58.18 v2(139.5,58)
  BOTTOM w0.203: PU4601.41 160.47,95.82
  BOTTOM w0.254: 160.47,95.82 161.14,96.48 161.48,96.48 PC4606.1 162.49,96.68 PC4607.1 163.19,96.69 v2(163.24,96.74) ; PG5022.1 138.91,57.22 139.5,57.8 v2(139.5,58) 139.5,59.25 138.92,59.82 PR4606.2
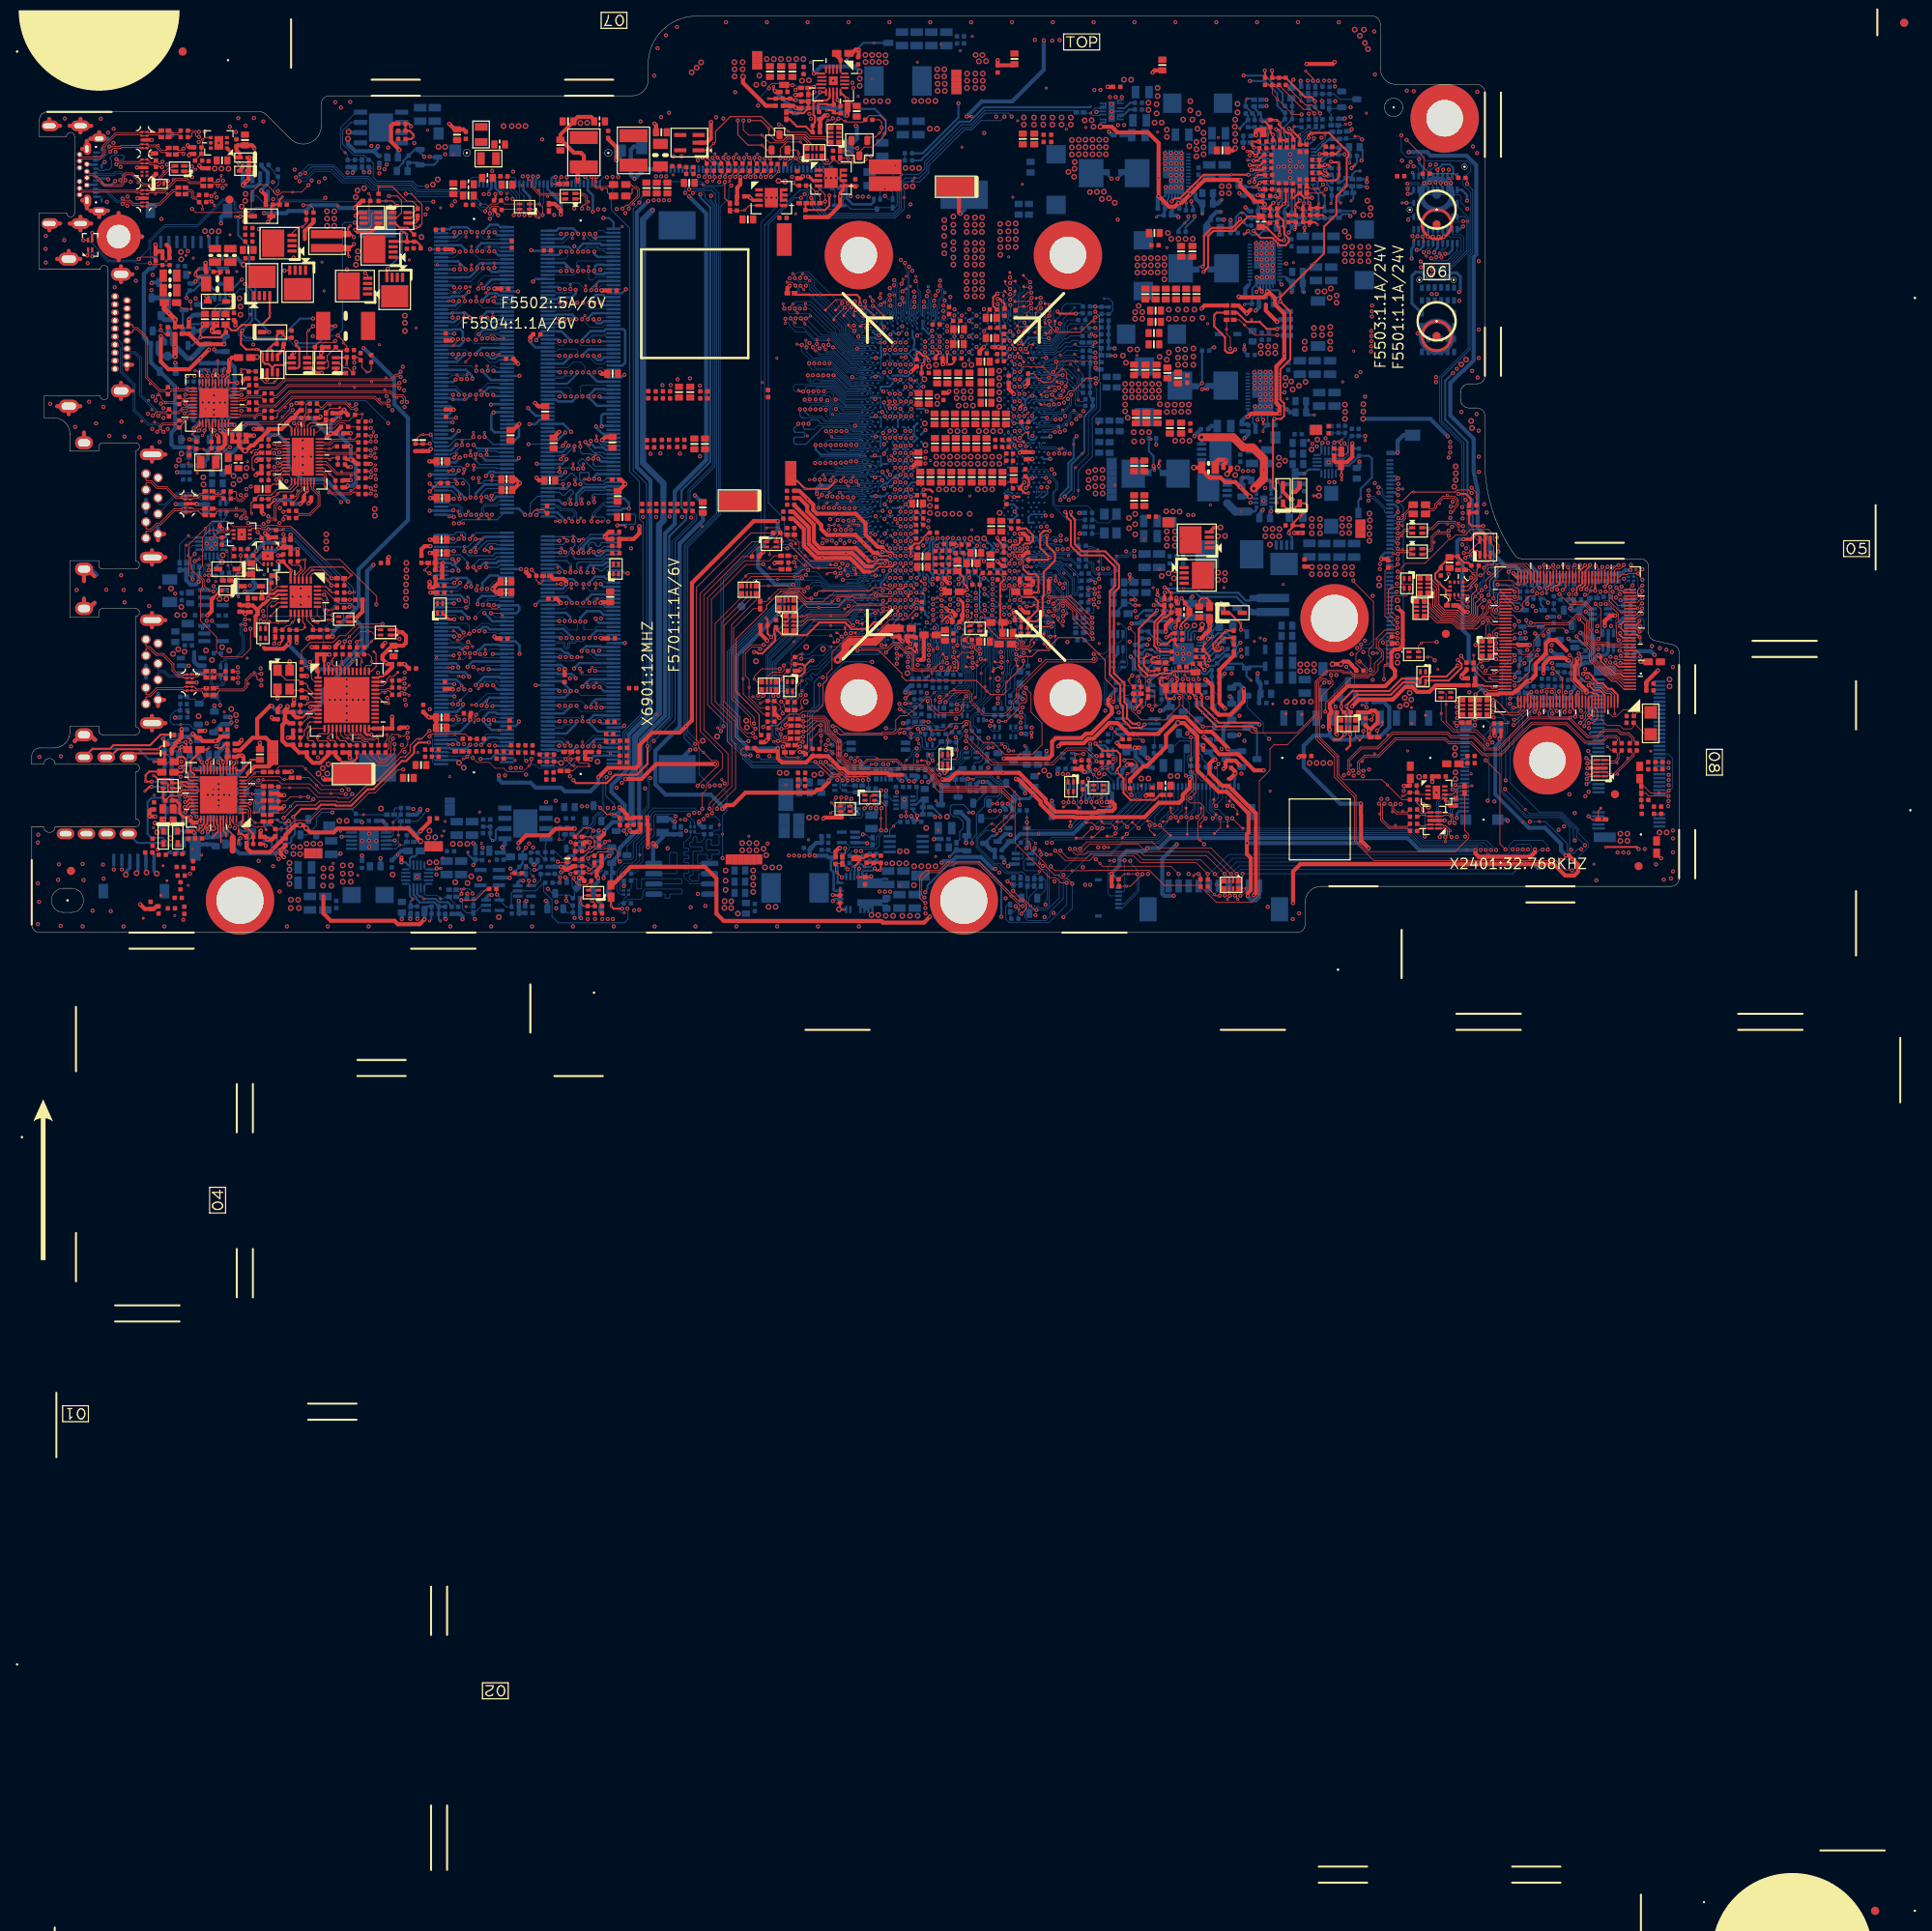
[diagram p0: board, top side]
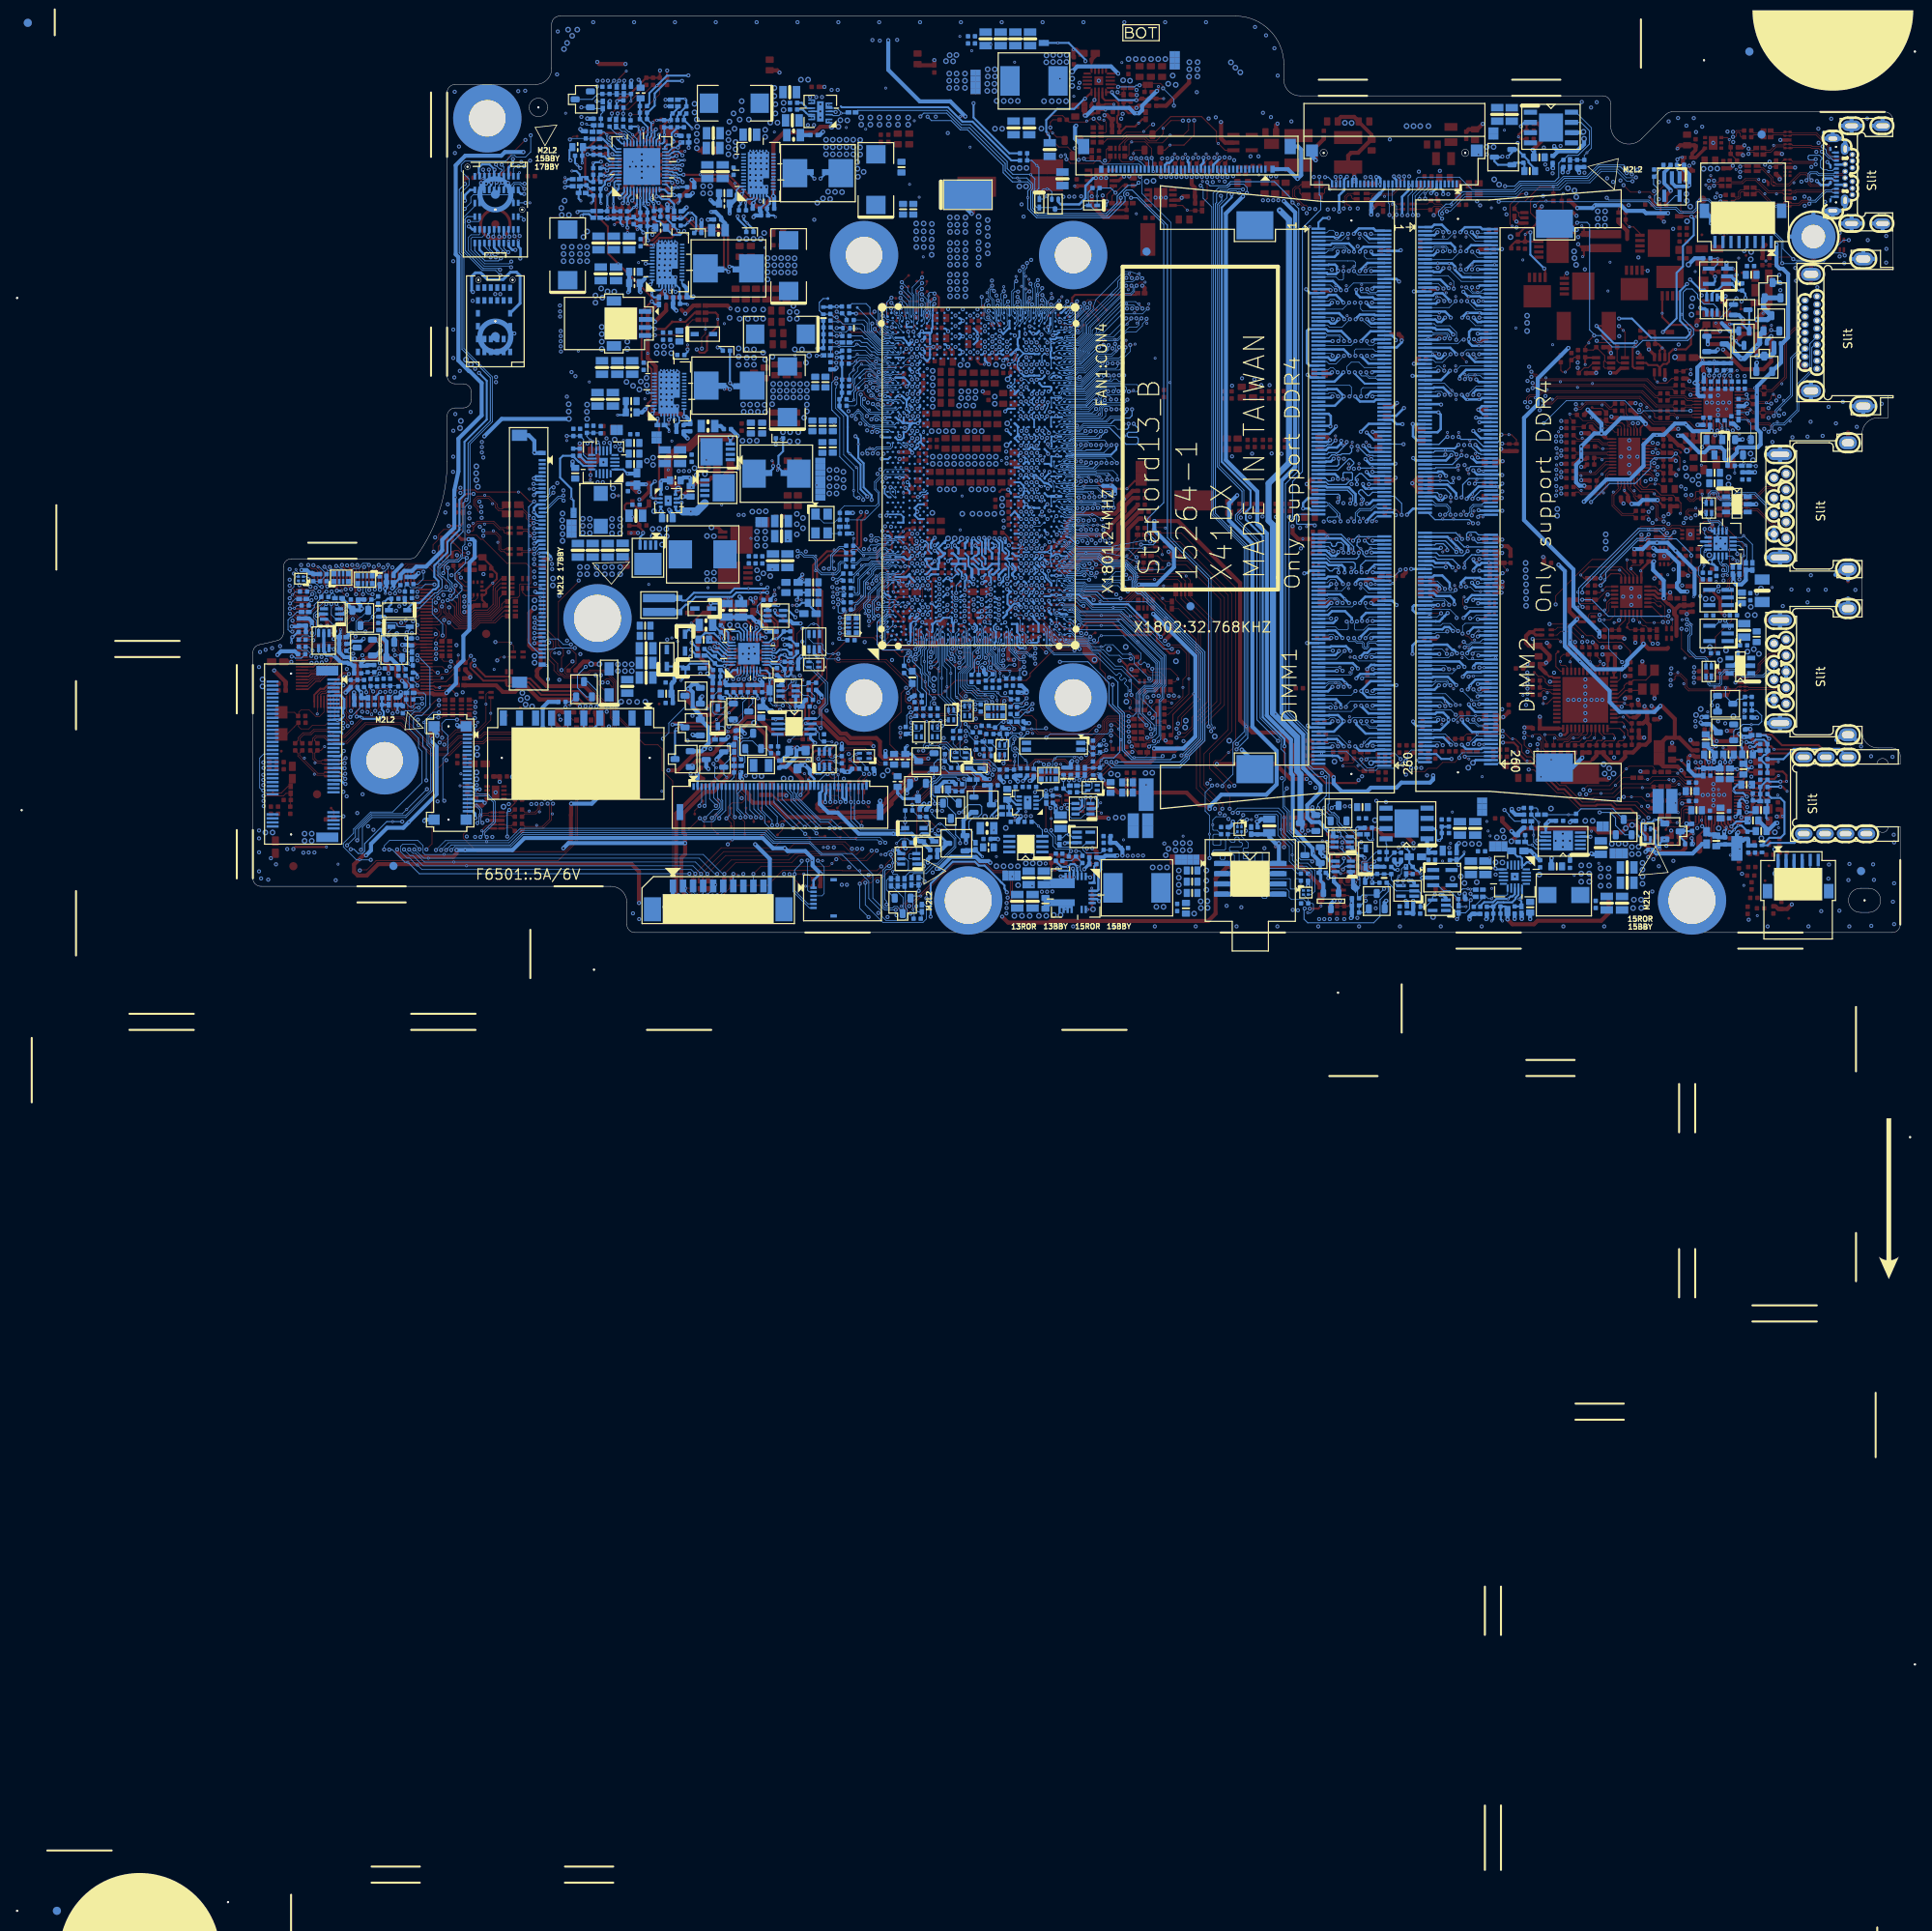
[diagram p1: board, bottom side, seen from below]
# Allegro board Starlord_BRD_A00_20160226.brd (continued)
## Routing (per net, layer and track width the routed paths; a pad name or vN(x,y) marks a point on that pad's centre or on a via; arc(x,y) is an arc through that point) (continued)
PWR_VCCSA_CSN_NTC: length 60.6
  TOP w0.254: v2(164.13,95.01) v1(164.53,95.41)
  L6 w0.254: v2(139.83,60.65) 139.83,62.25 140.71,63.13 155.24,63.13 160.02,67.91 160.02,69.3 159.07,70.25 157.21,70.25 155.95,71.5 155.95,75.3 157.83,77.18 157.83,83.72 159.46,85.34 159.46,89.24 159.46,89.79 164.13,94.46 v2(164.13,95.01)
  BOTTOM w0.254: v2(164.13,95.01) 164.79,95.67 PR4609.2 ; PR4606.1 139.83,61.42 v2(139.83,60.65)
PWR_VCCSA_CSP: length 65.1
  TOP w0.254: v1(140.28,58.64) 140.16,58.51 v2(140.16,57.98)
  L6 w0.254: v2(165.35,95.98) 165.02,95.65 165.02,94.27 160.22,89.47 160.22,85.01 158.62,83.41 158.62,76.88 156.74,75 156.74,71.79 157.52,71.01 159.39,71.01 160.86,69.54 160.86,67.67 155.55,62.37 141.04,62.37 140.77,62.09 140.77,59.76 140.05,59.05 140.05,58.08 v2(140.16,57.98)
  BOTTOM w0.254: v2(165.35,95.98) 165.48,96.1 165.48,97.27 PR4612.2 ; v2(140.16,57.98) 140.16,57.67 140.59,57.24 PG5021.1
PWR_VCCSA_CSP1B: length 7.5
  BOTTOM w0.203: 159.93,96.22 PU4601.40
  BOTTOM w0.254: v1(163.9,95.65) PR4609.1 163.9,97.53 PR4612.1 163.75,97.57 PC4607.2 162.49,97.57 PC4606.2 160.9,97.57 160.67,97.34 160.67,97.05 160.67,97.05 160.67,96.56 160.33,96.22 159.93,96.22
PWR_VCCSA_DRVH: length 14.8
  TOP w1.016: v3(145.46,61.56) 149.4,61.56 150.67,60.29 151.81,60.29 153.21,58.89 v1(153.21,57.52) 153.21,56.43 v3(151.97,55.19)
  BOTTOM w0.305: v3(151.97,55.19) 152.3,54.85 PU5001.8
  BOTTOM w0.406: PU5002.4 145.48,61.55 v3(145.46,61.56)
PWR_VCCSA_DRVL: length 4.5
  BOTTOM w0.305: PU5001.5 152.27,52.91 152.27,52.54 152.07,52.34 151.38,52.34
  BOTTOM w1.016: 151.38,52.34 v1(150.39,52.34) 149.68,52.34 148.65,53.37
PWR_VCCSA_ICCMAX: length 4.2
  TOP w0.254: v2(151.93,95.93) 151.98,95.98 152.45,95.98 153.13,96.66 PR4660.2
  BOTTOM w0.203: PU4601.20 152.04,95.82 v2(151.93,95.93)
  BOTTOM w0.254: v1(151.18,96) 151.85,96 v2(151.93,95.93)
PWR_VCCSA_ILIM: length 3.8
  TOP w0.254: PR4611.1 PC4632.1 160.66,95.27 v2(160.82,95.43) 161.22,95.43 v1(161.42,95.24)
  BOTTOM w0.203: PU4601.42 160.81,95.42 v2(160.82,95.43)
PWR_VCCSA_IOUT: length 3.6
  TOP w0.254: v1(162.69,97.29) 162.2,96.8 PC4609.1 PR4613.2 160.2,96.8 160.17,96.77 v2(160.16,96.77)
  BOTTOM w0.203: PU4601.39 160.01,96.62 v2(160.16,96.77)
PWR_VCCSA_PWM: length 59.6
  L6 w0.254: v2(154.86,56.07) 155.09,56.07 156.89,57.88 156.89,61.53 158.91,63.54 160.02,63.54 163.29,66.82 163.29,70.98 164.46,72.15 164.46,80.79 162.58,82.67 162.58,88.43 166.55,92.4 166.55,95.57 165.63,96.49 164.92,96.49 164.06,97.35 160.86,97.35 159.48,98.72 v2(159.43,98.72)
  BOTTOM w0.203: PU4601.36 158.99,98.07 159.43,98.52 v2(159.43,98.72)
  BOTTOM w0.254: PU5001.2 154.15,53.97 155.12,53.97 v1(155.32,54.17) 155.34,54.19 155.34,55.59 v2(154.86,56.07)
PWR_VCCSA_SNUB: length 3.1
  TOP w0.508: PC5031.1 148.19,58.14 148.46,58.41 v1(148.46,58.74) 147.53,58.74 147.17,58.38 PR5014.2
PWR_VCCSA_SW: length 10.6
  TOP w0.508: v3(144.5,57.8) PR5014.1 145.49,57.52 146.47,56.54 147.84,56.54 148.39,56 149.66,56 v1(150.29,55.36) v3(151.46,54.19)
  BOTTOM w0.305: PU5001.7 151.92,53.94 151.66,54.19 v3(151.46,54.19)
  BOTTOM w0.508: PC5008.2 v3(151.46,54.19)
PWR_VCCSA_VSN: length 3.6
  BOTTOM w0.203: PU4601.44 160.08,94.62 160.38,94.32
  BOTTOM w0.254: PC4603.2 161.84,93.52 161.84,93.99 PR4605.2 161.22,94.2 161.1,94.07 v1(160.72,94.07) 160.63,94.07 160.38,94.32
PWR_VCCSA_VSN_R: length 4.7
  BOTTOM w0.254: v1(165.18,94.66) 164.62,94.66 164.2,94.24 PR4604.2 163.93,93.91 163.5,93.91 PC4605.2 162.9,93.31 PC4603.1 PR4605.1
PWR_VCCSA_VSP: length 5.1
  BOTTOM w0.203: PU4601.45 159.93,94.22 160.19,93.95
  BOTTOM w0.254: 160.19,93.95 160.53,93.61 160.81,93.61 161.09,93.34 161.09,92.99 PR4608.2 161.62,92.38 161.64,92.37 PC4608.2 161.64,90.71 v1(161.54,90.62)
PWR_VCCSA_VSP_R: length 3.9
  BOTTOM w0.254: v1(164.06,90.95) 164.34,91.23 PR4616.1 164.2,92.09 PR4607.2 164.07,92.89 PC4605.1 162.93,92.45 PR4608.1
PWR_VCCSA_VSP_RC: length 2.1
  BOTTOM w0.254: v1(162.77,90.68) 162.52,90.93 PC4608.1 163.12,91.61 PR4616.2
PWR_VCORE_ADDR_BOOT: length 4.1
  TOP w0.254: v1(151.13,97.12) 151.64,97.12 152.17,96.59 v2(152.17,96.54) 152.64,97.01 PR4663.2
  BOTTOM w0.203: PU4601.21 153.01,96.22 152.85,96.38 152.53,96.38 152.37,96.54 v2(152.17,96.54)
PWR_VCORE_ALERT#: length 3.3
  BOTTOM w0.114: PU4601.33 157.49,98.5 158.57,99.58 158.98,99.58 159.57,100.18 PR4666.2
PWR_VCORE_BOOT: length 2.6
  BOTTOM w0.203: 156.01,65.12 155.65,65.48 PU4701.35
  BOTTOM w0.508: 156.01,65.12 v1(156.11,65.02) 156.46,64.66 PR4701.1
PWR_VCORE_BOOT_RC: length 2.6
  BOTTOM w0.254: PR4701.2 158.8,64.33 v1(159.51,64.33)
  BOTTOM w0.508: PR4701.2 PC4706.1
PWR_VCORE_COMP: length 4.2
  TOP w0.254: v1(153.06,100.78) 153.38,100.78 PC4601.1 154.02,99.46 v2(154.33,99.15) 154.34,99.14 PC4619.1
  BOTTOM w0.203: v2(154.33,99.15) 154.33,98.85 154.69,98.49 PU4601.26
PWR_VCORE_COMP_R: length 4.3
  TOP w0.254: PC4601.2 154.84,101.02 155.09,100.77 v1(155.09,100.73) 155.09,100.42 156.13,99.38 156.41,99.38 156.66,99.13 156.67,99.13 156.87,98.92 PR4636.1
PWR_VCORE_CSN: length 62.1
  L3 w0.254: v2(145.51,68.29) 145.51,70.45 147.75,72.69 147.75,75.4 151,78.66 151,85.32 150.12,86.2 148.11,86.2 146.53,87.78 146.53,94.14 147.78,95.39 147.78,104.28 149.35,105.86 v2(151.48,105.86)
  BOTTOM w0.203: PU4601.28 155.49,98.83 155.31,99 155.31,100.58 PC4634.2
  BOTTOM w0.254: PR4633.1 145.53,68.48 145.51,68.47 v2(145.51,68.29) 145.13,67.91 PG4708.1 ; v2(151.48,105.86) 153.34,105.86 154.89,104.31 v1(154.89,103.57) 154.89,102.78 155.75,101.92 PC4616.2 PC4634.2
PWR_VCORE_CSNNTC: length 49.3
  L3 w0.254: v2(150.7,106.54) 149.38,106.54 147.39,104.56 147.39,95.55 146.15,94.3 146.15,87.62 147.95,85.82 149.96,85.82 150.62,85.16 150.62,80.76 147.04,77.18 v2(147.04,72.74)
  BOTTOM w0.254: PR4629.2 155.55,103.03 155.55,104.33 v1(154.61,105.27) 153.36,106.52 150.72,106.52 v2(150.7,106.54) ; PR4633.2 146.42,72.36 146.8,72.74 v2(147.04,72.74)
PWR_VCORE_CSP: length 54.8
  TOP w0.254: v2(145.54,67.53) v1(146.23,67.53)
  L3 w0.254: v2(156.89,106.01) 152.5,106.01 151.61,105.12 149.17,105.12 148.16,104.11 148.16,95.23 146.91,93.99 146.91,87.94 148.27,86.58 150.28,86.58 151.38,85.47 151.38,78.48 148.16,75.25 148.16,72.53 146.02,70.4 146.02,68.01 v2(145.54,67.53)
  BOTTOM w0.254: PG4707.1 145.96,67.95 v2(145.54,67.53) ; PR4627.2 156.64,105.76 v2(156.89,106.01)
PWR_VCORE_CSP_1A: length 6.1
  BOTTOM w0.203: PU4601.29 155.89,98.99 155.74,99.14 v1(155.74,99.48) 155.74,100.12 PC4634.1
  BOTTOM w0.254: PR4627.1 156.73,103.61 PR4629.1 PC4616.1 PC4634.1
PWR_VCORE_DISB#: length 2.4
  BOTTOM w0.203: PU4701.2 153.68,63.11 PR4704.2
  BOTTOM w0.254: PR4704.2 153.11,62.54 v1(153.11,62.27)
PWR_VCORE_DRVON: length 78.8
  TOP w0.254: v2(158.79,98.8) 158.79,98.82 158.8,98.84 158.8,99.15 159.05,99.41 161.3,99.41 163.75,96.95 163.75,96.53 163.52,96.3 163.52,92.83 v1(163.15,92.45) 162.23,91.53 162.23,89.27 160.7,87.75 160.7,84.42 v1(159.42,83.13) 155.24,78.96 v2(155.24,78.45) 156.51,77.18 156.51,71.26 155.27,70.02 155.27,66.23 155.73,65.78 155.73,64.2 155.37,63.85 154.58,63.85 154.56,63.87 v2(154.52,63.87) 154.35,63.7 154.35,55.34 154.76,54.93 v2(154.76,53.44)
  L4 w0.254: v2(158.79,98.8) 158.77,98.8 158.74,98.77 155.01,98.77 154.63,98.39 151.94,98.39 151.31,97.76 151.31,97.37 145.21,91.28 144.58,91.28 v2(144.19,90.9)
  BOTTOM w0.203: PU4601.35 158.29,98.46 158.63,98.8 v2(158.79,98.8)
  BOTTOM w0.254: PR4704.1 154.54,63.78 154.52,63.8 v2(154.52,63.87) ; PR4809.1 144.41,90.3 144.19,90.52 v2(144.19,90.9) ; v2(155.24,78.45) 154.86,78.07 PR4808.1 ; v2(154.76,53.44) PU5001.3
PWR_VCORE_EN: length 3.6
  BOTTOM w0.127: PU4601.37 159.56,97.42 160.5,98.35 160.57,98.35 160.83,98.62 160.83,98.98 v1(160.83,99.18) 161.19,99.53 PR4630.1
PWR_VCORE_ICCMAX: length 4.2
  TOP w0.254: PR4658.2 153.2,95.84 152.7,95.34 v1(152.37,95.34) 151.69,95.34 151.63,95.4 v2(151.45,95.4)
  BOTTOM w0.203: PU4601.19 151.48,95.42 v2(151.45,95.4)
PWR_VCORE_ILIM: length 4.4
  TOP w0.254: v2(154.74,99.84) 154.97,99.84 155.23,99.58 v1(155.23,99.48) PC4633.1 155.23,98.48 PR4635.1
  BOTTOM w0.203: v2(154.74,99.84) 154.89,99.69 154.89,98.87 155.09,98.67 PU4601.27
PWR_VCORE_IOUT: length 5.3
  TOP w0.254: v2(156.34,99.94) 156.46,99.94 v1(156.84,99.56) 157.71,98.7 PC4613.1 PR4628.1
  BOTTOM w0.203: v2(156.34,99.94) 156.29,99.89 PU4601.30
PWR_VCORE_NTC: length 34.9
  TOP w0.254: v2(150.8,72.48) v1(150.8,73.04)
  L6 w0.254: v2(150.8,72.48) 150.8,72.7 157.05,78.95 157.05,87.04 156.87,87.22 156.87,91.94 154.23,94.58 154.23,96.06 152.2,98.09 151.19,98.09 v2(150.66,97.55)
  BOTTOM w0.254: v2(150.8,72.48) 150.8,72.18 151.18,71.8 PR4653.2 ; PR4652.1 PR4650.1 v2(150.66,97.55)
PWR_VCORE_PHASED:
  vias: v1(156.11,66.34)
PWR_VCORE_PWM: length 44.7
  TOP w0.254: v1(153.13,63.19) v2(153.13,63.75)
  L6 w0.254: v2(151.43,96.61) 151.86,97.04 152.38,97.04 153.72,95.71 153.72,94.35 156.26,91.81 156.26,88.82 155.78,88.33 155.78,86.83 156.51,86.09 156.51,80.44 153.82,77.75 153.82,77.74 150.29,74.21 150.29,72.27 150.67,71.89 150.67,65.6 151.56,64.71 152.42,64.71 153.13,64 v2(153.13,63.75)
  BOTTOM w0.203: PU4601.22 153.08,96.62 152.79,96.9 152.67,96.9 152.47,97.1 151.92,97.1 v2(151.43,96.61) ; PU4701.4 152.88,64 v2(153.13,63.75)
PWR_VCORE_ROSC_COREGT: length 2.4
  TOP w0.254: v1(152.2,92.7) 152.21,92.7 v2(152.71,93.2) 152.79,93.29 PR4664.1
  BOTTOM w0.203: v2(152.71,93.2) 152.92,93.42 PU4601.14
PWR_VCORE_ROSC_SAUS: length 3.8
  TOP w0.254: PR4659.1 152.45,94.17 v1(152.27,93.99) 152.04,93.77 v2(152.04,93.29)
  BOTTOM w0.203: v2(152.04,93.29) 152.53,93.77 152.98,93.77 153.02,93.82 PU4601.15
PWR_VCORE_SCLK: length 3.8
  BOTTOM w0.114: PU4601.34 157.89,98.5 158.35,98.96 158.35,98.99 158.6,99.24 v1(159.21,99.24) 159.64,99.24 160.5,100.11 PR4665.2
PWR_VCORE_SDIO: length 2.9
  BOTTOM w0.114: PU4601.32 157.09,98.62 v1(157.65,99.18) 157.98,99.51 158.13,99.51 PR4667.2
PWR_VCORE_SNUB: length 1.3
  BOTTOM w0.508: PC4709.1 146.67,62.96 PR4703.2
PWR_VCORE_TSENSE: length 4.4
  TOP w0.254: v2(151.99,97.58) 151.71,97.86 v1(151.71,98.26) 151.76,98.31 PC4628.1
  BOTTOM w0.203: v2(151.99,97.58) 152.64,97.58 153.2,97.02 PU4601.23
  BOTTOM w0.254: v2(151.99,97.58) 151.99,97.77 PR4650.2
PWR_VCORE_VCC: length 2.4
  BOTTOM w0.203: PU4701.6 152.08,64.27 151.84,64.02 151.84,63.4 PR4702.1
  BOTTOM w0.508: PC4708.1 PR4702.1
PWR_VCORE_VCC_R: length 3.9
  TOP w0.254: v2(152.71,92.4) 152.86,92.25 153.21,92.25 PC4631.1
  BOTTOM w0.203: PU4601.13 153.46,93.02 152.84,92.4 v2(152.71,92.4)
  BOTTOM w0.254: PR4657.2 150.87,92.68 v1(151.79,92.68) 151.89,92.58 152.53,92.58 v2(152.71,92.4)
PWR_VCORE_VR_RDY: length 3.1
  BOTTOM w0.203: PU4601.38 159.71,97.02 159.98,97.29
  BOTTOM w0.254: PR4670.1 161.31,98.64 160.7,98.04 v1(160.58,97.91) 160.58,97.88 159.98,97.29
PWR_VCORE_VRHOT#: length 3.2
  BOTTOM w0.203: PU4601.31 156.69,99.58 156.89,99.78 156.89,100.11 v1(156.97,100.19)
  BOTTOM w0.254: PR4668.1 157.77,100.19 v1(156.97,100.19)
PWR_VCORE_VRMP: length 4.5
  TOP w0.254: PC4629.1 152.53,91.57 v2(152.44,91.66)
  BOTTOM w0.254: PU4601.12 153.67,92.36 153.18,91.86 152.64,91.86 v2(152.44,91.66) 152.38,91.61 PR4601.2 151.77,90.9 v1(151.99,90.68)
PWR_VCORE_VSN: length 3.3
  BOTTOM w0.203: PU4601.25 153.91,98.07 153.86,98.13
  BOTTOM w0.254: 153.86,98.13 153.69,98.29 v1(153.69,99.19) 153.69,100.07 PC4623.2 153.71,100.11 PR4644.1
PWR_VCORE_VSN_R: length 3.8
  BOTTOM w0.254: v1(154.63,100.98) PC4623.1 152.89,100.98 PR4644.2 152.88,101.6 PC4625.1 152,102.48 PR4645.2
PWR_VCORE_VSP: length 4.7
  BOTTOM w0.203: 153.38,97.95 153.63,97.69 PU4601.24
  BOTTOM w0.254: PR4649.1 PR4647.1 152.07,100.05 152.76,99.36 152.76,98.75 152.5,98.49 v1(152.5,98.29) 152.84,97.95 153.38,97.95
PWR_VCORE_VSP_R: length 4.1
  BOTTOM w0.254: PR4647.2 152.07,101.53 PC4625.2 151.77,101.87 PC4627.2 150.95,103.47 v1(151.1,103.62) 151.13,103.65 151.88,103.65 PR4648.2
PWR_VCORE_VSP_RC: length 2.5
  BOTTOM w0.254: PC4627.1 151.25,101.5 PR4649.2 151.22,100.99 150.24,100.02 v1(150.24,99.91)
Q6204_G: length 18.4
  TOP w0.254: R6510.2 140.26,17.11 139.63,16.49 v1(137.51,16.49) 136.63,16.49 135.76,17.36 135.76,19.14 v2(134.97,19.93) 134.97,20.34 135.35,20.71 135.35,22.16 134.91,22.6 133.17,22.6 v2(132.28,23.49)
  BOTTOM w0.254: v2(132.28,23.49) 132.51,23.26 133.45,23.26 133.78,22.93 Q6504.5 ; Q6504.2 133.78,20.2 134.22,19.75 134.8,19.75 v2(134.97,19.93)
Q6205_Q: length 3.6
  BOTTOM w0.381: Q6503.D 124.01,16.64 v1(124.43,17.06) 124.69,17.31 R6503.2
Q6502_D: length 3.2
  BOTTOM w0.381: Q6502.D 122.95,22.19 R6514.1 123.72,22.97 v1(123.47,23.22)
RESET_OUT#: length 123.8
  TOP w0.102: v2(145.79,10.96) v1(145.23,11.52) 145.01,11.75 145.01,13.83 145.54,14.37 145.54,14.37 145.77,14.6 145.77,15.61 145.27,16.11 144.05,16.11 143.64,16.53 143.64,16.91 144.45,17.72 144.45,19.25 144.2,19.5 v2(143.53,19.5) ; KBC24.73 184.17,39.44 v2(184.94,38.68)
  L4 w0.102: v2(103.36,18.94) 103.39,18.97 103.44,18.97 103.97,19.5 104.25,19.5 104.53,19.78 109.71,19.78 110.26,19.22 111.71,19.22 112.7,18.23 115.44,18.23 116.19,17.48 122,17.48 122.6,16.88 127.07,16.88 127.3,16.65 133.86,16.65 134.22,16.29 138.85,16.29 141.02,18.46 142.81,18.46 143.53,19.19 v2(143.53,19.5) ; v2(145.79,10.96) 145.95,10.81 150.06,10.81 151.15,11.9 152.27,11.9 155.5,15.13 157.73,15.13 158.57,15.97 163.04,15.97 163.73,16.65 166.71,16.65 167.73,17.67 169.82,17.67 170.33,17.16 171.12,17.16 172.11,18.15 174.55,18.15 176.11,19.71 176.11,20.41 176.53,20.83 177.43,20.83 177.75,20.51 181.43,20.51 183.64,22.73 183.64,24.71 183.06,25.3 183.06,28.03 182.98,28.1 182.98,28.78 183.01,28.8 183.01,29.44 183.21,29.64 183.21,37.09 183.69,37.57 183.69,38.12 184.22,38.65 184.91,38.65 v2(184.94,38.68)
  BOTTOM w0.102: Q2602.G 143.31,22.54 143.31,19.73 v2(143.53,19.5) ; R1706.1 103.36,18.36 v2(103.36,18.94) 103.36,19.4 EC1704.1
REXT: length 3.1
  TOP w0.102: U5701.18 21.65,68.8 21.22,69.23 v2(21.13,69.23) 20.5,69.87 v1(20.29,69.87)
  BOTTOM w0.102: v2(21.13,69.23) 20.95,69.05 R5710.1
RING2: length 4.9
  TOP w0.203: RN2901.3 16.74,18.58 16.94,18.38 16.94,17.7 17.19,17.45 18.44,17.45 18.66,17.67 18.71,17.67 18.74,17.7 19.09,17.7 19.11,17.71 HDA27.29
  vias: v1(15.24,17.09)
RING2_R: length 12.6
  L3 w1.016: v3(15.59,12.46) 14.81,12.46 13.28,10.94 5.55,10.94 HPMIC1.4
  vias: v1(15.14,13.02)
RSMRST_PWRGD#: length 8.1
  BOTTOM w0.127: v1(157.83,103.34) R4032.2 R4029.2 R4030.2 R4033.2 R4031.2 161.96,104.25 162.63,103.57 D4002.3
RSVD_F65: length 1.7
  TOP w0.102: TP612.1 122.71,73.09 v2(122.28,73.52)
  BOTTOM w0.102: CPU1.F65 122.6,73.2 v2(122.28,73.52)
RSVD_G65: length 1.2
  TOP w0.102: v2(122.25,72.56) 122.25,72.74 TP613.1
  BOTTOM w0.102: CPU1.G65 121.95,72.86 v2(122.25,72.56)
RSVD_TP_AK12: length 1.9
  TOP w0.102: TP606.1 110.13,42.13 v2(110.01,42.26)
  BOTTOM w0.102: v2(110.01,42.26) 110.59,42.84 CPU1.AK12
RSVD_TP_AK13: length 1.3
  TOP w0.102: TP605.1 110.93,43.34 v2(111.06,43.34)
  BOTTOM w0.102: CPU1.AK13 110.59,43.65 110.9,43.34 v2(111.06,43.34)
RSVD_TP_AW70: length 5.2
  TOP w0.102: v2(101.93,77.77) 100.99,76.83 TP615.1
  BOTTOM w0.102: v2(101.93,77.77) 101.93,77.34 103.02,76.24 103.4,76.24 103.55,76.09 104.06,76.09 104.37,76.39 CPU1.AW70
RSVD_TP_AW71: length 3.1
  TOP w0.102: v2(104.49,75.89) 104.19,75.58 103.25,75.58 TP614.1
  BOTTOM w0.102: CPU1.AW71 105.05,76.44 v2(104.49,75.89)
RSVD_TP_BA68: length 5.9
  TOP w0.102: v2(101.09,77.69) 99.74,76.34 TP602.1
  BOTTOM w0.102: v2(101.09,77.69) 101.14,77.64 101.14,77.58 103.12,75.61 103.58,75.61 103.72,75.74 CPU1.BA68
RSVD_TP_BA70: length 1.9
  TOP w0.102: TP601.1 103.45,76.8 v2(103.1,77.16)
  BOTTOM w0.102: v2(103.1,77.16) 103.17,77.16 103.43,76.9 103.43,76.88 103.6,76.7 103.63,76.7 103.91,76.41 CPU1.BA70
RSVD_TP_BB68: length 5.5
  TOP w0.102: TP603.1 100.76,78.17 v2(100.76,78.25)
  BOTTOM w0.102: v2(100.76,78.25) 100.76,78.2 100.7,78.13 100.7,77.53 102.29,75.94 102.33,75.94 103.01,75.26 CPU1.BB68
RSVD_TP_BB69: length 6.7
  TOP w0.102: TP604.1 99.97,78.66 101.04,78.66 v2(101.47,78.22)
  BOTTOM w0.102: CPU1.BB69 103.08,75.91 101.5,77.5 101.5,77.84 101.47,77.87 v2(101.47,78.22)
RTC_AUX_S5: length 215.4
  TOP w0.406: R1730.1 96,22.42 95.53,22.42 v2(95.5,22.44)
  TOP w0.508: v2(73.81,19.09) 75.82,19.09 77.67,20.95 v2(84.99,20.95) ; v2(111.68,1.97) 110.95,1.24 105.84,1.24 105.64,1.44 86.05,1.44 85.14,2.35 85.14,6.72 83.69,8.17 74.47,8.17 v1(73.51,7.21) 72.03,5.73
  L3 w0.508: v2(192.58,37.25) 193.14,36.69 193.14,35.7 193.62,35.22 193.62,33.29 197.6,29.32 197.6,18.06 195.3,15.76 192.78,15.76 v2(191.87,14.85) ; v2(84.99,20.95) 87.17,20.95 88.09,20.03 92.1,20.03 92.76,20.69 93.43,20.69 95.15,22.42 95.48,22.42 v2(95.5,22.44)
  L4 w0.508: v2(70.38,3.98) 70.65,3.98 72.82,6.15 72.82,8.22 72.49,8.55 72.49,13 74.61,15.12 74.61,18.29 v2(73.81,19.09)
  L6 w0.508: v2(111.68,1.97) 111.68,2 111.78,2.1 111.78,2.71 111.77,2.72 111.77,5.7 114.19,8.12 118.39,8.12 119.68,6.82 120.8,6.82 120.98,7 121.66,7 123.59,8.93 126.87,8.93 127.48,9.54 128.18,9.54 128.38,9.74 132.57,9.74 132.75,9.57 134.86,9.57 135.25,9.17 135.25,8.2 135.74,7.72 135.74,7.21 137.75,5.2 143.18,5.2 144.45,3.93 152.73,3.93 156.79,7.99 181.23,7.99 182.62,9.39 189.48,9.39 191.23,11.14 191.23,14.22 v2(191.87,14.85)
  BOTTOM w0.508: R2472.2 192.7,37.25 v2(192.58,37.25) ; v2(70.38,3.98) 70.79,3.57 D2501.3
RTC_DET#: length 72.1
  TOP w0.102: v2(115.01,28.36) 115.24,28.36 115.57,28.03 115.57,27.65 115.21,27.3 112.89,27.3 111.86,28.33 111.86,28.95 111.58,29.23 111.22,29.23 110.97,28.97 110.97,28.9 109.56,27.49 109.36,27.49 108.81,26.94 107.97,26.94 107.44,26.41 107.44,25.19 107.14,24.88 105.74,24.88 105.63,24.78 101.01,24.78 100.14,25.65 v2(99.61,25.65)
  L3 w0.102: v2(99.61,25.65) 99.46,25.5 99.46,21 99.16,20.69 97.05,20.69 94.98,18.62 91.1,18.62 90.9,18.81 87.7,18.81 86.69,19.83 82.12,19.83 81.43,19.14 78.61,19.14 77.39,17.92 v2(76.27,17.92)
  BOTTOM w0.102: Q2505.D 74.03,10.72 75.97,12.67 75.97,15.08 76.58,15.69 76.58,17.52 76.27,17.82 v2(76.27,17.92) ; CPU1.P1 118.43,36.1 118.62,35.9 118.62,34.06 117.5,32.94 117.5,29.4 v1(117.32,29.23) 116.76,28.67 115.39,28.67 115.09,28.36 v2(115.01,28.36) 114.36,28.36 R2040.2
RTC_RST#: length 93.8
  TOP w0.127: RN1801.3 69.58,5.6 EC1807.1 69.05,5.88 68.07,5.88 v1(67.73,6.23) 67.38,6.57 v2(67.38,6.77)
  L3 w0.127: v2(65.15,16.37) 65.68,16.91 77.34,16.91 78.92,18.48 81.74,18.48 82.42,19.17 86.36,19.17 87.37,18.15 90.52,18.15 90.7,17.97 97.7,17.97 98.44,18.71 98.44,19.19 98.83,19.59 99.27,19.59 100.11,20.43 100.11,24.31 100.66,24.86 100.66,26.37 99.96,27.07 99.96,30.9 101.81,32.76 102.69,32.76 104.13,34.2 104.13,44.15 105.39,45.41 108.92,45.41 v2(109.33,45)
  L4 w0.127: v2(65.15,16.37) 64.78,16.01 64.78,15.88 64.3,15.4 64.17,15.4 63.42,14.65 63.42,7.71 63.04,7.33 63.04,6.57 v2(64.18,5.43)
  BOTTOM w0.127: CPU1.AM16 109.65,45.32 v2(109.33,45) ; v2(64.18,5.43) 64.76,4.86 Q1802.D 65.29,4.66 66.89,4.66 C1806.1 67.49,4.45 G1801.2 67.21,5.81 67.21,6.6 v2(67.38,6.77)
RTC_X1: length 36.2
  TOP w0.089: v1(99.36,23.44) 99.24,23.31 v2(98.75,23.31)
  L4 w0.127: v2(98.75,23.31) 98.14,23.31 97.61,23.83 97.61,29.53 97.01,30.13 97.01,32.36 99.79,35.14 99.79,36.44 103.38,40.02 103.38,42.56 104.27,43.45 104.27,44.68 105.91,46.32 108.92,46.32 v2(109.33,45.91)
  BOTTOM w0.089: v2(109.33,45.91) 109.65,46.24 CPU1.AM18 ; v2(98.75,23.31) 98.77,23.3 R1815.1 99.81,23.3 100.14,22.97 C1804.2 100.44,22.97 101.06,23.58 X1802.1
RTC_X2: length 38.8
  TOP w0.089: v1(99.62,22.22) 99.62,22.37 99.31,22.67 v2(98.75,22.67)
  L4 w0.127: v2(98.75,22.67) 98.05,22.67 97.09,23.64 97.09,29.32 96.51,29.9 96.51,32.58 99.34,35.41 99.34,36.69 102.92,40.28 102.92,42.66 103.81,43.55 103.81,44.95 105.61,46.75 105.92,46.75 106.45,47.29 108.56,47.29 108.68,47.41 v2(108.68,47.72)
  BOTTOM w0.089: v2(98.75,22.67) 99.02,22.41 R1815.2 99.54,22.41 99.79,22.15 C1803.2 100.52,22.15 101.09,22.73 X1802.4 ; v2(108.68,47.72) 109.35,47.72 109.65,47.42 CPU1.AM20
RTCRST_ON: length 187.5
  TOP w0.127: v2(66.47,3.95) v1(66.47,4.51) ; KBC24.31 197.98,42.24 197.69,42.54 197.38,42.54 v2(197.05,42.87)
  L3 w0.127: v2(197.05,42.87) 197.39,42.52 197.66,42.52 198.25,41.94 198.25,39.75 199.15,38.85 199.15,36.53 199.58,36.09 199.58,33.43 199.84,33.16 200.47,33.16 201.14,32.5 201.14,17.01 193.62,9.49 192.07,9.49 189.79,7.2 174.75,7.2 174.24,6.7 157.5,6.7 155.88,5.07 155.88,2.87 154.67,1.67 129.34,1.67 128.89,1.22 122.08,1.22 119.48,3.82 119.48,5.08 117.27,7.29 112.77,7.29 110.55,5.08 110.55,3.61 v2(111.12,3.04)
  L4 w0.127: v2(111.12,3.04) 111.24,3.04 112.13,2.16 112.13,1.79 111.78,1.44 110.92,1.44 110.74,1.26 104.04,1.26 103.81,1.49 74.85,1.49 74.17,2.18 70.18,2.18 69.82,2.53 67.89,2.53 v2(66.47,3.95)
  BOTTOM w0.127: Q1802.G 66.55,2.48 R1816.1 EC1808.1 67.11,3.37 66.62,3.85 66.57,3.85 v2(66.47,3.95)
SA0_CHA_DIM0: length 5.7
  TOP w0.102: v1(67.44,20.74) 67.18,20.74 v2(66.39,21.53) 67.09,22.23 R1205.1 R1204.1
  BOTTOM w0.102: v2(66.39,21.53) 66.39,21.53 66.19,21.73 DM1.256
SA0_CHB_DIM0: length 5.5
  TOP w0.102: v1(53.64,21.58) 53.87,21.58 v2(54.15,21.86) 54.39,22.1 R1302.1 R1303.1
  BOTTOM w0.102: v2(54.15,21.86) 54.08,21.94 DM2.256
SA1_CHA_DIM0: length 9.6
  TOP w0.102: R1210.1 67.28,20.08 67.84,20.64 69.24,20.64 v1(69.31,20.72) 69.31,20.92 69.16,21.08 68.09,21.08 67.93,21.24 R1208.1 67.13,21.63 v2(67.03,21.53)
  BOTTOM w0.102: v2(67.03,21.53) 67.03,21.23 66.27,20.46 65.48,20.46 65.21,20.73 DM1.260
SA1_CHB_DIM0: length 10.8
  TOP w0.102: v2(49.45,24.38) 49.76,24.68 v1(52.63,24.68) 53.92,24.68 54.49,24.11 R1307.1 54.52,24.07 R1306.1
  BOTTOM w0.102: v2(49.45,24.38) 49.83,23.99 49.83,21.2 50.1,20.94 DM2.260
SA2_CHA_DIM0: length 5.7
  TOP w0.102: v2(62.18,45.09) 62.75,44.52 R1211.1 62.74,44.33 62.74,43.81 v1(63.12,43.43) 63.37,43.43 63.59,43.64 R1212.1
  BOTTOM w0.102: DM1.166 62.95,44.23 62.18,45 v2(62.18,45.09)
SA2_CHB_DIM0: length 4.2
  TOP w0.102: v2(49.45,44.67) 49.25,44.67 v1(48.87,45.05) 49.31,45.5 R1311.1 48.47,45.94 R1310.1
  BOTTOM w0.102: v2(49.45,44.67) 49.69,44.44 DM2.166
SATA_ACT#: length 65.6
  TOP w0.127: v2(122.43,34.59) 122.71,34.31 v1(122.99,34.31) 124.36,34.31 125.12,35.07 126.48,35.07 126.87,35.46 126.87,35.87 127.66,36.66 130.66,36.66 133.48,33.84 133.48,31.54 134.67,30.34 134.67,28.85 v2(134.49,28.67)
  L6 w0.127: v2(134.49,28.67) 138,28.67 140.1,30.78 149.66,30.78 150.57,31.69 159.79,31.69 160.83,32.73 163.07,32.73 163.37,33.03 v2(163.47,33.03)
  BOTTOM w0.127: CPU1.H1 121.74,35.65 122.02,35.37 122.02,34.99 v2(122.43,34.59) 122.83,34.18 122.83,33.72 121.84,32.73 121.84,32.25 121.66,32.07 121.66,30.4 121.11,29.84 121.11,28.22 R1606.2 ; Q6105.S 163.36,29.29 164.49,30.42 164.49,32.01 v2(163.47,33.03)
SATA_LED#: length 97.2
  TOP w0.127: v2(165.98,28.01) 165.7,28.29 v1(165.4,28.29) ; R4302.2 178.48,93.63 v2(178.48,93.06) ; KBC24.69 183.99,41.04 v2(184.68,40.35)
  L4 w0.127: v2(165.98,28.01) 167.28,29.31 167.28,29.44 170.94,33.1 170.94,37.38 173.51,39.95 173.51,42.91 174.19,43.59 174.19,49.8 175.56,51.17 175.56,53.07 176.53,54.04 178.05,54.04 v2(178.31,53.79)
  BOTTOM w0.127: v2(184.68,40.35) 184.09,40.35 182.22,42.22 181.97,42.22 181.33,42.87 181.33,43.87 181.85,44.39 181.85,45.43 180.22,47.06 180.22,48.34 178.73,49.84 178.73,53.37 v2(178.31,53.79) 178.09,54 178.09,60.82 175.32,63.58 175.32,68.98 178.85,72.51 178.85,84.15 179.18,84.48 179.18,92.36 v2(178.48,93.06) ; Q6105.G 165.28,28.67 R6120.2 165.98,28.66 v2(165.98,28.01)
SATA_RX_CPU_N0: length 78.1
  TOP w0.102: v2(168.93,15.98) 169.14,15.78 169.14,15.29 169.32,15.11 ; C6006.1 171.04,14.75 169.68,14.75 169.32,15.11 ; 169.32,15.11 v1(169.21,15)
  L6 w0.127: v2(168.93,15.98) 169.33,16.38 169.33,16.96 169.05,17.24 152.84,17.24 151.26,18.83 149.27,18.83 148.58,19.51 144.72,19.51 139.5,24.73 136.74,24.73 133.95,27.52 133.95,27.82 133.28,28.48 133.28,30.15 137.34,34.21 137.34,36.41 136.83,36.92 136.19,36.92 135.09,38.03 135.09,42.98 133.59,44.48 131.13,44.48 129.74,45.87 125.47,45.87 124.65,46.69 123.77,46.69 123.26,47.2 123.26,47.35 123.24,47.48 v2(122.91,47.74)
  BOTTOM w0.102: v2(122.91,47.74) 122.87,47.7 122.87,47.6 122.55,47.29 CPU1.F20
SATA_RX_CPU_N1: length 106
  TOP w0.102: 166.98,22.06 167.44,22.06 169.58,24.2 175.79,24.2 176.27,23.71 179.02,23.71 180.52,22.22 182.57,22.22 186.43,26.08 190.9,26.08 193.23,23.75 195.16,23.75 195.88,24.48 197.05,24.48 197.41,24.12 197.41,23.83 C6309.2 ; 166.98,22.06 v1(166.98,22.22) ; 166.98,22.06 165.76,22.06 164.87,21.17 164.87,20.24 165,20.12 v2(165,19.83)
  L3 w0.14: v2(122.27,47.74) 122.69,48.16 123.28,48.16 123.72,48.61 126.64,48.61 127.83,49.8 128.78,49.8 130.11,48.47 130.11,47.97 131.53,46.55 134.49,46.55 135.58,45.46 135.58,39.93 134.87,39.22 134.87,33.91 136.12,32.66 136.12,31.12 136.89,30.34 137.23,30.01 137.6,29.63 137.6,29.63 138.36,28.87 138.99,28.87 139.84,28.01 140.48,28.01 141.52,26.98 145.76,26.98 146.83,25.91 150.23,25.91 151.6,24.54 161.11,24.54 164.77,20.89 164.77,20.41 165,20.18 v2(165,19.83)
  BOTTOM w0.102: CPU1.G21 122.27,47.82 v2(122.27,47.74)
SATA_RX_CPU_N1_C: length 7
  TOP w0.102: 197.02,21.2 197.38,21.56 197.38,22.31 C6309.1 ; 197.02,21.2 196.89,21.07 196.34,21.07 196.21,20.94 ED6301.4 ED6301.7 194.29,20.94 194.21,21.02 193.47,21.02 v2(193.44,21.05) ; 197.02,21.2 v1(197.13,21.1)
  BOTTOM w0.102: v2(193.44,21.05) 193.88,21.05 193.98,20.94 SSD1.43
SATA_RX_CPU_P0: length 77.8
  TOP w0.102: 170.48,14.98 169.77,14.98 169.37,15.38 169.37,15.76 v2(169.59,15.99) ; 170.48,14.98 171.07,14.98 C6005.1 ; 170.48,14.98 v1(170.48,15.1)
  L6 w0.127: v2(123.77,47.84) 123.51,47.51 123.52,47.44 123.53,47.37 123.53,47.31 123.88,46.96 124.76,46.96 125.58,46.14 129.85,46.14 131.24,44.75 133.7,44.75 135.35,43.1 135.35,38.14 136.3,37.19 136.94,37.19 137.6,36.53 137.6,34.09 133.55,30.04 133.55,28.59 134.21,27.93 134.21,27.63 136.85,25 139.61,25 144.83,19.77 148.69,19.77 149.38,19.09 151.37,19.09 152.95,17.5 169.16,17.5 169.59,17.07 v2(169.59,15.99)
  BOTTOM w0.102: CPU1.E20 123.19,47.47 123.57,47.84 v2(123.77,47.84)
SATA_RX_CPU_P1: length 105.7
  TOP w0.102: 165.39,21.37 165.1,21.08 165.1,20.34 165.33,20.11 v2(165.61,20.11) ; 165.39,21.37 165.85,21.84 167.54,21.84 169.67,23.97 175.7,23.97 176.18,23.49 178.92,23.49 180.42,21.99 182.67,21.99 186.53,25.85 190.81,25.85 193.13,23.52 195.25,23.52 195.98,24.25 196.96,24.25 197.18,24.03 197.18,23.88 C6301.2 ; 165.39,21.37 v1(165.48,21.28)
  L3 w0.14: v2(122.3,48.66) 122.53,48.43 123.17,48.43 123.61,48.87 126.53,48.87 127.72,50.07 128.89,50.07 130.38,48.58 130.38,48.08 131.64,46.82 134.6,46.82 135.85,45.57 135.85,39.82 135.14,39.11 135.14,34.02 136.38,32.77 136.38,31.23 137.08,30.53 137.41,30.2 137.87,29.74 138.47,29.14 139.1,29.14 139.96,28.28 140.59,28.28 141.63,27.25 145.87,27.25 146.94,26.18 150.34,26.18 151.71,24.81 161.22,24.81 165.03,21 165.03,20.52 165.45,20.11 v2(165.61,20.11)
  BOTTOM w0.102: CPU1.F21 122.3,48.2 122.2,48.3 122.2,48.56 v2(122.3,48.66)
SATA_RX_CPU_P1_C: length 8.1
  TOP w0.102: v1(195.93,23.11) 196.4,22.64 C6301.1 197.15,22.31 197.15,21.66 196.8,21.3 196.34,21.3 196.2,21.44 ED6301.5 ED6301.6 194.32,21.44 194.13,21.25 193.85,21.25 193.62,21.48 193.62,21.48 193.42,21.68 v2(193.32,21.68)
  BOTTOM w0.102: v2(193.32,21.68) 193.42,21.68 193.66,21.44 SSD1.41
SATA_RXN0_R: length 9.2
  TOP w0.102: C6006.2 172.55,14.4 172.72,14.57 173.35,14.57 173.47,14.46 U6001.7 U6001.4 175.46,14.46 175.58,14.58 176.14,14.58 176.5,14.22 176.5,13.83 v2(176.3,13.63)
  BOTTOM w0.102: HDD1.18 177.48,16.08 177.34,15.94 177.01,15.94 176.38,15.32 176.38,14.47 176.5,14.35 176.5,13.83 v2(176.3,13.63)
SATA_RXP0_R: length 9.5
  TOP w0.102: v2(176.94,13.6) 176.73,13.81 176.73,14.31 176.5,14.54 ; v1(176.6,14.65) 176.5,14.54 ; 176.5,14.54 176.23,14.81 175.58,14.81 175.46,14.94 U6001.5 U6001.6 173.46,14.94 173.33,14.8 172.77,14.8 C6005.2
  BOTTOM w0.102: HDD1.19 177.48,15.58 177.34,15.72 177.11,15.72 176.61,15.22 176.61,14.56 176.73,14.44 176.73,13.81 v2(176.94,13.6)
SATA_TX_CPU_N0: length 73.7
  TOP w0.102: 169.57,13.18 168.85,13.18 167.97,14.06 167.97,15.79 v2(168.2,16.02) ; 169.57,13.18 171.05,13.18 C6003.1 ; 169.57,13.18 v1(169.57,13.33)
  L3 w0.14: v2(127.56,47.64) 127.73,47.47 127.73,46.27 129.56,44.44 129.56,32.79 131.62,30.73 131.62,27.02 133.04,25.59 133.28,25.36 134.05,24.59 134.56,24.59 135.71,23.44 135.71,23.38 136.79,22.3 138.53,20.57 139.39,20.57 139.92,20.03 143.71,20.03 146.54,17.2 150.38,17.2 152.73,14.85 167.87,14.85 168.2,15.18 v2(168.2,16.02)
  BOTTOM w0.089: v2(127.56,47.64) 127.37,47.83 127.37,47.84 127.05,48.16 125.58,48.16 CPU1.B21
SATA_TX_CPU_N1: length 105.6
  TOP w0.102: v2(164.31,20.13) 164.08,20.13 163.85,20.36 163.85,20.82 ; C6303.2 199.01,23.83 199.01,24.1 198.51,24.6 197.61,24.6 197.2,25.01 195.55,25.01 194.78,24.25 193.42,24.25 191.1,26.56 186.23,26.56 182.37,22.7 180.73,22.7 179.23,24.2 176.48,24.2 175.99,24.68 169.26,24.68 167.41,22.83 165.35,22.83 163.85,21.33 163.85,20.82 ; 163.85,20.82 v1(163.98,20.82)
  L3 w0.14: v2(164.31,20.13) 164.11,20.13 163.35,20.9 163.35,21.4 161.21,23.54 154.28,23.54 153.52,22.78 150.01,22.78 147.67,25.11 144.72,25.11 144.37,25.47 142.11,25.47 140.61,26.96 139.37,26.96 138.88,27.46 138.62,27.46 137.96,28.12 137.96,28.12 137.62,28.46 137.62,28.88 137.39,29.11 136.86,29.64 135.6,30.9 135.6,32.45 134.35,33.69 134.35,39.44 135.06,40.15 135.06,45.14 134.19,46.02 131.33,46.02 129.59,47.75 129.59,48.07 129.26,48.4 128.27,48.4 v2(127.96,48.71)
  BOTTOM w0.089: v2(127.96,48.71) 127.48,49.19 127.02,49.19 126.76,48.93 125.81,48.93 125.8,48.93 125.79,48.93 125.67,48.87 125.52,48.87 125.39,48.93 125.14,48.93 125.02,48.87 124.35,48.87 CPU1.D21
SATA_TX_CPU_N1_C: length 9.3
  TOP w0.102: v2(193.37,19.74) 193.47,19.64 193.97,19.64 194.27,19.94 ED6301.9 ED6301.2 195.88,19.94 196.04,19.78 196.77,19.78 198.56,21.57 ; 198.56,21.57 199.03,22.04 199.03,22.31 C6303.1 ; 198.56,21.57 v1(198.45,21.68)
  BOTTOM w0.102: SSD1.47 194.04,19.94 193.77,19.68 193.43,19.68 v2(193.37,19.74)
SATA_TX_CPU_P0: length 73.6
  TOP w0.102: 167.74,14.75 167.74,15.81 v2(167.54,16.02) ; 167.74,14.75 167.74,13.97 168.75,12.95 171.05,12.95 C6001.1 ; 167.74,14.75 v1(167.61,14.75)
  L3 w0.14: v2(167.54,16.02) 167.93,15.62 167.93,15.29 167.76,15.12 152.84,15.12 150.49,17.47 146.65,17.47 143.82,20.3 140.03,20.3 139.5,20.83 138.64,20.83 137.17,22.3 135.98,23.49 135.98,23.55 134.67,24.86 134.16,24.86 133.47,25.55 133.23,25.78 131.89,27.13 131.89,30.84 129.83,32.9 129.83,44.55 128,46.38 128,47.41 v2(128.22,47.63)
  BOTTOM w0.089: CPU1.A21 126.04,48.35 127.13,48.35 127.3,48.18 128.04,48.18 128.22,47.99 v2(128.22,47.63)
SATA_TX_CPU_P1: length 105.3
  TOP w0.102: v1(168.63,24.55) 168.72,24.46 ; 168.72,24.46 169.17,24.91 176.09,24.91 176.57,24.43 179.32,24.43 180.82,22.93 182.28,22.93 186,26.65 186.14,26.79 191.2,26.79 193.51,24.48 194.69,24.48 195.45,25.24 197.3,25.24 197.7,24.83 198.6,24.83 199.24,24.2 199.24,23.88 C6302.2 ; 168.72,24.46 167.31,23.05 165.25,23.05 163.63,21.43 163.63,20.27 163.78,20.12 v2(163.78,19.78)
  L3 w0.14: v2(127.33,48.71) 127.9,48.14 129.15,48.14 129.32,47.96 129.32,47.64 131.22,45.75 134.08,45.75 134.8,45.03 134.8,40.26 134.08,39.55 134.08,33.58 135.33,32.34 135.33,30.79 136.67,29.45 137.2,28.92 137.35,28.77 137.35,28.34 137.85,27.85 137.85,27.85 138.51,27.19 138.77,27.19 139.26,26.7 140.5,26.7 142,25.2 144.26,25.2 144.61,24.85 147.56,24.85 149.9,22.51 153.63,22.51 154.39,23.27 161.1,23.27 163.08,21.29 163.08,20.79 163.78,20.09 v2(163.78,19.78)
  BOTTOM w0.089: v2(127.33,48.71) 127.3,48.74 125.81,48.74 125.68,48.68 125.53,48.68 125.49,48.69 125.35,48.74 125.16,48.74 125.03,48.68 124.81,48.68 CPU1.C21
SATA_TX_CPU_P1_C: length 9.6
  TOP w0.102: 197.1,19.78 196.87,19.55 196.01,19.55 195.9,19.44 ED6301.1 ED6301.10 194.13,19.44 194.11,19.41 193.68,19.41 v2(193.37,19.1) ; 197.1,19.78 v1(197.2,19.68) ; 197.1,19.78 199.26,21.94 199.26,22.31 C6302.1
  BOTTOM w0.102: v2(193.37,19.1) 193.7,19.44 SSD1.49
SATA_TXN0_R: length 14.2
  TOP w0.102: 176.25,12.64 176.25,12.18 v2(176.55,11.87) ; 176.25,12.64 v1(176.38,12.64) ; 176.25,12.64 176.25,12.87 175.83,13.29 175.58,13.29 175.46,13.42 U6001.2 U6001.9 173.44,13.42 173.3,13.28 172.69,13.28 172.46,13.51 C6003.2
  BOTTOM w0.102: HDD1.16 177.41,17.08 177.32,16.98 175.73,16.98 175.67,16.92 175.67,16.91 174.95,16.2 174.95,13.78 176.27,12.46 176.27,12.15 v2(176.55,11.87)
SATA_TXP0_R: length 14.8
  TOP w0.102: v1(175.79,11.29) 175.79,11.84 v2(175.76,11.87) 176.02,12.13 176.02,12.77 175.73,13.06 175.58,13.06 175.46,12.94 U6001.1 U6001.10 173.46,12.94 173.35,13.05 172.7,13.05 C6001.2
  BOTTOM w0.102: HDD1.15 177.58,17.58 177.21,17.21 175.64,17.21 175.44,17.02 175.44,17.01 174.72,16.29 174.72,13.69 176.05,12.37 176.05,12.15 v2(175.76,11.87)
SD_RCOMP: length 2.1
  TOP w0.508: R1901.1 114.83,39.56 114.42,39.97 v2(114.2,39.97) 114.04,39.97 v1(113.71,40.3)
  BOTTOM w0.254: v2(114.2,39.97) 114.21,39.97 114.4,39.77 CPU1.AB7
SENSOR_I2C_SCL: length 182
  TOP w0.089: RN6901.4 42.67,36.98 42.22,37.43 v1(41.83,37.43) 40.89,37.43 39.57,36.11 v2(39.55,36.11) R6928.2
  L3 w0.127: v2(112.69,20.24) 112.69,20.24 112.34,19.89 112.34,18.69 111.92,18.27 108.04,18.27 107.94,18.36 107.21,18.36 106.73,17.88 106.73,17.42 105.76,16.45 102.51,16.45 102.17,16.11 86.42,16.11 85.8,16.73 79.75,16.73 77.07,14.05 71.05,14.05 70.84,14.27 65.91,14.27 65.66,14.52 63.04,14.52 61.52,16.04 53.3,16.04 51,18.34 46.21,18.34 36.5,28.06 36.5,31.36 39.42,34.28 39.42,34.3 39.44,34.33 39.44,36.01 v2(39.55,36.11) 40.26,36.82 40.88,36.82 42.01,37.95 42.01,42.56 42.16,42.71 42.16,44.24 43.24,45.32 43.24,53.57 43.62,53.95 43.62,62.06 43.03,62.65 43.03,78.91 45.49,81.37 45.49,88.48 46.86,89.86 46.86,89.9 48.66,91.7 54.7,91.7 55.46,90.94 58.34,90.94 58.53,90.75 59.36,90.75 v2(59.79,91.18)
  BOTTOM w0.089: v2(112.69,20.24) 112.69,20.28 112.7,20.29 112.7,20.34 113.54,21.18 115.37,21.18 115.74,21.55 115.74,22.2 115.88,22.34 116.22,22.34 RN7001.2 116.3,22.36 116.94,23 116.94,24.13 R2020.2 ; TCBD1.8 58.65,92.7 59.79,91.56 v2(59.79,91.18)
SENSOR_I2C_SCL_2G: length 113
  TOP w0.089: U7001.1 178.38,41.96 v2(178.56,41.77) ; v2(121.49,22.62) 121.54,22.57 v1(122.1,22.57)
  L3 w0.127: v2(121.49,22.62) 121.54,22.57 121.63,22.57 125.78,18.43 125.78,15.54 126.36,14.95 126.36,11.68 126.85,11.19 v2(126.85,11.17) ; v2(178.56,41.77) 179.09,41.24 179.09,41.15 179.56,40.68 179.56,38.26 179.65,38.17 179.65,37.16 181.21,35.59 181.21,33.68 181.8,33.1 181.8,33 182.32,32.48 182.32,30.24 182.8,29.76 182.8,25.8 184.02,24.58 184.02,23.21 183.41,22.6 183.41,21.69 181.35,19.63 181.35,18.3 182.98,16.67 182.98,15.14 182.32,14.47 182.32,11.12 v2(181.46,10.25)
  BOTTOM w0.089: v2(121.49,22.62) 121.49,23.28 121.21,23.56 119.61,23.56 119.45,23.71 118.57,23.71 117.44,22.59 RN7001.3 ; v2(126.85,11.17) 127.2,11.52 129.82,11.52 129.86,11.57 135.46,11.57 135.86,11.57 135.86,11.57 139.92,11.57 141.04,12.69 171.47,12.69 173,11.16 180.55,11.16 v2(181.46,10.25)
SENSOR_I2C_SCL_HUB: length 2.4
  TOP w0.089: U6901.42 39.41,33.08 39.83,33.49 v1(39.83,33.67) 39.83,34 39.55,34.28 R6928.1
SENSOR_I2C_SDA: length 184.6
  TOP w0.089: R6929.2 38.67,35.46 38.91,35.7 v2(38.91,36.19) v1(39.51,36.78) 40.66,37.94 42.59,37.94 42.9,37.63 RN6901.3
  L3 w0.127: v2(112.89,19.6) 112.89,19.56 112.72,19.4 112.72,18.53 112.55,18.35 112.55,18.34 112.09,17.89 112.08,17.89 107.86,17.89 107.77,17.98 107.36,17.98 107.11,17.73 107.11,17.26 105.9,16.04 103.5,16.04 103.19,15.73 86.24,15.73 85.62,16.35 79.93,16.35 77.25,13.67 70.88,13.67 70.67,13.87 67.02,13.87 66.56,13.42 64.91,13.42 64.34,13.99 62.94,13.99 61.26,15.66 53.14,15.66 50.84,17.96 46.04,17.96 36.12,27.88 36.12,31.54 39.04,34.46 39.04,36.06 v2(38.91,36.19) 39.93,37.2 40.72,37.2 41.63,38.11 41.63,42.71 41.78,42.87 41.78,52.67 43.24,54.13 43.24,61.88 42.64,62.48 42.64,79.29 45.11,81.75 45.11,88.66 46.48,90.03 46.48,90.06 48.5,92.08 54.87,92.08 55.64,91.32 58.5,91.32 58.59,91.23 v2(59.08,91.23)
  BOTTOM w0.089: v2(112.89,19.6) 112.9,19.62 112.9,19.84 113.12,20.06 113.12,20.07 113.13,20.08 113.13,20.33 113.72,20.91 115.56,20.91 116.24,21.59 RN7001.1 116.61,21.71 116.91,22.01 116.91,22.6 117.78,23.46 R2021.2 ; v2(59.08,91.23) 59.08,91.81 58.55,92.35 58.39,92.35 58.15,92.59 TCBD1.7
SENSOR_I2C_SDA_2G: length 117.1
  TOP w0.089: U7001.4 178.44,43.57 v2(178.98,44.12) ; v2(121.03,23.05) 121.03,23.05 120.62,23.46 v1(120.62,23.47)
  L3 w0.127: v2(121.03,23.05) 121.03,22.37 121.56,21.84 121.78,21.84 125.4,18.22 125.4,15.23 125.93,14.7 125.93,11.45 v2(126.21,11.17) ; v2(178.98,44.12) 179.14,43.96 179.14,41.73 179.47,41.4 179.47,41.31 179.94,40.84 179.94,38.43 180.03,38.35 180.03,37.33 181.6,35.77 181.6,33.84 182.18,33.25 182.18,33.16 182.7,32.64 182.7,30.4 183.18,29.92 183.18,25.98 184.4,24.76 184.4,23.03 183.79,22.42 183.79,21.53 181.74,19.47 181.74,18.46 183.36,16.83 183.36,14.98 182.7,14.32 182.7,10.86 v2(182.09,10.25)
  BOTTOM w0.089: v2(121.03,23.05) 121.03,23.05 120.88,23.21 119.58,23.21 119.38,23.4 118.64,23.4 117.96,22.72 117.96,21.89 117.77,21.71 117.44,21.71 RN7001.4 ; v2(182.09,10.25) 180.92,11.43 173.13,11.43 171.6,12.96 140.93,12.96 139.81,11.83 135.97,11.83 129.75,11.83 129.72,11.8 126.85,11.8 v2(126.21,11.17)
SENSOR_I2C_SDA_HUB: length 2.3
  TOP w0.089: U6901.43 38.92,33.03 38.57,33.38 v1(38.57,33.65) 38.57,34.48 R6929.1
SERIRQ: length 147.5
  TOP w0.089: R1821.2 96.9,23.04 v1(96.9,23.97) 98.07,25.14 v2(98.12,25.14) ; KBC24.55 188.41,43.47 187.95,43.01 187.95,42.39 187.81,42.24 v2(187.81,42.16)
  L3 w0.127: v2(100.3,41.34) 101.41,41.34 103.1,39.66 103.1,34.92 102.26,34.08 101.17,34.08 99.83,32.74 97.83,32.74 96.47,31.39 96.47,30.04 98.64,27.87 98.64,25.66 v2(98.12,25.14)
  L4 w0.127: v2(106.2,24.22) 106.2,24.09 109.33,20.96 110.2,20.96 110.75,20.4 111.68,20.4 112.22,20.93 112.22,20.93 112.37,21.08 113.56,21.08 115.04,19.6 118.03,19.6 118.97,18.66 124.21,18.66 124.74,18.13 127.53,18.13 127.81,17.85 135.33,17.85 135.96,18.48 139.11,18.48 142.05,21.43 145.34,21.43 146.63,22.72 146.68,22.72 147.78,23.82 150.02,23.82 152.67,26.47 161.07,26.47 161.34,26.74 161.34,26.75 161.54,26.95 164.52,26.95 165.48,27.91 165.48,29.04 166.46,30.01 167.31,30.01 169.25,31.95 169.25,34.73 170.29,35.77 170.29,39.32 169.92,39.69 169.69,39.69 169.28,40.1 169.28,42.88 v2(169.75,43.35)
  L6 w0.102: v2(169.75,43.35) 169.95,43.15 172,43.15 172.23,42.92 177.49,42.92 178.18,43.6 178.42,43.6 178.45,43.64 179.3,43.64 179.42,43.76 181.21,43.76 181.68,43.28 181.68,42.97 182.04,42.61 183.51,42.61 183.69,42.79 185.14,42.79 186.21,41.72 187.37,41.72 v2(187.81,42.16)
  BOTTOM w0.089: v2(106.2,24.22) 105.73,24.69 98.57,24.69 v2(98.12,25.14) ; CPU1.AY11 104.41,42.58 104.09,42.26 102.01,42.26 101.57,41.83 100.73,41.83 100.35,41.44 100.35,41.39 v2(100.3,41.34)
SIO_EXT_SCI#: length 93.9
  TOP w0.089: v2(182.12,41.01) 182.29,41.19 182.29,42.03 182.51,42.24 KBC24.66
  L4 w0.127: v2(166.75,41.85) 166.8,41.8 166.8,37.06 166.65,36.91 166.65,35.3 165.5,34.15 164.93,34.15 164.46,33.69 164.46,33.39 161.71,30.64 160.49,30.64 160.34,30.79 154.72,30.79 154.1,30.17 151.46,30.17 151.13,29.84 150.14,29.84 149.15,28.85 148.18,28.85 147.24,27.91 144.45,27.91 143.97,27.42 142.19,27.42 142.17,27.41 142.15,27.41 138.99,24.25 138.37,24.25 138.36,24.26 137.99,24.26 137.98,24.25 137.54,24.25 137.4,24.39 133.33,24.39 133.13,24.59 132.93,24.79 126.1,24.79 124.8,23.5 122.5,23.5 121.46,24.54 121.46,27.8 v2(120.14,29.13)
  L6 w0.102: v2(182.12,41.01) 182.12,40.66 181.43,39.97 180.11,39.97 179.75,40.33 179.75,41.95 179.22,42.49 178.38,42.49 178.1,42.21 172.26,42.21 171.93,41.88 166.77,41.88 v2(166.75,41.85)
  BOTTOM w0.089: CPU1.J2 121.21,36.96 121.21,36.7 121.3,36.6 121.35,36.45 121.35,35.38 121.61,35.12 121.61,34.41 121.77,34.26 121.77,33.29 121.61,33.14 121.61,32.3 121.26,31.94 v1(121.26,31.16) 121.26,30.55 120.72,30.01 120.72,29.58 120.27,29.13 v2(120.14,29.13) 120.6,28.67 R1608.2
SIO_EXT_SMI#: length 143.4
  TOP w0.102: v1(125.3,10.25) 125.53,10.02 v2(125.53,9.69) ; KBC24.10 198.05,33.84 197.94,33.95 197.2,33.95 v2(196.98,34.18)
  L3 w0.102: v2(125.53,9.69) 125.3,9.92 125.3,10.58 124.86,11.01 124.86,14.27 124.31,14.82 124.31,17.14 123.7,17.75 122.99,17.75 121.44,19.3 121.44,19.73 119.91,21.26 119.91,25.88 119.84,25.95 119.84,28.19 v2(120.14,28.49)
  L4 w0.102: v2(196.98,34.18) 197.2,33.95 197.89,33.95 198.37,33.47 198.37,31.31 199.82,29.86 199.82,17.59 193.77,11.55 192.91,11.55 191.87,10.51 191.87,10.07 189.41,7.61 158.8,7.61 154.74,3.55 154.74,3.24 153.69,2.2 133.2,2.2 132.76,2.63 127.48,2.63 127.25,2.86 126.95,2.86 126.34,3.47 v2(126.06,3.47) ; v2(119.4,39.44) 119.47,39.37 119.47,31.86 119.58,31.74 119.58,28.95 120.04,28.49 v2(120.14,28.49)
  BOTTOM w0.102: v2(125.53,9.69) 125.53,9.39 125.3,9.16 125.3,8.09 125.55,7.84 126.08,7.84 126.26,7.66 126.26,4.11 126.06,3.9 v2(126.06,3.47) ; R802.1 119.71,28.06 v2(120.14,28.49) ; v2(119.4,39.44) 119.46,39.44 119.77,39.12 CPU1.L6
SIO_EXT_WAKE#: length 117.3
  TOP w0.102: KBC24.116 192.41,27.8 v2(192.66,27.55)
  L4 w0.102: v2(166.75,31.41) 166.29,31.41 163.7,28.82 160.3,28.82 159.56,28.08 151.99,28.08 150.42,26.51 149.38,26.51 148.92,26.05 145.26,26.05 144.65,25.44 144.65,24.17 144.04,23.56 141.55,23.56 139.14,21.15 137.42,21.15 136.46,20.18 135.74,20.18 135.25,20.67 131.52,20.67 131.04,21.15 130.25,21.15 130.2,21.2 124.81,21.2 124.46,20.84 121.56,20.84 121.31,20.59 120.52,20.59 120.23,20.59 119.14,21.68 118.48,21.68 118.07,22.09 115.58,22.09 114.53,23.14 111.12,23.14 110.22,24.05 v2(110.16,24.05) 108.71,24.05 108.08,24.68 108.08,25.14 109.09,26.15 109.09,30.55 110.5,31.96 110.5,32.62 110.16,32.96 v2(110.16,33.27)
  L6 w0.102: v2(192.66,27.55) 192.33,27.55 191.01,28.87 184.91,28.87 184.25,29.53 181.57,29.53 180.96,28.92 178.33,28.92 177.57,29.68 176.01,29.68 175.26,30.43 167.73,30.43 v2(166.75,31.41)
  BOTTOM w0.102: v2(110.16,33.27) 110.84,33.27 111.31,32.8 111.77,32.8 112.41,33.43 112.41,34.55 113.02,35.16 113.02,35.59 112.88,35.73 112.88,36.16 112.85,36.18 112.85,37.33 113.12,37.6 CPU1.AD3 ; R2041.2 109.68,20.68 109.68,22.27 109.85,22.44 110.26,22.44 110.49,22.67 110.49,23.28 v1(110.31,23.46) 110.16,23.61 v2(110.16,24.05)
SIO_PWRBTN#: length 158.8
  TOP w0.102: v2(99.92,44.72) 99.03,44.72 v1(98.89,44.58) ; KBC24.52 189.61,45.03 189.2,45.43 v2(189.2,45.69)
  L4 w0.102: v2(177.93,51.48) 177.57,51.48 177.11,51.02 177.11,49.38 175.93,48.2 175.93,46.02 174.99,45.08 174.99,40.26 171.74,37.01 171.74,32.77 168.08,29.11 168.08,28.62 165.52,26.06 165.02,26.06 164.8,25.85 161.67,25.85 161.49,25.67 161.24,25.67 161.01,25.44 161.01,25.44 160.76,25.19 153.61,25.19 152.78,24.35 152.78,24.27 150.76,22.25 150.76,22.25 148.41,19.9 146.02,19.9 144.3,18.18 143.46,18.18 143.23,17.95 141.22,17.95 139.06,15.79 134.64,15.79 134.36,15.51 126.11,15.51 125.25,16.37 122.42,16.37 121.8,17 115.99,17 115.24,17.75 109.93,17.75 109.27,18.41 108.91,18.41 108.66,18.66 108.66,19.04 108.41,19.3 105.05,19.3 104.24,18.48 100.05,18.48 99.54,18.99 99.54,19.11 98.31,20.34 97.1,20.34 96.16,21.28 94.97,21.28 94.33,21.91 94.33,23.56 94.66,23.89 94.66,26.18 94.56,26.28 94.56,35.17 98.78,39.39 98.78,41.32 99.92,42.46 v2(99.92,44.72)
  L6 w0.102: v2(177.93,51.48) 178.13,51.48 178.51,51.1 178.51,48.84 180.26,47.08 181.45,47.08 183.25,45.28 183.86,45.28 183.99,45.15 184.38,45.15 185.04,44.49 188.44,44.49 189.2,45.25 v2(189.2,45.69)
  BOTTOM w0.102: CPU1.BA15 103.75,44.94 103.43,44.62 101.9,44.62 101.71,44.81 101.31,44.81 100.77,44.28 100.37,44.28 v2(99.92,44.72)
SIO_RCIN#: length 153.5
  TOP w0.089: v2(188.64,45.38) 188.9,45.38 189.21,45.07 KBC24.53 ; R1820.2 98.14,23.02 v1(98.14,23.74) v2(98.14,24.5)
  L4 w0.127: v2(177.95,52.16) 177.67,52.16 176.35,50.84 175.82,50.84 175.54,50.56 175.54,46.19 174.6,45.25 174.6,43.43 173.91,42.74 173.91,39.77 171.35,37.2 171.35,32.93 167.69,29.28 167.69,28.79 165.36,26.46 164.86,26.46 164.65,26.25 161.52,26.25 161.33,26.06 153.57,26.06 152.13,24.62 152.13,24.57 151.24,23.68 151.24,23.66 150.98,23.4 150.96,23.4 150.47,22.9 149.45,22.9 148.49,21.94 146.99,21.94 145.34,20.29 143.69,20.29 143.05,19.64 143.05,19.26 142.66,18.86 140.87,18.86 139.55,17.54 136.19,17.54 135.71,17.06 127.46,17.06 127.23,17.29 124.46,17.29 123.87,17.87 116.35,17.87 115.6,18.62 112.86,18.62 111.87,19.61 110.43,19.61 109.87,20.17 108.49,20.17 107.3,21.37 104.38,21.37 103.47,20.45 101.33,20.45 99.52,22.26 99.52,24.17 99.19,24.5 98.17,24.5 ; 98.17,24.5 98.73,25.06 98.73,30.65 97.93,31.45 97.93,31.9 98.91,32.88 98.93,32.88 99.39,33.34 100.43,33.34 101.37,34.28 102.45,34.28 103.6,35.43 103.6,39.16 103.81,39.36 103.81,42.28 105.91,44.38 v2(105.91,44.95) ; 98.17,24.5 v2(98.14,24.5)
  L6 w0.102: v2(177.95,52.16) 177.98,52.16 178.89,51.25 178.89,49.09 180.35,47.63 181.44,47.63 183.41,45.66 184.02,45.66 184.15,45.53 184.54,45.53 185.17,44.9 188.16,44.9 v2(188.64,45.38)
  BOTTOM w0.089: v2(105.91,44.95) 105.94,44.92 105.94,44.16 105.49,43.71 CPU1.AW13
SIO_SLP_A#: length 1.2
  TOP w0.102: TP1706.1 108.68,45.78 v2(108.68,45.91)
  BOTTOM w0.102: v2(108.68,45.91) 109,45.59 CPU1.AN16
SIO_SLP_S0#: length 203.7
  TOP w0.127: v2(97.48,42.03) 97.92,42.46 v1(98.4,42.46) 104.16,42.46 104.57,42.87 105.61,42.87 105.64,42.89 106.07,42.89 106.27,42.69 106.9,42.69 v2(107.38,43.17) ; v2(193.32,42.66) 193.32,42.84 193.61,43.13 KBC24.42 ; R6005.1 172.26,16.09 172.97,15.38 v2(172.97,15.23)
  L4 w0.127: v2(193.32,42.66) 193.32,42.64 193.58,42.37 193.58,41.79 192.63,40.83 191.24,40.83 190.6,40.19 190.6,38.9 189.88,38.18 189.88,32.95 192.86,29.96 192.86,29.66 194.38,28.14 194.38,18.66 193.72,18 192.68,18 191.03,16.35 190.57,16.35 186.82,12.59 178.13,12.59 177.77,12.23 177.77,11.7 177.44,11.37 173.79,11.37 v2(173.23,11.93) 173.15,12.01 165.4,12.01 164.74,11.35 157.2,11.35 152.2,6.34 140.36,6.34 139.94,5.92 132.77,5.92 132.2,6.49 129.72,6.49 128.61,7.6 127.97,7.6 127.67,7.29 121.65,7.29 120.14,8.81 119.33,8.81 118.37,9.77 115.54,9.77 114.59,10.72 110.15,10.72 109.43,11.43 104.67,11.43 104.51,11.6 103.07,11.6 102.87,11.8 100.18,11.8 99.57,12.41 94.8,12.41 93.07,14.14 91.14,14.14 87.52,17.76 86.07,17.76 85.79,17.48 82.59,17.48 82.1,17.96 82.1,19.41 86.21,23.51 86.21,25.19 86.45,25.44 86.45,26.92 86.9,27.37 92.47,27.37 94.04,28.94 94.04,35.39 97.48,38.83 v2(97.48,42.03)
  BOTTOM w0.127: v2(107.38,43.17) 107.05,42.85 CPU1.AT11 ; v2(173.23,11.93) 173.23,14.98 v2(172.97,15.23)
SIO_SLP_S3#: length 519.1
  TOP w0.127: v2(94.71,93.21) 94.71,93.2 95.06,92.85 R4018.1 ; R4017.1 86.18,91.27 v2(86.18,93.29) ; v2(53.41,4.03) 55.17,4.03 56.56,5.43 R1733.1 ; KBC24.70 182.53,40.64 182.12,40.23 v2(182.12,40.05)
  L3 w0.127: v2(23.42,28.26) 23.42,28.41 21.51,30.32 21.51,32.35 19.86,34 19.86,36.03 17.19,38.7 17.19,40.1 16.43,40.86 16.43,44.8 17.4,45.76 17.4,55.77 18.59,56.96 18.59,57.8 22.1,61.31 22.1,62.49 24.5,64.89 24.5,66.07 24.37,66.2 24.37,68.68 24.94,69.25 24.94,69.85 28.37,73.28 28.37,86.48 28.75,86.86 28.75,87.98 28.23,88.5 28.23,89.62 29.77,91.15 v2(30.02,91.15) ; v2(55.12,1.67) 55.17,1.72 57.5,1.72 57.86,1.36 67.05,1.36 v2(67.51,1.82) ; v2(86.18,93.29) 86.33,93.44 92.07,93.44 92.75,94.12 93.72,94.12 94.64,93.21 v2(94.71,93.21) ; v2(71.47,19.32) 72.03,19.32 73.61,20.9 80.67,20.9 81.35,21.58 83.72,21.58 84.36,22.23 88.05,22.23 88.96,21.31 91.1,21.31 v2(91.72,21.94)
  L4 w0.127: v2(67.51,1.82) 66.03,3.31 66.03,4.14 68.55,6.67 68.55,7.2 68.3,7.46 68.3,8.73 66.27,10.76 66.27,11.6 67.02,12.35 68.41,12.35 70.08,14.01 70.94,14.01 v2(72.39,15.46) ; v2(182.12,40.05) 182.17,40.05 183.26,38.95 183.26,37.48 182.97,37.19 182.97,29.74 182.76,29.54 182.76,28.9 182.74,28.88 182.74,28 182.81,27.93 182.81,25.2 183.4,24.61 183.4,22.83 181.33,20.76 177.86,20.76 177.51,21.11 176.46,21.11 174.83,19.47 174.19,19.47 173.25,18.53 171.7,18.53 170.76,17.59 v2(170.61,17.59) ; v2(53.41,4.03) 53,4.45 53,5.52 53.21,5.73 53.21,8.63 51,10.84 51,11.92 47.57,15.36 v2(47.45,15.36) ; v2(147.95,22.83) 147.47,22.34 146.81,22.34 145.51,21.05 142.42,21.05 139.39,18.03 136.07,18.03 135.51,17.47 127.63,17.47 127.39,17.71 127.01,17.71 127,17.7 124.64,17.7 124.05,18.28 116.52,18.28 115.77,19.03 115.07,19.03 113.4,20.7 112.52,20.7 112.38,20.55 112.38,20.55 111.84,20.02 110.6,20.02 110.04,20.58 109.08,20.58 107.88,21.77 104.09,21.77 103.18,20.86 101.5,20.86 99.97,22.38 99.97,24.45 99.13,25.29 99.13,30.83 98.37,31.59 v2(98.37,31.72) 99.59,32.94 101.41,32.94 103.83,35.36 103.83,39.06 104.04,39.26 104.04,42.19 106.42,44.57 107.6,44.57 v2(108.03,45) ; v2(30.02,91.15) 30.28,91.15 31.55,89.88 35.51,89.88 36.5,90.87 41.83,90.87 49.76,98.8 54.05,98.8 54.94,97.91 54.94,94.1 56.18,92.85 73.46,92.85 v2(75.56,90.75)
  L6 w0.127: v2(147.95,22.83) 149.48,21.3 151,21.3 153.57,18.74 169.49,18.74 170.61,17.62 v2(170.61,17.59)
  BOTTOM w0.127: v2(86.18,93.29) 86.18,93.16 85.85,92.83 83.79,92.83 83.28,93.34 77.82,93.34 75.74,91.25 75.74,90.92 v2(75.56,90.75) 74.8,89.98 74.8,57.42 76.45,55.76 76.45,27.47 73.79,24.81 73.79,20.76 72.4,19.37 71.52,19.37 v2(71.47,19.32) 71.37,19.22 71.37,17.01 72.44,15.94 72.44,15.51 v2(72.39,15.46) 72.39,15.43 Q4008.G ; R4010.1 129.65,102.2 118.54,102.2 116.76,100.42 115.64,100.42 111.05,95.83 111.05,94.95 110.35,94.25 108.18,94.25 v1(108.13,94.2) 107.62,93.69 107.62,92.35 107.87,92.1 107.87,90.05 107.2,89.37 98.74,89.37 97.38,90.73 97.38,91.53 96.04,92.88 95.05,92.88 v2(94.71,93.21) ; v2(53.41,4.03) 53.57,3.88 53.57,2.94 54.06,2.44 PR5405.1 ; PR5126.1 47.32,15.49 v2(47.45,15.36) ; v2(108.03,45) 108.35,44.67 CPU1.AP15 ; Q2701.G 23.42,28.73 v2(23.42,28.26) ; v2(55.12,1.67) 54.91,1.87 PR5405.1 ; U1703.2 56.03,3.39 55.08,2.44 PR5405.1 ; v2(91.72,21.94) 91.9,21.76 95.5,21.76 96.48,22.74 96.48,27.28 97.28,28.08 97.28,31.11 97.89,31.72 v2(98.37,31.72)
SIO_SLP_S4#: length 309.9
  TOP w0.127: v2(94.41,48.23) 94.41,48.05 97.15,45.3 v1(97.86,45.3) v2(100.48,45.3) ; v2(184.43,41.72) 184.31,41.84 KBC24.67
  L3 w0.127: v2(95.65,91.33) 94.93,92.05 88.73,92.05 87.73,91.05 81.28,91.05 80.29,92.04 59.64,92.04 58.34,93.34 52.4,93.34 51.32,94.42 50.56,94.42 49.25,95.72 44.52,95.72 44.33,95.91 43.96,95.91 43.62,95.57 42.39,95.57 v2(41.32,94.5) ; v2(184.43,41.72) 184.87,41.28 184.87,40.89 186.85,38.9 186.85,38.31 186.49,37.95 186.49,36.72 186.73,36.48 186.73,34.3 186.99,34.04 187.18,34.04 188.44,32.78 188.44,32.23 189.39,31.28 190.59,31.28 191.83,30.05 191.83,29.58 192.85,28.56 193.04,28.56 194.09,27.51 194.09,24.63 192.86,23.4 192.86,18.84 v2(191.21,17.19)
  L4 w0.127: v2(100.48,45.3) 99.93,45.3 98.35,43.72 98.35,39.31 94.31,35.27 94.31,28.84 92.53,27.07 86.95,27.07 86.7,26.82 86.7,25.33 86.46,25.09 86.46,23.36 82.36,19.26 82.36,18.07 82.69,17.73 85.66,17.73 85.94,18.01 87.62,18.01 91.24,14.39 93.19,14.39 94.92,12.67 99.69,12.67 100.3,12.06 102.59,12.06 102.73,12.2 v2(103.36,12.2) 104.56,12.2 105.07,11.69 109.56,11.69 110.11,11.14 114.55,11.14 115.67,10.02 118.47,10.02 119.13,9.36 121.69,9.36 123.51,7.55 127.56,7.55 127.87,7.85 128.72,7.85 129.82,6.75 132.3,6.75 132.88,6.18 139.83,6.18 140.24,6.6 152.07,6.6 157.07,11.6 164.62,11.6 165.43,12.41 177.44,12.41 177.88,12.84 186.69,12.84 190.7,16.86 190.88,16.86 v2(191.21,17.19)
  BOTTOM w0.127: U4005.2 102.94,11.83 103.31,12.2 v2(103.36,12.2) 103.74,12.2 104.15,11.79 R4023.1 ; PR5417.1 41.07,94.76 v2(41.32,94.5) ; v2(100.48,45.3) 100.51,45.28 100.68,45.28 100.71,45.25 101.73,45.25 102.08,45.61 102.44,45.61 102.56,45.48 104.18,45.48 CPU1.BA16 ; v2(94.41,48.23) 93.47,48.23 93.44,48.2 92.91,48.2 92.63,48.48 92.63,48.73 93.6,49.7 93.6,51.43 91.59,53.43 91.59,88.03 94.89,91.33 v2(95.65,91.33)
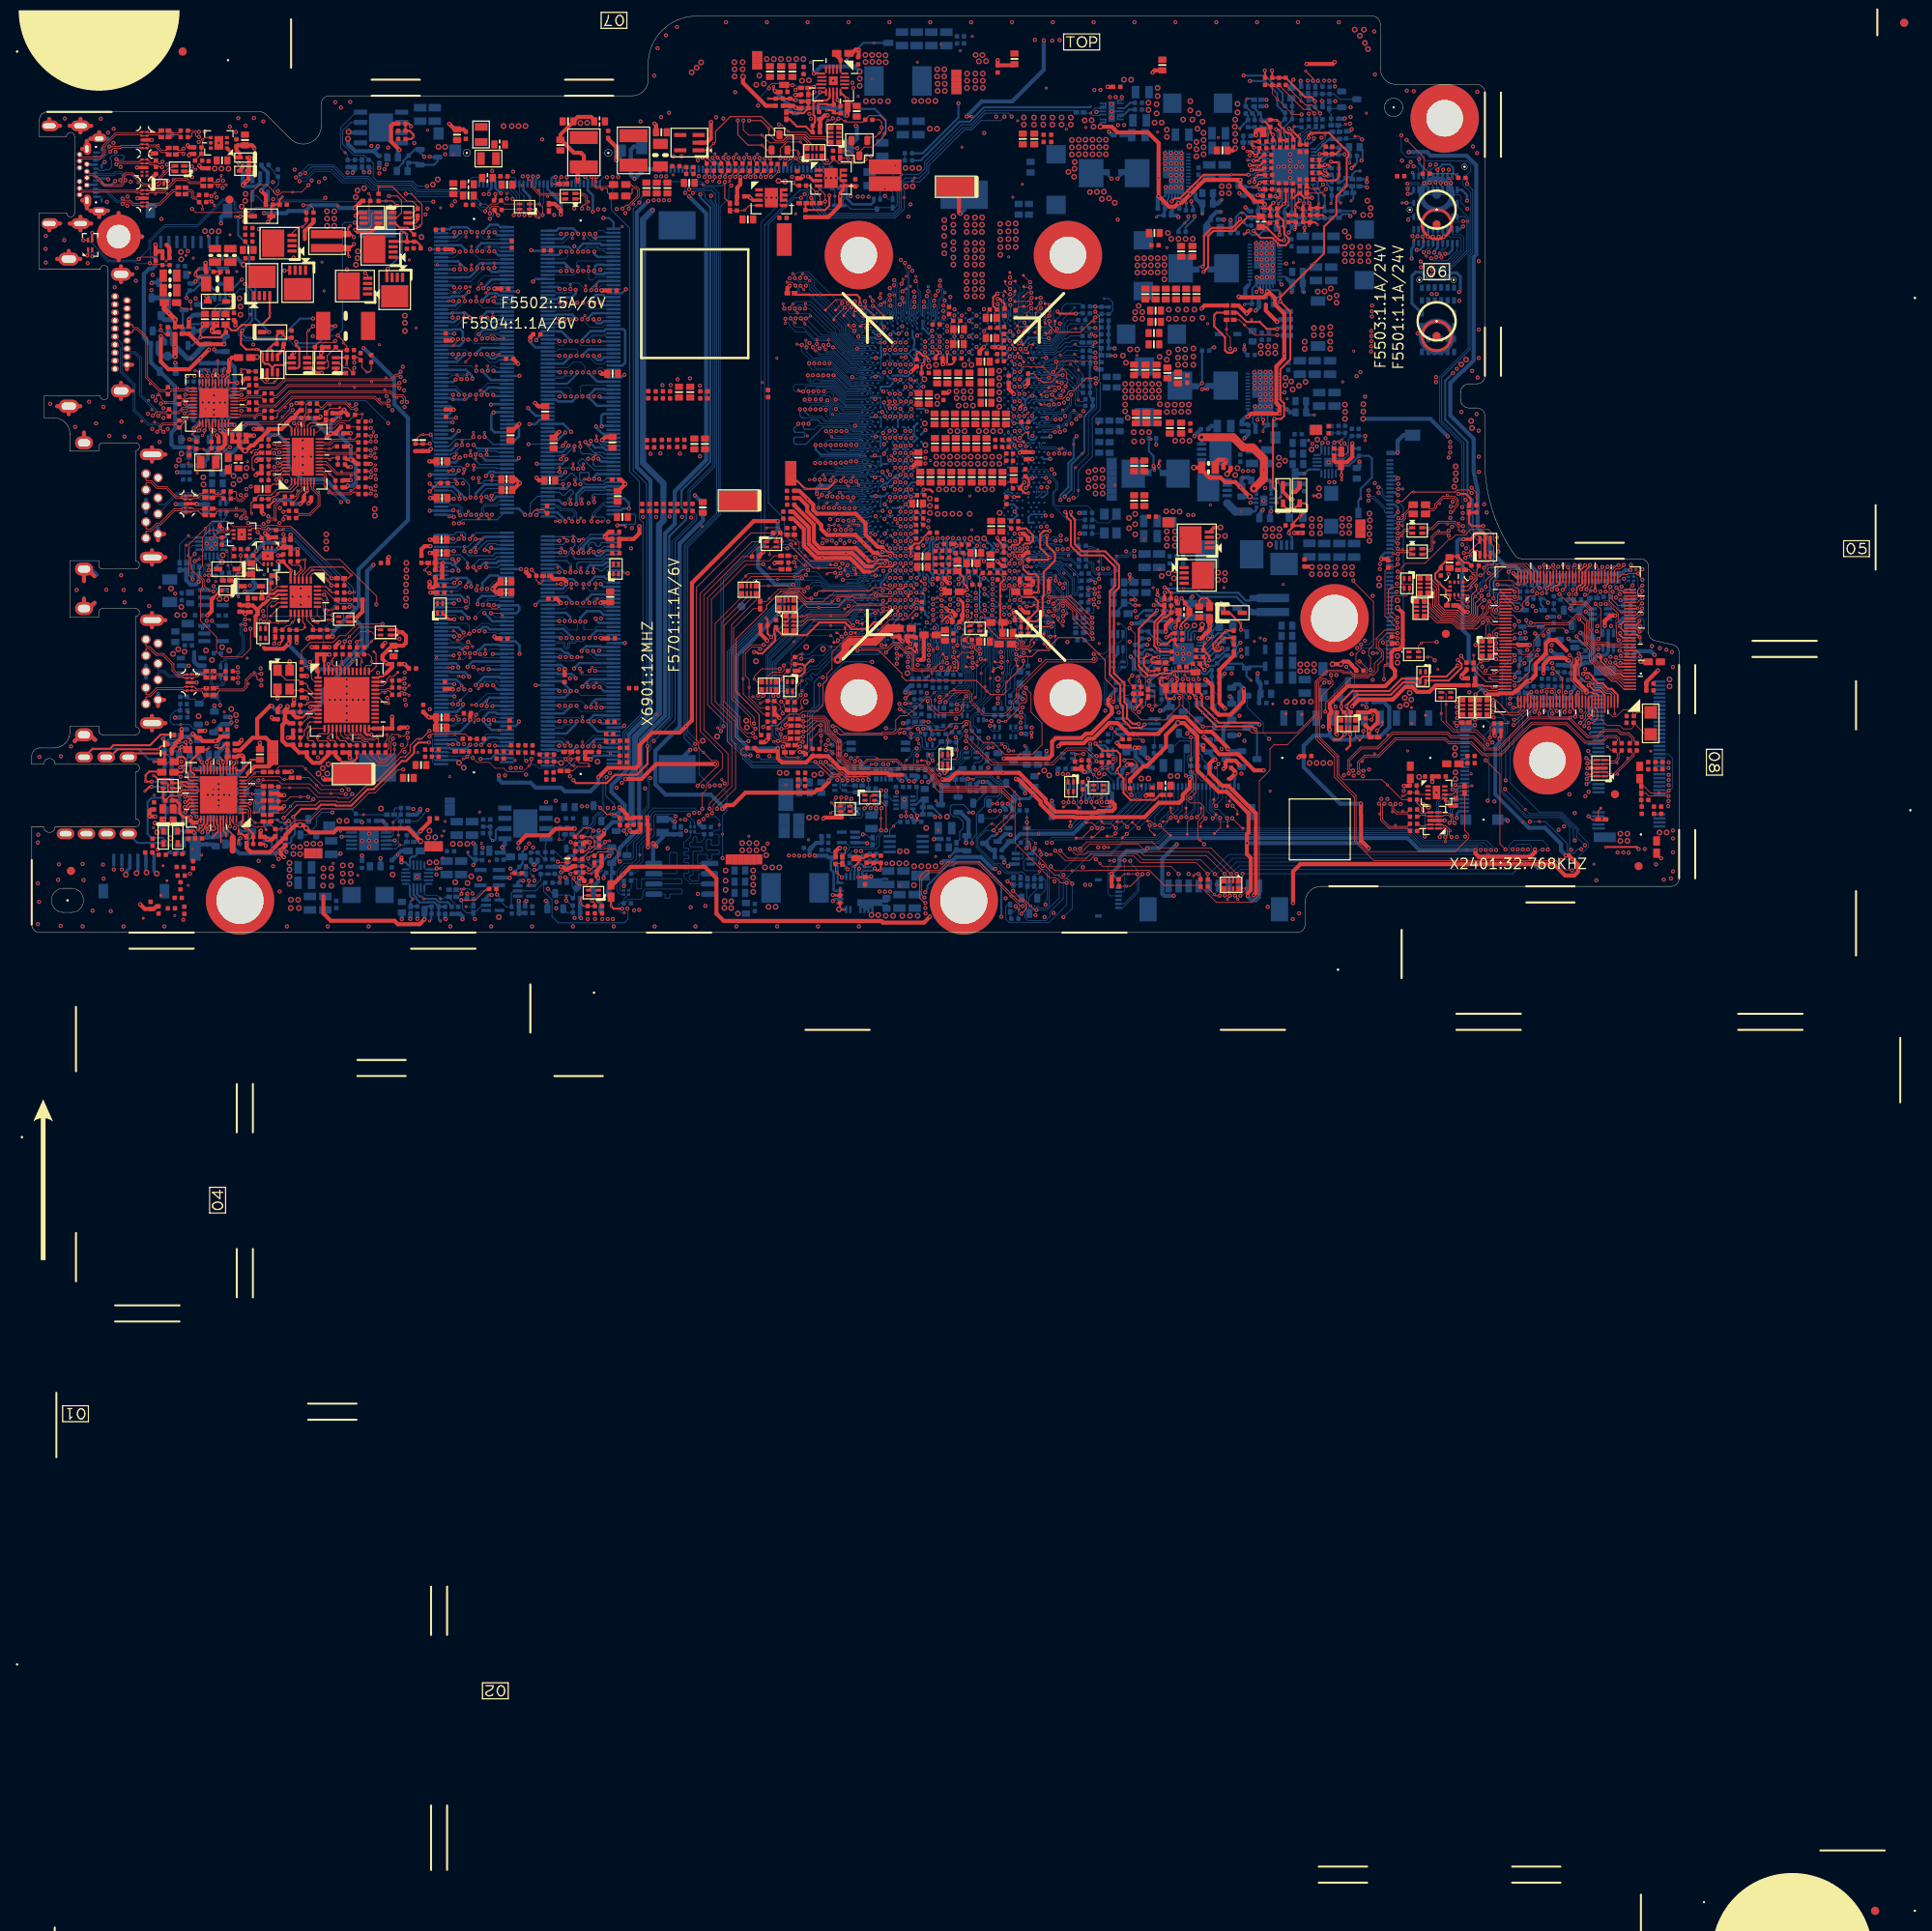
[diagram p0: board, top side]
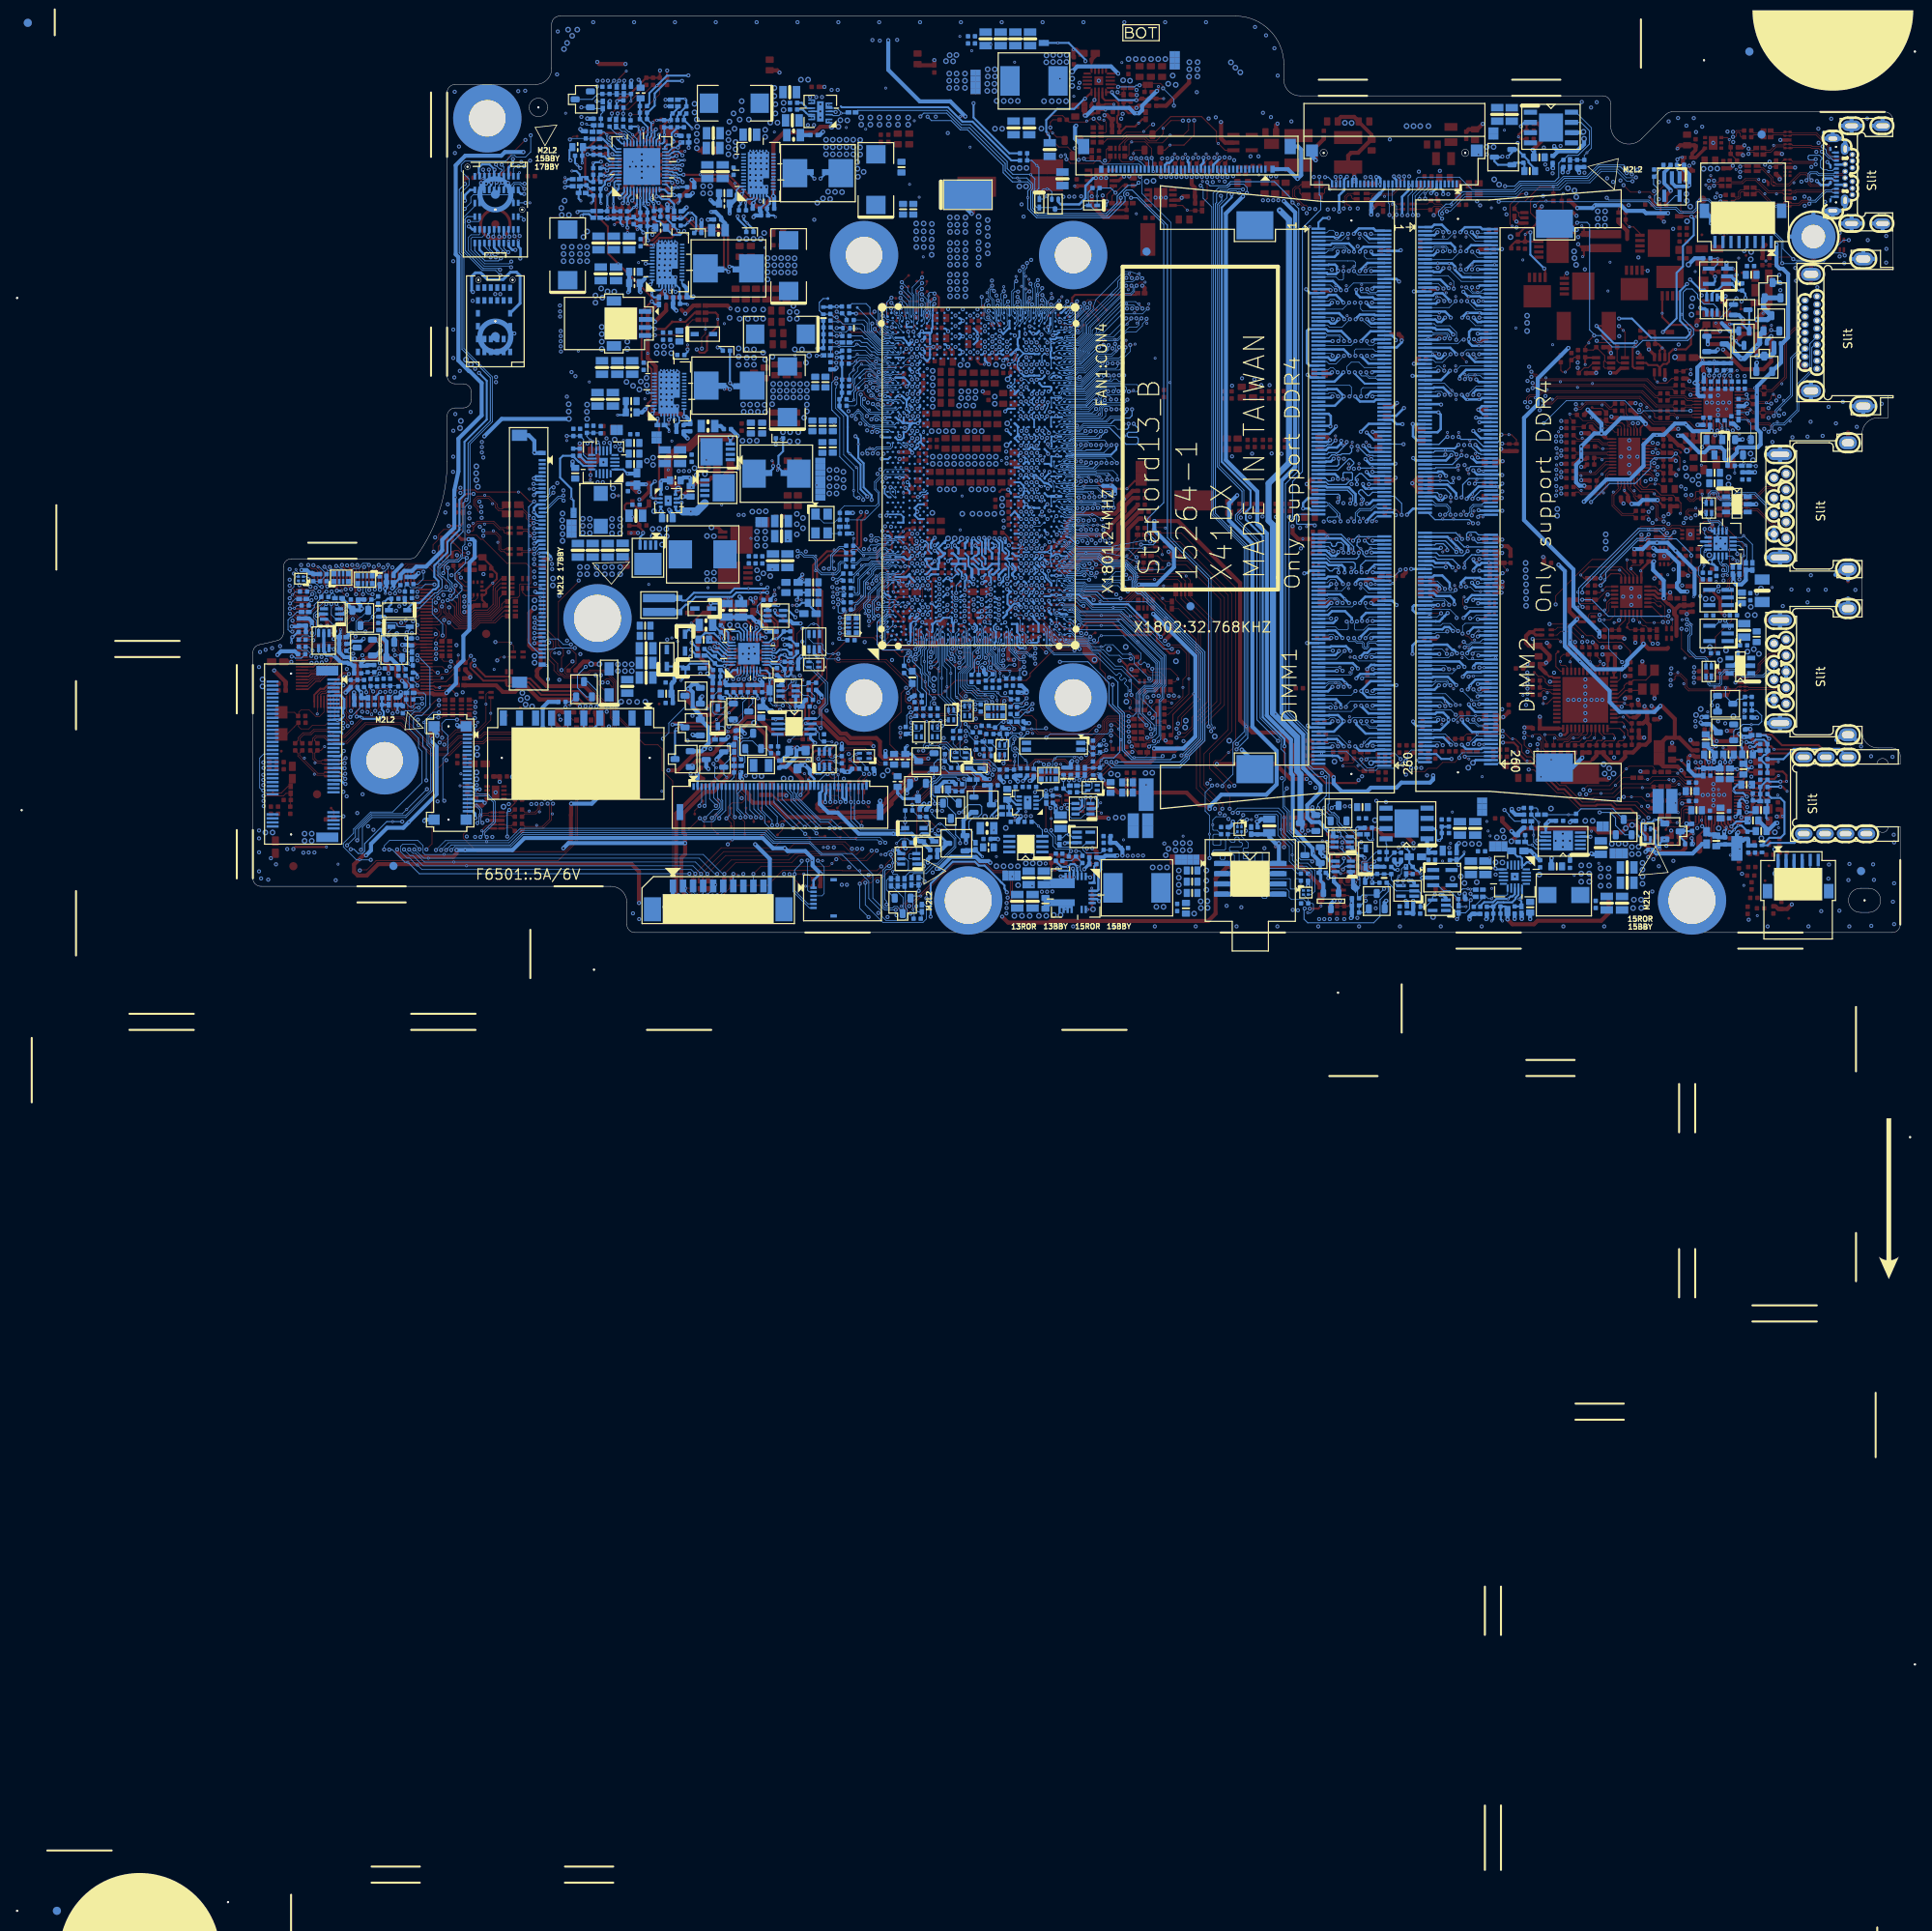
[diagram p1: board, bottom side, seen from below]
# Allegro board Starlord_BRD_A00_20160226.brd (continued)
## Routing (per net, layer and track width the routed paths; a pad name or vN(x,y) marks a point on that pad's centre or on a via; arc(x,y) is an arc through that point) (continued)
SIO_SLP_S5#: length 4.7
  TOP w0.102: TP1703.1 101.09,45.38 101.37,45.66 v2(101.45,45.66)
  BOTTOM w0.102: v2(101.45,45.66) 101.6,45.66 101.7,45.76 101.93,45.76 101.98,45.81 102.54,45.81 102.64,45.71 103,45.71 103.02,45.69 103.81,45.69 103.99,45.87 104.09,45.87 104.13,45.91 104.39,45.91 104.43,45.87 104.61,45.87 CPU1.AY16
SIO_SLP_SUS#: length 111.8
  TOP w0.102: v2(66.98,7.28) 67.16,7.46 R1729.2
  L3 w0.102: v2(65.23,3.01) 65.35,2.89 71.17,2.89 72.34,4.06 79.88,4.06 85.06,9.24 v2(85.9,9.24) 85.9,10.33 87.25,11.68 94.11,11.68 94.66,11.12 101.55,11.12 102.49,10.18 v2(102.49,10.13) ; v2(108.68,45) 108.61,45 108.2,44.59 106.46,44.59 104.34,42.47 104.34,34.62 106.17,32.78 106.17,28.13 104.01,25.98 102.45,25.98 102.12,25.98 100.35,24.21 100.35,20.33 99.37,19.35 98.93,19.35 98.68,19.09 98.68,18.61 97.8,17.73 90.36,17.73 90.19,17.9 87.22,17.9 87.07,18.05 85.8,18.05 v2(85.57,18.28)
  L4 w0.102: v2(65.23,3.01) 65.78,3.57 65.78,4.24 66.95,5.41 66.95,7.26 v2(66.98,7.28)
  BOTTOM w0.102: v2(85.57,18.28) 86.43,17.42 86.43,15.1 85.9,14.57 v1(85.9,12.23) v2(85.9,9.24) ; v2(108.68,45) 109,44.67 CPU1.AN15 ; PR5207.1 101.7,9.8 102.03,10.13 v2(102.49,10.13) ; PR5407.1 65.17,10 66.32,8.86 66.88,8.86 66.98,8.75 v2(66.98,7.28)
SKTOCC#: length 6.5
  BOTTOM w0.102: CPU1.A65 126.01,73.17 126.03,73.19 126.64,73.19 127.56,74.12 127.56,74.12 128.12,74.68 128.12,74.71 128.24,74.83 128.24,74.96 128.24,76.24 TP402.1
SLEEVE: length 5.7
  TOP w0.203: EC2906.1 17.18,16.98 18.29,16.98 v1(18.39,16.88) 18.39,16.88 18.87,17.36 19.4,17.36 19.45,17.31 HDA27.30
  TOP w0.305: EC2906.1 16.34,16.71 RN2901.4
SLEEVE_R: length 11.3
  L6 w1.016: HPMIC1.3 8.13,10.96 13.61,10.96 14.1,11.45 16.99,11.45 v3(17.27,11.73)
  vias: v1(18.74,13.86)
SLP_LAN#: length 3.9
  TOP w0.127: TP1704.1 102.49,44.97 v2(102.26,45.2)
  BOTTOM w0.102: 105.07,44.99 CPU1.AW15
  BOTTOM w0.127: 105.07,44.99 104.77,45.28 104.41,45.28 104.39,45.26 104.06,45.26 104.05,45.27 102.42,45.27 102.36,45.2 v2(102.26,45.2)
SM_DRAMRST#: length 35.1
  L4 w0.127: v2(104.49,33.65) 104.49,33.85 104.24,34.1 104.24,38.85 104.44,39.06 104.44,40.89 105.36,41.8 105.36,42.13 105.1,42.38 105.1,42.66 106.12,43.68 106.97,43.68 v2(107.38,44.09)
  BOTTOM w0.127: v2(107.38,44.09) 107.05,43.76 CPU1.AT13 ; R504.1 D502.2 R505.2 99.52,21.28 v1(99.39,21.4) 99.08,21.71 97.79,21.71 97.05,22.44 97.05,27.09 98.4,28.44 98.4,31.04 101.01,33.66 104.49,33.66 v2(104.49,33.65)
SM_INTRUDER#: length 30.1
  TOP w0.102: v2(98.12,25.77) 97.66,25.77 v1(97.2,25.32) 96.44,24.55 96.44,23.27 R1730.2
  L4 w0.102: v2(108.03,45.91) 107.62,45.51 105.91,45.51 105.51,45.1 105.51,44.29 103.6,42.38 103.6,39.46 103.4,39.26 103.4,38.04 97.51,32.15 97.51,30.34 98.12,29.73 v2(98.12,25.77)
  BOTTOM w0.102: v2(108.03,45.91) 108.35,45.59 CPU1.AP16
SM_PGCNTL: length 170.6
  TOP w0.127: v2(47.72,87.65) 48.08,87.65 v1(48.26,87.82) 48.52,88.09 48.52,90.49 47.22,91.79 47.22,91.79 47.17,91.84 v2(46.51,91.84)
  L3 w0.127: v2(46.02,23.31) 45.97,23.36 45.97,23.64 45.79,23.82 45.79,26.56 45.13,27.22 45.13,35.12 44.85,35.4 44.85,36.97 47.29,39.41 47.29,63.47 48.44,64.61 48.44,84.7 47.29,85.84 47.29,87.21 v2(47.72,87.65) ; v2(96.11,91.79) 96.11,91.13 95.78,90.79 94.31,90.79 94.31,90.8 80.52,90.8 79.53,91.79 59.51,91.79 58.22,93.08 52.3,93.08 51.22,94.16 48.83,94.16 v2(46.51,91.84)
  L4 w0.127: v2(37.39,14.93) 38.83,16.37 44.65,16.37 45.34,17.06 45.34,21.73 45.9,22.29 45.9,22.65 46.02,22.78 v2(46.02,23.31) ; v2(103.78,75.14) 102.53,76.39 98.39,76.39 96.95,77.84 96.95,89.96 96.11,90.8 v2(96.11,91.79)
  BOTTOM w0.127: v2(103.78,75.14) 104.03,74.9 104.75,74.9 104.92,74.73 CPU1.AW67 ; v2(37.39,14.93) 36.09,14.93 35.41,14.24 35.41,13.3 34.25,12.15 Q501.S
SM_PGCNTL_R: length 10.6
  BOTTOM w0.127: PR5125.1 v1(41.25,14.65) 40.42,14.65 R506.2 39.69,15.38 35.72,15.38 Q501.D
SM_RCOMP_0: length 17.7
  TOP w0.203: 105.81,47.92 106.45,47.29 106.92,47.29 v2(107.38,46.83)
  TOP w0.508: R501.1 95.45,54.91 v1(96.47,53.89) 97.18,53.18 97.18,52.52 97.64,52.06 102.46,52.06 103.68,50.84 103.68,49.47 105.23,47.92 105.81,47.92
  BOTTOM w0.305: v2(107.38,46.83) 107.38,46.69 107.69,46.37 CPU1.AR18
SM_RCOMP_1: length 16.2
  TOP w0.203: v2(106.73,46.83) 106.73,46.83 105.51,46.83 105.21,47.13
  TOP w0.508: R502.1 95.45,54.02 96.44,53.03 96.44,52.37 98.17,50.64 98.17,50.15 98.9,49.42 102.44,49.42 v1(103.45,48.4) 104.66,47.2 105.14,47.2 105.21,47.13
  BOTTOM w0.305: CPU1.AT18 107.03,46.37 106.73,46.68 v2(106.73,46.83)
SM_RCOMP_2: length 16.5
  TOP w0.203: v2(106.08,45.92) 106.01,45.85 104.84,45.85 104.49,45.51
  TOP w0.508: R503.1 94.69,52.32 96.62,50.38 96.62,48.33 97.79,47.16 v1(101.24,47.16) 102.05,47.16 103.71,45.51 104.49,45.51
  BOTTOM w0.305: v2(106.08,45.92) 106.08,46.02 106.4,46.35 CPU1.AU18
SMBCLK1: length 72.3
  TOP w0.203: v2(197.56,33.52) 197.64,33.44 KBC24.9
  TOP w0.254: 172.67,31.25 172.67,31.57 172.92,31.82 175.92,31.82 v2(177.29,33.19) ; 172.67,31.25 172.36,31.56 170.36,31.56 168.81,30.01 164.23,30.01 162.84,28.62 v2(162.84,28.08) 162.84,27.72 EC4309.1 163.45,27.1 RN4302.3 ; 172.67,31.25 RN2402.3 ; v2(152.14,25.26) 151.79,25.62 147.32,25.62 v1(145.63,27.31) 144.88,28.06 144.88,29.02 144.73,29.18 v2(144.73,29.22) 144.73,29.28 144.04,29.96 PG4410.1
  L6 w0.254: v2(197.56,33.52) 197.56,33.16 196.9,32.5 194.38,32.5 193.62,33.27 192.81,33.27 190.7,31.16 187.55,31.16 186.89,31.82 185.06,31.82 184.63,32.25 184.17,32.25 182.9,30.98 179.5,30.98 v2(177.29,33.19) ; v2(162.84,28.08) 162.84,28.29 162.53,28.59 161.24,28.59 158.09,25.44 153.01,25.44 152.83,25.26 v2(152.14,25.26)
  BOTTOM w0.254: v2(152.14,25.26) 152.36,25.05 D4306.3 ; v2(144.73,29.22) 144.73,29.52 PR4439.2
SMBCLK2: length 36.6
  TOP w0.089: RN2603.4 172.45,35.64 v1(172.79,35.98) 172.92,36.11 v2(174.7,36.11) ; v2(194.82,36.49) 195.11,36.79 195.11,40.21 v2(194.46,40.86) ; KBC24.12 197.96,34.64 197.56,35.04 v2(197.43,35.04)
  L6 w0.102: v2(194.82,36.49) 195.91,36.49 197.23,35.17 197.31,35.17 v2(197.43,35.04) ; v2(194.46,40.86) 194.38,40.86 193.85,40.33 192,40.33 191.51,39.84 189.08,39.84 189.03,39.89 187.86,39.89 187.53,39.56 186.64,39.56 186.28,39.92 183.36,39.92 182.93,39.49 181.47,39.49 181.36,39.59 179.65,39.59 177.29,37.23 176.02,37.23 174.9,36.11 v2(174.7,36.11)
  BOTTOM w0.089: v2(197.43,35.04) 197.9,35.51 R2459.1 ; Q2604.3 194.13,40.53 v2(194.46,40.86)
SMBCLK3: length 44.2
  TOP w0.089: RN2604.4 175.27,29.18 v1(175.27,27.25) 175.27,26.42 176.76,24.93 179.53,24.93 181.05,23.41 v2(181.05,23.36) ; v2(187.32,35.12) 187.12,35.12 186.29,34.29 185.76,34.29 184.96,33.49 184.96,32.78 184.42,32.24 KBC24.91
  L3 w0.127: v2(180.36,33.06) 179.98,32.68 179.98,29.12 180.77,28.34 180.77,26.58 181.01,26.34 181.05,26.3 181.06,26.29 181.18,26.17 181.19,26.16 181.21,26.14 181.43,25.92 181.43,25.31 180.69,24.58 180.69,23.71 v2(181.05,23.36)
  L6 w0.102: v2(194.61,37.46) 193.24,36.08 190.9,36.08 190.83,36.16 188.36,36.16 v2(187.32,35.12) 187.15,35.12 186.31,34.28 185.72,34.28 184.81,35.2 183.9,35.2 182.09,33.39 180.69,33.39 v2(180.36,33.06)
  BOTTOM w0.089: Q2605.1 194.84,37.23 v2(194.61,37.46)
SMBDA1: length 70.8
  TOP w0.203: v2(196.92,33.54) 196.92,33.44 197.33,33.04 198.75,33.04 KBC24.8
  TOP w0.254: v2(152.68,25.85) 152.45,26.08 147.6,26.08 v1(147.19,26.48) 145.51,28.16 145.51,29.18 v2(145.46,29.23) 145.49,29.25 145.49,29.56 145.01,30.04 PG4409.1 ; v2(177.34,33.87) 177.42,33.79 177.42,33.77 177.8,33.4 177.8,32.91 176.2,31.31 173.41,31.31 RN2402.4 173.32,30.75 173.21,30.63 172.37,30.63 171.89,31.11 170.55,31.11 169,29.56 164.81,29.56 163.5,28.25 v2(163.5,28.13) 163.5,27.93 164.02,27.41 EC4310.1 163.95,27.31 RN4302.2
  L6 w0.254: v2(152.68,25.85) 152.75,25.85 152.93,26.03 158.01,26.03 161.03,29.05 162.74,29.05 163.5,28.29 v2(163.5,28.13) ; v2(177.34,33.87) 179.78,31.44 182.71,31.44 183.98,32.71 184.83,32.71 185.27,32.27 187.09,32.27 187.76,31.61 190.5,31.61 192.61,33.72 193.83,33.72 194.59,32.96 196.52,32.96 196.92,33.37 v2(196.92,33.54)
  BOTTOM w0.254: D4305.3 151.12,25.51 151.46,25.85 v2(152.68,25.85) ; v2(145.46,29.23) 145.46,29.39 PR4438.2
SMBDA2: length 38.5
  TOP w0.089: v2(174.47,33.82) 174.06,34.24 v1(173.61,34.24) RN2603.3 ; KBC24.11 197.73,34.24 v2(197.58,34.38)
  L4 w0.127: v2(194.69,38.09) 194.94,38.09 195.41,38.56 196.52,38.56 196.55,38.54 197.85,38.54 198.19,38.19 198.19,35.12 197.58,34.51 v2(197.58,34.38)
  L6 w0.102: v2(194.69,38.09) 194.66,38.07 194.46,38.07 194.17,37.77 191.83,37.77 191.03,36.97 190.35,36.97 190.27,36.9 188.62,36.9 187.27,35.55 187.14,35.55 186.28,34.69 185.77,34.69 184.61,35.86 182.8,35.86 182.29,36.36 181.89,36.36 180.72,35.2 176.86,35.2 175.49,33.82 v2(174.47,33.82)
  BOTTOM w0.089: v2(197.58,34.38) 197.58,34.59 198.06,35.07 198.69,35.07 R2447.1 ; Q2604.6 195.54,38.94 v2(194.69,38.09)
SMBDA3: length 44.8
  TOP w0.089: KBC24.89 181.28,33.04 v2(180.78,32.54) ; RN2604.3 175.64,29.86 175.87,29.63 v1(175.87,28.39) 175.87,26.2 176.86,25.21 179.35,25.21 179.36,25.2 179.64,25.2 181.05,23.79 181.46,23.79 v2(181.63,23.62)
  L3 w0.127: v2(180.78,32.54) 180.36,32.12 180.36,30.82 181.21,29.97 181.21,29.6 180.78,29.16 180.78,28.87 181.15,28.49 181.15,27.67 181.15,27.67 181.15,26.74 181.48,26.42 181.48,26.41 181.7,26.19 181.84,26.05 181.84,25.39 182.97,24.25 182.97,23.89 182.7,23.62 v2(181.63,23.62)
  L6 w0.102: v2(196.31,34.26) 196.31,34.31 194.97,35.65 190.83,35.65 189.15,33.98 185.5,33.98 184.58,34.89 184.17,34.89 182.29,33.01 181.43,33.01 180.96,32.54 v2(180.78,32.54)
  BOTTOM w0.089: v2(196.31,34.26) 196.31,34.41 196.69,34.78 Q2605.4
SML0_SMBCLK: length 21.3
  TOP w0.089: v2(111.4,28.79) 111.4,28.21 112.6,27.02 115.37,27.02 115.87,27.52 v1(115.87,28.31) 115.87,29.05 v2(116.2,29.38)
  L3 w0.127: v2(116.2,29.38) 116.43,29.61 116.43,37.33 116.76,37.66 116.76,40.15 117.27,40.66 v2(117.45,40.66)
  BOTTOM w0.089: v2(111.4,28.79) 111.62,28.58 RN1807.5 ; CPU1.R9 117.87,41.08 v2(117.45,40.66)
SML0_SMBDATA: length 12.8
  BOTTOM w0.089: CPU1.W2 115.39,36.66 115.39,36.34 115.54,36.18 115.54,33.01 116.32,32.23 116.32,30.77 115.93,30.37 115.33,30.37 114.67,29.71 112.73,29.71 112.34,29.32 v1(112.34,28.9) 112.27,28.82 RN1807.6
SML1_SMBCLK: length 183.5
  TOP w0.089: v2(132.05,34) 131.98,33.93 126.06,33.93 122.45,30.32 122.45,29.25 121.79,28.59 121.79,28 121.02,27.23 118.47,27.23 116.9,28.8 116.9,29.67 116.49,30.07 114.36,30.07 v1(113.81,29.53) v2(112.93,28.64) ; v2(197.33,36.34) 197.03,36.64 197.03,38.48 197.32,38.77 197.32,39.56 196.05,40.83 v2(195.73,40.83)
  L4 w0.127: v2(132.05,34) 132.05,33.5 135.5,30.05 146.98,30.05 147.88,30.95 149.17,30.95 150.12,31.91 152.11,31.91 152.23,31.78 153.6,31.78 155.75,33.93 164.08,33.93 164.72,34.56 165.28,34.56 v2(165.58,34.87) 166.24,35.53 166.24,37.08 166.39,37.23 166.39,41.57 166.13,41.84 166.13,46.87 167.63,48.37 167.63,52.73 167.02,53.34 167.02,55.15 166.44,55.72 166.44,56.37 167.82,57.75 167.82,59.66 169.11,60.95 169.11,70.35 170.31,71.54 170.31,78.84 171.45,79.98 171.45,81.34 171.98,81.88 172.67,81.88 173.2,82.41 173.2,83.15 172.95,83.4 v2(172.72,83.4)
  L6 w0.102: v2(195.73,40.83) 194,39.11 192.91,39.11 192.63,39.39 191.97,39.39 191.82,39.23 191.03,39.23 190.12,38.32 188.77,38.32 188.19,37.74 184.99,37.74 184.68,37.43 183.74,37.43 183.34,37.84 181.81,37.84 181.66,37.68 181.65,37.68 181.57,37.61 181.31,37.61 180.6,36.9 179.43,36.9 178.33,35.81 176.61,35.81 175.36,34.56 170.83,34.56 170.17,35.22 169.48,35.22 169.42,35.17 166.59,35.17 166.28,34.86 165.59,34.86 v2(165.58,34.87)
  BOTTOM w0.089: Q2601.3 134.4,34.95 133.45,34 v2(132.05,34) ; Q2604.4 196.01,40.56 v2(195.73,40.83) ; R2459.2 197.42,36.4 197.36,36.34 v2(197.33,36.34) ; CPU1.W3 115.99,37.48 115.99,37.25 116.03,37.14 116.03,36.94 116,36.87 116,36.58 116.03,36.49 116.03,36.09 115.91,35.97 115.91,33.2 116.87,32.24 116.87,30.54 116.14,29.81 115.57,29.81 114.83,29.07 113.36,29.07 v2(112.93,28.64) 112.77,28.49 RN1807.7 ; v2(172.72,83.4) 173,83.13 176.02,83.13 177.75,84.86 177.75,86.25 177.54,86.45 176.33,86.45 176.06,86.72 176.06,87.4 GPU1.E8
SML1_SMBDATA: length 188.7
  TOP w0.089: v2(132.05,34.64) 132.48,34.21 132.48,33.83 132.23,33.58 131.88,33.58 131.82,33.64 126.23,33.64 122.73,30.13 122.73,29.15 122.07,28.49 122.07,27.9 121.13,26.96 118.36,26.96 116.63,28.69 116.63,29.56 116.38,29.8 114.8,29.8 v2(113.64,28.64)
  L4 w0.127: v2(164.13,34.61) 163.83,34.31 155.47,34.31 153.85,32.68 152.27,32.68 151.89,32.3 149.96,32.3 148.99,31.33 147.62,31.33 146.72,30.43 135.66,30.43 132.61,33.48 132.61,34.08 v2(132.05,34.64) ; v2(165.78,36.29) 165.78,37.18 165.95,37.34 165.95,41.46 165.75,41.66 165.75,47.03 167.24,48.52 167.24,52.38 166.57,53.05 166.13,53.05 165.75,53.43 165.75,56.21 167.44,57.9 167.44,59.83 168.73,61.13 168.73,70.53 169.92,71.72 169.92,79 171.04,80.11 171.04,81.5 171.83,82.29 172.49,82.29 172.74,82.54 v2(172.74,82.69)
  L6 w0.102: v2(195.1,40.83) 195.1,40.68 193.88,39.46 193.04,39.46 192.78,39.72 191.84,39.72 191.67,39.54 190.88,39.54 189.96,38.62 188.64,38.62 188.06,38.04 184.86,38.04 184.55,37.74 183.89,37.74 183.49,38.14 181.68,38.14 181.53,37.99 181.52,37.99 181.45,37.91 181.19,37.91 180.47,37.2 179.15,37.2 178.05,36.11 176.48,36.11 175.23,34.87 170.96,34.87 170.3,35.53 169.35,35.53 169.3,35.48 166.98,35.48 166.17,36.29 v2(165.78,36.29) 165.78,35.68 165.48,35.37 165.45,35.37 164.69,34.61 v2(164.13,34.61)
  BOTTOM w0.089: Q2601.6 135.7,36.51 135.13,35.93 134.14,35.93 133.98,35.78 133.98,35.27 133.35,34.64 v1(132.71,34.64) v2(132.05,34.64) ; R2447.2 198.66,36.87 197.89,36.87 197.81,36.8 197.33,36.8 197.08,37.05 197.08,37.81 196.96,37.93 196.96,38.81 197.32,39.18 197.32,39.57 197.1,39.8 197.09,39.8 196.69,40.2 196.69,40.51 196.59,40.61 196.52,40.61 196.16,40.97 196.16,41.01 195.91,41.27 195.55,41.27 195.12,40.83 v2(195.1,40.83) 195.1,39.51 194.52,38.94 Q2604.1 ; v2(172.74,82.69) 172.9,82.85 176.12,82.85 178.05,84.78 178.05,86.4 177.72,86.73 176.76,86.73 176.65,86.83 GPU1.E9 ; CPU1.V3 116.18,37.76 116.18,37.28 116.21,37.18 116.21,36.9 116.18,36.83 116.18,36.63 116.21,36.53 116.21,35.97 116.09,35.85 116.09,33.29 117.14,32.24 117.14,29.71 116.37,28.95 115.14,28.95 114.98,28.79 113.79,28.79 v2(113.64,28.64) 113.42,28.43 RN1807.8
SPI_CLK_CPU: length 22.5
  TOP w0.089: v2(93.01,32.78) 90.78,32.78 89.83,31.83 89.83,31.57 89.83,31.57 v1(89.83,31.51) 90.18,31.16 RN1803.8
  BOTTOM w0.089: CPU1.AV2 105.8,36.84 105.51,36.55 105.51,36.2 104.86,35.55 103.38,35.55 103.29,35.63 101.15,35.63 100.48,34.97 99.44,34.97 97.59,33.11 96.75,33.11 94.75,31.11 93.19,31.11 92.94,31.36 92.94,32.71 v2(93.01,32.78)
SPI_CLK_ROM: length 202.1
  TOP w0.089: RN1803.1 90.77,30.13 90.32,29.68 v2(90.32,29.46)
  L4 w0.127: v2(90.32,29.46) 90.75,29.89 91.13,29.89 91.41,29.61 91.41,29.26 90.75,28.59 86.08,28.59 80.87,23.39 80.87,21.07 80.11,20.31 80.11,17.14 v2(82.37,14.88) 82.37,14.55 82.12,14.29 82.12,13.15 83.16,12.11 92.25,12.11 93.93,10.43 98.52,10.43 100.13,8.83 103.73,8.83 103.74,8.82 105.2,8.82 106.83,7.18 112.89,7.18 113.83,8.12 117.69,8.12 120.3,5.52 121.75,5.52 121.85,5.62 122.24,5.62 122.72,5.13 126.99,5.13 128.09,4.03 129.84,4.03 133.69,4.03 134.01,3.71 152.3,3.71 157.96,9.38 188.21,9.38 189.61,10.77 189.61,11.56 192.04,13.99 192.32,13.99 192.33,13.99 193.24,14.9 193.94,14.9 197.79,18.76 197.79,29.02 194.03,32.78 194.03,33.11 193.53,33.61 193.53,38.14 194.96,39.56 196.25,39.56 196.94,40.25 197.22,40.25 198,41.03 198,42.17 197.69,42.49 v2(197.69,42.99)
  BOTTOM w0.089: RN2502.4 73.23,5.22 73.15,5.3 73.15,7.57 73.83,8.25 74.83,8.25 75.59,9.01 75.59,10.84 77.01,12.26 v1(77.01,12.82) 77.01,14.65 77.46,15.1 82.15,15.1 v2(82.37,14.88) ; RN2406.1 198.43,43.73 v2(197.69,42.99)
SPI_CLK_ROM_R: length 14.2
  BOTTOM w0.089: RN2502.1 74.53,5.54 EC2503.1 74.79,6.7 75.16,6.7 75.25,6.61 75.25,5.49 75.33,5.4 75.75,5.4 75.84,5.49 75.84,6.61 75.93,6.7 80.72,6.7 80.85,6.57 80.85,6.16 80.72,6.04 SKT251.6
SPI_CS_CPU_N0: length 20.2
  TOP w0.089: v2(96.26,29.51) 95.63,28.87 95.63,28.39 95.78,28.24 v1(95.78,27.93) 95.5,27.65 R1812.2
  BOTTOM w0.089: CPU1.AU3 106.49,37.63 106.27,37.41 106.27,37.24 106.25,37.22 106.23,37.13 106.23,35.5 105.24,34.51 100.07,34.51 99.53,33.98 99.52,33.98 97.53,31.99 97.4,31.99 97.16,32.23 97.03,32.23 96.84,32.04 96.84,31.92 97.09,31.67 97.09,31.55 96.9,31.36 96.77,31.36 96.53,31.6 96.4,31.6 96.21,31.41 96.21,31.29 96.46,31.04 96.46,30.92 96.04,30.5 96.04,29.73 v2(96.26,29.51)
SPI_CS_ROM_N0: length 208.3
  TOP w0.089: v2(93.19,28.72) 93.57,28.34 93.57,28.07 R1812.1 ; KBC24.27 197.27,40.64 196.54,41.38 196.54,42.33 v2(196.59,42.38)
  L4 w0.127: v2(196.59,42.38) 196.37,42.16 196.37,40.84 195.9,40.38 194.62,40.38 191.65,37.41 191.65,36.15 191.84,35.96 192.28,35.96 192.4,35.83 192.4,35.58 192.28,35.45 191.84,35.45 191.72,35.32 191.72,32.71 193.25,31.18 193.77,31.18 196.96,27.99 196.96,19.32 193.41,15.76 192.02,15.76 191.49,15.23 191.03,15.23 187.27,11.47 179.25,11.47 178.07,10.29 172.68,10.29 172.05,10.93 171.6,10.93 171.47,10.8 171.47,10.35 171.35,10.23 171.09,10.23 170.97,10.35 170.97,10.8 170.84,10.93 170.59,10.93 170.46,10.8 170.46,10.35 170.33,10.23 170.08,10.23 169.95,10.35 169.95,10.8 169.82,10.93 169.57,10.93 169.44,10.8 169.44,10.35 169.32,10.23 169.06,10.23 168.93,10.35 168.93,10.8 168.81,10.93 168.55,10.93 168.43,10.8 168.43,10.35 168.3,10.23 168.05,10.23 167.92,10.35 167.92,10.8 167.79,10.93 167.54,10.93 167.41,10.8 167.41,10.35 167.28,10.23 167.03,10.23 166.9,10.35 166.9,10.8 166.78,10.93 165.9,10.93 165.2,10.23 157.66,10.23 152.65,5.22 140.94,5.22 140.64,4.92 140.54,4.92 140.46,4.84 134.08,4.84 128.66,4.84 127.72,5.78 127.72,6.45 127.3,6.87 120.11,6.87 118.06,8.93 114.7,8.93 113.75,9.88 109.79,9.88 109.03,10.65 106.48,10.65 105.51,9.68 100.57,9.68 99.01,11.24 94.28,11.24 92.61,12.92 85.65,12.92 v2(84,14.57) 83.83,14.74 83.83,15.9 83.51,16.22 82.19,16.22 80.94,17.48 80.94,19.98 81.68,20.73 81.68,22.11 81.81,22.24 83.24,22.24 84,22.99 84,25.05 86.73,27.78 91.84,27.78 91.97,27.91 91.97,28.59 92.1,28.72 v2(93.19,28.72)
  BOTTOM w0.089: SKT251.1 82.98,8.58 82.8,8.75 82.8,9.59 82.93,9.72 83.87,9.72 83.96,9.63 83.96,9.18 84.05,9.09 84.47,9.09 84.55,9.18 84.55,9.63 84.64,9.72 85.37,9.72 85.49,9.85 85.49,10.13 85.37,10.25 84.02,10.25 83.89,10.38 83.89,11.41 84.09,11.6 84.38,11.6 84.5,11.47 84.5,10.94 84.58,10.86 85.34,10.86 85.47,10.99 85.47,12.09 85.34,12.22 R2501.1 84.95,12.72 85.39,12.72 85.49,12.81 v1(85.49,13.38) 85.49,13.99 85.08,14.4 84.17,14.4 v2(84,14.57)
SPI_HOLD_CPU: length 18.8
  TOP w0.089: v1(95.78,30.06) 95.78,29.71 v2(95.6,29.53) 95.6,29.43 94.88,28.71 R1811.2
  BOTTOM w0.089: CPU1.AU4 106.49,38.18 106.09,37.79 106.09,37.31 106.05,37.15 106.05,35.57 105.19,34.71 99.72,34.71 97.76,32.74 96.9,32.74 95.6,31.45 v2(95.6,29.53)
SPI_HOLD_ROM: length 43.9
  TOP w0.089: v2(93.6,29.25) 93.99,28.86 R1811.1 94,28.64 94.61,29.25 RN1802.4 94.61,30.11 v1(95.81,31.31)
  L4 w0.127: v2(80.06,14.44) 80.06,14.72 78.9,15.88 78.9,16.46 78.89,16.48 78.89,20.84 79.65,21.61 79.65,23.89 86.46,30.7 92.22,30.7 93.32,29.6 93.32,29.53 v2(93.6,29.25)
  BOTTOM w0.089: v2(80.06,14.44) 79.77,14.73 77.61,14.73 77.39,14.51 77.39,12.11 75.97,10.68 75.97,8.87 74.89,7.79 74.1,7.79 R2503.2
SPI_HOLD_ROM_R: length 13.2
  BOTTOM w0.089: SPI25.7 80.14,7.33 80.26,7.46 80.26,9.82 80.14,9.95 79.45,9.95 79.32,9.82 79.32,8.09 79.2,7.97 75.59,7.97 74.95,7.33 R2503.1
SPI_SI_CPU: length 19.4
  TOP w0.089: v2(95.68,34.03) 95.79,34.14 v1(95.79,34.64) 95.45,34.64 95.06,34.24 R1824.2 94.46,33.81 94.46,33.75 94.44,33.72 94.44,32.94 94.03,32.53 R1825.1 94,32.53 93.44,31.97 92.2,31.97 91.92,31.69 RN1803.6
  BOTTOM w0.089: CPU1.AV3 105.8,37.76 105.54,37.5 105.54,36.85 105.33,36.64 105.33,36.28 104.79,35.73 103.45,35.73 103.37,35.81 101.07,35.81 100.43,35.17 99.11,35.17 98.4,34.46 97.13,34.46 96.7,34.03 v2(95.68,34.03)
SPI_SI_ROM: length 198.8
  TOP w0.089: v2(92.23,29.43) 92.23,29.48 91.92,29.79 RN1803.3
  L4 w0.127: v2(92.23,29.43) 90.98,28.19 86.56,28.19 81.28,22.9 81.28,20.9 80.53,20.15 80.53,17.31 82.51,15.33 82.55,15.33 v2(83.01,14.88) 83.01,14.6 82.54,14.13 82.54,13.6 83.62,12.51 92.43,12.51 94.11,10.84 98.83,10.84 100.39,9.28 113.78,9.28 114.53,8.53 117.88,8.53 120.48,5.92 121.58,5.92 121.68,6.02 122.41,6.02 122.68,5.76 127.17,5.76 128.49,4.44 132.6,4.44 132.6,4.44 133.86,4.44 134.17,4.12 152.13,4.12 157.83,9.82 178.2,9.82 179.45,11.07 187.53,11.07 190.86,14.39 192.15,14.39 193.09,15.33 193.79,15.33 197.39,18.93 197.39,28.76 193.62,32.53 193.62,32.94 193.13,33.43 193.13,38.31 194.79,39.97 196.09,39.97 197,40.89 v2(197,41.62)
  BOTTOM w0.089: v2(83.01,14.88) 82.41,15.47 77.31,15.47 76.63,14.79 v1(76.63,14.29) 76.63,12.41 75.21,10.99 75.21,9.15 74.69,8.63 73.69,8.63 72.78,7.72 72.78,5.13 73.2,4.72 RN2502.3 ; v2(197,41.62) 197,42.23 197.21,42.44 197.23,42.44 197.3,42.51 197.98,42.51 R2405.1
SPI_SI_ROM_R: length 16.9
  BOTTOM w0.089: SPI25.5 78.67,4.79 78.75,4.7 78.75,4.35 78.84,4.26 79.26,4.26 79.35,4.35 79.35,4.7 79.44,4.79 80.77,4.79 80.9,4.92 80.9,5.27 80.77,5.4 76.27,5.4 76,5.12 76,4.39 75.72,4.11 74.17,4.11 73.68,3.62 EC2501.1 ; EC2501.1 73.62,4.12 RN2502.2 ; EC2501.1 73.1,3.62 72.97,3.5 72.97,2.79 73.35,2.4 73.63,2.4 v1(73.69,2.47)
SPI_SO_CPU: length 20.1
  TOP w0.089: RN1803.7 91.42,31.72 92.05,32.35 93.27,32.35 93.55,32.63 93.55,33.16 v2(93.52,33.19)
  BOTTOM w0.089: v2(93.52,33.19) 93.94,33.6 94.06,33.6 94.35,33.31 94.53,33.31 94.73,33.51 94.73,33.69 94.44,33.98 94.44,34.72 96.62,36.9 v1(99.36,36.9) 99.44,36.9 99.69,36.64 99.69,36.26 100.03,35.93 100.68,35.93 100.94,36.19 103.5,36.19 103.6,36.08 103.88,36.08 104.06,36.27 104.06,36.59 104.21,36.75 104.21,37.08 104.45,37.31 104.68,37.31 105.04,37.67 CPU1.AW3
SPI_SO_ROM: length 192.3
  TOP w0.089: v1(89.68,29.32) 89.8,29.32 90.09,29.02 90.55,29.02 v2(90.96,29.43) 91.06,29.43 91.42,29.79 RN1803.2
  L4 w0.127: v2(90.96,29.43) 90.52,29 89.88,29 89.75,29.13 89.75,29.66 89.62,29.79 89.37,29.79 89.24,29.66 89.24,29.13 89.11,29 88.86,29 88.73,29.13 88.73,29.66 88.61,29.79 88.35,29.79 88.23,29.66 88.23,29.13 88.1,29 87.84,29 87.72,29.13 87.72,29.66 87.59,29.79 87.34,29.79 87.21,29.66 87.21,29.13 87.08,29 85.91,29 80.47,23.56 80.47,21.25 79.7,20.49 79.7,16.96 81.71,14.95 v2(81.71,14.6) 81.71,12.98 83,11.69 92.09,11.69 93.75,10.02 98.35,10.02 99.96,8.41 105.03,8.41 106.67,6.77 113.05,6.77 113.96,7.67 117.56,7.67 120.51,4.73 126.8,4.73 127.9,3.62 130.01,3.62 133.25,3.62 133.69,3.18 152.39,3.18 157.96,8.75 158,8.75 158.22,8.97 188.38,8.97 190.02,10.6 190.02,11.39 192.2,13.58 193.36,13.58 198.2,18.42 198.2,29.2 194.44,32.96 194.44,33.29 193.94,33.79 193.94,37.97 195.08,39.11 196.55,39.11 196.71,38.94 197.09,38.94 197.36,39.21 197.36,39.81 198.41,40.86 198.41,42.63 198.14,42.89 198.14,43.81 v2(197.99,43.96)
  BOTTOM w0.089: v2(197.99,43.96) 198.27,44.23 RN2406.2 ; RN2503.2 82.4,13.17 82.4,13.76 81.71,14.46 v2(81.71,14.6)
SPI_SO_ROM_R: length 16.7
  BOTTOM w0.089: RN2503.3 82.62,12.34 83.5,12.34 EC2502.1 83.62,11.65 83.18,11.22 82.81,11.22 82.73,11.31 82.73,11.75 82.6,11.88 82.35,11.88 82.22,11.75 82.22,11.35 82.09,11.22 81.94,11.22 81.81,11.09 81.81,10.82 81.97,10.66 83.28,10.66 83.41,10.53 83.41,10.23 83.28,10.1 82.35,10.1 82.22,9.97 82.22,8.3 82.35,8.17 82.83,8.17 82.95,8.04 82.95,7.85 82.87,7.76 82.31,7.76 82.22,7.68 82.22,7.27 82.05,7.1 81.9,7.1 81.81,7.01 81.81,6.66 82.07,6.4 82.81,6.4 82.93,6.52 82.93,7.18 83.06,7.31 SKT251.2
SPI_WP_CPU: length 16
  TOP w0.089: v2(93.37,31.54) 92.99,31.16 RN1803.5
  BOTTOM w0.089: CPU1.AW2 105.13,37.02 104.7,36.59 104.7,36.27 104.33,35.91 103.53,35.91 103.43,36.01 101.01,36.01 100.53,35.53 v1(99.39,35.53) 99.08,35.53 98.84,35.77 97.91,35.77 96.72,34.59 95.64,34.59 95.25,34.2 95.25,33.42 v2(93.37,31.54)
SPI_WP_ROM: length 31
  TOP w0.089: v2(92.86,29.43) 92.57,29.72 RN1803.4 92.76,30 RN1802.3
  L4 w0.127: v2(92.86,29.43) 92,30.29 86.63,30.29 80.06,23.72 80.06,21.43 79.3,20.67 79.3,16.73 81.08,14.95 81.08,14.22 v2(81.25,14.04)
  BOTTOM w0.089: RN2503.1 81.92,13.73 81.61,14.04 v2(81.25,14.04) v1(80.67,14.04)
SPI_WP_ROM_R: length 13.7
  BOTTOM w0.089: SKT251.3 81.91,6.04 81.09,6.86 81.09,7.29 81.18,7.38 81.62,7.38 81.71,7.47 81.71,7.74 81.62,7.83 81.18,7.83 81.09,7.91 81.09,8.18 81.18,8.27 81.62,8.27 81.71,8.36 81.71,8.63 81.62,8.71 81.18,8.71 81.09,8.8 81.09,9.07 81.18,9.16 81.62,9.16 81.71,9.25 81.71,9.51 81.62,9.6 81.18,9.6 81.09,9.69 81.09,9.96 81.18,10.05 81.62,10.05 81.71,10.14 81.71,10.4 81.62,10.49 81.18,10.49 81.09,10.58 81.09,11.15 81.92,11.98 RN2503.4
SPK_DET#: length 135.4
  TOP w0.127: v2(114.58,34.23) 115.21,33.6 115.21,32.78 114.96,32.53 109.75,32.53 109.5,32.78 109.5,34.43 109.24,34.69 108.71,34.69 107.95,35.45 107.95,35.49 107.68,35.75 107.16,35.75 v2(106.22,34.81) ; v2(31.32,14.27) 31.39,14.27 32.97,15.84 35.28,15.84 35.77,16.33 37.9,16.33 38.02,16.22 39.55,16.22 41.6,18.27 42.34,18.27 45.9,21.84 46.44,21.84 47.06,22.46 47.06,23.26 47.88,24.07 v1(48.21,24.07) 48.46,24.07 v2(49.45,25.06)
  L6 w0.127: v2(11.2,7.84) 12.71,9.35 28.37,9.35 29.54,10.52 29.54,10.96 31.32,12.74 v2(31.32,14.27) ; v2(49.45,25.06) 48.96,24.57 48.96,23.43 50.75,21.63 51.79,21.63 54.46,18.97 55.65,18.97 55.71,19.03 65.42,19.03 66.71,17.73 70.52,17.73 73.33,20.54 74.14,20.54 75.59,21.99 76.73,21.99 77.93,23.18 78.46,23.18 86.84,31.56 92.43,31.56 93.39,32.53 94.51,32.53 95.55,33.57 95.96,33.57 97.08,34.69 105.17,34.69 105.29,34.81 v2(106.22,34.81)
  BOTTOM w0.089: v2(114.58,34.23) 114.55,34.23 114.32,34.46 114.32,36.27 CPU1.AB1
  BOTTOM w0.127: R2047.2 115.11,32.41 115.11,33.87 114.76,34.23 v2(114.58,34.23) ; SPK1.5 v2(11.2,7.84)
SPKR: length 94.8
  TOP w0.254: v2(32.51,14.37) 33.53,15.38 35.46,15.38 35.96,15.89 37.72,15.89 37.83,15.77 39.73,15.77 41.77,17.81 42.51,17.81 42.53,17.83 46.02,21.33 v1(46.4,21.33) 46.56,21.33 47.55,22.32 47.55,23.08 48.08,23.61 v2(49.4,23.61) ; v2(89.81,34.87) 90.14,34.87 90.32,34.69 90.83,34.69 92.45,36.31 92.45,36.97 92.33,37.1 92.33,37.72 R2006.2 92.56,37.74 93.33,36.96 96.35,36.96 97.93,38.54 101.15,38.54 101.65,38.04 101.65,38.01 101.94,37.72 103.9,37.72 104.75,38.58 105.38,38.58 v2(105.51,38.45)
  L6 w0.254: v2(49.4,23.61) 50.93,22.09 53.19,22.09 54.3,20.97 61.06,20.97 61.31,20.72 65.3,20.72 65.56,20.46 67.41,20.46 67.65,20.7 69.41,20.7 69.47,20.64 70.66,20.64 71.78,21.76 73.61,21.76 76.68,24.83 78.2,24.83 86.16,32.78 87.73,32.78 v2(89.81,34.87)
  BOTTOM w0.254: v2(32.51,14.37) 32.73,14.14 32.73,12.2 32.28,11.75 32.28,11.29 32.1,11.1 31.19,11.1 31.07,11.23 RN2701.2 ; CPU1.AW5 105.51,38.75 v2(105.51,38.45)
SRTC_RST#: length 84
  TOP w0.127: v2(69.67,3.98) 70.03,3.62 C1805.1 EC1806.1 69.12,3.27 68.67,3.27 68.65,3.28 68.64,3.28 v1(68.25,3.67) 68.25,4.23 68.63,4.62 RN1801.4
  L3 w0.127: v2(71.91,19.83) 72.16,19.83 73.48,21.15 80.54,21.15 81.23,21.84 83.59,21.84 84.24,22.48 88.17,22.48 89.09,21.57 89.93,21.57 v2(90.3,21.94) ; v2(97.94,30.8) 98.97,30.8 101.6,33.43 102.46,33.43 103.66,34.63 103.66,44.34 106.55,47.24 108.27,47.24 v2(108.68,46.83)
  L4 w0.127: v2(71.91,19.83) 72.34,19.4 72.34,19.02 74.17,17.19 74.17,15.31 72.03,13.17 72.03,10.89 71.36,10.21 71.36,8.44 72.38,7.42 72.38,6.34 70.46,4.42 70.11,4.42 v2(69.67,3.98)
  BOTTOM w0.127: CPU1.AN18 109,46.5 v2(108.68,46.83) ; v2(90.3,21.94) 90.74,21.49 95.59,21.49 96.75,22.65 96.75,27.17 97.94,28.36 v2(97.94,30.8)
SSD_PEDET: length 4.1
  TOP w0.127: v2(193.6,14.44) 193.98,14.06 R6305.1 194.8,15.14 AFTP6303.1
  BOTTOM w0.127: v2(193.6,14.44) 193.6,14.44 SSD1.69
SUS_STAT#/LPCPD#: length 33.3
  TOP w0.127: v2(96.95,41.52) 96.35,41.52 95.46,42.41 93.14,42.41 91.39,40.66 91.39,40.28 87.57,36.46 87.57,29.97 v1(87.86,29.68) 90.45,27.09 90.45,24.79 R1814.2
  BOTTOM w0.127: v2(96.95,41.52) 99.03,41.52 99.85,42.33 101.5,42.33 101.83,42.66 102.97,42.66 103.12,42.82 103.45,42.82 103.58,42.69 103.77,42.69 CPU1.BA11
SUSACK#: length 2.2
  TOP w0.127: v2(111.5,21.02) 111.15,21.38 TP1711.1
  BOTTOM w0.127: v2(111.5,21.02) 111.35,21.17 111.35,22.09 RN1702.2
SUSACK#_R: length 25.9
  TOP w0.127: v1(109.35,24.15) v2(109.35,24.71)
  L4 w0.127: v2(109.35,24.71) 109.35,25.39 109.9,25.95 109.9,30.17 111.4,31.67 111.4,32.73 111.1,33.04 111.1,35.25 111.17,35.32 111.17,37.05 110.84,37.38 110.84,38.75 111.17,39.08 111.17,41.85 110.29,42.74 109.16,42.74 108.7,42.28 v2(108.68,42.28)
  BOTTOM w0.127: v2(109.35,24.71) 109.4,24.76 111.01,24.76 R1708.2 111.12,24.64 111.12,23.74 111.36,23.51 RN1702.3 ; v2(108.68,42.28) 108.65,42.28 108.35,42.58 CPU1.AP11
SUSCLK: length 1.8
  TOP w0.089: TP1807.1 94.99,48.39 94.63,48.76 94.26,48.76 93.94,49.08 R1813.2
SUSCLK_R: length 12.4
  TOP w0.089: v2(100.81,45.86) 100.73,45.86 100.46,46.14 96.87,46.14 v1(96.16,46.85) 95.43,47.59 95.43,48.52 94.83,49.11 R1813.1 EC1803.2
  BOTTOM w0.089: CPU1.BA17 103.68,45.88 103.13,45.88 103.09,45.91 102.72,45.91 102.61,46.02 101.75,46.02 101.7,46.07 101.12,46.07 100.91,45.86 v2(100.81,45.86)
SWCLK: length 3.1
  TOP w0.127: U6901.37 42.23,32.47 42.82,33.06 42.82,34.64 TP6904.1
SWDIO: length 3.7
  TOP w0.127: U6901.34 43.68,30.67 44.14,31.14 44.14,31.49 44.5,31.84 45.01,31.84 TP6903.1
SYS_PRES1#: length 3.9
  TOP w0.102: R4301.2 167.4,25.02 v2(167.31,25.11) 167.94,25.75 AFTP4315.1
  BOTTOM w0.102: BATT1.7 167.7,25.5 v2(167.31,25.11)
SYS_PWROK: length 80.8
  TOP w0.127: v2(126.82,38.02) v1(124.99,38.02) 123.94,38.02 EC1702.1 123.89,37.15 R1717.1 ; v2(179.53,29.58) 180.18,30.24 180.95,30.24 181.11,30.08 182.22,30.08 182.39,30.24 KBC24.96
  L4 w0.127: v2(126.82,38.02) 124.97,36.16 124.97,32.91 125.7,32.17 125.7,28.6 127.75,26.56 136.38,26.56 136.73,26.9 137.91,26.9 138.51,27.51 138.51,28.4 139.78,29.67 147.41,29.67 148.31,30.57 149.35,30.57 150.2,31.42 152.03,31.42 152.06,31.4 153.78,31.4 154.3,31.92 160.05,31.92 160.57,32.44 161.78,32.44 v2(162.23,32)
  L6 w0.127: v2(162.23,32) 162.36,32.12 162.71,32.12 162.96,31.87 167.08,31.87 167.44,32.22 168.13,32.22 169.48,30.88 175.46,30.88 176.2,30.14 177.75,30.14 178.48,29.4 179.35,29.4 v2(179.53,29.58)
  BOTTOM w0.127: v2(126.82,38.02) 126.82,38.7 126.59,38.93 126.41,38.93 125.82,39.52 125.22,39.52 CPU1.B6
T_CRIT#: length 2.4
  BOTTOM w0.102: R2601.1 R2604.2 139.62,23.22 THM261.4
THERM_SYS_SHDN#: length 7.9
  BOTTOM w0.102: R2602.1 143.66,21.19 143.66,21.86 143.79,21.99 143.99,21.99 144.19,22.19 144.19,23.54 143.91,23.82 142.72,23.82 141.77,22.86 Q2602.S 140.99,22.86 R2601.2
THM_SML1_CLK: length 22.9
  TOP w0.089: v2(138.17,23.82) 137.96,24.03 C2608.1
  BOTTOM w0.089: Q2601.4 134.4,38 134.77,38.37 v1(135.13,38.37) 135.46,38.37 136.09,37.74 136.09,34.05 136.24,33.9 136.24,33.19 136.05,32.99 RN2602.4 135.69,32.99 133.65,30.95 133.65,28.52 134.4,27.77 134.4,26.91 134.71,26.6 THM261.8 136.16,26.6 136.45,26.31 136.45,25.42 137.49,24.38 137.54,24.38 138.1,23.82 v2(138.17,23.82)
THM_SML1_DATA: length 14.8
  TOP w0.089: v2(134.24,25.42) 134.28,25.42 v1(134.76,24.94) C2609.1
  BOTTOM w0.089: THM261.7 134.89,25.95 134.36,25.42 v2(134.24,25.42) 134.13,25.53 134.13,27.66 133.39,28.4 133.39,31.07 135.18,32.86 135.18,33.44 135.38,33.64 RN2602.3 Q2601.1
TOUCH_PANEL_INTR#: length 278.1
  TOP w0.127: v2(123.32,33.77) 123.32,33.21 121.13,31.03 121.13,29.89 120.83,29.58 119.2,29.58 v1(118.77,30.01) 117.45,31.33 108.68,31.33 108.2,31.82 108.2,32.2 105.31,35.09 v2(102.69,35.09)
  L3 w0.127: v2(130.71,8.12) 130.66,8.17 130.17,8.17 128.36,9.99 128.36,11.84 127.07,13.12 127.07,14.8 126.16,15.71 126.16,18.58 121.16,23.58 121.16,23.59 120.96,23.8 120.96,29.42 121.21,29.67 121.21,31.87 123.11,33.77 v2(123.32,33.77) ; v2(82.53,22.77) 83.55,22.77 83.95,23.17 88.76,23.17 88.99,22.94 91.39,22.94 92.26,23.82 92.26,26.82 94.71,29.27 94.71,30.17 99,34.46 102.06,34.46 v2(102.69,35.09)
  L4 w0.127: v2(81.74,92.37) 81.68,92.42 80.77,92.42 80.31,91.96 80.31,91 79.58,90.26 76.33,90.26 76.07,90.52 76.07,90.95 73.76,93.26 71.88,93.26 71.52,93.62 v2(71.52,93.9) ; v2(185.72,37.3) 185.72,37.21 185.28,36.76 185.28,35.01 186.75,33.54 186.75,30.81 186.02,30.08 186.02,29.7 186.66,29.05 187.68,29.05 188.58,28.15 188.58,26.6 189.15,26.03 189.15,25.72 191.93,22.94 191.93,19.89 188.49,16.45 186.97,16.45 186.28,15.76 179.4,15.76 178.94,15.31 177.14,15.31 176.66,14.82 175.03,14.82 173.79,13.58 164.9,13.58 164.08,12.77 156.54,12.77 152.22,8.45 140.38,8.45 140.02,8.08 130.8,8.08 130.76,8.12 v2(130.71,8.12)
  BOTTOM w0.127: v2(123.32,33.77) 123.32,34.23 122.96,34.59 122.96,34.94 123.19,35.17 124.08,35.17 124.13,35.12 126.53,35.12 127.23,35.81 127.23,38.6 126.67,39.16 126.52,39.16 125.91,39.76 CPU1.A7 ; TCBD1.32 70.65,93.43 71.12,93.9 v2(71.52,93.9) ; v2(185.72,37.3) 185.34,37.68 D2402.A 186.71,38.02 186.92,38.22 186.92,38.37 187.04,38.5 188.21,38.5 188.22,38.49 R2429.1 ; v2(82.53,22.77) 81.14,24.16 81.14,48.09 85.16,52.12 85.16,90.59 85.01,90.75 85.01,91.81 84.55,92.27 83.62,92.27 83.44,92.45 81.81,92.45 v2(81.74,92.37)
TOUCHPAD_INTR#: length 61.9
  TOP w0.102: v2(95.96,26.89) 98.57,26.89 99.18,26.28 99.18,25.24 100.71,23.71 100.71,21.99 101.27,21.43 101.5,21.43 102.05,20.87 103.17,20.87 103.86,21.56 107.58,21.56 108.26,20.87 110.99,20.87 111.27,20.59 111.57,20.59 112.44,19.72 112.44,19.27 112.8,18.91 112.8,18.84 113.48,18.15 121.51,18.15 v1(122.18,17.48) 122.86,16.81 v2(122.86,15.87)
  BOTTOM w0.102: D401.A 121.23,12.97 120.83,13.38 120.83,14.33 120.88,14.38 R404.2 R405.2 122.05,14.38 R410.2 122.85,15.85 v2(122.86,15.87) ; CPU1.BA5 103.58,38.6 103.22,38.6 102.26,37.63 96.75,37.63 92.56,33.44 92.56,31.21 93.04,30.73 93.98,30.73 94.99,29.71 94.99,27.3 95.4,26.89 v2(95.96,26.89)
TP1_AY4: length 3.8
  TOP w0.102: TP610.1 v2(101.85,37.23)
  BOTTOM w0.102: CPU1.AY4 104.56,38.41 104.16,38.02 103.83,38.02 103.66,37.84 103.07,37.84 102.64,37.41 102.11,37.41 101.93,37.23 v2(101.85,37.23)
TP2_BB3: length 3.3
  TOP w0.102: v2(101.22,37.15) 101.14,37.23 TP611.1
  BOTTOM w0.102: v2(101.22,37.15) 101.34,37.15 101.67,36.82 101.98,36.82 102,36.85 102.5,36.85 103.16,37.51 CPU1.BB3
TP4_BB5: length 1.5
  TOP w0.102: TP609.1 102.89,38.4 v2(102.64,38.65)
  BOTTOM w0.102: CPU1.BB5 103.14,38.92 102.87,38.65 v2(102.64,38.65)
TP5_AU5: length 1.2
  TOP w0.102: TP607.1 106.42,39.21 v2(106.73,39.51)
  BOTTOM w0.102: v2(106.73,39.51) 106.4,39.19 CPU1.AU5
TP6_AT5: length 1.2
  TOP w0.102: v2(107.38,39.51) 107.7,39.83 TP608.1
  BOTTOM w0.102: v2(107.38,39.51) 107.05,39.19 CPU1.AT5
TP_EN#: length 111.9
  TOP w0.127: RN2405.4 173.93,44.02 174.95,43 174.95,42.66 174.98,42.63 174.98,40.78 175.68,40.07 177.33,40.07 178.08,39.32 178.67,39.32 179.04,39.7 179.04,41.93 179.63,42.51 v2(179.63,43.15) ; KBC24.49 190.81,43.02 v2(190.37,42.59) ; v1(119.51,22.98) v2(118.95,22.98)
  L4 w0.127: v2(167.64,45.18) 166.99,44.53 166.99,42.94 167.69,42.24 167.69,36.36 167.57,36.25 167.57,35.41 167.7,35.29 167.7,34.35 166.43,33.09 166.3,33.09 162.73,29.52 162.6,29.52 159.83,29.52 159.68,29.67 155.51,29.67 154.84,29 151.92,29 151.59,28.67 150.59,28.67 148.66,26.74 144.91,26.74 144.42,26.25 143.89,26.25 142.26,24.63 140.95,24.63 138.98,22.66 138.11,22.66 137.76,22.31 133.41,22.31 132.9,22.81 131.35,22.81 130.57,23.6 126.53,23.6 125.25,22.32 122.35,22.32 121.68,22.17 121.42,22.17 121.25,22.23 121.21,22.24 120.47,22.98 v2(118.95,22.98)
  L6 w0.127: v2(190.37,42.59) 190.37,42.28 190.41,42.24 190.41,41.87 190.15,41.61 188.45,41.61 188.15,41.3 184.72,41.3 184.69,41.28 182.92,41.28 181.37,42.84 181.37,43.06 180.99,43.44 179.92,43.44 v2(179.63,43.15) 179.22,43.15 179.04,43.32 178.59,43.32 177.86,42.6 172.1,42.6 171.87,42.83 169.62,42.83 168.81,43.64 168.81,44.01 v2(167.64,45.18)
  BOTTOM w0.127: R6504.1 117.13,20.93 117.35,21.15 117.85,21.15 118.26,21.56 118.26,22.62 118.64,23 118.92,23 v2(118.95,22.98)
TP_ON#_GATE: length 5.9
  BOTTOM w0.127: Q6503.G 120.89,18.55 v1(120.17,19.27) 120.15,19.28 Q6502.G 120.15,21.04 119.68,21.51 119.01,21.51 C6502.2 118.02,20.51 R6504.2
TP_VDD: length 0.7
  BOTTOM w0.305: KBBD1.44 128.55,18.89
  vias: v2(131.37,19.12) v3(125.91,20.13) v3(126.52,19.52)
TPAN_VDD: length 15.3
  TOP w0.457: C5516.1 65.73,99.18 67.35,100.79 C5517.1
  TOP w0.508: R5507.2 69.95,100.98 69.54,101.39 67.91,101.39 C5517.1 ; v1(67.89,93.36) v2(67.89,93.92) 67.89,94.4 F5501.2 68.65,96.56 68.29,96.93 67.42,96.93 65.81,98.54 C5516.1
  BOTTOM w0.305: TCBD1.27 68.15,93.66 v2(67.89,93.92) 67.65,93.68 TCBD1.26
TPCLK_C: length 4.2
  TOP w0.089: AFTP6532.1 128.34,15.61 v2(128.93,16.2) 128.9,16.22 128.9,17.14 128.88,17.16 RN6502.3
  BOTTOM w0.089: KBBD1.43 129.05,16.32 v2(128.93,16.2)
TPDATA_C: length 4.3
  TOP w0.089: RN6502.4 129.53,16.23 v2(129.56,16.2) 130.22,15.54 AFTP6533.1
  BOTTOM w0.089: KBBD1.42 129.55,16.18 v2(129.56,16.2)
TPS70933_EN: length 4
  TOP w0.127: R3715.2 20.31,96 R3716.1 C3708.1 21.26,97.77 v1(21.26,98.57) 21.5,98.81 U3702.4
TS#_DIMM0_1: length 6.5
  TOP w0.127: R1215.2 63.68,52.54 v1(62.89,52.54) 62.63,52.54 v2(62,51.91)
  BOTTOM w0.127: DM1.134 62.9,54.23 62,53.34 v2(62,51.91)
TS#_DIMM1_1: length 3.4
  TOP w0.127: v2(49.49,54.84) v1(50.03,55.37) 50.53,55.87 R1312.2
  BOTTOM w0.127: v2(49.49,54.84) 49.49,54.81 49.88,54.42 50.89,54.42 DM2.134
TYPEC_5V: length 3.3
  TOP w0.254: PQ4309.3 45.17,88.19 45.76,87.61 46.71,87.61 PR4339.2
TYPEC_5V_SW:
  vias: v1(46.94,83.61)
TYPEC_5V_SW_R: length 12
  TOP w0.254: v2(44.27,82.54) 44.16,82.43 PU4306.4 ; PU4305.4 46.64,85.9 PR4330.1 ; PR4330.1 PR4339.1 47.86,85.88 48.37,85.37 PC4312.1 ; PR4330.1 46.66,86.76 v1(46.63,86.78) 46.38,87.04 v2(46,87.04)
  BOTTOM w0.254: v2(46,87.04) 46,84.27 v2(44.27,82.54)
TYPEC_CON_RXN1: length 16.7
  TOP w0.102: 17.69,93.52 16.34,92.17 14.68,92.17 14.57,92.28 EU3801.5 EU3801.6 13.65,92.28 13.51,92.14 13.14,92.14 13.01,92.27 6.2,92.27 USB1.B10 ; 17.69,93.52 17.89,93.72 19.3,93.72 19.7,93.32 21.03,93.32 R3835.2 ; 17.69,93.52 v1(17.6,93.62)
TYPEC_CON_RXN2: length 10.3
  TOP w0.102: R3837.2 16.74,97.01 16.08,97.01 15.42,97.67 14.53,97.67 14.38,97.52 EU3802.1 EU3802.9 13.44,97.52 13.36,97.6 11.17,97.6 11.04,97.48 10.16,97.48 v2(9.75,97.07)
  BOTTOM w0.102: USB1.A10 8.31,95.96 8.58,96.23 8.86,96.23 9.7,97.07 v2(9.75,97.07)
TYPEC_CON_RXP1: length 16.7
  TOP w0.102: v1(15.39,91.81) 15.39,91.94 ; 15.39,91.94 16.43,91.94 17.98,93.49 19.21,93.49 19.6,93.1 21.03,93.1 R3834.2 ; 15.39,91.94 14.65,91.94 14.52,91.8 EU3801.4 EU3801.7 13.62,91.8 13.51,91.91 13.05,91.91 12.92,92.04 6.29,92.04 USB1.B11
TYPEC_CON_RXP2: length 10.5
  TOP w0.102: v1(15.75,97.86) 15.65,97.76 ; 15.65,97.76 15.52,97.89 14.43,97.89 EU3802.2 EU3802.8 13.52,97.99 13.36,97.83 11.07,97.83 10.95,97.71 v2(9.65,97.71) ; 15.65,97.76 16.18,97.24 16.74,97.24 R3836.2
  BOTTOM w0.102: v2(9.65,97.71) 9.22,97.27 9.22,96.91 8.77,96.46 USB1.A11
TYPEC_CON_TXN1: length 12.2
  TOP w0.102: R3833.2 17.92,92.29 17.48,92.29 16.93,91.75 ; v1(16.84,91.84) 16.93,91.75 ; 16.93,91.75 15.84,90.65 14.46,90.65 EU3801.2 EU3801.8 13.6,90.75 13.49,90.64 12.62,90.64 12.24,91.02 11.5,91.02 v2(11.3,91.23)
  BOTTOM w0.102: v2(11.3,91.23) 11.1,91.02 10.59,91.02 9.29,92.32 8.52,92.32 8.38,92.46 USB1.A3
TYPEC_CON_TXN2: length 12.3
  TOP w0.102: USB1.B3 6.2,96.16 8.53,96.16 9.04,96.67 9.04,97.72 10.47,99.15 13.51,99.15 13.62,99.04 EU3802.7 EU3802.4 14.4,99.04 14.53,99.17 15.82,99.17 R3839.2
TYPEC_CON_TXP1: length 12.3
  TOP w0.102: v2(11.3,90.59) 11.5,90.8 12.15,90.8 12.53,90.42 13.49,90.42 13.62,90.28 EU3801.9 EU3801.1 14.5,90.42 15.44,90.42 ; 15.44,90.42 v1(15.44,90.29) ; 15.44,90.42 15.93,90.42 17.58,92.07 17.94,92.07 R3832.2
  BOTTOM w0.102: v2(11.3,90.59) 11.1,90.8 10.5,90.8 9.2,92.1 8.52,92.1 8.38,91.96 USB1.A2
TYPEC_CON_TXP2: length 12.4
  TOP w0.102: R3838.2 15.82,99.39 14.5,99.39 14.38,99.52 EU3802.5 EU3802.6 13.62,99.52 13.49,99.38 10.38,99.38 8.81,97.81 8.81,96.77 8.43,96.38 6.28,96.38 USB1.B2
U3703_OUT:
  vias: v1(28.9,44.47)
U3704_OUT:
  vias: v1(24.26,47.39)
U4006_CT: length 2.1
  BOTTOM w0.127: C4017.1 110.09,18.03 110.09,16.59 109.9,16.4 U4006.6
U4101_OUT:
  vias: v1(112.4,9.44)
U4301_IN: length 9.3
  BOTTOM w0.127: PR4329.1 29.45,95.28 30.14,94.59 30.14,94.43 PR4331.2 30.68,93.88 30.68,93.01 30.15,92.47 30.15,91.99 30.55,91.58 30.55,90.85 30.1,90.39 29.16,90.39 27.96,91.58 U4301.5
UART0_CTS#: length 2.1
  TOP w0.089: v2(116.36,38.68) 116.38,38.68 116.89,39.18 TP2014.1
  BOTTOM w0.089: v2(116.36,38.68) 116.38,38.68 116.71,38.35 CPU1.U4
UART0_RTS#: length 4.5
  TOP w0.089: v2(116.97,34.18) 116.48,34.18 TP2013.1
  BOTTOM w0.089: CPU1.U3 117.1,37.52 117.49,37.13 117.49,36.69 117.54,36.5 117.54,36.28 117.5,36.15 117.5,35.48 117.45,35.42 117.45,34.61 117.02,34.18 v2(116.97,34.18)
UART0_TXD: length 4.5
  TOP w0.089: TP2012.1 115.67,34.81 v2(116.91,34.81)
  BOTTOM w0.089: CPU1.U2 117.31,36.83 117.31,36.67 117.36,36.48 117.36,36.31 117.32,36.18 117.32,35.63 117.32,35.63 117.32,35.55 117.27,35.5 117.27,35.17 v2(116.91,34.81)
UART1_CTS#: length 5.9
  TOP w0.089: TP2017.1 114.81,33.42 v2(114.7,33.52)
  BOTTOM w0.089: v2(114.7,33.52) 114.68,33.54 114.63,33.54 114.15,34.03 114.15,36.41 114.22,36.58 114.22,36.86 114.19,36.95 114.19,37.15 114.22,37.23 114.22,37.51 114.19,37.6 114.19,38.09 CPU1.AB4
UART1_RTS#: length 4.8
  TOP w0.089: v2(113.74,34.13) 113.31,34.56 TP2016.1
  BOTTOM w0.089: v2(113.74,34.13) 113.74,34.15 113.97,34.38 113.97,36.45 114.04,36.62 114.04,36.82 114.01,36.9 114.01,37.19 114.04,37.27 114.04,37.47 114,37.57 114,37.74 113.83,37.97 CPU1.AC3
USB2_ID: length 18.4
  TOP w0.102: RN1602.1 v1(113.91,23.97) 113.91,24.52 v2(114.93,25.54)
  L4 w0.102: v2(114.93,25.54) 114.35,26.13 114.35,30.32 112.32,32.35 112.32,33.24 113.08,34 113.08,36.92 112.29,37.71 112.29,37.84 v2(112.27,37.86)
  BOTTOM w0.102: CPU1.AG3 112.1,37.7 v2(112.27,37.86)
USB2_VBUSSENSE: length 21.3
  TOP w0.102: v2(114.88,24.27) 115.11,24.05 v1(115.11,22.7) 115.11,21.81 114.86,21.56 113.46,21.56 113.26,21.75 RN1602.2
  L4 w0.102: v2(114.88,24.27) 114.15,25.01 114.15,30.16 112.06,32.25 112.06,36.29 111.56,36.8 111.56,37.81 111.3,38.07 v2(111.3,38.55)
  BOTTOM w0.102: v2(111.3,38.55) 111.5,38.35 CPU1.AG4
USB20_DN0_C: length 13.5
  BOTTOM w0.102: v1(24.64,54.5) 24.64,53.59 24.45,53.4 TR3602.2 24.14,53.93 23.91,54.15 23.91,54.51 23.52,54.91 22.87,54.91 22.55,54.59 22.55,54.22 22.27,53.94 21.89,53.94 21.66,54.17 EU3602.1 21.42,53.94 21.16,53.94 20.42,54.68 18.02,54.68 16.55,53.21 15.87,53.21 15.7,53.38 USB2.2
USB20_DN1_C: length 12.1
  BOTTOM w0.102: 22.34,32.16 22.45,32.04 22.45,30.97 22.55,30.87 23.61,30.87 23.71,30.97 23.71,31.07 23.48,31.3 TR3603.2 ; 22.34,32.16 21.81,32.68 20.22,32.68 19.51,31.97 18.9,31.97 18.65,32.21 EU3604.1 18.3,31.97 17.09,31.97 16.52,32.54 15.8,32.54 15.7,32.65 USB3.2 ; 22.34,32.16 v1(22.45,32.27)
USB20_DP0_C: length 11.5
  BOTTOM w0.102: USB2.3 18.12,54.45 18.71,54.45 EU3602.6 18.98,54.18 19.25,54.45 20.33,54.45 20.79,53.98 20.82,53.96 20.82,53.95 20.83,53.94 20.83,53.94 21.06,53.71 22.37,53.71 22.78,54.13 22.78,54.5 22.96,54.68 23.21,54.68 ; 23.21,54.68 23.42,54.68 23.68,54.42 23.68,54.15 23.46,53.93 TR3602.3 ; 23.21,54.68 v1(23.21,54.53)
USB20_DP1_C: length 12.5
  BOTTOM w0.102: v1(23.09,30.5) 23.09,30.64 ; 23.09,30.64 22.46,30.64 22.22,30.88 22.22,31.95 21.72,32.45 21.47,32.45 EU3604.6 21.23,32.22 21,32.45 20.31,32.45 19.6,31.74 17,31.74 16.42,32.32 15.8,32.32 15.7,32.21 USB3.3 ; 23.09,30.64 23.7,30.64 23.94,30.88 23.94,31.07 24.16,31.3 TR3603.3
USB30_RX_CPU_N1: length 160.9
  TOP w0.102: 24.31,52.39 23.09,52.39 22.96,52.26 22.96,52.09 22.75,51.88 R3609.1 ; 24.31,52.39 v1(24.31,52.24) ; 24.31,52.39 26.3,52.39 26.44,52.25 26.44,52.01 26.31,51.88 26.16,51.88 26.03,51.76 v2(26.03,51.5)
  L6 w0.127: v2(120.91,40.43) 120.81,40.53 120.54,40.53 120.25,40.24 120.25,38.13 118.73,36.61 118.73,33.74 117.84,32.85 117.84,28.79 116.95,27.9 116.95,22.42 115.02,20.49 115.02,18.57 113.59,17.14 108.43,17.14 107.97,16.68 105.35,16.68 104.79,17.24 92.17,17.24 91.49,17.92 86.56,17.92 86.1,17.47 82.6,17.47 82.04,16.91 81.15,16.91 79.93,15.69 79.53,15.69 73.94,10.1 71.45,10.1 71.12,9.77 68.93,9.77 68.17,10.53 66.55,10.53 65.99,11.09 64.72,11.09 62.69,13.12 61.52,13.12 61.19,13.45 52.28,13.45 49.89,15.84 46.53,15.84 35.25,27.12 35.25,33.68 33.75,35.18 26.76,35.18 22.38,39.56 22.38,41.47 21.21,42.64 21.21,44.62 20.78,45.05 20.78,48.61 23.07,50.91 25.99,50.91 26.22,51.14 26.22,51.31 v2(26.03,51.5)
  BOTTOM w0.102: v2(120.91,40.43) 121.24,40.76 CPU1.H8
USB30_RX_CPU_N2: length 137.6
  TOP w0.102: 26.8,30.93 26.8,30.5 26.33,30.04 23.29,30.04 23.16,29.91 23.16,29.73 22.96,29.53 R3612.1 ; 26.8,30.93 26.8,31.34 27.4,31.95 27.89,31.95 28.01,31.82 28.01,31.51 28.14,31.38 v2(28.55,31.38) ; 26.8,30.93 v1(26.92,30.93)
  L6 w0.127: v2(120.91,39.51) 120.99,39.51 121.17,39.33 121.17,39.11 120.76,38.7 120.76,37.88 119.08,36.19 119.08,33.17 118.38,32.47 118.38,28.31 117.46,27.39 117.46,22.21 115.54,20.3 115.54,18.36 113.82,16.63 109.5,16.63 108.94,16.07 107.75,16.07 107.65,16.17 99.77,16.17 99.21,16.73 91.94,16.73 91.27,17.4 86.78,17.4 86.27,16.9 82.77,16.9 82.26,16.39 81.37,16.39 80.15,15.17 79.75,15.17 74.16,9.58 72.7,9.58 72.04,8.92 69.86,8.92 69.61,8.67 68.68,8.67 67.32,10.02 66.31,10.02 65.79,10.55 64.52,10.55 62.47,12.6 61.22,12.6 60.88,12.95 52.06,12.95 50.27,14.74 46.72,14.74 42.93,18.52 42.92,18.52 41.86,19.57 41.04,19.57 34.46,26.15 29.74,26.15 29.34,26.56 29.34,29.25 28.03,30.56 28.03,31.61 28.15,31.74 28.42,31.74 28.55,31.61 v2(28.55,31.38)
  BOTTOM w0.102: CPU1.J6 120.8,39.97 120.91,39.86 v2(120.91,39.51)
USB30_RX_CPU_N4: length 175.2
  TOP w0.102: v1(123.44,41.04) 123.17,41.04 v2(122.87,41.34) ; C3806.1 31.15,53.86 30.89,53.86 30.15,53.12 30.15,51.65 30,51.5 29.64,51.5 v2(29.41,51.73)
  L6 w0.127: v2(29.41,51.73) 29.23,51.55 28.66,51.55 28.38,51.83 28.38,51.85 27.46,52.77 23.75,52.77 19.15,48.18 19.15,42.92 20.75,41.32 20.75,38.68 21.49,37.94 22.73,37.94 26.99,33.68 26.99,30.11 28.28,28.81 28.28,26.12 29.3,25.1 33.92,25.1 40.49,18.53 41.43,18.53 46.06,13.9 46.08,13.9 46.29,13.69 49.84,13.69 51.63,11.9 60.42,11.9 60.78,11.55 62.03,11.55 64.13,9.44 65.4,9.44 66.75,8.09 67.49,8.09 68.49,7.09 70.09,7.09 70.81,7.81 75.23,7.81 80.81,13.39 80.81,14.33 81.81,15.33 82.7,15.33 83.21,15.84 87.37,15.84 87.88,16.35 90.83,16.35 91.49,15.69 98.78,15.69 99.73,14.74 105.94,14.74 106.24,15.03 110.15,15.03 110.7,15.57 114.26,15.57 117.13,18.45 117.13,20.41 118.5,21.78 118.5,26.95 119.42,27.88 119.42,31.91 120.09,32.57 120.09,35.43 124.39,39.73 124.39,40.89 123.95,41.34 v2(122.87,41.34)
  BOTTOM w0.102: v2(122.87,41.34) 123.19,41.67 CPU1.E10
USB30_RX_CPU_N4_C: length 2.8
  TOP w0.102: U3801.4 33.5,55.48 33.59,55.39 33.59,55.24 33.18,54.82 ; v1(33.08,54.92) 33.18,54.82 ; 33.18,54.82 32.94,54.59 32.94,54.3 32.84,54.19 C3806.2
USB30_RX_CPU_P1: length 161.1
  TOP w0.102: 25.42,52.62 22.96,52.62 22.88,52.7 R3610.1 ; 25.42,52.62 26.39,52.62 26.67,52.34 v2(26.67,51.5) ; 25.42,52.62 v1(25.42,52.75)
  L6 w0.127: v2(26.67,51.5) 26.49,51.32 26.49,51.03 26.1,50.64 23.18,50.64 21.04,48.5 21.04,45.17 21.47,44.73 21.47,42.75 22.64,41.58 22.64,39.68 26.87,35.45 33.86,35.45 35.52,33.79 35.52,27.23 46.64,16.11 50,16.11 52.39,13.72 61.3,13.72 61.63,13.39 62.8,13.39 64.83,11.36 66.1,11.36 66.66,10.8 68.28,10.8 69.04,10.04 71.01,10.04 71.34,10.37 73.83,10.37 79.42,15.96 79.82,15.96 81.04,17.17 81.93,17.17 82.49,17.73 85.99,17.73 86.45,18.19 91.6,18.19 92.29,17.5 104.9,17.5 105.46,16.95 107.86,16.95 108.32,17.4 113.48,17.4 114.76,18.68 114.76,20.6 116.69,22.53 116.69,28.01 117.57,28.9 117.57,32.96 118.46,33.85 118.46,36.72 119.99,38.24 119.99,40.35 120.47,40.83 121.16,40.83 v2(121.56,40.43)
  BOTTOM w0.102: v2(121.56,40.43) 121.89,40.76 CPU1.G8
USB30_RX_CPU_P2: length 137.9
  TOP w0.102: v1(27.66,32.33) 27.66,32.17 ; 27.66,32.17 27.3,32.17 26.57,31.44 26.57,30.6 26.23,30.26 23.24,30.26 23.16,30.34 R3613.1 ; 27.66,32.17 v2(28.55,32.17)
  L6 w0.127: v2(121.56,39.51) 121.44,39.39 121.44,39 121.03,38.59 121.03,37.76 119.34,36.08 119.34,33.06 118.65,32.36 118.65,28.2 117.73,27.27 117.73,22.1 115.81,20.18 115.81,18.25 113.93,16.36 109.61,16.36 109.05,15.8 107.64,15.8 107.54,15.9 99.66,15.9 99.1,16.46 91.83,16.46 91.16,17.14 86.89,17.14 86.38,16.63 82.88,16.63 82.37,16.12 81.48,16.12 80.26,14.9 79.86,14.9 74.27,9.31 72.81,9.31 72.15,8.65 69.98,8.65 69.72,8.4 68.57,8.4 67.21,9.76 66.2,9.76 65.68,10.28 64.41,10.28 62.36,12.34 61.11,12.34 60.77,12.68 51.95,12.68 50.16,14.47 46.61,14.47 42.82,18.25 42.8,18.25 41.75,19.31 40.93,19.31 34.35,25.89 29.63,25.89 29.07,26.45 29.07,29.14 27.92,30.29 27.76,30.45 27.76,31.72 28.04,32.01 28.38,32.01 v2(28.55,32.17)
  BOTTOM w0.102: CPU1.H6 121.24,39.83 v2(121.56,39.51)
USB30_RX_CPU_P4: length 174
  TOP w0.102: 30.22,51.4 30.1,51.27 29.59,51.27 v2(29.41,51.1) ; 30.22,51.4 30.38,51.55 30.38,53.03 30.99,53.64 31.15,53.64 C3805.1 ; 30.22,51.4 v1(30.33,51.3)
  L6 w0.127: v2(29.41,51.1) 29.22,51.29 28.55,51.29 28.12,51.72 28.12,51.73 27.35,52.51 23.86,52.51 19.42,48.06 19.42,43.03 21.02,41.43 21.02,38.79 21.6,38.21 22.84,38.21 27.25,33.79 27.25,30.22 28.55,28.92 28.55,26.23 29.41,25.37 34.03,25.37 40.6,18.8 41.54,18.8 46.18,14.16 46.19,14.16 46.4,13.96 49.95,13.96 51.74,12.17 60.54,12.17 60.89,11.82 62.14,11.82 64.24,9.71 65.51,9.71 66.86,8.36 67.6,8.36 68.6,7.36 69.98,7.36 70.7,8.08 75.12,8.08 80.54,13.5 80.54,14.44 81.7,15.6 82.59,15.6 83.1,16.11 87.26,16.11 87.77,16.62 90.94,16.62 91.6,15.96 98.89,15.96 99.84,15 105.83,15 106.13,15.29 110.04,15.29 110.59,15.84 114.15,15.84 116.86,18.56 116.86,20.52 118.24,21.89 118.24,27.06 119.16,27.99 119.16,32.02 119.43,32.29 119.82,32.68 119.82,35.54 124.13,39.84 124.13,40.78 123.84,41.08 123.3,41.08 123.11,40.89 122.4,40.89 122.22,41.07 v2(122.22,41.34)
  BOTTOM w0.102: CPU1.F10 122.54,41.67 v2(122.22,41.34)
USB30_RX_CPU_P4_C: length 3.4
  TOP w0.102: C3805.2 32.96,53.9 32.96,53.99 33.17,54.2 33.17,54.49 33.82,55.14 33.82,55.39 33.9,55.48 U3801.5
USB30_RXDN1_C: length 9.5
  TOP w0.102: USB2.5 14.2,49.81 14.3,49.92 14.89,49.92 15.64,50.66 16.02,50.66 17.8,52.44 18.55,52.44 18.68,52.31 EU3601.9 EU3601.1 20.01,52.31 20.09,52.39 20.73,52.39 21.23,51.88 R3609.2
USB30_RXDN2_C: length 9.1
  TOP w0.102: USB3.5 14.2,29.21 14.3,29.32 14.74,29.32 15.62,30.2 18.84,30.2 18.96,30.08 EU3603.9 EU3603.1 20.35,30.08 20.39,30.04 21.11,30.04 21.23,29.91 21.23,29.74 21.44,29.53 R3612.2
USB30_RXDP1_C: length 9.4
  TOP w0.102: USB2.6 14.2,50.25 14.3,50.14 14.79,50.14 15.54,50.89 15.92,50.89 17.7,52.67 18.64,52.67 18.75,52.78 EU3601.8 EU3601.2 19.98,52.78 20.14,52.62 21.13,52.62 21.21,52.7 R3610.2
USB30_RXDP2_C: length 8.9
  TOP w0.102: R3613.2 21.21,30.34 21.13,30.26 20.49,30.26 20.44,30.31 20.44,30.31 20.19,30.56 EU3603.2 EU3603.8 18.96,30.56 18.84,30.43 15.53,30.43 14.64,29.54 14.3,29.54 14.2,29.65 USB3.6
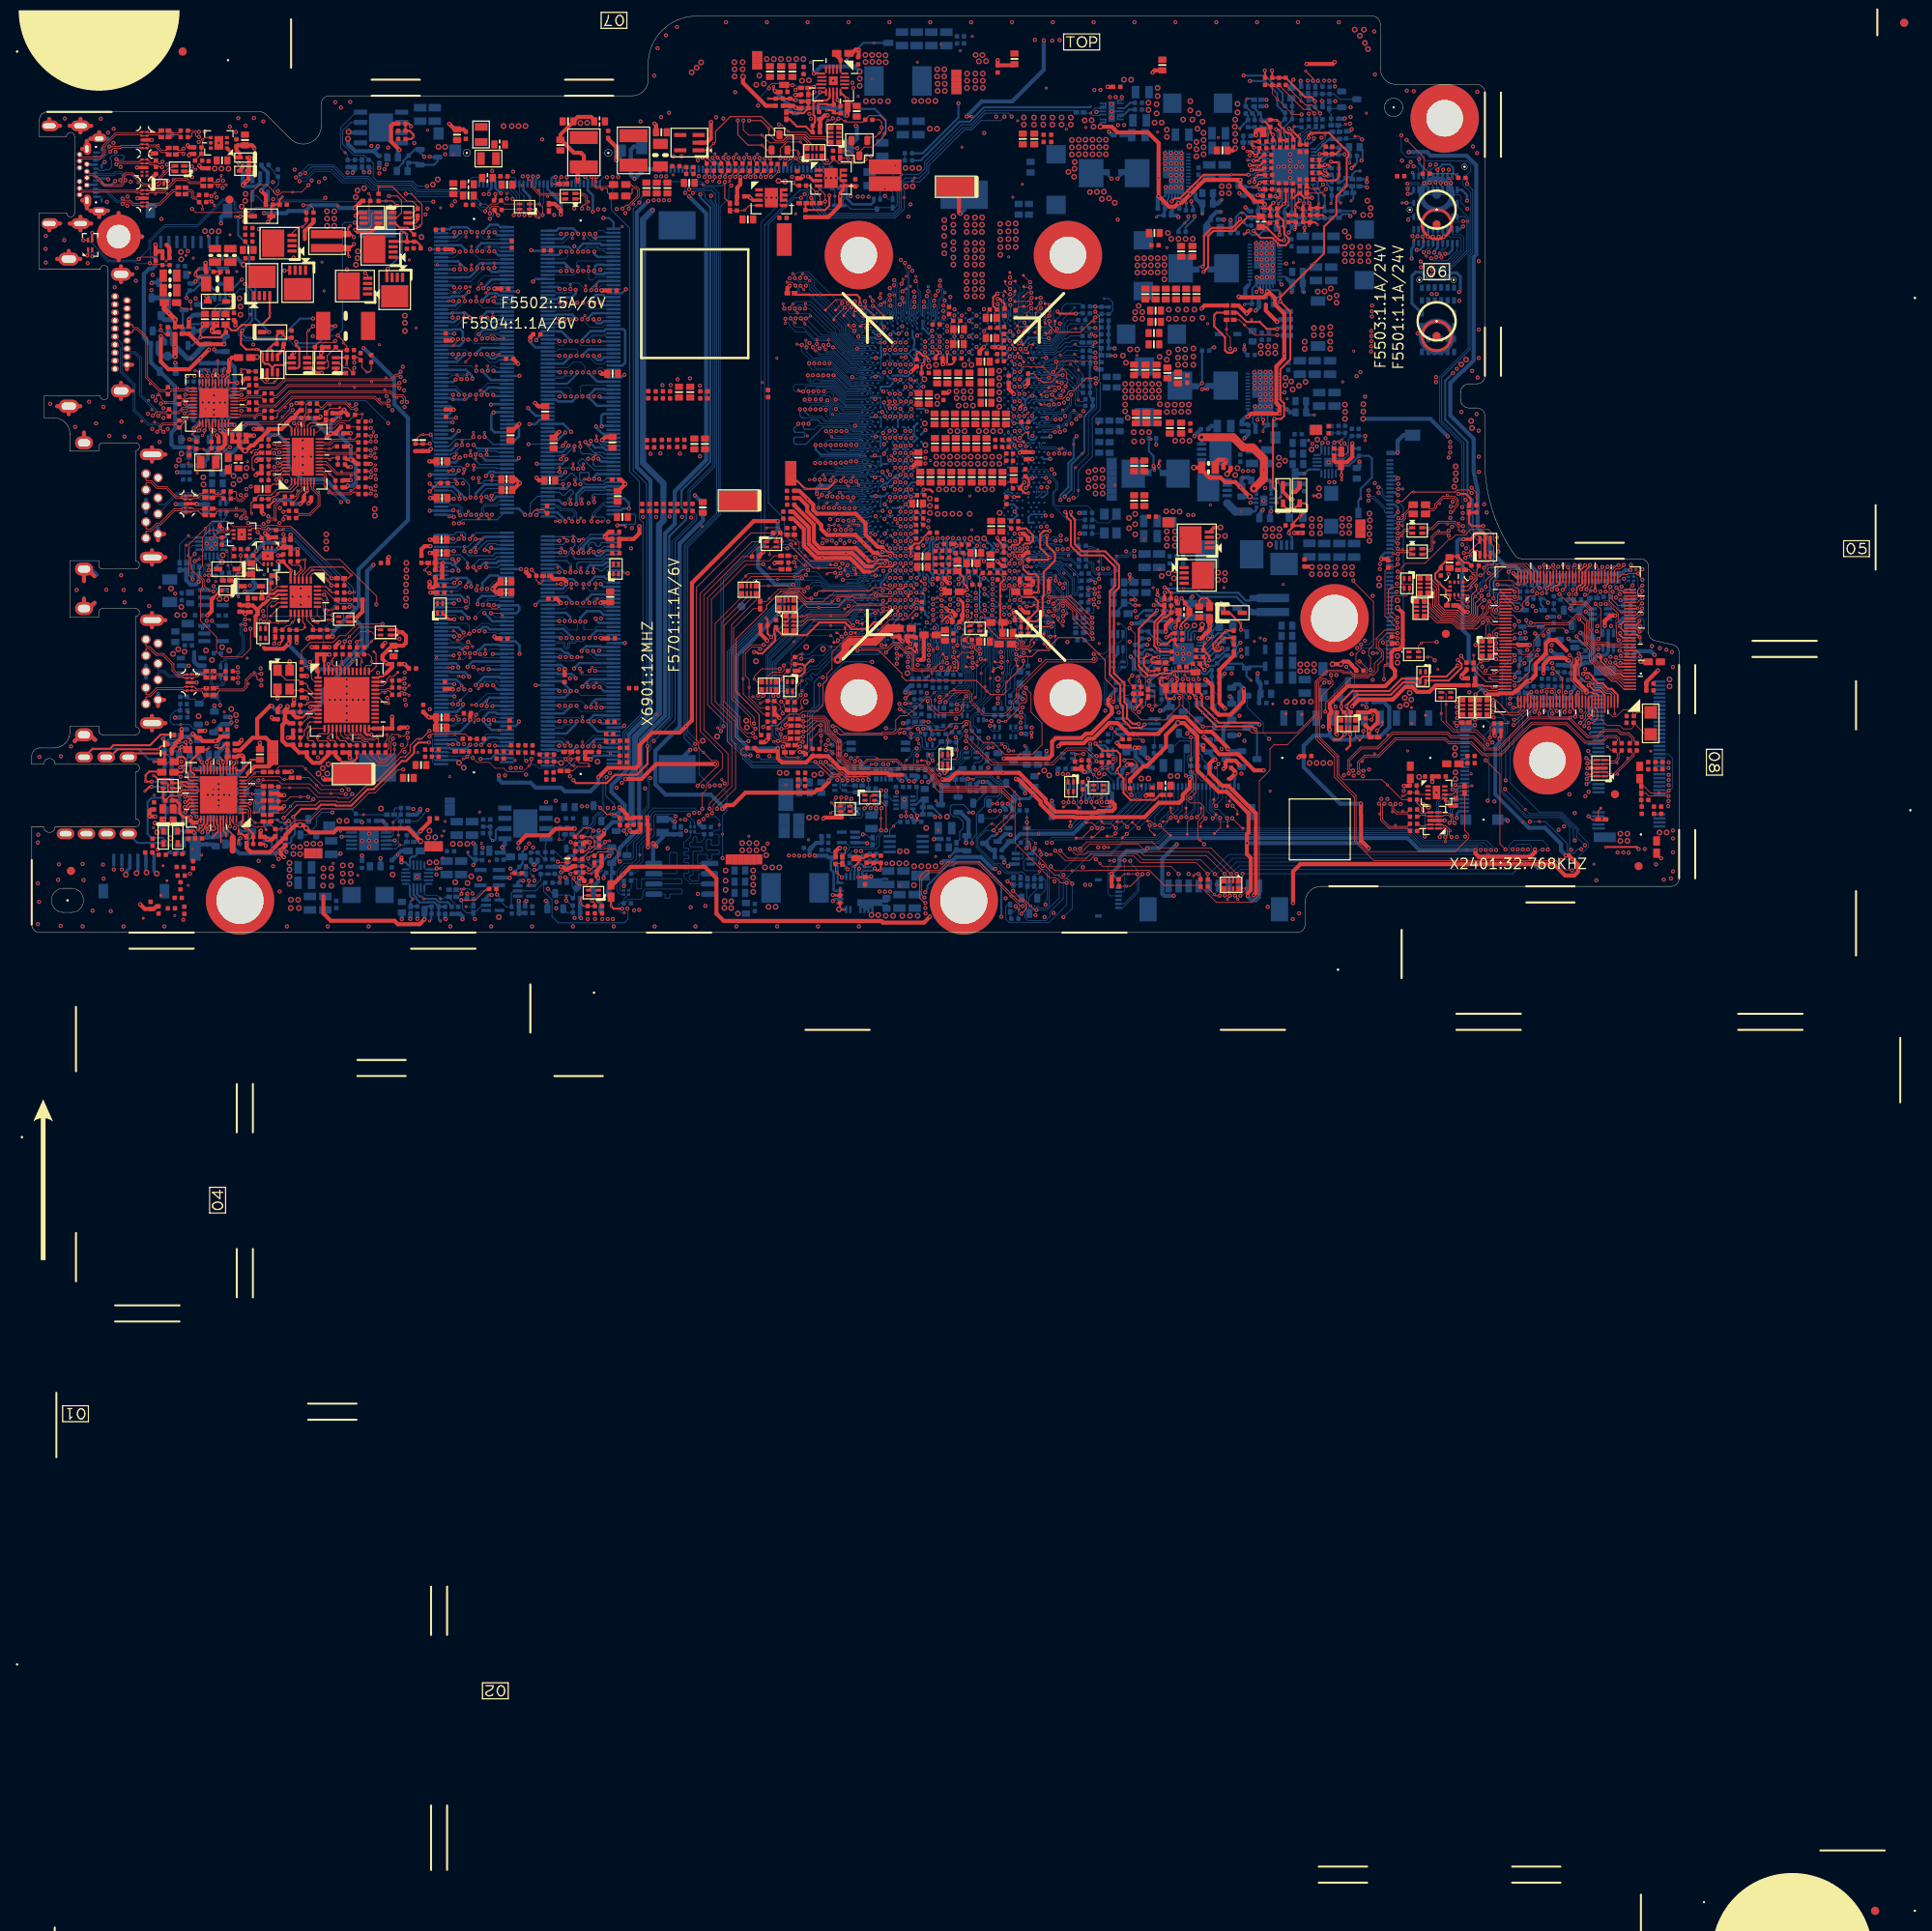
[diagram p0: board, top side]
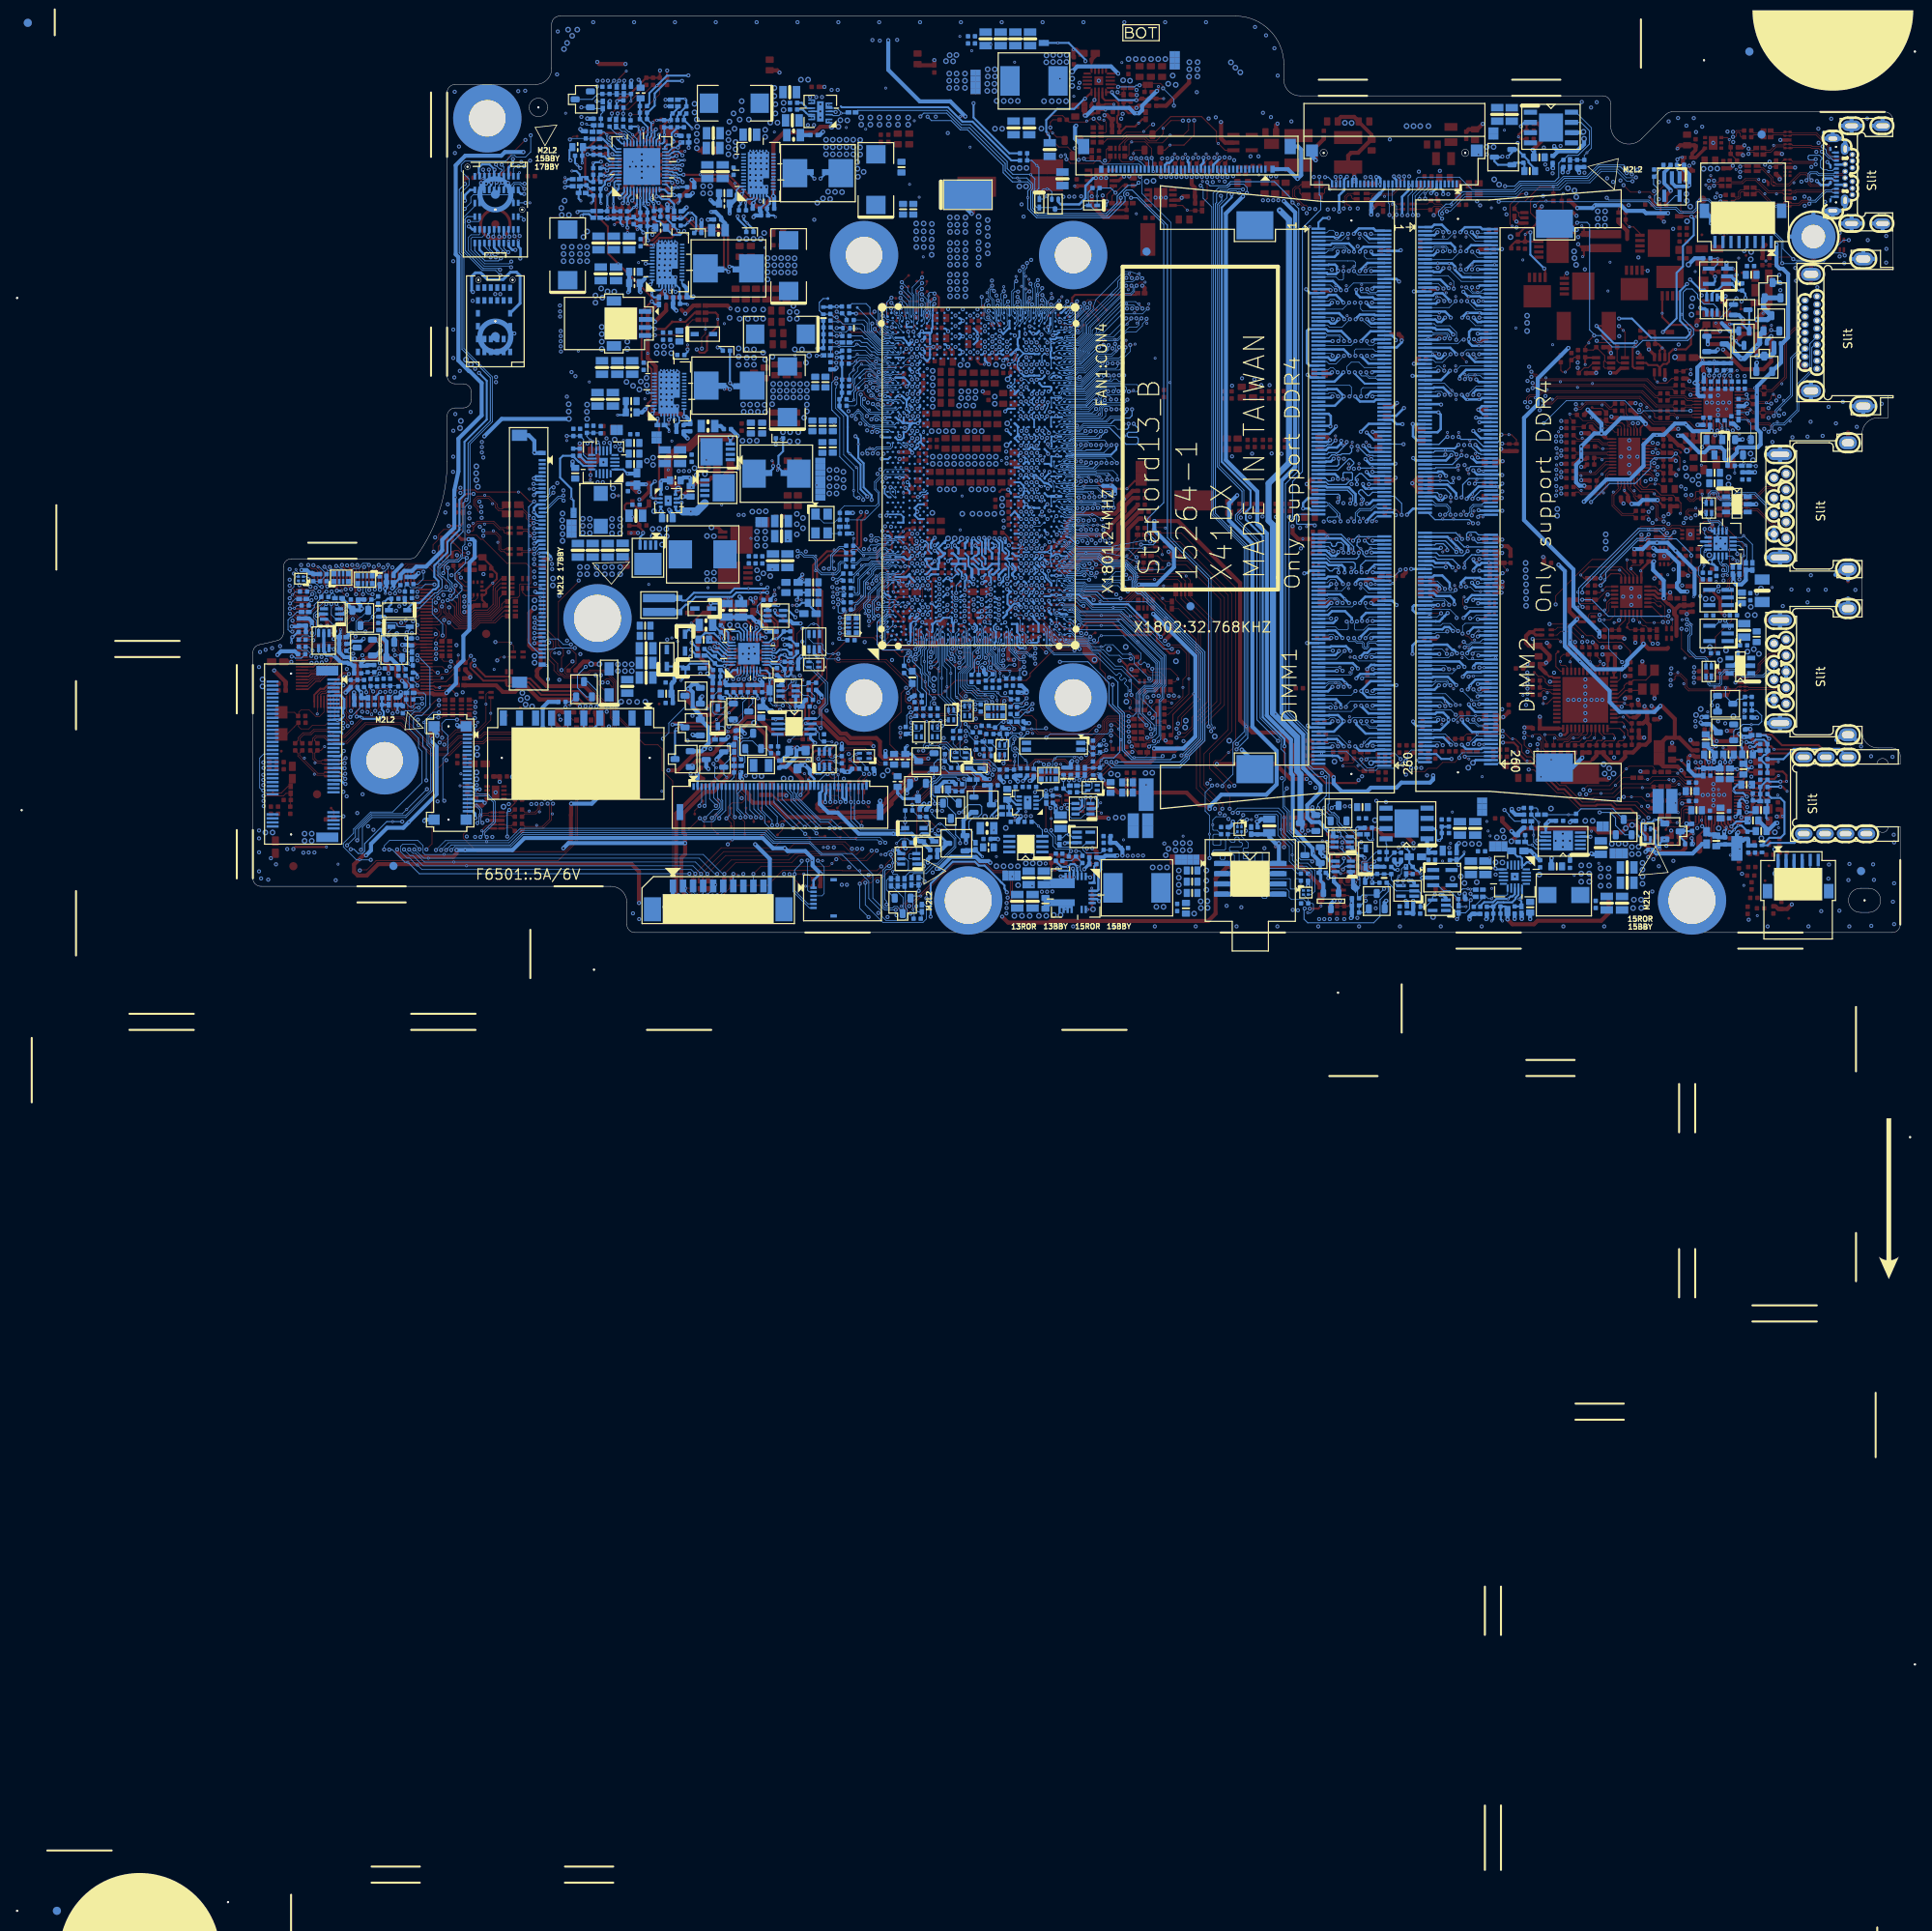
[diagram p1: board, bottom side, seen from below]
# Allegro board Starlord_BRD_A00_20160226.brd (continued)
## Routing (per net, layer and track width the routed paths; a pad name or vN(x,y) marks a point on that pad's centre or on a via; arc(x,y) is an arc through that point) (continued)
USB30_TX_CPU_N1: length 197.2
  TOP w0.102: v2(26.67,54.37) 26.47,54.17 26.47,53.9 26.15,53.59 25.67,53.59 25.32,53.94 C3601.1
  L6 w0.127: v2(26.67,54.37) 26.21,54.83 23.14,54.83 17.44,49.12 17.44,46.3 15.96,44.83 15.96,42.58 16.98,41.56 16.98,38.84 20.7,35.12 20.7,32.99 25.94,27.74 25.94,25.05 26.57,24.43 26.57,22.88 33.83,15.61 37.36,15.61 38.47,14.51 40.92,14.51 47.53,7.89 48.39,7.89 49.79,6.49 50.96,6.49 52.15,7.69 57.11,7.69 60.36,4.44 71.02,4.44 71.17,4.28 78.08,4.28 87.31,13.52 88.34,13.52 88.82,14 89.84,14 90.5,13.34 95.12,13.34 96.05,12.41 101.88,12.41 102.2,12.1 102.51,11.78 102.81,11.48 103.65,11.48 103.7,11.54 108.69,11.54 110.93,9.3 113.12,9.3 113.4,9.58 117.69,9.58 119.31,11.21 121.8,11.21 122.61,12.01 122.61,13.2 125.3,15.89 125.3,22.32 126.85,23.87 126.85,26.28 125.88,27.25 125.88,30.54 128.13,32.79 128.13,36.58 129.7,38.16 129.7,39.55 129.28,39.97 v2(128.24,39.97)
  BOTTOM w0.089: 127.43,42.74 127.42,42.75 127.42,42.78 126.8,43.4 126.45,43.4 126.07,43.78 125.81,43.78 125.72,43.75 125.45,43.75 125.36,43.78 125.16,43.78 125.03,43.73 124.82,43.73 CPU1.C13
  BOTTOM w0.102: v2(128.24,39.97) 128.7,40.43 128.7,40.74 128.12,41.32 128.12,42.05 127.83,42.34 127.83,42.34 127.58,42.59 127.43,42.74
USB30_TX_CPU_N2: length 157.5
  TOP w0.102: C3603.1 25.53,31.59 v2(25.65,31.72) ; v2(127.07,39.39) 126.19,39.39 v1(126.16,39.41)
  L6 w0.127: v2(25.65,31.72) 25.63,31.72 25.33,31.41 25.09,31.41 24.97,31.54 24.97,31.98 24.84,32.11 24.62,32.11 24.39,31.88 24.39,30.81 26.99,28.22 26.99,25.48 27.61,24.86 27.61,23.36 32.76,18.21 34.1,18.21 35.02,17.29 37.21,17.29 38.95,15.55 41.35,15.55 44.74,12.15 45.64,12.15 47.91,9.88 51.5,9.88 51.83,9.55 54.85,9.55 55.28,9.12 60.31,9.12 62.27,7.17 63.56,7.17 65.23,5.49 71.79,5.49 71.94,5.34 77.66,5.34 86.88,14.56 87.91,14.56 88.39,15.04 90.28,15.04 90.93,14.39 95.54,14.39 96.48,13.45 107.24,13.45 108.05,12.64 109.06,12.64 111.36,10.34 112.69,10.34 112.98,10.63 117.06,10.63 117.59,11.16 117.59,11.78 119.21,13.4 121.33,13.4 124.23,16.3 124.23,22.72 125.66,24.16 125.66,25.99 124.84,26.82 124.84,30.97 127.09,33.22 127.09,37.49 127.37,37.77 127.37,38.54 127.07,38.83 v2(127.07,39.39)
  BOTTOM w0.102: CPU1.B13 125.36,43.52 126.01,42.87 126.54,42.87 126.97,42.43 126.97,41.68 127.61,41.04 127.61,39.59 127.41,39.39 v2(127.07,39.39)
USB30_TX_CPU_N4: length 192.2
  TOP w0.102: C3804.1 31.42,52.42 v2(31.29,52.29) ; v2(127.84,43.37) 128.39,43.37 v1(128.4,43.38)
  L6 w0.127: v2(127.84,43.37) 127.68,43.37 127.28,42.97 126.16,42.97 125.64,42.45 125.64,39.73 125.12,39.21 125.12,35.73 126.52,34.33 126.52,33.37 124.33,31.18 124.33,26.61 125.16,25.78 125.16,24.37 123.34,22.55 123.34,18.65 122.41,17.72 122.41,15.76 120.94,14.28 119.37,14.28 116.78,11.69 116.09,11.69 115.54,11.14 112.77,11.14 112.48,10.85 111.57,10.85 109.26,13.16 108.31,13.16 107.51,13.96 99.41,13.96 98.46,14.91 91.15,14.91 90.5,15.56 88.19,15.56 87.7,15.07 86.67,15.07 78.35,6.75 72.84,6.75 72.14,6.05 65.49,6.05 61.87,9.67 55.52,9.67 55.09,10.1 52.02,10.1 51.73,10.39 48.12,10.39 45.85,12.66 44.95,12.66 41.53,16.08 39.15,16.08 37.23,18.01 35.25,18.01 27.49,25.76 27.49,28.48 26.21,29.76 26.21,33.11 25.73,33.6 24.1,33.6 19.81,37.89 19.81,41.01 18.83,41.99 18.26,42.56 18.26,48.71 23.12,53.56 29.23,53.56 30.5,52.29 v2(31.29,52.29)
  BOTTOM w0.089: 127.38,44.28 127.25,44.28 126.81,44.72 126.17,44.72 126.07,44.61 125.81,44.61 125.72,44.65 125.45,44.65 125.36,44.61 125.16,44.61 125.03,44.67 124.97,44.67 CPU1.C15
  BOTTOM w0.102: v2(127.84,43.37) 127.84,43.83 127.38,44.28
USB30_TX_CPU_N4_C: length 6.6
  TOP w0.102: U3801.7 34.7,55.48 34.79,55.39 34.79,55.14 35.61,54.32 35.61,53.15 34.55,52.09 33.21,52.09 C3804.2
USB30_TX_CPU_P1: length 197.7
  TOP w0.102: v2(128.24,39.34) 128.4,39.34 v1(128.73,39.67) ; C3602.1 25.35,54.83 25.47,54.7 25.47,54.11 25.77,53.81 26.06,53.81 26.24,53.99 26.24,54.12 v2(25.97,54.39)
  L6 w0.127: v2(128.24,39.34) 128.6,39.34 128.73,39.46 128.73,39.58 128.85,39.7 129.17,39.7 129.44,39.44 129.44,38.27 127.86,36.69 127.86,32.9 125.61,30.65 125.61,27.14 126.58,26.17 126.58,23.98 125.03,22.43 125.03,16 122.34,13.31 122.34,12.12 121.69,11.47 119.2,11.47 117.57,9.85 113.29,9.85 113.01,9.57 111.04,9.57 108.8,11.8 103.59,11.8 103.54,11.75 102.92,11.75 102.7,11.97 102.39,12.28 101.99,12.68 96.16,12.68 95.23,13.61 90.61,13.61 89.95,14.27 88.71,14.27 88.23,13.78 87.2,13.78 77.97,4.55 71.28,4.55 71.13,4.7 60.48,4.7 57.22,7.95 52.04,7.95 50.85,6.76 49.9,6.76 48.5,8.16 47.64,8.16 41.03,14.77 38.58,14.77 37.47,15.88 33.95,15.88 26.83,22.99 26.83,24.54 26.21,25.16 26.21,27.85 20.97,33.1 20.97,35.23 17.24,38.95 17.24,41.67 16.23,42.69 16.23,44.72 17.7,46.19 17.7,49.01 23.25,54.56 25.85,54.56 25.97,54.44 v2(25.97,54.39)
  BOTTOM w0.089: CPU1.D13 123.97,43.53 124.26,43.53 124.33,43.6 124.33,43.83 124.41,43.91 124.99,43.91 125.13,43.96 125.4,43.96 125.49,43.93 125.69,43.93 125.78,43.96 126.16,43.96 126.53,43.59 126.88,43.59 127.55,42.91 127.58,42.91 127.59,42.9
  BOTTOM w0.102: v2(128.24,39.34) 128.7,39.79 128.7,40.1 128.93,40.33 128.93,40.84 128.34,41.42 128.34,42.15 127.92,42.57 127.92,42.57 127.85,42.65 127.59,42.9
USB30_TX_CPU_P2: length 157.7
  TOP w0.102: C3604.1 25.53,32.48 v2(25.65,32.35) ; v2(127.63,39.06) 127.63,38.73 v1(128.24,38.12)
  L6 w0.127: v2(25.65,32.35) 25.63,32.38 24.51,32.38 24.13,32 24.13,30.7 26.72,28.11 26.72,25.37 27.34,24.75 27.34,23.25 32.65,17.94 33.99,17.94 34.91,17.02 37.09,17.02 38.83,15.28 41.24,15.28 44.63,11.89 45.53,11.89 47.8,9.62 51.39,9.62 51.72,9.29 54.74,9.29 55.17,8.86 60.2,8.86 62.16,6.9 63.45,6.9 65.12,5.22 71.68,5.22 71.83,5.07 77.77,5.07 86.99,14.29 88.02,14.29 88.5,14.77 90.17,14.77 90.82,14.13 95.43,14.13 96.37,13.19 107.13,13.19 107.94,12.37 108.95,12.37 111.25,10.08 112.8,10.08 113.09,10.37 117.17,10.37 117.85,11.05 117.85,11.67 119.32,13.14 121.44,13.14 124.5,16.19 124.5,22.61 125.93,24.05 125.93,26.1 125.11,26.93 125.11,30.86 127.35,33.11 127.35,37.38 127.63,37.66 v2(127.63,39.06)
  BOTTOM w0.102: CPU1.A13 125.91,43.29 126.11,43.1 126.63,43.1 127.2,42.52 127.2,41.77 127.7,41.27 127.84,41.14 127.84,39.49 127.63,39.29 v2(127.63,39.06)
USB30_TX_CPU_P4: length 191.9
  TOP w0.102: v1(127.33,44.34) v2(127.33,43.76) ; v2(31.29,51.35) 31.29,51.73 31.42,51.86 31.66,51.86 C3803.1
  L6 w0.127: v2(31.29,51.35) 31.29,51.65 30.92,52.02 30.39,52.02 29.12,53.29 23.23,53.29 18.53,48.59 18.53,42.67 20.08,41.12 20.08,38 24.21,33.86 25.84,33.86 26.48,33.22 26.48,29.87 27.76,28.59 27.76,25.87 35.36,18.27 37.34,18.27 39.26,16.35 41.64,16.35 45.06,12.93 45.96,12.93 48.23,10.66 51.84,10.66 52.13,10.37 55.2,10.37 55.63,9.94 61.98,9.94 65.6,6.32 72.03,6.32 72.73,7.01 78.24,7.01 86.56,15.33 87.58,15.33 88.08,15.83 90.61,15.83 91.26,15.18 98.57,15.18 99.52,14.23 107.62,14.23 108.42,13.43 109.37,13.43 111.68,11.12 112.37,11.12 112.66,11.41 115.43,11.41 115.98,11.96 116.67,11.96 119.26,14.55 120.83,14.55 122.15,15.87 122.15,17.83 123.07,18.76 123.07,22.66 124.89,24.48 124.89,25.67 124.06,26.5 124.06,31.29 126.25,33.48 126.25,34.22 124.85,35.62 124.85,39.32 125.37,39.84 125.37,42.56 126.05,43.23 127.17,43.23 127.33,43.4 v2(127.33,43.76)
  BOTTOM w0.089: CPU1.D15 124.35,44.49 124.99,44.49 125.13,44.44 125.4,44.44 125.49,44.47 125.69,44.47 125.78,44.44 126.16,44.44 126.25,44.53 126.73,44.53 127.33,43.93 v2(127.33,43.76)
USB30_TX_CPU_P4_C: length 7.1
  TOP w0.102: C3803.2 33.21,51.86 34.64,51.86 35.84,53.05 35.84,54.42 35.59,54.66 ; 35.59,54.66 35.02,55.24 35.02,55.39 35.1,55.48 U3801.8 ; 35.59,54.66 v1(35.69,54.75)
USB30_TXDN1_C: length 9.4
  TOP w0.102: R3605.2 21.3,54.32 20.98,54.32 20.62,53.97 20.06,53.97 19.93,53.83 EU3601.4 EU3601.7 18.83,53.83 18.71,53.95 17.94,53.95 16.69,55.21 15.54,55.21 14.84,55.92 14.3,55.92 14.2,55.81 USB2.8
USB30_TXDN1_R: length 1.6
  TOP w0.102: R3605.1 22.67,54.25 23.55,54.25 C3601.2
USB30_TXDN2_C: length 10.6
  TOP w0.102: R3611.2 21.41,31.98 20.81,31.98 20.59,31.77 20.22,31.77 20.06,31.61 EU3603.4 EU3603.7 18.96,31.61 18.84,31.73 18.25,31.73 17.45,32.54 17.45,33.27 16.26,34.46 15.45,34.46 14.59,35.32 14.3,35.32 14.2,35.21 USB3.8
USB30_TXDN2_R: length 1.8
  TOP w0.102: R3611.1 22.85,31.95 23.76,31.95 C3603.2
USB30_TXDP1_C: length 9.4
  TOP w0.102: R3606.2 21.27,54.55 20.88,54.55 20.53,54.19 20.09,54.19 19.98,54.31 EU3601.5 EU3601.6 18.83,54.31 18.71,54.18 18.04,54.18 16.78,55.44 15.64,55.44 14.93,56.14 14.3,56.14 14.2,56.25 USB2.9
USB30_TXDP1_R: length 1.7
  TOP w0.102: R3606.1 22.84,54.48 23.51,54.48 C3602.2
USB30_TXDP2_C: length 10.5
  TOP w0.102: USB3.9 14.2,35.65 14.3,35.54 14.69,35.54 15.54,34.69 16.36,34.69 17.68,33.37 17.68,32.63 18.35,31.96 18.84,31.96 18.96,32.08 EU3603.6 EU3603.5 20.13,32.08 20.22,32 20.5,32 20.71,32.21 21.41,32.21 R3614.2
USB30_TXDP2_R: length 1.8
  TOP w0.102: R3614.1 22.92,32.18 23.82,32.18 C3604.2
USB30_VCCA: length 2.4
  TOP w0.508: v2(23.7,50.18) 23.37,50.51 v1(23.37,50.69)
  BOTTOM w0.305: U3401.12 23.42,49.9 v2(23.7,50.18)
  BOTTOM w0.508: v2(17.91,53.26) 17.93,53.23 EU3602.5
  vias: v3(21.33,56.58) v3(21.36,55.69)
USB30_VCCB: length 2.4
  BOTTOM w0.508: EU3604.5 20.7,33.16 20.19,33.67 20.19,34.87
  vias: v1(21.23,37.79) v1(47.8,75.15) v3(18.08,39.46) v3(18.59,40.48) v3(18.97,39.46) v3(21.66,35.07) v3(36.63,49.5) v3(36.63,48.61) v3(36.63,47.72) v3(46.4,76.67) v3(46.4,75.78) v3(46.4,74.77)
USB_8+: length 3.1
  TOP w0.102: U6901.33 44.02,30.17 44.18,30.33 44.7,30.33 R6906.2 R6904.1
USB_8-: length 2.7
  TOP w0.102: R6905.2 44.82,29.67 44.39,30.1 44.27,30.1 44.11,29.94 43.89,29.94 ; U6901.32 43.29,29.67 43.56,29.94 43.89,29.94 ; v1(43.89,29.81) 43.89,29.94
USB_ADT: length 234.9
  TOP w0.508: v2(156.82,54.77) 157.14,54.77 157.66,55.29 PD4409.A
  L3 w0.508: v2(42.24,97.78) 41.33,97.78 38.63,95.08 38.63,83.02 v2(39.22,82.44) ; v2(153.34,36.41) 153.34,37.56 158.37,42.59 158.37,54.09 157.61,54.86 156.91,54.86 v2(156.82,54.77)
  L4 w0.508: v2(166.65,77.21) 167.1,77.21 167.69,76.62 167.69,72.44 166.5,71.25 166.5,69.99 163.68,67.17 161.02,67.17 156.77,62.92 156.77,54.82 v2(156.82,54.77) ; v2(42.24,97.78) 42.24,98.67 45.36,101.79 75.68,101.79 75.68,101.79 76.31,101.79 78.81,104.29 78.81,108.28 82.25,111.72 121.47,111.72 124.34,108.84 128.87,108.84 129.08,109.05 160.23,109.05 162.86,106.42 162.86,104.62 164.64,102.85 164.64,102.02 v2(164.01,101.39)
  L6 w0.508: v2(164.01,101.39) 164.21,101.39 164.56,101.03 164.56,100.52 168.48,96.61 168.48,78.38 167.31,77.21 v2(166.65,77.21)
  vias: v1(36.35,79.75) v1(152.75,36.62)
USB_ADT_D: length 8.3
  BOTTOM w0.254: PD4407.K 151.28,33.08 PD4406.K ; PD4406.K 150.5,33.42 148.26,33.42 148.05,33.21 148.05,33.06 147.62,32.63 PR4408.1 ; PD4406.K 151.06,31.88 v1(151.61,31.33)
USB_ADT_D1: length 11
  TOP w0.254: v2(156.34,49.67) 156.34,49.93 156.81,50.4 PC4434.2 ; PC4434.2 156.84,50.58 PR4442.1 ; PC4434.2 156.81,50.83 v1(157.65,51.68) 158.62,52.65 158.62,53.1 158.37,53.36 PD4409.K 157.05,52.75 156.01,52.75 155.6,53.15 PD4411.K
  BOTTOM w0.254: PU4403.4 156.7,49.16 156.34,49.52 v2(156.34,49.67)
USB_ADT_R1: length 7
  TOP w0.254: PR4327.1 31.61,73.94 PD4306.A 30.48,74.21 PR4328.2 30.09,73.16 v1(29.59,72.66) ; PQ4308.5 29.92,72.33 v1(29.59,72.66) ; v1(29.59,72.66) 29.27,72.34 PQ4308.6
USB_ADT_SW: length 18.7
  TOP w0.127: PU4304.4 31.48,82.33 v2(31.42,82.26) ; v2(26.06,69.41) 26.03,69.44 26.03,69.97 v1(26.06,69.99) 26.08,70.02 26.62,70.02 26.88,69.75 PR4320.2 PR4321.1
  L3 w0.127: v2(26.06,69.41) 26.75,69.41 28.88,71.54 28.88,79.72 v2(31.42,82.26)
USB_ADT_SW_R: length 4
  TOP w0.127: PQ4308.3 30.57,68.82 v1(30.2,68.44) 30.06,68.3 28.99,68.3 28.43,68.86 PR4321.2
USB_CAMERA_N: length 6.8
  TOP w0.102: 62.94,92.17 62.33,92.78 v2(62.33,94) ; 62.94,92.17 63.23,91.87 TR5501.3 ; 62.94,92.17 v1(63.04,92.27)
  BOTTOM w0.102: v2(62.33,94) 62.33,93.84 62.15,93.66 TCBD1.15
USB_CAMERA_P: length 7.7
  TOP w0.102: TR5501.2 65.86,91.19 65.73,91.32 65.73,91.52 65.61,91.65 64.13,91.65 ; 64.13,91.65 v1(64.13,91.51) ; 64.13,91.65 63.14,91.65 62.1,92.68 62.1,93.41 61.97,93.54 61.82,93.54 61.69,93.67 v2(61.69,94)
  BOTTOM w0.102: v2(61.69,94) 61.69,93.84 61.65,93.8 TCBD1.14
USB_CHG_EN: length 262.5
  TOP w0.102: v2(200.25,39.64) 200.1,39.64 199.62,39.16 199.57,39.16 199.45,39.04 KBC24.23 ; v2(20.27,47.06) 19.81,46.6 19.81,45.18 21.23,43.76 v1(21.23,42.76) 21,42.54 21,38.73 22.99,36.75 22.99,34.92 23.65,34.26 26.19,34.26 27.2,35.27 v2(27.2,37.76)
  L3 w0.102: v2(125.93,1.92) 125.91,1.92 125.7,1.72 122.46,1.72 120.06,4.11 120.06,5.2 117.01,8.25 116.48,8.25 113.56,11.17 111.96,11.17 111.56,11.57 110.37,11.57 110.22,11.73 94.77,11.73 94.33,12.16 86.99,12.16 79.37,4.54 71.58,4.54 70.56,3.52 66.14,3.52 65.28,4.39 62.48,4.39 57.17,9.69 57.17,10.79 56.72,11.24 55.65,11.24 54.58,10.18 47.23,10.18 45.34,12.06 44.19,12.06 41.53,14.72 38.25,14.72 36.52,16.45 36.52,18.74 37.45,19.66 37.45,23.63 33.51,27.56 33.51,34.56 32.68,35.4 31.8,35.4 31.42,35.78 31.42,36.03 31.04,36.41 28.91,36.41 27.56,37.76 v2(27.2,37.76)
  L4 w0.102: v2(125.93,1.92) 126.64,1.21 128.57,1.21 128.65,1.29 154.07,1.29 155.78,2.99 155.78,3.27 159.21,6.7 189.91,6.7 192.43,9.21 193.02,9.21 200.92,17.12 200.92,30.35 201.31,30.73 201.31,34.71 201.08,34.94 201.08,34.94 199.49,36.53 199.49,38.96 200.07,39.54 200.07,39.54 200.18,39.64 v2(200.25,39.64)
  BOTTOM w0.102: U3401.5 20.56,47.6 20.27,47.31 v2(20.27,47.06)
USB_CPU_PN0: length 147.4
  TOP w0.102: v1(21.99,45.64) 22.02,45.61 v2(22.02,45.05)
  L6 w0.089: v2(114.2,40.73) 114.2,40.87 114.41,41.09 114.56,41.09 114.63,41.02 114.63,39.32 115.04,38.91 115.04,38.86 115.12,38.78
  L6 w0.127: v2(22.02,45.05) 22.38,45.05 22.5,44.92 22.5,44.78 22.63,44.66 24.65,44.66 25.87,43.43 25.87,37.69 26.45,37.11 32.86,37.11 33.29,37.55 35.26,37.55 36.31,36.5 36.31,27.79 47.2,16.9 50.31,16.9 52.69,14.51 61.63,14.51 61.96,14.18 63.15,14.18 65.07,12.26 66.29,12.26 66.46,12.09 74.44,12.09 79.08,16.74 79.49,16.74 80.71,17.96 81.5,17.96 82.56,19.03 84.65,19.03 84.97,19.35 86.74,19.35 87.11,18.98 91.93,18.98 92.63,18.28 105.15,18.28 105.36,18.48 107.03,18.48 107.31,18.2 113.16,18.2 113.97,19.01 113.97,20.97 115.4,22.41 115.4,26.5 115.68,26.78 115.68,28.6 115.31,28.97 115.31,30.62 116.14,31.45 116.14,37.76 115.35,38.54 115.12,38.78
  BOTTOM w0.102: v2(114.2,40.73) 114.22,40.76 114.22,40.76 114.54,41.08 CPU1.AB9 ; v2(22.02,45.05) 21.83,44.86 21.65,44.86 21.56,44.94 21.56,45.41 21.73,45.58 22.19,45.58 22.46,45.86 22.46,46.06 22.6,46.2 U3401.2
USB_CPU_PN1: length 138.9
  TOP w0.102: v2(26.54,38.93) 27.07,38.93 v1(27.13,38.88)
  L6 w0.127: v2(26.54,38.93) 26.95,38.93 27.05,38.83 27.05,38.69 27.18,38.56 27.8,38.56 28.34,38.02 32.36,38.02 32.73,38.38 40.77,38.38 42.51,36.65 42.51,27.54 41.79,26.83 41.79,23.75 47.69,17.85 50.45,17.85 53,15.29 61.96,15.29 62.26,14.99 63.46,14.99 65.2,13.25 66.57,13.25 66.97,13.64 68.26,13.64 68.46,13.44 74.67,13.44 78.75,17.53 79.16,17.53 80.38,18.75 81.17,18.75 82.23,19.82 84.32,19.82 84.63,20.13 87.07,20.13 87.44,19.77 92.26,19.77 92.97,19.05 98.24,19.05 98.94,19.75 104.42,19.75 104.5,19.68 109.12,19.68 112.98,23.53 112.98,27.34 114.27,28.64 114.27,31.84 115.49,33.06 115.49,36.02 113.19,38.32 113.19,38.94 113.14,38.99 v2(113.14,39.31)
  BOTTOM w0.102: CPU1.AD6 113.67,39.33 113.49,39.51 113.26,39.51 113.14,39.39 v2(113.14,39.31) ; v2(26.54,38.93) 26.11,38.5 26.11,38.19 25.91,37.98 25.91,37.1 26.19,36.82 26.19,35.11 25.72,34.65 25.33,34.26 24.21,34.26 23.94,33.98 23.94,33.8 23.81,33.67 23.61,33.67 23.48,33.54 TR3603.1
USB_CPU_PN2: length 148.6
  TOP w0.102: v1(177.47,50.87) 177.35,50.75 ; 177.35,50.75 176.99,51.12 174.9,51.12 174.1,50.32 TR6601.2 ; 177.35,50.75 177.57,50.54 v2(178,50.54)
  L3 w0.14: v2(108.94,33.65) 109.4,33.19 109.4,32.81 109.99,32.21 109.99,29.04 112.47,26.56 112.47,21.92 113.96,20.42 113.96,17.86 115.53,16.29 115.53,14.16 116.45,13.24 116.78,13.24 119.39,10.63 119.39,9.84 120.18,9.05 120.18,8.44 121.23,7.38 121.87,7.38 123.89,5.36 124.83,5.36 126.69,3.5 128.96,3.5 129.16,3.31 152.08,3.31 156.7,7.93 173.26,7.93 175.27,9.94 178.49,9.94 179.84,11.29 179.84,12.86 179.61,13.09 179.61,16.15 178.75,17.01 178.75,29.24 178.29,29.69 178.29,31 179.28,31.99 179.28,35.02 178.57,35.73 178.57,37.73 178.09,38.21 178.09,43.22 178.52,43.65 178.52,45.5 179.02,45.99 179.02,47.16 179.2,47.34 179.2,49.09 178.85,49.44 178.85,50.15 178.59,50.4 178.14,50.4 v2(178,50.54)
  BOTTOM w0.089: CPU1.AH3 110.87,37.76 110.87,37.28 110.91,37.18 110.91,36.9 110.87,36.83 110.87,36.63 110.91,36.53 110.91,36 110.82,35.91 110.82,35.72 110.83,35.7
  BOTTOM w0.102: v2(108.94,33.65) 109.11,33.82 109.55,33.82 110.83,35.11 110.83,35.7
USB_CPU_PN2_C: length 3.1
  TOP w0.102: TR6601.1 171.41,50.32 171.22,50.13 170.69,50.13 170.19,49.62 v2(169.87,49.62)
  BOTTOM w0.102: v2(169.87,49.62) 169.79,49.71 IOBD1.19
USB_CPU_PN3: length 189
  TOP w0.102: v1(112.62,41.6) 112.85,41.6 v2(113.14,41.3) ; TR3805.1 19.84,94.64 v2(19.91,94.56)
  L6 w0.089: 113.16,37.86 113.16,37.96 112.7,38.42 112.7,41.53 112.8,41.63 112.93,41.63 113.14,41.42 v2(113.14,41.3)
  L6 w0.127: v2(19.91,94.56) 20.11,94.76 20.37,94.76 21.11,94.02 24.01,94.02 24.32,93.71 24.32,84.56 21.97,82.21 21.97,79.52 22.17,79.32 22.17,76.78 24.83,74.12 27.44,74.12 29.58,71.99 29.58,71.08 30.54,70.11 30.54,68.18 30.05,67.68 30.05,64.69 30.54,64.19 30.54,63 31.6,61.95 31.6,57.83 39.32,50.11 39.32,43.5 40.89,41.93 40.89,39.77 44.69,35.97 44.69,31.41 43.19,29.91 43.19,23.12 45.6,20.71 46.65,20.71 48.97,18.38 50.64,18.38 53.2,15.82 62.18,15.82 62.48,15.51 63.78,15.51 64.77,14.52 66.52,14.52 66.88,14.16 68.48,14.16 68.68,13.96 74.45,13.96 78.54,18.05 78.94,18.05 80.16,19.27 80.95,19.27 82.01,20.34 83.67,20.34 84.73,21.4 85.16,21.4 85.82,20.74 85.83,20.74 85.92,20.65 87.31,20.65 87.59,20.37 92.41,20.37 92.49,20.45 94.02,20.45 94.56,19.9 96.51,19.9 96.91,20.3 104.59,20.3 104.71,20.18 108.89,20.18 109.4,20.69 109.4,22.98 109.74,23.32 110.64,23.32 111.05,23.73 111.05,24.12 112.3,25.38 112.3,33.94 113.5,35.13 113.5,36.5 113.16,36.85 113.16,37.86
  BOTTOM w0.102: CPU1.AD9 113.44,41.3 v2(113.14,41.3)
USB_CPU_PN4: length 168.5
  TOP w0.102: 69.1,90.85 69.1,90.12 v2(69.21,90) ; 69.1,90.85 v1(69.24,90.85) ; 69.1,90.85 69.1,91.47 68.69,91.87 TR5501.4
  L6 w0.127: v2(107.62,34.05) 107.58,34.09 102.12,34.09 101.4,33.37 101.39,33.37 100.29,32.26 96.53,32.26 95.03,30.76 87.15,30.76 78.8,22.41 78.26,22.41 77.07,21.21 75.93,21.21 74.48,19.77 73.7,19.77 70.86,16.93 66.37,16.93 65.05,18.25 56.03,18.25 55.97,18.19 54.11,18.19 51.46,20.84 50.01,20.84 48.03,22.83 48.03,37.61 41.37,44.26 41.37,46.98 48.7,54.31 48.7,64.24 51.11,66.64 51.11,87.37 54.1,90.36 57.42,90.36 57.84,89.95 65.45,89.95 66.26,90.76 68.46,90.76 v2(69.21,90)
  BOTTOM w0.102: CPU1.AJ1 110.46,36.4 110.36,36.29 110.36,35.24 109.81,34.69 108.68,34.69 108.24,34.24 107.8,34.24 v2(107.62,34.05)
USB_CPU_PN5: length 149.6
  TOP w0.102: v1(176.02,54.35) 176.02,54.22 ; 176.02,54.22 175.46,54.22 174.47,53.23 174.47,52.94 174.2,52.67 173.82,52.67 R6605.2 ; 176.02,54.22 176.95,54.22 177.39,53.78 177.39,53.14 176.91,52.65 176.91,52.47 176.71,52.26 v2(176.45,52.26)
  L3 w0.14: v2(112.11,38.83) 111.95,38.99 111.06,38.99 110.83,38.76 110.83,37.95 111.12,37.66 111.12,31.29 112.13,30.28 112.13,28.43 113.52,27.03 113.52,22.38 115.02,20.88 115.02,18.57 116.58,17.01 116.58,14.6 116.89,14.29 117.22,14.29 120.45,11.07 120.45,10.33 124.34,6.43 125.28,6.43 127.13,4.58 133.74,4.58 134.91,5.74 152.97,5.74 156.24,9.01 172.49,9.01 174.52,11.04 178.05,11.04 178.78,11.76 178.78,12.07 178.56,12.28 178.56,15.71 177.7,16.58 177.7,28.79 176.93,29.56 176.93,31.94 177.6,32.61 178.23,33.24 178.23,34.59 177.52,35.3 177.52,37.29 177.04,37.78 177.04,43.66 177.47,44.09 177.47,45.98 177.18,46.27 177.18,52.39 176.95,52.62 176.76,52.62 176.45,52.31 v2(176.45,52.26)
  BOTTOM w0.102: CPU1.AF6 112.36,39.12 112.11,38.88 v2(112.11,38.83)
USB_CPU_PN5_C: length 4.6
  TOP w0.102: 170.61,51.83 170.61,51.55 170.39,51.32 170.15,51.32 v2(169.95,51.53) ; 170.61,51.83 v1(170.46,51.83) ; 170.61,51.83 170.61,52.03 171.22,52.64 171.22,53.05 171.35,53.18 R6605.1
  BOTTOM w0.102: v2(169.95,51.53) 169.75,51.32 169.63,51.21 IOBD1.16
USB_CPU_PN6: length 181.1
  TOP w0.102: 74.74,90.66 75.53,91.45 75.53,92.42 75.21,92.74 74.77,92.74 74.53,92.98 R5510.2 ; 74.74,90.66 v1(74.85,90.54) ; 74.74,90.66 74.24,90.16 v2(74.24,89.98)
  L6 w0.127: v2(111.56,35.12) 110.53,35.12 110.11,34.7 108.71,34.7 108.52,34.51 108.52,33.13 108.02,32.63 101.77,32.63 99.13,29.99 87.5,29.99 79.13,21.62 78.59,21.62 77.4,20.43 76.26,20.43 73.9,18.07 73.9,17.84 72.22,16.16 66.03,16.16 64.72,17.47 62.28,17.47 62.2,17.39 53.82,17.39 51.15,20.06 49.68,20.06 47.22,22.52 47.22,37.26 40.55,43.92 40.55,47.53 47.15,54.13 47.15,64.57 47.18,64.59 47.18,64.74 50.33,67.89 50.33,87.71 53.76,91.14 57.97,91.14 58.38,90.73 64.98,90.73 65.8,91.55 68.77,91.55 69.6,90.71 73.52,90.71 v2(74.24,89.98)
  BOTTOM w0.102: CPU1.AH1 111.17,36.68 111.17,35.5 v2(111.56,35.12)
USB_CPU_PN7: length 141.8
  TOP w0.102: v2(176.2,49.95) 176.05,49.8 174.95,49.8 ; TR6602.2 173.44,47.69 173.55,47.59 173.89,47.59 174.04,47.74 174.04,49.22 174.62,49.8 174.95,49.8 ; 174.95,49.8 v1(174.95,49.93)
  L3 w0.089: 112.53,38.8 112.53,39.65 112.42,39.77 v2(112.06,40.12)
  L3 w0.14: v2(176.2,49.95) 176.38,49.77 176.38,49.77 176.66,49.5 176.66,45.97 176.95,45.67 176.95,44.31 176.52,43.87 176.52,37.56 177,37.08 177,34.65 176.83,34.49 176.83,32.59 176.41,32.17 176.41,24.48 176.27,24.34 176.27,20.94 176.2,20.87 176.2,17.17 178.04,15.33 178.04,13.5 177.22,12.68 175.14,12.68 171.99,9.53 156.02,9.53 153.01,6.52 133.48,6.52 132.07,5.11 127.34,5.11 125.49,6.96 124.55,6.96 120.97,10.55 120.97,12.81 120.21,13.57 118.7,13.57 117.51,14.76 117.51,16.92 115.54,18.89 115.54,21.1 114.95,21.7 114.95,22.56 114.09,23.42 114.09,29.41 112.23,31.27 112.23,34.02 113.03,34.82 113.03,35.57 112.72,35.88 112.72,38.04 112.53,38.23 112.53,38.8
  BOTTOM w0.102: v2(112.06,40.12) 112.08,40.12 112.38,40.43 CPU1.AF8
USB_CPU_PN7_C: length 3.3
  TOP w0.102: v1(170.46,47.59) 170.46,47.46 ; 170.46,47.46 170.13,47.46 v2(169.87,47.72) ; 170.46,47.46 171.43,47.46 TR6602.1
  BOTTOM w0.102: v2(169.87,47.72) 169.82,47.72 169.75,47.79 169.64,47.79 169.23,48.21 IOBD1.22
USB_CPU_PN8: length 97.4
  TOP w0.102: R6905.1 45.71,29.77 45.87,29.94 46.12,29.94 46.35,29.71 v2(46.35,29.68) 46.71,29.68 v1(46.91,29.48)
  L6 w0.127: v2(111.53,33.82) 111.12,33.42 111.12,33.16 110.87,32.91 110.87,30.98 109.19,29.3 109.19,28.16 107.19,26.15 107.19,25.51 106.63,24.96 105.66,24.96 105.39,24.69 100.21,24.69 99.57,24.05 99.57,22.67 98.88,21.99 97.12,21.99 96.08,20.95 94.99,20.95 94.45,21.49 91.96,21.49 91.9,21.43 88.03,21.43 87.67,21.8 86.27,21.8 85.6,22.47 84.31,22.47 83.23,21.39 81.57,21.39 80.51,20.32 79.72,20.32 78.5,19.1 78.09,19.1 74,15.02 69.12,15.02 68.92,15.22 67.5,15.22 67.14,15.57 65.21,15.57 64.68,16.1 64.68,16.53 64.27,16.95 62.47,16.95 62.4,16.87 53.62,16.87 50.95,19.54 49.34,19.54 46.86,22.01 45.84,22.01 44.23,23.62 44.23,27.41 44.97,28.15 44.97,29.84 45.18,30.05 45.49,30.05 45.62,29.93 45.62,29.38 45.73,29.26 45.93,29.26 v2(46.35,29.68)
  BOTTOM w0.102: v2(111.53,33.82) 111.53,33.71 111.67,33.57 111.89,33.57 111.99,33.66 111.99,35.94 111.8,36.13 CPU1.AG1
USB_CPU_PP0: length 148.1
  TOP w0.102: v2(22.05,44.39) v1(21.49,44.39)
  L6 w0.089: 115.3,38.97 115.23,39.05 115.17,39.05 114.82,39.4 114.82,41.1 114.49,41.43 v2(114.22,41.43)
  L6 w0.127: 115.3,38.97 115.67,38.6 116.41,37.87 116.41,31.34 115.58,30.51 115.58,29.08 115.95,28.71 115.95,26.67 115.67,26.39 115.67,22.3 114.23,20.86 114.23,18.9 113.27,17.94 107.2,17.94 106.92,18.22 105.47,18.22 105.26,18.01 92.52,18.01 91.82,18.71 87,18.71 86.63,19.08 85.08,19.08 84.76,18.76 82.68,18.76 81.61,17.7 80.82,17.7 79.6,16.48 79.2,16.48 74.55,11.83 66.35,11.83 66.18,11.99 64.96,11.99 63.04,13.91 61.85,13.91 61.52,14.24 52.58,14.24 50.2,16.63 47.09,16.63 36.04,27.68 36.04,36.39 35.15,37.28 33.4,37.28 32.97,36.85 26.34,36.85 26.02,37.16 25.6,37.58 25.6,43.32 24.53,44.39 v2(22.05,44.39)
  BOTTOM w0.102: v2(114.22,41.43) 114.51,41.73 CPU1.AB10 ; v2(22.05,44.39) 21.81,44.63 21.55,44.63 21.33,44.85 21.33,45.51 21.64,45.81 22.09,45.81 22.24,45.95 22.24,46.06 22.1,46.2 U3401.3
USB_CPU_PP1: length 138.6
  TOP w0.102: v2(26.54,38.29) 26.52,38.27 v1(25.98,38.27)
  L6 w0.127: v2(113.13,39.96) 113.59,39.51 113.59,38.99 113.46,38.86 113.46,38.43 115.76,36.13 115.76,32.95 114.54,31.73 114.54,28.53 113.24,27.23 113.24,23.42 109.23,19.41 104.39,19.41 104.31,19.49 99.05,19.49 98.35,18.79 92.86,18.79 92.15,19.5 87.33,19.5 86.96,19.87 84.75,19.87 84.43,19.55 82.35,19.55 81.28,18.48 80.49,18.48 79.27,17.26 78.87,17.26 74.78,13.17 68.35,13.17 68.15,13.38 67.08,13.38 66.68,12.98 65.09,12.98 65.01,13.06 63.35,14.72 62.15,14.72 61.85,15.03 52.89,15.03 50.34,17.58 47.58,17.58 41.53,23.64 41.53,26.94 42.24,27.65 42.24,36.54 40.66,38.12 32.84,38.12 32.47,37.75 28.23,37.75 27.69,38.29 v2(26.54,38.29)
  BOTTOM w0.102: v2(26.54,38.29) 26.13,37.89 26.13,37.2 26.41,36.92 26.41,35.02 26.28,34.88 25.42,34.03 24.31,34.03 24.16,33.89 TR3603.4 ; CPU1.AD7 113.32,39.77 v2(113.13,39.96)
USB_CPU_PP2: length 148.2
  TOP w0.102: v2(178.04,49.88) 177.54,49.88 177.42,50 177.42,50.37 176.89,50.89 176.05,50.89 ; 176.05,50.89 v1(176.05,50.77) ; 176.05,50.89 175,50.89 174.2,50.09 173.76,50.09 173.63,49.96 173.63,49.76 173.51,49.64 TR6601.3
  L3 w0.14: v2(108.99,34.28) 109.47,34.28 109.66,34.09 109.66,32.92 110.26,32.32 110.26,29.15 112.74,26.67 112.74,22.03 114.23,20.53 114.23,17.97 115.8,16.4 115.8,14.27 116.56,13.5 116.89,13.5 119.66,10.74 119.66,9.95 120.45,9.16 120.45,8.55 121.35,7.65 121.98,7.65 124,5.63 124.94,5.63 126.8,3.77 129.07,3.77 129.27,3.57 151.97,3.57 156.59,8.2 173.15,8.2 175.16,10.2 178.38,10.2 179.58,11.4 179.58,12.75 179.35,12.97 179.35,16.04 178.48,16.9 178.48,29.13 178.03,29.58 178.03,31.11 179.02,32.1 179.02,34.91 178.31,35.62 178.31,37.62 177.82,38.1 177.82,43.33 178.26,43.76 178.26,45.61 178.75,46.11 178.75,47.27 178.93,47.45 178.93,48.98 178.58,49.33 178.58,50.04 178.48,50.13 178.28,50.13 178.04,49.89 v2(178.04,49.88)
  BOTTOM w0.089: CPU1.AJ3 110.69,37.48 110.69,37.25 110.73,37.14 110.73,36.94 110.69,36.87 110.69,36.58 110.73,36.49 110.73,36.09 110.6,35.97 110.6,35.75
  BOTTOM w0.102: v2(108.99,34.28) 109.22,34.05 109.45,34.05 110.6,35.2 110.6,35.75
USB_CPU_PP2_C: length 3.5
  TOP w0.102: TR6601.4 171.43,49.64 171.17,49.9 170.79,49.9 170.28,49.39 ; v1(170.38,49.29) 170.28,49.39 ; 170.28,49.39 v2(169.87,48.99)
  BOTTOM w0.102: v2(169.87,48.99) 169.65,49.21 IOBD1.20
USB_CPU_PP3: length 188.9
  TOP w0.102: v1(20.42,94.86) 20.27,94.86 v2(19.91,95.22) 19.84,95.29 TR3805.2
  L6 w0.089: 112.89,37.86 112.89,37.96 112.51,38.34 112.51,41.61 112.72,41.82 112.92,41.82 v2(113.11,42)
  L6 w0.127: v2(19.91,95.22) 20.1,95.03 20.48,95.03 21.22,94.29 24.12,94.29 24.59,93.82 24.59,84.45 22.23,82.1 22.23,79.63 22.44,79.43 22.44,76.89 24.94,74.39 27.55,74.39 29.84,72.1 29.84,71.19 30.81,70.22 30.81,68.07 30.31,67.57 30.31,64.8 30.81,64.3 30.81,63.11 31.86,62.06 31.86,57.94 39.58,50.22 39.58,43.61 41.16,42.04 41.16,39.88 44.96,36.08 44.96,31.3 43.46,29.8 43.46,23.23 45.71,20.97 46.76,20.97 49.08,18.65 50.75,18.65 53.31,16.08 62.29,16.08 62.59,15.78 63.89,15.78 64.88,14.79 66.64,14.79 66.99,14.43 68.59,14.43 68.79,14.23 74.34,14.23 78.42,18.32 78.83,18.32 80.05,19.54 80.84,19.54 81.9,20.6 83.56,20.6 84.62,21.67 85.27,21.67 85.94,21.01 85.94,21.01 86.03,20.92 87.43,20.92 87.7,20.64 92.3,20.64 92.38,20.72 94.13,20.72 94.67,20.17 96.4,20.17 96.8,20.57 104.7,20.57 104.82,20.45 108.78,20.45 109.13,20.8 109.13,23.09 109.62,23.59 110.53,23.59 110.78,23.84 110.78,24.23 112.04,25.49 112.04,34.05 113.23,35.24 113.23,36.39 112.89,36.74 112.89,37.86
  BOTTOM w0.102: CPU1.AD10 113.67,41.95 113.54,42.08 113.19,42.08 v2(113.11,42)
USB_CPU_PP4: length 168.1
  TOP w0.102: v2(68.42,90) 68.42,90.31 68.55,90.44 68.76,90.44 68.87,90.56 68.87,91.37 68.6,91.65 68.32,91.65 68.2,91.52 68.2,91.32 68.07,91.19 TR5501.1 ; v2(107.57,34.69) 107.8,34.46 v1(108.1,34.46)
  L6 w0.127: v2(68.42,90) 68.42,90.41 68.35,90.49 66.37,90.49 65.56,89.68 57.73,89.68 57.31,90.1 54.21,90.1 51.38,87.26 51.38,66.53 48.97,64.13 48.97,54.2 41.64,46.87 41.64,44.37 48.3,37.72 48.3,22.94 50.12,21.11 51.57,21.11 54.22,18.46 55.86,18.46 55.92,18.52 65.16,18.52 66.48,17.2 70.75,17.2 73.59,20.03 74.37,20.03 75.82,21.48 76.96,21.48 78.15,22.67 78.69,22.67 87.04,31.03 94.92,31.03 96.42,32.53 100.18,32.53 101.28,33.63 101.28,33.63 102.01,34.36 107.24,34.36 v2(107.57,34.69)
  BOTTOM w0.102: v2(107.57,34.69) 107.79,34.47 108.14,34.47 108.59,34.92 109.72,34.92 110.13,35.33 110.13,36.75 110.43,37.05 CPU1.AJ2
USB_CPU_PP5: length 150.1
  TOP w0.102: 174.96,53.4 175.56,53.99 176.86,53.99 177.16,53.69 177.16,53.23 176.88,52.95 v2(176.45,52.95) ; 174.96,53.4 174.7,53.14 174.7,52.85 174.29,52.44 173.72,52.44 R6606.2 ; 174.96,53.4 v1(175.05,53.31)
  L3 w0.14: v2(176.45,52.95) 176.52,52.89 177.06,52.89 177.44,52.5 177.44,46.38 177.73,46.09 177.73,43.98 177.3,43.55 177.3,37.89 177.79,37.4 177.79,35.41 178.5,34.7 178.5,33.13 177.87,32.5 177.2,31.83 177.2,29.67 177.96,28.91 177.96,16.69 178.83,15.82 178.83,12.4 179.04,12.18 179.04,11.65 178.16,10.77 174.63,10.77 172.6,8.74 156.35,8.74 153.08,5.48 135.02,5.48 133.85,4.31 127.02,4.31 125.17,6.16 124.23,6.16 120.18,10.21 120.18,10.96 117.11,14.02 116.78,14.02 116.32,14.49 116.32,16.9 114.96,18.25 114.76,18.46 114.76,20.77 113.26,22.27 113.26,26.92 111.86,28.32 111.86,30.17 110.85,31.18 110.85,37.55 110.56,37.84 110.56,38.87 110.95,39.26 111.86,39.26 v2(112.06,39.46)
  BOTTOM w0.102: CPU1.AF7 112.59,39.77 112.37,39.77 v2(112.06,39.46)
USB_CPU_PP5_C: length 4.6
  TOP w0.102: R6606.1 171.5,52.33 171.23,52.33 170.84,51.93 170.84,51.45 170.48,51.1 170.13,51.1 v2(169.92,50.89) 170.23,50.59 v1(170.43,50.59)
  BOTTOM w0.102: IOBD1.17 169.26,50.71 169.44,50.89 v2(169.92,50.89)
USB_CPU_PP6: length 180.9
  TOP w0.102: v2(73.46,89.98) 73.89,90.42 74.17,90.42 75.31,91.55 75.31,92.33 75.12,92.51 74.78,92.51 74.65,92.39 74.65,91.91 74.29,91.56 R5511.2 ; v2(111.58,35.75) 112.11,35.22 v1(112.11,35.07)
  L6 w0.127: v2(111.58,35.75) 111.21,35.39 110.42,35.39 110,34.97 108.6,34.97 108.25,34.62 108.25,33.24 107.91,32.9 101.66,32.9 99.02,30.26 87.39,30.26 79.02,21.89 78.48,21.89 77.29,20.69 76.15,20.69 73.63,18.18 73.63,17.95 72.11,16.43 66.14,16.43 64.83,17.73 62.16,17.73 62.09,17.66 53.93,17.66 51.26,20.32 49.79,20.32 47.48,22.63 47.48,37.37 40.82,44.03 40.82,47.42 47.42,54.02 47.42,64.46 47.45,64.48 47.45,64.63 50.6,67.78 50.6,87.6 53.87,90.87 57.86,90.87 58.27,90.47 65.09,90.47 65.91,91.28 68.65,91.28 69.49,90.44 73,90.44 v2(73.46,89.98)
  BOTTOM w0.102: v2(111.58,35.75) 111.4,35.93 111.4,37.1 CPU1.AH2
USB_CPU_PP7: length 141.7
  TOP w0.102: v2(176.2,49.32) 175.94,49.57 174.72,49.57 174.27,49.12 174.27,48.51 ; 174.27,48.51 v1(174.39,48.51) ; 174.27,48.51 174.27,47.64 173.98,47.36 173.6,47.36 173.26,47.01 TR6602.3
  L3 w0.089: v2(112.06,40.78) 112.33,41.05 112.46,41.05 112.55,40.96 112.55,39.9 112.72,39.73 112.72,38.95 112.8,38.88
  L3 w0.14: v2(176.2,49.32) 176.39,49.13 176.39,45.85 176.68,45.56 176.68,44.42 176.25,43.98 176.25,37.45 176.73,36.97 176.73,34.76 176.57,34.6 176.57,32.7 176.15,32.28 176.15,24.59 176.01,24.45 176.01,21.05 175.94,20.98 175.94,17.06 177.77,15.22 177.77,13.61 177.11,12.95 175.03,12.95 171.88,9.8 155.91,9.8 152.9,6.79 133.36,6.79 131.96,5.38 127.46,5.38 125.6,7.23 124.66,7.23 121.23,10.66 121.23,12.92 120.32,13.83 118.81,13.83 117.78,14.87 117.78,17.03 115.81,19 115.81,21.21 115.21,21.81 115.21,22.67 114.36,23.53 114.36,29.52 112.5,31.38 112.5,33.91 113.3,34.71 113.3,35.68 112.99,35.99 112.99,38.15 112.8,38.34 112.8,38.88
  BOTTOM w0.102: CPU1.AF9 112.35,41.08 v2(112.06,40.78)
USB_CPU_PP7_C: length 3.8
  TOP w0.102: v1(169.29,47.11) 169.34,47.06 v2(169.87,47.06) 169.95,47.06 170.13,47.24 171.44,47.24 TR6602.4
  BOTTOM w0.102: v2(169.87,47.06) 169.87,47.08 169.25,47.71 IOBD1.23
USB_CPU_PP8: length 97.9
  TOP w0.102: v1(46.94,30.73) 46.53,30.32 v2(46.35,30.32) 46.23,30.45 R6906.1
  L6 w0.127: v2(111.53,33.19) 111.14,32.8 111.14,30.87 109.46,29.19 109.46,28.05 107.45,26.04 107.45,25.4 106.74,24.69 105.77,24.69 105.5,24.43 100.32,24.43 99.83,23.93 99.83,22.56 98.99,21.72 97.23,21.72 96.19,20.68 94.88,20.68 94.34,21.23 92.07,21.23 92.01,21.16 87.92,21.16 87.56,21.53 86.16,21.53 85.48,22.2 84.42,22.2 83.34,21.12 81.68,21.12 80.62,20.06 79.83,20.06 78.61,18.84 78.2,18.84 74.12,14.75 69.01,14.75 68.81,14.95 67.39,14.95 67.03,15.31 65.1,15.31 64.41,15.99 64.41,16.42 64.16,16.68 62.62,16.68 62.54,16.6 53.51,16.6 50.84,19.27 49.23,19.27 46.75,21.75 45.73,21.75 43.97,23.51 43.97,27.52 44.7,28.26 44.7,29.95 45.07,30.32 v2(46.35,30.32)
  BOTTOM w0.102: CPU1.AG2 111.8,36.86 112.11,36.54 112.11,36.14 112.22,36.03 112.22,33.57 111.99,33.34 111.68,33.34 v2(111.53,33.19)
USB_EN#: length 352.8
  TOP w0.127: v2(200.02,34.31) 200.02,34.56 199.54,35.04 199.54,35.04 KBC24.13 ; v2(179.04,54.65) 178.69,55.01 177.26,55.01 177.01,54.75 v1(171.83,54.75) 171.6,54.75 170.43,53.59 v2(169.87,53.59)
  L3 w0.127: v2(22.4,38.75) 22.4,41.57 23.05,42.22 23.05,42.6 v2(22.6,43.04) 22.4,42.84 20.42,42.84 19.26,44 19.26,50.79 19.94,51.47 19.94,55.77 20.39,56.23 20.39,56.96 22.71,59.27 24.59,59.27 26.82,61.51 26.82,66.93 30.68,70.79 30.68,72.89 32,74.21 32,79.72 33.86,81.58 33.86,81.63 33.87,81.64 33.87,84.61 31.95,86.53 31.95,93.72 32.59,94.35 32.84,94.35 33.37,94.89 36.63,94.89 41.5,99.76 47.82,99.76 49.03,100.98 56.61,100.98 57.9,99.7 62.48,99.7 62.85,100.07 75.61,100.07 77.06,101.52 77.34,101.52 78.8,102.98 79.29,102.98 84.02,107.7 84.02,109.66 86.64,112.27 86.7,112.27 86.82,112.4 161.84,112.4 166.25,107.98 166.25,105.96 168.05,104.16 170.02,104.16 170.91,103.27 170.91,99.73 172.41,98.24 175.32,98.24 177.07,96.49 178.92,96.49 179.53,95.88 179.53,92.68 178.03,91.18 178.03,89.55 179.04,88.54 179.04,73.45 175.79,70.2 175.79,63.76 178.55,61 178.55,55.15 v2(179.04,54.65) 179.42,54.27 179.42,51.27 180.05,50.64 180.05,49.99 180.47,49.57 180.47,48.43 180.81,48.09 180.81,46.5 183.49,43.82 185.06,43.82 185.21,43.67 191.85,43.67 191.98,43.54 193.77,43.54 193.84,43.48 197.83,43.48 198.21,43.1 198.21,42.33 198.77,41.77 198.77,39.75 199.41,39.11 199.41,36.62 200.02,36.01 v2(200.02,34.31)
  BOTTOM w0.127: IOBD1.49 169.29,34.71 170.33,35.75 170.33,35.81 170.56,36.03 170.56,52.9 v2(169.87,53.59) ; v2(200.02,34.31) 199.77,34.31 199.57,34.1 198.83,34.1 198.33,34.6 R2434.2 ; U3501.4 23.05,42.6 v2(22.6,43.04) ; U3502.4 23.03,38.13 v2(22.4,38.75)
USB_OC0#: length 352
  TOP w0.102: v2(24.33,50.16) 23.9,49.72 23.21,49.72 22.93,50 22.1,50 21.23,49.14 v1(21.23,47.57) 21.23,45.58 20.88,45.23 20.88,44.42 21.44,43.86 21.44,43.1 22.12,42.41 v2(22.6,42.41) ; v2(131.88,38.5) 128.79,41.58 126.96,41.58 126.7,41.33 126.68,41.33 v2(126.44,41.09)
  L3 w0.102: v2(30.61,92.17) 31.71,91.06 31.71,86.43 33.63,84.51 33.63,81.74 33.6,81.72 33.6,81.68 31.75,79.82 31.75,74.31 30.43,72.99 30.43,70.91 26.58,67.06 26.58,61.62 24.49,59.53 22.62,59.53 20.14,57.05 20.14,56.33 19.68,55.87 19.68,51.55 19.02,50.89 19.02,43.9 20.33,42.59 22.43,42.59 v2(22.6,42.41) 22.6,42.12 21.41,40.92 21.41,39.12 v2(21.77,38.76) ; v2(171.12,95.24) 170.84,95.52 170.84,96.16 166.19,100.8 166.19,103.67 164.72,105.15 164.72,107.31 161.24,110.79 133.98,110.79 133.2,110 121.65,110 120.76,110.89 87.45,110.89 85.53,108.97 85.53,106.82 78.83,100.12 78.28,100.12 77.16,98.99 64.78,98.99 63.95,98.16 57.35,98.16 56.27,99.24 48.83,99.24 48.23,98.64 45.64,98.64 44.58,97.58 v2(44.32,97.58)
  L4 w0.102: v2(171.12,95.24) 170.29,94.42 170.29,90.37 170.25,90.34 170.25,80.1 169.62,79.47 169.62,79.21 169.56,79.15 169.56,71.89 168.36,70.69 168.36,61.28 167,59.92 167,58 165.38,56.38 165.38,41.51 165.54,41.34 165.54,37.46 163.17,35.09 154.74,35.09 153.1,33.46 151.95,33.46 151.58,33.09 147.93,33.09 147.05,32.21 144.77,32.21 144.45,32.53 137.21,32.53 134.49,35.25 134.49,37.41 132.34,39.56 131.7,39.56 131.44,39.31 131.44,38.93 v2(131.88,38.5)
  L6 w0.102: v2(30.61,92.17) 30.91,92.47 34.62,92.47 35.25,93.11 35.25,94.12 35.36,94.23 36.4,94.23 38.71,96.54 43.28,96.54 v2(44.32,97.58)
  BOTTOM w0.102: v2(22.6,42.41) 22.42,42.6 U3501.3 ; CPU1.A9 126.4,41.05 v2(126.44,41.09) ; U3401.13 24.33,49.53 v2(24.33,50.16) ; U3502.3 21.46,38.46 v2(21.77,38.76) ; v2(131.88,38.5) 131.79,38.42 RN1601.6
USB_OC1#: length 54.7
  TOP w0.102: v2(126.54,41.72) 126.6,41.79 129.22,41.79 v1(131.14,39.87) v2(131.88,39.13)
  L4 w0.102: v2(164.82,35.37) 164.69,35.25 163.83,35.25 163.47,34.89 154.91,34.89 153.27,33.25 152.03,33.25 151.67,32.88 148.03,32.88 146.15,31 140.66,31 139.65,32.02 137.51,32.02 137.02,31.53 136.25,31.53 133.81,33.98 133.81,37.81 132.48,39.13 131.88,39.13 v2(131.88,39.13)
  BOTTOM w0.102: IOBD1.48 167.34,35.21 167.18,35.37 v2(164.82,35.37) ; v2(131.88,39.13) 131.81,39.07 RN1601.5 ; CPU1.C9 124.69,41.05 125.04,41.39 125.9,41.39 126.24,41.72 v2(126.54,41.72)
USB_OC2#: length 11.9
  TOP w0.102: v2(127.2,40.25) 127.2,40.4 127.99,41.19 128.49,41.19 129.94,39.74 v1(129.94,39.41) 129.94,39.16 131.88,37.23 v2(131.88,37.2)
  BOTTOM w0.102: CPU1.D9 124.17,41.05 124.48,40.73 124.76,40.73 124.81,40.78 125.09,40.78 125.47,40.4 127.05,40.4 v2(127.2,40.25) ; RN1601.8 131.02,37.27 131.09,37.2 v2(131.88,37.2)
USB_OC3#: length 9.9
  TOP w0.102: v2(127.05,40.89) 127.54,41.38 128.59,41.38 130.43,39.54 130.43,39.33 v1(131.19,38.57) 131.88,37.89 v2(131.88,37.84)
  BOTTOM w0.102: CPU1.B9 125.47,41.05 125.91,40.61 126.77,40.61 v2(127.05,40.89) ; RN1601.7 131.16,37.92 131.25,37.83 131.87,37.83 v2(131.88,37.84)
USB_PN0_R: length 3.6
  BOTTOM w0.102: TR3602.1 24.14,51.62 23.91,51.39 23.91,51.2 23.68,50.96 22.63,50.96 22.46,50.79 22.46,50.64 22.6,50.51 U3401.11
USB_PN6_TPNL: length 4.5
  TOP w0.102: v2(70.23,93.92) 70.05,93.74 70.05,93.36 ; R5510.1 71.91,92.98 71.67,92.74 70.28,92.74 70.05,92.97 70.05,93.36 ; v1(70.18,93.36) 70.05,93.36
  BOTTOM w0.102: v2(70.23,93.92) 70.15,93.84 TCBD1.31
USB_PP0_R: length 3.6
  BOTTOM w0.102: TR3602.4 23.46,51.62 23.68,51.39 23.68,51.29 23.58,51.19 22.54,51.19 22.24,50.89 22.24,50.64 22.1,50.51 U3401.10
USB_PP6_TPNL: length 5.6
  TOP w0.102: 70.92,92.51 71.49,92.51 71.58,92.42 71.58,91.96 71.98,91.56 R5511.1 ; 70.92,92.51 70.19,92.51 69.82,92.88 69.82,93.72 v2(69.59,93.95) ; 70.92,92.51 v1(70.92,92.37)
  BOTTOM w0.102: TCBD1.30 69.65,93.89 v2(69.59,93.95)
USB_TYPEC_DIS: length 11.6
  TOP w0.254: v2(32.87,73.42) 32.87,73.02 v1(33.07,72.81) 33.27,72.61 33.27,70.35 33.08,70.16 PQ4310.6 ; PR4338.2 v2(37.77,75.4)
  BOTTOM w0.254: v2(32.87,73.42) 33.04,73.24 35.61,73.24 v2(37.77,75.4)
USB_TYPEC_R: length 17.9
  TOP w0.127: PU4303.4 41.77,81.71 41.53,81.96 v2(41.45,81.96) ; PC4310.1 42.21,69.89 41.98,69.66 v1(41.65,69.66) 41.07,70.25 41.07,70.97 PR4336.1 40.52,71.52 PR4322.1 40.07,70.9 v2(40.1,70.86)
  L6 w0.127: v2(40.1,70.86) 39.67,71.29 39.67,79.85 41.3,81.47 41.3,81.8 v2(41.45,81.96)
USB_TYPEC_SW: length 2.3
  TOP w0.254: v1(39.18,70.6) PR4322.2 39.12,71.46 PQ4307.3
USB_UART_SEL_D9: length 4
  TOP w0.102: v2(118.01,34) 118.11,33.9 TP2006.1
  BOTTOM w0.089: CPU1.P2 118.2,36.82 118.2,36.59 118.16,36.5 118.16,35.91 118.44,35.64 118.44,34.43 118.39,34.38
  BOTTOM w0.102: v2(118.01,34) 118.39,34.38
USBC1_CC1_CONN: length 100.9
  TOP w0.432: v2(30.71,47.82) 31.09,47.82 31.18,47.91 R3709.2
  TOP w0.508: R3709.2 C3711.1 R3720.2
  L3 w0.508: v2(10.18,99.91) 11.94,98.16 11.94,94.99 11.3,94.35 10.26,94.35 v2(9.52,93.62) ; v2(30.71,47.82) 30.88,48 30.88,48.72 30.63,48.97 30.63,49.73 31.95,51.05 31.95,54.69 32.44,55.19 32.82,55.56 32.82,56.59 31.93,57.48 31.93,61.37 30.68,62.61 30.68,64.99 35.3,69.61 35.3,73.26 35.83,73.79 35.83,76.26 36.47,76.9 36.47,85.72 34.92,87.27 34.92,91.79 35.71,92.57 v2(35.71,93.31)
  L4 w0.508: v2(10.18,99.91) 10.51,100.25 22.15,100.25 24.41,97.98 30.17,97.98 32.51,95.65 33.75,95.65 35.69,93.72 35.69,93.34 v2(35.71,93.31)
  BOTTOM w0.178: 8.51,93.74 8.48,93.74 8.2,93.46 USB1.A5
  BOTTOM w0.305: v2(9.52,93.62) 9.4,93.74 8.51,93.74
  BOTTOM w0.508: v2(26.49,42.38) 27.26,42.38 27.76,42.88 27.76,43.41 27.53,43.64 27.53,45.89 28.8,47.16 28.82,47.16 29.1,47.44 30.28,47.44 30.53,47.69 30.58,47.69 v2(30.71,47.82)
  vias: v1(25.7,41.75)
USBC1_CC2_CONN: length 119.5
  L3 w0.076: 7.39,95.09 7.36,95.06 USB1.B5
  L3 w0.089: USB1.B5 6.38,95.64 arc(6.41,95.73) 6.48,95.82 6.5,95.84 arc(6.56,95.89) 6.62,95.94 6.62,96.17
  L3 w0.229: 7.82,96.36 6.81,96.36 6.62,96.17 ; 7.82,96.36 8.99,97.53 8.99,97.88 9.55,98.44 9.55,99.38 v2(9.49,99.44) ; 7.82,96.36 7.82,95.52 7.39,95.09
  L3 w0.508: v2(36.45,93.75) 36.45,93.67 36.47,93.64 36.47,92.24 35.71,91.48 35.71,87.57 37.23,86.05 37.23,75.96 36.6,75.33 36.6,69.94 36.7,69.84 36.7,69.31 36.33,68.94 35.71,68.94 34.01,67.24 34.01,62.15 35.36,60.8 35.36,57.85 33.65,56.15 33.65,55.13 32.76,54.25 32.76,50.28 32.82,50.23 32.82,49.06 31.7,47.95 31.7,46.04 30.78,45.13 v2(28.19,45.13)
  L4 w0.089: 6.62,96.17 6.62,95.94 arc(6.56,95.89) 6.5,95.84 6.48,95.82 arc(6.41,95.73) 6.38,95.64 USB1.B5
  L4 w0.229: 6.62,96.17 6.81,96.36 7.82,96.36 8.99,97.53 8.99,97.88 9.55,98.44 9.55,99.38 v2(9.49,99.44)
  L4 w0.508: v2(9.49,99.44) 9.49,100.45 10.06,101.01 22.5,101.01 24.74,98.77 30.53,98.77 32.76,96.54 34.16,96.54 36.45,94.25 v2(36.45,93.75)
  L6 w0.076: USB1.B5 7.49,95.06 7.57,95.14
  L6 w0.089: 6.62,96.17 6.62,95.94 arc(6.56,95.89) 6.5,95.84 6.48,95.82 arc(6.41,95.73) 6.38,95.64 USB1.B5 5.96,94.26 6.38,93.68 arc(6.41,93.59) 6.48,93.5 6.48,93.41 arc(6.45,93.26) 6.38,93.12 arc(6.36,93.08) 6.33,93.05 6.33,92.84 6.38,92.78 arc(6.41,92.69) 6.48,92.6 6.5,92.58 arc(6.56,92.53) 6.62,92.48 arc(6.79,92.41) 6.98,92.38
  L6 w0.102: 7.36,92.52 7.22,92.38 6.98,92.38
  L6 w0.229: v2(9.49,99.44) 9.55,99.38 9.55,98.44 8.99,97.88 8.99,97.53 7.82,96.36 ; 7.82,96.36 7.82,96.1 7.57,95.85 7.57,92.73 7.36,92.52 ; 7.82,96.36 6.81,96.36 6.62,96.17
  vias: v1(22.88,43.65)
USBC_CON_PN3: length 19.5
  TOP w0.102: 13.32,93.3 12.42,94.2 11.74,94.2 11.53,94 11.53,93.64 v2(11.66,93.51) 11.43,93.29 11.43,93.01 11.17,92.75 9.04,92.75 7.7,94.1 7.14,94.1 USB1.B7 ; 13.32,93.3 13.8,92.83 15.7,92.83 EU3804.1 15.85,92.85 16.08,93.08 16.08,93.78 17.11,94.81 17.37,94.81 17.55,94.64 TR3805.4 ; 13.32,93.3 v1(13.23,93.21)
  BOTTOM w0.102: v2(11.66,93.51) 11.45,93.72 11.45,94.32 11.21,94.56 10.34,94.56 10.1,94.32 8.23,94.32 8.09,94.46 USB1.A7
USBC_CON_PP3: length 19.1
  TOP w0.102: v1(16.38,94.61) 16.48,94.5 ; 16.48,94.5 17.02,95.04 17.3,95.04 17.55,95.29 TR3805.3 ; 16.48,94.5 15.85,93.87 15.85,93.38 EU3804.2 15.63,93.26 15.42,93.06 13.89,93.06 12.52,94.43 11.64,94.43 11.3,94.09 11.3,93.79 v2(11.02,93.51) 11.2,93.34 11.2,93.11 11.07,92.98 9.14,92.98 7.79,94.32 7.14,94.32 USB1.B6
  BOTTOM w0.102: USB1.A6 8.12,93.96 8.25,94.1 10.2,94.1 10.43,94.33 11.12,94.33 11.23,94.23 11.23,93.72 v2(11.02,93.51)
USBC_DPAUX1: length 73
  TOP w0.102: U3801.27 32.7,62.62 32.88,62.79 32.88,63.05 v2(32.61,63.31) ; v2(16.25,95.83) 15.97,95.55 15.86,95.55 R3830.1 15.15,95.67 14.84,95.67 14.42,96.09 EU3803.9 EU3803.1 13.61,96.09 13.37,95.84 10.8,95.84 v2(10.51,96.13)
  L6 w0.127: v2(32.61,63.31) 32.98,63.68 32.98,64.09 32.87,64.2 31.72,64.2 30.83,65.09 30.83,67.35 31.32,67.83 31.32,70.43 30.35,71.4 30.35,72.36 26.77,75.94 25.4,75.94 23.93,77.41 23.93,82.84 25.18,84.1 25.18,95.08 24.99,95.27 24.99,97.53 22.26,100.26 15.48,100.26 14.02,98.8 14.02,96.21 14.57,95.66 16.09,95.66 v2(16.25,95.83)
  BOTTOM w0.102: USB1.A8 8.18,94.96 8.43,94.71 8.99,94.71 9.09,94.81 9.6,94.81 9.9,95.11 9.9,95.98 9.75,96.13 9.75,96.33 10.03,96.61 11.33,96.61 11.45,96.49 11.45,96.18 11.33,96.05 10.59,96.05 v2(10.51,96.13)
USBC_DPAUX2: length 73
  TOP w0.102: v2(16.2,95.14) 16.17,95.18 R3831.1 15.17,95.44 14.74,95.44 14.58,95.61 EU3803.8 EU3803.2 10.63,95.61 v2(10.51,95.5) ; v2(33.25,63.31) 33.1,63.17 U3801.26
  L3 w0.089: USB1.B8 6.38,92.78 arc(6.41,92.69) 6.48,92.6 6.5,92.58 arc(6.56,92.53) 6.62,92.48 arc(6.79,92.41) 6.98,92.38
  L3 w0.102: 6.98,92.38 7.17,92.38 7.26,92.47
  L3 w0.14: 7.26,92.47 10.29,95.5 v2(10.51,95.5)
  L6 w0.127: v2(33.25,63.31) 33.25,64.2 32.98,64.47 31.83,64.47 31.1,65.2 31.1,67.24 31.58,67.72 31.58,70.54 30.62,71.51 30.62,72.47 26.88,76.2 25.51,76.2 24.19,77.52 24.19,82.73 25.45,83.99 25.45,95.19 25.26,95.38 25.26,97.64 22.37,100.52 15.37,100.52 13.75,98.91 13.75,96.1 14.45,95.39 15.95,95.39 v2(16.2,95.14)
USBCHARGER_CB0: length 230.3
  TOP w0.102: v2(20.01,43.91) 19.53,44.39 19.53,48.2 v1(21.57,50.24) 22.45,51.12 24.38,51.12 25.04,50.46 27.15,50.46 27.28,50.59 28.42,50.59 28.65,50.36 29.01,50.36 29.26,50.61 30.5,50.61 30.63,50.49 32.23,50.49 36.35,46.37 38.33,46.37 42.85,41.85 v2(42.85,40.78) ; KBC24.118 193.21,27.49 192.89,27.17 192.89,26.94 v2(192.73,26.79)
  L3 w0.102: v2(83.44,18.18) 83.08,17.82 79.31,17.82 77.74,16.25 66.47,16.25 65.61,15.38 63.52,15.38 61.97,16.93 53.64,16.93 51.36,19.22 46.58,19.22 43.13,22.67 43.13,31.74 43.48,32.1 43.48,32.5 42.7,33.29 42.7,40.63 v2(42.85,40.78)
  L4 w0.102: v2(192.73,26.79) 192.61,26.79 192.1,26.28 192.1,23.66 192.43,23.33 192.43,19.69 188.68,15.94 187.2,15.94 186.51,15.26 179.61,15.26 179.14,14.79 178.9,14.79 177.19,13.07 165.12,13.07 164.31,12.26 156.77,12.26 152.45,7.94 140.61,7.94 139.5,6.82 133.15,6.82 132.54,7.43 130.4,7.43 128.85,8.98 123.04,8.98 121.99,10.02 119.39,10.02 118.74,10.67 115.94,10.67 114.82,11.79 113.96,11.79 113.31,12.44 111.84,12.44 111.56,12.16 110.06,12.16 109.88,12.34 107.47,12.34 106.65,13.15 102.59,13.15 102.18,12.74 100.58,12.74 100,13.33 95.22,13.33 93.5,15.05 91.5,15.05 87.39,19.17 84.43,19.17 v2(83.44,18.18)
  BOTTOM w0.102: v2(192.73,26.79) 192.66,26.79 191.35,28.1 R2473.1 ; R3401.1 v2(20.01,43.91)
USBCOMP: length 2.7
  TOP w0.254: v2(114.2,39.3) 113.79,39.3 113.21,38.72 v1(113.21,38.7)
  TOP w0.457: R1603.1 114.49,38.84 114.2,39.13 v2(114.2,39.3)
  BOTTOM w0.305: v2(114.2,39.3) 114.38,39.12 CPU1.AB6
USBDISABLE: length 6.9
  TOP w0.127: v2(46.35,31.59) 46.1,31.33 R6904.2 ; U6901.31 43.18,29.17 43.91,28.44 44.37,28.44 v1(44.4,28.46) 44.4,28.97 v2(44.19,29.17)
  L4 w0.127: v2(46.35,31.59) 44.19,29.43 v2(44.19,29.17)
V_EDRAM_EOPIO_R:
  vias: v1(102.67,92.8) v2(102.71,91.48) v2(103.34,91.48)
V_SM_VREF_CNTA: length 53.7
  TOP w0.508: R1206.2 73.06,48.05 C1222.1 v1(74.29,48.92) 74.86,48.92 75.56,49.62 v2(75.56,50.51)
  L4 w0.508: v2(75.56,50.51) 83.59,50.51 89.03,55.95 89.03,69.56 93.65,74.18 99.61,74.18 100.3,73.5 104.62,73.5 v2(105.36,74.24)
  BOTTOM w0.254: CPU1.AY67 104.63,74.61 104.9,74.34 105.26,74.34 v2(105.36,74.24)
V_SM_VREF_CNTB: length 80
  TOP w0.508: C1323.1 50.21,44.1 50.21,43.34 R1305.2 50.21,43.15 49.96,42.89 v1(49.5,42.89) 49.5,42.94 49.48,42.97 v2(49.48,43.6)
  L4 w0.508: v2(49.48,43.6) 50.49,43.6 51.1,44.21 63.57,44.21 65.4,46.04 71.25,46.04 73.51,48.3 73.51,50.41 75.74,52.65 84.28,52.65 88.01,56.38 88.01,69.98 93.48,75.45 v2(102.23,75.45)
  BOTTOM w0.089: CPU1.BA67 103.66,74.75 103.34,74.91 103.18,74.97 103.07,75.07 102.61,75.07 v2(102.23,75.45)
VCONN1: length 3.7
  TOP w0.127: U3701.5 32.7,44.33 33.47,45.1 v1(33.47,45.23) 33.47,45.48 33.3,45.66 32.36,45.66 32.18,45.84 R3720.1
VCONN2: length 3.9
  TOP w0.127: U3701.4 33.2,44.42 33.98,45.2 v1(33.98,46.33) 33.46,46.33 33.26,46.13 R3721.1
VCREF0: length 9.8
  TOP w0.102: KBC24.25 197.54,39.84 196.41,40.97 196.16,41.22 196.16,41.31 196.16,41.32 196.16,41.98 196.16,42.84 v2(196.29,42.97)
  BOTTOM w0.102: v2(196.29,42.97) 196.54,42.97 196.87,43.3 196.96,43.3 C2409.1 R2448.1 195.68,44.48 R2424.1 196.58,45.46 v1(196.75,45.46)
VD_IN1_C: length 137.3
  TOP w0.114: v2(120.27,26.25) v1(121.08,26.25) 121.16,26.25 122.59,27.68 122.59,27.69 122.75,27.85 122.75,28.26 123.05,28.55 123.51,28.55 123.7,28.74 123.7,29.48 v2(123.39,29.79)
  L3 w0.102: v2(128.29,7.15) 128.29,8.73 127.3,9.72 126.9,9.72 125.4,11.23 125.4,14.47 124.84,15.03 124.84,17.42 121.11,21.15 120.75,21.15 120.43,21.47 120.43,26.1 v2(120.27,26.25)
  L4 w0.114: v2(195.07,42.38) 194.94,42.26 194.94,42.05 193.22,40.33 193.06,40.33 192.8,40.08 192.8,39.91 192.28,39.39 192.25,39.39 191.99,39.14 191.99,39.1 190.73,37.84 190.67,37.84 190.42,37.59 190.42,33.25 193.4,30.27 193.77,30.27 196.42,27.62 196.42,19.55 193.2,16.32 191.79,16.32 191.26,15.79 190.8,15.79 187.04,12.03 179.04,12.03 177.84,10.83 172.9,10.83 172.27,11.47 165.65,11.47 164.97,10.79 157.43,10.79 152.42,5.78 140.64,5.78 140.24,5.38 128.89,5.38 128.26,6.01 128.26,6.37 128.29,6.4 v2(128.29,7.15)
  BOTTOM w0.114: R2611.1 194.65,41.96 v2(195.07,42.38) 195.07,42.12 C2613.2 ; C2612.2 122.86,31.25 R2610.2 122.86,30.47 123.39,29.94 v2(123.39,29.79)
VOL_DOWN#: length 46.1
  TOP w0.102: v2(186.41,38.5) 191.03,38.5 192.12,39.59 192.69,39.59 193.52,38.76 193.52,36.29 194.36,35.45 194.36,34.1 195.88,32.58 196.05,32.58 196.76,31.87 197.46,31.87 197.89,31.44 KBC24.4 ; v2(169.82,38.52) 168.71,39.64 168.71,42.51 v1(169.11,42.92) 170.55,42.92 RN2407.3
  L6 w0.102: v2(169.82,38.52) 170.03,38.32 170.03,38.32 170.28,38.07 170.28,38.07 173.18,35.17 175.11,35.17 176.35,36.41 177.93,36.41 179.02,37.51 180.35,37.51 181.06,38.22 181.32,38.22 181.4,38.29 181.41,38.29 181.56,38.45 183.72,38.45 184.38,39.11 185.11,39.11 185.37,38.85 185.37,38.7 185.67,38.4 186.31,38.4 v2(186.41,38.5)
  BOTTOM w0.102: IOBD1.42 169.51,38.21 v2(169.82,38.52)
VOL_UP#: length 46
  TOP w0.102: v2(185.85,38.83) 185.85,38.45 186.23,38.07 187.96,38.07 188.16,38.27 191.13,38.27 192.25,39.39 192.61,39.39 193.32,38.68 193.32,36.19 194.16,35.35 194.16,34.01 195.79,32.38 195.97,32.38 196.68,31.67 197.36,31.67 197.98,31.04 KBC24.3 ; v2(169.82,39.16) 169.09,39.89 169.09,41.62 v1(169.11,41.65) 169.34,41.88 170.91,41.88 171.32,42.28 RN2407.4
  L6 w0.102: v2(169.82,39.16) 173.61,35.37 175.02,35.37 176.27,36.62 177.84,36.62 178.94,37.71 180.26,37.71 180.97,38.42 181.24,38.42 181.47,38.65 183.61,38.65 184.28,39.31 185.37,39.31 v2(185.85,38.83)
  BOTTOM w0.102: IOBD1.41 169.37,38.71 v2(169.82,39.16)
VR_CAP: length 3.1
  TOP w0.203: v2(199.95,36.72) 199.63,37.04 KBC24.18
  BOTTOM w0.254: C2418.1 199.26,37.35 199.9,36.72 v2(199.95,36.72) 200.04,36.62 v1(200.04,36.03)
VR_EN: length 1.8
  BOTTOM w0.102: PR4630.2 162.47,99.69 R4002.2 162.49,100.37 163.24,100.37 v1(163.37,100.5)
VR_RDY: length 3.9
  TOP w0.102: AFTP4601.1 165.03,98.98 v2(165.43,98.58)
  BOTTOM w0.102: PR4670.2 163.38,98.64 PR4614.2 165.3,98.71 v2(165.43,98.58)
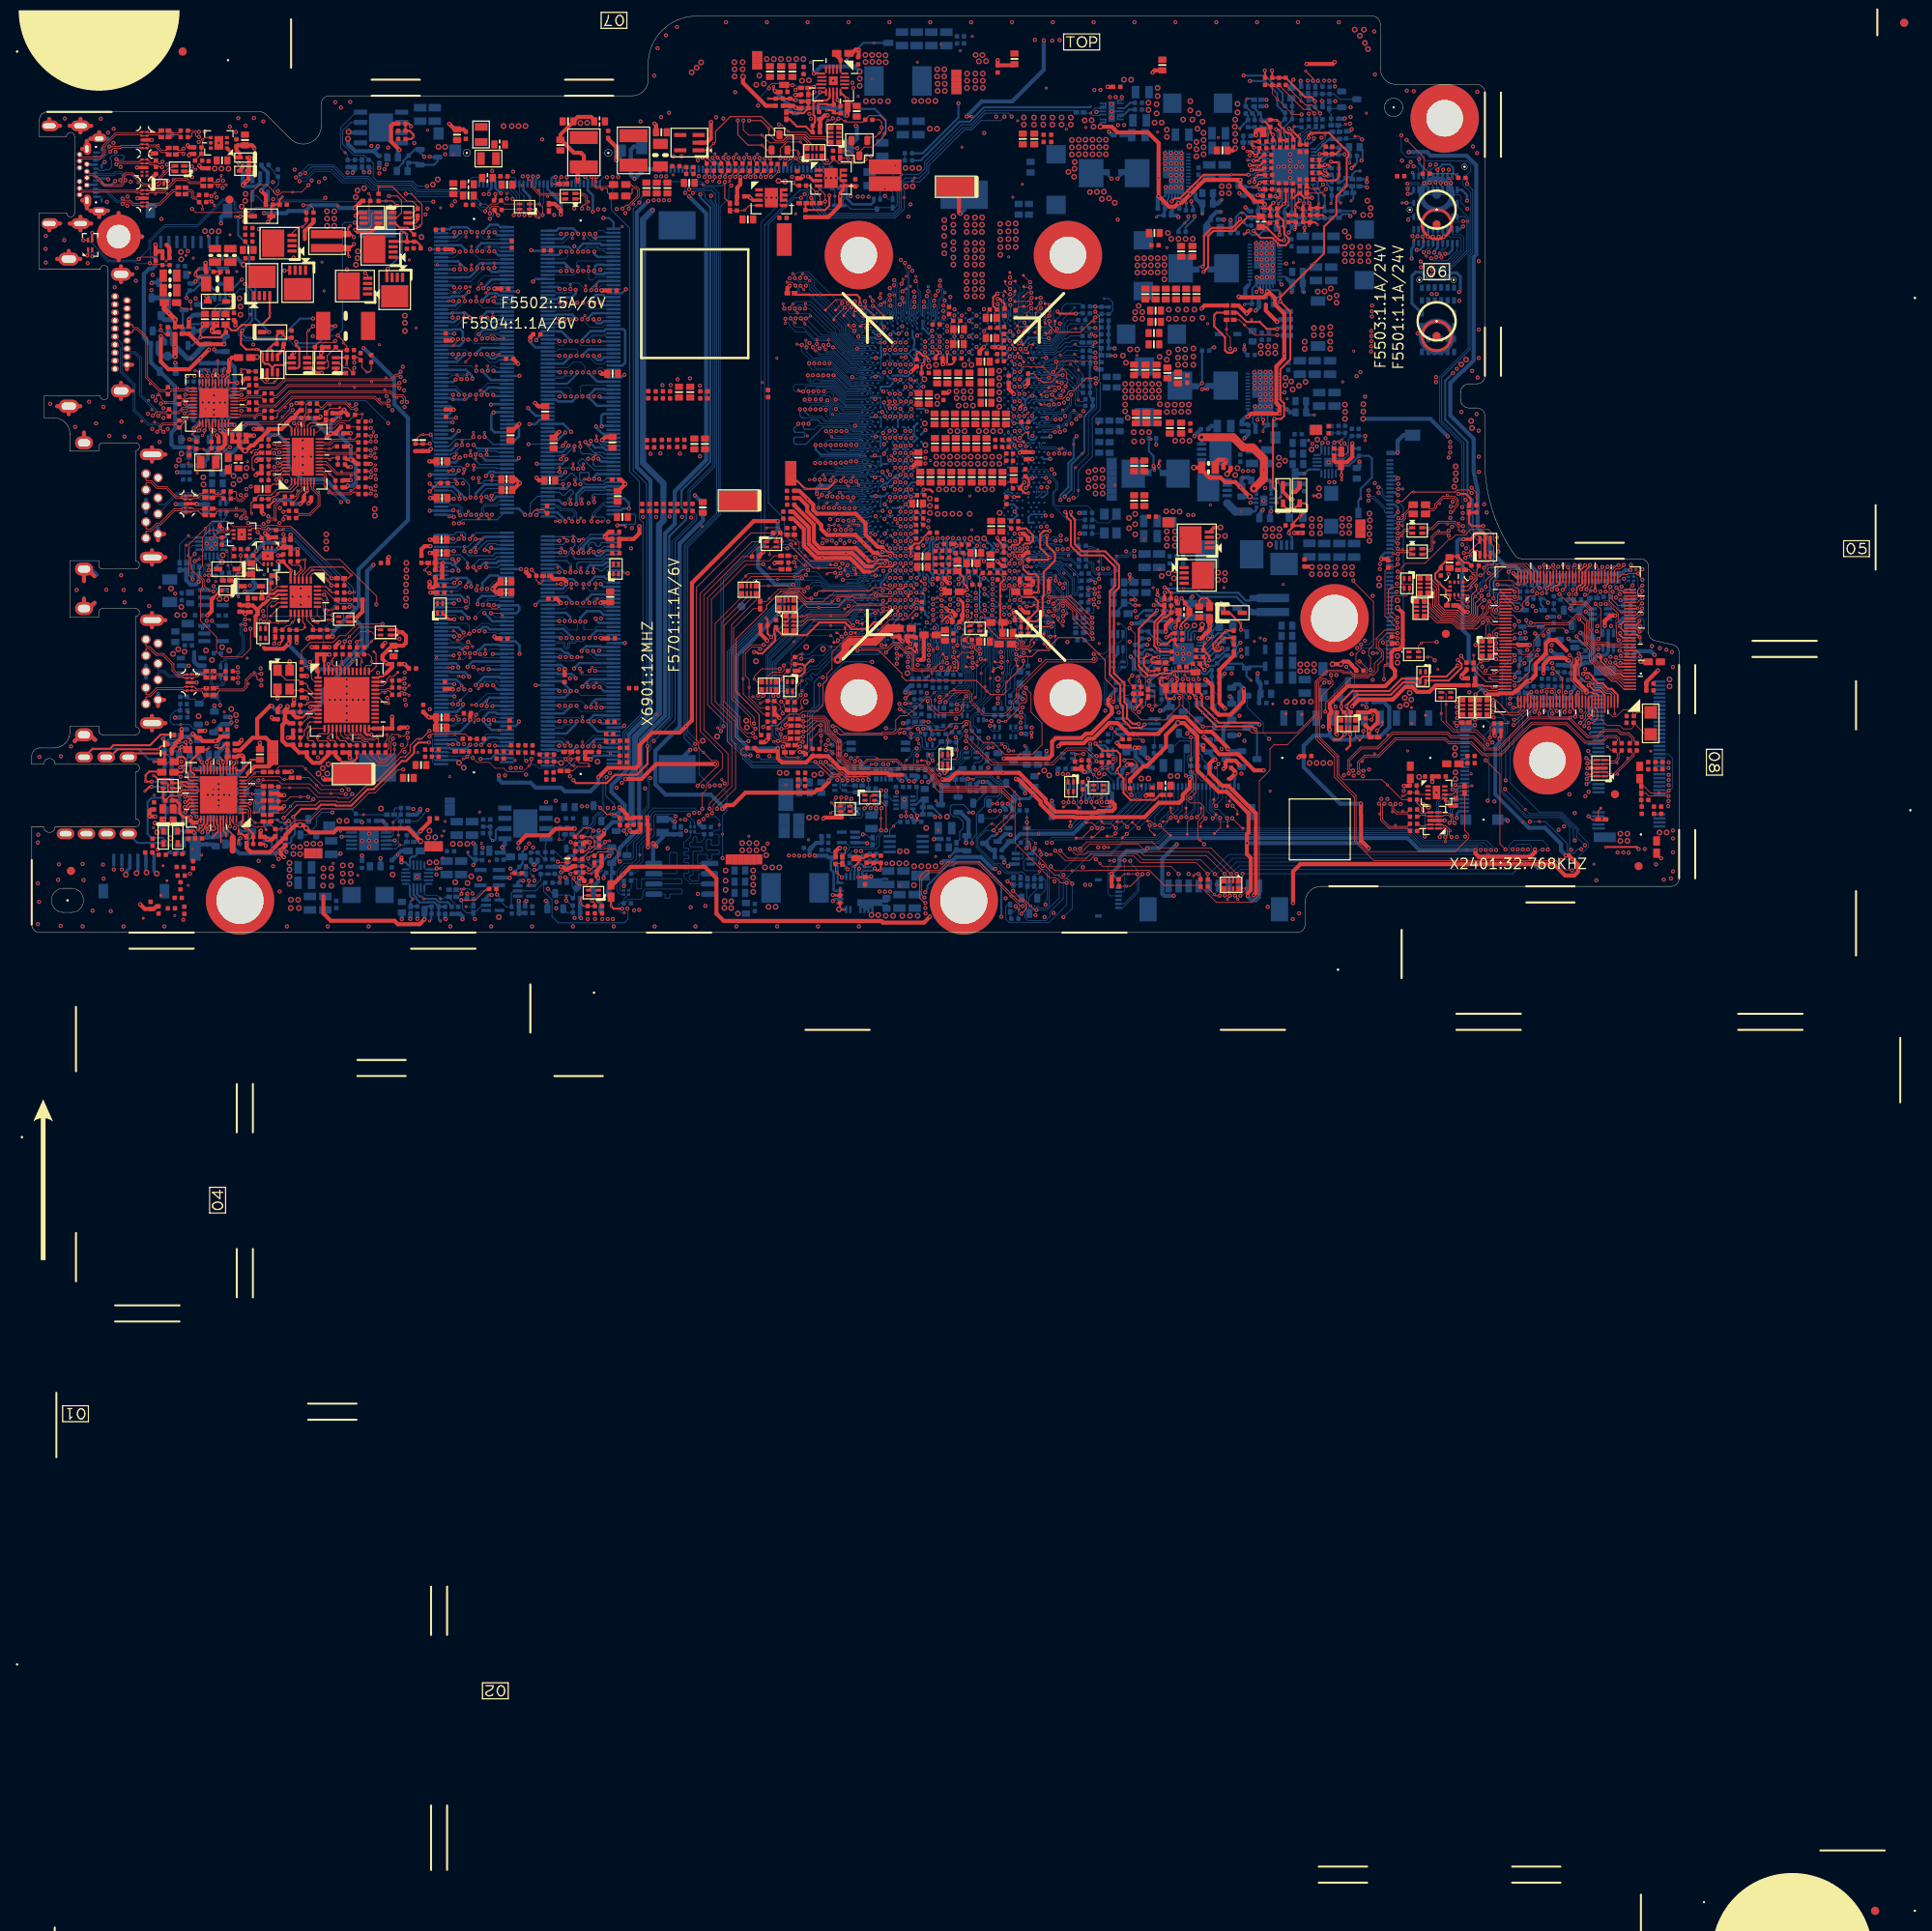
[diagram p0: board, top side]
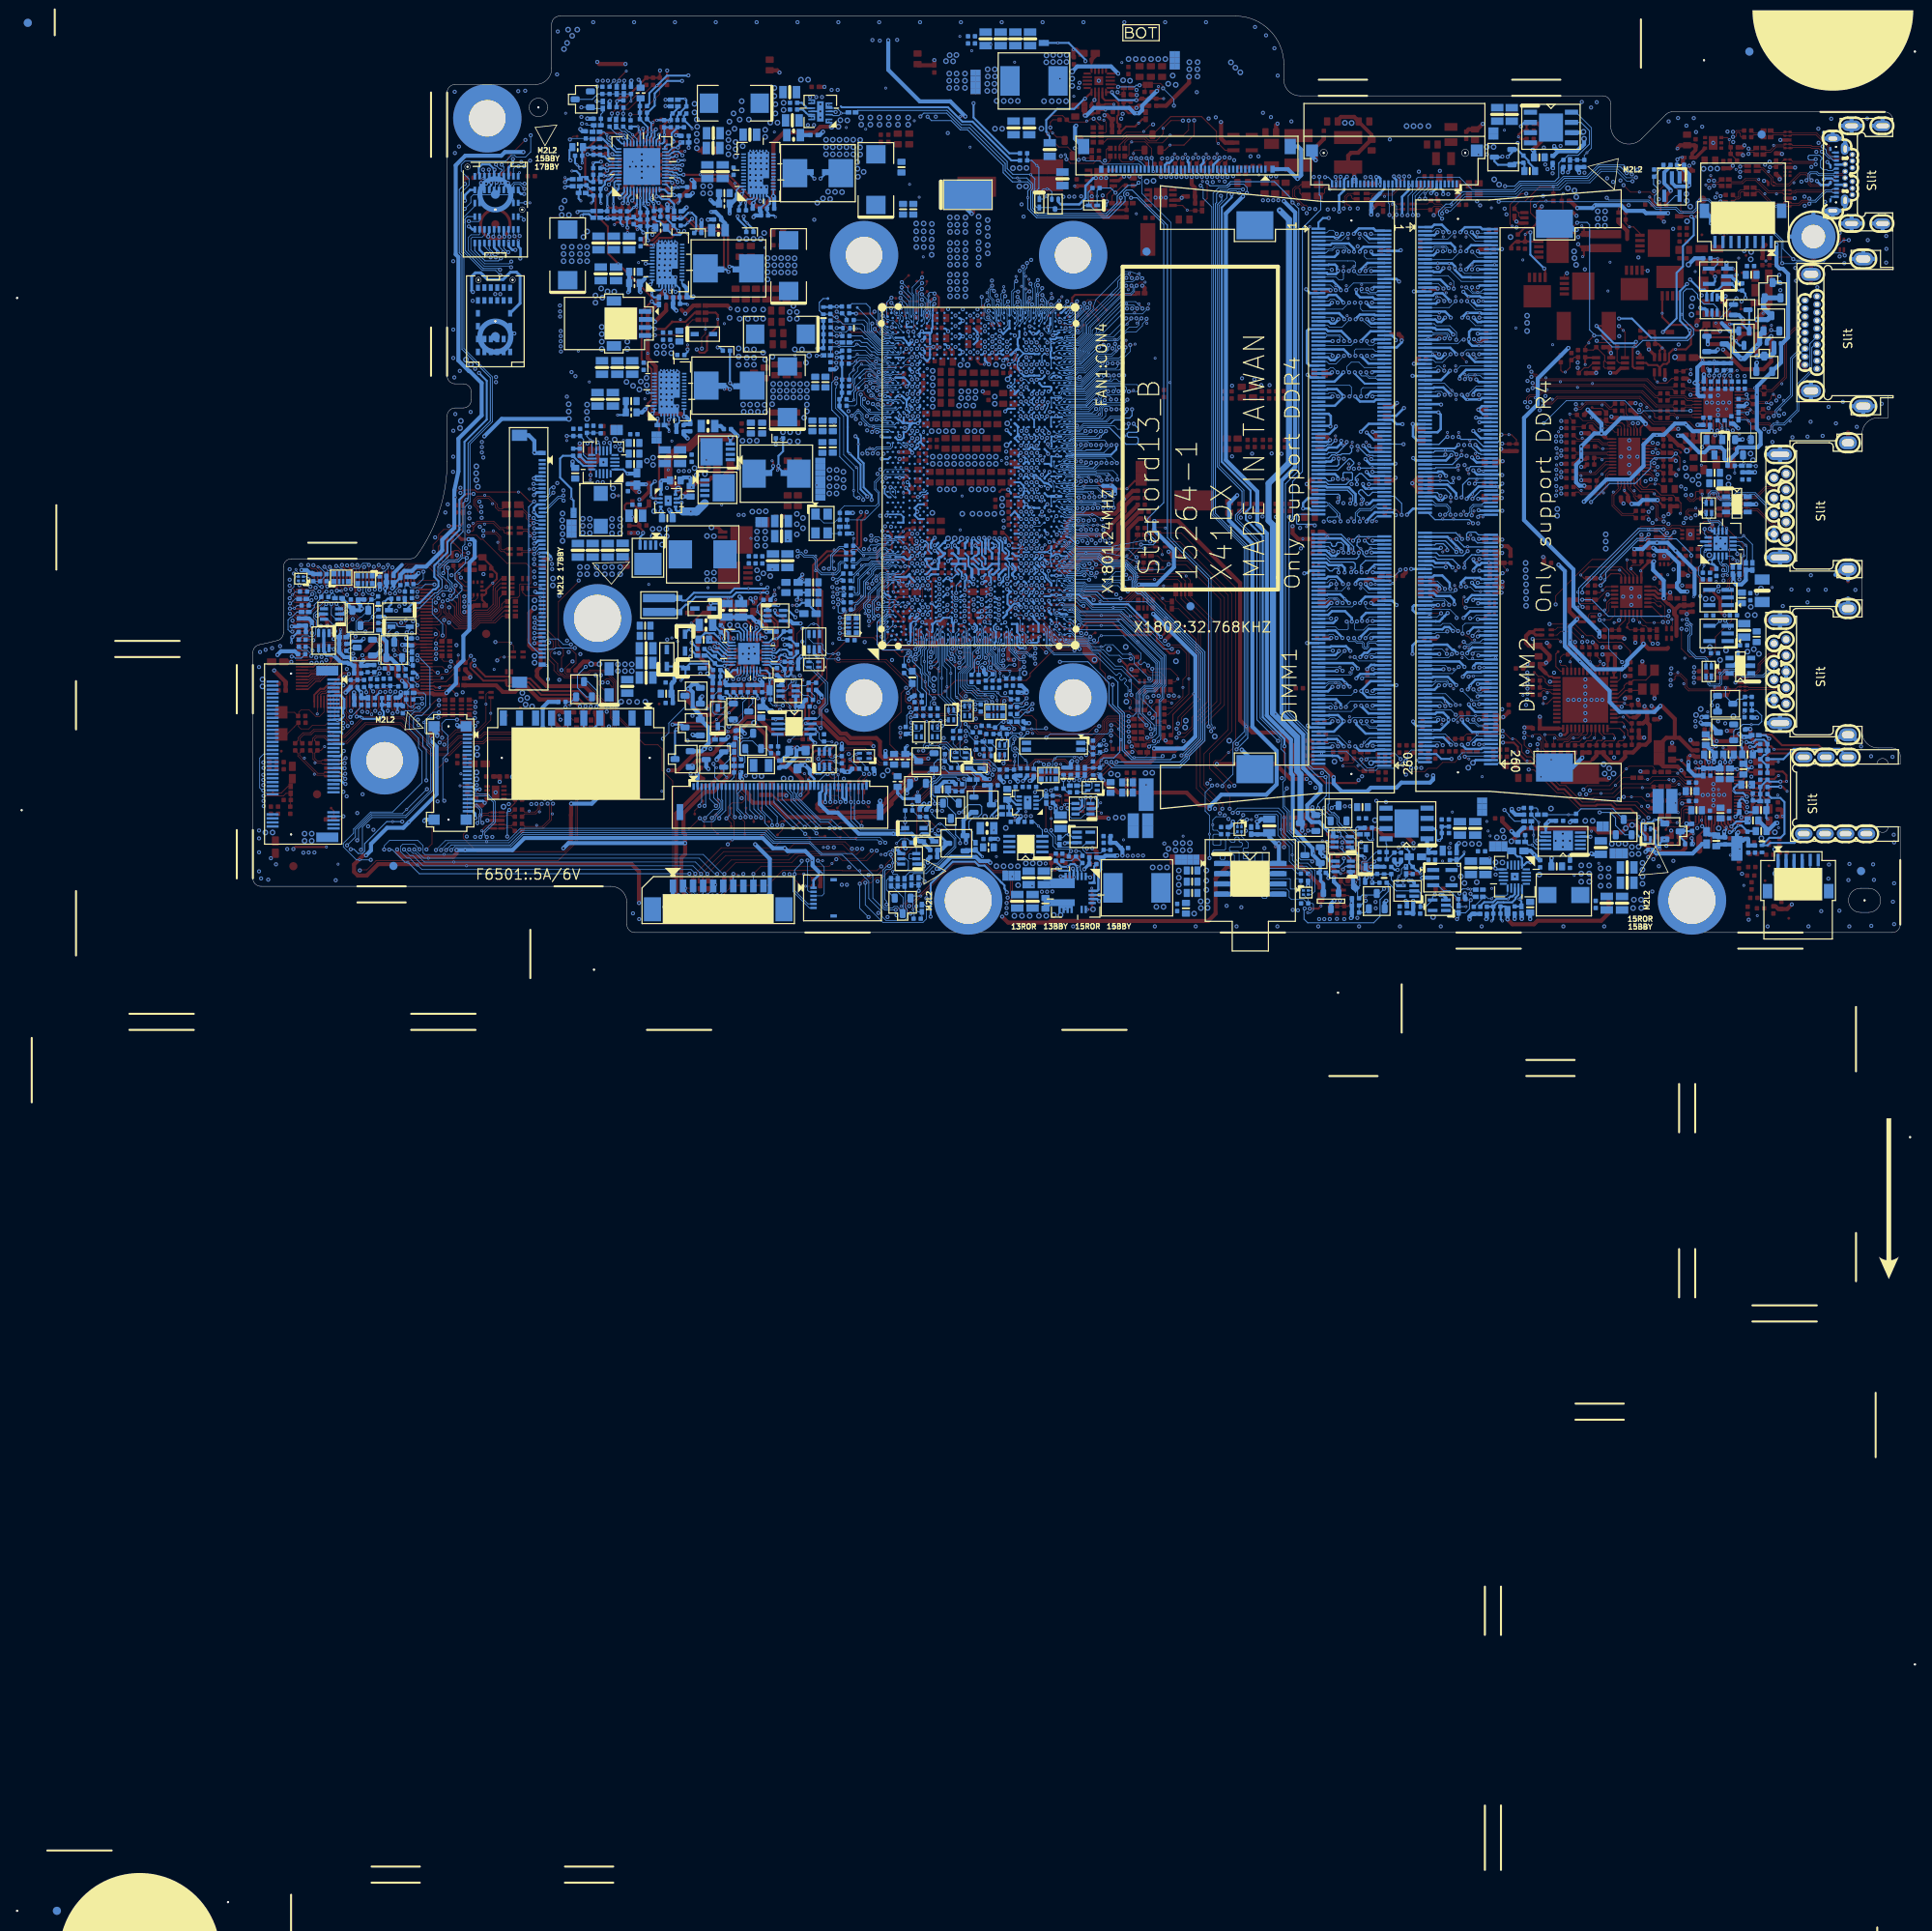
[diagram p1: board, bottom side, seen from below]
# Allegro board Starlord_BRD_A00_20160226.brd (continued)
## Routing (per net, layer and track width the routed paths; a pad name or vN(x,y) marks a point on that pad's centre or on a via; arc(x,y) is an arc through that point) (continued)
VR_SVID_ALERT#: length 75.4
  TOP w0.114: v2(132.26,74.16) 132.06,74.16 v1(131.77,74.44) ; v2(159.49,101.81) 158.97,102.33 158.13,102.33 PR4622.2
  L4 w0.114: v2(132.26,74.16) 136.51,74.16 136.76,74.42 137.05,74.71 150.94,74.71 151.94,74.71 154.1,76.86 157.94,76.86 158.21,76.59 162.43,76.59 162.84,76.59 168.4,82.15 168.69,82.44 168.69,96.18 168.67,96.2 168.67,96.28 166.81,98.14 165.23,98.14 164.79,98.57 163.03,98.57 160.83,100.77 160.83,102.02 160.55,102.31 159.98,102.31 v2(159.49,101.81)
  BOTTOM w0.114: v2(159.49,101.81) 159.49,101.27 PR4666.1 ; R728.1 v2(132.26,74.16) 132.8,74.16 R727.2
VR_SVID_CLK: length 74.7
  TOP w0.114: PR4621.2 155.93,105.33 158.39,102.86 159.21,102.86 160.22,101.85 v2(160.22,101.81) ; v1(131.98,72.86) 131.98,73.07 v2(132.26,73.35)
  L4 w0.114: v2(132.26,73.35) 131.76,73.84 131.76,74.4 132.07,74.71 136.36,74.71 136.85,75.2 151.73,75.2 153.89,77.36 158.14,77.36 158.42,77.09 162.64,77.09 168.2,82.64 168.2,96.03 166.6,97.63 165.02,97.63 164.67,97.98 162.92,97.98 160.22,100.68 v2(160.22,101.81)
  BOTTOM w0.114: R723.2 132.85,73.35 v2(132.26,73.35) 132.1,73.5 131.71,73.5 R732.2 ; PR4665.1 160.22,101.36 v2(160.22,101.81)
VR_SVID_DATA: length 70.8
  TOP w0.114: v2(134.75,71.7) v1(134.19,71.7)
  L4 w0.114: v2(134.75,71.7) 137.26,74.21 150.74,74.21 152.14,74.21 154.3,76.37 157.73,76.37 158.01,76.1 158.83,76.1 162.23,76.1 162.23,76.1 162.64,76.1 162.64,76.1 163.17,76.1 169.19,82.11 169.19,96.39 169.17,96.41 169.17,96.48 166.14,99.51 165.05,99.51 164.62,99.08 163.22,99.08 161.33,100.97 161.33,101.82 161.33,102.23 160.75,102.8 159.78,102.8 158.8,101.83 v2(158.8,101.78)
  BOTTOM w0.114: PR4667.1 v2(158.8,101.78) 158.77,101.81 PR4623.2 ; R709.2 134.52,71.75 134.57,71.7 v2(134.75,71.7)
VRAM_ID1: length 13.6
  L4 w0.102: v2(108.66,41.34) 108.76,41.34 109.15,40.95 109.97,40.95 110.42,40.49 110.42,39.09 110.29,38.95 110.29,37.18 110.42,37.04 110.42,35.51 109.69,34.78 109.69,33.48 109.27,33.06 109.02,33.06 v2(108.96,33.01)
  BOTTOM w0.102: v2(108.66,41.34) 108.66,41.32 108.35,41.02 CPU1.AP8 ; v2(108.96,33.01) 109.14,33.01 v1(109.47,32.68) 109.5,32.66 R2030.1 R2029.2
VREG3PD: length 6.1
  TOP w0.406: U3702.1 24.39,97.36 25.42,96.33 D3702.A
  TOP w0.457: D3702.A 25.89,96.84 25.45,97.27 C3709.1
  TOP w0.508: C3709.1 25.59,97.86 C3710.1 27.38,97.86 27.66,97.58 v1(27.66,97.48)
WHITE_LED_BAT: length 3.3
  BOTTOM w0.508: Q6401.C 113.12,16 EC6402.1 113.9,18.3 R6402.2
WIFI_RF_EN: length 58.2
  TOP w0.102: v2(165.3,35.81) 165.3,35.25 164.67,34.61 164.67,33.48 EC6603.1 ; v2(131.95,36.52) 131.7,36.77 131.7,36.77 v1(131.12,37.34) 129.45,39.02 129.45,39.94 128.39,41 128.07,41 127.81,40.74 127.81,40.3 127.36,39.86 126.53,39.86 v2(126.46,39.92)
  L4 w0.102: v2(131.95,36.52) 133.6,34.87 133.6,33.87 136.15,31.33 137.1,31.33 137.59,31.82 139.55,31.82 140.56,30.8 146.23,30.8 148.11,32.68 151.75,32.68 152.12,33.05 153.45,33.05 155.09,34.69 163.57,34.69 163.93,35.04 164.34,35.04 164.44,34.94 165,34.94 165.3,35.25 v2(165.3,35.81)
  BOTTOM w0.102: R1503.2 131.77,36.34 v2(131.95,36.52) ; v2(126.46,39.92) 126.39,39.92 126.11,40.2 125.54,40.2 CPU1.B7 ; v2(165.3,35.81) 166.24,35.81 166.93,36.49 168.22,36.49 168.5,36.21 IOBD1.46
XCLK_BIASREF: length 2.3
  TOP w0.508: v1(124.53,59.72) R1803.1 123.61,59.71 122.93,59.71 v2(122.86,59.63)
  BOTTOM w0.305: v2(122.86,59.63) 122.86,59.75 123.19,60.08 CPU1.E42
XDP_BPM0: length 4.1
  TOP w0.089: v2(128.08,68.3) 128.05,68.27 127.63,68.27 127.48,68.42 TP405.1
  BOTTOM w0.089: CPU1.C55 125.43,67.74 125.55,67.86 125.9,67.86 125.9,67.87 126.14,67.87 126.84,67.88 126.93,67.88 126.95,67.88 127.39,68.32 128.01,68.32 128.03,68.3 v2(128.08,68.3)
XDP_BPM1: length 5.3
  TOP w0.089: v2(127.76,67.73) 127.63,67.86 127.4,67.86 127.33,67.94 126.8,67.94 126.59,67.73 TP406.1
  BOTTOM w0.089: v2(127.76,67.73) 127.63,67.86 127.18,67.86 127.11,67.79 127.02,67.7 126.96,67.7 126.22,67.69 126.21,67.69 125.98,67.69 125.97,67.68 125.68,67.68 125.45,67.45 124.76,67.45 124.48,67.74 CPU1.D55
XDP_BPM2: length 4.1
  TOP w0.089: v2(127.23,67.38) 127.23,67.38 127.16,67.31 127.01,67.31 126.97,67.28 125.91,67.28 TP407.1
  BOTTOM w0.089: v2(127.23,67.38) 127.23,67.38 127.18,67.33 126.72,67.33 126.72,67.33 126.44,67.33 126.33,67.44 125.69,67.44 125.43,67.18 CPU1.B54
XDP_BPM3: length 5.8
  BOTTOM w0.089: CPU1.C56 124.81,68.52 124.99,68.69 125.04,68.71 125.69,68.71 125.78,68.74 126.16,68.74 126.31,68.6 126.32,68.6 126.33,68.59 126.65,68.59 126.88,68.82 126.88,68.85 127.08,69.05 127.13,69.05 127.17,69.1 127.2,69.1 127.21,69.1 127.26,69.1 127.84,69.69 128.57,69.69 128.83,69.43 128.91,69.43 TP408.1
XDP_DBRESET#: length 20.6
  TOP w0.114: EC1706.1 117.87,44.31 R1701.2 117.87,40.14 118.54,39.46 118.54,38.68 118.74,38.47 118.74,38.09 120.24,36.59 122.53,36.59 122.88,36.24 122.88,35.83 123.09,35.62 123.98,35.62 124.16,35.81 124.16,36.17 125.09,37.1 TP1709.1 125.88,36.67 v2(126.39,36.16)
  BOTTOM w0.114: CPU1.B5 125.26,38.22 125.8,37.68 126.05,37.68 126.24,37.5 126.24,36.31 v2(126.39,36.16)
XDP_PRDY#: length 6.4
  BOTTOM w0.089: CPU1.D56 124.35,68.07 124.4,68.02 124.82,68.02 124.84,68.04 126.07,68.04 126.08,68.06 126.87,68.06 127.34,68.52 127.75,68.52 127.92,68.69 128.24,68.69 128.27,68.65 128.28,68.65 128.41,68.52 128.7,68.52 TP1605.1
XDP_PREQ#: length 2.2
  TOP w0.089: TP1606.1 123.37,71.06 v2(122.89,71.53)
  BOTTOM w0.089: CPU1.D61 123.96,70.84 123.42,71.39 123.04,71.39 v2(122.89,71.53)
XDP_TCK_JTAGX: length 7.1
  BOTTOM w0.089: CPU1.A59 126.08,69.66 126.16,69.74 126.54,69.74 126.85,70.05 127.65,70.05 127.99,70.38 128.24,70.38 128.37,70.52 129.05,70.52 v1(129.18,70.65) 129.66,70.17 129.66,69.77 130.26,69.18 130.26,68.37 R417.1
XDP_TCLK: length 6.1
  BOTTOM w0.089: R406.1 129.9,72.33 129.87,72.36 128.67,72.36 128.09,71.77 v1(127.91,71.77) 127.61,71.77 127.39,71.55 127.15,71.55 126.83,71.24 126.49,71.24 126.31,71.05 125.75,71.05 125.47,70.78 CPU1.B61
XDP_TDI: length 14.6
  TOP w0.089: v2(128.56,67.89) 128.7,68.03 128.7,68.25 128.83,68.38 128.83,68.7 128.7,68.83 128.7,69.64 128.4,69.94 127.99,69.94 127.32,69.28 126.78,69.28 v1(125.73,70.32) 123.15,70.32 v2(122.87,70.6)
  BOTTOM w0.089: v2(128.56,67.89) 128.56,67.84 128.7,67.71 128.7,67.66 128.81,67.55 128.81,67.54 129.02,67.33 129.49,67.33 129.77,67.05 129.77,65.7 130,65.47 R422.1 ; v2(122.87,70.6) 122.89,70.58 123.75,70.58 124.11,70.22 CPU1.D60
XDP_TDO_CPU: length 5.4
  BOTTOM w0.089: R423.1 130.05,71.52 v1(129.69,71.87) 129.6,71.78 128.44,71.78 128.03,71.37 127.22,71.37 126.91,71.06 126.59,71.06 126.39,70.86 125.99,70.86 CPU1.A61
XDP_TMS: length 6.6
  BOTTOM w0.089: CPU1.C60 126.51,70.22 126.82,70.53 127.49,70.53 127.77,70.81 127.89,70.81 128.55,71.47 129.52,71.47 130.28,70.7 R421.1
XDP_TRST#: length 12.3
  TOP w0.089: v2(132.31,70.83) 132.26,70.83 132.08,71.01 v1(129.87,71.01) 127.4,71.01 v2(127.38,70.98) 127.46,70.91 127.46,70.1 v2(127.02,69.66)
  BOTTOM w0.089: CPU1.C61 124.87,70.52 126.56,70.52 126.74,70.7 127.15,70.7 127.38,70.93 v2(127.38,70.98) ; v2(127.02,69.66) 126.92,69.56 126.26,69.56 126.24,69.55 126.11,69.43 126.05,69.39 125.79,69.39 125.71,69.43 125.53,69.43 125.3,69.66 CPU1.B59 ; R402.1 132.45,70.9 132.38,70.83 v2(132.31,70.83)
XTAL1: length 10
  TOP w0.089: KBC24.123 195.21,26.42 195.86,25.77 197.44,25.77 197.9,25.31 198.87,25.31 199.19,25.62 199.19,26.06 C2425.2 199.71,25.57 199.71,25.56 200.63,24.63 X2401.1
XTAL2: length 7.9
  TOP w0.089: KBC24.125 196.01,27.4 196.59,26.82 196.99,26.82 197.86,27.68 198.85,27.68 199.13,27.4 199.13,27 C2424.2 199.68,27.37 X2401.2
XTAL24_IN: length 18
  BOTTOM w0.089: CPU1.E37 123.4,57.55 124.16,57.55 124.17,57.54 124.41,57.54 124.42,57.55 124.81,57.55 124.82,57.54 126.22,57.54 126.36,57.4 126.36,57.22 127.56,56.02 127.56,55.09 127.13,54.65 127.13,53.33 127.4,53.05 131.29,53.05 131.86,52.48 C1801.2 R1802.1 132.21,51.3 132.59,50.92 133.86,50.92 134.89,51.95 X1801.1
XTAL24_OUT: length 13.4
  BOTTOM w0.089: R1810.1 R1802.2 128.78,51.3 126.95,53.13 126.95,54.73 127.38,55.16 127.38,55.9 126.34,56.93 123.7,56.93 CPU1.E35
XTAL24_OUT_R: length 2.4
  BOTTOM w0.089: X1801.3 133.31,49.6 C1802.2 R1810.2
ZVM#: length 31.2
  L4 w0.102: v2(108.02,68.72) 108.02,68.9 107.75,69.18 105.84,69.18 105.33,69.69 105.33,70.83 105.46,70.96 105.46,73.5 106.22,74.26 106.22,74.77 106.73,75.28 106.73,77.18 106.09,77.82 v2(106.09,91.56)
  BOTTOM w0.102: CPU1.AR56 107.7,68.44 107.96,68.7 108,68.7 v2(108.02,68.72) ; Q4001.S 105.5,92.09 105.84,92.42 v1(106.09,92.42) 106.6,92.42 107.06,91.96 D4004.K 106.48,91.17 v2(106.09,91.56)

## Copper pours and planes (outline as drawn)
5V_HDD on TOP: 175.44,17.52 175.39,17.57 175.39,19.68 174.85,20.21 170.97,20.21 170.79,20.39 170.79,23.13 171.22,23.56 175.26,23.56 176.05,22.78 176.05,22.11 176.73,21.43 176.73,20.41 176.55,20.24 176.55,17.82 176.25,17.52 ; 2 cut-outs
5V_HDD_SIP on TOP: 176.96,18.76 176.71,19.02 176.71,20.03 177.09,20.41 177.09,21.43 177.14,21.48 177.93,21.48 178.05,21.35 179.63,21.35 180.14,20.84 180.14,19.52 179.37,18.76 ; 4 cut-outs
5V_HDD_SIP on BOTTOM: 176.81,18.79 175.69,19.9 175.69,21.43 175.94,21.68 177.09,21.68 177.54,21.23 178.79,21.23 178.87,21.15 178.87,19.52 178.74,19.4 177.49,19.4 177.42,19.32 177.42,19.02 177.19,18.79
5V_HDMI_R_S5 on TOP: 22.43,57.45 22.3,57.57 22.3,59.38 22.43,59.5 26.24,59.5 26.47,59.27 26.92,59.27 27.07,59.12 27.07,58.49 26.95,58.36 23.77,58.36 23.62,58.21 23.62,57.62 23.44,57.45 ; 2 cut-outs
5V_HDMI_S5 on TOP: 18.72,57.5 18.21,58 18.21,59.53 18.34,59.66 21.54,59.66 21.77,59.43 21.77,57.62 21.64,57.5 ; 2 cut-outs
5V_HDMI_S5 on L4: 15.54,77.69 15.54,71.09 18.72,67.91 18.72,61.43 19.48,60.67 19.48,58.64 18.97,58.13 17.83,58.13 16.94,59.02 16.94,61.81 17.32,62.2 17.32,62.96 17.07,63.21 17.07,66.64 13.77,69.94 13.77,76.93 12.62,78.07 11.61,78.07 11.35,78.32 11.35,79.34 11.48,79.47 13.77,79.47
5V_S0 on TOP: 135.1,99.99 134.8,100.3 134.8,100.65 136.07,101.92 136.07,104.23 135.81,104.49 135.43,104.49 135.05,104.87 135.05,105.86 135.69,106.49 137.77,106.49 138.33,105.93 138.33,100.7 137.62,99.99 ; 2 cut-outs
5V_S0 on TOP: 173.3,15.33 172.77,15.87 172.77,16.5 173.1,16.83 173.91,16.83 174.06,16.68 174.06,15.59 173.81,15.33
5V_S0 on TOP: 67.11,97.81 66.72,98.19 66.72,99.66 66.98,99.91 67.56,99.91 67.87,100.22 67.87,100.83 68.02,100.98 69.21,100.98 69.39,100.8 69.39,100.25 69.47,100.17 70.56,100.17 70.79,100.4 70.79,101.29 70.92,101.41 71.85,101.41 72.08,101.18 72.08,99.46 71.91,99.28 71.12,99.28 70.66,98.82 70.66,97.98 70.48,97.81 ; 2 cut-outs
5V_S0 on TOP: 26.59,56.35 25.96,56.99 25.58,56.99 25.2,57.37 25.2,58.13 25.32,58.26 26.97,58.26 27.23,58 27.23,56.61 26.97,56.35 ; 1 cut-out
5V_S0 on TOP: 172.92,17.52 172.69,17.75 172.69,18.63 172.41,18.91 170.89,18.91 170.71,19.09 170.71,19.8 170.91,20.01 173.28,20.01 173.71,19.57 173.71,18.66 173.96,18.41 173.96,17.59 173.89,17.52 ; 2 cut-outs
5V_S0 on TOP: 141.53,16.6 141.27,16.86 141.27,19.52 141.53,19.78 143.05,19.78 143.31,19.52 143.31,17.11 142.8,16.6 ; 2 cut-outs
5V_S0 on BOTTOM: 49.73,92.65 49.2,93.18 49.2,94.33 49.83,94.96 50.85,94.96 51.87,95.98 54.66,95.98 55.68,96.99 60.37,96.99 63.3,99.91 66.77,99.91 67.92,101.06 72.31,101.06 72.54,100.83 72.54,98.7 71.19,97.35 64.36,97.35 62.13,95.11 56.56,95.11 55.56,94.11 54.52,94.11 53.06,92.65
5V_S0 on BOTTOM: 141.78,19.02 141.53,19.27 141.53,19.52 141.91,19.9 141.91,21.43 142.04,21.56 143.05,21.56 143.31,21.3 143.31,19.14 143.18,19.02
5V_S0 on BOTTOM: 135.56,105.88 135.18,106.26 135.18,108.04 139.75,112.61 163.5,112.61 165.28,110.84 165.91,110.84 166.42,110.33 166.42,108.8 165.91,108.3 165.02,108.3 162.99,110.33 141.78,110.33 137.34,105.88
5V_S0 on BOTTOM: 37.62,50.99 34.34,54.27 29.31,54.27 27.66,55.92 26.82,55.92 24.89,57.85 22.96,57.85 22.35,58.46 22.35,59.76 22.53,59.94 23.54,59.94 23.71,59.77 23.71,59.4 23.89,59.22 26.34,59.22 27.4,58.16 28.14,58.16 29.28,57.01 29.28,56.56 30.33,55.52 35.48,55.52 37.87,53.13 42.87,53.13 43.13,52.87 43.13,51.53 42.59,50.99
5V_S0 on BOTTOM: 27.46,16.5 27.3,16.65 27.3,18.43 28.24,19.37 28.24,20.54 27.94,20.84 27.33,20.84 25.2,22.98 25.2,26.71 25.04,26.86 25.04,27.22 25.22,27.4 26.47,27.4 27.86,26 27.86,23.49 28.18,23.17 28.99,23.17 31.8,20.36 31.8,18.25 31.01,17.47 31.01,16.6 30.91,16.5
5V_S0 on BOTTOM: 134.97,100.04 134.82,100.19 134.82,101.26 134.95,101.39 136.02,101.39 136.42,101.79 137.62,101.79 137.72,101.69 137.72,100.3 137.46,100.04
5V_S0 on BOTTOM: 173.38,15.33 172.08,16.63 172.08,19.47 172.26,19.65 173.28,19.65 173.58,19.35 173.58,17.49 174.24,16.83 174.24,15.49 174.09,15.33
5V_S0 on L4: 25.58,24.86 24.94,25.49 24.94,28.13 24.95,28.15 24.95,35.41 29.51,39.97 39.93,39.97 43.23,43.27 43.23,49.34 42.14,50.44 42.14,52.54 43.74,54.14 43.74,62.2 43.36,62.58 43.34,62.58 42.57,63.35 42.57,64.38 41.96,64.99 41.96,69.87 43.05,70.96 43.05,90.34 47.32,94.61 50.52,94.61 51.04,94.09 51.04,93.46 46.15,88.57 46.15,75.23 46.28,75.1 46.28,70.98 45.26,69.97 45.26,67.02 45.74,66.54 45.74,65.37 46.28,64.84 46.28,64.23 46.53,63.97 46.53,48.1 46.15,47.72 46.15,40.86 42.47,37.18 30.78,37.18 28.5,34.89 28.5,25.62 27.74,24.86
5V_S0 on L4: 136.07,100.04 136.45,100.42 136.45,101.82 135.3,102.96 134.29,102.96 133.27,103.98 131.11,103.98 126.8,108.3 122.99,108.3 119.94,111.34 82.6,111.34 79.17,107.92 79.17,103.98 76.5,101.31 67.92,101.31 67.64,101.03 67.64,100.25 68.15,99.74 70.46,99.74 70.92,99.28 78.03,99.28 81.33,102.58 81.33,107.1 83.92,109.69 119.18,109.69 122.86,106.01 126.29,106.01 129.72,102.58 132.13,102.58 132.51,102.2 132.51,101.31 133.78,100.04
5V_S0 on L5VCC: 172.72,15.02 172.07,15.67 172.07,24.78 174.1,26.81 174.1,41.8 178.67,46.37 178.67,51.23 177.53,52.37 177.53,53.73 177.91,54.12 177.91,60.88 174.61,64.18 174.61,70.88 176.77,73.04 176.77,77.77 176.13,78.4 176.13,82.69 176.9,83.45 176.9,89.29 177.15,89.55 177.15,94.91 175.39,96.68 172.98,96.68 171.45,98.2 171.07,98.2 165.34,103.93 165.34,110.88 166.48,112.03 166.48,113.41 166.7,113.41 167.05,113.27 167.19,112.92 167.19,107.42 167.93,105.65 169.7,104.91 179.7,104.91 180.05,104.77 180.19,104.42 180.19,69.21 180.05,68.86 179.7,68.72 178.7,68.72 177.63,68.28 177.19,67.21 177.19,66.21 177.63,65.14 178.7,64.7 179.7,64.7 180.05,64.56 180.19,64.21 180.19,58.53 180.38,55.72 180.96,52.97 180.96,44.62 176.26,39.92 176.26,16.05 175.23,15.02
5V_S0 on L6: 141.37,19.88 142.9,19.88 143.48,19.3 143.48,18.91 144.24,18.15 147.47,18.15 148.18,17.44 150.7,17.44 152.55,15.59 171.32,15.59 172.54,16.81 173.86,16.81 175.36,15.31 175.36,13.89 173.89,12.41 151.81,12.41 149.55,14.67 144.04,14.67 141.17,17.54 141.17,19.68
5V_S5 on TOP: 25.07,42 24.69,42 24.56,41.88 23.16,41.88 22.91,41.62 22.91,37.81 23.29,37.43 23.29,35.14 23.8,34.64 25.07,34.64 25.45,35.02 25.45,38.57 25.2,38.83 25.2,41.88
5V_S5 on TOP: 26.72,45.48 26.36,45.84 26.36,47.16 26.52,47.31 26.52,48.12 26.62,48.23 27.1,48.23 27.56,48.68 27.56,49.22 27.46,49.32 26.87,49.32 26.85,49.34 26.85,49.65 26.87,49.67 27.68,49.67 28.14,49.22 28.14,47.31 28.01,47.18 27.84,47.18 27.68,47.34 27.18,47.34 27,47.16 27,46.52 27.2,46.32 27.71,46.32 27.84,46.19 27.84,45.61 27.71,45.48 ; 2 cut-outs
5V_S5 on TOP: 23.34,45.69 23.19,45.84 23.19,48.35 23.37,48.53 23.93,48.53 24.03,48.43 24.03,45.89 23.82,45.69
5V_S5 on TOP: 29.21,47.54 29.21,48.61 29.34,48.73 30.35,48.73 30.5,48.58 30.5,48.35 30.35,48.2 29.64,48.2 29.63,48.19 29.61,48.2 29.54,48.2 29.51,48.18 29.51,47.54
5V_S5 on TOP: 55.42,6.19 55.17,6.44 55.17,6.95 55.42,7.2 55.42,11.88 58.49,14.95 70.79,14.95 73.84,11.9 74.73,11.9 76.58,10.05 80.72,10.05 81.05,10.38 85.01,10.38 85.39,10.76 85.77,10.76 88.06,13.05 92.12,13.05 92.63,12.54 92.63,11.04 92.38,10.79 91.34,10.79 90.96,11.17 90.96,11.65 90.7,11.9 88.31,11.9 86.41,10 86.1,9.82 85.67,9.47 85.14,9.11 84.86,8.83 75.13,8.83 70.15,13.81 59.49,13.81 57.2,11.52 57.2,6.7 56.69,6.19
5V_S5 on TOP: 131.37,99.91 130.73,100.55 130.73,101.44 129.21,102.96 115.75,102.96 115.11,103.6 115.11,107.15 115.24,107.28 128.95,107.28 133.15,103.09 133.15,100.17 132.89,99.91 ; 2 cut-outs
5V_S5 on TOP: 25.42,55.85 25.2,56.07 24.51,56.07 23.8,56.79 23.8,58 23.93,58.13 24.81,58.13 24.94,58 24.94,57.37 25.45,56.86 25.83,56.86 26.21,56.48 26.21,55.97 26.08,55.85
5V_S5 on BOTTOM: 115.24,103.95 115.01,104.18 115.01,107.26 115.8,108.04 117.02,108.04 117.4,107.66 118.92,107.66 119.3,107.28 119.3,104.61 118.67,103.98 115.54,103.98 115.52,103.95
5V_S5 on BOTTOM: 107.03,16.81 106.96,16.88 106.96,17.31 106.93,17.31 106.55,17.7 106.55,18.1 106.88,18.43 107.8,18.43 107.9,18.33 107.9,17.85 107.77,17.72 107.77,16.86 107.72,16.81 ; 1 cut-out
5V_S5 on BOTTOM: 47.47,10.86 47.34,10.99 47.34,11.52 47.47,11.65 48.61,11.65 48.77,11.5 48.77,11.09 48.54,10.86
5V_S5 on BOTTOM: 23.09,35.86 22.99,35.96 22.99,37.23 23.14,37.38 24.51,37.38 24.69,37.56 24.69,38.8 24.53,38.95 23.98,38.95 23.72,39.21 23.72,39.62 22.99,40.35 22.99,42 23.19,42.21 25.8,42.21 26.06,41.95 26.06,39.77 25.25,38.95 25.25,34.99 24.97,34.71 24.03,34.71 23.75,34.43 23.26,34.43 23.09,34.61 ; 1 cut-out
5V_S5 on BOTTOM: 63.42,13.43 63.17,13.68 63.17,14.44 63.42,14.7 66.72,14.7 66.85,14.57 66.85,13.68 66.6,13.43 ; 2 cut-outs
5V_S5 on BOTTOM: 130.86,99.66 130.61,99.91 130.61,101.06 130.91,101.36 133.6,101.36 133.65,101.31 133.65,100.3 133.02,99.66
5V_S5 on BOTTOM: 167.36,42.79 167.18,42.97 167.18,44.19 168.43,45.43 169.21,45.43 169.44,45.2 169.44,44.7 169.42,44.67 169.42,43.25 169.21,43.04 168.4,43.04 168.15,42.79
5V_S5 on L3: 32.82,12.49 32.66,12.64 32.66,13.81 32.94,14.09 32.94,14.7 31.55,16.09 31.55,19.14 27.16,23.52 27.16,27.97 25.45,29.68 24.56,29.68 23.29,30.95 23.29,34.38 22.53,35.14 22.53,41.37 23.29,42.13 23.29,43.02 23.01,43.3 21.49,43.3 21.46,43.27 20.37,43.27 19.45,44.19 19.45,50.13 20.22,50.89 20.22,51.73 21.13,52.65 21.13,54.58 22.02,55.46 22.02,57.5 22.78,58.26 25.55,58.26 26.16,57.65 26.16,56.07 26.13,56.05 26.13,55.64 25.2,54.7 25.2,48.61 24.43,47.84 24.43,43.65 25.45,42.64 25.45,37.05 28.12,34.38 28.12,31.33 28.62,30.83 28.62,27.52 29.39,26.76 29.39,26.38 33.58,22.19 33.58,17.11 35.61,15.08 35.61,12.79 35.3,12.49
5V_S5 on L3: 93.62,11.47 94.18,10.91 98.96,10.91 100.07,9.8 104.44,9.8 105.79,11.14 111,11.14 111.68,10.46 112.67,10.46 114.1,9.03 114.1,8.73 114.08,8.72 114.08,8.34 113.79,8.04 113.43,8.04 112.32,9.16 105.38,9.16 105.08,8.86 99.92,8.86 99.44,9.34 97.15,9.34 96.67,9.82 96.67,10.02 96.39,10.3 91.82,10.3 91.24,10.89 91.24,11.37 91.34,11.47
5V_S5 on L3: 81.2,106.01 76.38,101.18 42.57,101.18 37.62,96.23 37.62,96.18 36.63,95.19 30.12,95.19 27.74,92.8 27.74,90.64 26.85,89.75 25.7,89.75 25.07,90.39 25.07,93.95 26.66,95.53 26.66,96.93 27.61,97.88 30.53,97.88 31.67,96.74 35.36,96.74 37.26,98.64 37.26,100.17 40.31,103.22 75.87,103.22 77.85,105.2 77.85,106.14 78.99,107.28 79.02,107.28 81.05,109.31 83.11,109.31 83.59,108.83 83.59,108.02 81.58,106.01
5V_S5 on L3: 107.49,17.62 113.33,17.62 115.11,15.84 115.11,13.05 116.13,12.03 116.94,12.03 117.91,11.07 117.91,10.38 119.66,8.63 119.66,8.25 119.96,7.94 119.96,7.87 119.81,7.71 119.48,7.71 117.45,9.74 117.14,9.74 114.48,12.41 114.48,15.59 113.08,16.98 107.62,16.98 107.36,17.24 107.36,17.49
5V_S5 on L4: 24.47,47.2 24.97,46.7 24.97,43.45 25.21,43.21 25.21,41.81 24.53,41.14 22.02,41.14 20.6,42.56 20.6,45.41 22.39,47.2
5V_S5 on L4: 26.21,56.2 26.21,60.16 27.2,61.15 27.2,63.19 28.37,64.35 28.37,66.01 28.83,66.46 28.83,69.99 24.69,74.13 24.69,76.98 26.03,78.32 26.03,84.62 27.86,86.45 27.86,92.47 27.53,92.8 26.67,92.8 26.06,92.19 26.06,90.92 23.93,88.79 23.93,85.39 22.02,83.48 22.02,78.91 21.39,78.27 21.39,77.89 20.8,77.31 20.8,72.91 23.8,69.92 24.51,69.92 24.79,69.64 24.79,65.78 23.54,64.53 23.54,57.37 24.99,55.92 25.93,55.92
5V_S5 on L4: 84.07,108.6 84.25,108.42 84.25,103.47 83.36,102.58 83.36,100.93 79.42,96.99 57.33,96.99 54.91,99.41 48.31,99.41 46.91,98.01 46.91,97.12 45.77,95.98 39.42,95.98 38.66,96.74 38.66,99.53 39.17,100.04 40.82,100.04 41.2,99.66 41.2,97.88 41.64,97.44 42.53,97.44 46.4,101.31 56.18,101.31 58.09,99.41 69.77,99.41 70.28,98.9 78.15,98.9 81.58,102.33 81.58,107.03 83.16,108.6
5V_S5 on L5VCC: 115.7,104.55 115.3,104.95 115.3,106.47 111.89,109.88 103.09,109.88 102.71,109.5 89.51,109.5 89.38,109.38 86.58,109.38 82.65,105.44 78.98,105.44 78.98,106.06 83.95,111.03 101.09,111.03 101.98,111.92 113.51,111.92 118.6,106.82 118.6,104.82 118.33,104.55
5V_S5 on L5VCC: 169.04,39.53 168.39,40.18 168.39,40.94 167.24,42.08 167.24,44.34 168.77,45.86 168.77,96.44 162.29,102.91 162.29,111.9 163.05,112.66 163.05,113.41 166.1,113.41 166.1,112.19 164.96,111.04 164.96,103.77 170.8,97.93 170.8,69.99 172.45,68.34 172.45,41.32 170.66,39.53
5V_S5 on L6: 165.91,112.61 166.04,112.49 166.04,111.6 165.53,111.09 165.15,111.09 164.2,110.14 134.3,110.14 128.01,103.85 116.25,103.85 114.6,105.5 114.6,107.53 112.44,109.69 103.17,109.69 102.54,109.06 90.98,109.06 90.73,108.8 86.66,108.8 82.6,104.74 80.31,104.74 79.93,105.12 79.93,106.52 84.25,110.84 115.49,110.84 116,110.33 116,109.19 118.03,107.15 126.16,107.15 131.62,112.61
5V_S5 on L6: 54.79,2.12 46.53,2.12 45.64,1.24 30.53,1.24 29.26,2.51 29.26,5.93 28.75,6.44 28.75,9.47 29.89,10.61 29.89,10.89 32.79,13.78 34.42,13.78 34.62,13.58 34.62,12.13 34.39,11.9 32.94,11.9 30.66,9.62 30.66,3.01 31.42,2.25 44.88,2.25 45.77,3.14 54.15,3.14 55.29,4.28 55.29,6.95 55.55,7.2 56.18,7.2 56.44,6.95 56.44,3.78
5V_S5 on L6: 113.13,8.93 113.33,8.93 113.74,9.34 118.11,9.34 118.39,9.62 119.78,9.62 120.32,9.08 120.32,8.09 119.91,7.69 119.53,7.69 118.62,8.6 113.89,8.6 113.46,8.17 113.21,8.17 112.88,8.5 112.88,8.68
+3V_AVDD on BOTTOM: 25.96,15.84 25.83,15.97 25.83,19.3 27.2,20.67 27.74,20.67 27.99,20.41 27.99,19.65 26.97,18.63 26.97,16.55 27.35,16.17 27.35,15.94 27.25,15.84 ; 5 cut-outs
+5V_KB_BL on TOP: 137.84,17.62 137.59,17.87 137.59,19.4 137.72,19.52 140.51,19.52 140.77,19.27 140.77,17.75 140.64,17.62 ; 3 cut-outs
+5V_KB_BL on BOTTOM: 135.81,18.76 135.69,18.89 135.69,19.27 136.07,19.65 139.11,19.65 140.13,20.67 140.13,21.43 140.26,21.56 141.27,21.56 141.4,21.43 141.4,20.03 140.13,18.76
+5V_PVDD on BOTTOM: 22.53,12.79 21.41,13.91 21.05,13.91 20.98,13.99 20.98,14.47 21.08,14.57 21.97,14.57 22.1,14.7 23.14,14.7 23.26,14.57 23.9,14.57 23.98,14.49 25.07,14.49 25.3,14.72 25.3,15.43 25.58,15.71 30.91,15.71 31.04,15.59 31.04,14.57 30.78,14.32 26.08,14.32 25.42,13.66 25.42,12.92 25.3,12.79 ; 5 cut-outs
+V1.00A_SIP on TOP: 118.79,34.38 118.16,35.02 117.78,35.02 117.65,35.14 117.65,35.4 117.78,35.53 118.67,35.53 118.79,35.65 118.79,36.54 118.92,36.67 119.68,36.67 119.94,36.41 120.7,36.41 120.83,36.29 120.83,34.51 120.7,34.38 ; 1 cut-out
+V1.00A_SIP on TOP: 109.23,48.39 109.14,48.48 109.14,48.73 109.83,49.42 110.23,49.42 110.41,49.6 110.41,50.79 110.56,50.94 111.07,50.94 111.15,50.87 111.15,49.7 110.41,48.96 110.41,48.81 110.23,48.63 109.65,48.63 109.41,48.39
+V1.00A_SIP on BOTTOM: 135.79,39.06 135.63,39.21 135.63,40.05 135.76,40.17 136.42,40.17 136.83,40.58 136.83,40.78 137.95,41.9 137.95,44.01 138.07,44.14 139.34,44.14 139.65,43.83 139.65,41.77 136.93,39.06
+V1.00A_SIP on L3: 120.58,50.12 120.6,50.11 120.6,48.15 120.29,47.84 119.71,47.84 119.54,48.01 119.54,50.58 120.88,51.91 122.38,51.91 122.69,52.23 122.69,57.81 124.08,59.2 124.53,59.2 124.71,59.02 124.71,58.08 124.31,57.67 124.31,52.04 124,51.73 123.29,51.73 123.06,51.5 123.06,51.12 122.88,50.94 121.41,50.94
+V1.00A_SIP on L3: 109.17,47.79 111.81,47.79 112.06,48.05 112.06,48.23 112.29,48.45 112.95,48.45 113.61,47.79 115.11,47.79 115.29,47.97 115.29,49.22 114.81,49.7 109.9,49.7 109.07,48.86 109.07,47.9
+V1.00A_SIP on L6: 113.08,42.46 116.28,42.46 116.71,42.03 116.71,36.47 117.35,35.83 117.35,35.25 117.57,35.02 118.06,35.02 118.21,35.17 118.21,37.46 118.69,37.94 118.69,41.72 120.42,43.45 123.85,43.45 125.22,42.08 126.11,42.08 126.72,41.47 129.34,41.47 129.61,41.75 129.61,43.96 128.37,45.2 125.63,45.2 125.32,45.51 125.32,45.53 124.26,46.6 120.55,46.6 120.55,48.84 120.27,49.11 115.87,49.11 115.14,48.38 115.11,48.38 115.11,48.35 114.86,48.1 114.86,46.96 113.26,45.36 113.26,44.06 113.09,43.9 113.09,43.13 112.9,42.94 112.9,42.64
+V1.8A on TOP: 20.37,26.51 20.24,26.64 20.24,27.65 20.5,27.91 21.51,27.91 22.4,28.79 24.94,28.79 25.32,28.41 25.32,27.65 24.81,27.14 23.42,27.14 22.78,26.51
+V1.8A on BOTTOM: 51.08,13.61 50.6,14.09 50.6,14.85 49.17,16.27 46.28,16.27 45.96,15.96 44.56,15.96 43.72,15.12 42.71,15.12 42.24,15.59 37.13,15.59 28.12,24.6 28.12,26.13 26.59,27.65 25.2,27.65 25.07,27.52 24.31,27.52 24.18,27.65 24.18,28.54 24.43,28.79 27.04,28.79 29.2,26.64 29.2,25.43 37.77,16.86 40.64,16.86 41.4,17.62 51.23,17.62 51.84,17.01 51.84,13.86 51.59,13.61
+V1.8A on BOTTOM: 20.27,25.49 19.56,26.2 19.15,26.2 18.97,26.38 18.97,28.34 19.07,28.44 19.63,28.44 20.17,27.91 21,27.91 21.39,27.52 21.39,25.62 21.26,25.49 ; 3 cut-outs
+V1.8A on L4: 73.58,16.22 72.31,17.49 66.98,17.49 64.06,14.57 64.06,5.68 64.31,5.43 64.31,5.3 64.06,5.05 63.55,5.05 61.77,3.27 59.61,3.27 58.85,4.03 56.46,4.03 55.98,3.55 53.36,3.55 52.12,4.79 52.12,9.62 50.98,10.76 48.31,10.76 45.79,13.28 44.6,13.28 44.21,13.67 44.21,15.37 43.79,15.79 43.08,15.79 42.8,15.51 42.8,13.48 44.25,12.03 45.26,12.03 47.8,9.49 50.47,9.49 50.85,9.11 50.85,4.16 52.5,2.51 52.55,2.51 52.88,2.18 57.12,2.18 57.45,2.51 58.22,2.51 58.6,2.12 63.8,2.12 64.82,3.14 64.82,3.78 65.84,4.79 65.84,5.81 65.07,6.57 65.07,11.65 66.53,13.11 66.53,14.89 67.74,16.09 72.57,16.09 72.74,15.92 72.74,15.41 72.95,15.21 73.28,15.21 73.58,15.51
+V1.8A on L6: 77.72,19.32 78.33,19.32 79.73,20.72 80.06,20.72 80.36,21.02 80.36,21.23 80.08,21.51 79.4,21.51 79.14,21.25 78.76,21.25 77.65,20.13 76.43,20.13 74.74,18.44 74.74,17.76 72.82,15.84 72.82,15.41 72.97,15.26 73.66,15.26
+V1.8A_SIP on TOP: 114.55,35.22 114.45,35.32 114.45,35.42 114.98,35.96 114.98,36.62 114.73,36.87 113.05,36.87 112.8,36.62 112.8,36.44 112.72,36.36 111.96,36.36 111.9,36.43 111.9,37.32 112.04,37.46 112.42,37.46 112.67,37.71 112.67,38.07 112.85,38.24 114.53,38.24 115.53,37.24 115.53,36.95 115.42,36.83 115.42,35.6 115.03,35.22 ; 4 cut-outs
+V1.8A_SIP on L3: 113.1,43.58 113.61,43.58 114.88,42.31 115.31,42.31 115.72,41.9 115.72,36.08 115.14,35.5 114.7,35.5 113.33,36.87 113.33,42.61 112.93,43.02 112.93,43.4
+V1.8S_EDRAM on TOP: 119.81,71.59 119.73,71.67 119.73,72.15 119.81,72.23 121.08,72.23 121.33,72.48 121.33,72.69 121.46,72.81 121.74,72.81 121.87,72.69 121.87,72.25 121.21,71.59
+V3.3A_SIP on TOP: outline of 90 points within 94.33,37.25 115.49,49.19 ; 6 cut-outs
+V3.3A_SIP on TOP: 116.51,42.89 116.25,43.15 116.25,44.16 116.38,44.29 116.76,44.29 117.02,44.54 117.02,44.92 117.14,45.05 117.52,45.05 117.65,44.92 117.65,43.78 117.4,43.53 117.4,43.15 117.14,42.89 ; 1 cut-out
+V3.3A_SIP on L3: 109.85,43.78 117.12,43.78 117.27,43.93 117.27,45.74 116.94,46.07 110.16,46.07 109.98,45.89 109.98,44.52 109.73,44.26 109.73,43.91
+VCCGT on TOP: outline of 103 points within 101.52,60.32 145.46,99.08 ; 87 cut-outs
+VCCGT on BOTTOM: 110.54,59.99 110.01,60.52 110.01,60.67 110.46,61.13 110.46,61.76 110.01,62.22 110.01,62.53 110.49,63.01 110.49,63.54 110.36,63.67 109.95,63.67 109.78,63.49 109.7,63.49 109.55,63.64 109.55,69.66 110.23,70.35 110.56,70.35 111.45,69.46 111.45,60.77 110.67,59.99
+VCCGT on BOTTOM: outline of 90 points within 109.27,61.27 144.45,99.41 ; 7 cut-outs
+VCCGT on L3: 129.21,99.03 133.78,99.03 134.03,98.77 134.03,95.47 133.65,95.09 133.65,93.18 134.39,92.45 137.95,92.45 139.88,90.52 139.88,86.45 141.53,84.8 141.53,80.1 140.38,78.96 140.38,72.99 139.5,72.1 135.94,72.1 134.8,73.24 134.8,84.29 136.45,85.94 136.45,89.22 135.57,90.1 132.34,90.1 132.05,90.39 130.48,90.39 129.59,91.28 129.59,93.18 128.45,94.33 128.45,95.09 128.83,95.47 128.83,98.64
+VCCGT on L3: 119.33,89.25 119.33,82.69 121.12,80.9 121.12,80.89 121.15,80.86 121.15,78.23 124.76,74.62 126.48,74.62 126.8,74.31 126.8,67.15 126.72,67.15 126.74,67.13 126.74,66.62 126.4,66.29 126.11,66.29 125.75,66.64 125.75,69.43 125.09,70.1 121.79,70.1 121.36,69.67 121.36,64.87 120.6,64.1 119.96,64.1 119.07,64.99 115.26,64.99 114.69,65.56 114.69,67.69 114.04,68.35 114.04,74.62 114.03,74.63 114.04,74.64 114.04,78.56 114.35,78.87 114.35,82.55 110.18,86.71 110.18,88.64 111.43,89.88 118.69,89.88
+VCCGT on L4: 125.78,66.95 126.31,66.95 126.57,66.69 126.57,66.41 126.08,65.93 126.08,64.66 126.54,64.2 126.54,63.82 126.39,63.67 125.58,63.67 125.3,63.95 125.3,66.46
+VCCGT on L5VCC: 111.13,60.33 111.03,60.42 111.03,63.77 112.14,64.88 113.31,64.88 113.92,65.48 114.19,65.56 114.3,65.56 114.35,65.61 114.51,65.65 114.56,65.69 117.25,65.69 117.69,66.13 117.69,67.28 114.44,70.53 114.44,73.55 110.55,77.44 110.55,87.87 121.77,99.09 133.5,99.09 134.15,98.44 134.15,96.11 133.34,95.29 133.34,93.36 141.41,85.28 141.41,80.11 138.75,77.44 138.75,70.23 138.27,69.75 131.21,69.75 126.63,65.17 126.63,63.9 125.47,62.74 113.86,62.74 111.45,60.33
+VCCGT on L6: 114.35,78.87 114.04,78.56 114.04,72.04 113.84,71.85 110.67,71.85 110.03,71.21 110.03,60.67 110.54,60.16 111.56,60.16 113.84,62.45 117.17,62.45 117.25,62.37 120.77,62.37 121.15,62.75 121.15,80.83 119.33,82.65 119.33,89.9 118.99,90.24 117.82,91.41 112.6,91.41 112.34,91.16 112.34,84.55 114.35,82.55 114.35,82.52 114.78,82.08 114.78,79.3
+VCCGT on L6: 134.03,95.47 133.65,95.09 133.65,93.18 134.42,92.42 137.97,92.42 139.88,90.52 139.88,86.45 141.53,84.8 141.53,80.1 140.38,78.96 140.38,72.99 139.5,72.1 136.32,72.1 136.07,72.36 136.07,74.01 136.57,74.51 136.57,87.85 134.8,89.63 134.14,89.63 132.08,91.69 131.24,91.69 128.45,94.48 128.45,95.09 128.83,95.47 128.83,98.64 129.21,99.03 133.78,99.03 134.03,98.77
+VCCIO on TOP: 106.73,59.66 106.35,60.04 105.21,60.04 103.05,62.2 103.05,63.85 99.11,67.78 94.03,67.78 89.84,71.97 89.84,83.79 92.38,86.33 94.41,86.33 94.66,86.07 94.66,82.77 93.01,81.12 93.01,73.88 94.66,72.23 100.63,72.23 101.14,71.72 101.14,69.43 102.67,67.91 108.25,67.91 109.9,66.26 111.81,66.26 112.44,66.89 113.59,66.89 113.71,66.77 113.71,65.88 113.33,65.5 112.57,65.5 112.49,65.42 111.73,65.42 110.41,64.1 110.41,60.8 109.27,59.66 ; 3 cut-outs
+VCCIO on TOP: 110.59,51.2 110.54,51.25 110.54,52.67 110.41,52.8 110.41,53.81 110.67,54.07 110.67,54.58 110.74,54.65 111.48,54.65 112.06,54.07 112.06,53.36 112.16,53.26 112.75,53.26 112.85,53.15 112.85,52.67 112.77,52.59 112.37,52.59 112.14,52.37 112.14,52.11 111.81,51.78 111.43,51.78 111.12,51.48 111.12,51.25 111.07,51.2 ; 3 cut-outs
+VCCIO on BOTTOM: 109.6,52.54 109.44,52.7 109.44,53.74 109.62,53.92 110.25,53.92 110.91,54.58 111.2,54.58 111.45,54.83 111.45,59.07 111.12,59.41 110.06,59.41 109.42,60.04 109.42,60.17 109.55,60.29 109.93,60.29 110.42,59.81 110.72,59.81 111.12,60.21 111.76,60.21 111.96,60.01 111.96,53.31 111.2,52.55 111.15,52.55 111.14,52.54
+VCCIO on L4: 112.83,67.02 113.08,66.77 113.08,61.18 111.94,60.04 111.94,58 112.32,57.62 112.32,52.16 111.94,51.78 110.79,51.78 109.78,52.8 109.78,66.77 110.03,67.02
+VCCIO on L5VCC: 110.44,51.72 109.66,52.5 109.66,66.1 111.15,67.59 112.9,67.59 113.63,66.87 113.63,65.73 113.15,65.26 111.98,65.26 110.65,63.93 110.65,60.26 110.81,60.11 110.63,59.39 110.58,58.99 110.63,58.65 110.6,57.26 110.81,55.4 112.96,53.26 112.28,52.57 112.28,52.14 111.86,51.72
+VCCIO_SIP on TOP: 92.63,86.86 92.58,86.91 92.58,88.18 92.66,88.26 93.32,88.26 93.55,88.48 93.55,89.07 93.62,89.15 93.75,89.15 94.16,89.55 94.16,90.75 94.08,90.82 93.04,90.82 93.01,90.85 93.01,92.55 93.14,92.68 94.28,92.68 94.66,92.29 95.05,92.29 95.3,92.04 95.3,91.15 95.43,91.02 95.55,91.02 95.81,90.77 95.81,87.8 94.87,86.86 ; 2 cut-outs
+VCCMPHYGTAON_1P0_LS_SIP on TOP: 89.66,33.06 89.28,33.44 89.28,34.28 89.43,34.43 91.39,34.43 93.7,36.75 96.65,36.75 96.98,36.41 96.98,35.53 96.42,34.97 94.44,34.97 92.53,33.06
+VCCMPHYGTAON_1P0_LS_SIP on TOP: 117.27,45.3 117.14,45.43 117.14,46.45 116.89,46.7 115.75,46.7 115.49,46.96 115.49,47.34 115.62,47.46 115.87,47.46 116.13,47.72 116.13,48.35 116.25,48.48 117.65,48.48 117.78,48.35 117.78,47.97 117.52,47.72 117.52,46.7 117.78,46.45 117.91,46.45 118.03,46.32 118.03,45.94 118.16,45.81 118.67,45.81 118.92,46.07 119.68,46.07 119.81,45.94 119.81,45.43 119.68,45.3 ; 3 cut-outs
+VCCMPHYGTAON_1P0_LS_SIP on TOP: 112.95,46.3 112.88,46.37 112.88,47.72 112.72,47.87 112.39,47.87 112.27,48 112.27,48.23 112.39,48.35 112.7,48.35 113.28,47.77 113.51,47.77 113.61,47.67 113.61,46.5 113.41,46.3
+VCCMPHYGTAON_1P0_LS_SIP on TOP: 119.18,37.96 118.84,38.29 118.84,43.73 119.35,44.24 120.32,44.24 120.42,44.14 120.42,43.68 120.09,43.35 120.09,38.17 119.89,37.96
+VCCMPHYGTAON_1P0_LS_SIP on BOTTOM: 119.37,43.76 118.86,44.27 118.03,44.27 117.8,44.5 117.8,45.28 117.93,45.41 118.21,45.41 118.77,45.97 118.77,46.3 118.59,46.47 118.59,46.57 118.67,46.65 118.89,46.65 119.24,46.3 119.24,44.5 119.48,44.26 119.58,44.26 119.78,44.07 119.78,43.91 119.62,43.76
+VCCMPHYGTAON_1P0_LS_SIP on BOTTOM: 92.84,13.68 92.71,13.81 92.71,14.75 92.81,14.85 94.82,14.85 95.02,15.05 95.02,16.35 95.2,16.53 97.48,16.53 97.64,16.68 97.64,17.7 97.71,17.77 98.68,17.77 99.49,16.96 99.49,14.93 99.21,14.65 98.32,14.65 98.04,14.37 98.04,13.94 97.79,13.68 ; 1 cut-out
+VCCMPHYGTAON_1P0_LS_SIP on BOTTOM: 88.19,24.81 87.86,25.14 87.86,33.47 88.77,34.38 90.27,34.38 90.57,34.08 90.57,33.6 90.02,33.04 90.02,26.92 89.41,26.31 89.41,25.16 89.05,24.81
+VCCMPHYGTAON_1P0_LS_SIP on L3: 112.34,48.33 112.75,48.33 113.46,47.62 115.47,47.62 116.2,48.35 117.65,48.35 117.85,48.15 117.85,47.79 116.36,46.3 112.95,46.3 112.22,47.03 112.22,48.2
+VCCMPHYGTAON_1P0_LS_SIP on L4: 97.79,14.29 97.79,13.81 97.55,13.57 95.55,13.57 93.8,15.32 91.91,15.32 86.71,20.51 86.71,24.68 86.99,24.96 86.99,26.46 87.32,26.79 89.1,26.79 89.25,26.64 89.25,25.42 88.87,25.04 88.87,24.63 88.31,24.07 88.31,23.28 88.67,22.93 88.67,20.59 92.59,16.67 94.78,16.67 96.05,15.4 96.68,15.4
+VCCMPHYGTAON_1P0_LS_SIP on L4: 105.03,47.79 103.43,46.19 103.43,43.88 102.41,42.87 102.41,40.3 96.67,34.56 96.19,34.56 95.76,34.99 95.76,35.48 99.59,39.31 99.59,40 101.09,41.49 101.09,43.15 102.03,44.09 102.03,44.7 101.34,45.38 101.34,47.41 105.84,51.91 110.29,51.91 110.95,51.25 111.05,51.25 111.66,50.64 119.43,50.64 119.81,50.26 119.81,44.06 119.51,43.76 118.95,43.76 118.82,43.88 118.82,44.31 118.64,44.49 117.65,44.49 117.3,44.85 117.3,49.09 116.99,49.39 114.32,49.39 114.07,49.14 114.07,48.33 113,47.26 110.31,47.26 109.78,47.79
+VCCPAZIO on L6: 106.07,43.4 105.97,43.5 105.97,44.26 106.45,44.75 110.06,44.75 110.59,44.21 110.59,43.78 110.21,43.4
+VCCPDSW_3P3 on L6: 110.34,42.92 110.51,42.74 110.51,41.77 110.29,41.55 106.22,41.55 106.07,41.7 106.07,42.61 106.37,42.92
+VCCPRIM_CORE on TOP: 96.21,28.11 95.96,28.36 95.96,28.9 96.19,29.13 96.42,29.13 96.7,29.4 96.7,29.66 96.11,30.24 96.11,31.87 96.48,32.24 96.48,32.67 97.43,33.62 97.43,35.58 97.69,35.83 99.13,35.83 99.31,35.65 99.31,33.06 98.12,31.87 98.12,31.49 97.61,30.98 97.61,30.6 98.17,30.04 98.17,28.59 97.69,28.11
+VCCPRIM_CORE on TOP: 92.89,17.87 92.71,18.05 92.71,20.59 92.89,20.77 95.22,20.77 95.58,20.41 95.58,18.03 95.43,17.87 ; 3 cut-outs
+VCCPRIM_CORE on BOTTOM: 92.91,16.86 92.51,17.26 92.51,19.96 92.71,20.16 95.63,20.16 95.93,19.85 95.93,16.98 95.81,16.86 ; 2 cut-outs
+VCCPRIM_CORE on L3: 97.94,28.29 97.13,29.1 96.09,29.1 95.86,28.87 95.86,27.22 96.34,26.74 96.34,23.51 96,23.17 96,22.43 95.58,22.01 95.4,22.01 93.5,20.11 93.17,20.11 92.96,19.9 92.96,19.65 93.11,19.5 94.64,19.5 97.15,22.01 97.61,22.01 97.94,22.34
+VCCPRIM_CORE on L5VCC: 92.97,19.21 92.7,19.48 92.7,21.6 93.97,22.87 93.97,28.97 95.62,30.62 95.62,33.67 98.93,36.99 103.63,36.99 105.67,39.02 110.24,39.02 110.6,39.38 110.6,41.83 110.35,42.08 110.35,46.75 113.16,49.56 115.92,49.56 116.19,49.29 116.19,48.18 112.89,44.88 112.89,39.16 110.08,36.35 105.89,36.35 104.11,34.57 99.79,34.57 97.78,32.56 97.78,29.38 95.49,27.1 95.49,23.51 95.62,23.38 95.62,20.24 94.59,19.21
+VCCPRIM_CORE on L6: 114.76,48.38 116.03,48.38 116.2,48.56 116.2,49.93 116.03,50.11 113.18,50.11 112.85,49.78 112.85,48.96 110.92,47.03 110.92,44.54 111.43,44.03 111.43,43.48 111.45,43.45 111.45,42.69 110.69,41.93 110.69,41.75 110.41,41.47 110.41,40.35 110.29,40.22 105.46,40.22 103.05,37.81 100.28,37.81 97.99,35.53 97.99,35.07 98.22,34.84 104.49,34.84 106.3,36.64 111.22,36.64 111.68,37.1 111.68,41.52 112.62,42.46 112.62,42.92 112.85,43.15 112.85,43.83 112.95,43.93 112.95,45.3 114.48,46.83 114.48,48.1
+VCCSA on TOP: 111.56,50.13 111.3,50.38 111.3,51.27 111.56,51.53 111.94,51.53 112.32,51.91 112.32,52.09 112.57,52.34 113.13,52.34 113.33,52.54 113.33,53.2 113.56,53.43 123.11,53.43 123.18,53.5 123.81,53.5 125.14,54.83 127.81,54.83 130.86,57.88 138.86,57.88 139.37,57.37 139.37,54.32 138.99,53.94 132.76,53.94 130.3,51.48 130.1,51.48 129.61,51.96 129.61,52.54 129.49,52.67 128.37,52.67 128.14,52.44 128.14,52.06 128.37,51.83 128.37,50.97 128.29,50.89 127.1,50.89 126.41,50.21 124.81,50.21 124.26,50.77 112.32,50.77 111.68,50.13 ; 15 cut-outs
+VCCSA on BOTTOM: 131.24,53.69 130.99,53.94 130.99,57.88 131.88,58.77 131.88,59.96 132,60.09 134.29,60.09 134.52,59.86 134.52,59.43 134.16,59.07 134.16,53.81 134.03,53.69 ; 1 cut-out
+VCCSA on BOTTOM: 120.8,49.47 120.41,49.86 120.09,49.86 119.83,50.12 119.83,50.56 119.88,50.62 119.88,53.19 120.53,53.84 121.03,53.84 121.13,53.74 121.13,53.13 121.28,52.99 121.98,52.99 122.08,52.89 122.08,52.89 122.08,52.68 121.89,52.48 121.89,52.15 122.09,51.95 122.09,51.75 121.89,51.56 121.89,51.22 122.08,51.03 122.08,50.85 121.88,50.64 121.88,50.32 122.07,50.14 122.07,49.91 121.8,49.64 121.8,49.57 121.69,49.47
+VCCSA on BOTTOM: 111.2,49.75 111.2,49.75 110.57,49.75 110.44,49.88 110.44,51.15 110.82,51.53 111.55,51.53 111.68,51.4 111.68,49.88 111.56,49.75
+VCCSA on L6: 113.33,53.81 112.16,52.65 110.73,52.65 110.48,52.4 110.48,50.24 110.73,49.98 112.62,49.98 113.05,50.41 116.61,50.41 117.04,49.98 126.03,49.98 126.03,50 127.18,51.15 127.18,53.05 126.74,53.48 123.87,53.48 123.54,53.81
+VDDQ_CPU_CLK on L4: 107.41,60.11 109.32,60.11 109.6,59.83 109.6,59.22 109.4,59.02 106.55,59.02 106.4,59.17 106.4,59.68 106.86,60.14 107.39,60.14
GND on TOP: 64.62,18.69 64.46,18.84 64.46,20.18 64.79,20.51 66.04,20.51 66.09,20.46 66.09,20.08 66.34,19.83 67.05,19.83 67.26,19.63 67.26,19.3 66.65,18.69 ; 3 cut-outs
GND on TOP: 106.58,99.58 106.45,99.71 106.45,100.17 106.58,100.3 106.58,101.34 106.17,101.74 103.78,101.74 103.07,101.03 102.11,101.03 101.98,101.16 101.98,101.79 102.18,102 103.07,102 103.38,102.3 106.68,102.3 107.36,101.62 107.36,99.71 107.24,99.58
GND on TOP: 27.53,54.63 27.3,54.86 26.57,54.86 26.41,55.01 26.41,55.29 27.42,56.29 27.93,56.29 28.14,56.51 28.8,56.51 28.88,56.43 28.88,55.8 28.65,55.57 28.65,54.88 28.4,54.63 ; 2 cut-outs
GND on TOP: 118.21,43.81 118.11,43.91 118.11,44.19 118.21,44.29 118.64,44.29 118.87,44.52 118.87,44.95 118.97,45.05 121.11,45.05 121.23,44.92 121.23,44.49 121.13,44.39 119.33,44.39 118.74,43.81
GND on TOP: 18.24,5.99 18.18,6.04 18.18,6.6 18.29,6.7 18.49,6.7 18.67,6.87 18.67,7.31 18.79,7.43 19.45,7.43 19.76,7.74 19.76,8.2 19.84,8.27 20.32,8.27 20.42,8.17 20.42,7.76 19.1,6.44 19.1,6.32 18.77,5.99 ; 1 cut-out
GND on TOP: 121,59.17 120.88,59.3 120.88,59.76 121.02,59.9 121.83,59.9 121.97,60.04 121.97,60.67 121.72,60.93 111.99,60.93 111.76,61.15 111.76,63.44 111.91,63.59 121.84,63.59 122.1,63.85 123.42,63.85 123.54,63.72 123.54,63.06 122.48,61.99 122.48,59.3 122.35,59.17 ; 18 cut-outs
GND on TOP: 196.67,25.67 195.43,26.92 195.43,27.32 195.5,27.4 195.76,27.4 196.52,26.64 197.13,26.64 197.71,27.22 198.58,27.22 198.68,27.12 198.68,25.85 198.5,25.67 ; 1 cut-out
GND on TOP: 11.61,79.09 11.1,79.59 10.34,79.59 10.01,79.92 10.01,82.43 9.26,83.4 8.13,82.94 1.45,82.94 1.45,88.95 3.96,88.95 4.91,88.45 5.77,89.1 5.9,89.23 5.9,90.91 6.78,91.79 9.83,91.79 10.59,91.02 10.59,90.26 11.23,89.63 15.8,89.63 17.32,91.15 18.18,91.15 20.62,88.71 20.62,87.47 19.86,86.71 17.58,86.71 16.94,86.07 16.94,85.69 16.43,85.18 16.18,85.18 16.05,85.31 16.05,85.69 15.8,85.94 14.53,85.94 12.88,84.29 12.88,83.15 13.51,82.52 16.81,82.52 16.94,82.39 16.94,79.21 16.81,79.09 ; 1 cut-out
GND on TOP: 25.02,47.31 24.89,47.44 24.89,48.07 25.55,48.73 25.55,50.26 25.58,50.28 26.62,50.28 26.67,50.23 26.67,49.24 26.74,49.17 27.35,49.17 27.39,49.13 27.39,48.78 27.38,48.78 27.02,48.43 26.52,48.43 26.31,48.23 26.31,47.39 26.24,47.31 ; 1 cut-out
GND on TOP: 161.26,55.74 161.14,55.87 161.14,57.34 160.5,57.98 160.5,60.04 160.81,60.34 160.81,61.15 160.72,61.24 160.72,62.13 160.96,62.37 161.49,62.37 161.57,62.3 161.57,58.26 162.25,57.57 162.25,55.85 162.15,55.74 ; 1 cut-out
GND on TOP: 113.69,72.64 113.41,72.91 113.41,74.49 112.57,75.33 112.57,76.24 113.49,77.16 114.32,77.16 114.48,77 114.48,76.42 114.76,76.14 114.76,75.12 115.09,74.79 115.09,73.88 115.37,73.6 115.37,73.12 114.88,72.64 ; 5 cut-outs
GND on TOP: 76.63,58.77 76,59.4 76,60.29 76.38,60.67 84.25,60.67 84.5,60.42 84.5,59.66 83.62,58.77 ; 15 cut-outs
GND on TOP: 28.6,46.24 28.55,46.3 28.55,47.29 28.62,47.36 29.61,47.36 29.69,47.44 29.69,48.07 30.2,48.07 30.33,47.95 30.33,47.59 30.61,47.31 31.49,47.31 31.57,47.24 31.57,46.78 31.39,46.6 30.45,46.6 30.1,46.24
GND on TOP: 106.25,8.22 105.99,8.47 105.99,9.08 105.84,9.24 105.46,9.24 105.33,9.36 105.33,9.74 105.47,9.88 107.12,9.88 107.52,9.49 108.84,9.49 109.14,9.19 109.14,8.4 108.96,8.22
GND on TOP: outline of 129 points within 1.45,48.75 182.52,113.41 ; 8 cut-outs
GND on TOP: 59.51,92.32 59.23,92.6 59.23,93.41 58.88,93.77 58.88,94.28 59.76,95.17 59.76,99.15 60.26,99.65 61.75,99.65 63.69,101.59 66.29,101.59 66.42,101.46 66.42,100.37 65.91,99.86 65.38,99.86 64.97,99.46 64.97,97.83 65.15,97.65 66.14,97.65 66.65,97.15 66.65,95.29 65.43,94.07 65.43,93.74 65.25,93.56 63.42,93.56 63.41,93.58 62.95,93.58 62.81,93.72 62.81,94.23 62.58,94.45 61.47,94.45 61.24,94.23 61.24,92.85 60.7,92.32 ; 7 cut-outs
GND on TOP: 139.88,84.93 139.75,85.06 139.75,87.6 139.88,87.72 141.53,87.72 142.29,86.96 144.52,86.96 145.08,86.4 145.08,85.23 144.78,84.93 ; 8 cut-outs
GND on TOP: 142.72,43.86 142.64,43.93 142.64,44.47 142.49,44.62 141.83,44.62 141.17,43.96 140.1,43.96 139.9,44.16 139.9,45.08 141.02,46.19 143.81,46.19 143.94,46.07 143.94,43.91 143.89,43.86
GND on TOP: 109.75,49.57 109.7,49.62 109.7,49.78 109.09,50.38 109.09,51.2 109.02,51.27 109.02,52.42 108.38,53.05 108.38,55.21 108.63,55.46 108.74,55.46 108.96,55.24 108.96,54.91 109.14,54.73 109.62,54.73 109.93,55.03 109.93,56.51 110.03,56.61 121.08,56.61 121.33,56.35 122.91,56.35 122.99,56.28 122.99,55.9 122.83,55.74 122.6,55.74 122.35,55.49 122.35,55.08 121.72,54.45 121.72,54.07 121.46,53.81 113.59,53.81 113.28,53.51 112.29,53.51 112.22,53.59 112.22,54.75 112.14,54.83 110.59,54.83 110.44,54.68 110.44,54.12 110.29,53.97 110.29,49.65 110.21,49.57 ; 27 cut-outs
GND on TOP: 176.07,42.87 174.9,44.03 174.9,44.62 174.95,44.67 175.59,44.67 175.77,44.85 175.77,45.64 175.89,45.76 176.73,45.76 177.06,45.43 177.6,45.43 177.7,45.33 177.7,44.01 177.57,43.88 177.57,43.04 177.39,42.87 ; 2 cut-outs
GND on TOP: 45.64,18.76 45.52,18.89 45.52,19.63 45.67,19.78 46.25,19.78 46.73,20.26 46.73,20.87 47.8,21.94 47.8,22.98 48.03,23.21 49.96,23.21 51.18,24.43 53.8,24.43 53.92,24.3 53.92,23.89 53.85,23.82 53.52,23.82 53.39,23.69 53.39,23.21 53.01,22.83 53.01,22.32 52.75,22.06 52.12,22.06 51.87,22.32 48.69,22.32 48.31,21.94 48.31,20.41 48.06,20.16 47.29,20.16 46.91,19.78 46.91,19.14 46.53,18.76 ; 3 cut-outs
GND on TOP: 25.04,95.22 24.79,95.47 23.95,95.47 23.87,95.55 23.87,96.41 23.98,96.51 24.66,96.51 25.22,95.95 25.91,95.95 25.98,95.88 25.98,95.52 25.68,95.22
GND on TOP: 136.45,48.48 136.07,48.86 136.07,53.05 136.45,53.43 138.73,53.43 139.11,53.05 139.11,48.99 138.61,48.48 ; 5 cut-outs
GND on TOP: 99.39,96.89 99.34,96.94 99.34,97.48 99.54,97.68 99.72,97.68 100,97.96 100,100.4 100.1,100.5 102.69,100.5 102.82,100.37 102.82,99.89 102.46,99.53 101.4,99.53 101.09,99.23 101.09,97.83 100.94,97.68 100.33,97.68 100.07,97.43 100.07,97.07 99.9,96.89
GND on TOP: 95.93,17.87 95.83,17.97 95.83,20.46 96.06,20.69 97.66,20.69 98.45,19.9 98.45,18.84 97.81,18.2 97.28,18.2 96.95,17.87 ; 3 cut-outs
GND on TOP: 176.83,21.66 176.45,22.04 176.45,22.88 176.78,23.21 177.26,23.21 177.95,22.52 179.7,22.52 179.86,22.37 179.86,21.78 179.73,21.66 ; 3 cut-outs
GND on TOP: 35.15,21.48 34.8,21.84 34.8,22.62 34.87,22.7 36.22,22.7 36.32,22.6 36.32,22.06 35.74,21.48 ; 2 cut-outs
GND on TOP: 195.63,11.01 195.38,11.27 195.38,14.32 195.5,14.44 197.03,14.44 197.28,14.19 197.28,13.17 197.53,12.92 198.42,12.92 198.8,12.54 198.8,11.27 198.55,11.01
GND on TOP: 142.54,68.93 141.65,69.82 140.64,69.82 140.38,70.07 134.03,70.07 133.65,70.45 133.65,71.59 134.03,71.97 139.24,71.97 139.75,72.48 139.75,77.69 139.37,78.07 138.23,78.07 137.97,78.32 137.97,78.96 138.1,79.09 145.21,79.09 145.46,78.83 145.46,78.32 145.08,77.94 145.08,69.82 144.19,68.93 ; 30 cut-outs
GND on TOP: outline of 145 points within 0.51,21.45 29.26,70.96 ; 5 cut-outs
GND on TOP: 123.21,35.78 123.09,35.91 123.09,36.31 122.6,36.8 121.44,36.8 121.33,36.9 121.33,37.68 121.44,37.79 122.3,37.79 122.78,38.27 123.24,38.27 123.32,38.19 123.32,36.97 123.8,36.49 123.8,36.01 123.57,35.78 ; 1 cut-out
GND on TOP: 169.98,25.37 169.21,26.13 169.21,28.79 169.72,29.3 174.29,29.3 174.55,29.05 174.55,26.13 173.79,25.37
GND on TOP: 102.08,104.74 101.83,104.99 101.83,105.68 101.75,105.76 100.3,105.76 100.23,105.68 100.23,105.35 100.2,105.33 99.13,105.33 99.11,105.35 99.11,105.68 99.03,105.76 97.51,105.76 97.13,105.38 95.73,105.38 95.22,105.88 92.17,105.88 91.16,104.87 90.14,104.87 89.89,105.12 89.89,106.77 90.14,107.03 96.49,107.03 97,106.52 98.78,106.52 98.86,106.44 100.18,106.44 100.2,106.42 100.2,106.16 100.35,106.01 102.13,106.01 102.31,105.83 102.31,105.12 102.39,105.05 102.39,104.87 102.26,104.74 ; 9 cut-outs
GND on TOP: outline of 92 points within 50.85,66.89 94,95.75 ; 45 cut-outs
GND on TOP: 122.55,98.9 122.35,99.1 122.35,101.31 122.99,101.95 129.59,101.95 129.97,101.57 129.97,100.22 128.65,98.9 ; 8 cut-outs
GND on TOP: outline of 182 points within 0.51,0.51 204.34,37.63 ; 17 cut-outs
GND on TOP: 136.62,58.23 136.45,58.41 136.45,63.59 136.57,63.72 140.38,63.72 140.51,63.59 140.51,62.83 140.77,62.58 144.47,62.58 144.85,62.2 144.85,61 144.52,60.67 141.37,60.67 138.94,58.23 ; 12 cut-outs
GND on TOP: 117.68,35.65 117.24,36.08 116.86,36.08 116.76,36.19 116.76,36.57 117.32,37.13 117.32,38.47 117.12,38.68 117.12,39.44 117.22,39.54 118.03,39.54 118.31,39.26 118.31,38.62 118.63,38.31 118.63,36.96 118.51,36.85 118.51,35.81 118.36,35.65 ; 2 cut-outs
GND on TOP: 117.65,65.35 117.55,65.45 117.55,65.93 117.42,66.06 114.83,66.06 114.6,66.29 114.6,67.53 114.48,67.66 112.83,67.66 111.81,66.64 109.9,66.64 109.78,66.77 109.78,67.4 110.67,68.29 111.17,68.29 111.68,68.8 117.14,68.8 117.27,68.93 117.27,70.45 117.14,70.58 117.14,71.34 117.27,71.47 118.03,71.47 118.16,71.34 118.16,70.45 118.54,70.07 118.54,65.55 118.34,65.35 ; 13 cut-outs
GND on TOP: 120.57,83.53 120.06,84.04 120.06,88.36 120.32,88.61 122.86,88.61 123.49,87.98 123.49,83.91 123.11,83.53
GND on TOP: outline of 140 points within 56.69,20.79 94.28,56.35 ; 58 cut-outs
GND on TOP: 26.16,82.64 25.96,82.85 25.96,83.76 25.7,84.01 25.7,88.26 26.21,88.76 26.72,88.76 26.97,88.51 26.97,83.46 26.72,83.2 26.72,82.8 26.57,82.64 ; 8 cut-outs
GND on TOP: 116.05,44.54 115.85,44.75 115.85,45.43 115.7,45.58 114.6,45.58 114.43,45.41 112.09,45.41 112.01,45.48 112.01,46.73 112.14,46.85 112.62,46.85 112.7,46.78 112.7,46.17 112.8,46.07 113.56,46.07 113.76,46.27 113.76,47.82 113.59,48 113.16,48 112.27,48.89 112.27,50.11 112.75,50.59 122.02,50.59 122.17,50.44 122.17,49.95 122.32,49.8 122.32,49.39 122.05,49.11 121.64,49.11 121.16,48.63 120.65,48.63 120.52,48.76 120.52,49.22 120.27,49.47 119.96,49.47 119.61,49.11 119.61,47.36 119.91,47.06 120.37,47.06 120.62,46.8 121.03,46.8 121.21,46.63 121.21,46.17 121.12,46.08 120.69,46.08 120.19,46.57 117.91,46.57 117.65,46.83 117.65,47.59 117.78,47.72 118.69,47.72 118.81,47.83 118.81,48.19 118.36,48.63 116.58,48.63 116.33,48.89 116.33,49.24 116.1,49.47 115.82,49.47 115.67,49.32 115.67,48.76 115.92,48.51 115.92,47.84 115.72,47.64 115.49,47.64 115.31,47.46 115.31,46.85 115.75,46.42 116.81,46.42 116.89,46.35 116.89,44.72 116.71,44.54 ; 1 cut-out
GND on TOP: 119.66,73.17 119.56,73.27 119.56,74.31 119.71,74.46 119.71,76.34 120.45,77.08 121.69,77.08 121.94,76.83 122.99,76.83 123.72,76.09 123.72,75.76 123.54,75.58 122.83,75.58 122.65,75.76 122.27,75.76 121.97,75.45 121.97,74.72 121.77,74.51 121.61,74.51 121.18,74.95 120.62,74.95 120.5,74.82 120.5,74.06 120.65,73.91 121.08,73.91 121.18,73.8 121.18,73.27 121.08,73.17 ; 7 cut-outs
GND on TOP: 109.9,45.05 109.65,45.3 109.65,48.1 109.78,48.23 110.54,48.23 110.67,48.35 110.92,48.35 111.05,48.23 111.05,47.84 110.67,47.46 110.67,45.18 110.54,45.05
GND on TOP: 112.56,35.11 112.47,35.2 112.47,35.58 112.95,36.06 112.95,36.54 113.13,36.72 114.68,36.72 114.88,36.52 114.88,36.08 113.9,35.11 ; 1 cut-out
GND on TOP: 140.71,32.5 140.66,32.55 140.66,34.41 140.88,34.62 141.9,34.62 142.16,34.89 142.54,34.89 142.67,35.02 142.67,37.3 142.8,37.43 144.19,37.43 144.45,37.18 144.45,36.47 145.08,35.83 145.08,34 144.96,33.87 144.19,33.87 143.81,33.49 143.18,33.49 143.05,33.37 143.05,32.86 142.95,32.76 141.81,32.76 141.55,32.5 ; 9 cut-outs
GND on BOTTOM: 24.33,14.7 24.18,14.85 23.47,14.85 23.19,15.13 22.05,15.13 21.7,14.79 21.04,14.79 21,14.82 21,17.11 21.92,18.03 21.92,19.42 22.02,19.52 22.91,19.52 23.29,19.9 23.8,19.9 24.05,19.65 24.05,19.27 24.18,19.14 25.32,19.14 25.7,18.76 25.7,16.22 25.07,15.59 25.07,14.8 24.97,14.7 ; 13 cut-outs
GND on BOTTOM: 137.11,84.8 137.01,84.9 137.01,87.9 137.34,88.23 140.89,88.23 142.42,86.71 144.83,86.71 144.96,86.58 144.96,85.18 144.58,84.8
GND on BOTTOM: 108.2,46.24 107.62,46.83 107.62,47.36 107.69,47.44 108.38,47.44 108.48,47.34 108.48,47.16 108.35,47.03 108.35,46.65 108.53,46.47 108.53,46.32 108.46,46.24
GND on BOTTOM: 19.91,37.25 20.09,37.43 22.48,37.43 22.86,37.05 22.86,35.83 22.96,35.73 22.96,33.87 22.58,33.49 22.15,33.49 21.99,33.65 21.99,34.08 22.35,34.43 22.35,36.77 22.2,36.92 20.88,36.92 20.17,36.21 19.63,36.21 19.45,36.03 19.45,34.81 19.18,34.54 17.98,34.54 17.63,34.18 17.3,34.18 17.07,34.41 17.07,34.99 17.35,35.27 17.35,36.47 17.4,36.52 18.34,36.52 18.6,36.78 18.6,37.19 18.67,37.25
GND on BOTTOM: 141.91,33.37 141.78,33.49 141.78,35.91 141.91,36.03 144.32,36.03 144.58,35.78 144.58,33.49 144.45,33.37
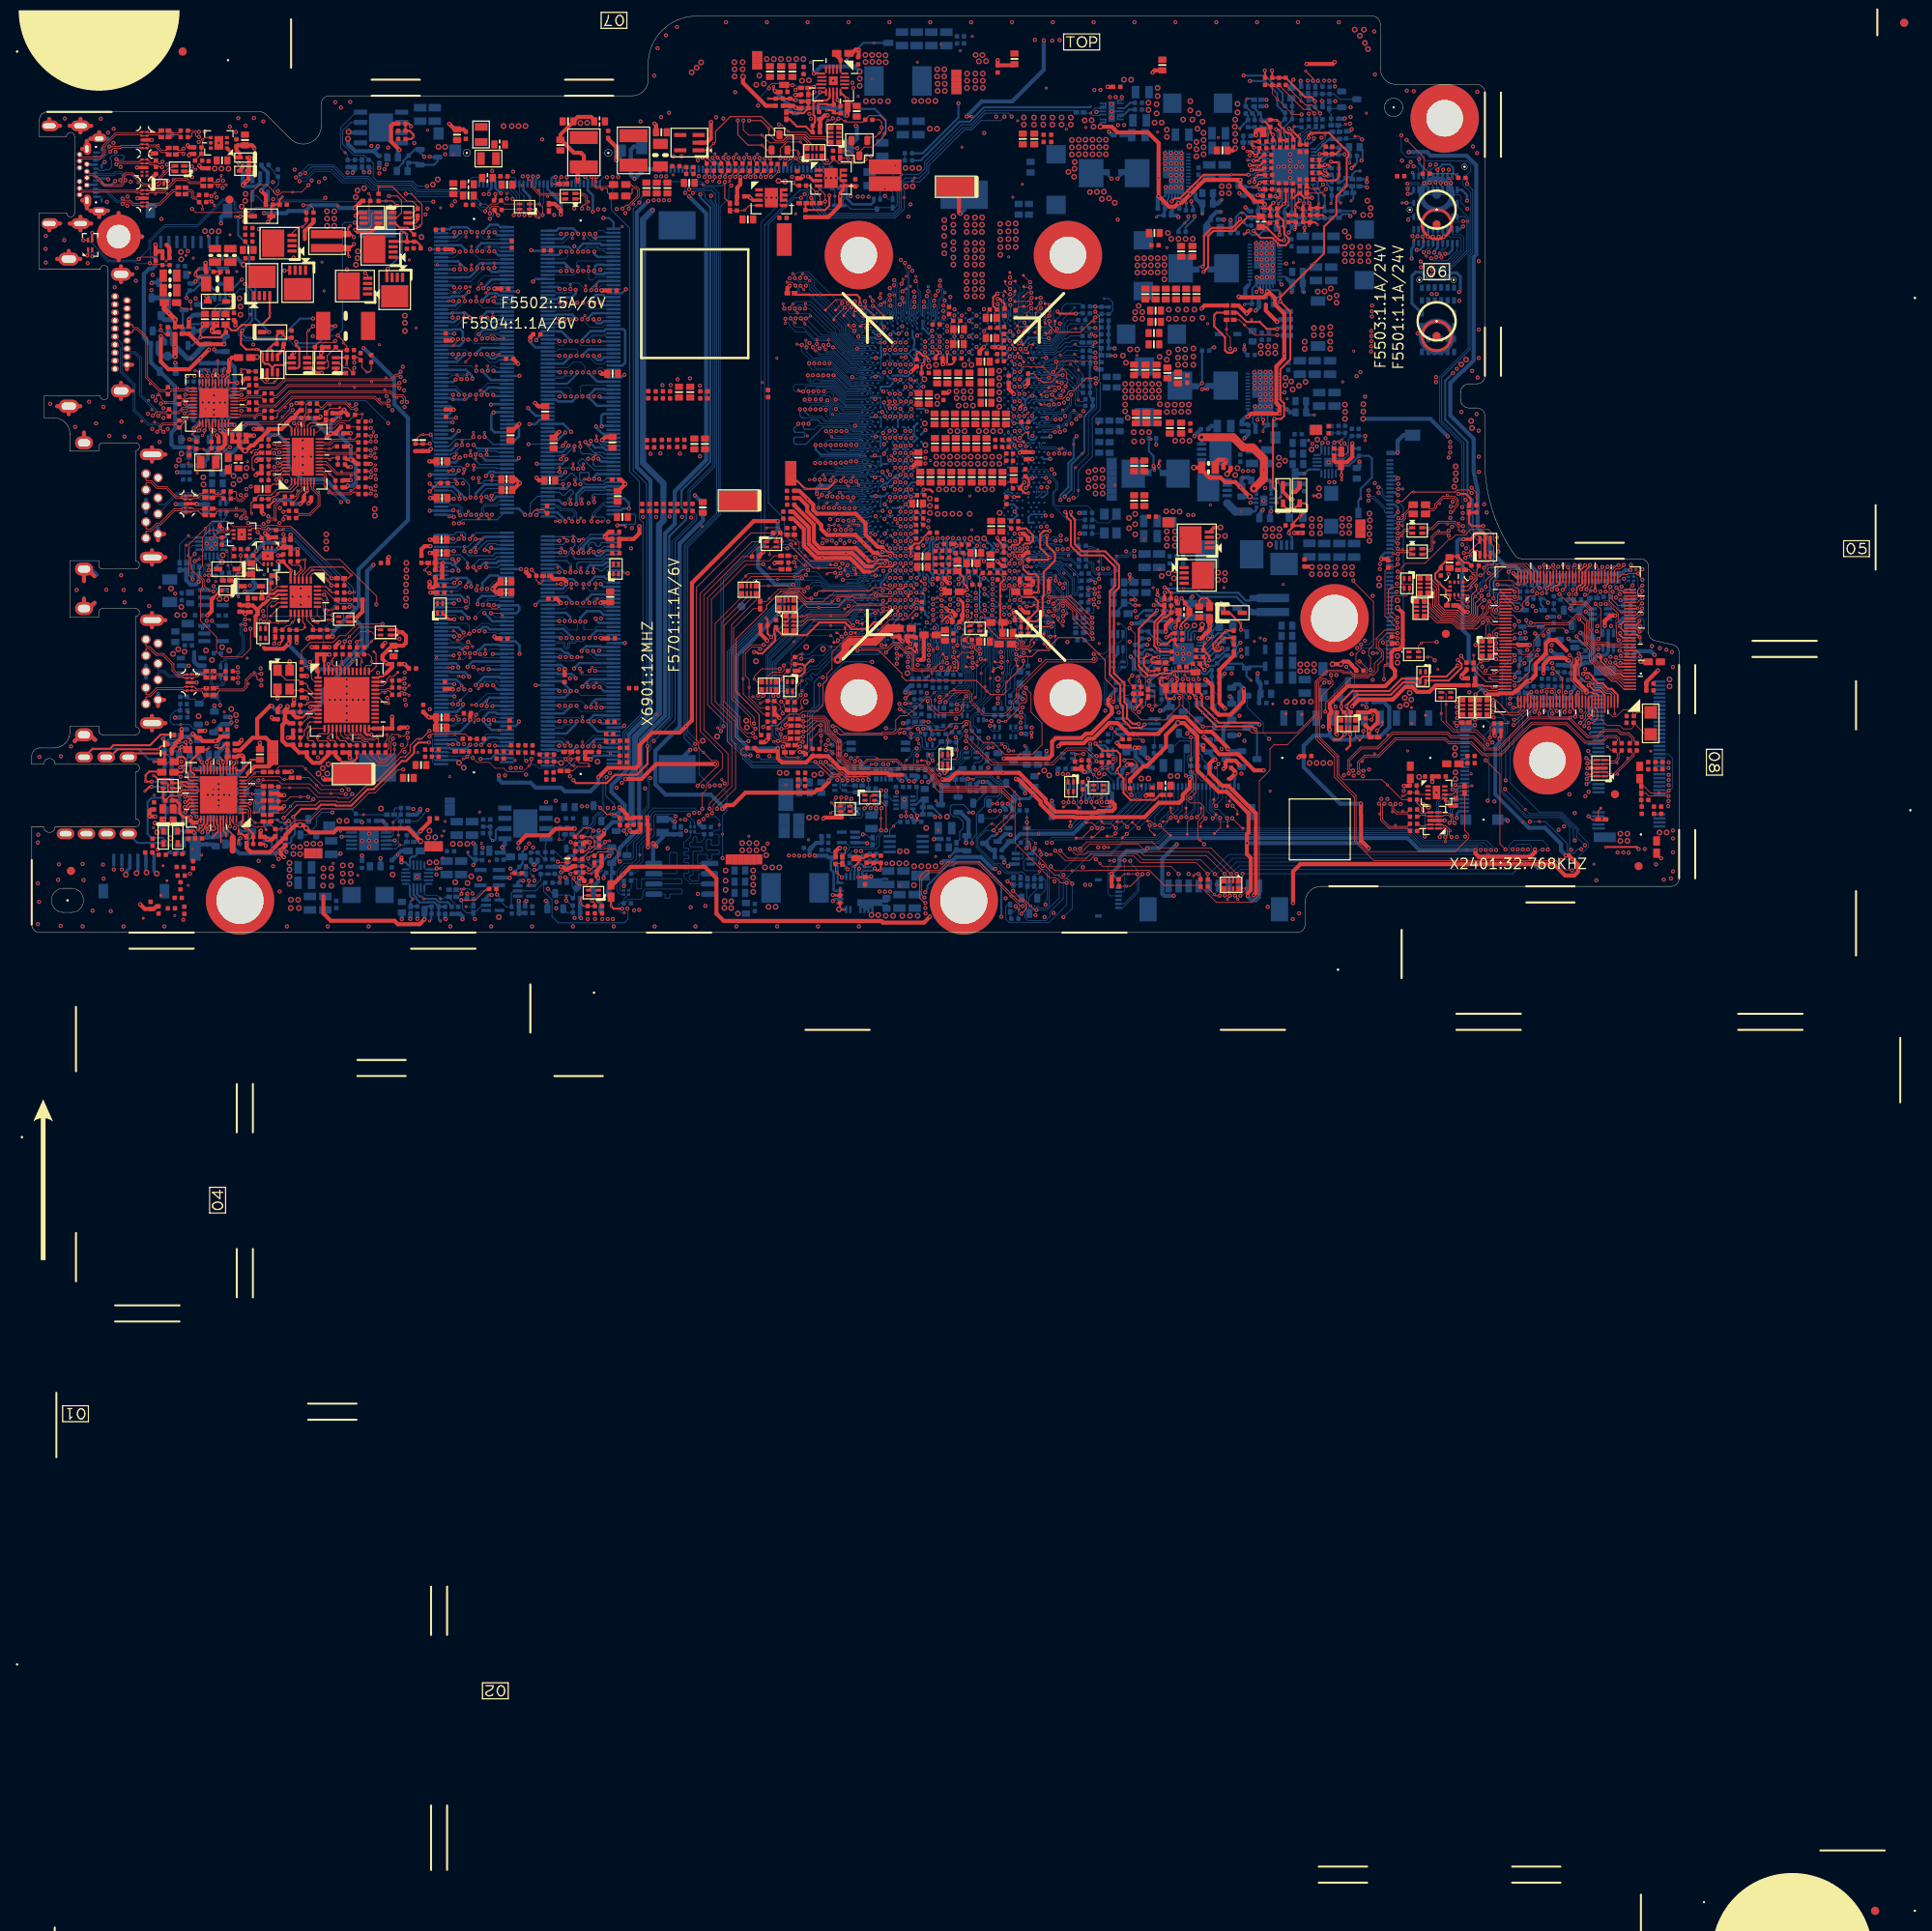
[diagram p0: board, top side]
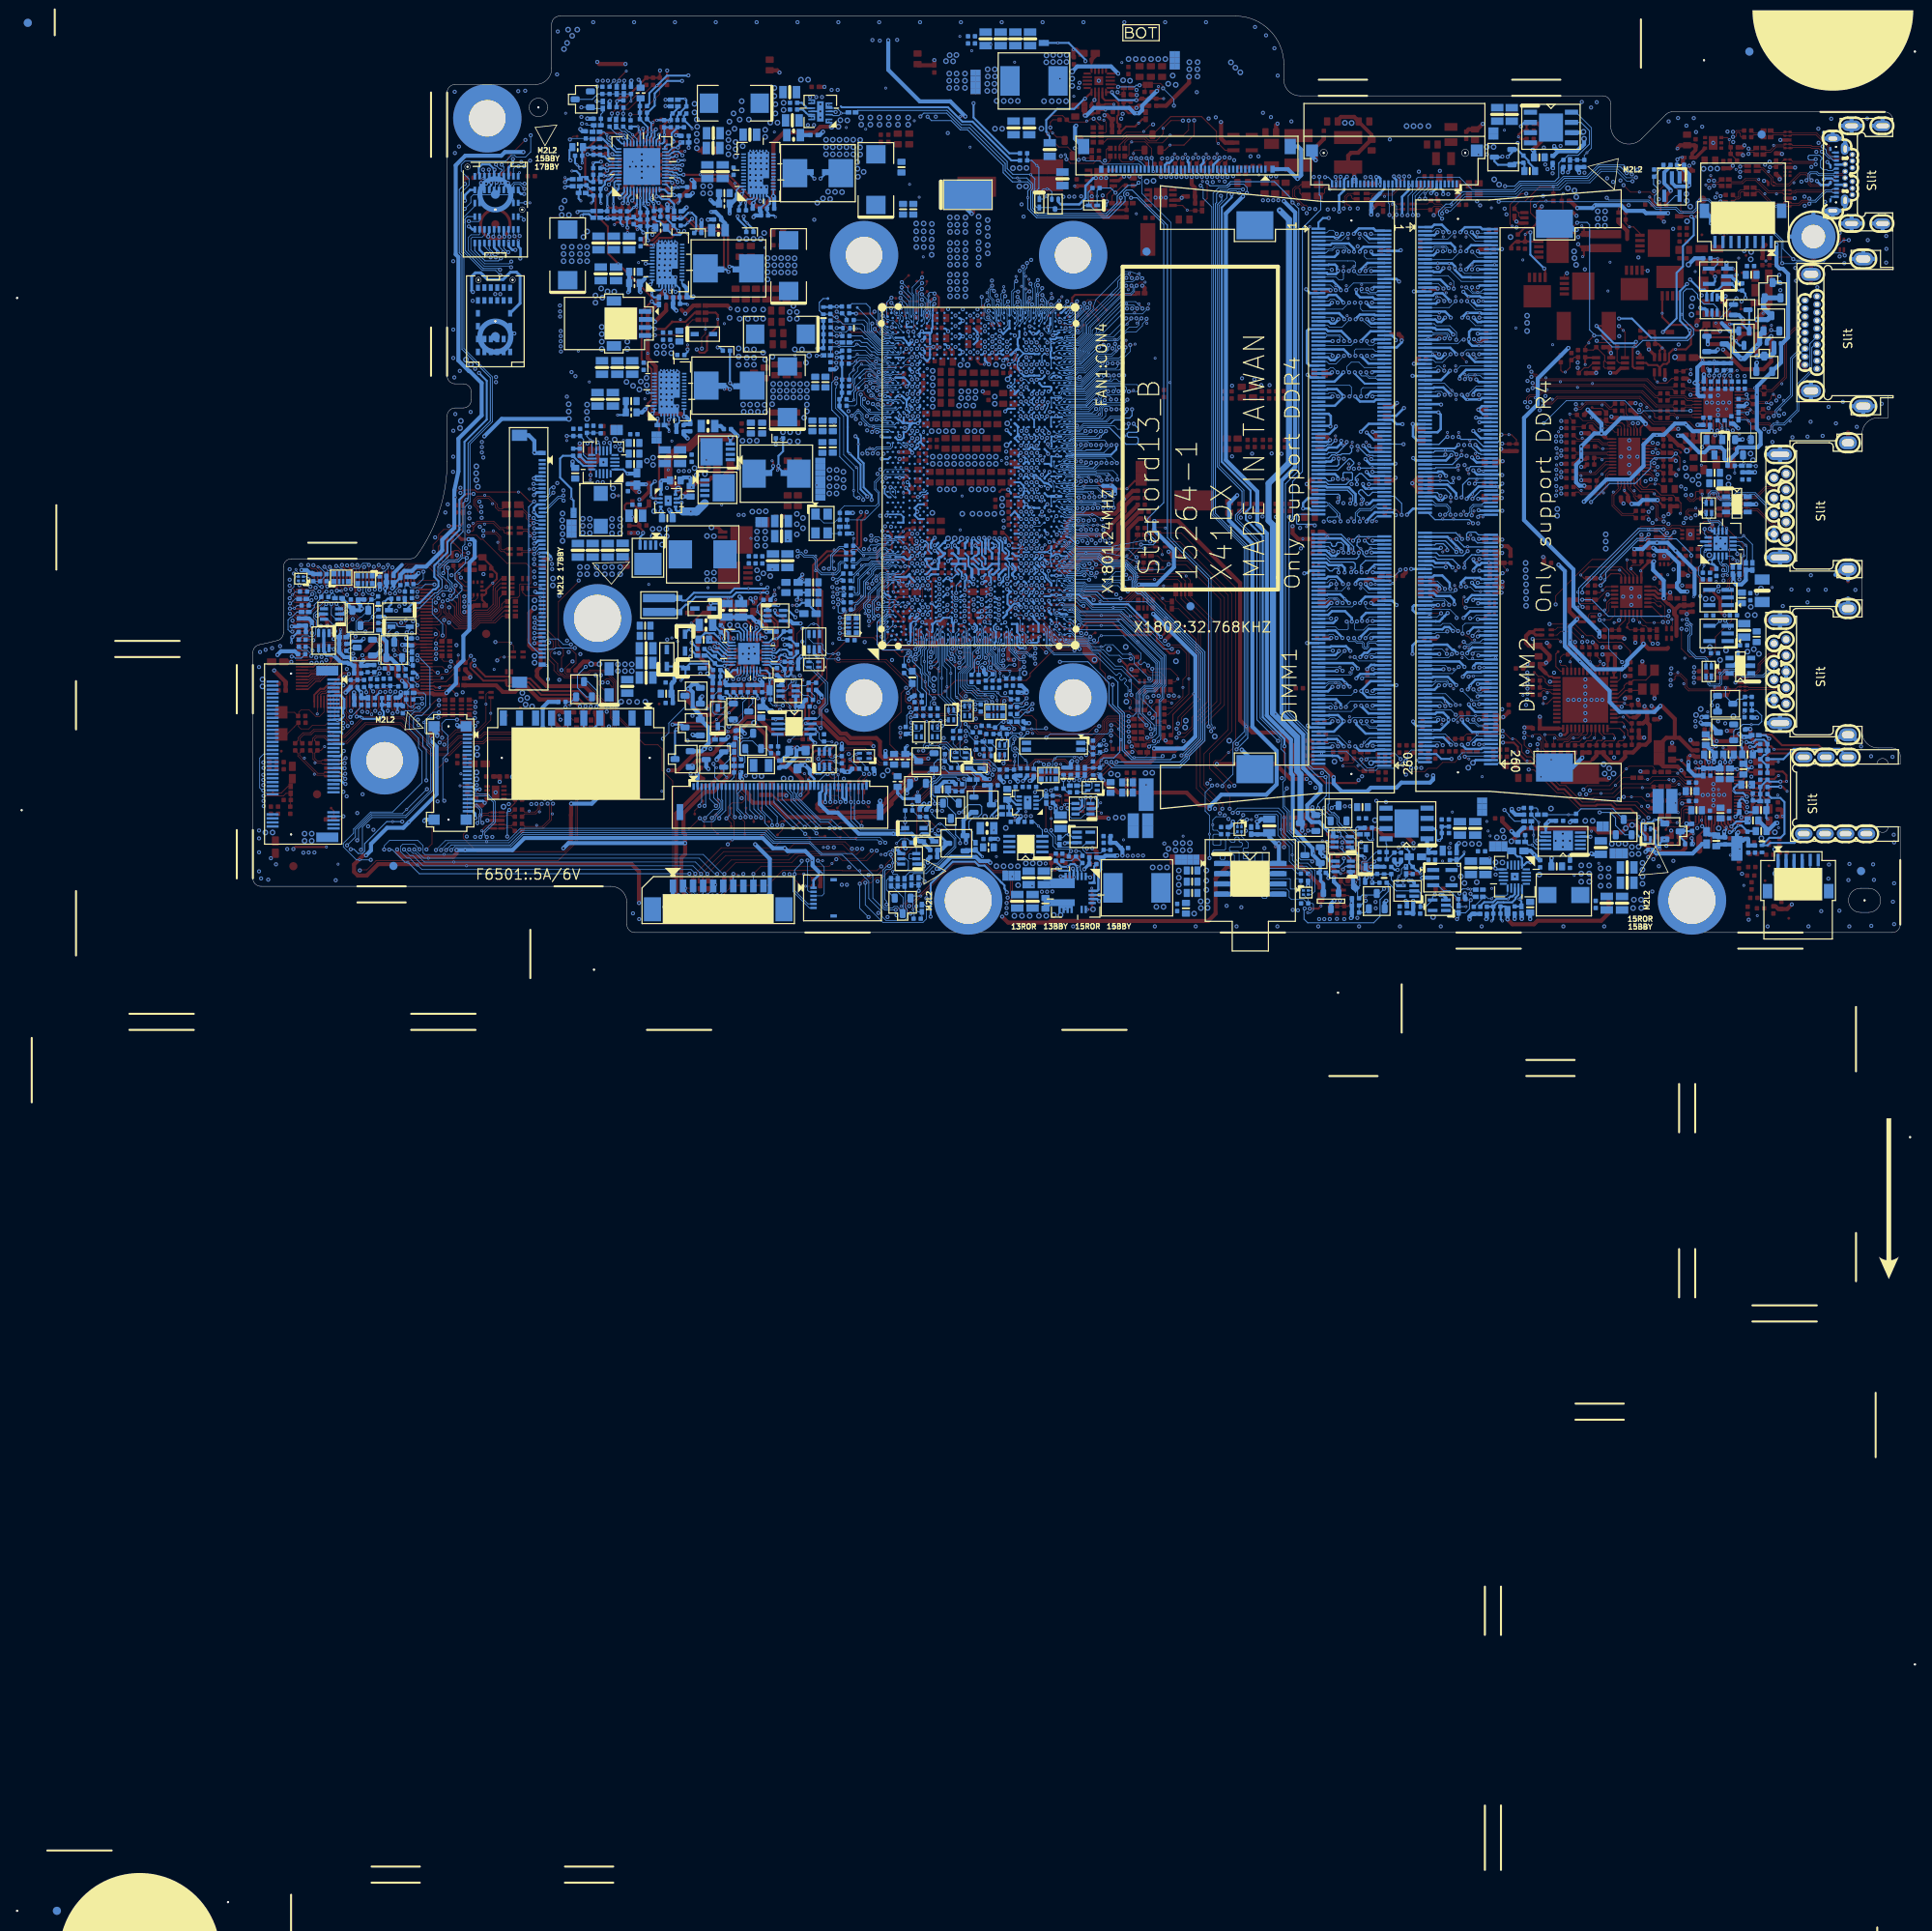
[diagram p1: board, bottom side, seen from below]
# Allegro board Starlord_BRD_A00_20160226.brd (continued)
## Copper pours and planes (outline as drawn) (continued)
GND on BOTTOM: 114.89,38.15 114.89,38.16 114.89,38.9 114.93,38.94 114.93,39.95 114.69,40.19 114.52,40.19 114.52,40.6 114.96,41.04 114.96,41.36 114.93,41.39 114.93,41.47 115.15,41.69 115.43,41.69 115.65,41.46 115.72,41.46 115.91,41.28 115.91,40.78 115.86,40.73 115.62,40.73 115.57,40.68 115.57,39.66 116,39.23 116,38.92 115.3,38.22 115.3,38.15
GND on BOTTOM: 152.8,52.95 152.7,53.05 152.7,55.36 152.88,55.54 153.49,55.54 153.67,55.36 153.67,53.05 153.57,52.95
GND on BOTTOM: 39.67,22.32 45.49,22.32 45.74,22.06 45.74,18.51 45.57,18.33 39.98,18.33 39.24,19.07 39.24,21.89
GND on BOTTOM: 123.59,41.57 123.47,41.7 123.47,42.05 122.35,43.17 122.35,43.98 123.04,44.67 123.44,44.67 123.77,44.34 125.02,44.34 125.09,44.26 125.09,44.14 124.99,44.03 123.26,44.03 122.96,43.73 122.96,43.5 123.19,43.27 123.19,43.02 123.52,42.69 123.95,42.69 124.51,42.13 124.97,42.13 125.07,42.03 125.07,41.65 124.99,41.57
GND on BOTTOM: 156.36,85.94 156.28,86.02 156.28,86.5 156.36,86.58 156.77,86.58 157.4,87.21 158.29,87.21 159.05,87.98 163.24,87.98 164.13,88.87 164.39,88.87 164.64,89.12 164.64,91.1 165.28,91.74 167.71,91.74 167.82,91.63 167.82,86.45 167.44,86.07 157.15,86.07 157.02,85.94
GND on BOTTOM: 40.84,10.18 40.69,10.33 40.69,13.12 40.79,13.22 41.45,13.22 41.55,13.33 41.55,14.11 41.63,14.19 42.16,14.19 42.21,14.14 42.21,13.53 42.37,13.38 42.98,13.38 43.18,13.17 43.18,10.28 43.08,10.18
GND on BOTTOM: 100.1,23.56 100,23.66 98.8,23.66 98.68,23.79 98.68,24.32 98.83,24.48 100.58,24.48 100.73,24.32 100.73,23.74 100.56,23.56 ; 1 cut-out
GND on BOTTOM: 96.32,16.86 96.06,17.11 96.06,19.85 96.49,20.29 98.65,20.29 98.73,20.21 98.73,18.25 98.6,18.13 97.59,18.13 97.33,17.87 97.33,16.98 97.2,16.86 ; 5 cut-outs
GND on BOTTOM: 104.54,48.81 104.16,49.19 104.16,49.29 104.29,49.42 104.44,49.42 104.7,49.17 105.13,49.17 105.41,49.45 105.41,51.81 105.54,51.93 105.66,51.93 105.76,51.83 105.76,51.27 106.32,50.72 106.63,50.72 107.08,50.26 108.71,50.26 109.27,50.82 109.27,51.1 109.09,51.27 109.09,51.53 109.75,52.19 109.75,52.42 109.78,52.44 110.46,52.44 110.84,52.06 110.84,51.83 110.26,51.25 110.26,50.28 109.9,49.93 109.88,49.93 109.8,49.85 106.88,49.85 106.6,50.13 106.6,50.16 106.53,50.23 106.25,50.23 105.76,49.75 105.76,49.11 105.46,48.81
GND on BOTTOM: 32.94,22.32 29.39,25.87 29.39,26.76 26.97,29.18 25.07,29.18 24.81,29.43 24.81,33.49 25.32,34 25.7,34 27.23,35.53 31.55,35.53 33.7,33.37 33.7,33.11 34.47,32.35 36.5,32.35 36.75,32.1 36.75,31.59 35.99,30.83 35.99,29.05 34.85,27.91 30.66,27.91 30.02,28.54 29.64,28.54 29.39,28.29 29.39,28.03 30.4,27.02 34.97,27.02 36.55,28.59 36.55,29.86 40.44,33.75 41.07,33.75 41.96,32.86 41.96,28.67 39.29,26 37.51,26 34.97,23.46 34.97,22.83 34.47,22.32 ; 1 cut-out
GND on BOTTOM: 133.27,68.67 133.15,68.8 133.15,69.31 133.65,69.82 133.65,70.7 134.29,71.34 134.29,71.72 134.54,71.97 136.07,71.97 136.45,71.59 139.24,71.59 139.88,72.23 139.88,77.56 140.38,78.07 144.32,78.07 146.86,75.53 147.75,75.53 148.13,75.15 148.13,73.75 147.62,73.24 145.59,73.24 145.08,72.74 145.08,70.45 144.7,70.07 140.64,70.07 139.62,69.05 135.81,69.05 135.43,68.67 ; 2 cut-outs
GND on BOTTOM: 123.11,48.15 123.01,48.25 123.01,48.56 122.65,48.91 120.88,48.91 120.75,49.04 120.75,49.17 120.88,49.29 121.77,49.29 121.97,49.5 121.97,49.7 122.48,50.21 122.65,50.21 123.32,49.55 123.95,49.55 124.05,49.45 124.05,49.22 123.48,48.65 123.48,48.31 123.32,48.15
GND on BOTTOM: 117.65,107.92 116.89,108.68 116.89,109.26 117.19,109.57 117.19,110.84 116.94,111.09 107.36,111.09 106.98,111.47 106.98,112.49 107.11,112.61 118.67,112.61 119.3,111.98 119.3,108.3 118.92,107.92 ; 3 cut-outs
GND on BOTTOM: outline of 119 points within 1.45,82.94 57.94,103.5
GND on BOTTOM: 136.45,48.48 136.07,48.86 136.07,52.29 136.19,52.42 138.48,52.42 138.86,52.04 138.86,48.68 138.66,48.48
GND on BOTTOM: 51.1,5.78 50.06,6.82 48.59,6.82 48.44,6.67 48.44,6.47 48.41,6.44 47.45,6.44 47.42,6.47 47.42,6.6 47.19,6.82 45.95,6.82 45.92,6.85 45.92,7.05 45.95,7.08 47.29,7.08 47.39,7.18 47.39,7.41 47.45,7.46 48.54,7.46 48.61,7.54 50.42,7.54 50.82,7.94 54.23,7.94 54.94,7.23 54.94,6.39 54.33,5.78
GND on BOTTOM: 1,0.51 0.65,0.65 0.51,1 0.51,12.63 0.97,12.63 1.7,11.9 2.18,11.9 4.42,9.67 10.49,9.67 10.59,9.57 10.59,6.95 11.48,6.06 16.43,6.06 16.69,6.32 16.69,10.02 16.91,10.25 19.23,10.25 19.48,10.51 21.13,10.51 21.64,10 24.69,10 25.7,8.98 27.23,8.98 27.74,8.47 28.37,8.47 31.04,5.81 31.04,1.87 31.89,1.02 73.87,1.02 74.47,1.62 74.47,3.14 74.34,3.27 74.22,3.27 74.22,4.03 80.36,4.03 81.51,5.17 85.29,5.17 85.34,5.12 85.34,1.67 85.99,1.02 112.44,1.02 112.69,0.75 112.96,0.51 85.52,0.51 85.52,0.51 73.84,0.51 73.84,0.51 31.93,0.51 31.93,0.51 ; 4 cut-outs
GND on BOTTOM: 177.98,11.65 177.6,12.03 177.6,14.7 183.69,14.7 184.71,13.68 184.71,12.79 184.33,12.41 180.9,12.41 180.14,11.65
GND on BOTTOM: 161.24,55.74 161.11,55.87 161.11,56.4 161.14,56.43 161.14,57.88 161.11,57.9 160.73,57.9 160.7,57.93 160.7,61.03 160.68,61.05 160.68,61.61 160.83,61.76 160.98,61.76 161.28,61.47 161.28,61.19 161.39,61.08 161.39,59.17 161.54,59.02 161.75,59.02 161.8,58.97 161.8,57.93 161.75,57.88 161.54,57.88 161.39,57.73 161.39,56.3 161.47,56.23 162.18,56.23 162.3,56.1 162.3,55.87 162.18,55.74
GND on BOTTOM: outline of 221 points within 73.11,0.51 204.34,113.41 ; 1 cut-out
GND on BOTTOM: 148,54.7 147.88,54.83 147.88,57.37 148.13,57.62 149.15,57.62 149.78,58.26 149.78,58.64 150.04,58.89 154.35,58.89 154.48,58.77 154.48,57.93 154.81,57.6 155.34,57.6 155.73,57.98 155.93,57.98 156.39,58.44 156.39,62.07 156.64,62.32 157.28,62.32 157.4,62.2 157.4,57.75 157.28,57.62 156.51,57.62 156.34,57.45 156.34,57.04 155.83,56.53 154.56,56.53 154.1,56.99 150.54,56.99 149.78,56.23 149.78,54.83 149.66,54.7 ; 6 cut-outs
GND on BOTTOM: 108.05,15.31 108.02,15.33 108.02,17.67 108.13,17.77 108.13,18.36 108.2,18.43 109.42,18.43 109.57,18.28 109.57,17.44 109.85,17.16 109.85,16.86 109.8,16.81 109.04,16.81 108.99,16.76 108.99,15.33 108.96,15.31 ; 1 cut-out
GND on BOTTOM: 156.36,30.83 156.28,30.9 156.28,38.55 157.81,40.07 157.81,41.19 159.97,43.35 163.96,43.35 166.34,40.96 166.34,37.35 163.75,34.76 163.75,33.9 160.68,30.83 ; 3 cut-outs
GND on BOTTOM: 121.82,41.65 121.41,42.05 119.99,42.05 119.78,42.26 119.78,42.49 119.94,42.64 120.09,42.64 120.19,42.74 120.19,43.73 120.27,43.81 120.62,43.81 121.13,43.3 121.13,43.04 120.93,42.84 120.93,42.64 121.08,42.49 121.84,42.49 122.1,42.23 122.1,41.77 121.97,41.65
GND on BOTTOM: 105.03,95.98 104.98,96.03 104.98,96.97 105.21,97.2 106.5,97.2 106.83,97.53 106.83,99 106.46,99.37 106.46,100.23 106.58,100.35 107.03,100.35 107.34,100.04 111.17,100.04 111.43,100.3 112.83,100.3 112.95,100.17 112.95,99.79 110.54,97.37 108.35,97.37 106.96,95.98
GND on BOTTOM: 41.32,90.52 47.93,90.52 48.44,90.01 48.44,88.36 48.18,88.1 46.15,88.1 45.52,87.47 45.52,85.94 45.26,85.69 40.56,85.69 40.44,85.82 40.44,86.58 39.93,87.09 39.93,87.72 40.05,87.85 40.44,87.85 40.56,87.98 40.56,88.48 40.44,88.61 40.05,88.61 39.93,88.74 39.93,89.12
GND on BOTTOM: 140.79,92.17 140.77,92.19 140.77,94.12 140.64,94.25 140.64,99.66 140.13,100.17 138.23,100.17 137.97,100.42 137.97,101.82 137.72,102.07 137.72,103.29 138.23,103.8 138.23,106.01 138.48,106.26 140.13,106.26 140.38,106.01 140.38,101.57 140.89,101.06 141.78,101.06 142.8,100.04 142.8,98.01 143.31,97.5 143.31,92.29 143.18,92.17 ; 3 cut-outs
GND on BOTTOM: 124.33,38.52 122.65,40.2 122.48,40.2 122.1,39.82 121.74,39.82 121.69,39.87 121.69,40.1 121.92,40.33 121.92,40.58 122.38,41.04 122.58,41.04 124.76,38.85 124.76,38.65 124.64,38.52
GND on BOTTOM: 52.14,9.69 51.99,9.85 51.99,12.79 52.12,12.92 55.55,12.92 55.8,12.67 56.31,12.67 56.44,12.54 56.44,11.78 56.26,11.6 54.76,11.6 54.58,11.42 54.58,10.43 54.51,10.35 54.13,10.35 53.92,10.15 53.92,9.82 53.8,9.69 ; 2 cut-outs
GND on BOTTOM: 169.47,25.62 169.21,25.87 169.21,31.08 169.85,31.72 172.36,31.72 172.64,31.44 172.64,30.32 172.9,30.06 173.53,30.06 174.17,29.43 174.17,26 173.79,25.62
GND on BOTTOM: 111.07,47.54 110.39,48.23 109.98,48.23 109.8,48.05 109.57,48.05 109.52,48.1 109.52,48.3 109.95,48.73 109.95,49.17 110.08,49.29 110.64,49.29 110.79,49.14 110.79,48.53 111.38,47.95 111.38,47.72 111.2,47.54
GND on BOTTOM: 99.44,17.31 99.01,17.75 99.01,18.23 99.9,19.12 99.9,19.32 100.02,19.45 100.02,19.8 100.1,19.88 100.61,19.88 100.71,19.78 100.71,19.3 100.51,19.09 100.51,18.81 100.35,18.66 100.35,17.52 100.15,17.31
GND on BOTTOM: 133.07,40.33 132.43,40.96 132.43,41.8 132.64,42 132.64,42.74 132.54,42.84 132.54,43.07 132.66,43.2 132.97,43.2 133.81,44.03 135.08,44.03 135.15,43.96 135.15,40.53 134.95,40.33 ; 4 cut-outs
GND on BOTTOM: 193.98,11.01 192.58,12.41 192.58,13.55 190.8,15.33 188.26,15.33 184.2,19.4 184.2,22.57 184.58,22.95 184.58,23.97 186.87,26.25 191.82,26.25 192.45,25.62 193.75,25.62 193.85,25.52 193.85,17.67 193.93,17.59 195.6,17.59 195.63,17.57 195.63,12.79 195.76,12.67 198.68,12.67 198.93,12.41 198.93,11.27 198.68,11.01
GND on BOTTOM: 113.33,72.38 113.21,72.51 113.21,75.76 113.31,75.86 113.79,75.86 113.97,75.68 113.97,72.66 113.69,72.38
GND on BOTTOM: 102.41,1.24 102.13,1.52 102.13,3.32 104.24,3.32 104.32,3.39 105.33,3.39 105.46,3.52 110.67,3.52 111.05,3.14 111.05,1.36 110.92,1.24 ; 2 cut-outs
GND on BOTTOM: 150.67,13.43 149.91,14.19 149.91,20.03 149.78,20.16 149.78,21.17 150.04,21.43 151.18,21.43 151.69,20.92 153.08,20.92 153.34,21.17 153.34,23.33 154.74,24.73 157.4,24.73 157.78,24.35 157.78,20.16 158.04,19.9 162.23,19.9 163.12,20.79 170.61,20.79 172.9,23.08 175.69,23.08 176.35,23.74 178.76,23.74 178.84,23.66 178.84,22.01 178.74,21.91 177.34,21.91 177.34,21.81 175.82,21.81 175.31,21.3 175.31,19.78 176.58,18.51 176.58,18.25 176.96,17.87 176.96,17.75 176.83,17.62 175.56,17.62 174.93,16.98 174.42,16.98 173.79,17.62 173.79,19.65 173.53,19.9 172.01,19.9 171.75,19.65 171.75,16.6 172.01,16.35 172.01,15.08 170.36,13.43
GND on BOTTOM: 113.71,21.63 113.59,21.76 113.59,22.9 113.89,23.21 115.06,23.21 115.19,23.08 115.19,22.24 114.58,21.63 ; 2 cut-outs
GND on BOTTOM: 152.2,80.99 152.07,81.12 152.07,86.33 152.2,86.45 154.48,86.45 154.61,86.33 154.61,81.12 154.48,80.99
GND on BOTTOM: 148.13,96.61 147.88,96.87 147.88,100.68 146.1,102.45 146.1,104.87 146.86,105.63 150.04,105.63 150.54,105.12 150.54,100.04 150.16,99.66 150.16,97.37 149.4,96.61
GND on BOTTOM: 148,91.53 147.24,92.29 147.24,92.55 146.1,92.55 144.45,94.2 143.56,94.2 143.43,94.33 143.43,94.45 143.56,94.58 149.02,94.58 149.27,94.33 149.27,91.79 149.02,91.53 ; 1 cut-out
GND on BOTTOM: 132.36,60.42 132,60.77 132,62.48 132.21,62.68 136.47,62.68 136.57,62.58 143.94,62.58 144.14,62.37 144.14,61.51 144.32,61.33 144.32,60.93 144.07,60.67 140.89,60.67 140.64,60.93 140.64,61.56 140.38,61.81 138.73,61.81 138.48,61.56 138.48,60.67 138.23,60.42 ; 9 cut-outs
GND on BOTTOM: 155.01,50.99 154.56,51.45 154.56,52.37 155.62,53.43 157.02,53.43 157.15,53.31 157.15,51.27 156.87,50.99 ; 1 cut-out
GND on BOTTOM: 95.15,93.77 94.82,94.1 94.82,95.24 94.89,95.32 99.49,95.32 99.67,95.5 103.63,95.5 104.11,95.98 104.11,96.59 104.27,96.74 104.75,96.74 104.82,96.66 104.82,95.72 105.21,95.34 105.21,94.07 105.08,93.95 100.89,93.95 100.57,94.26 97.14,94.26 96.98,94.43 96.49,94.43 95.83,93.77
GND on BOTTOM: 100.3,21.02 100.13,21.2 100.13,21.45 100.28,21.61 100.61,21.61 100.96,21.96 100.96,22.17 101.12,22.32 101.34,22.32 101.52,22.14 101.52,21.68 100.86,21.02
GND on BOTTOM: 32.31,1.24 31.55,2 31.55,8.98 31.67,9.11 33.32,9.11 33.58,8.86 33.58,3.65 33.83,3.39 38.15,3.39 38.28,3.27 38.28,1.62 37.9,1.24 ; 1 cut-out
GND on BOTTOM: outline of 119 points within 0.51,21.45 23.54,69.05 ; 5 cut-outs
GND on BOTTOM: 123.01,53.86 121.99,54.88 121.36,54.88 121.28,54.96 121.28,55.19 121.36,55.26 122.15,55.26 122.43,55.54 122.43,56.38 122.12,56.68 121.38,56.68 121.26,56.81 121.26,56.99 121.33,57.07 121.99,57.07 122.43,57.5 122.43,58.11 122.02,58.51 121.36,58.51 121.28,58.59 121.28,58.82 121.33,58.87 122.02,58.87 122.48,59.33 122.58,59.33 122.91,59 123.47,59 124.26,59.78 127.23,59.78 127.38,59.63 127.38,58.69 126.62,57.93 123.44,57.93 122.86,57.34 122.86,54.63 123.06,54.42 123.98,54.42 124.13,54.58 125.04,54.58 125.22,54.4 125.22,54.09 124.99,53.86
GND on BOTTOM: 76.88,58.64 76.63,58.89 76.63,87.85 77.77,88.99 77.77,89.75 77.01,90.52 77.01,91.91 77.14,92.04 80.19,92.04 83.49,88.74 83.49,58.77 83.36,58.64
GND on BOTTOM: 158.29,44.16 157.78,44.67 157.78,47.21 157.91,47.34 165.28,47.34 165.53,47.08 165.53,46.19 165.28,45.94 162.86,45.94 162.61,45.69 162.61,44.42 162.36,44.16
GND on BOTTOM: 121.46,83.53 121.45,83.54 120.97,83.54 120.32,84.19 120.32,88.48 121.59,89.75 124.38,89.75 124.64,89.5 124.64,85.06 123.11,83.53 ; 2 cut-outs
GND on BOTTOM: 31.16,39.84 30.15,40.86 30.15,43.02 31.16,44.03 31.16,46.07 31.42,46.32 34.59,46.32 36.37,44.54 36.37,43.4 37.39,42.38 37.39,41.37 35.86,39.84
GND on BOTTOM: 86.54,1.24 85.65,2.12 85.65,7.84 86.16,8.35 87.68,8.35 87.81,8.22 87.81,3.39 88.19,3.01 90.35,3.01 90.73,2.63 90.73,1.49 90.47,1.24 ; 11 cut-outs
GND on BOTTOM: 110.67,17.49 110.44,17.72 110.44,18.89 110.62,19.07 110.62,19.5 110.77,19.65 111.33,19.65 111.45,19.52 111.45,19.22 111.2,18.97 111.2,18.46 111.3,18.36 111.83,18.36 112.09,18.61 112.55,18.61 112.6,18.56 112.6,17.67 112.42,17.49 ; 1 cut-out
GND on BOTTOM: 105.71,7.08 105.33,7.46 105.33,7.99 105.97,8.63 105.97,8.98 105.59,9.36 104.04,9.36 103.86,9.54 103.86,10 103.94,10.08 105.71,10.08 105.87,10.23 107.39,10.23 107.44,10.18 107.44,9.72 107.67,9.49 108.74,9.49 109.22,9.01 109.22,7.28 109.02,7.08
GND on BOTTOM: 172.39,78.07 172.01,78.45 172.01,80.1 172.52,80.61 177.04,80.61 177.14,80.51 177.14,78.17 177.04,78.07
GND on BOTTOM: 140.1,43.83 139.39,44.54 137.72,44.54 137.46,44.8 137.46,45.81 137.59,45.94 140.89,45.94 141.15,46.19 143.38,46.19 143.56,46.02 143.56,44.9 143.31,44.64 141.86,44.64 141.04,43.83 ; 3 cut-outs
GND on BOTTOM: 151.94,64.86 151.81,64.99 151.81,65.9 151.92,66.01 152.35,66.01 152.5,66.16 152.5,66.77 152.4,66.87 151.79,66.87 151.69,66.97 151.69,72.23 151.18,72.74 151.18,73.75 151.43,74.01 154.48,74.01 154.74,73.75 157.15,73.75 158.67,75.28 158.67,81.37 158.93,81.63 162.61,81.63 162.99,81.25 162.99,71.09 162.48,70.58 154.53,70.58 154.35,70.4 154.35,64.99 154.23,64.86 ; 7 cut-outs
GND on BOTTOM: outline of 83 points within 18.85,45.81 46.4,73.36 ; 14 cut-outs
GND on BOTTOM: 21.79,43.5 21.69,43.6 21.69,43.91 21.79,44.01 22.38,44.01 22.55,44.19 22.55,44.59 22.6,44.64 23.19,44.64 23.34,44.8 23.34,45 23.37,45.03 23.93,45.03 23.95,45 23.95,43.68 23.93,43.65 23.37,43.65 23.24,43.78 22.96,43.78 22.68,43.5 ; 1 cut-out
GND on BOTTOM: 123.72,95.39 123.37,95.75 123.37,98.9 122.48,99.79 122.48,101.82 122.6,101.95 129.08,101.95 129.72,101.31 129.72,100.02 128.67,98.98 128.67,95.7 128.37,95.39 ; 2 cut-outs
GND on BOTTOM: 34.09,34.38 31.93,36.54 27.35,36.54 26.97,36.92 26.97,39.21 26.85,39.34 26.34,39.34 26.21,39.46 26.21,40.86 26.47,41.11 29.01,41.11 29.77,40.35 29.77,39.84 29.64,39.72 28.5,39.72 28.37,39.59 28.37,39.08 29.01,38.45 35.48,38.45 35.86,38.07 35.86,35.27 34.97,34.38
GND on BOTTOM: 168.5,32.94 168.32,33.11 168.32,34.26 168.45,34.38 169.47,34.38 169.92,34.84 170.36,34.84 170.64,34.56 170.64,34.13 170.15,33.65 170.15,32.99 170.1,32.94
GND on BOTTOM: 67.74,13.3 67.23,13.81 67.23,16.22 67.49,16.48 68.88,16.48 69.39,15.97 69.39,13.68 69.01,13.3 ; 4 cut-outs
GND on BOTTOM: 163.93,62.2 163.83,62.3 163.83,62.5 163.68,62.65 162.18,62.65 162.1,62.73 162.1,64.48 161.97,64.61 159.43,64.61 159.18,64.86 159.18,66.01 159.31,66.13 164.39,66.13 164.69,65.83 164.69,63.21 165.28,62.63 165.28,62.35 165.29,62.34 165.15,62.2 ; 4 cut-outs
GND on L2GND: outline of 194 points within 0.51,0.51 204.34,113.41
GND on L3: 200.4,37.51 200.12,37.79 199.87,37.79 199.69,37.96 199.69,38.19 199.88,38.38 200.3,38.38 200.54,38.14 200.54,37.27 200.86,36.35 201.67,35.81 202.8,35.53 203.95,35.28 204.23,35.11 204.34,34.8 204.34,12.54 204.21,12.41 204.01,12.41 203.88,12.54 203.88,12.67 203.5,13.05 202.23,13.05 201.73,12.54 201.73,10.63 200.84,9.74 196.77,9.74 196.77,12.16 201.47,16.86 201.47,33.39 200.4,34.47
GND on L3: 1,0.51 0.65,0.65 0.51,1 0.51,10.02 0.51,12.63 1.1,12.63 1.53,12.13 2.16,11.93 2.16,10.94 3.22,9.87 12.85,9.87 13.41,9.31 14.45,9.31 14.72,9.58 14.72,10.44 15.04,10.76 17.96,10.76 19.1,11.9 22.53,11.9 22.91,12.28 22.91,14.44 22.27,15.08 21.26,15.08 21.13,15.21 21.13,19.02 21.26,19.14 26.21,19.14 28.37,16.98 28.37,7.84 29.64,6.57 29.64,2.12 30.75,1.02 48.82,1.02 49.93,2.12 53.9,2.12 55.01,1.02 67.36,1.02 68.34,2 71.8,2 72.31,2.51 74.09,2.51 74.6,3.01 74.85,3.01 75.36,2.51 81.36,2.51 82.85,1.02 112.19,1.02 112.95,1.78 112.95,5.68 113.97,6.7 117.4,6.7 119.18,4.92 119.18,2.79 120.95,1.02 129.21,1.02 129.55,1.36 154.74,1.36 156.13,2.76 156.13,4.92 157.74,6.53 159.2,6.53 159.76,6.7 160.35,6.76 201.73,6.76 202.48,7.51 202.49,7.51 203.83,8.86 203.83,12.06 204.34,12.06 204.34,6.74 204.2,6.39 203.85,6.25 160.35,6.25 158.58,5.51 157.84,3.74 157.84,1 157.7,0.65 157.35,0.51
GND on L3: 35.02,67.48 37.18,67.48 37.64,67.02 37.64,63.08 36.88,62.32 36.88,61.81 37.51,61.18 37.51,54.45 37.13,54.07 37.13,51.78 37.64,51.27 37.64,45.69 35.23,43.27 35.23,40.22 34.34,39.34 29.01,39.34 28.5,39.84 28.5,41.11 28.88,41.49 28.88,44.39 29.06,44.57 31.32,44.57 32.56,45.81 32.56,48.18 33.58,49.19 33.58,54.42 34.19,55.03 34.19,56.07 35.76,57.65 35.76,61.38 34.47,62.68 34.47,66.92
GND on L3: outline of 214 points within 0.51,21.45 182.4,113.41
GND on L4: 1,0.51 0.65,0.65 0.51,1 0.51,10.23 0.51,12.63 1.1,12.63 1.52,12.14 2.13,11.93 2.13,10.84 3.1,9.87 12.8,9.87 13.38,9.29 14.53,9.29 14.76,9.52 14.76,10.61 15.04,10.89 18.21,10.89 19.23,11.9 22.15,11.9 22.53,12.28 22.53,13.05 22.78,13.3 22.78,14.57 22.4,14.95 21.39,14.95 21.13,15.21 21.13,19.02 21.26,19.14 26.21,19.14 28.37,16.98 28.37,7.84 29.92,6.29 29.92,2.02 30.93,1.02 103.3,1.02 103.46,0.85 112.06,0.85 112.83,1.62 112.83,5.17 114.73,7.08 117.14,7.08 123.2,1.02 154.9,1.02 157.35,3.47 157.35,4.01 158.31,5.97 160.35,6.76 201.98,6.76 203.83,8.61 203.83,12.06 204.34,12.06 204.34,6.74 204.2,6.39 203.85,6.25 160.35,6.25 158.58,5.51 157.84,3.74 157.84,1 157.7,0.65 157.35,0.51
GND on L4: 203.83,16.86 203.83,19.83 203.63,20.03 201.85,20.03 201.22,20.67 201.22,30.19 201.6,30.57 201.6,31.46 201.54,31.52 201.54,35.32 200.96,35.57 200.49,35.99 200.42,35.99 199.72,36.69 199.72,38.31 199.79,38.38 200.33,38.38 200.54,38.17 200.54,37.27 200.86,36.35 201.67,35.81 202.8,35.53 203.95,35.28 204.23,35.11 204.34,34.8 204.34,12.19 203.73,12.19 203.12,12.79 201.98,12.79 201.71,12.53 201.71,11 200.46,9.74 196.82,9.74 196.49,10.08 196.49,11.88 201.22,16.6 203.58,16.6
GND on L4: 41.2,31.97 41.96,31.21 41.96,26.38 41.27,25.7 37.39,25.7 36.78,26.31 36.78,31.72 37.03,31.97
GND on L4: 38.4,45.69 35.61,42.89 35.61,40.73 35.1,40.22 32.94,40.22 32.31,40.86 32.31,41.75 37.59,47.03 37.59,49.83 37.21,50.21 35.18,50.21 29.89,44.92 26.21,44.92 25.83,45.3 25.83,46.7 28.12,48.99 28.12,52.04 28.5,52.42 29.64,52.42 30.78,53.56 30.78,54.83 29.51,56.1 29.51,65.5 32.94,68.93 36.5,68.93 37.26,68.16 37.26,52.29 38.4,51.15
GND on L4: outline of 103 points within 1.45,48.84 182.42,113.41
GND on L4: 200.03,38.79 200.03,45.44 186.74,45.44 186.74,45.95 200.05,45.95 200.4,45.81 200.54,45.46 200.54,38.79
GND on L4: outline of 145 points within 0.51,21.45 24.6,91.66
GND on L4: 10.34,99.53 16.69,99.53 17.07,99.15 17.07,95.22 16.69,94.83 9.83,94.83 8.81,95.85 8.81,96.36 9.32,96.87 9.32,97.88 9.96,98.52 9.96,99.15
GND on L5VCC: outline of 205 points within 0.51,0.51 204.34,113.41 ; 5 cut-outs
GND on L6: 170.99,93.82 176.2,93.82 176.96,93.06 176.96,82.9 175.56,81.5 172.52,81.5 172.39,81.63 172.39,84.29 170.48,86.2 170.48,93.31
GND on L6: 33.58,67.91 33.58,70.32 36.29,73.04 38,73.04 38.24,72.8 38.24,71.68 37.9,71.34 37.9,70.07 38.91,69.05 38.91,64.86 40.44,63.34 40.44,55.72 43.1,53.05 43.1,51.02 41.07,48.99 40.31,48.99 39.67,49.62 39.67,50.89 32.31,58.26 32.31,62.2 33.58,63.47 33.58,64.74 32.69,65.62 32.69,66.26 33.2,66.77 33.58,66.77 33.83,67.02 33.83,67.66
GND on L6: outline of 414 points within 0.51,0.51 204.34,113.41 ; 2 cut-outs
GND on L7GND: outline of 239 points within 0.51,0.51 204.34,113.41 ; 1 cut-out
VCC3PD on TOP: 26.72,41.16 26.54,41.34 26.54,41.72 27,42.18 27,42.87 26.87,42.99 26.87,43.3 26.97,43.4 27.61,43.4 27.79,43.22 27.79,42.26 28.04,42 28.04,41.29 27.91,41.16
VCC_CORE on TOP: 109.27,54.83 109.12,54.98 109.12,55.46 108.96,55.62 108.96,57.7 109.4,58.13 110.41,58.13 110.92,58.64 110.92,59.78 111.05,59.91 111.56,59.91 111.94,60.29 111.94,60.57 112.01,60.65 121.69,60.65 121.77,60.57 121.77,60.16 121.69,60.09 120.88,60.09 120.57,59.78 120.57,59.15 120.83,58.89 123.24,58.89 123.75,59.4 123.75,64.23 124.89,65.37 127.56,65.37 128.58,66.39 129.08,66.39 130.48,67.79 132.74,67.79 134.77,69.82 140.38,69.82 140.64,69.56 141.53,69.56 142.29,68.8 144.19,68.8 144.45,68.55 144.45,63.08 144.32,62.96 140.89,62.96 140.77,63.08 140.77,63.72 140.51,63.97 136.57,63.97 136.04,63.44 136.04,58.87 135.56,58.39 130.86,58.39 127.56,55.08 125.14,55.08 123.62,56.61 121.46,56.61 121.21,56.86 113.49,56.86 113.47,56.88 113.46,56.86 109.9,56.86 109.73,56.68 109.73,55.06 109.5,54.83 ; 55 cut-outs
VCC_CORE on BOTTOM: 132.26,62.83 131.88,63.21 131.88,64.48 133.02,65.62 133.02,68.04 133.4,68.42 135.56,68.42 135.81,68.67 139.37,68.67 140.64,69.94 143.81,69.94 144.19,69.56 144.19,63.08 143.94,62.83 ; 14 cut-outs
VCC_CORE on BOTTOM: 121.66,53.41 121.1,53.97 120.34,53.97 120.13,54.18 120.13,54.19 120.01,54.31 120.01,61.04 120.39,61.41 120.89,61.41 121.28,61.03 121.28,60.65 121.53,60.4 122.04,60.4 122.29,60.14 122.29,59.29 122.05,59.05 121.33,59.05 121.16,58.87 121.16,58.54 121.28,58.41 121.91,58.41 122.29,58.03 122.29,57.54 121.94,57.19 121.31,57.19 121.16,57.04 121.16,56.76 121.33,56.58 121.99,56.58 122.29,56.28 122.29,55.69 122.27,55.69 121.94,55.36 121.28,55.36 121.16,55.24 121.16,54.6 122.1,53.66 122.1,53.51 121.99,53.41
VCC_CORE on BOTTOM: 110,54.38 110,54.38 109.6,54.38 109.17,54.81 109.17,55.24 109.67,55.74 109.67,56.18 109.13,56.71 109.13,57.02 109.69,57.57 109.69,57.99 109.13,58.54 109.13,58.77 109.31,58.95 110.1,58.95 110.48,59.33 110.97,59.33 111.33,58.97 111.33,55.01 111.17,54.85 110.52,54.85 110.05,54.38
VCC_CORE on L3: 110.82,57.24 110.82,59.02 110.95,59.15 111.2,59.15 113.36,61.31 120.47,61.31 120.84,60.94 120.83,60.93 120.83,57.37 120.32,56.87 112.45,56.87 112.44,56.86 111.2,56.86
VCC_CORE on L3: 136.37,69.18 143.33,69.18 144.86,67.66 144.86,63.85 144.08,63.07 144.07,63.08 136.45,63.08 135.58,63.95 135.58,68.39
VCC_CORE on L5VCC: 113.82,52.94 113.52,53.23 113.52,53.26 113.41,53.37 113.39,53.37 111.18,55.58 110.98,57.28 111.01,58.68 110.96,59 111.01,59.32 111.16,59.95 111.61,59.95 114.02,62.36 125.63,62.36 127.01,63.74 127.01,65.01 131.37,69.37 143.35,69.37 144.28,68.44 144.28,63.9 143.56,63.17 137.05,63.17 129.13,55.25 128.09,55.25 125.78,52.94
VCC_CORE on L6: 109.52,59.27 111.17,59.27 113.97,62.07 122.6,62.07 123.11,62.58 126.29,62.58 127.05,61.81 127.05,58.64 126.54,58.13 126.54,55.46 126.29,55.21 125.73,55.21 124.18,56.76 122.88,56.76 121.84,55.72 111.94,55.72 110.79,54.58 109.4,54.58 109.14,54.83 109.14,58.89
VCC_EDRAM_FUSEPRG on TOP: 121.11,70.37 120.88,70.6 119.86,70.6 119.73,70.73 119.73,71.24 119.84,71.34 121.89,71.34 122.5,70.73 122.5,70.5 122.38,70.37 ; 1 cut-out
VCCPD_VBUS on TOP: 22.58,94.5 22.45,94.63 22.45,95.34 22.38,95.42 21.18,95.42 20.83,95.77 20.83,96.13 20.98,96.28 21.44,96.28 21.77,96.61 21.77,97.63 21.89,97.76 22.48,97.76 22.53,97.71 22.53,96.97 22.76,96.74 23.42,96.74 23.54,96.61 23.54,95.57 23.8,95.32 24.66,95.32 24.86,95.11 24.86,94.76 24.61,94.5 ; 2 cut-outs
VCCPD_VBUS on TOP: 39.8,71.47 39.67,71.59 39.67,76.67 40.94,77.94 40.94,82.57 40.87,82.64 40.13,82.64 39.85,82.92 39.85,84.47 40.94,85.56 40.94,86.43 41.22,86.71 43.97,86.71 44.12,86.55 44.12,83.02 43.36,82.26 43.36,71.97 42.85,71.47 ; 5 cut-outs
VCCPD_VBUS on BOTTOM: 31.27,91.02 30.97,91.32 30.97,92.65 31.01,92.69 31.01,94.38 30.86,94.53 30.4,94.53 30.35,94.58 30.35,95.29 29.72,95.93 28.62,95.93 27.81,96.74 26.03,96.74 24.97,95.67 24.97,94.43 24.61,94.07 22.27,94.07 21.89,94.45 21.89,97.12 22.48,97.71 23.8,97.71 24.31,98.21 29.21,98.21 32.28,95.14 32.28,94.4 32.46,94.23 32.46,93.54 32.87,93.13 34.29,93.13 35.61,94.45 37.06,94.45 38.54,92.97 41.36,92.97 41.55,92.78 41.55,91.33 41.25,91.02 ; 1 cut-out
VCCPD_VBUS on BOTTOM: 6.6,95.14 6.53,95.22 6.53,95.75 6.65,95.88 7.26,95.88 7.54,95.6 8.18,95.6 8.23,95.55 8.23,95.37 8.18,95.32 7.57,95.32 7.39,95.14
VCCPD_VBUS on BOTTOM: 6.6,92.29 6.48,92.42 6.48,93.18 6.55,93.26 7.24,93.26 7.39,93.11 8.2,93.11 8.23,93.08 8.23,92.83 8.2,92.8 7.54,92.8 7.44,92.7 7.44,92.45 7.29,92.29
VCCPD_VBUS on L3: 40.18,82.64 42.59,82.64 43.66,83.71 43.66,92.55 43.28,92.93 40.28,92.93 39.95,92.6 39.95,91 40.69,90.26 40.69,85.31 39.93,84.55 39.93,82.9
VCCPD_VBUS on L4: 9.92,88.65 9.7,88.87 9.7,91.15 9,91.85 7.22,91.85 6.4,92.68 6.4,95.44 6.96,96 8.3,96 9.66,94.64 13.96,94.64 15.04,93.56 16.18,93.56 17.35,94.73 17.35,97.93 18.39,98.98 19.58,98.98 21.18,97.37 24.05,97.37 24.43,97.76 29.89,97.76 32.18,95.47 32.18,93.82 33.32,92.68 35.99,92.68 36.5,93.18 41.37,93.18 41.65,92.9 41.65,91.69 40.99,91.02 32.05,91.02 30.76,92.32 30.76,94.58 30.12,95.22 28.88,95.22 27.99,96.1 25.45,96.1 25.02,95.67 25.02,94.73 24.53,94.25 22.6,94.25 22.29,93.93 22.29,92.94 19.73,90.39 17,90.39 15.26,88.65 ; 3 cut-outs
VDDD on TOP: 27.99,35.14 27.51,35.63 27.51,36.82 27.86,37.18 29.31,37.18 29.54,36.95 29.54,35.53 29.16,35.14
0D6V_PWR on BOTTOM: 36.5,10.89 36.42,10.96 36.42,12.16 36.17,12.41 36.17,12.97 36.24,13.05 40.18,13.05 40.56,12.67 40.56,11.4 40.44,11.27 38.66,11.27 38.28,10.89
0D6V_S0 on TOP: 38.02,13.43 37.87,13.58 37.87,15.03 37.97,15.13 40.05,15.13 42.11,17.19 42.95,17.19 44.3,18.53 46.99,18.53 47.09,18.63 47.09,19.68 47.19,19.78 48.13,19.78 48.56,20.21 48.56,22.04 48.69,22.17 50.77,22.17 51.13,21.81 53.01,21.81 53.2,21.62 53.66,21.62 54.35,20.92 56.56,20.92 57.2,20.29 57.88,20.29 58.46,19.71 61.33,19.71 63.04,21.43 66.47,21.43 66.72,21.17 66.72,21.05 66.22,20.54 64.57,20.54 64.31,20.29 64.31,18.76 64.18,18.63 63.8,18.63 63.17,18 56.18,18 55.93,17.75 50.47,17.75 49.45,16.73 44.73,16.73 43.79,15.79 42.7,15.79 40.33,13.43 ; 13 cut-outs
0D6V_S0 on BOTTOM: 36.27,13.3 36.22,13.35 36.22,14.44 36.29,14.52 39.37,14.52 39.52,14.37 39.52,13.45 39.37,13.3
0D6V_S0 on BOTTOM: 53.41,19.96 52.32,21.05 52.07,21.05 52.02,21.1 52.02,21.68 52.04,21.71 53.41,21.71 53.74,21.38 54.33,21.38 54.41,21.3 54.41,20.54 53.82,19.96
1D0V_PWR on TOP: 88.7,2.63 88.06,3.27 88.06,7.71 87.68,8.09 86.54,8.09 86.23,8.4 86.23,8.98 86.26,9.01 91.41,9.01 91.79,9.39 91.79,9.67 94.16,12.03 101.27,12.03 102.54,10.76 102.54,10 102.41,9.87 102.41,8.86 102.28,8.73 101.65,8.73 101.4,8.98 101.4,10.63 101.01,11.01 95.05,11.01 93.65,9.62 93.65,3.01 93.27,2.63
1D0V_PWR on BOTTOM: 91.24,2.76 90.73,3.27 88.31,3.27 88.06,3.52 88.06,8.22 87.81,8.47 86.79,8.47 86.78,8.49 86.45,8.49 86.38,8.55 86.38,8.93 86.43,8.98 93.14,8.98 93.65,8.47 93.65,3.27 93.14,2.76 ; 16 cut-outs
1D0V_S5 on TOP: 86.31,9.11 86.26,9.16 86.26,9.72 86.33,9.8 86.46,9.8 88.19,11.52 90.22,11.52 90.98,10.76 91.18,10.76 91.49,10.46 91.49,9.47 91.13,9.11
1D0V_S5 on TOP: 118.06,31.11 117.65,31.51 108.96,31.51 108.53,31.94 108.53,32.4 108.74,32.6 118.59,32.6 119.09,32.11 120.29,32.11 120.88,32.69 120.88,34.28 121.08,34.48 121.08,36.16 121.31,36.39 121.97,36.39 122.12,36.24 122.12,32.35 120.88,31.11
1D0V_S5 on TOP: 89.33,87.98 89.2,88.1 89.2,89.25 89.71,89.75 90.85,89.75 91.11,90.01 91.11,91.36 90.98,91.48 89.91,91.48 89.86,91.53 89.86,92.9 90.17,93.21 91.62,93.21 93.27,94.86 93.7,94.86 94.44,95.6 96.82,95.6 97.18,95.95 97.92,95.95 98.58,95.29 100.07,95.29 100.25,95.11 100.25,92.55 100.13,92.42 98.73,92.42 98.6,92.55 98.6,93.82 98.47,93.95 97.46,93.95 97.05,94.35 94.38,94.35 94.21,94.17 94.21,93.23 93.88,92.9 93.11,92.9 92.76,92.55 92.76,90.14 90.6,87.98 ; 3 cut-outs
1D0V_S5 on BOTTOM: 86.71,9.11 86.18,9.64 86.18,14.42 86.79,15.03 86.79,17.62 84.12,20.29 84.12,20.31 83.67,20.77 83.67,20.79 83.21,21.25 83.21,23.61 81.71,25.11 81.71,47.06 85.79,51.13 85.79,90.02 89.08,93.31 91.74,93.31 92.07,93.64 93.93,93.64 94.08,93.49 94.08,92.78 94.07,92.76 94.07,92.08 90.22,88.23 90.22,49.11 85.27,44.16 85.27,24.98 86.26,23.99 86.26,23.49 86.82,22.93 86.82,22.44 92.63,16.63 94.64,16.63 94.77,16.5 94.77,15.05 94.71,15 92.58,15 92.43,14.85 92.43,13.4 92.71,13.12 96.19,13.12 96.42,13.35 97.81,13.35 98.22,13.76 103.43,13.76 103.63,13.96 105.33,13.96 106.68,15.31 106.68,15.79 106.93,16.04 107.72,16.04 107.75,16.02 107.75,13.68 107.21,13.15 105.46,13.15 105.21,12.89 105.21,12.44 105.15,12.39 103.58,12.39 103.12,12.84 99.24,12.84 98.86,12.46 97.76,12.46 96.32,11.01 96.32,9.49 96.11,9.29 89.71,9.29 89.53,9.11 ; 2 cut-outs
1D0V_S5 on L3: 86.87,11.47 89.89,11.47 90.56,10.8 91.15,10.8 91.84,10.1 96.09,10.1 96.34,9.85 96.34,9.52 96.11,9.29 87.35,9.29 86.76,9.87 86.76,11.37
1D0V_S5 on L4: 87.04,11.5 90.02,11.5 90.8,10.71 92.66,10.71 93.5,9.87 96.14,9.87 96.32,9.69 96.32,9.44 96.16,9.29 87.35,9.29 86.74,9.9 86.74,11.19
1D0V_S5 on L5VCC: 91.06,90.71 90.79,90.98 90.79,92.34 92.31,93.87 92.31,94.63 93.09,95.41 99.54,95.41 100.57,94.37 100.57,93.39 99.54,92.36 98.9,92.36 97.25,90.71
1D0V_S5 on L6: 124.74,34.23 125.58,34.23 125.78,34.03 125.78,33.67 123.32,31.21 119.94,31.21 119.84,31.31 119.84,31.77 120.11,32.05 122.55,32.05
1D0V_S5 on L6: 108.56,32.6 109.24,32.6 109.62,32.22 109.62,31.46 109.04,30.88 107.85,30.88 106.78,29.81 106.78,27.73 104.7,25.65 104.67,25.65 104.39,25.37 101.29,25.37 99.82,26.84 95.35,26.84 94.51,26 92.02,26 91.18,26.84 88.97,26.84 88.16,26.03 88.16,24.17 87.36,23.37 86.52,23.37 86.27,23.63 83.15,23.63 82.93,23.84 82.93,24.68 83.44,25.19 84.99,25.19 85.67,24.5 86.08,24.5 86.56,24.98 86.56,27.47 87.35,28.26 99.26,28.26 99.27,28.25 100.09,28.25 101.74,26.6 104.1,26.6 105.59,28.08 105.59,30.75 107.03,32.2 108.15,32.2
1D2V_PWR on TOP: 37.51,3.65 37.26,3.9 33.96,3.9 33.83,4.03 33.83,9.72 33.91,9.8 36.22,9.8 36.24,9.77 36.24,9.24 36.37,9.11 40.31,9.11 40.94,8.47 40.94,3.9 40.69,3.65
1D2V_PWR on BOTTOM: 37.51,3.65 37.26,3.9 33.96,3.9 33.83,4.03 33.83,9.72 33.93,9.82 36.17,9.82 36.24,9.74 36.24,9.24 36.37,9.11 38.4,9.11 38.78,9.49 38.78,10.89 39.04,11.14 40.44,11.14 40.56,11.01 40.56,8.6 40.69,8.47 41.45,8.47 41.83,8.86 42.34,8.86 42.59,8.6 42.59,7.59 41.2,6.19 41.2,3.9 40.94,3.65 ; 5 cut-outs
1D2V_S3 on TOP: 32.31,9.49 32.18,9.62 32.18,10.76 32.82,11.4 36.17,11.4 36.27,11.29 36.27,10.13 36.14,10 33.96,10 33.45,9.49
1D2V_S3 on TOP: outline of 122 points within 45.26,25.49 106.48,85.44 ; 179 cut-outs
1D2V_S3 on BOTTOM: 35.61,19.27 35.23,19.65 35.23,23.46 37.64,25.87 39.55,25.87 42.09,28.41 42.09,39.21 43.23,40.35 43.23,45.94 43.61,46.32 46.79,46.32 46.91,46.19 46.91,34.38 45.9,33.37 45.9,24.73 43.86,22.7 39.55,22.7 39.01,22.17 39.01,19.75 38.53,19.27
1D2V_S3 on BOTTOM: 32.31,9.49 32.18,9.62 32.18,10.76 32.84,11.42 34.44,11.42 34.9,11.88 34.9,12.64 35,12.74 35.81,12.74 35.89,12.67 35.89,12.28 36.24,11.93 36.24,9.97 36.17,9.9 33.86,9.9 33.45,9.49
1D2V_S3 on L3: 102.18,48.3 102.84,48.3 104.47,49.93 105.33,49.93 105.89,49.37 109.35,49.37 109.52,49.55 109.52,50 108.74,50.79 104.19,50.79 102.08,48.68 102.08,48.4
1D2V_S3 on L4: 31.77,15.26 31.89,15.14 32.55,15.14 32.69,15 32.69,13.91 32.28,13.5 31.11,13.5 30.99,13.38 30.99,10.61 31.09,10.51 32.1,10.51 32.18,10.43 32.18,9.62 32.43,9.36 35.89,9.36 35.9,9.38 36.71,9.38 37.16,9.82 37.16,14.06 37.01,14.22 37.01,15.51 37.79,16.3 37.79,21.12 37.59,21.33 31.95,21.33 31.77,21.15
1D2V_S3 on L5VCC: 32.77,8.54 32.12,9.19 32.12,11.32 32.51,11.71 33.53,11.71 34.15,12.33 34.15,19.32 36.2,21.37 40.01,21.37 41.39,22.75 41.39,27.45 42.4,28.46 42.4,46.11 43.18,46.89 48.48,46.89 48.75,46.62 48.75,19.86 45.31,16.41 41.25,16.41 37.96,13.13 37.96,10.2 36.29,8.54
1D5V_PWR on BOTTOM: 55.12,7.31 54.91,7.51 54.91,7.94 55.01,8.04 55.14,8.04 55.29,8.2 55.29,8.35 55.4,8.45 56.26,8.45 56.54,8.73 56.54,10 56.56,10.02 57.25,10.02 57.28,10 57.28,9.49 57.4,9.36 58.01,9.36 58.11,9.26 58.11,8.73 57.66,8.27 57.22,8.27 56.92,7.97 56.92,7.59 56.64,7.31 ; 1 cut-out
1D5V_S0 on TOP: 26.77,70.93 26.64,71.06 26.64,71.95 26.74,72.05 28.19,72.05 28.42,71.82 28.42,71.14 28.22,70.93
1D5V_S0 on BOTTOM: 55.78,9.59 55.73,9.64 55.73,11.22 55.78,11.27 57.05,11.27 57.28,11.04 57.28,10.41 57.22,10.35 56.39,10.35 56.36,10.33 56.36,9.69 56.26,9.59
1D5V_VDD on TOP: 20.12,67.78 18.97,68.93 18.97,69.31 19.23,69.56 20.5,69.56 21,69.05 21.26,69.05 21.39,68.93 21.39,67.91 21.26,67.78
1D5V_VDD on BOTTOM: 19.1,68.16 18.97,68.29 18.97,69.43 19.1,69.56 20.5,69.56 20.62,69.43 20.62,68.29 20.5,68.16 ; 1 cut-out
1D5V_VDD on L6: 20.37,62.32 19.86,62.32 19.48,62.7 19.48,67.53 18.85,68.16 18.85,69.31 19.1,69.56 20.37,69.56 21,68.93 23.8,68.93 24.18,69.31 24.18,69.56 24.31,69.69 24.81,69.69 24.94,69.56 24.94,69.05 24.81,68.93 24.81,64.1 25.58,63.34 25.58,62.83 25.32,62.58 24.05,62.58 23.67,62.96 21,62.96
1D8V_PWR on BOTTOM: 52.12,13.17 51.99,13.3 51.99,16.73 52.12,16.86 52.63,16.86 52.88,16.6 58.85,16.6 59.61,15.84 59.61,13.94 59.36,13.68 55.93,13.68 55.42,13.17 ; 4 cut-outs
2D5V_S3 on TOP: 59.28,20.21 58.7,20.79 57.81,20.79 57.5,21.1 57.5,21.81 57.61,21.91 58.8,21.91 59.46,22.57 59.49,22.57 59.61,22.7 62.41,22.7 62.53,22.57 62.53,22.06 62.41,21.94 61.26,21.94 61.01,21.68 61.01,21.05 61.26,20.79 61.26,20.46 61.01,20.21 ; 6 cut-outs
2D5V_S3 on TOP: 70.15,20.84 70,21 70,21.38 70.41,21.78 70.86,21.78 71.07,21.99 71.07,24.05 71.14,24.12 73.33,24.12 73.51,23.94 73.51,21.05 73.3,20.84 ; 7 cut-outs
2D5V_S3 on BOTTOM: 50.47,97.25 50.19,97.53 50.19,97.83 50.75,98.39 50.75,100.07 50.85,100.17 51.66,100.17 51.95,99.88 51.95,98.44 51.76,98.25 51.76,97.45 51.56,97.25
2D5V_S3 on BOTTOM: 63.04,18.38 62.28,19.14 58.99,19.14 58.23,19.9 58.23,21.84 60.52,21.84 61.41,20.95 61.41,20.92 61.9,20.92 62.28,20.54 62.79,20.54 63.17,20.16 66.32,20.16 67.84,21.68 73.2,21.68 73.33,21.56 73.33,20.92 72.95,20.54 71.7,20.54 70.89,19.73 70.33,19.73 68.98,18.38
2D5V_S3 on L4: 52.88,98.39 53.9,97.37 53.9,90.14 51.99,88.23 50.72,88.23 49.58,87.09 49.58,27.91 49.07,27.4 49.07,23.59 52.75,19.9 55.12,19.9 57.1,21.89 60.68,21.89 61.14,21.43 61.14,20.41 60.88,20.16 58.22,20.16 57.71,19.65 57.71,18.51 56.69,17.49 51.74,17.49 47.42,21.81 47.42,22.95 46.79,23.59 46.79,39.84 47.04,40.1 47.04,46.83 46.79,47.08 46.79,88.61 47.42,89.25 49.2,89.25 51.61,91.66 51.61,96.03 51.87,96.28 51.87,96.97 51.69,97.15 50.52,97.15 50.14,97.53 50.14,98.16 50.37,98.39
3D3V_CAMERA_S0 on TOP: 58.11,91.63 57.91,91.84 57.91,94.81 58.49,95.39 58.49,98.37 58.14,98.72 57.15,98.72 56.54,99.33 55.27,99.33 54.99,99.61 54.99,100.6 55.19,100.8 56.89,100.8 57.96,99.74 58.95,99.74 59.51,99.18 59.51,95.14 58.72,94.35 58.72,93.72 58.93,93.51 58.93,92.63 59.33,92.22 59.33,91.86 59.1,91.63 ; 2 cut-outs
3D3V_S0 on TOP: 57.02,93.26 56.87,93.41 56.87,94.48 56.64,94.71 56.64,97.35 56.36,97.63 55.22,97.63 54.99,97.86 54.99,98.7 55.12,98.82 56.64,98.82 56.95,98.52 57.99,98.52 58.22,98.29 58.22,95.39 57.73,94.91 57.73,93.34 57.66,93.26 ; 2 cut-outs
3D3V_S0 on TOP: 55.61,21.34 55.19,21.76 55.19,22.06 54.96,22.29 54.96,22.75 55.09,22.88 55.93,22.88 56.16,23.11 56.16,23.56 55.93,23.79 55.93,24.53 55.52,24.93 51.28,24.93 51.1,25.11 51.1,27.04 50.56,27.59 49.29,27.59 48.92,27.96 48.46,27.96 47.34,29.07 47.34,33.34 46.81,33.87 44.55,33.87 44.37,34.05 44.37,34.64 44.68,34.94 46.96,34.94 47.34,35.32 47.34,37.08 43.36,41.06 43.36,42.43 42.26,43.53 42.26,46.19 42.57,46.5 43.51,46.5 43.71,46.3 43.71,44.44 45.03,43.12 45.03,40.91 48.82,37.13 48.82,30.65 52.07,27.4 52.07,26.36 52.4,26.03 56.16,26.03 56.69,25.49 56.69,23.56 56.56,23.44 56.56,21.84 56.07,21.34 ; 9 cut-outs
3D3V_S0 on TOP: 79.64,96.19 79.53,96.31 79.53,98.8 79.37,98.95 78.56,98.95 78.51,99 78.51,100.12 78.56,100.17 81.1,100.17 81.43,99.84 81.43,96.46 81.16,96.19
3D3V_S0 on TOP: 201.7,8.98 201.5,9.19 201.5,10.41 201.6,10.51 202.66,10.51 202.92,10.25 202.92,9.14 202.77,8.98
3D3V_S0 on TOP: 93.27,38.02 92.81,38.47 92.17,38.47 92,38.65 92,40.61 92.2,40.81 94.11,40.81 94.23,40.68 94.23,39.82 94.28,39.77 94.28,38.19 94.11,38.02 ; 2 cut-outs
3D3V_S0 on TOP: 111.2,18.38 111.07,18.51 111.07,18.91 110.84,19.14 109.47,19.14 109.35,19.02 109.35,18.71 109.14,18.51 108.38,18.51 108.13,18.76 108.13,19.65 108.38,19.9 110.82,19.9 110.92,19.8 111.22,19.8 111.66,19.37 111.66,18.89 111.9,18.65 111.9,18.47 111.81,18.38
3D3V_S0 on TOP: 201.62,18.08 201.06,18.63 199.46,18.63 199.26,18.84 199.26,19.55 199.46,19.75 203.63,19.75 203.78,19.6 203.78,18.2 203.66,18.08
3D3V_S0 on TOP: 121.77,23 120.93,23.84 118.41,23.84 116.1,26.15 112.01,26.15 111.58,26.59 110.39,26.59 109.5,25.7 108.43,25.7 108.25,25.87 108.25,26.51 108.51,26.76 108.89,26.76 109.43,27.31 111.97,27.31 112.42,26.86 115.44,26.86 115.7,27.12 117.24,27.12 119.26,25.1 121.7,25.1 122.55,24.25 123.21,24.25 123.37,24.4 123.37,27.7 123.21,27.86 123.01,27.86 122.93,27.93 122.93,28.16 123.14,28.36 123.47,28.36 124.74,27.09 124.74,26.66 125.45,25.95 125.45,23.44 125.02,23
3D3V_S0 on TOP: 102.45,15.93 102.28,16.09 101.95,16.09 101.88,16.17 101.88,16.98 102.36,17.47 103.76,17.47 103.96,17.26 103.96,16.37 103.52,15.93
3D3V_S0 on BOTTOM: 176.73,74.59 176.58,74.74 176.58,77.36 177.26,78.05 177.26,78.73 177.39,78.86 177.98,78.86 178.1,78.73 178.1,75.43 177.26,74.59
3D3V_S0 on BOTTOM: 110.46,29.58 110.31,29.73 110.31,30.06 110.03,30.34 110.03,30.95 110.16,31.08 111.43,31.08 111.58,30.93 113.97,30.93 113.97,30.95 114.48,31.46 115.75,31.46 115.87,31.33 115.87,30.95 115.75,30.83 114.73,30.83 114.04,30.14 112.29,30.14 111.73,29.58 ; 4 cut-outs
3D3V_S0 on BOTTOM: outline of 104 points within 117.27,21.68 135.25,37.66 ; 2 cut-outs
3D3V_S0 on BOTTOM: 180.31,35.88 178.31,37.89 178.31,40 178.59,40.28 179.07,40.28 179.25,40.1 179.25,38.14 180.54,36.85 181.38,36.85 181.56,37.02 181.56,38.88 182.34,39.67 184.68,39.67 184.71,39.64 186.26,39.64 186.28,39.67 186.28,40.5 186.42,40.64 186.42,41.74 186.49,41.8 187.02,41.8 187.04,41.77 187.04,40.96 187.27,40.73 187.27,39.46 186.89,39.08 184.96,39.08 184.71,38.83 184.05,38.83 183.13,37.91 183.13,36.8 182.22,35.88
3D3V_S0 on BOTTOM: 140.26,22.83 140.13,22.95 140.13,23.59 140.64,24.1 140.64,26.13 140.38,26.38 137.84,26.38 137.83,26.39 136.92,26.39 136.35,26.97 135.1,26.97 134.92,27.14 134.92,27.47 135.33,27.88 135.33,28.34 135.41,28.41 135.86,28.41 135.91,28.36 135.91,27.75 136.07,27.6 136.75,27.6 137.21,27.14 142.04,27.14 142.92,26.25 142.92,25.87 142.67,25.62 142.16,25.62 141.53,24.98 141.53,24.1 140.89,23.46 140.89,23.08 140.64,22.83 ; 2 cut-outs
3D3V_S0 on BOTTOM: 93.55,100.19 92.86,100.88 89.74,100.88 89.25,101.36 87.6,101.36 87.12,100.88 84.81,100.88 84.61,101.08 84.61,102.23 85.27,102.89 89.53,102.89 90.07,102.35 93.62,102.35 94.31,101.67 96.24,101.67 96.52,101.95 97.08,101.95 97.28,101.74 97.28,100.93 96.54,100.19
3D3V_S0 on BOTTOM: 168.45,39.54 168.35,39.64 168.35,41.34 168.43,41.42 169.57,41.42 169.86,41.71 169.87,41.7 170.2,41.7 170.36,41.55 170.36,39.74 170.15,39.54
3D3V_S0 on BOTTOM: 134.97,102.76 134.92,102.81 134.92,103.5 134.87,103.55 134.01,103.55 133.83,103.72 133.83,104.54 134.8,105.5 137.72,105.5 137.97,105.25 137.97,103.88 137.69,103.6 136.45,103.6 135.81,102.96 135.81,102.79 135.79,102.76
3D3V_S0 on BOTTOM: 114.76,26.15 114.6,26.31 114.6,26.66 114.78,26.84 115.06,26.84 115.54,27.32 116.51,27.32 116.58,27.25 116.58,26.48 116.41,26.31 116.05,26.31 115.9,26.15
3D3V_S0 on L3: 108.51,26.64 109.27,26.64 109.92,25.99 110.63,25.99 111.35,25.26 111.35,20.18 111.91,19.63 111.91,18.43 111.76,18.28 111.45,18.28 111.25,18.48 111.25,18.94 110.64,19.55 106.98,19.55 106.77,19.33 106.75,19.33 104.91,17.49 103.07,17.49 102.44,16.86 102.44,16.65 102.21,16.43 100,16.43 99.87,16.55 99.87,17.24 100.4,17.77 102.08,17.77 102.64,18.33 103.99,18.33 105.84,20.18 106.48,20.18 107.06,20.77 107.92,20.77 108.61,21.45 110.08,21.45 110.44,21.81 110.44,23.82 108.25,26 108.25,26.38
3D3V_S0 on L3: 118.39,24.5 119.1,24.5 119.33,24.27 119.33,23.71 118.97,23.36 118.69,23.36 118.59,23.26 118.59,22.75 119.3,22.04 119.3,20.87 120.72,19.45 120.72,18.66 120.98,18.41 121,18.41 121.99,17.42 121.99,15.49 122.99,14.49 122.99,13.63 123.98,12.64 123.98,10.35 123.85,10.23 123.47,10.23 123.09,10.61 123.09,12.21 121.99,13.3 121.99,14.27 121.08,15.18 121.08,16.83 119.84,18.08 119.84,18.56 118.13,20.26 118.13,22.37 117.93,22.57 117.93,24.05
3D3V_S0 on L3: 49.43,28.21 50.44,28.21 51.69,26.97 51.69,23.41 52.22,22.88 56.18,22.88 56.39,22.67 56.39,21.68 55.62,20.92 53.95,20.92 53.21,21.66 51.31,21.66 50.34,22.62 50.34,26.53 49.58,27.3 49.38,27.3 49.17,27.5 49.17,27.96
3D3V_S0 on L4: 56.95,94.2 58.6,94.2 59.49,95.09 69.82,95.09 70.23,94.68 75.18,94.68 75.59,95.09 80.19,95.09 83.49,98.39 84.89,98.39 86.41,99.91 86.41,101.57 86.16,101.82 85.01,101.82 84.86,101.67 84.86,100.4 84.5,100.04 84,100.04 83.23,99.28 82.22,99.28 79.68,96.74 57.07,96.74 56.56,96.23 56.56,94.58
3D3V_S0 on L4: 169.59,39.97 172.52,39.97 173.15,40.61 173.15,43.02 173.8,43.67 173.8,51.54 175.23,52.98 175.23,67.89 176.34,68.99 176.34,69.78 176.81,70.25 177.85,70.25 178.97,71.37 178.97,72.61 178.43,73.14 177.24,73.14 173.28,69.18 173.28,53.66 172.39,52.77 172.39,44.39 171.75,43.76 171.75,42 171.37,41.62 169.59,41.62 169.47,41.49 169.47,40.1
3D3V_S0 on L4: 55.47,21.23 56.03,21.23 56.97,22.17 64.44,22.17 64.67,21.94 67.38,21.94 68.04,21.28 69.57,21.28 69.7,21.4 69.7,22.29 69.19,22.8 65.28,22.8 65.02,23.05 56.41,23.05 55.42,22.06 55.42,21.28
3D3V_S0 on L4: 41.02,45.08 42.26,45.08 42.87,45.69 42.87,45.89 41.37,47.39 41.37,52.57 39.79,54.16 39.38,54.16 38.96,53.74 38.96,52.75 39.88,51.83 39.88,46.22
3D3V_S0 on L6: 169.57,41.57 172.39,41.57 173.81,40.15 178.69,40.15 178.99,39.84 178.99,39.46 178.87,39.34 172.79,39.34 172.13,40 169.64,40 169.31,40.33 169.31,41.32
3D3V_S0 on L6: 179.12,70.2 179.5,70.58 179.5,96.64 177.62,98.52 174.42,98.52 171.8,101.13 171.8,103.22 170.43,104.59 167.99,104.59 166.55,106.04 166.55,107.28 166.17,107.66 166.17,108.68 164.9,109.95 134.59,109.95 133.32,108.68 133.32,104.54 133.03,104.25 130.95,104.25 130.25,103.55 113.61,103.55 112.75,102.68 103.48,102.68 101.98,104.18 98.55,104.18 98.36,103.99 97.65,103.99 96.16,102.51 96.16,101.54 96.77,100.93 98.17,100.93 98.4,101.16 98.4,101.77 98.78,102.15 99.21,102.15 99.39,101.97 101.55,101.97 102.08,101.44 102.72,101.44 103.1,101.06 113.64,101.06 114.4,101.82 132.51,101.82 133.63,100.7 134.59,100.7 136.17,102.28 136.17,103.83 137.72,105.38 137.72,107.15 138.99,108.42 162.74,108.42 164.51,106.65 164.51,105.76 166.95,103.32 166.95,101.54 168.96,99.53 170.74,99.53 174.04,96.23 175.56,96.23 177.6,94.2 177.6,79.37 176.96,78.73 176.96,75.12 175.94,74.11 173.23,74.11 172.72,74.62 172.29,74.62 172.11,74.44 172.11,68.85 172.92,68.04 174.83,68.04 176.33,69.54 176.33,69.87 176.66,70.2
3D3V_S0 on L7GND: 201.04,17.94 194.95,24.03 193.04,24.03 190.63,26.45 186.18,26.45 186.06,26.57 183.52,26.57 182.48,27.6 182.48,28.75 181.87,29.37 176.15,29.37 173.21,32.3 173.21,37.51 171.2,39.53 169.04,39.53 168.39,40.18 168.39,41.54 168.78,41.94 171.93,41.94 175.63,38.24 175.63,33.03 177.14,31.53 182.72,31.53 185.01,29.24 193.52,29.24 202.92,19.84 204.34,19.84 204.34,17.94
3D3V_S5 on TOP: 57.83,1.49 57.45,1.87 57.45,4.16 58.22,4.92 58.22,9.49 59.99,11.27 60.83,11.27 60.96,11.14 60.96,9.31 60.37,8.73 60.37,6.32 59.74,5.68 59.74,2.76 58.47,1.49 ; 1 cut-out
3D3V_S5 on TOP: 107.62,12.54 106.6,13.55 106.6,15.61 105.76,16.45 105.76,17.11 105.99,17.34 105.99,17.75 106.12,17.87 106.37,17.87 106.55,17.7 106.55,17.14 107.49,16.2 107.49,14.32 108.46,13.35 111.38,13.35 111.58,13.15 111.58,12.79 111.33,12.54
3D3V_S5 on TOP: 166.04,48.48 165.38,49.14 165.38,52.19 165.24,52.33 163.59,52.33 163.37,52.54 163.37,55.82 164.51,56.96 164.51,62.58 165.06,63.12 165.06,67.06 165.28,67.28 167.18,67.28 168.2,66.26 168.2,61.31 167.56,60.67 167.56,48.86 167.18,48.48
3D3V_S5 on TOP: 48.44,85.82 48.18,86.07 48.18,87.16 48.56,87.55 48.56,90.49 46.81,92.24 45.95,92.24 45.11,93.08 42.19,93.08 41.93,93.34 41.93,95.14 42.39,95.6 46.3,95.6 49.48,92.42 50.47,92.42 51.05,91.84 51.05,89.32 50.54,88.82 50.54,86.99 49.38,85.82 ; 2 cut-outs
3D3V_S5 on TOP: 197.92,28.82 197.46,29.28 197.46,29.71 196.62,30.55 196.29,30.55 195.79,31.04 195.06,31.04 192.89,33.21 192.89,34.69 192.63,34.94 191.29,34.94 191.11,34.76 190.65,34.76 190.4,35.02 190.4,35.32 190.83,35.75 192.81,35.75 193.57,34.99 193.57,33.49 195.41,31.65 195.82,31.65 196.44,31.03 196.8,31.03 196.81,31.02 196.99,31.02 197.81,30.19 197.81,30.04 197.97,29.89 200.07,29.89 200.4,29.56 201.17,29.56 201.42,29.81 201.42,31.41 202.61,32.6 202.61,32.99 202.49,33.11 201.98,33.11 201.85,33.24 201.85,33.87 201.5,34.23 201.5,34.61 201.65,34.76 202.49,34.76 203.5,33.75 203.5,32.35 202.61,31.46 202.61,29.25 202.18,28.82 ; 3 cut-outs
3D3V_S5 on TOP: 171.98,41.88 171.88,41.98 171.88,43.37 171.63,43.63 170.53,43.63 170.43,43.73 170.43,45 170.91,45.48 173.15,45.48 176.33,48.66 176.63,48.66 177.19,49.22 178.13,49.22 178.26,49.09 178.26,48.68 178.18,48.61 177.7,48.61 176.91,47.82 176.45,47.82 173.12,44.49 173.12,42 173,41.88
3D3V_S5 on BOTTOM: 99.79,10.2 99.21,10.79 98.91,10.79 98.75,10.94 98.75,12.13 99.26,12.64 101.24,12.64 101.34,12.54 101.34,11.95 101.17,11.78 100.15,11.78 99.92,11.55 99.92,10.91 100.02,10.81 100.61,10.81 100.73,10.68 100.73,10.35 100.58,10.2 ; 2 cut-outs
3D3V_S5 on BOTTOM: 120.22,21.17 119.56,21.84 118.57,21.84 118.49,21.91 118.49,22.5 118.67,22.67 120.62,22.67 121.11,22.19 121.11,21.45 120.83,21.17
3D3V_S5 on BOTTOM: 165.91,48.35 165.53,48.73 165.53,49.24 165.4,49.37 165.4,52.16 165.66,52.42 166.7,52.42 167.51,51.6 167.51,51.58 167.56,51.53 167.56,48.86 167.05,48.35
3D3V_S5 on BOTTOM: 161.16,104.82 161.09,104.89 161.09,105.48 161.01,105.55 160.65,105.55 160.45,105.76 160.45,106.39 160.58,106.52 162.1,106.52 162.33,106.29 162.33,105.78 162.13,105.58 161.85,105.58 161.67,105.4 161.67,104.87 161.62,104.82
3D3V_S5 on BOTTOM: 131.49,102.45 131.37,102.58 131.37,104.61 131.88,105.12 133.15,105.12 133.65,104.61 133.65,102.71 132.26,102.71 132,102.45
3D3V_S5 on BOTTOM: 57.28,7.51 57.25,7.54 57.25,8.02 57.3,8.07 57.99,8.07 58.29,8.37 58.29,9.19 58.49,9.39 59.13,9.39 59.21,9.47 59.21,10.25 59.87,10.91 59.87,15.84 58.85,16.86 52.91,16.86 51.87,17.9 48.28,17.9 47.29,18.89 47.29,86.58 47.67,86.96 48.82,86.96 49.33,86.45 49.33,20.79 49.81,20.31 52.73,20.31 54.15,18.89 58.22,18.89 58.85,18.25 61.72,18.25 62.91,17.06 65.84,17.06 66.72,16.17 66.72,15.16 66.6,15.03 63.12,15.03 62.91,14.82 62.91,11.78 62.66,11.52 61.92,11.52 61.39,10.99 61.34,10.99 60.45,10.1 60.45,8.73 60.17,8.45 60.17,7.81 59.87,7.51 ; 2 cut-outs
3D3V_S5 on BOTTOM: 107.75,9.82 107.59,9.97 107.59,10.46 107.57,10.48 105.87,10.48 105.59,10.76 105.59,11.52 105.71,11.65 107.62,11.65 109.14,13.17 110.03,13.17 110.29,13.43 110.29,13.96 110.39,14.06 111.3,14.06 111.4,13.96 112.98,13.96 113.08,13.86 113.08,12.54 112.95,12.41 109.65,12.41 109.27,12.03 109.27,10.18 108.91,9.82 ; 1 cut-out
3D3V_S5 on BOTTOM: 43.79,94.5 43.61,94.68 43.61,95.29 43.79,95.47 43.79,96.66 43.38,97.07 43.38,97.96 43.05,98.29 42.26,98.29 41.81,97.83 40.05,97.83 40,97.88 40,98.44 40.08,98.52 41.48,98.52 41.93,98.98 41.93,101.77 42.01,101.85 44.91,101.85 44.93,101.82 44.93,94.99 44.45,94.5 ; 2 cut-outs
3D3V_S5 on BOTTOM: 106.12,17.47 105.99,17.59 105.99,17.97 105.71,18.25 105.31,18.25 105.18,18.38 104.95,18.38 104.65,18.69 104.65,19.45 104.75,19.55 107.14,19.55 107.21,19.47 107.21,18.76 107.08,18.63 106.7,18.63 106.37,18.3 106.37,17.59 106.25,17.47
3D3V_S5 on BOTTOM: 57.94,1.16 57.5,1.59 57.5,2.94 57.58,3.01 58.67,3.01 59,2.68 59.89,2.68 60.04,2.53 60.04,2.07 60.2,1.92 61.72,1.92 61.95,2.15 61.95,4.16 61.85,4.26 61.44,4.26 61.39,4.31 61.39,4.69 61.44,4.74 63.27,4.74 63.47,4.54 63.47,1.64 62.99,1.16 ; 4 cut-outs
3D3V_S5 on L4: 177.93,48.61 179.25,48.61 180.03,49.39 180.03,51.93 179.93,52.04 179.42,52.04 179.32,51.93 179.32,49.65 178.84,49.17 177.93,49.17 177.75,48.99 177.75,48.78
3D3V_S5 on L4: 131.88,104.49 133.15,104.49 133.27,104.61 133.27,105.88 133.78,106.39 160.07,106.39 160.35,106.11 160.35,105.76 160.55,105.55 162.13,105.55 162.25,105.68 162.25,106.44 160.02,108.68 133.78,108.68 131.75,106.65 131.75,104.61
3D3V_S5 on L6: 41.76,94.3 42.16,94.3 42.31,94.45 42.31,95.19 41.37,96.13 40.89,96.13 40.69,95.93 40.69,95.32 40.79,95.22 41.27,95.22 41.6,94.89 41.6,94.45
3D3V_S5 on L6: 111.73,12.03 115.24,12.03 115.9,12.69 116.15,12.69 122.65,19.19 122.65,19.7 122.15,20.21 122.15,21.68 121.79,22.04 120.55,22.04 120.32,21.81 120.32,19.27 114.6,13.55 111.22,13.55 110.92,13.25 110.92,12.84
3D3V_S5 on L6: 109.14,10.15 109.14,9.57 108.71,9.14 106.17,9.14 105.81,8.78 100.18,8.78 98.58,10.38 92.68,10.38 91.59,11.47 89.03,11.47 89,11.45 88.47,11.45 86.99,9.97 86.99,9.01 83.36,5.38 82.4,5.38 78.84,1.82 73.73,1.82 73.38,2.18 67.36,2.18 66.65,1.46 57.96,1.46 57.68,1.74 57.68,3.47 58.06,3.85 59.41,3.85 59.49,3.78 70.69,3.78 70.81,3.65 78.36,3.65 87.51,12.81 95.06,12.81 95.76,12.11 101.78,12.11 102.94,10.94 108.35,10.94
3D3V_S5 on L7GND: 165.36,63.15 165.21,63.29 165.21,65.67 165.48,65.94 165.99,65.94 167.5,67.45 167.5,82.56 168.26,83.33 168.26,98.47 161.16,105.57 160.66,105.57 160.51,105.71 160.51,106.95 160.91,107.34 163.8,107.34 170.93,100.22 170.93,84.37 170.42,83.86 170.42,65.45 168.12,63.15
3D3V_S5_KBC on TOP: 171.83,32.1 170.41,33.52 170.41,35.02 170.89,35.5 170.89,41.22 171.12,41.44 172.57,41.44 172.64,41.37 172.64,36.72 172.11,36.19 172.11,35.32 171.93,35.14 171.93,33.93 172.01,33.85 173.84,33.85 174.24,33.44 174.72,33.44 175.03,33.75 175.03,34.18 177.39,36.54 180.67,36.54 180.74,36.47 180.74,34.13 180.69,34.08 179.83,34.08 179.68,34.23 179.68,34.66 179.55,34.79 177.57,34.79 176.9,34.12 176.9,33.53 175.46,32.1
3D3V_S5_KBC on TOP: 178.53,26.56 178.41,26.69 178.41,29.35 178.36,29.4 177.37,29.4 176.93,28.97 176.2,28.97 176.12,29.05 176.12,30.15 176.25,30.28 177.48,30.28 177.61,30.15 178.98,30.15 179.12,30.01 179.12,29.43 179.32,29.23 180.39,29.23 180.52,29.1 180.52,26.71 180.36,26.56
3D3V_S5_KBC on BOTTOM: 184.83,41.27 184.81,41.29 184.81,42.03 184.75,42.09 184.29,42.09 184.12,42.26 184.12,42.54 184.22,42.64 185.32,42.64 185.39,42.56 185.39,41.34 185.32,41.27
3D3V_S5_KBC on BOTTOM: 189.74,44.01 189.53,44.21 189.53,45.58 189.69,45.74 190.4,45.74 191.01,45.13 192.12,45.13 192.25,45 192.25,44.03 192.23,44.01
